VERSION ""

NS_ :

BS_:

BU_: GW_FD5 GW_FD6 GW_FD3 GW_FD4 GW_FD1 GW_FD2 PDCS_FD1 PDCU SRR3 SRR4 ADCU_FD3 BDCS DDCU CDCS ADCS_FD3 CDCS_OverSea TBOX FLC_ME_FD3 FLC_FD3 ICU_E02 ICU PDCS_HVM_FD1 TBOX_OverSea BMS ISC GCU EMS IDB ESC_FD3 EHB_FD3 MCU IMU ACU EPS WPC CDU AMP BAM PDCS_FD3 EVCC REPB ADCS_FD6 ADCU_FD6 FLC_ME_FD6 FLC_FD6 DLC GW_FD7 ESC_FD6 EHB_FD6

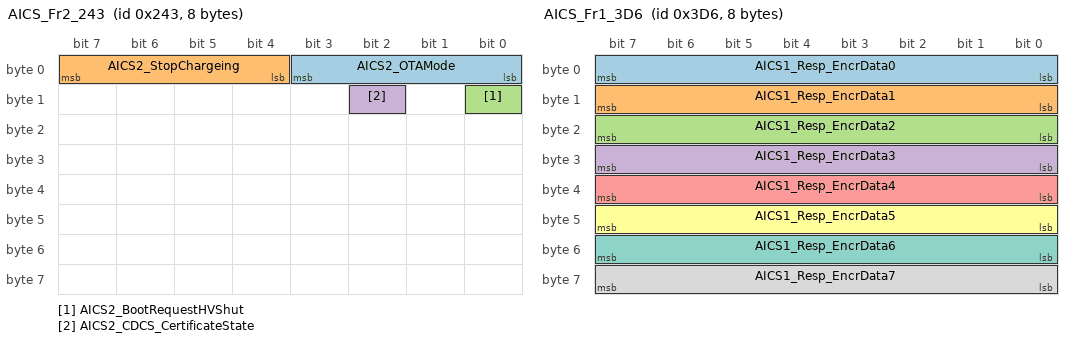
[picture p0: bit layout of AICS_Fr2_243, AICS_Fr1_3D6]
BO_ 579 AICS_Fr2_243: 8 GW_FD5
 SG_ AICS2_OTAMode : 3|4@0+ (1,0) [0|15] "NoUnit" PDCS_FD1,PDCU,SRR3,SRR4,ADCU_FD3,BDCS,DDCU,CDCS,ADCS_FD3,CDCS_OverSea,TBOX,FLC_ME_FD3,FLC_FD3,ICU_E02,ICU,PDCS_HVM_FD1,TBOX_OverSea
 SG_ AICS2_StopChargeing : 7|4@0+ (1,0) [0|15] "NoUnit" PDCS_FD1,ADCU_FD3,BMS,ADCS_FD3,FLC_ME_FD3,FLC_FD3,PDCS_HVM_FD1
 SG_ AICS2_BootRequestHVShut : 8|1@0+ (1,0) [0|1] "NoUnit" PDCS_FD1,ADCU_FD3,BMS,ADCS_FD3,FLC_ME_FD3,FLC_FD3,PDCS_HVM_FD1
 SG_ AICS2_CDCS_CertificateState : 10|1@0+ (1,0) [0|1] "NoUnit" CDCS,CDCS_OverSea

BO_ 982 AICS_Fr1_3D6: 8 GW_FD2
 SG_ AICS1_Resp_EncrData0 : 7|8@0+ (1,0) [0|255] "NoUnit" BDCS
 SG_ AICS1_Resp_EncrData1 : 15|8@0+ (1,0) [0|255] "NoUnit" BDCS
 SG_ AICS1_Resp_EncrData2 : 23|8@0+ (1,0) [0|255] "NoUnit" BDCS
 SG_ AICS1_Resp_EncrData3 : 31|8@0+ (1,0) [0|255] "NoUnit" BDCS
 SG_ AICS1_Resp_EncrData4 : 39|8@0+ (1,0) [0|255] "NoUnit" BDCS
 SG_ AICS1_Resp_EncrData5 : 47|8@0+ (1,0) [0|255] "NoUnit" BDCS
 SG_ AICS1_Resp_EncrData6 : 55|8@0+ (1,0) [0|255] "NoUnit" BDCS
 SG_ AICS1_Resp_EncrData7 : 63|8@0+ (1,0) [0|255] "NoUnit" BDCS

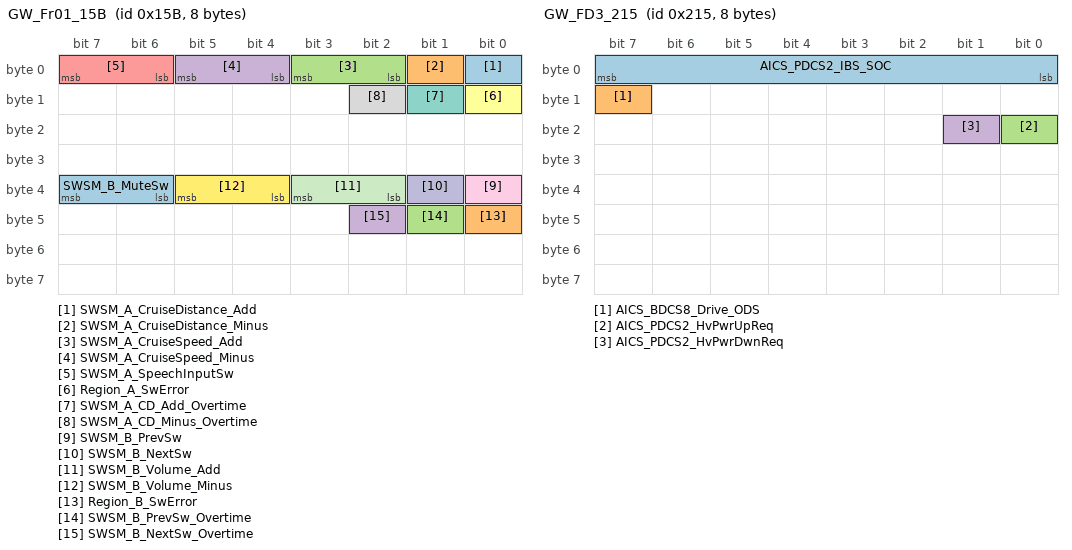
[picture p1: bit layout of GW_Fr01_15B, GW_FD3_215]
BO_ 347 GW_Fr01_15B: 8 GW_FD3
 SG_ SWSM_A_CruiseDistance_Add : 0|1@0+ (1,0) [0|1] "NoUnit" FLC_ME_FD3,FLC_FD3,DDCU,CDCS,ADCS_FD3,CDCS_OverSea
 SG_ SWSM_A_CruiseDistance_Minus : 1|1@0+ (1,0) [0|1] "NoUnit" FLC_ME_FD3,FLC_FD3,DDCU,CDCS,ADCS_FD3,CDCS_OverSea
 SG_ SWSM_A_CruiseSpeed_Add : 3|2@0+ (1,0) [0|3] "NoUnit" PDCS_FD1,FLC_ME_FD3,FLC_FD3,DDCU,CDCS,PDCS_HVM_FD1,ADCS_FD3,CDCS_OverSea
 SG_ SWSM_A_CruiseSpeed_Minus : 5|2@0+ (1,0) [0|3] "NoUnit" PDCS_FD1,FLC_ME_FD3,FLC_FD3,DDCU,CDCS,PDCS_HVM_FD1,ADCS_FD3,CDCS_OverSea
 SG_ SWSM_A_SpeechInputSw : 7|2@0+ (1,0) [0|3] "NoUnit" FLC_ME_FD3,FLC_FD3,CDCS,ADCS_FD3,CDCS_OverSea
 SG_ Region_A_SwError : 8|1@0+ (1,0) [0|1] "NoUnit" PDCS_FD1,FLC_ME_FD3,FLC_FD3,CDCS,PDCS_HVM_FD1,ADCS_FD3,CDCS_OverSea
 SG_ SWSM_A_CD_Add_Overtime : 9|1@0+ (1,0) [0|1] "NoUnit" FLC_ME_FD3,FLC_FD3,CDCS,ADCS_FD3,CDCS_OverSea
 SG_ SWSM_A_CD_Minus_Overtime : 10|1@0+ (1,0) [0|1] "NoUnit" FLC_ME_FD3,FLC_FD3,CDCS,ADCS_FD3,CDCS_OverSea
 SG_ SWSM_B_PrevSw : 32|1@0+ (1,0) [0|1] "NoUnit" PDCU,CDCS,CDCS_OverSea
 SG_ SWSM_B_NextSw : 33|1@0+ (1,0) [0|1] "NoUnit" PDCU,CDCS,CDCS_OverSea
 SG_ SWSM_B_Volume_Add : 35|2@0+ (1,0) [0|3] "NoUnit" PDCU,CDCS,CDCS_OverSea
 SG_ SWSM_B_Volume_Minus : 37|2@0+ (1,0) [0|3] "NoUnit" PDCU,CDCS,CDCS_OverSea
 SG_ SWSM_B_MuteSw : 39|2@0+ (1,0) [0|3] "NoUnit" CDCS,CDCS_OverSea
 SG_ Region_B_SwError : 40|1@0+ (1,0) [0|1] "NoUnit" CDCS,CDCS_OverSea
 SG_ SWSM_B_PrevSw_Overtime : 41|1@0+ (1,0) [0|1] "NoUnit" CDCS,CDCS_OverSea
 SG_ SWSM_B_NextSw_Overtime : 42|1@0+ (1,0) [0|1] "NoUnit" CDCS,CDCS_OverSea

BO_ 405 GW_UPA_0x195: 16 GW_FD5
 SG_ FPA_ResponseError : 0|1@0+ (1,0) [0|1] "" TBOX,CDCS,CDCS_OverSea,TBOX_OverSea
 SG_ FPA_Staus : 1|1@0+ (1,0) [0|1] "" TBOX,CDCS,CDCS_OverSea,TBOX_OverSea
 SG_ FPA_AssemblyNumberDID : 4|3@0+ (1,0) [0|7] "" TBOX,CDCS,CDCS_OverSea,TBOX_OverSea
 SG_ FPA_DetectionFOL : 15|8@0+ (1,0) [0|255] "cm" TBOX,CDCS,CDCS_OverSea,TBOX_OverSea
 SG_ FPA_DetectionFML : 23|8@0+ (1,0) [0|255] "cm" TBOX,CDCS,CDCS_OverSea,TBOX_OverSea
 SG_ FPA_DetectionFMR : 31|8@0+ (1,0) [0|255] "cm" TBOX,CDCS,CDCS_OverSea,TBOX_OverSea
 SG_ FPA_DetectionFOR : 39|8@0+ (1,0) [0|255] "cm" TBOX,CDCS,CDCS_OverSea,TBOX_OverSea
 SG_ FPA_FOLErrorFlag : 40|1@0+ (1,0) [0|1] "" TBOX,CDCS,CDCS_OverSea,TBOX_OverSea
 SG_ FPA_FMLErrorFlag : 41|1@0+ (1,0) [0|1] "" TBOX,CDCS,CDCS_OverSea,TBOX_OverSea
 SG_ FPA_FMRErrorFlag : 42|1@0+ (1,0) [0|1] "" TBOX,CDCS,CDCS_OverSea,TBOX_OverSea
 SG_ FPA_FORErrorFlag : 43|1@0+ (1,0) [0|1] "" TBOX,CDCS,CDCS_OverSea,TBOX_OverSea
 SG_ FPA_PoweVoltageAbnormal : 44|1@0+ (1,0) [0|1] "" TBOX,CDCS,CDCS_OverSea,TBOX_OverSea
 SG_ FPA_Sound_Location : 46|2@0+ (1,0) [0|3] "" TBOX,CDCS,CDCS_OverSea,TBOX_OverSea
 SG_ FPA_SoundIndication : 50|3@0+ (1,0) [0|7] "" TBOX,CDCS,CDCS_OverSea,TBOX_OverSea
 SG_ FPA_HardwareVersion : 55|5@0+ (1,0) [0|31] "" TBOX,CDCS,CDCS_OverSea,TBOX_OverSea
 SG_ FPA_SoftwareSubVersion : 59|4@0+ (1,0) [0|15] "" TBOX,CDCS,CDCS_OverSea,TBOX_OverSea
 SG_ FPA_SoftwareMainVersion : 63|4@0+ (1,0) [0|15] "" TBOX,CDCS,CDCS_OverSea,TBOX_OverSea
 SG_ RPA_ResponseError : 64|1@0+ (1,0) [0|1] "" TBOX,CDCS,CDCS_OverSea,TBOX_OverSea
 SG_ RPA_Staus : 65|1@0+ (1,0) [0|1] "" TBOX,CDCS,CDCS_OverSea,TBOX_OverSea
 SG_ RPA_AssemblyNumberDID : 68|3@0+ (1,0) [0|7] "" TBOX,CDCS,CDCS_OverSea,TBOX_OverSea
 SG_ RPA_DetectionROL : 79|8@0+ (1,0) [0|255] "cm" TBOX,CDCS,CDCS_OverSea,TBOX_OverSea
 SG_ RPA_DetectionRML : 87|8@0+ (1,0) [0|255] "cm" TBOX,CDCS,CDCS_OverSea,TBOX_OverSea
 SG_ RPA_DetectionRMR : 95|8@0+ (1,0) [0|255] "cm" TBOX,CDCS,CDCS_OverSea,TBOX_OverSea
 SG_ RPA_DetectionROR : 103|8@0+ (1,0) [0|255] "cm" TBOX,CDCS,CDCS_OverSea,TBOX_OverSea
 SG_ RPA_ROLErrorFlag : 104|1@0+ (1,0) [0|1] "" TBOX,CDCS,CDCS_OverSea,TBOX_OverSea
 SG_ RPA_RMLErrorFlag : 105|1@0+ (1,0) [0|1] "" TBOX,CDCS,CDCS_OverSea,TBOX_OverSea
 SG_ RPA_RMRErrorFlag : 106|1@0+ (1,0) [0|1] "" TBOX,CDCS,CDCS_OverSea,TBOX_OverSea
 SG_ RPA_RORErrorFlag : 107|1@0+ (1,0) [0|1] "" TBOX,CDCS,CDCS_OverSea,TBOX_OverSea
 SG_ RPA_PoweVoltageAbnormal : 108|1@0+ (1,0) [0|1] "" TBOX,CDCS,CDCS_OverSea,TBOX_OverSea
 SG_ RPA_Sound_Location : 110|2@0+ (1,0) [0|3] "" TBOX,CDCS,CDCS_OverSea,TBOX_OverSea
 SG_ RPA_SoundIndication : 114|3@0+ (1,0) [0|7] "" TBOX,CDCS,CDCS_OverSea,TBOX_OverSea
 SG_ RPA_HardwareVersion : 119|5@0+ (1,0) [0|31] "" TBOX,CDCS,CDCS_OverSea,TBOX_OverSea
 SG_ RPA_SoftwareSubVersion : 123|4@0+ (1,0) [0|15] "" TBOX,CDCS,CDCS_OverSea,TBOX_OverSea
 SG_ RPA_SoftwareMainVersion : 127|4@0+ (1,0) [0|15] "" TBOX,CDCS,CDCS_OverSea,TBOX_OverSea

BO_ 533 GW_FD3_215: 8 GW_FD3
 SG_ AICS_PDCS2_IBS_SOC : 7|8@0+ (1,0) [0|100] "%" CDCS,ADCS_FD3,CDCS_OverSea
 SG_ AICS_BDCS8_Drive_ODS : 15|1@0+ (1,0) [0|1] "NoUnit" FLC_ME_FD3,FLC_FD3,ADCU_FD3,ADCS_FD3
 SG_ AICS_PDCS2_HvPwrUpReq : 16|1@0+ (1,0) [0|1] "NoUnit" ISC
 SG_ AICS_PDCS2_HvPwrDwnReq : 17|1@0+ (1,0) [0|1] "NoUnit" ISC

BO_ 1233 GW_FD5_4D1: 16 GW_FD5
 SG_ AICS_GCU3_OperModFdbk : 7|4@0+ (1,0) [0|15] "NoUnit" TBOX,TBOX_OverSea
 SG_ AICS_GCU3_Motor_Torque : 3|12@0+ (0.5,-300) [-130|130] "Nm" TBOX,TBOX_OverSea
 SG_ AICS_GCU3_Motor_Speed : 23|16@0+ (1,-12000) [-8000|8000] "rpm" TBOX,TBOX_OverSea
 SG_ AICS_EMS1_EngineStartedCompleted : 39|1@0+ (1,0) [0|1] "NoUnit" TBOX,TBOX_OverSea
 SG_ AICS_EMS1_EngineStopAllow : 38|1@0+ (1,0) [0|1] "NoUnit" TBOX,TBOX_OverSea
 SG_ AICS_EMS1_ActualEngineTorqueValid : 37|1@0+ (1,0) [0|1] "NoUnit" TBOX,TBOX_OverSea
 SG_ AICS_EMS1_ActualEngineTorque : 35|12@0+ (0.5,-500) [-500|1547] "Nm" TBOX,TBOX_OverSea
 SG_ AICS_EMS1_EngineTorqMin : 55|12@0+ (0.5,-500) [-500|1547] "Nm" TBOX,TBOX_OverSea
 SG_ AICS_EMS1_EngineTorqMax : 59|12@0+ (0.5,-500) [-500|1547] "Nm" TBOX,TBOX_OverSea
 SG_ AICS_EMS1_EngineTorqLoss : 79|10@0+ (0.5,-100) [-100|411] "Nm" TBOX,TBOX_OverSea

BO_ 1536 AICS_NM_600: 8 GW_FD5
 SG_ AICS_SourceNodeIdentifier : 7|8@0+ (1,0) [0|255] "NoUnit" Vector__XXX
 SG_ AICS_RepeatMessageRequest : 8|1@0+ (1,0) [0|1] "NoUnit" Vector__XXX
 SG_ AICS_Reserve1 : 11|3@0+ (1,0) [0|3] "NoUnit" Vector__XXX
 SG_ AICS_ActiveWakeup : 12|1@0+ (1,0) [0|1] "NoUnit" Vector__XXX
 SG_ AICS_Reserve2 : 15|3@0+ (1,0) [0|7] "NoUnit" Vector__XXX
 SG_ AICS_WakeUp_KL15 : 16|1@0+ (1,0) [0|1] "NoUnit" Vector__XXX
 SG_ AICS_WakeUp_NM : 17|1@0+ (1,0) [0|1] "NoUnit" Vector__XXX
 SG_ AICS_WakeUp_LIN : 18|1@0+ (1,0) [0|1] "NoUnit" Vector__XXX
 SG_ AICS_WakeUp_LocalPreCharge : 19|1@0+ (1,0) [0|1] "NoUnit" Vector__XXX
 SG_ AICS_WakeUp_RemotePreCharge : 20|1@0+ (1,0) [0|1] "NoUnit" Vector__XXX
 SG_ AICS_WakeUp_OTA : 21|1@0+ (1,0) [0|1] "NoUnit" Vector__XXX
 SG_ AICS_WakeUp_Remote : 22|1@0+ (1,0) [0|1] "NoUnit" Vector__XXX
 SG_ AICS_WakeUp_PhoneReminder : 23|1@0+ (1,0) [0|1] "NoUnit" Vector__XXX
 SG_ AICS_RepeatFromSleep : 24|1@0+ (1,0) [0|1] "NoUnit" Vector__XXX
 SG_ AICS_RepeatFromPrepare : 25|1@0+ (1,0) [0|1] "NoUnit" Vector__XXX
 SG_ AICS_NormalFromRepeat : 26|1@0+ (1,0) [0|1] "NoUnit" Vector__XXX
 SG_ AICS_NormalFromReady : 27|1@0+ (1,0) [0|1] "NoUnit" Vector__XXX
 SG_ AICS_RepeatFromReady : 28|1@0+ (1,0) [0|1] "NoUnit" Vector__XXX
 SG_ AICS_RepeatFromNormal : 29|1@0+ (1,0) [0|1] "NoUnit" Vector__XXX
 SG_ AICS_RemainNetworkWakeUp_BMS_NM : 32|1@0+ (1,0) [0|1] "NoUnit" Vector__XXX
 SG_ AICS_RemainNetworkWakeUp_CDU_NM : 33|1@0+ (1,0) [0|1] "NoUnit" Vector__XXX
 SG_ AICS_RemainNetworkWakeUp_MCU_NM : 34|1@0+ (1,0) [0|1] "NoUnit" Vector__XXX
 SG_ AICS_RemainNetworkWakeUp_PDCU_NM : 35|1@0+ (1,0) [0|1] "NoUnit" Vector__XXX
 SG_ AICS_RemainNetworkWakeUp_ADCS_NM : 36|1@0+ (1,0) [0|1] "NoUnit" Vector__XXX
 SG_ AICS_RemainNetworkWakeUp_PDCS_NM : 38|1@0+ (1,0) [0|1] "NoUnit" Vector__XXX
 SG_ AICS_RemainNetworkWakeUp_DDCU_NM : 39|1@0+ (1,0) [0|1] "NoUnit" Vector__XXX
 SG_ AICS_RemainNetworkWakeUpReason1 : 40|1@0+ (1,0) [0|1] "NoUnit" Vector__XXX
 SG_ AICS_RemainNetworkWakeUpReason2 : 41|1@0+ (1,0) [0|1] "NoUnit" Vector__XXX
 SG_ AICS_RemainNetworkWakeUp_BDCS_NM : 42|1@0+ (1,0) [0|1] "NoUnit" Vector__XXX
 SG_ AICS_RemainNetworkWakeUp_FMCU_NM : 43|1@0+ (1,0) [0|1] "NoUnit" Vector__XXX
 SG_ AICS_RemainNetworkWakeUp_ICU_NM : 44|1@0+ (1,0) [0|1] "NoUnit" Vector__XXX
 SG_ AICS_RemainNetworkWakeUp_CDCS_NM : 45|1@0+ (1,0) [0|1] "NoUnit" Vector__XXX
 SG_ AICS_RemainNetworkWakeUp_AMP_NM : 46|1@0+ (1,0) [0|1] "NoUnit" Vector__XXX
 SG_ AICS_RemainNetworkWakeUp_BTM_NM : 47|1@0+ (1,0) [0|1] "NoUnit" Vector__XXX
 SG_ AICS_RemainNetworkWakeUpReason3 : 48|1@0+ (1,0) [0|1] "NoUnit" Vector__XXX
 SG_ AICS_RemainNetworkWakeUp_GCU_NM : 49|1@0+ (1,0) [0|1] "NoUnit" Vector__XXX
 SG_ AICS_RemainNetworkWakeUp_HUD_NM : 50|1@0+ (1,0) [0|1] "NoUnit" Vector__XXX
 SG_ AICS_RemainNetworkWakeUp_T_BOX_NM : 51|1@0+ (1,0) [0|1] "NoUnit" Vector__XXX
 SG_ AICS_RemainNetworkWakeUp_LIN : 52|1@0+ (1,0) [0|1] "NoUnit" Vector__XXX
 SG_ AICS_RemainNetworkWakeUpReason22 : 53|1@0+ (1,0) [0|1] "NoUnit" Vector__XXX
 SG_ AICS_RemainNetworkWakeUpReason23 : 54|1@0+ (1,0) [0|1] "NoUnit" Vector__XXX
 SG_ AICS_RemainNetworkWakeUpReason24 : 55|1@0+ (1,0) [0|1] "NoUnit" Vector__XXX
 SG_ AICS_UserData5 : 63|8@0+ (1,0) [0|255] "NoUnit" Vector__XXX

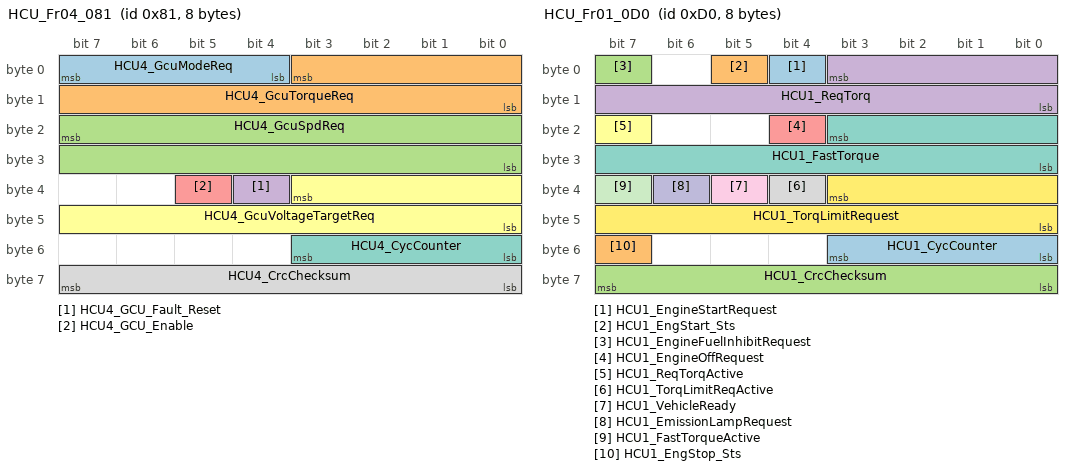
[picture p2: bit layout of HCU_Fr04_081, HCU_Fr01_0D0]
BO_ 129 HCU_Fr04_081: 8 PDCS_FD1
 SG_ HCU4_GcuModeReq : 7|4@0+ (1,0) [0|15] "NoUnit" TBOX,GW_FD5,GCU,TBOX_OverSea
 SG_ HCU4_GcuTorqueReq : 3|12@0+ (0.5,-300) [-130|130] "Nm" TBOX,GW_FD5,GCU,TBOX_OverSea
 SG_ HCU4_GcuSpdReq : 23|16@0+ (1,-12000) [-8000|8000] "rpm" TBOX,GW_FD5,GCU,TBOX_OverSea
 SG_ HCU4_GCU_Fault_Reset : 36|1@0+ (1,0) [0|1] "NoUnit" TBOX,GW_FD5,GCU,TBOX_OverSea
 SG_ HCU4_GCU_Enable : 37|1@0+ (1,0) [0|1] "NoUnit" TBOX,GW_FD5,GCU,TBOX_OverSea
 SG_ HCU4_GcuVoltageTargetReq : 35|12@0+ (1,0) [0|700] "V" TBOX,GW_FD5,GCU,TBOX_OverSea
 SG_ HCU4_CycCounter : 51|4@0+ (1,0) [0|15] "NoUnit" GCU
 SG_ HCU4_CrcChecksum : 63|8@0+ (1,0) [0|255] "NoUnit" GCU

BO_ 208 HCU_Fr01_0D0: 8 PDCS_FD1
 SG_ HCU1_EngineStartRequest : 4|1@0+ (1,0) [0|1] "NoUnit" TBOX,GW_FD5,GCU,EMS,TBOX_OverSea
 SG_ HCU1_EngStart_Sts : 5|1@0+ (1,0) [0|1] "NoUnit" TBOX,GW_FD5,TBOX_OverSea
 SG_ HCU1_EngineFuelInhibitRequest : 7|1@0+ (1,0) [0|1] "NoUnit" TBOX,GW_FD5,GCU,EMS,TBOX_OverSea
 SG_ HCU1_ReqTorq : 3|12@0+ (0.5,-500) [-500|1547] "Nm" TBOX,GW_FD5,GCU,EMS,TBOX_OverSea
 SG_ HCU1_EngineOffRequest : 20|1@0+ (1,0) [0|1] "NoUnit" TBOX,GW_FD5,EMS,TBOX_OverSea
 SG_ HCU1_ReqTorqActive : 23|1@0+ (1,0) [0|1] "NoUnit" TBOX,GW_FD5,EMS,TBOX_OverSea
 SG_ HCU1_FastTorque : 19|12@0+ (0.5,-500) [-500|1547] "Nm" TBOX,GW_FD5,EMS,TBOX_OverSea
 SG_ HCU1_TorqLimitReqActive : 36|1@0+ (1,0) [0|1] "NoUnit" TBOX,GW_FD5,TBOX_OverSea
 SG_ HCU1_VehicleReady : 37|1@0+ (1,0) [0|1] "NoUnit" TBOX,GW_FD5,IDB,ESC_FD3,GW_FD3,EMS,EHB_FD3,TBOX_OverSea
 SG_ HCU1_EmissionLampRequest : 38|1@0+ (1,0) [0|1] "NoUnit" TBOX,GW_FD5,TBOX_OverSea
 SG_ HCU1_FastTorqueActive : 39|1@0+ (1,0) [0|1] "NoUnit" TBOX,GW_FD5,EMS,TBOX_OverSea
 SG_ HCU1_TorqLimitRequest : 35|12@0+ (0.5,-500) [-500|1547] "Nm" TBOX,GW_FD5,TBOX_OverSea
 SG_ HCU1_CycCounter : 51|4@0+ (1,0) [0|15] "" EMS
 SG_ HCU1_EngStop_Sts : 55|1@0+ (1,0) [0|1] "NoUnit" TBOX,GW_FD5,TBOX_OverSea
 SG_ HCU1_CrcChecksum : 63|8@0+ (1,0) [0|255] "" EMS

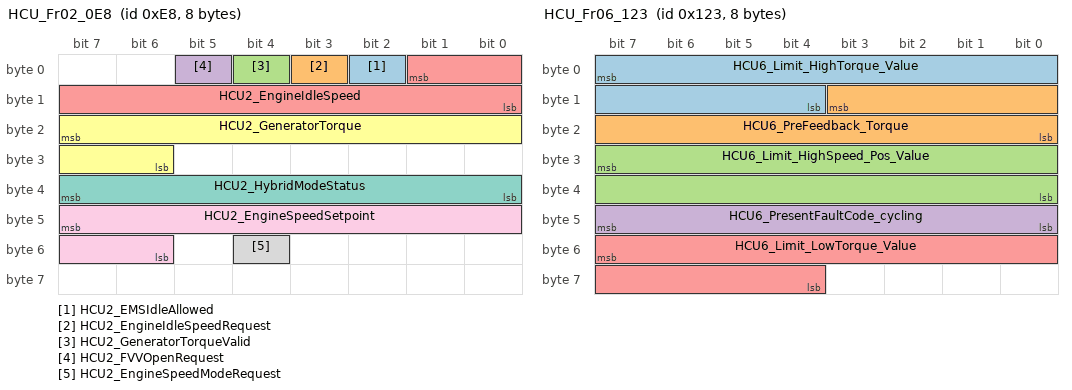
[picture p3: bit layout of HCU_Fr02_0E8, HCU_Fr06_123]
BO_ 232 HCU_Fr02_0E8: 8 PDCS_FD1
 SG_ HCU2_EMSIdleAllowed : 2|1@0+ (1,0) [0|1] "NoUnit" TBOX,GW_FD5,EMS,TBOX_OverSea
 SG_ HCU2_EngineIdleSpeedRequest : 3|1@0+ (1,0) [0|1] "NoUnit" TBOX,GW_FD5,EMS,TBOX_OverSea
 SG_ HCU2_GeneratorTorqueValid : 4|1@0+ (1,0) [0|1] "NoUnit" TBOX,GW_FD5,EMS,TBOX_OverSea
 SG_ HCU2_FVVOpenRequest : 5|1@0+ (1,0) [0|1] "NoUnit" TBOX,GW_FD5,EMS,TBOX_OverSea
 SG_ HCU2_EngineIdleSpeed : 1|10@0+ (10,0) [0|8200] "rpm" TBOX,GW_FD5,EMS,TBOX_OverSea
 SG_ HCU2_GeneratorTorque : 23|10@0+ (0.5,0) [0|255] "NoUnit" TBOX,GW_FD5,EMS,TBOX_OverSea
 SG_ HCU2_HybridModeStatus : 39|8@0+ (1,0) [0|255] "NoUnit" TBOX,GW_FD5,TBOX_OverSea
 SG_ HCU2_EngineSpeedModeRequest : 52|1@0+ (1,0) [0|1] "NoUnit" TBOX,GW_FD5,EMS,TBOX_OverSea
 SG_ HCU2_EngineSpeedSetpoint : 47|10@0+ (10,0) [0|10000] "rpm" TBOX,GW_FD5,EMS,TBOX_OverSea

BO_ 291 HCU_Fr06_123: 8 PDCS_FD1
 SG_ HCU6_Limit_HighTorque_Value : 7|12@0+ (0.5,-300) [-130|130] "Nm" TBOX,GW_FD5,GCU,TBOX_OverSea
 SG_ HCU6_PreFeedback_Torque : 11|12@0+ (0.5,-300) [-130|130] "Nm" TBOX,GW_FD5,GCU,TBOX_OverSea
 SG_ HCU6_Limit_HighSpeed_Pos_Value : 31|16@0+ (1,-12000) [-8000|8000] "rpm" TBOX,GW_FD5,GCU,TBOX_OverSea
 SG_ HCU6_PresentFaultCode_cycling : 47|8@0+ (1,0) [0|255] "NoUnit" TBOX,GW_FD5,GCU,TBOX_OverSea
 SG_ HCU6_Limit_LowTorque_Value : 55|12@0+ (0.5,-300) [-130|130] "Nm" GCU

BO_ 384 HCU_Fr05_180: 16 PDCS_FD1
 SG_ HCU5_EnginIdingIdleSetFeedback : 1|2@0+ (1,0) [0|3] "NoUnit" GW_FD4,CDCS,CDCS_OverSea
 SG_ HCU5_fueltankparkingunlock : 2|1@0+ (1,0) [0|1] "NoUnit" TBOX,GW_FD5,GW_FD4,CDCS,CDCS_OverSea,TBOX_OverSea
 SG_ HCU5_Decompressionfail : 3|1@0+ (1,0) [0|1] "NoUnit" TBOX,GW_FD5,GW_FD4,CDCS,CDCS_OverSea,TBOX_OverSea
 SG_ HCU5_serviceLampRequest : 4|1@0+ (1,0) [0|1] "NoUnit" TBOX,GW_FD5,ICU_E02,GW_FD4,ICU,CDCS,CDCS_OverSea,TBOX_OverSea
 SG_ HCU5_fueltankunLockrequest : 5|1@0+ (1,0) [0|1] "NoUnit" TBOX,PDCU,GW_FD5,GW_FD2,DDCU,TBOX_OverSea
 SG_ HCU5_CoolantFillingSta : 6|1@0+ (1,0) [0|1] "NoUnit" GW_FD4,CDCS,CDCS_OverSea
 SG_ HCU5_PureFuelResMilage : 15|16@0+ (0.1,0) [0|6553] "Km" TBOX,GW_FD5,ICU_E02,GW_FD4,ICU,CDCS,CDCS_OverSea,TBOX_OverSea
 SG_ HCU5_s_WaitTiExitRefu : 24|1@0+ (1,0) [0|1] "NoUnit" TBOX,GW_FD5,GW_FD4,CDCS,CDCS_OverSea,TBOX_OverSea
 SG_ HCU5_flag_CapUncls : 25|1@0+ (1,0) [0|1] "NoUnit" TBOX,GW_FD5,GW_FD4,CDCS,CDCS_OverSea,TBOX_OverSea
 SG_ HCU5_flg_EngWtrOvrTemp : 26|1@0+ (1,0) [0|1] "NoUnit" TBOX,GW_FD5,ICU_E02,GW_FD4,ICU,CDCS,CDCS_OverSea,TBOX_OverSea
 SG_ HCU5_TWV3_CWFlg : 27|1@0+ (1,0) [0|1] "NoUnit" TBOX,GW_FD5,GW_FD4,CDCS,CDCS_OverSea,TBOX_OverSea
 SG_ HCU5_TWV3_CCWFlg : 28|1@0+ (1,0) [0|1] "NoUnit" TBOX,GW_FD5,GW_FD4,CDCS,CDCS_OverSea,TBOX_OverSea
 SG_ HCU5_TWV3_motorSta : 29|1@0+ (1,0) [0|1] "NoUnit" TBOX,GW_FD5,GW_FD4,CDCS,CDCS_OverSea,TBOX_OverSea
 SG_ HCU5_TWV3_RespError : 30|1@0+ (1,0) [0|1] "NoUnit" TBOX,GW_FD5,GW_FD4,CDCS,CDCS_OverSea,TBOX_OverSea
 SG_ HCU5_TWV3_OvervoltageFlt : 31|1@0+ (1,0) [0|1] "NoUnit" TBOX,GW_FD5,GW_FD4,CDCS,CDCS_OverSea,TBOX_OverSea
 SG_ HCU5_TWV3_RealSta : 39|8@0+ (1,0) [0|100] "%" TBOX,GW_FD5,GW_FD4,GW_FD2,BDCS,CDCS,CDCS_OverSea,TBOX_OverSea
 SG_ HCU5_TWV3_OverCurrent : 40|1@0+ (1,0) [0|1] "NoUnit" TBOX,GW_FD5,GW_FD4,CDCS,CDCS_OverSea,TBOX_OverSea
 SG_ HCU5_TWV3_OverTempFlt : 41|1@0+ (1,0) [0|1] "NoUnit" TBOX,GW_FD5,GW_FD4,CDCS,CDCS_OverSea,TBOX_OverSea
 SG_ HCU5_TWV3_UndervoltageFlt : 42|1@0+ (1,0) [0|1] "NoUnit" TBOX,GW_FD5,GW_FD4,CDCS,CDCS_OverSea,TBOX_OverSea
 SG_ HCU5_TWV2_CWFlg : 43|1@0+ (1,0) [0|1] "NoUnit" TBOX,GW_FD5,GW_FD4,CDCS,CDCS_OverSea,TBOX_OverSea
 SG_ HCU5_TWV2_CCWFlg : 44|1@0+ (1,0) [0|1] "NoUnit" TBOX,GW_FD5,GW_FD4,CDCS,CDCS_OverSea,TBOX_OverSea
 SG_ HCU5_TWV2_motorSta : 45|1@0+ (1,0) [0|1] "NoUnit" TBOX,GW_FD5,GW_FD4,CDCS,CDCS_OverSea,TBOX_OverSea
 SG_ HCU5_TWV2_RespError : 46|1@0+ (1,0) [0|1] "NoUnit" TBOX,GW_FD5,GW_FD4,CDCS,CDCS_OverSea,TBOX_OverSea
 SG_ HCU5_TWV2_OvervoltageFlt : 47|1@0+ (1,0) [0|1] "NoUnit" TBOX,GW_FD5,GW_FD4,CDCS,CDCS_OverSea,TBOX_OverSea
 SG_ HCU5_TWV2_OverCurrent : 48|1@0+ (1,0) [0|1] "NoUnit" TBOX,GW_FD5,GW_FD4,CDCS,CDCS_OverSea,TBOX_OverSea
 SG_ HCU5_TWV2_OverTempFlt : 49|1@0+ (1,0) [0|1] "NoUnit" TBOX,GW_FD5,GW_FD4,CDCS,CDCS_OverSea,TBOX_OverSea
 SG_ HCU5_TWV2_UndervoltageFlt : 50|1@0+ (1,0) [0|1] "NoUnit" TBOX,GW_FD5,GW_FD4,CDCS,CDCS_OverSea,TBOX_OverSea
 SG_ HCU5_WtrMotOutTempValid : 51|1@0+ (1,0) [0|1] "NoUnit" GW_FD2,BDCS
 SG_ HCU5_OilFillCapLockremind : 52|1@0+ (1,0) [0|1] "NoUnit" TBOX,GW_FD5,GW_FD4,CDCS,CDCS_OverSea,TBOX_OverSea
 SG_ HCU5_RexMode : 55|3@0+ (1,0) [0|7] "NoUnit" TBOX,GW_FD5,BMS,GW_FD4,CDCS,CDCS_OverSea,TBOX_OverSea
 SG_ HCU5_Ctl_PWM_Fan1_BackDiag : 63|8@0+ (1,0) [0|255] "NoUnit" TBOX,GW_FD5,GW_FD4,CDCS,CDCS_OverSea,TBOX_OverSea
 SG_ HCU5_Ctl_PWM_Wtpump1_BackDiag : 71|8@0+ (1,0) [0|255] "NoUnit" TBOX,GW_FD5,GW_FD4,CDCS,CDCS_OverSea,TBOX_OverSea
 SG_ HCU5_Ctl_PWM_Wtpump3_BackDiag : 79|8@0+ (1,0) [0|255] "NoUnit" TBOX,GW_FD5,GW_FD4,CDCS,CDCS_OverSea,TBOX_OverSea
 SG_ HCU5_TWV2_RealSta : 87|8@0+ (1,0) [0|100] "NoUnit" TBOX,GW_FD5,GW_FD4,CDCS,CDCS_OverSea,TBOX_OverSea
 SG_ HCU5_T_EdCoolant : 95|8@0+ (1,0) [0|255] "NoUnit" TBOX,GW_FD5,GW_FD4,CDCS,CDCS_OverSea,TBOX_OverSea
 SG_ HCU5_ForcechargingLevelSetFeedBack : 97|2@0+ (1,0) [0|3] "" GW_FD4,CDCS,CDCS_OverSea
 SG_ HCU5_PREMDisplayReminder : 103|3@0+ (1,0) [0|7] "NoUnit" GW_FD4,CDCS,CDCS_OverSea
 SG_ HCU5_REXchargSts : 111|2@0+ (1,0) [0|3] "" GW_FD4,CDCS,CDCS_OverSea
 SG_ HCU5_MileagePREMExtended : 109|14@0+ (0.1,0) [0|1638.3] "km" GW_FD4,CDCS,CDCS_OverSea
 SG_ HCU5_WtrMotOutTemp : 127|8@0+ (1,-40) [-40|120] "℃" GW_FD2,BDCS

BO_ 531 HCU_Fr03_213: 32 PDCS_FD1
 SG_ HCU3_EngStrtForStaleFu : 0|1@0+ (1,0) [0|1] "NoUnit" GW_FD4,CDCS,CDCS_OverSea
 SG_ HCU3_VCMActv : 1|1@0+ (1,0) [0|1] "NoUnit" GW_FD4,CDCS,CDCS_OverSea
 SG_ HCU3_SportmodAvailableDisp : 3|2@0+ (1,0) [0|3] "NoUnit" GW_FD4,CDCS,CDCS_OverSea
 SG_ HCU3_RexSysError : 4|1@0+ (1,0) [0|1] "NoUnit" TBOX,GW_FD5,ICU_E02,GW_FD4,ICU,CDCS,CDCS_OverSea,TBOX_OverSea
 SG_ HCU3_RexModeAvalidreminder : 7|3@0+ (1,0) [0|7] "NoUnit" GW_FD4,CDCS,CDCS_OverSea
 SG_ HCU3_MileagePremTolSav : 15|24@0+ (0.1,0) [0|1677721.5] "Km" TBOX,GW_FD5,GW_FD4,CDCS,CDCS_OverSea,TBOX_OverSea
 SG_ HCU3_DayPremActv : 39|16@0+ (1,0) [0|65535] "Day" GW_FD4,CDCS,CDCS_OverSea
 SG_ HCU3_FuelConsumptionLongTrip : 55|16@0+ (0.01,0) [0|655.35] "L/100km" TBOX,GW_FD5,GW_FD4,CDCS,CDCS_OverSea,TBOX_OverSea
 SG_ HCU3_REXStartFail : 65|1@0+ (1,0) [0|1] "NoUnit" GW_FD4,CDCS,CDCS_OverSea
 SG_ HCU3_PowerGradREX2MCU : 67|2@0+ (1,0) [0|3] "NoUnit" GW_FD4,CDCS,CDCS_OverSea
 SG_ HCU3_EnergyFlowSts : 71|4@0+ (1,0) [0|15] "NoUnit" GW_FD4,CDCS,CDCS_OverSea
 SG_ HCU3_FuelSavePremLongTrip : 64|17@0+ (0.1,0) [0|13107.1] "L" TBOX,GW_FD5,GW_FD4,CDCS,CDCS_OverSea,TBOX_OverSea
 SG_ HCU3_PowerGradMCU2Batt : 93|2@0+ (1,0) [0|3] "NoUnit" GW_FD4,CDCS,CDCS_OverSea
 SG_ HCU3_PowerGradREX2Batt : 95|2@0+ (1,0) [0|3] "NoUnit" GW_FD4,CDCS,CDCS_OverSea
 SG_ HCU3_FuelSavePremShortTrip : 91|12@0+ (0.1,0) [0|409.5] "L" GW_FD4,CDCS,CDCS_OverSea
 SG_ HCU3_EVModAvailableDisp : 109|3@0+ (1,0) [0|7] "NoUnit" GW_FD4,CDCS,CDCS_OverSea
 SG_ HCU3_MotorDrive_Satis : 111|2@0+ (1,0) [0|3] "NoUnit" GW_FD4,CDCS,CDCS_OverSea
 SG_ HCU3_FuelConsumptionShortTrip : 119|16@0+ (0.01,0) [0|655.35] "L/100km" TBOX,GW_FD5,GW_FD4,CDCS,CDCS_OverSea,TBOX_OverSea
 SG_ HCU3_FuelLevelEstimated : 135|8@0+ (1,0) [0|255] "%" TBOX,GW_FD5,ICU_E02,GW_FD4,ICU,CDCS,CDCS_OverSea,TBOX_OverSea
 SG_ HCU3_StRngextModeAct : 155|4@0+ (1,0) [0|15] "NoUnit" Vector__XXX
 SG_ HCU3_HCUSoftVersion : 143|20@0+ (1,0) [0|999999] "NoUnit" Vector__XXX
 SG_ HCU3_FTMSt : 167|8@0+ (1,0) [0|15] "NoUnit" Vector__XXX
 SG_ HCU3_REXreadyforsleep : 173|1@0+ (1,0) [0|1] "NoUnit" Vector__XXX
 SG_ HCU3_RexShutdownRdy : 174|1@0+ (1,0) [0|1] "NoUnit" Vector__XXX
 SG_ HCU3_flg_RexZeroPower : 175|1@0+ (1,0) [0|1] "NoUnit" Vector__XXX
 SG_ HCU3_GenInstEnergyConsum : 172|11@0+ (0.1,-99.9) [-99.9|99.9] "Kws" GW_FD4,CDCS,CDCS_OverSea

BO_ 854 HCU_Fr07_356: 64 PDCS_FD1
 SG_ HCU7_perc_EngOilHealth : 7|8@0+ (1,0) [0|100] "%" TBOX,GW_FD5,GW_FD4,CDCS,CDCS_OverSea,TBOX_OverSea
 SG_ HCU7_m_MnResdMilgKm : 15|16@0+ (1,0) [0|30000] "km" TBOX,GW_FD5,GW_FD4,CDCS,CDCS_OverSea,TBOX_OverSea
 SG_ HCU7_ti_MnResTiDay : 31|16@0+ (1,0) [0|1000] "day" TBOX,GW_FD5,GW_FD4,CDCS,CDCS_OverSea,TBOX_OverSea
 SG_ HCU7_ti_AftMnFrznTimYear : 47|8@0+ (1,2000) [2000|2255] "" TBOX,GW_FD5,TBOX_OverSea
 SG_ HCU7_ti_AftMnFrznTimMonth : 51|4@0+ (1,0) [0|15] "" TBOX,GW_FD5,TBOX_OverSea
 SG_ HCU7_kwhpL_PwrGenFu2Elec : 55|4@0+ (1,0) [0|15] "kWh/L" TBOX,GW_FD5,TBOX_OverSea
 SG_ HCU7_ti_AftMnFrznTimDay : 60|5@0+ (1,0) [0|31] "" TBOX,GW_FD5,TBOX_OverSea
 SG_ HCU7_StEngDynTranReq : 62|2@0+ (1,0) [0|3] "" TBOX,GW_FD5,TBOX_OverSea
 SG_ HCU7_ti_EE1EngIdleTimHr : 71|16@0+ (1,0) [0|15000] "h" TBOX,GW_FD5,TBOX_OverSea
 SG_ HCU7_m_EE1EngEquivRunMilgKm : 87|16@0+ (1,0) [0|20000] "km" TBOX,GW_FD5,TBOX_OverSea
 SG_ HCU7_u_EE1HourOfDayLck : 100|5@0+ (1,0) [0|25] "h" TBOX,GW_FD5,TBOX_OverSea
 SG_ HCU7_ti_EE1EngRunTimHr : 111|16@0+ (1,0) [0|15000] "h" TBOX,GW_FD5,TBOX_OverSea
 SG_ HCU7_NrTolEngStartReq : 123|20@0+ (1,0) [0|1048575] "" TBOX,GW_FD5,TBOX_OverSea
 SG_ HCU7_NrTolEngStartFail : 151|16@0+ (1,0) [0|65535] "" TBOX,GW_FD5,TBOX_OverSea
 SG_ HCU7_stEngStopTran : 178|3@0+ (1,0) [0|7] "" TBOX,GW_FD5,TBOX_OverSea
 SG_ HCU7_stEngStrtTran : 181|3@0+ (1,0) [0|7] "" TBOX,GW_FD5,TBOX_OverSea
 SG_ HCU7_Hr_EngRunningTime : 167|18@0+ (1,0) [0|262140] "hour" TBOX,GW_FD5,TBOX_OverSea
 SG_ HCU7_kw_PwrEngDynMaxLim : 191|8@0+ (1,0) [0|255] "kw" TBOX,GW_FD5,TBOX_OverSea
 SG_ HCU7_kw_PwrRngextReq : 199|8@0+ (1,0) [0|255] "kw" TBOX,GW_FD5,TBOX_OverSea
 SG_ HCU7_AcvPwrReqStgy : 202|3@0+ (1,0) [0|7] "" TBOX,GW_FD5,TBOX_OverSea
 SG_ HCU7_StRngextSys : 207|4@0+ (1,0) [0|15] "" TBOX,GW_FD5,TBOX_OverSea
 SG_ HCU7_fac_PREMValEquiv : 215|8@0+ (1,150) [150|405] "g/kwh" TBOX,GW_FD5,TBOX_OverSea
 SG_ HCU7_L_WhlDrvLifeFuCns : 223|16@0+ (1,0) [0|65535] "L" TBOX,GW_FD5,TBOX_OverSea
 SG_ HCU7_kwh_WhlDrvLifeGenEgy : 239|16@0+ (1,0) [0|65535] "kWh" TBOX,GW_FD5,TBOX_OverSea
 SG_ HCU7_kwhpkm_VehEgyCns : 255|8@0+ (1,0) [0|255] "kWh/km" TBOX,GW_FD5,TBOX_OverSea
 SG_ HCU7_Lp100km_FuCnsNormEV : 263|14@0+ (0.01,0) [0|100] "L/100km" TBOX,GW_FD5,TBOX_OverSea
 SG_ HCU7_kwhp100km_ECnsNormEV : 265|10@0+ (0.1,0) [0|100] "kmh/100km" TBOX,GW_FD5,TBOX_OverSea
 SG_ HCU7_kwhpL_FacFuToElecNormEV : 286|7@0+ (0.1,0) [0|10] "kmh/L" TBOX,GW_FD5,TBOX_OverSea
 SG_ HCU7_pct_EffRexSysNormEV : 294|7@0+ (1,0) [0|100] "%" TBOX,GW_FD5,TBOX_OverSea
 SG_ HCU7_Lp100km_FuCnsNormFHEV : 303|14@0+ (0.01,0) [0|100] "L/100km" TBOX,GW_FD5,TBOX_OverSea
 SG_ HCU7_kwhp100km_ECnsNormFHEV : 305|10@0+ (0.1,0) [0|100] "kmh/100km" TBOX,GW_FD5,TBOX_OverSea
 SG_ HCU7_kwhpL_FacFuToElecNormFHEV : 326|7@0+ (0.1,0) [0|10] "kmh/L" TBOX,GW_FD5,TBOX_OverSea
 SG_ HCU7_pct_EffRexSysNormFHEV : 334|7@0+ (1,0) [0|100] "%" TBOX,GW_FD5,TBOX_OverSea
 SG_ HCU7_Lp100km_FuCnsNormPREM : 343|14@0+ (0.01,0) [0|100] "L/100km" TBOX,GW_FD5,TBOX_OverSea
 SG_ HCU7_kwhp100km_ECnsNormPREM : 345|10@0+ (0.1,0) [0|100] "kmh/100km" TBOX,GW_FD5,TBOX_OverSea
 SG_ HCU7_kwhpL_FacFuToElecNormPREM : 366|7@0+ (0.1,0) [0|10] "kmh/L" TBOX,GW_FD5,TBOX_OverSea
 SG_ HCU7_pct_EffRexSysNormPREM : 374|7@0+ (1,0) [0|100] "%" TBOX,GW_FD5,TBOX_OverSea
 SG_ HCU7_Lp100km_FuCnsECOEV : 383|14@0+ (0.01,0) [0|100] "L/100km" TBOX,GW_FD5,TBOX_OverSea
 SG_ HCU7_kwhp100km_ECnsECOEV : 385|10@0+ (0.1,0) [0|100] "kmh/100km" TBOX,GW_FD5,TBOX_OverSea
 SG_ HCU7_kwhpL_FacFuToElecECOEV : 406|7@0+ (0.1,0) [0|10] "kmh/L" TBOX,GW_FD5,TBOX_OverSea
 SG_ HCU7_pct_EffRexSysECOEV : 414|7@0+ (1,0) [0|100] "%" TBOX,GW_FD5,TBOX_OverSea
 SG_ HCU7_Lp100km_FuCnsECOFHEV : 423|14@0+ (0.01,0) [0|100] "L/100km" TBOX,GW_FD5,TBOX_OverSea
 SG_ HCU7_kwhp100km_ECnsECOFHEV : 425|10@0+ (0.1,0) [0|100] "kmh/100km" TBOX,GW_FD5,TBOX_OverSea
 SG_ HCU7_kwhpL_FacFuToElecECOFHEV : 446|7@0+ (0.1,0) [0|10] "kmh/L" TBOX,GW_FD5,TBOX_OverSea
 SG_ HCU7_pct_EffRexSysECOFHEV : 454|7@0+ (1,0) [0|100] "%" TBOX,GW_FD5,TBOX_OverSea
 SG_ HCU7_Lp100km_FuCnsECOPREM : 463|14@0+ (0.01,0) [0|100] "L/100km" TBOX,GW_FD5,TBOX_OverSea
 SG_ HCU7_kwhp100km_ECnsECOPREM : 465|10@0+ (0.1,0) [0|100] "kmh/100km" TBOX,GW_FD5,TBOX_OverSea
 SG_ HCU7_kwhpL_FacFuToElecECOPREM : 486|7@0+ (0.1,0) [0|10] "kmh/L" TBOX,GW_FD5,TBOX_OverSea
 SG_ HCU7_pct_EffRexSysECOPREM : 494|7@0+ (1,0) [0|100] "%" TBOX,GW_FD5,TBOX_OverSea
 SG_ HCU7_Lp100km_FuCnsSpt : 503|14@0+ (0.01,0) [0|100] "L/100km" TBOX,GW_FD5,TBOX_OverSea

BO_ 856 HCU_Fr08_358: 32 PDCS_FD1
 SG_ HCU8_kwhpL_FacFuToElecSpt : 6|7@0+ (0.1,0) [0|10] "kmh/L" TBOX,GW_FD5,TBOX_OverSea
 SG_ HCU8_pct_EffRexSysSpt : 14|7@0+ (1,0) [0|100] "%" TBOX,GW_FD5,TBOX_OverSea
 SG_ HCU8_Lp100km_FuCnsTot : 23|14@0+ (0.01,0) [0|100] "L/100km" TBOX,GW_FD5,TBOX_OverSea
 SG_ HCU8_kwhp100km_ECnsTot : 25|10@0+ (0.1,0) [0|100] "kmh/100km" TBOX,GW_FD5,TBOX_OverSea
 SG_ HCU8_kwhpL_FacFuToElecTot : 46|7@0+ (0.1,0) [0|10] "kmh/L" TBOX,GW_FD5,TBOX_OverSea
 SG_ HCU8_pct_EffRexSysTot : 54|7@0+ (1,0) [0|100] "%" TBOX,GW_FD5,TBOX_OverSea
 SG_ HCU8_StVCM : 62|3@0+ (1,0) [0|7] "NoUnit" TBOX,GW_FD5,TBOX_OverSea
 SG_ HCU8_kwhp100km_ECnsSpt : 57|10@0+ (0.1,0) [0|100] "kmh/100km" TBOX,GW_FD5,TBOX_OverSea
 SG_ HCU8_VolRemainingFuel : 78|7@0+ (1,0) [0|127] "L" TBOX,GW_FD5,TBOX_OverSea
 SG_ HCU8_bAcvFuLeak : 79|1@0+ (1,0) [0|1] "NoUnit" TBOX,GW_FD5,TBOX_OverSea
 SG_ HCU8_FuelLevelEstimated : 86|7@0+ (1,0) [0|100] "%" TBOX,GW_FD5,TBOX_OverSea
 SG_ HCU8_bAcvRefu : 87|1@0+ (1,0) [0|1] "NoUnit" TBOX,GW_FD5,TBOX_OverSea
 SG_ HCU8_StInhbtEngStopReason : 95|16@0+ (1,0) [0|65535] "" TBOX,GW_FD5,TBOX_OverSea
 SG_ HCU8_StInhbtEngStartReason : 111|20@0+ (1,0) [0|1048575] "" TBOX,GW_FD5,TBOX_OverSea
 SG_ HCU8_Lp100km_FuCnsHEV : 135|14@0+ (0.01,0) [0|100] "L/100km" TBOX,GW_FD5,TBOX_OverSea
 SG_ HCU8_kwhp100km_ECnsHEV : 137|10@0+ (0.1,0) [0|100] "kmh/100km" TBOX,GW_FD5,TBOX_OverSea
 SG_ HCU8_kwhpL_FacFuToElecHEV : 158|7@0+ (0.1,0) [0|10] "kmh/L" TBOX,GW_FD5,TBOX_OverSea
 SG_ HCU8_pct_EffRexSysHEV : 166|7@0+ (1,0) [0|100] "%" TBOX,GW_FD5,TBOX_OverSea
 SG_ HCU8_EngStartReason : 175|16@0+ (1,0) [0|65535] "NoUnit" TBOX,GW_FD5,TBOX_OverSea
 SG_ HCU8_EngStopReason : 191|20@0+ (1,0) [0|1048575] "NoUnit" TBOX,GW_FD5,TBOX_OverSea
 SG_ HCU8_m_RexWorkingTolMilgKm : 215|24@0+ (0.1,0) [0|1677721.4] "NoUnit" Vector__XXX

BO_ 200 VCU_Fr01_0C8: 16 PDCS_FD1
 SG_ VCU1_Torque_Command : 7|16@0+ (0.05,-1024) [-1024|1024] "Nm" TBOX,GW_FD5,IDB,GW_FD3,MCU,TBOX_OverSea
 SG_ VCU1_Speed_Command : 23|16@0+ (0.5,-16000) [-16000|16000] "rpm" TBOX,GW_FD5,IDB,GW_FD3,MCU,TBOX_OverSea
 SG_ VCU1_MCUEnable : 33|1@0+ (1,0) [0|1] "NoUnit" TBOX,GW_FD5,MCU,TBOX_OverSea
 SG_ VCU1_Mode_Command : 36|3@0+ (1,0) [0|7] "NoUnit" TBOX,GW_FD5,IDB,GW_FD3,MCU,TBOX_OverSea
 SG_ VCU1_PMM_TmOuSt : 39|3@0+ (1,0) [0|7] "NoUnit" TBOX,GW_FD5,TBOX_OverSea
 SG_ VCU1_PMM_PwrUpSt : 42|3@0+ (1,0) [0|7] "NoUnit" TBOX,GW_FD5,TBOX_OverSea
 SG_ VCU1_HvEmgy_status : 43|1@0+ (1,0) [0|1] "NoUnit" TBOX,GW_FD5,BMS,MCU,TBOX_OverSea
 SG_ VCU1_MCUShakeRedn : 45|2@0+ (1,0) [0|3] "NoUnit" TBOX,GW_FD5,IDB,GW_FD3,MCU,TBOX_OverSea
 SG_ VCU1_VCMModeReq : 46|1@0+ (1,0) [0|1] "NoUnit" GW_FD3,ISC
 SG_ VCU1_VCMPwrDwnCmd : 47|1@0+ (1,0) [0|1] "NoUnit" GW_FD3,ISC
 SG_ VCU1_AliveCounter : 51|4@0+ (1,0) [0|15] "NoUnit" IDB,GW_FD3,MCU
 SG_ VCU1_PMM_PwrDwnSt : 54|3@0+ (1,0) [0|7] "NoUnit" TBOX,GW_FD5,TBOX_OverSea
 SG_ VCU_OBDMilLightReq : 55|1@0+ (1,0) [0|1] "NoUnit" EMS
 SG_ VCU1_Checksum : 63|8@0+ (1,0) [0|255] "NoUnit" IDB,GW_FD3,MCU
 SG_ VCU1_FMCUTorque_Command : 71|16@0+ (0.05,-1024) [-1024|1024] "Nm" TBOX,GW_FD5,IDB,GW_FD3,MCU,TBOX_OverSea
 SG_ VCU1_FMCUSpeed_Command : 87|16@0+ (0.5,-16000) [-16000|16000] "rpm" TBOX,GW_FD5,IDB,GW_FD3,MCU,TBOX_OverSea
 SG_ VCU1_DisBatt2PMM : 96|1@0+ (1,0) [0|1] "NoUnit" BMS
 SG_ VCU1_FMCUEnable : 97|1@0+ (1,0) [0|1] "NoUnit" TBOX,GW_FD5,MCU,TBOX_OverSea
 SG_ VCU1_FMCUMode_Command : 100|3@0+ (1,0) [0|7] "NoUnit" TBOX,GW_FD5,IDB,GW_FD3,MCU,TBOX_OverSea
 SG_ VCU1_RexVCMProcess : 103|3@0+ (1,0) [0|7] "NoUnit" MCU
 SG_ VCU1_AppWrkSts : 106|3@0+ (1,0) [0|7] "NoUnit" BMS
 SG_ VCU1_FMCUHvEmgy_status : 107|1@0+ (1,0) [0|1] "NoUnit" TBOX,GW_FD5,BMS,MCU,TBOX_OverSea
 SG_ VCU1_FMCUShakeRedn : 109|2@0+ (1,0) [0|3] "NoUnit" TBOX,GW_FD5,IDB,GW_FD3,MCU,TBOX_OverSea
 SG_ VCU1_BTVSleepRdyFlg : 110|1@0+ (1,0) [0|1] "NoUnit" Vector__XXX
 SG_ VCU1_HvPwrUpTmOutFlg : 111|1@0+ (1,0) [0|1] "NoUnit" Vector__XXX

BO_ 227 VCU_Fr05_0E3: 8 PDCS_FD1
 SG_ VCU5_ActGear : 2|3@0+ (1,0) [0|7] "NoUnit" PDCU,IDB,ESC_FD3,ADCU_FD3,EHB_FD3,CDCS,ICU_E02,SRR3,SRR4,BDCS,DDCU,ADCS_FD3,CDCS_OverSea,IMU,TBOX,FLC_ME_FD3,ACU,FLC_FD3,GW_FD5,GW_FD6,GW_FD3,GW_FD4,ICU,GW_FD2,TBOX_OverSea
 SG_ VCU5_ActGearValid : 3|1@0+ (1,0) [0|1] "NoUnit" PDCU,IDB,ESC_FD3,ADCU_FD3,EHB_FD3,CDCS,ICU_E02,SRR3,SRR4,BDCS,DDCU,ADCS_FD3,CDCS_OverSea,IMU,TBOX,FLC_ME_FD3,ACU,FLC_FD3,GW_FD5,GW_FD6,GW_FD3,GW_FD4,ICU,GW_FD2,TBOX_OverSea
 SG_ VCU5_READYLightSts : 4|1@0+ (1,0) [0|1] "NoUnit" PDCU,IDB,ESC_FD3,ADCU_FD3,EPS,WPC,EHB_FD3,CDCS,CDU,ICU_E02,ISC,AMP,BMS,EMS,BDCS,DDCU,ADCS_FD3,CDCS_OverSea,TBOX,FLC_ME_FD3,ACU,FLC_FD3,GW_FD5,GCU,GW_FD3,GW_FD4,ICU,GW_FD2,MCU,TBOX_OverSea
 SG_ VCU5_HVIL_Attach : 5|1@0+ (1,0) [0|1] "NoUnit" TBOX,GW_FD5,GW_FD4,CDCS,CDCS_OverSea,TBOX_OverSea
 SG_ VCU5_PwrTrainFailureLevel : 7|2@0+ (1,0) [0|3] "NoUnit" ADCU_FD3,CDCS,ADCS_FD3,CDCS_OverSea,TBOX,FLC_ME_FD3,FLC_FD3,GW_FD5,GW_FD3,GW_FD4,TBOX_OverSea
 SG_ VCU5_HVIL_MajorLoop : 8|1@0+ (1,0) [0|1] "NoUnit" TBOX,GW_FD5,GW_FD4,CDCS,CDCS_OverSea,TBOX_OverSea
 SG_ VCU5_RangeModeFb : 10|2@0+ (1,0) [0|3] "NoUnit" TBOX,GW_FD5,GW_FD4,CDCS,CDCS_OverSea,TBOX_OverSea
 SG_ VCU5_HVReady : 11|1@0+ (1,0) [0|1] "NoUnit" IDB,ADCU_FD3,BDCS,CDCS,ADCS_FD3,CDCS_OverSea,TBOX,FLC_ME_FD3,FLC_FD3,GW_FD5,ICU_E02,GW_FD3,GW_FD4,GW_FD1,ICU,GW_FD2,TBOX_OverSea
 SG_ VCU5_HubMode : 12|1@0+ (1,0) [0|1] "NoUnit" TBOX,GW_FD5,IDB,ESC_FD3,GW_FD3,BMS,EHB_FD3,TBOX_OverSea
 SG_ VCU5_StartOffFlagReq : 13|1@0+ (1,0) [0|1] "NoUnit" TBOX,GW_FD5,GW_FD2,BDCS,TBOX_OverSea
 SG_ VCU5_EmuEngineSts : 14|1@0+ (1,0) [0|1] "NoUnit" IDB,ADCU_FD3,BDCS,ADCS_FD3,TBOX,FLC_ME_FD3,FLC_FD3,GW_FD5,GW_FD3,GW_FD2,TBOX_OverSea
 SG_ VCU5_AccelPositionValid : 15|1@0+ (1,0) [0|1] "NoUnit" IDB,ESC_FD3,ADCU_FD3,EHB_FD3,CDCS,CDU,ICU_E02,BMS,EMS,BDCS,ADCS_FD3,CDCS_OverSea,TBOX,FLC_ME_FD3,ACU,FLC_FD3,GW_FD5,GCU,GW_FD3,GW_FD4,ICU,GW_FD2,MCU,TBOX_OverSea
 SG_ VCU5_GearRatio : 23|16@0+ (0.001,0) [0|20] "NoUnit" TBOX,GW_FD5,IDB,ESC_FD3,GW_FD3,EHB_FD3,TBOX_OverSea
 SG_ VCU5_AccelPosition : 39|8@0+ (1,0) [0|100] "%" IDB,ESC_FD3,ADCU_FD3,EHB_FD3,CDCS,CDU,ICU_E02,BMS,EMS,BDCS,ADCS_FD3,CDCS_OverSea,TBOX,FLC_ME_FD3,ACU,FLC_FD3,GW_FD5,GCU,GW_FD3,GW_FD4,ICU,GW_FD2,MCU,TBOX_OverSea
 SG_ VCU5_LBatt_Voltage : 47|8@0+ (0.1,0) [0|18] "V" IDB,ESC_FD3,WPC,EHB_FD3,BDCS,CDCS,CDCS_OverSea,TBOX,GW_FD5,GW_FD3,GW_FD4,GW_FD2,MCU,TBOX_OverSea
 SG_ VCU5_AliveCounter : 51|4@0+ (1,0) [0|15] "NoUnit" IDB,ESC_FD3,ADCU_FD3,EMS,EHB_FD3,ADCS_FD3,TBOX,FLC_ME_FD3,FLC_FD3,GW_FD5,GW_FD3,TBOX_OverSea
 SG_ VCU5_DriveMode_fb : 54|3@0+ (1,0) [0|7] "NoUnit" ADCU_FD3,BDCS,CDCS,ADCS_FD3,CDCS_OverSea,TBOX,FLC_ME_FD3,FLC_FD3,GW_FD5,GW_FD3,ISC,GW_FD4,GW_FD2,MCU,TBOX_OverSea
 SG_ VCU5_DriverOvertakeMode : 55|1@0+ (1,0) [0|1] "NoUnit" IDB,ESC_FD3,ADCU_FD3,EHB_FD3,ADCS_FD3,TBOX,FLC_ME_FD3,FLC_FD3,GW_FD5,GW_FD3,TBOX_OverSea
 SG_ VCU5_Checksum : 63|8@0+ (1,0) [0|255] "NoUnit" IDB,ESC_FD3,ADCU_FD3,EMS,EHB_FD3,ADCS_FD3,TBOX,FLC_ME_FD3,FLC_FD3,GW_FD5,GW_FD3,TBOX_OverSea

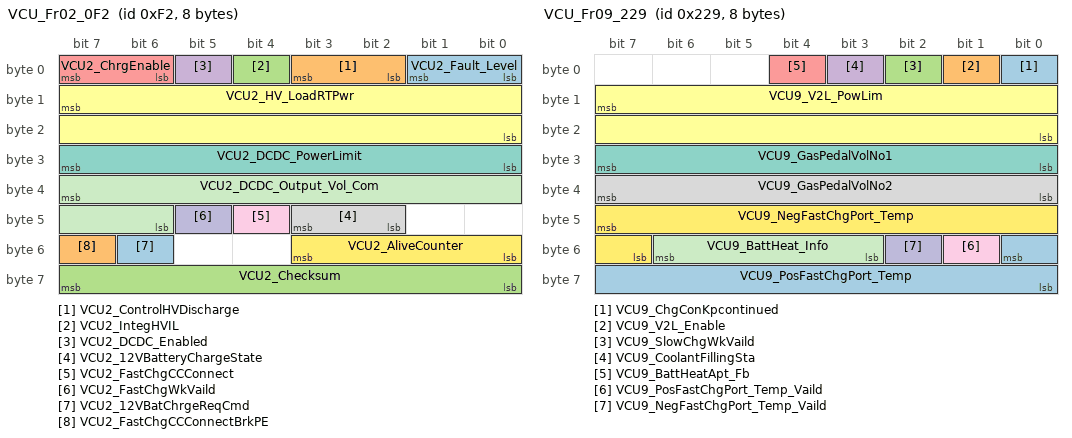
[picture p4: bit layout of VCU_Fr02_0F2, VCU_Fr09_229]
BO_ 242 VCU_Fr02_0F2: 8 PDCS_FD1
 SG_ VCU2_Fault_Level : 1|2@0+ (1,0) [0|3] "NoUnit" TBOX,GW_FD5,TBOX_OverSea
 SG_ VCU2_ControlHVDischarge : 3|2@0+ (1,0) [0|3] "NoUnit" TBOX,CDU,GW_FD5,BMS,TBOX_OverSea
 SG_ VCU2_IntegHVIL : 4|1@0+ (1,0) [0|1] "NoUnit" TBOX,GW_FD5,TBOX_OverSea
 SG_ VCU2_DCDC_Enabled : 5|1@0+ (1,0) [0|1] "NoUnit" TBOX,CDU,GW_FD5,TBOX_OverSea
 SG_ VCU2_ChrgEnable : 7|2@0+ (1,0) [0|3] "NoUnit" TBOX,CDU,GW_FD5,BMS,TBOX_OverSea
 SG_ VCU2_HV_LoadRTPwr : 15|16@0+ (1,0) [0|65535] "W" TBOX,GW_FD5,BMS,TBOX_OverSea
 SG_ VCU2_DCDC_PowerLimit : 31|8@0+ (0.02,0) [0|5] "Kw" TBOX,CDU,GW_FD5,TBOX_OverSea
 SG_ VCU2_12VBatteryChargeState : 43|2@0+ (1,0) [0|3] "NoUnit" TBOX,GW_FD5,BMS,TBOX_OverSea
 SG_ VCU2_FastChgCCConnect : 44|1@0+ (1,0) [0|1] "NoUnit" TBOX,CDU,GW_FD5,BMS,TBOX_OverSea
 SG_ VCU2_FastChgWkVaild : 45|1@0+ (1,0) [0|1] "NoUnit" TBOX,GW_FD5,BMS,TBOX_OverSea
 SG_ VCU2_DCDC_Output_Vol_Com : 39|10@0+ (0.05,0) [0|51.15] "V" TBOX,CDU,GW_FD5,TBOX_OverSea
 SG_ VCU2_AliveCounter : 51|4@0+ (1,0) [0|15] "NoUnit" CDU,BMS
 SG_ VCU2_12VBatChrgeReqCmd : 54|1@0+ (1,0) [0|1] "NoUnit" Vector__XXX
 SG_ VCU2_FastChgCCConnectBrkPE : 55|1@0+ (1,0) [0|1] "NoUnit" BMS
 SG_ VCU2_Checksum : 63|8@0+ (1,0) [0|255] "NoUnit" CDU,BMS

BO_ 251 VCU_Fr06_0FB: 16 PDCS_FD1
 SG_ VCU6_StopModeFb : 1|2@0+ (1,0) [0|3] "NoUnit" IDB,ESC_FD3,EHB_FD3,CDCS,CDCS_OverSea,TBOX,GW_FD5,GW_FD3,ISC,GW_FD4,MCU,TBOX_OverSea
 SG_ VCU6_MotorDrvMode : 2|1@0+ (1,0) [0|1] "NoUnit" TBOX,GW_FD5,TBOX_OverSea
 SG_ VCU6_PMM_SysSt : 5|3@0+ (1,0) [0|7] "NoUnit" TBOX,GW_FD5,GW_FD2,BDCS,TBOX_OverSea
 SG_ VCU6_Lock_Status : 7|2@0+ (1,0) [0|3] "NoUnit" TBOX,GW_FD5,ICU_E02,BMS,GW_FD4,ICU,TBOX_OverSea
 SG_ VCU6_BrakeSts : 9|2@0+ (1,0) [0|3] "NoUnit" TBOX,GW_FD5,GW_FD2,BDCS,MCU,TBOX_OverSea
 SG_ VCU6_BrakeStsValid : 10|1@0+ (1,0) [0|1] "NoUnit" TBOX,GW_FD5,GW_FD2,BDCS,MCU,TBOX_OverSea
 SG_ VCU6_DispGearFltRemind : 13|3@0+ (1,0) [0|7] "NoUnit" ICU_E02,GW_FD3,ISC,GW_FD4,ICU,CDCS,CDCS_OverSea
 SG_ VCU6_ParkCtrlOvrTime : 14|1@0+ (1,0) [0|1] "NoUnit" ICU_E02,IDB,ESC_FD3,GW_FD3,ISC,GW_FD4,ICU,EHB_FD3,CDCS,CDCS_OverSea
 SG_ VCU6_EPBBackupCtrlAail : 15|1@0+ (1,0) [0|1] "NoUnit" IDB,ESC_FD3,GW_FD3,ISC,EHB_FD3
 SG_ VCU6_EnergyRecLevelSts : 25|2@0+ (1,0) [0|3] "NoUnit" TBOX,GW_FD5,ICU_E02,GW_FD4,ICU,CDCS,CDCS_OverSea,TBOX_OverSea
 SG_ VCU6_SystemWarnLightSts : 26|1@0+ (1,0) [0|1] "NoUnit" ADCU_FD3,CDCS,ADCS_FD3,CDCS_OverSea,TBOX,GW_FD5,ICU_E02,GW_FD3,GW_FD4,ICU,TBOX_OverSea
 SG_ VCU6_RegenFlg : 27|1@0+ (1,0) [0|1] "NoUnit" TBOX,GW_FD5,GW_FD2,BDCS,TBOX_OverSea
 SG_ VCU6_ResidualOdometer : 23|12@0+ (1,0) [0|4000] "Km" BDCS,BAM,CDCS,CDCS_OverSea,TBOX,GW_FD5,ICU_E02,GW_FD4,ICU,GW_FD2,TBOX_OverSea
 SG_ VCU6_PNLelFault : 32|1@0+ (1,0) [0|1] "NoUnit" TBOX,GW_FD5,ICU_E02,GW_FD4,ICU,GW_FD2,BDCS,CDCS,CDCS_OverSea,TBOX_OverSea
 SG_ VCU6_SOCWarningLightSts : 33|1@0+ (1,0) [0|1] "NoUnit" TBOX,GW_FD5,ICU_E02,GW_FD4,ICU,CDCS,CDCS_OverSea,TBOX_OverSea
 SG_ VCU6_12VBatChargeFaultSts : 34|1@0+ (1,0) [0|1] "NoUnit" TBOX,GW_FD5,ICU_E02,GW_FD4,ICU,CDCS,CDCS_OverSea,TBOX_OverSea
 SG_ VCU6_SystemFaultWarn_Light : 35|1@0+ (1,0) [0|1] "NoUnit" TBOX,GW_FD5,ICU_E02,GW_FD4,ICU,CDCS,CDCS_OverSea,TBOX_OverSea
 SG_ VCU6_AuthStatus : 37|2@0+ (1,0) [0|3] "NoUnit" ICU_E02,GW_FD4,ICU,GW_FD2,BDCS,CDCS,CDCS_OverSea
 SG_ VCU6_onepedal_WorkSts : 39|2@0+ (1,0) [0|3] "NoUnit" IDB,ESC_FD3,EHB_FD3,BDCS,CDCS,CDCS_OverSea,ICU_E02,GW_FD3,ISC,GW_FD4,ICU,GW_FD2,MCU
 SG_ VCU6_GearShftRmn : 43|4@0+ (1,0) [0|15] "NoUnit" ICU_E02,GW_FD3,ISC,GW_FD4,ICU,CDCS,CDCS_OverSea
 SG_ VCU6_DiagThmStsFltLvl : 45|2@0+ (1,0) [0|3] "NoUnit" ICU_E02,GW_FD4,ICU
 SG_ VCU6_RpBatt_Sts : 47|2@0+ (1,0) [0|3] "NoUnit" BMS
 SG_ VCU6_AliveCounter : 51|4@0+ (1,0) [0|15] "NoUnit" ICU_E02,IDB,ESC_FD3,GW_FD3,ISC,BMS,GW_FD4,GW_FD2,EHB_FD3,BDCS
 SG_ VCU6_ReadyLost_CheckFlt : 52|1@0+ (1,0) [0|1] "NoUnit" ICU_E02,GW_FD4,ICU,CDCS,CDCS_OverSea
 SG_ VCU6_GearFlt_CheckGear : 53|1@0+ (1,0) [0|1] "NoUnit" ICU_E02,GW_FD3,ISC,GW_FD4,ICU,CDCS,CDCS_OverSea
 SG_ VCU6_ChargeConnKpTempSw_Fb : 55|2@0+ (1,0) [0|3] "NoUnit" GW_FD4,CDCS,CDCS_OverSea
 SG_ VCU6_Checksum : 63|8@0+ (1,0) [0|255] "NoUnit" ICU_E02,IDB,ESC_FD3,GW_FD3,ISC,BMS,GW_FD4,GW_FD2,EHB_FD3,BDCS
 SG_ VCU6_StrtgyGear : 66|3@0+ (1,0) [0|7] "NoUnit" IDB,ESC_FD3,ADCU_FD3,BMS,EHB_FD3,BDCS,BAM,CDCS,ADCS_FD3,CDCS_OverSea,TBOX,ACU,CDU,GW_FD5,GW_FD3,ISC,GW_FD4,GW_FD2,MCU,TBOX_OverSea
 SG_ VCU6_DispGear : 69|3@0+ (1,0) [0|7] "NoUnit" BMS,BAM,CDCS,CDCS_OverSea,TBOX,CDU,GW_FD5,ICU_E02,GW_FD3,ISC,GW_FD4,ICU,GW_FD2,TBOX_OverSea
 SG_ VCU6_PGearFlt : 70|1@0+ (1,0) [0|1] "NoUnit" ICU_E02,GW_FD4,ICU,CDCS,CDCS_OverSea
 SG_ VCU6_TracModeEPBRelsReq : 71|1@0+ (1,0) [0|1] "NoUnit" IDB,ESC_FD3,GW_FD3,ISC,EHB_FD3
 SG_ VCU6_PumpMWorkSts : 79|8@0+ (1,0) [0|100] "%" GW_FD2,BDCS,MCU
 SG_ VCU6_PumpMReq : 87|8@0+ (1,0) [0|100] "%" GW_FD2,BDCS,MCU
 SG_ VCU6_AccelPositionD : 95|8@0+ (1,0) [0|100] "%" CDU,IDB,GCU,GW_FD3,EMS,MCU
 SG_ VCU6_AccelPositionE : 103|8@0+ (1,0) [0|100] "%" CDU,IDB,GCU,GW_FD3,EMS,MCU
 SG_ VCU6_EnergyRecyleWarn : 115|2@0+ (1,0) [0|3] "NoUnit" ICU_E02,GW_FD4,ICU,CDCS,CDCS_OverSea
 SG_ VCU6_FltRollgNum : 111|9@0+ (1,0) [0|511] "NoUnit" Vector__XXX

BO_ 252 VCU_Fr07_0FC: 32 PDCS_FD1
 SG_ VCU7_DrvWheelTorqueReq : 7|16@0+ (0.5,-16000) [-16000|16000] "Nm" IDB,ESC_FD3,GW_FD3,ISC,EHB_FD3
 SG_ VCU7_MaxMotPosTq : 23|16@0+ (0.05,0) [0|350] "Nm" IDB,ESC_FD3,GW_FD3,ISC,ADCU_FD3,EHB_FD3,MCU,ADCS_FD3
 SG_ VCU7_MaxMotGenTq : 39|16@0+ (0.05,0) [0|350] "Nm" IDB,ESC_FD3,GW_FD3,ISC,ADCU_FD3,EHB_FD3,MCU,ADCS_FD3
 SG_ VCU7_Fr07_AliveCounter : 51|4@0+ (1,0) [0|15] "NoUnit" IDB,ESC_FD3,GW_FD3,ISC,EHB_FD3,MCU
 SG_ VCU7_FrntAxleWhlTqDemValid : 54|1@0+ (1,0) [0|1] "NoUnit" IDB,ESC_FD3,GW_FD3,ISC,EHB_FD3
 SG_ VCU7_ReAxleWhlTqDemValid : 55|1@0+ (1,0) [0|1] "NoUnit" IDB,ESC_FD3,GW_FD3,ISC,EHB_FD3
 SG_ VCU7_Fr07_Checksum : 63|8@0+ (1,0) [0|255] "NoUnit" IDB,ESC_FD3,GW_FD3,ISC,EHB_FD3,MCU
 SG_ VCU7_FrntAxleWhlTqDem : 71|16@0+ (1,-16000) [-16000|16000] "Nm" IDB,ESC_FD3,GW_FD3,ISC,EHB_FD3
 SG_ VCU7_MaxFMotPosTq : 87|16@0+ (0.05,0) [0|350] "Nm" IDB,ESC_FD3,GW_FD3,ISC,ADCU_FD3,EHB_FD3,MCU,ADCS_FD3
 SG_ VCU7_MaxFMotGenTq : 103|16@0+ (0.05,0) [0|350] "Nm" IDB,ESC_FD3,GW_FD3,ISC,ADCU_FD3,EHB_FD3,MCU,ADCS_FD3
 SG_ VCU7_ReAxleWhlTqDem : 119|16@0+ (1,-16000) [-16000|16000] "Nm" IDB,ESC_FD3,GW_FD3,ISC,EHB_FD3
 SG_ VCU7_FrntMotDrvTqWhlLim : 135|16@0+ (1,-16000) [-16000|16000] "Nm" IDB,ESC_FD3,GW_FD3,ISC,EHB_FD3
 SG_ VCU7_FrntMotRgnTqWhlLim : 151|16@0+ (1,-16000) [-16000|16000] "Nm" IDB,ESC_FD3,GW_FD3,ISC,EHB_FD3
 SG_ VCU7_ReMotDrvTqWhlLim : 167|16@0+ (1,-16000) [-16000|16000] "Nm" IDB,ESC_FD3,GW_FD3,ISC,EHB_FD3
 SG_ VCU7_ReMotRgnTqWhlLim : 183|16@0+ (1,-16000) [-16000|16000] "Nm" IDB,ESC_FD3,GW_FD3,ISC,EHB_FD3
 SG_ VCU7_FrntAxleWhlTqCommd : 199|16@0+ (1,-16000) [-16000|16000] "Nm" IDB,ESC_FD3,GW_FD3,ISC,EHB_FD3
 SG_ VCU7_ReAxleWhlTqCommd : 215|16@0+ (1,-16000) [-16000|16000] "Nm" IDB,ESC_FD3,GW_FD3,ISC,EHB_FD3
 SG_ VCU7_FrntMotDrvTqWhlLimValid : 228|1@0+ (1,0) [0|1] "NoUnit" IDB,ESC_FD3,GW_FD3,ISC,EHB_FD3
 SG_ VCU7_FrntMotRgnTqWhlLimValid : 229|1@0+ (1,0) [0|1] "NoUnit" IDB,ESC_FD3,GW_FD3,ISC,EHB_FD3
 SG_ VCU7_ReMotDrvTqWhlLimValid : 230|1@0+ (1,0) [0|1] "NoUnit" IDB,ESC_FD3,GW_FD3,ISC,EHB_FD3
 SG_ VCU7_ReMotRgnTqWhlLimValid : 231|1@0+ (1,0) [0|1] "NoUnit" IDB,ESC_FD3,GW_FD3,ISC,EHB_FD3

BO_ 553 VCU_Fr09_229: 8 PDCS_FD1
 SG_ VCU9_ChgConKpcontinued : 0|1@0+ (1,0) [0|1] "NoUnit" TBOX,GW_FD5,BMS,GW_FD4,CDCS,CDCS_OverSea,TBOX_OverSea
 SG_ VCU9_V2L_Enable : 1|1@0+ (1,0) [0|1] "NoUnit" TBOX,GW_FD5,BMS,TBOX_OverSea
 SG_ VCU9_SlowChgWkVaild : 2|1@0+ (1,0) [0|1] "NoUnit" TBOX,GW_FD5,BMS,TBOX_OverSea
 SG_ VCU9_CoolantFillingSta : 3|1@0+ (1,0) [0|1] "NoUnit" GW_FD4,GW_FD2,BDCS,CDCS,CDCS_OverSea
 SG_ VCU9_BattHeatApt_Fb : 4|1@0+ (1,0) [0|1] "NoUnit" TBOX,GW_FD5,BMS,GW_FD4,CDCS,CDCS_OverSea,TBOX_OverSea
 SG_ VCU9_V2L_PowLim : 15|16@0+ (5,0) [0|320000] "W" TBOX,GW_FD5,BMS,TBOX_OverSea
 SG_ VCU9_GasPedalVolNo1 : 31|8@0+ (0.1,0) [0|22.5] "V" TBOX,GW_FD5,TBOX_OverSea
 SG_ VCU9_GasPedalVolNo2 : 39|8@0+ (0.1,0) [0|22.5] "V" TBOX,GW_FD5,TBOX_OverSea
 SG_ VCU9_PosFastChgPort_Temp_Vaild : 49|1@0+ (1,0) [0|1] "NoUnit" BMS
 SG_ VCU9_NegFastChgPort_Temp_Vaild : 50|1@0+ (1,0) [0|1] "NoUnit" BMS
 SG_ VCU9_BattHeat_Info : 54|4@0+ (1,0) [0|15] "NoUnit" TBOX,GW_FD5,BMS,GW_FD4,CDCS,CDCS_OverSea,TBOX_OverSea
 SG_ VCU9_NegFastChgPort_Temp : 47|9@0+ (1,-40) [-40|300] "℃" TBOX,GW_FD5,BMS,TBOX_OverSea
 SG_ VCU9_PosFastChgPort_Temp : 48|9@0+ (1,-40) [-40|300] "℃" TBOX,GW_FD5,BMS,TBOX_OverSea

BO_ 724 VCU_Fr04_2D4: 32 PDCS_FD1
 SG_ VCU4_BattWtrInTReq : 7|8@0+ (1,-40) [-40|125] "" TBOX,GW_FD5,GW_FD2,BDCS,TBOX_OverSea
 SG_ VCU4_CLM_PoweLimitedSts : 10|3@0+ (1,0) [0|7] "NoUnit" TBOX,GW_FD5,GW_FD2,BDCS,TBOX_OverSea
 SG_ VCU4_VINEolUnImplnt : 11|1@0+ (1,0) [0|1] "NoUnit" TBOX,GW_FD5,TBOX_OverSea
 SG_ VCU4_ChgWake : 14|1@0+ (1,0) [0|1] "NoUnit" TBOX,GW_FD5,ICU_E02,GW_FD4,ICU,CDCS,CDCS_OverSea,TBOX_OverSea
 SG_ VCU4_VINImps : 15|1@0+ (1,0) [0|1] "NoUnit" TBOX,GW_FD5,TBOX_OverSea
 SG_ VCU4_CLM_PTCPumpFailCode : 17|2@0+ (1,0) [0|3] "NoUnit" TBOX,GW_FD5,GW_FD2,BDCS,TBOX_OverSea
 SG_ VCU4_CLM_FanFailCode : 19|2@0+ (1,0) [0|3] "NoUnit" TBOX,GW_FD5,GW_FD2,BDCS,TBOX_OverSea
 SG_ VCU4_CCS_Status : 23|4@0+ (1,0) [0|15] "NoUnit" TBOX,ACU,GW_FD5,ICU_E02,GW_FD4,ICU,CDCS,CDCS_OverSea,TBOX_OverSea
 SG_ VCU4_CCS_target_Speed : 31|8@0+ (1,0) [0|255] "Km/h" TBOX,GW_FD5,ICU_E02,GW_FD4,ICU,CDCS,CDCS_OverSea,TBOX_OverSea
 SG_ VCU4_CLM_PTCWorkSts : 39|8@0+ (1,0) [0|100] "%" TBOX,GW_FD5,GW_FD2,BDCS,TBOX_OverSea
 SG_ VCU4_CLM_FanGearSts : 41|2@0+ (1,0) [0|3] "NoUnit" TBOX,GW_FD5,GW_FD2,BDCS,TBOX_OverSea
 SG_ VCU4_CLM_PowerPermittedV : 42|1@0+ (1,0) [0|1] "NoUnit" TBOX,GW_FD5,GW_FD2,BDCS,TBOX_OverSea
 SG_ VCU4_CLM_PowerPermitted : 47|5@0+ (0.5,0) [0|15] "Kw" TBOX,GW_FD5,GW_FD2,BDCS,TBOX_OverSea
 SG_ VCU4_BattHeatLvl : 50|3@0+ (1,0) [0|7] "NoUnit" TBOX,GW_FD5,GW_FD2,BDCS,TBOX_OverSea
 SG_ VCU4_ChgConKpTemp : 51|1@0+ (1,0) [0|1] "NoUnit" TBOX,GW_FD5,BMS,TBOX_OverSea
 SG_ VCU4_BattCoolLvl : 54|3@0+ (1,0) [0|7] "NoUnit" TBOX,GW_FD5,GW_FD2,BDCS,TBOX_OverSea
 SG_ VCU4_LearnSts : 55|1@0+ (1,0) [0|1] "NoUnit" TBOX,GW_FD5,TBOX_OverSea
 SG_ VCU4_BattPmpSpdReq : 63|8@0+ (1,0) [0|100] "%" TBOX,GW_FD5,BMS,GW_FD2,BDCS,TBOX_OverSea
 SG_ VCU4_LeftExtFanSpd : 70|7@0+ (1,0) [0|100] "%" GW_FD2,BDCS
 SG_ VCU4_LeftExtFanFlt : 71|1@0+ (1,0) [0|1] "NoUnit" GW_FD2,BDCS
 SG_ VCU4_RightExtFanSpd : 78|7@0+ (1,0) [0|100] "%" GW_FD2,BDCS
 SG_ VCU4_RightExtFanFlt : 79|1@0+ (1,0) [0|1] "NoUnit" GW_FD2,BDCS
 SG_ VCU4_PumpHReq : 87|8@0+ (1,0) [0|100] "%" GW_FD2,BDCS
 SG_ VCU4_TWV2Req : 95|8@0+ (1,0) [0|100] "%" GW_FD2,BDCS
 SG_ VCU4_TWV3Req : 103|8@0+ (1,0) [0|100] "%" GW_FD2,BDCS
 SG_ VCU4_TWV4Req : 111|8@0+ (1,0) [0|100] "%" GW_FD2,BDCS
 SG_ VCU4_FWVReq : 119|8@0+ (1,0) [0|100] "%" GW_FD2,BDCS
 SG_ VCU4_AGSPositionActSts : 127|4@0+ (1,0) [0|15] "NoUnit" GW_FD2,BDCS,CDCS,CDCS_OverSea
 SG_ VCU4_MotlnpWtrT : 122|11@0+ (0.1,-48) [-48|125] "℃" GW_FD2,BDCS
 SG_ VCU4_CCSetFail_Indication : 143|2@0+ (1,0) [0|3] "NoUnit" GW_FD4,CDCS,CDCS_OverSea
 SG_ VCU4_BattInstEnergyCosum : 154|11@0+ (0.1,-100) [-100|100] "kWs" GW_FD4,CDCS,CDCS_OverSea
 SG_ VCU4_DrivingPowerPercentage : 175|8@0+ (1,-100) [-100|100] "%" ICU_E02,GW_FD4,ICU,CDCS,CDCS_OverSea
 SG_ VCU4_BattPmpWorkSts : 183|8@0+ (1,0) [0|100] "%" Vector__XXX
 SG_ VCU4_DrivingPower : 191|12@0+ (1,-512) [-512|512] "" ICU_E02,GW_FD4,ICU,CDCS,CDCS_OverSea

BO_ 809 VCU_Fr10_329: 32 PDCS_FD1
 SG_ VCU10_Odometer : 7|24@0+ (0.1,0) [0|1677721.4] "NoUnit" TBOX,GW_FD5,ICU_E02,GW_FD4,ICU,GW_FD2,BDCS,TBOX_OverSea
 SG_ VCU10_MotCircWtrPumWrkSts : 31|16@0+ (0.1,0) [0|100] "%" TBOX,GW_FD5,TBOX_OverSea
 SG_ VCU10_IBS_ERROR_Commom : 43|1@0+ (1,0) [0|1] "NoUnit" GW_FD4,CDCS,CDCS_OverSea
 SG_ VCU10_SOC_LOW : 44|1@0+ (1,0) [0|1] "NoUnit" ICU_E02,GW_FD4,ICU
 SG_ VCU10_GasPedalFault : 45|1@0+ (1,0) [0|1] "NoUnit" TBOX,GW_FD5,TBOX_OverSea
 SG_ VCU10_GasPedaExcessAmplitude : 46|1@0+ (1,0) [0|1] "NoUnit" TBOX,GW_FD5,TBOX_OverSea
 SG_ VCU10_BMSCommFault : 47|1@0+ (1,0) [0|1] "NoUnit" TBOX,GW_FD5,TBOX_OverSea
 SG_ VCU10_VehRunning_Status : 66|3@0+ (1,0) [0|7] "" TBOX,GW_FD5,GW_FD4,CDCS,CDCS_OverSea,TBOX_OverSea
 SG_ VCU10_Channel1_speed : 69|2@0+ (1,0) [0|3] "" GW_FD4,CDCS,CDCS_OverSea
 SG_ VCU10_MotorDrive_Status : 71|2@0+ (1,0) [0|3] "" TBOX,GW_FD5,GW_FD4,CDCS,CDCS_OverSea,TBOX_OverSea
 SG_ VCU10_Channel2_speed : 79|2@0+ (1,0) [0|3] "" GW_FD4,CDCS,CDCS_OverSea
 SG_ VCU10_Energy_total : 76|13@0+ (0.1,0) [0|500] "kw" TBOX,GW_FD5,GW_FD4,CDCS,CDCS_OverSea,TBOX_OverSea
 SG_ VCU10_Energy_drv : 92|13@0+ (0.1,0) [0|500] "kw" TBOX,GW_FD5,GW_FD4,CDCS,CDCS_OverSea,TBOX_OverSea
 SG_ VCU10_Energy_ac : 108|13@0+ (0.1,0) [0|500] "kw" TBOX,GW_FD5,GW_FD4,CDCS,CDCS_OverSea,TBOX_OverSea
 SG_ VCU10_Energy_elc : 124|13@0+ (0.1,0) [0|500] "kw" TBOX,GW_FD5,GW_FD4,CDCS,CDCS_OverSea,TBOX_OverSea
 SG_ VCU10_Energy_rep : 140|13@0+ (0.1,0) [0|500] "kw" TBOX,GW_FD5,GW_FD4,CDCS,CDCS_OverSea,TBOX_OverSea
 SG_ VCU10_Energy_wid : 156|13@0+ (0.1,0) [0|500] "kw" TBOX,GW_FD5,GW_FD4,CDCS,CDCS_OverSea,TBOX_OverSea
 SG_ VCU10_Energy_Average : 172|13@0+ (0.1,0) [0|500] "Kwh/Km" TBOX,GW_FD5,GW_FD4,CDCS,CDCS_OverSea,TBOX_OverSea

BO_ 152 VCU_Fr0D_098: 16 PDCS_FD3
 SG_ VCU13_TotalMotRgnTqWhlLim : 7|16@0+ (1,-16000) [-16000|16000] "Nm" TBOX,GW_FD5,IDB,ESC_FD3,ISC,EHB_FD3,TBOX_OverSea
 SG_ VCU13_TotalMotDrvTqWhlLim : 23|16@0+ (1,-16000) [-16000|16000] "Nm" TBOX,GW_FD5,IDB,ESC_FD3,ISC,EHB_FD3,TBOX_OverSea
 SG_ VCU13_ReMotRgnTqWhlDesgn : 39|16@0+ (1,-16000) [-16000|16000] "Nm" IDB,ESC_FD3,ISC,EHB_FD3
 SG_ VCU13_Fr0D_rollingcounter : 51|4@0+ (1,0) [0|15] "NoUnit" TBOX,GW_FD5,IDB,ESC_FD3,ISC,EHB_FD3,TBOX_OverSea
 SG_ VCU13_TotalMotRgnTqWhlLimValid : 52|1@0+ (1,0) [0|1] "NoUnit" IDB,ESC_FD3,ISC,EHB_FD3
 SG_ VCU13_TotalMotDrvTqWhlLimValid : 53|1@0+ (1,0) [0|1] "NoUnit" IDB,ESC_FD3,ISC,EHB_FD3
 SG_ VCU13_ReMotRgnTqWhlDesgnValid : 54|1@0+ (1,0) [0|1] "NoUnit" IDB,ESC_FD3,ISC,EHB_FD3
 SG_ VCU13_FrntMotRgnTqWhlDesgnValid : 55|1@0+ (1,0) [0|1] "NoUnit" IDB,ESC_FD3,ISC,EHB_FD3
 SG_ VCU13_Fr0D_Checksum : 63|8@0+ (1,0) [0|255] "NoUnit" IDB,ESC_FD3,ISC,EHB_FD3
 SG_ VCU13_FrntMotRgnTqWhlDesgn : 71|16@0+ (1,-16000) [-16000|16000] "Nm" TBOX,GW_FD5,IDB,ESC_FD3,ISC,EHB_FD3,TBOX_OverSea

BO_ 264 VCU_Fr0E_108: 8 PDCS_FD3
 SG_ VCU14_PAAvailable : 0|1@0+ (1,0) [0|1] "NoUnit" FLC_ME_FD3,FLC_FD3,ADCU_FD3,ADCS_FD3
 SG_ VCU14_Sys_Ready : 1|1@0+ (1,0) [0|1] "NoUnit" Vector__XXX
 SG_ VCU14_ACC_Ready : 2|1@0+ (1,0) [0|1] "NoUnit" FLC_ME_FD3,FLC_FD3,IDB,ESC_FD3,ADCU_FD3,EHB_FD3,ADCS_FD3
 SG_ VCU14_PAActive : 3|1@0+ (1,0) [0|1] "NoUnit" FLC_ME_FD3,FLC_FD3,ADCU_FD3,ADCS_FD3
 SG_ VCU14_AntiSlipWarning : 6|3@0+ (1,0) [0|7] "Na" ICU_E02,GW_FD4,ICU,CDCS,CDCS_OverSea
 SG_ VCU14_AntiSlipAVHActvReq : 7|1@0+ (1,0) [0|1] "Na" IDB
 SG_ VCU14_PA_ParkingFnMd : 18|3@0+ (1,0) [0|7] "NoUnit" FLC_ME_FD3,FLC_FD3,ADCU_FD3,ADCS_FD3
 SG_ VCU14_ACC_Active : 19|1@0+ (1,0) [0|1] "NoUnit" Vector__XXX
 SG_ VCU14_PA_FailCode : 23|4@0+ (1,0) [0|15] "NoUnit" FLC_ME_FD3,FLC_FD3,ADCU_FD3,ADCS_FD3
 SG_ VCU14_Gear_PAActive : 25|2@0+ (1,0) [0|3] "NoUnit" FLC_ME_FD3,FLC_FD3,ADCU_FD3,ADCS_FD3
 SG_ VCU14_Gear_PAAvailable : 28|1@0+ (1,0) [0|1] "NoUnit" FLC_ME_FD3,FLC_FD3,ADCU_FD3,ADCS_FD3
 SG_ VCU14_Gear_ErrorSts_M01 : 29|1@0+ (1,0) [0|1] "NoUnit" FLC_ME_FD3,FLC_FD3,ADCU_FD3,ADCS_FD3
 SG_ VCU4_PA_DeceltorSts : 30|1@0+ (1,0) [0|1] "NoUnit" FLC_ME_FD3,FLC_FD3,ADCU_FD3,ADCS_FD3
 SG_ VCU4_PA_TargetTrqValueValidity : 31|1@0+ (1,0) [0|1] "NoUnit" FLC_ME_FD3,FLC_FD3,ADCU_FD3,ADCS_FD3
 SG_ VCU14_Gear_PACtrlAbortFeedback : 44|3@0+ (1,0) [0|7] "NoUnit" FLC_ME_FD3,FLC_FD3,ADCU_FD3,ADCS_FD3
 SG_ VCU4_PA_TargetTrqValue : 39|11@0+ (0.5,-400) [400|400] "Nm" FLC_ME_FD3,FLC_FD3,ADCU_FD3,ADCS_FD3
 SG_ VCU14_Fr0E_MsgCounter : 51|4@0+ (1,0) [0|15] "NoUnit" FLC_ME_FD3,FLC_FD3,ADCU_FD3,ADCS_FD3
 SG_ VCU14_BMSSOCLowWarn : 55|4@0+ (1,0) [0|15] "" ISC,GW_FD4,CDCS,CDCS_OverSea
 SG_ VCU14_Fr0E_Checksum : 63|8@0+ (1,0) [0|255] "NoUnit" FLC_ME_FD3,FLC_FD3,ADCU_FD3,ADCS_FD3

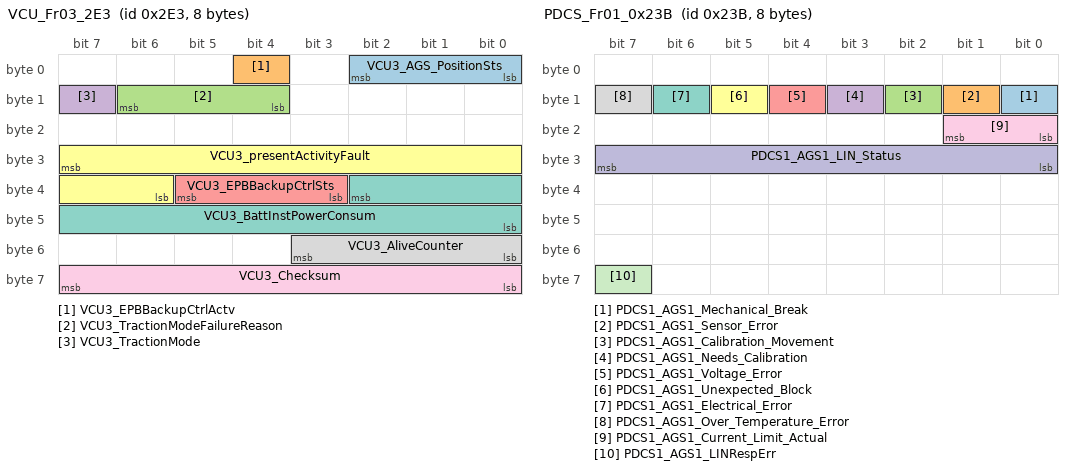
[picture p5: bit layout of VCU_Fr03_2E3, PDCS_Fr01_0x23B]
BO_ 739 VCU_Fr03_2E3: 8 PDCS_FD3
 SG_ VCU3_AGS_PositionSts : 2|3@0+ (1,0) [0|7] "NoUnit" ICU_E02,GW_FD4,ICU,GW_FD2,BDCS,CDCS,CDCS_OverSea
 SG_ VCU3_EPBBackupCtrlActv : 4|1@0+ (1,0) [0|1] "" IDB,ESC_FD3,ISC,ADCU_FD3,ADCS_FD3
 SG_ VCU3_TractionModeFailureReason : 14|3@0+ (1,0) [0|7] "NoUnit" TBOX,GW_FD5,ICU_E02,IDB,ESC_FD3,ISC,GW_FD4,ICU,CDCS,CDCS_OverSea,TBOX_OverSea
 SG_ VCU3_TractionMode : 15|1@0+ (1,0) [0|1] "NoUnit" TBOX,GW_FD5,ICU_E02,IDB,ESC_FD3,ISC,GW_FD4,ICU,CDCS,CDCS_OverSea,TBOX_OverSea
 SG_ VCU3_EPBBackupCtrlSts : 37|3@0+ (1,0) [0|7] "NoUnit" IDB,ESC_FD3,ISC,ADCU_FD3,ADCS_FD3
 SG_ VCU3_presentActivityFault : 31|10@0+ (1,0) [0|1023] "NoUnit" TBOX,GW_FD5,GW_FD4,CDCS,CDCS_OverSea,TBOX_OverSea
 SG_ VCU3_BattInstPowerConsum : 34|11@0+ (0.1,-99.9) [-99.9|99.9] "Kwh/100Km" ICU_E02,GW_FD4,ICU,CDCS,CDCS_OverSea
 SG_ VCU3_AliveCounter : 51|4@0+ (1,0) [0|15] "NoUnit" TBOX,GW_FD5,TBOX_OverSea
 SG_ VCU3_Checksum : 63|8@0+ (1,0) [0|255] "NoUnit" TBOX,GW_FD5,ISC,TBOX_OverSea

BO_ 1073 PDCS_LIN2_431: 32 PDCS_FD1
 SG_ PDCS2_IBS_I_RANGE : 9|2@0+ (1,0) [0|3] "NoUnit" TBOX,GW_FD5,GW_FD1,TBOX_OverSea
 SG_ PDCS2_IBS_U_BATT : 7|14@0+ (9.765625E-4,3) [3|18] "V" TBOX,GW_FD5,GW_FD1,TBOX_OverSea
 SG_ PDCS2_IBS_I_BATT : 23|16@0+ (0.0625,-2048) [-1500|1500] "A" TBOX,GW_FD5,GW_FD1,TBOX_OverSea
 SG_ PDCS2_IBS_T_BATT : 39|8@0+ (1,-40) [-40|105] "℃" TBOX,GW_FD5,GW_FD1,TBOX_OverSea
 SG_ PDCS2_IBS_Status_Current : 49|2@0+ (1,0) [0|3] "NoUnit" GW_FD1
 SG_ PDCS2_IBS_Status_Voltage : 51|2@0+ (1,0) [0|3] "NoUnit" GW_FD1
 SG_ PDCS2_IBS_Status_Temp : 53|2@0+ (1,0) [0|3] "NoUnit" GW_FD1
 SG_ PDCS2_IBS_ERROR_Commom : 54|1@0+ (1,0) [0|1] "NoUnit" TBOX,GW_FD5,GW_FD1,TBOX_OverSea
 SG_ PDCS2_IBS_LINRespErr : 56|1@0+ (1,0) [0|1] "NoUnit" GW_FD1
 SG_ PDCS2_IBS_SOC : 71|8@0+ (1,0) [0|100] "%" TBOX,GW_FD5,GW_FD1,TBOX_OverSea
 SG_ PDCS2_IBS_SOH : 103|8@0+ (1,0) [0|100] "%" TBOX,GW_FD5,GW_FD1,TBOX_OverSea
 SG_ PDCS2_IBS_DisChargeCurrWU_Sts : 104|1@0+ (1,0) [0|1] "NoUnit" TBOX,GW_FD5,GW_FD1,TBOX_OverSea
 SG_ PDCS2_IBS_ChargeCurrWU_Sts : 105|1@0+ (1,0) [0|1] "NoUnit" GW_FD1
 SG_ PDCS2_IBS_SOCWU_Sts : 106|1@0+ (1,0) [0|1] "NoUnit" GW_FD1
 SG_ PDCS2_IBS_DisChargeCurrWU : 107|1@0+ (1,0) [0|1] "NoUnit" GW_FD1
 SG_ PDCS2_IBS_ChargeCurrWU : 108|1@0+ (1,0) [0|1] "NoUnit" GW_FD1
 SG_ PDCS2_IBS_SOCWU : 109|1@0+ (1,0) [0|1] "NoUnit" TBOX,GW_FD5,GW_FD1,TBOX_OverSea
 SG_ PDCS2_IBS_SOH_STATE : 113|2@0+ (1,0) [0|3] "NoUnit" GW_FD1
 SG_ PDCS2_IBS_SOC_STATE : 115|2@0+ (1,0) [0|3] "NoUnit" TBOX,GW_FD5,GW_FD1,TBOX_OverSea
 SG_ PDCS2_SOCWU_Treshold : 135|8@0+ (1,0) [50|80] "℃" GW_FD1
 SG_ PDCS2_SOCWU_Ena : 143|1@0+ (1,0) [0|1] "NoUnit" GW_FD1

BO_ 571 PDCS_Fr01_0x23B: 8 PDCS_FD1
 SG_ PDCS1_AGS1_Mechanical_Break : 8|1@0+ (1,0) [0|1] "" GW_FD2,BDCS
 SG_ PDCS1_AGS1_Sensor_Error : 9|1@0+ (1,0) [0|1] "" GW_FD2,BDCS
 SG_ PDCS1_AGS1_Calibration_Movement : 10|1@0+ (1,0) [0|1] "" GW_FD2,BDCS
 SG_ PDCS1_AGS1_Needs_Calibration : 11|1@0+ (1,0) [0|1] "" GW_FD2,BDCS
 SG_ PDCS1_AGS1_Voltage_Error : 12|1@0+ (1,0) [0|1] "" GW_FD2,BDCS
 SG_ PDCS1_AGS1_Unexpected_Block : 13|1@0+ (1,0) [0|1] "" GW_FD2,BDCS
 SG_ PDCS1_AGS1_Electrical_Error : 14|1@0+ (1,0) [0|1] "" GW_FD2,BDCS
 SG_ PDCS1_AGS1_Over_Temperature_Error : 15|1@0+ (1,0) [0|1] "" GW_FD2,BDCS
 SG_ PDCS1_AGS1_Current_Limit_Actual : 17|2@0+ (1,0) [0|3] "" GW_FD2,BDCS
 SG_ PDCS1_AGS1_LIN_Status : 31|8@0+ (1,0) [0|255] "" GW_FD2,BDCS
 SG_ PDCS1_AGS1_LINRespErr : 63|1@0+ (1,0) [0|1] "" GW_FD2,BDCS

BO_ 816 PDCS_Fr02_330: 16 PDCS_FD1
 SG_ PDCS2_DisAeb : 0|1@0+ (1,0) [0|1] "NoUnit" Vector__XXX
 SG_ PDCS2_DisApa : 1|1@0+ (1,0) [0|1] "NoUnit" Vector__XXX
 SG_ PDCS2_VehSpdLimFgl : 2|1@0+ (1,0) [0|1] "NoUnit" Vector__XXX
 SG_ PDCS2_DisDcDc : 3|1@0+ (1,0) [0|1] "NoUnit" GW_FD1
 SG_ PDCS2_DisRegen : 4|1@0+ (1,0) [0|1] "NoUnit" GW_FD1
 SG_ PDCS2_DisCcs : 5|1@0+ (1,0) [0|1] "NoUnit" GW_FD1
 SG_ PDCS2_DisAcc : 6|1@0+ (1,0) [0|1] "NoUnit" GW_FD1
 SG_ PDCS2_DisMot : 7|1@0+ (1,0) [0|1] "NoUnit" GW_FD1
 SG_ PDCS2_LimHomeFlg : 8|1@0+ (1,0) [0|1] "NoUnit" GW_FD1
 SG_ PDCS2_PwrLimFlg : 9|1@0+ (1,0) [0|1] "NoUnit" GW_FD1
 SG_ PDCS2_12VBatChrgePwrUpReq : 12|1@0+ (1,0) [0|1] "NoUnit" Vector__XXX
 SG_ PDCS2_12VBatChrgePwrDwnReq : 13|1@0+ (1,0) [0|1] "NoUnit" Vector__XXX
 SG_ PDCS2_HvPwrUpReq : 14|1@0+ (1,0) [0|1] "NoUnit" Vector__XXX
 SG_ PDCS2_HvPwrDwnReq : 15|1@0+ (1,0) [0|1] "NoUnit" Vector__XXX
 SG_ PDCS2_12VBatChargeExitReason : 29|4@0+ (1,0) [0|15] "NoUnit" Vector__XXX
 SG_ PDCS2_12VBatChrgeCntr : 25|10@0+ (1,0) [0|1023] "NoUnit" Vector__XXX
 SG_ PDCS2_12VBatChrgeTi : 47|16@0+ (1,0) [0|65535] "s" Vector__XXX
 SG_ PDCS2_entityID : 75|4@0+ (1,0) [0|15] "NoUnit" Vector__XXX
 SG_ PDCS2_Softwareversion : 63|20@0+ (1,0) [0|999999] "NoUnit" Vector__XXX

BO_ 1172 PDCS_Fr03_494: 32 PDCS_FD1
 SG_ MCU_u32ResetReson : 7|16@0+ (1,0) [0|65535] "NoUnit" TBOX,GW_FD5,TBOX_OverSea
 SG_ SOC_BackEepUsed_Flag : 16|1@0+ (1,0) [0|1] "NoUnit" TBOX,GW_FD5,TBOX_OverSea
 SG_ SOC_CurrentBlockChk_Flag : 17|1@0+ (1,0) [0|1] "NoUnit" TBOX,GW_FD5,TBOX_OverSea
 SG_ VCU_ShutdownStoreBlockChk_Flag : 18|1@0+ (1,0) [0|1] "NoUnit" TBOX,GW_FD5,TBOX_OverSea
 SG_ HCU_BackEepUsed_Flag : 19|1@0+ (1,0) [0|1] "NoUnit" TBOX,GW_FD5,TBOX_OverSea
 SG_ HCU_CurrentBlockChk_Flag : 20|1@0+ (1,0) [0|1] "NoUnit" TBOX,GW_FD5,TBOX_OverSea
 SG_ HCU_ShutdownStoreBlockChk_Flag : 21|1@0+ (1,0) [0|1] "NoUnit" TBOX,GW_FD5,TBOX_OverSea
 SG_ BDCS_Reset_PIN_Flag : 22|1@0+ (1,0) [0|1] "NoUnit" TBOX,GW_FD5,TBOX_OverSea
 SG_ BDCS_TeachPinSK_Flag : 23|1@0+ (1,0) [0|1] "NoUnit" TBOX,GW_FD5,TBOX_OverSea
 SG_ BSW_Running_Status : 31|8@0+ (1,0) [0|1] "NoUnit" TBOX,GW_FD5,TBOX_OverSea
 SG_ BSW_Run_su1_run_request : 39|8@0+ (1,0) [0|1] "NoUnit" TBOX,GW_FD5,TBOX_OverSea
 SG_ ComM_BusState0 : 47|8@0+ (1,0) [0|255] "NoUnit" TBOX,GW_FD5,TBOX_OverSea
 SG_ ComM_BusState1 : 55|8@0+ (1,0) [0|255] "NoUnit" TBOX,GW_FD5,TBOX_OverSea
 SG_ ComM_BusState2 : 63|8@0+ (1,0) [0|255] "NoUnit" TBOX,GW_FD5,TBOX_OverSea
 SG_ ComM_BusState3 : 71|8@0+ (1,0) [0|255] "NoUnit" TBOX,GW_FD5,TBOX_OverSea
 SG_ ComM_BusState4 : 79|8@0+ (1,0) [0|255] "NoUnit" TBOX,GW_FD5,TBOX_OverSea
 SG_ ComM_BusState5 : 87|8@0+ (1,0) [0|255] "NoUnit" TBOX,GW_FD5,TBOX_OverSea
 SG_ BSW_PostRun_su1_postrun_request : 95|8@0+ (1,0) [0|255] "NoUnit" TBOX,GW_FD5,TBOX_OverSea
 SG_ BSW_PostRun_CANNMState : 103|8@0+ (1,0) [0|255] "NoUnit" TBOX,GW_FD5,TBOX_OverSea
 SG_ BSW_PostRun_WakeupSource : 111|16@0+ (1,0) [0|65535] "NoUnit" TBOX,GW_FD5,TBOX_OverSea
 SG_ BSW_PostRun_DemPostRunRequest : 127|8@0+ (1,0) [0|255] "NoUnit" TBOX,GW_FD5,TBOX_OverSea
 SG_ BSW_PostRun_app_request : 135|8@0+ (1,0) [0|255] "NoUnit" TBOX,GW_FD5,TBOX_OverSea
 SG_ BSW_WaitForNvm_NvMJobState : 143|8@0+ (1,0) [0|255] "NoUnit" TBOX,GW_FD5,TBOX_OverSea
 SG_ BSW_Eth_TrcvLinkState : 151|8@0+ (1,0) [0|255] "NoUnit" TBOX,GW_FD5,TBOX_OverSea
 SG_ BSW_Eth_SdMsgCnt : 159|8@0+ (1,0) [0|255] "NoUnit" TBOX,GW_FD5,TBOX_OverSea
 SG_ VCU_Packet1 : 167|8@0+ (1,0) [0|255] "NoUnit" GW_FD1
 SG_ VCU_Packet2 : 175|8@0+ (1,0) [0|255] "NoUnit" GW_FD1
 SG_ VCU_Packet3 : 183|8@0+ (1,0) [0|255] "NoUnit" GW_FD1
 SG_ VCU_Packet4 : 191|8@0+ (1,0) [0|255] "NoUnit" GW_FD1
 SG_ VCU_Packet5 : 199|8@0+ (1,0) [0|255] "NoUnit" GW_FD1
 SG_ VCU_Packet6 : 207|8@0+ (1,0) [0|255] "NoUnit" GW_FD1
 SG_ VCU_Packet7 : 215|8@0+ (1,0) [0|255] "NoUnit" GW_FD1
 SG_ VCU_Packet8 : 223|8@0+ (1,0) [0|255] "NoUnit" GW_FD1

BO_ 1545 PDCS_NM_609: 8 PDCS_FD1
 SG_ PDCS_SourceNodeIdentifier : 7|8@0+ (1,0) [0|255] "NoUnit" Vector__XXX
 SG_ PDCS_RepeatMessageRequest : 8|1@0+ (1,0) [0|1] "NoUnit" Vector__XXX
 SG_ PDCS_Reserve1 : 11|3@0+ (1,0) [0|3] "NoUnit" Vector__XXX
 SG_ PDCS_ActiveWakeup : 12|1@0+ (1,0) [0|1] "NoUnit" Vector__XXX
 SG_ PDCS_Reserve2 : 15|3@0+ (1,0) [0|7] "NoUnit" Vector__XXX
 SG_ PDCS_WakeUp_KL15 : 16|1@0+ (1,0) [0|1] "NoUnit" Vector__XXX
 SG_ PDCS_WakeUp_NM : 17|1@0+ (1,0) [0|1] "NoUnit" Vector__XXX
 SG_ PDCS_WakeUp_CC : 18|1@0+ (1,0) [0|1] "NoUnit" Vector__XXX
 SG_ PDCS_WakeUp_CP : 19|1@0+ (1,0) [0|1] "NoUnit" Vector__XXX
 SG_ PDCS_WakeUp_BMS : 20|1@0+ (1,0) [0|1] "NoUnit" Vector__XXX
 SG_ PDCS_WakeUp_RTC : 21|1@0+ (1,0) [0|1] "NoUnit" Vector__XXX
 SG_ PDCS_WakeUp_APLUS : 22|1@0+ (1,0) [0|1] "NoUnit" Vector__XXX
 SG_ PDCS_WakeUp_OBC : 23|1@0+ (1,0) [0|1] "NoUnit" Vector__XXX
 SG_ PDCS_RepeatFromSleep : 24|1@0+ (1,0) [0|1] "NoUnit" Vector__XXX
 SG_ PDCS_RepeatFromPrepare : 25|1@0+ (1,0) [0|1] "NoUnit" Vector__XXX
 SG_ PDCS_NormalFromRepeat : 26|1@0+ (1,0) [0|1] "NoUnit" Vector__XXX
 SG_ PDCS_NormalFromReady : 27|1@0+ (1,0) [0|1] "NoUnit" Vector__XXX
 SG_ PDCS_RepeatFromReady : 28|1@0+ (1,0) [0|1] "NoUnit" Vector__XXX
 SG_ PDCS_RepeatFromNormal : 29|1@0+ (1,0) [0|1] "NoUnit" Vector__XXX
 SG_ PDCS_WakeUp_APP : 32|1@0+ (1,0) [0|1] "NoUnit" Vector__XXX
 SG_ PDCS_WakeUp_DIAG : 33|1@0+ (1,0) [0|1] "NoUnit" Vector__XXX
 SG_ PDCS_WakeUp_LIN : 34|1@0+ (1,0) [0|1] "NoUnit" Vector__XXX
 SG_ PDCS_Request_APP : 39|2@0+ (1,0) [0|3] "NoUnit" Vector__XXX

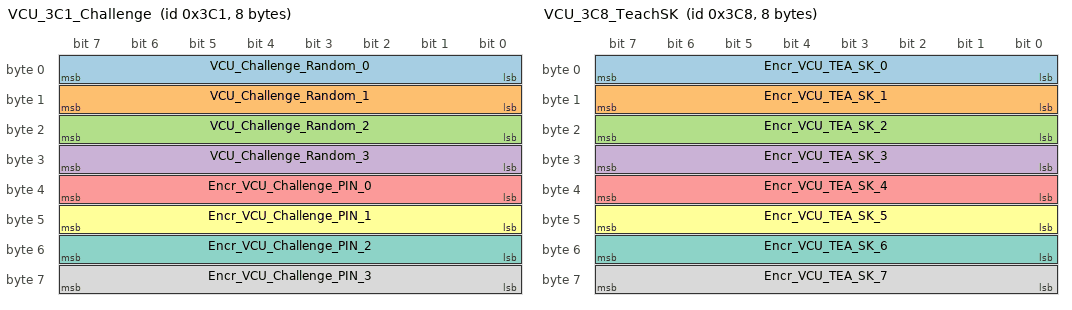
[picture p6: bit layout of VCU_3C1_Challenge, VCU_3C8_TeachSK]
BO_ 961 VCU_3C1_Challenge: 8 PDCS_FD1
 SG_ VCU_Challenge_Random_0 : 7|8@0+ (1,0) [0|255] "NoUnit" GW_FD2,BDCS
 SG_ VCU_Challenge_Random_1 : 15|8@0+ (1,0) [0|255] "NoUnit" GW_FD2,BDCS
 SG_ VCU_Challenge_Random_2 : 23|8@0+ (1,0) [0|255] "NoUnit" GW_FD2,BDCS
 SG_ VCU_Challenge_Random_3 : 31|8@0+ (1,0) [0|255] "NoUnit" GW_FD2,BDCS
 SG_ Encr_VCU_Challenge_PIN_0 : 39|8@0+ (1,0) [0|255] "NoUnit" GW_FD2,BDCS
 SG_ Encr_VCU_Challenge_PIN_1 : 47|8@0+ (1,0) [0|255] "NoUnit" GW_FD2,BDCS
 SG_ Encr_VCU_Challenge_PIN_2 : 55|8@0+ (1,0) [0|255] "NoUnit" GW_FD2,BDCS
 SG_ Encr_VCU_Challenge_PIN_3 : 63|8@0+ (1,0) [0|255] "NoUnit" GW_FD2,BDCS

BO_ 964 VCU_3C4_LearnSK: 8 PDCS_FD1
 SG_ VCU_LEARN_SK_RC : 7|8@0+ (1,0) [0|255] "NoUnit" GW_FD2,BDCS

BO_ 966 VCU_3C6_LearnPIN: 8 PDCS_FD1
 SG_ VCU_LEARN_PIN_RC : 7|8@0+ (1,0) [0|255] "NoUnit" GW_FD2,BDCS

BO_ 968 VCU_3C8_TeachSK: 8 PDCS_FD1
 SG_ Encr_VCU_TEA_SK_0 : 7|8@0+ (1,0) [0|255] "NoUnit" GW_FD2,BDCS
 SG_ Encr_VCU_TEA_SK_1 : 15|8@0+ (1,0) [0|255] "NoUnit" GW_FD2,BDCS
 SG_ Encr_VCU_TEA_SK_2 : 23|8@0+ (1,0) [0|255] "NoUnit" GW_FD2,BDCS
 SG_ Encr_VCU_TEA_SK_3 : 31|8@0+ (1,0) [0|255] "NoUnit" GW_FD2,BDCS
 SG_ Encr_VCU_TEA_SK_4 : 39|8@0+ (1,0) [0|255] "NoUnit" GW_FD2,BDCS
 SG_ Encr_VCU_TEA_SK_5 : 47|8@0+ (1,0) [0|255] "NoUnit" GW_FD2,BDCS
 SG_ Encr_VCU_TEA_SK_6 : 55|8@0+ (1,0) [0|255] "NoUnit" GW_FD2,BDCS
 SG_ Encr_VCU_TEA_SK_7 : 63|8@0+ (1,0) [0|255] "NoUnit" GW_FD2,BDCS

BO_ 970 VCU_3CA_Reset: 8 PDCS_FD1
 SG_ VCU_RES_RC : 7|8@0+ (1,0) [0|255] "NoUnit" GW_FD2,BDCS

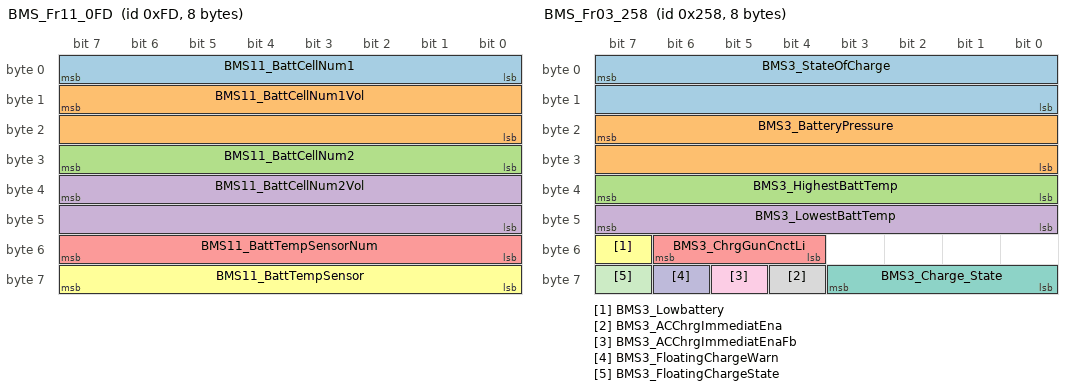
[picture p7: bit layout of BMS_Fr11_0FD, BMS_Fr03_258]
BO_ 253 BMS_Fr11_0FD: 8 BMS
 SG_ BMS11_BattCellNum1 : 7|8@0+ (1,0) [0|255] "NoUnit" TBOX,GW_FD5,TBOX_OverSea
 SG_ BMS11_BattCellNum1Vol : 15|16@0+ (1,0) [0|5000] "NoUnit" TBOX,GW_FD5,TBOX_OverSea
 SG_ BMS11_BattCellNum2 : 31|8@0+ (1,0) [0|255] "NoUnit" TBOX,GW_FD5,TBOX_OverSea
 SG_ BMS11_BattCellNum2Vol : 39|16@0+ (1,0) [0|5000] "NoUnit" TBOX,GW_FD5,TBOX_OverSea
 SG_ BMS11_BattTempSensorNum : 55|8@0+ (1,0) [0|255] "NoUnit" TBOX,GW_FD5,TBOX_OverSea
 SG_ BMS11_BattTempSensor : 63|8@0+ (1,-40) [-40|125] "NoUnit" TBOX,GW_FD5,TBOX_OverSea

BO_ 246 BMS_Fr06_0F6: 8 BMS
 SG_ BMS6_Sts : 0|1@0+ (1,0) [0|1] "NoUnit" PDCS_FD1,TBOX,GW_FD5,TBOX_OverSea
 SG_ BMS6_Enable_request : 1|1@0+ (1,0) [0|1] "NoUnit" PDCS_FD1,TBOX,GW_FD5,TBOX_OverSea
 SG_ BMS6_ControlHVDischarge : 3|2@0+ (1,0) [0|3] "NoUnit" PDCS_FD1,TBOX,GW_FD5,TBOX_OverSea
 SG_ BMS6_WorkingMode : 7|4@0+ (1,0) [0|15] "NoUnit" PDCS_FD1,TBOX,GW_FD5,GW_FD2,BDCS,TBOX_OverSea
 SG_ BMS6_PosBattContSts : 9|2@0+ (1,0) [0|3] "NoUnit" PDCS_FD1,TBOX,GW_FD5,GCU,MCU,TBOX_OverSea
 SG_ BMS6_NegBattContSts : 11|2@0+ (1,0) [0|3] "NoUnit" PDCS_FD1,TBOX,GW_FD5,GCU,MCU,TBOX_OverSea
 SG_ BMS6_PrechargeContSts : 13|2@0+ (1,0) [0|3] "NoUnit" PDCS_FD1,TBOX,GW_FD5,TBOX_OverSea
 SG_ BMS6_DCChargeContSts : 15|2@0+ (1,0) [0|3] "NoUnit" PDCS_FD1,TBOX,GW_FD5,GW_FD4,CDCS,CDCS_OverSea,TBOX_OverSea
 SG_ BMS6_PrechargeSts : 17|2@0+ (1,0) [0|3] "NoUnit" PDCS_FD1,TBOX,GW_FD5,TBOX_OverSea
 SG_ BMS6_InterlockSts : 18|1@0+ (1,0) [0|1] "NoUnit" PDCS_FD1,TBOX,GW_FD5,ICU_E02,GW_FD4,ICU,CDCS,CDCS_OverSea,TBOX_OverSea
 SG_ BMS6_ThermalDiffusion : 19|1@0+ (1,0) [0|1] "NoUnit" PDCS_FD1,ICU_E02,GW_FD4,ICU,GW_FD2,BDCS,CDCS,CDCS_OverSea
 SG_ BMS6_CellOverTempSts : 20|1@0+ (1,0) [0|1] "NoUnit" PDCS_FD1,TBOX,GW_FD5,ICU_E02,GW_FD4,ICU,CDCS,CDCS_OverSea,TBOX_OverSea
 SG_ BMS6_CellUnderTempSts : 21|1@0+ (1,0) [0|1] "NoUnit" PDCS_FD1,TBOX,GW_FD5,ICU_E02,GW_FD4,ICU,CDCS,CDCS_OverSea,TBOX_OverSea
 SG_ BMS6_CellOverVoltageSts : 22|1@0+ (1,0) [0|1] "NoUnit" PDCS_FD1,TBOX,GW_FD5,ICU_E02,GW_FD4,ICU,CDCS,CDCS_OverSea,TBOX_OverSea
 SG_ BMS6_CellUnderVoltageSts : 23|1@0+ (1,0) [0|1] "NoUnit" PDCS_FD1,TBOX,GW_FD5,ICU_E02,GW_FD4,ICU,CDCS,CDCS_OverSea,TBOX_OverSea
 SG_ BMS6_OverVoltageSts : 24|1@0+ (1,0) [0|1] "NoUnit" PDCS_FD1,TBOX,GW_FD5,ICU_E02,GW_FD4,ICU,CDCS,CDCS_OverSea,TBOX_OverSea
 SG_ BMS6_UnderVoltageSts : 25|1@0+ (1,0) [0|1] "NoUnit" PDCS_FD1,TBOX,GW_FD5,ICU_E02,GW_FD4,ICU,CDCS,CDCS_OverSea,TBOX_OverSea
 SG_ BMS6_UnderSOCSts : 26|1@0+ (1,0) [0|1] "NoUnit" PDCS_FD1,TBOX,GW_FD5,ICU_E02,GW_FD4,ICU,CDCS,CDCS_OverSea,TBOX_OverSea
 SG_ BMS6_BattOverSoc : 27|1@0+ (1,0) [0|1] "NoUnit" TBOX,GW_FD5,TBOX_OverSea
 SG_ BMS6_BattSocJump : 28|1@0+ (1,0) [0|1] "NoUnit" TBOX,GW_FD5,TBOX_OverSea
 SG_ BMS6_BattOverCharging : 29|1@0+ (1,0) [0|1] "NoUnit" TBOX,GW_FD5,TBOX_OverSea
 SG_ BMS6_BattMismatching : 30|1@0+ (1,0) [0|1] "NoUnit" TBOX,GW_FD5,TBOX_OverSea
 SG_ BMS6_OverCurrentSts : 31|1@0+ (1,0) [0|1] "NoUnit" PDCS_FD1,TBOX,GW_FD5,ICU_E02,GW_FD4,ICU,CDCS,CDCS_OverSea,TBOX_OverSea
 SG_ BMS6_IsolSuperSts : 32|1@0+ (1,0) [0|1] "NoUnit" PDCS_FD1,TBOX,GW_FD5,ICU_E02,GW_FD4,ICU,CDCS,CDCS_OverSea,TBOX_OverSea
 SG_ BMS6_TempDiffSts : 33|1@0+ (1,0) [0|1] "NoUnit" PDCS_FD1,TBOX,GW_FD5,ICU_E02,GW_FD4,ICU,CDCS,CDCS_OverSea,TBOX_OverSea
 SG_ BMS6_DiagSts : 34|1@0+ (1,0) [0|1] "NoUnit" PDCS_FD1,TBOX,GW_FD5,ICU_E02,GW_FD4,ICU,CDCS,CDCS_OverSea,TBOX_OverSea
 SG_ BMS6_CellConsistencySts : 35|1@0+ (1,0) [0|1] "NoUnit" PDCS_FD1,TBOX,GW_FD5,ICU_E02,GW_FD4,ICU,CDCS,CDCS_OverSea,TBOX_OverSea
 SG_ BMS6_DCChargeNegContSts : 37|2@0+ (1,0) [0|3] "NoUnit" TBOX,CDU,GW_FD5,GW_FD4,CDCS,CDCS_OverSea,TBOX_OverSea
 SG_ BMS6_ElectromagneticLockCtrl : 39|2@0+ (1,0) [0|3] "NoUnit" CDU
 SG_ BMS6_MILSts : 40|1@0+ (1,0) [0|1] "NoUnit" EMS
 SG_ BMS6_TempRiseFast_Flt : 41|1@0+ (1,0) [0|1] "NoUnit" PDCS_FD1,TBOX,GW_FD5,TBOX_OverSea
 SG_ BMS6_dischgActiveFltCategory : 47|4@0+ (1,0) [0|15] "NoUnit" PDCS_FD1,TBOX,GW_FD5,TBOX_OverSea
 SG_ BMS6_AliveCounter : 51|4@0+ (1,0) [0|15] "NoUnit" PDCS_FD1,TBOX,GW_FD5,ICU_E02,GW_FD4,ICU,CDCS,MCU,CDCS_OverSea,TBOX_OverSea
 SG_ BMS6_chgActiveFltCategory : 55|4@0+ (1,0) [0|15] "NoUnit" PDCS_FD1,TBOX,GW_FD5,TBOX_OverSea
 SG_ BMS6_presentActivityFault : 63|8@0+ (1,0) [0|255] "NoUnit" PDCS_FD1,TBOX,GW_FD5,TBOX_OverSea

BO_ 600 BMS_Fr03_258: 8 BMS
 SG_ BMS3_StateOfCharge : 7|16@0+ (0.1,0) [0|100] "NoUnit" PDCS_FD1,PDCU,ADCU_FD3,EMS,BDCS,DDCU,BAM,CDCS,ADCS_FD3,CDCS_OverSea,TBOX,FLC_ME_FD3,FLC_FD3,CDU,GW_FD5,ICU_E02,GW_FD3,GW_FD4,ICU,GW_FD2,TBOX_OverSea
 SG_ BMS3_BatteryPressure : 23|16@0+ (0.1,0) [0|6000] "kPa" TBOX,GW_FD5,TBOX_OverSea
 SG_ BMS3_HighestBattTemp : 39|8@0+ (1,-40) [-40|125] "" PDCS_FD1,TBOX,GW_FD5,GW_FD2,BDCS,BAM,TBOX_OverSea
 SG_ BMS3_LowestBattTemp : 47|8@0+ (1,-40) [-40|125] "" PDCS_FD1,TBOX,GW_FD5,GW_FD2,BDCS,TBOX_OverSea
 SG_ BMS3_ChrgGunCnctLi : 54|3@0+ (1,0) [0|7] "NoUnit" PDCS_FD1,PDCU,BDCS,DDCU,CDCS,CDCS_OverSea,TBOX,GW_FD5,ICU_E02,GW_FD4,ICU,GW_FD2,TBOX_OverSea
 SG_ BMS3_Lowbattery : 55|1@0+ (1,0) [0|1] "NoUnit" GW_FD4,CDCS,CDCS_OverSea
 SG_ BMS3_Charge_State : 59|4@0+ (1,0) [0|15] "NoUnit" PDCS_FD1,PDCU,ADCU_FD3,BDCS,DDCU,BAM,CDCS,ADCS_FD3,CDCS_OverSea,TBOX,FLC_ME_FD3,FLC_FD3,GW_FD5,ICU_E02,GW_FD3,GW_FD4,GW_FD1,ICU,GW_FD2,TBOX_OverSea
 SG_ BMS3_ACChrgImmediatEna : 60|1@0+ (1,0) [0|1] "" TBOX,GW_FD5,GW_FD4,CDCS,CDCS_OverSea,TBOX_OverSea
 SG_ BMS3_ACChrgImmediatEnaFb : 61|1@0+ (1,0) [0|1] "" TBOX,GW_FD5,GW_FD4,CDCS,CDCS_OverSea,TBOX_OverSea
 SG_ BMS3_FloatingChargeWarn : 62|1@0+ (1,0) [0|1] "" TBOX,GW_FD5,GW_FD4,CDCS,CDCS_OverSea,TBOX_OverSea
 SG_ BMS3_FloatingChargeState : 63|1@0+ (1,0) [0|1] "" Vector__XXX

BO_ 136 BMS_Fr01_088: 16 BMS
 SG_ BMS1_PeakDischargeCurrent : 7|16@0+ (0.1,-1600) [-1600|1024] "A" PDCS_FD1
 SG_ BMS1_PeakChargeCurrent : 23|16@0+ (0.1,-1600) [-1600|1024] "A" PDCS_FD1
 SG_ BMS1_BatteryCurrent : 39|16@0+ (0.1,-1600) [-1600|1024] "A" PDCS_FD1,BDCS,CDCS,CDCS_OverSea,TBOX,GW_FD5,ICU_E02,GW_FD4,ICU,GW_FD2,MCU,TBOX_OverSea
 SG_ BMS1_AliveCounter : 51|4@0+ (1,0) [0|15] "NoUnit" PDCS_FD1
 SG_ BMS1_BatteryState : 52|1@0+ (1,0) [0|1] "NoUnit" PDCS_FD1,BDCS,BAM,CDCS,CDCS_OverSea,TBOX,CDU,GW_FD5,ICU_E02,GW_FD4,ICU,GW_FD2,MCU,TBOX_OverSea
 SG_ BMS1_Checksum : 63|8@0+ (1,0) [0|255] "NoUnit" PDCS_FD1
 SG_ BMS1_DCChrgPostvVoltCtrl : 65|2@0+ (1,0) [0|3] "" CDU
 SG_ BMS1_DCChrgNegVoltCtrl : 67|2@0+ (1,0) [0|3] "" CDU
 SG_ BMS1_ContnsChargeCurrent : 79|16@0+ (0.1,-1600) [-1600|1024] "A" PDCS_FD1
 SG_ BMS1_SOEpercentage : 95|16@0+ (0.1,0) [0|100] "%" PDCS_FD1,GW_FD2,BDCS
 SG_ BMS1_ContnsDischargeCurrent : 111|16@0+ (0.1,-1600) [-1600|1024] "A" PDCS_FD1
 SG_ BMS1_SlowChargeInterState : 123|4@0+ (1,0) [0|15] "" Vector__XXX
 SG_ BMS1_FastChargeInterState : 127|4@0+ (1,0) [0|15] "" Vector__XXX

BO_ 261 BMS_Fr05_105: 16 BMS
 SG_ BMS5_PeakDchaPwr : 7|16@0+ (0.1,0) [0|1000] "kW" PDCS_FD1
 SG_ BMS5_ContnsDchaPwr : 23|16@0+ (0.1,0) [0|1000] "kW" PDCS_FD1
 SG_ BMS5_BatteryVoltage : 39|16@0+ (0.05,0) [0|1000] "V" PDCS_FD1,TBOX,GW_FD5,GW_FD4,GW_FD2,BDCS,CDCS,CDCS_OverSea,TBOX_OverSea
 SG_ BMS5_AliveCounter : 51|4@0+ (1,0) [0|15] "NoUnit" PDCS_FD1
 SG_ BMS5_Checksum : 63|8@0+ (1,0) [0|255] "NoUnit" PDCS_FD1
 SG_ BMS5_PeakChrgPwr : 71|16@0+ (0.1,0) [0|1000] "kW" PDCS_FD1
 SG_ BMS5_ContnsChrgPwr : 87|16@0+ (0.1,0) [0|1000] "kW" PDCS_FD1
 SG_ BMS5_DCBusVoltage : 103|16@0+ (0.05,0) [0|1000] "V" PDCS_FD1,TBOX,GW_FD5,TBOX_OverSea

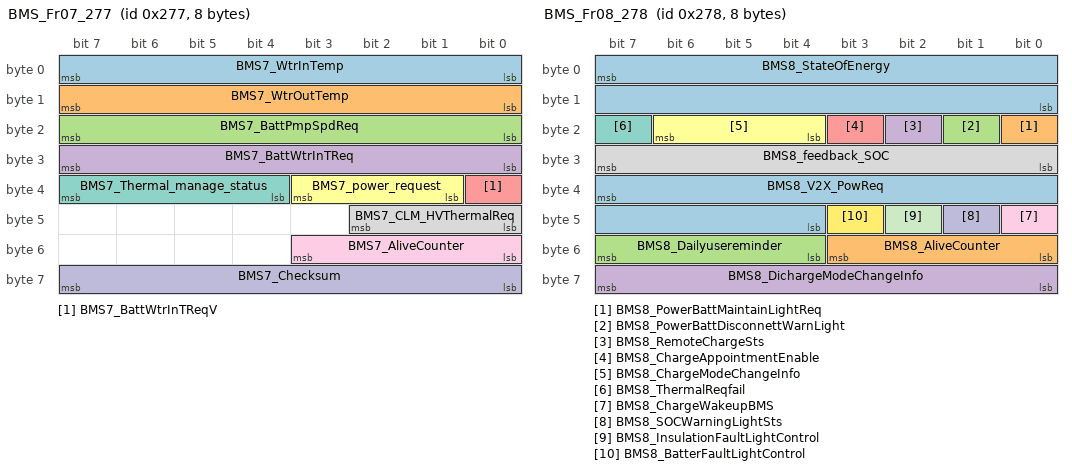
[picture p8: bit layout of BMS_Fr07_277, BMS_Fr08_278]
BO_ 631 BMS_Fr07_277: 8 BMS
 SG_ BMS7_WtrInTemp : 7|8@0+ (1,-40) [-40|125] "" PDCS_FD1,TBOX,GW_FD5,GW_FD2,BDCS,TBOX_OverSea
 SG_ BMS7_WtrOutTemp : 15|8@0+ (1,-40) [-40|125] "" PDCS_FD1,TBOX,GW_FD5,GW_FD2,BDCS,TBOX_OverSea
 SG_ BMS7_BattPmpSpdReq : 23|8@0+ (1,0) [0|100] "%" PDCS_FD1,TBOX,GW_FD5,GW_FD2,BDCS,TBOX_OverSea
 SG_ BMS7_BattWtrInTReq : 31|8@0+ (1,-40) [-40|125] "" PDCS_FD1,TBOX,GW_FD5,GW_FD2,BDCS,TBOX_OverSea
 SG_ BMS7_BattWtrInTReqV : 32|1@0+ (1,0) [0|1] "NoUnit" PDCS_FD1,TBOX,GW_FD5,GW_FD2,BDCS,TBOX_OverSea
 SG_ BMS7_power_request : 35|3@0+ (1,0) [0|7] "NoUnit" PDCS_FD1,TBOX,GW_FD5,GW_FD2,BDCS,TBOX_OverSea
 SG_ BMS7_Thermal_manage_status : 39|4@0+ (1,0) [0|15] "NoUnit" PDCS_FD1,TBOX,GW_FD5,GW_FD2,BDCS,TBOX_OverSea
 SG_ BMS7_CLM_HVThermalReq : 42|3@0+ (1,0) [0|7] "NoUnit" PDCS_FD1,GW_FD2,BDCS
 SG_ BMS7_AliveCounter : 51|4@0+ (1,0) [0|15] "NoUnit" PDCS_FD1,GW_FD2,BDCS
 SG_ BMS7_Checksum : 63|8@0+ (1,0) [0|255] "NoUnit" PDCS_FD1

BO_ 632 BMS_Fr08_278: 8 BMS
 SG_ BMS8_StateOfEnergy : 7|16@0+ (0.1,0) [0|254] "Kwh" PDCS_FD1,TBOX,GW_FD5,GW_FD4,CDCS,CDCS_OverSea,TBOX_OverSea
 SG_ BMS8_PowerBattMaintainLightReq : 16|1@0+ (1,0) [0|1] "NoUnit" TBOX,GW_FD5,ICU_E02,GW_FD4,ICU,CDCS,CDCS_OverSea,TBOX_OverSea
 SG_ BMS8_PowerBattDisconnettWarnLight : 17|1@0+ (1,0) [0|1] "NoUnit" TBOX,GW_FD5,ICU_E02,GW_FD4,ICU,CDCS,CDCS_OverSea,TBOX_OverSea
 SG_ BMS8_RemoteChargeSts : 18|1@0+ (1,0) [0|1] "NoUnit" TBOX,GW_FD5,GW_FD4,CDCS,CDCS_OverSea,TBOX_OverSea
 SG_ BMS8_ChargeAppointmentEnable : 19|1@0+ (1,0) [0|1] "NoUnit" TBOX,GW_FD5,GW_FD4,CDCS,CDCS_OverSea,TBOX_OverSea
 SG_ BMS8_ChargeModeChangeInfo : 22|3@0+ (1,0) [0|7] "NoUnit" TBOX,GW_FD5,GW_FD4,CDCS,CDCS_OverSea,TBOX_OverSea
 SG_ BMS8_ThermalReqfail : 23|1@0+ (1,0) [0|1] "NoUnit" ICU_E02,GW_FD4,ICU,CDCS,CDCS_OverSea
 SG_ BMS8_feedback_SOC : 31|8@0+ (1,0) [0|100] "%" TBOX,GW_FD5,GW_FD4,CDCS,CDCS_OverSea,TBOX_OverSea
 SG_ BMS8_ChargeWakeupBMS : 40|1@0+ (1,0) [0|1] "NoUnit" TBOX,GW_FD5,GW_FD4,CDCS,CDCS_OverSea,TBOX_OverSea
 SG_ BMS8_SOCWarningLightSts : 41|1@0+ (1,0) [0|1] "NoUnit" TBOX,GW_FD5,ICU_E02,GW_FD4,ICU,CDCS,CDCS_OverSea,TBOX_OverSea
 SG_ BMS8_InsulationFaultLightControl : 42|1@0+ (1,0) [0|1] "NoUnit" TBOX,GW_FD5,ICU_E02,GW_FD4,ICU,CDCS,CDCS_OverSea,TBOX_OverSea
 SG_ BMS8_BatterFaultLightControl : 43|1@0+ (1,0) [0|1] "NoUnit" TBOX,GW_FD5,ICU_E02,GW_FD4,ICU,CDCS,CDCS_OverSea,TBOX_OverSea
 SG_ BMS8_V2X_PowReq : 39|12@0+ (0.1,0) [0|254] "Kw" PDCS_FD1
 SG_ BMS8_AliveCounter : 51|4@0+ (1,0) [0|15] "NoUnit" TBOX,GW_FD5,GW_FD4,CDCS,CDCS_OverSea,TBOX_OverSea
 SG_ BMS8_Dailyusereminder : 55|4@0+ (1,0) [0|15] "NoUnit" TBOX,GW_FD5,GW_FD4,CDCS,CDCS_OverSea,TBOX_OverSea
 SG_ BMS8_DichargeModeChangeInfo : 63|8@0+ (1,0) [0|100] "%" TBOX,GW_FD5,GW_FD4,CDCS,CDCS_OverSea,TBOX_OverSea

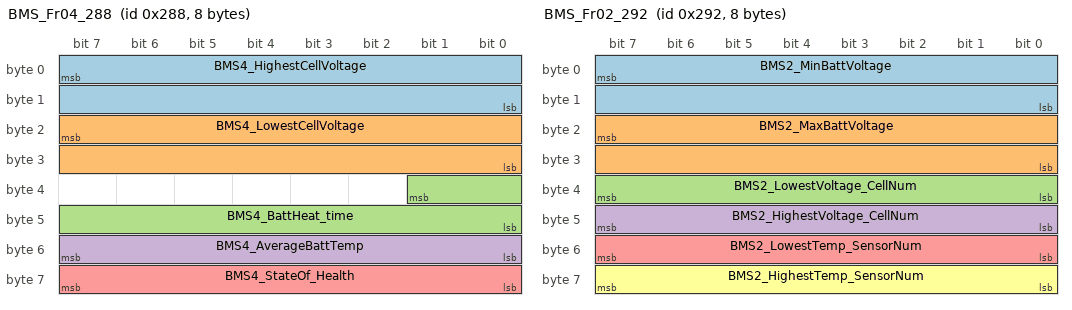
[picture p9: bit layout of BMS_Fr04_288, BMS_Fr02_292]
BO_ 648 BMS_Fr04_288: 8 BMS
 SG_ BMS4_HighestCellVoltage : 7|16@0+ (1,0) [0|5000] "mv" PDCS_FD1,TBOX,GW_FD5,TBOX_OverSea
 SG_ BMS4_LowestCellVoltage : 23|16@0+ (1,0) [0|5000] "mv" PDCS_FD1,TBOX,GW_FD5,TBOX_OverSea
 SG_ BMS4_BattHeat_time : 33|10@0+ (1,0) [0|1023] "min" TBOX,GW_FD5,TBOX_OverSea
 SG_ BMS4_AverageBattTemp : 55|8@0+ (1,-40) [-40|125] "" PDCS_FD1,TBOX,GW_FD5,GW_FD2,BDCS,TBOX_OverSea
 SG_ BMS4_StateOf_Health : 63|8@0+ (1,0) [0|100] "%" PDCS_FD1,TBOX,GW_FD5,GW_FD2,BDCS,TBOX_OverSea

BO_ 658 BMS_Fr02_292: 8 BMS
 SG_ BMS2_MinBattVoltage : 7|16@0+ (0.05,0) [0|1000] "V" PDCS_FD1,TBOX,GW_FD5,TBOX_OverSea
 SG_ BMS2_MaxBattVoltage : 23|16@0+ (0.05,0) [0|1000] "V" PDCS_FD1,TBOX,GW_FD5,TBOX_OverSea
 SG_ BMS2_LowestVoltage_CellNum : 39|8@0+ (1,0) [0|200] "NoUnit" PDCS_FD1,TBOX,GW_FD5,TBOX_OverSea
 SG_ BMS2_HighestVoltage_CellNum : 47|8@0+ (1,0) [0|200] "NoUnit" PDCS_FD1,TBOX,GW_FD5,TBOX_OverSea
 SG_ BMS2_LowestTemp_SensorNum : 55|8@0+ (1,0) [0|200] "NoUnit" PDCS_FD1,TBOX,GW_FD5,TBOX_OverSea
 SG_ BMS2_HighestTemp_SensorNum : 63|8@0+ (1,0) [0|200] "NoUnit" PDCS_FD1,TBOX,GW_FD5,TBOX_OverSea

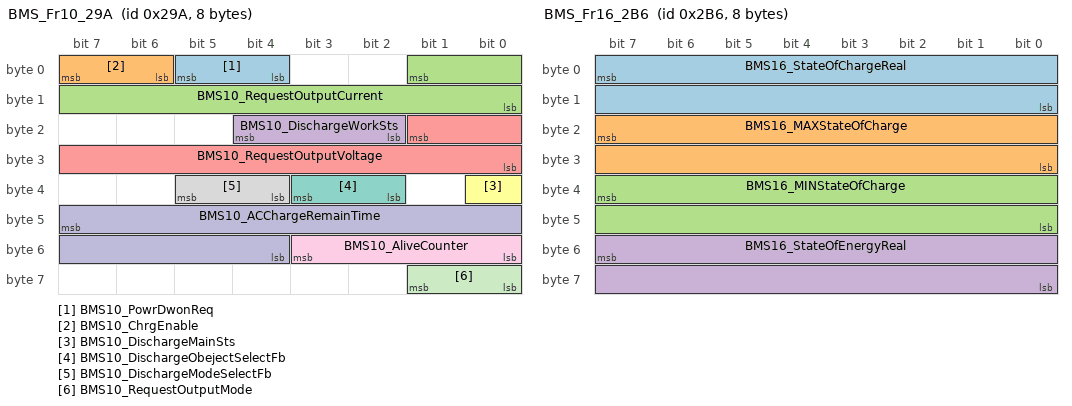
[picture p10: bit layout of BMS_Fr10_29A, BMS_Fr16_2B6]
BO_ 666 BMS_Fr10_29A: 8 BMS
 SG_ BMS10_PowrDwonReq : 5|2@0+ (1,0) [0|3] "NoUnit" CDU,GW_FD2,BDCS,BAM
 SG_ BMS10_ChrgEnable : 7|2@0+ (1,0) [0|3] "NoUnit" CDU,GW_FD2,BAM
 SG_ BMS10_RequestOutputCurrent : 1|10@0+ (0.1,0) [0|100] "A" PDCS_FD1,CDU,GW_FD2,BDCS,BAM
 SG_ BMS10_DischargeWorkSts : 20|3@0+ (1,0) [0|7] "NoUnit" PDCS_FD1,PDCU,DDCU,CDCS,CDCS_OverSea,TBOX,GW_FD5,ICU_E02,GW_FD4,ICU,GW_FD2,TBOX_OverSea
 SG_ BMS10_RequestOutputVoltage : 17|10@0+ (1,0) [0|1000] "V" PDCS_FD1,CDU,GW_FD2,BDCS,BAM
 SG_ BMS10_DischargeMainSts : 32|1@0+ (1,0) [0|1] "NoUnit" PDCS_FD1,TBOX,CDU,GW_FD5,ICU_E02,GW_FD4,ICU,CDCS,CDCS_OverSea,TBOX_OverSea
 SG_ BMS10_DischargeObejectSelectFb : 35|2@0+ (1,0) [0|3] "NoUnit" PDCS_FD1,TBOX,CDU,GW_FD5,ICU_E02,GW_FD4,ICU,CDCS,CDCS_OverSea,TBOX_OverSea
 SG_ BMS10_DischargeModeSelectFb : 37|2@0+ (1,0) [0|3] "NoUnit" PDCS_FD1,TBOX,GW_FD5,ICU_E02,GW_FD4,ICU,CDCS,CDCS_OverSea,TBOX_OverSea
 SG_ BMS10_AliveCounter : 51|4@0+ (1,0) [0|15] "NoUnit" PDCS_FD1,CDU,GW_FD2,BAM
 SG_ BMS10_ACChargeRemainTime : 47|12@0+ (1,0) [0|2400] "min" PDCS_FD1,BDCS,CDCS,CDCS_OverSea,TBOX,GW_FD5,ICU_E02,GW_FD4,ICU,GW_FD2,TBOX_OverSea
 SG_ BMS10_RequestOutputMode : 57|2@0+ (1,0) [0|3] "NoUnit" PDCS_FD1,TBOX,CDU,GW_FD5,GW_FD2,BDCS,BAM,TBOX_OverSea

BO_ 694 BMS_Fr16_2B6: 8 BMS
 SG_ BMS16_StateOfChargeReal : 7|16@0+ (0.1,0) [0|100] "%" PDCS_FD1,IDB,ESC_FD3,GW_FD3,ISC,GW_FD2,EHB_FD3,BDCS
 SG_ BMS16_MAXStateOfCharge : 23|16@0+ (0.1,0) [0|100] "%" PDCS_FD1
 SG_ BMS16_MINStateOfCharge : 39|16@0+ (0.1,0) [0|100] "%" PDCS_FD1
 SG_ BMS16_StateOfEnergyReal : 55|16@0+ (0.1,0) [0|254] "Kwh" PDCS_FD1,GW_FD2,BDCS

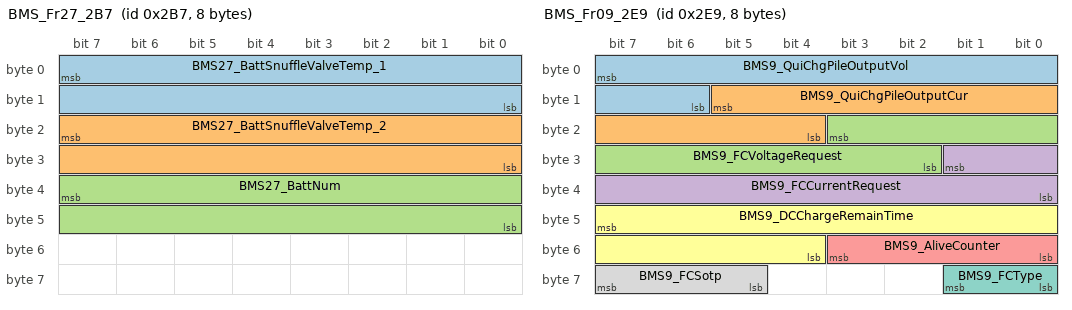
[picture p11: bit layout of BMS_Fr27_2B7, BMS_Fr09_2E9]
BO_ 695 BMS_Fr27_2B7: 8 BMS
 SG_ BMS27_BattSnuffleValveTemp_1 : 7|16@0+ (1,-40) [-40|125] "NoUnit" TBOX,GW_FD5,TBOX_OverSea
 SG_ BMS27_BattSnuffleValveTemp_2 : 23|16@0+ (1,-40) [-40|125] "NoUnit" TBOX,GW_FD5,TBOX_OverSea
 SG_ BMS27_BattNum : 39|16@0+ (1,0) [0|65535] "NoUnit" Vector__XXX

BO_ 745 BMS_Fr09_2E9: 8 BMS
 SG_ BMS9_QuiChgPileOutputVol : 7|10@0+ (1,0) [0|1000] "V" PDCS_FD1,TBOX,GW_FD5,TBOX_OverSea
 SG_ BMS9_QuiChgPileOutputCur : 13|10@0+ (1,-400) [-400|400] "A" PDCS_FD1,TBOX,GW_FD5,TBOX_OverSea
 SG_ BMS9_FCVoltageRequest : 19|10@0+ (1,0) [0|1000] "V" PDCS_FD1,TBOX,GW_FD5,GW_FD2,BDCS,TBOX_OverSea
 SG_ BMS9_FCCurrentRequest : 25|10@0+ (1,-400) [-400|400] "A" PDCS_FD1,TBOX,GW_FD5,GW_FD2,BDCS,TBOX_OverSea
 SG_ BMS9_AliveCounter : 51|4@0+ (1,0) [0|15] "NoUnit" PDCS_FD1,TBOX,GW_FD5,TBOX_OverSea
 SG_ BMS9_DCChargeRemainTime : 47|12@0+ (1,0) [0|2400] "min" PDCS_FD1,TBOX,GW_FD5,GW_FD4,GW_FD2,BDCS,CDCS,CDCS_OverSea,TBOX_OverSea
 SG_ BMS9_FCType : 57|2@0+ (1,0) [0|3] "NoUnit" PDCS_FD1,TBOX,GW_FD5,TBOX_OverSea
 SG_ BMS9_FCSotp : 63|3@0+ (1,0) [0|7] "NoUnit" PDCS_FD1,TBOX,GW_FD5,TBOX_OverSea

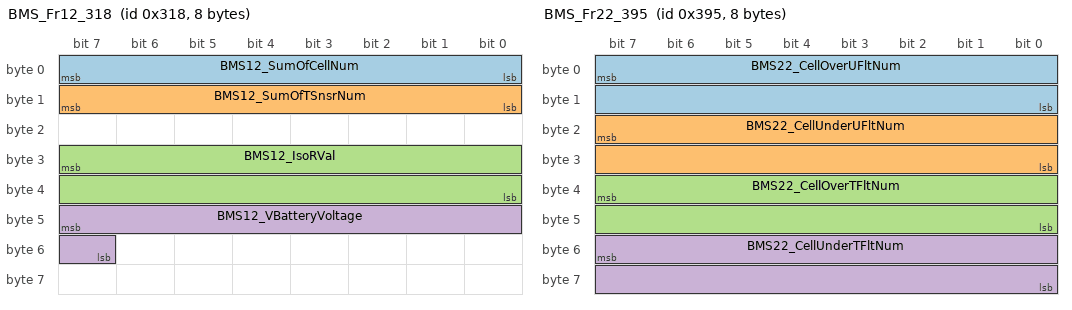
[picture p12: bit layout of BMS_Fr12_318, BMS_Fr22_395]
BO_ 792 BMS_Fr12_318: 8 BMS
 SG_ BMS12_SumOfCellNum : 7|8@0+ (1,0) [0|254] "NoUnit" TBOX,GW_FD5,TBOX_OverSea
 SG_ BMS12_SumOfTSnsrNum : 15|8@0+ (1,0) [0|254] "NoUnit" TBOX,GW_FD5,TBOX_OverSea
 SG_ BMS12_IsoRVal : 31|16@0+ (1,0) [0|60000] "KΩ" TBOX,GW_FD5,TBOX_OverSea
 SG_ BMS12_VBatteryVoltage : 47|9@0+ (0.05,0) [0|25] "V" TBOX,GW_FD5,TBOX_OverSea

BO_ 913 BMS_Fr18_391: 8 BMS
 SG_ BMS18_Hds_ah_AccumChrgCpSum : 2|25@0+ (0.01,0) [0|210240] "Ah" TBOX,GW_FD5,TBOX_OverSea
 SG_ BMS18_Hds_egy_AccumChrgEgySum : 38|23@0+ (0.01,0) [0|68036] "Kwh" TBOX,GW_FD5,TBOX_OverSea

BO_ 914 BMS_Fr19_392: 8 BMS
 SG_ BMS19_Hds_ah_AccumDchaCpSum : 2|25@0+ (0.01,0) [0|210240] "Ah" TBOX,GW_FD5,TBOX_OverSea
 SG_ BMS19_Hds_kWh_AccumDchaEgySum : 38|23@0+ (0.01,0) [0|68036] "Kwh" TBOX,GW_FD5,TBOX_OverSea

BO_ 915 BMS_Fr20_393: 8 BMS
 SG_ BMS20_Hds_ah_AccumRechrgCpSum : 2|25@0+ (0.01,0) [0|210240] "Ah" TBOX,GW_FD5,TBOX_OverSea
 SG_ BMS20_Hds_kWh_AccumRechrgEgySum : 38|23@0+ (0.01,0) [0|68036] "Kwh" TBOX,GW_FD5,TBOX_OverSea

BO_ 916 BMS_Fr21_394: 8 BMS
 SG_ BMS21_HistorcumulativerunT : 7|32@0+ (1,0) [0|4.294967295E9] "NoUnit" TBOX,GW_FD5,TBOX_OverSea
 SG_ BMS21_HistorcumulativedormancyT : 39|32@0+ (1,0) [0|4.294967295E9] "NoUnit" TBOX,GW_FD5,TBOX_OverSea

BO_ 917 BMS_Fr22_395: 8 BMS
 SG_ BMS22_CellOverUFltNum : 7|16@0+ (1,0) [0|65535] "NoUnit" TBOX,GW_FD5,TBOX_OverSea
 SG_ BMS22_CellUnderUFltNum : 23|16@0+ (1,0) [0|65535] "NoUnit" TBOX,GW_FD5,TBOX_OverSea
 SG_ BMS22_CellOverTFltNum : 39|16@0+ (1,0) [0|65535] "NoUnit" TBOX,GW_FD5,TBOX_OverSea
 SG_ BMS22_CellUnderTFltNum : 55|16@0+ (1,0) [0|65535] "NoUnit" TBOX,GW_FD5,TBOX_OverSea

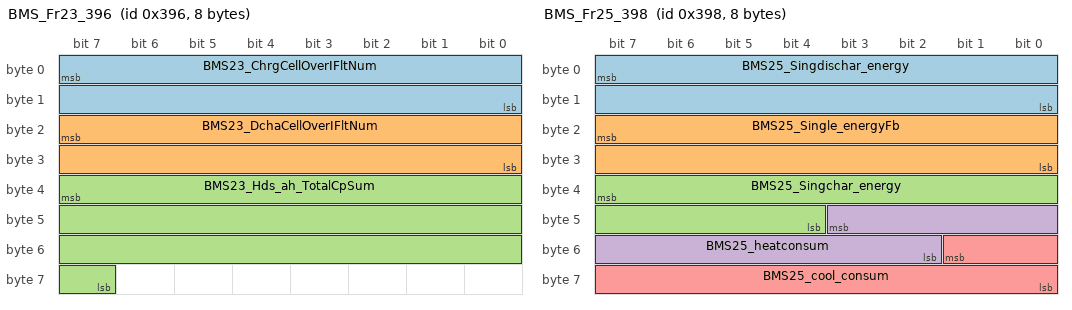
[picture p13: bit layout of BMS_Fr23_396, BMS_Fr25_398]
BO_ 918 BMS_Fr23_396: 8 BMS
 SG_ BMS23_ChrgCellOverIFltNum : 7|16@0+ (1,0) [0|65535] "NoUnit" TBOX,GW_FD5,TBOX_OverSea
 SG_ BMS23_DchaCellOverIFltNum : 23|16@0+ (1,0) [0|65535] "NoUnit" TBOX,GW_FD5,TBOX_OverSea
 SG_ BMS23_Hds_ah_TotalCpSum : 39|25@0+ (0.01,0) [0|210240] "Ah" TBOX,GW_FD5,GW_FD4,CDCS,CDCS_OverSea,TBOX_OverSea

BO_ 919 BMS_Fr24_397: 8 BMS
 SG_ BMS24_Hds_ah_ReActiveCpSum : 1|25@0+ (0.01,0) [0|210240] "NoUnit" TBOX,GW_FD5,TBOX_OverSea
 SG_ BMS24_Hds_ah_ActiveCpSum : 24|25@0+ (0.01,0) [0|210240] "NoUnit" TBOX,GW_FD5,TBOX_OverSea

BO_ 920 BMS_Fr25_398: 8 BMS
 SG_ BMS25_Singdischar_energy : 7|16@0+ (0.1,0) [0|999] "Kwh" TBOX,GW_FD5,TBOX_OverSea
 SG_ BMS25_Single_energyFb : 23|16@0+ (0.1,0) [0|999] "Kwh" TBOX,GW_FD5,TBOX_OverSea
 SG_ BMS25_Singchar_energy : 39|12@0+ (0.1,0) [0|400] "Kwh" PDCS_FD1,TBOX,GW_FD5,TBOX_OverSea
 SG_ BMS25_heatconsum : 43|10@0+ (0.1,0) [0|102] "Kwh" PDCS_FD1,TBOX,GW_FD5,GW_FD2,BDCS,TBOX_OverSea
 SG_ BMS25_cool_consum : 49|10@0+ (0.1,0) [0|102] "Kwh" PDCS_FD1,TBOX,GW_FD5,GW_FD2,BDCS,TBOX_OverSea

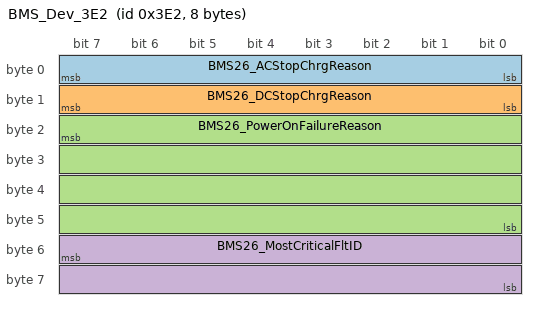
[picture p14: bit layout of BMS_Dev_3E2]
BO_ 994 BMS_Dev_3E2: 8 BMS
 SG_ BMS26_ACStopChrgReason : 7|8@0+ (1,0) [0|255] "NoUnit" TBOX,GW_FD5,TBOX_OverSea
 SG_ BMS26_DCStopChrgReason : 15|8@0+ (1,0) [0|255] "NoUnit" TBOX,GW_FD5,TBOX_OverSea
 SG_ BMS26_PowerOnFailureReason : 23|32@0+ (1,0) [0|4.294967295E9] "NoUnit" TBOX,GW_FD5,TBOX_OverSea
 SG_ BMS26_MostCriticalFltID : 55|16@0+ (1,0) [0|65535] "NoUnit" TBOX,GW_FD5,TBOX_OverSea

BO_ 1540 BMS_NM_604: 8 BMS
 SG_ BMS_SourceNodeIdentifier : 7|8@0+ (1,0) [0|255] "NoUnit" Vector__XXX
 SG_ BMS_RepeatMessageRequest : 8|1@0+ (1,0) [0|1] "NoUnit" Vector__XXX
 SG_ BMS_Reserve1 : 11|3@0+ (1,0) [0|3] "NoUnit" Vector__XXX
 SG_ BMS_ActiveWakeup : 12|1@0+ (1,0) [0|1] "NoUnit" Vector__XXX
 SG_ BMS_Reserve2 : 15|3@0+ (1,0) [0|7] "NoUnit" Vector__XXX
 SG_ BMS_WakeUp_KL15 : 16|1@0+ (1,0) [0|1] "NoUnit" Vector__XXX
 SG_ BMS_WakeUp_NM : 17|1@0+ (1,0) [0|1] "NoUnit" Vector__XXX
 SG_ BMS_WakeUp_ThermalDiffusion : 18|1@0+ (1,0) [0|1] "NoUnit" Vector__XXX
 SG_ BMS_WakeUpReason4 : 19|1@0+ (1,0) [0|1] "NoUnit" Vector__XXX
 SG_ BMS_WakeUpReason5 : 20|1@0+ (1,0) [0|1] "NoUnit" Vector__XXX
 SG_ BMS_WakeUp_PreCharge : 21|1@0+ (1,0) [0|1] "NoUnit" Vector__XXX
 SG_ BMS_WakeUp_OTA : 22|1@0+ (1,0) [0|1] "NoUnit" Vector__XXX
 SG_ BMS_WakeUp_OverAmTemp : 23|1@0+ (1,0) [0|1] "NoUnit" Vector__XXX
 SG_ BMS_RepeatFromSleep : 24|1@0+ (1,0) [0|1] "NoUnit" Vector__XXX
 SG_ BMS_RepeatFromPrepare : 25|1@0+ (1,0) [0|1] "NoUnit" Vector__XXX
 SG_ BMS_NormalFromRepeat : 26|1@0+ (1,0) [0|1] "NoUnit" Vector__XXX
 SG_ BMS_NormalFromReady : 27|1@0+ (1,0) [0|1] "NoUnit" Vector__XXX
 SG_ BMS_RepeatFromReady : 28|1@0+ (1,0) [0|1] "NoUnit" Vector__XXX
 SG_ BMS_RepeatFromNormal : 29|1@0+ (1,0) [0|1] "NoUnit" Vector__XXX
 SG_ BMS_RemainNetworkWakeUpReason1 : 32|1@0+ (1,0) [0|1] "NoUnit" Vector__XXX
 SG_ BMS_RemainNetworkWakeUpReason2 : 33|1@0+ (1,0) [0|1] "NoUnit" Vector__XXX
 SG_ BMS_RemainNetworkWakeUpReason3 : 34|1@0+ (1,0) [0|1] "NoUnit" Vector__XXX
 SG_ BMS_RemainNetworkWakeUpReason4 : 35|1@0+ (1,0) [0|1] "NoUnit" Vector__XXX
 SG_ BMS_RemainNetworkWakeUpReason5 : 36|1@0+ (1,0) [0|1] "NoUnit" Vector__XXX
 SG_ BMS_RemainNetworkWakeUpReason6 : 37|1@0+ (1,0) [0|1] "NoUnit" Vector__XXX
 SG_ BMS_RemainNetworkWakeUpReason7 : 38|1@0+ (1,0) [0|1] "NoUnit" Vector__XXX
 SG_ BMS_RemainNetworkWakeUpReason8 : 39|1@0+ (1,0) [0|1] "NoUnit" Vector__XXX
 SG_ BMS_RemainNetworkWakeUpReason9 : 40|1@0+ (1,0) [0|1] "NoUnit" Vector__XXX
 SG_ BMS_RemainNetworkWakeUpReason10 : 41|1@0+ (1,0) [0|1] "NoUnit" Vector__XXX

BO_ 170 MCU_Fr01_0AA: 16 MCU
 SG_ MCU1_MaxAvailableTorque : 7|16@0+ (0.05,0) [0|1024] "Nm" PDCS_FD1,TBOX,GW_FD5,PDCS_HVM_FD1,TBOX_OverSea
 SG_ MCU1_MotorSpeed : 23|16@0+ (1,-20000) [-20000|45531] "rpm" PDCS_FD1,IDB,ESC_FD3,ADCU_FD3,EHB_FD3,CDCS,ADCS_FD3,CDCS_OverSea,TBOX,FLC_ME_FD3,FLC_FD3,GW_FD5,ICU_E02,GW_FD3,ISC,GW_FD4,ICU,PDCS_HVM_FD1,TBOX_OverSea
 SG_ MCU1_ControllerTorque : 39|16@0+ (0.05,-1024) [-1024|1024] "Nm" PDCS_FD1,IDB,ESC_FD3,ADCU_FD3,EHB_FD3,ADCS_FD3,TBOX,FLC_ME_FD3,FLC_FD3,GW_FD5,ICU_E02,GW_FD3,ISC,GW_FD4,ICU,PDCS_HVM_FD1,TBOX_OverSea
 SG_ MCU1_AliveCounter : 51|4@0+ (1,0) [0|15] "NoUnit" PDCS_FD1,IDB,ESC_FD3,ADCU_FD3,EHB_FD3,CDCS,ADCS_FD3,CDCS_OverSea,TBOX,FLC_ME_FD3,FLC_FD3,GW_FD5,ICU_E02,GW_FD3,GW_FD4,ICU,PDCS_HVM_FD1,TBOX_OverSea
 SG_ MCU1_Mode : 54|3@0+ (1,0) [0|7] "NoUnit" PDCS_FD1,IDB,ESC_FD3,EHB_FD3,CDCS,CDCS_OverSea,TBOX,GW_FD5,GW_FD3,ISC,GW_FD4,PDCS_HVM_FD1,TBOX_OverSea
 SG_ MCU1_ControllerTorqueValid : 55|1@0+ (1,0) [0|1] "NoUnit" PDCS_FD1,PDCS_HVM_FD1
 SG_ MCU1_Checksum : 63|8@0+ (1,0) [0|255] "NoUnit" PDCS_FD1,ICU_E02,IDB,ESC_FD3,GW_FD3,GW_FD4,ICU,EHB_FD3,CDCS,PDCS_HVM_FD1,CDCS_OverSea
 SG_ MCU1_presentActivityFault : 71|8@0+ (1,0) [0|128] "NoUnit" TBOX,FLC_ME_FD3,FLC_FD3,GW_FD5,GW_FD3,ISC,ADCU_FD3,ADCS_FD3,TBOX_OverSea
 SG_ MCU1_CurrentTorque : 78|15@0+ (0.05,-400) [-400|400] "Nm" FLC_ME_FD3,FLC_FD3,IDB,GW_FD3,ADCU_FD3,ADCS_FD3
 SG_ MCU1_TorMonitorFault : 94|1@0+ (1,0) [0|1] "NoUnit" Vector__XXX
 SG_ MCU1_CurrentTorqueValid : 95|1@0+ (1,0) [0|1] "NoUnit" FLC_ME_FD3,FLC_FD3,IDB,GW_FD3,ADCU_FD3,ADCS_FD3
 SG_ MCU1_MonitorTorque : 103|16@0+ (0.05,-1024) [-1024|1024] "Nm" Vector__XXX

BO_TX_BU_ 579 : GW_FD5,GW_FD6,GW_FD3,GW_FD4,GW_FD1,GW_FD2;
BO_TX_BU_ 347 : GW_FD3,GW_FD4,GW_FD1,GW_FD2;
BO_TX_BU_ 405 : GW_FD5,GW_FD4;
BO_TX_BU_ 533 : GW_FD3,GW_FD4;
BO_TX_BU_ 1536 : GW_FD5,GW_FD6,GW_FD3,GW_FD4,GW_FD1,GW_FD2;
BO_TX_BU_ 129 : PDCS_FD1,PDCS_HVM_FD1;
BO_TX_BU_ 208 : PDCS_FD1,PDCS_HVM_FD1;
BO_TX_BU_ 232 : PDCS_FD1,PDCS_HVM_FD1;
BO_TX_BU_ 291 : PDCS_FD1,PDCS_HVM_FD1;
BO_TX_BU_ 384 : PDCS_FD1,PDCS_HVM_FD1;
BO_TX_BU_ 531 : PDCS_FD1,PDCS_HVM_FD1;
BO_TX_BU_ 854 : PDCS_FD1,PDCS_HVM_FD1;
BO_TX_BU_ 856 : PDCS_FD1,PDCS_HVM_FD1;
BO_TX_BU_ 200 : PDCS_FD1,PDCS_HVM_FD1;
BO_TX_BU_ 227 : PDCS_FD1,PDCS_HVM_FD1;
BO_TX_BU_ 242 : PDCS_FD1,PDCS_HVM_FD1;
BO_TX_BU_ 251 : PDCS_FD1,PDCS_HVM_FD1;
BO_TX_BU_ 252 : PDCS_FD1,PDCS_HVM_FD1;
BO_TX_BU_ 553 : PDCS_FD1,PDCS_HVM_FD1;
BO_TX_BU_ 724 : PDCS_FD1,PDCS_HVM_FD1;
BO_TX_BU_ 809 : PDCS_FD1,PDCS_HVM_FD1;
BO_TX_BU_ 1073 : PDCS_FD1,PDCS_HVM_FD1;
BO_TX_BU_ 571 : PDCS_FD1,PDCS_HVM_FD1;
BO_TX_BU_ 816 : PDCS_FD1,PDCS_HVM_FD1;
BO_TX_BU_ 1172 : PDCS_FD1,PDCS_HVM_FD1;
BO_TX_BU_ 1545 : PDCS_FD1,PDCS_HVM_FD1;
BO_TX_BU_ 961 : PDCS_FD1,PDCS_HVM_FD1;
BO_TX_BU_ 964 : PDCS_FD1,PDCS_HVM_FD1;
BO_TX_BU_ 966 : PDCS_FD1,PDCS_HVM_FD1;
BO_TX_BU_ 968 : PDCS_FD1,PDCS_HVM_FD1;
BO_TX_BU_ 970 : PDCS_FD1,PDCS_HVM_FD1;
BO_TX_BU_ 253 : BMS,PDCS_HVM_FD1;
BO_TX_BU_ 246 : BMS,PDCS_HVM_FD1;
BO_TX_BU_ 600 : BMS,PDCS_HVM_FD1;
BO_TX_BU_ 136 : BMS,PDCS_HVM_FD1;
BO_TX_BU_ 261 : BMS,PDCS_HVM_FD1;
BO_TX_BU_ 631 : BMS,PDCS_HVM_FD1;
BO_TX_BU_ 632 : BMS,PDCS_HVM_FD1;
BO_TX_BU_ 648 : BMS,PDCS_HVM_FD1;
BO_TX_BU_ 658 : BMS,PDCS_HVM_FD1;
BO_TX_BU_ 666 : BMS,PDCS_HVM_FD1;
BO_TX_BU_ 694 : BMS,PDCS_HVM_FD1;
BO_TX_BU_ 695 : BMS,PDCS_HVM_FD1;
BO_TX_BU_ 745 : BMS,PDCS_HVM_FD1;
BO_TX_BU_ 792 : BMS,PDCS_HVM_FD1;
BO_TX_BU_ 913 : BMS,PDCS_HVM_FD1;
BO_TX_BU_ 914 : BMS,PDCS_HVM_FD1;
BO_TX_BU_ 915 : BMS,PDCS_HVM_FD1;
BO_TX_BU_ 916 : BMS,PDCS_HVM_FD1;
BO_TX_BU_ 917 : BMS,PDCS_HVM_FD1;
BO_TX_BU_ 918 : BMS,PDCS_HVM_FD1;
BO_TX_BU_ 919 : BMS,PDCS_HVM_FD1;
BO_TX_BU_ 920 : BMS,PDCS_HVM_FD1;
BO_TX_BU_ 994 : BMS,PDCS_HVM_FD1;

CM_ BO_ 252 "T-Box接收该报文中信号上传TSP，在FD5周期改为1000ms";
CM_ BO_ 1172 "PDCS内部状态监控";
CM_ SG_ 579 AICS2_OTAMode "OTA模式进入及退出请求";
CM_ SG_ 579 AICS2_StopChargeing "断开充电";
CM_ SG_ 579 AICS2_BootRequestHVShut "OTA刷写三电下高压电请求";
CM_ SG_ 579 AICS2_CDCS_CertificateState "PKI证书状态";
CM_ SG_ 982 AICS1_Resp_EncrData0 "AICS OTA控制身份认证响应0";
CM_ SG_ 982 AICS1_Resp_EncrData1 "AICS OTA控制身份认证响应1";
CM_ SG_ 982 AICS1_Resp_EncrData2 "AICS OTA控制身份认证响应2";
CM_ SG_ 982 AICS1_Resp_EncrData3 "AICS OTA控制身份认证响应3";
CM_ SG_ 982 AICS1_Resp_EncrData4 "AICS OTA控制身份认证响应4";
CM_ SG_ 982 AICS1_Resp_EncrData5 "AICS OTA控制身份认证响应5";
CM_ SG_ 982 AICS1_Resp_EncrData6 "AICS OTA控制身份认证响应6";
CM_ SG_ 982 AICS1_Resp_EncrData7 "AICS OTA控制身份认证响应7";
CM_ SG_ 347 SWSM_A_CruiseDistance_Add "巡航跟车距离加开关";
CM_ SG_ 347 SWSM_A_CruiseDistance_Minus "巡航跟车距离减开关";
CM_ SG_ 347 SWSM_A_CruiseSpeed_Add "方向盘A区巡航车速+开关";
CM_ SG_ 347 SWSM_A_CruiseSpeed_Minus "方向盘A区巡航车速-开关";
CM_ SG_ 347 SWSM_A_SpeechInputSw "语音唤醒开关";
CM_ SG_ 347 Region_A_SwError "方向盘A区开关故障";
CM_ SG_ 347 SWSM_A_CD_Add_Overtime "CD加开关超时";
CM_ SG_ 347 SWSM_A_CD_Minus_Overtime "CD减开关超时";
CM_ SG_ 347 SWSM_B_PrevSw "方向盘B区上一曲/接通开关";
CM_ SG_ 347 SWSM_B_NextSw "方向盘B区下一曲/挂断开关";
CM_ SG_ 347 SWSM_B_Volume_Add "方向盘B区音量+开关";
CM_ SG_ 347 SWSM_B_Volume_Minus "方向盘B区音量-开关";
CM_ SG_ 347 SWSM_B_MuteSw "方向盘B区静音开关";
CM_ SG_ 347 Region_B_SwError "方向盘B区开关故障";
CM_ SG_ 347 SWSM_B_PrevSw_Overtime "上一曲开关超时";
CM_ SG_ 347 SWSM_B_NextSw_Overtime "下一曲开关超时";
CM_ SG_ 405 FPA_ResponseError "ResponseError";
CM_ SG_ 405 FPA_Staus "Feedback_FPAS_working_status_Frnt";
CM_ SG_ 405 FPA_AssemblyNumberDID "Vehicle Manufacturer ECU Software Assembly Number Data Identifier";
CM_ SG_ 405 FPA_DetectionFOL "Detection_info_for_display_FOL";
CM_ SG_ 405 FPA_DetectionFML "Detection_info_for_display_FML";
CM_ SG_ 405 FPA_DetectionFMR "Detection_info_for_display_FMR";
CM_ SG_ 405 FPA_DetectionFOR "Detection_info_for_display_FOR";
CM_ SG_ 405 FPA_FOLErrorFlag "FOL_Error_Flag";
CM_ SG_ 405 FPA_FMLErrorFlag "FML_Error_Flag";
CM_ SG_ 405 FPA_FMRErrorFlag "FMR_Error_Flag";
CM_ SG_ 405 FPA_FORErrorFlag "FOR_Error_Flag";
CM_ SG_ 405 FPA_PoweVoltageAbnormal "Power_voltage_abnormal";
CM_ SG_ 405 FPA_Sound_Location "FPAS_Sound_Location";
CM_ SG_ 405 FPA_SoundIndication "Front_Park_Assistant_System_Sound_Indication";
CM_ SG_ 405 FPA_HardwareVersion "Hardware version number";
CM_ SG_ 405 FPA_SoftwareSubVersion "Software sub version number";
CM_ SG_ 405 FPA_SoftwareMainVersion "Software main version number";
CM_ SG_ 405 RPA_ResponseError "RPA_ResponseError";
CM_ SG_ 405 RPA_Staus "Feedback_RPAS_working_status_Rear";
CM_ SG_ 405 RPA_AssemblyNumberDID "Vehicle Manufacturer ECU Software Assembly Number Data Identifier";
CM_ SG_ 405 RPA_DetectionROL "Detection_info_for_display_ROL";
CM_ SG_ 405 RPA_DetectionRML "Detection_info_for_display_RML";
CM_ SG_ 405 RPA_DetectionRMR "Detection_info_for_display_RMR";
CM_ SG_ 405 RPA_DetectionROR "Detection_info_for_display_ROR";
CM_ SG_ 405 RPA_ROLErrorFlag "ROL_Error_Flag";
CM_ SG_ 405 RPA_RMLErrorFlag "RML_Error_Flag";
CM_ SG_ 405 RPA_RMRErrorFlag "RMR_Error_Flag";
CM_ SG_ 405 RPA_RORErrorFlag "ROR_Error_Flag";
CM_ SG_ 405 RPA_PoweVoltageAbnormal "Power_voltage_abnormal";
CM_ SG_ 405 RPA_Sound_Location "RPAS_Sound_Location";
CM_ SG_ 405 RPA_SoundIndication "Rear_Park_Assistant_System_Sound_Indication";
CM_ SG_ 405 RPA_HardwareVersion "Hardware version number";
CM_ SG_ 405 RPA_SoftwareSubVersion "Software sub version number";
CM_ SG_ 405 RPA_SoftwareMainVersion "Software main version number";
CM_ SG_ 533 AICS_PDCS2_IBS_SOC "小电池SOC值(转发自FD1网段0x431报文)";
CM_ SG_ 533 AICS_BDCS8_Drive_ODS "Drive ODS  status on CAN Bus
主驾占位传感器状态(转发自FD2网段0x2A5报文)";
CM_ SG_ 533 AICS_PDCS2_HvPwrUpReq "高压上电请求";
CM_ SG_ 533 AICS_PDCS2_HvPwrDwnReq "高压下电请求";
CM_ SG_ 1233 AICS_GCU3_OperModFdbk "GCU反馈的工作模式
GCU Operating Mode";
CM_ SG_ 1233 AICS_GCU3_Motor_Torque "GCU反馈的实际转矩
GCU Actual Torque";
CM_ SG_ 1233 AICS_GCU3_Motor_Speed "GCU反馈的实际转速
GCU Actual Speed";
CM_ SG_ 1233 AICS_EMS1_EngineStartedCompleted "Engine start completed";
CM_ SG_ 1233 AICS_EMS1_EngineStopAllow "Engine stop allowed";
CM_ SG_ 1233 AICS_EMS1_ActualEngineTorqueValid "Actual engine flywheel torque validity";
CM_ SG_ 1233 AICS_EMS1_ActualEngineTorque "Actual engine flywheel torque";
CM_ SG_ 1233 AICS_EMS1_EngineTorqMin "Min engine torque (Flywheel/Indicated)";
CM_ SG_ 1233 AICS_EMS1_EngineTorqMax "Max engine torque (Flywheel/Indicated)";
CM_ SG_ 1233 AICS_EMS1_EngineTorqLoss "Engine friction torque";
CM_ SG_ 1536 AICS_SourceNodeIdentifier "ECU节点标识符";
CM_ SG_ 1536 AICS_RepeatMessageRequest "Repeat Message请求";
CM_ SG_ 1536 AICS_Reserve1 "预留";
CM_ SG_ 1536 AICS_ActiveWakeup "激活唤醒，主动唤醒网络时置1，其他（包括被动唤醒节点）为0";
CM_ SG_ 1536 AICS_Reserve2 "预留";
CM_ SG_ 1536 AICS_WakeUp_KL15 "KL15 ON唤醒";
CM_ SG_ 1536 AICS_WakeUp_NM "NM报文唤醒";
CM_ SG_ 1536 AICS_WakeUp_LIN "LIN电平变化唤醒";
CM_ SG_ 1536 AICS_WakeUp_LocalPreCharge "本地预约充电";
CM_ SG_ 1536 AICS_WakeUp_RemotePreCharge "远程预约充电";
CM_ SG_ 1536 AICS_WakeUp_OTA "OTA";
CM_ SG_ 1536 AICS_WakeUp_Remote "远程功能";
CM_ SG_ 1536 AICS_WakeUp_PhoneReminder "手机遗忘提醒";
CM_ SG_ 1536 AICS_RemainNetworkWakeUp_BMS_NM "KL15 OFF持续收到BMS 网络管理报文0x604";
CM_ SG_ 1536 AICS_RemainNetworkWakeUp_CDU_NM "KL15 OFF持续收到CDU 网络管理报文0x606";
CM_ SG_ 1536 AICS_RemainNetworkWakeUp_MCU_NM "KL15 OFF持续收到MCU 网络管理报文0x636";
CM_ SG_ 1536 AICS_RemainNetworkWakeUp_PDCU_NM "KL15 OFF持续收到PDCU 网络管理报文0x60D";
CM_ SG_ 1536 AICS_RemainNetworkWakeUp_ADCS_NM "KL15 OFF持续收到ADCS 网络管理报文0x607";
CM_ SG_ 1536 AICS_RemainNetworkWakeUp_PDCS_NM "KL15 OFF持续收到PDCS 网络管理报文0x609";
CM_ SG_ 1536 AICS_RemainNetworkWakeUp_DDCU_NM "KL15 OFF持续收到DDCU 网络管理报文0x60E";
CM_ SG_ 1536 AICS_RemainNetworkWakeUpReason1 "预留";
CM_ SG_ 1536 AICS_RemainNetworkWakeUpReason2 "预留";
CM_ SG_ 1536 AICS_RemainNetworkWakeUp_BDCS_NM "KL15 OFF持续收到BDCS 网络管理报文0x602";
CM_ SG_ 1536 AICS_RemainNetworkWakeUp_FMCU_NM "KL15 OFF持续收到FMCU 网络管理报文0x638";
CM_ SG_ 1536 AICS_RemainNetworkWakeUp_ICU_NM "KL15 OFF持续收到ICU 网络管理报文0x641";
CM_ SG_ 1536 AICS_RemainNetworkWakeUp_CDCS_NM "KL15 OFF持续收到CDCS 网络管理报文0x608";
CM_ SG_ 1536 AICS_RemainNetworkWakeUp_AMP_NM "KL15 OFF持续收到AMP 网络管理报文0x635";
CM_ SG_ 1536 AICS_RemainNetworkWakeUp_BTM_NM "KL15 OFF持续收到BTM 网络管理报文0x637";
CM_ SG_ 1536 AICS_RemainNetworkWakeUpReason3 "预留";
CM_ SG_ 1536 AICS_RemainNetworkWakeUp_GCU_NM "KL15 OFF持续收到GCU 网络管理报文0x639";
CM_ SG_ 1536 AICS_RemainNetworkWakeUp_HUD_NM "KL15 OFF持续收到HUD 网络管理报文0x648";
CM_ SG_ 1536 AICS_RemainNetworkWakeUp_T_BOX_NM "KL15 OFF持续收到T_BOX 网络管理报文0x601";
CM_ SG_ 1536 AICS_RemainNetworkWakeUp_LIN "KL15 OFF持续收到LIN电平变化";
CM_ SG_ 1536 AICS_RemainNetworkWakeUpReason22 "保持网络唤醒原因22";
CM_ SG_ 1536 AICS_RemainNetworkWakeUpReason23 "保持网络唤醒原因23";
CM_ SG_ 1536 AICS_RemainNetworkWakeUpReason24 "保持网络唤醒原因24";
CM_ SG_ 1536 AICS_UserData5 "用户数据5预留";
CM_ SG_ 129 HCU4_GcuModeReq "请求GCU工作模式";
CM_ SG_ 129 HCU4_GcuTorqueReq "请求GCU扭矩值";
CM_ SG_ 129 HCU4_GcuSpdReq "请求GCU转速值";
CM_ SG_ 129 HCU4_GCU_Fault_Reset "请求GCU清除故障";
CM_ SG_ 129 HCU4_GCU_Enable "HCU请求GCU使能";
CM_ SG_ 129 HCU4_GcuVoltageTargetReq "请求GCU目标电压值";
CM_ SG_ 129 HCU4_CycCounter "E2E Profile2-CRC8H2F，Counter:0-15";
CM_ SG_ 129 HCU4_CrcChecksum "E2E Profile2-CRC8H2F
DataID List:#64 - 146 66 18 112 62 74 95 181 178 98 228 126 132 205 227 157";
CM_ SG_ 208 HCU1_EngineStartRequest "Engine start request";
CM_ SG_ 208 HCU1_EngStart_Sts "增程器起动状态位";
CM_ SG_ 208 HCU1_EngineFuelInhibitRequest "Engine fuel inhibit request";
CM_ SG_ 208 HCU1_ReqTorq "Flywheel torque request";
CM_ SG_ 208 HCU1_EngineOffRequest "Engine off request";
CM_ SG_ 208 HCU1_ReqTorqActive "Flywheel torque request active";
CM_ SG_ 208 HCU1_FastTorque "Engine fast torque request";
CM_ SG_ 208 HCU1_TorqLimitReqActive "Engine torque limit request active";
CM_ SG_ 208 HCU1_VehicleReady "Vehicle propulsion state is ready to work";
CM_ SG_ 208 HCU1_EmissionLampRequest "HCU请求仪表MIL灯点亮（发给ECU，由ECU点亮MIL灯）";
CM_ SG_ 208 HCU1_FastTorqueActive "Engine fast torque request active";
CM_ SG_ 208 HCU1_TorqLimitRequest "Engine torque limit request";
CM_ SG_ 208 HCU1_CycCounter "E2E Profile2-CRC8H2F，Counter:0-15";
CM_ SG_ 208 HCU1_EngStop_Sts "增程器停机状态位";
CM_ SG_ 208 HCU1_CrcChecksum "E2E Profile2-CRC8H2F
DataID List:#64 - 146 66 18 112 62 74 95 181 178 98 228 126 132 205 227 157";
CM_ SG_ 232 HCU2_EMSIdleAllowed "Allow EMS enable idle control";
CM_ SG_ 232 HCU2_EngineIdleSpeedRequest "Engine idle speed request active";
CM_ SG_ 232 HCU2_GeneratorTorqueValid "Generator torque validity";
CM_ SG_ 232 HCU2_FVVOpenRequest "FVV open request for refuel";
CM_ SG_ 232 HCU2_EngineIdleSpeed "Desired idle speed";
CM_ SG_ 232 HCU2_GeneratorTorque "Generator torque";
CM_ SG_ 232 HCU2_HybridModeStatus "混动模式状态（满足GB T-32960要求）";
CM_ SG_ 232 HCU2_EngineSpeedModeRequest "发动机转速模式请求";
CM_ SG_ 232 HCU2_EngineSpeedSetpoint "发动机转速模式目标转速";
CM_ SG_ 291 HCU6_Limit_HighTorque_Value "HCU请求限制，转速模式下限制转矩
HCU_GCU_Demand_Limit_HighTorque_Pos_Value";
CM_ SG_ 291 HCU6_PreFeedback_Torque "HCU转速环前馈预留
HCU PreFeedback Torque";
CM_ SG_ 291 HCU6_Limit_HighSpeed_Pos_Value "HCU请求限制，转矩模式下限制转速
HCU_GCU_Demand_Limit_HighSpeed_Pos_Value";
CM_ SG_ 291 HCU6_PresentFaultCode_cycling "HCU当前活动故障码";
CM_ SG_ 291 HCU6_Limit_LowTorque_Value "GCU minimal torque limitation";
CM_ SG_ 384 HCU5_EnginIdingIdleSetFeedback "燃油检测模式反馈";
CM_ SG_ 384 HCU5_fueltankparkingunlock "请驻车熄火解锁加油门";
CM_ SG_ 384 HCU5_Decompressionfail "泄压失败";
CM_ SG_ 384 HCU5_serviceLampRequest "HCU请求仪表发动机保养维修灯点亮";
CM_ SG_ 384 HCU5_fueltankunLockrequest "油箱门锁解锁请求";
CM_ SG_ 384 HCU5_CoolantFillingSta "PDCS冷却液加注状态反馈";
CM_ SG_ 384 HCU5_PureFuelResMilage "燃油剩余里程";
CM_ SG_ 384 HCU5_s_WaitTiExitRefu "即将退出加油请求等待时间";
CM_ SG_ 384 HCU5_flag_CapUncls "行车过程中加油口盖未关闭";
CM_ SG_ 384 HCU5_flg_EngWtrOvrTemp "发动机水温过高报警";
CM_ SG_ 384 HCU5_TWV3_CWFlg "Three way valve 3 open rotation flag";
CM_ SG_ 384 HCU5_TWV3_CCWFlg "Three way valve 3 close rotation flag";
CM_ SG_ 384 HCU5_TWV3_motorSta "Three way valve 3 motor state";
CM_ SG_ 384 HCU5_TWV3_RespError "三通阀3LIN响应错误";
CM_ SG_ 384 HCU5_TWV3_OvervoltageFlt "三通阀3过压故障";
CM_ SG_ 384 HCU5_TWV3_RealSta "Three way valve 3 actual postion";
CM_ SG_ 384 HCU5_TWV3_OverCurrent "三通阀3过流故障";
CM_ SG_ 384 HCU5_TWV3_OverTempFlt "三通阀3过温故障";
CM_ SG_ 384 HCU5_TWV3_UndervoltageFlt "三通阀3欠压故障";
CM_ SG_ 384 HCU5_TWV2_CWFlg "Three way valve 2 open rotation flag";
CM_ SG_ 384 HCU5_TWV2_CCWFlg "Three way valve 2 close rotation flag";
CM_ SG_ 384 HCU5_TWV2_motorSta "Three way valve 2 motor state";
CM_ SG_ 384 HCU5_TWV2_RespError "三通阀2LIN响应错误";
CM_ SG_ 384 HCU5_TWV2_OvervoltageFlt "三通阀2过压故障";
CM_ SG_ 384 HCU5_TWV2_OverCurrent "三通阀2过流故障";
CM_ SG_ 384 HCU5_TWV2_OverTempFlt "三通阀2过温故障";
CM_ SG_ 384 HCU5_TWV2_UndervoltageFlt "三通阀2欠压故障";
CM_ SG_ 384 HCU5_WtrMotOutTempValid "增程系统电驱水温有效性";
CM_ SG_ 384 HCU5_OilFillCapLockremind "加油大屏显示";
CM_ SG_ 384 HCU5_RexMode "Actual REX Mode activated";
CM_ SG_ 384 HCU5_Ctl_PWM_Fan1_BackDiag "feedback PWM of fan 1";
CM_ SG_ 384 HCU5_Ctl_PWM_Wtpump1_BackDiag "feedback PWM of water pump 1";
CM_ SG_ 384 HCU5_Ctl_PWM_Wtpump3_BackDiag "feedback PWM of water pump 3";
CM_ SG_ 384 HCU5_TWV2_RealSta "Three way valve 2 actual postion";
CM_ SG_ 384 HCU5_T_EdCoolant "E-drive circuit water temperature";
CM_ SG_ 384 HCU5_ForcechargingLevelSetFeedBack "强制充电档位设置反馈";
CM_ SG_ 384 HCU5_PREMDisplayReminder "PREM功能选择提示";
CM_ SG_ 384 HCU5_REXchargSts "强制充电设置反馈";
CM_ SG_ 384 HCU5_MileagePREMExtended "PREM功能预测的当前延长行驶里程";
CM_ SG_ 384 HCU5_WtrMotOutTemp "增程系统电驱水温";
CM_ SG_ 531 HCU3_EngStrtForStaleFu "HMI reminder at engine start for engine self-mantinaince";
CM_ SG_ 531 HCU3_VCMActv "HMI reminder at VCM active";
CM_ SG_ 531 HCU3_SportmodAvailableDisp "HMI reminder for Sport mode";
CM_ SG_ 531 HCU3_RexSysError "SVS Lamp request";
CM_ SG_ 531 HCU3_RexModeAvalidreminder "HMI reminder for REX mode";
CM_ SG_ 531 HCU3_MileagePremTolSav "total saved  mileage  PREM active for HMI display
PREM模式下累计增加续航";
CM_ SG_ 531 HCU3_DayPremActv "total day PREM active for HMI display";
CM_ SG_ 531 HCU3_FuelConsumptionLongTrip "total average fuel consumpiton";
CM_ SG_ 531 HCU3_REXStartFail "增程器起动失败HMI提示";
CM_ SG_ 531 HCU3_PowerGradREX2MCU "能量流显示REX与MCU之间功率等级";
CM_ SG_ 531 HCU3_EnergyFlowSts "能量流显示状态";
CM_ SG_ 531 HCU3_FuelSavePremLongTrip "total fuel saving from PREM";
CM_ SG_ 531 HCU3_PowerGradMCU2Batt "能量流显示MCU与BATT之间功率等级";
CM_ SG_ 531 HCU3_PowerGradREX2Batt "能量流显示REX与BATT之间功率等级";
CM_ SG_ 531 HCU3_FuelSavePremShortTrip "fuel saving from PREM at current trip";
CM_ SG_ 531 HCU3_EVModAvailableDisp "纯电模式CDCS交互信号用于低电量报警文字提示";
CM_ SG_ 531 HCU3_MotorDrive_Satis "车辆驱动回收状态";
CM_ SG_ 531 HCU3_FuelConsumptionShortTrip "average fuel consumpiton at current trip";
CM_ SG_ 531 HCU3_FuelLevelEstimated "估算燃油液位信号";
CM_ SG_ 531 HCU3_StRngextModeAct "增程模式内部解析信号";
CM_ SG_ 531 HCU3_HCUSoftVersion "HCU软件版本号";
CM_ SG_ 531 HCU3_FTMSt "加油控制状态信号";
CM_ SG_ 531 HCU3_REXreadyforsleep "增程系统允许休眠信号标志信号";
CM_ SG_ 531 HCU3_RexShutdownRdy "增程系统允许关管信号标志信号";
CM_ SG_ 531 HCU3_flg_RexZeroPower "增程系统零功率标志信号";
CM_ SG_ 531 HCU3_GenInstEnergyConsum "发电机短时能量消耗";
CM_ SG_ 854 HCU7_perc_EngOilHealth "增程器智能保养机油健康指数";
CM_ SG_ 854 HCU7_m_MnResdMilgKm "增程器智能保养机油剩余保养里程";
CM_ SG_ 854 HCU7_ti_MnResTiDay "增程器智能保养机油剩余保养时间";
CM_ SG_ 854 HCU7_ti_AftMnFrznTimYear "增程器智能保养当前保养时间年";
CM_ SG_ 854 HCU7_ti_AftMnFrznTimMonth "增程器智能保养当前保养时间月";
CM_ SG_ 854 HCU7_kwhpL_PwrGenFu2Elec "增程器油电转换效率";
CM_ SG_ 854 HCU7_ti_AftMnFrznTimDay "增程器智能保养当前保养时间天";
CM_ SG_ 854 HCU7_StEngDynTranReq "增程器动态行为状态";
CM_ SG_ 854 HCU7_ti_EE1EngIdleTimHr "增程器保养后怠速累计时间";
CM_ SG_ 854 HCU7_m_EE1EngEquivRunMilgKm "增程器保养后等效运行里程累计";
CM_ SG_ 854 HCU7_u_EE1HourOfDayLck "增程器保养时间小时";
CM_ SG_ 854 HCU7_ti_EE1EngRunTimHr "增程器工作时间累计";
CM_ SG_ 854 HCU7_NrTolEngStartReq "发动机累计启机次数";
CM_ SG_ 854 HCU7_NrTolEngStartFail "发动机累计启机失败次数";
CM_ SG_ 854 HCU7_stEngStopTran "停机过程状态";
CM_ SG_ 854 HCU7_stEngStrtTran "启机过程状态";
CM_ SG_ 854 HCU7_Hr_EngRunningTime "发动机累计工作时间";
CM_ SG_ 854 HCU7_kw_PwrEngDynMaxLim "增程器发电功率限值";
CM_ SG_ 854 HCU7_kw_PwrRngextReq "增程器请求发电功率";
CM_ SG_ 854 HCU7_AcvPwrReqStgy "增程器发电类型";
CM_ SG_ 854 HCU7_StRngextSys "上下电状态判定";
CM_ SG_ 854 HCU7_fac_PREMValEquiv "PrEM功能激活后的等效燃油系数";
CM_ SG_ 854 HCU7_L_WhlDrvLifeFuCns "历史总耗油量";
CM_ SG_ 854 HCU7_kwh_WhlDrvLifeGenEgy "增程器历史总发电量";
CM_ SG_ 854 HCU7_kwhpkm_VehEgyCns "单位里程整车用电量";
CM_ SG_ 854 HCU7_Lp100km_FuCnsNormEV "Normal EV模式下油耗值";
CM_ SG_ 854 HCU7_kwhp100km_ECnsNormEV "Normal EV模式下电耗值";
CM_ SG_ 854 HCU7_kwhpL_FacFuToElecNormEV "Normal EV模式下油转点系数";
CM_ SG_ 854 HCU7_pct_EffRexSysNormEV "Normal EV模式下增程系统效率";
CM_ SG_ 854 HCU7_Lp100km_FuCnsNormFHEV "Normal FHEV模式下油耗值";
CM_ SG_ 854 HCU7_kwhp100km_ECnsNormFHEV "Normal FHEV模式下电耗值";
CM_ SG_ 854 HCU7_kwhpL_FacFuToElecNormFHEV "Normal FHEV模式下油转点系数";
CM_ SG_ 854 HCU7_pct_EffRexSysNormFHEV "Normal FHEV模式下增程系统效率";
CM_ SG_ 854 HCU7_Lp100km_FuCnsNormPREM "Normal PREM模式下油耗值";
CM_ SG_ 854 HCU7_kwhp100km_ECnsNormPREM "Normal PREM模式下电耗值";
CM_ SG_ 854 HCU7_kwhpL_FacFuToElecNormPREM "Normal PREM模式下油转点系数";
CM_ SG_ 854 HCU7_pct_EffRexSysNormPREM "Normal PREM模式下增程系统效率";
CM_ SG_ 854 HCU7_Lp100km_FuCnsECOEV "ECO EV模式下油耗值";
CM_ SG_ 854 HCU7_kwhp100km_ECnsECOEV "ECO EV模式下电耗值";
CM_ SG_ 854 HCU7_kwhpL_FacFuToElecECOEV "ECO EV模式下油转点系数";
CM_ SG_ 854 HCU7_pct_EffRexSysECOEV "ECO EV模式下增程系统效率";
CM_ SG_ 854 HCU7_Lp100km_FuCnsECOFHEV "ECO FHEV模式下油耗值";
CM_ SG_ 854 HCU7_kwhp100km_ECnsECOFHEV "ECO FHEV模式下电耗值";
CM_ SG_ 854 HCU7_kwhpL_FacFuToElecECOFHEV "ECO FHEV模式下油转点系数";
CM_ SG_ 854 HCU7_pct_EffRexSysECOFHEV "ECO FHEV模式下增程系统效率";
CM_ SG_ 854 HCU7_Lp100km_FuCnsECOPREM "ECO PREM模式下油耗值";
CM_ SG_ 854 HCU7_kwhp100km_ECnsECOPREM "ECO PREM模式下电耗值";
CM_ SG_ 854 HCU7_kwhpL_FacFuToElecECOPREM "ECO PREM模式下油转点系数";
CM_ SG_ 854 HCU7_pct_EffRexSysECOPREM "ECO PREM模式下增程系统效率";
CM_ SG_ 854 HCU7_Lp100km_FuCnsSpt "运动模式下油耗值";
CM_ SG_ 856 HCU8_kwhpL_FacFuToElecSpt "运动模式下油转点系数";
CM_ SG_ 856 HCU8_pct_EffRexSysSpt "运动模式下增程系统效率";
CM_ SG_ 856 HCU8_Lp100km_FuCnsTot "综合模式下油耗值";
CM_ SG_ 856 HCU8_kwhp100km_ECnsTot "综合模式下电耗值";
CM_ SG_ 856 HCU8_kwhpL_FacFuToElecTot "综合模式下油转点系数";
CM_ SG_ 856 HCU8_pct_EffRexSysTot "综合模式下增程系统效率";
CM_ SG_ 856 HCU8_kwhp100km_ECnsSpt "运动模式下电耗值";
CM_ SG_ 856 HCU8_VolRemainingFuel "估算剩余燃油值";
CM_ SG_ 856 HCU8_bAcvFuLeak "油箱燃油漏油标志";
CM_ SG_ 856 HCU8_FuelLevelEstimated "估算燃油液位信号";
CM_ SG_ 856 HCU8_bAcvRefu "加油标志";
CM_ SG_ 856 HCU8_StInhbtEngStopReason "禁止停机原因:
bit0:增程模式
bit1:驾驶模式
bit2:最小运行时间
bit3:EMS请求
bit4:发动机水温
bit5:催化剂加热
bit6:功率维度
bit7:SOC维度
bit8:电池母线电压低
bit9:固定点发电
bit10:VCM工况
bit11:故障模式";
CM_ SG_ 856 HCU8_StInhbtEngStartReason "禁止启机原因:
bit0:EMS请求
bit1:上下电状态
bit2:DCDC状态
bit3:燃油液位低
bit4:连续3次以上启机失败
bit5:OTA
bit6:EMS故障
bit7:GCU故障
bit8:处于加油过程
bit9:插枪充电
bit10:故障模式
bit11:燃油用尽
bit12:展车模式
bit13:主驾座位信号
bit14: UDS
bit15: RexMode";
CM_ SG_ 856 HCU8_Lp100km_FuCnsHEV "增程电耗模式下油耗值";
CM_ SG_ 856 HCU8_kwhp100km_ECnsHEV "增程电耗模式下电耗值";
CM_ SG_ 856 HCU8_kwhpL_FacFuToElecHEV "增程电耗模式下油转电系数";
CM_ SG_ 856 HCU8_pct_EffRexSysHEV "增程电耗模式下增程系统效率";
CM_ SG_ 856 HCU8_EngStartReason "启机原因:
bit0: REXMODE
bit1: VehicleSpeed
bit2: DrvMode
bit3: EMS
bit4: Coolanttemp
bit5: PwrReq
bit6: BattSOC
bit7: BattVolt
bit8: RemoteStart
bit9: VCM
bit10: UDS
bit11: StaleFuel
bit12: PREM";
CM_ SG_ 856 HCU8_EngStopReason "停机原因:
bit0: PwrReq
bit1: RexMod
bit2: DrvMode
bit3: Engine
bit4: Engine FCO
bit5: RngExtSys
bit6: BattSOC
bit7: EMSError
bit8: GCUERROR
bit9: Refuel
bit10: Charge
bit11: UDS
bit12: Fuel Runout
bit13: PREM
bit14: FIM
bit15:DrvrSeat
bit16: Stational Mode
bit17: GCUstErr";
CM_ SG_ 856 HCU8_m_RexWorkingTolMilgKm "REX total working mileage for HMI display
增程器工作时行驶总里程";
CM_ SG_ 200 VCU1_Torque_Command "扭矩请求命令";
CM_ SG_ 200 VCU1_Speed_Command "速度请求命令";
CM_ SG_ 200 VCU1_MCUEnable "电机使能信号";
CM_ SG_ 200 VCU1_Mode_Command "电机模式请求";
CM_ SG_ 200 VCU1_PMM_TmOuSt "上下电超时原因";
CM_ SG_ 200 VCU1_PMM_PwrUpSt "高压上电状态";
CM_ SG_ 200 VCU1_HvEmgy_status "紧急下电请求状态";
CM_ SG_ 200 VCU1_MCUShakeRedn "VCU请求MCU开启\关闭防抖";
CM_ SG_ 200 VCU1_VCMModeReq "VCM模式请求";
CM_ SG_ 200 VCU1_VCMPwrDwnCmd "VCM下电指令";
CM_ SG_ 200 VCU1_AliveCounter "E2E Profile2-CRC8H2F，Counter:0-15";
CM_ SG_ 200 VCU1_PMM_PwrDwnSt "高压下电状态";
CM_ SG_ 200 VCU_OBDMilLightReq "VCU请求EMS点MIL灯";
CM_ SG_ 200 VCU1_Checksum "E2E Profile2-CRC8H2F
DataID List:#32 - 242 165 194 90 167 136 69 119 173 80 76 95 67 239 144 234";
CM_ SG_ 200 VCU1_FMCUTorque_Command "前电机扭矩请求命令";
CM_ SG_ 200 VCU1_FMCUSpeed_Command "前电机速度请求命令";
CM_ SG_ 200 VCU1_DisBatt2PMM "禁止上高压标志位";
CM_ SG_ 200 VCU1_FMCUEnable "前电机电机使能信号";
CM_ SG_ 200 VCU1_FMCUMode_Command "前电机电机模式请求";
CM_ SG_ 200 VCU1_RexVCMProcess "VCM模式进入状态";
CM_ SG_ 200 VCU1_AppWrkSts "App工作状态";
CM_ SG_ 200 VCU1_FMCUHvEmgy_status "前电机紧急下电请求状态";
CM_ SG_ 200 VCU1_FMCUShakeRedn "VCU请求FMCU开启\关闭防抖";
CM_ SG_ 200 VCU1_BTVSleepRdyFlg "内部休眠请求标志位";
CM_ SG_ 200 VCU1_HvPwrUpTmOutFlg "高压上电超时标志位";
CM_ SG_ 227 VCU5_ActGear "Strategy gear (VCU)";
CM_ SG_ 227 VCU5_ActGearValid "Strategy gear valid (VCU)";
CM_ SG_ 227 VCU5_READYLightSts "运动准备就绪指示灯";
CM_ SG_ 227 VCU5_HVIL_Attach "高压附件环路互锁信号状态";
CM_ SG_ 227 VCU5_PwrTrainFailureLevel "动力系统故障等级";
CM_ SG_ 227 VCU5_HVIL_MajorLoop "主回路高压互锁信号状态";
CM_ SG_ 227 VCU5_RangeModeFb "续航里程显示方式反馈";
CM_ SG_ 227 VCU5_HVReady "高压准备就绪";
CM_ SG_ 227 VCU5_HubMode "转毂模式";
CM_ SG_ 227 VCU5_StartOffFlagReq "要求PEPS断开StartRelay";
CM_ SG_ 227 VCU5_EmuEngineSts "模拟（仿真emulated）的引擎状态，用于start控制逻辑。";
CM_ SG_ 227 VCU5_AccelPositionValid "加速踏板行程有效位";
CM_ SG_ 227 VCU5_GearRatio "速比";
CM_ SG_ 227 VCU5_AccelPosition "加速踏板行程";
CM_ SG_ 227 VCU5_LBatt_Voltage "小电池电压";
CM_ SG_ 227 VCU5_AliveCounter "E2E Profile2-CRC8H2F，Counter:0-15";
CM_ SG_ 227 VCU5_DriveMode_fb "驾驶模式反馈(VCU)";
CM_ SG_ 227 VCU5_DriverOvertakeMode "驾驶员超越模式";
CM_ SG_ 227 VCU5_Checksum "E2E Profile2-CRC8H2F
DataID List:#16 - 149 178 48 27 29 185 17 203 148 68 204 36 101 195 44 16";
CM_ SG_ 242 VCU2_Fault_Level "VCU环路互锁信号故障等级";
CM_ SG_ 242 VCU2_ControlHVDischarge "VCU控制放电回路";
CM_ SG_ 242 VCU2_IntegHVIL "高压互锁信号集成状态（BMS、MCU、VCU，用于国标报警）";
CM_ SG_ 242 VCU2_DCDC_Enabled "DCDC使能信号";
CM_ SG_ 242 VCU2_ChrgEnable "VCU允许充电";
CM_ SG_ 242 VCU2_HV_LoadRTPwr "高压负载实时功率";
CM_ SG_ 242 VCU2_DCDC_PowerLimit "DCDC功率限制";
CM_ SG_ 242 VCU2_12VBatteryChargeState "智能补电状态";
CM_ SG_ 242 VCU2_FastChgCCConnect "Fast Charge(DC Charge) CC Connect Validity";
CM_ SG_ 242 VCU2_FastChgWkVaild "Fast Charge(DC Charge) Wake Validity";
CM_ SG_ 242 VCU2_DCDC_Output_Vol_Com "DCDC输出电压值指令";
CM_ SG_ 242 VCU2_AliveCounter "E2E Profile2-CRC8H2F，Counter:0-15";
CM_ SG_ 242 VCU2_12VBatChrgeReqCmd "智能补电请求指令";
CM_ SG_ 242 VCU2_FastChgCCConnectBrkPE "PE状态";
CM_ SG_ 242 VCU2_Checksum "E2E Profile2-CRC8H2F
DataID List:#74 - 9 47 115 37 72 101 75 248 69 251 51 50 208 228 15 236";
CM_ SG_ 251 VCU6_StopModeFb "停车模式状态反馈";
CM_ SG_ 251 VCU6_MotorDrvMode "纵向(Longitudinal)驾驶响应模式，自动/手动";
CM_ SG_ 251 VCU6_PMM_SysSt "上下电状态";
CM_ SG_ 251 VCU6_Lock_Status "落锁状态(换电项目新增专用)";
CM_ SG_ 251 VCU6_BrakeSts "制动踏板信号";
CM_ SG_ 251 VCU6_BrakeStsValid "制动踏板信号有效位";
CM_ SG_ 251 VCU6_DispGearFltRemind "显示档位故障提醒";
CM_ SG_ 251 VCU6_ParkCtrlOvrTime "驻车超时报警信号";
CM_ SG_ 251 VCU6_EPBBackupCtrlAail "PDCS备份驻车功能有效性信号";
CM_ SG_ 251 VCU6_EnergyRecLevelSts "能量回收等级强度反馈";
CM_ SG_ 251 VCU6_SystemWarnLightSts "系统报警灯（黄色降功率）";
CM_ SG_ 251 VCU6_RegenFlg "能量回收点亮制动灯";
CM_ SG_ 251 VCU6_ResidualOdometer "续航里程";
CM_ SG_ 251 VCU6_PNLelFault "PN档位故障";
CM_ SG_ 251 VCU6_SOCWarningLightSts "电量低报警灯";
CM_ SG_ 251 VCU6_12VBatChargeFaultSts "12V蓄电池充放电故障灯";
CM_ SG_ 251 VCU6_SystemFaultWarn_Light "系统故障灯";
CM_ SG_ 251 VCU6_AuthStatus "VCU和PEPS间的防盗认证结果。";
CM_ SG_ 251 VCU6_onepedal_WorkSts "One Pedal工作状态指示（入门版用）";
CM_ SG_ 251 VCU6_GearShftRmn "换挡提示(仪表接收到NoRmn不提醒，其他以文字提醒，文字显示最长持续5S，满足熄灭条件停止显示)";
CM_ SG_ 251 VCU6_DiagThmStsFltLvl "VCU诊断热管理系统故障等级";
CM_ SG_ 251 VCU6_RpBatt_Sts "换电提示信号状态";
CM_ SG_ 251 VCU6_AliveCounter "E2E Profile2-CRC8H2F，Counter:0-15";
CM_ SG_ 251 VCU6_ReadyLost_CheckFlt "Ready已丢失，请检查故障(文字提示)";
CM_ SG_ 251 VCU6_GearFlt_CheckGear "档位故障，请检查换挡器(文字提示)";
CM_ SG_ 251 VCU6_ChargeConnKpTempSw_Fb "插枪保温开启/关闭开关";
CM_ SG_ 251 VCU6_Checksum "E2E Profile2-CRC8H2F
DataID List:#33 - 37 248 50 236 79 83 180 196 249 48 4 88 62 134 99 246";
CM_ SG_ 251 VCU6_StrtgyGear "档位控制功能需求";
CM_ SG_ 251 VCU6_DispGear "档位控制功能需求";
CM_ SG_ 251 VCU6_PGearFlt "P档故障信号";
CM_ SG_ 251 VCU6_TracModeEPBRelsReq "PDCS牵引模式请求EPB释放";
CM_ SG_ 251 VCU6_PumpMWorkSts "电驱水泵工作状态反馈";
CM_ SG_ 251 VCU6_PumpMReq "电驱水泵目标占空比";
CM_ SG_ 251 VCU6_AccelPositionD "绝对加速踏板行程D";
CM_ SG_ 251 VCU6_AccelPositionE "绝对加速踏板行程E";
CM_ SG_ 251 VCU6_EnergyRecyleWarn "能量回收不足提醒";
CM_ SG_ 251 VCU6_FltRollgNum "PDCS故障码代号";
CM_ SG_ 252 VCU7_DrvWheelTorqueReq "驾驶员需求轮端扭矩,前进为正，后退为负，能量回收为负";
CM_ SG_ 252 VCU7_MaxMotPosTq "1、基于电池可用放电功率计算的电机前向允许驱动扭矩；
2、MCU执行扭矩+MCU内部防抖扭矩之和不允许超出此上限";
CM_ SG_ 252 VCU7_MaxMotGenTq "1、基于电池可用放电功率和回充功率计算的电机允许倒车扭矩和回充扭矩，MCU内部取反处理；
2、MCU执行扭矩+MCU内部防抖扭矩之和不允许超出此上限";
CM_ SG_ 252 VCU7_Fr07_AliveCounter "E2E Profile2-CRC8H2F，Counter:0-15";
CM_ SG_ 252 VCU7_FrntAxleWhlTqDemValid "前轴驾驶员需求扭矩（轮端）";
CM_ SG_ 252 VCU7_ReAxleWhlTqDemValid "后轴驾驶员需求扭矩（轮端）";
CM_ SG_ 252 VCU7_Fr07_Checksum "DataID List:#31 - 107 116 215 111 150 102 246 7 91 151 240 244 28 35 139 81";
CM_ SG_ 252 VCU7_FrntAxleWhlTqDem "前轴驾驶员需求扭矩（轮端）";
CM_ SG_ 252 VCU7_MaxFMotPosTq "1、基于电池可用放电功率计算的电机前向允许驱动扭矩；
2、FMCU执行扭矩+FMCU内部防抖扭矩之和不允许超出此上限";
CM_ SG_ 252 VCU7_MaxFMotGenTq "1、基于电池可用放电功率和回充功率计算的电机允许倒车扭矩和回充扭矩，FMCU内部取反处理；
2、FMCU执行扭矩+MCU内部防抖扭矩之和不允许超出此上限";
CM_ SG_ 252 VCU7_ReAxleWhlTqDem "后轴驾驶员需求扭矩（轮端）";
CM_ SG_ 252 VCU7_FrntMotDrvTqWhlLim "前轴电机最大可用驱动扭矩（轮端）";
CM_ SG_ 252 VCU7_FrntMotRgnTqWhlLim "前轴电机最大可用电回馈扭矩（轮端）";
CM_ SG_ 252 VCU7_ReMotDrvTqWhlLim "后轴电机最大可用驱动扭矩（轮端）";
CM_ SG_ 252 VCU7_ReMotRgnTqWhlLim "后轴电机最大可用电回馈扭矩（轮端）";
CM_ SG_ 252 VCU7_FrntAxleWhlTqCommd "前轴驱动电机扭矩指令（轮边）";
CM_ SG_ 252 VCU7_ReAxleWhlTqCommd "后轴驱动电机扭矩指令（轮边）";
CM_ SG_ 252 VCU7_FrntMotDrvTqWhlLimValid "前轴电机最大可用驱动扭矩（轮端）有效性";
CM_ SG_ 252 VCU7_FrntMotRgnTqWhlLimValid "前轴电机最大可用电回馈扭矩（轮端）有效性";
CM_ SG_ 252 VCU7_ReMotDrvTqWhlLimValid "后轴电机最大可用驱动扭矩（轮端）有效性";
CM_ SG_ 252 VCU7_ReMotRgnTqWhlLimValid "后轴电机最大可用电回馈扭矩（轮端）有效性";
CM_ SG_ 553 VCU9_ChgConKpcontinued "保温间隔反馈";
CM_ SG_ 553 VCU9_V2L_Enable "V2L使能";
CM_ SG_ 553 VCU9_SlowChgWkVaild "Slow Charge(AC Charge) Wake Validity";
CM_ SG_ 553 VCU9_CoolantFillingSta "冷却液加注模式";
CM_ SG_ 553 VCU9_BattHeatApt_Fb "电池保温启动状态";
CM_ SG_ 553 VCU9_V2L_PowLim "V2L功率限制";
CM_ SG_ 553 VCU9_GasPedalVolNo1 "第一路加速踏板信号电压";
CM_ SG_ 553 VCU9_GasPedalVolNo2 "第二路加速踏板信号电压";
CM_ SG_ 553 VCU9_PosFastChgPort_Temp_Vaild "快充口正端温度有效位";
CM_ SG_ 553 VCU9_NegFastChgPort_Temp_Vaild "快充口负端温度有效位";
CM_ SG_ 553 VCU9_BattHeat_Info "电池保温信息提示";
CM_ SG_ 553 VCU9_NegFastChgPort_Temp "快充口负端温度";
CM_ SG_ 553 VCU9_PosFastChgPort_Temp "快充口正端温度";
CM_ SG_ 724 VCU4_BattWtrInTReq "VCU请求电池的目标入水口温度";
CM_ SG_ 724 VCU4_CLM_PoweLimitedSts "空调功率限制状态（原因）";
CM_ SG_ 724 VCU4_VINEolUnImplnt "车辆VIN码未录入";
CM_ SG_ 724 VCU4_ChgWake "充电唤醒信号(BMS HardWire)";
CM_ SG_ 724 VCU4_VINImps "VIN码录入不合理";
CM_ SG_ 724 VCU4_CLM_PTCPumpFailCode "PTC水泵故障反馈";
CM_ SG_ 724 VCU4_CLM_FanFailCode "冷却风扇故障反馈";
CM_ SG_ 724 VCU4_CCS_Status "定速巡航状态";
CM_ SG_ 724 VCU4_CCS_target_Speed "巡航目标车速";
CM_ SG_ 724 VCU4_CLM_PTCWorkSts "PTC水泵工作状态反馈";
CM_ SG_ 724 VCU4_CLM_FanGearSts "冷却风扇高低档状态";
CM_ SG_ 724 VCU4_CLM_PowerPermittedV "空调允许功率值有效性";
CM_ SG_ 724 VCU4_CLM_PowerPermitted "空调允许功率值";
CM_ SG_ 724 VCU4_BattHeatLvl "VCU请求电池热管理的加热等级";
CM_ SG_ 724 VCU4_ChgConKpTemp "VCU插枪保温请求";
CM_ SG_ 724 VCU4_BattCoolLvl "VCU请求电池热管理的制冷等级";
CM_ SG_ 724 VCU4_LearnSts "VCU学习状态";
CM_ SG_ 724 VCU4_BattPmpSpdReq "VCU请求BMS控制电池回路水泵的转速";
CM_ SG_ 724 VCU4_LeftExtFanSpd "室外左风扇转速";
CM_ SG_ 724 VCU4_LeftExtFanFlt "室外左风扇故障状态";
CM_ SG_ 724 VCU4_RightExtFanSpd "室外右风扇转速";
CM_ SG_ 724 VCU4_RightExtFanFlt "室外右风扇故障状态";
CM_ SG_ 724 VCU4_PumpHReq "PTC水泵目标占空比";
CM_ SG_ 724 VCU4_TWV2Req "三通阀2开度控制指令";
CM_ SG_ 724 VCU4_TWV3Req "三通阀3开度控制指令";
CM_ SG_ 724 VCU4_TWV4Req "三通阀4开度控制指令";
CM_ SG_ 724 VCU4_FWVReq "四通阀开度控制指令";
CM_ SG_ 724 VCU4_AGSPositionActSts "AGS实际开度";
CM_ SG_ 724 VCU4_MotlnpWtrT "电机入水口温度传感器温度反馈";
CM_ SG_ 724 VCU4_CCSetFail_Indication "定速巡航激活失败提示";
CM_ SG_ 724 VCU4_BattInstEnergyCosum "短时电量消耗";
CM_ SG_ 724 VCU4_DrivingPowerPercentage "驱动功率百分比";
CM_ SG_ 724 VCU4_BattPmpWorkSts "电池水泵工作状态";
CM_ SG_ 724 VCU4_DrivingPower "驱动功率实时值";
CM_ SG_ 809 VCU10_Odometer "VCU发送总里程信息";
CM_ SG_ 809 VCU10_MotCircWtrPumWrkSts "电机回路水泵工作状态";
CM_ SG_ 809 VCU10_IBS_ERROR_Commom "转发IBS传感器通讯错误信号";
CM_ SG_ 809 VCU10_SOC_LOW "转发IBS传感器SOC信号";
CM_ SG_ 809 VCU10_GasPedalFault "加速踏板信号故障";
CM_ SG_ 809 VCU10_GasPedaExcessAmplitude "加速踏板信号超幅错误";
CM_ SG_ 809 VCU10_BMSCommFault "BMS通信故障";
CM_ SG_ 809 VCU10_VehRunning_Status "车辆运行状态";
CM_ SG_ 809 VCU10_Channel1_speed "通道1流速";
CM_ SG_ 809 VCU10_MotorDrive_Status "驱动/回收状态";
CM_ SG_ 809 VCU10_Channel2_speed "通道2流速";
CM_ SG_ 809 VCU10_Energy_total "总能耗";
CM_ SG_ 809 VCU10_Energy_drv "行驶能耗";
CM_ SG_ 809 VCU10_Energy_ac "空调能耗";
CM_ SG_ 809 VCU10_Energy_elc "其他能耗";
CM_ SG_ 809 VCU10_Energy_rep "回收能量";
CM_ SG_ 809 VCU10_Energy_wid "风阻能耗";
CM_ SG_ 809 VCU10_Energy_Average "平均能耗";
CM_ SG_ 152 VCU13_TotalMotRgnTqWhlLim "基于动力电池可用功率，计算的可用于前/后电机进行能量回收（电制动）的总扭矩";
CM_ SG_ 152 VCU13_TotalMotDrvTqWhlLim "基于动力电池可用功率，计算的可用于前/后电机进行驱动的总扭矩";
CM_ SG_ 152 VCU13_ReMotRgnTqWhlDesgn "后电机能量回收（电制动）的扭矩目标值";
CM_ SG_ 152 VCU13_Fr0D_rollingcounter "E2E Profile2-CRC8H2F，Counter:0-15";
CM_ SG_ 152 VCU13_TotalMotRgnTqWhlLimValid "能量回收（电制动）的总扭矩有效性";
CM_ SG_ 152 VCU13_TotalMotDrvTqWhlLimValid "驱动的总扭矩有效性";
CM_ SG_ 152 VCU13_ReMotRgnTqWhlDesgnValid "后电机能量回收（电制动）的扭矩目标值有效性";
CM_ SG_ 152 VCU13_FrntMotRgnTqWhlDesgnValid "前电机能量回收（电制动）的扭矩目标值有效性";
CM_ SG_ 152 VCU13_Fr0D_Checksum "E2E Profile2-CRC8H2F
DataID List:#27 - 114 177 90 184 43 119 50 223 95 237 29 234 232 83 63 215";
CM_ SG_ 152 VCU13_FrntMotRgnTqWhlDesgn "前电机能量回收（电制动）的扭矩目标值";
CM_ SG_ 264 VCU14_PAAvailable "VCU是否满足APA控制要求";
CM_ SG_ 264 VCU14_Sys_Ready "VCU系统状态正常运行。Ready后ADAS应开始监测CAN报文和输入电压。";
CM_ SG_ 264 VCU14_ACC_Ready "VCU的ACC功能准备就绪，可以响应ACC扭矩请求";
CM_ SG_ 264 VCU14_PAActive "VCU反馈握手请求";
CM_ SG_ 264 VCU14_AntiSlipWarning "防溜坡信息提醒";
CM_ SG_ 264 VCU14_AntiSlipAVHActvReq "防溜坡激活AVH请求";
CM_ SG_ 264 VCU14_PA_ParkingFnMd "VCU反馈当前泊车功能模式";
CM_ SG_ 264 VCU14_ACC_Active "自适应巡航激活标志位";
CM_ SG_ 264 VCU14_PA_FailCode "VCU反馈VCU fail的原因";
CM_ SG_ 264 VCU14_Gear_PAActive "Gear反馈握手请求";
CM_ SG_ 264 VCU14_Gear_PAAvailable "Gear是否满足APA控制状态";
CM_ SG_ 264 VCU14_Gear_ErrorSts_M01 "系统故障信号";
CM_ SG_ 264 VCU4_PA_DeceltorSts "VCU是否支持负扭矩";
CM_ SG_ 264 VCU4_PA_TargetTrqValueValidity "VCU接收到PA目标扭力值有效位";
CM_ SG_ 264 VCU14_Gear_PACtrlAbortFeedback "Gear系统APA功能退出原因";
CM_ SG_ 264 VCU4_PA_TargetTrqValue "VCU接收到PA目标扭力值[-400,400]Nm";
CM_ SG_ 264 VCU14_Fr0E_MsgCounter "E2E Profile2-CRC8H2F，Counter:0-15";
CM_ SG_ 264 VCU14_BMSSOCLowWarn "SOC低提醒";
CM_ SG_ 264 VCU14_Fr0E_Checksum "E2E Profile2-CRC8H2F
DataID List:#28 - 148 221 7 229 19 81 190 49 200 67 41 82 170 169 230 197";
CM_ SG_ 739 VCU3_AGS_PositionSts "进气格栅角度状态";
CM_ SG_ 739 VCU3_EPBBackupCtrlActv "PDCS接管EPB控制状态";
CM_ SG_ 739 VCU3_TractionModeFailureReason "牵引模式激活失败原因";
CM_ SG_ 739 VCU3_TractionMode "牵引模式激活";
CM_ SG_ 739 VCU3_EPBBackupCtrlSts "EPB备份控制状态";
CM_ SG_ 739 VCU3_presentActivityFault "当前活动最严重错误号";
CM_ SG_ 739 VCU3_BattInstPowerConsum "纯电瞬时能耗";
CM_ SG_ 739 VCU3_AliveCounter "E2E Profile2-CRC8H2F，Counter:0-15";
CM_ SG_ 739 VCU3_Checksum "E2E Profile2-CRC8H2F
DataID List:#78 - 123 97 3 75 138 23 158 228 220 120 119 11 5 161 145 180";
CM_ SG_ 1073 PDCS2_IBS_I_RANGE "电池电流值范围(转发自PDCSLIN1的0x34报文对应信号)";
CM_ SG_ 1073 PDCS2_IBS_U_BATT "电池电压值(转发自PDCSLIN1的0x34报文对应信号)";
CM_ SG_ 1073 PDCS2_IBS_I_BATT "(转发自PDCSLIN1的0x34报文对应信号)
根据IBS_I_RANGE定义的取值范围，决定IBS_I_BATT的计算方法和取值范围:
1.IBS_I_RANGE=0时，IBS_I_BATT信号偏移量=-32，精度0.0009765625，取值范围[-1，1]；
2.IBS_I_RANGE=1时，IBS_I_BATT信号偏移量=-256，精度0.0078125，取值范围[-200，200]；
3.IBS_I_RANGE=2时，IBS_I_BATT信号偏移量=-2048，精度0.0625，取值范围[-1500，1500]";
CM_ SG_ 1073 PDCS2_IBS_T_BATT "电池温度值(转发自PDCSLIN1的0x34报文对应信号)";
CM_ SG_ 1073 PDCS2_IBS_Status_Current "电池电流值状态(转发自PDCSLIN1的0x34报文对应信号)";
CM_ SG_ 1073 PDCS2_IBS_Status_Voltage "电池电压值状态(转发自PDCSLIN1的0x34报文对应信号)";
CM_ SG_ 1073 PDCS2_IBS_Status_Temp "电池温度值状态(转发自PDCSLIN1的0x34报文对应信号)";
CM_ SG_ 1073 PDCS2_IBS_ERROR_Commom "Internal IBS error (switch sensor).(转发自PDCSLIN1的0x34报文对应信号)";
CM_ SG_ 1073 PDCS2_IBS_LINRespErr "LIN响应错误(转发自PDCSLIN1的0x34报文对应信号)";
CM_ SG_ 1073 PDCS2_IBS_SOC "小电池SOC值(转发自PDCSLIN1的0x35报文对应信号)";
CM_ SG_ 1073 PDCS2_IBS_SOH "小电池SOH值(转发自PDCSLIN1的0x35报文对应信号)";
CM_ SG_ 1073 PDCS2_IBS_DisChargeCurrWU_Sts "IBS充电唤醒使能(转发自PDCSLIN1的0x35报文对应信号)";
CM_ SG_ 1073 PDCS2_IBS_ChargeCurrWU_Sts "IBS放电唤醒使能(转发自PDCSLIN1的0x35报文对应信号)";
CM_ SG_ 1073 PDCS2_IBS_SOCWU_Sts "IBS低SOC唤醒使能(转发自PDCSLIN1的0x35报文对应信号)";
CM_ SG_ 1073 PDCS2_IBS_DisChargeCurrWU "IBS是否执行放电电流唤醒反馈(转发自PDCSLIN1的0x35报文对应信号)";
CM_ SG_ 1073 PDCS2_IBS_ChargeCurrWU "IBS是否执行充电电流唤醒反馈(转发自PDCSLIN1的0x35报文对应信号)";
CM_ SG_ 1073 PDCS2_IBS_SOCWU "IBS是否执行低SOC唤醒反馈(转发自PDCSLIN1的0x35报文对应信号)";
CM_ SG_ 1073 PDCS2_IBS_SOH_STATE "IBS_SOH值可信度(转发自PDCSLIN1的0x35报文对应信号)";
CM_ SG_ 1073 PDCS2_IBS_SOC_STATE "IBS_SOC值可信度(转发自PDCSLIN1的0x35报文对应信号)";
CM_ SG_ 1073 PDCS2_SOCWU_Treshold "(转发自PDCSLIN1的0x39报文对应信号)";
CM_ SG_ 1073 PDCS2_SOCWU_Ena "(转发自PDCSLIN1的0x39报文对应信号)";
CM_ SG_ 571 PDCS1_AGS1_Mechanical_Break "Mechanical coupling breakage feedback（路由自PDCS LIN_0x21报文）";
CM_ SG_ 571 PDCS1_AGS1_Sensor_Error "Position sensor error feedback（路由自PDCS LIN_0x21报文）";
CM_ SG_ 571 PDCS1_AGS1_Calibration_Movement "Feedback of whether the actuator is in calibrating movement（路由自PDCS LIN_0x21报文）";
CM_ SG_ 571 PDCS1_AGS1_Needs_Calibration "Feedback of whether the actuator needs recalibration（路由自PDCS LIN_0x21报文）";
CM_ SG_ 571 PDCS1_AGS1_Voltage_Error "Feedback of whether under/over voltage error occurs（路由自PDCS LIN_0x21报文）";
CM_ SG_ 571 PDCS1_AGS1_Unexpected_Block "Unexpected blockage feedback（路由自PDCS LIN_0x21报文）";
CM_ SG_ 571 PDCS1_AGS1_Electrical_Error "Electrical error feedback（路由自PDCS LIN_0x21报文）";
CM_ SG_ 571 PDCS1_AGS1_Over_Temperature_Error "Over Temperature fault feedback（路由自PDCS LIN_0x21报文）";
CM_ SG_ 571 PDCS1_AGS1_Current_Limit_Actual "Actuator drive current feedback（路由自PDCS LIN_0x21报文）";
CM_ SG_ 571 PDCS1_AGS1_LIN_Status "Lin Status Feedback（路由自PDCS LIN_0x21报文）";
CM_ SG_ 571 PDCS1_AGS1_LINRespErr "AGS LIN响应错误（路由自PDCS LIN_0x21报文）";
CM_ SG_ 816 PDCS2_DisAeb "禁止AEB标志位";
CM_ SG_ 816 PDCS2_DisApa "禁止泊车标志位";
CM_ SG_ 816 PDCS2_VehSpdLimFgl "限速标志位";
CM_ SG_ 816 PDCS2_DisDcDc "禁止DCDC工作标志位";
CM_ SG_ 816 PDCS2_DisRegen "禁止能量回收标志位";
CM_ SG_ 816 PDCS2_DisCcs "禁止定速巡航标志位";
CM_ SG_ 816 PDCS2_DisAcc "禁止自适应巡航标志位";
CM_ SG_ 816 PDCS2_DisMot "禁止上Ready标志位";
CM_ SG_ 816 PDCS2_LimHomeFlg "跛行标志位";
CM_ SG_ 816 PDCS2_PwrLimFlg "限功率标志位";
CM_ SG_ 816 PDCS2_12VBatChrgePwrUpReq "智能补电上电请求";
CM_ SG_ 816 PDCS2_12VBatChrgePwrDwnReq "智能补电下电请求";
CM_ SG_ 816 PDCS2_HvPwrUpReq "高压上电请求";
CM_ SG_ 816 PDCS2_HvPwrDwnReq "高压下电请求";
CM_ SG_ 816 PDCS2_12VBatChargeExitReason "智能补电退出原因";
CM_ SG_ 816 PDCS2_12VBatChrgeCntr "智能补电次数";
CM_ SG_ 816 PDCS2_12VBatChrgeTi "智能补电工作时间";
CM_ SG_ 816 PDCS2_entityID "零件ID";
CM_ SG_ 816 PDCS2_Softwareversion "软件版本";
CM_ SG_ 1172 MCU_u32ResetReson "软件复位原因
0x11~0xFFFF：Reserved";
CM_ SG_ 1172 SOC_BackEepUsed_Flag "SOC动态存储使用备份数据故障";
CM_ SG_ 1172 SOC_CurrentBlockChk_Flag "SOC当前存储Block数据校验不一致";
CM_ SG_ 1172 VCU_ShutdownStoreBlockChk_Flag "VCU下电存储Block数据校验不一致";
CM_ SG_ 1172 HCU_BackEepUsed_Flag "HCU动态存储使用备份数据故障";
CM_ SG_ 1172 HCU_CurrentBlockChk_Flag "HCU当前动态储Block数据校验不一致";
CM_ SG_ 1172 HCU_ShutdownStoreBlockChk_Flag "HCU下电存储Block数据校验不一致";
CM_ SG_ 1172 BDCS_Reset_PIN_Flag "BDCS是否重置PIN";
CM_ SG_ 1172 BDCS_TeachPinSK_Flag "BDCS是否教PIN和SK";
CM_ SG_ 1172 BSW_Running_Status "BSW 运行状态机观测量";
CM_ SG_ 1172 BSW_Run_su1_run_request "状态机跳转并维持 run请求标志";
CM_ SG_ 1172 ComM_BusState0 "Com0通信状态量";
CM_ SG_ 1172 ComM_BusState1 "Com1通信状态量";
CM_ SG_ 1172 ComM_BusState2 "Com2通信状态量";
CM_ SG_ 1172 ComM_BusState3 "Com3通信状态量";
CM_ SG_ 1172 ComM_BusState4 "Com4通信状态量";
CM_ SG_ 1172 ComM_BusState5 "Com5通信状态量";
CM_ SG_ 1172 BSW_PostRun_su1_postrun_request "状态机跳转并维持 postrun请求标志";
CM_ SG_ 1172 BSW_PostRun_CANNMState "Can NM 状态机观测量";
CM_ SG_ 1172 BSW_PostRun_WakeupSource "唤醒源观测量";
CM_ SG_ 1172 BSW_PostRun_DemPostRunRequest "Dem跳转并维持Postrun请求标志";
CM_ SG_ 1172 BSW_PostRun_app_request "App 请求下电标志";
CM_ SG_ 1172 BSW_WaitForNvm_NvMJobState "NVM Job状态观测量";
CM_ SG_ 1172 BSW_Eth_TrcvLinkState "Eth Transceiver Link的状态";
CM_ SG_ 1172 BSW_Eth_SdMsgCnt "Eth接收到Sd的报文数量计数";
CM_ SG_ 1172 VCU_Packet1 "PDCS数据包1";
CM_ SG_ 1172 VCU_Packet2 "PDCS数据包2";
CM_ SG_ 1172 VCU_Packet3 "PDCS数据包3";
CM_ SG_ 1172 VCU_Packet4 "PDCS数据包4";
CM_ SG_ 1172 VCU_Packet5 "PDCS数据包5";
CM_ SG_ 1172 VCU_Packet6 "PDCS数据包6";
CM_ SG_ 1172 VCU_Packet7 "PDCS数据包7";
CM_ SG_ 1172 VCU_Packet8 "PDCS数据包8";
CM_ SG_ 1545 PDCS_SourceNodeIdentifier "ECU节点标识符";
CM_ SG_ 1545 PDCS_RepeatMessageRequest "Repeat Message请求";
CM_ SG_ 1545 PDCS_Reserve1 "预留";
CM_ SG_ 1545 PDCS_ActiveWakeup "激活唤醒，主动唤醒网络时置1，其他（包括被动唤醒节点）为0";
CM_ SG_ 1545 PDCS_Reserve2 "预留";
CM_ SG_ 1545 PDCS_WakeUp_KL15 "KL15 ON 唤醒";
CM_ SG_ 1545 PDCS_WakeUp_NM "NM报文唤醒";
CM_ SG_ 1545 PDCS_WakeUp_CC "CC唤醒源";
CM_ SG_ 1545 PDCS_WakeUp_CP "CP唤醒源";
CM_ SG_ 1545 PDCS_WakeUp_BMS "BMS唤醒源";
CM_ SG_ 1545 PDCS_WakeUp_RTC "RTC唤醒";
CM_ SG_ 1545 PDCS_WakeUp_APLUS "A+唤醒";
CM_ SG_ 1545 PDCS_WakeUp_OBC "OBC唤醒";
CM_ SG_ 1545 PDCS_WakeUp_APP "APP唤醒源";
CM_ SG_ 1545 PDCS_WakeUp_DIAG "诊断报文唤醒源";
CM_ SG_ 1545 PDCS_WakeUp_LIN "LIN唤醒源";
CM_ SG_ 1545 PDCS_Request_APP "APP请求网络";
CM_ SG_ 961 VCU_Challenge_Random_0 "Random Byte0(HighByte)";
CM_ SG_ 961 VCU_Challenge_Random_1 "Random Byte1";
CM_ SG_ 961 VCU_Challenge_Random_2 "Random Byte2";
CM_ SG_ 961 VCU_Challenge_Random_3 "Random Byte3(LowByte)";
CM_ SG_ 961 Encr_VCU_Challenge_PIN_0 "Encript PIN Code Byte0(HighByte)";
CM_ SG_ 961 Encr_VCU_Challenge_PIN_1 "Encript PIN Code Byte1(LowByte)";
CM_ SG_ 961 Encr_VCU_Challenge_PIN_2 "加密前为0xAA";
CM_ SG_ 961 Encr_VCU_Challenge_PIN_3 "加密前为0x55";
CM_ SG_ 964 VCU_LEARN_SK_RC "Response Code";
CM_ SG_ 966 VCU_LEARN_PIN_RC "Response Code";
CM_ SG_ 968 Encr_VCU_TEA_SK_0 "Encript Secret Key Byte0(HighByte)";
CM_ SG_ 968 Encr_VCU_TEA_SK_1 "Encript Secret Key Byte1";
CM_ SG_ 968 Encr_VCU_TEA_SK_2 "Encript Secret Key Byte2";
CM_ SG_ 968 Encr_VCU_TEA_SK_3 "Encript Secret Key Byte3";
CM_ SG_ 968 Encr_VCU_TEA_SK_4 "Encript Secret Key Byte4";
CM_ SG_ 968 Encr_VCU_TEA_SK_5 "Encript Secret Key Byte5";
CM_ SG_ 968 Encr_VCU_TEA_SK_6 "Encript Secret Key Byte6";
CM_ SG_ 968 Encr_VCU_TEA_SK_7 "Encript Secret Key Byte7(LowByte)";
CM_ SG_ 970 VCU_RES_RC "Response Code";
CM_ SG_ 253 BMS11_BattCellNum1 "单体电压号";
CM_ SG_ 253 BMS11_BattCellNum1Vol "单体电压值";
CM_ SG_ 253 BMS11_BattCellNum2 "单体电压号";
CM_ SG_ 253 BMS11_BattCellNum2Vol "单体电压值";
CM_ SG_ 253 BMS11_BattTempSensorNum "温度探头号";
CM_ SG_ 253 BMS11_BattTempSensor "温度探头值";
CM_ SG_ 246 BMS6_Sts "电池准备就绪";
CM_ SG_ 246 BMS6_Enable_request "BMS模式使能请求";
CM_ SG_ 246 BMS6_ControlHVDischarge "BMS上高压请求";
CM_ SG_ 246 BMS6_WorkingMode "BMS工作模式";
CM_ SG_ 246 BMS6_PosBattContSts "电池正极继电器状态";
CM_ SG_ 246 BMS6_NegBattContSts "电池负极继电器状态";
CM_ SG_ 246 BMS6_PrechargeContSts "电池预充继电器状态";
CM_ SG_ 246 BMS6_DCChargeContSts "电池快充继电器状态";
CM_ SG_ 246 BMS6_PrechargeSts "电池预充状态";
CM_ SG_ 246 BMS6_InterlockSts "高压环路互锁故障";
CM_ SG_ 246 BMS6_ThermalDiffusion "热失控故障";
CM_ SG_ 246 BMS6_CellOverTempSts "电池高温报警";
CM_ SG_ 246 BMS6_CellUnderTempSts "电池低温报警";
CM_ SG_ 246 BMS6_CellOverVoltageSts "单体电池过压报警";
CM_ SG_ 246 BMS6_CellUnderVoltageSts "单体电池欠压报警";
CM_ SG_ 246 BMS6_OverVoltageSts "电池总电压过高报警";
CM_ SG_ 246 BMS6_UnderVoltageSts "总电压低压报警";
CM_ SG_ 246 BMS6_UnderSOCSts "SOC低报警";
CM_ SG_ 246 BMS6_BattOverSoc "SOC过高";
CM_ SG_ 246 BMS6_BattSocJump "SOC跳变";
CM_ SG_ 246 BMS6_BattOverCharging "过充";
CM_ SG_ 246 BMS6_BattMismatching "储能系统不匹配";
CM_ SG_ 246 BMS6_OverCurrentSts "总电流过流报警";
CM_ SG_ 246 BMS6_IsolSuperSts "绝缘故障";
CM_ SG_ 246 BMS6_TempDiffSts "温度差异报警";
CM_ SG_ 246 BMS6_DiagSts "动力电池系统故障";
CM_ SG_ 246 BMS6_CellConsistencySts "单体一致性差报警";
CM_ SG_ 246 BMS6_DCChargeNegContSts "电池快充负极继电器状态";
CM_ SG_ 246 BMS6_ElectromagneticLockCtrl "电磁锁控制";
CM_ SG_ 246 BMS6_MILSts "MIL故障灯点亮申请";
CM_ SG_ 246 BMS6_TempRiseFast_Flt "温升过快故障";
CM_ SG_ 246 BMS6_dischgActiveFltCategory "当前最高放电故障等级";
CM_ SG_ 246 BMS6_AliveCounter "检测控制器工作信号";
CM_ SG_ 246 BMS6_chgActiveFltCategory "当前最高充电故障等级";
CM_ SG_ 246 BMS6_presentActivityFault "当前活动最严重错误号";
CM_ SG_ 600 BMS3_StateOfCharge "电池电量SOC";
CM_ SG_ 600 BMS3_BatteryPressure "BPS压力";
CM_ SG_ 600 BMS3_HighestBattTemp "电池最高温度";
CM_ SG_ 600 BMS3_LowestBattTemp "电池最低温度";
CM_ SG_ 600 BMS3_ChrgGunCnctLi "充电连接指示";
CM_ SG_ 600 BMS3_Lowbattery "电池低温提示显示位";
CM_ SG_ 600 BMS3_Charge_State "电池充电状态";
CM_ SG_ 600 BMS3_ACChrgImmediatEna "BMS交流立即充电控制使能
AC charger immediately enabled";
CM_ SG_ 600 BMS3_ACChrgImmediatEnaFb "BMS交流立即充电控制反馈
AC charger immediately enabled feedback";
CM_ SG_ 600 BMS3_FloatingChargeWarn "防浮充提醒";
CM_ SG_ 600 BMS3_FloatingChargeState "防浮充标志位";
CM_ SG_ 136 BMS1_PeakDischargeCurrent "电池允许峰值放电电流";
CM_ SG_ 136 BMS1_PeakChargeCurrent "电池允许峰值充电电流";
CM_ SG_ 136 BMS1_BatteryCurrent "电池总线电流";
CM_ SG_ 136 BMS1_AliveCounter "E2E Profile2-CRC8H2F，Counter:0-15";
CM_ SG_ 136 BMS1_BatteryState "电池连接状态";
CM_ SG_ 136 BMS1_Checksum "E2E Profile2-CRC8H2F
DataID List:#22 - 23 11 188 245 202 204 151 53 110 34 129 92 51 2 196 121";
CM_ SG_ 136 BMS1_DCChrgPostvVoltCtrl "直流充电正外总压控制
DCCharger Positive Voltage control";
CM_ SG_ 136 BMS1_DCChrgNegVoltCtrl "直流充电负外总压控制
DCCharger Negative Voltage control";
CM_ SG_ 136 BMS1_ContnsChargeCurrent "电池允许持续充电电流";
CM_ SG_ 136 BMS1_SOEpercentage "电池剩余可用SOE百分比";
CM_ SG_ 136 BMS1_ContnsDischargeCurrent "电池允许持续放电电流";
CM_ SG_ 136 BMS1_SlowChargeInterState "慢充内部状态信号";
CM_ SG_ 136 BMS1_FastChargeInterState "快充内部状态信号";
CM_ SG_ 261 BMS5_PeakDchaPwr "峰值放电功率";
CM_ SG_ 261 BMS5_ContnsDchaPwr "持续放电功率";
CM_ SG_ 261 BMS5_BatteryVoltage "电池包两端电压";
CM_ SG_ 261 BMS5_AliveCounter "E2E Profile2-CRC8H2F，Counter:0-15";
CM_ SG_ 261 BMS5_Checksum "E2E Profile2-CRC8H2F
DataID List:#23 - 136 95 77 205 225 52 170 129 17 198 33 10 128 32 4 193";
CM_ SG_ 261 BMS5_PeakChrgPwr "峰值充电功率";
CM_ SG_ 261 BMS5_ContnsChrgPwr "持续充电功率";
CM_ SG_ 261 BMS5_DCBusVoltage "高压总线两端电压";
CM_ SG_ 631 BMS7_WtrInTemp "电池包进水口温度";
CM_ SG_ 631 BMS7_WtrOutTemp "电池包出水口温度";
CM_ SG_ 631 BMS7_BattPmpSpdReq "BMS请求PDCS控制电池回路水泵的转速";
CM_ SG_ 631 BMS7_BattWtrInTReq "BMS请求电池的目标入水口温度";
CM_ SG_ 631 BMS7_BattWtrInTReqV "目标温度是否有效";
CM_ SG_ 631 BMS7_power_request "电池热管理功率请求";
CM_ SG_ 631 BMS7_Thermal_manage_status "电池系统热管理状态";
CM_ SG_ 631 BMS7_CLM_HVThermalReq "电池热管理请求状态";
CM_ SG_ 631 BMS7_AliveCounter "检测控制器工作信号";
CM_ SG_ 631 BMS7_Checksum "E2E Profile2-CRC8H2F
DataID List:#86 - 240 118 247 131 141 192 106 156 64 114 169 166 36 154 165 214";
CM_ SG_ 632 BMS8_StateOfEnergy "电池剩余可用SOE";
CM_ SG_ 632 BMS8_PowerBattMaintainLightReq "动力电池维护请求，仪表收点亮指示灯提示";
CM_ SG_ 632 BMS8_PowerBattDisconnettWarnLight "动力蓄电池切断指示灯";
CM_ SG_ 632 BMS8_RemoteChargeSts "远程充电状态反馈";
CM_ SG_ 632 BMS8_ChargeAppointmentEnable "预约充电使能反馈";
CM_ SG_ 632 BMS8_ChargeModeChangeInfo "SOC设置信息反馈";
CM_ SG_ 632 BMS8_ThermalReqfail "热管理失败反馈提示显示位";
CM_ SG_ 632 BMS8_feedback_SOC "反馈设置后目标SOC值";
CM_ SG_ 632 BMS8_ChargeWakeupBMS "BMS硬线被动唤醒信号";
CM_ SG_ 632 BMS8_SOCWarningLightSts "动力电池电量低提示灯";
CM_ SG_ 632 BMS8_InsulationFaultLightControl "动力电池绝缘灯";
CM_ SG_ 632 BMS8_BatterFaultLightControl "动力电池故障灯";
CM_ SG_ 632 BMS8_V2X_PowReq "V2X功率请求";
CM_ SG_ 632 BMS8_AliveCounter "检测控制器工作信号";
CM_ SG_ 632 BMS8_Dailyusereminder "电池日常提示";
CM_ SG_ 632 BMS8_DichargeModeChangeInfo "外接放电SOC反馈";
CM_ SG_ 648 BMS4_HighestCellVoltage "电池组电池单体最高电压";
CM_ SG_ 648 BMS4_LowestCellVoltage "电池组电池单体最低电压";
CM_ SG_ 648 BMS4_BattHeat_time "插枪保温加热时间";
CM_ SG_ 648 BMS4_AverageBattTemp "电池平均温度";
CM_ SG_ 648 BMS4_StateOf_Health "电池健康指数";
CM_ SG_ 658 BMS2_MinBattVoltage "电池允许最小放电电压";
CM_ SG_ 658 BMS2_MaxBattVoltage "电池允许最大充电电压";
CM_ SG_ 658 BMS2_LowestVoltage_CellNum "最低电压单体序号";
CM_ SG_ 658 BMS2_HighestVoltage_CellNum "最高电压单体序号";
CM_ SG_ 658 BMS2_LowestTemp_SensorNum "最低温度探针号";
CM_ SG_ 658 BMS2_HighestTemp_SensorNum "最高温度探针号";
CM_ SG_ 666 BMS10_PowrDwonReq "慢充下电请求";
CM_ SG_ 666 BMS10_ChrgEnable "充电使能信号";
CM_ SG_ 666 BMS10_RequestOutputCurrent "BMS请求的电流";
CM_ SG_ 666 BMS10_DischargeWorkSts "对外放电激活状态";
CM_ SG_ 666 BMS10_RequestOutputVoltage "BMS请求的电压";
CM_ SG_ 666 BMS10_DischargeMainSts "对外放电主开关状态";
CM_ SG_ 666 BMS10_DischargeObejectSelectFb "对外放电对象选择反馈";
CM_ SG_ 666 BMS10_DischargeModeSelectFb "对外放电模式选择反馈";
CM_ SG_ 666 BMS10_AliveCounter "检测控制器工作信号";
CM_ SG_ 666 BMS10_ACChargeRemainTime "交流充电完成剩余时间";
CM_ SG_ 666 BMS10_RequestOutputMode "OBC充电模式请求";
CM_ SG_ 694 BMS16_StateOfChargeReal "真实SOC";
CM_ SG_ 694 BMS16_MAXStateOfCharge "电池电量最大SOC";
CM_ SG_ 694 BMS16_MINStateOfCharge "电池电量最小SOC";
CM_ SG_ 694 BMS16_StateOfEnergyReal "真实SOE";
CM_ SG_ 695 BMS27_BattSnuffleValveTemp_1 "电池防爆阀温度1";
CM_ SG_ 695 BMS27_BattSnuffleValveTemp_2 "电池防爆阀温度2";
CM_ SG_ 695 BMS27_BattNum "电池组号";
CM_ SG_ 745 BMS9_QuiChgPileOutputVol "快充桩输出电压";
CM_ SG_ 745 BMS9_QuiChgPileOutputCur "快充桩输出电流";
CM_ SG_ 745 BMS9_FCVoltageRequest "快充电压需求";
CM_ SG_ 745 BMS9_FCCurrentRequest "快充电流需求";
CM_ SG_ 745 BMS9_AliveCounter "检测控制器工作信号";
CM_ SG_ 745 BMS9_DCChargeRemainTime "直流充电完成剩余时间";
CM_ SG_ 745 BMS9_FCType "快充充电模式";
CM_ SG_ 745 BMS9_FCSotp "快充停止原因";
CM_ SG_ 792 BMS12_SumOfCellNum "动力电池总成单体总数";
CM_ SG_ 792 BMS12_SumOfTSnsrNum "动力电池温度传感器总数";
CM_ SG_ 792 BMS12_IsoRVal "绝缘电阻值";
CM_ SG_ 792 BMS12_VBatteryVoltage "低压蓄电池电压值";
CM_ SG_ 913 BMS18_Hds_ah_AccumChrgCpSum "累计充电总容量";
CM_ SG_ 913 BMS18_Hds_egy_AccumChrgEgySum "累计充电总能量";
CM_ SG_ 914 BMS19_Hds_ah_AccumDchaCpSum "累计放电总容量";
CM_ SG_ 914 BMS19_Hds_kWh_AccumDchaEgySum "累计放电总能量";
CM_ SG_ 915 BMS20_Hds_ah_AccumRechrgCpSum "累计回充总容量";
CM_ SG_ 915 BMS20_Hds_kWh_AccumRechrgEgySum "累计回充总能量";
CM_ SG_ 916 BMS21_HistorcumulativerunT "BMS历史累计运行时间";
CM_ SG_ 916 BMS21_HistorcumulativedormancyT "BMS历史累计休眠时间";
CM_ SG_ 917 BMS22_CellOverUFltNum "电芯过压故障次数";
CM_ SG_ 917 BMS22_CellUnderUFltNum "电芯欠压故障次数";
CM_ SG_ 917 BMS22_CellOverTFltNum "电芯过温故障次数";
CM_ SG_ 917 BMS22_CellUnderTFltNum "电芯低温故障次数";
CM_ SG_ 918 BMS23_ChrgCellOverIFltNum "充电过流故障次数";
CM_ SG_ 918 BMS23_DchaCellOverIFltNum "放电过流故障次数";
CM_ SG_ 918 BMS23_Hds_ah_TotalCpSum "动力电池总容量";
CM_ SG_ 919 BMS24_Hds_ah_ReActiveCpSum "动力电池剩余可用容量";
CM_ SG_ 919 BMS24_Hds_ah_ActiveCpSum "动力电池可用容量";
CM_ SG_ 920 BMS25_Singdischar_energy "单次放电能量";
CM_ SG_ 920 BMS25_Single_energyFb "单次回馈能量";
CM_ SG_ 920 BMS25_Singchar_energy "单次充电能量";
CM_ SG_ 920 BMS25_heatconsum "电池加热到目标温度消耗能量";
CM_ SG_ 920 BMS25_cool_consum "电池冷却到目标温度消耗能量";
CM_ SG_ 994 BMS26_ACStopChrgReason "慢充停止原因";
CM_ SG_ 994 BMS26_DCStopChrgReason "快充停止原因";
CM_ SG_ 994 BMS26_PowerOnFailureReason "无法上高压原因";
CM_ SG_ 994 BMS26_MostCriticalFltID "BMS内部最严重故障号";
CM_ SG_ 1540 BMS_SourceNodeIdentifier "ECU节点标识符";
CM_ SG_ 1540 BMS_RepeatMessageRequest "Repeat Message请求";
CM_ SG_ 1540 BMS_Reserve1 "预留";
CM_ SG_ 1540 BMS_ActiveWakeup "激活唤醒，主动唤醒网络时置1，其他（包括被动唤醒节点）为0";
CM_ SG_ 1540 BMS_Reserve2 "预留";
CM_ SG_ 1540 BMS_WakeUp_KL15 "KL15 ON唤醒";
CM_ SG_ 1540 BMS_WakeUp_NM "NM报文唤醒";
CM_ SG_ 1540 BMS_WakeUp_ThermalDiffusion "电池包热失控";
CM_ SG_ 1540 BMS_WakeUpReason4 "唤醒原因4";
CM_ SG_ 1540 BMS_WakeUpReason5 "唤醒原因5";
CM_ SG_ 1540 BMS_WakeUp_PreCharge "预约充电唤醒";
CM_ SG_ 1540 BMS_WakeUp_OTA "OTA升级唤醒";
CM_ SG_ 1540 BMS_WakeUp_OverAmTemp "外温过高电池包降温需求";
CM_ SG_ 1540 BMS_RemainNetworkWakeUpReason1 "保持网络唤醒原因1";
CM_ SG_ 1540 BMS_RemainNetworkWakeUpReason2 "保持网络唤醒原因2";
CM_ SG_ 1540 BMS_RemainNetworkWakeUpReason3 "保持网络唤醒原因3";
CM_ SG_ 1540 BMS_RemainNetworkWakeUpReason4 "保持网络唤醒原因4";
CM_ SG_ 1540 BMS_RemainNetworkWakeUpReason5 "保持网络唤醒原因5";
CM_ SG_ 1540 BMS_RemainNetworkWakeUpReason6 "保持网络唤醒原因6";
CM_ SG_ 1540 BMS_RemainNetworkWakeUpReason7 "保持网络唤醒原因7";
CM_ SG_ 1540 BMS_RemainNetworkWakeUpReason8 "保持网络唤醒原因8";
CM_ SG_ 1540 BMS_RemainNetworkWakeUpReason9 "保持网络唤醒原因9";
CM_ SG_ 1540 BMS_RemainNetworkWakeUpReason10 "保持网络唤醒原因10";
CM_ SG_ 170 MCU1_MaxAvailableTorque "电机最大可输出扭矩";
CM_ SG_ 170 MCU1_MotorSpeed "电机转速";
CM_ SG_ 170 MCU1_ControllerTorque "实际输出扭矩
包含MCU Damping torque";
CM_ SG_ 170 MCU1_AliveCounter "E2E Profile2-CRC8H2F，Counter:0-15";
CM_ SG_ 170 MCU1_Mode "电机当前工作模式";
CM_ SG_ 170 MCU1_ControllerTorqueValid "实际输出扭矩有效位
包含MCU Damping torque";
CM_ SG_ 170 MCU1_Checksum "E2E Profile2-CRC8H2F
DataID List:#7 - 12 243 207 94 6 201 30 183 35 143 78 190 188 108 16 38";
CM_ SG_ 170 MCU1_presentActivityFault "当前活动最严重错误号";
CM_ SG_ 170 MCU1_CurrentTorque "实际扭力值
[-400,400] Nm";
CM_ SG_ 170 MCU1_TorMonitorFault "扭矩监控故障";
CM_ SG_ 170 MCU1_CurrentTorqueValid "实际扭力值有效位";
CM_ SG_ 170 MCU1_MonitorTorque "监控扭矩估算值";

BA_DEF_ BO_ "CANFD_BRS" ENUM "0","1";
BA_DEF_ BO_ "GenMsgSendType" ENUM "Cycle","NoMsgSendType","IfActive","Event","CA","CE";
BA_DEF_ BO_ "GenMsgNrOfRepetition" INT 0 0;
BA_DEF_ BO_ "GenMsgILSupport" ENUM "No","Yes";
BA_DEF_ BO_ "GenMsgDelayTime" INT 0 0;
BA_DEF_ BO_ "GenMsgCycleTimeFast" INT 0 0;
BA_DEF_ BO_ "GenMsgCycleTime" INT 0 0;
BA_DEF_ BO_ "DiagResponse" ENUM "No","Yes";
BA_DEF_ BO_ "DiagRequest" ENUM "No","Yes";
BA_DEF_ BO_ "NmMessage" ENUM "No","Yes";
BA_DEF_ BO_ "VFrameFormat" ENUM "StandardCAN","ExtendedCAN","reserved","J1939PG","reserved","reserved","reserved","reserved","reserved","reserved","reserved","reserved","reserved","reserved","StandardCAN_FD","ExtendedCAN_FD";
BA_DEF_ "NmType" STRING ;
BA_DEF_ "ProtocolType" STRING ;
BA_DEF_ "NmBaseAddress" HEX 0 2047;
BA_DEF_ "DBName" STRING ;
BA_DEF_ "BusType" STRING ;
BA_DEF_ "Baudrate" INT 0 1000000;
BA_DEF_ SG_ "GenSigInvalidValue" HEX 0 0;
BA_DEF_ SG_ "GenSigStartValue" HEX 0 0;
BA_DEF_ SG_ "GenSigSendType" ENUM "Cycle","OnWrite","OnWriteWithRepetition","OnChange","OnChangeWithRepetition","IfActive","IfActiveWithRepetition","NoSigSendType","vector_leerstring";
BA_DEF_ BU_ "NodeLayerModules" STRING ;
BA_DEF_ BU_ "NmCAN" INT 1 2;
BA_DEF_ BU_ "ILUsed" ENUM "No","Yes";
BA_DEF_DEF_ "CANFD_BRS" "1";
BA_DEF_DEF_ "GenMsgSendType" "Cycle";
BA_DEF_DEF_ "GenMsgNrOfRepetition" 0;
BA_DEF_DEF_ "GenMsgILSupport" "Yes";
BA_DEF_DEF_ "GenMsgDelayTime" 0;
BA_DEF_DEF_ "GenMsgCycleTimeFast" 0;
BA_DEF_DEF_ "GenMsgCycleTime" 0;
BA_DEF_DEF_ "DiagResponse" "No";
BA_DEF_DEF_ "DiagRequest" "No";
BA_DEF_DEF_ "NmMessage" "No";
BA_DEF_DEF_ "VFrameFormat" "StandardCAN";
BA_DEF_DEF_ "NmType" "AUTOSAR";
BA_DEF_DEF_ "ProtocolType" "CAN";
BA_DEF_DEF_ "NmBaseAddress" 1536;
BA_DEF_DEF_ "DBName" "";
BA_DEF_DEF_ "BusType" "CAN FD";
BA_DEF_DEF_ "Baudrate" 500000;
BA_DEF_DEF_ "GenSigInvalidValue" 0;
BA_DEF_DEF_ "GenSigStartValue" 0;
BA_DEF_DEF_ "GenSigSendType" "Cycle";
BA_DEF_DEF_ "NodeLayerModules" "OSEKNM01.dll,CANoeILNLVector.dll";
BA_DEF_DEF_ "NmCAN" 2;
BA_DEF_DEF_ "ILUsed" "Yes";
BA_ "DBName" "EP32_V5.3.1";
BA_ "ProtocolType" "CAN FD";
BA_ "GenMsgCycleTime" BO_ 579 100;
BA_ "VFrameFormat" BO_ 579 14;
BA_ "GenMsgSendType" BO_ 982 2;
BA_ "VFrameFormat" BO_ 982 14;
BA_ "GenMsgCycleTime" BO_ 347 50;
BA_ "VFrameFormat" BO_ 347 14;
BA_ "GenMsgCycleTime" BO_ 405 50;
BA_ "VFrameFormat" BO_ 405 14;
BA_ "GenMsgCycleTime" BO_ 533 100;
BA_ "VFrameFormat" BO_ 533 14;
BA_ "GenMsgCycleTime" BO_ 1233 200;
BA_ "VFrameFormat" BO_ 1233 14;
BA_ "GenMsgCycleTime" BO_ 1536 500;
BA_ "NmMessage" BO_ 1536 1;
BA_ "GenMsgCycleTime" BO_ 129 10;
BA_ "VFrameFormat" BO_ 129 14;
BA_ "GenMsgCycleTime" BO_ 208 10;
BA_ "VFrameFormat" BO_ 208 14;
BA_ "GenMsgCycleTime" BO_ 232 20;
BA_ "VFrameFormat" BO_ 232 14;
BA_ "GenMsgCycleTime" BO_ 291 20;
BA_ "VFrameFormat" BO_ 291 14;
BA_ "GenMsgCycleTime" BO_ 384 50;
BA_ "VFrameFormat" BO_ 384 14;
BA_ "GenMsgCycleTime" BO_ 531 100;
BA_ "VFrameFormat" BO_ 531 14;
BA_ "GenMsgCycleTime" BO_ 854 1000;
BA_ "VFrameFormat" BO_ 854 14;
BA_ "GenMsgCycleTime" BO_ 856 1000;
BA_ "VFrameFormat" BO_ 856 14;
BA_ "GenMsgCycleTime" BO_ 200 10;
BA_ "VFrameFormat" BO_ 200 14;
BA_ "GenMsgCycleTime" BO_ 227 20;
BA_ "VFrameFormat" BO_ 227 14;
BA_ "GenMsgCycleTime" BO_ 242 20;
BA_ "VFrameFormat" BO_ 242 14;
BA_ "GenMsgCycleTime" BO_ 251 20;
BA_ "VFrameFormat" BO_ 251 14;
BA_ "GenMsgCycleTime" BO_ 252 10;
BA_ "VFrameFormat" BO_ 252 14;
BA_ "GenMsgCycleTime" BO_ 553 100;
BA_ "VFrameFormat" BO_ 553 14;
BA_ "GenMsgCycleTime" BO_ 724 100;
BA_ "VFrameFormat" BO_ 724 14;
BA_ "GenMsgCycleTime" BO_ 809 500;
BA_ "VFrameFormat" BO_ 809 14;
BA_ "GenMsgCycleTime" BO_ 152 10;
BA_ "VFrameFormat" BO_ 152 14;
BA_ "GenMsgCycleTime" BO_ 264 20;
BA_ "VFrameFormat" BO_ 264 14;
BA_ "GenMsgCycleTime" BO_ 739 100;
BA_ "VFrameFormat" BO_ 739 14;
BA_ "GenMsgCycleTime" BO_ 1073 200;
BA_ "VFrameFormat" BO_ 1073 14;
BA_ "GenMsgCycleTime" BO_ 571 100;
BA_ "VFrameFormat" BO_ 571 14;
BA_ "GenMsgCycleTime" BO_ 816 200;
BA_ "VFrameFormat" BO_ 816 14;
BA_ "GenMsgCycleTime" BO_ 1172 500;
BA_ "VFrameFormat" BO_ 1172 14;
BA_ "GenMsgCycleTime" BO_ 1545 500;
BA_ "NmMessage" BO_ 1545 1;
BA_ "GenMsgSendType" BO_ 961 2;
BA_ "VFrameFormat" BO_ 961 14;
BA_ "GenMsgSendType" BO_ 964 2;
BA_ "VFrameFormat" BO_ 964 14;
BA_ "GenMsgSendType" BO_ 966 2;
BA_ "VFrameFormat" BO_ 966 14;
BA_ "GenMsgSendType" BO_ 968 2;
BA_ "VFrameFormat" BO_ 968 14;
BA_ "GenMsgSendType" BO_ 970 2;
BA_ "VFrameFormat" BO_ 970 14;
BA_ "GenMsgCycleTime" BO_ 253 20;
BA_ "VFrameFormat" BO_ 253 14;
BA_ "GenMsgCycleTime" BO_ 246 20;
BA_ "VFrameFormat" BO_ 246 14;
BA_ "GenMsgCycleTime" BO_ 600 100;
BA_ "VFrameFormat" BO_ 600 14;
BA_ "GenMsgCycleTime" BO_ 136 10;
BA_ "VFrameFormat" BO_ 136 14;
BA_ "GenMsgCycleTime" BO_ 261 20;
BA_ "VFrameFormat" BO_ 261 14;
BA_ "GenMsgCycleTime" BO_ 631 100;
BA_ "VFrameFormat" BO_ 631 14;
BA_ "GenMsgCycleTime" BO_ 632 100;
BA_ "VFrameFormat" BO_ 632 14;
BA_ "GenMsgCycleTime" BO_ 648 100;
BA_ "VFrameFormat" BO_ 648 14;
BA_ "GenMsgCycleTime" BO_ 658 100;
BA_ "VFrameFormat" BO_ 658 14;
BA_ "GenMsgCycleTime" BO_ 666 100;
BA_ "VFrameFormat" BO_ 666 14;
BA_ "GenMsgCycleTime" BO_ 694 100;
BA_ "VFrameFormat" BO_ 694 14;
BA_ "GenMsgCycleTime" BO_ 695 100;
BA_ "VFrameFormat" BO_ 695 14;
BA_ "GenMsgCycleTime" BO_ 745 100;
BA_ "VFrameFormat" BO_ 745 14;
BA_ "GenMsgCycleTime" BO_ 792 500;
BA_ "VFrameFormat" BO_ 792 14;
BA_ "GenMsgCycleTime" BO_ 913 5000;
BA_ "VFrameFormat" BO_ 913 14;
BA_ "GenMsgCycleTime" BO_ 914 5000;
BA_ "VFrameFormat" BO_ 914 14;
BA_ "GenMsgCycleTime" BO_ 915 5000;
BA_ "VFrameFormat" BO_ 915 14;
BA_ "GenMsgCycleTime" BO_ 916 5000;
BA_ "VFrameFormat" BO_ 916 14;
BA_ "GenMsgCycleTime" BO_ 917 5000;
BA_ "VFrameFormat" BO_ 917 14;
BA_ "GenMsgCycleTime" BO_ 918 5000;
BA_ "VFrameFormat" BO_ 918 14;
BA_ "GenMsgCycleTime" BO_ 919 5000;
BA_ "VFrameFormat" BO_ 919 14;
BA_ "GenMsgCycleTime" BO_ 920 1000;
BA_ "VFrameFormat" BO_ 920 14;
BA_ "GenMsgCycleTime" BO_ 994 500;
BA_ "VFrameFormat" BO_ 994 14;
BA_ "GenMsgCycleTime" BO_ 1540 500;
BA_ "NmMessage" BO_ 1540 1;
BA_ "GenMsgCycleTime" BO_ 170 10;
BA_ "VFrameFormat" BO_ 170 14;
BA_ "GenSigSendType" SG_ 982 AICS1_Resp_EncrData0 5;
BA_ "GenSigSendType" SG_ 982 AICS1_Resp_EncrData1 5;
BA_ "GenSigSendType" SG_ 982 AICS1_Resp_EncrData2 5;
BA_ "GenSigSendType" SG_ 982 AICS1_Resp_EncrData3 5;
BA_ "GenSigSendType" SG_ 982 AICS1_Resp_EncrData4 5;
BA_ "GenSigSendType" SG_ 982 AICS1_Resp_EncrData5 5;
BA_ "GenSigSendType" SG_ 982 AICS1_Resp_EncrData6 5;
BA_ "GenSigSendType" SG_ 982 AICS1_Resp_EncrData7 5;
BA_ "GenSigInvalidValue" SG_ 533 AICS_PDCS2_IBS_SOC 255;
BA_ "GenSigStartValue" SG_ 533 AICS_PDCS2_IBS_SOC 255;
BA_ "GenSigStartValue" SG_ 531 HCU3_GenInstEnergyConsum 999;
BA_ "GenSigStartValue" SG_ 200 VCU1_RexVCMProcess 2;
BA_ "GenSigStartValue" SG_ 227 VCU5_GearRatio 9110;
BA_ "GenSigInvalidValue" SG_ 242 VCU2_DCDC_PowerLimit 255;
BA_ "GenSigStartValue" SG_ 252 VCU7_FrntAxleWhlTqDem 16000;
BA_ "GenSigStartValue" SG_ 252 VCU7_ReAxleWhlTqDem 16000;
BA_ "GenSigStartValue" SG_ 252 VCU7_FrntMotDrvTqWhlLim 16000;
BA_ "GenSigStartValue" SG_ 252 VCU7_FrntMotRgnTqWhlLim 16000;
BA_ "GenSigStartValue" SG_ 252 VCU7_ReMotDrvTqWhlLim 16000;
BA_ "GenSigStartValue" SG_ 252 VCU7_ReMotRgnTqWhlLim 16000;
BA_ "GenSigStartValue" SG_ 252 VCU7_FrntAxleWhlTqCommd 16000;
BA_ "GenSigStartValue" SG_ 252 VCU7_ReAxleWhlTqCommd 16000;
BA_ "GenSigInvalidValue" SG_ 724 VCU4_CLM_PowerPermitted 31;
BA_ "GenSigInvalidValue" SG_ 724 VCU4_MotlnpWtrT 2047;
BA_ "GenSigStartValue" SG_ 724 VCU4_MotlnpWtrT 680;
BA_ "GenSigStartValue" SG_ 724 VCU4_BattInstEnergyCosum 1000;
BA_ "GenSigStartValue" SG_ 724 VCU4_DrivingPowerPercentage 100;
BA_ "GenSigStartValue" SG_ 724 VCU4_DrivingPower 512;
BA_ "GenSigStartValue" SG_ 152 VCU13_TotalMotRgnTqWhlLim 16000;
BA_ "GenSigStartValue" SG_ 152 VCU13_TotalMotDrvTqWhlLim 16000;
BA_ "GenSigStartValue" SG_ 152 VCU13_ReMotRgnTqWhlDesgn 16000;
BA_ "GenSigStartValue" SG_ 152 VCU13_FrntMotRgnTqWhlDesgn 16000;
BA_ "GenSigStartValue" SG_ 264 VCU4_PA_TargetTrqValue 800;
BA_ "GenSigInvalidValue" SG_ 1073 PDCS2_IBS_I_RANGE 3;
BA_ "GenSigInvalidValue" SG_ 1073 PDCS2_IBS_U_BATT 16383;
BA_ "GenSigStartValue" SG_ 1073 PDCS2_IBS_U_BATT 16383;
BA_ "GenSigInvalidValue" SG_ 1073 PDCS2_IBS_T_BATT 255;
BA_ "GenSigStartValue" SG_ 1073 PDCS2_IBS_T_BATT 255;
BA_ "GenSigInvalidValue" SG_ 1073 PDCS2_IBS_SOC 255;
BA_ "GenSigStartValue" SG_ 1073 PDCS2_IBS_SOC 255;
BA_ "GenSigInvalidValue" SG_ 1073 PDCS2_IBS_SOH 255;
BA_ "GenSigStartValue" SG_ 1073 PDCS2_IBS_SOH 255;
BA_ "GenSigInvalidValue" SG_ 1073 PDCS2_SOCWU_Treshold 255;
BA_ "GenSigStartValue" SG_ 1073 PDCS2_SOCWU_Treshold 70;
BA_ "GenSigSendType" SG_ 961 VCU_Challenge_Random_0 5;
BA_ "GenSigSendType" SG_ 961 VCU_Challenge_Random_1 5;
BA_ "GenSigSendType" SG_ 961 VCU_Challenge_Random_2 5;
BA_ "GenSigSendType" SG_ 961 VCU_Challenge_Random_3 5;
BA_ "GenSigSendType" SG_ 961 Encr_VCU_Challenge_PIN_0 5;
BA_ "GenSigSendType" SG_ 961 Encr_VCU_Challenge_PIN_1 5;
BA_ "GenSigSendType" SG_ 961 Encr_VCU_Challenge_PIN_2 5;
BA_ "GenSigSendType" SG_ 961 Encr_VCU_Challenge_PIN_3 5;
BA_ "GenSigSendType" SG_ 964 VCU_LEARN_SK_RC 5;
BA_ "GenSigSendType" SG_ 966 VCU_LEARN_PIN_RC 5;
BA_ "GenSigSendType" SG_ 968 Encr_VCU_TEA_SK_0 5;
BA_ "GenSigSendType" SG_ 968 Encr_VCU_TEA_SK_1 5;
BA_ "GenSigSendType" SG_ 968 Encr_VCU_TEA_SK_2 5;
BA_ "GenSigSendType" SG_ 968 Encr_VCU_TEA_SK_3 5;
BA_ "GenSigSendType" SG_ 968 Encr_VCU_TEA_SK_4 5;
BA_ "GenSigSendType" SG_ 968 Encr_VCU_TEA_SK_5 5;
BA_ "GenSigSendType" SG_ 968 Encr_VCU_TEA_SK_6 5;
BA_ "GenSigSendType" SG_ 968 Encr_VCU_TEA_SK_7 5;
BA_ "GenSigSendType" SG_ 970 VCU_RES_RC 5;
BA_ "GenSigStartValue" SG_ 136 BMS1_PeakDischargeCurrent 16000;
BA_ "GenSigStartValue" SG_ 136 BMS1_PeakChargeCurrent 16000;
BA_ "GenSigStartValue" SG_ 136 BMS1_BatteryCurrent 6000;
BA_ "GenSigStartValue" SG_ 136 BMS1_ContnsChargeCurrent 16000;
BA_ "GenSigStartValue" SG_ 136 BMS1_ContnsDischargeCurrent 16000;
BA_ "GenSigStartValue" SG_ 632 BMS8_DichargeModeChangeInfo 20;
BA_ "GenSigStartValue" SG_ 695 BMS27_BattSnuffleValveTemp_1 40;
BA_ "GenSigStartValue" SG_ 695 BMS27_BattSnuffleValveTemp_2 40;
BA_ "GenSigStartValue" SG_ 170 MCU1_CurrentTorque 8000;
VAL_ 579 AICS2_OTAMode 15 "Reserved" 14 "Reserved" 13 "Reserved" 12 "Reserved" 11 "Reserved" 10 "Reserved" 9 "Reserved" 8 "Reserved" 7 "Reserved" 6 "Reserved" 5 "Reserved" 4 "Reserved" 3 "in OTA mode" 2 "enter OTA mode request" 1 "quit OTA mode request" 0 "No request";
VAL_ 579 AICS2_StopChargeing 15 "Reserved" 14 "Reserved" 13 "Reserved" 12 "Reserved" 11 "Reserved" 10 "Reserved" 9 "Reserved" 8 "Reserved" 7 "Reserved" 6 "Reserved" 5 "Reserved" 4 "Reserved" 3 "Reserved" 2 "Reserved" 1 "shutdown chargeing" 0 "No request";
VAL_ 579 AICS2_BootRequestHVShut 1 "Request" 0 "No request";
VAL_ 579 AICS2_CDCS_CertificateState 1 "有效" 0 "无效";
VAL_ 347 SWSM_A_CruiseDistance_Add 1 "Press" 0 "No Press";
VAL_ 347 SWSM_A_CruiseDistance_Minus 1 "Press" 0 "No Press";
VAL_ 347 SWSM_A_CruiseSpeed_Add 2 "Fast Slider" 1 "Slowly Slider" 0 "No Action";
VAL_ 347 SWSM_A_CruiseSpeed_Minus 2 "Fast Slider" 1 "Slowly Slider" 0 "No Action";
VAL_ 347 SWSM_A_SpeechInputSw 2 "Long Press" 1 "Short Press" 0 "No Press";
VAL_ 347 Region_A_SwError 1 "Error" 0 "No Error";
VAL_ 347 SWSM_A_CD_Add_Overtime 1 "Stucked _>60s" 0 "No Stuck";
VAL_ 347 SWSM_A_CD_Minus_Overtime 1 "Stucked _>60s" 0 "No Stuck";
VAL_ 347 SWSM_B_PrevSw 1 "Press" 0 "No Press";
VAL_ 347 SWSM_B_NextSw 1 "Press" 0 "No Press";
VAL_ 347 SWSM_B_Volume_Add 2 "Fast Slider" 1 "Slowly Slider" 0 "No Action";
VAL_ 347 SWSM_B_Volume_Minus 2 "Fast Slider" 1 "Slowly Slider" 0 "No Action";
VAL_ 347 SWSM_B_MuteSw 2 "Long Press" 1 "Short Press" 0 "No Press";
VAL_ 347 Region_B_SwError 1 "Error" 0 "No Error";
VAL_ 347 SWSM_B_PrevSw_Overtime 1 "Stucked _>60s" 0 "No Stuck";
VAL_ 347 SWSM_B_NextSw_Overtime 1 "Stucked _>60s" 0 "No Stuck";
VAL_ 405 FPA_ResponseError 1 "Response Error True" 0 "Response Error False";
VAL_ 405 FPA_Staus 1 "Front PAS On" 0 "Front PAS Off";
VAL_ 405 FPA_AssemblyNumberDID 7 "Reserved" 6 "Reserved" 5 "Reserved" 4 "Reserved" 3 "Reserved" 2 "Reserved" 1 "EP40" 0 "EP36";
VAL_ 405 FPA_DetectionFOL 255 "Invalid";
VAL_ 405 FPA_DetectionFML 255 "Invalid";
VAL_ 405 FPA_DetectionFMR 255 "Invalid";
VAL_ 405 FPA_DetectionFOR 255 "Invalid";
VAL_ 405 FPA_FOLErrorFlag 1 "Sensor fault" 0 "Sensor normal";
VAL_ 405 FPA_FMLErrorFlag 1 "Sensor fault" 0 "Sensor normal";
VAL_ 405 FPA_FMRErrorFlag 1 "Sensor fault" 0 "Sensor normal";
VAL_ 405 FPA_FORErrorFlag 1 "Sensor fault" 0 "Sensor normal";
VAL_ 405 FPA_PoweVoltageAbnormal 1 "电压过低,PAS进入保护" 0 "电压正常";
VAL_ 405 FPA_Sound_Location 3 "Right Front+Left Front" 2 "Left Front" 1 "Right Front" 0 "No warning";
VAL_ 405 FPA_SoundIndication 6 "Warning Level 4_R" 5 "Warning Level 3_R" 4 "Warning Level 2_R" 3 "Warning Level 1_R" 2 "SyStem fault" 1 "System normal" 0 "No Request";
VAL_ 405 RPA_ResponseError 1 "Response Error True" 0 "Response Error False";
VAL_ 405 RPA_Staus 1 "Front PAS On" 0 "Front PAS Off";
VAL_ 405 RPA_AssemblyNumberDID 7 "Reserved" 6 "Reserved" 5 "Reserved" 4 "Reserved" 3 "Reserved" 2 "Reserved" 1 "EP40" 0 "EP36";
VAL_ 405 RPA_DetectionROL 255 "Invalid";
VAL_ 405 RPA_DetectionRML 255 "Invalid";
VAL_ 405 RPA_DetectionRMR 255 "Invalid";
VAL_ 405 RPA_DetectionROR 255 "Invalid";
VAL_ 405 RPA_ROLErrorFlag 1 "Sensor fault" 0 "Sensor normal";
VAL_ 405 RPA_RMLErrorFlag 1 "Sensor fault" 0 "Sensor normal";
VAL_ 405 RPA_RMRErrorFlag 1 "Sensor fault" 0 "Sensor normal";
VAL_ 405 RPA_RORErrorFlag 1 "Sensor fault" 0 "Sensor normal";
VAL_ 405 RPA_PoweVoltageAbnormal 1 "电压过低,PAS进入保护" 0 "电压正常";
VAL_ 405 RPA_Sound_Location 3 "Right Front+Left Front" 2 "Left Front" 1 "Right Front" 0 "No warning";
VAL_ 405 RPA_SoundIndication 6 "Warning Level 4_R" 5 "Warning Level 3_R" 4 "Warning Level 2_R" 3 "Warning Level 1_R" 2 "SyStem fault" 1 "System normal" 0 "No Request";
VAL_ 533 AICS_BDCS8_Drive_ODS 1 "Unoccupied（无人）" 0 "Occupied（有人）";
VAL_ 533 AICS_PDCS2_HvPwrUpReq 1 "Request" 0 "No request";
VAL_ 533 AICS_PDCS2_HvPwrDwnReq 1 "Request" 0 "No request";
VAL_ 1233 AICS_GCU3_OperModFdbk 7 "Error Mode" 6 "Discharge" 5 "VolCtrl" 4 "SpdCtrl" 3 "TqCtrl" 2 "Ready" 1 "Standby" 0 "Ini";
VAL_ 1233 AICS_EMS1_EngineStartedCompleted 1 "True" 0 "False";
VAL_ 1233 AICS_EMS1_EngineStopAllow 1 "Stop allowed" 0 "Stop not allowed";
VAL_ 1233 AICS_EMS1_ActualEngineTorqueValid 1 "valid" 0 "Invalid";
VAL_ 1536 AICS_RepeatMessageRequest 1 "Repeat message request" 0 "No repeat message request";
VAL_ 1536 AICS_ActiveWakeup 1 "Wakeup" 0 "No wakeup";
VAL_ 1536 AICS_WakeUp_KL15 1 "KL15 ON Wakeup" 0 "No Request";
VAL_ 1536 AICS_WakeUp_NM 1 "NM Wakeup" 0 "No Request";
VAL_ 1536 AICS_WakeUp_LIN 1 "LIN Wakeup" 0 "No Request";
VAL_ 1536 AICS_WakeUp_LocalPreCharge 1 "Wakeup Requrst" 0 "No Request";
VAL_ 1536 AICS_WakeUp_RemotePreCharge 1 "Wakeup Requrst" 0 "No Request";
VAL_ 1536 AICS_WakeUp_OTA 1 "Wakeup Requrst" 0 "No Request";
VAL_ 1536 AICS_WakeUp_Remote 1 "Wakeup Requrst" 0 "No Request";
VAL_ 1536 AICS_WakeUp_PhoneReminder 1 "Wakeup Requrst" 0 "No Request";
VAL_ 1536 AICS_RepeatFromSleep 1 "occur" 0 "not occur";
VAL_ 1536 AICS_RepeatFromPrepare 1 "occur" 0 "not occur";
VAL_ 1536 AICS_NormalFromRepeat 1 "occur" 0 "not occur";
VAL_ 1536 AICS_NormalFromReady 1 "occur" 0 "not occur";
VAL_ 1536 AICS_RepeatFromReady 1 "occur" 0 "not occur";
VAL_ 1536 AICS_RepeatFromNormal 1 "occur" 0 "not occur";
VAL_ 1536 AICS_RemainNetworkWakeUp_BMS_NM 1 "Remain wakeup BMS NM" 0 "default";
VAL_ 1536 AICS_RemainNetworkWakeUp_CDU_NM 1 "Remain wakeup CDU NM" 0 "default";
VAL_ 1536 AICS_RemainNetworkWakeUp_MCU_NM 1 "Remain wakeup MCU NM" 0 "default";
VAL_ 1536 AICS_RemainNetworkWakeUp_PDCU_NM 1 "Remain wakeup PDCU NM" 0 "default";
VAL_ 1536 AICS_RemainNetworkWakeUp_ADCS_NM 1 "Remain wakeup ADCS NM" 0 "default";
VAL_ 1536 AICS_RemainNetworkWakeUp_PDCS_NM 1 "Remain wakeup PDCS NM" 0 "default";
VAL_ 1536 AICS_RemainNetworkWakeUp_DDCU_NM 1 "Remain wakeup DDCU NM" 0 "default";
VAL_ 1536 AICS_RemainNetworkWakeUpReason1 1 "Remain wakeup PLG NM" 0 "default";
VAL_ 1536 AICS_RemainNetworkWakeUpReason2 1 "Remain wakeup CLM NM" 0 "default";
VAL_ 1536 AICS_RemainNetworkWakeUp_BDCS_NM 1 "Remain wakeup BDM NM" 0 "default";
VAL_ 1536 AICS_RemainNetworkWakeUp_FMCU_NM 1 "Remain wakeup FMCU NM" 0 "default";
VAL_ 1536 AICS_RemainNetworkWakeUp_ICU_NM 1 "Remain wakeup ICU NM" 0 "default";
VAL_ 1536 AICS_RemainNetworkWakeUp_CDCS_NM 1 "Remain wakeup CDCS NM" 0 "default";
VAL_ 1536 AICS_RemainNetworkWakeUp_AMP_NM 1 "Remain wakeup AMP NM" 0 "default";
VAL_ 1536 AICS_RemainNetworkWakeUp_BTM_NM 1 "Remain wakeup BTM NM" 0 "default";
VAL_ 1536 AICS_RemainNetworkWakeUpReason3 1 "Remain wakeup DVR NM" 0 "default";
VAL_ 1536 AICS_RemainNetworkWakeUp_GCU_NM 1 "Remain wakeup GCU NM" 0 "default";
VAL_ 1536 AICS_RemainNetworkWakeUp_HUD_NM 1 "Remain wakeup HUD NM" 0 "default";
VAL_ 1536 AICS_RemainNetworkWakeUp_T_BOX_NM 1 "Remain wakeup T_BOX NM" 0 "default";
VAL_ 1536 AICS_RemainNetworkWakeUp_LIN 1 "Remain wakeup LIN" 0 "default";
VAL_ 1536 AICS_RemainNetworkWakeUpReason22 1 "Remain wakeup reason" 0 "default";
VAL_ 1536 AICS_RemainNetworkWakeUpReason23 1 "Remain wakeup reason" 0 "default";
VAL_ 1536 AICS_RemainNetworkWakeUpReason24 1 "Remain wakeup reason" 0 "default";
VAL_ 129 HCU4_GcuModeReq 6 "Discharge" 5 "VolCtrl" 4 "SpdCtrl" 3 "TqCtrl" 2 "Ready" 1 "Standby" 0 "No Request";
VAL_ 129 HCU4_GCU_Fault_Reset 1 "Enable" 0 "Disable";
VAL_ 129 HCU4_GCU_Enable 1 "Enable" 0 "Disable";
VAL_ 208 HCU1_EngineStartRequest 1 "Engine start request" 0 "No start request";
VAL_ 208 HCU1_EngStart_Sts 1 "start failed" 0 "start success";
VAL_ 208 HCU1_EngineFuelInhibitRequest 1 "Fuel inhibited" 0 "No request";
VAL_ 208 HCU1_EngineOffRequest 1 "Stop request" 0 "No request";
VAL_ 208 HCU1_ReqTorqActive 1 "Request active" 0 "No request";
VAL_ 208 HCU1_TorqLimitReqActive 1 "Request active" 0 "No request";
VAL_ 208 HCU1_VehicleReady 1 "Ready" 0 "Not ready";
VAL_ 208 HCU1_EmissionLampRequest 1 "Request active" 0 "No request";
VAL_ 208 HCU1_FastTorqueActive 1 "Request active" 0 "No request";
VAL_ 208 HCU1_EngStop_Sts 1 "Stop Failed" 0 "Stop Success";
VAL_ 232 HCU2_EMSIdleAllowed 1 "Allowed" 0 "Not allowed";
VAL_ 232 HCU2_EngineIdleSpeedRequest 1 "Request" 0 "No request";
VAL_ 232 HCU2_GeneratorTorqueValid 1 "Valid" 0 "Invalid";
VAL_ 232 HCU2_FVVOpenRequest 1 "True" 0 "False";
VAL_ 232 HCU2_HybridModeStatus 3 "燃油" 2 "混动" 1 "纯电";
VAL_ 232 HCU2_EngineSpeedModeRequest 1 "request" 0 "no request";
VAL_ 384 HCU5_EnginIdingIdleSetFeedback 3 "Reserved" 2 "High" 1 "Low" 0 "Off";
VAL_ 384 HCU5_fueltankparkingunlock 1 "Request" 0 "No Request";
VAL_ 384 HCU5_Decompressionfail 1 "Failed" 0 "No Fail";
VAL_ 384 HCU5_serviceLampRequest 1 "Request" 0 "No Request";
VAL_ 384 HCU5_fueltankunLockrequest 1 "Request" 0 "No Request";
VAL_ 384 HCU5_CoolantFillingSta 1 "on" 0 "off";
VAL_ 384 HCU5_s_WaitTiExitRefu 1 "Valid" 0 "Invalid";
VAL_ 384 HCU5_flag_CapUncls 1 "Valid" 0 "Invalid";
VAL_ 384 HCU5_flg_EngWtrOvrTemp 1 "Valid" 0 "Invalid";
VAL_ 384 HCU5_TWV3_CWFlg 1 "Open rotation" 0 "No open rotaion";
VAL_ 384 HCU5_TWV3_CCWFlg 1 "close rotation" 0 "No close rotation";
VAL_ 384 HCU5_TWV3_motorSta 1 "Motor Stop" 0 "Motor Running";
VAL_ 384 HCU5_TWV3_RespError 1 "Fail" 0 "nromal";
VAL_ 384 HCU5_TWV3_OvervoltageFlt 1 "Fail" 0 "nromal";
VAL_ 384 HCU5_TWV3_OverCurrent 1 "Fail" 0 "nromal";
VAL_ 384 HCU5_TWV3_OverTempFlt 1 "Fail" 0 "nromal";
VAL_ 384 HCU5_TWV3_UndervoltageFlt 1 "Fail" 0 "nromal";
VAL_ 384 HCU5_TWV2_CWFlg 1 "Open rotation" 0 "No open rotaion";
VAL_ 384 HCU5_TWV2_CCWFlg 1 "close rotation" 0 "No close rotation";
VAL_ 384 HCU5_TWV2_motorSta 1 "Motor Stop" 0 "Motor Running";
VAL_ 384 HCU5_TWV2_RespError 1 "Fail" 0 "nromal";
VAL_ 384 HCU5_TWV2_OvervoltageFlt 1 "Fail" 0 "nromal";
VAL_ 384 HCU5_TWV2_OverCurrent 1 "Fail" 0 "nromal";
VAL_ 384 HCU5_TWV2_OverTempFlt 1 "Fail" 0 "nromal";
VAL_ 384 HCU5_TWV2_UndervoltageFlt 1 "Fail" 0 "nromal";
VAL_ 384 HCU5_WtrMotOutTempValid 1 "Valid(有效)" 0 "Invalid(无效)";
VAL_ 384 HCU5_OilFillCapLockremind 1 "Active" 0 "Inactive";
VAL_ 384 HCU5_RexMode 7 "reverse" 6 "reverse" 5 "reverse" 4 "PREM 前哨节能" 3 "FHEV 增程优先" 2 "HEV 纯电优先" 1 "EV 极致纯电" 0 "No Action";
VAL_ 384 HCU5_ForcechargingLevelSetFeedBack 3 "Strong" 2 "Normal" 1 "Weak" 0 "Default";
VAL_ 384 HCU5_PREMDisplayReminder 7 "Reserved" 6 "Reserved" 5 "Reserved" 4 "PREM ACTIVE" 3 "PREM Ready" 2 "e-Horizon date, PREM disable" 1 "PREM enable, No E-horizon" 0 "PREM inactive";
VAL_ 384 HCU5_REXchargSts 3 "Reserved" 2 "OFF" 1 "ON" 0 "Default";
VAL_ 531 HCU3_EngStrtForStaleFu 1 "Request" 0 "NoRequest";
VAL_ 531 HCU3_VCMActv 1 "Active" 0 "Inactive";
VAL_ 531 HCU3_SportmodAvailableDisp 2 "SOC low_Sport is not available" 1 "SOC low_Exit SPORT" 0 "Inactive";
VAL_ 531 HCU3_RexSysError 1 "request" 0 "no request";
VAL_ 531 HCU3_RexModeAvalidreminder 7 "HEV exit due to Batt charge limited" 6 "HEV not available due to Batt charge limited" 5 "Sport mode not available in Sport" 4 "PREM not available in Sport" 3 "FHEV not available in Sport" 2 "HEV not available in Sport" 1 "EV not available in Sport" 0 "no action";
VAL_ 531 HCU3_REXStartFail 1 "Request" 0 "No Request";
VAL_ 531 HCU3_PowerGradREX2MCU 3 "高速" 2 "中速" 1 "低速" 0 "默认状态";
VAL_ 531 HCU3_EnergyFlowSts 15 "Reserved" 14 "Reserved" 13 "Reserved" 12 "Reserved" 11 "Reserved" 10 "Reserved" 9 "Reserved" 8 "Reserved" 7 "增程器充电" 6 "增程器驱动+增程器充电" 5 "增程器驱动+电池驱动" 4 "增程器驱动" 3 "能量回收+增程器充电" 2 "能量回收" 1 "电池驱动" 0 "非运行状态";
VAL_ 531 HCU3_PowerGradMCU2Batt 3 "高速" 2 "中速" 1 "低速" 0 "默认状态";
VAL_ 531 HCU3_PowerGradREX2Batt 3 "高速" 2 "中速" 1 "低速" 0 "默认状态";
VAL_ 531 HCU3_EVModAvailableDisp 7 "Reserved" 6 "Reserved" 5 "18% Soc Low reminder" 4 "9%  Soc Low reminder 2" 3 "9%  Soc Low reminder 1" 2 "5%  Soc Low warning" 1 "0%  Soc Low warning" 0 "default";
VAL_ 531 HCU3_MotorDrive_Satis 3 "Reserved" 2 "回收" 1 "驱动" 0 "默认";
VAL_ 531 HCU3_FuelLevelEstimated 255 "Invalid";
VAL_ 531 HCU3_StRngextModeAct 7 "reserved" 6 "Sport 运动模式" 5 "EV 极致纯电" 4 "PREM 前哨节能" 3 "FHEV 增程优先" 2 "HEV 纯电优先" 1 "EVRange extension silence 增程静默" 0 "No Action";
VAL_ 531 HCU3_FTMSt 14 "Reserved" 13 "Reserved" 12 "Reserved" 11 "Prompt  11" 10 "LED_OFF  10" 9 "FinishedCapOn" 8 "WaitLong" 7 "Decompression_Error" 6 "Unparked" 5 "FinishedCapOff" 4 "Fuelling 4" 3 "FuelTankLock" 2 "FFV_Operation" 1 "Standby" 0 "No Action";
VAL_ 531 HCU3_REXreadyforsleep 1 "Active" 0 "Inactive";
VAL_ 531 HCU3_RexShutdownRdy 1 "Active" 0 "Inactive";
VAL_ 531 HCU3_flg_RexZeroPower 1 "Active" 0 "Inactive";
VAL_ 854 HCU7_StEngDynTranReq 2 "Engine Stop Request" 1 "Engine Start Request" 0 "No request";
VAL_ 854 HCU7_stEngStopTran 5 "EngineStopped" 4 "Engine Stop In Progress" 3 "Ready To Stop" 2 "Engine Stop Preparation" 1 "Engine Running" 0 "Initial State";
VAL_ 854 HCU7_stEngStrtTran 7 "Start Failure" 6 "Engine Running" 5 "Ignition Release" 4 "Engine Cranking" 3 "Ready To Start" 2 "Engine Start Preparation" 1 "EngineStopped" 0 "Initial State";
VAL_ 854 HCU7_AcvPwrReqStgy 5 "能量跟随" 4 "强制发电" 3 "VCM发电" 2 "功率跟随" 1 "定点发电" 0 "No request";
VAL_ 854 HCU7_StRngextSys 13 "Failure" 12 "Sleep" 11 "LV After Run" 10 "Shut down Initial" 9 "Active Discharge" 8 "Power Down Standby" 7 "Engine Off" 6 "Power Down" 5 "Operation" 4 "PT Ready" 3 "HV Ready" 2 "HV Power up" 1 "Initialization" 0 "Wakeup";
VAL_ 856 HCU8_StVCM 4 "Pending" 3 "Fail" 2 "Ready" 1 "Standbyready" 0 "Inactive";
VAL_ 856 HCU8_VolRemainingFuel 127 "Invalid";
VAL_ 856 HCU8_bAcvFuLeak 1 "ture" 0 "false";
VAL_ 856 HCU8_FuelLevelEstimated 127 "Invalid";
VAL_ 856 HCU8_bAcvRefu 1 "ture" 0 "false";
VAL_ 200 VCU1_MCUEnable 1 "Enable" 0 "Disable";
VAL_ 200 VCU1_Mode_Command 7 "Discharge mode" 6 "Zero torque mode" 5 "Speed mode" 4 "Reverse drive mode" 3 "Forward drive mode" 2 "Brake mode" 1 "Failure mode" 0 "Off";
VAL_ 200 VCU1_PMM_TmOuSt 7 "NONE" 6 "WAITVOLTDEC" 5 "OPENCNTCTR" 4 "WAITCURRDEC" 3 "PU" 2 "DCDCPU" 1 "CLSMAINCNTCTR" 0 "NONE";
VAL_ 200 VCU1_PMM_PwrUpSt 7 "Reserved2" 6 "Reserved1" 5 "FINISHED" 4 "TIMEOUT" 3 "TMSTART" 2 "DCDCENABLE" 1 "CLOSEMAINCNTRCTR" 0 "NONE";
VAL_ 200 VCU1_HvEmgy_status 1 "Emergency" 0 "NO Emergency";
VAL_ 200 VCU1_MCUShakeRedn 3 "Closed" 0 "Default/Open";
VAL_ 200 VCU1_VCMModeReq 1 "Request" 0 "No request";
VAL_ 200 VCU1_VCMPwrDwnCmd 1 "Request" 0 "No request";
VAL_ 200 VCU1_PMM_PwrDwnSt 6 "FINISHED" 5 "LOWVOLTPWRDWN" 4 "WAITVOLTDEC" 3 "OPENMAINCNTCTR" 2 "DCDCPWRDWN" 1 "WAITCURRENTDEC" 0 "NONE";
VAL_ 200 VCU_OBDMilLightReq 1 "Request Light MIL" 0 "No request";
VAL_ 200 VCU1_DisBatt2PMM 1 "故障发生" 0 "Default";
VAL_ 200 VCU1_FMCUEnable 1 "Enable" 0 "Disable";
VAL_ 200 VCU1_FMCUMode_Command 7 "Discharge mode" 6 "Zero torque mode" 5 "Speed mode" 4 "Reverse drive mode" 3 "Forward drive mode" 2 "Brake mode" 1 "Failure mode" 0 "Off";
VAL_ 200 VCU1_RexVCMProcess 2 "Default" 1 "VCM process" 0 "No VCM process";
VAL_ 200 VCU1_AppWrkSts 7 "Reserve" 5 "Reserve" 4 "需要打开通信，不可释放通信" 3 "Reserve" 2 "Reserve" 1 "可以下电" 0 "Default";
VAL_ 200 VCU1_FMCUHvEmgy_status 1 "Emergency" 0 "NO Emergency";
VAL_ 200 VCU1_FMCUShakeRedn 3 "Closed" 0 "Default/Open";
VAL_ 200 VCU1_BTVSleepRdyFlg 1 "休眠请求" 0 "Default";
VAL_ 200 VCU1_HvPwrUpTmOutFlg 1 "高压上电超时故障" 0 "Default";
VAL_ 227 VCU5_ActGear 7 "Invalid" 5 "S" 4 "Drive" 3 "Neutral" 2 "Reverse" 1 "Park" 0 "Default";
VAL_ 227 VCU5_ActGearValid 1 "Valid" 0 "Invalid";
VAL_ 227 VCU5_READYLightSts 1 "Lamp ON" 0 "Lamp OFF";
VAL_ 227 VCU5_HVIL_Attach 1 "Connect" 0 "No connect";
VAL_ 227 VCU5_PwrTrainFailureLevel 3 "Failure Stop" 2 "Failure Limit" 1 "Failure Slight" 0 "No Failure";
VAL_ 227 VCU5_HVIL_MajorLoop 1 "Connect" 0 "No connect";
VAL_ 227 VCU5_RangeModeFb 3 "CLTC" 2 "WLTC" 1 "NEDC" 0 "Default";
VAL_ 227 VCU5_HVReady 1 "Ready" 0 "Not Ready";
VAL_ 227 VCU5_HubMode 1 "Hub Mode(下电自动清零)" 0 "Normal mode";
VAL_ 227 VCU5_StartOffFlagReq 1 "Request" 0 "No Request";
VAL_ 227 VCU5_EmuEngineSts 1 "Engine Running" 0 "Engine Stop";
VAL_ 227 VCU5_AccelPositionValid 1 "Valid" 0 "Invalid";
VAL_ 227 VCU5_DriveMode_fb 4 "LAUNCH" 3 "CONFORM" 2 "SPORT" 1 "ECO" 0 "Default";
VAL_ 227 VCU5_DriverOvertakeMode 1 "Active" 0 "Not Active";
VAL_ 242 VCU2_Fault_Level 3 "FaultLevel3" 2 "FaultLevel2" 1 "FaultLevel1" 0 "No Fault";
VAL_ 242 VCU2_ControlHVDischarge 3 "Reserved" 2 "Reserved" 1 "Connect" 0 "Disconnect";
VAL_ 242 VCU2_IntegHVIL 1 "Error" 0 "No Error";
VAL_ 242 VCU2_DCDC_Enabled 1 "On" 0 "Off";
VAL_ 242 VCU2_ChrgEnable 3 "resevered" 2 "disable" 1 "enable" 0 "default";
VAL_ 242 VCU2_12VBatteryChargeState 3 "Error/Interrupt" 2 "Finished" 1 "Charging" 0 "Default/Not active";
VAL_ 242 VCU2_FastChgCCConnect 1 "Vaild" 0 "Invaild";
VAL_ 242 VCU2_FastChgWkVaild 1 "Vaild" 0 "Invaild";
VAL_ 242 VCU2_12VBatChrgeReqCmd 1 "Request" 0 "No request";
VAL_ 242 VCU2_FastChgCCConnectBrkPE 1 "break PE" 0 "PE connect";
VAL_ 251 VCU6_StopModeFb 2 "Parking Stop" 1 "Creep" 0 "Default";
VAL_ 251 VCU6_MotorDrvMode 1 "Auto" 0 "Manual";
VAL_ 251 VCU6_PMM_SysSt 7 "ENUM_PMM_HvActDchaReq" 6 "ENUM_PMM_VCM" 5 "PWRDWN" 4 "TMOUT" 3 "NORMAL" 2 "HVPWRUP" 1 "LVPWRUP" 0 "INIT";
VAL_ 251 VCU6_Lock_Status 3 "预留" 2 "未锁止" 1 "故障" 0 "锁止";
VAL_ 251 VCU6_BrakeSts 3 "Error" 2 "Reserved" 1 "Braking" 0 "Not braking";
VAL_ 251 VCU6_BrakeStsValid 1 "Vaild" 0 "Invaild";
VAL_ 251 VCU6_DispGearFltRemind 7 "Invalid" 6 "Reserved" 5 "Reserved" 4 "Reserved" 3 "档位闪烁 + 档位故障声音提醒" 2 "档位故障声音提醒" 1 "档位闪烁" 0 "No Remind";
VAL_ 251 VCU6_ParkCtrlOvrTime 1 "驻车超时故障" 0 "无故障";
VAL_ 251 VCU6_EPBBackupCtrlAail 1 "PDCS备份控制功能异常（not available）" 0 "PDCS备份控制功能正常（available）";
VAL_ 251 VCU6_EnergyRecLevelSts 3 "Reserved" 2 "High" 1 "Middle" 0 "Weak";
VAL_ 251 VCU6_SystemWarnLightSts 1 "Lamp ON" 0 "Lamp OFF/Startup/Default";
VAL_ 251 VCU6_RegenFlg 1 "ON" 0 "OFF";
VAL_ 251 VCU6_PNLelFault 1 "Fault" 0 "Not fault";
VAL_ 251 VCU6_SOCWarningLightSts 1 "Lamp ON" 0 "Lamp OFF/Startup/Default";
VAL_ 251 VCU6_12VBatChargeFaultSts 1 "Lamp ON" 0 "Lamp OFF/Startup/Default";
VAL_ 251 VCU6_SystemFaultWarn_Light 1 "Lamp ON" 0 "Lamp OFF/Startup/Default";
VAL_ 251 VCU6_AuthStatus 3 "Reserved" 2 "Failure" 1 "Pass" 0 "Default";
VAL_ 251 VCU6_onepedal_WorkSts 3 "StandBy" 2 "Error" 1 "Enable" 0 "Disable";
VAL_ 251 VCU6_GearShftRmn 15 "Invalid" 11 "档位异常" 10 "请踩刹车以进入牵引模式" 9 "请松开加速踏板以换入 R 挡" 8 "请松开加速踏板以换入 D 挡" 7 "请降速以换入 P 挡" 6 "请请降速以换入 R 挡" 5 "请降速以换入 D 挡" 4 "请踩刹车以换出 P 挡" 3 "请踩刹车以换入 P 挡" 2 "请踩刹车以换入 R 挡" 1 "请踩刹车以换入 D 挡" 0 "NoRmn";
VAL_ 251 VCU6_DiagThmStsFltLvl 3 "FaultLvl3" 2 "FaultLvl2" 1 "FaultLvl1" 0 "NoFault";
VAL_ 251 VCU6_RpBatt_Sts 3 "Reserved" 2 "故障" 1 "换电提示信号" 0 "无换电提示信号";
VAL_ 251 VCU6_ReadyLost_CheckFlt 1 "Fault" 0 "NoFault";
VAL_ 251 VCU6_GearFlt_CheckGear 1 "Fault" 0 "NoFault";
VAL_ 251 VCU6_ChargeConnKpTempSw_Fb 3 "Reserved" 2 "Reserved" 1 "开启" 0 "关闭";
VAL_ 251 VCU6_StrtgyGear 7 "Invalid" 5 "S" 4 "Drive" 3 "Neutral" 2 "Reverse" 1 "Park" 0 "Default";
VAL_ 251 VCU6_DispGear 7 "Invalid" 5 "S" 4 "Drive" 3 "Neutral" 2 "Reverse" 1 "Park" 0 "Default";
VAL_ 251 VCU6_PGearFlt 1 "Fault" 0 "NoFault";
VAL_ 251 VCU6_TracModeEPBRelsReq 1 "Request  Release" 0 "No Request";
VAL_ 251 VCU6_EnergyRecyleWarn 3 "Warnning" 2 "Not Enough" 1 "Enough" 0 "Default";
VAL_ 252 VCU7_FrntAxleWhlTqDemValid 1 "Valid(有效" 0 "Invalid(无效)";
VAL_ 252 VCU7_ReAxleWhlTqDemValid 1 "Valid(有效" 0 "Invalid(无效)";
VAL_ 252 VCU7_FrntMotDrvTqWhlLimValid 1 "Valid(有效" 0 "Invalid(无效)";
VAL_ 252 VCU7_FrntMotRgnTqWhlLimValid 1 "Valid(有效" 0 "Invalid(无效)";
VAL_ 252 VCU7_ReMotDrvTqWhlLimValid 1 "Valid(有效" 0 "Invalid(无效)";
VAL_ 252 VCU7_ReMotRgnTqWhlLimValid 1 "Valid(有效" 0 "Invalid(无效)";
VAL_ 553 VCU9_ChgConKpcontinued 1 "Request" 0 "No Request";
VAL_ 553 VCU9_V2L_Enable 1 "Enable" 0 "Disable";
VAL_ 553 VCU9_SlowChgWkVaild 1 "Vaild" 0 "Invaild";
VAL_ 553 VCU9_CoolantFillingSta 1 "on" 0 "off";
VAL_ 553 VCU9_BattHeatApt_Fb 1 "Active" 0 "Inactive";
VAL_ 553 VCU9_PosFastChgPort_Temp_Vaild 1 "Valid(有效" 0 "Invalid(无效)";
VAL_ 553 VCU9_NegFastChgPort_Temp_Vaild 1 "Valid(有效" 0 "Invalid(无效)";
VAL_ 553 VCU9_BattHeat_Info 12 "本次保温无法执行，下次充电生效" 11 "系统故障，电池保温退出" 10 "保温开关关闭，保温退出" 9 "电源模式ON, 电池保温退出" 8 "充电枪拔出或充电停止，电池保温退出" 7 "坏境温度高，电池保温退出" 6 "保温时长到，电池保温退出" 5 "系统故障，电池保温启动失败" 4 "电源模式ON，保温启动失败" 3 "充电枪未连接，保温启动失败" 2 "环境温度高，电池保温启动失败" 1 "电池保温已启动" 0 "default";
VAL_ 724 VCU4_CLM_PoweLimitedSts 5 "压力过高过低" 4 "CAN通信失败" 3 "功率受限" 2 "SOC 低" 1 "系统故障" 0 "reserved";
VAL_ 724 VCU4_VINEolUnImplnt 1 "UNImplemented" 0 "Implemented";
VAL_ 724 VCU4_ChgWake 1 "Waked" 0 "Not waked";
VAL_ 724 VCU4_VINImps 1 "VIN Implausible" 0 "VIN Reliable";
VAL_ 724 VCU4_CLM_PTCPumpFailCode 3 "fault" 2 "work" 1 "stop" 0 "No fault";
VAL_ 724 VCU4_CLM_FanFailCode 1 "Fault Present" 0 "No fault";
VAL_ 724 VCU4_CCS_Status 3 "Error" 2 "Active" 1 "Stand By" 0 "OFF";
VAL_ 724 VCU4_CLM_FanGearSts 3 "Reserved" 2 "High" 1 "Low" 0 "OFF";
VAL_ 724 VCU4_CLM_PowerPermittedV 1 "Valid" 0 "Invalid";
VAL_ 724 VCU4_BattHeatLvl 2 "MaxHeat" 1 "NormalHeat" 0 "OFF";
VAL_ 724 VCU4_ChgConKpTemp 1 "request" 0 "No request";
VAL_ 724 VCU4_BattCoolLvl 2 "MaxCool" 1 "NormalCool" 0 "OFF";
VAL_ 724 VCU4_LearnSts 1 "Learned" 0 "Not learned";
VAL_ 724 VCU4_LeftExtFanSpd 100 "100%" 0 "0";
VAL_ 724 VCU4_LeftExtFanFlt 1 "Fault Present" 0 "No fault";
VAL_ 724 VCU4_RightExtFanSpd 100 "100%" 0 "0";
VAL_ 724 VCU4_RightExtFanFlt 1 "Fault Present" 0 "No fault";
VAL_ 724 VCU4_AGSPositionActSts 15 "Open" 14 "93.75%" 13 "87.5%" 12 "81.25%" 11 "75%" 10 "68.75%" 9 "62.5%" 8 "56.25%" 7 "50%" 6 "43.75%" 5 "37.5%" 4 "31.25%" 3 "25%" 2 "18.75%" 1 "12.5%" 0 "Close";
VAL_ 724 VCU4_CCSetFail_Indication 2 "reserved" 1 "indication" 0 "no indication";
VAL_ 809 VCU10_IBS_ERROR_Commom 1 "Error" 0 "No error";
VAL_ 809 VCU10_SOC_LOW 1 "Low 12v battery SOC" 0 "No low 12v battery SOC";
VAL_ 809 VCU10_GasPedalFault 1 "Fault" 0 "No Fault";
VAL_ 809 VCU10_GasPedaExcessAmplitude 1 "Error" 0 "No Error";
VAL_ 809 VCU10_BMSCommFault 1 "Fault" 0 "No Fault";
VAL_ 809 VCU10_VehRunning_Status 7 "预留" 6 "仅前轮能量回收（预留）" 5 "仅后轮能量回收(预留)" 4 "四轮能量回收" 3 "纯电四驱" 2 "纯电仅前驱（预留）" 1 "纯电仅后驱动" 0 "默认";
VAL_ 809 VCU10_Channel1_speed 3 "高" 2 "中" 1 "低" 0 "默认";
VAL_ 809 VCU10_MotorDrive_Status 2 "能量回收" 1 "驱动" 0 "默认";
VAL_ 809 VCU10_Channel2_speed 3 "高" 2 "中" 1 "低" 0 "默认";
VAL_ 152 VCU13_TotalMotRgnTqWhlLimValid 1 "Valid(有效" 0 "Invalid(无效)";
VAL_ 152 VCU13_TotalMotDrvTqWhlLimValid 1 "Valid(有效" 0 "Invalid(无效)";
VAL_ 152 VCU13_ReMotRgnTqWhlDesgnValid 1 "Valid(有效" 0 "Invalid(无效)";
VAL_ 152 VCU13_FrntMotRgnTqWhlDesgnValid 1 "Valid(有效" 0 "Invalid(无效)";
VAL_ 264 VCU14_PAAvailable 1 "Not Available" 0 "Available";
VAL_ 264 VCU14_Sys_Ready 1 "Ready" 0 "Not ready";
VAL_ 264 VCU14_ACC_Ready 1 "Ready" 0 "Not ready";
VAL_ 264 VCU14_PAActive 1 "active" 0 "not active";
VAL_ 264 VCU14_AntiSlipWarning 7 "Invalid" 6 "Reserved" 5 "Reserved" 4 "Reserved" 3 "车辆正在溜坡" 2 "车辆可能溜坡" 1 "AVH激活失败，车辆可能溜坡" 0 "No Warning";
VAL_ 264 VCU14_AntiSlipAVHActvReq 1 "Request" 0 "No request";
VAL_ 264 VCU14_PA_ParkingFnMd 5 "abort" 4 "suspend" 3 "Cruising_HPP Pro_Mod" 2 "Cruising_HPP_Mode" 1 "Parking Mode" 0 "Function Not Active";
VAL_ 264 VCU14_ACC_Active 1 "active" 0 "not active";
VAL_ 264 VCU14_PA_FailCode 5 "Reserved" 4 "vehicle block（车辆无法移动）" 3 "Can not change gear" 2 "Driver interfervene" 1 "Over speed" 0 "Normal";
VAL_ 264 VCU14_Gear_PAActive 1 "active" 0 "not active";
VAL_ 264 VCU14_Gear_PAAvailable 1 "Not Available" 0 "Available";
VAL_ 264 VCU14_Gear_ErrorSts_M01 1 "Error" 0 "No Error";
VAL_ 264 VCU4_PA_DeceltorSts 1 "Not support" 0 "Support";
VAL_ 264 VCU4_PA_TargetTrqValueValidity 1 "Valid" 0 "Invalid";
VAL_ 264 VCU14_Gear_PACtrlAbortFeedback 4 "vehicle block（车辆无法移动）" 3 "Can not change gear" 2 "Driver intervene" 1 "Over speed" 0 "Normal";
VAL_ 264 VCU14_BMSSOCLowWarn 15 "Reserve" 10 "Reserve" 9 "18%提示纯电" 8 "9%提示纯电" 7 "5%提示纯电" 6 "0%提示纯电" 5 "18%提示增程" 4 "9%提示增程②" 3 "9%提示增程①" 2 "5%提示增程" 1 "0%提示增程" 0 "Default";
VAL_ 739 VCU3_AGS_PositionSts 4 "Reseved1" 3 "level3  大进风量" 2 "level2  小进风量" 1 "level1  无进风量" 0 "Invalid 无效";
VAL_ 739 VCU3_EPBBackupCtrlActv 1 "PDCS接管控制EPB卡钳" 0 "PDCS未接管控制EPB卡钳";
VAL_ 739 VCU3_TractionModeFailureReason 7 "Reserved3" 6 "Reserved2" 5 "充电枪插入导致牵引失败" 4 "其他原因" 3 "请先下高压电" 2 "未踩刹车" 1 "不在P档" 0 "Normal";
VAL_ 739 VCU3_TractionMode 1 "Traction Mode" 0 "Normal";
VAL_ 739 VCU3_EPBBackupCtrlSts 7 "Fault" 6 "Reserved" 5 "Resrved" 4 "Releasing in progress卡钳释放中" 3 "Clamping in progress卡钳夹紧中" 2 "Clamped卡钳夹紧" 1 "Released卡钳释放" 0 "No Control未备份控制";
VAL_ 1073 PDCS2_IBS_I_RANGE 3 "Invalid" 2 "-1500_1500A" 1 "-200_200A" 0 "-1_1A";
VAL_ 1073 PDCS2_IBS_Status_Current 3 "LIN saturation(no HW defect)" 2 "HW defect(out of ranger or ADC defect)" 1 "Error Open circuit" 0 "No Error";
VAL_ 1073 PDCS2_IBS_Status_Voltage 3 "LIN saturation(no HW defect)" 2 "HW defect(ADC defect)" 1 "Error Open circuit" 0 "No Error";
VAL_ 1073 PDCS2_IBS_Status_Temp 3 "LIN saturation(no HW defect)" 2 "HW defect(ADC defect)" 1 "not used" 0 "No Error";
VAL_ 1073 PDCS2_IBS_ERROR_Commom 1 "Error" 0 "No_error";
VAL_ 1073 PDCS2_IBS_LINRespErr 1 "Lin_Respone_Error" 0 "No_error";
VAL_ 1073 PDCS2_IBS_DisChargeCurrWU_Sts 1 "Enabled" 0 "Disabled";
VAL_ 1073 PDCS2_IBS_ChargeCurrWU_Sts 1 "Enabled" 0 "Disabled";
VAL_ 1073 PDCS2_IBS_SOCWU_Sts 1 "Enabled" 0 "Disabled";
VAL_ 1073 PDCS2_IBS_DisChargeCurrWU 1 "Wake Up with discharge current" 0 "No Wake Up with discharge current";
VAL_ 1073 PDCS2_IBS_ChargeCurrWU 1 "Wake Up with charge current" 0 "No Wake Up with discharge current";
VAL_ 1073 PDCS2_IBS_SOCWU 1 "Wake Up with Low SOC" 0 "NNo Wake Up with Low SOC";
VAL_ 1073 PDCS2_IBS_SOH_STATE 3 "invalid" 2 "deviation lower 10%" 1 "deviation lower 15%" 0 "deviation higher 15%";
VAL_ 1073 PDCS2_IBS_SOC_STATE 3 "invalid" 2 "deviation lower 10%" 1 "deviation lower 15%" 0 "deviation higher 15%";
VAL_ 1073 PDCS2_SOCWU_Ena 1 "Enabled" 0 "Disabled";
VAL_ 816 PDCS2_DisAeb 1 "故障发生" 0 "Default";
VAL_ 816 PDCS2_DisApa 1 "故障发生" 0 "Default";
VAL_ 816 PDCS2_VehSpdLimFgl 1 "故障发生" 0 "Default";
VAL_ 816 PDCS2_DisDcDc 1 "故障发生" 0 "Default";
VAL_ 816 PDCS2_DisRegen 1 "故障发生" 0 "Default";
VAL_ 816 PDCS2_DisCcs 1 "故障发生" 0 "Default";
VAL_ 816 PDCS2_DisAcc 1 "故障发生" 0 "Default";
VAL_ 816 PDCS2_DisMot 1 "故障发生" 0 "Default";
VAL_ 816 PDCS2_LimHomeFlg 1 "故障发生" 0 "Default";
VAL_ 816 PDCS2_PwrLimFlg 1 "故障发生" 0 "Default";
VAL_ 816 PDCS2_12VBatChrgePwrUpReq 1 "Request" 0 "No request";
VAL_ 816 PDCS2_12VBatChrgePwrDwnReq 1 "Request" 0 "No request";
VAL_ 816 PDCS2_HvPwrUpReq 1 "Request" 0 "No request";
VAL_ 816 PDCS2_HvPwrDwnReq 1 "Request" 0 "No request";
VAL_ 816 PDCS2_12VBatChargeExitReason 13 "IBSSocHigh" 12 "APAMode_Sentr" 11 "SOC DiffValue Out of rang(3%)" 10 "TailGateAjarOpen" 9 "EngRoomAjarOpen" 8 "BDM Remote Ignition off" 7 "Tbox request Exit" 6 "Charge Timeout" 5 "Crank" 4 "Charge Ignition on" 3 "HV Battery SOC low" 2 "DCDC Fault" 1 "HV not Ready" 0 "No fault";
VAL_ 816 PDCS2_entityID 6 "增程两驱HVM" 5 "纯电四驱HVM" 4 "纯电两驱HVM" 3 "增程两驱BMSEVE" 2 "增程两驱BMSCATL" 1 "纯电四驱BMS" 0 "纯电两驱BMS";
VAL_ 1172 MCU_u32ResetReson 65535 "Reserved" 17 "Reserved" 16 "诊断请求复位" 15 "Reserved" 14 "Reserved" 13 "Reserved" 12 "Reserved" 11 "Reserved" 10 "Reserved" 9 "Reserved" 8 "刷新复位" 7 "Reserved" 6 "Reserved" 5 "Reserved" 4 "硬件看门狗超时复位" 3 "Reserved" 2 "软件看门狗超时复位" 1 "硬件冷启动" 0 "Default";
VAL_ 1545 PDCS_RepeatMessageRequest 1 "Repeat message request" 0 "No repeat message request";
VAL_ 1545 PDCS_ActiveWakeup 1 "Wakeup" 0 "No wakeup";
VAL_ 1545 PDCS_WakeUp_KL15 1 "KL15 ON Wakeup" 0 "No Request";
VAL_ 1545 PDCS_WakeUp_NM 1 "NM Wakeup" 0 "No Request";
VAL_ 1545 PDCS_WakeUp_CC 1 "CC" 0 "No Request";
VAL_ 1545 PDCS_WakeUp_CP 1 "CP" 0 "No Request";
VAL_ 1545 PDCS_WakeUp_BMS 1 "BMS" 0 "No Request";
VAL_ 1545 PDCS_WakeUp_RTC 1 "RTC" 0 "No Request";
VAL_ 1545 PDCS_WakeUp_APLUS 1 "APLUS" 0 "No Request";
VAL_ 1545 PDCS_WakeUp_OBC 1 "OBC" 0 "No Request";
VAL_ 1545 PDCS_RepeatFromSleep 1 "occur" 0 "not occur";
VAL_ 1545 PDCS_RepeatFromPrepare 1 "occur" 0 "not occur";
VAL_ 1545 PDCS_NormalFromRepeat 1 "occur" 0 "not occur";
VAL_ 1545 PDCS_NormalFromReady 1 "occur" 0 "not occur";
VAL_ 1545 PDCS_RepeatFromReady 1 "occur" 0 "not occur";
VAL_ 1545 PDCS_RepeatFromNormal 1 "occur" 0 "not occur";
VAL_ 1545 PDCS_WakeUp_APP 1 "APP" 0 "No Request";
VAL_ 1545 PDCS_WakeUp_DIAG 1 "DIAG" 0 "No Request";
VAL_ 1545 PDCS_WakeUp_LIN 1 "LIN" 0 "No Request";
VAL_ 1545 PDCS_Request_APP 3 "Sleep or overflow" 2 "Reserved" 1 "APP_SHUTDOWN" 0 "APP_NORMAL";
VAL_ 964 VCU_LEARN_SK_RC 50 "VCU未学习，没有 PIN" 82 "VCU已学习过 PIN，但PIN不匹配" 81 "VCU已学习过 SK，但SK不匹配" 17 "由于未知原因，请求未执行" 49 "VCU未学习，没有 SK" 113 "由于PIN不匹配，请求未执行" 16 "请求不支持" 66 "VCU已学习过 PIN" 65 "VCU已学习过 SK" 97 "SK或PIN校验和错误" 33 "VCU忙碌" 0 "VCU已经完成相应请求";
VAL_ 966 VCU_LEARN_PIN_RC 50 "VCU未学习，没有 PIN" 82 "VCU已学习过 PIN，但PIN不匹配" 81 "VCU已学习过 SK，但SK不匹配" 17 "由于未知原因，请求未执行" 49 "VCU未学习，没有 SK" 113 "由于PIN不匹配，请求未执行" 16 "请求不支持" 66 "VCU已学习过 PIN" 65 "VCU已学习过 SK" 97 "SK或PIN校验和错误" 33 "VCU忙碌" 0 "VCU已经完成相应请求";
VAL_ 970 VCU_RES_RC 50 "VCU未学习，没有 PIN" 82 "VCU已学习过 PIN，但PIN不匹配" 81 "VCU已学习过 SK，但SK不匹配" 17 "由于未知原因，请求未执行" 49 "VCU未学习，没有 SK" 113 "由于PIN不匹配，请求未执行" 16 "请求不支持" 66 "VCU已学习过 PIN" 65 "VCU已学习过 SK" 97 "SK或PIN校验和错误" 33 "VCU忙碌" 0 "VCU已经完成相应请求";
VAL_ 246 BMS6_Sts 1 "Battery ready" 0 "Battery not ready";
VAL_ 246 BMS6_Enable_request 1 "request" 0 "no request";
VAL_ 246 BMS6_ControlHVDischarge 2 "HV Down request" 1 "HV Up request" 0 "no request";
VAL_ 246 BMS6_WorkingMode 7 "Power off cooling" 6 "Battery warm" 5 "External discharge" 4 "DC charging" 3 "AC charging" 2 "Discharge" 1 "Standby" 0 "No mode";
VAL_ 246 BMS6_PosBattContSts 3 "stuck" 2 "adhesion" 1 "Connect" 0 "Disconnect";
VAL_ 246 BMS6_NegBattContSts 3 "stuck" 2 "adhesion" 1 "Connect" 0 "Disconnect";
VAL_ 246 BMS6_PrechargeContSts 3 "stuck" 2 "adhesion" 1 "Connect" 0 "Disconnect";
VAL_ 246 BMS6_DCChargeContSts 3 "stuck" 2 "adhesion" 1 "Connect" 0 "Disconnect";
VAL_ 246 BMS6_PrechargeSts 3 "PrechargeFailed" 2 "PrechargeSuccess" 1 "Precharging" 0 "Disconnect";
VAL_ 246 BMS6_InterlockSts 1 "fault" 0 "Normal";
VAL_ 246 BMS6_ThermalDiffusion 1 "fault" 0 "Normal";
VAL_ 246 BMS6_CellOverTempSts 1 "fault" 0 "Normal";
VAL_ 246 BMS6_CellUnderTempSts 1 "fault" 0 "Normal";
VAL_ 246 BMS6_CellOverVoltageSts 1 "fault" 0 "Normal";
VAL_ 246 BMS6_CellUnderVoltageSts 1 "fault" 0 "Normal";
VAL_ 246 BMS6_OverVoltageSts 1 "fault" 0 "Normal";
VAL_ 246 BMS6_UnderVoltageSts 1 "fault" 0 "Normal";
VAL_ 246 BMS6_UnderSOCSts 1 "fault" 0 "Normal";
VAL_ 246 BMS6_BattOverSoc 1 "fault" 0 "Normal";
VAL_ 246 BMS6_BattSocJump 1 "fault" 0 "Normal";
VAL_ 246 BMS6_BattOverCharging 1 "fault" 0 "Normal";
VAL_ 246 BMS6_BattMismatching 1 "fault" 0 "Normal";
VAL_ 246 BMS6_OverCurrentSts 1 "fault" 0 "Normal";
VAL_ 246 BMS6_IsolSuperSts 1 "fault" 0 "Normal";
VAL_ 246 BMS6_TempDiffSts 1 "fault" 0 "Normal";
VAL_ 246 BMS6_DiagSts 1 "fault" 0 "Normal";
VAL_ 246 BMS6_CellConsistencySts 1 "fault" 0 "Normal";
VAL_ 246 BMS6_DCChargeNegContSts 3 "Stuck" 2 "Adhesion" 1 "Connect" 0 "Disconnect";
VAL_ 246 BMS6_ElectromagneticLockCtrl 3 "Reserved" 2 "Unlock_解锁" 1 "Lock_闭锁" 0 "NoReqLock_不请求";
VAL_ 246 BMS6_MILSts 1 "fault" 0 "Normal";
VAL_ 246 BMS6_TempRiseFast_Flt 1 "fault" 0 "Normal";
VAL_ 246 BMS6_dischgActiveFltCategory 8 "Grade 8" 7 "Grade 7" 6 "Grade 6" 5 "Grade 5" 4 "Grade 4" 3 "Grade 3" 2 "Grade 2" 1 "Grade 1" 0 "Default";
VAL_ 246 BMS6_chgActiveFltCategory 8 "Grade 8" 7 "Grade 7" 6 "Grade 6" 5 "Grade 5" 4 "Grade 4" 3 "Grade 3" 2 "Grade 2" 1 "Grade 1" 0 "Default";
VAL_ 600 BMS3_ChrgGunCnctLi 4 "CMConnect Unbelievable" 3 "DCM Connect" 2 "FCM Connect" 1 "CM Connect" 0 "Disconnect";
VAL_ 600 BMS3_Lowbattery 1 "On" 0 "Off";
VAL_ 600 BMS3_Charge_State 8 "Charge Achieved" 7 "Chager Fault" 6 "Charge Stop" 5 "Heat preservation" 4 "Heating while charging" 3 "Heating" 2 "Fast Charging" 1 "Slow Charging" 0 "Normal";
VAL_ 600 BMS3_ACChrgImmediatEna 1 "Enable" 0 "Disable";
VAL_ 600 BMS3_ACChrgImmediatEnaFb 1 "Enable" 0 "Disable";
VAL_ 600 BMS3_FloatingChargeWarn 1 "Request" 0 "NO Request";
VAL_ 600 BMS3_FloatingChargeState 1 "Enable" 0 "Disable";
VAL_ 136 BMS1_BatteryState 1 "Connected" 0 "Disconnect";
VAL_ 136 BMS1_DCChrgPostvVoltCtrl 3 "Reserved" 2 "Disconnected（断开）" 1 "Connected（连接）" 0 "Default（默认值）";
VAL_ 136 BMS1_DCChrgNegVoltCtrl 3 "Reserved" 2 "Disconnected（断开）" 1 "Connected（连接）" 0 "Default（默认值）";
VAL_ 631 BMS7_BattWtrInTReqV 1 "valid" 0 "inviald";
VAL_ 631 BMS7_power_request 5 "resever" 4 "normal power" 3 "max power" 2 "Medium power" 1 "lowe power" 0 "no request";
VAL_ 631 BMS7_Thermal_manage_status 7 "fault" 6 "reveser" 5 "heating finish" 4 "cooling finsh" 3 "thermal balance" 2 "heating" 1 "cooling" 0 "defaut";
VAL_ 631 BMS7_CLM_HVThermalReq 3 "Heating request" 2 "Cooling request" 1 "Circular request" 0 "No request";
VAL_ 632 BMS8_PowerBattMaintainLightReq 1 "Lamp ON" 0 "Lamp OFF";
VAL_ 632 BMS8_PowerBattDisconnettWarnLight 1 "Lamp ON" 0 "Lamp OFF";
VAL_ 632 BMS8_RemoteChargeSts 1 "Start" 0 "Stop";
VAL_ 632 BMS8_ChargeAppointmentEnable 1 "Enable" 0 "Disable";
VAL_ 632 BMS8_ChargeModeChangeInfo 3 "Setup failed" 2 "长续航设置成功" 1 "长寿命设置成功" 0 "default";
VAL_ 632 BMS8_ThermalReqfail 1 "On" 0 "Off";
VAL_ 632 BMS8_ChargeWakeupBMS 1 "On" 0 "Off";
VAL_ 632 BMS8_SOCWarningLightSts 1 "Lamp ON" 0 "Lamp OFF";
VAL_ 632 BMS8_InsulationFaultLightControl 1 "Lamp ON" 0 "Lamp OFF";
VAL_ 632 BMS8_BatterFaultLightControl 1 "Lamp ON" 0 "Lamp OFF";
VAL_ 632 BMS8_Dailyusereminder 10 "慢充连接断开提示" 9 "电池充电故障提示" 8 "电池制冷失效提示" 7 "压差故障提示" 6 "欠压过放提示" 5 "过放提示" 4 "满充提示" 3 "充电过流提示" 2 "使用交流充电提示" 1 "使用长寿命提示" 0 "Normal";
VAL_ 666 BMS10_PowrDwonReq 2 "resevered" 1 "Request sleep" 0 "default value";
VAL_ 666 BMS10_ChrgEnable 3 "resevered" 2 "end of charge" 1 "enable" 0 "default value";
VAL_ 666 BMS10_DischargeWorkSts 7 "invalid3" 6 "invalid2" 5 "invalid1" 4 "Use error" 3 "Fault" 2 "Finished" 1 "Active" 0 "Inactive";
VAL_ 666 BMS10_DischargeMainSts 1 "On" 0 "Off";
VAL_ 666 BMS10_DischargeObejectSelectFb 2 "V2V" 1 "V2L" 0 "default value";
VAL_ 666 BMS10_DischargeModeSelectFb 2 "三相设备" 1 "单相设备" 0 "default value";
VAL_ 666 BMS10_RequestOutputMode 3 "Inverting" 2 "Heating" 1 "charging" 0 "Disconnect";
VAL_ 745 BMS9_FCType 2 "恒流" 1 "恒压" 0 "未直流充电";
VAL_ 745 BMS9_FCSotp 6 "resevered" 5 "vehicle active stop" 4 "Battery Full stop" 3 "Battery failure stop" 2 "Charger failure stop" 1 "Charger active stop" 0 "no Charger";
VAL_ 1540 BMS_RepeatMessageRequest 1 "Repeat message request" 0 "No repeat message request";
VAL_ 1540 BMS_ActiveWakeup 1 "Wakeup" 0 "No wakeup";
VAL_ 1540 BMS_WakeUp_KL15 1 "KL15 Wakeup" 0 "No Request";
VAL_ 1540 BMS_WakeUp_NM 1 "NM Wakeup" 0 "No Request";
VAL_ 1540 BMS_WakeUp_ThermalDiffusion 1 "Thermal_Diffusion" 0 "No Request";
VAL_ 1540 BMS_WakeUpReason4 1 "Wakeup Requrst" 0 "No Request";
VAL_ 1540 BMS_WakeUpReason5 1 "Wakeup Requrst" 0 "No Request";
VAL_ 1540 BMS_WakeUp_PreCharge 1 "PreCharge Wakeup" 0 "No Request";
VAL_ 1540 BMS_WakeUp_OTA 1 "OTA Wakeup" 0 "No Request";
VAL_ 1540 BMS_WakeUp_OverAmTemp 1 "Over Temp" 0 "No Request";
VAL_ 1540 BMS_RepeatFromSleep 1 "occur" 0 "not occur";
VAL_ 1540 BMS_RepeatFromPrepare 1 "occur" 0 "not occur";
VAL_ 1540 BMS_NormalFromRepeat 1 "occur" 0 "not occur";
VAL_ 1540 BMS_NormalFromReady 1 "occur" 0 "not occur";
VAL_ 1540 BMS_RepeatFromReady 1 "occur" 0 "not occur";
VAL_ 1540 BMS_RepeatFromNormal 1 "occur" 0 "not occur";
VAL_ 1540 BMS_RemainNetworkWakeUpReason1 1 "Remain wakeup reason" 0 "default";
VAL_ 1540 BMS_RemainNetworkWakeUpReason2 1 "Remain wakeup reason" 0 "default";
VAL_ 1540 BMS_RemainNetworkWakeUpReason3 1 "Remain wakeup reason" 0 "default";
VAL_ 1540 BMS_RemainNetworkWakeUpReason4 1 "Remain wakeup reason" 0 "default";
VAL_ 1540 BMS_RemainNetworkWakeUpReason5 1 "Remain wakeup reason" 0 "default";
VAL_ 1540 BMS_RemainNetworkWakeUpReason6 1 "Remain wakeup reason" 0 "default";
VAL_ 1540 BMS_RemainNetworkWakeUpReason7 1 "Remain wakeup reason" 0 "default";
VAL_ 1540 BMS_RemainNetworkWakeUpReason8 1 "Remain wakeup reason" 0 "default";
VAL_ 1540 BMS_RemainNetworkWakeUpReason9 1 "Remain wakeup reason" 0 "default";
VAL_ 1540 BMS_RemainNetworkWakeUpReason10 1 "Remain wakeup reason" 0 "default";
VAL_ 170 MCU1_Mode 7 "Discharge mode" 6 "Zero torque mode" 5 "Speed mode" 4 "Reverse drive mode" 3 "Forward drive mode" 2 "Brake mode" 1 "Failure mode" 0 "Off";
VAL_ 170 MCU1_ControllerTorqueValid 1 "Invalid" 0 "Valid";
VAL_ 170 MCU1_TorMonitorFault 1 "fault" 0 "Not fault";
VAL_ 170 MCU1_CurrentTorqueValid 1 "Invalid" 0 "Valid";
VERSION ""

NS_ :

BS_:

BU_: GW_FD5 GW_FD6 GW_FD3 GW_FD4 GW_FD1 GW_FD2 PDCS_FD1 PDCU SRR3 SRR4 ADCU_FD3 BDCS DDCU CDCS ADCS_FD3 CDCS_OverSea TBOX FLC_ME_FD3 FLC_FD3 ICU_E02 ICU PDCS_HVM_FD1 TBOX_OverSea BMS ISC GCU EMS IDB ESC_FD3 EHB_FD3 MCU IMU ACU EPS WPC CDU AMP BAM PDCS_FD3 EVCC REPB ADCS_FD6 ADCU_FD6 FLC_ME_FD6 FLC_FD6 DLC GW_FD7 ESC_FD6 EHB_FD6

BO_ 267 MCU_Fr02_10B: 8 MCU
 SG_ MCU2_MilLampRequest : 0|1@0+ (1,0) [0|1] "NoUnit" EMS
 SG_ MCU2_Fault_Level : 2|2@0+ (1,0) [0|3] "NoUnit" PDCS_FD1,TBOX,GW_FD5,ICU_E02,GW_FD4,ICU,CDCS,PDCS_HVM_FD1,CDCS_OverSea,TBOX_OverSea
 SG_ MCU2_MotorFaultLampRequest : 3|1@0+ (1,0) [0|1] "NoUnit" PDCS_FD1,TBOX,GW_FD5,ICU_E02,GW_FD4,ICU,CDCS,PDCS_HVM_FD1,CDCS_OverSea,TBOX_OverSea
 SG_ MCU2_Motor_Block_Warning : 4|1@0+ (1,0) [0|1] "NoUnit" PDCS_FD1,TBOX,GW_FD5,GW_FD4,CDCS,PDCS_HVM_FD1,CDCS_OverSea,TBOX_OverSea
 SG_ MCU2_OpenProtion_Lock_Fault : 5|1@0+ (1,0) [0|1] "NoUnit" PDCS_FD1,TBOX,GW_FD5,PDCS_HVM_FD1,TBOX_OverSea
 SG_ MCU2_Cooling_System_Fault : 6|1@0+ (1,0) [0|1] "NoUnit" PDCS_FD1,TBOX,GW_FD5,GW_FD4,CDCS,PDCS_HVM_FD1,CDCS_OverSea,TBOX_OverSea
 SG_ MCU2_Self_check_Fault : 7|1@0+ (1,0) [0|1] "NoUnit" PDCS_FD1,TBOX,GW_FD5,GW_FD4,CDCS,PDCS_HVM_FD1,CDCS_OverSea,TBOX_OverSea
 SG_ MCU2_Sensor_Check_Fault : 12|1@0+ (1,0) [0|1] "NoUnit" PDCS_FD1,TBOX,GW_FD5,GW_FD4,CDCS,PDCS_HVM_FD1,CDCS_OverSea,TBOX_OverSea
 SG_ MCU2_Battery_Check_Fault : 13|1@0+ (1,0) [0|1] "NoUnit" PDCS_FD1,TBOX,GW_FD5,GW_FD4,CDCS,PDCS_HVM_FD1,CDCS_OverSea,TBOX_OverSea
 SG_ MCU2_Motor_Lack_of_Phase_Fault : 14|1@0+ (1,0) [0|1] "NoUnit" PDCS_FD1,TBOX,GW_FD5,GW_FD4,CDCS,PDCS_HVM_FD1,CDCS_OverSea,TBOX_OverSea
 SG_ MCU2_RDC_Alignment_Fault : 15|1@0+ (1,0) [0|1] "NoUnit" PDCS_FD1,TBOX,GW_FD5,GW_FD4,CDCS,PDCS_HVM_FD1,CDCS_OverSea,TBOX_OverSea
 SG_ MCU2_DampingTq : 23|16@0+ (0.05,-300) [-300|300] "Nm" PDCS_FD1,TBOX,GW_FD5,GW_FD4,CDCS,PDCS_HVM_FD1,CDCS_OverSea,TBOX_OverSea
 SG_ MCU2_PhaseOvercurrentFault : 32|1@0+ (1,0) [0|1] "NoUnit" PDCS_FD1,TBOX,GW_FD5,GW_FD4,CDCS,PDCS_HVM_FD1,CDCS_OverSea,TBOX_OverSea
 SG_ MCU2_InverterFault : 33|1@0+ (1,0) [0|1] "NoUnit" PDCS_FD1,TBOX,GW_FD5,GW_FD4,CDCS,PDCS_HVM_FD1,CDCS_OverSea,TBOX_OverSea
 SG_ MCU2_SensorSupplyVoltageFault : 39|1@0+ (1,0) [0|1] "NoUnit" PDCS_FD1,TBOX,GW_FD5,GW_FD4,CDCS,PDCS_HVM_FD1,CDCS_OverSea,TBOX_OverSea
 SG_ MCU2_DC_link_OvercurrentFault : 40|1@0+ (1,0) [0|1] "NoUnit" PDCS_FD1,TBOX,GW_FD5,GW_FD4,CDCS,PDCS_HVM_FD1,CDCS_OverSea,TBOX_OverSea
 SG_ MCU2_GateDriverDesaturationFault : 41|1@0+ (1,0) [0|1] "NoUnit" PDCS_FD1,TBOX,GW_FD5,GW_FD4,CDCS,PDCS_HVM_FD1,CDCS_OverSea,TBOX_OverSea
 SG_ MCU2_MotorPositionSensorFault : 42|1@0+ (1,0) [0|1] "NoUnit" PDCS_FD1,TBOX,GW_FD5,GW_FD4,CDCS,PDCS_HVM_FD1,CDCS_OverSea,TBOX_OverSea
 SG_ MCU2_DischargeOverTime : 43|1@0+ (1,0) [0|1] "NoUnit" PDCS_FD1,TBOX,GW_FD5,GW_FD4,CDCS,PDCS_HVM_FD1,CDCS_OverSea,TBOX_OverSea
 SG_ MCU2_SumPhaseCurrentOverThd : 44|1@0+ (1,0) [0|1] "NoUnit" PDCS_FD1,TBOX,GW_FD5,GW_FD4,CDCS,PDCS_HVM_FD1,CDCS_OverSea,TBOX_OverSea
 SG_ MCU2_MotorOvertempFault : 46|2@0+ (1,0) [0|3] "NoUnit" PDCS_FD1,TBOX,GW_FD5,ICU_E02,GW_FD4,ICU,CDCS,PDCS_HVM_FD1,CDCS_OverSea,TBOX_OverSea
 SG_ MCU2_A_phase_OvercurrWarn : 47|1@0+ (1,0) [0|1] "NoUnit" PDCS_FD1,TBOX,GW_FD5,GW_FD4,CDCS,PDCS_HVM_FD1,CDCS_OverSea,TBOX_OverSea
 SG_ MCU2_B_phase_OvercurrWarn : 48|1@0+ (1,0) [0|1] "NoUnit" PDCS_FD1,TBOX,GW_FD5,GW_FD4,CDCS,PDCS_HVM_FD1,CDCS_OverSea,TBOX_OverSea
 SG_ MCU2_C_phase_OvercurrentWarning : 49|1@0+ (1,0) [0|1] "NoUnit" PDCS_FD1,TBOX,GW_FD5,GW_FD4,CDCS,PDCS_HVM_FD1,CDCS_OverSea,TBOX_OverSea
 SG_ MCU2_InverterOvertempFault : 51|2@0+ (1,0) [0|3] "NoUnit" PDCS_FD1,TBOX,GW_FD5,ICU_E02,GW_FD4,ICU,CDCS,PDCS_HVM_FD1,CDCS_OverSea,TBOX_OverSea
 SG_ MCU2_Rx_CAN_Failed : 52|1@0+ (1,0) [0|1] "NoUnit" PDCS_FD1,TBOX,GW_FD5,GW_FD4,CDCS,PDCS_HVM_FD1,CDCS_OverSea,TBOX_OverSea
 SG_ MCU2_LV_PowerSupplyFault : 53|1@0+ (1,0) [0|1] "NoUnit" PDCS_FD1,TBOX,GW_FD5,GW_FD4,CDCS,PDCS_HVM_FD1,CDCS_OverSea,TBOX_OverSea
 SG_ MCU2_IgnSts_Dev : 54|1@0+ (1,0) [0|1] "NoUnit" TBOX,GW_FD5,TBOX_OverSea
 SG_ MCU2_HV_Battery_Connect_states : 55|1@0+ (1,0) [0|1] "NoUnit" PDCS_FD1,TBOX,GW_FD5,GW_FD4,CDCS,PDCS_HVM_FD1,CDCS_OverSea,TBOX_OverSea
 SG_ MCU2_VCU_Inverter_states : 56|1@0+ (1,0) [0|1] "NoUnit" PDCS_FD1,TBOX,GW_FD5,PDCS_HVM_FD1,TBOX_OverSea
 SG_ MCU2_SafetyFault : 57|1@0+ (1,0) [0|1] "NoUnit" PDCS_FD1,TBOX,GW_FD5,GW_FD4,CDCS,PDCS_HVM_FD1,CDCS_OverSea,TBOX_OverSea
 SG_ MCU2_ModeError : 58|1@0+ (1,0) [0|1] "NoUnit" PDCS_FD1,TBOX,GW_FD5,GW_FD4,CDCS,PDCS_HVM_FD1,CDCS_OverSea,TBOX_OverSea
 SG_ MCU2_GateDriverVoltageSupplyFault : 59|1@0+ (1,0) [0|1] "NoUnit" PDCS_FD1,TBOX,GW_FD5,GW_FD4,CDCS,PDCS_HVM_FD1,CDCS_OverSea,TBOX_OverSea
 SG_ MCU2_Fr02_AliveCounter : 63|4@0+ (1,0) [0|15] "NoUnit" PDCS_FD1,TBOX,GW_FD5,GW_FD4,CDCS,PDCS_HVM_FD1,CDCS_OverSea,TBOX_OverSea

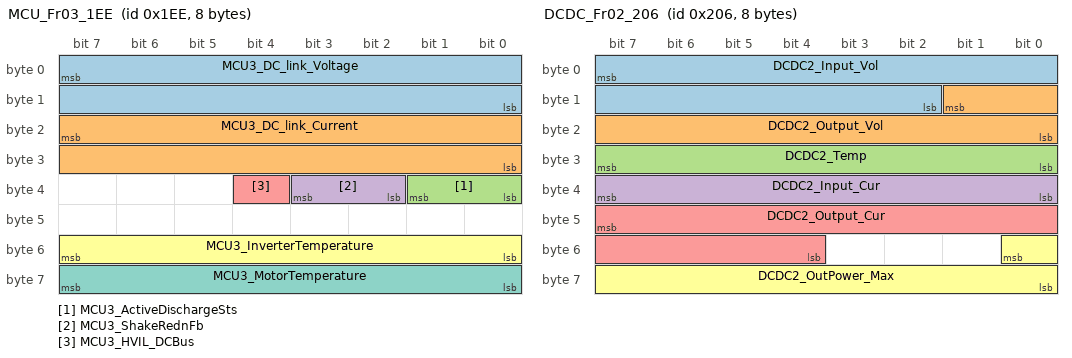
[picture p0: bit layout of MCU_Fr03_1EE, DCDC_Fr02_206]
BO_ 494 MCU_Fr03_1EE: 8 MCU
 SG_ MCU3_DC_link_Voltage : 7|16@0+ (0.05,0) [0|1200] "V" PDCS_FD1,TBOX,GW_FD5,BMS,GW_FD4,GW_FD2,BDCS,CDCS,PDCS_HVM_FD1,CDCS_OverSea,TBOX_OverSea
 SG_ MCU3_DC_link_Current : 23|16@0+ (0.05,-1000) [-1000|1000] "A" PDCS_FD1,TBOX,GW_FD5,BMS,GW_FD4,GW_FD2,BDCS,CDCS,PDCS_HVM_FD1,CDCS_OverSea,TBOX_OverSea
 SG_ MCU3_ActiveDischargeSts : 33|2@0+ (1,0) [0|3] "NoUnit" PDCS_FD1,TBOX,GW_FD5,BMS,PDCS_HVM_FD1,TBOX_OverSea
 SG_ MCU3_ShakeRednFb : 35|2@0+ (1,0) [0|3] "NoUnit" PDCS_FD1,TBOX,GW_FD5,PDCS_HVM_FD1,TBOX_OverSea
 SG_ MCU3_HVIL_DCBus : 36|1@0+ (1,0) [0|1] "NoUnit" PDCS_FD1,TBOX,GW_FD5,PDCS_HVM_FD1,TBOX_OverSea
 SG_ MCU3_InverterTemperature : 55|8@0+ (1,-48) [-48|206] "" PDCS_FD1,TBOX,GW_FD5,GW_FD4,GW_FD2,BDCS,CDCS,PDCS_HVM_FD1,CDCS_OverSea,TBOX_OverSea
 SG_ MCU3_MotorTemperature : 63|8@0+ (1,-48) [-48|206] "" PDCS_FD1,TBOX,GW_FD5,GW_FD4,GW_FD2,BDCS,CDCS,PDCS_HVM_FD1,CDCS_OverSea,TBOX_OverSea

BO_ 735 MCU_Fr04_2DF: 8 MCU
 SG_ MCU4_AlOfsNoPlaus : 0|1@0+ (1,0) [0|1] "NoUnit" PDCS_FD1,TBOX,GW_FD5,PDCS_HVM_FD1,TBOX_OverSea
 SG_ MCU4_Can_BusOff : 1|1@0+ (1,0) [0|1] "NoUnit" PDCS_FD1,TBOX,GW_FD5,PDCS_HVM_FD1,TBOX_OverSea
 SG_ MCU4_IUMonOvHiRng : 4|1@0+ (1,0) [0|1] "NoUnit" PDCS_FD1,TBOX,GW_FD5,PDCS_HVM_FD1,TBOX_OverSea
 SG_ MCU4_IUMonOvLoRng : 5|1@0+ (1,0) [0|1] "NoUnit" PDCS_FD1,TBOX,GW_FD5,PDCS_HVM_FD1,TBOX_OverSea
 SG_ MCU4_IUOc : 6|1@0+ (1,0) [0|1] "NoUnit" PDCS_FD1,TBOX,GW_FD5,PDCS_HVM_FD1,TBOX_OverSea
 SG_ MCU4_IUOvHiRng : 7|1@0+ (1,0) [0|1] "NoUnit" PDCS_FD1,TBOX,GW_FD5,PDCS_HVM_FD1,TBOX_OverSea
 SG_ MCU4_IUOvLoRng : 8|1@0+ (1,0) [0|1] "NoUnit" PDCS_FD1,TBOX,GW_FD5,PDCS_HVM_FD1,TBOX_OverSea
 SG_ MCU4_IVMonOvHiRng : 9|1@0+ (1,0) [0|1] "NoUnit" PDCS_FD1,TBOX,GW_FD5,PDCS_HVM_FD1,TBOX_OverSea
 SG_ MCU4_IVMonOvLoRng : 10|1@0+ (1,0) [0|1] "NoUnit" PDCS_FD1,TBOX,GW_FD5,PDCS_HVM_FD1,TBOX_OverSea
 SG_ MCU4_IVOc : 11|1@0+ (1,0) [0|1] "NoUnit" PDCS_FD1,TBOX,GW_FD5,PDCS_HVM_FD1,TBOX_OverSea
 SG_ MCU4_IVOvHiRng : 12|1@0+ (1,0) [0|1] "NoUnit" PDCS_FD1,TBOX,GW_FD5,PDCS_HVM_FD1,TBOX_OverSea
 SG_ MCU4_IVOvLoRng : 13|1@0+ (1,0) [0|1] "NoUnit" PDCS_FD1,TBOX,GW_FD5,PDCS_HVM_FD1,TBOX_OverSea
 SG_ MCU4_IWMonOvHiRng : 14|1@0+ (1,0) [0|1] "NoUnit" PDCS_FD1,TBOX,GW_FD5,PDCS_HVM_FD1,TBOX_OverSea
 SG_ MCU4_IWMonOvLoRng : 15|1@0+ (1,0) [0|1] "NoUnit" PDCS_FD1,TBOX,GW_FD5,PDCS_HVM_FD1,TBOX_OverSea
 SG_ MCU4_IWOc : 16|1@0+ (1,0) [0|1] "NoUnit" PDCS_FD1,TBOX,GW_FD5,PDCS_HVM_FD1,TBOX_OverSea
 SG_ MCU4_IWOvHiRng : 17|1@0+ (1,0) [0|1] "NoUnit" PDCS_FD1,TBOX,GW_FD5,PDCS_HVM_FD1,TBOX_OverSea
 SG_ MCU4_IWOvLoRng : 18|1@0+ (1,0) [0|1] "NoUnit" PDCS_FD1,TBOX,GW_FD5,PDCS_HVM_FD1,TBOX_OverSea
 SG_ MCU4_IphaOC : 19|1@0+ (1,0) [0|1] "NoUnit" PDCS_FD1,TBOX,GW_FD5,PDCS_HVM_FD1,TBOX_OverSea
 SG_ MCU4_IphaOffCal : 20|1@0+ (1,0) [0|1] "NoUnit" PDCS_FD1,TBOX,GW_FD5,PDCS_HVM_FD1,TBOX_OverSea
 SG_ MCU4_MosTHiRng : 21|1@0+ (1,0) [0|1] "NoUnit" PDCS_FD1,TBOX,GW_FD5,PDCS_HVM_FD1,TBOX_OverSea
 SG_ MCU4_NFltHA : 22|1@0+ (1,0) [0|1] "NoUnit" PDCS_FD1,TBOX,GW_FD5,PDCS_HVM_FD1,TBOX_OverSea
 SG_ MCU4_NFltHB : 23|1@0+ (1,0) [0|1] "NoUnit" PDCS_FD1,TBOX,GW_FD5,PDCS_HVM_FD1,TBOX_OverSea
 SG_ MCU4_NFltLA : 24|1@0+ (1,0) [0|1] "NoUnit" PDCS_FD1,TBOX,GW_FD5,PDCS_HVM_FD1,TBOX_OverSea
 SG_ MCU4_NFltLB : 25|1@0+ (1,0) [0|1] "NoUnit" PDCS_FD1,TBOX,GW_FD5,PDCS_HVM_FD1,TBOX_OverSea
 SG_ MCU4_RslvDos : 26|1@0+ (1,0) [0|1] "NoUnit" PDCS_FD1,TBOX,GW_FD5,PDCS_HVM_FD1,TBOX_OverSea
 SG_ MCU4_RslvLos : 27|1@0+ (1,0) [0|1] "NoUnit" PDCS_FD1,TBOX,GW_FD5,PDCS_HVM_FD1,TBOX_OverSea
 SG_ MCU4_RslvLot : 28|1@0+ (1,0) [0|1] "NoUnit" PDCS_FD1,TBOX,GW_FD5,PDCS_HVM_FD1,TBOX_OverSea
 SG_ MCU4_HwPhaCurPosBackErr : 30|1@0+ (1,0) [0|1] "NoUnit" PDCS_FD1,TBOX,GW_FD5,PDCS_HVM_FD1,TBOX_OverSea
 SG_ MCU4_HwPhaCurNegBackErr : 31|1@0+ (1,0) [0|1] "NoUnit" PDCS_FD1,TBOX,GW_FD5,PDCS_HVM_FD1,TBOX_OverSea
 SG_ MCU4_TSttr1OvHiLim : 33|1@0+ (1,0) [0|1] "NoUnit" PDCS_FD1,TBOX,GW_FD5,PDCS_HVM_FD1,TBOX_OverSea
 SG_ MCU4_TSttr1OvLoLim : 34|1@0+ (1,0) [0|1] "NoUnit" PDCS_FD1,TBOX,GW_FD5,PDCS_HVM_FD1,TBOX_OverSea
 SG_ MCU4_TSttr2OvHiLim : 35|1@0+ (1,0) [0|1] "NoUnit" PDCS_FD1,TBOX,GW_FD5,PDCS_HVM_FD1,TBOX_OverSea
 SG_ MCU4_TSttr2OvLoLim : 36|1@0+ (1,0) [0|1] "NoUnit" PDCS_FD1,TBOX,GW_FD5,PDCS_HVM_FD1,TBOX_OverSea
 SG_ MCU4_TUErrOff : 37|1@0+ (1,0) [0|1] "NoUnit" PDCS_FD1,TBOX,GW_FD5,PDCS_HVM_FD1,TBOX_OverSea
 SG_ MCU4_TVErrOff : 38|1@0+ (1,0) [0|1] "NoUnit" PDCS_FD1,TBOX,GW_FD5,PDCS_HVM_FD1,TBOX_OverSea
 SG_ MCU4_TWErrOff : 39|1@0+ (1,0) [0|1] "NoUnit" PDCS_FD1,TBOX,GW_FD5,PDCS_HVM_FD1,TBOX_OverSea
 SG_ MCU4_tDBCTempUHiLom : 40|1@0+ (1,0) [0|1] "NoUnit" PDCS_FD1,TBOX,GW_FD5,PDCS_HVM_FD1,TBOX_OverSea
 SG_ MCU4_tDBCTempULoLom : 41|1@0+ (1,0) [0|1] "NoUnit" PDCS_FD1,TBOX,GW_FD5,PDCS_HVM_FD1,TBOX_OverSea
 SG_ MCU4_tDBCTempVHiLom : 42|1@0+ (1,0) [0|1] "NoUnit" PDCS_FD1,TBOX,GW_FD5,PDCS_HVM_FD1,TBOX_OverSea
 SG_ MCU4_tDBCTempVLoLom : 43|1@0+ (1,0) [0|1] "NoUnit" PDCS_FD1,TBOX,GW_FD5,PDCS_HVM_FD1,TBOX_OverSea
 SG_ MCU4_tDBCTempWHiLom : 44|1@0+ (1,0) [0|1] "NoUnit" PDCS_FD1,TBOX,GW_FD5,PDCS_HVM_FD1,TBOX_OverSea
 SG_ MCU4_tDBCTempWLoLom : 45|1@0+ (1,0) [0|1] "NoUnit" PDCS_FD1,TBOX,GW_FD5,PDCS_HVM_FD1,TBOX_OverSea
 SG_ MCU4_QtShrGnd : 46|1@0+ (1,0) [0|1] "NoUnit" PDCS_FD1,TBOX,GW_FD5,PDCS_HVM_FD1,TBOX_OverSea
 SG_ MCU4_SttrTemp1ShrGnd : 47|1@0+ (1,0) [0|1] "NoUnit" PDCS_FD1,TBOX,GW_FD5,PDCS_HVM_FD1,TBOX_OverSea
 SG_ MCU4_SttrTemp2ShrGnd : 48|1@0+ (1,0) [0|1] "NoUnit" PDCS_FD1,TBOX,GW_FD5,PDCS_HVM_FD1,TBOX_OverSea
 SG_ MCU4_UMonShrGnd : 49|1@0+ (1,0) [0|1] "NoUnit" PDCS_FD1,TBOX,GW_FD5,PDCS_HVM_FD1,TBOX_OverSea
 SG_ MCU4_VMonShrGnd : 50|1@0+ (1,0) [0|1] "NoUnit" PDCS_FD1,TBOX,GW_FD5,PDCS_HVM_FD1,TBOX_OverSea
 SG_ MCU4_WMonShrGnd : 51|1@0+ (1,0) [0|1] "NoUnit" PDCS_FD1,TBOX,GW_FD5,PDCS_HVM_FD1,TBOX_OverSea
 SG_ MCU4_UShrGnd : 52|1@0+ (1,0) [0|1] "NoUnit" PDCS_FD1,TBOX,GW_FD5,PDCS_HVM_FD1,TBOX_OverSea
 SG_ MCU4_VShrGnd : 53|1@0+ (1,0) [0|1] "NoUnit" PDCS_FD1,TBOX,GW_FD5,PDCS_HVM_FD1,TBOX_OverSea
 SG_ MCU4_WShrGnd : 54|1@0+ (1,0) [0|1] "NoUnit" PDCS_FD1,TBOX,GW_FD5,PDCS_HVM_FD1,TBOX_OverSea
 SG_ MCU4_UKl30Ov : 55|1@0+ (1,0) [0|1] "NoUnit" PDCS_FD1,TBOX,GW_FD5,PDCS_HVM_FD1,TBOX_OverSea
 SG_ MCU4_UKl30Unv : 56|1@0+ (1,0) [0|1] "NoUnit" PDCS_FD1,TBOX,GW_FD5,PDCS_HVM_FD1,TBOX_OverSea
 SG_ MCU4_VcuRecOvTime : 57|1@0+ (1,0) [0|1] "NoUnit" PDCS_FD1,TBOX,GW_FD5,PDCS_HVM_FD1,TBOX_OverSea
 SG_ MCU4_UdcLnkOvHiRng : 59|2@0+ (1,0) [0|3] "NoUnit" PDCS_FD1,TBOX,GW_FD5,PDCS_HVM_FD1,TBOX_OverSea
 SG_ MCU4_UdcLnkOvLoRng : 61|2@0+ (1,0) [0|3] "NoUnit" PDCS_FD1,TBOX,GW_FD5,PDCS_HVM_FD1,TBOX_OverSea
 SG_ MCU4_OverSpdDetn : 63|2@0+ (1,0) [0|3] "NoUnit" PDCS_FD1,TBOX,GW_FD5,PDCS_HVM_FD1,TBOX_OverSea

BO_ 1590 MCU_NM_636: 8 MCU
 SG_ MCU_SourceNodeIdentifier : 7|8@0+ (1,0) [0|255] "NoUnit" Vector__XXX
 SG_ MCU_RepeatMessageRequest : 8|1@0+ (1,0) [0|1] "NoUnit" Vector__XXX
 SG_ MCU_Reserve1 : 11|3@0+ (1,0) [0|3] "NoUnit" Vector__XXX
 SG_ MCU_ActiveWakeup : 12|1@0+ (1,0) [0|1] "NoUnit" Vector__XXX
 SG_ MCU_Reserve2 : 15|3@0+ (1,0) [0|7] "NoUnit" Vector__XXX
 SG_ MCU_WakeUp_Reason1 : 16|1@0+ (1,0) [0|1] "NoUnit" Vector__XXX
 SG_ MCU_WakeUp_NM : 17|1@0+ (1,0) [0|1] "NoUnit" Vector__XXX
 SG_ MCU_RepeatFromSleep : 24|1@0+ (1,0) [0|1] "NoUnit" Vector__XXX
 SG_ MCU_RepeatFromPrepare : 25|1@0+ (1,0) [0|1] "NoUnit" Vector__XXX
 SG_ MCU_NormalFromRepeat : 26|1@0+ (1,0) [0|1] "NoUnit" Vector__XXX
 SG_ MCU_NormalFromReady : 27|1@0+ (1,0) [0|1] "NoUnit" Vector__XXX
 SG_ MCU_RepeatFromReady : 28|1@0+ (1,0) [0|1] "NoUnit" Vector__XXX
 SG_ MCU_RepeatFromNormal : 29|1@0+ (1,0) [0|1] "NoUnit" Vector__XXX
 SG_ MCU_RemainNetworkWakeUpReason1 : 32|1@0+ (1,0) [0|1] "NoUnit" Vector__XXX
 SG_ MCU_RemainNetworkWakeUpReason2 : 33|1@0+ (1,0) [0|1] "NoUnit" Vector__XXX
 SG_ MCU_RemainNetworkWakeUpReason3 : 34|1@0+ (1,0) [0|1] "NoUnit" Vector__XXX
 SG_ MCU_RemainNetworkWakeUpReason4 : 35|1@0+ (1,0) [0|1] "NoUnit" Vector__XXX

BO_ 518 DCDC_Fr02_206: 8 CDU
 SG_ DCDC2_Input_Vol : 7|14@0+ (0.05,0) [0|819.1] "NoUnit" PDCS_FD1,GW_FD2,BDCS,PDCS_HVM_FD1
 SG_ DCDC2_Output_Vol : 9|10@0+ (0.05,0) [0|51.15] "NoUnit" PDCS_FD1,TBOX,GW_FD5,GW_FD2,BDCS,PDCS_HVM_FD1,TBOX_OverSea
 SG_ DCDC2_Temp : 31|8@0+ (1,-48) [-48|206] "NoUnit" PDCS_FD1,GW_FD2,BDCS,PDCS_HVM_FD1
 SG_ DCDC2_Input_Cur : 39|8@0+ (0.1,0) [0|25.4] "NoUnit" PDCS_FD1,GW_FD2,BDCS,PDCS_HVM_FD1
 SG_ DCDC2_Output_Cur : 47|12@0+ (0.05,0) [0|204.7] "NoUnit" PDCS_FD1,TBOX,GW_FD5,GW_FD2,BDCS,PDCS_HVM_FD1,TBOX_OverSea
 SG_ DCDC2_OutPower_Max : 48|9@0+ (0.01,0) [0|3] "NoUnit" PDCS_FD1,GW_FD2,BDCS,PDCS_HVM_FD1

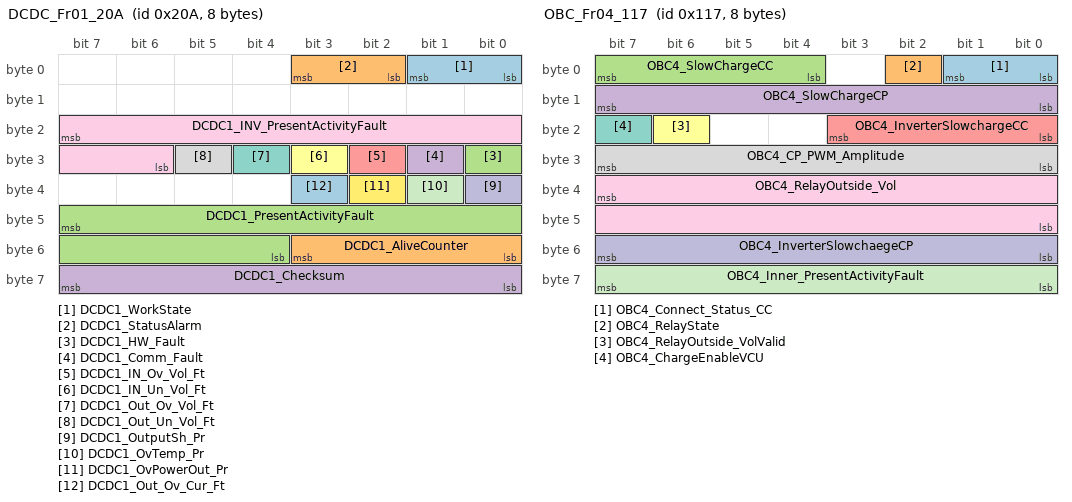
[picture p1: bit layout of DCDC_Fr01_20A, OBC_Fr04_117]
BO_ 522 DCDC_Fr01_20A: 8 CDU
 SG_ DCDC1_WorkState : 1|2@0+ (1,0) [0|3] "NoUnit" PDCS_FD1,TBOX,GW_FD5,ICU_E02,GW_FD4,ICU,CDCS,PDCS_HVM_FD1,CDCS_OverSea,TBOX_OverSea
 SG_ DCDC1_StatusAlarm : 3|2@0+ (1,0) [0|3] "NoUnit" Vector__XXX
 SG_ DCDC1_HW_Fault : 24|1@0+ (1,0) [0|1] "NoUnit" PDCS_FD1,PDCS_HVM_FD1
 SG_ DCDC1_Comm_Fault : 25|1@0+ (1,0) [0|1] "NoUnit" PDCS_FD1,PDCS_HVM_FD1
 SG_ DCDC1_IN_Ov_Vol_Ft : 26|1@0+ (1,0) [0|1] "NoUnit" PDCS_FD1,PDCS_HVM_FD1
 SG_ DCDC1_IN_Un_Vol_Ft : 27|1@0+ (1,0) [0|1] "NoUnit" PDCS_FD1,PDCS_HVM_FD1
 SG_ DCDC1_Out_Ov_Vol_Ft : 28|1@0+ (1,0) [0|1] "NoUnit" PDCS_FD1,PDCS_HVM_FD1
 SG_ DCDC1_Out_Un_Vol_Ft : 29|1@0+ (1,0) [0|1] "NoUnit" PDCS_FD1,PDCS_HVM_FD1
 SG_ DCDC1_INV_PresentActivityFault : 23|10@0+ (1,0) [0|1023] "NoUnit" Vector__XXX
 SG_ DCDC1_OutputSh_Pr : 32|1@0+ (1,0) [0|1] "NoUnit" PDCS_FD1,PDCS_HVM_FD1
 SG_ DCDC1_OvTemp_Pr : 33|1@0+ (1,0) [0|1] "NoUnit" PDCS_FD1,TBOX,GW_FD5,ICU_E02,GW_FD4,ICU,CDCS,PDCS_HVM_FD1,CDCS_OverSea,TBOX_OverSea
 SG_ DCDC1_OvPowerOut_Pr : 34|1@0+ (1,0) [0|1] "NoUnit" PDCS_FD1,PDCS_HVM_FD1
 SG_ DCDC1_Out_Ov_Cur_Ft : 35|1@0+ (1,0) [0|1] "NoUnit" PDCS_FD1,PDCS_HVM_FD1
 SG_ DCDC1_AliveCounter : 51|4@0+ (1,0) [0|15] "NoUnit" PDCS_FD1,TBOX,GW_FD5,PDCS_HVM_FD1,TBOX_OverSea
 SG_ DCDC1_PresentActivityFault : 47|12@0+ (1,0) [0|4095] "NoUnit" Vector__XXX
 SG_ DCDC1_Checksum : 63|8@0+ (1,0) [0|255] "NoUnit" PDCS_FD1,TBOX,GW_FD5,PDCS_HVM_FD1,TBOX_OverSea

BO_ 279 OBC_Fr04_117: 8 CDU
 SG_ OBC4_Connect_Status_CC : 1|2@0+ (1,0) [0|3] "NoUnit" PDCS_FD1,TBOX,GW_FD5,BMS,GW_FD2,BAM,PDCS_HVM_FD1,TBOX_OverSea
 SG_ OBC4_RelayState : 2|1@0+ (1,0) [0|1] "NoUnit" PDCS_FD1,BMS,PDCS_HVM_FD1
 SG_ OBC4_SlowChargeCC : 7|4@0+ (1,0) [0|15] "NoUnit" TBOX,GW_FD5,BMS,GW_FD2,BAM,PDCS_HVM_FD1,TBOX_OverSea
 SG_ OBC4_SlowChargeCP : 15|8@0+ (0.5,0) [0|100] "%" TBOX,GW_FD5,BMS,GW_FD4,GW_FD2,BAM,CDCS,PDCS_HVM_FD1,CDCS_OverSea,TBOX_OverSea
 SG_ OBC4_InverterSlowchargeCC : 19|4@0+ (1,0) [0|15] "NoUnit" BMS,PDCS_HVM_FD1
 SG_ OBC4_RelayOutside_VolValid : 22|1@0+ (1,0) [0|1] "NoUnit" BMS,PDCS_HVM_FD1
 SG_ OBC4_ChargeEnableVCU : 23|1@0+ (1,0) [0|1] "NoUnit" PDCS_HVM_FD1
 SG_ OBC4_CP_PWM_Amplitude : 31|8@0+ (0.1,0) [0|20] "V" PDCS_HVM_FD1
 SG_ OBC4_RelayOutside_Vol : 39|16@0+ (0.05,0) [0|1000] "V" BMS,PDCS_HVM_FD1
 SG_ OBC4_InverterSlowchaegeCP : 55|8@0+ (0.5,0) [0|100] "%" BMS,PDCS_HVM_FD1
 SG_ OBC4_Inner_PresentActivityFault : 63|8@0+ (1,0) [0|255] "" Vector__XXX

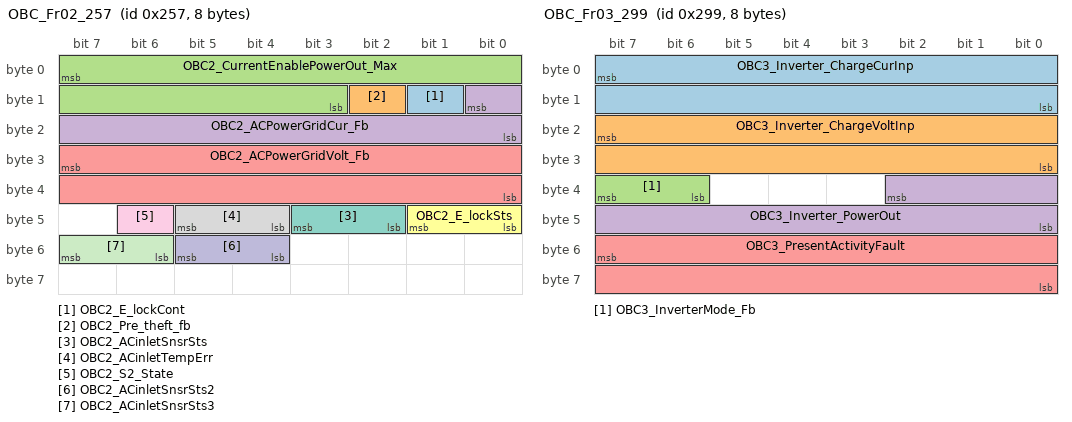
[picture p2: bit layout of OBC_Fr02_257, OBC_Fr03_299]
BO_ 599 OBC_Fr02_257: 8 CDU
 SG_ OBC2_E_lockCont : 9|1@0+ (1,0) [0|1] "NoUnit" GW_FD2,BAM
 SG_ OBC2_Pre_theft_fb : 10|1@0+ (1,0) [0|1] "NoUnit" GW_FD4,GW_FD2,BAM,CDCS,CDCS_OverSea
 SG_ OBC2_CurrentEnablePowerOut_Max : 7|13@0+ (0.005,0) [0|25] "Kw" PDCS_FD1,TBOX,GW_FD5,BMS,GW_FD2,BAM,PDCS_HVM_FD1,TBOX_OverSea
 SG_ OBC2_ACPowerGridCur_Fb : 8|9@0+ (0.1,0) [0|40] "A" TBOX,GW_FD5,BMS,GW_FD2,BAM,PDCS_HVM_FD1,TBOX_OverSea
 SG_ OBC2_ACPowerGridVolt_Fb : 31|16@0+ (0.01,0) [0|655.34] "V" TBOX,GW_FD5,BMS,GW_FD2,BAM,PDCS_HVM_FD1,TBOX_OverSea
 SG_ OBC2_E_lockSts : 41|2@0+ (1,0) [0|3] "NoUnit" TBOX,GW_FD5,BMS,GW_FD4,GW_FD2,BAM,CDCS,PDCS_HVM_FD1,CDCS_OverSea,TBOX_OverSea
 SG_ OBC2_ACinletSnsrSts : 43|2@0+ (1,0) [0|3] "NoUnit" TBOX,GW_FD5,BMS,GW_FD2,BAM,PDCS_HVM_FD1,TBOX_OverSea
 SG_ OBC2_ACinletTempErr : 45|2@0+ (1,0) [0|3] "NoUnit" TBOX,GW_FD5,BMS,GW_FD2,BAM,PDCS_HVM_FD1,TBOX_OverSea
 SG_ OBC2_S2_State : 46|1@0+ (1,0) [0|1] "NoUnit" TBOX,GW_FD5,BMS,GW_FD2,BAM,PDCS_HVM_FD1,TBOX_OverSea
 SG_ OBC2_ACinletSnsrSts2 : 53|2@0+ (1,0) [0|3] "NoUnit" Vector__XXX
 SG_ OBC2_ACinletSnsrSts3 : 55|2@0+ (1,0) [0|3] "NoUnit" Vector__XXX

BO_ 602 OBC_Fr01_25A: 8 CDU
 SG_ OBC1_CM_State : 2|3@0+ (1,0) [0|7] "NoUnit" PDCS_FD1,BMS,BDCS,BAM,CDCS,CDCS_OverSea,TBOX,GW_FD5,ICU_E02,GW_FD4,ICU,GW_FD2,PDCS_HVM_FD1,TBOX_OverSea
 SG_ OBC1_MilLampRequest : 3|1@0+ (1,0) [0|1] "NoUnit" EMS
 SG_ OBC1_StatusAlarm : 5|2@0+ (1,0) [0|3] "NoUnit" PDCS_FD1,BMS,BDCS,BAM,CDCS,CDCS_OverSea,TBOX,GW_FD5,ICU_E02,GW_FD4,ICU,GW_FD2,PDCS_HVM_FD1,TBOX_OverSea
 SG_ OBC1_No_Battery : 7|1@0+ (1,0) [0|1] "NoUnit" TBOX,GW_FD5,BMS,GW_FD2,BAM,PDCS_HVM_FD1,TBOX_OverSea
 SG_ OBC1_ChargeCurrent : 15|16@0+ (0.05,0) [0|400] "A" PDCS_FD1,BMS,BDCS,BAM,CDCS,CDCS_OverSea,TBOX,GW_FD5,ICU_E02,GW_FD4,ICU,GW_FD2,PDCS_HVM_FD1,TBOX_OverSea
 SG_ OBC1_ChargeVoltage : 31|16@0+ (0.05,0) [0|1000] "V" PDCS_FD1,BMS,BDCS,BAM,CDCS,CDCS_OverSea,TBOX,GW_FD5,ICU_E02,GW_FD4,ICU,GW_FD2,PDCS_HVM_FD1,TBOX_OverSea
 SG_ OBC1_HighVoltOutput_UnderVoltFlt : 40|1@0+ (1,0) [0|1] "NoUnit" TBOX,GW_FD5,BMS,GW_FD2,BAM,PDCS_HVM_FD1,TBOX_OverSea
 SG_ OBC1_HighVoltOutput_OverVoltFlt : 41|1@0+ (1,0) [0|1] "NoUnit" TBOX,GW_FD5,BMS,GW_FD2,BAM,PDCS_HVM_FD1,TBOX_OverSea
 SG_ OBC1_HighVoltOutput_ShortCircuitFlt : 42|1@0+ (1,0) [0|1] "NoUnit" TBOX,GW_FD5,BMS,GW_FD2,BAM,PDCS_HVM_FD1,TBOX_OverSea
 SG_ OBC1_Input_UnderVoltage : 43|1@0+ (1,0) [0|1] "NoUnit" TBOX,GW_FD5,BMS,GW_FD2,BAM,PDCS_HVM_FD1,TBOX_OverSea
 SG_ OBC1_Input_OverVoltage : 44|1@0+ (1,0) [0|1] "NoUnit" TBOX,GW_FD5,BMS,GW_FD2,BAM,PDCS_HVM_FD1,TBOX_OverSea
 SG_ OBC1_Over_Temperature : 46|2@0+ (1,0) [0|3] "NoUnit" TBOX,GW_FD5,BMS,GW_FD2,BDCS,BAM,PDCS_HVM_FD1,TBOX_OverSea
 SG_ OBC1_MsgCounter : 51|4@0+ (1,0) [0|15] "NoUnit" PDCS_FD1,BMS,BDCS,BAM,CDCS,CDCS_OverSea,TBOX,GW_FD5,GW_FD4,GW_FD2,PDCS_HVM_FD1,TBOX_OverSea
 SG_ OBC1_High_Current_Output_Fault : 52|1@0+ (1,0) [0|1] "NoUnit" TBOX,GW_FD5,BMS,GW_FD2,BAM,PDCS_HVM_FD1,TBOX_OverSea
 SG_ OBC1_CANMsgFault : 53|1@0+ (1,0) [0|1] "NoUnit" TBOX,GW_FD5,BMS,GW_FD2,BAM,PDCS_HVM_FD1,TBOX_OverSea
 SG_ OBC1_Battery_Reverse : 54|1@0+ (1,0) [0|1] "NoUnit" TBOX,GW_FD5,BMS,GW_FD2,BAM,PDCS_HVM_FD1,TBOX_OverSea
 SG_ OBC1_Temp : 63|8@0+ (1,-48) [-48|206] "" PDCS_FD1,TBOX,GW_FD5,BMS,GW_FD2,BDCS,BAM,PDCS_HVM_FD1,TBOX_OverSea

BO_ 665 OBC_Fr03_299: 8 CDU
 SG_ OBC3_Inverter_ChargeCurInp : 7|16@0+ (0.05,0) [0|400] "A" TBOX,GW_FD5,BMS,GW_FD2,BAM,PDCS_HVM_FD1,TBOX_OverSea
 SG_ OBC3_Inverter_ChargeVoltInp : 23|16@0+ (0.05,0) [0|1000] "V" TBOX,GW_FD5,BMS,GW_FD2,BAM,PDCS_HVM_FD1,TBOX_OverSea
 SG_ OBC3_InverterMode_Fb : 39|2@0+ (1,0) [0|3] "NoUnit" TBOX,GW_FD5,BMS,GW_FD2,BAM,PDCS_HVM_FD1,TBOX_OverSea
 SG_ OBC3_Inverter_PowerOut : 34|11@0+ (0.005,0) [0|7] "Kw" TBOX,GW_FD5,BMS,GW_FD4,GW_FD2,BAM,CDCS,PDCS_HVM_FD1,CDCS_OverSea,TBOX_OverSea
 SG_ OBC3_PresentActivityFault : 55|16@0+ (1,0) [0|65535] "NoUnit" Vector__XXX

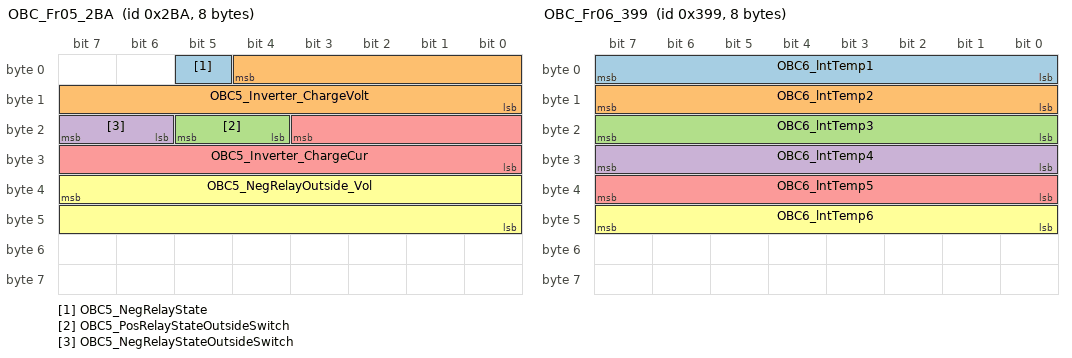
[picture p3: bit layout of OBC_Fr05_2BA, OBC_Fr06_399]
BO_ 698 OBC_Fr05_2BA: 8 CDU
 SG_ OBC5_NegRelayState : 5|1@0+ (1,0) [0|1] "NoUnit" BMS,PDCS_HVM_FD1
 SG_ OBC5_Inverter_ChargeVolt : 4|13@0+ (0.1,0) [0|450] "V" BMS,GW_FD4,CDCS,PDCS_HVM_FD1,CDCS_OverSea
 SG_ OBC5_PosRelayStateOutsideSwitch : 21|2@0+ (1,0) [0|3] "" BMS,PDCS_HVM_FD1
 SG_ OBC5_NegRelayStateOutsideSwitch : 23|2@0+ (1,0) [0|3] "" BMS,PDCS_HVM_FD1
 SG_ OBC5_Inverter_ChargeCur : 19|12@0+ (0.01,0) [0|35] "A" BMS,GW_FD4,CDCS,PDCS_HVM_FD1,CDCS_OverSea
 SG_ OBC5_NegRelayOutside_Vol : 39|16@0+ (0.05,0) [0|1000] "V" BMS,PDCS_HVM_FD1

BO_ 921 OBC_Fr06_399: 8 CDU
 SG_ OBC6_lntTemp1 : 7|8@0+ (1,-40) [-40|215] "" BMS,PDCS_HVM_FD1
 SG_ OBC6_lntTemp2 : 15|8@0+ (1,-40) [-40|215] "" BMS,PDCS_HVM_FD1
 SG_ OBC6_lntTemp3 : 23|8@0+ (1,-40) [-40|215] "" BMS,PDCS_HVM_FD1
 SG_ OBC6_lntTemp4 : 31|8@0+ (1,-40) [-40|215] "" BMS,PDCS_HVM_FD1
 SG_ OBC6_lntTemp5 : 39|8@0+ (1,-40) [-40|215] "" BMS,PDCS_HVM_FD1
 SG_ OBC6_lntTemp6 : 47|8@0+ (1,-40) [-40|215] "" BMS,PDCS_HVM_FD1

BO_ 1542 CDU_NM_606: 8 CDU
 SG_ CDU_SourceNodeIdentifier : 7|8@0+ (1,0) [0|255] "NoUnit" Vector__XXX
 SG_ CDU_RepeatMessageRequest : 8|1@0+ (1,0) [0|1] "NoUnit" Vector__XXX
 SG_ CDU_Reserve1 : 11|3@0+ (1,0) [0|3] "NoUnit" Vector__XXX
 SG_ CDU_ActiveWakeup : 12|1@0+ (1,0) [0|1] "NoUnit" Vector__XXX
 SG_ CDU_Reserve2 : 15|3@0+ (1,0) [0|7] "NoUnit" Vector__XXX
 SG_ CDU_WakeUp_KL15 : 16|1@0+ (1,0) [0|1] "NoUnit" Vector__XXX
 SG_ CDU_WakeUp_ACcharging : 17|1@0+ (1,0) [0|1] "NoUnit" Vector__XXX
 SG_ CDU_WakeUp_BMSIntelligentCharging : 18|1@0+ (1,0) [0|1] "NoUnit" Vector__XXX
 SG_ CDU_WakeUp_ACchargingThermal : 19|1@0+ (1,0) [0|1] "NoUnit" Vector__XXX
 SG_ CDU_WakeUp_LocalPreCharge : 20|1@0+ (1,0) [0|1] "NoUnit" Vector__XXX
 SG_ CDU_WakeUp_RemotePreCharge : 21|1@0+ (1,0) [0|1] "NoUnit" Vector__XXX
 SG_ CDU_WakeUp_OTA : 22|1@0+ (1,0) [0|1] "NoUnit" Vector__XXX
 SG_ CDU_WakeUpReason8 : 23|1@0+ (1,0) [0|1] "NoUnit" Vector__XXX
 SG_ CDU_RepeatFromSleep : 24|1@0+ (1,0) [0|1] "NoUnit" Vector__XXX
 SG_ CDU_RepeatFromPrepare : 25|1@0+ (1,0) [0|1] "NoUnit" Vector__XXX
 SG_ CDU_NormalFromRepeat : 26|1@0+ (1,0) [0|1] "NoUnit" Vector__XXX
 SG_ CDU_NormalFromReady : 27|1@0+ (1,0) [0|1] "NoUnit" Vector__XXX
 SG_ CDU_RepeatFromReady : 28|1@0+ (1,0) [0|1] "NoUnit" Vector__XXX
 SG_ CDU_RepeatFromNormal : 29|1@0+ (1,0) [0|1] "NoUnit" Vector__XXX
 SG_ CDU_RemainNetworkWakeUpReason1 : 32|1@0+ (1,0) [0|1] "NoUnit" Vector__XXX
 SG_ CDU_RemainNetworkWakeUpReason2 : 33|1@0+ (1,0) [0|1] "NoUnit" Vector__XXX
 SG_ CDU_RemainNetworkWakeUpReason3 : 34|1@0+ (1,0) [0|1] "NoUnit" Vector__XXX
 SG_ CDU_RemainNetworkWakeUpReason4 : 35|1@0+ (1,0) [0|1] "NoUnit" Vector__XXX

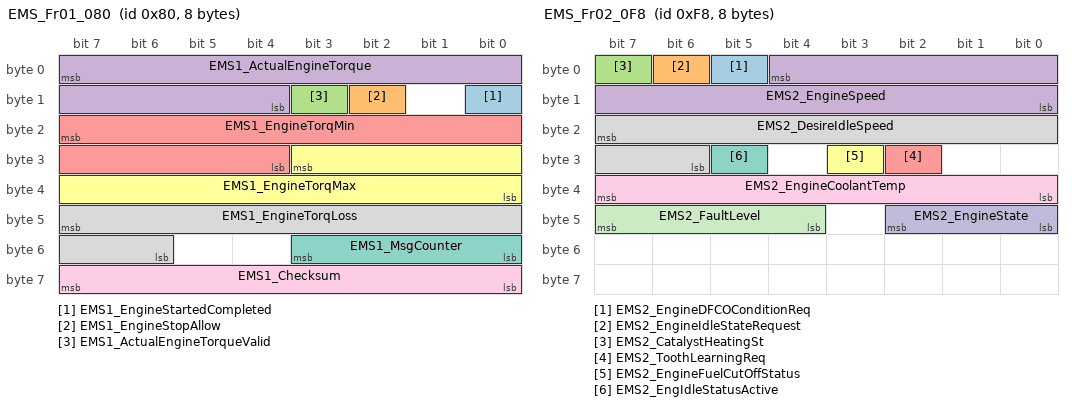
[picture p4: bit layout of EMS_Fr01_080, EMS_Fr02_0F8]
BO_ 128 EMS_Fr01_080: 8 EMS
 SG_ EMS1_EngineStartedCompleted : 8|1@0+ (1,0) [0|1] "NoUnit" PDCS_FD1,GCU,MCU,PDCS_HVM_FD1
 SG_ EMS1_EngineStopAllow : 10|1@0+ (1,0) [0|1] "NoUnit" PDCS_FD1,PDCS_HVM_FD1
 SG_ EMS1_ActualEngineTorqueValid : 11|1@0+ (1,0) [0|1] "NoUnit" PDCS_FD1,GCU,PDCS_HVM_FD1
 SG_ EMS1_ActualEngineTorque : 7|12@0+ (0.5,-500) [-500|1547] "Nm" PDCS_FD1,GCU,PDCS_HVM_FD1
 SG_ EMS1_EngineTorqMin : 23|12@0+ (0.5,-500) [-500|1547] "Nm" PDCS_FD1,PDCS_HVM_FD1
 SG_ EMS1_EngineTorqMax : 27|12@0+ (0.5,-500) [-500|1547] "Nm" PDCS_FD1,PDCS_HVM_FD1
 SG_ EMS1_MsgCounter : 51|4@0+ (1,0) [0|15] "NoUnit" Vector__XXX
 SG_ EMS1_EngineTorqLoss : 47|10@0+ (0.5,-100) [-100|411] "Nm" PDCS_FD1,PDCS_HVM_FD1
 SG_ EMS1_Checksum : 63|8@0+ (1,0) [0|255] "NoUnit" PDCS_FD1,PDCS_HVM_FD1

BO_ 248 EMS_Fr02_0F8: 8 EMS
 SG_ EMS2_EngineDFCOConditionReq : 5|1@0+ (1,0) [0|1] "NoUnit" PDCS_FD1,TBOX,GW_FD5,PDCS_HVM_FD1,TBOX_OverSea
 SG_ EMS2_EngineIdleStateRequest : 6|1@0+ (1,0) [0|1] "NoUnit" PDCS_FD1,PDCS_HVM_FD1
 SG_ EMS2_CatalystHeatingSt : 7|1@0+ (1,0) [0|1] "NoUnit" PDCS_FD1,TBOX,GW_FD5,PDCS_HVM_FD1,TBOX_OverSea
 SG_ EMS2_EngineSpeed : 4|13@0+ (1,0) [0|8191] "rpm" PDCS_FD1,IDB,ESC_FD3,EHB_FD3,BDCS,CDCS,ADCS_FD3,CDCS_OverSea,TBOX,ACU,GW_FD5,GCU,GW_FD3,GW_FD4,GW_FD2,MCU,PDCS_HVM_FD1,TBOX_OverSea
 SG_ EMS2_ToothLearningReq : 26|1@0+ (1,0) [0|1] "NoUnit" PDCS_FD1,TBOX,GW_FD5,PDCS_HVM_FD1,TBOX_OverSea
 SG_ EMS2_EngineFuelCutOffStatus : 27|1@0+ (1,0) [0|1] "NoUnit" PDCS_FD1,TBOX,GW_FD5,PDCS_HVM_FD1,TBOX_OverSea
 SG_ EMS2_EngIdleStatusActive : 29|1@0+ (1,0) [0|1] "NoUnit" PDCS_FD1,TBOX,GW_FD5,PDCS_HVM_FD1,TBOX_OverSea
 SG_ EMS2_DesireIdleSpeed : 23|10@0+ (10,0) [0|8190] "rpm" PDCS_FD1,TBOX,GW_FD5,PDCS_HVM_FD1,TBOX_OverSea
 SG_ EMS2_EngineCoolantTemp : 39|8@0+ (1,-40) [-40|215] "degree" PDCS_FD1,IDB,ESC_FD3,EHB_FD3,BDCS,CDCS,CDCS_OverSea,TBOX,GW_FD5,ICU_E02,GW_FD3,GW_FD4,ICU,GW_FD2,PDCS_HVM_FD1,TBOX_OverSea
 SG_ EMS2_EngineState : 42|3@0+ (1,0) [0|7] "NoUnit" PDCS_FD1,TBOX,GW_FD5,GCU,PDCS_HVM_FD1,TBOX_OverSea
 SG_ EMS2_FaultLevel : 47|4@0+ (1,0) [0|15] "NoUnit" PDCS_FD1,TBOX,GW_FD5,ICU_E02,GW_FD4,ICU,CDCS,PDCS_HVM_FD1,CDCS_OverSea,TBOX_OverSea

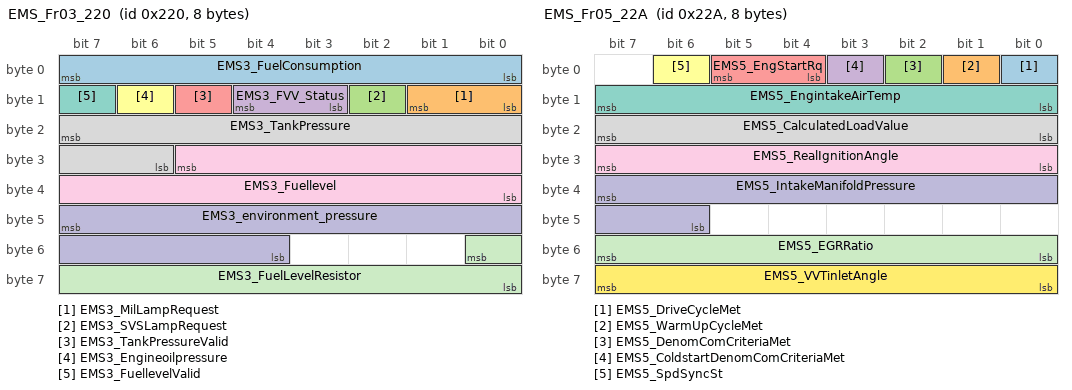
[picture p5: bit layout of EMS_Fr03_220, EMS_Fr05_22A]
BO_ 544 EMS_Fr03_220: 8 EMS
 SG_ EMS3_FuelConsumption : 7|8@0+ (4,0) [0|1020] "ul/100ms" PDCS_FD1,TBOX,GW_FD5,CDCS,PDCS_HVM_FD1,CDCS_OverSea,TBOX_OverSea
 SG_ EMS3_MilLampRequest : 9|2@0+ (1,0) [0|3] "NoUnit" TBOX,GW_FD5,ICU_E02,GW_FD4,ICU,CDCS,CDCS_OverSea,TBOX_OverSea
 SG_ EMS3_SVSLampRequest : 10|1@0+ (1,0) [0|1] "NoUnit" PDCS_FD1,TBOX,GW_FD5,PDCS_HVM_FD1,TBOX_OverSea
 SG_ EMS3_FVV_Status : 12|2@0+ (1,0) [0|3] "NoUnit" PDCS_FD1,TBOX,GW_FD5,PDCS_HVM_FD1,TBOX_OverSea
 SG_ EMS3_TankPressureValid : 13|1@0+ (1,0) [0|1] "NoUnit" PDCS_FD1,TBOX,GW_FD5,PDCS_HVM_FD1,TBOX_OverSea
 SG_ EMS3_Engineoilpressure : 14|1@0+ (1,0) [0|1] "NoUnit" PDCS_FD1,TBOX,GW_FD5,ICU_E02,GW_FD4,ICU,CDCS,PDCS_HVM_FD1,CDCS_OverSea,TBOX_OverSea
 SG_ EMS3_FuellevelValid : 15|1@0+ (1,0) [0|1] "NoUnit" PDCS_FD1,TBOX,GW_FD5,PDCS_HVM_FD1,TBOX_OverSea
 SG_ EMS3_TankPressure : 23|10@0+ (0.1,-20) [-20|40] "kPa" PDCS_FD1,TBOX,GW_FD5,PDCS_HVM_FD1,TBOX_OverSea
 SG_ EMS3_Fuellevel : 29|14@0+ (0.01,0) [0|100] "%" PDCS_FD1,TBOX,GW_FD5,ICU_E02,GW_FD4,ICU,CDCS,PDCS_HVM_FD1,CDCS_OverSea,TBOX_OverSea
 SG_ EMS3_environment_pressure : 47|12@0+ (0.1,0) [0|256] "kPa" PDCS_FD1,TBOX,GW_FD5,PDCS_HVM_FD1,TBOX_OverSea
 SG_ EMS3_FuelLevelResistor : 48|9@0+ (1,0) [0|511] "Ω" PDCS_FD1,TBOX,GW_FD5,PDCS_HVM_FD1,TBOX_OverSea

BO_ 554 EMS_Fr05_22A: 8 EMS
 SG_ EMS5_DriveCycleMet : 0|1@0+ (1,0) [0|1] "NoUnit" PDCS_FD1,CDU,IDB,ESC_FD3,GCU,GW_FD3,BMS,EHB_FD3,MCU,PDCS_HVM_FD1
 SG_ EMS5_WarmUpCycleMet : 1|1@0+ (1,0) [0|1] "NoUnit" PDCS_FD1,CDU,IDB,ESC_FD3,GCU,GW_FD3,BMS,EHB_FD3,MCU,PDCS_HVM_FD1
 SG_ EMS5_DenomComCriteriaMet : 2|1@0+ (1,0) [0|1] "NoUnit" PDCS_FD1,CDU,IDB,GCU,GW_FD3,BMS,MCU,PDCS_HVM_FD1
 SG_ EMS5_ColdstartDenomComCriteriaMet : 3|1@0+ (1,0) [0|1] "NoUnit" PDCS_FD1,CDU,IDB,GCU,GW_FD3,BMS,MCU,PDCS_HVM_FD1
 SG_ EMS5_EngStartRq : 5|2@0+ (1,0) [0|3] "NoUnit" PDCS_FD1,IDB,GW_FD3,PDCS_HVM_FD1
 SG_ EMS5_SpdSyncSt : 6|1@0+ (1,0) [0|1] "" PDCS_FD1,IDB,GW_FD3,PDCS_HVM_FD1
 SG_ EMS5_EngintakeAirTemp : 15|8@0+ (0.75,-40) [-40|150.5] "℃" PDCS_FD1,IDB,GW_FD3,GW_FD2,BDCS,PDCS_HVM_FD1
 SG_ EMS5_CalculatedLoadValue : 23|8@0+ (0.4,0) [0|100] "%" PDCS_FD1,IDB,GW_FD3,PDCS_HVM_FD1
 SG_ EMS5_RealIgnitionAngle : 31|8@0+ (0.75,-96) [-96|95.25] "Grad KW" PDCS_FD1,IDB,GW_FD3,PDCS_HVM_FD1
 SG_ EMS5_IntakeManifoldPressure : 39|10@0+ (4,100) [100|4188] "mba" PDCS_FD1,IDB,GW_FD3,PDCS_HVM_FD1
 SG_ EMS5_EGRRatio : 55|8@0+ (1,0) [0|100] "%" Vector__XXX
 SG_ EMS5_VVTinletAngle : 63|8@0+ (1,-50) [-50|50] "NoUnit" Vector__XXX

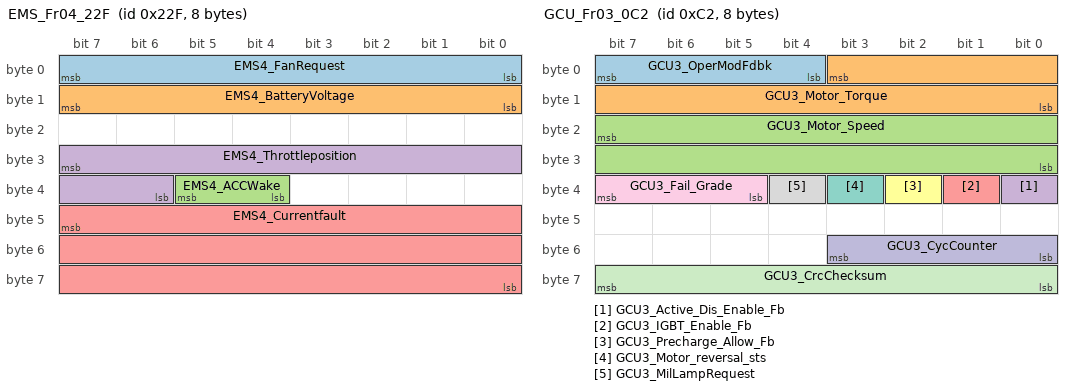
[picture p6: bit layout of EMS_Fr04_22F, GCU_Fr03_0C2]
BO_ 559 EMS_Fr04_22F: 8 EMS
 SG_ EMS4_FanRequest : 7|8@0+ (1,0) [0|100] "%" PDCS_FD1,PDCS_HVM_FD1
 SG_ EMS4_BatteryVoltage : 15|8@0+ (0.1,0) [0|25] "NoUnit" Vector__XXX
 SG_ EMS4_ACCWake : 37|2@0+ (1,0) [0|3] "NoUnit" PDCS_FD1,PDCS_HVM_FD1
 SG_ EMS4_Throttleposition : 31|10@0+ (0.1,0) [0|100] "%" PDCS_FD1,TBOX,ACU,GW_FD5,IDB,ESC_FD3,GW_FD3,EHB_FD3,PDCS_HVM_FD1,ADCS_FD3,TBOX_OverSea
 SG_ EMS4_Currentfault : 47|24@0+ (1,0) [0|1.6777215E7] "NoUnit" PDCS_FD1,TBOX,GW_FD5,PDCS_HVM_FD1,TBOX_OverSea

BO_ 194 GCU_Fr03_0C2: 8 GCU
 SG_ GCU3_OperModFdbk : 7|4@0+ (1,0) [0|15] "NoUnit" PDCS_FD1,GW_FD3,ISC,PDCS_HVM_FD1
 SG_ GCU3_Motor_Torque : 3|12@0+ (0.5,-300) [-130|130] "Nm" PDCS_FD1,GW_FD3,ISC,EMS,PDCS_HVM_FD1
 SG_ GCU3_Motor_Speed : 23|16@0+ (1,-12000) [-8000|8000] "rpm" PDCS_FD1,GW_FD3,ISC,EMS,PDCS_HVM_FD1
 SG_ GCU3_Active_Dis_Enable_Fb : 32|1@0+ (1,0) [0|1] "NoUnit" PDCS_FD1,PDCS_HVM_FD1
 SG_ GCU3_IGBT_Enable_Fb : 33|1@0+ (1,0) [0|1] "NoUnit" PDCS_FD1,PDCS_HVM_FD1
 SG_ GCU3_Precharge_Allow_Fb : 34|1@0+ (1,0) [0|1] "NoUnit" PDCS_FD1,PDCS_HVM_FD1
 SG_ GCU3_Motor_reversal_sts : 35|1@0+ (1,0) [0|1] "NoUnit" PDCS_FD1,PDCS_HVM_FD1
 SG_ GCU3_MilLampRequest : 36|1@0+ (1,0) [0|1] "NoUnit" EMS
 SG_ GCU3_Fail_Grade : 39|3@0+ (1,0) [0|7] "NoUnit" PDCS_FD1,PDCS_HVM_FD1
 SG_ GCU3_CycCounter : 51|4@0+ (1,0) [0|15] "NoUnit" PDCS_FD1,PDCS_HVM_FD1
 SG_ GCU3_CrcChecksum : 63|8@0+ (1,0) [0|255] "NoUnit" PDCS_FD1,PDCS_HVM_FD1

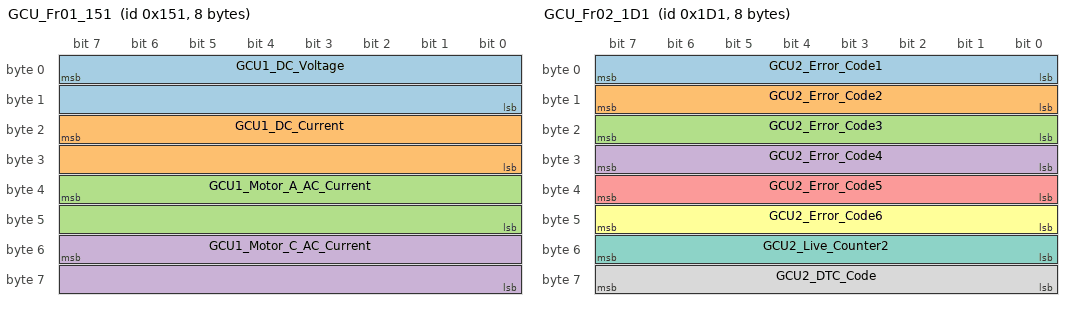
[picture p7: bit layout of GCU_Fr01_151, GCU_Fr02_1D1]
BO_ 337 GCU_Fr01_151: 8 GCU
 SG_ GCU1_DC_Voltage : 7|16@0+ (0.5,0) [0|700] "V" PDCS_FD1,TBOX,GW_FD5,ICU_E02,GW_FD4,ICU,CDCS,PDCS_HVM_FD1,CDCS_OverSea,TBOX_OverSea
 SG_ GCU1_DC_Current : 23|16@0+ (0.5,-500) [-500|500] "A" PDCS_FD1,TBOX,GW_FD5,ICU_E02,GW_FD4,ICU,CDCS,PDCS_HVM_FD1,CDCS_OverSea,TBOX_OverSea
 SG_ GCU1_Motor_A_AC_Current : 39|16@0+ (0.5,-500) [-500|500] "A" PDCS_FD1,TBOX,GW_FD5,ICU_E02,GW_FD4,ICU,PDCS_HVM_FD1,TBOX_OverSea
 SG_ GCU1_Motor_C_AC_Current : 55|16@0+ (0.5,-500) [-500|500] "A" PDCS_FD1,TBOX,GW_FD5,ICU_E02,GW_FD4,ICU,PDCS_HVM_FD1,TBOX_OverSea

BO_ 465 GCU_Fr02_1D1: 8 GCU
 SG_ GCU2_Error_Code1 : 7|8@0+ (1,0) [0|255] "NoUnit" PDCS_FD1,PDCS_HVM_FD1
 SG_ GCU2_Error_Code2 : 15|8@0+ (1,0) [0|255] "NoUnit" PDCS_FD1,PDCS_HVM_FD1
 SG_ GCU2_Error_Code3 : 23|8@0+ (1,0) [0|255] "NoUnit" PDCS_FD1,PDCS_HVM_FD1
 SG_ GCU2_Error_Code4 : 31|8@0+ (1,0) [0|255] "NoUnit" PDCS_FD1,PDCS_HVM_FD1
 SG_ GCU2_Error_Code5 : 39|8@0+ (1,0) [0|255] "NoUnit" PDCS_FD1,PDCS_HVM_FD1
 SG_ GCU2_Error_Code6 : 47|8@0+ (1,0) [0|255] "NoUnit" PDCS_FD1,PDCS_HVM_FD1
 SG_ GCU2_Live_Counter2 : 55|8@0+ (1,0) [0|255] "NoUnit" PDCS_FD1,PDCS_HVM_FD1
 SG_ GCU2_DTC_Code : 63|8@0+ (1,0) [0|255] "NoUnit" PDCS_FD1,PDCS_HVM_FD1

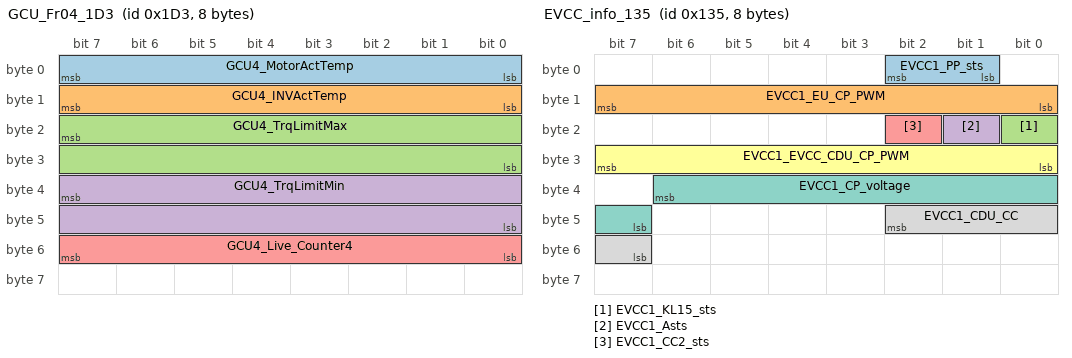
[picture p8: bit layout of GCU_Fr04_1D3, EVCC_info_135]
BO_ 467 GCU_Fr04_1D3: 8 GCU
 SG_ GCU4_MotorActTemp : 7|8@0+ (1,-50) [-45|200] "" PDCS_FD1,TBOX,GW_FD5,PDCS_HVM_FD1,TBOX_OverSea
 SG_ GCU4_INVActTemp : 15|8@0+ (1,-50) [-45|200] "" PDCS_FD1,TBOX,GW_FD5,PDCS_HVM_FD1,TBOX_OverSea
 SG_ GCU4_TrqLimitMax : 23|16@0+ (0.5,-300) [-130|130] "Nm" PDCS_FD1,TBOX,GW_FD5,PDCS_HVM_FD1,TBOX_OverSea
 SG_ GCU4_TrqLimitMin : 39|16@0+ (0.5,-300) [-130|130] "Nm" PDCS_FD1,TBOX,GW_FD5,PDCS_HVM_FD1,TBOX_OverSea
 SG_ GCU4_Live_Counter4 : 55|8@0+ (1,0) [0|255] "NoUnit" PDCS_FD1,PDCS_HVM_FD1

BO_ 1593 GCU_NM_639: 8 GCU
 SG_ GCU_SourceNodeIdentifier : 7|8@0+ (1,0) [0|255] "NoUnit" Vector__XXX
 SG_ GCU_RepeatMessageRequest : 8|1@0+ (1,0) [0|1] "NoUnit" Vector__XXX
 SG_ GCU_Reserve1 : 11|3@0+ (1,0) [0|3] "NoUnit" Vector__XXX
 SG_ GCU_ActiveWakeup : 12|1@0+ (1,0) [0|1] "NoUnit" Vector__XXX
 SG_ GCU_Reserve2 : 15|3@0+ (1,0) [0|7] "NoUnit" Vector__XXX
 SG_ GCU_WakeUp_Reason1 : 16|1@0+ (1,0) [0|1] "NoUnit" Vector__XXX
 SG_ GCU_WakeUp_NM : 17|1@0+ (1,0) [0|1] "NoUnit" Vector__XXX
 SG_ GCU_RepeatFromSleep : 24|1@0+ (1,0) [0|1] "NoUnit" Vector__XXX
 SG_ GCU_RepeatFromPrepare : 25|1@0+ (1,0) [0|1] "NoUnit" Vector__XXX
 SG_ GCU_NormalFromRepeat : 26|1@0+ (1,0) [0|1] "NoUnit" Vector__XXX
 SG_ GCU_NormalFromReady : 27|1@0+ (1,0) [0|1] "NoUnit" Vector__XXX
 SG_ GCU_RepeatFromReady : 28|1@0+ (1,0) [0|1] "NoUnit" Vector__XXX
 SG_ GCU_RepeatFromNormal : 29|1@0+ (1,0) [0|1] "NoUnit" Vector__XXX
 SG_ GCU_RemainNetworkWakeUpReason1 : 32|1@0+ (1,0) [0|1] "NoUnit" Vector__XXX
 SG_ GCU_RemainNetworkWakeUpReason2 : 33|1@0+ (1,0) [0|1] "NoUnit" Vector__XXX
 SG_ GCU_RemainNetworkWakeUpReason3 : 34|1@0+ (1,0) [0|1] "NoUnit" Vector__XXX
 SG_ GCU_RemainNetworkWakeUpReason4 : 35|1@0+ (1,0) [0|1] "NoUnit" Vector__XXX

BO_ 309 EVCC_info_135: 8 EVCC
 SG_ EVCC1_PP_sts : 2|2@0+ (1,0) [0|3] "" PDCS_FD1,CDU,BMS,PDCS_HVM_FD1
 SG_ EVCC1_EU_CP_PWM : 15|8@0+ (1,0) [0|100] "" PDCS_FD1,CDU,BMS,PDCS_HVM_FD1
 SG_ EVCC1_KL15_sts : 16|1@0+ (1,0) [0|1] "" PDCS_FD1,CDU,BMS,PDCS_HVM_FD1
 SG_ EVCC1_Asts : 17|1@0+ (1,0) [0|1] "" PDCS_FD1,CDU,BMS,PDCS_HVM_FD1
 SG_ EVCC1_CC2_sts : 18|1@0+ (1,0) [0|1] "" PDCS_FD1,CDU,BMS,PDCS_HVM_FD1
 SG_ EVCC1_EVCC_CDU_CP_PWM : 31|8@0+ (1,0) [0|100] "" PDCS_FD1,CDU,BMS,PDCS_HVM_FD1
 SG_ EVCC1_CP_voltage : 38|8@0+ (0.1,0) [0|25.4] "" PDCS_FD1,CDU,BMS,PDCS_HVM_FD1
 SG_ EVCC1_CDU_CC : 42|4@0+ (1,0) [0|14] "" PDCS_FD1,CDU,BMS,PDCS_HVM_FD1

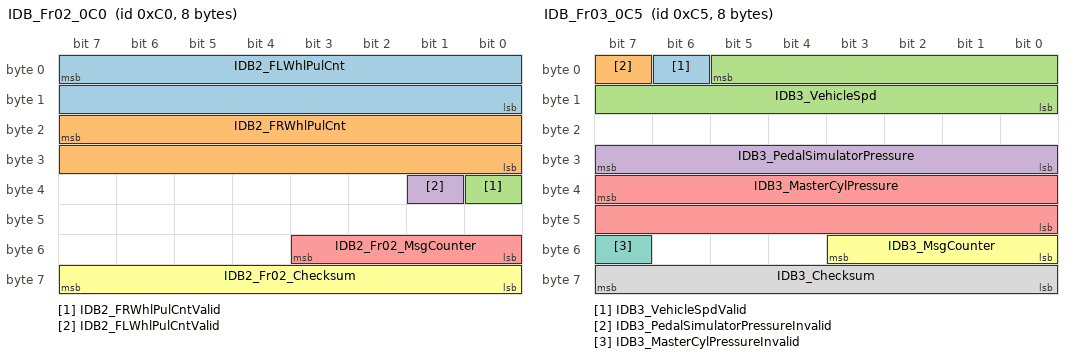
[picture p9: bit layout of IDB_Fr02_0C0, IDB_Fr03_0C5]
BO_ 192 IDB_Fr02_0C0: 8 IDB
 SG_ IDB2_FLWhlPulCnt : 7|16@0+ (0.5,0) [0|32767] "NoUnit" PDCS_FD3,PDCU,REPB,ADCU_FD3,EHB_FD3,BDCS,DDCU,CDCS,ADCS_FD3,CDCS_OverSea,TBOX,FLC_ME_FD3,FLC_FD3,GW_FD5,ICU_E02,ISC,GW_FD4,ICU,GW_FD2,TBOX_OverSea
 SG_ IDB2_FRWhlPulCnt : 23|16@0+ (0.5,0) [0|32767] "NoUnit" PDCS_FD3,REPB,ADCU_FD3,EHB_FD3,CDCS,ADCS_FD3,CDCS_OverSea,TBOX,FLC_ME_FD3,FLC_FD3,GW_FD5,ICU_E02,ISC,GW_FD4,ICU,TBOX_OverSea
 SG_ IDB2_FRWhlPulCntValid : 32|1@0+ (1,0) [0|1] "NoUnit" PDCS_FD3,REPB,ADCU_FD3,EHB_FD3,CDCS,ADCS_FD3,CDCS_OverSea,TBOX,FLC_ME_FD3,FLC_FD3,GW_FD5,ICU_E02,ISC,GW_FD4,ICU,TBOX_OverSea
 SG_ IDB2_FLWhlPulCntValid : 33|1@0+ (1,0) [0|1] "NoUnit" PDCS_FD3,PDCU,REPB,ADCU_FD3,EHB_FD3,BDCS,DDCU,CDCS,ADCS_FD3,CDCS_OverSea,TBOX,FLC_ME_FD3,FLC_FD3,GW_FD5,ICU_E02,ISC,GW_FD4,ICU,GW_FD2,TBOX_OverSea
 SG_ IDB2_Fr02_MsgCounter : 51|4@0+ (1,0) [0|15] "NoUnit" PDCS_FD3,REPB,ADCU_FD3,EHB_FD3,ADCS_FD3,TBOX,FLC_ME_FD3,FLC_FD3,GW_FD5,ISC,TBOX_OverSea
 SG_ IDB2_Fr02_Checksum : 63|8@0+ (1,0) [0|255] "NoUnit" PDCS_FD3,REPB,ADCU_FD3,EHB_FD3,ADCS_FD3,TBOX,FLC_ME_FD3,FLC_FD3,GW_FD5,ISC,TBOX_OverSea

BO_ 197 IDB_Fr03_0C5: 8 IDB
 SG_ IDB3_VehicleSpdValid : 6|1@0+ (1,0) [0|1] "NoUnit" PDCS_FD3,PDCU,REPB,ADCU_FD3,EPS,WPC,EHB_FD3,CDCS,CDU,ICU_E02,ISC,AMP,SRR3,SRR4,BMS,EMS,BDCS,DDCU,BAM,ADCS_FD3,CDCS_OverSea,IMU,TBOX,EVCC,FLC_ME_FD3,ACU,FLC_FD3,GW_FD5,GW_FD6,GCU,GW_FD4,GW_FD1,ICU,GW_FD2,MCU,TBOX_OverSea
 SG_ IDB3_PedalSimulatorPressureInvalid : 7|1@0+ (1,0) [0|1] "NoUnit" TBOX,REPB,GW_FD5,ISC,TBOX_OverSea
 SG_ IDB3_VehicleSpd : 5|14@0+ (0.03125,0) [0|511.9375] "km/h" PDCS_FD3,PDCU,REPB,ADCU_FD3,EPS,WPC,EHB_FD3,CDCS,CDU,ICU_E02,ISC,AMP,SRR3,SRR4,BMS,EMS,BDCS,DDCU,BAM,ADCS_FD3,CDCS_OverSea,IMU,TBOX,EVCC,FLC_ME_FD3,ACU,FLC_FD3,GW_FD5,GW_FD6,GCU,GW_FD4,GW_FD1,ICU,GW_FD2,MCU,TBOX_OverSea
 SG_ IDB3_PedalSimulatorPressure : 31|8@0+ (1,0) [0|250] "Bar" TBOX,REPB,GW_FD5,ISC,TBOX_OverSea
 SG_ IDB3_MasterCylPressure : 39|16@0+ (0.01,-30) [0|280] "Bar" PDCS_FD3,REPB,ADCU_FD3,EHB_FD3,CDCS,ADCS_FD3,CDCS_OverSea,TBOX,FLC_ME_FD3,FLC_FD3,GW_FD5,ICU_E02,ISC,GW_FD4,ICU,TBOX_OverSea
 SG_ IDB3_MsgCounter : 51|4@0+ (1,0) [0|15] "NoUnit" PDCS_FD3,REPB,ADCU_FD3,EPS,EHB_FD3,CDCS,ICU_E02,ISC,BMS,EMS,BDCS,ADCS_FD3,CDCS_OverSea,TBOX,FLC_ME_FD3,ACU,FLC_FD3,GW_FD5,GW_FD4,GW_FD1,ICU,GW_FD2,TBOX_OverSea
 SG_ IDB3_MasterCylPressureInvalid : 55|1@0+ (1,0) [0|1] "NoUnit" PDCS_FD3,REPB,ADCU_FD3,EHB_FD3,CDCS,ADCS_FD3,CDCS_OverSea,TBOX,FLC_ME_FD3,FLC_FD3,GW_FD5,ICU_E02,ISC,GW_FD4,ICU,TBOX_OverSea
 SG_ IDB3_Checksum : 63|8@0+ (1,0) [0|255] "NoUnit" PDCS_FD3,REPB,ADCU_FD3,EPS,EHB_FD3,CDCS,ICU_E02,ISC,BMS,EMS,BDCS,ADCS_FD3,CDCS_OverSea,TBOX,FLC_ME_FD3,ACU,FLC_FD3,GW_FD5,GW_FD4,GW_FD1,ICU,GW_FD2,TBOX_OverSea

BO_ 199 IDB_Fr04_0C7: 32 IDB
 SG_ IDB4_FLWhlVelocityValid : 9|1@0+ (1,0) [0|1] "NoUnit" PDCS_FD3,REPB,SRR3,SRR4,ADCU_FD3,EPS,EMS,EHB_FD3,CDCS,ADCS_FD3,CDCS_OverSea,IMU,TBOX,FLC_ME_FD3,FLC_FD3,GW_FD5,GW_FD6,ISC,GW_FD4,GW_FD1,TBOX_OverSea
 SG_ IDB4_FLWhlVelocity : 7|14@0+ (0.03125,0) [0|511.9375] "km/h" PDCS_FD3,REPB,SRR3,SRR4,ADCU_FD3,EPS,EMS,EHB_FD3,CDCS,ADCS_FD3,CDCS_OverSea,IMU,TBOX,FLC_ME_FD3,FLC_FD3,GW_FD5,GW_FD6,ISC,GW_FD4,GW_FD1,TBOX_OverSea
 SG_ IDB4_FRWhlVelocityValid : 25|1@0+ (1,0) [0|1] "NoUnit" PDCS_FD3,REPB,SRR3,SRR4,ADCU_FD3,EPS,EMS,EHB_FD3,CDCS,ADCS_FD3,CDCS_OverSea,IMU,TBOX,FLC_ME_FD3,FLC_FD3,GW_FD5,GW_FD6,ISC,GW_FD4,GW_FD1,TBOX_OverSea
 SG_ IDB4_FRWhlVelocity : 23|14@0+ (0.03125,0) [0|511.9375] "km/h" PDCS_FD3,REPB,SRR3,SRR4,ADCU_FD3,EPS,EMS,EHB_FD3,CDCS,ADCS_FD3,CDCS_OverSea,IMU,TBOX,FLC_ME_FD3,FLC_FD3,GW_FD5,GW_FD6,ISC,GW_FD4,GW_FD1,TBOX_OverSea
 SG_ IDB4_RRWhlDir : 33|2@0+ (1,0) [0|3] "NoUnit" PDCS_FD3,REPB,SRR3,SRR4,ADCU_FD3,EPS,EHB_FD3,CDCS,ADCS_FD3,CDCS_OverSea,TBOX,FLC_ME_FD3,FLC_FD3,GW_FD5,GW_FD6,ISC,GW_FD4,TBOX_OverSea
 SG_ IDB4_RLWhlDir : 35|2@0+ (1,0) [0|3] "NoUnit" PDCS_FD3,REPB,SRR3,SRR4,ADCU_FD3,EPS,EHB_FD3,CDCS,ADCS_FD3,CDCS_OverSea,TBOX,FLC_ME_FD3,FLC_FD3,GW_FD5,GW_FD6,ISC,GW_FD4,TBOX_OverSea
 SG_ IDB4_FRWhlDir : 37|2@0+ (1,0) [0|3] "NoUnit" PDCS_FD3,REPB,SRR3,SRR4,ADCU_FD3,EPS,EHB_FD3,CDCS,ADCS_FD3,CDCS_OverSea,TBOX,FLC_ME_FD3,FLC_FD3,GW_FD5,GW_FD6,ISC,GW_FD4,TBOX_OverSea
 SG_ IDB4_FLWhlDir : 39|2@0+ (1,0) [0|3] "NoUnit" PDCS_FD3,REPB,SRR3,SRR4,ADCU_FD3,EPS,EHB_FD3,CDCS,ADCS_FD3,CDCS_OverSea,TBOX,FLC_ME_FD3,FLC_FD3,GW_FD5,GW_FD6,ISC,GW_FD4,TBOX_OverSea
 SG_ IDB4_MsgCounter : 51|4@0+ (1,0) [0|15] "NoUnit" PDCS_FD3,REPB,SRR3,SRR4,ADCU_FD3,EPS,EHB_FD3,ADCS_FD3,TBOX,FLC_ME_FD3,FLC_FD3,GW_FD5,GW_FD6,ISC,TBOX_OverSea
 SG_ IDB4_Checksum : 63|8@0+ (1,0) [0|255] "NoUnit" PDCS_FD3,REPB,SRR3,SRR4,ADCU_FD3,EPS,EHB_FD3,ADCS_FD3,TBOX,FLC_ME_FD3,FLC_FD3,GW_FD5,GW_FD6,ISC,TBOX_OverSea
 SG_ IDB4_RRWhlVelocityValid : 72|1@0+ (1,0) [0|1] "NoUnit" PDCS_FD3,REPB,SRR3,SRR4,ADCU_FD3,EPS,EMS,EHB_FD3,CDCS,ADCS_FD3,CDCS_OverSea,IMU,TBOX,FLC_ME_FD3,FLC_FD3,GW_FD5,GW_FD6,ISC,GW_FD4,GW_FD1,TBOX_OverSea
 SG_ IDB4_RLWhlVelocityValid : 73|1@0+ (1,0) [0|1] "NoUnit" PDCS_FD3,REPB,SRR3,SRR4,ADCU_FD3,EPS,EMS,EHB_FD3,CDCS,ADCS_FD3,CDCS_OverSea,IMU,TBOX,FLC_ME_FD3,FLC_FD3,GW_FD5,GW_FD6,ISC,GW_FD4,GW_FD1,TBOX_OverSea
 SG_ IDB4_RLWhlVelocity : 71|14@0+ (0.03125,0) [0|511.9375] "km/h" PDCS_FD3,REPB,SRR3,SRR4,ADCU_FD3,EPS,EMS,EHB_FD3,CDCS,ADCS_FD3,CDCS_OverSea,IMU,TBOX,FLC_ME_FD3,FLC_FD3,GW_FD5,GW_FD6,ISC,GW_FD4,GW_FD1,TBOX_OverSea
 SG_ IDB4_RLWhlPulCntValid : 88|1@0+ (1,0) [0|1] "NoUnit" PDCS_FD3,REPB,SRR3,SRR4,ADCU_FD3,EHB_FD3,CDCS,ADCS_FD3,CDCS_OverSea,TBOX,FLC_ME_FD3,FLC_FD3,GW_FD5,ICU_E02,GW_FD6,ISC,GW_FD4,ICU,TBOX_OverSea
 SG_ IDB4_RRWhlPulCntValid : 89|1@0+ (1,0) [0|1] "NoUnit" PDCS_FD3,REPB,SRR3,SRR4,ADCU_FD3,EHB_FD3,CDCS,ADCS_FD3,CDCS_OverSea,TBOX,FLC_ME_FD3,FLC_FD3,GW_FD5,ICU_E02,GW_FD6,ISC,GW_FD4,ICU,TBOX_OverSea
 SG_ IDB4_RRWhlVelocity : 87|14@0+ (0.03125,0) [0|511.9375] "km/h" PDCS_FD3,REPB,SRR3,SRR4,ADCU_FD3,EPS,EMS,EHB_FD3,CDCS,ADCS_FD3,CDCS_OverSea,IMU,TBOX,FLC_ME_FD3,FLC_FD3,GW_FD5,GW_FD6,ISC,GW_FD4,GW_FD1,TBOX_OverSea
 SG_ IDB4_RLWhlPulCnt : 103|16@0+ (0.5,0) [0|32767] "NoUnit" PDCS_FD3,REPB,SRR3,SRR4,ADCU_FD3,EHB_FD3,CDCS,ADCS_FD3,CDCS_OverSea,TBOX,FLC_ME_FD3,FLC_FD3,GW_FD5,ICU_E02,GW_FD6,ISC,GW_FD4,ICU,TBOX_OverSea
 SG_ IDB4_RRWhlPulCnt : 119|16@0+ (0.5,0) [0|32767] "NoUnit" PDCS_FD3,REPB,SRR3,SRR4,ADCU_FD3,EHB_FD3,CDCS,ADCS_FD3,CDCS_OverSea,TBOX,FLC_ME_FD3,FLC_FD3,GW_FD5,ICU_E02,GW_FD6,ISC,GW_FD4,ICU,TBOX_OverSea

BO_ 201 IDB_Fr10_0C9: 16 IDB
 SG_ IDB10_BrRegenFrntAxleTar : 7|16@0+ (0.5,-16000) [-16000|16000] "Nm" TBOX,PDCS_FD3,REPB,GW_FD5,ESC_FD3,TBOX_OverSea
 SG_ IDB10_BrRegenReAxleTar : 23|16@0+ (0.5,-16000) [-16000|16000] "Nm" TBOX,PDCS_FD3,REPB,GW_FD5,ESC_FD3,TBOX_OverSea
 SG_ IDB10_ADAS_DrvTorqueReq : 40|1@0+ (1,0) [0|1] "NoUnit" TBOX,FLC_ME_FD3,PDCS_FD3,FLC_FD3,REPB,GW_FD5,ESC_FD3,ADCU_FD3,ADCS_FD3,TBOX_OverSea
 SG_ IDB10_ADAS_RegenTorqueReq : 41|1@0+ (1,0) [0|1] "NoUnit" TBOX,FLC_ME_FD3,PDCS_FD3,FLC_FD3,REPB,GW_FD5,ESC_FD3,ADCU_FD3,ADCS_FD3,TBOX_OverSea
 SG_ IDB10_MsgCounter : 51|4@0+ (1,0) [0|15] "NoUnit" TBOX,PDCS_FD3,REPB,GW_FD5,ESC_FD3,TBOX_OverSea
 SG_ IDB10_BrRegenFrntAxleTarReq : 52|1@0+ (1,0) [0|1] "NoUnit" TBOX,PDCS_FD3,REPB,GW_FD5,ESC_FD3,TBOX_OverSea
 SG_ IDB10_BrRegenReAxleTarReq : 53|1@0+ (1,0) [0|1] "NoUnit" TBOX,PDCS_FD3,REPB,GW_FD5,ESC_FD3,TBOX_OverSea
 SG_ IDB10_Checksum : 63|8@0+ (1,0) [0|255] "NoUnit" TBOX,PDCS_FD3,REPB,GW_FD5,ESC_FD3,TBOX_OverSea
 SG_ IDB10_ADAS_DrvTorque : 103|16@0+ (0.5,-16000) [-16000|16000] "Nm" TBOX,FLC_ME_FD3,PDCS_FD3,FLC_FD3,REPB,GW_FD5,ESC_FD3,ADCU_FD3,ADCS_FD3,TBOX_OverSea
 SG_ IDB10_ADAS_RegenTorque : 119|16@0+ (0.5,-16000) [-16000|16000] "Nm" TBOX,FLC_ME_FD3,PDCS_FD3,FLC_FD3,REPB,GW_FD5,ESC_FD3,ADCU_FD3,ADCS_FD3,TBOX_OverSea

BO_ 202 IDB_Fr11_0CA: 16 IDB
 SG_ IDB11_MsgCounter : 51|4@0+ (1,0) [0|15] "NoUnit" TBOX,PDCS_FD3,REPB,GW_FD5,EHB_FD3,TBOX_OverSea
 SG_ IDB11_MotrTrqFrntAxleTargtReq : 54|1@0+ (1,0) [0|1] "NoUnit" TBOX,PDCS_FD3,REPB,GW_FD5,EHB_FD3,TBOX_OverSea
 SG_ IDB11_MotrTrqRearAxleTargtReq : 55|1@0+ (1,0) [0|1] "NoUnit" TBOX,PDCS_FD3,REPB,GW_FD5,EHB_FD3,TBOX_OverSea
 SG_ IDB11_Checksum : 63|8@0+ (1,0) [0|255] "NoUnit" TBOX,PDCS_FD3,REPB,GW_FD5,EHB_FD3,TBOX_OverSea
 SG_ IDB11_MotrTrqFrntAxleTargt : 71|16@0+ (0.5,-16000) [-16000|16000] "Nm" TBOX,PDCS_FD3,REPB,GW_FD5,EHB_FD3,TBOX_OverSea
 SG_ IDB11_MotrTrqRearAxleTargt : 87|16@0+ (0.5,-16000) [-16000|16000] "Nm" TBOX,PDCS_FD3,REPB,GW_FD5,EHB_FD3,TBOX_OverSea

BO_ 229 IDB_Fr01_0E5: 8 IDB
 SG_ IDB1_BrakePedalApplied : 0|1@0+ (1,0) [0|1] "NoUnit" PDCS_FD3,REPB,SRR3,ESC_FD3,SRR4,ADCU_FD3,EMS,CDCS,ADCS_FD3,CDCS_OverSea,TBOX,FLC_ME_FD3,ACU,FLC_FD3,GW_FD5,GW_FD6,ISC,GW_FD4,GW_FD1,TBOX_OverSea
 SG_ IDB1_BrakePedalAppliedV : 1|1@0+ (1,0) [0|1] "NoUnit" PDCS_FD3,REPB,SRR3,ESC_FD3,SRR4,ADCU_FD3,EMS,CDCS,ADCS_FD3,CDCS_OverSea,TBOX,FLC_ME_FD3,ACU,FLC_FD3,GW_FD5,GW_FD6,ISC,GW_FD4,GW_FD1,TBOX_OverSea
 SG_ IDB1_BBSFail : 2|1@0+ (1,0) [0|1] "NoUnit" REPB,ESC_FD3,CDCS,CDCS_OverSea,TBOX,GW_FD5,ICU_E02,ISC,GW_FD4,ICU,TBOX_OverSea
 SG_ IDB1_RBSFail : 3|1@0+ (1,0) [0|1] "NoUnit" TBOX,PDCS_FD3,REPB,GW_FD5,ESC_FD3,ISC,GW_FD4,CDCS,CDCS_OverSea,TBOX_OverSea
 SG_ IDB1_RBS_ActiveSta : 4|1@0+ (1,0) [0|1] "NoUnit" PDCS_FD3,REPB,ESC_FD3,CDCS,CDCS_OverSea,TBOX,GW_FD5,ICU_E02,ISC,GW_FD4,ICU,TBOX_OverSea
 SG_ IDB1_BBS_ActiveSta : 5|1@0+ (1,0) [0|1] "NoUnit" TBOX,REPB,GW_FD5,ESC_FD3,ISC,GW_FD4,CDCS,CDCS_OverSea,TBOX_OverSea
 SG_ IDB1_BrakeFluidLow : 6|1@0+ (1,0) [0|1] "NoUnit" REPB,ESC_FD3,CDCS,CDCS_OverSea,TBOX,GW_FD5,ICU_E02,ISC,GW_FD4,ICU,TBOX_OverSea
 SG_ IDB1_BrakPedalDisp : 15|16@0+ (0.1,-40) [-40|160] "mm" PDCS_FD3,REPB,ESC_FD3,CDCS,ADCS_FD3,CDCS_OverSea,TBOX,FLC_ME_FD3,ACU,FLC_FD3,GW_FD5,ISC,GW_FD4,GW_FD1,TBOX_OverSea
 SG_ IDB1_TrvSnsCalSts : 26|1@0+ (1,0) [0|1] "NoUnit" TBOX,REPB,GW_FD5,ESC_FD3,ISC,GW_FD4,CDCS,CDCS_OverSea,TBOX_OverSea
 SG_ IDB1_BrakPedalDisp_Q : 29|1@0+ (1,0) [0|1] "NoUnit" PDCS_FD3,REPB,ESC_FD3,CDCS,ADCS_FD3,CDCS_OverSea,TBOX,FLC_ME_FD3,ACU,FLC_FD3,GW_FD5,ISC,GW_FD4,GW_FD1,TBOX_OverSea
 SG_ IDB1_BrakeClusterDispMSG : 31|2@0+ (1,0) [0|3] "NoUnit" REPB,ESC_FD3,ISC,GW_FD4,CDCS,CDCS_OverSea
 SG_ IDB1_CSTFail : 40|1@0+ (1,0) [0|1] "NoUnit" PDCS_FD3,REPB,ESC_FD3,ADCU_FD3,CDCS,ADCS_FD3,CDCS_OverSea,TBOX,FLC_ME_FD3,FLC_FD3,GW_FD5,ICU_E02,ISC,GW_FD4,ICU,TBOX_OverSea
 SG_ IDB1_CSTAtive : 41|1@0+ (1,0) [0|1] "NoUnit" PDCS_FD3,REPB,ESC_FD3,ADCU_FD3,CDCS,ADCS_FD3,CDCS_OverSea,TBOX,FLC_ME_FD3,FLC_FD3,GW_FD5,ICU_E02,ISC,GW_FD4,ICU,TBOX_OverSea
 SG_ IDB1_CSTEnabled : 42|1@0+ (1,0) [0|1] "NoUnit" PDCS_FD3,REPB,ESC_FD3,ADCU_FD3,CDCS,ADCS_FD3,CDCS_OverSea,FLC_ME_FD3,FLC_FD3,ICU_E02,ISC,GW_FD4,ICU
 SG_ IDB1_Brakestyle_Enabled : 43|1@0+ (1,0) [0|1] "NoUnit" REPB,ESC_FD3,ADCU_FD3,CDCS,ADCS_FD3,CDCS_OverSea,FLC_ME_FD3,FLC_FD3,ICU_E02,ISC,GW_FD4,ICU
 SG_ IDB1_Brakestyle_Fail : 44|1@0+ (1,0) [0|1] "NoUnit" REPB,ESC_FD3,ADCU_FD3,CDCS,ADCS_FD3,CDCS_OverSea,FLC_ME_FD3,FLC_FD3,ICU_E02,ISC,GW_FD4,ICU
 SG_ IDB1_FailedState : 47|3@0+ (1,0) [0|7] "NoUnit" PDCS_FD3,REPB,ESC_FD3,ADCU_FD3,CDCS,ADCS_FD3,CDCS_OverSea,TBOX,FLC_ME_FD3,ACU,FLC_FD3,GW_FD5,ISC,GW_FD4,GW_FD1,TBOX_OverSea
 SG_ IDB1_Fr01_MsgCounter : 51|4@0+ (1,0) [0|15] "NoUnit" PDCS_FD3,REPB,SRR3,ESC_FD3,SRR4,ADCU_FD3,EMS,CDCS,ADCS_FD3,CDCS_OverSea,TBOX,FLC_ME_FD3,ACU,FLC_FD3,GW_FD5,ICU_E02,GW_FD6,ISC,GW_FD4,GW_FD1,ICU,TBOX_OverSea
 SG_ IDB1_MilLampRequset : 52|1@0+ (1,0) [0|1] "NoUnit" REPB,ESC_FD3,EMS,CDCS,CDCS_OverSea,TBOX,GW_FD5,ISC,GW_FD4,GW_FD1,TBOX_OverSea
 SG_ IDB1_Brakestyle : 55|2@0+ (1,0) [0|3] "NoUnit" REPB,ICU_E02,ESC_FD3,ISC,GW_FD4,ICU,CDCS,CDCS_OverSea
 SG_ IDB1_Fr01_Checksum : 63|8@0+ (1,0) [0|255] "NoUnit" PDCS_FD3,REPB,SRR3,ESC_FD3,SRR4,ADCU_FD3,EMS,CDCS,ADCS_FD3,CDCS_OverSea,TBOX,FLC_ME_FD3,ACU,FLC_FD3,GW_FD5,ICU_E02,GW_FD6,ISC,GW_FD4,GW_FD1,ICU,TBOX_OverSea

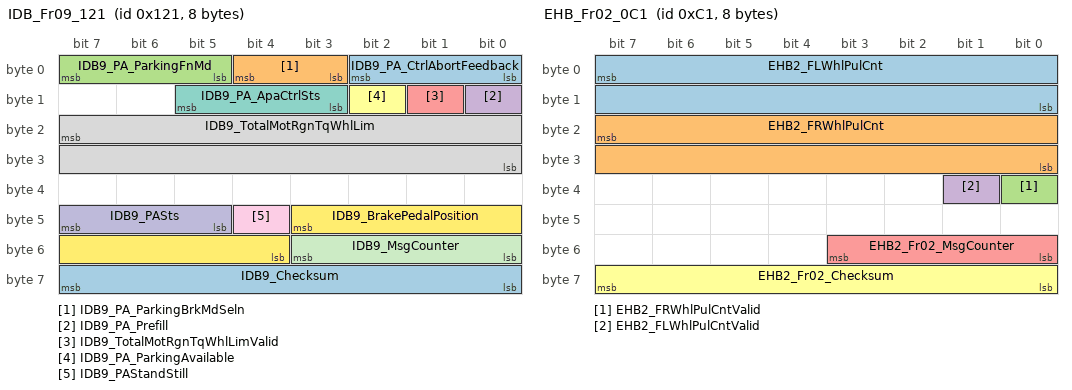
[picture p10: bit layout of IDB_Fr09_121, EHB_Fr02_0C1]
BO_ 289 IDB_Fr09_121: 8 IDB
 SG_ IDB9_PA_CtrlAbortFeedback : 2|3@0+ (1,0) [0|7] "NoUnit" REPB,ESC_FD3,ADCU_FD3,ADCS_FD3
 SG_ IDB9_PA_ParkingBrkMdSeln : 4|2@0+ (1,0) [0|3] "NoUnit" REPB,ESC_FD3,ADCU_FD3,ADCS_FD3
 SG_ IDB9_PA_ParkingFnMd : 7|3@0+ (1,0) [0|7] "NoUnit" REPB,ESC_FD3,ADCU_FD3,ADCS_FD3
 SG_ IDB9_PA_Prefill : 8|1@0+ (1,0) [0|1] "NoUnit" REPB,ESC_FD3,ADCU_FD3,ADCS_FD3
 SG_ IDB9_TotalMotRgnTqWhlLimValid : 9|1@0+ (1,0) [0|1] "NoUnit" REPB
 SG_ IDB9_PA_ParkingAvailable : 10|1@0+ (1,0) [0|1] "NoUnit" REPB,ESC_FD3,ADCU_FD3,ADCS_FD3
 SG_ IDB9_PA_ApaCtrlSts : 13|3@0+ (1,0) [0|7] "NoUnit" PDCS_FD3,REPB,ESC_FD3,ADCU_FD3,ADCS_FD3
 SG_ IDB9_TotalMotRgnTqWhlLim : 23|16@0+ (0.5,-16000) [-16000|16000] "Nm" REPB
 SG_ IDB9_PAStandStill : 44|1@0+ (1,0) [0|1] "NoUnit" TBOX,PDCS_FD3,REPB,GW_FD5,ESC_FD3,ADCU_FD3,ADCS_FD3,TBOX_OverSea
 SG_ IDB9_PASts : 47|3@0+ (1,0) [0|7] "NoUnit" TBOX,PDCS_FD3,REPB,GW_FD5,ESC_FD3,ADCU_FD3,ADCS_FD3,TBOX_OverSea
 SG_ IDB9_MsgCounter : 51|4@0+ (1,0) [0|15] "NoUnit" TBOX,PDCS_FD3,REPB,GW_FD5,ESC_FD3,ADCU_FD3,ADCS_FD3,TBOX_OverSea
 SG_ IDB9_BrakePedalPosition : 43|8@0+ (1,0) [0|100] "%" ACU,FLC_FD3,REPB,ADCU_FD3,GW_FD1,ADCS_FD3
 SG_ IDB9_Checksum : 63|8@0+ (1,0) [0|255] "NoUnit" TBOX,PDCS_FD3,REPB,GW_FD5,ESC_FD3,ADCU_FD3,ADCS_FD3,TBOX_OverSea

BO_ 297 IDB_Fr05_129: 8 IDB
 SG_ IDB5_BrakeDiscTempSts : 0|1@0+ (1,0) [0|1] "NoUnit" FLC_ME_FD3,FLC_FD3,REPB,ESC_FD3,ADCU_FD3,ADCS_FD3
 SG_ IDB5_VehicleStanstill : 2|2@0+ (1,0) [0|3] "NoUnit" FLC_ME_FD3,FLC_FD3,REPB,ESC_FD3,ADCU_FD3,ADCS_FD3
 SG_ IDB5_JerkActive : 3|1@0+ (1,0) [0|1] "NoUnit" FLC_ME_FD3,FLC_FD3,REPB,ESC_FD3,ADCU_FD3,ADCS_FD3
 SG_ IDB5_Jerkfail : 4|1@0+ (1,0) [0|1] "NoUnit" FLC_ME_FD3,FLC_FD3,REPB,ESC_FD3,ADCU_FD3,ADCS_FD3
 SG_ IDB5_ADAS_PrefillSts : 6|2@0+ (1,0) [0|3] "" FLC_ME_FD3,FLC_FD3,REPB,ESC_FD3,ADCU_FD3,ADCS_FD3
 SG_ IDB5_ACC_ReqLim : 25|2@0+ (1,0) [0|3] "NoUnit" FLC_ME_FD3,FLC_FD3,REPB,ESC_FD3,ADCU_FD3,ADCS_FD3
 SG_ IDB5_DBSavailable : 26|1@0+ (1,0) [0|1] "NoUnit" FLC_ME_FD3,FLC_FD3,REPB,ESC_FD3,ADCU_FD3,ADCS_FD3
 SG_ IDB5_Prefillavailable : 27|1@0+ (1,0) [0|1] "NoUnit" FLC_ME_FD3,FLC_FD3,REPB,ESC_FD3,ADCU_FD3,ADCS_FD3
 SG_ IDB5_ABAactive : 28|1@0+ (1,0) [0|1] "NoUnit" FLC_ME_FD3,FLC_FD3,REPB,ESC_FD3,ADCU_FD3,ADCS_FD3
 SG_ IDB5_AEB_Enable : 41|2@0+ (1,0) [0|3] "NoUnit" FLC_ME_FD3,PDCS_FD3,FLC_FD3,REPB,ESC_FD3,ADCU_FD3,ADCS_FD3
 SG_ IDB5_ACC_Enable : 43|2@0+ (1,0) [0|3] "NoUnit" FLC_ME_FD3,PDCS_FD3,FLC_FD3,REPB,ESC_FD3,ADCU_FD3,ADCS_FD3
 SG_ IDB5_ACC_Sta : 44|1@0+ (1,0) [0|1] "NoUnit" FLC_ME_FD3,PDCS_FD3,FLC_FD3,REPB,ESC_FD3,ADCU_FD3,ADCS_FD3
 SG_ IDB5_ACC_ReferenceAccel : 39|11@0+ (0.01,-10.23) [-10.23|10.24] "m/s2" FLC_ME_FD3,FLC_FD3,REPB,ESC_FD3,ADCU_FD3,ADCS_FD3
 SG_ IDB5_MsgCounter : 51|4@0+ (1,0) [0|15] "NoUnit" FLC_ME_FD3,PDCS_FD3,FLC_FD3,REPB,ESC_FD3,ADCU_FD3,ADCS_FD3
 SG_ IDB5_AEBactive : 52|1@0+ (1,0) [0|1] "NoUnit" FLC_ME_FD3,PDCS_FD3,ACU,FLC_FD3,REPB,ESC_FD3,ADCU_FD3,GW_FD1,ADCS_FD3
 SG_ IDB5_DriverOverride : 54|2@0+ (1,0) [0|3] "NoUnit" PDCS_FD3,REPB,ESC_FD3
 SG_ IDB5_Checksum : 63|8@0+ (1,0) [0|255] "NoUnit" FLC_ME_FD3,PDCS_FD3,FLC_FD3,REPB,ESC_FD3,ADCU_FD3,ADCS_FD3

BO_ 299 IDB_Fr06_12B: 8 IDB
 SG_ IDB6_EPB_SwitchSta : 1|2@0+ (1,0) [0|3] "NoUnit" TBOX,PDCS_FD3,REPB,GW_FD5,ESC_FD3,TBOX_OverSea
 SG_ IDB6_MainSysActive : 2|1@0+ (1,0) [0|1] "NoUnit" TBOX,REPB,GW_FD5,TBOX_OverSea
 SG_ IDB6_EPB_DynamicApplySta : 4|2@0+ (1,0) [0|3] "NoUnit" TBOX,PDCS_FD3,REPB,GW_FD5,ESC_FD3,GW_FD4,CDCS_OverSea,TBOX_OverSea
 SG_ IDB6_EPB_ActuatorSt_R : 7|3@0+ (1,0) [0|7] "NoUnit" TBOX,PDCS_FD3,REPB,GW_FD5,ESC_FD3,TBOX_OverSea
 SG_ IDB6_EPB_ActuatorSt_L : 10|3@0+ (1,0) [0|7] "NoUnit" TBOX,PDCS_FD3,REPB,GW_FD5,ESC_FD3,TBOX_OverSea
 SG_ IDB6_EpbDrvAwyInt : 11|1@0+ (1,0) [0|1] "NoUnit" REPB,ESC_FD3
 SG_ IDB6_EpbActrAvailPrim : 12|1@0+ (1,0) [0|1] "NoUnit" REPB,ESC_FD3
 SG_ IDB6_EPB_DisplayMsgID : 15|3@0+ (1,0) [0|7] "NoUnit" TBOX,REPB,GW_FD5,ICU_E02,ESC_FD3,GW_FD4,ICU,TBOX_OverSea
 SG_ IDB6_EpbActrStatPrim : 20|3@0+ (1,0) [0|6] "NoUnit" REPB,ESC_FD3
 SG_ IDB6_PGearPositionReqSt : 21|1@0+ (1,0) [0|1] "NoUnit" PDCS_FD3,REPB,ESC_FD3
 SG_ IDB6_PGearPositionReqStInv : 22|1@0+ (1,0) [0|1] "NoUnit" PDCS_FD3,REPB,ESC_FD3
 SG_ IDB6_PGearPositionReqStValid : 23|1@0+ (1,0) [0|1] "NoUnit" PDCS_FD3,REPB
 SG_ IDB6_EPBClusterDispMSG2 : 28|3@0+ (1,0) [0|7] "NoUnit" REPB,GW_FD4,CDCS,CDCS_OverSea
 SG_ IDB6_EpbAplRelReq : 31|3@0+ (1,0) [0|6] "NoUnit" REPB,ESC_FD3
 SG_ IDB6_EPBStatus : 34|3@0+ (1,0) [0|7] "NoUnit" PDCS_FD3,REPB,ESC_FD3,ADCU_FD3,CDCS,ADCS_FD3,CDCS_OverSea,TBOX,FLC_ME_FD3,ACU,FLC_FD3,GW_FD5,ICU_E02,GW_FD4,GW_FD1,ICU,TBOX_OverSea
 SG_ IDB6_EPBAvailable : 37|3@0+ (1,0) [0|7] "NoUnit" PDCS_FD3,REPB,ESC_FD3,ADCU_FD3,CDCS,ADCS_FD3,CDCS_OverSea,TBOX,FLC_ME_FD3,ACU,FLC_FD3,GW_FD5,ICU_E02,GW_FD4,GW_FD1,ICU,TBOX_OverSea
 SG_ IDB6_EPBWarnLampReq : 41|2@0+ (1,0) [0|3] "NoUnit" TBOX,REPB,GW_FD5,ICU_E02,ESC_FD3,GW_FD4,ICU,CDCS,CDCS_OverSea,TBOX_OverSea
 SG_ IDB6_EPBStatusLampReq : 43|2@0+ (1,0) [0|3] "NoUnit" TBOX,REPB,GW_FD5,ICU_E02,ESC_FD3,GW_FD4,ICU,CDCS,CDCS_OverSea,TBOX_OverSea
 SG_ IDB6_EPBSysBrkLightsReq : 44|1@0+ (1,0) [0|1] "NoUnit" REPB,ESC_FD3
 SG_ IDB6_EPBCruiseCtrlCancelReq : 45|1@0+ (1,0) [0|1] "NoUnit" REPB,ESC_FD3
 SG_ IDB6_RollingBenchModeSts : 50|1@0+ (1,0) [0|1] "NoUnit" TBOX,PDCS_FD3,REPB,GW_FD5,ESC_FD3,TBOX_OverSea
 SG_ IDB6_EpbCtrlAvail : 51|1@0+ (1,0) [0|1] "" PDCS_FD3,REPB,ESC_FD3
 SG_ IDB6_EPBClusterDispMSG : 54|3@0+ (1,0) [0|7] "NoUnit" REPB,ICU_E02,ESC_FD3,GW_FD4,ICU,CDCS,CDCS_OverSea

BO_ 301 IDB_Fr07_12D: 16 IDB
 SG_ IDB7_ESCFail : 0|1@0+ (1,0) [0|1] "NoUnit" PDCS_FD3,REPB,ADCU_FD3,EHB_FD3,CDCS,ADCS_FD3,CDCS_OverSea,TBOX,FLC_ME_FD3,ACU,FLC_FD3,GW_FD5,ICU_E02,ISC,GW_FD4,GW_FD1,ICU,TBOX_OverSea
 SG_ IDB7_ESCActive : 1|1@0+ (1,0) [0|1] "NoUnit" PDCS_FD3,REPB,ADCU_FD3,EHB_FD3,CDCS,ADCS_FD3,CDCS_OverSea,TBOX,FLC_ME_FD3,ACU,FLC_FD3,GW_FD5,ICU_E02,ISC,GW_FD4,GW_FD1,ICU,TBOX_OverSea
 SG_ IDB7_ESCDisable : 2|1@0+ (1,0) [0|1] "NoUnit" PDCS_FD3,REPB,ADCU_FD3,EHB_FD3,CDCS,ADCS_FD3,CDCS_OverSea,TBOX,FLC_ME_FD3,ACU,FLC_FD3,GW_FD5,ICU_E02,ISC,GW_FD4,GW_FD1,ICU,TBOX_OverSea
 SG_ IDB7_ABSActive : 3|1@0+ (1,0) [0|1] "NoUnit" PDCS_FD3,REPB,ADCU_FD3,EHB_FD3,CDCS,ADCS_FD3,CDCS_OverSea,TBOX,FLC_ME_FD3,ACU,FLC_FD3,GW_FD5,ISC,GW_FD4,GW_FD1,TBOX_OverSea
 SG_ IDB7_EBD_Fail : 4|1@0+ (1,0) [0|1] "NoUnit" PDCS_FD3,REPB,ADCU_FD3,EHB_FD3,CDCS,ADCS_FD3,CDCS_OverSea,TBOX,FLC_ME_FD3,ACU,FLC_FD3,GW_FD5,ICU_E02,ISC,GW_FD4,GW_FD1,ICU,TBOX_OverSea
 SG_ IDB7_EBD_Active : 5|1@0+ (1,0) [0|1] "NoUnit" PDCS_FD3,REPB,ADCU_FD3,EHB_FD3,CDCS,ADCS_FD3,CDCS_OverSea,TBOX,FLC_ME_FD3,ACU,FLC_FD3,GW_FD5,ICU_E02,ISC,GW_FD4,GW_FD1,ICU,TBOX_OverSea
 SG_ IDB7_HBAActive : 6|1@0+ (1,0) [0|1] "NoUnit" REPB,ADCU_FD3,EHB_FD3,CDCS,ADCS_FD3,CDCS_OverSea,TBOX,FLC_ME_FD3,FLC_FD3,GW_FD5,ISC,GW_FD4,TBOX_OverSea
 SG_ IDB7_HBAFail : 7|1@0+ (1,0) [0|1] "NoUnit" REPB,ADCU_FD3,EHB_FD3,CDCS,ADCS_FD3,CDCS_OverSea,TBOX,FLC_ME_FD3,FLC_FD3,GW_FD5,ISC,GW_FD4,TBOX_OverSea
 SG_ IDB7_DiagMode : 8|1@0+ (1,0) [0|1] "NoUnit" REPB,ADCU_FD3,EHB_FD3,CDCS,ADCS_FD3,CDCS_OverSea,TBOX,FLC_ME_FD3,FLC_FD3,GW_FD5,ICU_E02,ISC,GW_FD4,ICU,TBOX_OverSea
 SG_ IDB7_TCSActive : 9|1@0+ (1,0) [0|1] "NoUnit" PDCS_FD3,REPB,ADCU_FD3,EHB_FD3,CDCS,ADCS_FD3,CDCS_OverSea,TBOX,FLC_ME_FD3,ACU,FLC_FD3,GW_FD5,ICU_E02,ISC,GW_FD4,GW_FD1,ICU,TBOX_OverSea
 SG_ IDB7_TCSDisable : 10|1@0+ (1,0) [0|1] "NoUnit" PDCS_FD3,REPB,ADCU_FD3,EHB_FD3,CDCS,ADCS_FD3,CDCS_OverSea,TBOX,FLC_ME_FD3,ACU,FLC_FD3,GW_FD5,ICU_E02,ISC,GW_FD4,GW_FD1,ICU,TBOX_OverSea
 SG_ IDB7_TCSFail : 11|1@0+ (1,0) [0|1] "NoUnit" PDCS_FD3,REPB,ADCU_FD3,EHB_FD3,CDCS,ADCS_FD3,CDCS_OverSea,TBOX,FLC_ME_FD3,ACU,FLC_FD3,GW_FD5,ICU_E02,ISC,GW_FD4,GW_FD1,ICU,TBOX_OverSea
 SG_ IDB7_ROPACTIVE : 12|1@0+ (1,0) [0|1] "NoUnit" PDCS_FD3,REPB,ADCU_FD3,EHB_FD3,CDCS,ADCS_FD3,CDCS_OverSea,TBOX,FLC_ME_FD3,FLC_FD3,GW_FD5,ICU_E02,ISC,GW_FD4,ICU,TBOX_OverSea
 SG_ IDB7_ROPFailure : 13|1@0+ (1,0) [0|1] "NoUnit" PDCS_FD3,REPB,ADCU_FD3,EHB_FD3,CDCS,ADCS_FD3,CDCS_OverSea,TBOX,FLC_ME_FD3,FLC_FD3,GW_FD5,ISC,GW_FD4,TBOX_OverSea
 SG_ IDB7_DynParkBrkByIDBActive : 21|1@0+ (1,0) [0|1] "NoUnit" PDCS_FD3,REPB,ADCU_FD3,EHB_FD3,CDCS,ADCS_FD3,CDCS_OverSea,TBOX,FLC_ME_FD3,FLC_FD3,GW_FD5,ISC,GW_FD4,TBOX_OverSea
 SG_ IDB7_DynParkBrkByIDBAvailable : 22|1@0+ (1,0) [0|1] "NoUnit" PDCS_FD3,REPB,ADCU_FD3,EHB_FD3,CDCS,ADCS_FD3,CDCS_OverSea,TBOX,FLC_ME_FD3,FLC_FD3,GW_FD5,ISC,GW_FD4,TBOX_OverSea
 SG_ IDB7_HSAActive : 23|1@0+ (1,0) [0|1] "NoUnit" PDCS_FD3,REPB,ADCU_FD3,EHB_FD3,CDCS,ADCS_FD3,CDCS_OverSea,TBOX,FLC_ME_FD3,FLC_FD3,GW_FD5,ISC,GW_FD4,TBOX_OverSea
 SG_ IDB7_HSAFail : 24|1@0+ (1,0) [0|1] "NoUnit" PDCS_FD3,REPB,ADCU_FD3,EHB_FD3,CDCS,ADCS_FD3,CDCS_OverSea,TBOX,FLC_ME_FD3,FLC_FD3,GW_FD5,ISC,GW_FD4,TBOX_OverSea
 SG_ IDB7_HDCEnabled : 25|1@0+ (1,0) [0|1] "NoUnit" REPB,ADCU_FD3,EHB_FD3,CDCS,ADCS_FD3,CDCS_OverSea,TBOX,FLC_ME_FD3,FLC_FD3,GW_FD5,ISC,GW_FD4,TBOX_OverSea
 SG_ IDB7_HDCFail : 26|1@0+ (1,0) [0|1] "NoUnit" REPB,ADCU_FD3,EHB_FD3,CDCS,ADCS_FD3,CDCS_OverSea,TBOX,FLC_ME_FD3,FLC_FD3,GW_FD5,ICU_E02,ISC,GW_FD4,ICU,TBOX_OverSea
 SG_ IDB7_HDCAtive : 27|1@0+ (1,0) [0|1] "NoUnit" PDCS_FD3,REPB,ADCU_FD3,EHB_FD3,CDCS,ADCS_FD3,CDCS_OverSea,TBOX,FLC_ME_FD3,FLC_FD3,GW_FD5,ICU_E02,ISC,GW_FD4,ICU,TBOX_OverSea
 SG_ IDB7_BrkLightReq : 28|1@0+ (1,0) [0|1] "NoUnit" REPB,EHB_FD3,BDCS,CDCS,CDCS_OverSea,TBOX,GW_FD5,ISC,GW_FD4,GW_FD2,TBOX_OverSea
 SG_ IDB7_ABSFail : 29|1@0+ (1,0) [0|1] "NoUnit" PDCS_FD3,REPB,ADCU_FD3,EHB_FD3,CDCS,ADCS_FD3,CDCS_OverSea,TBOX,FLC_ME_FD3,ACU,FLC_FD3,GW_FD5,ICU_E02,ISC,GW_FD4,GW_FD1,ICU,TBOX_OverSea
 SG_ IDB7_ESSActiveReq : 31|2@0+ (1,0) [0|3] "NoUnit" REPB,EHB_FD3,BDCS,CDCS,CDCS_OverSea,TBOX,GW_FD5,ISC,GW_FD4,GW_FD2,TBOX_OverSea
 SG_ IDB7_CBCActive : 32|1@0+ (1,0) [0|1] "NoUnit" TBOX,REPB,GW_FD5,ISC,GW_FD4,EHB_FD3,CDCS,CDCS_OverSea,TBOX_OverSea
 SG_ IDB7_CBCFail : 33|1@0+ (1,0) [0|1] "NoUnit" TBOX,REPB,GW_FD5,ISC,GW_FD4,EHB_FD3,CDCS,CDCS_OverSea,TBOX_OverSea
 SG_ IDB7_ETCSActivationFlag_F : 34|1@0+ (1,0) [0|1] "NoUnit" TBOX,PDCS_FD3,REPB,GW_FD5,ISC,GW_FD4,EHB_FD3,CDCS,CDCS_OverSea,TBOX_OverSea
 SG_ IDB7_ETCSActivationFlag_R : 35|1@0+ (1,0) [0|1] "NoUnit" TBOX,PDCS_FD3,REPB,GW_FD5,ISC,GW_FD4,EHB_FD3,CDCS,CDCS_OverSea,TBOX_OverSea
 SG_ IDB7_BTCSActFlag : 36|1@0+ (1,0) [0|1] "NoUnit" TBOX,REPB,GW_FD5,ISC,GW_FD4,EHB_FD3,CDCS,CDCS_OverSea,TBOX_OverSea
 SG_ IDB7_HBCActive : 44|1@0+ (1,0) [0|1] "NoUnit" TBOX,REPB,GW_FD5,ISC,GW_FD4,EHB_FD3,CDCS,CDCS_OverSea,TBOX_OverSea
 SG_ IDB7_HBCFail : 45|1@0+ (1,0) [0|1] "NoUnit" TBOX,REPB,GW_FD5,ISC,GW_FD4,EHB_FD3,CDCS,CDCS_OverSea,TBOX_OverSea
 SG_ IDB7_HBCReduced : 46|1@0+ (1,0) [0|1] "NoUnit" TBOX,REPB,GW_FD5,ISC,GW_FD4,EHB_FD3,CDCS,CDCS_OverSea,TBOX_OverSea
 SG_ IDB7_MsgCounter : 51|4@0+ (1,0) [0|15] "NoUnit" PDCS_FD3,REPB,ADCU_FD3,EHB_FD3,BDCS,ADCS_FD3,TBOX,FLC_ME_FD3,FLC_FD3,GW_FD5,ICU_E02,ISC,GW_FD4,GW_FD2,TBOX_OverSea
 SG_ IDB7_BrakeWarningLamp : 54|3@0+ (1,0) [0|7] "NoUnit" REPB,EHB_FD3,CDCS,CDCS_OverSea,TBOX,ACU,GW_FD5,ICU_E02,ISC,GW_FD4,GW_FD1,ICU,TBOX_OverSea
 SG_ IDB7_ActAccXValid : 55|1@0+ (1,0) [0|1] "NoUnit" REPB
 SG_ IDB7_Checksum : 63|8@0+ (1,0) [0|255] "NoUnit" PDCS_FD3,REPB,ADCU_FD3,EHB_FD3,BDCS,ADCS_FD3,TBOX,FLC_ME_FD3,FLC_FD3,GW_FD5,ICU_E02,ISC,GW_FD4,GW_FD2,TBOX_OverSea
 SG_ IDB7_GroundSlopeValid : 100|1@0+ (1,0) [0|1] "NoUnit" REPB
 SG_ IDB7_HDCClusterDispMSG : 103|3@0+ (1,0) [0|7] "NoUnit" REPB,GW_FD4,CDCS,CDCS_OverSea
 SG_ IDB7_GroundSlope : 99|12@0+ (0.1,-200) [-200|200] "%" TBOX,REPB,GW_FD5,TBOX_OverSea
 SG_ IDB7_ActAccX : 119|12@0+ (0.01,-20) [-20|20] "m/s2" TBOX,REPB,GW_FD5,TBOX_OverSea
 SG_ IDB7_PIBFail : 120|1@0+ (1,0) [0|1] "NoUnit" PDCS_FD3,GW_FD2,BDCS
 SG_ IDB7_PIBActive : 121|1@0+ (1,0) [0|1] "NoUnit" PDCS_FD3,GW_FD2,BDCS
 SG_ IDB7_TSAActive : 122|1@0+ (1,0) [0|1] "NoUnit" PDCS_FD3,ICU_E02,ICU,CDCS,CDCS_OverSea
 SG_ IDB7_TSAFail : 123|1@0+ (1,0) [0|1] "NoUnit" PDCS_FD3,ICU_E02,ICU,CDCS,CDCS_OverSea

BO_ 302 IDB_Fr12_12E: 16 IDB
 SG_ IDB12_AVHDispMSG : 15|2@0+ (1,0) [0|3] "NoUnit" REPB,ESC_FD3,ADCU_FD3,CDCS,ADCS_FD3,CDCS_OverSea,FLC_ME_FD3,FLC_FD3,ICU_E02,GW_FD4,ICU
 SG_ IDB12_AVHLampReq : 17|2@0+ (1,0) [0|3] "NoUnit" PDCS_FD3,REPB,ESC_FD3,ADCU_FD3,CDCS,ADCS_FD3,CDCS_OverSea,TBOX,FLC_ME_FD3,FLC_FD3,GW_FD5,ICU_E02,GW_FD4,ICU,TBOX_OverSea
 SG_ IDB12_AVHStatus : 19|2@0+ (1,0) [0|3] "NoUnit" PDCS_FD3,REPB,ESC_FD3,ADCU_FD3,BDCS,CDCS,ADCS_FD3,CDCS_OverSea,FLC_ME_FD3,FLC_FD3,ICU_E02,GW_FD4,ICU,GW_FD2
 SG_ IDB12_AVHEnabled : 20|1@0+ (1,0) [0|1] "NoUnit" FLC_ME_FD3,PDCS_FD3,FLC_FD3,REPB,ESC_FD3,ADCU_FD3,GW_FD4,CDCS,ADCS_FD3,CDCS_OverSea
 SG_ IDB12_EpedalAct : 37|1@0+ (1,0) [0|1] "NoUnit" PDCS_FD3,REPB,ESC_FD3
 SG_ IDB12_EpedalSts : 38|1@0+ (1,0) [0|1] "NoUnit" PDCS_FD3,REPB,ESC_FD3
 SG_ IDB12_RBS_exitReq : 39|1@0+ (1,0) [0|1] "NoUnit" REPB,ESC_FD3
 SG_ IDB12_ReDTCAxleTarReq : 40|1@0+ (1,0) [0|1] "NoUnit" PDCS_FD3,REPB,ESC_FD3
 SG_ IDB12_FrntDTCAxleTarReq : 41|1@0+ (1,0) [0|1] "NoUnit" PDCS_FD3,REPB,ESC_FD3
 SG_ IDB12_DTC_Activesta : 42|1@0+ (1,0) [0|1] "NoUnit" TBOX,PDCS_FD3,REPB,GW_FD5,ESC_FD3,TBOX_OverSea
 SG_ IDB12_DTCFail : 43|1@0+ (1,0) [0|1] "NoUnit" PDCS_FD3,REPB,ESC_FD3,CDCS,CDCS_OverSea,TBOX,GW_FD5,ICU_E02,GW_FD4,ICU,TBOX_OverSea
 SG_ IDB12_MsgCounter : 51|4@0+ (1,0) [0|15] "NoUnit" TBOX,PDCS_FD3,REPB,GW_FD5,ICU_E02,ESC_FD3,GW_FD4,TBOX_OverSea
 SG_ IDB12_Checksum : 63|8@0+ (1,0) [0|255] "NoUnit" TBOX,PDCS_FD3,REPB,GW_FD5,ICU_E02,ESC_FD3,GW_FD4,TBOX_OverSea
 SG_ IDB12_ReDTCAxleTar : 71|16@0+ (0.5,-16000) [-16000|16000] "Nm" PDCS_FD3,REPB,ESC_FD3
 SG_ IDB12_FrntDTCAxleTar : 87|16@0+ (0.5,-16000) [-16000|16000] "Nm" PDCS_FD3,REPB,ESC_FD3
 SG_ IDB12_RBSExitReason : 106|3@0+ (1,0) [0|7] "NoUnit" REPB,ESC_FD3
 SG_ IDB12_sOutputRodAct : 103|13@0+ (0.01,-5) [-5|50] "mm" REPB,ESC_FD3
 SG_ IDB12_sOutputRodActValid : 112|1@0+ (1,0) [0|1] "NoUnit" REPB,ESC_FD3

BO_ 303 IDB_Fr08_12F: 16 IDB
 SG_ IDB8_MsgCounter : 51|4@0+ (1,0) [0|15] "NoUnit" TBOX,REPB,GW_FD5,EHB_FD3,TBOX_OverSea
 SG_ IDB8_BrakeActive : 52|1@0+ (1,0) [0|1] "NoUnit" PDCS_FD3,REPB,EHB_FD3
 SG_ IDB8_Checksum : 63|8@0+ (1,0) [0|255] "NoUnit" TBOX,REPB,GW_FD5,EHB_FD3,TBOX_OverSea
 SG_ IDB8_FrntLeEstimdWhlPres : 71|8@0+ (1,0) [0|250] "Bar" TBOX,PDCS_FD3,REPB,GW_FD5,EHB_FD3,TBOX_OverSea
 SG_ IDB8_FrntRiEstimdWhlPres : 79|8@0+ (1,0) [0|250] "Bar" TBOX,PDCS_FD3,REPB,GW_FD5,EHB_FD3,TBOX_OverSea
 SG_ IDB8_ReLeEstimdWhlPres : 87|8@0+ (1,0) [0|250] "Bar" TBOX,PDCS_FD3,REPB,GW_FD5,EHB_FD3,TBOX_OverSea
 SG_ IDB8_ReRiEstimdWhlPres : 95|8@0+ (1,0) [0|250] "Bar" TBOX,PDCS_FD3,REPB,GW_FD5,EHB_FD3,TBOX_OverSea
 SG_ IDB8_FrntLeEstimdWhlPresVldty : 96|1@0+ (1,0) [0|1] "NoUnit" PDCS_FD3,REPB,EHB_FD3
 SG_ IDB8_FrntRiEstimdWhlPresVldty : 97|1@0+ (1,0) [0|1] "NoUnit" PDCS_FD3,REPB,EHB_FD3
 SG_ IDB8_ReLeEstimdWhlPresVldty : 98|1@0+ (1,0) [0|1] "NoUnit" PDCS_FD3,REPB,EHB_FD3
 SG_ IDB8_ReRiEstimdWhlPresVldty : 99|1@0+ (1,0) [0|1] "NoUnit" PDCS_FD3,REPB,EHB_FD3

BO_ 1554 IDB_NM_612: 8 IDB
 SG_ IDB_SourceNodeIdentifier : 7|8@0+ (1,0) [0|255] "NoUnit" Vector__XXX
 SG_ IDB_RepeatMessageRequest : 8|1@0+ (1,0) [0|1] "NoUnit" Vector__XXX
 SG_ IDB_Reserve1 : 11|3@0+ (1,0) [0|3] "NoUnit" Vector__XXX
 SG_ IDB_ActiveWakeup : 12|1@0+ (1,0) [0|1] "NoUnit" Vector__XXX
 SG_ IDB_Reserve2 : 15|3@0+ (1,0) [0|7] "NoUnit" Vector__XXX
 SG_ IDB_WakeUp_KL15 : 16|1@0+ (1,0) [0|1] "NoUnit" Vector__XXX
 SG_ IDB_WakeUp_NM : 17|1@0+ (1,0) [0|1] "NoUnit" Vector__XXX
 SG_ IDB_WakeUp_EPBsw : 18|1@0+ (1,0) [0|1] "NoUnit" Vector__XXX
 SG_ IDB_RepeatFromSleep : 24|1@0+ (1,0) [0|1] "NoUnit" Vector__XXX
 SG_ IDB_RepeatFromPrepare : 25|1@0+ (1,0) [0|1] "NoUnit" Vector__XXX
 SG_ IDB_NormalFromRepeat : 26|1@0+ (1,0) [0|1] "NoUnit" Vector__XXX
 SG_ IDB_NormalFromReady : 27|1@0+ (1,0) [0|1] "NoUnit" Vector__XXX
 SG_ IDB_RepeatFromReady : 28|1@0+ (1,0) [0|1] "NoUnit" Vector__XXX
 SG_ IDB_RepeatFromNormal : 29|1@0+ (1,0) [0|1] "NoUnit" Vector__XXX
 SG_ IDB_RemainNetworkWakeUpReason1 : 32|1@0+ (1,0) [0|1] "NoUnit" Vector__XXX
 SG_ IDB_RemainNetworkWakeUpReason2 : 33|1@0+ (1,0) [0|1] "NoUnit" Vector__XXX
 SG_ IDB_RemainNetworkWakeUpReason3 : 34|1@0+ (1,0) [0|1] "NoUnit" Vector__XXX
 SG_ IDB_RemainNetworkWakeUpReason4 : 35|1@0+ (1,0) [0|1] "NoUnit" Vector__XXX

BO_ 193 EHB_Fr02_0C1: 8 EHB_FD3
 SG_ EHB2_FLWhlPulCnt : 7|16@0+ (0.5,0) [0|32767] "NoUnit" ESC_FD3
 SG_ EHB2_FRWhlPulCnt : 23|16@0+ (0.5,0) [0|32767] "NoUnit" ESC_FD3
 SG_ EHB2_FRWhlPulCntValid : 32|1@0+ (1,0) [0|1] "NoUnit" ESC_FD3
 SG_ EHB2_FLWhlPulCntValid : 33|1@0+ (1,0) [0|1] "NoUnit" ESC_FD3
 SG_ EHB2_Fr02_MsgCounter : 51|4@0+ (1,0) [0|15] "NoUnit" ESC_FD3
 SG_ EHB2_Fr02_Checksum : 63|8@0+ (1,0) [0|255] "NoUnit" ESC_FD3

BO_ 195 EHB_Fr04_0C3: 32 EHB_FD3
 SG_ EHB4_FLWhlVelocityValid : 9|1@0+ (1,0) [0|1] "NoUnit" ESC_FD3
 SG_ EHB4_FLWhlVelocity : 7|14@0+ (0.03125,0) [0|511.9375] "km/h" ESC_FD3
 SG_ EHB4_FRWhlVelocityValid : 25|1@0+ (1,0) [0|1] "NoUnit" ESC_FD3
 SG_ EHB4_FRWhlVelocity : 23|14@0+ (0.03125,0) [0|511.9375] "km/h" ESC_FD3
 SG_ EHB4_RRWhlDir : 33|2@0+ (1,0) [0|3] "NoUnit" ESC_FD3
 SG_ EHB4_RLWhlDir : 35|2@0+ (1,0) [0|3] "NoUnit" ESC_FD3
 SG_ EHB4_FRWhlDir : 37|2@0+ (1,0) [0|3] "NoUnit" ESC_FD3
 SG_ EHB4_FLWhlDir : 39|2@0+ (1,0) [0|3] "NoUnit" ESC_FD3
 SG_ EHB4_MsgCounter : 51|4@0+ (1,0) [0|15] "NoUnit" ESC_FD3
 SG_ EHB4_Checksum : 63|8@0+ (1,0) [0|255] "NoUnit" ESC_FD3
 SG_ EHB4_RRWhlVelocityValid : 72|1@0+ (1,0) [0|1] "NoUnit" ESC_FD3
 SG_ EHB4_RLWhlVelocityValid : 73|1@0+ (1,0) [0|1] "NoUnit" ESC_FD3
 SG_ EHB4_RLWhlVelocity : 71|14@0+ (0.03125,0) [0|511.9375] "km/h" ESC_FD3
 SG_ EHB4_RLWhlPulCntValid : 88|1@0+ (1,0) [0|1] "NoUnit" ESC_FD3
 SG_ EHB4_RRWhlPulCntValid : 89|1@0+ (1,0) [0|1] "NoUnit" ESC_FD3
 SG_ EHB4_RRWhlVelocity : 87|14@0+ (0.03125,0) [0|511.9375] "km/h" ESC_FD3
 SG_ EHB4_RLWhlPulCnt : 103|16@0+ (0.5,0) [0|32767] "NoUnit" ESC_FD3
 SG_ EHB4_RRWhlPulCnt : 119|16@0+ (0.5,0) [0|32767] "NoUnit" ESC_FD3

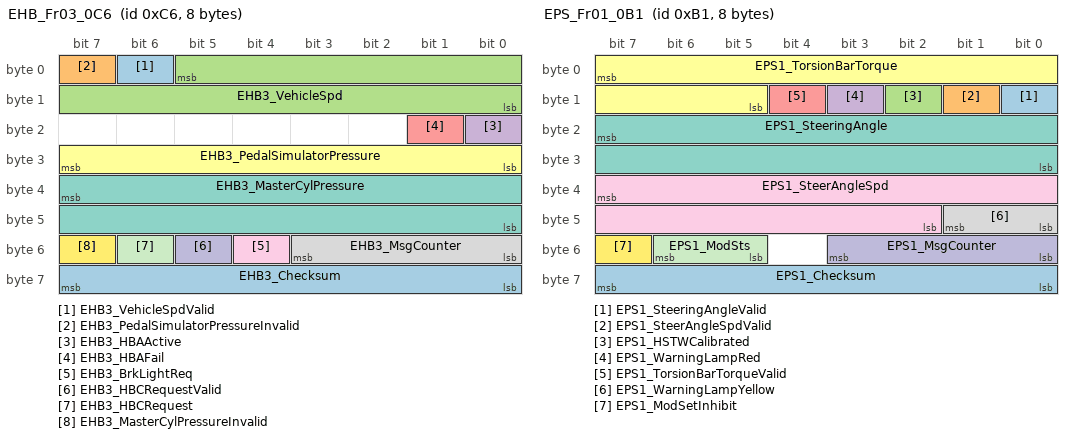
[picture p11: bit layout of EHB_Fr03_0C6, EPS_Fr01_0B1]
BO_ 198 EHB_Fr03_0C6: 8 EHB_FD3
 SG_ EHB3_VehicleSpdValid : 6|1@0+ (1,0) [0|1] "NoUnit" ESC_FD3,ISC
 SG_ EHB3_PedalSimulatorPressureInvalid : 7|1@0+ (1,0) [0|1] "NoUnit" ESC_FD3,ISC
 SG_ EHB3_VehicleSpd : 5|14@0+ (0.03125,0) [0|511.9375] "km/h" ESC_FD3,ISC
 SG_ EHB3_HBAActive : 16|1@0+ (1,0) [0|1] "NoUnit" ESC_FD3,ISC
 SG_ EHB3_HBAFail : 17|1@0+ (1,0) [0|1] "NoUnit" ESC_FD3,ISC
 SG_ EHB3_PedalSimulatorPressure : 31|8@0+ (1,0) [0|250] "Bar" ESC_FD3,ISC
 SG_ EHB3_MasterCylPressure : 39|16@0+ (0.01,-30) [0|280] "Bar" ESC_FD3,ISC
 SG_ EHB3_MsgCounter : 51|4@0+ (1,0) [0|15] "NoUnit" ESC_FD3,ISC
 SG_ EHB3_BrkLightReq : 52|1@0+ (1,0) [0|1] "NoUnit" ESC_FD3,ISC,GW_FD2,BDCS
 SG_ EHB3_HBCRequestValid : 53|1@0+ (1,0) [0|1] "NoUnit" ESC_FD3,ISC
 SG_ EHB3_HBCRequest : 54|1@0+ (1,0) [0|1] "NoUnit" ESC_FD3,ISC
 SG_ EHB3_MasterCylPressureInvalid : 55|1@0+ (1,0) [0|1] "NoUnit" ESC_FD3,ISC
 SG_ EHB3_Checksum : 63|8@0+ (1,0) [0|255] "NoUnit" ESC_FD3,ISC

BO_ 300 ESC_Fr01_12C: 8 ESC_FD3
 SG_ ESC1_EPB_DynamicApplySta : 4|2@0+ (1,0) [0|3] "NoUnit" EHB_FD3
 SG_ ESC1_EPB_ActuatorSt_R : 7|3@0+ (1,0) [0|7] "NoUnit" EHB_FD3
 SG_ ESC1_EPB_ActuatorSt_L : 10|3@0+ (1,0) [0|7] "NoUnit" EHB_FD3
 SG_ ESC1_EpbDrvAwyInt : 11|1@0+ (1,0) [0|1] "NoUnit" EHB_FD3
 SG_ ESC1_EpbActrAvailPrim : 12|1@0+ (1,0) [0|1] "NoUnit" EHB_FD3
 SG_ ESC1_EPB_DisplayMsgID : 15|3@0+ (1,0) [0|7] "NoUnit" EHB_FD3
 SG_ ESC1_EpbActrStatPrim : 20|3@0+ (1,0) [0|6] "NoUnit" EHB_FD3
 SG_ ESC1_EpbAplRelReq : 31|3@0+ (1,0) [0|6] "NoUnit" EHB_FD3
 SG_ ESC1_EPBStatus : 34|3@0+ (1,0) [0|7] "NoUnit" EHB_FD3
 SG_ ESC1_EPBAvailable : 37|3@0+ (1,0) [0|7] "NoUnit" EHB_FD3
 SG_ ESC1_EPBWarnLampReq : 41|2@0+ (1,0) [0|3] "NoUnit" EHB_FD3
 SG_ ESC1_EPBStatusLampReq : 43|2@0+ (1,0) [0|3] "NoUnit" EHB_FD3
 SG_ ESC1_EPBSysBrkLightsReq : 44|1@0+ (1,0) [0|1] "NoUnit" EHB_FD3
 SG_ ESC1_EPBCruiseCtrlCancelReq : 45|1@0+ (1,0) [0|1] "NoUnit" EHB_FD3
 SG_ ESC1_RollingBenchModeSts : 50|1@0+ (1,0) [0|1] "NoUnit" EHB_FD3
 SG_ ESC1_EpbCtrlAvail : 51|1@0+ (1,0) [0|1] "" EHB_FD3
 SG_ ESC1_EPBClusterDispMSG : 54|3@0+ (1,0) [0|7] "NoUnit" EHB_FD3

BO_ 177 EPS_Fr01_0B1: 8 EPS
 SG_ EPS1_SteeringAngleValid : 8|1@0+ (1,0) [0|1] "NoUnit" PDCS_FD3,IDB,ESC_FD3,ADCU_FD3,EHB_FD3,CDCS,ICU_E02,ISC,SRR3,SRR4,BDCS,ADCS_FD3,CDCS_OverSea,IMU,TBOX,FLC_ME_FD3,ACU,FLC_FD3,GW_FD5,GW_FD6,GW_FD4,GW_FD1,ICU,GW_FD2,TBOX_OverSea
 SG_ EPS1_SteerAngleSpdValid : 9|1@0+ (1,0) [0|1] "NoUnit" PDCS_FD3,IDB,SRR3,ESC_FD3,SRR4,ADCU_FD3,EHB_FD3,CDCS,ADCS_FD3,CDCS_OverSea,IMU,FLC_ME_FD3,FLC_FD3,ICU_E02,GW_FD6,ISC,GW_FD4,ICU
 SG_ EPS1_HSTWCalibrated : 10|1@0+ (1,0) [0|1] "NoUnit" PDCS_FD3,IDB,ESC_FD3,ADCU_FD3,EHB_FD3,CDCS,ADCS_FD3,CDCS_OverSea,TBOX,FLC_FD3,GW_FD5,ICU_E02,ISC,GW_FD4,ICU,TBOX_OverSea
 SG_ EPS1_WarningLampRed : 11|1@0+ (1,0) [0|1] "NoUnit" ADCU_FD3,CDCS,ADCS_FD3,CDCS_OverSea,TBOX,FLC_ME_FD3,FLC_FD3,GW_FD5,ICU_E02,ISC,GW_FD4,ICU,TBOX_OverSea
 SG_ EPS1_TorsionBarTorqueValid : 12|1@0+ (1,0) [0|1] "NoUnit" FLC_ME_FD3,FLC_FD3,ISC,ADCU_FD3,ADCS_FD3
 SG_ EPS1_TorsionBarTorque : 7|11@0+ (0.01,-10.24) [-10.24|10.23] "Nm" FLC_ME_FD3,FLC_FD3,ISC,ADCU_FD3,ADCS_FD3
 SG_ EPS1_SteeringAngle : 23|16@0+ (0.0345,-780) [-780|780.021] "degree" PDCS_FD3,IDB,ESC_FD3,ADCU_FD3,EHB_FD3,CDCS,ICU_E02,ISC,SRR3,SRR4,BDCS,ADCS_FD3,CDCS_OverSea,IMU,TBOX,FLC_ME_FD3,ACU,FLC_FD3,GW_FD5,GW_FD6,GW_FD4,GW_FD1,ICU,GW_FD2,TBOX_OverSea
 SG_ EPS1_WarningLampYellow : 41|2@0+ (1,0) [0|3] "NoUnit" FLC_ME_FD3,FLC_FD3,ICU_E02,ISC,ADCU_FD3,GW_FD4,ICU,CDCS,ADCS_FD3,CDCS_OverSea
 SG_ EPS1_SteerAngleSpd : 39|14@0+ (0.125,-1024) [-1024|1023.75] "deg/s" PDCS_FD3,IDB,SRR3,ESC_FD3,SRR4,ADCU_FD3,EHB_FD3,CDCS,ADCS_FD3,CDCS_OverSea,IMU,FLC_ME_FD3,FLC_FD3,ICU_E02,GW_FD6,ISC,GW_FD4,ICU
 SG_ EPS1_MsgCounter : 51|4@0+ (1,0) [0|15] "NoUnit" PDCS_FD3,IDB,SRR3,ESC_FD3,SRR4,ADCU_FD3,EHB_FD3,ADCS_FD3,FLC_ME_FD3,FLC_FD3,GW_FD6,ISC
 SG_ EPS1_ModSts : 54|2@0+ (1,0) [0|3] "NoUnit" ISC,GW_FD4,CDCS,CDCS_OverSea
 SG_ EPS1_ModSetInhibit : 55|1@0+ (1,0) [0|1] "NoUnit" ISC,GW_FD4,CDCS,CDCS_OverSea
 SG_ EPS1_Checksum : 63|8@0+ (1,0) [0|255] "NoUnit" PDCS_FD3,IDB,SRR3,ESC_FD3,SRR4,ADCU_FD3,EHB_FD3,ADCS_FD3,FLC_ME_FD3,FLC_FD3,GW_FD6,ISC

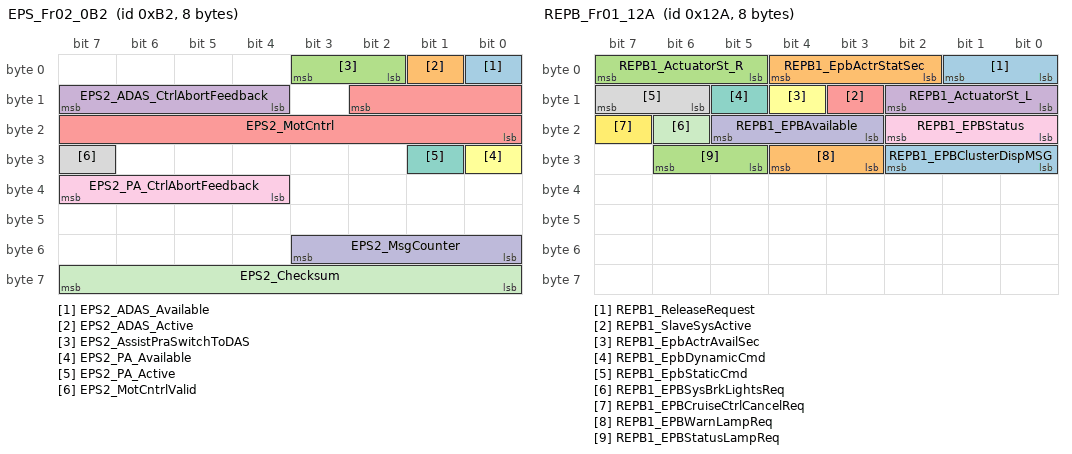
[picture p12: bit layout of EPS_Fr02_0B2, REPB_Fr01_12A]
BO_ 178 EPS_Fr02_0B2: 8 EPS
 SG_ EPS2_ADAS_Available : 0|1@0+ (1,0) [0|1] "NoUnit" FLC_ME_FD3,FLC_FD3,ADCU_FD3,ADCS_FD3
 SG_ EPS2_ADAS_Active : 1|1@0+ (1,0) [0|1] "NoUnit" FLC_ME_FD3,FLC_FD3,ADCU_FD3,ADCS_FD3
 SG_ EPS2_AssistPraSwitchToDAS : 3|2@0+ (1,0) [0|3] "NoUnit" FLC_ME_FD3,FLC_FD3,ADCU_FD3,ADCS_FD3
 SG_ EPS2_ADAS_CtrlAbortFeedback : 15|4@0+ (1,0) [0|15] "NoUnit" FLC_ME_FD3,FLC_FD3,ADCU_FD3,ADCS_FD3
 SG_ EPS2_MotCntrl : 10|11@0+ (0.01,-8) [-8|8] "Nm" FLC_ME_FD3,FLC_FD3,ADCU_FD3,ADCS_FD3
 SG_ EPS2_PA_Available : 24|1@0+ (1,0) [0|1] "NoUnit" FLC_ME_FD3,FLC_FD3,ADCU_FD3,ADCS_FD3
 SG_ EPS2_PA_Active : 25|1@0+ (1,0) [0|1] "NoUnit" FLC_ME_FD3,FLC_FD3,ADCU_FD3,ADCS_FD3
 SG_ EPS2_MotCntrlValid : 31|1@0+ (1,0) [0|1] "NoUnit" FLC_ME_FD3,FLC_FD3,ADCU_FD3,ADCS_FD3
 SG_ EPS2_PA_CtrlAbortFeedback : 39|4@0+ (1,0) [0|15] "NoUnit" FLC_ME_FD3,FLC_FD3,ADCU_FD3,ADCS_FD3
 SG_ EPS2_MsgCounter : 51|4@0+ (1,0) [0|15] "NoUnit" FLC_ME_FD3,FLC_FD3,ADCU_FD3,ADCS_FD3
 SG_ EPS2_Checksum : 63|8@0+ (1,0) [0|255] "NoUnit" FLC_ME_FD3,FLC_FD3,ADCU_FD3,ADCS_FD3

BO_ 298 REPB_Fr01_12A: 8 REPB
 SG_ REPB1_ReleaseRequest : 1|2@0+ (1,0) [0|3] "NoUnit" IDB
 SG_ REPB1_EpbActrStatSec : 4|3@0+ (1,0) [0|6] "NoUnit" IDB
 SG_ REPB1_ActuatorSt_R : 7|3@0+ (1,0) [0|7] "NoUnit" IDB
 SG_ REPB1_ActuatorSt_L : 10|3@0+ (1,0) [0|7] "NoUnit" IDB
 SG_ REPB1_SlaveSysActive : 11|1@0+ (1,0) [0|1] "NoUnit" IDB
 SG_ REPB1_EpbActrAvailSec : 12|1@0+ (1,0) [0|1] "NoUnit" IDB
 SG_ REPB1_EpbDynamicCmd : 13|1@0+ (1,0) [0|1] "NoUnit" IDB
 SG_ REPB1_EpbStaticCmd : 15|2@0+ (1,0) [0|2] "NoUnit" IDB
 SG_ REPB1_EPBStatus : 18|3@0+ (1,0) [0|7] "NoUnit" IDB
 SG_ REPB1_EPBAvailable : 21|3@0+ (1,0) [0|7] "NoUnit" IDB
 SG_ REPB1_EPBSysBrkLightsReq : 22|1@0+ (1,0) [0|1] "NoUnit" IDB
 SG_ REPB1_EPBCruiseCtrlCancelReq : 23|1@0+ (1,0) [0|1] "NoUnit" IDB
 SG_ REPB1_EPBClusterDispMSG : 26|3@0+ (1,0) [0|7] "NoUnit" IDB,GW_FD4,CDCS,CDCS_OverSea
 SG_ REPB1_EPBWarnLampReq : 28|2@0+ (1,0) [0|3] "NoUnit" ICU_E02,IDB,GW_FD4,ICU,CDCS,CDCS_OverSea
 SG_ REPB1_EPBStatusLampReq : 30|2@0+ (1,0) [0|3] "NoUnit" ICU_E02,IDB,GW_FD4,ICU,CDCS,CDCS_OverSea

BO_ 817 ISC_Fr02_331: 8 ISC
 SG_ ISC_ISCErrorSts : 0|1@0+ (1,0) [0|1] "" GW_FD4,CDCS,CDCS_OverSea
 SG_ ISC_ISCModeSetFb : 3|3@0+ (1,0) [0|4] "" GW_FD4,CDCS,CDCS_OverSea

BO_ 555 ISC_Fr01_Dev: 32 ISC
 SG_ ISC_FLWheelAcc : 7|16@0+ (0.001,-16) [-16|16] "G" Vector__XXX
 SG_ ISC_FLBodyAcc : 23|16@0+ (0.001,-16) [-16|16] "G" Vector__XXX
 SG_ ISC_FRWheelAcc : 39|16@0+ (0.001,-16) [-16|16] "G" Vector__XXX
 SG_ ISC_FRBodyAcc : 55|16@0+ (0.001,-16) [-16|16] "G" Vector__XXX
 SG_ ISC_RearBodyAcc : 71|16@0+ (0.001,-16) [-16|16] "G" Vector__XXX
 SG_ ISC_FLCurrentReq : 87|16@0+ (1,0) [0|1600] "mA" Vector__XXX
 SG_ ISC_FRCurrentReq : 103|16@0+ (1,0) [0|1600] "mA" Vector__XXX
 SG_ ISC_RLCurrentReq : 119|16@0+ (1,0) [0|1600] "mA" Vector__XXX
 SG_ ISC_RRCurrentReq : 135|16@0+ (1,0) [0|1600] "mA" Vector__XXX
 SG_ ISC_FLCurrentFb : 151|16@0+ (1,0) [0|1600] "mA" Vector__XXX
 SG_ ISC_FRCurrentFb : 167|16@0+ (1,0) [0|1600] "mA" Vector__XXX
 SG_ ISC_RLCurrentFb : 183|16@0+ (1,0) [0|1600] "mA" Vector__XXX
 SG_ ISC_RRCurrentFb : 199|16@0+ (1,0) [0|1600] "mA" Vector__XXX

BO_ 142 ADCS_Fr02_08E: 16 ADCS_FD3
 SG_ ADCS2_ADAS_EPSAngleReqSt : 0|1@0+ (1,0) [0|1] "NoUnit" ACU,EPS,GW_FD1
 SG_ ADCS2_EPS_LDPState : 3|3@0+ (1,0) [0|7] "NoUnit" ACU,ICU_E02,EPS,GW_FD4,GW_FD1,ICU,CDCS,CDCS_OverSea
 SG_ ADCS2_NNP_SystemFaultStatus : 6|3@0+ (1,0) [0|7] "NoUnit" EPS,GW_FD4,CDCS,CDCS_OverSea
 SG_ ADCS_Pilot_SystemFaultStatus : 10|3@0+ (1,0) [0|7] "NoUnit" EPS
 SG_ ADCS2_ADAS_EPSLateralCtrlType : 14|4@0+ (1,0) [0|15] "NoUnit" ACU,EPS,GW_FD1
 SG_ ADCS2_ADAS_EPSAngleReq : 29|14@0+ (0.1,-720) [-720|720] "degree" ACU,EPS,GW_FD1
 SG_ ADCS2_ADAS_IHBCSysState : 42|3@0+ (1,0) [0|7] "NoUnit" PDCU,ICU_E02,GW_FD4,ICU,GW_FD2,BDCS,DDCU,CDCS,CDCS_OverSea
 SG_ ADCS2_ALCDirection : 45|3@0+ (1,0) [0|7] "NoUnit" ACU,ICU_E02,GW_FD4,GW_FD1,ICU,GW_FD2,BDCS,CDCS,CDCS_OverSea
 SG_ ADCS2_ACC_EpbReq : 47|2@0+ (1,0) [0|3] "NoUnit" IDB,ESC_FD3,EHB_FD3
 SG_ ADCS2_MsgCounter0 : 51|4@0+ (1,0) [0|15] "NoUnit" IDB,ESC_FD3,EPS,EHB_FD3
 SG_ ADCS2_Checksum0 : 63|8@0+ (1,0) [0|255] "NoUnit" IDB,ESC_FD3,EPS,EHB_FD3
 SG_ ADCS2_AEBVehicleHoldReq : 73|1@0+ (1,0) [0|1] "NoUnit" IDB,ESC_FD3,ADCU_FD3,EHB_FD3
 SG_ ADCS2_AEBFullBrake : 74|1@0+ (1,0) [0|1] "NoUnit" PDCS_FD1,IDB,ESC_FD3,ADCU_FD3,EHB_FD3,BDCS,CDCS,CDCS_OverSea,ACU,ICU_E02,GW_FD4,GW_FD1,ICU,GW_FD2,PDCS_HVM_FD1
 SG_ ADCS2_AEBPartialBrake : 75|1@0+ (1,0) [0|1] "NoUnit" IDB,ESC_FD3,ADCU_FD3,EHB_FD3,BDCS,CDCS,CDCS_OverSea,ACU,ICU_E02,GW_FD4,GW_FD1,ICU,GW_FD2
 SG_ ADCS2_AEB_DBSLevel : 77|2@0+ (1,0) [0|3] "NoUnit" IDB,ESC_FD3,ADCU_FD3,EHB_FD3
 SG_ ADCS2_AEBPrefillReq : 78|1@0+ (1,0) [0|1] "NoUnit" IDB,ESC_FD3,ADCU_FD3,EHB_FD3
 SG_ ADCS2_AEB_JerkReq : 79|1@0+ (1,0) [0|1] "NoUnit" IDB,ESC_FD3,ADCU_FD3,GW_FD4,EHB_FD3,CDCS,CDCS_OverSea
 SG_ ADCS2_AEBTargetDeceleration : 87|8@0+ (0.1,-12.7) [-12.7|12.8] "m/s2" IDB,ESC_FD3,EHB_FD3
 SG_ ADCS2_longitudCtrlType : 98|3@0+ (1,0) [0|7] "NoUnit" IDB,ESC_FD3,EHB_FD3
 SG_ ADCS2_LongitudCtrlDecToStopReq : 99|1@0+ (1,0) [0|1] "NoUnit" IDB,ESC_FD3,EHB_FD3
 SG_ ADCS2_LongitudCtrlDriveOff : 100|1@0+ (1,0) [0|1] "NoUnit" IDB,ESC_FD3,EHB_FD3
 SG_ ADCS2_AEB_JerkLevel : 102|2@0+ (1,0) [0|3] "NoUnit" IDB,ESC_FD3,EHB_FD3
 SG_ ADCS2_LongitudCtrlAccelCtrlReq : 116|1@0+ (1,0) [0|1] "NoUnit" PDCS_FD1,ACU,IDB,ESC_FD3,GW_FD1,EHB_FD3,PDCS_HVM_FD1
 SG_ ADCS2_LongitudCtrlTargetAccel : 111|11@0+ (0.01,-10.23) [-10.23|10.24] "m/s2" ACU,IDB,ESC_FD3,GW_FD1,EHB_FD3

BO_ 143 ADCS_Fr11_08F_APA1: 32 ADCU_FD3
 SG_ ADCS11_PA_GearReq : 0|1@0+ (1,0) [0|1] "NoUnit" PDCS_FD1,TBOX,GW_FD5,GW_FD1,PDCS_HVM_FD1,TBOX_OverSea
 SG_ ADCS11_PA_GearPosReqVail : 1|1@0+ (1,0) [0|1] "NoUnit" PDCS_FD1,TBOX,GW_FD5,GW_FD1,PDCS_HVM_FD1,TBOX_OverSea
 SG_ ADCS11_PA_prefillReq : 2|1@0+ (1,0) [0|1] "NoUnit" TBOX,GW_FD5,IDB,ESC_FD3,EHB_FD3,TBOX_OverSea
 SG_ ADCS11_PA_GearPosReq : 5|3@0+ (1,0) [0|7] "NoUnit" PDCS_FD1,TBOX,GW_FD5,GW_FD1,PDCS_HVM_FD1,TBOX_OverSea
 SG_ ADCS11_PA_BrakemodeReq : 7|2@0+ (1,0) [0|3] "NoUnit" TBOX,GW_FD5,IDB,ESC_FD3,EHB_FD3,TBOX_OverSea
 SG_ ADCS11_PA_EpbReq : 17|2@0+ (1,0) [0|3] "NoUnit" TBOX,GW_FD5,IDB,ESC_FD3,EHB_FD3,TBOX_OverSea
 SG_ ADCS11_PA_lampreq : 19|2@0+ (1,0) [0|3] "NoUnit" TBOX,GW_FD5,GW_FD2,BDCS,TBOX_OverSea
 SG_ ADCS11_PA_StopDistance : 15|12@0+ (0.01,0) [0|40.95] "m" TBOX,GW_FD5,IDB,ESC_FD3,EHB_FD3,TBOX_OverSea
 SG_ ADCS11_Parking_WorkSts : 27|4@0+ (1,0) [0|15] "NoUnit" PDCS_FD1,IDB,ESC_FD3,EPS,EHB_FD3,BDCS,CDCS,CDCS_OverSea,TBOX,FLC_FD3,GW_FD5,ICU_E02,GW_FD4,GW_FD1,ICU,GW_FD2,MCU,PDCS_HVM_FD1,TBOX_OverSea
 SG_ ADCS11_RPA_RemoteParkAppStartReq : 28|1@0+ (1,0) [0|1] "NoUnit" TBOX,GW_FD5,GW_FD4,CDCS,CDCS_OverSea,TBOX_OverSea
 SG_ ADCS11_PA_Recover : 29|1@0+ (1,0) [0|1] "NoUnit" TBOX,GW_FD5,IDB,ESC_FD3,GW_FD4,EHB_FD3,CDCS,CDCS_OverSea,TBOX_OverSea
 SG_ ADCS11_TurnLampReq : 31|2@0+ (1,0) [0|3] "NoUnit" TBOX,GW_FD5,TBOX_OverSea
 SG_ ADCS11_SetPathwayWorkSts : 39|2@0+ (1,0) [0|3] "NoUnit" TBOX,GW_FD5,GW_FD4,CDCS,CDCS_OverSea,TBOX_OverSea
 SG_ ADCS11_PA_EPSAngleReq : 37|14@0+ (0.1,-720) [-720|720] "degree" TBOX,GW_FD5,EPS,TBOX_OverSea
 SG_ ADCS11_MsgCounter0 : 51|4@0+ (1,0) [0|15] "NoUnit" PDCS_FD1,TBOX,GW_FD5,IDB,ESC_FD3,EPS,GW_FD1,EHB_FD3,PDCS_HVM_FD1,TBOX_OverSea
 SG_ ADCS11_HPAGuideSts : 54|3@0+ (1,0) [0|7] "NoUnit" TBOX,GW_FD5,GW_FD4,CDCS,CDCS_OverSea,TBOX_OverSea
 SG_ ADCS11_Checksum0 : 63|8@0+ (1,0) [0|255] "NoUnit" PDCS_FD1,TBOX,GW_FD5,IDB,ESC_FD3,EPS,GW_FD1,EHB_FD3,PDCS_HVM_FD1,TBOX_OverSea
 SG_ ADCS11_HPA_WorkSts : 74|3@0+ (1,0) [0|7] "NoUnit" TBOX,GW_FD5,GW_FD4,CDCS,CDCS_OverSea,TBOX_OverSea
 SG_ ADCS11_PA_IDBControlReqV : 75|1@0+ (1,0) [0|1] "NoUnit" TBOX,GW_FD5,IDB,ESC_FD3,EHB_FD3,TBOX_OverSea
 SG_ ADCS11_PA_TarDecel : 71|12@0+ (0.01,-20.48) [-20.48|20.46] "m/s2" PDCS_FD1,TBOX,GW_FD5,IDB,ESC_FD3,GW_FD1,EHB_FD3,PDCS_HVM_FD1,TBOX_OverSea
 SG_ ADCS11_APA_FRWindowsCtrl : 82|3@0+ (1,0) [0|7] "NoUnit" TBOX,GW_FD5,GW_FD2,BDCS,TBOX_OverSea
 SG_ ADCS11_APA_RemoteLockCtrl : 84|2@0+ (1,0) [0|3] "NoUnit" TBOX,GW_FD5,GW_FD2,BDCS,TBOX_OverSea
 SG_ ADCS11_APA_FLWindowsCtrl : 87|3@0+ (1,0) [0|7] "NoUnit" TBOX,GW_FD5,GW_FD2,BDCS,TBOX_OverSea
 SG_ ADCS11_APA_requestMirrorFoldSt : 89|2@0+ (1,0) [0|3] "NoUnit" TBOX,GW_FD5,GW_FD2,BDCS,TBOX_OverSea
 SG_ ADCS11_APA_RRWindowsCtrl : 92|3@0+ (1,0) [0|7] "NoUnit" TBOX,GW_FD5,GW_FD2,BDCS,TBOX_OverSea
 SG_ ADCS11_APA_RLWindowsCtrl : 95|3@0+ (1,0) [0|7] "NoUnit" TBOX,GW_FD5,GW_FD2,BDCS,TBOX_OverSea
 SG_ ADCS11_PA_EPSAngleReqSt : 96|1@0+ (1,0) [0|1] "NoUnit" TBOX,GW_FD5,EPS,TBOX_OverSea
 SG_ ADCS11_PA_EPSAngleReqV : 97|1@0+ (1,0) [0|1] "NoUnit" TBOX,GW_FD5,EPS,TBOX_OverSea
 SG_ ADCS11_PrkngFctnModeReq : 100|3@0+ (1,0) [0|7] "NoUnit" TBOX,GW_FD5,TBOX_OverSea
 SG_ ADCS11_HPAPathlearning_WorkSts : 103|3@0+ (1,0) [0|7] "NoUnit" TBOX,GW_FD5,GW_FD4,CDCS,CDCS_OverSea,TBOX_OverSea
 SG_ ADCS11_HPAPathwaytoCloud_WorkSts : 106|3@0+ (1,0) [0|7] "NoUnit" TBOX,GW_FD5,GW_FD4,CDCS,CDCS_OverSea,TBOX_OverSea
 SG_ ADCS11_TrackreverseWorkSts : 109|3@0+ (1,0) [0|7] "NoUnit" TBOX,GW_FD5,GW_FD4,CDCS,CDCS_OverSea,TBOX_OverSea
 SG_ ADCS11_Currentgear : 111|2@0+ (1,0) [0|3] "NoUnit" TBOX,GW_FD5,GW_FD4,CDCS,CDCS_OverSea,TBOX_OverSea
 SG_ ADCS11_PA_PAMaxSpd : 119|16@0+ (0.015625,0) [0|512] "km/h" PDCS_FD1,TBOX,GW_FD5,IDB,ESC_FD3,GW_FD1,EHB_FD3,PDCS_HVM_FD1,TBOX_OverSea
 SG_ ADCS11_PA_IDBControlReq : 129|2@0+ (1,0) [0|3] "NoUnit" TBOX,GW_FD5,IDB,ESC_FD3,EHB_FD3,TBOX_OverSea
 SG_ ADCS11_APA_RemoteStartReq : 130|1@0+ (1,0) [0|1] "NoUnit" TBOX,GW_FD5,GW_FD2,BDCS,TBOX_OverSea
 SG_ ADCS11_APA_RemoteShutdownReq : 131|1@0+ (1,0) [0|1] "NoUnit" TBOX,GW_FD5,GW_FD2,BDCS,TBOX_OverSea
 SG_ ADCS11_MirrorFoldrequest : 133|2@0+ (1,0) [0|3] "NoUnit" TBOX,GW_FD5,GW_FD2,BDCS,TBOX_OverSea
 SG_ ADCS11_PA_TorqReq : 134|1@0+ (1,0) [0|1] "NoUnit" PDCS_FD1,TBOX,GW_FD5,GW_FD1,PDCS_HVM_FD1,TBOX_OverSea
 SG_ ADCS11_PA_TorqReqValidity : 135|1@0+ (1,0) [0|1] "NoUnit" PDCS_FD1,TBOX,GW_FD5,GW_FD1,PDCS_HVM_FD1,TBOX_OverSea
 SG_ ADCS11_PA_Pause_Recover : 137|2@0+ (1,0) [0|3] "NoUnit" TBOX,GW_FD5,GW_FD4,CDCS,CDCS_OverSea,TBOX_OverSea
 SG_ ADCS11_HPA_BacktoEntrance : 138|1@0+ (1,0) [0|1] "NoUnit" TBOX,GW_FD5,GW_FD4,CDCS,CDCS_OverSea,TBOX_OverSea
 SG_ ADCS11_HPA_BacktoStart : 139|1@0+ (1,0) [0|1] "NoUnit" TBOX,GW_FD5,GW_FD4,CDCS,CDCS_OverSea,TBOX_OverSea
 SG_ ADCS11_PA_TarDecelreq : 141|1@0+ (1,0) [0|1] "NoUnit" TBOX,GW_FD5,IDB,ESC_FD3,EHB_FD3,TBOX_OverSea
 SG_ ADCS11_PA_ParkingFnMd : 143|2@0+ (1,0) [0|3] "NoUnit" TBOX,GW_FD5,IDB,ESC_FD3,EHB_FD3,TBOX_OverSea
 SG_ ADCS11_PA_screenReq : 147|4@0+ (1,0) [0|15] "NoUnit" TBOX,GW_FD5,GW_FD4,CDCS,CDCS_OverSea,TBOX_OverSea
 SG_ ADCS11_HPA_PathlearningSt : 149|2@0+ (1,0) [0|3] "NoUnit" TBOX,GW_FD5,GW_FD4,CDCS,CDCS_OverSea,TBOX_OverSea
 SG_ ADCS11_HPA_Path_exist : 151|2@0+ (1,0) [0|3] "NoUnit" TBOX,GW_FD5,GW_FD4,CDCS,CDCS_OverSea,TBOX_OverSea
 SG_ ADCS11_PA_PickSt : 157|1@0+ (1,0) [0|1] "NoUnit" TBOX,GW_FD5,TBOX_OverSea
 SG_ ADCS11_PA_StopReq : 158|1@0+ (1,0) [0|1] "NoUnit" TBOX,GW_FD5,IDB,ESC_FD3,GW_FD4,EHB_FD3,CDCS,CDCS_OverSea,TBOX_OverSea
 SG_ ADCS11_PA_StopDistanceValid : 159|1@0+ (1,0) [0|1] "NoUnit" TBOX,GW_FD5,IDB,ESC_FD3,EHB_FD3,TBOX_OverSea
 SG_ ADCS11_PA_TorqReqValue : 156|13@0+ (1,-1023) [-1023|1023] "Nm" PDCS_FD1,TBOX,GW_FD5,GW_FD1,PDCS_HVM_FD1,TBOX_OverSea
 SG_ ADCS11_HPA_Pathavailable_ID2 : 175|8@0+ (1,0) [0|255] "NoUnit" TBOX,GW_FD5,GW_FD4,CDCS,CDCS_OverSea,TBOX_OverSea
 SG_ ADCS11_HPA_distance : 183|12@0+ (1,0) [0|4095] "NoUnit" TBOX,GW_FD5,GW_FD4,CDCS,CDCS_OverSea,TBOX_OverSea
 SG_ ADCS11_Parkingtimeremaining : 185|10@0+ (1,0) [0|1023] "NoUnit" TBOX,GW_FD5,GW_FD4,CDCS,CDCS_OverSea,TBOX_OverSea
 SG_ ADCS11_NNS_distance : 207|16@0+ (1,0) [0|65535] "NoUnit" TBOX,GW_FD5,GW_FD4,CDCS,CDCS_OverSea,TBOX_OverSea
 SG_ ADCS11_HPA_Pathavailable_ID1 : 223|8@0+ (1,0) [0|255] "NoUnit" TBOX,GW_FD5,GW_FD4,CDCS,CDCS_OverSea,TBOX_OverSea
 SG_ ADCS11_HighBeam : 225|2@0+ (1,0) [0|3] "NoUnit" TBOX,GW_FD5,GW_FD2,BDCS,TBOX_OverSea
 SG_ ADCS11_ReqPwmode : 227|2@0+ (1,0) [0|3] "NoUnit" TBOX,GW_FD5,GW_FD2,BDCS,TBOX_OverSea
 SG_ ADCS11_SecuritySts : 229|2@0+ (1,0) [0|3] "NoUnit" TBOX,GW_FD5,GW_FD2,BDCS,TBOX_OverSea
 SG_ ADCS11_LowBeam : 231|2@0+ (1,0) [0|3] "NoUnit" TBOX,GW_FD5,GW_FD2,BDCS,TBOX_OverSea
 SG_ ADCS11_PA_IDB_TorqReqValidity : 244|1@0+ (1,0) [0|1] "NoUnit" TBOX,GW_FD5,IDB,ESC_FD3,EHB_FD3,TBOX_OverSea
 SG_ ADCS11_HPA_learnpathdistance : 239|10@0+ (1,0) [0|1023] "NoUnit" TBOX,GW_FD5,GW_FD4,CDCS,CDCS_OverSea,TBOX_OverSea
 SG_ ADCS11_PA_IDB_TorqReqValue : 243|12@0+ (0.5,-1023) [-1023|1023] "Nm" TBOX,GW_FD5,IDB,ESC_FD3,EHB_FD3,TBOX_OverSea

BO_ 254 ADCS_Fr04_0FE_APA2: 32 ADCU_FD3
 SG_ ADCS4_AVM_RCW_warningReq : 1|2@0+ (1,0) [0|3] "NoUnit" IDB,ESC_FD3,GW_FD4,EHB_FD3,CDCS,CDCS_OverSea
 SG_ ADCS4_AVM_BSD_warningReqLeft : 3|2@0+ (1,0) [0|3] "NoUnit" PDCU,GW_FD4,GW_FD2,DDCU,CDCS,CDCS_OverSea
 SG_ ADCS4_AVM_BSD_warningReqRight : 5|2@0+ (1,0) [0|3] "NoUnit" PDCU,GW_FD4,GW_FD2,DDCU,CDCS,CDCS_OverSea
 SG_ ADCS4_SystemFault2 : 7|2@0+ (1,0) [0|3] "NoUnit" GW_FD4,CDCS,CDCS_OverSea
 SG_ ADCS4_TBA_Distance : 13|6@0+ (1,0) [0|63] "m" GW_FD4,CDCS,CDCS_OverSea
 SG_ ADCS4_AVM_DayNightStatus : 14|1@0+ (1,0) [0|1] "NoUnit" GW_FD4,CDCS,CDCS_OverSea
 SG_ ADCS4_APA_InParkingSpaceStatus : 15|1@0+ (1,0) [0|1] "NoUnit" GW_FD4,CDCS,CDCS_OverSea
 SG_ ADCS4_AVM_Sts : 18|3@0+ (1,0) [0|7] "NoUnit" GW_FD4,CDCS,CDCS_OverSea
 SG_ ADCS4_RPA_RemoteParkFinishReq : 20|2@0+ (1,0) [0|3] "NoUnit" TBOX,GW_FD5,GW_FD4,CDCS,CDCS_OverSea,TBOX_OverSea
 SG_ ADCS4_AVM_BSD_SysSts : 23|3@0+ (1,0) [0|7] "NoUnit" GW_FD4,CDCS,CDCS_OverSea
 SG_ ADCS4_PA_InfoDisplayReq : 27|4@0+ (1,0) [0|15] "NoUnit" TBOX,GW_FD5,ICU_E02,GW_FD4,ICU,CDCS,CDCS_OverSea,TBOX_OverSea
 SG_ ADCS4_PA_failinfo : 31|4@0+ (1,0) [0|15] "NoUnit" TBOX,GW_FD5,GW_FD4,CDCS,CDCS_OverSea,TBOX_OverSea
 SG_ ADCS4_UPA_Sound_Location : 35|4@0+ (1,0) [0|15] "NoUnit" GW_FD4,CDCS,CDCS_OverSea
 SG_ ADCS4_HPA_failinfo : 39|4@0+ (1,0) [0|15] "NoUnit" GW_FD4,CDCS,CDCS_OverSea
 SG_ ADCS4_UPA_SysSoundIndication : 42|3@0+ (1,0) [0|7] "NoUnit" GW_FD4,CDCS,CDCS_OverSea
 SG_ ADCS4_AVM_SysSoundIndication : 45|3@0+ (1,0) [0|7] "NoUnit" GW_FD4,CDCS,CDCS_OverSea
 SG_ ADCS4_DCWposition : 47|2@0+ (1,0) [0|3] "NoUnit" GW_FD4,CDCS,CDCS_OverSea
 SG_ ADCS4_MsgCounter0 : 51|4@0+ (1,0) [0|15] "NoUnit" Vector__XXX
 SG_ ADCS4_PA_ParkBarPercent : 55|4@0+ (1,0) [0|15] "NoUnit" TBOX,GW_FD5,GW_FD4,CDCS,CDCS_OverSea,TBOX_OverSea
 SG_ ADCS4_Checksum0 : 63|8@0+ (1,0) [0|255] "NoUnit" Vector__XXX
 SG_ ADCS4_APA_FunctionMode : 70|3@0+ (1,0) [0|7] "NoUnit" TBOX,GW_FD5,GW_FD4,CDCS,CDCS_OverSea,TBOX_OverSea
 SG_ ADCS4_HornReq : 71|1@0+ (1,0) [0|1] "NoUnit" GW_FD2,BDCS
 SG_ ADCS4_Text : 79|8@0+ (1,0) [0|255] "NoUnit" TBOX,GW_FD5,GW_FD4,CDCS,CDCS_OverSea,TBOX_OverSea
 SG_ ADCS4_ParkingswithReq : 80|1@0+ (1,0) [0|1] "NoUnit" TBOX,GW_FD5,GW_FD4,CDCS,CDCS_OverSea,TBOX_OverSea
 SG_ ADCS4_Slotavaliable : 82|2@0+ (1,0) [0|3] "NoUnit" TBOX,GW_FD5,GW_FD4,CDCS,CDCS_OverSea,TBOX_OverSea
 SG_ ADCS4_locationSt : 84|2@0+ (1,0) [0|3] "NoUnit" GW_FD4,CDCS,CDCS_OverSea
 SG_ ADCS4_DCWlevel : 87|3@0+ (1,0) [0|7] "NoUnit" GW_FD4,CDCS,CDCS_OverSea
 SG_ ADCS4_PA_GuideLineE_a : 95|16@0+ (0.01,0) [0|655.35] "NoUnit" TBOX,GW_FD5,GW_FD4,CDCS,CDCS_OverSea,TBOX_OverSea
 SG_ ADCS4_PA_GuideLineE_b : 111|16@0+ (0.01,0) [0|655.35] "NoUnit" TBOX,GW_FD5,GW_FD4,CDCS,CDCS_OverSea,TBOX_OverSea
 SG_ ADCS4_PA_GuideLineE_c : 127|16@0+ (0.01,0) [0|655.35] "NoUnit" TBOX,GW_FD5,GW_FD4,CDCS,CDCS_OverSea,TBOX_OverSea
 SG_ ADCS4_PA_GuideLineE_d : 143|16@0+ (0.01,0) [0|655.35] "NoUnit" TBOX,GW_FD5,GW_FD4,CDCS,CDCS_OverSea,TBOX_OverSea
 SG_ ADCS4_PA_GuideLineE_Xmin : 159|16@0+ (0.01,0) [0|655.35] "NoUnit" TBOX,GW_FD5,GW_FD4,CDCS,CDCS_OverSea,TBOX_OverSea
 SG_ ADCS4_PA_GuideLineE_Xmax : 175|16@0+ (0.01,0) [0|655.35] "NoUnit" TBOX,GW_FD5,GW_FD4,CDCS,CDCS_OverSea,TBOX_OverSea
 SG_ ADCS4_HPA_deleteMapSt : 187|2@0+ (1,0) [0|3] "NoUnit" GW_FD4,CDCS,CDCS_OverSea
 SG_ ADCS4_HPA_uploadMapSt : 191|4@0+ (1,0) [0|15] "NoUnit" GW_FD4,CDCS,CDCS_OverSea
 SG_ ADCS4_ParkingTime : 185|10@0+ (1,0) [0|1023] "s" TBOX,GW_FD5,GW_FD4,CDCS,CDCS_OverSea,TBOX_OverSea
 SG_ ADCS4_HPAWarningInfo : 203|4@0+ (1,0) [0|15] "NoUnit" GW_FD4,CDCS,CDCS_OverSea
 SG_ ADCS4_AVM_vedioReq : 206|3@0+ (1,0) [0|7] "NoUnit" GW_FD4,CDCS,CDCS_OverSea
 SG_ ADCS4_HPA_FunctionMode : 208|1@0+ (1,0) [0|1] "NoUnit" GW_FD4,CDCS,CDCS_OverSea
 SG_ ADCS4_NNS_FunctionMode : 211|3@0+ (1,0) [0|7] "NoUnit" TBOX,GW_FD5,GW_FD4,CDCS,CDCS_OverSea,TBOX_OverSea
 SG_ ADCS4_TractionswithReq : 212|1@0+ (1,0) [0|1] "NoUnit" GW_FD4,CDCS,CDCS_OverSea
 SG_ ADCS4_RPA_FunctionMode : 215|3@0+ (1,0) [0|7] "NoUnit" TBOX,GW_FD5,GW_FD4,CDCS,CDCS_OverSea,TBOX_OverSea
 SG_ ADCS4_HourOfDay : 221|6@0+ (1,0) [0|63] "NoUnit" TBOX,GW_FD5,GW_FD4,CDCS,CDCS_OverSea,TBOX_OverSea
 SG_ ADCS4_MinuteOfHour : 229|6@0+ (1,0) [0|63] "NoUnit" TBOX,GW_FD5,GW_FD4,CDCS,CDCS_OverSea,TBOX_OverSea
 SG_ ADCS4_GMState : 231|2@0+ (1,0) [0|3] "NoUnit" TBOX,GW_FD5,GW_FD4,CDCS,CDCS_OverSea,TBOX_OverSea
 SG_ ADCS4_SecondOfMinute : 237|6@0+ (1,0) [0|63] "NoUnit" TBOX,GW_FD5,GW_FD4,CDCS,CDCS_OverSea,TBOX_OverSea
 SG_ ADCS4_GMWarnState : 239|2@0+ (1,0) [0|3] "NoUnit" TBOX,GW_FD5,GW_FD4,GW_FD2,BDCS,CDCS,CDCS_OverSea,TBOX_OverSea
 SG_ ADCS4_DCWworkSt : 242|3@0+ (1,0) [0|7] "NoUnit" GW_FD4,CDCS,CDCS_OverSea
 SG_ ADCS4_DCWtext : 245|3@0+ (1,0) [0|7] "NoUnit" GW_FD4,CDCS,CDCS_OverSea
 SG_ ADCS4_GM_SystemFaultStatus : 247|2@0+ (1,0) [0|3] "NoUnit" ICU_E02,GW_FD4,ICU,CDCS,CDCS_OverSea
 SG_ ADCS4_GMWorkState : 255|3@0+ (1,0) [0|7] "NoUnit" TBOX,GW_FD5,GW_FD4,CDCS,CDCS_OverSea,TBOX_OverSea

BO_TX_BU_ 192 : IDB,ESC_FD3;
BO_TX_BU_ 197 : IDB,ESC_FD3;
BO_TX_BU_ 199 : IDB,ESC_FD3;
BO_TX_BU_ 201 : IDB,EHB_FD3;
BO_TX_BU_ 202 : IDB,ESC_FD3;
BO_TX_BU_ 229 : IDB,EHB_FD3;
BO_TX_BU_ 289 : IDB,EHB_FD3;
BO_TX_BU_ 297 : IDB,EHB_FD3;
BO_TX_BU_ 299 : IDB,EHB_FD3;
BO_TX_BU_ 301 : IDB,ESC_FD3;
BO_TX_BU_ 302 : IDB,EHB_FD3;
BO_TX_BU_ 303 : IDB,ESC_FD3;
BO_TX_BU_ 142 : ADCS_FD3,FLC_ME_FD3,FLC_FD3;
BO_TX_BU_ 143 : ADCU_FD3,ADCS_FD3;
BO_TX_BU_ 254 : ADCU_FD3,ADCS_FD3;
CM_ SG_ 267 MCU2_MilLampRequest "MIL故障灯点亮";
CM_ SG_ 267 MCU2_Fault_Level "当MCU检测到故障时，故障状态置位";
CM_ SG_ 267 MCU2_MotorFaultLampRequest "电机故障灯点亮";
CM_ SG_ 267 MCU2_Motor_Block_Warning "电机堵转警告";
CM_ SG_ 267 MCU2_OpenProtion_Lock_Fault "MCU开盖保护状态";
CM_ SG_ 267 MCU2_Cooling_System_Fault "MCU冷却系统故障";
CM_ SG_ 267 MCU2_Self_check_Fault "MCU自检故障";
CM_ SG_ 267 MCU2_Sensor_Check_Fault "MCU传感器自检故障";
CM_ SG_ 267 MCU2_Battery_Check_Fault "MCU低压电源输入故障";
CM_ SG_ 267 MCU2_Motor_Lack_of_Phase_Fault "电机缺相故障";
CM_ SG_ 267 MCU2_RDC_Alignment_Fault "电机位置角度故障";
CM_ SG_ 267 MCU2_DampingTq "MCU防抖扭矩";
CM_ SG_ 267 MCU2_PhaseOvercurrentFault "相电流过流";
CM_ SG_ 267 MCU2_InverterFault "逆变器故障";
CM_ SG_ 267 MCU2_SensorSupplyVoltageFault "传感器的供电电压故障";
CM_ SG_ 267 MCU2_DC_link_OvercurrentFault "母线电流过流";
CM_ SG_ 267 MCU2_GateDriverDesaturationFault "功率模块故障";
CM_ SG_ 267 MCU2_MotorPositionSensorFault "电机位置传感器故障";
CM_ SG_ 267 MCU2_DischargeOverTime "放电超时故障";
CM_ SG_ 267 MCU2_SumPhaseCurrentOverThd "三相电流和超限故障";
CM_ SG_ 267 MCU2_MotorOvertempFault "电机温度过高";
CM_ SG_ 267 MCU2_A_phase_OvercurrWarn "A相电流过载";
CM_ SG_ 267 MCU2_B_phase_OvercurrWarn "B 相电流过载";
CM_ SG_ 267 MCU2_C_phase_OvercurrentWarning "C 相电流过载";
CM_ SG_ 267 MCU2_InverterOvertempFault "逆变器温度过高（驱动电机控制器温度报警）";
CM_ SG_ 267 MCU2_Rx_CAN_Failed "CAN 总线故障";
CM_ SG_ 267 MCU2_LV_PowerSupplyFault "控制器供电电压故障";
CM_ SG_ 267 MCU2_IgnSts_Dev "MCU点火状态";
CM_ SG_ 267 MCU2_HV_Battery_Connect_states "电池连接状态";
CM_ SG_ 267 MCU2_VCU_Inverter_states "VCU对Inverter的控制状态";
CM_ SG_ 267 MCU2_SafetyFault "MCU安全故障";
CM_ SG_ 267 MCU2_ModeError "电机模式故障";
CM_ SG_ 267 MCU2_GateDriverVoltageSupplyFault "门驱动供电电压故障";
CM_ SG_ 267 MCU2_Fr02_AliveCounter "检测控制器工作信号";
CM_ SG_ 494 MCU3_DC_link_Voltage "直流母线电压";
CM_ SG_ 494 MCU3_DC_link_Current "直流母线电流";
CM_ SG_ 494 MCU3_ActiveDischargeSts "主动放电状态";
CM_ SG_ 494 MCU3_ShakeRednFb "MCU防抖反馈";
CM_ SG_ 494 MCU3_HVIL_DCBus "直流母线互锁（国标报警）
当MCU检测到直流母线互锁硬件信号时反馈环路互锁连接状态为1，否则为0";
CM_ SG_ 494 MCU3_InverterTemperature "逆变器温度";
CM_ SG_ 494 MCU3_MotorTemperature "电机温度";
CM_ SG_ 735 MCU4_AlOfsNoPlaus "偏移角标定结果可信度诊断";
CM_ SG_ 735 MCU4_Can_BusOff "Can总线关闭";
CM_ SG_ 735 MCU4_IUMonOvHiRng "U相监控电流超高限";
CM_ SG_ 735 MCU4_IUMonOvLoRng "U相监控电流超低限";
CM_ SG_ 735 MCU4_IUOc "U相过流";
CM_ SG_ 735 MCU4_IUOvHiRng "U相电流超高限";
CM_ SG_ 735 MCU4_IUOvLoRng "U相电流超低限";
CM_ SG_ 735 MCU4_IVMonOvHiRng "V相监控电流超高限";
CM_ SG_ 735 MCU4_IVMonOvLoRng "V相监控电流超低限";
CM_ SG_ 735 MCU4_IVOc "V相过流";
CM_ SG_ 735 MCU4_IVOvHiRng "V相电流超高限";
CM_ SG_ 735 MCU4_IVOvLoRng "V相电流超低限";
CM_ SG_ 735 MCU4_IWMonOvHiRng "W相监控电流超高限";
CM_ SG_ 735 MCU4_IWMonOvLoRng "W相监控电流超低限";
CM_ SG_ 735 MCU4_IWOc "W相过流";
CM_ SG_ 735 MCU4_IWOvHiRng "W相电流超高限";
CM_ SG_ 735 MCU4_IWOvLoRng "W相电流超低限";
CM_ SG_ 735 MCU4_IphaOC "相电流硬件过流";
CM_ SG_ 735 MCU4_IphaOffCal "相电流偏移量标定";
CM_ SG_ 735 MCU4_MosTHiRng "EPP mos管过温故障";
CM_ SG_ 735 MCU4_NFltHA "上桥A故障";
CM_ SG_ 735 MCU4_NFltHB "上桥B故障";
CM_ SG_ 735 MCU4_NFltLA "下桥A故障";
CM_ SG_ 735 MCU4_NFltLB "下桥B故障";
CM_ SG_ 735 MCU4_RslvDos "旋变Dos故障";
CM_ SG_ 735 MCU4_RslvLos "旋变Los故障";
CM_ SG_ 735 MCU4_RslvLot "旋变Lot故障";
CM_ SG_ 735 MCU4_HwPhaCurPosBackErr "硬件电流阈值正值回采故障";
CM_ SG_ 735 MCU4_HwPhaCurNegBackErr "硬件电流阈值负值回采故障";
CM_ SG_ 735 MCU4_TSttr1OvHiLim "第一路定子温度超高限";
CM_ SG_ 735 MCU4_TSttr1OvLoLim "第一路定子温度超低限";
CM_ SG_ 735 MCU4_TSttr2OvHiLim "第二路定子温度超高限";
CM_ SG_ 735 MCU4_TSttr2OvLoLim "第二路定子温度超低限";
CM_ SG_ 735 MCU4_TUErrOff "U相温度传感器出错";
CM_ SG_ 735 MCU4_TVErrOff "V相温度传感器出错";
CM_ SG_ 735 MCU4_TWErrOff "W相温度传感器出错";
CM_ SG_ 735 MCU4_tDBCTempUHiLom "U相DBC温度超高限";
CM_ SG_ 735 MCU4_tDBCTempULoLom "U相DBC温度超低限";
CM_ SG_ 735 MCU4_tDBCTempVHiLom "V相DBC温度超高限";
CM_ SG_ 735 MCU4_tDBCTempVLoLom "V相DBC温度超低限";
CM_ SG_ 735 MCU4_tDBCTempWHiLom "W相DBC温度超高限";
CM_ SG_ 735 MCU4_tDBCTempWLoLom "W相DBC温度超低限";
CM_ SG_ 735 MCU4_QtShrGnd "驱动板供电短路到地";
CM_ SG_ 735 MCU4_SttrTemp1ShrGnd "电机第一路采样短路到地";
CM_ SG_ 735 MCU4_SttrTemp2ShrGnd "电机第二路采样短路到地";
CM_ SG_ 735 MCU4_UMonShrGnd "U相电流监控采样短路到地";
CM_ SG_ 735 MCU4_VMonShrGnd "V相电流监控采样短路到地";
CM_ SG_ 735 MCU4_WMonShrGnd "W相电流监控采样短路到地";
CM_ SG_ 735 MCU4_UShrGnd "U相电流采样短路到地";
CM_ SG_ 735 MCU4_VShrGnd "V相电流采样短路到地";
CM_ SG_ 735 MCU4_WShrGnd "W相电流采样短路到地";
CM_ SG_ 735 MCU4_UKl30Ov "KL30过压";
CM_ SG_ 735 MCU4_UKl30Unv "KL30欠压";
CM_ SG_ 735 MCU4_VcuRecOvTime "VCU接收超时";
CM_ SG_ 735 MCU4_UdcLnkOvHiRng "母线电压超高限";
CM_ SG_ 735 MCU4_UdcLnkOvLoRng "母线电压超低限";
CM_ SG_ 735 MCU4_OverSpdDetn "过转速检测故障";
CM_ SG_ 1590 MCU_SourceNodeIdentifier "ECU节点标识符";
CM_ SG_ 1590 MCU_RepeatMessageRequest "Repeat Message请求";
CM_ SG_ 1590 MCU_Reserve1 "预留";
CM_ SG_ 1590 MCU_ActiveWakeup "激活唤醒，主动唤醒网络时置1，其他（包括被动唤醒节点）为0";
CM_ SG_ 1590 MCU_Reserve2 "预留";
CM_ SG_ 1590 MCU_WakeUp_Reason1 "唤醒原因1";
CM_ SG_ 1590 MCU_WakeUp_NM "NM报文唤醒";
CM_ SG_ 1590 MCU_RemainNetworkWakeUpReason1 "保持网络唤醒原因1";
CM_ SG_ 1590 MCU_RemainNetworkWakeUpReason2 "保持网络唤醒原因2";
CM_ SG_ 1590 MCU_RemainNetworkWakeUpReason3 "保持网络唤醒原因3";
CM_ SG_ 1590 MCU_RemainNetworkWakeUpReason4 "保持网络唤醒原因4";
CM_ SG_ 518 DCDC2_Input_Vol "DCDC输入电压";
CM_ SG_ 518 DCDC2_Output_Vol "DCDC输出电压";
CM_ SG_ 518 DCDC2_Temp "DCDC温度";
CM_ SG_ 518 DCDC2_Input_Cur "DCDC输入电流";
CM_ SG_ 518 DCDC2_Output_Cur "DCDC输出电流";
CM_ SG_ 518 DCDC2_OutPower_Max "DCDC当前可输出最大功率";
CM_ SG_ 522 DCDC1_WorkState "DCDC工作状态";
CM_ SG_ 522 DCDC1_StatusAlarm "DCDC故障等级";
CM_ SG_ 522 DCDC1_HW_Fault "DCDC硬件故障";
CM_ SG_ 522 DCDC1_Comm_Fault "DCDC通讯故障";
CM_ SG_ 522 DCDC1_IN_Ov_Vol_Ft "DCDC输入过压故障";
CM_ SG_ 522 DCDC1_IN_Un_Vol_Ft "DCDC输入欠压故障";
CM_ SG_ 522 DCDC1_Out_Ov_Vol_Ft "DCDC输出过压故障";
CM_ SG_ 522 DCDC1_Out_Un_Vol_Ft "DCDC输出欠压故障";
CM_ SG_ 522 DCDC1_INV_PresentActivityFault "INV故障码";
CM_ SG_ 522 DCDC1_OutputSh_Pr "DCDC输出短路保护";
CM_ SG_ 522 DCDC1_OvTemp_Pr "DCDC过温保护（DC-DC温度报警）";
CM_ SG_ 522 DCDC1_OvPowerOut_Pr "DCDC超功率输出保护";
CM_ SG_ 522 DCDC1_Out_Ov_Cur_Ft "DCDC输出过流故障";
CM_ SG_ 522 DCDC1_AliveCounter "E2E Profile2-CRC8H2F，Counter:0-15";
CM_ SG_ 522 DCDC1_PresentActivityFault "DCDC故障码";
CM_ SG_ 522 DCDC1_Checksum "E2E Profile2-CRC8H2F
DataID List:#84 - 128 61 228 182 89 180 44 105 245 137 215 134 80 152 12 70";
CM_ SG_ 279 OBC4_Connect_Status_CC "CC连接状态";
CM_ SG_ 279 OBC4_RelayState "快充接触器状态";
CM_ SG_ 279 OBC4_SlowChargeCC "慢充CC状态";
CM_ SG_ 279 OBC4_SlowChargeCP "慢充CP(0-100)";
CM_ SG_ 279 OBC4_InverterSlowchargeCC "逆变慢充CC状态，不同于慢充CC信号";
CM_ SG_ 279 OBC4_RelayOutside_VolValid "快充接触器外侧电压有效性";
CM_ SG_ 279 OBC4_ChargeEnableVCU "慢充硬线使能VCU";
CM_ SG_ 279 OBC4_CP_PWM_Amplitude "慢充CP幅值";
CM_ SG_ 279 OBC4_RelayOutside_Vol "快充接触器外侧电压";
CM_ SG_ 279 OBC4_InverterSlowchaegeCP "V2V放电CP值";
CM_ SG_ 279 OBC4_Inner_PresentActivityFault "内部其他故障码";
CM_ SG_ 599 OBC2_E_lockCont "电子锁控制";
CM_ SG_ 599 OBC2_Pre_theft_fb "电子锁防盗状态反馈";
CM_ SG_ 599 OBC2_CurrentEnablePowerOut_Max "充电机当前可输出的最大功率";
CM_ SG_ 599 OBC2_ACPowerGridCur_Fb "OBC反馈交流电网电流";
CM_ SG_ 599 OBC2_ACPowerGridVolt_Fb "OBC反馈交流电网电压";
CM_ SG_ 599 OBC2_E_lockSts "电子锁状态";
CM_ SG_ 599 OBC2_ACinletSnsrSts "慢充温度传感器状态";
CM_ SG_ 599 OBC2_ACinletTempErr "慢充插座温度故障";
CM_ SG_ 599 OBC2_S2_State "S2状态";
CM_ SG_ 599 OBC2_ACinletSnsrSts2 "慢充温度传感器2状态";
CM_ SG_ 599 OBC2_ACinletSnsrSts3 "慢充温度传感器3状态";
CM_ SG_ 602 OBC1_CM_State "充电机状态";
CM_ SG_ 602 OBC1_MilLampRequest "MIL故障灯点亮申请";
CM_ SG_ 602 OBC1_StatusAlarm "OBC故障等级";
CM_ SG_ 602 OBC1_No_Battery "充电机未检测到电池包或电池电压过低故障";
CM_ SG_ 602 OBC1_ChargeCurrent "充电机输出电流";
CM_ SG_ 602 OBC1_ChargeVoltage "充电机输出电压";
CM_ SG_ 602 OBC1_HighVoltOutput_UnderVoltFlt "充电机高压输出欠压故障";
CM_ SG_ 602 OBC1_HighVoltOutput_OverVoltFlt "充电机高压输出过压故障";
CM_ SG_ 602 OBC1_HighVoltOutput_ShortCircuitFlt "充电机高压输出回路短路故障";
CM_ SG_ 602 OBC1_Input_UnderVoltage "充电机交流电输入欠压故障";
CM_ SG_ 602 OBC1_Input_OverVoltage "充电机交流电输入过压故障";
CM_ SG_ 602 OBC1_Over_Temperature "充电机过温故障";
CM_ SG_ 602 OBC1_High_Current_Output_Fault "充电机输出电流故障";
CM_ SG_ 602 OBC1_CANMsgFault "充电机CAN故障";
CM_ SG_ 602 OBC1_Battery_Reverse "电池包正负极反接故障";
CM_ SG_ 602 OBC1_Temp "OBC温度";
CM_ SG_ 665 OBC3_Inverter_ChargeCurInp "充电机逆变输入电流";
CM_ SG_ 665 OBC3_Inverter_ChargeVoltInp "充电机逆变输入电压";
CM_ SG_ 665 OBC3_InverterMode_Fb "OBC逆变模式反馈";
CM_ SG_ 665 OBC3_Inverter_PowerOut "OBC逆变输出功率";
CM_ SG_ 665 OBC3_PresentActivityFault "OBC故障码";
CM_ SG_ 698 OBC5_NegRelayState "快充负接触器状态";
CM_ SG_ 698 OBC5_Inverter_ChargeVolt "OBC逆变输出电压";
CM_ SG_ 698 OBC5_PosRelayStateOutsideSwitch "快充正极检测回路继电器状态";
CM_ SG_ 698 OBC5_NegRelayStateOutsideSwitch "快充负极检测回路继电器状态";
CM_ SG_ 698 OBC5_Inverter_ChargeCur "OBC逆变输出电流";
CM_ SG_ 698 OBC5_NegRelayOutside_Vol "快充负接触器外侧电压";
CM_ SG_ 921 OBC6_lntTemp1 "慢充插座温度NTC1温度";
CM_ SG_ 921 OBC6_lntTemp2 "慢充插座温度NTC2温度";
CM_ SG_ 921 OBC6_lntTemp3 "慢充插座温度NTC3温度";
CM_ SG_ 921 OBC6_lntTemp4 "慢充插座温度NTC4温度";
CM_ SG_ 921 OBC6_lntTemp5 "慢充插座温度NTC5温度";
CM_ SG_ 921 OBC6_lntTemp6 "慢充插座温度NTC6温度";
CM_ SG_ 1542 CDU_SourceNodeIdentifier "ECU节点标识符";
CM_ SG_ 1542 CDU_RepeatMessageRequest "Repeat Message请求";
CM_ SG_ 1542 CDU_Reserve1 "预留";
CM_ SG_ 1542 CDU_ActiveWakeup "激活唤醒，主动唤醒网络时置1，其他（包括被动唤醒节点）为0";
CM_ SG_ 1542 CDU_Reserve2 "预留";
CM_ SG_ 1542 CDU_WakeUp_KL15 "KL15 ON唤醒";
CM_ SG_ 1542 CDU_WakeUp_ACcharging "交流充电";
CM_ SG_ 1542 CDU_WakeUp_BMSIntelligentCharging "BMS智能充电";
CM_ SG_ 1542 CDU_WakeUp_ACchargingThermal "交流充电热管理";
CM_ SG_ 1542 CDU_WakeUp_LocalPreCharge "本地预约充电";
CM_ SG_ 1542 CDU_WakeUp_RemotePreCharge "远程预约充电";
CM_ SG_ 1542 CDU_WakeUp_OTA "OTA";
CM_ SG_ 1542 CDU_WakeUpReason8 "右后外释放开关";
CM_ SG_ 1542 CDU_RemainNetworkWakeUpReason1 "保持网络唤醒原因1";
CM_ SG_ 1542 CDU_RemainNetworkWakeUpReason2 "保持网络唤醒原因2";
CM_ SG_ 1542 CDU_RemainNetworkWakeUpReason3 "保持网络唤醒原因3";
CM_ SG_ 1542 CDU_RemainNetworkWakeUpReason4 "保持网络唤醒原因4";
CM_ SG_ 128 EMS1_EngineStartedCompleted "Engine start completed";
CM_ SG_ 128 EMS1_EngineStopAllow "Engine stop allowed";
CM_ SG_ 128 EMS1_ActualEngineTorqueValid "Actual engine flywheel torque validity";
CM_ SG_ 128 EMS1_ActualEngineTorque "Actual engine flywheel torque";
CM_ SG_ 128 EMS1_EngineTorqMin "Min engine torque (Flywheel/Indicated)";
CM_ SG_ 128 EMS1_EngineTorqMax "Max engine torque (Flywheel/Indicated)";
CM_ SG_ 128 EMS1_MsgCounter "E2E Profile2-CRC8H2F，Counter:0-15";
CM_ SG_ 128 EMS1_EngineTorqLoss "Engine friction torque";
CM_ SG_ 128 EMS1_Checksum "E2E Profile2-CRC8H2F
DataID List:#19 - 42 45 226 106 113 62 80 154 133 115 60 98 94 63 21 212";
CM_ SG_ 248 EMS2_EngineDFCOConditionReq "Deceleration fuel cut off condition request (for O2 diag)";
CM_ SG_ 248 EMS2_EngineIdleStateRequest "Engine idle state request
 (for PCVD/ICMD diag)";
CM_ SG_ 248 EMS2_CatalystHeatingSt "Catalyst heating active status";
CM_ SG_ 248 EMS2_EngineSpeed "Engine Speed";
CM_ SG_ 248 EMS2_ToothLearningReq "齿讯学习请求信号";
CM_ SG_ 248 EMS2_EngineFuelCutOffStatus "Engine fuel cut off status";
CM_ SG_ 248 EMS2_EngIdleStatusActive "Engine idle status";
CM_ SG_ 248 EMS2_DesireIdleSpeed "Desired idle speed";
CM_ SG_ 248 EMS2_EngineCoolantTemp "Engine Coolant Temperature";
CM_ SG_ 248 EMS2_EngineState "Engine state";
CM_ SG_ 248 EMS2_FaultLevel "Engine fault level";
CM_ SG_ 544 EMS3_FuelConsumption "Engine fuel consume(100ms)";
CM_ SG_ 544 EMS3_MilLampRequest "ECU request Mil lamp";
CM_ SG_ 544 EMS3_SVSLampRequest "ECU request SVS lamp";
CM_ SG_ 544 EMS3_FVV_Status "FVV  status";
CM_ SG_ 544 EMS3_TankPressureValid "Tank pressure validity";
CM_ SG_ 544 EMS3_Engineoilpressure "发动机机油压力";
CM_ SG_ 544 EMS3_FuellevelValid "燃油液位有效位";
CM_ SG_ 544 EMS3_TankPressure "Tank pressure";
CM_ SG_ 544 EMS3_Fuellevel "燃油液位";
CM_ SG_ 544 EMS3_environment_pressure "环境压力";
CM_ SG_ 544 EMS3_FuelLevelResistor "油箱油位传感器电阻值";
CM_ SG_ 554 EMS5_DriveCycleMet "OBD基础信号
EMS Drive Cycle met";
CM_ SG_ 554 EMS5_WarmUpCycleMet "OBD基础信号
EMS WarmUp Cycle met";
CM_ SG_ 554 EMS5_DenomComCriteriaMet "OBD基础信号
EMS DenomCom Criteria Met";
CM_ SG_ 554 EMS5_ColdstartDenomComCriteriaMet "OBD基础信号
EMS Coldstart DenomCom Criteria Met";
CM_ SG_ 554 EMS5_EngStartRq "EMS基础信号
Engine Start Request";
CM_ SG_ 554 EMS5_SpdSyncSt "EMS基础信号
SpdSyncSt";
CM_ SG_ 554 EMS5_EngintakeAirTemp "EMS基础信号
EngintakeAirTemp";
CM_ SG_ 554 EMS5_CalculatedLoadValue "EMS基础信号
CalculatedLoadValue";
CM_ SG_ 554 EMS5_RealIgnitionAngle "EMS基础信号
RealIgnitionAngle";
CM_ SG_ 554 EMS5_IntakeManifoldPressure "EMS基础信号
IntakeManifoldPressure";
CM_ SG_ 554 EMS5_EGRRatio "EMS EGR率";
CM_ SG_ 554 EMS5_VVTinletAngle "EMS VVT角度";
CM_ SG_ 559 EMS4_FanRequest "Fan running request";
CM_ SG_ 559 EMS4_BatteryVoltage "EMS系统电压";
CM_ SG_ 559 EMS4_ACCWake "ACC高电平唤醒信号";
CM_ SG_ 559 EMS4_Throttleposition "节气门开度";
CM_ SG_ 559 EMS4_Currentfault "当前故障码";
CM_ SG_ 194 GCU3_OperModFdbk "GCU反馈的工作模式
GCU Operating Mode";
CM_ SG_ 194 GCU3_Motor_Torque "GCU反馈的实际转矩
GCU Actual Torque";
CM_ SG_ 194 GCU3_Motor_Speed "GCU反馈的实际转速
GCU Actual Speed";
CM_ SG_ 194 GCU3_Active_Dis_Enable_Fb "GCU反馈是否允许主动放电
GCU Active Discharge Allow Feedback";
CM_ SG_ 194 GCU3_IGBT_Enable_Fb "GCU反馈当前是否允许IGBT开管
GCU IGBT Enable Feedback";
CM_ SG_ 194 GCU3_Precharge_Allow_Fb "GCU反馈是否允许预充
GCU Precharge Allow Feedback";
CM_ SG_ 194 GCU3_Motor_reversal_sts "GCU发生反转标志位
ISG speed reversal ststus";
CM_ SG_ 194 GCU3_Fail_Grade "GCU故障状态
GCU Fail Status";
CM_ SG_ 194 GCU3_CycCounter "E2E Profile2-CRC8H2F，Counter:0-15";
CM_ SG_ 194 GCU3_CrcChecksum "E2E Profile2-CRC8H2F
DataID List:#85 - 76 163 161 44 164 33 6 152 151 73 88 19 40 143 104 219";
CM_ SG_ 337 GCU1_DC_Voltage "GCU母线电压";
CM_ SG_ 337 GCU1_DC_Current "GCU母线直流电流";
CM_ SG_ 337 GCU1_Motor_A_AC_Current "GCU A相交流电流";
CM_ SG_ 337 GCU1_Motor_C_AC_Current "GCUC相交流电流";
CM_ SG_ 465 GCU2_Error_Code1 "GCU故障代码1
GCU Error Code 1";
CM_ SG_ 465 GCU2_Error_Code2 "GCU故障代码2
GCU Error Code 2";
CM_ SG_ 465 GCU2_Error_Code3 "GCU故障代码3
GCU Error Code 3";
CM_ SG_ 465 GCU2_Error_Code4 "GCU故障代码4
GCU Error Code 4";
CM_ SG_ 465 GCU2_Error_Code5 "GCU故障代码5
GCU Error Code 5";
CM_ SG_ 465 GCU2_Error_Code6 "GCU故障代码6
GCU Error Code 6";
CM_ SG_ 465 GCU2_Live_Counter2 "GCU生命信号2
GCU Live_Counter2";
CM_ SG_ 465 GCU2_DTC_Code "GCU故障代码";
CM_ SG_ 467 GCU4_MotorActTemp "GCU电机温度
GCU Motor Actual Temperature";
CM_ SG_ 467 GCU4_INVActTemp "GCU逆变器温度
GCU Inverter Actual Temperature";
CM_ SG_ 467 GCU4_TrqLimitMax "GCU最大转矩限制
GCU Torque Limit";
CM_ SG_ 467 GCU4_TrqLimitMin "GCU最小转矩限制
GCU Torque Limit";
CM_ SG_ 467 GCU4_Live_Counter4 "GCU生命信号4
GCU Live_Counter4";
CM_ SG_ 1593 GCU_SourceNodeIdentifier "ECU节点标识符";
CM_ SG_ 1593 GCU_RepeatMessageRequest "Repeat Message请求";
CM_ SG_ 1593 GCU_Reserve1 "预留";
CM_ SG_ 1593 GCU_ActiveWakeup "激活唤醒，主动唤醒网络时置1，其他（包括被动唤醒节点）为0";
CM_ SG_ 1593 GCU_Reserve2 "预留";
CM_ SG_ 1593 GCU_WakeUp_Reason1 "唤醒原因1";
CM_ SG_ 1593 GCU_WakeUp_NM "NM报文唤醒";
CM_ SG_ 1593 GCU_RemainNetworkWakeUpReason1 "保持网络唤醒原因1";
CM_ SG_ 1593 GCU_RemainNetworkWakeUpReason2 "保持网络唤醒原因2";
CM_ SG_ 1593 GCU_RemainNetworkWakeUpReason3 "保持网络唤醒原因3";
CM_ SG_ 1593 GCU_RemainNetworkWakeUpReason4 "保持网络唤醒原因4";
CM_ SG_ 309 EVCC1_PP_sts "PP连接状态";
CM_ SG_ 309 EVCC1_EU_CP_PWM "EU PP";
CM_ SG_ 309 EVCC1_KL15_sts "KL15状态";
CM_ SG_ 309 EVCC1_Asts "A+状态";
CM_ SG_ 309 EVCC1_CC2_sts "CC2状态";
CM_ SG_ 309 EVCC1_EVCC_CDU_CP_PWM "CDU接收CP_PWM状态";
CM_ SG_ 309 EVCC1_CP_voltage "CP_幅值";
CM_ SG_ 309 EVCC1_CDU_CC "OBC接收 CC连接";
CM_ SG_ 192 IDB2_FLWhlPulCnt "FL Wheel Pulse Counter";
CM_ SG_ 192 IDB2_FRWhlPulCnt "FR Wheel Pulse Counter";
CM_ SG_ 192 IDB2_FRWhlPulCntValid "FR Wheel Speed Sensor Validity";
CM_ SG_ 192 IDB2_FLWhlPulCntValid "FL Wheel Speed Sensor Validity";
CM_ SG_ 192 IDB2_Fr02_MsgCounter "E2E Profile2-CRC8H2F，Counter:0-15";
CM_ SG_ 192 IDB2_Fr02_Checksum "E2E Profile2-CRC8H2F
DataID List:#32 - 242 165 194 90 167 136 69 119 173 80 76 95 67 239 144 234";
CM_ SG_ 197 IDB3_VehicleSpdValid "Vehicle Speed Status 车速有效位";
CM_ SG_ 197 IDB3_PedalSimulatorPressureInvalid "Pedal Simulator Pressure Validity";
CM_ SG_ 197 IDB3_VehicleSpd "Vehicle Speed 车速";
CM_ SG_ 197 IDB3_PedalSimulatorPressure "Pedal Simulator Pressure";
CM_ SG_ 197 IDB3_MasterCylPressure "主缸压力";
CM_ SG_ 197 IDB3_MsgCounter "E2E Profile2-CRC8H2F，Counter:0-15";
CM_ SG_ 197 IDB3_MasterCylPressureInvalid "主缸压力值有效性";
CM_ SG_ 197 IDB3_Checksum "E2E Profile2-CRC8H2F
DataID List:#54 - 87 57 114 13 81 177 37 40 90 82 133 184 56 248 43 107";
CM_ SG_ 199 IDB4_FLWhlVelocityValid "Wheel Ground Velocity FL Valid";
CM_ SG_ 199 IDB4_FLWhlVelocity "Wheel Ground Velocity FL";
CM_ SG_ 199 IDB4_FRWhlVelocityValid "Wheel Ground Velocity FR Valid";
CM_ SG_ 199 IDB4_FRWhlVelocity "Wheel Ground Velocity FR";
CM_ SG_ 199 IDB4_RRWhlDir "Wheel RR Directiion";
CM_ SG_ 199 IDB4_RLWhlDir "Wheel RL Directiion";
CM_ SG_ 199 IDB4_FRWhlDir "Wheel FR Directiion";
CM_ SG_ 199 IDB4_FLWhlDir "Wheel FL Directiion";
CM_ SG_ 199 IDB4_MsgCounter "E2E Profile2-CRC8H2F，Counter:0-15";
CM_ SG_ 199 IDB4_Checksum "E2E Profile2-CRC8H2F
DataID List:#2 - 180 134 53 233 243 121 67 176 9 94 168 132 198 142 201 138";
CM_ SG_ 199 IDB4_RRWhlVelocityValid "Wheel Ground Velocity RR Valid";
CM_ SG_ 199 IDB4_RLWhlVelocityValid "Wheel Ground Velocity RL Valid";
CM_ SG_ 199 IDB4_RLWhlVelocity "Wheel Ground Velocity RL";
CM_ SG_ 199 IDB4_RLWhlPulCntValid "RL Wheel Speed Sensor Validity";
CM_ SG_ 199 IDB4_RRWhlPulCntValid "RR Wheel Speed Sensor Validity";
CM_ SG_ 199 IDB4_RRWhlVelocity "Wheel Ground Velocity RR";
CM_ SG_ 199 IDB4_RLWhlPulCnt "RL Wheel Pulse Counter";
CM_ SG_ 199 IDB4_RRWhlPulCnt "RR Wheel Pulse Counter";
CM_ SG_ 201 IDB10_BrRegenFrntAxleTar "Regenerative torque of front axle braking";
CM_ SG_ 201 IDB10_BrRegenReAxleTar "Regenerative torque of rear axle braking";
CM_ SG_ 201 IDB10_ADAS_DrvTorqueReq "Total driver torque of ADAS request";
CM_ SG_ 201 IDB10_ADAS_RegenTorqueReq "Total regenerative braking torque of ADAS request";
CM_ SG_ 201 IDB10_MsgCounter "E2E Profile2-CRC8H2F，Counter:0-15";
CM_ SG_ 201 IDB10_BrRegenFrntAxleTarReq "Regenerative torque of front axle braking request";
CM_ SG_ 201 IDB10_BrRegenReAxleTarReq "Regenerative torque of rear axle braking  request";
CM_ SG_ 201 IDB10_Checksum "E2E Profile2-CRC8H2F
DataID List:#34 - 219 232 142 64 159 96 133 222 128 194 15 172 7 227 20 164";
CM_ SG_ 201 IDB10_ADAS_DrvTorque "Total driver torque of ADAS";
CM_ SG_ 201 IDB10_ADAS_RegenTorque "Total regenerative braking torque of ADAS";
CM_ SG_ 202 IDB11_MsgCounter "E2E Profile2-CRC8H2F，Counter:0-15";
CM_ SG_ 202 IDB11_MotrTrqFrntAxleTargtReq "Target torque value of front axle motor request";
CM_ SG_ 202 IDB11_MotrTrqRearAxleTargtReq "Target torque value of rear axle motor request";
CM_ SG_ 202 IDB11_Checksum "E2E Profile2-CRC8H2F
DataID List:#34 - 219 232 142 64 159 96 133 222 128 194 15 172 7 227 20 164";
CM_ SG_ 202 IDB11_MotrTrqFrntAxleTargt "Target torque value of front axle motor";
CM_ SG_ 202 IDB11_MotrTrqRearAxleTargt "Target torque value of rear axle motor";
CM_ SG_ 229 IDB1_BrakePedalApplied "制动踏板踩下信号";
CM_ SG_ 229 IDB1_BrakePedalAppliedV "制动踏板踩下信号有效性";
CM_ SG_ 229 IDB1_BBSFail "BBS(Basic brake boost) FAIL OR NOT";
CM_ SG_ 229 IDB1_RBSFail "RBS(Regen brake boost) FAIL OR NOT";
CM_ SG_ 229 IDB1_RBS_ActiveSta "RBS(Regen brake boost) Active Status";
CM_ SG_ 229 IDB1_BBS_ActiveSta "BBS(Basic brake boost) Active Status";
CM_ SG_ 229 IDB1_BrakeFluidLow "制动液液位报警信号";
CM_ SG_ 229 IDB1_BrakPedalDisp "制动踏板位移量";
CM_ SG_ 229 IDB1_TrvSnsCalSts "踏板行程传感器零位标定状态";
CM_ SG_ 229 IDB1_BrakPedalDisp_Q "制动踏板位移量有效性";
CM_ SG_ 229 IDB1_BrakeClusterDispMSG "BrakeClusterDispMSG";
CM_ SG_ 229 IDB1_CSTFail "CST功能失效";
CM_ SG_ 229 IDB1_CSTAtive "CST激活";
CM_ SG_ 229 IDB1_CSTEnabled "CST功能使能";
CM_ SG_ 229 IDB1_Brakestyle_Enabled "Brake style功能使能";
CM_ SG_ 229 IDB1_Brakestyle_Fail "Brake style功能失效";
CM_ SG_ 229 IDB1_FailedState "IDB/EHB故障及有效性";
CM_ SG_ 229 IDB1_Fr01_MsgCounter "E2E Profile2-CRC8H2F，Counter:0-15";
CM_ SG_ 229 IDB1_MilLampRequset "Mil request";
CM_ SG_ 229 IDB1_Brakestyle "制动类型";
CM_ SG_ 229 IDB1_Fr01_Checksum "E2E Profile2-CRC8H2F
DataID List:#19 - 42 45 226 106 113 62 80 154 133 115 60 98 94 63 21 212";
CM_ SG_ 289 IDB9_PA_CtrlAbortFeedback "IDB/EHB反馈泊车的终止原因
ESC反馈泊车的终止原因";
CM_ SG_ 289 IDB9_PA_ParkingBrkMdSeln "IDB/EHB反馈当前制动模式
ESC反馈当前制动模式";
CM_ SG_ 289 IDB9_PA_ParkingFnMd "IDB/EHB反馈当前功能模式
ESC反馈当前功能模式";
CM_ SG_ 289 IDB9_PA_Prefill "PA预建压是否已开启";
CM_ SG_ 289 IDB9_TotalMotRgnTqWhlLimValid "制动能量回收可用的最大转矩值（轮端）有效性";
CM_ SG_ 289 IDB9_PA_ParkingAvailable "当前是否满足泊车的状态信号";
CM_ SG_ 289 IDB9_TotalMotRgnTqWhlLim "制动能量回收可用的最大转矩值（轮端）";
CM_ SG_ 289 IDB9_PAStandStill "Stop confirmation signal during APA operation";
CM_ SG_ 289 IDB9_PASts "IDB/EHB control state for APA
ESC control state for APA";
CM_ SG_ 289 IDB9_MsgCounter "E2E Profile2-CRC8H2F，Counter:0-15";
CM_ SG_ 289 IDB9_BrakePedalPosition "制动踏板开度";
CM_ SG_ 289 IDB9_Checksum "E2E Profile2-CRC8H2F
DataID List:#67 - 24 231 54 71 249 240 162 122 56 55 94 118 178 174 32 41";
CM_ SG_ 297 IDB5_BrakeDiscTempSts "Over Temp status";
CM_ SG_ 297 IDB5_VehicleStanstill "Vehicle Stan still";
CM_ SG_ 297 IDB5_JerkActive "Jerk Active 点刹功能激活";
CM_ SG_ 297 IDB5_Jerkfail "Jerk fail 点刹功能失败";
CM_ SG_ 297 IDB5_ACC_ReqLim "Due to limitaion of the actuators the acceleration or deceleration request from FRM can not be processed or only partly";
CM_ SG_ 297 IDB5_DBSavailable "DBS function available";
CM_ SG_ 297 IDB5_Prefillavailable "Prefill function available";
CM_ SG_ 297 IDB5_AEB_Enable "This signal is set by the safety logic for AEB in the ESC";
CM_ SG_ 297 IDB5_ACC_Enable "This signal is set by the safety logic in the ESC.";
CM_ SG_ 297 IDB5_ACC_Sta "IDB ACC激活状态";
CM_ SG_ 297 IDB5_ACC_ReferenceAccel "Feedback signal for the inner acceleration control loop";
CM_ SG_ 297 IDB5_MsgCounter "E2E Profile2-CRC8H2F，Counter:0-15";
CM_ SG_ 297 IDB5_DriverOverride "Input signal which represents a driver accelerator/brake pedal press/release manipulation.";
CM_ SG_ 297 IDB5_Checksum "E2E Profile2-CRC8H2F
DataID List:#58 - 204 92 25 9 246 113 123 47 41 35 210 115 157 97 39 37";
CM_ SG_ 299 IDB6_EPB_SwitchSta "EPB开关状态";
CM_ SG_ 299 IDB6_MainSysActive "主系统工作状态";
CM_ SG_ 299 IDB6_EPB_DynamicApplySta "Dynamic Apply Status
动态制动状态";
CM_ SG_ 299 IDB6_EPB_ActuatorSt_R "Right EPB Actuator State
右Moc状态";
CM_ SG_ 299 IDB6_EPB_ActuatorSt_L "Left EPB Actuator State
左Moc状态";
CM_ SG_ 299 IDB6_EpbDrvAwyInt "EPB Drive Away Intention Indicatio";
CM_ SG_ 299 IDB6_EpbActrAvailPrim "EPB Actuator Available in IDB";
CM_ SG_ 299 IDB6_EpbActrStatPrim "EPB Actuator State in IDB";
CM_ SG_ 299 IDB6_PGearPositionReqSt "P Gear Request
P档请求";
CM_ SG_ 299 IDB6_PGearPositionReqStInv "P Gear Request
P档请求取反";
CM_ SG_ 299 IDB6_PGearPositionReqStValid "P Gear Request
P档请求有效性";
CM_ SG_ 299 IDB6_EPBClusterDispMSG2 "EPB Cluster Display MSG2";
CM_ SG_ 299 IDB6_EpbAplRelReq "EPB Apply Release Request";
CM_ SG_ 299 IDB6_EPBStatus "EPB工作状态";
CM_ SG_ 299 IDB6_EPBAvailable "Availability of EPB";
CM_ SG_ 299 IDB6_EPBWarnLampReq "Electric Park Brake System Warning Indication Request";
CM_ SG_ 299 IDB6_EPBStatusLampReq "Electric Park Brake System Status Indication Request";
CM_ SG_ 299 IDB6_EPBSysBrkLightsReq "Electric Park Brake System Brake Lights Requested";
CM_ SG_ 299 IDB6_EPBCruiseCtrlCancelReq "Electric Park Brake Cruise Control Cancel Request";
CM_ SG_ 299 IDB6_RollingBenchModeSts "转鼓模式";
CM_ SG_ 299 IDB6_EpbCtrlAvail "vailableEPB Control";
CM_ SG_ 299 IDB6_EPBClusterDispMSG "EPB Cluster Display Message";
CM_ SG_ 301 IDB7_ESCFail "Electric Stability Control  Fault";
CM_ SG_ 301 IDB7_ESCActive "Electric Stability Control Active";
CM_ SG_ 301 IDB7_ESCDisable "Electric Stability Control Driver Intent
(ESC_DISABLED)";
CM_ SG_ 301 IDB7_ABSActive "Antilock Brake System Active";
CM_ SG_ 301 IDB7_EBD_Fail "EBD Fault";
CM_ SG_ 301 IDB7_EBD_Active "EBD激活";
CM_ SG_ 301 IDB7_HBAActive "HBA激活";
CM_ SG_ 301 IDB7_HBAFail "HBA失效";
CM_ SG_ 301 IDB7_DiagMode "This signal indicate diagnostic mode condition";
CM_ SG_ 301 IDB7_TCSActive "Traction Control System Active";
CM_ SG_ 301 IDB7_TCSDisable "Traction Control System Driver Intent";
CM_ SG_ 301 IDB7_TCSFail "Traction Control System Fault";
CM_ SG_ 301 IDB7_ROPACTIVE "ROP激活";
CM_ SG_ 301 IDB7_ROPFailure "ROP失效";
CM_ SG_ 301 IDB7_DynParkBrkByIDBActive "Dynamic Parking Brake Activation by IDB";
CM_ SG_ 301 IDB7_DynParkBrkByIDBAvailable "Dynamic Parking Brake Available status by IDB";
CM_ SG_ 301 IDB7_HSAActive "坡道辅助";
CM_ SG_ 301 IDB7_HSAFail "坡道辅助故障";
CM_ SG_ 301 IDB7_HDCEnabled "HDC功能使能";
CM_ SG_ 301 IDB7_HDCFail "HDC功能失效";
CM_ SG_ 301 IDB7_HDCAtive "HDC激活";
CM_ SG_ 301 IDB7_BrkLightReq "ESC请求点亮制动灯";
CM_ SG_ 301 IDB7_ABSFail "Antilock Brake System Failed";
CM_ SG_ 301 IDB7_ESSActiveReq "紧急制动信号，用于制动灯快闪";
CM_ SG_ 301 IDB7_CBCActive "CBCActive";
CM_ SG_ 301 IDB7_CBCFail "CBCFail";
CM_ SG_ 301 IDB7_ETCSActivationFlag_F "ETCS Activation Flag  (Front)";
CM_ SG_ 301 IDB7_ETCSActivationFlag_R "ETCS Activation Flag (Rear)";
CM_ SG_ 301 IDB7_BTCSActFlag "BTCS Act Flag";
CM_ SG_ 301 IDB7_HBCActive "HBC功能激活";
CM_ SG_ 301 IDB7_HBCFail "HBC功能故障";
CM_ SG_ 301 IDB7_HBCReduced "HBCReduced激活置位";
CM_ SG_ 301 IDB7_MsgCounter "E2E Profile2-CRC8H2F，Counter:0-15";
CM_ SG_ 301 IDB7_BrakeWarningLamp "汇总各种故障状态给仪表、安全气囊等控制器";
CM_ SG_ 301 IDB7_ActAccXValid "相对地面的实际加速度有效性";
CM_ SG_ 301 IDB7_Checksum "E2E Profile2-CRC8H2F
DataID List:#12 - 159 194 20 136 217 173 214 95 89 144 158 77 230 186 51 205";
CM_ SG_ 301 IDB7_GroundSlopeValid "地面坡度信号有效性";
CM_ SG_ 301 IDB7_HDCClusterDispMSG "HDC功能在大屏上的文字提示";
CM_ SG_ 301 IDB7_GroundSlope "地面坡度信号";
CM_ SG_ 301 IDB7_ActAccX "相对地面的实际加速度";
CM_ SG_ 301 IDB7_PIBFail "PIB功能故障";
CM_ SG_ 301 IDB7_PIBActive "PIB激活";
CM_ SG_ 301 IDB7_TSAActive "TSA拖车激活";
CM_ SG_ 301 IDB7_TSAFail "TSA拖车故障";
CM_ SG_ 302 IDB12_AVHDispMSG "Auto Hold System Display Message";
CM_ SG_ 302 IDB12_AVHLampReq "Auto Hold System Lamp Request";
CM_ SG_ 302 IDB12_AVHStatus "Auto Hold System Status";
CM_ SG_ 302 IDB12_AVHEnabled "AVH功能使能";
CM_ SG_ 302 IDB12_EpedalAct "E-pedal Act Flag";
CM_ SG_ 302 IDB12_EpedalSts "E-pedal Status";
CM_ SG_ 302 IDB12_RBS_exitReq "DTC请求RBS退出";
CM_ SG_ 302 IDB12_ReDTCAxleTarReq "干预转矩请求（后）";
CM_ SG_ 302 IDB12_FrntDTCAxleTarReq "干预转矩请求（前）";
CM_ SG_ 302 IDB12_DTC_Activesta "DTC功能激活状态";
CM_ SG_ 302 IDB12_DTCFail "DTC功能失效状态";
CM_ SG_ 302 IDB12_MsgCounter "E2E Profile2-CRC8H2F，Counter:0-15";
CM_ SG_ 302 IDB12_Checksum "E2E Profile2-CRC8H2F
DataID List:#12 - 159 194 20 136 217 173 214 95 89 144 158 77 230 186 51 205";
CM_ SG_ 302 IDB12_ReDTCAxleTar "干预转矩值（后）";
CM_ SG_ 302 IDB12_FrntDTCAxleTar "干预转矩值（前）";
CM_ SG_ 302 IDB12_RBSExitReason "制动能量回收退出原因";
CM_ SG_ 302 IDB12_sOutputRodAct "主缸推杆位移量";
CM_ SG_ 302 IDB12_sOutputRodActValid "主缸推杆位移量有效性";
CM_ SG_ 303 IDB8_MsgCounter "E2E Profile2-CRC8H2F，Counter:0-15";
CM_ SG_ 303 IDB8_BrakeActive "Brake Active";
CM_ SG_ 303 IDB8_Checksum "E2E Profile2-CRC8H2F
DataID List:#14 - 186 170 140 32 215 199 25 141 103 102 16 242 163 113 91 114";
CM_ SG_ 303 IDB8_FrntLeEstimdWhlPres "Front  left  of the estimated wheels pressure";
CM_ SG_ 303 IDB8_FrntRiEstimdWhlPres "Front  right   of the estimated wheels pressure";
CM_ SG_ 303 IDB8_ReLeEstimdWhlPres "Rear left  of the estimated wheels pressure";
CM_ SG_ 303 IDB8_ReRiEstimdWhlPres "Rear  right  of the estimated wheels pressure";
CM_ SG_ 303 IDB8_FrntLeEstimdWhlPresVldty "Front  left  of the estimated wheels pressure Validity";
CM_ SG_ 303 IDB8_FrntRiEstimdWhlPresVldty "Front  right   of the estimated wheels pressure Validity";
CM_ SG_ 303 IDB8_ReLeEstimdWhlPresVldty "Rear  left  of the estimated wheels pressure Validity";
CM_ SG_ 303 IDB8_ReRiEstimdWhlPresVldty "Rear  right  of the estimated wheels pressure Validity";
CM_ SG_ 1554 IDB_SourceNodeIdentifier "ECU节点标识符";
CM_ SG_ 1554 IDB_RepeatMessageRequest "Repeat Message请求";
CM_ SG_ 1554 IDB_Reserve1 "预留";
CM_ SG_ 1554 IDB_ActiveWakeup "激活唤醒，主动唤醒网络时置1，其他（包括被动唤醒节点）为0";
CM_ SG_ 1554 IDB_Reserve2 "预留";
CM_ SG_ 1554 IDB_WakeUp_KL15 "KL15 ON 唤醒";
CM_ SG_ 1554 IDB_WakeUp_NM "NM报文唤醒";
CM_ SG_ 1554 IDB_WakeUp_EPBsw "EPB开关拉起";
CM_ SG_ 1554 IDB_RemainNetworkWakeUpReason1 "保持网络唤醒原因1";
CM_ SG_ 1554 IDB_RemainNetworkWakeUpReason2 "保持网络唤醒原因2";
CM_ SG_ 1554 IDB_RemainNetworkWakeUpReason3 "保持网络唤醒原因3";
CM_ SG_ 1554 IDB_RemainNetworkWakeUpReason4 "保持网络唤醒原因4";
CM_ SG_ 193 EHB2_FLWhlPulCnt "FL Wheel Pulse Counter";
CM_ SG_ 193 EHB2_FRWhlPulCnt "FR Wheel Pulse Counter";
CM_ SG_ 193 EHB2_FRWhlPulCntValid "FR Wheel Speed Sensor Validity";
CM_ SG_ 193 EHB2_FLWhlPulCntValid "FL Wheel Speed Sensor Validity";
CM_ SG_ 193 EHB2_Fr02_MsgCounter "E2E Profile2-CRC8H2F，Counter:0-15";
CM_ SG_ 193 EHB2_Fr02_Checksum "E2E Profile2-CRC8H2F
DataID List:#32 - 242 165 194 90 167 136 69 119 173 80 76 95 67 239 144 234";
CM_ SG_ 195 EHB4_FLWhlVelocityValid "Wheel Ground Velocity FL Valid";
CM_ SG_ 195 EHB4_FLWhlVelocity "Wheel Ground Velocity FL";
CM_ SG_ 195 EHB4_FRWhlVelocityValid "Wheel Ground Velocity FR Valid";
CM_ SG_ 195 EHB4_FRWhlVelocity "Wheel Ground Velocity FR";
CM_ SG_ 195 EHB4_RRWhlDir "Wheel RR Directiion";
CM_ SG_ 195 EHB4_RLWhlDir "Wheel RL Directiion";
CM_ SG_ 195 EHB4_FRWhlDir "Wheel FR Directiion";
CM_ SG_ 195 EHB4_FLWhlDir "Wheel FL Directiion";
CM_ SG_ 195 EHB4_MsgCounter "E2E Profile2-CRC8H2F，Counter:0-15";
CM_ SG_ 195 EHB4_Checksum "E2E Profile2-CRC8H2F
DataID List:#2 - 180 134 53 233 243 121 67 176 9 94 168 132 198 142 201 138";
CM_ SG_ 195 EHB4_RRWhlVelocityValid "Wheel Ground Velocity RR Valid";
CM_ SG_ 195 EHB4_RLWhlVelocityValid "Wheel Ground Velocity RL Valid";
CM_ SG_ 195 EHB4_RLWhlVelocity "Wheel Ground Velocity RL";
CM_ SG_ 195 EHB4_RLWhlPulCntValid "RL Wheel Speed Sensor Validity";
CM_ SG_ 195 EHB4_RRWhlPulCntValid "RR Wheel Speed Sensor Validity";
CM_ SG_ 195 EHB4_RRWhlVelocity "Wheel Ground Velocity RR";
CM_ SG_ 195 EHB4_RLWhlPulCnt "RL Wheel Pulse Counter";
CM_ SG_ 195 EHB4_RRWhlPulCnt "RR Wheel Pulse Counter";
CM_ SG_ 198 EHB3_VehicleSpdValid "Vehicle Speed Status 车速有效位";
CM_ SG_ 198 EHB3_PedalSimulatorPressureInvalid "踏板感模拟缸压力信号有效性";
CM_ SG_ 198 EHB3_VehicleSpd "Vehicle Speed 车速";
CM_ SG_ 198 EHB3_HBAActive "HBA激活";
CM_ SG_ 198 EHB3_HBAFail "HBA失效";
CM_ SG_ 198 EHB3_PedalSimulatorPressure "踏板感模拟缸压力信号";
CM_ SG_ 198 EHB3_MasterCylPressure "主缸压力";
CM_ SG_ 198 EHB3_MsgCounter "E2E Profile2-CRC8H2F，Counter:0-15";
CM_ SG_ 198 EHB3_BrkLightReq "EHB点亮制动灯请求";
CM_ SG_ 198 EHB3_HBCRequestValid "请求HBC工作信号有效性";
CM_ SG_ 198 EHB3_HBCRequest "请求HBC工作";
CM_ SG_ 198 EHB3_MasterCylPressureInvalid "主缸压力值有效性";
CM_ SG_ 198 EHB3_Checksum "E2E Profile2-CRC8H2F
DataID List:#54 - 87 57 114 13 81 177 37 40 90 82 133 184 56 248 43 107";
CM_ SG_ 300 ESC1_EPB_DynamicApplySta "Dynamic Apply Status
动态制动状态";
CM_ SG_ 300 ESC1_EPB_ActuatorSt_R "Right EPB Actuator State
右Moc状态";
CM_ SG_ 300 ESC1_EPB_ActuatorSt_L "Left EPB Actuator State
左Moc状态";
CM_ SG_ 300 ESC1_EpbDrvAwyInt "EPB Drive Away Intention Indicatio";
CM_ SG_ 300 ESC1_EpbActrAvailPrim "EPB Actuator Available in IDB";
CM_ SG_ 300 ESC1_EpbActrStatPrim "EPB Actuator State in IDB";
CM_ SG_ 300 ESC1_EpbAplRelReq "EPB Apply Release Request";
CM_ SG_ 300 ESC1_EPBStatus "EPB工作状态";
CM_ SG_ 300 ESC1_EPBAvailable "Availability of EPB";
CM_ SG_ 300 ESC1_EPBWarnLampReq "Electric Park Brake System Warning Indication Request";
CM_ SG_ 300 ESC1_EPBStatusLampReq "Electric Park Brake System Status Indication Request";
CM_ SG_ 300 ESC1_EPBSysBrkLightsReq "Electric Park Brake System Brake Lights Requested";
CM_ SG_ 300 ESC1_EPBCruiseCtrlCancelReq "Electric Park Brake Cruise Control Cancel Request";
CM_ SG_ 300 ESC1_RollingBenchModeSts "转鼓模式";
CM_ SG_ 300 ESC1_EpbCtrlAvail "vailableEPB Control";
CM_ SG_ 300 ESC1_EPBClusterDispMSG "EPB Cluster Display Message";
CM_ SG_ 177 EPS1_SteeringAngleValid "方向盘转角有效位";
CM_ SG_ 177 EPS1_SteerAngleSpdValid "方向盘角速度有效位";
CM_ SG_ 177 EPS1_HSTWCalibrated "方向盘水平位置标定状态";
CM_ SG_ 177 EPS1_WarningLampRed "EPS功能故障红色警示灯";
CM_ SG_ 177 EPS1_TorsionBarTorqueValid "转向杆扭矩有效位";
CM_ SG_ 177 EPS1_TorsionBarTorque "转向扭杆扭矩（驾驶员手力矩，左正右负）";
CM_ SG_ 177 EPS1_SteeringAngle "方向盘转角（左正右负）";
CM_ SG_ 177 EPS1_WarningLampYellow "EPS一般故障黄色警示灯";
CM_ SG_ 177 EPS1_SteerAngleSpd "方向盘角速度（左正右负）";
CM_ SG_ 177 EPS1_MsgCounter "E2E Profile2-CRC8H2F，Counter:0-15";
CM_ SG_ 177 EPS1_ModSts "EPS转向模式状态";
CM_ SG_ 177 EPS1_ModSetInhibit "EPS反馈转向模式是否允许切换";
CM_ SG_ 177 EPS1_Checksum "E2E Profile2-CRC8H2F
DataID List:#7 - 12 243 207 94 6 201 30 183 35 143 78 190 188 108 16 38";
CM_ SG_ 178 EPS2_ADAS_Available "EPS ADAS功能可用状态";
CM_ SG_ 178 EPS2_ADAS_Active "EPS反馈ADAS功能激活状态";
CM_ SG_ 178 EPS2_AssistPraSwitchToDAS "EPS ADAS助力模式状态";
CM_ SG_ 178 EPS2_ADAS_CtrlAbortFeedback "EPS当前跳出ADAS的原因";
CM_ SG_ 178 EPS2_MotCntrl "电机控制扭矩 (left“+”,right“-” )";
CM_ SG_ 178 EPS2_PA_Available "EPS系统APA功能可用状态";
CM_ SG_ 178 EPS2_PA_Active "EPS反馈APA功能激活状态";
CM_ SG_ 178 EPS2_MotCntrlValid "电机扭矩有效性";
CM_ SG_ 178 EPS2_PA_CtrlAbortFeedback "EPS当前跳出APA的原因";
CM_ SG_ 178 EPS2_MsgCounter "E2E Profile2-CRC8H2F，Counter:0-15";
CM_ SG_ 178 EPS2_Checksum "E2E Profile2-CRC8H2F
DataID List:#10 - 4 65 1 42 110 208 168 45 211 25 191 226 12 167 122 106";
CM_ SG_ 298 REPB1_ReleaseRequest "辅系统请求主系统释放EPB";
CM_ SG_ 298 REPB1_EpbActrStatSec "EPB Actuator State in R-EPB";
CM_ SG_ 298 REPB1_ActuatorSt_R "Right EPB Actuator State
右Moc状态";
CM_ SG_ 298 REPB1_ActuatorSt_L "Left EPB Actuator State
左Moc状态";
CM_ SG_ 298 REPB1_SlaveSysActive "辅系统工作状态";
CM_ SG_ 298 REPB1_EpbActrAvailSec "EPB Actuator Available in R-EPB";
CM_ SG_ 298 REPB1_EpbDynamicCmd "EPB Dynamic Command from R-EPB";
CM_ SG_ 298 REPB1_EpbStaticCmd "EPB Static Command from R-EPB";
CM_ SG_ 298 REPB1_EPBStatus "REPB工作状态";
CM_ SG_ 298 REPB1_EPBAvailable "Availability of R-EPB";
CM_ SG_ 298 REPB1_EPBSysBrkLightsReq "Electric Park Brake System Brake Lights Requested";
CM_ SG_ 298 REPB1_EPBCruiseCtrlCancelReq "Electric Park Brake Cruise Control Cancel Request";
CM_ SG_ 298 REPB1_EPBClusterDispMSG "REPB Cluster Display Message";
CM_ SG_ 298 REPB1_EPBWarnLampReq "Electric Park Brake System Warning Indication Request";
CM_ SG_ 298 REPB1_EPBStatusLampReq "Electric Park Brake System Status Indication Request";
CM_ SG_ 817 ISC_ISCErrorSts "减振器故障";
CM_ SG_ 817 ISC_ISCModeSetFb "悬架模式设置反馈信号";
CM_ SG_ 555 ISC_FLWheelAcc "Front left wheel accelaration";
CM_ SG_ 555 ISC_FLBodyAcc "Front left Body accelaration";
CM_ SG_ 555 ISC_FRWheelAcc "Front right wheel accelaration";
CM_ SG_ 555 ISC_FRBodyAcc "Front right Body accelaration";
CM_ SG_ 555 ISC_RearBodyAcc "Rear Body accelaration";
CM_ SG_ 555 ISC_FLCurrentReq "Front Left Target Current";
CM_ SG_ 555 ISC_FRCurrentReq "Front Right Target Current";
CM_ SG_ 555 ISC_RLCurrentReq "Rear Left Target Current";
CM_ SG_ 555 ISC_RRCurrentReq "Rear Right Target Current";
CM_ SG_ 555 ISC_FLCurrentFb "Front Left Current Feedback";
CM_ SG_ 555 ISC_FRCurrentFb "Front Right Current Feedback";
CM_ SG_ 555 ISC_RLCurrentFb "Rear Left Current Feedback";
CM_ SG_ 555 ISC_RRCurrentFb "Rear Right Current Feedback";
CM_ SG_ 142 ADCS2_ADAS_EPSAngleReqSt "ADAS横向控制对EPS的请求状态";
CM_ SG_ 142 ADCS2_EPS_LDPState "LDP功能状态";
CM_ SG_ 142 ADCS2_NNP_SystemFaultStatus "NNP故障状态";
CM_ SG_ 142 ADCS_Pilot_SystemFaultStatus "Pilot故障状态";
CM_ SG_ 142 ADCS2_ADAS_EPSLateralCtrlType "ADAS横向控制对EPS的请求类型";
CM_ SG_ 142 ADCS2_ADAS_EPSAngleReq "ADAS 请求转向角度值(left“+”,right“-” )";
CM_ SG_ 142 ADCS2_ADAS_IHBCSysState "IHBC System State";
CM_ SG_ 142 ADCS2_ALCDirection "变道转向灯请求";
CM_ SG_ 142 ADCS2_ACC_EpbReq "EPB请求信号(行车功能)";
CM_ SG_ 142 ADCS2_MsgCounter0 "E2E Profile2-CRC8H2F，Counter:0-15";
CM_ SG_ 142 ADCS2_Checksum0 "E2E Profile2-CRC8H2F
DataID List:#4 - 158 161 150 33 238 151 203 19 139 104 55 2 184 16 105 67";
CM_ SG_ 142 ADCS2_AEBVehicleHoldReq "This signal means stop request flag by AEB";
CM_ SG_ 142 ADCS2_AEBFullBrake "This signal means flag which indicates that the deceleration command for AEB full braking is valid or not.";
CM_ SG_ 142 ADCS2_AEBPartialBrake "This signal means flag which indicates that the deceleration command for AEB partial braking is valid or not.";
CM_ SG_ 142 ADCS2_AEB_DBSLevel "This signal means command to use lowered DBS (Dynamic Braking Support) threshold to determine the DBS entrance";
CM_ SG_ 142 ADCS2_AEBPrefillReq "This signal means command to activate pre-fill";
CM_ SG_ 142 ADCS2_AEB_JerkReq "AEB点刹报警请求";
CM_ SG_ 142 ADCS2_AEBTargetDeceleration "This signal means deceleration command for AEB braking";
CM_ SG_ 142 ADCS2_longitudCtrlType "ADAS纵向控制请求类型";
CM_ SG_ 142 ADCS2_LongitudCtrlDecToStopReq "ADAS纵向控制减速到停请求";
CM_ SG_ 142 ADCS2_LongitudCtrlDriveOff "ADAS纵向控制起步请求";
CM_ SG_ 142 ADCS2_AEB_JerkLevel "Jerk等级";
CM_ SG_ 142 ADCS2_LongitudCtrlAccelCtrlReq "ADAS纵向控制请求";
CM_ SG_ 142 ADCS2_LongitudCtrlTargetAccel "ADAS纵向控制请求值";
CM_ SG_ 143 ADCS11_PA_GearReq "APA换挡握手请求";
CM_ SG_ 143 ADCS11_PA_GearPosReqVail "挡位请求有效性";
CM_ SG_ 143 ADCS11_PA_prefillReq "APA请求ESC预制动";
CM_ SG_ 143 ADCS11_PA_GearPosReq "挡位请求";
CM_ SG_ 143 ADCS11_PA_BrakemodeReq "APA制动模式请求";
CM_ SG_ 143 ADCS11_PA_EpbReq "EPB请求信号";
CM_ SG_ 143 ADCS11_PA_lampreq "APA请求危险报警灯光";
CM_ SG_ 143 ADCS11_PA_StopDistance "刹车距离请求";
CM_ SG_ 143 ADCS11_Parking_WorkSts "泊车工作状态信号";
CM_ SG_ 143 ADCS11_RPA_RemoteParkAppStartReq "泊车程序启动请求";
CM_ SG_ 143 ADCS11_PA_Recover "APA/RPA泊车恢复指令";
CM_ SG_ 143 ADCS11_TurnLampReq "请求双闪灯";
CM_ SG_ 143 ADCS11_SetPathwayWorkSts "路线管理开关反馈";
CM_ SG_ 143 ADCS11_PA_EPSAngleReq "APA请求转向角度值(left“+”,right“-” )";
CM_ SG_ 143 ADCS11_MsgCounter0 "E2E Profile2-CRC8H2F，Counter:0-15";
CM_ SG_ 143 ADCS11_HPAGuideSts "记忆泊车学习使用状态信息播报";
CM_ SG_ 143 ADCS11_Checksum0 "E2E Profile2-CRC8H2F
DataID List:#1 - 28 8 73 140 234 86 71 199 14 46 36 103 158 122 129 242";
CM_ SG_ 143 ADCS11_HPA_WorkSts "记忆泊车状态播报";
CM_ SG_ 143 ADCS11_PA_IDBControlReqV "IDB握手请求有效位";
CM_ SG_ 143 ADCS11_PA_TarDecel "减速度请求（发给IDB）";
CM_ SG_ 143 ADCS11_APA_FRWindowsCtrl "远程控制副驾车窗动作";
CM_ SG_ 143 ADCS11_APA_RemoteLockCtrl "远程控制车辆上锁";
CM_ SG_ 143 ADCS11_APA_FLWindowsCtrl "远程控制主驾车窗动作";
CM_ SG_ 143 ADCS11_APA_requestMirrorFoldSt "请求控制后视镜状态";
CM_ SG_ 143 ADCS11_APA_RRWindowsCtrl "远程控制右后车窗动作";
CM_ SG_ 143 ADCS11_APA_RLWindowsCtrl "远程控制左后车窗动作";
CM_ SG_ 143 ADCS11_PA_EPSAngleReqSt "APA转向握手控制请求";
CM_ SG_ 143 ADCS11_PA_EPSAngleReqV "APA转向握手控制请求有效性";
CM_ SG_ 143 ADCS11_PrkngFctnModeReq "泊车当前模式";
CM_ SG_ 143 ADCS11_HPAPathlearning_WorkSts "记忆泊车路线学习反馈";
CM_ SG_ 143 ADCS11_HPAPathwaytoCloud_WorkSts "路线上传反馈播报";
CM_ SG_ 143 ADCS11_TrackreverseWorkSts "循迹倒车开关反馈";
CM_ SG_ 143 ADCS11_Currentgear "泊车当前档位信息";
CM_ SG_ 143 ADCS11_PA_PAMaxSpd "最大速度请求";
CM_ SG_ 143 ADCS11_PA_IDBControlReq "IDB握手请求";
CM_ SG_ 143 ADCS11_APA_RemoteStartReq "远程启动请求";
CM_ SG_ 143 ADCS11_APA_RemoteShutdownReq "远程熄火请求";
CM_ SG_ 143 ADCS11_MirrorFoldrequest "车后视镜控制请求";
CM_ SG_ 143 ADCS11_PA_TorqReq "PA请求控制加速";
CM_ SG_ 143 ADCS11_PA_TorqReqValidity "目标扭力值有效位";
CM_ SG_ 143 ADCS11_PA_Pause_Recover "HPP/SM 暂停反馈";
CM_ SG_ 143 ADCS11_HPA_BacktoEntrance "回到车库入口";
CM_ SG_ 143 ADCS11_HPA_BacktoStart "回到起点位置";
CM_ SG_ 143 ADCS11_PA_TarDecelreq "PA请求加减速度控制";
CM_ SG_ 143 ADCS11_PA_ParkingFnMd "泊车当前工作状态";
CM_ SG_ 143 ADCS11_PA_screenReq "泊车系统对大屏显示的请求";
CM_ SG_ 143 ADCS11_HPA_PathlearningSt "路线学习状态";
CM_ SG_ 143 ADCS11_HPA_Path_exist "是否存在记忆泊车路线";
CM_ SG_ 143 ADCS11_PA_PickSt "ADCS反馈接驾模式";
CM_ SG_ 143 ADCS11_PA_StopReq "stop请求信号";
CM_ SG_ 143 ADCS11_PA_StopDistanceValid "刹车距离请求有效位";
CM_ SG_ 143 ADCS11_PA_TorqReqValue "目标扭力值（轮端）";
CM_ SG_ 143 ADCS11_HPA_Pathavailable_ID2 "显示存在路线";
CM_ SG_ 143 ADCS11_HPA_distance "记忆泊车剩余距离信息";
CM_ SG_ 143 ADCS11_Parkingtimeremaining "记忆泊车剩余时间";
CM_ SG_ 143 ADCS11_NNS_distance "智能召唤剩余距离";
CM_ SG_ 143 ADCS11_HPA_Pathavailable_ID1 "显示存在路线";
CM_ SG_ 143 ADCS11_HighBeam "请求远光灯";
CM_ SG_ 143 ADCS11_ReqPwmode "ADCS请求上高压";
CM_ SG_ 143 ADCS11_SecuritySts "ADCS发送认证";
CM_ SG_ 143 ADCS11_LowBeam "请求近光灯";
CM_ SG_ 143 ADCS11_PA_IDB_TorqReqValidity "PA请求IDB扭矩值有效位";
CM_ SG_ 143 ADCS11_HPA_learnpathdistance "车端选择车位信息";
CM_ SG_ 143 ADCS11_PA_IDB_TorqReqValue "PA请求IDB扭矩值";
CM_ SG_ 254 ADCS4_AVM_RCW_warningReq "车辆后方报警信号";
CM_ SG_ 254 ADCS4_AVM_BSD_warningReqLeft "BSD左侧报警信号";
CM_ SG_ 254 ADCS4_AVM_BSD_warningReqRight "BSD右侧报警信号";
CM_ SG_ 254 ADCS4_SystemFault2 "ADAS系统故障指示（泊车）";
CM_ SG_ 254 ADCS4_TBA_Distance "循迹倒车剩余距离信息";
CM_ SG_ 254 ADCS4_AVM_DayNightStatus "AVM/APA黑夜/白天显示状态";
CM_ SG_ 254 ADCS4_APA_InParkingSpaceStatus "ADAS判断车辆当前是否在车位内";
CM_ SG_ 254 ADCS4_AVM_Sts "AVM系统状态";
CM_ SG_ 254 ADCS4_RPA_RemoteParkFinishReq "泊车结束请求";
CM_ SG_ 254 ADCS4_AVM_BSD_SysSts "BSD系统状态信号";
CM_ SG_ 254 ADCS4_PA_InfoDisplayReq "APA请求IHU显示APA进入失败原因";
CM_ SG_ 254 ADCS4_PA_failinfo "上电故障，开关置灰";
CM_ SG_ 254 ADCS4_UPA_Sound_Location "UPA声音报警对应车上扬声器位置发声";
CM_ SG_ 254 ADCS4_HPA_failinfo "记忆泊车路线学习过程中出错，退出原因播报";
CM_ SG_ 254 ADCS4_UPA_SysSoundIndication "UPA系统声音提示";
CM_ SG_ 254 ADCS4_AVM_SysSoundIndication "系统声音指示";
CM_ SG_ 254 ADCS4_DCWposition "反馈开门预警设置信号";
CM_ SG_ 254 ADCS4_MsgCounter0 "E2E Profile2-CRC8H2F，Counter:0-15";
CM_ SG_ 254 ADCS4_PA_ParkBarPercent "泊车进程";
CM_ SG_ 254 ADCS4_Checksum0 "E2E Profile2-CRC8H2F
DataID List:#16 - 149 178 48 27 29 185 17 203 148 68 204 36 101 195 44 16";
CM_ SG_ 254 ADCS4_APA_FunctionMode "APA功能模式反馈信号";
CM_ SG_ 254 ADCS4_HornReq "请求喇叭响(泊车)";
CM_ SG_ 254 ADCS4_Text "文字提示信息";
CM_ SG_ 254 ADCS4_ParkingswithReq "自动泊车软开关显示请求";
CM_ SG_ 254 ADCS4_Slotavaliable "自选车位是否可用";
CM_ SG_ 254 ADCS4_locationSt "当前定位状态";
CM_ SG_ 254 ADCS4_DCWlevel "开门预警报警级别信号";
CM_ SG_ 254 ADCS4_PA_GuideLineE_a "泊车引导线方程y=ax3+bx2+cx+d";
CM_ SG_ 254 ADCS4_PA_GuideLineE_b "泊车引导线方程y=ax3+bx2+cx+d";
CM_ SG_ 254 ADCS4_PA_GuideLineE_c "泊车引导线方程y=ax3+bx2+cx+d";
CM_ SG_ 254 ADCS4_PA_GuideLineE_d "泊车引导线方程y=ax3+bx2+cx+d";
CM_ SG_ 254 ADCS4_PA_GuideLineE_Xmin "泊车引导线方程y=ax3+bx2+cx+d";
CM_ SG_ 254 ADCS4_PA_GuideLineE_Xmax "泊车引导线方程y=ax3+bx2+cx+d";
CM_ SG_ 254 ADCS4_HPA_deleteMapSt "记忆泊车删除路线状态";
CM_ SG_ 254 ADCS4_HPA_uploadMapSt "记忆泊车上传路线状态";
CM_ SG_ 254 ADCS4_ParkingTime "泊车计时";
CM_ SG_ 254 ADCS4_HPAWarningInfo "记忆泊车警报信息";
CM_ SG_ 254 ADCS4_AVM_vedioReq "AVM启动反馈信号";
CM_ SG_ 254 ADCS4_HPA_FunctionMode "记忆泊车模式";
CM_ SG_ 254 ADCS4_NNS_FunctionMode "智能召唤状态";
CM_ SG_ 254 ADCS4_TractionswithReq "循迹倒车开始信息";
CM_ SG_ 254 ADCS4_RPA_FunctionMode "反馈泊车模式信号";
CM_ SG_ 254 ADCS4_HourOfDay "目标到达时间显示";
CM_ SG_ 254 ADCS4_MinuteOfHour "目标到达时间显示";
CM_ SG_ 254 ADCS4_GMState "哨兵模式开关状态反馈";
CM_ SG_ 254 ADCS4_SecondOfMinute "目标到达时间显示";
CM_ SG_ 254 ADCS4_GMWarnState "哨兵模式报警";
CM_ SG_ 254 ADCS4_DCWworkSt "开门预警状态";
CM_ SG_ 254 ADCS4_DCWtext "开门预警提示信息";
CM_ SG_ 254 ADCS4_GM_SystemFaultStatus "哪吒卫士故障";
CM_ SG_ 254 ADCS4_GMWorkState "哨兵模式工作状态";

BA_DEF_ BO_ "CANFD_BRS" ENUM "0","1";
BA_DEF_ BO_ "GenMsgSendType" ENUM "Cycle","NoMsgSendType","IfActive","Event","CA","CE";
BA_DEF_ BO_ "GenMsgNrOfRepetition" INT 0 0;
BA_DEF_ BO_ "GenMsgILSupport" ENUM "No","Yes";
BA_DEF_ BO_ "GenMsgDelayTime" INT 0 0;
BA_DEF_ BO_ "GenMsgCycleTimeFast" INT 0 0;
BA_DEF_ BO_ "GenMsgCycleTime" INT 0 0;
BA_DEF_ BO_ "DiagResponse" ENUM "No","Yes";
BA_DEF_ BO_ "DiagRequest" ENUM "No","Yes";
BA_DEF_ BO_ "NmMessage" ENUM "No","Yes";
BA_DEF_ BO_ "VFrameFormat" ENUM "StandardCAN","ExtendedCAN","reserved","J1939PG","reserved","reserved","reserved","reserved","reserved","reserved","reserved","reserved","reserved","reserved","StandardCAN_FD","ExtendedCAN_FD";
BA_DEF_ SG_ "GenSigInvalidValue" HEX 0 0;
BA_DEF_ SG_ "GenSigStartValue" HEX 0 0;
BA_DEF_ SG_ "GenSigSendType" ENUM "Cycle","OnWrite","OnWriteWithRepetition","OnChange","OnChangeWithRepetition","IfActive","IfActiveWithRepetition","NoSigSendType","vector_leerstring";
BA_DEF_DEF_ "CANFD_BRS" "1";
BA_DEF_DEF_ "GenMsgSendType" "Cycle";
BA_DEF_DEF_ "GenMsgNrOfRepetition" 0;
BA_DEF_DEF_ "GenMsgILSupport" "Yes";
BA_DEF_DEF_ "GenMsgDelayTime" 0;
BA_DEF_DEF_ "GenMsgCycleTimeFast" 0;
BA_DEF_DEF_ "GenMsgCycleTime" 0;
BA_DEF_DEF_ "DiagResponse" "No";
BA_DEF_DEF_ "DiagRequest" "No";
BA_DEF_DEF_ "NmMessage" "No";
BA_DEF_DEF_ "VFrameFormat" "StandardCAN";
BA_DEF_DEF_ "GenSigInvalidValue" 0;
BA_DEF_DEF_ "GenSigStartValue" 0;
BA_DEF_DEF_ "GenSigSendType" "Cycle";
BA_ "GenMsgCycleTime" BO_ 267 20;
BA_ "VFrameFormat" BO_ 267 14;
BA_ "GenMsgCycleTime" BO_ 494 50;
BA_ "VFrameFormat" BO_ 494 14;
BA_ "GenMsgCycleTime" BO_ 735 100;
BA_ "VFrameFormat" BO_ 735 14;
BA_ "GenMsgCycleTime" BO_ 1590 500;
BA_ "NmMessage" BO_ 1590 1;
BA_ "GenMsgCycleTime" BO_ 518 100;
BA_ "VFrameFormat" BO_ 518 14;
BA_ "GenMsgCycleTime" BO_ 522 100;
BA_ "VFrameFormat" BO_ 522 14;
BA_ "GenMsgCycleTime" BO_ 279 20;
BA_ "VFrameFormat" BO_ 279 14;
BA_ "GenMsgCycleTime" BO_ 599 100;
BA_ "VFrameFormat" BO_ 599 14;
BA_ "GenMsgCycleTime" BO_ 602 100;
BA_ "VFrameFormat" BO_ 602 14;
BA_ "GenMsgCycleTime" BO_ 665 100;
BA_ "VFrameFormat" BO_ 665 14;
BA_ "GenMsgCycleTime" BO_ 698 100;
BA_ "VFrameFormat" BO_ 698 14;
BA_ "GenMsgCycleTime" BO_ 921 500;
BA_ "VFrameFormat" BO_ 921 14;
BA_ "GenMsgCycleTime" BO_ 1542 500;
BA_ "NmMessage" BO_ 1542 1;
BA_ "GenMsgCycleTime" BO_ 128 10;
BA_ "VFrameFormat" BO_ 128 14;
BA_ "GenMsgCycleTime" BO_ 248 20;
BA_ "VFrameFormat" BO_ 248 14;
BA_ "GenMsgCycleTime" BO_ 544 100;
BA_ "VFrameFormat" BO_ 544 14;
BA_ "GenMsgCycleTime" BO_ 554 100;
BA_ "VFrameFormat" BO_ 554 14;
BA_ "GenMsgCycleTime" BO_ 559 100;
BA_ "VFrameFormat" BO_ 559 14;
BA_ "GenMsgCycleTime" BO_ 194 10;
BA_ "VFrameFormat" BO_ 194 14;
BA_ "GenMsgCycleTime" BO_ 337 50;
BA_ "VFrameFormat" BO_ 337 14;
BA_ "GenMsgCycleTime" BO_ 465 50;
BA_ "VFrameFormat" BO_ 465 14;
BA_ "GenMsgCycleTime" BO_ 467 50;
BA_ "VFrameFormat" BO_ 467 14;
BA_ "GenMsgCycleTime" BO_ 1593 500;
BA_ "NmMessage" BO_ 1593 1;
BA_ "GenMsgCycleTime" BO_ 309 20;
BA_ "VFrameFormat" BO_ 309 14;
BA_ "GenMsgCycleTime" BO_ 192 10;
BA_ "VFrameFormat" BO_ 192 14;
BA_ "GenMsgCycleTime" BO_ 197 10;
BA_ "VFrameFormat" BO_ 197 14;
BA_ "GenMsgCycleTime" BO_ 199 10;
BA_ "VFrameFormat" BO_ 199 14;
BA_ "GenMsgCycleTime" BO_ 201 10;
BA_ "VFrameFormat" BO_ 201 14;
BA_ "GenMsgCycleTime" BO_ 202 10;
BA_ "VFrameFormat" BO_ 202 14;
BA_ "GenMsgCycleTime" BO_ 229 10;
BA_ "VFrameFormat" BO_ 229 14;
BA_ "GenMsgCycleTime" BO_ 289 20;
BA_ "VFrameFormat" BO_ 289 14;
BA_ "GenMsgCycleTime" BO_ 297 20;
BA_ "VFrameFormat" BO_ 297 14;
BA_ "GenMsgCycleTime" BO_ 299 20;
BA_ "VFrameFormat" BO_ 299 14;
BA_ "GenMsgCycleTime" BO_ 301 20;
BA_ "VFrameFormat" BO_ 301 14;
BA_ "GenMsgCycleTime" BO_ 302 20;
BA_ "VFrameFormat" BO_ 302 14;
BA_ "GenMsgCycleTime" BO_ 303 20;
BA_ "VFrameFormat" BO_ 303 14;
BA_ "GenMsgCycleTime" BO_ 1554 500;
BA_ "NmMessage" BO_ 1554 1;
BA_ "GenMsgCycleTime" BO_ 193 10;
BA_ "VFrameFormat" BO_ 193 14;
BA_ "GenMsgCycleTime" BO_ 195 10;
BA_ "VFrameFormat" BO_ 195 14;
BA_ "GenMsgCycleTime" BO_ 198 10;
BA_ "VFrameFormat" BO_ 198 14;
BA_ "GenMsgCycleTime" BO_ 300 20;
BA_ "VFrameFormat" BO_ 300 14;
BA_ "GenMsgCycleTime" BO_ 177 10;
BA_ "VFrameFormat" BO_ 177 14;
BA_ "GenMsgCycleTime" BO_ 178 10;
BA_ "VFrameFormat" BO_ 178 14;
BA_ "GenMsgCycleTime" BO_ 298 20;
BA_ "VFrameFormat" BO_ 298 14;
BA_ "GenMsgCycleTime" BO_ 817 100;
BA_ "VFrameFormat" BO_ 817 14;
BA_ "GenMsgCycleTime" BO_ 555 50;
BA_ "VFrameFormat" BO_ 555 14;
BA_ "GenMsgCycleTime" BO_ 142 10;
BA_ "VFrameFormat" BO_ 142 14;
BA_ "GenMsgCycleTime" BO_ 143 10;
BA_ "VFrameFormat" BO_ 143 14;
BA_ "GenMsgCycleTime" BO_ 254 20;
BA_ "VFrameFormat" BO_ 254 14;
BA_ "GenSigInvalidValue" SG_ 494 MCU3_InverterTemperature 255;
BA_ "GenSigInvalidValue" SG_ 494 MCU3_MotorTemperature 255;
BA_ "GenSigInvalidValue" SG_ 518 DCDC2_Input_Vol 16383;
BA_ "GenSigInvalidValue" SG_ 518 DCDC2_Temp 255;
BA_ "GenSigInvalidValue" SG_ 518 DCDC2_Input_Cur 255;
BA_ "GenSigInvalidValue" SG_ 518 DCDC2_Output_Cur 4095;
BA_ "GenSigInvalidValue" SG_ 518 DCDC2_OutPower_Max 511;
BA_ "GenSigInvalidValue" SG_ 599 OBC2_CurrentEnablePowerOut_Max 8191;
BA_ "GenSigStartValue" SG_ 554 EMS5_VVTinletAngle 50;
BA_ "GenSigInvalidValue" SG_ 192 IDB2_FLWhlPulCnt 65535;
BA_ "GenSigInvalidValue" SG_ 192 IDB2_FRWhlPulCnt 65535;
BA_ "GenSigInvalidValue" SG_ 197 IDB3_MasterCylPressure 65535;
BA_ "GenSigStartValue" SG_ 197 IDB3_MasterCylPressure 3000;
BA_ "GenSigInvalidValue" SG_ 199 IDB4_FLWhlVelocity 16383;
BA_ "GenSigInvalidValue" SG_ 199 IDB4_FRWhlVelocity 16383;
BA_ "GenSigInvalidValue" SG_ 199 IDB4_RLWhlVelocity 16383;
BA_ "GenSigInvalidValue" SG_ 199 IDB4_RRWhlVelocity 16383;
BA_ "GenSigInvalidValue" SG_ 199 IDB4_RLWhlPulCnt 65535;
BA_ "GenSigInvalidValue" SG_ 199 IDB4_RRWhlPulCnt 65535;
BA_ "GenSigStartValue" SG_ 201 IDB10_BrRegenFrntAxleTar 32000;
BA_ "GenSigStartValue" SG_ 201 IDB10_BrRegenReAxleTar 32000;
BA_ "GenSigStartValue" SG_ 201 IDB10_ADAS_DrvTorque 32000;
BA_ "GenSigStartValue" SG_ 201 IDB10_ADAS_RegenTorque 32000;
BA_ "GenSigStartValue" SG_ 202 IDB11_MotrTrqFrntAxleTargt 32000;
BA_ "GenSigStartValue" SG_ 202 IDB11_MotrTrqRearAxleTargt 32000;
BA_ "GenSigStartValue" SG_ 229 IDB1_BrakPedalDisp 400;
BA_ "GenSigStartValue" SG_ 229 IDB1_Brakestyle_Enabled 1;
BA_ "GenSigStartValue" SG_ 289 IDB9_TotalMotRgnTqWhlLim 32000;
BA_ "GenSigStartValue" SG_ 297 IDB5_ACC_ReferenceAccel 1023;
BA_ "GenSigStartValue" SG_ 301 IDB7_GroundSlope 2000;
BA_ "GenSigStartValue" SG_ 301 IDB7_ActAccX 2000;
BA_ "GenSigStartValue" SG_ 302 IDB12_ReDTCAxleTar 32000;
BA_ "GenSigStartValue" SG_ 302 IDB12_FrntDTCAxleTar 32000;
BA_ "GenSigStartValue" SG_ 302 IDB12_sOutputRodActValid 1;
BA_ "GenSigInvalidValue" SG_ 193 EHB2_FLWhlPulCnt 65535;
BA_ "GenSigInvalidValue" SG_ 193 EHB2_FRWhlPulCnt 65535;
BA_ "GenSigInvalidValue" SG_ 195 EHB4_FLWhlVelocity 16383;
BA_ "GenSigInvalidValue" SG_ 195 EHB4_FRWhlVelocity 16383;
BA_ "GenSigInvalidValue" SG_ 195 EHB4_RLWhlVelocity 16383;
BA_ "GenSigInvalidValue" SG_ 195 EHB4_RRWhlVelocity 16383;
BA_ "GenSigInvalidValue" SG_ 195 EHB4_RLWhlPulCnt 65535;
BA_ "GenSigInvalidValue" SG_ 195 EHB4_RRWhlPulCnt 65535;
BA_ "GenSigStartValue" SG_ 198 EHB3_HBAActive 1;
BA_ "GenSigInvalidValue" SG_ 198 EHB3_MasterCylPressure 65535;
BA_ "GenSigStartValue" SG_ 198 EHB3_MasterCylPressure 3000;
BA_ "GenSigInvalidValue" SG_ 177 EPS1_TorsionBarTorque 2047;
BA_ "GenSigInvalidValue" SG_ 177 EPS1_SteeringAngle 65535;
BA_ "GenSigInvalidValue" SG_ 177 EPS1_SteerAngleSpd 16383;
BA_ "GenSigInvalidValue" SG_ 178 EPS2_MotCntrl 2047;
BA_ "GenSigInvalidValue" SG_ 817 ISC_ISCErrorSts 1;
BA_ "GenSigStartValue" SG_ 142 ADCS2_ADAS_EPSAngleReq 7200;
BA_ "GenSigStartValue" SG_ 142 ADCS2_AEBTargetDeceleration 127;
BA_ "GenSigStartValue" SG_ 142 ADCS2_LongitudCtrlTargetAccel 1023;
BA_ "GenSigStartValue" SG_ 143 ADCS11_PA_EPSAngleReq 7200;
BA_ "GenSigInvalidValue" SG_ 143 ADCS11_PA_TarDecel 4095;
BA_ "GenSigStartValue" SG_ 143 ADCS11_PA_TarDecel 2048;
BA_ "GenSigInvalidValue" SG_ 143 ADCS11_PA_TorqReqValue 2047;
BA_ "GenSigStartValue" SG_ 143 ADCS11_PA_TorqReqValue 1023;
BA_ "GenSigInvalidValue" SG_ 143 ADCS11_HPA_Pathavailable_ID2 255;
BA_ "GenSigInvalidValue" SG_ 143 ADCS11_HPA_distance 4095;
BA_ "GenSigInvalidValue" SG_ 143 ADCS11_Parkingtimeremaining 1023;
BA_ "GenSigInvalidValue" SG_ 143 ADCS11_NNS_distance 65535;
BA_ "GenSigInvalidValue" SG_ 143 ADCS11_HPA_Pathavailable_ID1 255;
BA_ "GenSigInvalidValue" SG_ 143 ADCS11_HPA_learnpathdistance 1023;
BA_ "GenSigInvalidValue" SG_ 143 ADCS11_PA_IDB_TorqReqValue 4095;
BA_ "GenSigStartValue" SG_ 143 ADCS11_PA_IDB_TorqReqValue 4095;
BA_ "GenSigInvalidValue" SG_ 254 ADCS4_HourOfDay 63;
BA_ "GenSigInvalidValue" SG_ 254 ADCS4_MinuteOfHour 63;
BA_ "GenSigStartValue" SG_ 254 ADCS4_GMState 2;
BA_ "GenSigInvalidValue" SG_ 254 ADCS4_SecondOfMinute 63;
VAL_ 267 MCU2_MilLampRequest 1 "Lamp on request" 0 "No request";
VAL_ 267 MCU2_Fault_Level 3 "FaultLevel3" 2 "FaultLevel2" 1 "FaultLevel1" 0 "No Fault";
VAL_ 267 MCU2_MotorFaultLampRequest 1 "Lamp on request" 0 "No request";
VAL_ 267 MCU2_Motor_Block_Warning 1 "Fault" 0 "Not fault";
VAL_ 267 MCU2_OpenProtion_Lock_Fault 1 "Fault" 0 "Not fault";
VAL_ 267 MCU2_Cooling_System_Fault 1 "Fault" 0 "Not fault";
VAL_ 267 MCU2_Self_check_Fault 1 "Fault" 0 "Not fault";
VAL_ 267 MCU2_Sensor_Check_Fault 1 "Fault" 0 "Not fault";
VAL_ 267 MCU2_Battery_Check_Fault 1 "Fault" 0 "Not fault";
VAL_ 267 MCU2_Motor_Lack_of_Phase_Fault 1 "Fault" 0 "Not fault";
VAL_ 267 MCU2_RDC_Alignment_Fault 1 "Fault" 0 "Not fault";
VAL_ 267 MCU2_PhaseOvercurrentFault 1 "Fault" 0 "Not fault";
VAL_ 267 MCU2_InverterFault 1 "Fault" 0 "Not fault";
VAL_ 267 MCU2_SensorSupplyVoltageFault 1 "Fault" 0 "Not fault";
VAL_ 267 MCU2_DC_link_OvercurrentFault 1 "Fault" 0 "Not fault";
VAL_ 267 MCU2_GateDriverDesaturationFault 1 "Fault" 0 "Not fault";
VAL_ 267 MCU2_MotorPositionSensorFault 1 "Fault" 0 "Not fault";
VAL_ 267 MCU2_DischargeOverTime 1 "Fault" 0 "Not fault";
VAL_ 267 MCU2_SumPhaseCurrentOverThd 1 "Fault" 0 "Not fault";
VAL_ 267 MCU2_MotorOvertempFault 3 "FaultLevel3" 2 "FaultLevel2" 1 "FaultLevel1" 0 "No Fault";
VAL_ 267 MCU2_A_phase_OvercurrWarn 1 "Fault" 0 "Not fault";
VAL_ 267 MCU2_B_phase_OvercurrWarn 1 "Fault" 0 "Not fault";
VAL_ 267 MCU2_C_phase_OvercurrentWarning 1 "Fault" 0 "Not fault";
VAL_ 267 MCU2_InverterOvertempFault 3 "FaultLevel3" 2 "FaultLevel2" 1 "FaultLevel1" 0 "No Fault";
VAL_ 267 MCU2_Rx_CAN_Failed 1 "Fault" 0 "Not fault";
VAL_ 267 MCU2_LV_PowerSupplyFault 1 "Fault" 0 "Not fault";
VAL_ 267 MCU2_IgnSts_Dev 1 "ON" 0 "OFF";
VAL_ 267 MCU2_HV_Battery_Connect_states 1 "Connect" 0 "No connect";
VAL_ 267 MCU2_VCU_Inverter_states 1 "Inverter enable" 0 "Inverter disable";
VAL_ 267 MCU2_SafetyFault 1 "Fault" 0 "Not fault";
VAL_ 267 MCU2_ModeError 1 "Fault" 0 "Not fault";
VAL_ 267 MCU2_GateDriverVoltageSupplyFault 1 "Fault" 0 "Not fault";
VAL_ 494 MCU3_ActiveDischargeSts 3 "失败" 2 "完成" 1 "放电中" 0 "未进行";
VAL_ 494 MCU3_ShakeRednFb 1 "关闭" 0 "默认开启";
VAL_ 494 MCU3_HVIL_DCBus 1 "Connect" 0 "Disconnect";
VAL_ 735 MCU4_AlOfsNoPlaus 1 "Fault" 0 "Not fault";
VAL_ 735 MCU4_Can_BusOff 1 "Fault" 0 "Not fault";
VAL_ 735 MCU4_IUMonOvHiRng 1 "Fault" 0 "Not fault";
VAL_ 735 MCU4_IUMonOvLoRng 1 "Fault" 0 "Not fault";
VAL_ 735 MCU4_IUOc 1 "Fault" 0 "Not fault";
VAL_ 735 MCU4_IUOvHiRng 1 "Fault" 0 "Not fault";
VAL_ 735 MCU4_IUOvLoRng 1 "Fault" 0 "Not fault";
VAL_ 735 MCU4_IVMonOvHiRng 1 "Fault" 0 "Not fault";
VAL_ 735 MCU4_IVMonOvLoRng 1 "Fault" 0 "Not fault";
VAL_ 735 MCU4_IVOc 1 "Fault" 0 "Not fault";
VAL_ 735 MCU4_IVOvHiRng 1 "Fault" 0 "Not fault";
VAL_ 735 MCU4_IVOvLoRng 1 "Fault" 0 "Not fault";
VAL_ 735 MCU4_IWMonOvHiRng 1 "Fault" 0 "Not fault";
VAL_ 735 MCU4_IWMonOvLoRng 1 "Fault" 0 "Not fault";
VAL_ 735 MCU4_IWOc 1 "Fault" 0 "Not fault";
VAL_ 735 MCU4_IWOvHiRng 1 "Fault" 0 "Not fault";
VAL_ 735 MCU4_IWOvLoRng 1 "Fault" 0 "Not fault";
VAL_ 735 MCU4_IphaOC 1 "Fault" 0 "Not fault";
VAL_ 735 MCU4_IphaOffCal 1 "Fault" 0 "Not fault";
VAL_ 735 MCU4_MosTHiRng 1 "Fault" 0 "Not fault";
VAL_ 735 MCU4_NFltHA 1 "Fault" 0 "Not fault";
VAL_ 735 MCU4_NFltHB 1 "Fault" 0 "Not fault";
VAL_ 735 MCU4_NFltLA 1 "Fault" 0 "Not fault";
VAL_ 735 MCU4_NFltLB 1 "Fault" 0 "Not fault";
VAL_ 735 MCU4_RslvDos 1 "Fault" 0 "Not fault";
VAL_ 735 MCU4_RslvLos 1 "Fault" 0 "Not fault";
VAL_ 735 MCU4_RslvLot 1 "Fault" 0 "Not fault";
VAL_ 735 MCU4_HwPhaCurPosBackErr 1 "Fault" 0 "Not fault";
VAL_ 735 MCU4_HwPhaCurNegBackErr 1 "Fault" 0 "Not fault";
VAL_ 735 MCU4_TSttr1OvHiLim 1 "Fault" 0 "Not fault";
VAL_ 735 MCU4_TSttr1OvLoLim 1 "Fault" 0 "Not fault";
VAL_ 735 MCU4_TSttr2OvHiLim 1 "Fault" 0 "Not fault";
VAL_ 735 MCU4_TSttr2OvLoLim 1 "Fault" 0 "Not fault";
VAL_ 735 MCU4_TUErrOff 1 "Fault" 0 "Not fault";
VAL_ 735 MCU4_TVErrOff 1 "Fault" 0 "Not fault";
VAL_ 735 MCU4_TWErrOff 1 "Fault" 0 "Not fault";
VAL_ 735 MCU4_tDBCTempUHiLom 1 "Fault" 0 "Not fault";
VAL_ 735 MCU4_tDBCTempULoLom 1 "Fault" 0 "Not fault";
VAL_ 735 MCU4_tDBCTempVHiLom 1 "Fault" 0 "Not fault";
VAL_ 735 MCU4_tDBCTempVLoLom 1 "Fault" 0 "Not fault";
VAL_ 735 MCU4_tDBCTempWHiLom 1 "Fault" 0 "Not fault";
VAL_ 735 MCU4_tDBCTempWLoLom 1 "Fault" 0 "Not fault";
VAL_ 735 MCU4_QtShrGnd 1 "Fault" 0 "Not fault";
VAL_ 735 MCU4_SttrTemp1ShrGnd 1 "Fault" 0 "Not fault";
VAL_ 735 MCU4_SttrTemp2ShrGnd 1 "Fault" 0 "Not fault";
VAL_ 735 MCU4_UMonShrGnd 1 "Fault" 0 "Not fault";
VAL_ 735 MCU4_VMonShrGnd 1 "Fault" 0 "Not fault";
VAL_ 735 MCU4_WMonShrGnd 1 "Fault" 0 "Not fault";
VAL_ 735 MCU4_UShrGnd 1 "Fault" 0 "Not fault";
VAL_ 735 MCU4_VShrGnd 1 "Fault" 0 "Not fault";
VAL_ 735 MCU4_WShrGnd 1 "Fault" 0 "Not fault";
VAL_ 735 MCU4_UKl30Ov 1 "Fault" 0 "Not fault";
VAL_ 735 MCU4_UKl30Unv 1 "Fault" 0 "Not fault";
VAL_ 735 MCU4_VcuRecOvTime 1 "Fault" 0 "Not fault";
VAL_ 735 MCU4_UdcLnkOvHiRng 3 "Level 3 Fault" 2 "Level 2 Fault" 1 "Level 1 Fault" 0 "No Fault";
VAL_ 735 MCU4_UdcLnkOvLoRng 3 "Level 3 Fault" 2 "Level 2 Fault" 1 "Level 1 Fault" 0 "No Fault";
VAL_ 735 MCU4_OverSpdDetn 3 "Level 3 Fault" 2 "Level 2 Fault" 1 "Level 1 Fault" 0 "No Fault";
VAL_ 1590 MCU_RepeatMessageRequest 1 "Repeat message request" 0 "No repeat message request";
VAL_ 1590 MCU_ActiveWakeup 1 "Wakeup" 0 "No wakeup";
VAL_ 1590 MCU_WakeUp_Reason1 1 "Wakeup" 0 "No Request";
VAL_ 1590 MCU_WakeUp_NM 1 "NM Wakeup" 0 "No Request";
VAL_ 1590 MCU_RepeatFromSleep 1 "occur" 0 "not occur";
VAL_ 1590 MCU_RepeatFromPrepare 1 "occur" 0 "not occur";
VAL_ 1590 MCU_NormalFromRepeat 1 "occur" 0 "not occur";
VAL_ 1590 MCU_NormalFromReady 1 "occur" 0 "not occur";
VAL_ 1590 MCU_RepeatFromReady 1 "occur" 0 "not occur";
VAL_ 1590 MCU_RepeatFromNormal 1 "occur" 0 "not occur";
VAL_ 1590 MCU_RemainNetworkWakeUpReason1 1 "Remain wakeup reason" 0 "default";
VAL_ 1590 MCU_RemainNetworkWakeUpReason2 1 "Remain wakeup reason" 0 "default";
VAL_ 1590 MCU_RemainNetworkWakeUpReason3 1 "Remain wakeup reason" 0 "default";
VAL_ 1590 MCU_RemainNetworkWakeUpReason4 1 "Remain wakeup reason" 0 "default";
VAL_ 522 DCDC1_WorkState 3 "Reserved" 2 "error" 1 "work" 0 "standby";
VAL_ 522 DCDC1_StatusAlarm 3 "Level 3" 2 "Level 2" 1 "Level 1" 0 "Normal";
VAL_ 522 DCDC1_HW_Fault 1 "Fault" 0 "Not fault";
VAL_ 522 DCDC1_Comm_Fault 1 "Fault" 0 "Not fault";
VAL_ 522 DCDC1_IN_Ov_Vol_Ft 1 "Fault" 0 "Not fault";
VAL_ 522 DCDC1_IN_Un_Vol_Ft 1 "Fault" 0 "Not fault";
VAL_ 522 DCDC1_Out_Ov_Vol_Ft 1 "Fault" 0 "Not fault";
VAL_ 522 DCDC1_Out_Un_Vol_Ft 1 "Fault" 0 "Not fault";
VAL_ 522 DCDC1_OutputSh_Pr 1 "Protected happened" 0 "No protected";
VAL_ 522 DCDC1_OvTemp_Pr 1 "Protected happened" 0 "No protected";
VAL_ 522 DCDC1_OvPowerOut_Pr 1 "Protected happened" 0 "No protected";
VAL_ 522 DCDC1_Out_Ov_Cur_Ft 1 "Fault" 0 "Not fault";
VAL_ 279 OBC4_Connect_Status_CC 2 "Connect" 1 "Half Connect" 0 "Not Connect";
VAL_ 279 OBC4_RelayState 1 "Connected" 0 "Disconnect";
VAL_ 279 OBC4_SlowChargeCC 9 "State F/" 8 "State F" 7 "State E/" 6 "State E" 5 "State D/" 4 "State D" 3 "State C/" 2 "State C" 1 "State B" 0 "State A";
VAL_ 279 OBC4_InverterSlowchargeCC 9 "State F/" 8 "State F" 7 "State E/" 6 "State E" 5 "State D/" 4 "State D" 3 "State C/" 2 "State C" 1 "State B" 0 "State A";
VAL_ 279 OBC4_RelayOutside_VolValid 1 "valid" 0 "invalid";
VAL_ 279 OBC4_ChargeEnableVCU 1 "on" 0 "off";
VAL_ 599 OBC2_E_lockCont 1 "locked" 0 "unlock";
VAL_ 599 OBC2_Pre_theft_fb 1 "Open" 0 "Close";
VAL_ 599 OBC2_E_lockSts 3 "lock error" 2 "unlock error" 1 "locked" 0 "unlock";
VAL_ 599 OBC2_ACinletSnsrSts 2 "both two sensor  in error state" 1 "one sensor  in error state" 0 "no fault";
VAL_ 599 OBC2_ACinletTempErr 2 "AC inlet over temperature" 1 "Over differential of two sensors" 0 "no fault";
VAL_ 599 OBC2_S2_State 1 "Connect" 0 "Disconnect";
VAL_ 599 OBC2_ACinletSnsrSts2 2 "both two sensor  in error state" 1 "one sensor  in error state" 0 "no fault";
VAL_ 599 OBC2_ACinletSnsrSts3 2 "both two sensor  in error state" 1 "one sensor  in error state" 0 "no fault";
VAL_ 602 OBC1_CM_State 6 "Sleeping" 5 "Inverting" 4 "Heating" 3 "ChargerFault" 2 "Charging" 1 "standby" 0 "Initial";
VAL_ 602 OBC1_MilLampRequest 1 "Lamp on request" 0 "No request";
VAL_ 602 OBC1_StatusAlarm 3 "Level 3" 2 "Level 2" 1 "Level 1" 0 "Normal";
VAL_ 602 OBC1_No_Battery 1 "Fault" 0 "Not fault";
VAL_ 602 OBC1_HighVoltOutput_UnderVoltFlt 1 "Fault" 0 "Not fault";
VAL_ 602 OBC1_HighVoltOutput_OverVoltFlt 1 "Fault" 0 "Not fault";
VAL_ 602 OBC1_HighVoltOutput_ShortCircuitFlt 1 "Fault" 0 "Not fault";
VAL_ 602 OBC1_Input_UnderVoltage 1 "Fault" 0 "Not fault";
VAL_ 602 OBC1_Input_OverVoltage 1 "Fault" 0 "Not fault";
VAL_ 602 OBC1_Over_Temperature 3 "Reserved" 2 "Over Temperature 2" 1 "Over Temperature 1" 0 "Not fault";
VAL_ 602 OBC1_High_Current_Output_Fault 1 "Fault" 0 "Not fault";
VAL_ 602 OBC1_CANMsgFault 1 "Fault" 0 "Not fault";
VAL_ 602 OBC1_Battery_Reverse 1 "Fault" 0 "Not fault";
VAL_ 665 OBC3_InverterMode_Fb 3 "Error" 2 "无状态" 1 "V2V" 0 "V2L";
VAL_ 698 OBC5_NegRelayState 1 "valid" 0 "invalid";
VAL_ 698 OBC5_PosRelayStateOutsideSwitch 3 "Reserved" 2 "Disconnected（断开）" 1 "Connected（闭合）" 0 "Default（默认值）";
VAL_ 698 OBC5_NegRelayStateOutsideSwitch 3 "Reserved" 2 "Disconnected（断开）" 1 "Connected（闭合）" 0 "Default（默认值）";
VAL_ 1542 CDU_RepeatMessageRequest 1 "Repeat message request" 0 "No repeat message request";
VAL_ 1542 CDU_ActiveWakeup 1 "Wakeup" 0 "No wakeup";
VAL_ 1542 CDU_WakeUp_KL15 1 "KL15 ON Wakeup" 0 "No Request";
VAL_ 1542 CDU_WakeUp_ACcharging 1 "NM Wakeup" 0 "No Request";
VAL_ 1542 CDU_WakeUp_BMSIntelligentCharging 1 "Wakeup Requrst" 0 "No Request";
VAL_ 1542 CDU_WakeUp_ACchargingThermal 1 "Wakeup Requrst" 0 "No Request";
VAL_ 1542 CDU_WakeUp_LocalPreCharge 1 "Wakeup Requrst" 0 "No Request";
VAL_ 1542 CDU_WakeUp_RemotePreCharge 1 "Wakeup Requrst" 0 "No Request";
VAL_ 1542 CDU_WakeUp_OTA 1 "Wakeup Requrst" 0 "No Request";
VAL_ 1542 CDU_WakeUpReason8 1 "Wakeup Requrst" 0 "No Request";
VAL_ 1542 CDU_RepeatFromSleep 1 "occur" 0 "not occur";
VAL_ 1542 CDU_RepeatFromPrepare 1 "occur" 0 "not occur";
VAL_ 1542 CDU_NormalFromRepeat 1 "occur" 0 "not occur";
VAL_ 1542 CDU_NormalFromReady 1 "occur" 0 "not occur";
VAL_ 1542 CDU_RepeatFromReady 1 "occur" 0 "not occur";
VAL_ 1542 CDU_RepeatFromNormal 1 "occur" 0 "not occur";
VAL_ 1542 CDU_RemainNetworkWakeUpReason1 1 "Remain wakeup reason" 0 "default";
VAL_ 1542 CDU_RemainNetworkWakeUpReason2 1 "Remain wakeup reason" 0 "default";
VAL_ 1542 CDU_RemainNetworkWakeUpReason3 1 "Remain wakeup reason" 0 "default";
VAL_ 1542 CDU_RemainNetworkWakeUpReason4 1 "Remain wakeup reason" 0 "default";
VAL_ 128 EMS1_EngineStartedCompleted 1 "True" 0 "False";
VAL_ 128 EMS1_EngineStopAllow 1 "Stop allowed" 0 "Stop not allowed";
VAL_ 128 EMS1_ActualEngineTorqueValid 1 "valid" 0 "Invalid";
VAL_ 248 EMS2_EngineDFCOConditionReq 1 "Request active" 0 "No request";
VAL_ 248 EMS2_EngineIdleStateRequest 1 "Idle state request" 0 "No request";
VAL_ 248 EMS2_CatalystHeatingSt 1 "Catalyst is heating" 0 "Catalyst is not heating";
VAL_ 248 EMS2_ToothLearningReq 1 "True" 0 "False";
VAL_ 248 EMS2_EngineFuelCutOffStatus 1 "Fuel cut off active" 0 "Not active";
VAL_ 248 EMS2_EngIdleStatusActive 1 "True" 0 "False";
VAL_ 248 EMS2_EngineState 7 "Power Off Delay" 6 "Stopped" 5 "Stopping" 4 "Stall" 3 "Running" 2 "Crank" 1 "Key On" 0 "Power Off";
VAL_ 248 EMS2_FaultLevel 9 "Level9" 8 "Level8" 7 "Level7" 6 "Level6" 5 "Level5" 4 "Level4" 3 "Level3" 2 "Level2" 1 "Level1" 0 "Normal";
VAL_ 544 EMS3_MilLampRequest 2 "Lamp Flash" 1 "Lamp on request" 0 "No request";
VAL_ 544 EMS3_SVSLampRequest 1 "Lamp on request" 0 "No request";
VAL_ 544 EMS3_FVV_Status 2 "invalid" 1 "Open" 0 "Close";
VAL_ 544 EMS3_TankPressureValid 1 "True" 0 "False";
VAL_ 544 EMS3_Engineoilpressure 1 "压力低" 0 "压力正常";
VAL_ 544 EMS3_FuellevelValid 1 "Valid" 0 "Invalid";
VAL_ 554 EMS5_DriveCycleMet 1 "met" 0 "not met";
VAL_ 554 EMS5_WarmUpCycleMet 1 "met" 0 "not met";
VAL_ 554 EMS5_DenomComCriteriaMet 1 "met" 0 "not met";
VAL_ 554 EMS5_ColdstartDenomComCriteriaMet 1 "met" 0 "not met";
VAL_ 554 EMS5_EngStartRq 3 "Reserved" 2 "Reserved" 1 "Allowed" 0 "Not allowed";
VAL_ 554 EMS5_SpdSyncSt 1 "SYNC" 0 "NOT_SYNC";
VAL_ 559 EMS4_ACCWake 3 "Reserved" 2 "Reserved" 1 "True" 0 "False";
VAL_ 194 GCU3_OperModFdbk 7 "Error Mode" 6 "Discharge" 5 "VolCtrl" 4 "SpdCtrl" 3 "TqCtrl" 2 "Ready" 1 "Standby" 0 "Ini";
VAL_ 194 GCU3_Active_Dis_Enable_Fb 1 "Enable" 0 "Disable";
VAL_ 194 GCU3_IGBT_Enable_Fb 1 "Enable" 0 "Disable";
VAL_ 194 GCU3_Precharge_Allow_Fb 1 "Enable" 0 "Disable";
VAL_ 194 GCU3_Motor_reversal_sts 1 "True" 0 "False";
VAL_ 194 GCU3_MilLampRequest 1 "Lamp on request" 0 "No request";
VAL_ 194 GCU3_Fail_Grade 4 "Serious Fault(stop the vehicle)" 3 "Fault(shut down MCU)" 2 "Fault(zero torque output)" 1 "Warning(degraded)" 0 "No Fault";
VAL_ 1593 GCU_RepeatMessageRequest 1 "Repeat message request" 0 "No repeat message request";
VAL_ 1593 GCU_ActiveWakeup 1 "Wakeup" 0 "No wakeup";
VAL_ 1593 GCU_WakeUp_Reason1 1 "Wakeup" 0 "No Request";
VAL_ 1593 GCU_WakeUp_NM 1 "NM Wakeup" 0 "No Request";
VAL_ 1593 GCU_RepeatFromSleep 1 "occur" 0 "not occur";
VAL_ 1593 GCU_RepeatFromPrepare 1 "occur" 0 "not occur";
VAL_ 1593 GCU_NormalFromRepeat 1 "occur" 0 "not occur";
VAL_ 1593 GCU_NormalFromReady 1 "occur" 0 "not occur";
VAL_ 1593 GCU_RepeatFromReady 1 "occur" 0 "not occur";
VAL_ 1593 GCU_RepeatFromNormal 1 "occur" 0 "not occur";
VAL_ 1593 GCU_RemainNetworkWakeUpReason1 1 "Remain wakeup reason" 0 "default";
VAL_ 1593 GCU_RemainNetworkWakeUpReason2 1 "Remain wakeup reason" 0 "default";
VAL_ 1593 GCU_RemainNetworkWakeUpReason3 1 "Remain wakeup reason" 0 "default";
VAL_ 1593 GCU_RemainNetworkWakeUpReason4 1 "Remain wakeup reason" 0 "default";
VAL_ 309 EVCC1_PP_sts 3 "reserve" 2 "Unreliable" 1 "ture" 0 "false";
VAL_ 309 EVCC1_KL15_sts 1 "ture" 0 "false";
VAL_ 309 EVCC1_Asts 1 "ture" 0 "false";
VAL_ 309 EVCC1_CC2_sts 1 "ture" 0 "false";
VAL_ 309 EVCC1_CDU_CC 14 "预留" 8 "预留" 7 "双枪插入" 6 "放电枪半连接" 5 "慢充半连接" 4 "放电枪连接" 3 "16A慢充连接" 2 "10A慢充连接" 1 "快充枪连接" 0 "无连接";
VAL_ 192 IDB2_FRWhlPulCntValid 1 "Valid(有效)" 0 "Invalid(无效)";
VAL_ 192 IDB2_FLWhlPulCntValid 1 "Valid(有效)" 0 "Invalid(无效)";
VAL_ 197 IDB3_VehicleSpdValid 1 "Valid(有效)" 0 "Invalid(无效)";
VAL_ 197 IDB3_PedalSimulatorPressureInvalid 1 "Valid(有效)" 0 "Invalid(无效)";
VAL_ 197 IDB3_MasterCylPressureInvalid 1 "Valid(有效)" 0 "Invalid(无效)";
VAL_ 199 IDB4_FLWhlVelocityValid 1 "Valid(有效)" 0 "Invalid(无效)";
VAL_ 199 IDB4_FRWhlVelocityValid 1 "Valid(有效)" 0 "Invalid(无效)";
VAL_ 199 IDB4_RRWhlDir 3 "Error identifier" 2 "Backward direction" 1 "Forward direction" 0 "Unknown or stanstill";
VAL_ 199 IDB4_RLWhlDir 3 "Error identifier" 2 "Backward direction" 1 "Forward direction" 0 "Unknown or stanstill";
VAL_ 199 IDB4_FRWhlDir 3 "Error identifier" 2 "Backward direction" 1 "Forward direction" 0 "Unknown or stanstill";
VAL_ 199 IDB4_FLWhlDir 3 "Error identifier" 2 "Backward direction" 1 "Forward direction" 0 "Unknown or stanstill";
VAL_ 199 IDB4_RRWhlVelocityValid 1 "Valid(有效)" 0 "Invalid(无效)";
VAL_ 199 IDB4_RLWhlVelocityValid 1 "Valid(有效)" 0 "Invalid(无效)";
VAL_ 199 IDB4_RLWhlPulCntValid 1 "Valid(有效)" 0 "Invalid(无效)";
VAL_ 199 IDB4_RRWhlPulCntValid 1 "Valid(有效)" 0 "Invalid(无效)";
VAL_ 201 IDB10_ADAS_DrvTorqueReq 1 "Request" 0 "No Request";
VAL_ 201 IDB10_ADAS_RegenTorqueReq 1 "Request" 0 "No Request";
VAL_ 201 IDB10_BrRegenFrntAxleTarReq 1 "Requested" 0 "No Request";
VAL_ 201 IDB10_BrRegenReAxleTarReq 1 "Requested" 0 "No Request";
VAL_ 202 IDB11_MotrTrqFrntAxleTargtReq 1 "Request" 0 "No Request";
VAL_ 202 IDB11_MotrTrqRearAxleTargtReq 1 "Request" 0 "No Request";
VAL_ 229 IDB1_BrakePedalApplied 1 "press( 制动踏板被踩下)" 0 "no press(( 制动踏板未被踩下)";
VAL_ 229 IDB1_BrakePedalAppliedV 1 "Valid(有效)" 0 "Invalid(无效)";
VAL_ 229 IDB1_BBSFail 1 "fail" 0 "no fail";
VAL_ 229 IDB1_RBSFail 1 "fail" 0 "no fail";
VAL_ 229 IDB1_RBS_ActiveSta 1 "Active" 0 "Inactive";
VAL_ 229 IDB1_BBS_ActiveSta 1 "Active" 0 "Inactive";
VAL_ 229 IDB1_BrakeFluidLow 1 "Low" 0 "Normal";
VAL_ 229 IDB1_TrvSnsCalSts 1 "Yes" 0 "No";
VAL_ 229 IDB1_BrakPedalDisp_Q 1 "Valid(有效)" 0 "Invalid(无效)";
VAL_ 229 IDB1_BrakeClusterDispMSG 2 "The brake style function is faulty" 1 "Please release brake pedal" 0 "Off";
VAL_ 229 IDB1_CSTFail 1 "Fail" 0 "Not fail";
VAL_ 229 IDB1_CSTAtive 1 "Active" 0 "Not active";
VAL_ 229 IDB1_CSTEnabled 1 "Enabled" 0 "Disabled";
VAL_ 229 IDB1_Brakestyle_Enabled 1 "Enabled" 0 "Disabled";
VAL_ 229 IDB1_Brakestyle_Fail 1 "Fail" 0 "Not fail";
VAL_ 229 IDB1_FailedState 6 "fault level 6" 5 "fault level 5" 4 "fault level 4" 3 "fault level 3" 2 "fault level 2" 1 "fault level 1" 0 "no fault";
VAL_ 229 IDB1_MilLampRequset 1 "request" 0 "no request";
VAL_ 229 IDB1_Brakestyle 2 "sport" 1 "normal" 0 "comfortable";
VAL_ 289 IDB9_PA_CtrlAbortFeedback 7 "Communication failure with RCU" 6 "IDB Hydraulic failure" 5 "IDB Internal failure" 4 "Communication error with APA" 3 "Failure" 2 "EPB intervened" 1 "over speed" 0 "normal";
VAL_ 289 IDB9_PA_ParkingBrkMdSeln 2 "Function Not Active" 1 "Standstill (vehicle has been stopped)" 0 "Not standstill";
VAL_ 289 IDB9_PA_ParkingFnMd 3 "HPP Pro_Cruising" 2 "HPP_Cruising" 1 "Parking Mode" 0 "Function Not Active";
VAL_ 289 IDB9_PA_Prefill 1 "on" 0 "off";
VAL_ 289 IDB9_TotalMotRgnTqWhlLimValid 1 "Valid(有效)" 0 "Invalid(无效)";
VAL_ 289 IDB9_PA_ParkingAvailable 1 "Not Available" 0 "Available";
VAL_ 289 IDB9_PA_ApaCtrlSts 7 "Reserved" 6 "Emergency Stop" 5 "IDB Fail" 4 "Standstill" 3 "Stop Control" 2 "Speed Control" 1 "Ready" 0 "Off";
VAL_ 289 IDB9_PAStandStill 1 "standstill" 0 "not standstill";
VAL_ 289 IDB9_PASts 1 "Failure" 0 "Normal";
VAL_ 297 IDB5_BrakeDiscTempSts 1 "Temperature too high" 0 "Not high";
VAL_ 297 IDB5_VehicleStanstill 3 "reserved" 2 "invalid (short unavailability, max 3min)" 1 "standstill" 0 "not standstill";
VAL_ 297 IDB5_JerkActive 1 "available" 0 "Not available";
VAL_ 297 IDB5_Jerkfail 1 "fail" 0 "no fail";
VAL_ 297 IDB5_ADAS_PrefillSts 1 "active" 0 "not active";
VAL_ 297 IDB5_ACC_ReqLim 3 "Deceleration Limit" 2 "Reserved" 1 "Reserved" 0 "No request";
VAL_ 297 IDB5_DBSavailable 1 "Available" 0 "Not Available";
VAL_ 297 IDB5_Prefillavailable 1 "Available" 0 "Not Available";
VAL_ 297 IDB5_ABAactive 1 "Active" 0 "No Active";
VAL_ 297 IDB5_AEB_Enable 3 "AEB Communication Error" 2 "Permanently not Available" 1 "Temporarily not Available" 0 "Available";
VAL_ 297 IDB5_ACC_Enable 3 "ACC Communication Error" 2 "Permanently not Available" 1 "Temporarily not Available" 0 "Available";
VAL_ 297 IDB5_ACC_Sta 1 "ready" 0 "no ready";
VAL_ 297 IDB5_AEBactive 1 "Active" 0 "No Active";
VAL_ 297 IDB5_DriverOverride 3 "Reserved" 2 "DecelOverride" 1 "AccelOverride" 0 "No override";
VAL_ 299 IDB6_EPB_SwitchSta 2 "Error" 1 "Pressing" 0 "No action";
VAL_ 299 IDB6_MainSysActive 1 "Active" 0 "Inactive";
VAL_ 299 IDB6_EPB_DynamicApplySta 3 "reversed" 2 "Degrade Apply" 1 "RWU active" 0 "Not Active";
VAL_ 299 IDB6_EPB_ActuatorSt_R 7 "reversed" 6 "Hold" 5 "Unknown" 4 "Completely Released" 3 "Brake Applying" 2 "Brake Released" 1 "Brake Applied" 0 "Brake Releasing";
VAL_ 299 IDB6_EPB_ActuatorSt_L 7 "reversed" 6 "Hold" 5 "Unknown" 4 "Completely Released" 3 "Brake Applying" 2 "Brake Released" 1 "Brake Applied" 0 "Brake Releasing";
VAL_ 299 IDB6_EpbDrvAwyInt 1 "Indicated" 0 "Not Indicated";
VAL_ 299 IDB6_EpbActrAvailPrim 1 "Not Available" 0 "Available";
VAL_ 299 IDB6_EPB_DisplayMsgID 4 "after roll reapply,still roll" 3 "slpoe too steep" 2 "push brake pedal" 1 "close door（主驾门）" 0 "off";
VAL_ 299 IDB6_EpbActrStatPrim 6 "CompletelyReleased" 5 "Releasing" 4 "Applying" 3 "Released" 2 "HoldApplied" 1 "ParkApplied" 0 "Unknown";
VAL_ 299 IDB6_PGearPositionReqSt 1 "Request" 0 "No Request";
VAL_ 299 IDB6_PGearPositionReqStInv 1 "Request" 0 "No Request";
VAL_ 299 IDB6_PGearPositionReqStValid 1 "Valid" 0 "Invalid";
VAL_ 299 IDB6_EPBClusterDispMSG2 7 "Reserved" 6 "Reserved" 5 "Reserved" 4 "Reserved" 3 "Please switch gears" 2 "Please press the accelerator pedal" 1 "Please fasten seat belt" 0 "Off";
VAL_ 299 IDB6_EpbAplRelReq 6 "Adjustment" 5 "RollerbenchApply" 4 "DynamicApply" 3 "Release" 2 "HoldApply" 1 "ParkApply" 0 "None";
VAL_ 299 IDB6_EPBStatus 7 "Not Initialized (NEW)" 6 "Full Released完全释放" 5 "Dynamic braking via EPB动态驻车" 4 "Releasing in progress卡钳释放中" 3 "Clamping in progress卡钳夹紧中" 2 "Clamped卡钳夹紧" 1 "Released卡钳释放" 0 "Unknown未知";
VAL_ 299 IDB6_EPBAvailable 6 "EPB  failure" 5 "EPB Permanently Not Available" 4 "EPB Temporarily Not Available" 3 "EPB Diagnostic" 2 "EPB Initialization State" 1 "EPB No failure" 0 "Not valid";
VAL_ 299 IDB6_EPBWarnLampReq 3 "Reserved" 2 "Flash Rate 1 Indication" 1 "Continuous Indication" 0 "No Indication";
VAL_ 299 IDB6_EPBStatusLampReq 3 "Reserved" 2 "Flash Rate 1 Indication" 1 "Continuous Indication" 0 "No Indication";
VAL_ 299 IDB6_EPBSysBrkLightsReq 1 "Request to turn on" 0 "No request";
VAL_ 299 IDB6_EPBCruiseCtrlCancelReq 1 "Cruise Control Cancel Requested" 0 "No request";
VAL_ 299 IDB6_RollingBenchModeSts 1 "Active" 0 "Inactive";
VAL_ 299 IDB6_EpbCtrlAvail 1 "Not Available (Both Actuator Not Avvailable）" 0 "Available";
VAL_ 299 IDB6_EPBClusterDispMSG 7 "Not support EPB release under gear P" 6 "Press down the accelerator pedal" 5 "Park Brake Released" 4 "Park Brake Set" 3 "Service Park Brake" 2 "Release Park Brake Switch" 1 "Press Brake Pedal to Release Park Brake" 0 "Off";
VAL_ 301 IDB7_ESCFail 1 "Fail" 0 "Not fail";
VAL_ 301 IDB7_ESCActive 1 "Active" 0 "Inactive";
VAL_ 301 IDB7_ESCDisable 1 "ESC Function Disabled" 0 "ESC Function Enabled";
VAL_ 301 IDB7_ABSActive 1 "Active" 0 "Inactive";
VAL_ 301 IDB7_EBD_Fail 1 "fail" 0 "no fail";
VAL_ 301 IDB7_EBD_Active 1 "Active" 0 "Inactive";
VAL_ 301 IDB7_HBAActive 1 "Active" 0 "Inactive";
VAL_ 301 IDB7_HBAFail 1 "Fail" 0 "Not fail";
VAL_ 301 IDB7_DiagMode 1 "DiagnosticMode" 0 "NormalMode";
VAL_ 301 IDB7_TCSActive 1 "Active" 0 "Inactive";
VAL_ 301 IDB7_TCSDisable 1 "TCS Function Disabled" 0 "TCS Function Enabled";
VAL_ 301 IDB7_TCSFail 1 "Fail" 0 "Not fail";
VAL_ 301 IDB7_ROPACTIVE 1 "Active" 0 "No Active";
VAL_ 301 IDB7_ROPFailure 1 "Failure" 0 "No Failure";
VAL_ 301 IDB7_DynParkBrkByIDBActive 1 "Active" 0 "Inactive";
VAL_ 301 IDB7_DynParkBrkByIDBAvailable 1 "Available" 0 "Not Available";
VAL_ 301 IDB7_HSAActive 1 "Active" 0 "Inactive";
VAL_ 301 IDB7_HSAFail 1 "Fail" 0 "Not fail";
VAL_ 301 IDB7_HDCEnabled 1 "Enabled" 0 "Disabled";
VAL_ 301 IDB7_HDCFail 1 "Fail" 0 "Not fail";
VAL_ 301 IDB7_HDCAtive 1 "Active" 0 "Not active";
VAL_ 301 IDB7_BrkLightReq 1 "Requested" 0 "No Request";
VAL_ 301 IDB7_ABSFail 1 "fail" 0 "no fail";
VAL_ 301 IDB7_ESSActiveReq 2 "ESS function defective" 1 "Requested" 0 "No Request";
VAL_ 301 IDB7_CBCActive 1 "Active" 0 "Inactive";
VAL_ 301 IDB7_CBCFail 1 "Fail" 0 "Not fail";
VAL_ 301 IDB7_ETCSActivationFlag_F 1 "Active" 0 "Inactive";
VAL_ 301 IDB7_ETCSActivationFlag_R 1 "Active" 0 "Inactive";
VAL_ 301 IDB7_BTCSActFlag 1 "Active" 0 "Inactive";
VAL_ 301 IDB7_HBCActive 1 "Active" 0 "Inactive";
VAL_ 301 IDB7_HBCFail 1 "Fail" 0 "No Fail";
VAL_ 301 IDB7_HBCReduced 1 "Active" 0 "Inactive";
VAL_ 301 IDB7_BrakeWarningLamp 2 "IDB  BrakeWarning YellowLamp ON" 1 "IDB  BrakeWarning RedLamp ON" 0 "IDB BrakeWarning Lamp OFF";
VAL_ 301 IDB7_ActAccXValid 1 "Valid(有效)" 0 "Invalid(无效)";
VAL_ 301 IDB7_GroundSlopeValid 1 "Valid(有效)" 0 "Invalid(无效)";
VAL_ 301 IDB7_HDCClusterDispMSG 7 "Reserved" 6 "Reserved" 5 "Reserved" 4 "The HDC function  exits because the vehicle speed is greater than 60km/h；HDC功能因车速大于60km/h而退出" 3 "The HDC function exits because the temperature of the brake disk is too high；HDC功能因制动盘温度过高退出" 2 "The HDC function fails to be enabled because the temperature of the brake disc is too high；HDC功能因制动盘温度过高而无法开启" 1 "The HDC function cannot be enabled because the vehicle speed is greater than 60km/h；HDC功能因车速大于60km/h而无法开启" 0 "Off";
VAL_ 301 IDB7_PIBFail 1 "fail" 0 "no fail";
VAL_ 301 IDB7_PIBActive 1 "Active" 0 "no active";
VAL_ 301 IDB7_TSAActive 1 "Active" 0 "Inactive";
VAL_ 301 IDB7_TSAFail 1 "Fail" 0 "No Fail";
VAL_ 302 IDB12_AVHDispMSG 3 "AUTO HOLD cannot be activated Close Door" 2 "Press Brake Pedal to Release AUTO HOLD" 1 "AUTO HOLD to be deactivated Press Brake Pedal" 0 "AVH is off";
VAL_ 302 IDB12_AVHLampReq 3 "AVH READY" 2 "AVH ACTIVE(Green)" 1 "AVH failure(Yellow)" 0 "AVH Off";
VAL_ 302 IDB12_AVHStatus 2 "AVH being released" 1 "AVH Active" 0 "AVH Inactive";
VAL_ 302 IDB12_AVHEnabled 1 "Enabled" 0 "Disabled";
VAL_ 302 IDB12_EpedalAct 1 "Active" 0 "No Active";
VAL_ 302 IDB12_EpedalSts 1 "Fail" 0 "Normal";
VAL_ 302 IDB12_RBS_exitReq 1 "Requested" 0 "No Request";
VAL_ 302 IDB12_ReDTCAxleTarReq 1 "Requested" 0 "No Request";
VAL_ 302 IDB12_FrntDTCAxleTarReq 1 "Requested" 0 "No Request";
VAL_ 302 IDB12_DTC_Activesta 1 "Active" 0 "No Active";
VAL_ 302 IDB12_DTCFail 1 "Fail" 0 "Not Fail";
VAL_ 302 IDB12_RBSExitReason 7 "Reserved" 6 "Reserved" 5 "非D挡" 4 "制动踏板踩下速率达到阈值" 3 "滑移率达到阈值" 2 "ABS/EBD/ESC/AEB功能激活" 1 "制动踏板未踩下" 0 "RBS功能未工作";
VAL_ 302 IDB12_sOutputRodActValid 1 "Valid(有效)" 0 "Invalid(无效)";
VAL_ 303 IDB8_BrakeActive 1 "Active" 0 "No Active";
VAL_ 303 IDB8_FrntLeEstimdWhlPresVldty 1 "Valid(有效)" 0 "Invalid(无效)";
VAL_ 303 IDB8_FrntRiEstimdWhlPresVldty 1 "Valid(有效)" 0 "Invalid(无效)";
VAL_ 303 IDB8_ReLeEstimdWhlPresVldty 1 "Valid(有效)" 0 "Invalid(无效)";
VAL_ 303 IDB8_ReRiEstimdWhlPresVldty 1 "Valid(有效)" 0 "Invalid(无效)";
VAL_ 1554 IDB_RepeatMessageRequest 1 "Repeat message request" 0 "No repeat message request";
VAL_ 1554 IDB_ActiveWakeup 1 "Wakeup" 0 "No wakeup";
VAL_ 1554 IDB_WakeUp_KL15 1 "KL15 ON Wakeup" 0 "No Request";
VAL_ 1554 IDB_WakeUp_NM 1 "NM Wakeup" 0 "No Request";
VAL_ 1554 IDB_WakeUp_EPBsw 1 "EPB" 0 "No Request";
VAL_ 1554 IDB_RepeatFromSleep 1 "occur" 0 "not occur";
VAL_ 1554 IDB_RepeatFromPrepare 1 "occur" 0 "not occur";
VAL_ 1554 IDB_NormalFromRepeat 1 "occur" 0 "not occur";
VAL_ 1554 IDB_NormalFromReady 1 "occur" 0 "not occur";
VAL_ 1554 IDB_RepeatFromReady 1 "occur" 0 "not occur";
VAL_ 1554 IDB_RepeatFromNormal 1 "occur" 0 "not occur";
VAL_ 1554 IDB_RemainNetworkWakeUpReason1 1 "Remain wakeup reason" 0 "default";
VAL_ 1554 IDB_RemainNetworkWakeUpReason2 1 "Remain wakeup reason" 0 "default";
VAL_ 1554 IDB_RemainNetworkWakeUpReason3 1 "Remain wakeup reason" 0 "default";
VAL_ 1554 IDB_RemainNetworkWakeUpReason4 1 "Remain wakeup reason" 0 "default";
VAL_ 193 EHB2_FRWhlPulCntValid 1 "Valid(有效)" 0 "Invalid(无效)";
VAL_ 193 EHB2_FLWhlPulCntValid 1 "Valid(有效)" 0 "Invalid(无效)";
VAL_ 195 EHB4_FLWhlVelocityValid 1 "Valid(有效)" 0 "Invalid(无效)";
VAL_ 195 EHB4_FRWhlVelocityValid 1 "Valid(有效)" 0 "Invalid(无效)";
VAL_ 195 EHB4_RRWhlDir 3 "Error identifier" 2 "Backward direction" 1 "Forward direction" 0 "Unknown or stanstill";
VAL_ 195 EHB4_RLWhlDir 3 "Error identifier" 2 "Backward direction" 1 "Forward direction" 0 "Unknown or stanstill";
VAL_ 195 EHB4_FRWhlDir 3 "Error identifier" 2 "Backward direction" 1 "Forward direction" 0 "Unknown or stanstill";
VAL_ 195 EHB4_FLWhlDir 3 "Error identifier" 2 "Backward direction" 1 "Forward direction" 0 "Unknown or stanstill";
VAL_ 195 EHB4_RRWhlVelocityValid 1 "Valid(有效)" 0 "Invalid(无效)";
VAL_ 195 EHB4_RLWhlVelocityValid 1 "Valid(有效)" 0 "Invalid(无效)";
VAL_ 195 EHB4_RLWhlPulCntValid 1 "Valid(有效)" 0 "Invalid(无效)";
VAL_ 195 EHB4_RRWhlPulCntValid 1 "Valid(有效)" 0 "Invalid(无效)";
VAL_ 198 EHB3_VehicleSpdValid 1 "Valid(有效)" 0 "Invalid(无效)";
VAL_ 198 EHB3_PedalSimulatorPressureInvalid 1 "Valid(有效)" 0 "Invalid(无效)";
VAL_ 198 EHB3_HBAActive 1 "Active" 0 "Inactive";
VAL_ 198 EHB3_HBAFail 1 "Fail" 0 "Not fail";
VAL_ 198 EHB3_BrkLightReq 1 "Request" 0 "No request";
VAL_ 198 EHB3_HBCRequestValid 1 "Valid(有效)" 0 "Invalid(无效)";
VAL_ 198 EHB3_HBCRequest 1 "Request(请求HBC工作)" 0 "No Request(无请求)";
VAL_ 198 EHB3_MasterCylPressureInvalid 1 "Valid(有效)" 0 "Invalid(无效)";
VAL_ 300 ESC1_EPB_DynamicApplySta 3 "reversed" 2 "Degrade Apply" 1 "RWU active" 0 "Not Active";
VAL_ 300 ESC1_EPB_ActuatorSt_R 7 "reversed" 6 "Hold" 5 "Unknown" 4 "Completely Released" 3 "Brake Applying" 2 "Brake Released" 1 "Brake Applied" 0 "Brake Releasing";
VAL_ 300 ESC1_EPB_ActuatorSt_L 7 "reversed" 6 "Hold" 5 "Unknown" 4 "Completely Released" 3 "Brake Applying" 2 "Brake Released" 1 "Brake Applied" 0 "Brake Releasing";
VAL_ 300 ESC1_EpbDrvAwyInt 1 "Indicated" 0 "Not Indicated";
VAL_ 300 ESC1_EpbActrAvailPrim 1 "Not Available" 0 "Available";
VAL_ 300 ESC1_EPB_DisplayMsgID 4 "after roll reapply,still roll" 3 "slpoe too steep" 2 "push brake pedal" 1 "close door（主驾门）" 0 "off";
VAL_ 300 ESC1_EpbActrStatPrim 6 "CompletelyReleased" 5 "Releasing" 4 "Applying" 3 "Released" 2 "HoldApplied" 1 "ParkApplied" 0 "Unknown";
VAL_ 300 ESC1_EpbAplRelReq 6 "Adjustment" 5 "RollerbenchApply" 4 "DynamicApply" 3 "Release" 2 "HoldApply" 1 "ParkApply" 0 "None";
VAL_ 300 ESC1_EPBStatus 7 "Not Initialized (NEW)" 6 "Full Released完全释放" 5 "Dynamic braking via EPB动态驻车" 4 "Releasing in progress卡钳释放中" 3 "Clamping in progress卡钳夹紧中" 2 "Clamped卡钳夹紧" 1 "Released卡钳释放" 0 "Unknown未知";
VAL_ 300 ESC1_EPBAvailable 6 "EPB  failure" 5 "EPB Permanently Not Available" 4 "EPB Temporarily Not Available" 3 "EPB Diagnostic" 2 "EPB Initialization State" 1 "EPB No failure" 0 "Not valid";
VAL_ 300 ESC1_EPBWarnLampReq 3 "Reserved" 2 "Flash Rate 1 Indication" 1 "Continuous Indication" 0 "No Indication";
VAL_ 300 ESC1_EPBStatusLampReq 3 "Reserved" 2 "Flash Rate 1 Indication" 1 "Continuous Indication" 0 "No Indication";
VAL_ 300 ESC1_EPBSysBrkLightsReq 1 "Request to turn on" 0 "No request";
VAL_ 300 ESC1_EPBCruiseCtrlCancelReq 1 "Cruise Control Cancel Requested" 0 "No request";
VAL_ 300 ESC1_RollingBenchModeSts 1 "Active" 0 "Inactive";
VAL_ 300 ESC1_EpbCtrlAvail 1 "Not Available (Both Actuator Not Avvailable）" 0 "Available";
VAL_ 300 ESC1_EPBClusterDispMSG 6 "Press down the accelerator pedal" 5 "Park Brake Released" 4 "Park Brake Set" 3 "Service Park Brake" 2 "Release Park Brake Switch" 1 "Press Brake Pedal to Release Park Brake" 0 "Off";
VAL_ 177 EPS1_SteeringAngleValid 1 "Valid" 0 "Invalid";
VAL_ 177 EPS1_SteerAngleSpdValid 1 "Valid" 0 "Invalid";
VAL_ 177 EPS1_HSTWCalibrated 1 "angle calibrated" 0 "angle not calibrated";
VAL_ 177 EPS1_WarningLampRed 1 "Function failure, lamp on" 0 "close";
VAL_ 177 EPS1_TorsionBarTorqueValid 1 "Valid" 0 "Invalid";
VAL_ 177 EPS1_WarningLampYellow 3 "Reserved" 2 "function limited, lamp on" 1 "angle not calibrated, lamp blink" 0 "close";
VAL_ 177 EPS1_ModSts 3 "Sport" 2 "Standard" 1 "Comfort" 0 "Reserved";
VAL_ 177 EPS1_ModSetInhibit 1 "Inhibit" 0 "No inhibit";
VAL_ 178 EPS2_ADAS_Available 1 "Available" 0 "Not  Available";
VAL_ 178 EPS2_ADAS_Active 1 "active" 0 "not active";
VAL_ 178 EPS2_AssistPraSwitchToDAS 3 "Reserved" 2 "APA mode" 1 "ADAS mode" 0 "not in ADAS mode";
VAL_ 178 EPS2_ADAS_CtrlAbortFeedback 10 "Parking interruption" 9 "ADAS activation request error" 8 "Request Value over range" 7 "Request Slope over range" 6 "ADAS transmition signal error" 5 "EPS Temporary error" 4 "EPS Permanently error" 3 "Over speed" 2 "Vehicle Speed Invalid" 1 "Driver  override" 0 "No error";
VAL_ 178 EPS2_PA_Available 1 "Available" 0 "Not Available";
VAL_ 178 EPS2_PA_Active 1 "active" 0 "not active";
VAL_ 178 EPS2_MotCntrlValid 1 "Valid" 0 "Invalid";
VAL_ 178 EPS2_PA_CtrlAbortFeedback 9 "Parking activation error" 8 "Request Value over range" 7 "Request Slope over range" 6 "APA transmition signal error" 5 "EPS Temporary error" 4 "EPS Permanently error" 3 "Over speed" 2 "Vehicle Speed Invalid" 1 "Driver override" 0 "No error";
VAL_ 298 REPB1_ReleaseRequest 2 "EPB Apply Request" 1 "EPB Release Request" 0 "No Request";
VAL_ 298 REPB1_EpbActrStatSec 6 "CompletelyReleased" 5 "Releasing" 4 "Applying" 3 "Released" 2 "HoldApplied" 1 "ParkApplied" 0 "Unknown";
VAL_ 298 REPB1_ActuatorSt_R 7 "reversed" 6 "Hold" 5 "Unknown" 4 "Completely Released" 3 "Brake Applying" 2 "Brake Released" 1 "Brake Applied" 0 "Brake Releasing";
VAL_ 298 REPB1_ActuatorSt_L 7 "reversed" 6 "Hold" 5 "Unknown" 4 "Completely Released" 3 "Brake Applying" 2 "Brake Released" 1 "Brake Applied" 0 "Brake Releasing";
VAL_ 298 REPB1_SlaveSysActive 1 "Active" 0 "Inactive";
VAL_ 298 REPB1_EpbActrAvailSec 1 "Not Available" 0 "Available";
VAL_ 298 REPB1_EpbDynamicCmd 1 "Dynamic Apply" 0 "None";
VAL_ 298 REPB1_EpbStaticCmd 2 "Apply" 1 "Release" 0 "None";
VAL_ 298 REPB1_EPBStatus 7 "Not Initialized (NEW)" 6 "Full Released完全释放" 5 "Dynamic braking via EPB动态驻车" 4 "Releasing in progress卡钳释放中" 3 "Clamping in progress卡钳夹紧中" 2 "Clamped卡钳夹紧" 1 "Released卡钳释放" 0 "Unknown未知";
VAL_ 298 REPB1_EPBAvailable 6 "EPB  failure" 5 "EPB Permanently Not Available" 4 "EPB Temporarily Not Available" 3 "EPB Diagnostic" 2 "EPB Initialization State" 1 "EPB No failure" 0 "Not valid";
VAL_ 298 REPB1_EPBSysBrkLightsReq 1 "Request to turn on" 0 "No request";
VAL_ 298 REPB1_EPBCruiseCtrlCancelReq 1 "Cruise Control Cancel Requested" 0 "No request";
VAL_ 298 REPB1_EPBClusterDispMSG 7 "Not support EPB release under gear P" 6 "Press down the accelerator pedal" 5 "Park Brake Released" 4 "Park Brake Set" 3 "Service Park Brake" 2 "Release Park Brake Switch" 1 "Press Brake Pedal to Release Park Brake" 0 "Off";
VAL_ 298 REPB1_EPBWarnLampReq 3 "Reserved" 2 "Flash Rate 1 Indication" 1 "Continuous Indication" 0 "No Indication";
VAL_ 298 REPB1_EPBStatusLampReq 3 "Reserved" 2 "Flash Rate 1 Indication" 1 "Continuous Indication" 0 "No Indication";
VAL_ 817 ISC_ISCErrorSts 1 "Error" 0 "No error";
VAL_ 817 ISC_ISCModeSetFb 4 "RESERVED" 3 "RESERVED" 2 "SPORT" 1 "NORMAL" 0 "COMFORT";
VAL_ 142 ADCS2_ADAS_EPSAngleReqSt 1 "Requested" 0 "No Request";
VAL_ 142 ADCS2_EPS_LDPState 4 "LDP passive" 3 "LDP Fail" 2 "LDP Active" 1 "LDP Standby" 0 "Off";
VAL_ 142 ADCS2_NNP_SystemFaultStatus 3 "Service Required" 2 "System Temporary Unvailable" 1 "Performance Degradation" 0 "No Error";
VAL_ 142 ADCS_Pilot_SystemFaultStatus 3 "Service Required" 2 "System Temporary Unvailable" 1 "Performance Degradation" 0 "No Error";
VAL_ 142 ADCS2_ADAS_EPSLateralCtrlType 7 "Reserved" 6 "Reserved" 5 "Reserved" 4 "ELK Mode" 3 "NNP Mode" 2 "Pilot Mode" 1 "LDP Mode" 0 "None";
VAL_ 142 ADCS2_ADAS_IHBCSysState 4 "System Failure" 3 "IHBC On & High Beam On" 2 "IHBC On & High Beam Off" 1 "Standby&passive" 0 "IHBC Off";
VAL_ 142 ADCS2_ALCDirection 4 "Warning Light" 3 "Shutdown" 2 "Right" 1 "Left" 0 "Off";
VAL_ 142 ADCS2_ACC_EpbReq 3 "Reserve" 2 "apply request" 1 "Release request" 0 "No request";
VAL_ 142 ADCS2_AEBVehicleHoldReq 1 "Requested" 0 "No Request";
VAL_ 142 ADCS2_AEBFullBrake 1 "Requested" 0 "No Request";
VAL_ 142 ADCS2_AEBPartialBrake 1 "Requested" 0 "No Request";
VAL_ 142 ADCS2_AEB_DBSLevel 3 "DBS level 3" 2 "DBS level 2" 1 "DBS level 1" 0 "No activation";
VAL_ 142 ADCS2_AEBPrefillReq 1 "Requested" 0 "No Request";
VAL_ 142 ADCS2_AEB_JerkReq 1 "Request" 0 "No request";
VAL_ 142 ADCS2_longitudCtrlType 3 "NNP Mode" 2 "NPilot Mode" 1 "ACC Mode" 0 "None";
VAL_ 142 ADCS2_LongitudCtrlDecToStopReq 1 "Requested" 0 "No Request";
VAL_ 142 ADCS2_LongitudCtrlDriveOff 1 "Requested" 0 "No Request";
VAL_ 142 ADCS2_AEB_JerkLevel 3 "Jerk level 3" 2 "Jerk level 2" 1 "Jerk level 1" 0 "No activation";
VAL_ 142 ADCS2_LongitudCtrlAccelCtrlReq 1 "Requested" 0 "No Request";
VAL_ 143 ADCS11_PA_GearReq 1 "Request" 0 "No request";
VAL_ 143 ADCS11_PA_GearPosReqVail 1 "Valid" 0 "Invalid";
VAL_ 143 ADCS11_PA_prefillReq 1 "Request" 0 "No request";
VAL_ 143 ADCS11_PA_GearPosReq 7 "Reserved" 6 "Reserved" 5 "Reserved" 4 "D" 3 "N" 2 "R" 1 "P" 0 "No request";
VAL_ 143 ADCS11_PA_BrakemodeReq 2 "Emergency Brake Active" 1 "Comfort Brake Active" 0 "Function Not Active";
VAL_ 143 ADCS11_PA_EpbReq 3 "Reserve" 2 "apply request" 1 "Release request" 0 "No request";
VAL_ 143 ADCS11_PA_lampreq 3 "Hazard Lamp Request" 2 "Right Turn Lamp Request" 1 "Left Turn Lamp  Request" 0 "No Request";
VAL_ 143 ADCS11_Parking_WorkSts 15 "Invalid" 11 "Cruising（HPP Pro）" 10 "Failure" 9 "Abort" 8 "Suspend" 7 "Complete" 6 "Localization" 5 "Map building" 4 "Cruising（HPP）" 3 "Parking" 2 "TBA standby" 1 "Standby(通过开关进入PA)" 0 "off";
VAL_ 143 ADCS11_RPA_RemoteParkAppStartReq 1 "Request" 0 "No Request";
VAL_ 143 ADCS11_PA_Recover 1 "Recovered" 0 "No Request";
VAL_ 143 ADCS11_TurnLampReq 3 "HazardLamp on" 2 "right turn lamp on" 1 "left turn lamp on" 0 "off";
VAL_ 143 ADCS11_SetPathwayWorkSts 2 "off" 1 "on" 0 "No Request";
VAL_ 143 ADCS11_HPAGuideSts 7 "Reserved" 6 "Reserved" 5 "Reserved" 4 "backtobasement" 3 "backtobegin" 2 "Located" 1 "Relocation" 0 "Normal";
VAL_ 143 ADCS11_HPA_WorkSts 7 "Failed" 6 "Abort" 5 "Suspend" 4 "Finished" 3 "Active" 2 "Enable" 1 "Standby" 0 "Off";
VAL_ 143 ADCS11_PA_IDBControlReqV 1 "valid" 0 "Invalid";
VAL_ 143 ADCS11_APA_FRWindowsCtrl 5 "通风" 4 "Auto Down" 3 "Auto Up预留" 2 "Manual Down" 1 "Manual Up" 0 "No request";
VAL_ 143 ADCS11_APA_RemoteLockCtrl 3 "寻车" 2 "Unlock" 1 "Lock" 0 "No request";
VAL_ 143 ADCS11_APA_FLWindowsCtrl 5 "通风" 4 "Auto Down" 3 "Auto Up" 2 "Manual Down" 1 "Manual Up" 0 "No request";
VAL_ 143 ADCS11_APA_requestMirrorFoldSt 2 "Fold" 1 "Unfold" 0 "No request";
VAL_ 143 ADCS11_APA_RRWindowsCtrl 5 "通风" 4 "Auto Down" 3 "Auto Up预留" 2 "Manual Down" 1 "Manual Up" 0 "No request";
VAL_ 143 ADCS11_APA_RLWindowsCtrl 5 "通风" 4 "Auto Down" 3 "Auto Up预留" 2 "Manual Down" 1 "Manual Up" 0 "No request";
VAL_ 143 ADCS11_PA_EPSAngleReqSt 1 "Request" 0 "No request";
VAL_ 143 ADCS11_PA_EPSAngleReqV 1 "Valid" 0 "Invalid";
VAL_ 143 ADCS11_PrkngFctnModeReq 7 "reserved" 6 "TAB" 5 "ISM" 4 "AVP" 3 "HPP" 2 "RPA" 1 "FAPA" 0 "Off";
VAL_ 143 ADCS11_HPAPathlearning_WorkSts 7 "Failed" 6 "Abort" 5 "Suspend" 4 "Finished" 3 "Active" 2 "Enable" 1 "Standby" 0 "Off";
VAL_ 143 ADCS11_HPAPathwaytoCloud_WorkSts 7 "Reserve" 6 "Reserve" 5 "Reserve" 4 "Reserve" 3 "Uploading error" 2 "Uploading" 1 "Uploaded" 0 "To be uploaded";
VAL_ 143 ADCS11_TrackreverseWorkSts 7 "Failed" 6 "Abort" 5 "Suspend" 4 "Finished" 3 "Active" 2 "Enable" 1 "Standby" 0 "Off";
VAL_ 143 ADCS11_Currentgear 2 "Gear R" 1 "Gear D" 0 "No Request";
VAL_ 143 ADCS11_PA_IDBControlReq 3 "Failed" 2 "Assist" 1 "Ready" 0 "Off";
VAL_ 143 ADCS11_APA_RemoteStartReq 1 "Request" 0 "No request";
VAL_ 143 ADCS11_APA_RemoteShutdownReq 1 "Request" 0 "No request";
VAL_ 143 ADCS11_MirrorFoldrequest 2 "Fold" 1 "Unfold" 0 "No request";
VAL_ 143 ADCS11_PA_TorqReq 1 "Request" 0 "No request";
VAL_ 143 ADCS11_PA_TorqReqValidity 1 "Valid" 0 "Invalid";
VAL_ 143 ADCS11_PA_Pause_Recover 3 "reserved" 2 "recover" 1 "Pause" 0 "No request";
VAL_ 143 ADCS11_HPA_BacktoEntrance 1 "Request" 0 "No request";
VAL_ 143 ADCS11_HPA_BacktoStart 1 "Request" 0 "No request";
VAL_ 143 ADCS11_PA_TarDecelreq 1 "Request" 0 "No Request";
VAL_ 143 ADCS11_PA_ParkingFnMd 3 "HPP Pro_Cruising" 2 "HPP_Cruising" 1 "Parking" 0 "NoRequest";
VAL_ 143 ADCS11_PA_screenReq 9 "TAB" 8 "ISM" 7 "AVP" 6 "HPP" 5 "RPA" 4 "FAPA" 3 "AVM" 2 "RVC" 1 "PDC" 0 "No Request";
VAL_ 143 ADCS11_HPA_PathlearningSt 2 "complete" 1 "learning" 0 "Noaction";
VAL_ 143 ADCS11_HPA_Path_exist 3 "A certain distance" 2 "exist" 1 "inexistence" 0 "Noaction";
VAL_ 143 ADCS11_PA_PickSt 1 "active" 0 "Noaction";
VAL_ 143 ADCS11_PA_StopReq 1 "Stop control is required" 0 "No request";
VAL_ 143 ADCS11_PA_StopDistanceValid 1 "valid" 0 "Invalid";
VAL_ 143 ADCS11_HPA_Pathavailable_ID2 0 "Default";
VAL_ 143 ADCS11_HPA_distance 4095 "invalid";
VAL_ 143 ADCS11_Parkingtimeremaining 1023 "invalid";
VAL_ 143 ADCS11_NNS_distance 65535 "invaild";
VAL_ 143 ADCS11_HPA_Pathavailable_ID1 0 "Default";
VAL_ 143 ADCS11_HighBeam 3 "Flash" 2 "OFF" 1 "ON" 0 "No request";
VAL_ 143 ADCS11_ReqPwmode 2 "Power off" 1 "Power on" 0 "No request";
VAL_ 143 ADCS11_SecuritySts 3 "Reserved" 2 "In security  status" 1 "Not in Security status" 0 "Initial value";
VAL_ 143 ADCS11_LowBeam 2 "Request Off" 1 "Request On" 0 "No request";
VAL_ 143 ADCS11_PA_IDB_TorqReqValidity 1 "Valid" 0 "Invalid";
VAL_ 143 ADCS11_HPA_learnpathdistance 0 "Default";
VAL_ 254 ADCS4_AVM_RCW_warningReq 3 "Reserved2" 2 "Reserved1" 1 "Warning" 0 "No warning";
VAL_ 254 ADCS4_AVM_BSD_warningReqLeft 3 "Reserved" 2 "Warning level 2" 1 "Warning level 1" 0 "No warning";
VAL_ 254 ADCS4_AVM_BSD_warningReqRight 3 "Reserved" 2 "Warning level 2" 1 "Warning level 1" 0 "No warning";
VAL_ 254 ADCS4_SystemFault2 3 "reserved" 2 "Service Required" 1 "System temporary Unavaliable" 0 "System Normal";
VAL_ 254 ADCS4_AVM_DayNightStatus 1 "Night" 0 "Day";
VAL_ 254 ADCS4_APA_InParkingSpaceStatus 1 "In Parking Space" 0 "Not In Parking Space";
VAL_ 254 ADCS4_AVM_Sts 7 "Show Sc" 6 "Show PA" 5 "Fault" 4 "Calibration" 3 "Road Calibration" 2 "Show AVM" 1 "Standby" 0 "off";
VAL_ 254 ADCS4_RPA_RemoteParkFinishReq 2 "Park out finish" 1 "Park in finish" 0 "No request";
VAL_ 254 ADCS4_AVM_BSD_SysSts 6 "Reserved" 5 "System blindness" 4 "System fault" 3 "Trailer mode, all BSD function not available(Reserved)" 2 "Active" 1 "Standby" 0 "Initialization";
VAL_ 254 ADCS4_PA_InfoDisplayReq 9 "Extreme weather" 8 "Abort_external system_Fail" 7 "Abort_VCU_Fail" 6 "Abort_ESP_Fail" 5 "Abort_EPS_Fail" 4 "Abort_APA_ECU_Fail" 3 "APA_Off_Speed too high" 2 "Slope_is_restricted" 1 "Abort_Other_reasons" 0 "OFF";
VAL_ 254 ADCS4_PA_failinfo 15 "充电中，请稍后再试" 14 "请检查车门,后背箱和机舱盖是否关闭" 13 "当前环境无法开启路线学习" 12 "蓝牙连接异常，无法使用此功能" 11 "车辆未挂P档，无法使用此功能" 10 "当前环境，无法使用此功能" 9 "续航能力低，无法使用此功能" 8 "ADAS已开启，无法使用此功能" 7 "请保持速度＜25km/h下，使用此功能" 6 "后视镜折叠，功能无法开启" 5 "关联件系统故障，功能无法开启" 4 "请在车辆启动下，使用此功能" 3 "雷达故障，功能无法开启" 2 "系统故障，功能无法开启" 1 "摄像头故障，功能无法开启" 0 "Normal";
VAL_ 254 ADCS4_UPA_Sound_Location 6 "Right Rear+Left Rear" 5 "Left Rear" 4 "Right Rear" 3 "Driver Front+Passenger Front" 2 "Driver Front" 1 "Passenger Front" 0 "No warning";
VAL_ 254 ADCS4_HPA_failinfo 15 "reserved" 14 "reserved" 13 "reserved" 12 "reserved" 11 "reserved" 10 "reserved" 9 "记忆泊车暂不可用" 8 "系统受限，功能无法开启" 7 "当前环境，无法开启记忆泊车" 6 "请在车辆启动下，使用此功能" 5 "关联系统受限，功能无法开启" 4 "激光雷达不可用，功能无法开启" 3 "请从地面回到地库，再使用记忆泊车" 2 "请打开设置项开关，再使用记忆泊车" 1 "请在地下停车场使用记忆泊车功能" 0 "Normal";
VAL_ 254 ADCS4_UPA_SysSoundIndication 5 "Tone 4 - 1Hz音频 (ICU_AudioAlarmReq 0x4:Radar lv1)" 4 "Tone 4 - 1Hz音频(ICU_AudioAlarmReq 0x4:Radar lv1)" 3 "Tone 3 - 2Hz音频(ICU_AudioAlarmReq 0x3:Radar lv2)" 2 "Tone 2 - 4Hz音频(ICU_AudioAlarmReq 0x2:Radar lv3)" 1 "Tone 1 - 长鸣(ICU_AudioAlarmReq 0x1:Radar lv4)" 0 "Tone 0 - No warning(ICU_AudioAlarmReq 0x0:Off)";
VAL_ 254 ADCS4_AVM_SysSoundIndication 2 "Over speed" 1 "System disabled or fault" 0 "No indication";
VAL_ 254 ADCS4_DCWposition 3 "level3" 2 "level2" 1 "level1" 0 "off";
VAL_ 254 ADCS4_PA_ParkBarPercent 11 "100%" 10 "90%" 9 "80%" 8 "70%" 7 "60%" 6 "50%" 5 "40%" 4 "30%" 3 "20%" 2 "10%" 1 "0%" 0 "No request";
VAL_ 254 ADCS4_APA_FunctionMode 4 "Traction" 3 "choice parking in" 2 "Parking out" 1 "Parking in" 0 "No action";
VAL_ 254 ADCS4_HornReq 1 "Request" 0 "No Request";
VAL_ 254 ADCS4_Text 63 "前方左转" 62 "回到记忆泊车路线上，点击恢复记忆泊车" 61 "Reserved" 60 "Reserved" 59 "请行驶到路线起点，开启记忆泊车" 58 "Reserved" 57 "Reserved" 56 "请按照提示的指引来使用记忆泊车" 55 "有点难，你帮我过去吧" 54 "请踩住刹车，点击开始泊入" 53 "请泊入车位后再挂P档" 52 "选中您的车位后点击开始泊入" 51 "请保持低速行驶" 50 "请按照提示的指引重新学习路线" 49 "前方右转" 48 "记忆泊车工作中" 47 "目标车位被占，请接管车辆" 46 "您的车位已被占，请点击选择其他车位泊入" 45 "你可操作上传或删除，路线删除后，如需使?该地停?场记忆泊?，则需重新学习(弹窗)" 44 "当前起点有重复路线，请选择路线（弹窗）" 43 "重新学习路线，将会覆盖原有的路线，确定要重新学习吗？(弹窗)" 42 "您好，路线正在学习中，如退出，已学习路线将删除（弹窗）“" 41 "即将自动泊入车位" 40 "正在低速跟车" 39 "正在避让行人" 38 "前方路口" 37 "正在避让障碍物" 36 "前方路口，请注意穿行车辆" 35 "车辆已到达召唤点（手机）" 34 "记忆泊车已暂停" 33 "长按终点图标重设召唤点" 32 "路径规划中" 31 "拖动或点击地图，选择召唤点" 30 "已到达预约位置，请尽快前往" 29 "记忆泊车已完成" 28 "语音播报（不显示文字）" 27 "语音播报2（不显示文字）" 26 "请选择车位" 25 "点击开始记忆泊车" 24 "语音播报1（不显示文字）" 23 "恭喜，路线学习成功（弹窗）" 22 "请输入路线名称，已学习的路线将自动保存（弹窗）" 21 "倒入车位后，请挂P档" 20 "请泊入您的车位" 19 "你好，路线库已满，如需学习路线，需前往路线管理删除路线（弹窗）" 18 "到达您的车位后，请倒车入库" 17 "请控制车辆搜索车位" 16 "你好，使用远程泊车功能需停好车辆后，挂P档，下车，关好车门，打开手机蓝牙，通过手机App来进行操作。（弹窗）" 15 "请在车辆静止下使用此功能" 14 "请保持车辆静止并点击开始泊车" 13 "请选择合适车位，当前车位不可用" 12 "请调整好目标车位后点击确认" 11 "请保持车辆静止并选择车位类型" 10 "当前方向不可泊出，请重新选择" 9 "请保持车辆静止并选择泊出类型及方向" 8 "车速过快" 7 "车速过快，自动泊车已退出" 6 "车速过快，请将车速降低至25km/H以下" 5 "泊车已完成，3S后退出（车端）请前往处理（手机）" 4 "请注意周边环境" 3 "请松开刹车及方向盘，自动泊车开始" 2 "已找到车位，请踩住刹车，点击开始泊入或OK手势开启泊车，您也可以通过点选或语音切换目标车位" 1 "搜索车位中，请保持低速行驶" 0 "No indication";
VAL_ 254 ADCS4_ParkingswithReq 1 "Request" 0 "No Request";
VAL_ 254 ADCS4_Slotavaliable 2 "not Avaliable" 1 "Avaliable" 0 "Undecided";
VAL_ 254 ADCS4_locationSt 2 "step2" 1 "step1" 0 "No action";
VAL_ 254 ADCS4_DCWlevel 3 "doublewarning" 2 "rightwarning" 1 "leftwarning" 0 "default";
VAL_ 254 ADCS4_HPA_deleteMapSt 2 "delcomplete" 1 "deleting" 0 "Noaction";
VAL_ 254 ADCS4_HPA_uploadMapSt 11 "100%" 10 "90%" 9 "80%" 8 "70%" 7 "60%" 6 "50%" 5 "40%" 4 "30%" 3 "20%" 2 "10%" 1 "0%" 0 "No request";
VAL_ 254 ADCS4_HPAWarningInfo 2 "此处已有地图，是否重新学习" 1 "地图存储已满" 0 "Default";
VAL_ 254 ADCS4_AVM_vedioReq 6 "Picture in picture" 5 "Send Calibration File" 4 "Show calibration" 3 "Show PA" 2 "Show AVM" 1 "Hide" 0 "No Request";
VAL_ 254 ADCS4_HPA_FunctionMode 1 "Request on" 0 "No request";
VAL_ 254 ADCS4_NNS_FunctionMode 5 "Inplace" 4 "suspend" 3 "Ready" 2 "Path planing" 1 "NNS" 0 "No action";
VAL_ 254 ADCS4_TractionswithReq 1 "Request" 0 "No Request";
VAL_ 254 ADCS4_RPA_FunctionMode 4 "liner ctrl" 3 "choice parking in" 2 "Parking out" 1 "Parking in" 0 "No action";
VAL_ 254 ADCS4_GMState 3 "Reserved" 2 "Standby" 1 "On" 0 "Off";
VAL_ 254 ADCS4_GMWarnState 3 "Level 2 Warning" 2 "Approach Warning" 1 "Vibration Warning" 0 "No Warning";
VAL_ 254 ADCS4_DCWworkSt 7 "Reserved" 6 "Reserved" 5 "Reserved" 4 "Abort" 3 "Failure" 2 "Active" 1 "Standby" 0 "Off";
VAL_ 254 ADCS4_DCWtext 7 "Reserved" 6 "Reserved" 5 "Reserved" 4 "Reserved" 3 "请小心开门" 2 "请小心右侧开门" 1 "请小心左侧开门" 0 "default";
VAL_ 254 ADCS4_GM_SystemFaultStatus 3 "Service Required" 2 "System Temporary Unvailable" 1 "Performance Degradation" 0 "No Error";
VAL_ 254 ADCS4_GMWorkState 7 "Reserved" 6 "Reserved" 5 "fail" 4 "disable" 3 "active" 2 "passive" 1 "standby" 0 "NO action";
VERSION ""

NS_ :

BS_:

BU_: GW_FD5 GW_FD6 GW_FD3 GW_FD4 GW_FD1 GW_FD2 PDCS_FD1 PDCU SRR3 SRR4 ADCU_FD3 BDCS DDCU CDCS ADCS_FD3 CDCS_OverSea TBOX FLC_ME_FD3 FLC_FD3 ICU_E02 ICU PDCS_HVM_FD1 TBOX_OverSea BMS ISC GCU EMS IDB ESC_FD3 EHB_FD3 MCU IMU ACU EPS WPC CDU AMP BAM PDCS_FD3 EVCC REPB ADCS_FD6 ADCU_FD6 FLC_ME_FD6 FLC_FD6 DLC GW_FD7 ESC_FD6 EHB_FD6

BO_ 528 ADCS_Fr09_210: 8 ADCU_FD3
 SG_ ADCS9_AVM_MODdetectionSts : 0|1@0+ (1,0) [0|1] "NoUnit" ICU_E02,GW_FD4,ICU,CDCS,CDCS_OverSea
 SG_ ADCS9_AVM_TransparentchassisSts : 1|1@0+ (1,0) [0|1] "NoUnit" ICU_E02,GW_FD4,ICU,CDCS,CDCS_OverSea
 SG_ ADCS9_PA_FRS_Onoffset : 2|1@0+ (1,0) [0|1] "NoUnit" GW_FD4,CDCS,CDCS_OverSea
 SG_ ADCS9_AVM_Diaphaneity : 7|4@0+ (1,0) [0|15] "NoUnit" ICU_E02,GW_FD4,ICU,CDCS,CDCS_OverSea
 SG_ ADCS9_AVM_startMode : 10|3@0+ (1,0) [0|7] "NoUnit" GW_FD4,CDCS,CDCS_OverSea
 SG_ ADCS9_CDCS_CertificateState : 11|1@0+ (1,0) [0|1] "NoUnit" GW_FD4,CDCS,CDCS_OverSea
 SG_ ADCS9_AVMFrontCAMFault : 17|2@0+ (1,0) [0|3] "NoUnit" GW_FD4,CDCS,CDCS_OverSea
 SG_ ADCS9_AVMLeftCAMFault : 19|2@0+ (1,0) [0|3] "NoUnit" GW_FD4,CDCS,CDCS_OverSea
 SG_ ADCS9_AVMRightCAMFault : 21|2@0+ (1,0) [0|3] "NoUnit" GW_FD4,CDCS,CDCS_OverSea
 SG_ ADCS9_AVMRearCAMFault : 23|2@0+ (1,0) [0|3] "NoUnit" GW_FD4,CDCS,CDCS_OverSea
 SG_ ADCS9_HPA_OnOffSetSts : 26|1@0+ (1,0) [0|1] "NoUnit" TBOX,GW_FD5,GW_FD4,CDCS,CDCS_OverSea,TBOX_OverSea
 SG_ ADCS9_AVM_InitializationSts : 32|1@0+ (1,0) [0|1] "NoUnit" GW_FD4,CDCS,CDCS_OverSea
 SG_ ADCS9_AVM_bodySyncSts : 33|1@0+ (1,0) [0|1] "NoUnit" GW_FD4,CDCS,CDCS_OverSea
 SG_ ADCS9_HPA_CrossingNumber : 25|8@0+ (1,0) [0|255] "NoUnit" TBOX,GW_FD5,GW_FD4,CDCS,CDCS_OverSea,TBOX_OverSea
 SG_ ADCS9_AVM_3DRotateSts : 40|1@0+ (1,0) [0|1] "NoUnit" GW_FD4,CDCS,CDCS_OverSea
 SG_ ADCS9_AVM_TurnlightstartSts : 41|1@0+ (1,0) [0|1] "NoUnit" GW_FD4,CDCS,CDCS_OverSea
 SG_ ADCS9_AVM_SteeringstartSts : 42|1@0+ (1,0) [0|1] "NoUnit" GW_FD4,CDCS,CDCS_OverSea
 SG_ ADCS9_AVM_MagnifiedviewSts : 43|1@0+ (1,0) [0|1] "NoUnit" GW_FD4,CDCS,CDCS_OverSea
 SG_ ADCS9_AVM_auxiliarylineSts : 44|1@0+ (1,0) [0|1] "NoUnit" GW_FD4,CDCS,CDCS_OverSea
 SG_ ADCS9_AVM_RaderdisplaySts : 45|1@0+ (1,0) [0|1] "NoUnit" GW_FD4,CDCS,CDCS_OverSea
 SG_ ADCS9_AVM_LowSpeedBSDSts : 53|1@0+ (1,0) [0|1] "NoUnit" GW_FD4,CDCS,CDCS_OverSea
 SG_ ADCS9_AVM_SpeViewSts : 55|2@0+ (1,0) [0|3] "NoUnit" GW_FD4,CDCS,CDCS_OverSea

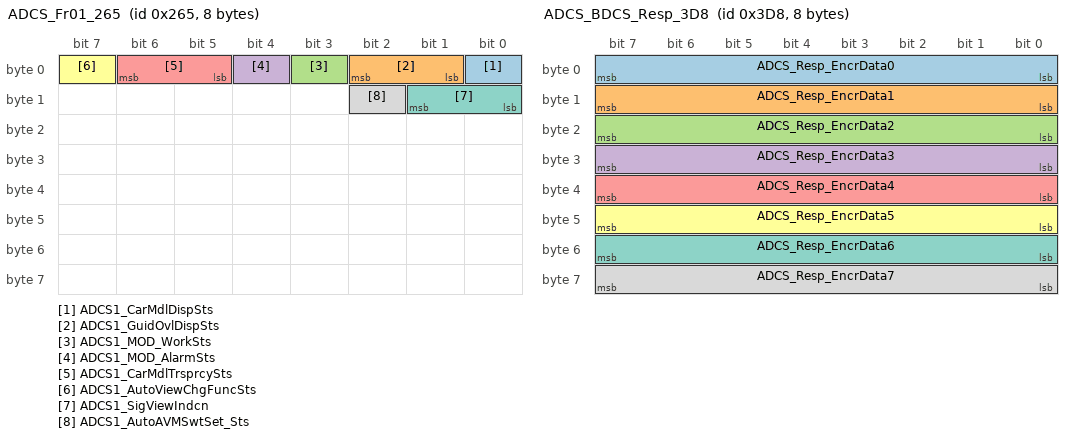
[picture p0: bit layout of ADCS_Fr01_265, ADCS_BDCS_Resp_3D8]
BO_ 613 ADCS_Fr01_265: 8 ADCU_FD3
 SG_ ADCS1_CarMdlDispSts : 0|1@0+ (1,0) [0|1] "NoUnit" GW_FD4,CDCS,CDCS_OverSea
 SG_ ADCS1_GuidOvlDispSts : 2|2@0+ (1,0) [0|3] "NoUnit" GW_FD4,CDCS,CDCS_OverSea
 SG_ ADCS1_MOD_WorkSts : 3|1@0+ (1,0) [0|1] "NoUnit" GW_FD4,CDCS,CDCS_OverSea
 SG_ ADCS1_MOD_AlarmSts : 4|1@0+ (1,0) [0|1] "NoUnit" GW_FD4,CDCS,CDCS_OverSea
 SG_ ADCS1_CarMdlTrsprcySts : 6|2@0+ (1,0) [0|3] "NoUnit" GW_FD4,CDCS,CDCS_OverSea
 SG_ ADCS1_AutoViewChgFuncSts : 7|1@0+ (1,0) [0|1] "NoUnit" GW_FD4,CDCS,CDCS_OverSea
 SG_ ADCS1_SigViewIndcn : 9|2@0+ (1,0) [0|3] "NoUnit" GW_FD4,CDCS,CDCS_OverSea
 SG_ ADCS1_AutoAVMSwtSet_Sts : 10|1@0+ (1,0) [0|1] "NoUnit" GW_FD4,CDCS,CDCS_OverSea

BO_ 984 ADCS_BDCS_Resp_3D8: 8 ADCU_FD3
 SG_ ADCS_Resp_EncrData0 : 7|8@0+ (1,0) [0|255] "NoUnit" GW_FD2,BDCS
 SG_ ADCS_Resp_EncrData1 : 15|8@0+ (1,0) [0|255] "NoUnit" GW_FD2,BDCS
 SG_ ADCS_Resp_EncrData2 : 23|8@0+ (1,0) [0|255] "NoUnit" GW_FD2,BDCS
 SG_ ADCS_Resp_EncrData3 : 31|8@0+ (1,0) [0|255] "NoUnit" GW_FD2,BDCS
 SG_ ADCS_Resp_EncrData4 : 39|8@0+ (1,0) [0|255] "NoUnit" GW_FD2,BDCS
 SG_ ADCS_Resp_EncrData5 : 47|8@0+ (1,0) [0|255] "NoUnit" GW_FD2,BDCS
 SG_ ADCS_Resp_EncrData6 : 55|8@0+ (1,0) [0|255] "NoUnit" GW_FD2,BDCS
 SG_ ADCS_Resp_EncrData7 : 63|8@0+ (1,0) [0|255] "NoUnit" GW_FD2,BDCS

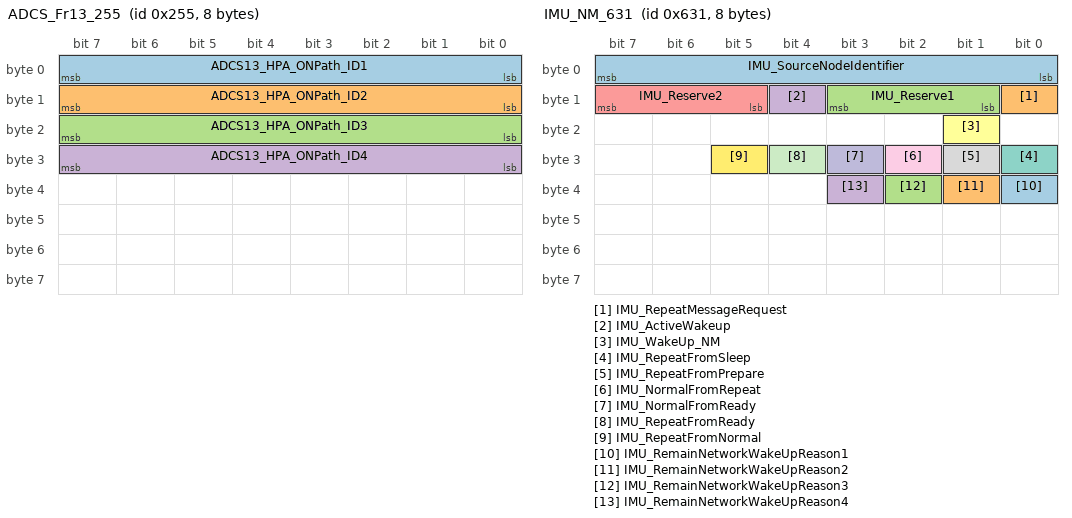
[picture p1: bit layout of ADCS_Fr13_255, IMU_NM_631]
BO_ 597 ADCS_Fr13_255: 8 ADCS_FD3
 SG_ ADCS13_HPA_ONPath_ID1 : 7|8@0+ (1,0) [0|255] "NoUnit" GW_FD4,CDCS,CDCS_OverSea
 SG_ ADCS13_HPA_ONPath_ID2 : 15|8@0+ (1,0) [0|255] "NoUnit" GW_FD4,CDCS,CDCS_OverSea
 SG_ ADCS13_HPA_ONPath_ID3 : 23|8@0+ (1,0) [0|255] "NoUnit" GW_FD4,CDCS,CDCS_OverSea
 SG_ ADCS13_HPA_ONPath_ID4 : 31|8@0+ (1,0) [0|255] "NoUnit" GW_FD4,CDCS,CDCS_OverSea

BO_ 842 FLC_Fr01_34A: 64 FLC_ME_FD6
 SG_ FLC_RlvTgt01_heading : 7|8@0+ (2,-180) [0|180] "°" GW_FD4,CDCS_OverSea
 SG_ FLC_SRObject_RlvTgt01Detn : 12|2@0+ (1,0) [0|3] "" GW_FD4,CDCS_OverSea
 SG_ FLC_SRObject_RlvTgt01Typ : 15|3@0+ (1,0) [0|7] "" GW_FD4,CDCS_OverSea
 SG_ FLC_SRObject_RlvTgt01Dx : 8|9@0+ (0.5,0) [0|255] "m" GW_FD4,CDCS_OverSea
 SG_ FLC_RlvTgt02_heading : 31|8@0+ (2,-180) [0|180] "°" GW_FD4,CDCS_OverSea
 SG_ FLC_SRObject_RlvTgt01Dy : 39|8@0+ (0.1,-12.8) [-12.8|12.7] "m" GW_FD4,CDCS_OverSea
 SG_ FLC_SRObject_LeTgt02Typ : 47|3@0+ (1,0) [0|7] "" GW_FD4,CDCS_OverSea
 SG_ FLC_SRObject_RlvTgt02Detn : 44|2@0+ (1,0) [0|3] "" GW_FD4,CDCS_OverSea
 SG_ FLC_SRObject_RlvTgt02Dx : 40|9@0+ (0.5,0) [0|255] "m" GW_FD4,CDCS_OverSea
 SG_ FLC_RiTgt01_heading : 63|8@0+ (2,-180) [0|180] "°" GW_FD4,CDCS_OverSea
 SG_ FLC_SRObject_RlvTgt02Dy : 71|8@0+ (0.1,-12.8) [-12.8|12.7] "m" GW_FD4,CDCS_OverSea
 SG_ FLC_SRObject_RlvTgt02Typ : 79|3@0+ (1,0) [0|7] "" GW_FD4,CDCS_OverSea
 SG_ FLC_SRObject_RiTgt01Detn : 76|2@0+ (1,0) [0|3] "" GW_FD4,CDCS_OverSea
 SG_ FLC_SRObject_RiTgt01Dx : 72|9@0+ (0.5,0) [0|255] "m" GW_FD4,CDCS_OverSea
 SG_ FLC_RiTgt02_heading : 95|8@0+ (2,-180) [0|180] "°" GW_FD4,CDCS_OverSea
 SG_ FLC_SRObject_RiTgt01Dy : 103|8@0+ (0.1,-12.8) [-12.8|12.7] "m" GW_FD4,CDCS_OverSea
 SG_ FLC_SRObject_RiTgt01Typ : 111|3@0+ (1,0) [0|7] "" GW_FD4,CDCS_OverSea
 SG_ FLC_SRObject_RiTgt02Detn : 108|2@0+ (1,0) [0|3] "" GW_FD4,CDCS_OverSea
 SG_ FLC_SRObject_RiTgt02Dx : 104|9@0+ (0.5,0) [0|255] "m" GW_FD4,CDCS_OverSea
 SG_ FLC_LeTgt01_heading : 127|8@0+ (2,-180) [0|180] "°" GW_FD4,CDCS_OverSea
 SG_ FLC_SRObject_RiTgt02Dy : 135|8@0+ (0.1,-12.8) [-12.8|12.7] "m" GW_FD4,CDCS_OverSea
 SG_ FLC_SRObject_RiTgt02Typ : 143|3@0+ (1,0) [0|7] "" GW_FD4,CDCS_OverSea
 SG_ FLC_SRObject_LeTgt01Detn : 140|2@0+ (1,0) [0|3] "" GW_FD4,CDCS_OverSea
 SG_ FLC_SRObject_LeTgt01Dx : 136|9@0+ (0.5,0) [0|255] "m" GW_FD4,CDCS_OverSea
 SG_ FLC_LeTgt02_heading : 159|8@0+ (2,-180) [0|180] "°" GW_FD4,CDCS_OverSea
 SG_ FLC_SRObject_LeTgt01Dy : 167|8@0+ (0.1,-12.8) [-12.8|12.7] "m" GW_FD4,CDCS_OverSea
 SG_ FLC_SRObject_LeTgt01Typ : 175|3@0+ (1,0) [0|7] "" GW_FD4,CDCS_OverSea
 SG_ FLC_SRObject_LeTgt02Detn : 172|2@0+ (1,0) [0|3] "" GW_FD4,CDCS_OverSea
 SG_ FLC_SRObject_LeTgt02Dx : 168|9@0+ (0.5,0) [0|255] "" GW_FD4,CDCS_OverSea
 SG_ FLC_SRObject_LeTgt02Dy : 191|8@0+ (0.1,-12.8) [-12.8|12.7] "" GW_FD4,CDCS_OverSea

BO_ 843 FLC_Fr02_34B: 64 FLC_ME_FD6
 SG_ FLC_LeftLane_C0 : 7|12@0+ (0.00390625,-8) [-8|7.99609375] "" GW_FD4,CDCS_OverSea
 SG_ FLC_RightLane_C0 : 11|12@0+ (0.00390625,-8) [-8|7.99609375] "" GW_FD4,CDCS_OverSea
 SG_ FLC_NextLeftLane_C0 : 31|12@0+ (0.00390625,-8) [-8|7.99609375] "" GW_FD4,CDCS_OverSea
 SG_ FLC_NextRightLane_C0 : 35|12@0+ (0.00390625,-8) [-8|7.99609375] "" GW_FD4,CDCS_OverSea
 SG_ FLC_NextLeftLane_C1 : 55|12@0+ (5.0E-4,-1) [-1|1] "" GW_FD4,CDCS_OverSea
 SG_ FLC_NextLeftLane_C2 : 59|12@0+ (1.0E-5,-0.02) [-0.02|0.02] "" GW_FD4,CDCS_OverSea
 SG_ FLC_NextLeftLane_C3 : 79|12@0+ (1.0E-7,-0.0002) [-2.0E-4|2.0E-4] "" GW_FD4,CDCS_OverSea
 SG_ FLC_NextRightLane_C1 : 83|12@0+ (5.0E-4,-1) [-1|1] "" GW_FD4,CDCS_OverSea
 SG_ FLC_NextRightLane_C2 : 103|12@0+ (1.0E-5,-0.02) [-0.02|0.02] "" GW_FD4,CDCS_OverSea
 SG_ FLC_NextRightLane_C3 : 107|12@0+ (1.0E-7,-0.0002) [-2.0E-4|2.0E-4] "" GW_FD4,CDCS_OverSea
 SG_ FLC_LeftLane_C1 : 127|12@0+ (5.0E-4,-1) [-1|1] "" GW_FD4,CDCS_OverSea
 SG_ FLC_LeftLane_C2 : 131|12@0+ (1.0E-5,-0.02) [-0.02|0.02] "" GW_FD4,CDCS_OverSea
 SG_ FLC_LeftLane_C3 : 151|12@0+ (1.0E-7,-0.0002) [-2.0E-4|2.0E-4] "" GW_FD4,CDCS_OverSea
 SG_ FLC_RightLane_C1 : 155|12@0+ (5.0E-4,-1) [-1|1] "" GW_FD4,CDCS_OverSea
 SG_ FLC_RightLane_C2 : 175|12@0+ (1.0E-5,-0.02) [-0.02|0.02] "" GW_FD4,CDCS_OverSea
 SG_ FLC_RightLane_C3 : 179|12@0+ (1.0E-7,-0.0002) [-2.0E-4|2.0E-4] "" GW_FD4,CDCS_OverSea
 SG_ FLC_NextRightLane_Type : 198|7@0+ (1,0) [0|127] "" GW_FD4,CDCS_OverSea
 SG_ FLC_NextRightLane_DxStart : 207|11@0+ (0.1,0) [0|200] "m" GW_FD4,CDCS_OverSea
 SG_ FLC_NextRightLane_DxEnd : 218|11@0+ (0.1,0) [0|200] "m" GW_FD4,CDCS_OverSea
 SG_ FLC_RightLane_Type : 238|7@0+ (1,0) [0|127] "" GW_FD4,CDCS_OverSea
 SG_ FLC_RightLane_DxStart : 247|11@0+ (0.1,0) [0|200] "m" GW_FD4,CDCS_OverSea
 SG_ FLC_RightLane_DxEnd : 250|11@0+ (0.1,0) [0|200] "m" GW_FD4,CDCS_OverSea
 SG_ FLC_LeftLane_Type : 270|7@0+ (1,0) [0|127] "" GW_FD4,CDCS_OverSea
 SG_ FLC_LeftLane_DxStart : 279|11@0+ (0.1,0) [0|200] "m" GW_FD4,CDCS_OverSea
 SG_ FLC_LeftLane_DxEnd : 282|11@0+ (0.1,0) [0|200] "m" GW_FD4,CDCS_OverSea
 SG_ FLC_NextLeftLane_Type : 302|7@0+ (1,0) [0|127] "" GW_FD4,CDCS_OverSea
 SG_ FLC_NextLeftLane_DxStart : 311|11@0+ (0.1,0) [0|200] "m" GW_FD4,CDCS_OverSea
 SG_ FLC_NextLeftLane_DxEnd : 314|11@0+ (0.1,0) [0|200] "m" GW_FD4,CDCS_OverSea

BO_ 1543 ADCS_NM_607: 8 ADCS_FD3
 SG_ ADCS_SourceNodeIdentifier : 7|8@0+ (1,0) [0|255] "NoUnit" Vector__XXX
 SG_ ADCS_RepeatMessageRequest : 8|1@0+ (1,0) [0|1] "NoUnit" Vector__XXX
 SG_ ADCS_Reserve1 : 11|3@0+ (1,0) [0|3] "NoUnit" Vector__XXX
 SG_ ADCS_ActiveWakeup : 12|1@0+ (1,0) [0|1] "NoUnit" Vector__XXX
 SG_ ADCS_Reserve2 : 15|3@0+ (1,0) [0|7] "NoUnit" Vector__XXX
 SG_ ADCS_WakeUp_KL15 : 16|1@0+ (1,0) [0|1] "NoUnit" Vector__XXX
 SG_ ADCS_WakeUp_NM : 17|1@0+ (1,0) [0|1] "NoUnit" Vector__XXX
 SG_ ADCS_WakeUp_GM : 18|1@0+ (1,0) [0|1] "NoUnit" Vector__XXX
 SG_ ADCS_WakeUpReason4 : 19|1@0+ (1,0) [0|1] "NoUnit" Vector__XXX
 SG_ ADCS_WakeUpReason5 : 20|1@0+ (1,0) [0|1] "NoUnit" Vector__XXX
 SG_ ADCS_WakeUpReason6 : 21|1@0+ (1,0) [0|1] "NoUnit" Vector__XXX
 SG_ ADCS_WakeUpReason7 : 22|1@0+ (1,0) [0|1] "NoUnit" Vector__XXX
 SG_ ADCS_WakeUpReason8 : 23|1@0+ (1,0) [0|1] "NoUnit" Vector__XXX
 SG_ ADCS_RepeatFromSleep : 24|1@0+ (1,0) [0|1] "NoUnit" Vector__XXX
 SG_ ADCS_RepeatFromPrepare : 25|1@0+ (1,0) [0|1] "NoUnit" Vector__XXX
 SG_ ADCS_NormalFromRepeat : 26|1@0+ (1,0) [0|1] "NoUnit" Vector__XXX
 SG_ ADCS_NormalFromReady : 27|1@0+ (1,0) [0|1] "NoUnit" Vector__XXX
 SG_ ADCS_RepeatFromReady : 28|1@0+ (1,0) [0|1] "NoUnit" Vector__XXX
 SG_ ADCS_RepeatFromNormal : 29|1@0+ (1,0) [0|1] "NoUnit" Vector__XXX
 SG_ ADCS_RNM_DOW : 32|1@0+ (1,0) [0|1] "NoUnit" Vector__XXX
 SG_ ADCS_RNM_GM : 33|1@0+ (1,0) [0|1] "NoUnit" Vector__XXX
 SG_ ADCS_RNM_ICS : 34|1@0+ (1,0) [0|1] "NoUnit" Vector__XXX
 SG_ ADCS_RNM_RPA : 35|1@0+ (1,0) [0|1] "NoUnit" Vector__XXX
 SG_ ADCS_RNM_ISM : 36|1@0+ (1,0) [0|1] "NoUnit" Vector__XXX

BO_ 1557 ADCU_NM_615: 8 ADCU_FD3
 SG_ ADCU_SourceNodeIdentifier : 7|8@0+ (1,0) [0|255] "NoUnit" Vector__XXX
 SG_ ADCU_RepeatMessageRequest : 8|1@0+ (1,0) [0|1] "NoUnit" Vector__XXX
 SG_ ADCU_Reserve1 : 11|3@0+ (1,0) [0|3] "NoUnit" Vector__XXX
 SG_ ADCU_ActiveWakeup : 12|1@0+ (1,0) [0|1] "NoUnit" Vector__XXX
 SG_ ADCU_Reserve2 : 15|3@0+ (1,0) [0|7] "NoUnit" Vector__XXX
 SG_ ADCU_WakeUp_KL15 : 16|1@0+ (1,0) [0|1] "NoUnit" Vector__XXX
 SG_ ADCU_WakeUp_NM : 17|1@0+ (1,0) [0|1] "NoUnit" Vector__XXX
 SG_ ADCU_WakeUp_GM : 18|1@0+ (1,0) [0|1] "NoUnit" Vector__XXX
 SG_ ADCU_WakeUpReason4 : 19|1@0+ (1,0) [0|1] "NoUnit" Vector__XXX
 SG_ ADCU_WakeUpReason5 : 20|1@0+ (1,0) [0|1] "NoUnit" Vector__XXX
 SG_ ADCU_WakeUpReason6 : 21|1@0+ (1,0) [0|1] "NoUnit" Vector__XXX
 SG_ ADCU_WakeUpReason7 : 22|1@0+ (1,0) [0|1] "NoUnit" Vector__XXX
 SG_ ADCU_WakeUpReason8 : 23|1@0+ (1,0) [0|1] "NoUnit" Vector__XXX
 SG_ ADCU_RepeatFromSleep : 24|1@0+ (1,0) [0|1] "NoUnit" Vector__XXX
 SG_ ADCU_RepeatFromPrepare : 25|1@0+ (1,0) [0|1] "NoUnit" Vector__XXX
 SG_ ADCU_NormalFromRepeat : 26|1@0+ (1,0) [0|1] "NoUnit" Vector__XXX
 SG_ ADCU_NormalFromReady : 27|1@0+ (1,0) [0|1] "NoUnit" Vector__XXX
 SG_ ADCU_RepeatFromReady : 28|1@0+ (1,0) [0|1] "NoUnit" Vector__XXX
 SG_ ADCU_RepeatFromNormal : 29|1@0+ (1,0) [0|1] "NoUnit" Vector__XXX
 SG_ ADCU_RNM_GM : 33|1@0+ (1,0) [0|1] "NoUnit" Vector__XXX
 SG_ ADCU_RNM_ICS : 34|1@0+ (1,0) [0|1] "NoUnit" Vector__XXX
 SG_ ADCU_RNM_RPA : 35|1@0+ (1,0) [0|1] "NoUnit" Vector__XXX
 SG_ ADCU_RNM_ISM : 36|1@0+ (1,0) [0|1] "NoUnit" Vector__XXX

BO_ 1556 FLC_NM_614: 8 FLC_ME_FD3
 SG_ FLC_SourceNodeIdentifier : 7|8@0+ (1,0) [0|255] "NoUnit" Vector__XXX
 SG_ FLC_RepeatMessageRequest : 8|1@0+ (1,0) [0|1] "NoUnit" Vector__XXX
 SG_ FLC_Reserve1 : 11|3@0+ (1,0) [0|3] "NoUnit" Vector__XXX
 SG_ FLC_ActiveWakeup : 12|1@0+ (1,0) [0|1] "NoUnit" Vector__XXX
 SG_ FLC_Reserve2 : 15|3@0+ (1,0) [0|7] "NoUnit" Vector__XXX
 SG_ FLC_WakeUp_KL15 : 16|1@0+ (1,0) [0|1] "NoUnit" Vector__XXX
 SG_ FLC_WakeUp_NM : 17|1@0+ (1,0) [0|1] "NoUnit" Vector__XXX
 SG_ FLC_WakeUpReason4 : 19|1@0+ (1,0) [0|1] "NoUnit" Vector__XXX
 SG_ FLC_WakeUpReason5 : 20|1@0+ (1,0) [0|1] "NoUnit" Vector__XXX
 SG_ FLC_WakeUpReason6 : 21|1@0+ (1,0) [0|1] "NoUnit" Vector__XXX
 SG_ FLC_WakeUpReason7 : 22|1@0+ (1,0) [0|1] "NoUnit" Vector__XXX
 SG_ FLC_WakeUpReason8 : 23|1@0+ (1,0) [0|1] "NoUnit" Vector__XXX
 SG_ FLC_RepeatFromSleep : 24|1@0+ (1,0) [0|1] "NoUnit" Vector__XXX
 SG_ FLC_RepeatFromPrepare : 25|1@0+ (1,0) [0|1] "NoUnit" Vector__XXX
 SG_ FLC_NormalFromRepeat : 26|1@0+ (1,0) [0|1] "NoUnit" Vector__XXX
 SG_ FLC_NormalFromReady : 27|1@0+ (1,0) [0|1] "NoUnit" Vector__XXX
 SG_ FLC_RepeatFromReady : 28|1@0+ (1,0) [0|1] "NoUnit" Vector__XXX
 SG_ FLC_RepeatFromNormal : 29|1@0+ (1,0) [0|1] "NoUnit" Vector__XXX
 SG_ FLC_RNM_DOW : 32|1@0+ (1,0) [0|1] "NoUnit" Vector__XXX

BO_ 615 IMU_HCFDINSPVAT2B: 32 IMU
 SG_ INS_GpsWeek : 7|16@0+ (1,0) [0|65535] "week" PDCS_FD1,GW_FD1,PDCS_HVM_FD1
 SG_ INS_GpsTime : 23|32@0+ (0.001,0) [0|604800] "s" PDCS_FD1,GW_FD1,PDCS_HVM_FD1
 SG_ INS_E2eCounter : 51|4@0+ (1,0) [0|15] "" PDCS_FD1,GW_FD1,PDCS_HVM_FD1
 SG_ INS_Received : 55|4@0+ (1,0) [0|15] "" PDCS_FD1,GW_FD1,PDCS_HVM_FD1
 SG_ INS_E2eCRC : 63|8@0+ (1,0) [0|255] "" PDCS_FD1,GW_FD1,PDCS_HVM_FD1
 SG_ INS_VelE : 71|16@0- (0.005,0) [-150|150] "m/s" PDCS_FD1,GW_FD1,PDCS_HVM_FD1
 SG_ INS_VelN : 87|16@0- (0.005,0) [-150|150] "m/s" PDCS_FD1,GW_FD1,PDCS_HVM_FD1
 SG_ INS_VelU : 103|16@0- (0.005,0) [-150|150] "m/s" PDCS_FD1,GW_FD1,PDCS_HVM_FD1
 SG_ INS_Pitch : 119|16@0- (0.01,0) [-90|90] "deg" PDCS_FD1,GW_FD1,PDCS_HVM_FD1
 SG_ INS_Roll : 135|16@0- (0.01,0) [-180|180] "deg" PDCS_FD1,GW_FD1,PDCS_HVM_FD1
 SG_ INS_Yaw : 151|16@0- (0.01,0) [-180|180] "deg" PDCS_FD1,GW_FD1,PDCS_HVM_FD1
 SG_ INS_StdVelE : 167|12@0+ (0.01,0) [0|40] "m/s" PDCS_FD1,GW_FD1,PDCS_HVM_FD1
 SG_ INS_StdVelN : 171|12@0+ (0.01,0) [0|40] "m/s" PDCS_FD1,GW_FD1,PDCS_HVM_FD1
 SG_ INS_StdVelU : 191|12@0+ (0.01,0) [0|40] "m/s" PDCS_FD1,GW_FD1,PDCS_HVM_FD1
 SG_ INS_StdPitch : 195|12@0+ (0.01,0) [0|40] "deg" PDCS_FD1,GW_FD1,PDCS_HVM_FD1
 SG_ INS_StdRoll : 215|12@0+ (0.01,0) [0|40] "deg" PDCS_FD1,GW_FD1,PDCS_HVM_FD1
 SG_ INS_StdYaw : 219|12@0+ (0.01,0) [0|40] "deg" PDCS_FD1,GW_FD1,PDCS_HVM_FD1
 SG_ INS_StatIns : 235|2@0+ (1,0) [0|3] "" PDCS_FD1,GW_FD1,PDCS_HVM_FD1
 SG_ INS_StatPos : 239|4@0+ (1,0) [0|15] "" PDCS_FD1,GW_FD1,PDCS_HVM_FD1

BO_ 772 IMU_GGA_Fr01_304: 64 IMU
 SG_ IMU_GPGGA_size : 7|8@0+ (1,0) [0|60] "NoUnit" TBOX,GW_FD5,TBOX_OverSea
 SG_ IMU_GPGGA_num_total : 15|8@0+ (1,0) [0|255] "NoUnit" TBOX,GW_FD5,TBOX_OverSea
 SG_ IMU_GPGGA_num : 23|8@0+ (1,0) [0|255] "NoUnit" TBOX,GW_FD5,TBOX_OverSea
 SG_ IMU_GPGGA_Reserved : 31|8@0+ (1,0) [0|255] "NoUnit" TBOX,GW_FD5,TBOX_OverSea
 SG_ IMU_GPGGA_data : 39|480@0+ (1,0) [0|0] "NoUnit" TBOX,GW_FD5,TBOX_OverSea

BO_ 1376 IMU_HCFDSUMMARY: 64 IMU
 SG_ calibration_progress : 7|8@0+ (1,0) [0|100] "%" GW_FD4,CDCS,CDCS_OverSea
 SG_ satellite_used_num : 15|8@0+ (1,0) [0|255] "" GW_FD4,CDCS,CDCS_OverSea
 SG_ stat_pos : 19|4@0+ (1,0) [0|15] "" GW_FD4,CDCS,CDCS_OverSea
 SG_ stat_ins : 21|2@0+ (1,0) [0|3] "" GW_FD4,CDCS,CDCS_OverSea
 SG_ antenes_status : 23|2@0+ (1,0) [0|3] "" GW_FD4,CDCS,CDCS_OverSea
 SG_ diff_Age : 31|16@0+ (0.1,0) [0|6553.5] "s" GW_FD4,CDCS,CDCS_OverSea
 SG_ BD_CN_L1 : 47|6@0+ (1,0) [0|63] "" GW_FD4,CDCS,CDCS_OverSea
 SG_ BD_CN_L5 : 41|6@0+ (1,0) [0|63] "" GW_FD4,CDCS,CDCS_OverSea
 SG_ GAL_CN_L5 : 61|6@0+ (1,0) [0|63] "" GW_FD4,CDCS,CDCS_OverSea
 SG_ GAL_CN_L1 : 51|6@0+ (1,0) [0|63] "" GW_FD4,CDCS,CDCS_OverSea
 SG_ GPS_CN_L1 : 71|6@0+ (1,0) [0|63] "" GW_FD4,CDCS,CDCS_OverSea
 SG_ CalibrationFailReason : 75|4@0+ (1,0) [0|15] "" GW_FD4,CDCS,CDCS_OverSea
 SG_ GPS_CN_L5 : 65|6@0+ (1,0) [0|63] "" GW_FD4,CDCS,CDCS_OverSea
 SG_ satellite_visible_num : 87|8@0+ (1,0) [0|255] "" GW_FD4,CDCS,CDCS_OverSea
 SG_ differential_status : 88|1@0+ (1,0) [0|1] "" GW_FD4,CDCS,CDCS_OverSea
 SG_ Base1005_lost : 89|1@0+ (1,0) [0|1] "" GW_FD4,CDCS,CDCS_OverSea
 SG_ Base1005_CoordinatesWrong : 90|1@0+ (1,0) [0|1] "" GW_FD4,CDCS,CDCS_OverSea

BO_ 1585 IMU_NM_631: 8 IMU
 SG_ IMU_SourceNodeIdentifier : 7|8@0+ (1,0) [0|255] "NoUnit" Vector__XXX
 SG_ IMU_RepeatMessageRequest : 8|1@0+ (1,0) [0|1] "" Vector__XXX
 SG_ IMU_Reserve1 : 11|3@0+ (1,0) [0|3] "" Vector__XXX
 SG_ IMU_ActiveWakeup : 12|1@0+ (1,0) [0|1] "" Vector__XXX
 SG_ IMU_Reserve2 : 15|3@0+ (1,0) [0|7] "" Vector__XXX
 SG_ IMU_WakeUp_NM : 17|1@0+ (1,0) [0|1] "" Vector__XXX
 SG_ IMU_RepeatFromSleep : 24|1@0+ (1,0) [0|1] "" Vector__XXX
 SG_ IMU_RepeatFromPrepare : 25|1@0+ (1,0) [0|1] "" Vector__XXX
 SG_ IMU_NormalFromRepeat : 26|1@0+ (1,0) [0|1] "" Vector__XXX
 SG_ IMU_NormalFromReady : 27|1@0+ (1,0) [0|1] "" Vector__XXX
 SG_ IMU_RepeatFromReady : 28|1@0+ (1,0) [0|1] "" Vector__XXX
 SG_ IMU_RepeatFromNormal : 29|1@0+ (1,0) [0|1] "" Vector__XXX
 SG_ IMU_RemainNetworkWakeUpReason1 : 32|1@0+ (1,0) [0|1] "" Vector__XXX
 SG_ IMU_RemainNetworkWakeUpReason2 : 33|1@0+ (1,0) [0|1] "" Vector__XXX
 SG_ IMU_RemainNetworkWakeUpReason3 : 34|1@0+ (1,0) [0|1] "" Vector__XXX
 SG_ IMU_RemainNetworkWakeUpReason4 : 35|1@0+ (1,0) [0|1] "" Vector__XXX

BO_ 824 SRR3_FR01_338: 16 SRR3
 SG_ SRR_BsdSetFd : 10|1@0+ (1,0) [0|1] "" FLC_ME_FD6,GW_FD4,CDCS,CDCS_OverSea
 SG_ SRR_BSD_warningReqRight : 12|2@0+ (1,0) [0|3] "" FLC_ME_FD6,GW_FD4,CDCS,CDCS_OverSea
 SG_ SRR_BSD_warningReqLeft : 14|2@0+ (1,0) [0|3] "" FLC_ME_FD6,GW_FD4,CDCS,CDCS_OverSea
 SG_ SRR_RL_Fault : 17|2@0+ (1,0) [0|3] "" FLC_ME_FD6,GW_FD4,CDCS,CDCS_OverSea
 SG_ SRR_RR_Fault : 19|2@0+ (1,0) [0|3] "" FLC_ME_FD6,GW_FD4,CDCS,CDCS_OverSea
 SG_ SRR_BSD_VoiceActive_St : 22|3@0+ (1,0) [0|7] "" FLC_ME_FD6,GW_FD4,CDCS,CDCS_OverSea
 SG_ SRR_BSD_SysSts : 9|3@0+ (1,0) [0|7] "" FLC_ME_FD6,GW_FD4,CDCS,CDCS_OverSea
 SG_ SRR_DOW_OnOff_fbk : 32|1@0+ (1,0) [0|1] "" FLC_ME_FD6,GW_FD4,CDCS,CDCS_OverSea
 SG_ SRR_DOW_St : 36|4@0+ (1,0) [0|15] "" FLC_ME_FD6,GW_FD4,CDCS,CDCS_OverSea
 SG_ SRR_DOW_FL_Warn_St : 38|2@0+ (1,0) [0|3] "" FLC_ME_FD6,GW_FD4,CDCS,CDCS_OverSea
 SG_ SRR_DOW_RL_Warn_St : 41|2@0+ (1,0) [0|3] "" FLC_ME_FD6,GW_FD4,CDCS,CDCS_OverSea
 SG_ SRR_DOW_FR_Warn_St : 43|2@0+ (1,0) [0|3] "" FLC_ME_FD6,GW_FD4,CDCS,CDCS_OverSea
 SG_ SRR_DOW_RR_Warn_St : 45|2@0+ (1,0) [0|3] "" FLC_ME_FD6,GW_FD4,CDCS,CDCS_OverSea
 SG_ SRR_FCTA_OnOff_fbk : 46|1@0+ (1,0) [0|1] "" FLC_ME_FD6,GW_FD4,CDCS,CDCS_OverSea
 SG_ SRR_RCTA_Left_VoiceActive_St : 50|3@0+ (1,0) [0|7] "" FLC_ME_FD6,GW_FD4,CDCS,CDCS_OverSea
 SG_ SRR_FCTA_Left_Active_St : 53|3@0+ (1,0) [0|7] "" FLC_ME_FD6,GW_FD4,CDCS,CDCS_OverSea
 SG_ SRR_FCTA_Right_Active_St : 58|3@0+ (1,0) [0|7] "" FLC_ME_FD6,GW_FD4,CDCS,CDCS_OverSea
 SG_ SRR_FCTA_St : 63|4@0+ (1,0) [0|15] "" FLC_ME_FD6,GW_FD4,CDCS,CDCS_OverSea
 SG_ SRR_DOW_VoiceActive_St : 66|3@0+ (1,0) [0|7] "" FLC_ME_FD6,GW_FD4,CDCS,CDCS_OverSea
 SG_ SRR_RCTA_OnOff_fbk : 67|1@0+ (1,0) [0|1] "" FLC_ME_FD6,GW_FD4,CDCS,CDCS_OverSea
 SG_ SRR_RCTA_St : 71|4@0+ (1,0) [0|15] "" FLC_ME_FD6,GW_FD4,CDCS,CDCS_OverSea
 SG_ SRR_RCTA_Left_Active_St : 74|3@0+ (1,0) [0|7] "" FLC_ME_FD6,GW_FD4,CDCS,CDCS_OverSea
 SG_ SRR_RCTA_Right_Active_St : 77|3@0+ (1,0) [0|7] "" FLC_ME_FD6,GW_FD4,CDCS,CDCS_OverSea
 SG_ SRR_RCW_St : 99|4@0+ (1,0) [0|15] "" FLC_ME_FD6,GW_FD4,CDCS,CDCS_OverSea
 SG_ SRR_RCW_OnOff_fbk : 104|1@0+ (1,0) [0|1] "" FLC_ME_FD6,GW_FD4,CDCS,CDCS_OverSea
 SG_ SRR_RCTA_Right_VoiceActive_St : 107|3@0+ (1,0) [0|7] "" FLC_ME_FD6,GW_FD4,CDCS,CDCS_OverSea
 SG_ SRR_RCW_Warn_St : 109|2@0+ (1,0) [0|3] "" FLC_ME_FD6,GW_FD4,CDCS,CDCS_OverSea

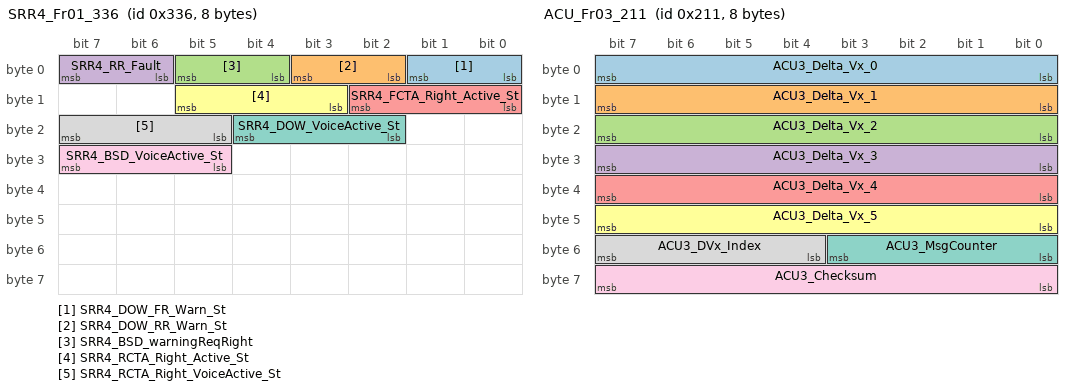
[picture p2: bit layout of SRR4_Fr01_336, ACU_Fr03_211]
BO_ 822 SRR4_Fr01_336: 8 SRR4
 SG_ SRR4_DOW_FR_Warn_St : 1|2@0+ (1,0) [0|3] "" FLC_ME_FD6,SRR3
 SG_ SRR4_DOW_RR_Warn_St : 3|2@0+ (1,0) [0|3] "" FLC_ME_FD6,SRR3
 SG_ SRR4_BSD_warningReqRight : 5|2@0+ (1,0) [0|3] "" FLC_ME_FD6,SRR3
 SG_ SRR4_RR_Fault : 7|2@0+ (1,0) [0|3] "" FLC_ME_FD6,SRR3
 SG_ SRR4_FCTA_Right_Active_St : 10|3@0+ (1,0) [0|7] "" FLC_ME_FD6,SRR3
 SG_ SRR4_RCTA_Right_Active_St : 13|3@0+ (1,0) [0|7] "" FLC_ME_FD6,SRR3
 SG_ SRR4_DOW_VoiceActive_St : 20|3@0+ (1,0) [0|7] "" FLC_ME_FD6,SRR3
 SG_ SRR4_RCTA_Right_VoiceActive_St : 23|3@0+ (1,0) [0|7] "" FLC_ME_FD6,SRR3
 SG_ SRR4_BSD_VoiceActive_St : 31|3@0+ (1,0) [0|7] "" FLC_ME_FD6,SRR3

BO_ 825 SRR_RL_First_Frame: 64 SRR3
 SG_ SRR_RL_TargetTI_Status : 7|8@0+ (1,0) [0|255] "" FLC_ME_FD6
 SG_ SRR_RL_OBJTi_Stamp : 15|32@0+ (0.1,0) [0|4.294967295E8] "ms" FLC_ME_FD6
 SG_ SRR_RL_Delay_Time : 47|32@0+ (0.1,0) [0|4.294967295E8] "ms" FLC_ME_FD6
 SG_ SRR_RL_NrObj : 79|8@0+ (1,0) [0|255] "" FLC_ME_FD6
 SG_ SRR_RLRadar_Status : 87|4@0+ (1,0) [0|15] "" FLC_ME_FD6
 SG_ SRR_RL_MsgCounter : 491|4@0+ (1,0) [0|15] "" FLC_ME_FD6
 SG_ SRR_RL_CRC16Checksum : 503|16@0+ (1,0) [0|65535] "" FLC_ME_FD6

BO_ 826 SRR_RL_SGUObjPos_1: 64 SRR3
 SG_ SRR_RL_ObjID_1 : 7|8@0+ (1,0) [0|255] "" FLC_ME_FD6
 SG_ SRR_RL_ObjConf_1 : 15|6@0+ (0.015625,0) [0|0.984375] "" FLC_ME_FD6
 SG_ SRR_RL_ObjSNR_1 : 9|11@0+ (0.0625,0) [0|40] "dB" FLC_ME_FD6
 SG_ SRR_RL_ObjDistX_1 : 30|12@0+ (0.0625,-128) [-128|127] "m" FLC_ME_FD6
 SG_ SRR_RL_ObjRelVelX_1 : 34|12@0+ (0.0625,-128) [-128|127] "m/s" FLC_ME_FD6
 SG_ SRR_RL_ObjDistY_1 : 54|14@0+ (0.015625,-128) [-128|127] "m" FLC_ME_FD6
 SG_ SRR_RL_ObjRelVelY_1 : 56|12@0+ (0.0625,-128) [-128|127] "m/s" FLC_ME_FD6
 SG_ SRR_RL_ObjAccelX_1 : 76|12@0+ (0.03125,-16) [-16|15] "m/s2" FLC_ME_FD6
 SG_ SRR_RL_ObjAccelY_1 : 80|12@0+ (0.03125,-16) [-16|15] "m/s2" FLC_ME_FD6
 SG_ SRR_RL_ObjHeading_1 : 100|12@0+ (0.1,-180) [-180|180] "Deg" FLC_ME_FD6
 SG_ SRR_RL_ObjBoxCenterLgt_1 : 104|9@0+ (0.1,-25) [-25|25] "m" FLC_ME_FD6
 SG_ SRR_RL_ObjBoxCenterLat_1 : 127|9@0+ (0.1,-25) [-25|25] "m" FLC_ME_FD6
 SG_ SRR_RL_ObjBoxLength_1 : 134|9@0+ (0.1,0) [0|50] "m" FLC_ME_FD6
 SG_ SRR_RL_ObjBoxWidth_1 : 141|9@0+ (0.1,0) [0|50] "m" FLC_ME_FD6
 SG_ SRR_RL_ObjDyStdDe_1 : 148|8@0+ (0.05,0) [0|12.7] "m" FLC_ME_FD6
 SG_ SRR_RL_ObjDxStdDe_1 : 156|8@0+ (0.05,0) [0|12.7] "m" FLC_ME_FD6
 SG_ SRR_RL_ObjVyStdDe_1 : 174|6@0+ (0.05,0) [0|2] "m/s" FLC_ME_FD6
 SG_ SRR_RL_ObjVxStdDe_1 : 164|6@0+ (0.05,0) [0|2] "m/s" FLC_ME_FD6
 SG_ SRR_RL_ObjMtnPat_1 : 180|3@0+ (1,0) [0|7] "" FLC_ME_FD6
 SG_ SRR_RL_ObjTyp_1 : 183|3@0+ (1,0) [0|7] "" FLC_ME_FD6
 SG_ SRR_RL_ObjID_2 : 191|8@0+ (1,0) [0|255] "" FLC_ME_FD6
 SG_ SRR_RL_ObjConf_2 : 199|6@0+ (0.015625,0) [0|0.984375] "" FLC_ME_FD6
 SG_ SRR_RL_ObjSNR_2 : 193|11@0+ (0.0625,0) [0|40] "dB" FLC_ME_FD6
 SG_ SRR_RL_ObjDistX_2 : 214|12@0+ (0.0625,-128) [-128|127] "m" FLC_ME_FD6
 SG_ SRR_RL_ObjRelVelX_2 : 218|12@0+ (0.0625,-128) [-128|127] "m/s" FLC_ME_FD6
 SG_ SRR_RL_ObjDistY_2 : 238|14@0+ (0.015625,-128) [-128|127] "m" FLC_ME_FD6
 SG_ SRR_RL_ObjRelVelY_2 : 240|12@0+ (0.0625,-128) [-128|127] "m/s" FLC_ME_FD6
 SG_ SRR_RL_ObjAccelX_2 : 260|12@0+ (0.03125,-16) [-16|15] "m/s2" FLC_ME_FD6
 SG_ SRR_RL_ObjAccelY_2 : 264|12@0+ (0.03125,-16) [-16|15] "m/s2" FLC_ME_FD6
 SG_ SRR_RL_ObjHeading_2 : 284|12@0+ (0.1,-180) [-180|180] "Deg" FLC_ME_FD6
 SG_ SRR_RL_ObjBoxCenterLgt_2 : 288|9@0+ (0.1,-25) [-25|25] "m" FLC_ME_FD6
 SG_ SRR_RL_ObjBoxCenterLat_2 : 311|9@0+ (0.1,-25) [-25|25] "m" FLC_ME_FD6
 SG_ SRR_RL_ObjBoxLength_2 : 318|9@0+ (0.1,0) [0|50] "m" FLC_ME_FD6
 SG_ SRR_RL_ObjBoxWidth_2 : 325|9@0+ (0.1,0) [0|50] "m" FLC_ME_FD6
 SG_ SRR_RL_ObjDyStdDe_2 : 332|8@0+ (0.05,0) [0|12.7] "m" FLC_ME_FD6
 SG_ SRR_RL_ObjDxStdDe_2 : 340|8@0+ (0.05,0) [0|12.7] "m" FLC_ME_FD6
 SG_ SRR_RL_ObjVyStdDe_2 : 358|6@0+ (0.05,0) [0|2] "m/s" FLC_ME_FD6
 SG_ SRR_RL_ObjVxStdDe_2 : 348|6@0+ (0.05,0) [0|2] "m/s" FLC_ME_FD6
 SG_ SRR_RL_ObjMtnPat_2 : 364|3@0+ (1,0) [0|7] "" FLC_ME_FD6
 SG_ SRR_RL_ObjTyp_2 : 367|3@0+ (1,0) [0|7] "" FLC_ME_FD6
 SG_ SRR_RLObj1MsgCounter : 491|4@0+ (1,0) [0|15] "" FLC_ME_FD6
 SG_ SRR_RLObj1CRC16Checksum : 503|16@0+ (1,0) [0|65535] "" FLC_ME_FD6

BO_ 827 SRR_RL_SGUObjPos_2: 64 SRR3
 SG_ SRR_RL_ObjID_3 : 7|8@0+ (1,0) [0|255] "" FLC_ME_FD6
 SG_ SRR_RL_ObjConf_3 : 15|6@0+ (0.015625,0) [0|0.984375] "" FLC_ME_FD6
 SG_ SRR_RL_ObjSNR_3 : 9|11@0+ (0.0625,0) [0|40] "dB" FLC_ME_FD6
 SG_ SRR_RL_ObjDistX_3 : 30|12@0+ (0.0625,-128) [-128|127] "m" FLC_ME_FD6
 SG_ SRR_RL_ObjRelVelX_3 : 34|12@0+ (0.0625,-128) [-128|127] "m/s" FLC_ME_FD6
 SG_ SRR_RL_ObjDistY_3 : 54|14@0+ (0.015625,-128) [-128|127] "m" FLC_ME_FD6
 SG_ SRR_RL_ObjRelVelY_3 : 56|12@0+ (0.0625,-128) [-128|127] "m/s" FLC_ME_FD6
 SG_ SRR_RL_ObjAccelX_3 : 76|12@0+ (0.03125,-16) [-16|15] "m/s2" FLC_ME_FD6
 SG_ SRR_RL_ObjAccelY_3 : 80|12@0+ (0.03125,-16) [-16|15] "m/s2" FLC_ME_FD6
 SG_ SRR_RL_ObjHeading_3 : 100|12@0+ (0.1,-180) [-180|180] "Deg" FLC_ME_FD6
 SG_ SRR_RL_ObjBoxCenterLgt_3 : 104|9@0+ (0.1,-25) [-25|25] "m" FLC_ME_FD6
 SG_ SRR_RL_ObjBoxCenterLat_3 : 127|9@0+ (0.1,-25) [-25|25] "m" FLC_ME_FD6
 SG_ SRR_RL_ObjBoxLength_3 : 134|9@0+ (0.1,0) [0|50] "m" FLC_ME_FD6
 SG_ SRR_RL_ObjBoxWidth_3 : 141|9@0+ (0.1,0) [0|50] "m" FLC_ME_FD6
 SG_ SRR_RL_ObjDyStdDe_3 : 148|8@0+ (0.05,0) [0|12.7] "m" FLC_ME_FD6
 SG_ SRR_RL_ObjDxStdDe_3 : 156|8@0+ (0.05,0) [0|12.7] "m" FLC_ME_FD6
 SG_ SRR_RL_ObjVyStdDe_3 : 174|6@0+ (0.05,0) [0|2] "m/s" FLC_ME_FD6
 SG_ SRR_RL_ObjVxStdDe_3 : 164|6@0+ (0.05,0) [0|2] "m/s" FLC_ME_FD6
 SG_ SRR_RL_ObjMtnPat_3 : 180|3@0+ (1,0) [0|7] "" FLC_ME_FD6
 SG_ SRR_RL_ObjTyp_3 : 183|3@0+ (1,0) [0|7] "" FLC_ME_FD6
 SG_ SRR_RL_ObjID_4 : 191|8@0+ (1,0) [0|255] "" FLC_ME_FD6
 SG_ SRR_RL_ObjConf_4 : 199|6@0+ (0.015625,0) [0|0.984375] "" FLC_ME_FD6
 SG_ SRR_RL_ObjSNR_4 : 193|11@0+ (0.0625,0) [0|40] "dB" FLC_ME_FD6
 SG_ SRR_RL_ObjDistX_4 : 214|12@0+ (0.0625,-128) [-128|127] "m" FLC_ME_FD6
 SG_ SRR_RL_ObjRelVelX_4 : 218|12@0+ (0.0625,-128) [-128|127] "m/s" FLC_ME_FD6
 SG_ SRR_RL_ObjDistY_4 : 238|14@0+ (0.015625,-128) [-128|127] "m" FLC_ME_FD6
 SG_ SRR_RL_ObjRelVelY_4 : 240|12@0+ (0.0625,-128) [-128|127] "m/s" FLC_ME_FD6
 SG_ SRR_RL_ObjAccelX_4 : 260|12@0+ (0.03125,-16) [-16|15] "m/s2" FLC_ME_FD6
 SG_ SRR_RL_ObjAccelY_4 : 264|12@0+ (0.03125,-16) [-16|15] "m/s2" FLC_ME_FD6
 SG_ SRR_RL_ObjHeading_4 : 284|12@0+ (0.1,-180) [-180|180] "Deg" FLC_ME_FD6
 SG_ SRR_RL_ObjBoxCenterLgt_4 : 288|9@0+ (0.1,-25) [-25|25] "m" FLC_ME_FD6
 SG_ SRR_RL_ObjBoxCenterLat_4 : 311|9@0+ (0.1,-25) [-25|25] "m" FLC_ME_FD6
 SG_ SRR_RL_ObjBoxLength_4 : 318|9@0+ (0.1,0) [0|50] "m" FLC_ME_FD6
 SG_ SRR_RL_ObjBoxWidth_4 : 325|9@0+ (0.1,0) [0|50] "m" FLC_ME_FD6
 SG_ SRR_RL_ObjDyStdDe_4 : 332|8@0+ (0.05,0) [0|12.7] "m" FLC_ME_FD6
 SG_ SRR_RL_ObjDxStdDe_4 : 340|8@0+ (0.05,0) [0|12.7] "m" FLC_ME_FD6
 SG_ SRR_RL_ObjVyStdDe_4 : 358|6@0+ (0.05,0) [0|2] "m/s" FLC_ME_FD6
 SG_ SRR_RL_ObjVxStdDe_4 : 348|6@0+ (0.05,0) [0|2] "m/s" FLC_ME_FD6
 SG_ SRR_RL_ObjMtnPat_4 : 364|3@0+ (1,0) [0|7] "" FLC_ME_FD6
 SG_ SRR_RL_ObjTyp_4 : 367|3@0+ (1,0) [0|7] "" FLC_ME_FD6
 SG_ SRR_RLObj2MsgCounter : 491|4@0+ (1,0) [0|15] "" FLC_ME_FD6
 SG_ SRR_RLObj2CRC16Checksum : 503|16@0+ (1,0) [0|65535] "" FLC_ME_FD6

BO_ 828 SRR_RL_SGUObjPos_3: 64 SRR3
 SG_ SRR_RL_ObjID_5 : 7|8@0+ (1,0) [0|255] "" FLC_ME_FD6
 SG_ SRR_RL_ObjConf_5 : 15|6@0+ (0.015625,0) [0|0.984375] "" FLC_ME_FD6
 SG_ SRR_RL_ObjSNR_5 : 9|11@0+ (0.0625,0) [0|40] "dB" FLC_ME_FD6
 SG_ SRR_RL_ObjDistX_5 : 30|12@0+ (0.0625,-128) [-128|127] "m" FLC_ME_FD6
 SG_ SRR_RL_ObjRelVelX_5 : 34|12@0+ (0.0625,-128) [-128|127] "m/s" FLC_ME_FD6
 SG_ SRR_RL_ObjDistY_5 : 54|14@0+ (0.015625,-128) [-128|127] "m" FLC_ME_FD6
 SG_ SRR_RL_ObjRelVelY_5 : 56|12@0+ (0.0625,-128) [-128|127] "m/s" FLC_ME_FD6
 SG_ SRR_RL_ObjAccelX_5 : 76|12@0+ (0.03125,-16) [-16|15] "m/s2" FLC_ME_FD6
 SG_ SRR_RL_ObjAccelY_5 : 80|12@0+ (0.03125,-16) [-16|15] "m/s2" FLC_ME_FD6
 SG_ SRR_RL_ObjHeading_5 : 100|12@0+ (0.1,-180) [-180|180] "Deg" FLC_ME_FD6
 SG_ SRR_RL_ObjBoxCenterLgt_5 : 104|9@0+ (0.1,-25) [-25|25] "m" FLC_ME_FD6
 SG_ SRR_RL_ObjBoxCenterLat_5 : 127|9@0+ (0.1,-25) [-25|25] "m" FLC_ME_FD6
 SG_ SRR_RL_ObjBoxLength_5 : 134|9@0+ (0.1,0) [0|50] "m" FLC_ME_FD6
 SG_ SRR_RL_ObjBoxWidth_5 : 141|9@0+ (0.1,0) [0|50] "m" FLC_ME_FD6
 SG_ SRR_RL_ObjDyStdDe_5 : 148|8@0+ (0.05,0) [0|12.7] "m" FLC_ME_FD6
 SG_ SRR_RL_ObjDxStdDe_5 : 156|8@0+ (0.05,0) [0|12.7] "m" FLC_ME_FD6
 SG_ SRR_RL_ObjVyStdDe_5 : 174|6@0+ (0.05,0) [0|2] "m/s" FLC_ME_FD6
 SG_ SRR_RL_ObjVxStdDe_5 : 164|6@0+ (0.05,0) [0|2] "m/s" FLC_ME_FD6
 SG_ SRR_RL_ObjMtnPat_5 : 180|3@0+ (1,0) [0|7] "" FLC_ME_FD6
 SG_ SRR_RL_ObjTyp_5 : 183|3@0+ (1,0) [0|7] "" FLC_ME_FD6
 SG_ SRR_RL_ObjID_6 : 191|8@0+ (1,0) [0|255] "" FLC_ME_FD6
 SG_ SRR_RL_ObjConf_6 : 199|6@0+ (0.015625,0) [0|0.984375] "" FLC_ME_FD6
 SG_ SRR_RL_ObjSNR_6 : 193|11@0+ (0.0625,0) [0|40] "dB" FLC_ME_FD6
 SG_ SRR_RL_ObjDistX_6 : 214|12@0+ (0.0625,-128) [-128|127] "m" FLC_ME_FD6
 SG_ SRR_RL_ObjRelVelX_6 : 218|12@0+ (0.0625,-128) [-128|127] "m/s" FLC_ME_FD6
 SG_ SRR_RL_ObjDistY_6 : 238|14@0+ (0.015625,-128) [-128|127] "m" FLC_ME_FD6
 SG_ SRR_RL_ObjRelVelY_6 : 240|12@0+ (0.0625,-128) [-128|127] "m/s" FLC_ME_FD6
 SG_ SRR_RL_ObjAccelX_6 : 260|12@0+ (0.03125,-16) [-16|15] "m/s2" FLC_ME_FD6
 SG_ SRR_RL_ObjAccelY_6 : 264|12@0+ (0.03125,-16) [-16|15] "m/s2" FLC_ME_FD6
 SG_ SRR_RL_ObjHeading_6 : 284|12@0+ (0.1,-180) [-180|180] "Deg" FLC_ME_FD6
 SG_ SRR_RL_ObjBoxCenterLgt_6 : 288|9@0+ (0.1,-25) [-25|25] "m" FLC_ME_FD6
 SG_ SRR_RL_ObjBoxCenterLat_6 : 311|9@0+ (0.1,-25) [-25|25] "m" FLC_ME_FD6
 SG_ SRR_RL_ObjBoxLength_6 : 318|9@0+ (0.1,0) [0|50] "m" FLC_ME_FD6
 SG_ SRR_RL_ObjBoxWidth_6 : 325|9@0+ (0.1,0) [0|50] "m" FLC_ME_FD6
 SG_ SRR_RL_ObjDyStdDe_6 : 332|8@0+ (0.05,0) [0|12.7] "m" FLC_ME_FD6
 SG_ SRR_RL_ObjDxStdDe_6 : 340|8@0+ (0.05,0) [0|12.7] "m" FLC_ME_FD6
 SG_ SRR_RL_ObjVyStdDe_6 : 358|6@0+ (0.05,0) [0|2] "m/s" FLC_ME_FD6
 SG_ SRR_RL_ObjVxStdDe_6 : 348|6@0+ (0.05,0) [0|2] "m/s" FLC_ME_FD6
 SG_ SRR_RL_ObjMtnPat_6 : 364|3@0+ (1,0) [0|7] "" FLC_ME_FD6
 SG_ SRR_RL_ObjTyp_6 : 367|3@0+ (1,0) [0|7] "" FLC_ME_FD6
 SG_ SRR_RLObj3MsgCounter : 491|4@0+ (1,0) [0|15] "" FLC_ME_FD6
 SG_ SRR_RLObj3CRC16Checksum : 503|16@0+ (1,0) [0|65535] "" FLC_ME_FD6

BO_ 829 SRR_RL_SGUObjPos_4: 64 SRR3
 SG_ SRR_RL_ObjID_7 : 7|8@0+ (1,0) [0|255] "" FLC_ME_FD6
 SG_ SRR_RL_ObjConf_7 : 15|6@0+ (0.015625,0) [0|0.984375] "" FLC_ME_FD6
 SG_ SRR_RL_ObjSNR_7 : 9|11@0+ (0.0625,0) [0|40] "dB" FLC_ME_FD6
 SG_ SRR_RL_ObjDistX_7 : 30|12@0+ (0.0625,-128) [-128|127] "m" FLC_ME_FD6
 SG_ SRR_RL_ObjRelVelX_7 : 34|12@0+ (0.0625,-128) [-128|127] "m/s" FLC_ME_FD6
 SG_ SRR_RL_ObjDistY_7 : 54|14@0+ (0.015625,-128) [-128|127] "m" FLC_ME_FD6
 SG_ SRR_RL_ObjRelVelY_7 : 56|12@0+ (0.0625,-128) [-128|127] "m/s" FLC_ME_FD6
 SG_ SRR_RL_ObjAccelX_7 : 76|12@0+ (0.03125,-16) [-16|15] "m/s2" FLC_ME_FD6
 SG_ SRR_RL_ObjAccelY_7 : 80|12@0+ (0.03125,-16) [-16|15] "m/s2" FLC_ME_FD6
 SG_ SRR_RL_ObjHeading_7 : 100|12@0+ (0.1,-180) [-180|180] "Deg" FLC_ME_FD6
 SG_ SRR_RL_ObjBoxCenterLgt_7 : 104|9@0+ (0.1,-25) [-25|25] "m" FLC_ME_FD6
 SG_ SRR_RL_ObjBoxCenterLat_7 : 127|9@0+ (0.1,-25) [-25|25] "m" FLC_ME_FD6
 SG_ SRR_RL_ObjBoxLength_7 : 134|9@0+ (0.1,0) [0|50] "m" FLC_ME_FD6
 SG_ SRR_RL_ObjBoxWidth_7 : 141|9@0+ (0.1,0) [0|50] "m" FLC_ME_FD6
 SG_ SRR_RL_ObjDyStdDe_7 : 148|8@0+ (0.05,0) [0|12.7] "m" FLC_ME_FD6
 SG_ SRR_RL_ObjDxStdDe_7 : 156|8@0+ (0.05,0) [0|12.7] "m" FLC_ME_FD6
 SG_ SRR_RL_ObjVyStdDe_7 : 174|6@0+ (0.05,0) [0|2] "m/s" FLC_ME_FD6
 SG_ SRR_RL_ObjVxStdDe_7 : 164|6@0+ (0.05,0) [0|2] "m/s" FLC_ME_FD6
 SG_ SRR_RL_ObjMtnPat_7 : 180|3@0+ (1,0) [0|7] "" FLC_ME_FD6
 SG_ SRR_RL_ObjTyp_7 : 183|3@0+ (1,0) [0|7] "" FLC_ME_FD6
 SG_ SRR_RL_ObjID_8 : 191|8@0+ (1,0) [0|255] "" FLC_ME_FD6
 SG_ SRR_RL_ObjConf_8 : 199|6@0+ (0.015625,0) [0|0.984375] "" FLC_ME_FD6
 SG_ SRR_RL_ObjSNR_8 : 193|11@0+ (0.0625,0) [0|40] "dB" FLC_ME_FD6
 SG_ SRR_RL_ObjDistX_8 : 214|12@0+ (0.0625,-128) [-128|127] "m" FLC_ME_FD6
 SG_ SRR_RL_ObjRelVelX_8 : 218|12@0+ (0.0625,-128) [-128|127] "m/s" FLC_ME_FD6
 SG_ SRR_RL_ObjDistY_8 : 238|14@0+ (0.015625,-128) [-128|127] "m" FLC_ME_FD6
 SG_ SRR_RL_ObjRelVelY_8 : 240|12@0+ (0.0625,-128) [-128|127] "m/s" FLC_ME_FD6
 SG_ SRR_RL_ObjAccelX_8 : 260|12@0+ (0.03125,-16) [-16|15] "m/s2" FLC_ME_FD6
 SG_ SRR_RL_ObjAccelY_8 : 264|12@0+ (0.03125,-16) [-16|15] "m/s2" FLC_ME_FD6
 SG_ SRR_RL_ObjHeading_8 : 284|12@0+ (0.1,-180) [-180|180] "Deg" FLC_ME_FD6
 SG_ SRR_RL_ObjBoxCenterLgt_8 : 288|9@0+ (0.1,-25) [-25|25] "m" FLC_ME_FD6
 SG_ SRR_RL_ObjBoxCenterLat_8 : 311|9@0+ (0.1,-25) [-25|25] "m" FLC_ME_FD6
 SG_ SRR_RL_ObjBoxLength_8 : 318|9@0+ (0.1,0) [0|50] "m" FLC_ME_FD6
 SG_ SRR_RL_ObjBoxWidth_8 : 325|9@0+ (0.1,0) [0|50] "m" FLC_ME_FD6
 SG_ SRR_RL_ObjDyStdDe_8 : 332|8@0+ (0.05,0) [0|12.7] "m" FLC_ME_FD6
 SG_ SRR_RL_ObjDxStdDe_8 : 340|8@0+ (0.05,0) [0|12.7] "m" FLC_ME_FD6
 SG_ SRR_RL_ObjVyStdDe_8 : 358|6@0+ (0.05,0) [0|2] "m/s" FLC_ME_FD6
 SG_ SRR_RL_ObjVxStdDe_8 : 348|6@0+ (0.05,0) [0|2] "m/s" FLC_ME_FD6
 SG_ SRR_RL_ObjMtnPat_8 : 364|3@0+ (1,0) [0|7] "" FLC_ME_FD6
 SG_ SRR_RL_ObjTyp_8 : 367|3@0+ (1,0) [0|7] "" FLC_ME_FD6
 SG_ SRR_RLObj4MsgCounter : 491|4@0+ (1,0) [0|15] "" FLC_ME_FD6
 SG_ SRR_RLObj4CRC16Checksum : 503|16@0+ (1,0) [0|65535] "" FLC_ME_FD6

BO_ 830 SRR_RL_SGUObjPos_5: 64 SRR3
 SG_ SRR_RL_ObjID_9 : 7|8@0+ (1,0) [0|255] "" FLC_ME_FD6
 SG_ SRR_RL_ObjConf_9 : 15|6@0+ (0.015625,0) [0|0.984375] "" FLC_ME_FD6
 SG_ SRR_RL_ObjSNR_9 : 9|11@0+ (0.0625,0) [0|40] "dB" FLC_ME_FD6
 SG_ SRR_RL_ObjDistX_9 : 30|12@0+ (0.0625,-128) [-128|127] "m" FLC_ME_FD6
 SG_ SRR_RL_ObjRelVelX_9 : 34|12@0+ (0.0625,-128) [-128|127] "m/s" FLC_ME_FD6
 SG_ SRR_RL_ObjDistY_9 : 54|14@0+ (0.015625,-128) [-128|127] "m" FLC_ME_FD6
 SG_ SRR_RL_ObjRelVelY_9 : 56|12@0+ (0.0625,-128) [-128|127] "m/s" FLC_ME_FD6
 SG_ SRR_RL_ObjAccelX_9 : 76|12@0+ (0.03125,-16) [-16|15] "m/s2" FLC_ME_FD6
 SG_ SRR_RL_ObjAccelY_9 : 80|12@0+ (0.03125,-16) [-16|15] "m/s2" FLC_ME_FD6
 SG_ SRR_RL_ObjHeading_9 : 100|12@0+ (0.1,-180) [-180|180] "Deg" FLC_ME_FD6
 SG_ SRR_RL_ObjBoxCenterLgt_9 : 104|9@0+ (0.1,-25) [-25|25] "m" FLC_ME_FD6
 SG_ SRR_RL_ObjBoxCenterLat_9 : 127|9@0+ (0.1,-25) [-25|25] "m" FLC_ME_FD6
 SG_ SRR_RL_ObjBoxLength_9 : 134|9@0+ (0.1,0) [0|50] "m" FLC_ME_FD6
 SG_ SRR_RL_ObjBoxWidth_9 : 141|9@0+ (0.1,0) [0|50] "m" FLC_ME_FD6
 SG_ SRR_RL_ObjDyStdDe_9 : 148|8@0+ (0.05,0) [0|12.7] "m" FLC_ME_FD6
 SG_ SRR_RL_ObjDxStdDe_9 : 156|8@0+ (0.05,0) [0|12.7] "m" FLC_ME_FD6
 SG_ SRR_RL_ObjVyStdDe_9 : 174|6@0+ (0.05,0) [0|2] "m/s" FLC_ME_FD6
 SG_ SRR_RL_ObjVxStdDe_9 : 164|6@0+ (0.05,0) [0|2] "m/s" FLC_ME_FD6
 SG_ SRR_RL_ObjMtnPat_9 : 180|3@0+ (1,0) [0|7] "" FLC_ME_FD6
 SG_ SRR_RL_ObjTyp_9 : 183|3@0+ (1,0) [0|7] "" FLC_ME_FD6
 SG_ SRR_RL_ObjID_10 : 191|8@0+ (1,0) [0|255] "" FLC_ME_FD6
 SG_ SRR_RL_ObjConf_10 : 199|6@0+ (0.015625,0) [0|0.984375] "" FLC_ME_FD6
 SG_ SRR_RL_ObjSNR_10 : 193|11@0+ (0.0625,0) [0|40] "dB" FLC_ME_FD6
 SG_ SRR_RL_ObjDistX_10 : 214|12@0+ (0.0625,-128) [-128|127] "m" FLC_ME_FD6
 SG_ SRR_RL_ObjRelVelX_10 : 218|12@0+ (0.0625,-128) [-128|127] "m/s" FLC_ME_FD6
 SG_ SRR_RL_ObjDistY_10 : 238|14@0+ (0.015625,-128) [-128|127] "m" FLC_ME_FD6
 SG_ SRR_RL_ObjRelVelY_10 : 240|12@0+ (0.0625,-128) [-128|127] "m/s" FLC_ME_FD6
 SG_ SRR_RL_ObjAccelX_10 : 260|12@0+ (0.03125,-16) [-16|15] "m/s2" FLC_ME_FD6
 SG_ SRR_RL_ObjAccelY_10 : 264|12@0+ (0.03125,-16) [-16|15] "m/s2" FLC_ME_FD6
 SG_ SRR_RL_ObjHeading_10 : 284|12@0+ (0.1,-180) [-180|180] "Deg" FLC_ME_FD6
 SG_ SRR_RL_ObjBoxCenterLgt_10 : 288|9@0+ (0.1,-25) [-25|25] "m" FLC_ME_FD6
 SG_ SRR_RL_ObjBoxCenterLat_10 : 311|9@0+ (0.1,-25) [-25|25] "m" FLC_ME_FD6
 SG_ SRR_RL_ObjBoxLength_10 : 318|9@0+ (0.1,0) [0|50] "m" FLC_ME_FD6
 SG_ SRR_RL_ObjBoxWidth_10 : 325|9@0+ (0.1,0) [0|50] "m" FLC_ME_FD6
 SG_ SRR_RL_ObjDyStdDe_10 : 332|8@0+ (0.05,0) [0|12.7] "m" FLC_ME_FD6
 SG_ SRR_RL_ObjDxStdDe_10 : 340|8@0+ (0.05,0) [0|12.7] "m" FLC_ME_FD6
 SG_ SRR_RL_ObjVyStdDe_10 : 358|6@0+ (0.05,0) [0|2] "m/s" FLC_ME_FD6
 SG_ SRR_RL_ObjVxStdDe_10 : 348|6@0+ (0.05,0) [0|2] "m/s" FLC_ME_FD6
 SG_ SRR_RL_ObjMtnPat_10 : 364|3@0+ (1,0) [0|7] "" FLC_ME_FD6
 SG_ SRR_RL_ObjTyp_10 : 367|3@0+ (1,0) [0|7] "" FLC_ME_FD6
 SG_ SRR_RLObj5MsgCounter : 491|4@0+ (1,0) [0|15] "" FLC_ME_FD6
 SG_ SRR_RLObj5CRC16Checksum : 503|16@0+ (1,0) [0|65535] "" FLC_ME_FD6

BO_ 831 SRR_RL_SGUObjPos_6: 64 SRR3
 SG_ SRR_RL_ObjID_11 : 7|8@0+ (1,0) [0|255] "" FLC_ME_FD6
 SG_ SRR_RL_ObjConf_11 : 15|6@0+ (0.015625,0) [0|0.984375] "" FLC_ME_FD6
 SG_ SRR_RL_ObjSNR_11 : 9|11@0+ (0.0625,0) [0|40] "dB" FLC_ME_FD6
 SG_ SRR_RL_ObjDistX_11 : 30|12@0+ (0.0625,-128) [-128|127] "m" FLC_ME_FD6
 SG_ SRR_RL_ObjRelVelX_11 : 34|12@0+ (0.0625,-128) [-128|127] "m/s" FLC_ME_FD6
 SG_ SRR_RL_ObjDistY_11 : 54|14@0+ (0.015625,-128) [-128|127] "m" FLC_ME_FD6
 SG_ SRR_RL_ObjRelVelY_11 : 56|12@0+ (0.0625,-128) [-128|127] "m/s" FLC_ME_FD6
 SG_ SRR_RL_ObjAccelX_11 : 76|12@0+ (0.03125,-16) [-16|15] "m/s2" FLC_ME_FD6
 SG_ SRR_RL_ObjAccelY_11 : 80|12@0+ (0.03125,-16) [-16|15] "m/s2" FLC_ME_FD6
 SG_ SRR_RL_ObjHeading_11 : 100|12@0+ (0.1,-180) [-180|180] "Deg" FLC_ME_FD6
 SG_ SRR_RL_ObjBoxCenterLgt_11 : 104|9@0+ (0.1,-25) [-25|25] "m" FLC_ME_FD6
 SG_ SRR_RL_ObjBoxCenterLat_11 : 127|9@0+ (0.1,-25) [-25|25] "m" FLC_ME_FD6
 SG_ SRR_RL_ObjBoxLength_11 : 134|9@0+ (0.1,0) [0|50] "m" FLC_ME_FD6
 SG_ SRR_RL_ObjBoxWidth_11 : 141|9@0+ (0.1,0) [0|50] "m" FLC_ME_FD6
 SG_ SRR_RL_ObjDyStdDe_11 : 148|8@0+ (0.05,0) [0|12.7] "m" FLC_ME_FD6
 SG_ SRR_RL_ObjDxStdDe_11 : 156|8@0+ (0.05,0) [0|12.7] "m" FLC_ME_FD6
 SG_ SRR_RL_ObjVyStdDe_11 : 174|6@0+ (0.05,0) [0|2] "m/s" FLC_ME_FD6
 SG_ SRR_RL_ObjVxStdDe_11 : 164|6@0+ (0.05,0) [0|2] "m/s" FLC_ME_FD6
 SG_ SRR_RL_ObjMtnPat_11 : 180|3@0+ (1,0) [0|7] "" FLC_ME_FD6
 SG_ SRR_RL_ObjTyp_11 : 183|3@0+ (1,0) [0|7] "" FLC_ME_FD6
 SG_ SRR_RL_ObjID_12 : 191|8@0+ (1,0) [0|255] "" FLC_ME_FD6
 SG_ SRR_RL_ObjConf_12 : 199|6@0+ (0.015625,0) [0|0.984375] "" FLC_ME_FD6
 SG_ SRR_RL_ObjSNR_12 : 193|11@0+ (0.0625,0) [0|40] "dB" FLC_ME_FD6
 SG_ SRR_RL_ObjDistX_12 : 214|12@0+ (0.0625,-128) [-128|127] "m" FLC_ME_FD6
 SG_ SRR_RL_ObjRelVelX_12 : 218|12@0+ (0.0625,-128) [-128|127] "m/s" FLC_ME_FD6
 SG_ SRR_RL_ObjDistY_12 : 238|14@0+ (0.015625,-128) [-128|127] "m" FLC_ME_FD6
 SG_ SRR_RL_ObjRelVelY_12 : 240|12@0+ (0.0625,-128) [-128|127] "m/s" FLC_ME_FD6
 SG_ SRR_RL_ObjAccelX_12 : 260|12@0+ (0.03125,-16) [-16|15] "m/s2" FLC_ME_FD6
 SG_ SRR_RL_ObjAccelY_12 : 264|12@0+ (0.03125,-16) [-16|15] "m/s2" FLC_ME_FD6
 SG_ SRR_RL_ObjHeading_12 : 284|12@0+ (0.1,-180) [-180|180] "Deg" FLC_ME_FD6
 SG_ SRR_RL_ObjBoxCenterLgt_12 : 288|9@0+ (0.1,-25) [-25|25] "m" FLC_ME_FD6
 SG_ SRR_RL_ObjBoxCenterLat_12 : 311|9@0+ (0.1,-25) [-25|25] "m" FLC_ME_FD6
 SG_ SRR_RL_ObjBoxLength_12 : 318|9@0+ (0.1,0) [0|50] "m" FLC_ME_FD6
 SG_ SRR_RL_ObjBoxWidth_12 : 325|9@0+ (0.1,0) [0|50] "m" FLC_ME_FD6
 SG_ SRR_RL_ObjDyStdDe_12 : 332|8@0+ (0.05,0) [0|12.7] "m" FLC_ME_FD6
 SG_ SRR_RL_ObjDxStdDe_12 : 340|8@0+ (0.05,0) [0|12.7] "m" FLC_ME_FD6
 SG_ SRR_RL_ObjVyStdDe_12 : 358|6@0+ (0.05,0) [0|2] "m/s" FLC_ME_FD6
 SG_ SRR_RL_ObjVxStdDe_12 : 348|6@0+ (0.05,0) [0|2] "m/s" FLC_ME_FD6
 SG_ SRR_RL_ObjMtnPat_12 : 364|3@0+ (1,0) [0|7] "" FLC_ME_FD6
 SG_ SRR_RL_ObjTyp_12 : 367|3@0+ (1,0) [0|7] "" FLC_ME_FD6
 SG_ SRR_RLObj6MsgCounter : 491|4@0+ (1,0) [0|15] "" FLC_ME_FD6
 SG_ SRR_RLObj6CRC16Checksum : 503|16@0+ (1,0) [0|65535] "" FLC_ME_FD6

BO_ 832 SRR_RL_SGUObjPos_7: 64 SRR3
 SG_ SRR_RL_ObjID_13 : 7|8@0+ (1,0) [0|255] "" FLC_ME_FD6
 SG_ SRR_RL_ObjConf_13 : 15|6@0+ (0.015625,0) [0|0.984375] "" FLC_ME_FD6
 SG_ SRR_RL_ObjSNR_13 : 9|11@0+ (0.0625,0) [0|40] "dB" FLC_ME_FD6
 SG_ SRR_RL_ObjDistX_13 : 30|12@0+ (0.0625,-128) [-128|127] "m" FLC_ME_FD6
 SG_ SRR_RL_ObjRelVelX_13 : 34|12@0+ (0.0625,-128) [-128|127] "m/s" FLC_ME_FD6
 SG_ SRR_RL_ObjDistY_13 : 54|14@0+ (0.015625,-128) [-128|127] "m" FLC_ME_FD6
 SG_ SRR_RL_ObjRelVelY_13 : 56|12@0+ (0.0625,-128) [-128|127] "m/s" FLC_ME_FD6
 SG_ SRR_RL_ObjAccelX_13 : 76|12@0+ (0.03125,-16) [-16|15] "m/s2" FLC_ME_FD6
 SG_ SRR_RL_ObjAccelY_13 : 80|12@0+ (0.03125,-16) [-16|15] "m/s2" FLC_ME_FD6
 SG_ SRR_RL_ObjHeading_13 : 100|12@0+ (0.1,-180) [-180|180] "Deg" FLC_ME_FD6
 SG_ SRR_RL_ObjBoxCenterLgt_13 : 104|9@0+ (0.1,-25) [-25|25] "m" FLC_ME_FD6
 SG_ SRR_RL_ObjBoxCenterLat_13 : 127|9@0+ (0.1,-25) [-25|25] "m" FLC_ME_FD6
 SG_ SRR_RL_ObjBoxLength_13 : 134|9@0+ (0.1,0) [0|50] "m" FLC_ME_FD6
 SG_ SRR_RL_ObjBoxWidth_13 : 141|9@0+ (0.1,0) [0|50] "m" FLC_ME_FD6
 SG_ SRR_RL_ObjDyStdDe_13 : 148|8@0+ (0.05,0) [0|12.7] "m" FLC_ME_FD6
 SG_ SRR_RL_ObjDxStdDe_13 : 156|8@0+ (0.05,0) [0|12.7] "m" FLC_ME_FD6
 SG_ SRR_RL_ObjVyStdDe_13 : 174|6@0+ (0.05,0) [0|2] "m/s" FLC_ME_FD6
 SG_ SRR_RL_ObjVxStdDe_13 : 164|6@0+ (0.05,0) [0|2] "m/s" FLC_ME_FD6
 SG_ SRR_RL_ObjMtnPat_13 : 180|3@0+ (1,0) [0|7] "" FLC_ME_FD6
 SG_ SRR_RL_ObjTyp_13 : 183|3@0+ (1,0) [0|7] "" FLC_ME_FD6
 SG_ SRR_RL_ObjID_14 : 191|8@0+ (1,0) [0|255] "" FLC_ME_FD6
 SG_ SRR_RL_ObjConf_14 : 199|6@0+ (0.015625,0) [0|0.984375] "" FLC_ME_FD6
 SG_ SRR_RL_ObjSNR_14 : 193|11@0+ (0.0625,0) [0|40] "dB" FLC_ME_FD6
 SG_ SRR_RL_ObjDistX_14 : 214|12@0+ (0.0625,-128) [-128|127] "m" FLC_ME_FD6
 SG_ SRR_RL_ObjRelVelX_14 : 218|12@0+ (0.0625,-128) [-128|127] "m/s" FLC_ME_FD6
 SG_ SRR_RL_ObjDistY_14 : 238|14@0+ (0.015625,-128) [-128|127] "m" FLC_ME_FD6
 SG_ SRR_RL_ObjRelVelY_14 : 240|12@0+ (0.0625,-128) [-128|127] "m/s" FLC_ME_FD6
 SG_ SRR_RL_ObjAccelX_14 : 260|12@0+ (0.03125,-16) [-16|15] "m/s2" FLC_ME_FD6
 SG_ SRR_RL_ObjAccelY_14 : 264|12@0+ (0.03125,-16) [-16|15] "m/s2" FLC_ME_FD6
 SG_ SRR_RL_ObjHeading_14 : 284|12@0+ (0.1,-180) [-180|180] "Deg" FLC_ME_FD6
 SG_ SRR_RL_ObjBoxCenterLgt_14 : 288|9@0+ (0.1,-25) [-25|25] "m" FLC_ME_FD6
 SG_ SRR_RL_ObjBoxCenterLat_14 : 311|9@0+ (0.1,-25) [-25|25] "m" FLC_ME_FD6
 SG_ SRR_RL_ObjBoxLength_14 : 318|9@0+ (0.1,0) [0|50] "m" FLC_ME_FD6
 SG_ SRR_RL_ObjBoxWidth_14 : 325|9@0+ (0.1,0) [0|50] "m" FLC_ME_FD6
 SG_ SRR_RL_ObjDyStdDe_14 : 332|8@0+ (0.05,0) [0|12.7] "m" FLC_ME_FD6
 SG_ SRR_RL_ObjDxStdDe_14 : 340|8@0+ (0.05,0) [0|12.7] "m" FLC_ME_FD6
 SG_ SRR_RL_ObjVyStdDe_14 : 358|6@0+ (0.05,0) [0|2] "m/s" FLC_ME_FD6
 SG_ SRR_RL_ObjVxStdDe_14 : 348|6@0+ (0.05,0) [0|2] "m/s" FLC_ME_FD6
 SG_ SRR_RL_ObjMtnPat_14 : 364|3@0+ (1,0) [0|7] "" FLC_ME_FD6
 SG_ SRR_RL_ObjTyp_14 : 367|3@0+ (1,0) [0|7] "" FLC_ME_FD6
 SG_ SRR_RLObj7MsgCounter : 491|4@0+ (1,0) [0|15] "" FLC_ME_FD6
 SG_ SRR_RLObj7CRC16Checksum : 503|16@0+ (1,0) [0|65535] "" FLC_ME_FD6

BO_ 833 SRR_RL_SGUObjPos_8: 64 SRR3
 SG_ SRR_RL_ObjID_15 : 7|8@0+ (1,0) [0|255] "" FLC_ME_FD6
 SG_ SRR_RL_ObjConf_15 : 15|6@0+ (0.015625,0) [0|0.984375] "" FLC_ME_FD6
 SG_ SRR_RL_ObjSNR_15 : 9|11@0+ (0.0625,0) [0|40] "dB" FLC_ME_FD6
 SG_ SRR_RL_ObjDistX_15 : 30|12@0+ (0.0625,-128) [-128|127] "m" FLC_ME_FD6
 SG_ SRR_RL_ObjRelVelX_15 : 34|12@0+ (0.0625,-128) [-128|127] "m/s" FLC_ME_FD6
 SG_ SRR_RL_ObjDistY_15 : 54|14@0+ (0.015625,-128) [-128|127] "m" FLC_ME_FD6
 SG_ SRR_RL_ObjRelVelY_15 : 56|12@0+ (0.0625,-128) [-128|127] "m/s" FLC_ME_FD6
 SG_ SRR_RL_ObjAccelX_15 : 76|12@0+ (0.03125,-16) [-16|15] "m/s2" FLC_ME_FD6
 SG_ SRR_RL_ObjAccelY_15 : 80|12@0+ (0.03125,-16) [-16|15] "m/s2" FLC_ME_FD6
 SG_ SRR_RL_ObjHeading_15 : 100|12@0+ (0.1,-180) [-180|180] "Deg" FLC_ME_FD6
 SG_ SRR_RL_ObjBoxCenterLgt_15 : 104|9@0+ (0.1,-25) [-25|25] "m" FLC_ME_FD6
 SG_ SRR_RL_ObjBoxCenterLat_15 : 127|9@0+ (0.1,-25) [-25|25] "m" FLC_ME_FD6
 SG_ SRR_RL_ObjBoxLength_15 : 134|9@0+ (0.1,0) [0|50] "m" FLC_ME_FD6
 SG_ SRR_RL_ObjBoxWidth_15 : 141|9@0+ (0.1,0) [0|50] "m" FLC_ME_FD6
 SG_ SRR_RL_ObjDyStdDe_15 : 148|8@0+ (0.05,0) [0|12.7] "m" FLC_ME_FD6
 SG_ SRR_RL_ObjDxStdDe_15 : 156|8@0+ (0.05,0) [0|12.7] "m" FLC_ME_FD6
 SG_ SRR_RL_ObjVyStdDe_15 : 174|6@0+ (0.05,0) [0|2] "m/s" FLC_ME_FD6
 SG_ SRR_RL_ObjVxStdDe_15 : 164|6@0+ (0.05,0) [0|2] "m/s" FLC_ME_FD6
 SG_ SRR_RL_ObjMtnPat_15 : 180|3@0+ (1,0) [0|7] "" FLC_ME_FD6
 SG_ SRR_RL_ObjTyp_15 : 183|3@0+ (1,0) [0|7] "" FLC_ME_FD6
 SG_ SRR_RL_ObjID_16 : 191|8@0+ (1,0) [0|255] "" FLC_ME_FD6
 SG_ SRR_RL_ObjConf_16 : 199|6@0+ (0.015625,0) [0|0.984375] "" FLC_ME_FD6
 SG_ SRR_RL_ObjSNR_16 : 193|11@0+ (0.0625,0) [0|40] "dB" FLC_ME_FD6
 SG_ SRR_RL_ObjDistX_16 : 214|12@0+ (0.0625,-128) [-128|127] "m" FLC_ME_FD6
 SG_ SRR_RL_ObjRelVelX_16 : 218|12@0+ (0.0625,-128) [-128|127] "m/s" FLC_ME_FD6
 SG_ SRR_RL_ObjDistY_16 : 238|14@0+ (0.015625,-128) [-128|127] "m" FLC_ME_FD6
 SG_ SRR_RL_ObjRelVelY_16 : 240|12@0+ (0.0625,-128) [-128|127] "m/s" FLC_ME_FD6
 SG_ SRR_RL_ObjAccelX_16 : 260|12@0+ (0.03125,-16) [-16|15] "m/s2" FLC_ME_FD6
 SG_ SRR_RL_ObjAccelY_16 : 264|12@0+ (0.03125,-16) [-16|15] "m/s2" FLC_ME_FD6
 SG_ SRR_RL_ObjHeading_16 : 284|12@0+ (0.1,-180) [-180|180] "Deg" FLC_ME_FD6
 SG_ SRR_RL_ObjBoxCenterLgt_16 : 288|9@0+ (0.1,-25) [-25|25] "m" FLC_ME_FD6
 SG_ SRR_RL_ObjBoxCenterLat_16 : 311|9@0+ (0.1,-25) [-25|25] "m" FLC_ME_FD6
 SG_ SRR_RL_ObjBoxLength_16 : 318|9@0+ (0.1,0) [0|50] "m" FLC_ME_FD6
 SG_ SRR_RL_ObjBoxWidth_16 : 325|9@0+ (0.1,0) [0|50] "m" FLC_ME_FD6
 SG_ SRR_RL_ObjDyStdDe_16 : 332|8@0+ (0.05,0) [0|12.7] "m" FLC_ME_FD6
 SG_ SRR_RL_ObjDxStdDe_16 : 340|8@0+ (0.05,0) [0|12.7] "m" FLC_ME_FD6
 SG_ SRR_RL_ObjVyStdDe_16 : 358|6@0+ (0.05,0) [0|2] "m/s" FLC_ME_FD6
 SG_ SRR_RL_ObjVxStdDe_16 : 348|6@0+ (0.05,0) [0|2] "m/s" FLC_ME_FD6
 SG_ SRR_RL_ObjMtnPat_16 : 364|3@0+ (1,0) [0|7] "" FLC_ME_FD6
 SG_ SRR_RL_ObjTyp_16 : 367|3@0+ (1,0) [0|7] "" FLC_ME_FD6
 SG_ SRR_RLObj8MsgCounter : 491|4@0+ (1,0) [0|15] "" FLC_ME_FD6
 SG_ SRR_RLObj8CRC16Checksum : 503|16@0+ (1,0) [0|65535] "" FLC_ME_FD6

BO_ 834 SRR_RR_First_Frame: 64 SRR4
 SG_ SRR_RR_TargetTI_Status : 7|8@0+ (1,0) [0|255] "" FLC_ME_FD6
 SG_ SRR_RR_OBJTi_Stamp : 15|32@0+ (0.1,0) [0|4.294967295E8] "" FLC_ME_FD6
 SG_ SRR_RR_Delay_Time : 47|32@0+ (0.1,0) [0|4.294967295E8] "" FLC_ME_FD6
 SG_ SRR_RR_NrObj : 79|8@0+ (1,0) [0|255] "" FLC_ME_FD6
 SG_ SRR_RRRadar_Status : 87|4@0+ (1,0) [0|15] "" FLC_ME_FD6
 SG_ SRR_RR_MsgCounter : 491|4@0+ (1,0) [0|15] "" FLC_ME_FD6
 SG_ SRR_RR_CRC16Checksum : 503|16@0+ (1,0) [0|65535] "" FLC_ME_FD6

BO_ 835 SRR_RR_SGUObjPos_1: 64 SRR4
 SG_ SRR_RR_ObjID_1 : 7|8@0+ (1,0) [0|255] "" FLC_ME_FD6
 SG_ SRR_RR_ObjConf_1 : 15|6@0+ (0.015625,0) [0|0.984375] "" FLC_ME_FD6
 SG_ SRR_RR_ObjSNR_1 : 9|11@0+ (0.0625,0) [0|40] "" FLC_ME_FD6
 SG_ SRR_RR_ObjDistX_1 : 30|12@0+ (0.0625,-128) [-128|127] "" FLC_ME_FD6
 SG_ SRR_RR_ObjRelVelX_1 : 34|12@0+ (0.0625,-128) [-128|127] "" FLC_ME_FD6
 SG_ SRR_RR_ObjDistY_1 : 54|14@0+ (0.015625,-128) [-128|127] "" FLC_ME_FD6
 SG_ SRR_RR_ObjRelVelY_1 : 56|12@0+ (0.0625,-128) [-128|127] "" FLC_ME_FD6
 SG_ SRR_RR_ObjAccelX_1 : 76|12@0+ (0.03125,-16) [-16|15] "" FLC_ME_FD6
 SG_ SRR_RR_ObjAccelY_1 : 80|12@0+ (0.03125,-16) [-16|15] "" FLC_ME_FD6
 SG_ SRR_RR_ObjHeading_1 : 100|12@0+ (0.1,-180) [-180|180] "" FLC_ME_FD6
 SG_ SRR_RR_ObjBoxCenterLgt_1 : 104|9@0+ (0.1,-25) [-25|25] "" FLC_ME_FD6
 SG_ SRR_RR_ObjBoxCenterLat_1 : 127|9@0+ (0.1,-25) [-25|25] "" FLC_ME_FD6
 SG_ SRR_RR_ObjBoxLength_1 : 134|9@0+ (0.1,0) [0|50] "" FLC_ME_FD6
 SG_ SRR_RR_ObjBoxWidth_1 : 141|9@0+ (0.1,0) [0|50] "" FLC_ME_FD6
 SG_ SRR_RR_ObjDyStdDe_1 : 148|8@0+ (0.05,0) [0|12.7] "" FLC_ME_FD6
 SG_ SRR_RR_ObjDxStdDe_1 : 156|8@0+ (0.05,0) [0|12.7] "" FLC_ME_FD6
 SG_ SRR_RR_ObjVyStdDe_1 : 174|6@0+ (0.05,0) [0|2] "" FLC_ME_FD6
 SG_ SRR_RR_ObjVxStdDe_1 : 164|6@0+ (0.05,0) [0|2] "" FLC_ME_FD6
 SG_ SRR_RR_ObjMtnPat_1 : 180|3@0+ (1,0) [0|7] "" FLC_ME_FD6
 SG_ SRR_RR_ObjTyp_1 : 183|3@0+ (1,0) [0|7] "" FLC_ME_FD6
 SG_ SRR_RR_ObjID_2 : 191|8@0+ (1,0) [0|255] "" FLC_ME_FD6
 SG_ SRR_RR_ObjConf_2 : 199|6@0+ (0.015625,0) [0|0.984375] "" FLC_ME_FD6
 SG_ SRR_RR_ObjSNR_2 : 193|11@0+ (0.0625,0) [0|40] "" FLC_ME_FD6
 SG_ SRR_RR_ObjDistX_2 : 214|12@0+ (0.0625,-128) [-128|127] "" FLC_ME_FD6
 SG_ SRR_RR_ObjRelVelX_2 : 218|12@0+ (0.0625,-128) [-128|127] "" FLC_ME_FD6
 SG_ SRR_RR_ObjDistY_2 : 238|14@0+ (0.015625,-128) [-128|127] "" FLC_ME_FD6
 SG_ SRR_RR_ObjRelVelY_2 : 240|12@0+ (0.0625,-128) [-128|127] "" FLC_ME_FD6
 SG_ SRR_RR_ObjAccelX_2 : 260|12@0+ (0.03125,-16) [-16|15] "" FLC_ME_FD6
 SG_ SRR_RR_ObjAccelY_2 : 264|12@0+ (0.03125,-16) [-16|15] "" FLC_ME_FD6
 SG_ SRR_RR_ObjHeading_2 : 284|12@0+ (0.1,-180) [-180|180] "" FLC_ME_FD6
 SG_ SRR_RR_ObjBoxCenterLgt_2 : 288|9@0+ (0.1,-25) [-25|25] "" FLC_ME_FD6
 SG_ SRR_RR_ObjBoxCenterLat_2 : 311|9@0+ (0.1,-25) [-25|25] "" FLC_ME_FD6
 SG_ SRR_RR_ObjBoxLength_2 : 318|9@0+ (0.1,0) [0|50] "" FLC_ME_FD6
 SG_ SRR_RR_ObjBoxWidth_2 : 325|9@0+ (0.1,0) [0|50] "" FLC_ME_FD6
 SG_ SRR_RR_ObjDyStdDe_2 : 332|8@0+ (0.05,0) [0|12.7] "" FLC_ME_FD6
 SG_ SRR_RR_ObjDxStdDe_2 : 340|8@0+ (0.05,0) [0|12.7] "" FLC_ME_FD6
 SG_ SRR_RR_ObjVyStdDe_2 : 358|6@0+ (0.05,0) [0|2] "" FLC_ME_FD6
 SG_ SRR_RR_ObjVxStdDe_2 : 348|6@0+ (0.05,0) [0|2] "" FLC_ME_FD6
 SG_ SRR_RR_ObjMtnPat_2 : 364|3@0+ (1,0) [0|7] "" FLC_ME_FD6
 SG_ SRR_RR_ObjTyp_2 : 367|3@0+ (1,0) [0|7] "" FLC_ME_FD6
 SG_ SRR_RRObj1MsgCounter : 491|4@0+ (1,0) [0|15] "" FLC_ME_FD6
 SG_ SRR_RRObj1CRC16Checksum : 503|16@0+ (1,0) [0|65535] "" FLC_ME_FD6

BO_ 836 SRR_RR_SGUObjPos_2: 64 SRR4
 SG_ SRR_RR_ObjID_3 : 7|8@0+ (1,0) [0|255] "" FLC_ME_FD6
 SG_ SRR_RR_ObjConf_3 : 15|6@0+ (0.015625,0) [0|0.984375] "" FLC_ME_FD6
 SG_ SRR_RR_ObjSNR_3 : 9|11@0+ (0.0625,0) [0|40] "" FLC_ME_FD6
 SG_ SRR_RR_ObjDistX_3 : 30|12@0+ (0.0625,-128) [-128|127] "" FLC_ME_FD6
 SG_ SRR_RR_ObjRelVelX_3 : 34|12@0+ (0.0625,-128) [-128|127] "" FLC_ME_FD6
 SG_ SRR_RR_ObjDistY_3 : 54|14@0+ (0.015625,-128) [-128|127] "" FLC_ME_FD6
 SG_ SRR_RR_ObjRelVelY_3 : 56|12@0+ (0.0625,-128) [-128|127] "" FLC_ME_FD6
 SG_ SRR_RR_ObjAccelX_3 : 76|12@0+ (0.03125,-16) [-16|15] "" FLC_ME_FD6
 SG_ SRR_RR_ObjAccelY_3 : 80|12@0+ (0.03125,-16) [-16|15] "" FLC_ME_FD6
 SG_ SRR_RR_ObjHeading_3 : 100|12@0+ (0.1,-180) [-180|180] "" FLC_ME_FD6
 SG_ SRR_RR_ObjBoxCenterLgt_3 : 104|9@0+ (0.1,-25) [-25|25] "" FLC_ME_FD6
 SG_ SRR_RR_ObjBoxCenterLat_3 : 127|9@0+ (0.1,-25) [-25|25] "" FLC_ME_FD6
 SG_ SRR_RR_ObjBoxLength_3 : 134|9@0+ (0.1,0) [0|50] "" FLC_ME_FD6
 SG_ SRR_RR_ObjBoxWidth_3 : 141|9@0+ (0.1,0) [0|50] "" FLC_ME_FD6
 SG_ SRR_RR_ObjDyStdDe_3 : 148|8@0+ (0.05,0) [0|12.7] "" FLC_ME_FD6
 SG_ SRR_RR_ObjDxStdDe_3 : 156|8@0+ (0.05,0) [0|12.7] "" FLC_ME_FD6
 SG_ SRR_RR_ObjVyStdDe_3 : 174|6@0+ (0.05,0) [0|2] "" FLC_ME_FD6
 SG_ SRR_RR_ObjVxStdDe_3 : 164|6@0+ (0.05,0) [0|2] "" FLC_ME_FD6
 SG_ SRR_RR_ObjMtnPat_3 : 180|3@0+ (1,0) [0|7] "" FLC_ME_FD6
 SG_ SRR_RR_ObjTyp_3 : 183|3@0+ (1,0) [0|7] "" FLC_ME_FD6
 SG_ SRR_RR_ObjID_4 : 191|8@0+ (1,0) [0|255] "" FLC_ME_FD6
 SG_ SRR_RR_ObjConf_4 : 199|6@0+ (0.015625,0) [0|0.984375] "" FLC_ME_FD6
 SG_ SRR_RR_ObjSNR_4 : 193|11@0+ (0.0625,0) [0|40] "" FLC_ME_FD6
 SG_ SRR_RR_ObjDistX_4 : 214|12@0+ (0.0625,-128) [-128|127] "" FLC_ME_FD6
 SG_ SRR_RR_ObjRelVelX_4 : 218|12@0+ (0.0625,-128) [-128|127] "" FLC_ME_FD6
 SG_ SRR_RR_ObjDistY_4 : 238|14@0+ (0.015625,-128) [-128|127] "" FLC_ME_FD6
 SG_ SRR_RR_ObjRelVelY_4 : 240|12@0+ (0.0625,-128) [-128|127] "" FLC_ME_FD6
 SG_ SRR_RR_ObjAccelX_4 : 260|12@0+ (0.03125,-16) [-16|15] "" FLC_ME_FD6
 SG_ SRR_RR_ObjAccelY_4 : 264|12@0+ (0.03125,-16) [-16|15] "" FLC_ME_FD6
 SG_ SRR_RR_ObjHeading_4 : 284|12@0+ (0.1,-180) [-180|180] "" FLC_ME_FD6
 SG_ SRR_RR_ObjBoxCenterLgt_4 : 288|9@0+ (0.1,-25) [-25|25] "" FLC_ME_FD6
 SG_ SRR_RR_ObjBoxCenterLat_4 : 311|9@0+ (0.1,-25) [-25|25] "" FLC_ME_FD6
 SG_ SRR_RR_ObjBoxLength_4 : 318|9@0+ (0.1,0) [0|50] "" FLC_ME_FD6
 SG_ SRR_RR_ObjBoxWidth_4 : 325|9@0+ (0.1,0) [0|50] "" FLC_ME_FD6
 SG_ SRR_RR_ObjDyStdDe_4 : 332|8@0+ (0.05,0) [0|12.7] "" FLC_ME_FD6
 SG_ SRR_RR_ObjDxStdDe_4 : 340|8@0+ (0.05,0) [0|12.7] "" FLC_ME_FD6
 SG_ SRR_RR_ObjVyStdDe_4 : 358|6@0+ (0.05,0) [0|2] "" FLC_ME_FD6
 SG_ SRR_RR_ObjVxStdDe_4 : 348|6@0+ (0.05,0) [0|2] "" FLC_ME_FD6
 SG_ SRR_RR_ObjMtnPat_4 : 364|3@0+ (1,0) [0|7] "" FLC_ME_FD6
 SG_ SRR_RR_ObjTyp_4 : 367|3@0+ (1,0) [0|7] "" FLC_ME_FD6
 SG_ SRR_RRObj2MsgCounter : 491|4@0+ (1,0) [0|15] "" FLC_ME_FD6
 SG_ SRR_RRObj2CRC16Checksum : 503|16@0+ (1,0) [0|65535] "" FLC_ME_FD6

BO_ 837 SRR_RR_SGUObjPos_3: 64 SRR4
 SG_ SRR_RR_ObjID_5 : 7|8@0+ (1,0) [0|255] "" FLC_ME_FD6
 SG_ SRR_RR_ObjConf_5 : 15|6@0+ (0.015625,0) [0|0.984375] "" FLC_ME_FD6
 SG_ SRR_RR_ObjSNR_5 : 9|11@0+ (0.0625,0) [0|40] "" FLC_ME_FD6
 SG_ SRR_RR_ObjDistX_5 : 30|12@0+ (0.0625,-128) [-128|127] "" FLC_ME_FD6
 SG_ SRR_RR_ObjRelVelX_5 : 34|12@0+ (0.0625,-128) [-128|127] "" FLC_ME_FD6
 SG_ SRR_RR_ObjDistY_5 : 54|14@0+ (0.015625,-128) [-128|127] "" FLC_ME_FD6
 SG_ SRR_RR_ObjRelVelY_5 : 56|12@0+ (0.0625,-128) [-128|127] "" FLC_ME_FD6
 SG_ SRR_RR_ObjAccelX_5 : 76|12@0+ (0.03125,-16) [-16|15] "" FLC_ME_FD6
 SG_ SRR_RR_ObjAccelY_5 : 80|12@0+ (0.03125,-16) [-16|15] "" FLC_ME_FD6
 SG_ SRR_RR_ObjHeading_5 : 100|12@0+ (0.1,-180) [-180|180] "" FLC_ME_FD6
 SG_ SRR_RR_ObjBoxCenterLgt_5 : 104|9@0+ (0.1,-25) [-25|25] "" FLC_ME_FD6
 SG_ SRR_RR_ObjBoxCenterLat_5 : 127|9@0+ (0.1,-25) [-25|25] "" FLC_ME_FD6
 SG_ SRR_RR_ObjBoxLength_5 : 134|9@0+ (0.1,0) [0|50] "" FLC_ME_FD6
 SG_ SRR_RR_ObjBoxWidth_5 : 141|9@0+ (0.1,0) [0|50] "" FLC_ME_FD6
 SG_ SRR_RR_ObjDyStdDe_5 : 148|8@0+ (0.05,0) [0|12.7] "" FLC_ME_FD6
 SG_ SRR_RR_ObjDxStdDe_5 : 156|8@0+ (0.05,0) [0|12.7] "" FLC_ME_FD6
 SG_ SRR_RR_ObjVyStdDe_5 : 174|6@0+ (0.05,0) [0|2] "" FLC_ME_FD6
 SG_ SRR_RR_ObjVxStdDe_5 : 164|6@0+ (0.05,0) [0|2] "" FLC_ME_FD6
 SG_ SRR_RR_ObjMtnPat_5 : 180|3@0+ (1,0) [0|7] "" FLC_ME_FD6
 SG_ SRR_RR_ObjTyp_5 : 183|3@0+ (1,0) [0|7] "" FLC_ME_FD6
 SG_ SRR_RR_ObjID_6 : 191|8@0+ (1,0) [0|255] "" FLC_ME_FD6
 SG_ SRR_RR_ObjConf_6 : 199|6@0+ (0.015625,0) [0|0.984375] "" FLC_ME_FD6
 SG_ SRR_RR_ObjSNR_6 : 193|11@0+ (0.0625,0) [0|40] "" FLC_ME_FD6
 SG_ SRR_RR_ObjDistX_6 : 214|12@0+ (0.0625,-128) [-128|127] "" FLC_ME_FD6
 SG_ SRR_RR_ObjRelVelX_6 : 218|12@0+ (0.0625,-128) [-128|127] "" FLC_ME_FD6
 SG_ SRR_RR_ObjDistY_6 : 238|14@0+ (0.015625,-128) [-128|127] "" FLC_ME_FD6
 SG_ SRR_RR_ObjRelVelY_6 : 240|12@0+ (0.0625,-128) [-128|127] "" FLC_ME_FD6
 SG_ SRR_RR_ObjAccelX_6 : 260|12@0+ (0.03125,-16) [-16|15] "" FLC_ME_FD6
 SG_ SRR_RR_ObjAccelY_6 : 264|12@0+ (0.03125,-16) [-16|15] "" FLC_ME_FD6
 SG_ SRR_RR_ObjHeading_6 : 284|12@0+ (0.1,-180) [-180|180] "" FLC_ME_FD6
 SG_ SRR_RR_ObjBoxCenterLgt_6 : 288|9@0+ (0.1,-25) [-25|25] "" FLC_ME_FD6
 SG_ SRR_RR_ObjBoxCenterLat_6 : 311|9@0+ (0.1,-25) [-25|25] "" FLC_ME_FD6
 SG_ SRR_RR_ObjBoxLength_6 : 318|9@0+ (0.1,0) [0|50] "" FLC_ME_FD6
 SG_ SRR_RR_ObjBoxWidth_6 : 325|9@0+ (0.1,0) [0|50] "" FLC_ME_FD6
 SG_ SRR_RR_ObjDyStdDe_6 : 332|8@0+ (0.05,0) [0|12.7] "" FLC_ME_FD6
 SG_ SRR_RR_ObjDxStdDe_6 : 340|8@0+ (0.05,0) [0|12.7] "" FLC_ME_FD6
 SG_ SRR_RR_ObjVyStdDe_6 : 358|6@0+ (0.05,0) [0|2] "" FLC_ME_FD6
 SG_ SRR_RR_ObjVxStdDe_6 : 348|6@0+ (0.05,0) [0|2] "" FLC_ME_FD6
 SG_ SRR_RR_ObjMtnPat_6 : 364|3@0+ (1,0) [0|7] "" FLC_ME_FD6
 SG_ SRR_RR_ObjTyp_6 : 367|3@0+ (1,0) [0|7] "" FLC_ME_FD6
 SG_ SRR_RRObj3MsgCounter : 491|4@0+ (1,0) [0|15] "" FLC_ME_FD6
 SG_ SRR_RRObj3CRC16Checksum : 503|16@0+ (1,0) [0|65535] "" FLC_ME_FD6

BO_ 838 SRR_RR_SGUObjPos_4: 64 SRR4
 SG_ SRR_RR_ObjID_7 : 7|8@0+ (1,0) [0|255] "" FLC_ME_FD6
 SG_ SRR_RR_ObjConf_7 : 15|6@0+ (0.015625,0) [0|0.984375] "" FLC_ME_FD6
 SG_ SRR_RR_ObjSNR_7 : 9|11@0+ (0.0625,0) [0|40] "" FLC_ME_FD6
 SG_ SRR_RR_ObjDistX_7 : 30|12@0+ (0.0625,-128) [-128|127] "" FLC_ME_FD6
 SG_ SRR_RR_ObjRelVelX_7 : 34|12@0+ (0.0625,-128) [-128|127] "" FLC_ME_FD6
 SG_ SRR_RR_ObjDistY_7 : 54|14@0+ (0.015625,-128) [-128|127] "" FLC_ME_FD6
 SG_ SRR_RR_ObjRelVelY_7 : 56|12@0+ (0.0625,-128) [-128|127] "" FLC_ME_FD6
 SG_ SRR_RR_ObjAccelX_7 : 76|12@0+ (0.03125,-16) [-16|15] "" FLC_ME_FD6
 SG_ SRR_RR_ObjAccelY_7 : 80|12@0+ (0.03125,-16) [-16|15] "" FLC_ME_FD6
 SG_ SRR_RR_ObjHeading_7 : 100|12@0+ (0.1,-180) [-180|180] "" FLC_ME_FD6
 SG_ SRR_RR_ObjBoxCenterLgt_7 : 104|9@0+ (0.1,-25) [-25|25] "" FLC_ME_FD6
 SG_ SRR_RR_ObjBoxCenterLat_7 : 127|9@0+ (0.1,-25) [-25|25] "" FLC_ME_FD6
 SG_ SRR_RR_ObjBoxLength_7 : 134|9@0+ (0.1,0) [0|50] "" FLC_ME_FD6
 SG_ SRR_RR_ObjBoxWidth_7 : 141|9@0+ (0.1,0) [0|50] "" FLC_ME_FD6
 SG_ SRR_RR_ObjDyStdDe_7 : 148|8@0+ (0.05,0) [0|12.7] "" FLC_ME_FD6
 SG_ SRR_RR_ObjDxStdDe_7 : 156|8@0+ (0.05,0) [0|12.7] "" FLC_ME_FD6
 SG_ SRR_RR_ObjVyStdDe_7 : 174|6@0+ (0.05,0) [0|2] "" FLC_ME_FD6
 SG_ SRR_RR_ObjVxStdDe_7 : 164|6@0+ (0.05,0) [0|2] "" FLC_ME_FD6
 SG_ SRR_RR_ObjMtnPat_7 : 180|3@0+ (1,0) [0|7] "" FLC_ME_FD6
 SG_ SRR_RR_ObjTyp_7 : 183|3@0+ (1,0) [0|7] "" FLC_ME_FD6
 SG_ SRR_RR_ObjID_8 : 191|8@0+ (1,0) [0|255] "" FLC_ME_FD6
 SG_ SRR_RR_ObjConf_8 : 199|6@0+ (0.015625,0) [0|0.984375] "" FLC_ME_FD6
 SG_ SRR_RR_ObjSNR_8 : 193|11@0+ (0.0625,0) [0|40] "" FLC_ME_FD6
 SG_ SRR_RR_ObjDistX_8 : 214|12@0+ (0.0625,-128) [-128|127] "" FLC_ME_FD6
 SG_ SRR_RR_ObjRelVelX_8 : 218|12@0+ (0.0625,-128) [-128|127] "" FLC_ME_FD6
 SG_ SRR_RR_ObjDistY_8 : 238|14@0+ (0.015625,-128) [-128|127] "" FLC_ME_FD6
 SG_ SRR_RR_ObjRelVelY_8 : 240|12@0+ (0.0625,-128) [-128|127] "" FLC_ME_FD6
 SG_ SRR_RR_ObjAccelX_8 : 260|12@0+ (0.03125,-16) [-16|15] "" FLC_ME_FD6
 SG_ SRR_RR_ObjAccelY_8 : 264|12@0+ (0.03125,-16) [-16|15] "" FLC_ME_FD6
 SG_ SRR_RR_ObjHeading_8 : 284|12@0+ (0.1,-180) [-180|180] "" FLC_ME_FD6
 SG_ SRR_RR_ObjBoxCenterLgt_8 : 288|9@0+ (0.1,-25) [-25|25] "" FLC_ME_FD6
 SG_ SRR_RR_ObjBoxCenterLat_8 : 311|9@0+ (0.1,-25) [-25|25] "" FLC_ME_FD6
 SG_ SRR_RR_ObjBoxLength_8 : 318|9@0+ (0.1,0) [0|50] "" FLC_ME_FD6
 SG_ SRR_RR_ObjBoxWidth_8 : 325|9@0+ (0.1,0) [0|50] "" FLC_ME_FD6
 SG_ SRR_RR_ObjDyStdDe_8 : 332|8@0+ (0.05,0) [0|12.7] "" FLC_ME_FD6
 SG_ SRR_RR_ObjDxStdDe_8 : 340|8@0+ (0.05,0) [0|12.7] "" FLC_ME_FD6
 SG_ SRR_RR_ObjVyStdDe_8 : 358|6@0+ (0.05,0) [0|2] "" FLC_ME_FD6
 SG_ SRR_RR_ObjVxStdDe_8 : 348|6@0+ (0.05,0) [0|2] "" FLC_ME_FD6
 SG_ SRR_RR_ObjMtnPat_8 : 364|3@0+ (1,0) [0|7] "" FLC_ME_FD6
 SG_ SRR_RR_ObjTyp_8 : 367|3@0+ (1,0) [0|7] "" FLC_ME_FD6
 SG_ SRR_RRObj4MsgCounter : 491|4@0+ (1,0) [0|15] "" FLC_ME_FD6
 SG_ SRR_RRObj4CRC16Checksum : 503|16@0+ (1,0) [0|65535] "" FLC_ME_FD6

BO_ 839 SRR_RR_SGUObjPos_5: 64 SRR4
 SG_ SRR_RR_ObjID_9 : 7|8@0+ (1,0) [0|255] "" FLC_ME_FD6
 SG_ SRR_RR_ObjConf_9 : 15|6@0+ (0.015625,0) [0|0.984375] "" FLC_ME_FD6
 SG_ SRR_RR_ObjSNR_9 : 9|11@0+ (0.0625,0) [0|40] "" FLC_ME_FD6
 SG_ SRR_RR_ObjDistX_9 : 30|12@0+ (0.0625,-128) [-128|127] "" FLC_ME_FD6
 SG_ SRR_RR_ObjRelVelX_9 : 34|12@0+ (0.0625,-128) [-128|127] "" FLC_ME_FD6
 SG_ SRR_RR_ObjDistY_9 : 54|14@0+ (0.015625,-128) [-128|127] "" FLC_ME_FD6
 SG_ SRR_RR_ObjRelVelY_9 : 56|12@0+ (0.0625,-128) [-128|127] "" FLC_ME_FD6
 SG_ SRR_RR_ObjAccelX_9 : 76|12@0+ (0.03125,-16) [-16|15] "" FLC_ME_FD6
 SG_ SRR_RR_ObjAccelY_9 : 80|12@0+ (0.03125,-16) [-16|15] "" FLC_ME_FD6
 SG_ SRR_RR_ObjHeading_9 : 100|12@0+ (0.1,-180) [-180|180] "" FLC_ME_FD6
 SG_ SRR_RR_ObjBoxCenterLgt_9 : 104|9@0+ (0.1,-25) [-25|25] "" FLC_ME_FD6
 SG_ SRR_RR_ObjBoxCenterLat_9 : 127|9@0+ (0.1,-25) [-25|25] "" FLC_ME_FD6
 SG_ SRR_RR_ObjBoxLength_9 : 134|9@0+ (0.1,0) [0|50] "" FLC_ME_FD6
 SG_ SRR_RR_ObjBoxWidth_9 : 141|9@0+ (0.1,0) [0|50] "" FLC_ME_FD6
 SG_ SRR_RR_ObjDyStdDe_9 : 148|8@0+ (0.05,0) [0|12.7] "" FLC_ME_FD6
 SG_ SRR_RR_ObjDxStdDe_9 : 156|8@0+ (0.05,0) [0|12.7] "" FLC_ME_FD6
 SG_ SRR_RR_ObjVyStdDe_9 : 174|6@0+ (0.05,0) [0|2] "" FLC_ME_FD6
 SG_ SRR_RR_ObjVxStdDe_9 : 164|6@0+ (0.05,0) [0|2] "" FLC_ME_FD6
 SG_ SRR_RR_ObjMtnPat_9 : 180|3@0+ (1,0) [0|7] "" FLC_ME_FD6
 SG_ SRR_RR_ObjTyp_9 : 183|3@0+ (1,0) [0|7] "" FLC_ME_FD6
 SG_ SRR_RR_ObjID_10 : 191|8@0+ (1,0) [0|255] "" FLC_ME_FD6
 SG_ SRR_RR_ObjConf_10 : 199|6@0+ (0.015625,0) [0|0.984375] "" FLC_ME_FD6
 SG_ SRR_RR_ObjSNR_10 : 193|11@0+ (0.0625,0) [0|40] "" FLC_ME_FD6
 SG_ SRR_RR_ObjDistX_10 : 214|12@0+ (0.0625,-128) [-128|127] "" FLC_ME_FD6
 SG_ SRR_RR_ObjRelVelX_10 : 218|12@0+ (0.0625,-128) [-128|127] "" FLC_ME_FD6
 SG_ SRR_RR_ObjDistY_10 : 238|14@0+ (0.015625,-128) [-128|127] "" FLC_ME_FD6
 SG_ SRR_RR_ObjRelVelY_10 : 240|12@0+ (0.0625,-128) [-128|127] "" FLC_ME_FD6
 SG_ SRR_RR_ObjAccelX_10 : 260|12@0+ (0.03125,-16) [-16|15] "" FLC_ME_FD6
 SG_ SRR_RR_ObjAccelY_10 : 264|12@0+ (0.03125,-16) [-16|15] "" FLC_ME_FD6
 SG_ SRR_RR_ObjHeading_10 : 284|12@0+ (0.1,-180) [-180|180] "" FLC_ME_FD6
 SG_ SRR_RR_ObjBoxCenterLgt_10 : 288|9@0+ (0.1,-25) [-25|25] "" FLC_ME_FD6
 SG_ SRR_RR_ObjBoxCenterLat_10 : 311|9@0+ (0.1,-25) [-25|25] "" FLC_ME_FD6
 SG_ SRR_RR_ObjBoxLength_10 : 318|9@0+ (0.1,0) [0|50] "" FLC_ME_FD6
 SG_ SRR_RR_ObjBoxWidth_10 : 325|9@0+ (0.1,0) [0|50] "" FLC_ME_FD6
 SG_ SRR_RR_ObjDyStdDe_10 : 332|8@0+ (0.05,0) [0|12.7] "" FLC_ME_FD6
 SG_ SRR_RR_ObjDxStdDe_10 : 340|8@0+ (0.05,0) [0|12.7] "" FLC_ME_FD6
 SG_ SRR_RR_ObjVyStdDe_10 : 358|6@0+ (0.05,0) [0|2] "" FLC_ME_FD6
 SG_ SRR_RR_ObjVxStdDe_10 : 348|6@0+ (0.05,0) [0|2] "" FLC_ME_FD6
 SG_ SRR_RR_ObjMtnPat_10 : 364|3@0+ (1,0) [0|7] "" FLC_ME_FD6
 SG_ SRR_RR_ObjTyp_10 : 367|3@0+ (1,0) [0|7] "" FLC_ME_FD6
 SG_ SRR_RRObj5MsgCounter : 491|4@0+ (1,0) [0|15] "" FLC_ME_FD6
 SG_ SRR_RRObj5CRC16Checksum : 503|16@0+ (1,0) [0|65535] "" FLC_ME_FD6

BO_ 840 SRR_RR_SGUObjPos_6: 64 SRR4
 SG_ SRR_RR_ObjID_11 : 7|8@0+ (1,0) [0|255] "" FLC_ME_FD6
 SG_ SRR_RR_ObjConf_11 : 15|6@0+ (0.015625,0) [0|0.984375] "" FLC_ME_FD6
 SG_ SRR_RR_ObjSNR_11 : 9|11@0+ (0.0625,0) [0|40] "" FLC_ME_FD6
 SG_ SRR_RR_ObjDistX_11 : 30|12@0+ (0.0625,-128) [-128|127] "" FLC_ME_FD6
 SG_ SRR_RR_ObjRelVelX_11 : 34|12@0+ (0.0625,-128) [-128|127] "" FLC_ME_FD6
 SG_ SRR_RR_ObjDistY_11 : 54|14@0+ (0.015625,-128) [-128|127] "" FLC_ME_FD6
 SG_ SRR_RR_ObjRelVelY_11 : 56|12@0+ (0.0625,-128) [-128|127] "" FLC_ME_FD6
 SG_ SRR_RR_ObjAccelX_11 : 76|12@0+ (0.03125,-16) [-16|15] "" FLC_ME_FD6
 SG_ SRR_RR_ObjAccelY_11 : 80|12@0+ (0.03125,-16) [-16|15] "" FLC_ME_FD6
 SG_ SRR_RR_ObjHeading_11 : 100|12@0+ (0.1,-180) [-180|180] "" FLC_ME_FD6
 SG_ SRR_RR_ObjBoxCenterLgt_11 : 104|9@0+ (0.1,-25) [-25|25] "" FLC_ME_FD6
 SG_ SRR_RR_ObjBoxCenterLat_11 : 127|9@0+ (0.1,-25) [-25|25] "" FLC_ME_FD6
 SG_ SRR_RR_ObjBoxLength_11 : 134|9@0+ (0.1,0) [0|50] "" FLC_ME_FD6
 SG_ SRR_RR_ObjBoxWidth_11 : 141|9@0+ (0.1,0) [0|50] "" FLC_ME_FD6
 SG_ SRR_RR_ObjDyStdDe_11 : 148|8@0+ (0.05,0) [0|12.7] "" FLC_ME_FD6
 SG_ SRR_RR_ObjDxStdDe_11 : 156|8@0+ (0.05,0) [0|12.7] "" FLC_ME_FD6
 SG_ SRR_RR_ObjVyStdDe_11 : 174|6@0+ (0.05,0) [0|2] "" FLC_ME_FD6
 SG_ SRR_RR_ObjVxStdDe_11 : 164|6@0+ (0.05,0) [0|2] "" FLC_ME_FD6
 SG_ SRR_RR_ObjMtnPat_11 : 180|3@0+ (1,0) [0|7] "" FLC_ME_FD6
 SG_ SRR_RR_ObjTyp_11 : 183|3@0+ (1,0) [0|7] "" FLC_ME_FD6
 SG_ SRR_RR_ObjID_12 : 191|8@0+ (1,0) [0|255] "" FLC_ME_FD6
 SG_ SRR_RR_ObjConf_12 : 199|6@0+ (0.015625,0) [0|0.984375] "" FLC_ME_FD6
 SG_ SRR_RR_ObjSNR_12 : 193|11@0+ (0.0625,0) [0|40] "" FLC_ME_FD6
 SG_ SRR_RR_ObjDistX_12 : 214|12@0+ (0.0625,-128) [-128|127] "" FLC_ME_FD6
 SG_ SRR_RR_ObjRelVelX_12 : 218|12@0+ (0.0625,-128) [-128|127] "" FLC_ME_FD6
 SG_ SRR_RR_ObjDistY_12 : 238|14@0+ (0.015625,-128) [-128|127] "" FLC_ME_FD6
 SG_ SRR_RR_ObjRelVelY_12 : 240|12@0+ (0.0625,-128) [-128|127] "" FLC_ME_FD6
 SG_ SRR_RR_ObjAccelX_12 : 260|12@0+ (0.03125,-16) [-16|15] "" FLC_ME_FD6
 SG_ SRR_RR_ObjAccelY_12 : 264|12@0+ (0.03125,-16) [-16|15] "" FLC_ME_FD6
 SG_ SRR_RR_ObjHeading_12 : 284|12@0+ (0.1,-180) [-180|180] "" FLC_ME_FD6
 SG_ SRR_RR_ObjBoxCenterLgt_12 : 288|9@0+ (0.1,-25) [-25|25] "" FLC_ME_FD6
 SG_ SRR_RR_ObjBoxCenterLat_12 : 311|9@0+ (0.1,-25) [-25|25] "" FLC_ME_FD6
 SG_ SRR_RR_ObjBoxLength_12 : 318|9@0+ (0.1,0) [0|50] "" FLC_ME_FD6
 SG_ SRR_RR_ObjBoxWidth_12 : 325|9@0+ (0.1,0) [0|50] "" FLC_ME_FD6
 SG_ SRR_RR_ObjDyStdDe_12 : 332|8@0+ (0.05,0) [0|12.7] "" FLC_ME_FD6
 SG_ SRR_RR_ObjDxStdDe_12 : 340|8@0+ (0.05,0) [0|12.7] "" FLC_ME_FD6
 SG_ SRR_RR_ObjVyStdDe_12 : 358|6@0+ (0.05,0) [0|2] "" FLC_ME_FD6
 SG_ SRR_RR_ObjVxStdDe_12 : 348|6@0+ (0.05,0) [0|2] "" FLC_ME_FD6
 SG_ SRR_RR_ObjMtnPat_12 : 364|3@0+ (1,0) [0|7] "" FLC_ME_FD6
 SG_ SRR_RR_ObjTyp_12 : 367|3@0+ (1,0) [0|7] "" FLC_ME_FD6
 SG_ SRR_RRObj6MsgCounter : 491|4@0+ (1,0) [0|15] "" FLC_ME_FD6
 SG_ SRR_RRObj6CRC16Checksum : 503|16@0+ (1,0) [0|65535] "" FLC_ME_FD6

BO_ 841 SRR_RR_SGUObjPos_7: 64 SRR4
 SG_ SRR_RR_ObjID_13 : 7|8@0+ (1,0) [0|255] "" FLC_ME_FD6
 SG_ SRR_RR_ObjConf_13 : 15|6@0+ (0.015625,0) [0|0.984375] "" FLC_ME_FD6
 SG_ SRR_RR_ObjSNR_13 : 9|11@0+ (0.0625,0) [0|40] "" FLC_ME_FD6
 SG_ SRR_RR_ObjDistX_13 : 30|12@0+ (0.0625,-128) [-128|127] "" FLC_ME_FD6
 SG_ SRR_RR_ObjRelVelX_13 : 34|12@0+ (0.0625,-128) [-128|127] "" FLC_ME_FD6
 SG_ SRR_RR_ObjDistY_13 : 54|14@0+ (0.015625,-128) [-128|127] "" FLC_ME_FD6
 SG_ SRR_RR_ObjRelVelY_13 : 56|12@0+ (0.0625,-128) [-128|127] "" FLC_ME_FD6
 SG_ SRR_RR_ObjAccelX_13 : 76|12@0+ (0.03125,-16) [-16|15] "" FLC_ME_FD6
 SG_ SRR_RR_ObjAccelY_13 : 80|12@0+ (0.03125,-16) [-16|15] "" FLC_ME_FD6
 SG_ SRR_RR_ObjHeading_13 : 100|12@0+ (0.1,-180) [-180|180] "" FLC_ME_FD6
 SG_ SRR_RR_ObjBoxCenterLgt_13 : 104|9@0+ (0.1,-25) [-25|25] "" FLC_ME_FD6
 SG_ SRR_RR_ObjBoxCenterLat_13 : 127|9@0+ (0.1,-25) [-25|25] "" FLC_ME_FD6
 SG_ SRR_RR_ObjBoxLength_13 : 134|9@0+ (0.1,0) [0|50] "" FLC_ME_FD6
 SG_ SRR_RR_ObjBoxWidth_13 : 141|9@0+ (0.1,0) [0|50] "" FLC_ME_FD6
 SG_ SRR_RR_ObjDyStdDe_13 : 148|8@0+ (0.05,0) [0|12.7] "" FLC_ME_FD6
 SG_ SRR_RR_ObjDxStdDe_13 : 156|8@0+ (0.05,0) [0|12.7] "" FLC_ME_FD6
 SG_ SRR_RR_ObjVyStdDe_13 : 174|6@0+ (0.05,0) [0|2] "" FLC_ME_FD6
 SG_ SRR_RR_ObjVxStdDe_13 : 164|6@0+ (0.05,0) [0|2] "" FLC_ME_FD6
 SG_ SRR_RR_ObjMtnPat_13 : 180|3@0+ (1,0) [0|7] "" FLC_ME_FD6
 SG_ SRR_RR_ObjTyp_13 : 183|3@0+ (1,0) [0|7] "" FLC_ME_FD6
 SG_ SRR_RR_ObjID_14 : 191|8@0+ (1,0) [0|255] "" FLC_ME_FD6
 SG_ SRR_RR_ObjConf_14 : 199|6@0+ (0.015625,0) [0|0.984375] "" FLC_ME_FD6
 SG_ SRR_RR_ObjSNR_14 : 193|11@0+ (0.0625,0) [0|40] "" FLC_ME_FD6
 SG_ SRR_RR_ObjDistX_14 : 214|12@0+ (0.0625,-128) [-128|127] "" FLC_ME_FD6
 SG_ SRR_RR_ObjRelVelX_14 : 218|12@0+ (0.0625,-128) [-128|127] "" FLC_ME_FD6
 SG_ SRR_RR_ObjDistY_14 : 238|14@0+ (0.015625,-128) [-128|127] "" FLC_ME_FD6
 SG_ SRR_RR_ObjRelVelY_14 : 240|12@0+ (0.0625,-128) [-128|127] "" FLC_ME_FD6
 SG_ SRR_RR_ObjAccelX_14 : 260|12@0+ (0.03125,-16) [-16|15] "" FLC_ME_FD6
 SG_ SRR_RR_ObjAccelY_14 : 264|12@0+ (0.03125,-16) [-16|15] "" FLC_ME_FD6
 SG_ SRR_RR_ObjHeading_14 : 284|12@0+ (0.1,-180) [-180|180] "" FLC_ME_FD6
 SG_ SRR_RR_ObjBoxCenterLgt_14 : 288|9@0+ (0.1,-25) [-25|25] "" FLC_ME_FD6
 SG_ SRR_RR_ObjBoxCenterLat_14 : 311|9@0+ (0.1,-25) [-25|25] "" FLC_ME_FD6
 SG_ SRR_RR_ObjBoxLength_14 : 318|9@0+ (0.1,0) [0|50] "" FLC_ME_FD6
 SG_ SRR_RR_ObjBoxWidth_14 : 325|9@0+ (0.1,0) [0|50] "" FLC_ME_FD6
 SG_ SRR_RR_ObjDyStdDe_14 : 332|8@0+ (0.05,0) [0|12.7] "" FLC_ME_FD6
 SG_ SRR_RR_ObjDxStdDe_14 : 340|8@0+ (0.05,0) [0|12.7] "" FLC_ME_FD6
 SG_ SRR_RR_ObjVyStdDe_14 : 358|6@0+ (0.05,0) [0|2] "" FLC_ME_FD6
 SG_ SRR_RR_ObjVxStdDe_14 : 348|6@0+ (0.05,0) [0|2] "" FLC_ME_FD6
 SG_ SRR_RR_ObjMtnPat_14 : 364|3@0+ (1,0) [0|7] "" FLC_ME_FD6
 SG_ SRR_RR_ObjTyp_14 : 367|3@0+ (1,0) [0|7] "" FLC_ME_FD6
 SG_ SRR_RRObj7MsgCounter : 491|4@0+ (1,0) [0|15] "" FLC_ME_FD6
 SG_ SRR_RRObj7CRC16Checksum : 503|16@0+ (1,0) [0|65535] "" FLC_ME_FD6

BO_ 848 SRR_RR_SGUObjPos_8: 64 SRR4
 SG_ SRR_RR_ObjID_15 : 7|8@0+ (1,0) [0|255] "" FLC_ME_FD6
 SG_ SRR_RR_ObjConf_15 : 15|6@0+ (0.015625,0) [0|0.984375] "" FLC_ME_FD6
 SG_ SRR_RR_ObjSNR_15 : 9|11@0+ (0.0625,0) [0|40] "" FLC_ME_FD6
 SG_ SRR_RR_ObjDistX_15 : 30|12@0+ (0.0625,-128) [-128|127] "" FLC_ME_FD6
 SG_ SRR_RR_ObjRelVelX_15 : 34|12@0+ (0.0625,-128) [-128|127] "" FLC_ME_FD6
 SG_ SRR_RR_ObjDistY_15 : 54|14@0+ (0.015625,-128) [-128|127] "" FLC_ME_FD6
 SG_ SRR_RR_ObjRelVelY_15 : 56|12@0+ (0.0625,-128) [-128|127] "" FLC_ME_FD6
 SG_ SRR_RR_ObjAccelX_15 : 76|12@0+ (0.03125,-16) [-16|15] "" FLC_ME_FD6
 SG_ SRR_RR_ObjAccelY_15 : 80|12@0+ (0.03125,-16) [-16|15] "" FLC_ME_FD6
 SG_ SRR_RR_ObjHeading_15 : 100|12@0+ (0.1,-180) [-180|180] "" FLC_ME_FD6
 SG_ SRR_RR_ObjBoxCenterLgt_15 : 104|9@0+ (0.1,-25) [-25|25] "" FLC_ME_FD6
 SG_ SRR_RR_ObjBoxCenterLat_15 : 127|9@0+ (0.1,-25) [-25|25] "" FLC_ME_FD6
 SG_ SRR_RR_ObjBoxLength_15 : 134|9@0+ (0.1,0) [0|50] "" FLC_ME_FD6
 SG_ SRR_RR_ObjBoxWidth_15 : 141|9@0+ (0.1,0) [0|50] "" FLC_ME_FD6
 SG_ SRR_RR_ObjDyStdDe_15 : 148|8@0+ (0.05,0) [0|12.7] "" FLC_ME_FD6
 SG_ SRR_RR_ObjDxStdDe_15 : 156|8@0+ (0.05,0) [0|12.7] "" FLC_ME_FD6
 SG_ SRR_RR_ObjVyStdDe_15 : 174|6@0+ (0.05,0) [0|2] "" FLC_ME_FD6
 SG_ SRR_RR_ObjVxStdDe_15 : 164|6@0+ (0.05,0) [0|2] "" FLC_ME_FD6
 SG_ SRR_RR_ObjMtnPat_15 : 180|3@0+ (1,0) [0|7] "" FLC_ME_FD6
 SG_ SRR_RR_ObjTyp_15 : 183|3@0+ (1,0) [0|7] "" FLC_ME_FD6
 SG_ SRR_RR_ObjID_16 : 191|8@0+ (1,0) [0|255] "" FLC_ME_FD6
 SG_ SRR_RR_ObjConf_16 : 199|6@0+ (0.015625,0) [0|0.984375] "" FLC_ME_FD6
 SG_ SRR_RR_ObjSNR_16 : 193|11@0+ (0.0625,0) [0|40] "" FLC_ME_FD6
 SG_ SRR_RR_ObjDistX_16 : 214|12@0+ (0.0625,-128) [-128|127] "" FLC_ME_FD6
 SG_ SRR_RR_ObjRelVelX_16 : 218|12@0+ (0.0625,-128) [-128|127] "" FLC_ME_FD6
 SG_ SRR_RR_ObjDistY_16 : 238|14@0+ (0.015625,-128) [-128|127] "" FLC_ME_FD6
 SG_ SRR_RR_ObjRelVelY_16 : 240|12@0+ (0.0625,-128) [-128|127] "" FLC_ME_FD6
 SG_ SRR_RR_ObjAccelX_16 : 260|12@0+ (0.03125,-16) [-16|15] "" FLC_ME_FD6
 SG_ SRR_RR_ObjAccelY_16 : 264|12@0+ (0.03125,-16) [-16|15] "" FLC_ME_FD6
 SG_ SRR_RR_ObjHeading_16 : 284|12@0+ (0.1,-180) [-180|180] "" FLC_ME_FD6
 SG_ SRR_RR_ObjBoxCenterLgt_16 : 288|9@0+ (0.1,-25) [-25|25] "" FLC_ME_FD6
 SG_ SRR_RR_ObjBoxCenterLat_16 : 311|9@0+ (0.1,-25) [-25|25] "" FLC_ME_FD6
 SG_ SRR_RR_ObjBoxLength_16 : 318|9@0+ (0.1,0) [0|50] "" FLC_ME_FD6
 SG_ SRR_RR_ObjBoxWidth_16 : 325|9@0+ (0.1,0) [0|50] "" FLC_ME_FD6
 SG_ SRR_RR_ObjDyStdDe_16 : 332|8@0+ (0.05,0) [0|12.7] "" FLC_ME_FD6
 SG_ SRR_RR_ObjDxStdDe_16 : 340|8@0+ (0.05,0) [0|12.7] "" FLC_ME_FD6
 SG_ SRR_RR_ObjVyStdDe_16 : 358|6@0+ (0.05,0) [0|2] "" FLC_ME_FD6
 SG_ SRR_RR_ObjVxStdDe_16 : 348|6@0+ (0.05,0) [0|2] "" FLC_ME_FD6
 SG_ SRR_RR_ObjMtnPat_16 : 364|3@0+ (1,0) [0|7] "" FLC_ME_FD6
 SG_ SRR_RR_ObjTyp_16 : 367|3@0+ (1,0) [0|7] "" FLC_ME_FD6
 SG_ SRR_RRObj8MsgCounter : 491|4@0+ (1,0) [0|15] "" FLC_ME_FD6
 SG_ SRR_RRObj8CRC16Checksum : 503|16@0+ (1,0) [0|65535] "" FLC_ME_FD6

BO_ 529 ACU_Fr03_211: 8 ACU
 SG_ ACU3_Delta_Vx_0 : 7|8@0+ (1,-127) [-100|100] "kph" GW_FD5,TBOX_OverSea
 SG_ ACU3_Delta_Vx_1 : 15|8@0+ (1,-127) [-100|100] "kph" GW_FD5,TBOX_OverSea
 SG_ ACU3_Delta_Vx_2 : 23|8@0+ (1,-127) [-100|100] "kph" GW_FD5,TBOX_OverSea
 SG_ ACU3_Delta_Vx_3 : 31|8@0+ (1,-127) [-100|100] "kph" GW_FD5,TBOX_OverSea
 SG_ ACU3_Delta_Vx_4 : 39|8@0+ (1,-127) [-100|100] "kph" GW_FD5,TBOX_OverSea
 SG_ ACU3_Delta_Vx_5 : 47|8@0+ (1,-127) [-100|100] "kph" GW_FD5,TBOX_OverSea
 SG_ ACU3_MsgCounter : 51|4@0+ (1,0) [0|15] "NoUnit" GW_FD5,TBOX_OverSea
 SG_ ACU3_DVx_Index : 55|4@0+ (1,0) [0|15] "NoUnit" GW_FD5,TBOX_OverSea
 SG_ ACU3_Checksum : 63|8@0+ (1,0) [0|255] "NoUnit" GW_FD5,TBOX_OverSea

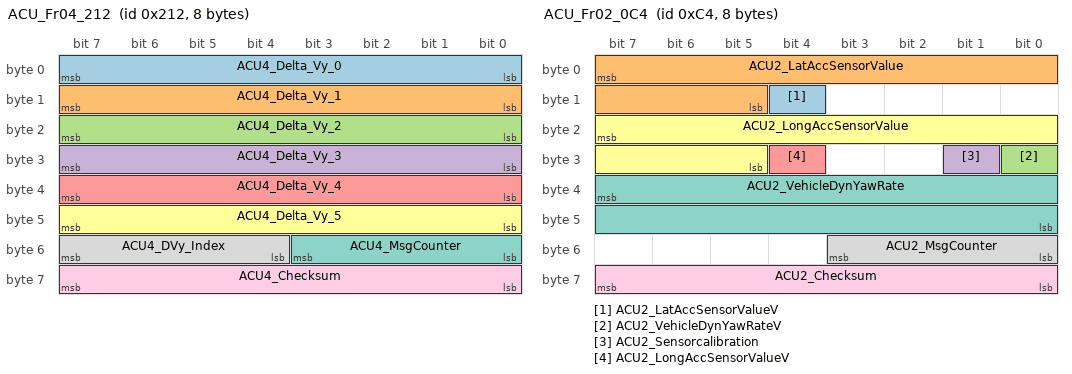
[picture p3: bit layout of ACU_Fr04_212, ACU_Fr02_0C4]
BO_ 530 ACU_Fr04_212: 8 ACU
 SG_ ACU4_Delta_Vy_0 : 7|8@0+ (1,-127) [-100|100] "kph" GW_FD5,TBOX_OverSea
 SG_ ACU4_Delta_Vy_1 : 15|8@0+ (1,-127) [-100|100] "kph" GW_FD5,TBOX_OverSea
 SG_ ACU4_Delta_Vy_2 : 23|8@0+ (1,-127) [-100|100] "kph" GW_FD5,TBOX_OverSea
 SG_ ACU4_Delta_Vy_3 : 31|8@0+ (1,-127) [-100|100] "kph" GW_FD5,TBOX_OverSea
 SG_ ACU4_Delta_Vy_4 : 39|8@0+ (1,-127) [-100|100] "kph" GW_FD5,TBOX_OverSea
 SG_ ACU4_Delta_Vy_5 : 47|8@0+ (1,-127) [-100|100] "kph" GW_FD5,TBOX_OverSea
 SG_ ACU4_MsgCounter : 51|4@0+ (1,0) [0|15] "NoUnit" GW_FD5,TBOX_OverSea
 SG_ ACU4_DVy_Index : 55|4@0+ (1,0) [0|15] "NoUnit" GW_FD5,TBOX_OverSea
 SG_ ACU4_Checksum : 63|8@0+ (1,0) [0|255] "NoUnit" GW_FD5,TBOX_OverSea

BO_ 196 ACU_Fr02_0C4: 8 ACU
 SG_ ACU2_LatAccSensorValueV : 12|1@0+ (1,0) [0|1] "NoUnit" PDCS_FD1,IDB,SRR3,ESC_FD3,SRR4,ADCU_FD3,EHB_FD3,CDCS,ADCS_FD3,CDCS_OverSea,TBOX,FLC_ME_FD3,FLC_FD3,GW_FD5,GW_FD6,GW_FD3,ISC,GW_FD4,PDCS_HVM_FD1,TBOX_OverSea
 SG_ ACU2_LatAccSensorValue : 7|11@0+ (0.02,-16) [-16|16] "m/s2" PDCS_FD1,IDB,SRR3,ESC_FD3,SRR4,ADCU_FD3,EHB_FD3,CDCS,ADCS_FD3,CDCS_OverSea,TBOX,FLC_ME_FD3,FLC_FD3,GW_FD5,GW_FD6,GW_FD3,ISC,GW_FD4,PDCS_HVM_FD1,TBOX_OverSea
 SG_ ACU2_VehicleDynYawRateV : 24|1@0+ (1,0) [0|1] "NoUnit" PDCS_FD1,IDB,SRR3,ESC_FD3,SRR4,ADCU_FD3,EPS,EHB_FD3,CDCS,ADCS_FD3,CDCS_OverSea,TBOX,FLC_ME_FD3,FLC_FD3,GW_FD5,GW_FD6,GW_FD3,ISC,GW_FD4,PDCS_HVM_FD1,TBOX_OverSea
 SG_ ACU2_Sensorcalibration : 25|1@0+ (1,0) [0|1] "NoUnit" PDCS_FD1,IDB,SRR3,ESC_FD3,SRR4,ADCU_FD3,EHB_FD3,CDCS,ADCS_FD3,CDCS_OverSea,TBOX,FLC_ME_FD3,FLC_FD3,GW_FD5,GW_FD6,GW_FD3,ISC,GW_FD4,PDCS_HVM_FD1,TBOX_OverSea
 SG_ ACU2_LongAccSensorValueV : 28|1@0+ (1,0) [0|1] "NoUnit" PDCS_FD1,IDB,SRR3,ESC_FD3,SRR4,ADCU_FD3,EHB_FD3,CDCS,ADCS_FD3,CDCS_OverSea,TBOX,FLC_ME_FD3,FLC_FD3,GW_FD5,GW_FD6,GW_FD3,ISC,GW_FD4,PDCS_HVM_FD1,TBOX_OverSea
 SG_ ACU2_LongAccSensorValue : 23|11@0+ (0.02,-16) [-16|16] "m/s2" PDCS_FD1,IDB,SRR3,ESC_FD3,SRR4,ADCU_FD3,EHB_FD3,CDCS,ADCS_FD3,CDCS_OverSea,TBOX,FLC_ME_FD3,FLC_FD3,GW_FD5,GW_FD6,GW_FD3,ISC,GW_FD4,PDCS_HVM_FD1,TBOX_OverSea
 SG_ ACU2_VehicleDynYawRate : 39|16@0+ (0.01,-180) [-180|180] "deg/s" PDCS_FD1,IDB,SRR3,ESC_FD3,SRR4,ADCU_FD3,EPS,EHB_FD3,CDCS,ADCS_FD3,CDCS_OverSea,TBOX,FLC_ME_FD3,FLC_FD3,GW_FD5,GW_FD6,GW_FD3,ISC,GW_FD4,PDCS_HVM_FD1,TBOX_OverSea
 SG_ ACU2_MsgCounter : 51|4@0+ (1,0) [0|15] "NoUnit" PDCS_FD1,IDB,SRR3,ESC_FD3,SRR4,ADCU_FD3,EPS,EHB_FD3,ADCS_FD3,TBOX,FLC_ME_FD3,FLC_FD3,GW_FD5,GW_FD6,GW_FD3,ISC,PDCS_HVM_FD1,TBOX_OverSea
 SG_ ACU2_Checksum : 63|8@0+ (1,0) [0|255] "NoUnit" PDCS_FD1,IDB,SRR3,ESC_FD3,SRR4,ADCU_FD3,EPS,EHB_FD3,ADCS_FD3,TBOX,FLC_ME_FD3,FLC_FD3,GW_FD5,GW_FD6,GW_FD3,ISC,PDCS_HVM_FD1,TBOX_OverSea

BO_ 258 ACU_Fr01_102: 8 ACU
 SG_ ACU1_Driver_Buckle : 1|2@0+ (1,0) [0|3] "NoUnit" PDCS_FD1,IDB,ESC_FD3,ADCU_FD3,EHB_FD3,BDCS,CDCS,ADCS_FD3,CDCS_OverSea,TBOX,FLC_ME_FD3,FLC_FD3,GW_FD5,ICU_E02,GW_FD3,GW_FD4,ICU,GW_FD2,PDCS_HVM_FD1,TBOX_OverSea
 SG_ ACU1_Passenger_Buckle : 3|2@0+ (1,0) [0|3] "NoUnit" PDCS_FD1,IDB,ADCU_FD3,CDCS,ADCS_FD3,CDCS_OverSea,TBOX,FLC_ME_FD3,FLC_FD3,GW_FD5,ICU_E02,GW_FD3,GW_FD4,ICU,PDCS_HVM_FD1,TBOX_OverSea
 SG_ ACU1_PAB_State : 7|1@0+ (1,0) [0|1] "NoUnit" GW_FD4,CDCS_OverSea
 SG_ ACU1_Passenger_ODS : 11|2@0+ (1,0) [0|3] "NoUnit" ADCU_FD3,BDCS,CDCS,ADCS_FD3,CDCS_OverSea,TBOX,FLC_ME_FD3,FLC_FD3,GW_FD5,ICU_E02,GW_FD3,GW_FD4,ICU,GW_FD2,TBOX_OverSea
 SG_ ACU1_CrashStatus : 12|1@0+ (1,0) [0|1] "NoUnit" PDCS_FD1,PDCU,IDB,ADCU_FD3,BMS,EMS,BDCS,DDCU,CDCS,ADCS_FD3,CDCS_OverSea,TBOX,FLC_ME_FD3,FLC_FD3,GW_FD5,GW_FD3,GW_FD4,GW_FD2,MCU,PDCS_HVM_FD1,TBOX_OverSea
 SG_ ACU1_warningLight : 14|2@0+ (1,0) [0|3] "NoUnit" ADCU_FD3,BDCS,CDCS,ADCS_FD3,CDCS_OverSea,TBOX,FLC_ME_FD3,FLC_FD3,GW_FD5,ICU_E02,GW_FD3,GW_FD4,ICU,GW_FD2,TBOX_OverSea
 SG_ ACU1_Rear_Left_ODS : 17|2@0+ (1,0) [0|3] "NoUnit" ADCU_FD3,BDCS,CDCS,ADCS_FD3,CDCS_OverSea,TBOX,FLC_FD3,GW_FD5,ICU_E02,GW_FD3,GW_FD4,ICU,GW_FD2,TBOX_OverSea
 SG_ ACU1_Rear_Left_BuckleSts_Logic : 20|3@0+ (1,0) [0|7] "NoUnit" ADCU_FD3,BDCS,CDCS,ADCS_FD3,CDCS_OverSea,TBOX,FLC_FD3,GW_FD5,ICU_E02,GW_FD3,GW_FD4,ICU,GW_FD2,TBOX_OverSea
 SG_ ACU1_Rear_Right_Buckle : 23|3@0+ (1,0) [0|7] "NoUnit" TBOX,FLC_ME_FD3,FLC_FD3,GW_FD5,ICU_E02,GW_FD3,ADCU_FD3,GW_FD4,ICU,ADCS_FD3,TBOX_OverSea
 SG_ ACU1_Rear_Left_Buckle : 26|3@0+ (1,0) [0|7] "NoUnit" TBOX,FLC_ME_FD3,FLC_FD3,GW_FD5,ICU_E02,GW_FD3,ADCU_FD3,GW_FD4,ICU,ADCS_FD3,TBOX_OverSea
 SG_ ACU1_Rear_Middle_Buckle : 29|3@0+ (1,0) [0|7] "NoUnit" TBOX,FLC_ME_FD3,FLC_FD3,GW_FD5,ICU_E02,GW_FD3,ADCU_FD3,GW_FD4,ICU,ADCS_FD3,TBOX_OverSea
 SG_ ACU1_Rear_Middle_ODS : 31|2@0+ (1,0) [0|3] "NoUnit" ADCU_FD3,BDCS,CDCS,ADCS_FD3,CDCS_OverSea,TBOX,FLC_FD3,GW_FD5,ICU_E02,GW_FD3,GW_FD4,ICU,GW_FD2,TBOX_OverSea
 SG_ ACU1_Rear_Midlle_BuckleSts_Logic : 34|3@0+ (1,0) [0|7] "NoUnit" ADCU_FD3,BDCS,CDCS,ADCS_FD3,CDCS_OverSea,TBOX,FLC_FD3,GW_FD5,ICU_E02,GW_FD3,GW_FD4,ICU,GW_FD2,TBOX_OverSea
 SG_ ACU1_Rear_Right_ODS : 36|2@0+ (1,0) [0|3] "NoUnit" ADCU_FD3,BDCS,CDCS,ADCS_FD3,CDCS_OverSea,TBOX,FLC_FD3,GW_FD5,ICU_E02,GW_FD3,GW_FD4,ICU,GW_FD2,TBOX_OverSea
 SG_ ACU1_Rear_Right_BuckleSts_Logic : 39|3@0+ (1,0) [0|7] "NoUnit" ADCU_FD3,BDCS,CDCS,ADCS_FD3,CDCS_OverSea,TBOX,FLC_FD3,GW_FD5,ICU_E02,GW_FD3,GW_FD4,ICU,GW_FD2,TBOX_OverSea
 SG_ ACU1_CrashType : 47|8@0+ (1,0) [0|255] "NoUnit" TBOX,GW_FD5,TBOX_OverSea
 SG_ ACU1_MsgCounter : 51|4@0+ (1,0) [0|15] "NoUnit" PDCS_FD1,IDB,ESC_FD3,BMS,EMS,EHB_FD3,CDCS,CDCS_OverSea,TBOX,GW_FD5,ICU_E02,GW_FD3,GW_FD4,ICU,MCU,PDCS_HVM_FD1,TBOX_OverSea
 SG_ ACU1_Checksum : 63|8@0+ (1,0) [0|255] "NoUnit" PDCS_FD1,IDB,ESC_FD3,BMS,EMS,EHB_FD3,CDCS,CDCS_OverSea,TBOX,GW_FD5,ICU_E02,GW_FD3,GW_FD4,ICU,MCU,PDCS_HVM_FD1,TBOX_OverSea

BO_TX_BU_ 528 : ADCU_FD3,ADCS_FD3;
BO_TX_BU_ 613 : ADCU_FD3,ADCS_FD3;
BO_TX_BU_ 984 : ADCU_FD3,ADCS_FD3;
BO_TX_BU_ 1556 : FLC_ME_FD3,FLC_FD3;
CM_ BO_ 842 "欧盟小批量智驾FLC_ME平台方案报文";
CM_ BO_ 843 "欧盟小批量智驾FLC_ME平台方案报文";
CM_ BO_ 822 "报文触发报警功能后按照50ms周期发送";
CM_ BO_ 529 "纵向Delta_Vx";
CM_ BO_ 530 "横向Delta_Vy";
CM_ SG_ 528 ADCS9_AVM_MODdetectionSts "MOD状态";
CM_ SG_ 528 ADCS9_AVM_TransparentchassisSts "透明底盘状态";
CM_ SG_ 528 ADCS9_PA_FRS_Onoffset "反馈前雷达开关信号";
CM_ SG_ 528 ADCS9_AVM_Diaphaneity "透明度反馈";
CM_ SG_ 528 ADCS9_AVM_startMode "ADCS记忆设置";
CM_ SG_ 528 ADCS9_CDCS_CertificateState "PKI证书状态(泊车)";
CM_ SG_ 528 ADCS9_AVMFrontCAMFault "前环视摄像头故障";
CM_ SG_ 528 ADCS9_AVMLeftCAMFault "左环视摄像头故障";
CM_ SG_ 528 ADCS9_AVMRightCAMFault "右环视摄像头故障";
CM_ SG_ 528 ADCS9_AVMRearCAMFault "后环视摄像头故障";
CM_ SG_ 528 ADCS9_HPA_OnOffSetSts "记忆泊车功能开关状态反馈";
CM_ SG_ 528 ADCS9_AVM_InitializationSts "初始化设置功能状态";
CM_ SG_ 528 ADCS9_AVM_bodySyncSts "车身信息同步功能状态";
CM_ SG_ 528 ADCS9_HPA_CrossingNumber "记忆泊车经过路口数显示信号";
CM_ SG_ 528 ADCS9_AVM_3DRotateSts "3D旋转动画功能状态";
CM_ SG_ 528 ADCS9_AVM_TurnlightstartSts "转向灯开启全景功能状态";
CM_ SG_ 528 ADCS9_AVM_SteeringstartSts "转向角开启全景功能状态";
CM_ SG_ 528 ADCS9_AVM_MagnifiedviewSts "自动放大视角开关功能状态";
CM_ SG_ 528 ADCS9_AVM_auxiliarylineSts "辅助线功能状态";
CM_ SG_ 528 ADCS9_AVM_RaderdisplaySts "雷达显示功能状态";
CM_ SG_ 528 ADCS9_AVM_LowSpeedBSDSts "低速BSD功能状态";
CM_ SG_ 528 ADCS9_AVM_SpeViewSts "特殊视角功能状态";
CM_ SG_ 613 ADCS1_CarMdlDispSts "360全景2D、3D模式反馈";
CM_ SG_ 613 ADCS1_GuidOvlDispSts "360全景轨迹线显示方式";
CM_ SG_ 613 ADCS1_MOD_WorkSts "360低速移动物体探测工作状态";
CM_ SG_ 613 ADCS1_MOD_AlarmSts "360低速移动物体警告";
CM_ SG_ 613 ADCS1_CarMdlTrsprcySts "360透明底盘显示模式";
CM_ SG_ 613 ADCS1_AutoViewChgFuncSts "360智能视角模式状态反馈";
CM_ SG_ 613 ADCS1_SigViewIndcn "360前后左右视角";
CM_ SG_ 613 ADCS1_AutoAVMSwtSet_Sts "360转向开启功能状态";
CM_ SG_ 984 ADCS_Resp_EncrData0 "ADCS控制身份认证响应0";
CM_ SG_ 984 ADCS_Resp_EncrData1 "ADCS控制身份认证响应1";
CM_ SG_ 984 ADCS_Resp_EncrData2 "ADCS控制身份认证响应2";
CM_ SG_ 984 ADCS_Resp_EncrData3 "ADCS控制身份认证响应3";
CM_ SG_ 984 ADCS_Resp_EncrData4 "ADCS控制身份认证响应4";
CM_ SG_ 984 ADCS_Resp_EncrData5 "ADCS控制身份认证响应5";
CM_ SG_ 984 ADCS_Resp_EncrData6 "ADCS控制身份认证响应6";
CM_ SG_ 984 ADCS_Resp_EncrData7 "ADCS控制身份认证响应7";
CM_ SG_ 597 ADCS13_HPA_ONPath_ID1 "记忆泊车当前车辆所在路线ID1";
CM_ SG_ 597 ADCS13_HPA_ONPath_ID2 "记忆泊车当前车辆所在路线ID2";
CM_ SG_ 597 ADCS13_HPA_ONPath_ID3 "记忆泊车当前车辆所在路线ID3";
CM_ SG_ 597 ADCS13_HPA_ONPath_ID4 "记忆泊车当前车辆所在路线ID4";
CM_ SG_ 842 FLC_RlvTgt01_heading "本车道目标01朝向角";
CM_ SG_ 842 FLC_SRObject_RlvTgt01Detn "本车道内识别第一目标的状态";
CM_ SG_ 842 FLC_SRObject_RlvTgt01Typ "本车道内识别第一目标的类型";
CM_ SG_ 842 FLC_SRObject_RlvTgt01Dx "本车道内识别第一目标的纵向距离Dx";
CM_ SG_ 842 FLC_RlvTgt02_heading "本车道目标02朝向角";
CM_ SG_ 842 FLC_SRObject_RlvTgt01Dy "本车道内识别第一目标的横向距离Dy";
CM_ SG_ 842 FLC_SRObject_LeTgt02Typ "左侧车道内识别第二目标的类型";
CM_ SG_ 842 FLC_SRObject_RlvTgt02Detn "本车道内识别第二目标的状态";
CM_ SG_ 842 FLC_SRObject_RlvTgt02Dx "本车道内识别第二目标的纵向距离Dx";
CM_ SG_ 842 FLC_RiTgt01_heading "右车道目标01朝向角";
CM_ SG_ 842 FLC_SRObject_RlvTgt02Dy "本车道内识别第二目标的横向距离Dy";
CM_ SG_ 842 FLC_SRObject_RlvTgt02Typ "本车道内识别第二目标的类型";
CM_ SG_ 842 FLC_SRObject_RiTgt01Detn "右侧车道内识别第一目标的状态";
CM_ SG_ 842 FLC_SRObject_RiTgt01Dx "右侧车道内识别第一目标的纵向距离Dx";
CM_ SG_ 842 FLC_RiTgt02_heading "右车道目标02朝向角";
CM_ SG_ 842 FLC_SRObject_RiTgt01Dy "右侧车道内识别第一目标的横向距离Dy";
CM_ SG_ 842 FLC_SRObject_RiTgt01Typ "右侧车道内识别第一目标的类型";
CM_ SG_ 842 FLC_SRObject_RiTgt02Detn "右侧车道内识别第二目标的状态";
CM_ SG_ 842 FLC_SRObject_RiTgt02Dx "右侧车道内识别第二目标的纵向距离Dx";
CM_ SG_ 842 FLC_LeTgt01_heading "左车道目标01朝向角";
CM_ SG_ 842 FLC_SRObject_RiTgt02Dy "右侧车道内识别第二目标的横向距离Dy";
CM_ SG_ 842 FLC_SRObject_RiTgt02Typ "右侧车道内识别第二目标的类型";
CM_ SG_ 842 FLC_SRObject_LeTgt01Detn "左侧车道内识别第一目标的状态";
CM_ SG_ 842 FLC_SRObject_LeTgt01Dx "左侧车道内识别第一目标的纵向距离Dx";
CM_ SG_ 842 FLC_LeTgt02_heading "左车道目标02朝向角";
CM_ SG_ 842 FLC_SRObject_LeTgt01Dy "左侧车道内识别第一目标的横向距离Dy";
CM_ SG_ 842 FLC_SRObject_LeTgt01Typ "左侧车道内识别第一目标的类型";
CM_ SG_ 842 FLC_SRObject_LeTgt02Detn "左侧车道内识别第二目标的状态";
CM_ SG_ 842 FLC_SRObject_LeTgt02Dx "左侧车道内识别第二目标的纵向距离Dx";
CM_ SG_ 842 FLC_SRObject_LeTgt02Dy "左侧车道内识别第二目标的横向距离Dy";
CM_ SG_ 843 FLC_LeftLane_C0 "左车道线的方程参数C0";
CM_ SG_ 843 FLC_RightLane_C0 "右车道线的方程参数C0";
CM_ SG_ 843 FLC_NextLeftLane_C0 "左左车道线的方程参数C0";
CM_ SG_ 843 FLC_NextRightLane_C0 "右右车道线的方程参数C0";
CM_ SG_ 843 FLC_NextLeftLane_C1 "左左车道线方程参数";
CM_ SG_ 843 FLC_NextLeftLane_C2 "左左车道线方程参数";
CM_ SG_ 843 FLC_NextLeftLane_C3 "左左车道线方程参数";
CM_ SG_ 843 FLC_NextRightLane_C1 "右右车道线方程参数";
CM_ SG_ 843 FLC_NextRightLane_C2 "右右车道线方程参数";
CM_ SG_ 843 FLC_NextRightLane_C3 "右右车道线方程参数";
CM_ SG_ 843 FLC_LeftLane_C1 "左车道线方程参数";
CM_ SG_ 843 FLC_LeftLane_C2 "左车道线方程参数";
CM_ SG_ 843 FLC_LeftLane_C3 "左车道线方程参数";
CM_ SG_ 843 FLC_RightLane_C1 "右车道线方程参数";
CM_ SG_ 843 FLC_RightLane_C2 "右车道线方程参数";
CM_ SG_ 843 FLC_RightLane_C3 "右车道线方程参数";
CM_ SG_ 843 FLC_NextRightLane_Type "识别相邻右侧车道线的类型";
CM_ SG_ 843 FLC_NextRightLane_DxStart "识别相邻右侧车道线的纵向距离起始位置";
CM_ SG_ 843 FLC_NextRightLane_DxEnd "识别相邻右侧车道线的纵向距离结束位置";
CM_ SG_ 843 FLC_RightLane_Type "识别右侧车道线的类型";
CM_ SG_ 843 FLC_RightLane_DxStart "识别右侧车道线的纵向距离起始位置";
CM_ SG_ 843 FLC_RightLane_DxEnd "识别右侧车道线的纵向距离结束位置";
CM_ SG_ 843 FLC_LeftLane_Type "识别左侧车道线的类型";
CM_ SG_ 843 FLC_LeftLane_DxStart "识别左侧车道线的纵向距离起始位置";
CM_ SG_ 843 FLC_LeftLane_DxEnd "识别左侧车道线的纵向距离结束位置";
CM_ SG_ 843 FLC_NextLeftLane_Type "识别相邻左侧车道线的类型";
CM_ SG_ 843 FLC_NextLeftLane_DxStart "识别相邻左侧车道线的纵向距离起始位置";
CM_ SG_ 843 FLC_NextLeftLane_DxEnd "识别相邻左侧车道线的纵向距离结束位置";
CM_ SG_ 1543 ADCS_SourceNodeIdentifier "ECU节点标识符";
CM_ SG_ 1543 ADCS_RepeatMessageRequest "Repeat Message请求";
CM_ SG_ 1543 ADCS_Reserve1 "预留";
CM_ SG_ 1543 ADCS_ActiveWakeup "激活唤醒，主动唤醒网络时置1，其他（包括被动唤醒节点）为0";
CM_ SG_ 1543 ADCS_Reserve2 "预留";
CM_ SG_ 1543 ADCS_WakeUp_KL15 "KL15 ON唤醒";
CM_ SG_ 1543 ADCS_WakeUp_NM "NM报文唤醒";
CM_ SG_ 1543 ADCS_WakeUp_GM "哨兵模式唤醒";
CM_ SG_ 1543 ADCS_WakeUpReason4 "网络唤醒原因4";
CM_ SG_ 1543 ADCS_WakeUpReason5 "网络唤醒原因5";
CM_ SG_ 1543 ADCS_WakeUpReason6 "网络唤醒原因6";
CM_ SG_ 1543 ADCS_WakeUpReason7 "网络唤醒原因7";
CM_ SG_ 1543 ADCS_WakeUpReason8 "网络唤醒原因8";
CM_ SG_ 1543 ADCS_RNM_DOW "DOW功能，需整车延迟休眠3min";
CM_ SG_ 1543 ADCS_RNM_GM "哨兵模式";
CM_ SG_ 1543 ADCS_RNM_ICS "智能寻车";
CM_ SG_ 1543 ADCS_RNM_RPA "遥控泊车";
CM_ SG_ 1543 ADCS_RNM_ISM "智能召唤";
CM_ SG_ 1557 ADCU_SourceNodeIdentifier "ECU节点标识符";
CM_ SG_ 1557 ADCU_RepeatMessageRequest "Repeat Message请求";
CM_ SG_ 1557 ADCU_Reserve1 "预留";
CM_ SG_ 1557 ADCU_ActiveWakeup "激活唤醒，主动唤醒网络时置1，其他（包括被动唤醒节点）为0";
CM_ SG_ 1557 ADCU_Reserve2 "预留";
CM_ SG_ 1557 ADCU_WakeUp_KL15 "KL15 ON唤醒";
CM_ SG_ 1557 ADCU_WakeUp_NM "NM报文唤醒";
CM_ SG_ 1557 ADCU_WakeUp_GM "哨兵模式唤醒";
CM_ SG_ 1557 ADCU_WakeUpReason4 "网络唤醒原因4";
CM_ SG_ 1557 ADCU_WakeUpReason5 "网络唤醒原因5";
CM_ SG_ 1557 ADCU_WakeUpReason6 "网络唤醒原因6";
CM_ SG_ 1557 ADCU_WakeUpReason7 "网络唤醒原因7";
CM_ SG_ 1557 ADCU_WakeUpReason8 "网络唤醒原因8";
CM_ SG_ 1557 ADCU_RNM_GM "哨兵模式";
CM_ SG_ 1557 ADCU_RNM_ICS "智能寻车";
CM_ SG_ 1557 ADCU_RNM_RPA "遥控泊车";
CM_ SG_ 1557 ADCU_RNM_ISM "智能召唤";
CM_ SG_ 1556 FLC_SourceNodeIdentifier "ECU节点标识符";
CM_ SG_ 1556 FLC_RepeatMessageRequest "Repeat Message请求";
CM_ SG_ 1556 FLC_Reserve1 "预留";
CM_ SG_ 1556 FLC_ActiveWakeup "激活唤醒，主动唤醒网络时置1，其他（包括被动唤醒节点）为0";
CM_ SG_ 1556 FLC_Reserve2 "预留";
CM_ SG_ 1556 FLC_WakeUp_KL15 "KL15 ON唤醒";
CM_ SG_ 1556 FLC_WakeUp_NM "NM报文唤醒";
CM_ SG_ 1556 FLC_WakeUpReason4 "网络唤醒原因4";
CM_ SG_ 1556 FLC_WakeUpReason5 "网络唤醒原因5";
CM_ SG_ 1556 FLC_WakeUpReason6 "网络唤醒原因6";
CM_ SG_ 1556 FLC_WakeUpReason7 "网络唤醒原因7";
CM_ SG_ 1556 FLC_WakeUpReason8 "网络唤醒原因8";
CM_ SG_ 1556 FLC_RNM_DOW "DOW功能，需整车延迟休眠3min";
CM_ SG_ 615 INS_GpsWeek "GPS周";
CM_ SG_ 615 INS_GpsTime "GPS周内秒，s";
CM_ SG_ 615 INS_E2eCounter "E2E Profile2-CRC8H2F，Counter:0-15";
CM_ SG_ 615 INS_Received "预留";
CM_ SG_ 615 INS_E2eCRC "E2E Profile2-CRC8H2F
DataID List:#22:23 11 188 245 202 204 151 53 110 34 129 92 51 2 196 121";
CM_ SG_ 615 INS_VelE "东向速度，m/s";
CM_ SG_ 615 INS_VelN "北向速度，m/s";
CM_ SG_ 615 INS_VelU "天向速度，m/s";
CM_ SG_ 615 INS_Pitch "俯仰角，deg";
CM_ SG_ 615 INS_Roll "横滚角，deg";
CM_ SG_ 615 INS_Yaw "航向角，deg";
CM_ SG_ 615 INS_StdVelE "东向速度标准差，m/s";
CM_ SG_ 615 INS_StdVelN "北向速度标准差，m/s";
CM_ SG_ 615 INS_StdVelU "天向速度标准差，m/s";
CM_ SG_ 615 INS_StdPitch "俯仰角标准差，deg";
CM_ SG_ 615 INS_StdRoll "横滚角标准差，deg";
CM_ SG_ 615 INS_StdYaw "航向角标准差，deg";
CM_ SG_ 615 INS_StatIns "组合状态";
CM_ SG_ 615 INS_StatPos "定位状态";
CM_ SG_ 772 IMU_GPGGA_size "单包数据的大小";
CM_ SG_ 772 IMU_GPGGA_num_total "分包总数";
CM_ SG_ 772 IMU_GPGGA_num "第几个分包";
CM_ SG_ 772 IMU_GPGGA_Reserved "预留位";
CM_ SG_ 772 IMU_GPGGA_data "数据";
CM_ SG_ 1376 calibration_progress "标定进度";
CM_ SG_ 1376 satellite_used_num "搜星数";
CM_ SG_ 1376 stat_pos "定位状态";
CM_ SG_ 1376 stat_ins "组合状态";
CM_ SG_ 1376 antenes_status "天线状态";
CM_ SG_ 1376 diff_Age "差分龄期，s";
CM_ SG_ 1376 BD_CN_L1 "BDL1信噪比";
CM_ SG_ 1376 BD_CN_L5 "BDL5信噪比";
CM_ SG_ 1376 GAL_CN_L5 "GAL5信噪比";
CM_ SG_ 1376 GAL_CN_L1 "GAL1信噪比";
CM_ SG_ 1376 GPS_CN_L1 "GPS1信噪比";
CM_ SG_ 1376 CalibrationFailReason "标定失败原因";
CM_ SG_ 1376 GPS_CN_L5 "GPS5信噪比";
CM_ SG_ 1376 satellite_visible_num "使用卫星数";
CM_ SG_ 1376 differential_status "差分状态";
CM_ SG_ 1376 Base1005_lost "1005基站数据丢失";
CM_ SG_ 1376 Base1005_CoordinatesWrong "1005基站坐标错误";
CM_ SG_ 1585 IMU_SourceNodeIdentifier "ECU节点标识符";
CM_ SG_ 1585 IMU_RepeatMessageRequest "Repeat Message请求";
CM_ SG_ 1585 IMU_Reserve1 "预留";
CM_ SG_ 1585 IMU_ActiveWakeup "激活唤醒，主动唤醒网络时置1，其他（包括被动唤醒节点）为0";
CM_ SG_ 1585 IMU_Reserve2 "预留";
CM_ SG_ 1585 IMU_WakeUp_NM "NM报文唤醒（OTA\远程）";
CM_ SG_ 1585 IMU_RemainNetworkWakeUpReason1 "保持网络唤醒原因1";
CM_ SG_ 1585 IMU_RemainNetworkWakeUpReason2 "保持网络唤醒原因2";
CM_ SG_ 1585 IMU_RemainNetworkWakeUpReason3 "保持网络唤醒原因3";
CM_ SG_ 1585 IMU_RemainNetworkWakeUpReason4 "保持网络唤醒原因4";
CM_ SG_ 824 SRR_BsdSetFd "BSD开关设置反馈";
CM_ SG_ 824 SRR_BSD_warningReqRight "BSD右侧报警";
CM_ SG_ 824 SRR_BSD_warningReqLeft "BSD左侧报警";
CM_ SG_ 824 SRR_RL_Fault "左后角雷达故障";
CM_ SG_ 824 SRR_RR_Fault "右后角雷达故障";
CM_ SG_ 824 SRR_BSD_VoiceActive_St "BSD激活报警状态";
CM_ SG_ 824 SRR_BSD_SysSts "BSD系统状态";
CM_ SG_ 824 SRR_DOW_OnOff_fbk "DOW开关反馈";
CM_ SG_ 824 SRR_DOW_St "开门预警功能状态";
CM_ SG_ 824 SRR_DOW_FL_Warn_St "左前门开门报警状态";
CM_ SG_ 824 SRR_DOW_RL_Warn_St "左后门开门报警状态";
CM_ SG_ 824 SRR_DOW_FR_Warn_St "右前门开门报警状态";
CM_ SG_ 824 SRR_DOW_RR_Warn_St "右后门开门报警状态";
CM_ SG_ 824 SRR_FCTA_OnOff_fbk "FCTA开关反馈";
CM_ SG_ 824 SRR_RCTA_Left_VoiceActive_St "RCTA左侧激活报警制动状态";
CM_ SG_ 824 SRR_FCTA_Left_Active_St "FCTA左侧激活报警制动状态";
CM_ SG_ 824 SRR_FCTA_Right_Active_St "FCTA右侧激活报警制动状态";
CM_ SG_ 824 SRR_FCTA_St "FCTA (前向目标横穿辅助）功能状态";
CM_ SG_ 824 SRR_DOW_VoiceActive_St "DOW激活报警状态";
CM_ SG_ 824 SRR_RCTA_OnOff_fbk "RCTA开关反馈";
CM_ SG_ 824 SRR_RCTA_St "RCTA (前向目标横穿辅助）功能状态";
CM_ SG_ 824 SRR_RCTA_Left_Active_St "RCTA左侧激活报警制动状态";
CM_ SG_ 824 SRR_RCTA_Right_Active_St "RCTA右侧激活报警制动状态";
CM_ SG_ 824 SRR_RCW_St "RCW（后碰撞预警）功能状态";
CM_ SG_ 824 SRR_RCW_OnOff_fbk "RCW开关反馈";
CM_ SG_ 824 SRR_RCTA_Right_VoiceActive_St "RCTA右侧激活报警制动状态";
CM_ SG_ 824 SRR_RCW_Warn_St "RCW报警等级";
CM_ SG_ 822 SRR4_DOW_FR_Warn_St "右前门开门报警状态";
CM_ SG_ 822 SRR4_DOW_RR_Warn_St "右后门开门报警状态";
CM_ SG_ 822 SRR4_BSD_warningReqRight "BSD右侧报警";
CM_ SG_ 822 SRR4_RR_Fault "右后角雷达故障";
CM_ SG_ 822 SRR4_FCTA_Right_Active_St "FCTA右侧激活报警制动状态";
CM_ SG_ 822 SRR4_RCTA_Right_Active_St "RCTA右侧激活报警制动状态";
CM_ SG_ 822 SRR4_DOW_VoiceActive_St "DOW激活报警状态";
CM_ SG_ 822 SRR4_RCTA_Right_VoiceActive_St "RCTA右侧激活报警制动状态";
CM_ SG_ 822 SRR4_BSD_VoiceActive_St "BSD激活报警状态";
CM_ SG_ 825 SRR_RL_TargetTI_Status "Status of time synchronization";
CM_ SG_ 825 SRR_RL_OBJTi_Stamp "Object timestamp雷达目标时间戳";
CM_ SG_ 825 SRR_RL_NrObj "目标数目";
CM_ SG_ 825 SRR_RLRadar_Status "雷达内部故障:雷达被遮挡、雷达未标定、雷达标定失败、雷达温度过高、雷达硬件故障、雷达软件故障、雷达水平角度超差、雷达位置安装错误、下线NVM无汽车参数未配置
雷达外部故障:与FLC丢失通信、雷达接收的数据无效";
CM_ SG_ 825 SRR_RL_MsgCounter "The MessageCounter is a 0 ~ 15 counter, increased of one unit on every message transmission";
CM_ SG_ 825 SRR_RL_CRC16Checksum "CRC16";
CM_ SG_ 826 SRR_RL_ObjID_1 "ID is an identifier number that allows for tracking of persistent objects over time";
CM_ SG_ 826 SRR_RL_ObjConf_1 "The probability of an object to exist in reality";
CM_ SG_ 826 SRR_RL_ObjSNR_1 "Signal noise ratio";
CM_ SG_ 826 SRR_RL_ObjDistX_1 "Position of target vehicle in x-direction（目标最近点的纵向距离）";
CM_ SG_ 826 SRR_RL_ObjRelVelX_1 "target object velocity in x-direction（绝对速度）";
CM_ SG_ 826 SRR_RL_ObjDistY_1 "Position of target vehicle in y-direction（目标最近点的横向距离）";
CM_ SG_ 826 SRR_RL_ObjRelVelY_1 "target object velocity in y-direction（绝对速度）";
CM_ SG_ 826 SRR_RL_ObjAccelX_1 "target acceleration  in x-direction（绝对加速度）";
CM_ SG_ 826 SRR_RL_ObjAccelY_1 "target acceleration  in y-direction（绝对加速度）";
CM_ SG_ 826 SRR_RL_ObjHeading_1 "Heading angle";
CM_ SG_ 826 SRR_RL_ObjBoxCenterLgt_1 "长方体中心x坐标（相对于目标最近点）";
CM_ SG_ 826 SRR_RL_ObjBoxCenterLat_1 "长方体中心y坐标（相对于目标最近点）";
CM_ SG_ 826 SRR_RL_ObjBoxLength_1 "长方体长度（平行于对象Heading angle的长方体长度）";
CM_ SG_ 826 SRR_RL_ObjBoxWidth_1 "长方体宽度垂直于对象Heading angle的长方体宽度）";
CM_ SG_ 826 SRR_RL_ObjDyStdDe_1 "Lateral position standard deviation";
CM_ SG_ 826 SRR_RL_ObjDxStdDe_1 "Longitudinal position standard deviation";
CM_ SG_ 826 SRR_RL_ObjVyStdDe_1 "Lateral speed standard deviation";
CM_ SG_ 826 SRR_RL_ObjVxStdDe_1 "Longitudinal speed standard deviation";
CM_ SG_ 826 SRR_RL_ObjID_2 "ID is an identifier number that allows for tracking of persistent objects over time";
CM_ SG_ 826 SRR_RL_ObjConf_2 "The probability of an object to exist in reality";
CM_ SG_ 826 SRR_RL_ObjSNR_2 "Signal noise ratio";
CM_ SG_ 826 SRR_RL_ObjDistX_2 "Position of target vehicle in x-direction（目标最近点的纵向距离）";
CM_ SG_ 826 SRR_RL_ObjRelVelX_2 "target object velocity in x-direction（绝对速度）";
CM_ SG_ 826 SRR_RL_ObjDistY_2 "Position of target vehicle in y-direction（目标最近点的横向距离）";
CM_ SG_ 826 SRR_RL_ObjRelVelY_2 "target object velocity in y-direction（绝对速度）";
CM_ SG_ 826 SRR_RL_ObjAccelX_2 "target acceleration  in x-direction（绝对加速度）";
CM_ SG_ 826 SRR_RL_ObjAccelY_2 "target acceleration  in y-direction（绝对加速度）";
CM_ SG_ 826 SRR_RL_ObjHeading_2 "Heading angle";
CM_ SG_ 826 SRR_RL_ObjBoxCenterLgt_2 "长方体中心x坐标（相对于目标最近点）";
CM_ SG_ 826 SRR_RL_ObjBoxCenterLat_2 "长方体中心y坐标（相对于目标最近点）";
CM_ SG_ 826 SRR_RL_ObjBoxLength_2 "长方体长度（平行于对象Heading angle的长方体长度）";
CM_ SG_ 826 SRR_RL_ObjBoxWidth_2 "长方体宽度垂直于对象Heading angle的长方体宽度）";
CM_ SG_ 826 SRR_RL_ObjDyStdDe_2 "Lateral position standard deviation";
CM_ SG_ 826 SRR_RL_ObjDxStdDe_2 "Longitudinal position standard deviation";
CM_ SG_ 826 SRR_RL_ObjVyStdDe_2 "Lateral speed standard deviation";
CM_ SG_ 826 SRR_RL_ObjVxStdDe_2 "Longitudinal speed standard deviation";
CM_ SG_ 826 SRR_RLObj1MsgCounter "The MessageCounter is a 0 ~ 15 counter, increased of one unit on every message transmission";
CM_ SG_ 826 SRR_RLObj1CRC16Checksum "CRC16";
CM_ SG_ 827 SRR_RL_ObjID_3 "ID is an identifier number that allows for tracking of persistent objects over time";
CM_ SG_ 827 SRR_RL_ObjConf_3 "The probability of an object to exist in reality";
CM_ SG_ 827 SRR_RL_ObjSNR_3 "Signal noise ratio";
CM_ SG_ 827 SRR_RL_ObjDistX_3 "Position of target vehicle in x-direction（目标最近点的纵向距离）";
CM_ SG_ 827 SRR_RL_ObjRelVelX_3 "target object velocity in x-direction（绝对速度）";
CM_ SG_ 827 SRR_RL_ObjDistY_3 "Position of target vehicle in y-direction（目标最近点的横向距离）";
CM_ SG_ 827 SRR_RL_ObjRelVelY_3 "target object velocity in y-direction（绝对速度）";
CM_ SG_ 827 SRR_RL_ObjAccelX_3 "target acceleration  in x-direction（绝对加速度）";
CM_ SG_ 827 SRR_RL_ObjAccelY_3 "target acceleration  in y-direction（绝对加速度）";
CM_ SG_ 827 SRR_RL_ObjHeading_3 "Heading angle";
CM_ SG_ 827 SRR_RL_ObjBoxCenterLgt_3 "长方体中心x坐标（相对于目标最近点）";
CM_ SG_ 827 SRR_RL_ObjBoxCenterLat_3 "长方体中心y坐标（相对于目标最近点）";
CM_ SG_ 827 SRR_RL_ObjBoxLength_3 "长方体长度（平行于对象Heading angle的长方体长度）";
CM_ SG_ 827 SRR_RL_ObjBoxWidth_3 "长方体宽度垂直于对象Heading angle的长方体宽度）";
CM_ SG_ 827 SRR_RL_ObjDyStdDe_3 "Lateral position standard deviation";
CM_ SG_ 827 SRR_RL_ObjDxStdDe_3 "Longitudinal position standard deviation";
CM_ SG_ 827 SRR_RL_ObjVyStdDe_3 "Lateral speed standard deviation";
CM_ SG_ 827 SRR_RL_ObjVxStdDe_3 "Longitudinal speed standard deviation";
CM_ SG_ 827 SRR_RL_ObjID_4 "ID is an identifier number that allows for tracking of persistent objects over time";
CM_ SG_ 827 SRR_RL_ObjConf_4 "The probability of an object to exist in reality";
CM_ SG_ 827 SRR_RL_ObjSNR_4 "Signal noise ratio";
CM_ SG_ 827 SRR_RL_ObjDistX_4 "Position of target vehicle in x-direction（目标最近点的纵向距离）";
CM_ SG_ 827 SRR_RL_ObjRelVelX_4 "target object velocity in x-direction（绝对速度）";
CM_ SG_ 827 SRR_RL_ObjDistY_4 "Position of target vehicle in y-direction（目标最近点的横向距离）";
CM_ SG_ 827 SRR_RL_ObjRelVelY_4 "target object velocity in y-direction（绝对速度）";
CM_ SG_ 827 SRR_RL_ObjAccelX_4 "target acceleration  in x-direction（绝对加速度）";
CM_ SG_ 827 SRR_RL_ObjAccelY_4 "target acceleration  in y-direction（绝对加速度）";
CM_ SG_ 827 SRR_RL_ObjHeading_4 "Heading angle";
CM_ SG_ 827 SRR_RL_ObjBoxCenterLgt_4 "长方体中心x坐标（相对于目标最近点）";
CM_ SG_ 827 SRR_RL_ObjBoxCenterLat_4 "长方体中心y坐标（相对于目标最近点）";
CM_ SG_ 827 SRR_RL_ObjBoxLength_4 "长方体长度（平行于对象Heading angle的长方体长度）";
CM_ SG_ 827 SRR_RL_ObjBoxWidth_4 "长方体宽度垂直于对象Heading angle的长方体宽度）";
CM_ SG_ 827 SRR_RL_ObjDyStdDe_4 "Lateral position standard deviation";
CM_ SG_ 827 SRR_RL_ObjDxStdDe_4 "Longitudinal position standard deviation";
CM_ SG_ 827 SRR_RL_ObjVyStdDe_4 "Lateral speed standard deviation";
CM_ SG_ 827 SRR_RL_ObjVxStdDe_4 "Longitudinal speed standard deviation";
CM_ SG_ 827 SRR_RLObj2MsgCounter "The MessageCounter is a 0 ~ 15 counter, increased of one unit on every message transmission";
CM_ SG_ 827 SRR_RLObj2CRC16Checksum "CRC16";
CM_ SG_ 828 SRR_RL_ObjID_5 "ID is an identifier number that allows for tracking of persistent objects over time";
CM_ SG_ 828 SRR_RL_ObjConf_5 "The probability of an object to exist in reality";
CM_ SG_ 828 SRR_RL_ObjSNR_5 "Signal noise ratio";
CM_ SG_ 828 SRR_RL_ObjDistX_5 "Position of target vehicle in x-direction（目标最近点的纵向距离）";
CM_ SG_ 828 SRR_RL_ObjRelVelX_5 "target object velocity in x-direction（绝对速度）";
CM_ SG_ 828 SRR_RL_ObjDistY_5 "Position of target vehicle in y-direction（目标最近点的横向距离）";
CM_ SG_ 828 SRR_RL_ObjRelVelY_5 "target object velocity in y-direction（绝对速度）";
CM_ SG_ 828 SRR_RL_ObjAccelX_5 "target acceleration  in x-direction（绝对加速度）";
CM_ SG_ 828 SRR_RL_ObjAccelY_5 "target acceleration  in y-direction（绝对加速度）";
CM_ SG_ 828 SRR_RL_ObjHeading_5 "Heading angle";
CM_ SG_ 828 SRR_RL_ObjBoxCenterLgt_5 "长方体中心x坐标（相对于目标最近点）";
CM_ SG_ 828 SRR_RL_ObjBoxCenterLat_5 "长方体中心y坐标（相对于目标最近点）";
CM_ SG_ 828 SRR_RL_ObjBoxLength_5 "长方体长度（平行于对象Heading angle的长方体长度）";
CM_ SG_ 828 SRR_RL_ObjBoxWidth_5 "长方体宽度垂直于对象Heading angle的长方体宽度）";
CM_ SG_ 828 SRR_RL_ObjDyStdDe_5 "Lateral position standard deviation";
CM_ SG_ 828 SRR_RL_ObjDxStdDe_5 "Longitudinal position standard deviation";
CM_ SG_ 828 SRR_RL_ObjVyStdDe_5 "Lateral speed standard deviation";
CM_ SG_ 828 SRR_RL_ObjVxStdDe_5 "Longitudinal speed standard deviation";
CM_ SG_ 828 SRR_RL_ObjID_6 "ID is an identifier number that allows for tracking of persistent objects over time";
CM_ SG_ 828 SRR_RL_ObjConf_6 "The probability of an object to exist in reality";
CM_ SG_ 828 SRR_RL_ObjSNR_6 "Signal noise ratio";
CM_ SG_ 828 SRR_RL_ObjDistX_6 "Position of target vehicle in x-direction（目标最近点的纵向距离）";
CM_ SG_ 828 SRR_RL_ObjRelVelX_6 "target object velocity in x-direction（绝对速度）";
CM_ SG_ 828 SRR_RL_ObjDistY_6 "Position of target vehicle in y-direction（目标最近点的横向距离）";
CM_ SG_ 828 SRR_RL_ObjRelVelY_6 "target object velocity in y-direction（绝对速度）";
CM_ SG_ 828 SRR_RL_ObjAccelX_6 "target acceleration  in x-direction（绝对加速度）";
CM_ SG_ 828 SRR_RL_ObjAccelY_6 "target acceleration  in y-direction（绝对加速度）";
CM_ SG_ 828 SRR_RL_ObjHeading_6 "Heading angle";
CM_ SG_ 828 SRR_RL_ObjBoxCenterLgt_6 "长方体中心x坐标（相对于目标最近点）";
CM_ SG_ 828 SRR_RL_ObjBoxCenterLat_6 "长方体中心y坐标（相对于目标最近点）";
CM_ SG_ 828 SRR_RL_ObjBoxLength_6 "长方体长度（平行于对象Heading angle的长方体长度）";
CM_ SG_ 828 SRR_RL_ObjBoxWidth_6 "长方体宽度垂直于对象Heading angle的长方体宽度）";
CM_ SG_ 828 SRR_RL_ObjDyStdDe_6 "Lateral position standard deviation";
CM_ SG_ 828 SRR_RL_ObjDxStdDe_6 "Longitudinal position standard deviation";
CM_ SG_ 828 SRR_RL_ObjVyStdDe_6 "Lateral speed standard deviation";
CM_ SG_ 828 SRR_RL_ObjVxStdDe_6 "Longitudinal speed standard deviation";
CM_ SG_ 828 SRR_RLObj3MsgCounter "The MessageCounter is a 0 ~ 15 counter, increased of one unit on every message transmission";
CM_ SG_ 828 SRR_RLObj3CRC16Checksum "CRC16";
CM_ SG_ 829 SRR_RL_ObjID_7 "ID is an identifier number that allows for tracking of persistent objects over time";
CM_ SG_ 829 SRR_RL_ObjConf_7 "The probability of an object to exist in reality";
CM_ SG_ 829 SRR_RL_ObjSNR_7 "Signal noise ratio";
CM_ SG_ 829 SRR_RL_ObjDistX_7 "Position of target vehicle in x-direction（目标最近点的纵向距离）";
CM_ SG_ 829 SRR_RL_ObjRelVelX_7 "target object velocity in x-direction（绝对速度）";
CM_ SG_ 829 SRR_RL_ObjDistY_7 "Position of target vehicle in y-direction（目标最近点的横向距离）";
CM_ SG_ 829 SRR_RL_ObjRelVelY_7 "target object velocity in y-direction（绝对速度）";
CM_ SG_ 829 SRR_RL_ObjAccelX_7 "target acceleration  in x-direction（绝对加速度）";
CM_ SG_ 829 SRR_RL_ObjAccelY_7 "target acceleration  in y-direction（绝对加速度）";
CM_ SG_ 829 SRR_RL_ObjHeading_7 "Heading angle";
CM_ SG_ 829 SRR_RL_ObjBoxCenterLgt_7 "长方体中心x坐标（相对于目标最近点）";
CM_ SG_ 829 SRR_RL_ObjBoxCenterLat_7 "长方体中心y坐标（相对于目标最近点）";
CM_ SG_ 829 SRR_RL_ObjBoxLength_7 "长方体长度（平行于对象Heading angle的长方体长度）";
CM_ SG_ 829 SRR_RL_ObjBoxWidth_7 "长方体宽度垂直于对象Heading angle的长方体宽度）";
CM_ SG_ 829 SRR_RL_ObjDyStdDe_7 "Lateral position standard deviation";
CM_ SG_ 829 SRR_RL_ObjDxStdDe_7 "Longitudinal position standard deviation";
CM_ SG_ 829 SRR_RL_ObjVyStdDe_7 "Lateral speed standard deviation";
CM_ SG_ 829 SRR_RL_ObjVxStdDe_7 "Longitudinal speed standard deviation";
CM_ SG_ 829 SRR_RL_ObjID_8 "ID is an identifier number that allows for tracking of persistent objects over time";
CM_ SG_ 829 SRR_RL_ObjConf_8 "The probability of an object to exist in reality";
CM_ SG_ 829 SRR_RL_ObjSNR_8 "Signal noise ratio";
CM_ SG_ 829 SRR_RL_ObjDistX_8 "Position of target vehicle in x-direction（目标最近点的纵向距离）";
CM_ SG_ 829 SRR_RL_ObjRelVelX_8 "target object velocity in x-direction（绝对速度）";
CM_ SG_ 829 SRR_RL_ObjDistY_8 "Position of target vehicle in y-direction（目标最近点的横向距离）";
CM_ SG_ 829 SRR_RL_ObjRelVelY_8 "target object velocity in y-direction（绝对速度）";
CM_ SG_ 829 SRR_RL_ObjAccelX_8 "target acceleration  in x-direction（绝对加速度）";
CM_ SG_ 829 SRR_RL_ObjAccelY_8 "target acceleration  in y-direction（绝对加速度）";
CM_ SG_ 829 SRR_RL_ObjHeading_8 "Heading angle";
CM_ SG_ 829 SRR_RL_ObjBoxCenterLgt_8 "长方体中心x坐标（相对于目标最近点）";
CM_ SG_ 829 SRR_RL_ObjBoxCenterLat_8 "长方体中心y坐标（相对于目标最近点）";
CM_ SG_ 829 SRR_RL_ObjBoxLength_8 "长方体长度（平行于对象Heading angle的长方体长度）";
CM_ SG_ 829 SRR_RL_ObjBoxWidth_8 "长方体宽度垂直于对象Heading angle的长方体宽度）";
CM_ SG_ 829 SRR_RL_ObjDyStdDe_8 "Lateral position standard deviation";
CM_ SG_ 829 SRR_RL_ObjDxStdDe_8 "Longitudinal position standard deviation";
CM_ SG_ 829 SRR_RL_ObjVyStdDe_8 "Lateral speed standard deviation";
CM_ SG_ 829 SRR_RL_ObjVxStdDe_8 "Longitudinal speed standard deviation";
CM_ SG_ 829 SRR_RLObj4MsgCounter "The MessageCounter is a 0 ~ 15 counter, increased of one unit on every message transmission";
CM_ SG_ 829 SRR_RLObj4CRC16Checksum "CRC16";
CM_ SG_ 830 SRR_RL_ObjID_9 "ID is an identifier number that allows for tracking of persistent objects over time";
CM_ SG_ 830 SRR_RL_ObjConf_9 "The probability of an object to exist in reality";
CM_ SG_ 830 SRR_RL_ObjSNR_9 "Signal noise ratio";
CM_ SG_ 830 SRR_RL_ObjDistX_9 "Position of target vehicle in x-direction（目标最近点的纵向距离）";
CM_ SG_ 830 SRR_RL_ObjRelVelX_9 "target object velocity in x-direction（绝对速度）";
CM_ SG_ 830 SRR_RL_ObjDistY_9 "Position of target vehicle in y-direction（目标最近点的横向距离）";
CM_ SG_ 830 SRR_RL_ObjRelVelY_9 "target object velocity in y-direction（绝对速度）";
CM_ SG_ 830 SRR_RL_ObjAccelX_9 "target acceleration  in x-direction（绝对加速度）";
CM_ SG_ 830 SRR_RL_ObjAccelY_9 "target acceleration  in y-direction（绝对加速度）";
CM_ SG_ 830 SRR_RL_ObjHeading_9 "Heading angle";
CM_ SG_ 830 SRR_RL_ObjBoxCenterLgt_9 "长方体中心x坐标（相对于目标最近点）";
CM_ SG_ 830 SRR_RL_ObjBoxCenterLat_9 "长方体中心y坐标（相对于目标最近点）";
CM_ SG_ 830 SRR_RL_ObjBoxLength_9 "长方体长度（平行于对象Heading angle的长方体长度）";
CM_ SG_ 830 SRR_RL_ObjBoxWidth_9 "长方体宽度垂直于对象Heading angle的长方体宽度）";
CM_ SG_ 830 SRR_RL_ObjDyStdDe_9 "Lateral position standard deviation";
CM_ SG_ 830 SRR_RL_ObjDxStdDe_9 "Longitudinal position standard deviation";
CM_ SG_ 830 SRR_RL_ObjVyStdDe_9 "Lateral speed standard deviation";
CM_ SG_ 830 SRR_RL_ObjVxStdDe_9 "Longitudinal speed standard deviation";
CM_ SG_ 830 SRR_RL_ObjID_10 "ID is an identifier number that allows for tracking of persistent objects over time";
CM_ SG_ 830 SRR_RL_ObjConf_10 "The probability of an object to exist in reality";
CM_ SG_ 830 SRR_RL_ObjSNR_10 "Signal noise ratio";
CM_ SG_ 830 SRR_RL_ObjDistX_10 "Position of target vehicle in x-direction（目标最近点的纵向距离）";
CM_ SG_ 830 SRR_RL_ObjRelVelX_10 "target object velocity in x-direction（绝对速度）";
CM_ SG_ 830 SRR_RL_ObjDistY_10 "Position of target vehicle in y-direction（目标最近点的横向距离）";
CM_ SG_ 830 SRR_RL_ObjRelVelY_10 "target object velocity in y-direction（绝对速度）";
CM_ SG_ 830 SRR_RL_ObjAccelX_10 "target acceleration  in x-direction（绝对加速度）";
CM_ SG_ 830 SRR_RL_ObjAccelY_10 "target acceleration  in y-direction（绝对加速度）";
CM_ SG_ 830 SRR_RL_ObjHeading_10 "Heading angle";
CM_ SG_ 830 SRR_RL_ObjBoxCenterLgt_10 "长方体中心x坐标（相对于目标最近点）";
CM_ SG_ 830 SRR_RL_ObjBoxCenterLat_10 "长方体中心y坐标（相对于目标最近点）";
CM_ SG_ 830 SRR_RL_ObjBoxLength_10 "长方体长度（平行于对象Heading angle的长方体长度）";
CM_ SG_ 830 SRR_RL_ObjBoxWidth_10 "长方体宽度垂直于对象Heading angle的长方体宽度）";
CM_ SG_ 830 SRR_RL_ObjDyStdDe_10 "Lateral position standard deviation";
CM_ SG_ 830 SRR_RL_ObjDxStdDe_10 "Longitudinal position standard deviation";
CM_ SG_ 830 SRR_RL_ObjVyStdDe_10 "Lateral speed standard deviation";
CM_ SG_ 830 SRR_RL_ObjVxStdDe_10 "Longitudinal speed standard deviation";
CM_ SG_ 830 SRR_RLObj5MsgCounter "The MessageCounter is a 0 ~ 15 counter, increased of one unit on every message transmission";
CM_ SG_ 830 SRR_RLObj5CRC16Checksum "CRC16";
CM_ SG_ 831 SRR_RL_ObjID_11 "ID is an identifier number that allows for tracking of persistent objects over time";
CM_ SG_ 831 SRR_RL_ObjConf_11 "The probability of an object to exist in reality";
CM_ SG_ 831 SRR_RL_ObjSNR_11 "Signal noise ratio";
CM_ SG_ 831 SRR_RL_ObjDistX_11 "Position of target vehicle in x-direction（目标最近点的纵向距离）";
CM_ SG_ 831 SRR_RL_ObjRelVelX_11 "target object velocity in x-direction（绝对速度）";
CM_ SG_ 831 SRR_RL_ObjDistY_11 "Position of target vehicle in y-direction（目标最近点的横向距离）";
CM_ SG_ 831 SRR_RL_ObjRelVelY_11 "target object velocity in y-direction（绝对速度）";
CM_ SG_ 831 SRR_RL_ObjAccelX_11 "target acceleration  in x-direction（绝对加速度）";
CM_ SG_ 831 SRR_RL_ObjAccelY_11 "target acceleration  in y-direction（绝对加速度）";
CM_ SG_ 831 SRR_RL_ObjHeading_11 "Heading angle";
CM_ SG_ 831 SRR_RL_ObjBoxCenterLgt_11 "长方体中心x坐标（相对于目标最近点）";
CM_ SG_ 831 SRR_RL_ObjBoxCenterLat_11 "长方体中心y坐标（相对于目标最近点）";
CM_ SG_ 831 SRR_RL_ObjBoxLength_11 "长方体长度（平行于对象Heading angle的长方体长度）";
CM_ SG_ 831 SRR_RL_ObjBoxWidth_11 "长方体宽度垂直于对象Heading angle的长方体宽度）";
CM_ SG_ 831 SRR_RL_ObjDyStdDe_11 "Lateral position standard deviation";
CM_ SG_ 831 SRR_RL_ObjDxStdDe_11 "Longitudinal position standard deviation";
CM_ SG_ 831 SRR_RL_ObjVyStdDe_11 "Lateral speed standard deviation";
CM_ SG_ 831 SRR_RL_ObjVxStdDe_11 "Longitudinal speed standard deviation";
CM_ SG_ 831 SRR_RL_ObjID_12 "ID is an identifier number that allows for tracking of persistent objects over time";
CM_ SG_ 831 SRR_RL_ObjConf_12 "The probability of an object to exist in reality";
CM_ SG_ 831 SRR_RL_ObjSNR_12 "Signal noise ratio";
CM_ SG_ 831 SRR_RL_ObjDistX_12 "Position of target vehicle in x-direction（目标最近点的纵向距离）";
CM_ SG_ 831 SRR_RL_ObjRelVelX_12 "target object velocity in x-direction（绝对速度）";
CM_ SG_ 831 SRR_RL_ObjDistY_12 "Position of target vehicle in y-direction（目标最近点的横向距离）";
CM_ SG_ 831 SRR_RL_ObjRelVelY_12 "target object velocity in y-direction（绝对速度）";
CM_ SG_ 831 SRR_RL_ObjAccelX_12 "target acceleration  in x-direction（绝对加速度）";
CM_ SG_ 831 SRR_RL_ObjAccelY_12 "target acceleration  in y-direction（绝对加速度）";
CM_ SG_ 831 SRR_RL_ObjHeading_12 "Heading angle";
CM_ SG_ 831 SRR_RL_ObjBoxCenterLgt_12 "长方体中心x坐标（相对于目标最近点）";
CM_ SG_ 831 SRR_RL_ObjBoxCenterLat_12 "长方体中心y坐标（相对于目标最近点）";
CM_ SG_ 831 SRR_RL_ObjBoxLength_12 "长方体长度（平行于对象Heading angle的长方体长度）";
CM_ SG_ 831 SRR_RL_ObjBoxWidth_12 "长方体宽度垂直于对象Heading angle的长方体宽度）";
CM_ SG_ 831 SRR_RL_ObjDyStdDe_12 "Lateral position standard deviation";
CM_ SG_ 831 SRR_RL_ObjDxStdDe_12 "Longitudinal position standard deviation";
CM_ SG_ 831 SRR_RL_ObjVyStdDe_12 "Lateral speed standard deviation";
CM_ SG_ 831 SRR_RL_ObjVxStdDe_12 "Longitudinal speed standard deviation";
CM_ SG_ 831 SRR_RLObj6MsgCounter "The MessageCounter is a 0 ~ 15 counter, increased of one unit on every message transmission";
CM_ SG_ 831 SRR_RLObj6CRC16Checksum "CRC16";
CM_ SG_ 832 SRR_RL_ObjID_13 "ID is an identifier number that allows for tracking of persistent objects over time";
CM_ SG_ 832 SRR_RL_ObjConf_13 "The probability of an object to exist in reality";
CM_ SG_ 832 SRR_RL_ObjSNR_13 "Signal noise ratio";
CM_ SG_ 832 SRR_RL_ObjDistX_13 "Position of target vehicle in x-direction（目标最近点的纵向距离）";
CM_ SG_ 832 SRR_RL_ObjRelVelX_13 "target object velocity in x-direction（绝对速度）";
CM_ SG_ 832 SRR_RL_ObjDistY_13 "Position of target vehicle in y-direction（目标最近点的横向距离）";
CM_ SG_ 832 SRR_RL_ObjRelVelY_13 "target object velocity in y-direction（绝对速度）";
CM_ SG_ 832 SRR_RL_ObjAccelX_13 "target acceleration  in x-direction（绝对加速度）";
CM_ SG_ 832 SRR_RL_ObjAccelY_13 "target acceleration  in y-direction（绝对加速度）";
CM_ SG_ 832 SRR_RL_ObjHeading_13 "Heading angle";
CM_ SG_ 832 SRR_RL_ObjBoxCenterLgt_13 "长方体中心x坐标（相对于目标最近点）";
CM_ SG_ 832 SRR_RL_ObjBoxCenterLat_13 "长方体中心y坐标（相对于目标最近点）";
CM_ SG_ 832 SRR_RL_ObjBoxLength_13 "长方体长度（平行于对象Heading angle的长方体长度）";
CM_ SG_ 832 SRR_RL_ObjBoxWidth_13 "长方体宽度垂直于对象Heading angle的长方体宽度）";
CM_ SG_ 832 SRR_RL_ObjDyStdDe_13 "Lateral position standard deviation";
CM_ SG_ 832 SRR_RL_ObjDxStdDe_13 "Longitudinal position standard deviation";
CM_ SG_ 832 SRR_RL_ObjVyStdDe_13 "Lateral speed standard deviation";
CM_ SG_ 832 SRR_RL_ObjVxStdDe_13 "Longitudinal speed standard deviation";
CM_ SG_ 832 SRR_RL_ObjID_14 "ID is an identifier number that allows for tracking of persistent objects over time";
CM_ SG_ 832 SRR_RL_ObjConf_14 "The probability of an object to exist in reality";
CM_ SG_ 832 SRR_RL_ObjSNR_14 "Signal noise ratio";
CM_ SG_ 832 SRR_RL_ObjDistX_14 "Position of target vehicle in x-direction（目标最近点的纵向距离）";
CM_ SG_ 832 SRR_RL_ObjRelVelX_14 "target object velocity in x-direction（绝对速度）";
CM_ SG_ 832 SRR_RL_ObjDistY_14 "Position of target vehicle in y-direction（目标最近点的横向距离）";
CM_ SG_ 832 SRR_RL_ObjRelVelY_14 "target object velocity in y-direction（绝对速度）";
CM_ SG_ 832 SRR_RL_ObjAccelX_14 "target acceleration  in x-direction（绝对加速度）";
CM_ SG_ 832 SRR_RL_ObjAccelY_14 "target acceleration  in y-direction（绝对加速度）";
CM_ SG_ 832 SRR_RL_ObjHeading_14 "Heading angle";
CM_ SG_ 832 SRR_RL_ObjBoxCenterLgt_14 "长方体中心x坐标（相对于目标最近点）";
CM_ SG_ 832 SRR_RL_ObjBoxCenterLat_14 "长方体中心y坐标（相对于目标最近点）";
CM_ SG_ 832 SRR_RL_ObjBoxLength_14 "长方体长度（平行于对象Heading angle的长方体长度）";
CM_ SG_ 832 SRR_RL_ObjBoxWidth_14 "长方体宽度垂直于对象Heading angle的长方体宽度）";
CM_ SG_ 832 SRR_RL_ObjDyStdDe_14 "Lateral position standard deviation";
CM_ SG_ 832 SRR_RL_ObjDxStdDe_14 "Longitudinal position standard deviation";
CM_ SG_ 832 SRR_RL_ObjVyStdDe_14 "Lateral speed standard deviation";
CM_ SG_ 832 SRR_RL_ObjVxStdDe_14 "Longitudinal speed standard deviation";
CM_ SG_ 832 SRR_RLObj7MsgCounter "The MessageCounter is a 0 ~ 15 counter, increased of one unit on every message transmission";
CM_ SG_ 832 SRR_RLObj7CRC16Checksum "CRC16";
CM_ SG_ 833 SRR_RL_ObjID_15 "ID is an identifier number that allows for tracking of persistent objects over time";
CM_ SG_ 833 SRR_RL_ObjConf_15 "The probability of an object to exist in reality";
CM_ SG_ 833 SRR_RL_ObjSNR_15 "Signal noise ratio";
CM_ SG_ 833 SRR_RL_ObjDistX_15 "Position of target vehicle in x-direction（目标最近点的纵向距离）";
CM_ SG_ 833 SRR_RL_ObjRelVelX_15 "target object velocity in x-direction（绝对速度）";
CM_ SG_ 833 SRR_RL_ObjDistY_15 "Position of target vehicle in y-direction（目标最近点的横向距离）";
CM_ SG_ 833 SRR_RL_ObjRelVelY_15 "target object velocity in y-direction（绝对速度）";
CM_ SG_ 833 SRR_RL_ObjAccelX_15 "target acceleration  in x-direction（绝对加速度）";
CM_ SG_ 833 SRR_RL_ObjAccelY_15 "target acceleration  in y-direction（绝对加速度）";
CM_ SG_ 833 SRR_RL_ObjHeading_15 "Heading angle";
CM_ SG_ 833 SRR_RL_ObjBoxCenterLgt_15 "长方体中心x坐标（相对于目标最近点）";
CM_ SG_ 833 SRR_RL_ObjBoxCenterLat_15 "长方体中心y坐标（相对于目标最近点）";
CM_ SG_ 833 SRR_RL_ObjBoxLength_15 "长方体长度（平行于对象Heading angle的长方体长度）";
CM_ SG_ 833 SRR_RL_ObjBoxWidth_15 "长方体宽度垂直于对象Heading angle的长方体宽度）";
CM_ SG_ 833 SRR_RL_ObjDyStdDe_15 "Lateral position standard deviation";
CM_ SG_ 833 SRR_RL_ObjDxStdDe_15 "Longitudinal position standard deviation";
CM_ SG_ 833 SRR_RL_ObjVyStdDe_15 "Lateral speed standard deviation";
CM_ SG_ 833 SRR_RL_ObjVxStdDe_15 "Longitudinal speed standard deviation";
CM_ SG_ 833 SRR_RL_ObjID_16 "ID is an identifier number that allows for tracking of persistent objects over time";
CM_ SG_ 833 SRR_RL_ObjConf_16 "The probability of an object to exist in reality";
CM_ SG_ 833 SRR_RL_ObjSNR_16 "Signal noise ratio";
CM_ SG_ 833 SRR_RL_ObjDistX_16 "Position of target vehicle in x-direction（目标最近点的纵向距离）";
CM_ SG_ 833 SRR_RL_ObjRelVelX_16 "target object velocity in x-direction（绝对速度）";
CM_ SG_ 833 SRR_RL_ObjDistY_16 "Position of target vehicle in y-direction（目标最近点的横向距离）";
CM_ SG_ 833 SRR_RL_ObjRelVelY_16 "target object velocity in y-direction（绝对速度）";
CM_ SG_ 833 SRR_RL_ObjAccelX_16 "target acceleration  in x-direction（绝对加速度）";
CM_ SG_ 833 SRR_RL_ObjAccelY_16 "target acceleration  in y-direction（绝对加速度）";
CM_ SG_ 833 SRR_RL_ObjHeading_16 "Heading angle";
CM_ SG_ 833 SRR_RL_ObjBoxCenterLgt_16 "长方体中心x坐标（相对于目标最近点）";
CM_ SG_ 833 SRR_RL_ObjBoxCenterLat_16 "长方体中心y坐标（相对于目标最近点）";
CM_ SG_ 833 SRR_RL_ObjBoxLength_16 "长方体长度（平行于对象Heading angle的长方体长度）";
CM_ SG_ 833 SRR_RL_ObjBoxWidth_16 "长方体宽度垂直于对象Heading angle的长方体宽度）";
CM_ SG_ 833 SRR_RL_ObjDyStdDe_16 "Lateral position standard deviation";
CM_ SG_ 833 SRR_RL_ObjDxStdDe_16 "Longitudinal position standard deviation";
CM_ SG_ 833 SRR_RL_ObjVyStdDe_16 "Lateral speed standard deviation";
CM_ SG_ 833 SRR_RL_ObjVxStdDe_16 "Longitudinal speed standard deviation";
CM_ SG_ 833 SRR_RLObj8MsgCounter "The MessageCounter is a 0 ~ 15 counter, increased of one unit on every message transmission";
CM_ SG_ 833 SRR_RLObj8CRC16Checksum "CRC16";
CM_ SG_ 834 SRR_RR_TargetTI_Status "Status of time synchronization";
CM_ SG_ 834 SRR_RR_OBJTi_Stamp "Object timestamp雷达目标时间戳";
CM_ SG_ 834 SRR_RR_NrObj "目标数目";
CM_ SG_ 834 SRR_RRRadar_Status "雷达内部故障:雷达被遮挡、雷达未标定、雷达标定失败、雷达温度过高、雷达硬件故障、雷达软件故障、雷达水平角度超差、雷达位置安装错误、下线NVM无汽车参数未配置
雷达外部故障:与FLC丢失通信、雷达接收的数据无效";
CM_ SG_ 834 SRR_RR_MsgCounter "The MessageCounter is a 0 ~ 15 counter, increased of one unit on every message transmission";
CM_ SG_ 834 SRR_RR_CRC16Checksum "CRC16";
CM_ SG_ 835 SRR_RR_ObjID_1 "ID is an identifier number that allows for tracking of persistent objects over time";
CM_ SG_ 835 SRR_RR_ObjConf_1 "The probability of an object to exist in reality";
CM_ SG_ 835 SRR_RR_ObjSNR_1 "Signal noise ratio";
CM_ SG_ 835 SRR_RR_ObjDistX_1 "Position of target vehicle in x-direction（目标最近点的纵向距离）";
CM_ SG_ 835 SRR_RR_ObjRelVelX_1 "target object velocity in x-direction（绝对速度）";
CM_ SG_ 835 SRR_RR_ObjDistY_1 "Position of target vehicle in y-direction（目标最近点的横向距离）";
CM_ SG_ 835 SRR_RR_ObjRelVelY_1 "target object velocity in y-direction（绝对速度）";
CM_ SG_ 835 SRR_RR_ObjAccelX_1 "target acceleration  in x-direction（绝对加速度）";
CM_ SG_ 835 SRR_RR_ObjAccelY_1 "target acceleration  in y-direction（绝对加速度）";
CM_ SG_ 835 SRR_RR_ObjHeading_1 "Heading angle";
CM_ SG_ 835 SRR_RR_ObjBoxCenterLgt_1 "长方体中心x坐标（相对于目标最近点）";
CM_ SG_ 835 SRR_RR_ObjBoxCenterLat_1 "长方体中心y坐标（相对于目标最近点）";
CM_ SG_ 835 SRR_RR_ObjBoxLength_1 "长方体长度（平行于对象Heading angle的长方体长度）";
CM_ SG_ 835 SRR_RR_ObjBoxWidth_1 "长方体宽度垂直于对象Heading angle的长方体宽度）";
CM_ SG_ 835 SRR_RR_ObjDyStdDe_1 "Lateral position standard deviation";
CM_ SG_ 835 SRR_RR_ObjDxStdDe_1 "Longitudinal position standard deviation";
CM_ SG_ 835 SRR_RR_ObjVyStdDe_1 "Lateral speed standard deviation";
CM_ SG_ 835 SRR_RR_ObjVxStdDe_1 "Longitudinal speed standard deviation";
CM_ SG_ 835 SRR_RR_ObjID_2 "ID is an identifier number that allows for tracking of persistent objects over time";
CM_ SG_ 835 SRR_RR_ObjConf_2 "The probability of an object to exist in reality";
CM_ SG_ 835 SRR_RR_ObjSNR_2 "Signal noise ratio";
CM_ SG_ 835 SRR_RR_ObjDistX_2 "Position of target vehicle in x-direction（目标最近点的纵向距离）";
CM_ SG_ 835 SRR_RR_ObjRelVelX_2 "target object velocity in x-direction（绝对速度）";
CM_ SG_ 835 SRR_RR_ObjDistY_2 "Position of target vehicle in y-direction（目标最近点的横向距离）";
CM_ SG_ 835 SRR_RR_ObjRelVelY_2 "target object velocity in y-direction（绝对速度）";
CM_ SG_ 835 SRR_RR_ObjAccelX_2 "target acceleration  in x-direction（绝对加速度）";
CM_ SG_ 835 SRR_RR_ObjAccelY_2 "target acceleration  in y-direction（绝对加速度）";
CM_ SG_ 835 SRR_RR_ObjHeading_2 "Heading angle";
CM_ SG_ 835 SRR_RR_ObjBoxCenterLgt_2 "长方体中心x坐标（相对于目标最近点）";
CM_ SG_ 835 SRR_RR_ObjBoxCenterLat_2 "长方体中心y坐标（相对于目标最近点）";
CM_ SG_ 835 SRR_RR_ObjBoxLength_2 "长方体长度（平行于对象Heading angle的长方体长度）";
CM_ SG_ 835 SRR_RR_ObjBoxWidth_2 "长方体宽度垂直于对象Heading angle的长方体宽度）";
CM_ SG_ 835 SRR_RR_ObjDyStdDe_2 "Lateral position standard deviation";
CM_ SG_ 835 SRR_RR_ObjDxStdDe_2 "Longitudinal position standard deviation";
CM_ SG_ 835 SRR_RR_ObjVyStdDe_2 "Lateral speed standard deviation";
CM_ SG_ 835 SRR_RR_ObjVxStdDe_2 "Longitudinal speed standard deviation";
CM_ SG_ 835 SRR_RRObj1MsgCounter "The MessageCounter is a 0 ~ 15 counter, increased of one unit on every message transmission";
CM_ SG_ 835 SRR_RRObj1CRC16Checksum "CRC16";
CM_ SG_ 836 SRR_RR_ObjID_3 "ID is an identifier number that allows for tracking of persistent objects over time";
CM_ SG_ 836 SRR_RR_ObjConf_3 "The probability of an object to exist in reality";
CM_ SG_ 836 SRR_RR_ObjSNR_3 "Signal noise ratio";
CM_ SG_ 836 SRR_RR_ObjDistX_3 "Position of target vehicle in x-direction（目标最近点的纵向距离）";
CM_ SG_ 836 SRR_RR_ObjRelVelX_3 "target object velocity in x-direction（绝对速度）";
CM_ SG_ 836 SRR_RR_ObjDistY_3 "Position of target vehicle in y-direction（目标最近点的横向距离）";
CM_ SG_ 836 SRR_RR_ObjRelVelY_3 "target object velocity in y-direction（绝对速度）";
CM_ SG_ 836 SRR_RR_ObjAccelX_3 "target acceleration  in x-direction（绝对加速度）";
CM_ SG_ 836 SRR_RR_ObjAccelY_3 "target acceleration  in y-direction（绝对加速度）";
CM_ SG_ 836 SRR_RR_ObjHeading_3 "Heading angle";
CM_ SG_ 836 SRR_RR_ObjBoxCenterLgt_3 "长方体中心x坐标（相对于目标最近点）";
CM_ SG_ 836 SRR_RR_ObjBoxCenterLat_3 "长方体中心y坐标（相对于目标最近点）";
CM_ SG_ 836 SRR_RR_ObjBoxLength_3 "长方体长度（平行于对象Heading angle的长方体长度）";
CM_ SG_ 836 SRR_RR_ObjBoxWidth_3 "长方体宽度垂直于对象Heading angle的长方体宽度）";
CM_ SG_ 836 SRR_RR_ObjDyStdDe_3 "Lateral position standard deviation";
CM_ SG_ 836 SRR_RR_ObjDxStdDe_3 "Longitudinal position standard deviation";
CM_ SG_ 836 SRR_RR_ObjVyStdDe_3 "Lateral speed standard deviation";
CM_ SG_ 836 SRR_RR_ObjVxStdDe_3 "Longitudinal speed standard deviation";
CM_ SG_ 836 SRR_RR_ObjID_4 "ID is an identifier number that allows for tracking of persistent objects over time";
CM_ SG_ 836 SRR_RR_ObjConf_4 "The probability of an object to exist in reality";
CM_ SG_ 836 SRR_RR_ObjSNR_4 "Signal noise ratio";
CM_ SG_ 836 SRR_RR_ObjDistX_4 "Position of target vehicle in x-direction（目标最近点的纵向距离）";
CM_ SG_ 836 SRR_RR_ObjRelVelX_4 "target object velocity in x-direction（绝对速度）";
CM_ SG_ 836 SRR_RR_ObjDistY_4 "Position of target vehicle in y-direction（目标最近点的横向距离）";
CM_ SG_ 836 SRR_RR_ObjRelVelY_4 "target object velocity in y-direction（绝对速度）";
CM_ SG_ 836 SRR_RR_ObjAccelX_4 "target acceleration  in x-direction（绝对加速度）";
CM_ SG_ 836 SRR_RR_ObjAccelY_4 "target acceleration  in y-direction（绝对加速度）";
CM_ SG_ 836 SRR_RR_ObjHeading_4 "Heading angle";
CM_ SG_ 836 SRR_RR_ObjBoxCenterLgt_4 "长方体中心x坐标（相对于目标最近点）";
CM_ SG_ 836 SRR_RR_ObjBoxCenterLat_4 "长方体中心y坐标（相对于目标最近点）";
CM_ SG_ 836 SRR_RR_ObjBoxLength_4 "长方体长度（平行于对象Heading angle的长方体长度）";
CM_ SG_ 836 SRR_RR_ObjBoxWidth_4 "长方体宽度垂直于对象Heading angle的长方体宽度）";
CM_ SG_ 836 SRR_RR_ObjDyStdDe_4 "Lateral position standard deviation";
CM_ SG_ 836 SRR_RR_ObjDxStdDe_4 "Longitudinal position standard deviation";
CM_ SG_ 836 SRR_RR_ObjVyStdDe_4 "Lateral speed standard deviation";
CM_ SG_ 836 SRR_RR_ObjVxStdDe_4 "Longitudinal speed standard deviation";
CM_ SG_ 836 SRR_RRObj2MsgCounter "The MessageCounter is a 0 ~ 15 counter, increased of one unit on every message transmission";
CM_ SG_ 836 SRR_RRObj2CRC16Checksum "CRC16";
CM_ SG_ 837 SRR_RR_ObjID_5 "ID is an identifier number that allows for tracking of persistent objects over time";
CM_ SG_ 837 SRR_RR_ObjConf_5 "The probability of an object to exist in reality";
CM_ SG_ 837 SRR_RR_ObjSNR_5 "Signal noise ratio";
CM_ SG_ 837 SRR_RR_ObjDistX_5 "Position of target vehicle in x-direction（目标最近点的纵向距离）";
CM_ SG_ 837 SRR_RR_ObjRelVelX_5 "target object velocity in x-direction（绝对速度）";
CM_ SG_ 837 SRR_RR_ObjDistY_5 "Position of target vehicle in y-direction（目标最近点的横向距离）";
CM_ SG_ 837 SRR_RR_ObjRelVelY_5 "target object velocity in y-direction（绝对速度）";
CM_ SG_ 837 SRR_RR_ObjAccelX_5 "target acceleration  in x-direction（绝对加速度）";
CM_ SG_ 837 SRR_RR_ObjAccelY_5 "target acceleration  in y-direction（绝对加速度）";
CM_ SG_ 837 SRR_RR_ObjHeading_5 "Heading angle";
CM_ SG_ 837 SRR_RR_ObjBoxCenterLgt_5 "长方体中心x坐标（相对于目标最近点）";
CM_ SG_ 837 SRR_RR_ObjBoxCenterLat_5 "长方体中心y坐标（相对于目标最近点）";
CM_ SG_ 837 SRR_RR_ObjBoxLength_5 "长方体长度（平行于对象Heading angle的长方体长度）";
CM_ SG_ 837 SRR_RR_ObjBoxWidth_5 "长方体宽度垂直于对象Heading angle的长方体宽度）";
CM_ SG_ 837 SRR_RR_ObjDyStdDe_5 "Lateral position standard deviation";
CM_ SG_ 837 SRR_RR_ObjDxStdDe_5 "Longitudinal position standard deviation";
CM_ SG_ 837 SRR_RR_ObjVyStdDe_5 "Lateral speed standard deviation";
CM_ SG_ 837 SRR_RR_ObjVxStdDe_5 "Longitudinal speed standard deviation";
CM_ SG_ 837 SRR_RR_ObjID_6 "ID is an identifier number that allows for tracking of persistent objects over time";
CM_ SG_ 837 SRR_RR_ObjConf_6 "The probability of an object to exist in reality";
CM_ SG_ 837 SRR_RR_ObjSNR_6 "Signal noise ratio";
CM_ SG_ 837 SRR_RR_ObjDistX_6 "Position of target vehicle in x-direction（目标最近点的纵向距离）";
CM_ SG_ 837 SRR_RR_ObjRelVelX_6 "target object velocity in x-direction（绝对速度）";
CM_ SG_ 837 SRR_RR_ObjDistY_6 "Position of target vehicle in y-direction（目标最近点的横向距离）";
CM_ SG_ 837 SRR_RR_ObjRelVelY_6 "target object velocity in y-direction（绝对速度）";
CM_ SG_ 837 SRR_RR_ObjAccelX_6 "target acceleration  in x-direction（绝对加速度）";
CM_ SG_ 837 SRR_RR_ObjAccelY_6 "target acceleration  in y-direction（绝对加速度）";
CM_ SG_ 837 SRR_RR_ObjHeading_6 "Heading angle";
CM_ SG_ 837 SRR_RR_ObjBoxCenterLgt_6 "长方体中心x坐标（相对于目标最近点）";
CM_ SG_ 837 SRR_RR_ObjBoxCenterLat_6 "长方体中心y坐标（相对于目标最近点）";
CM_ SG_ 837 SRR_RR_ObjBoxLength_6 "长方体长度（平行于对象Heading angle的长方体长度）";
CM_ SG_ 837 SRR_RR_ObjBoxWidth_6 "长方体宽度垂直于对象Heading angle的长方体宽度）";
CM_ SG_ 837 SRR_RR_ObjDyStdDe_6 "Lateral position standard deviation";
CM_ SG_ 837 SRR_RR_ObjDxStdDe_6 "Longitudinal position standard deviation";
CM_ SG_ 837 SRR_RR_ObjVyStdDe_6 "Lateral speed standard deviation";
CM_ SG_ 837 SRR_RR_ObjVxStdDe_6 "Longitudinal speed standard deviation";
CM_ SG_ 837 SRR_RRObj3MsgCounter "The MessageCounter is a 0 ~ 15 counter, increased of one unit on every message transmission";
CM_ SG_ 837 SRR_RRObj3CRC16Checksum "CRC16";
CM_ SG_ 838 SRR_RR_ObjID_7 "ID is an identifier number that allows for tracking of persistent objects over time";
CM_ SG_ 838 SRR_RR_ObjConf_7 "The probability of an object to exist in reality";
CM_ SG_ 838 SRR_RR_ObjSNR_7 "Signal noise ratio";
CM_ SG_ 838 SRR_RR_ObjDistX_7 "Position of target vehicle in x-direction（目标最近点的纵向距离）";
CM_ SG_ 838 SRR_RR_ObjRelVelX_7 "target object velocity in x-direction（绝对速度）";
CM_ SG_ 838 SRR_RR_ObjDistY_7 "Position of target vehicle in y-direction（目标最近点的横向距离）";
CM_ SG_ 838 SRR_RR_ObjRelVelY_7 "target object velocity in y-direction（绝对速度）";
CM_ SG_ 838 SRR_RR_ObjAccelX_7 "target acceleration  in x-direction（绝对加速度）";
CM_ SG_ 838 SRR_RR_ObjAccelY_7 "target acceleration  in y-direction（绝对加速度）";
CM_ SG_ 838 SRR_RR_ObjHeading_7 "Heading angle";
CM_ SG_ 838 SRR_RR_ObjBoxCenterLgt_7 "长方体中心x坐标（相对于目标最近点）";
CM_ SG_ 838 SRR_RR_ObjBoxCenterLat_7 "长方体中心y坐标（相对于目标最近点）";
CM_ SG_ 838 SRR_RR_ObjBoxLength_7 "长方体长度（平行于对象Heading angle的长方体长度）";
CM_ SG_ 838 SRR_RR_ObjBoxWidth_7 "长方体宽度垂直于对象Heading angle的长方体宽度）";
CM_ SG_ 838 SRR_RR_ObjDyStdDe_7 "Lateral position standard deviation";
CM_ SG_ 838 SRR_RR_ObjDxStdDe_7 "Longitudinal position standard deviation";
CM_ SG_ 838 SRR_RR_ObjVyStdDe_7 "Lateral speed standard deviation";
CM_ SG_ 838 SRR_RR_ObjVxStdDe_7 "Longitudinal speed standard deviation";
CM_ SG_ 838 SRR_RR_ObjID_8 "ID is an identifier number that allows for tracking of persistent objects over time";
CM_ SG_ 838 SRR_RR_ObjConf_8 "The probability of an object to exist in reality";
CM_ SG_ 838 SRR_RR_ObjSNR_8 "Signal noise ratio";
CM_ SG_ 838 SRR_RR_ObjDistX_8 "Position of target vehicle in x-direction（目标最近点的纵向距离）";
CM_ SG_ 838 SRR_RR_ObjRelVelX_8 "target object velocity in x-direction（绝对速度）";
CM_ SG_ 838 SRR_RR_ObjDistY_8 "Position of target vehicle in y-direction（目标最近点的横向距离）";
CM_ SG_ 838 SRR_RR_ObjRelVelY_8 "target object velocity in y-direction（绝对速度）";
CM_ SG_ 838 SRR_RR_ObjAccelX_8 "target acceleration  in x-direction（绝对加速度）";
CM_ SG_ 838 SRR_RR_ObjAccelY_8 "target acceleration  in y-direction（绝对加速度）";
CM_ SG_ 838 SRR_RR_ObjHeading_8 "Heading angle";
CM_ SG_ 838 SRR_RR_ObjBoxCenterLgt_8 "长方体中心x坐标（相对于目标最近点）";
CM_ SG_ 838 SRR_RR_ObjBoxCenterLat_8 "长方体中心y坐标（相对于目标最近点）";
CM_ SG_ 838 SRR_RR_ObjBoxLength_8 "长方体长度（平行于对象Heading angle的长方体长度）";
CM_ SG_ 838 SRR_RR_ObjBoxWidth_8 "长方体宽度垂直于对象Heading angle的长方体宽度）";
CM_ SG_ 838 SRR_RR_ObjDyStdDe_8 "Lateral position standard deviation";
CM_ SG_ 838 SRR_RR_ObjDxStdDe_8 "Longitudinal position standard deviation";
CM_ SG_ 838 SRR_RR_ObjVyStdDe_8 "Lateral speed standard deviation";
CM_ SG_ 838 SRR_RR_ObjVxStdDe_8 "Longitudinal speed standard deviation";
CM_ SG_ 838 SRR_RRObj4MsgCounter "The MessageCounter is a 0 ~ 15 counter, increased of one unit on every message transmission";
CM_ SG_ 838 SRR_RRObj4CRC16Checksum "CRC16";
CM_ SG_ 839 SRR_RR_ObjID_9 "ID is an identifier number that allows for tracking of persistent objects over time";
CM_ SG_ 839 SRR_RR_ObjConf_9 "The probability of an object to exist in reality";
CM_ SG_ 839 SRR_RR_ObjSNR_9 "Signal noise ratio";
CM_ SG_ 839 SRR_RR_ObjDistX_9 "Position of target vehicle in x-direction（目标最近点的纵向距离）";
CM_ SG_ 839 SRR_RR_ObjRelVelX_9 "target object velocity in x-direction（绝对速度）";
CM_ SG_ 839 SRR_RR_ObjDistY_9 "Position of target vehicle in y-direction（目标最近点的横向距离）";
CM_ SG_ 839 SRR_RR_ObjRelVelY_9 "target object velocity in y-direction（绝对速度）";
CM_ SG_ 839 SRR_RR_ObjAccelX_9 "target acceleration  in x-direction（绝对加速度）";
CM_ SG_ 839 SRR_RR_ObjAccelY_9 "target acceleration  in y-direction（绝对加速度）";
CM_ SG_ 839 SRR_RR_ObjHeading_9 "Heading angle";
CM_ SG_ 839 SRR_RR_ObjBoxCenterLgt_9 "长方体中心x坐标（相对于目标最近点）";
CM_ SG_ 839 SRR_RR_ObjBoxCenterLat_9 "长方体中心y坐标（相对于目标最近点）";
CM_ SG_ 839 SRR_RR_ObjBoxLength_9 "长方体长度（平行于对象Heading angle的长方体长度）";
CM_ SG_ 839 SRR_RR_ObjBoxWidth_9 "长方体宽度垂直于对象Heading angle的长方体宽度）";
CM_ SG_ 839 SRR_RR_ObjDyStdDe_9 "Lateral position standard deviation";
CM_ SG_ 839 SRR_RR_ObjDxStdDe_9 "Longitudinal position standard deviation";
CM_ SG_ 839 SRR_RR_ObjVyStdDe_9 "Lateral speed standard deviation";
CM_ SG_ 839 SRR_RR_ObjVxStdDe_9 "Longitudinal speed standard deviation";
CM_ SG_ 839 SRR_RR_ObjID_10 "ID is an identifier number that allows for tracking of persistent objects over time";
CM_ SG_ 839 SRR_RR_ObjConf_10 "The probability of an object to exist in reality";
CM_ SG_ 839 SRR_RR_ObjSNR_10 "Signal noise ratio";
CM_ SG_ 839 SRR_RR_ObjDistX_10 "Position of target vehicle in x-direction（目标最近点的纵向距离）";
CM_ SG_ 839 SRR_RR_ObjRelVelX_10 "target object velocity in x-direction（绝对速度）";
CM_ SG_ 839 SRR_RR_ObjDistY_10 "Position of target vehicle in y-direction（目标最近点的横向距离）";
CM_ SG_ 839 SRR_RR_ObjRelVelY_10 "target object velocity in y-direction（绝对速度）";
CM_ SG_ 839 SRR_RR_ObjAccelX_10 "target acceleration  in x-direction（绝对加速度）";
CM_ SG_ 839 SRR_RR_ObjAccelY_10 "target acceleration  in y-direction（绝对加速度）";
CM_ SG_ 839 SRR_RR_ObjHeading_10 "Heading angle";
CM_ SG_ 839 SRR_RR_ObjBoxCenterLgt_10 "长方体中心x坐标（相对于目标最近点）";
CM_ SG_ 839 SRR_RR_ObjBoxCenterLat_10 "长方体中心y坐标（相对于目标最近点）";
CM_ SG_ 839 SRR_RR_ObjBoxLength_10 "长方体长度（平行于对象Heading angle的长方体长度）";
CM_ SG_ 839 SRR_RR_ObjBoxWidth_10 "长方体宽度垂直于对象Heading angle的长方体宽度）";
CM_ SG_ 839 SRR_RR_ObjDyStdDe_10 "Lateral position standard deviation";
CM_ SG_ 839 SRR_RR_ObjDxStdDe_10 "Longitudinal position standard deviation";
CM_ SG_ 839 SRR_RR_ObjVyStdDe_10 "Lateral speed standard deviation";
CM_ SG_ 839 SRR_RR_ObjVxStdDe_10 "Longitudinal speed standard deviation";
CM_ SG_ 839 SRR_RRObj5MsgCounter "The MessageCounter is a 0 ~ 15 counter, increased of one unit on every message transmission";
CM_ SG_ 839 SRR_RRObj5CRC16Checksum "CRC16";
CM_ SG_ 840 SRR_RR_ObjID_11 "ID is an identifier number that allows for tracking of persistent objects over time";
CM_ SG_ 840 SRR_RR_ObjConf_11 "The probability of an object to exist in reality";
CM_ SG_ 840 SRR_RR_ObjSNR_11 "Signal noise ratio";
CM_ SG_ 840 SRR_RR_ObjDistX_11 "Position of target vehicle in x-direction（目标最近点的纵向距离）";
CM_ SG_ 840 SRR_RR_ObjRelVelX_11 "target object velocity in x-direction（绝对速度）";
CM_ SG_ 840 SRR_RR_ObjDistY_11 "Position of target vehicle in y-direction（目标最近点的横向距离）";
CM_ SG_ 840 SRR_RR_ObjRelVelY_11 "target object velocity in y-direction（绝对速度）";
CM_ SG_ 840 SRR_RR_ObjAccelX_11 "target acceleration  in x-direction（绝对加速度）";
CM_ SG_ 840 SRR_RR_ObjAccelY_11 "target acceleration  in y-direction（绝对加速度）";
CM_ SG_ 840 SRR_RR_ObjHeading_11 "Heading angle";
CM_ SG_ 840 SRR_RR_ObjBoxCenterLgt_11 "长方体中心x坐标（相对于目标最近点）";
CM_ SG_ 840 SRR_RR_ObjBoxCenterLat_11 "长方体中心y坐标（相对于目标最近点）";
CM_ SG_ 840 SRR_RR_ObjBoxLength_11 "长方体长度（平行于对象Heading angle的长方体长度）";
CM_ SG_ 840 SRR_RR_ObjBoxWidth_11 "长方体宽度垂直于对象Heading angle的长方体宽度）";
CM_ SG_ 840 SRR_RR_ObjDyStdDe_11 "Lateral position standard deviation";
CM_ SG_ 840 SRR_RR_ObjDxStdDe_11 "Longitudinal position standard deviation";
CM_ SG_ 840 SRR_RR_ObjVyStdDe_11 "Lateral speed standard deviation";
CM_ SG_ 840 SRR_RR_ObjVxStdDe_11 "Longitudinal speed standard deviation";
CM_ SG_ 840 SRR_RR_ObjID_12 "ID is an identifier number that allows for tracking of persistent objects over time";
CM_ SG_ 840 SRR_RR_ObjConf_12 "The probability of an object to exist in reality";
CM_ SG_ 840 SRR_RR_ObjSNR_12 "Signal noise ratio";
CM_ SG_ 840 SRR_RR_ObjDistX_12 "Position of target vehicle in x-direction（目标最近点的纵向距离）";
CM_ SG_ 840 SRR_RR_ObjRelVelX_12 "target object velocity in x-direction（绝对速度）";
CM_ SG_ 840 SRR_RR_ObjDistY_12 "Position of target vehicle in y-direction（目标最近点的横向距离）";
CM_ SG_ 840 SRR_RR_ObjRelVelY_12 "target object velocity in y-direction（绝对速度）";
CM_ SG_ 840 SRR_RR_ObjAccelX_12 "target acceleration  in x-direction（绝对加速度）";
CM_ SG_ 840 SRR_RR_ObjAccelY_12 "target acceleration  in y-direction（绝对加速度）";
CM_ SG_ 840 SRR_RR_ObjHeading_12 "Heading angle";
CM_ SG_ 840 SRR_RR_ObjBoxCenterLgt_12 "长方体中心x坐标（相对于目标最近点）";
CM_ SG_ 840 SRR_RR_ObjBoxCenterLat_12 "长方体中心y坐标（相对于目标最近点）";
CM_ SG_ 840 SRR_RR_ObjBoxLength_12 "长方体长度（平行于对象Heading angle的长方体长度）";
CM_ SG_ 840 SRR_RR_ObjBoxWidth_12 "长方体宽度垂直于对象Heading angle的长方体宽度）";
CM_ SG_ 840 SRR_RR_ObjDyStdDe_12 "Lateral position standard deviation";
CM_ SG_ 840 SRR_RR_ObjDxStdDe_12 "Longitudinal position standard deviation";
CM_ SG_ 840 SRR_RR_ObjVyStdDe_12 "Lateral speed standard deviation";
CM_ SG_ 840 SRR_RR_ObjVxStdDe_12 "Longitudinal speed standard deviation";
CM_ SG_ 840 SRR_RRObj6MsgCounter "The MessageCounter is a 0 ~ 15 counter, increased of one unit on every message transmission";
CM_ SG_ 840 SRR_RRObj6CRC16Checksum "CRC16";
CM_ SG_ 841 SRR_RR_ObjID_13 "ID is an identifier number that allows for tracking of persistent objects over time";
CM_ SG_ 841 SRR_RR_ObjConf_13 "The probability of an object to exist in reality";
CM_ SG_ 841 SRR_RR_ObjSNR_13 "Signal noise ratio";
CM_ SG_ 841 SRR_RR_ObjDistX_13 "Position of target vehicle in x-direction（目标最近点的纵向距离）";
CM_ SG_ 841 SRR_RR_ObjRelVelX_13 "target object velocity in x-direction（绝对速度）";
CM_ SG_ 841 SRR_RR_ObjDistY_13 "Position of target vehicle in y-direction（目标最近点的横向距离）";
CM_ SG_ 841 SRR_RR_ObjRelVelY_13 "target object velocity in y-direction（绝对速度）";
CM_ SG_ 841 SRR_RR_ObjAccelX_13 "target acceleration  in x-direction（绝对加速度）";
CM_ SG_ 841 SRR_RR_ObjAccelY_13 "target acceleration  in y-direction（绝对加速度）";
CM_ SG_ 841 SRR_RR_ObjHeading_13 "Heading angle";
CM_ SG_ 841 SRR_RR_ObjBoxCenterLgt_13 "长方体中心x坐标（相对于目标最近点）";
CM_ SG_ 841 SRR_RR_ObjBoxCenterLat_13 "长方体中心y坐标（相对于目标最近点）";
CM_ SG_ 841 SRR_RR_ObjBoxLength_13 "长方体长度（平行于对象Heading angle的长方体长度）";
CM_ SG_ 841 SRR_RR_ObjBoxWidth_13 "长方体宽度垂直于对象Heading angle的长方体宽度）";
CM_ SG_ 841 SRR_RR_ObjDyStdDe_13 "Lateral position standard deviation";
CM_ SG_ 841 SRR_RR_ObjDxStdDe_13 "Longitudinal position standard deviation";
CM_ SG_ 841 SRR_RR_ObjVyStdDe_13 "Lateral speed standard deviation";
CM_ SG_ 841 SRR_RR_ObjVxStdDe_13 "Longitudinal speed standard deviation";
CM_ SG_ 841 SRR_RR_ObjID_14 "ID is an identifier number that allows for tracking of persistent objects over time";
CM_ SG_ 841 SRR_RR_ObjConf_14 "The probability of an object to exist in reality";
CM_ SG_ 841 SRR_RR_ObjSNR_14 "Signal noise ratio";
CM_ SG_ 841 SRR_RR_ObjDistX_14 "Position of target vehicle in x-direction（目标最近点的纵向距离）";
CM_ SG_ 841 SRR_RR_ObjRelVelX_14 "target object velocity in x-direction（绝对速度）";
CM_ SG_ 841 SRR_RR_ObjDistY_14 "Position of target vehicle in y-direction（目标最近点的横向距离）";
CM_ SG_ 841 SRR_RR_ObjRelVelY_14 "target object velocity in y-direction（绝对速度）";
CM_ SG_ 841 SRR_RR_ObjAccelX_14 "target acceleration  in x-direction（绝对加速度）";
CM_ SG_ 841 SRR_RR_ObjAccelY_14 "target acceleration  in y-direction（绝对加速度）";
CM_ SG_ 841 SRR_RR_ObjHeading_14 "Heading angle";
CM_ SG_ 841 SRR_RR_ObjBoxCenterLgt_14 "长方体中心x坐标（相对于目标最近点）";
CM_ SG_ 841 SRR_RR_ObjBoxCenterLat_14 "长方体中心y坐标（相对于目标最近点）";
CM_ SG_ 841 SRR_RR_ObjBoxLength_14 "长方体长度（平行于对象Heading angle的长方体长度）";
CM_ SG_ 841 SRR_RR_ObjBoxWidth_14 "长方体宽度垂直于对象Heading angle的长方体宽度）";
CM_ SG_ 841 SRR_RR_ObjDyStdDe_14 "Lateral position standard deviation";
CM_ SG_ 841 SRR_RR_ObjDxStdDe_14 "Longitudinal position standard deviation";
CM_ SG_ 841 SRR_RR_ObjVyStdDe_14 "Lateral speed standard deviation";
CM_ SG_ 841 SRR_RR_ObjVxStdDe_14 "Longitudinal speed standard deviation";
CM_ SG_ 841 SRR_RRObj7MsgCounter "The MessageCounter is a 0 ~ 15 counter, increased of one unit on every message transmission";
CM_ SG_ 841 SRR_RRObj7CRC16Checksum "CRC16";
CM_ SG_ 848 SRR_RR_ObjID_15 "ID is an identifier number that allows for tracking of persistent objects over time";
CM_ SG_ 848 SRR_RR_ObjConf_15 "The probability of an object to exist in reality";
CM_ SG_ 848 SRR_RR_ObjSNR_15 "Signal noise ratio";
CM_ SG_ 848 SRR_RR_ObjDistX_15 "Position of target vehicle in x-direction（目标最近点的纵向距离）";
CM_ SG_ 848 SRR_RR_ObjRelVelX_15 "target object velocity in x-direction（绝对速度）";
CM_ SG_ 848 SRR_RR_ObjDistY_15 "Position of target vehicle in y-direction（目标最近点的横向距离）";
CM_ SG_ 848 SRR_RR_ObjRelVelY_15 "target object velocity in y-direction（绝对速度）";
CM_ SG_ 848 SRR_RR_ObjAccelX_15 "target acceleration  in x-direction（绝对加速度）";
CM_ SG_ 848 SRR_RR_ObjAccelY_15 "target acceleration  in y-direction（绝对加速度）";
CM_ SG_ 848 SRR_RR_ObjHeading_15 "Heading angle";
CM_ SG_ 848 SRR_RR_ObjBoxCenterLgt_15 "长方体中心x坐标（相对于目标最近点）";
CM_ SG_ 848 SRR_RR_ObjBoxCenterLat_15 "长方体中心y坐标（相对于目标最近点）";
CM_ SG_ 848 SRR_RR_ObjBoxLength_15 "长方体长度（平行于对象Heading angle的长方体长度）";
CM_ SG_ 848 SRR_RR_ObjBoxWidth_15 "长方体宽度垂直于对象Heading angle的长方体宽度）";
CM_ SG_ 848 SRR_RR_ObjDyStdDe_15 "Lateral position standard deviation";
CM_ SG_ 848 SRR_RR_ObjDxStdDe_15 "Longitudinal position standard deviation";
CM_ SG_ 848 SRR_RR_ObjVyStdDe_15 "Lateral speed standard deviation";
CM_ SG_ 848 SRR_RR_ObjVxStdDe_15 "Longitudinal speed standard deviation";
CM_ SG_ 848 SRR_RR_ObjID_16 "ID is an identifier number that allows for tracking of persistent objects over time";
CM_ SG_ 848 SRR_RR_ObjConf_16 "The probability of an object to exist in reality";
CM_ SG_ 848 SRR_RR_ObjSNR_16 "Signal noise ratio";
CM_ SG_ 848 SRR_RR_ObjDistX_16 "Position of target vehicle in x-direction（目标最近点的纵向距离）";
CM_ SG_ 848 SRR_RR_ObjRelVelX_16 "target object velocity in x-direction（绝对速度）";
CM_ SG_ 848 SRR_RR_ObjDistY_16 "Position of target vehicle in y-direction（目标最近点的横向距离）";
CM_ SG_ 848 SRR_RR_ObjRelVelY_16 "target object velocity in y-direction（绝对速度）";
CM_ SG_ 848 SRR_RR_ObjAccelX_16 "target acceleration  in x-direction（绝对加速度）";
CM_ SG_ 848 SRR_RR_ObjAccelY_16 "target acceleration  in y-direction（绝对加速度）";
CM_ SG_ 848 SRR_RR_ObjHeading_16 "Heading angle";
CM_ SG_ 848 SRR_RR_ObjBoxCenterLgt_16 "长方体中心x坐标（相对于目标最近点）";
CM_ SG_ 848 SRR_RR_ObjBoxCenterLat_16 "长方体中心y坐标（相对于目标最近点）";
CM_ SG_ 848 SRR_RR_ObjBoxLength_16 "长方体长度（平行于对象Heading angle的长方体长度）";
CM_ SG_ 848 SRR_RR_ObjBoxWidth_16 "长方体宽度垂直于对象Heading angle的长方体宽度）";
CM_ SG_ 848 SRR_RR_ObjDyStdDe_16 "Lateral position standard deviation";
CM_ SG_ 848 SRR_RR_ObjDxStdDe_16 "Longitudinal position standard deviation";
CM_ SG_ 848 SRR_RR_ObjVyStdDe_16 "Lateral speed standard deviation";
CM_ SG_ 848 SRR_RR_ObjVxStdDe_16 "Longitudinal speed standard deviation";
CM_ SG_ 848 SRR_RRObj8MsgCounter "The MessageCounter is a 0 ~ 15 counter, increased of one unit on every message transmission";
CM_ SG_ 848 SRR_RRObj8CRC16Checksum "CRC16";
CM_ SG_ 529 ACU3_Delta_Vx_0 "纵向碰撞Delta_Vx0";
CM_ SG_ 529 ACU3_Delta_Vx_1 "纵向碰撞Delta_Vx1";
CM_ SG_ 529 ACU3_Delta_Vx_2 "纵向碰撞Delta_Vx2";
CM_ SG_ 529 ACU3_Delta_Vx_3 "纵向碰撞Delta_Vx3";
CM_ SG_ 529 ACU3_Delta_Vx_4 "纵向碰撞Delta_Vx4";
CM_ SG_ 529 ACU3_Delta_Vx_5 "纵向碰撞Delta_Vx5";
CM_ SG_ 529 ACU3_MsgCounter "E2E Profile2-CRC8H2F，Counter:0-15";
CM_ SG_ 529 ACU3_DVx_Index "纵向碰撞Delta_V索引";
CM_ SG_ 529 ACU3_Checksum "E2E Profile2-CRC8H2F
DataID List:#39 - 35 72 175 251 135 15 120 79 40 109 154 209 122 216 197 48";
CM_ SG_ 530 ACU4_Delta_Vy_0 "横向碰撞Delta_Vy0";
CM_ SG_ 530 ACU4_Delta_Vy_1 "横向碰撞Delta_Vy1";
CM_ SG_ 530 ACU4_Delta_Vy_2 "横向碰撞Delta_Vy2";
CM_ SG_ 530 ACU4_Delta_Vy_3 "横向碰撞Delta_Vy3";
CM_ SG_ 530 ACU4_Delta_Vy_4 "横向碰撞Delta_Vy4";
CM_ SG_ 530 ACU4_Delta_Vy_5 "横向碰撞Delta_Vy5";
CM_ SG_ 530 ACU4_MsgCounter "E2E Profile2-CRC8H2F，Counter:0-15";
CM_ SG_ 530 ACU4_DVy_Index "横向碰撞Delta_Vy索引";
CM_ SG_ 530 ACU4_Checksum "E2E Profile2-CRC8H2F
DataID List:#40 - 80 63 225 241 23 198 116 213 4 11 73 153 20 111 188 235";
CM_ SG_ 196 ACU2_LatAccSensorValueV "Lateral Acceleration Sensor Value Validity";
CM_ SG_ 196 ACU2_LatAccSensorValue "Lateral Acceleration Sensor Value";
CM_ SG_ 196 ACU2_VehicleDynYawRateV "Vehicle Dynamics Yaw Rate Validity";
CM_ SG_ 196 ACU2_Sensorcalibration "组合传感器零位是否标定
Sensor calibration or not";
CM_ SG_ 196 ACU2_LongAccSensorValueV "Longitude Acceleration Sensor Value Validity";
CM_ SG_ 196 ACU2_LongAccSensorValue "Longitude Acceleration Sensor Value";
CM_ SG_ 196 ACU2_VehicleDynYawRate "Vehicle Dynamics Yaw Rate";
CM_ SG_ 196 ACU2_MsgCounter "E2E Profile2-CRC8H2F，Counter:0-15";
CM_ SG_ 196 ACU2_Checksum "E2E Profile2-CRC8H2F
DataID List:#26 - 39 175 13 15 49 40 145 209 184 197 98 107 118 202 100 99";
CM_ SG_ 258 ACU1_Driver_Buckle "Driver Buckle status on CAN Bus
驾驶员安全带状态";
CM_ SG_ 258 ACU1_Passenger_Buckle "Passenger Buckle status on CAN Bus
副驾安全带状态";
CM_ SG_ 258 ACU1_PAB_State "ACU1_PAB_State
ACU反馈副驾驶气囊开启状态";
CM_ SG_ 258 ACU1_Passenger_ODS "Passenger ODS  status on CAN Bus
副驾占位传感器状态";
CM_ SG_ 258 ACU1_CrashStatus "Crash status on CAN Bus
碰撞信号";
CM_ SG_ 258 ACU1_warningLight "Airbag System Fault
安全气囊故障警报灯";
CM_ SG_ 258 ACU1_Rear_Left_ODS "Rear Left Passenger ODS status on CAN Bus后排左侧占位传感器状态";
CM_ SG_ 258 ACU1_Rear_Left_BuckleSts_Logic "Rear Left Buckle status After Logic
后排左侧安全带状态(与占位开关逻辑后)";
CM_ SG_ 258 ACU1_Rear_Right_Buckle "Rear Right Buckle status on CAN Bus
后排右侧安全带状态";
CM_ SG_ 258 ACU1_Rear_Left_Buckle "Rear Left Buckle status on CAN Bus
后排左侧安全带状态";
CM_ SG_ 258 ACU1_Rear_Middle_Buckle "Rear Middle Buckle status on CAN Bus
后排中间安全带状态";
CM_ SG_ 258 ACU1_Rear_Middle_ODS "Rear Left Passenger ODS status on CAN Bus后排中间侧占位传感器状态";
CM_ SG_ 258 ACU1_Rear_Midlle_BuckleSts_Logic "Rear Middle Buckle status After Logic
后排中间侧安全带状态(与占位开关逻辑后)";
CM_ SG_ 258 ACU1_Rear_Right_ODS "Rear Left Passenger ODS status on CAN Bus
后排右侧占位传感器状态";
CM_ SG_ 258 ACU1_Rear_Right_BuckleSts_Logic "Rear Left Buckle status After Logic
后排右侧安全带状态(与占位开关逻辑后)";
CM_ SG_ 258 ACU1_CrashType "碰撞类型
Crash信号是按照bit表示状态的:
若同时有多个方向发生碰撞，则代表各方向的各个碰撞标志位均会被置1.例如左碰叠加右碰，那么输出的信号是00001100";
CM_ SG_ 258 ACU1_MsgCounter "E2E Profile2-CRC8H2F，Counter:0-15";
CM_ SG_ 258 ACU1_Checksum "E2E Profile2-CRC8H2F
DataID List:#72 - 131 156 166 214 177 28 212 186 164 184 178 8 135 171 119 170";

BA_DEF_ BO_ "CANFD_BRS" ENUM "0","1";
BA_DEF_ BO_ "GenMsgSendType" ENUM "Cycle","NoMsgSendType","IfActive","Event","CA","CE";
BA_DEF_ BO_ "GenMsgNrOfRepetition" INT 0 0;
BA_DEF_ BO_ "GenMsgILSupport" ENUM "No","Yes";
BA_DEF_ BO_ "GenMsgDelayTime" INT 0 0;
BA_DEF_ BO_ "GenMsgCycleTimeFast" INT 0 0;
BA_DEF_ BO_ "GenMsgCycleTime" INT 0 0;
BA_DEF_ BO_ "DiagResponse" ENUM "No","Yes";
BA_DEF_ BO_ "DiagRequest" ENUM "No","Yes";
BA_DEF_ BO_ "NmMessage" ENUM "No","Yes";
BA_DEF_ BO_ "VFrameFormat" ENUM "StandardCAN","ExtendedCAN","reserved","J1939PG","reserved","reserved","reserved","reserved","reserved","reserved","reserved","reserved","reserved","reserved","StandardCAN_FD","ExtendedCAN_FD";
BA_DEF_ SG_ "GenSigInvalidValue" HEX 0 0;
BA_DEF_ SG_ "GenSigStartValue" HEX 0 0;
BA_DEF_ SG_ "GenSigSendType" ENUM "Cycle","OnWrite","OnWriteWithRepetition","OnChange","OnChangeWithRepetition","IfActive","IfActiveWithRepetition","NoSigSendType","vector_leerstring";
BA_DEF_DEF_ "CANFD_BRS" "1";
BA_DEF_DEF_ "GenMsgSendType" "Cycle";
BA_DEF_DEF_ "GenMsgNrOfRepetition" 0;
BA_DEF_DEF_ "GenMsgILSupport" "Yes";
BA_DEF_DEF_ "GenMsgDelayTime" 0;
BA_DEF_DEF_ "GenMsgCycleTimeFast" 0;
BA_DEF_DEF_ "GenMsgCycleTime" 0;
BA_DEF_DEF_ "DiagResponse" "No";
BA_DEF_DEF_ "DiagRequest" "No";
BA_DEF_DEF_ "NmMessage" "No";
BA_DEF_DEF_ "VFrameFormat" "StandardCAN";
BA_DEF_DEF_ "GenSigInvalidValue" 0;
BA_DEF_DEF_ "GenSigStartValue" 0;
BA_DEF_DEF_ "GenSigSendType" "Cycle";
BA_ "GenMsgCycleTime" BO_ 528 100;
BA_ "VFrameFormat" BO_ 528 14;
BA_ "GenMsgCycleTime" BO_ 613 100;
BA_ "VFrameFormat" BO_ 613 14;
BA_ "GenMsgSendType" BO_ 984 2;
BA_ "VFrameFormat" BO_ 984 14;
BA_ "GenMsgCycleTime" BO_ 597 100;
BA_ "VFrameFormat" BO_ 597 14;
BA_ "GenMsgCycleTime" BO_ 842 50;
BA_ "GenMsgCycleTimeFast" BO_ 842 50;
BA_ "VFrameFormat" BO_ 842 14;
BA_ "GenMsgCycleTime" BO_ 843 100;
BA_ "GenMsgCycleTimeFast" BO_ 843 50;
BA_ "VFrameFormat" BO_ 843 14;
BA_ "GenMsgCycleTime" BO_ 1543 500;
BA_ "NmMessage" BO_ 1543 1;
BA_ "GenMsgCycleTime" BO_ 1557 500;
BA_ "NmMessage" BO_ 1557 1;
BA_ "GenMsgCycleTime" BO_ 1556 500;
BA_ "NmMessage" BO_ 1556 1;
BA_ "GenMsgCycleTime" BO_ 615 100;
BA_ "VFrameFormat" BO_ 615 14;
BA_ "GenMsgNrOfRepetition" BO_ 772 3;
BA_ "GenMsgCycleTimeFast" BO_ 772 20;
BA_ "GenMsgSendType" BO_ 772 3;
BA_ "VFrameFormat" BO_ 772 14;
BA_ "GenMsgCycleTime" BO_ 1376 500;
BA_ "VFrameFormat" BO_ 1376 14;
BA_ "GenMsgCycleTime" BO_ 1585 500;
BA_ "NmMessage" BO_ 1585 1;
BA_ "GenMsgCycleTime" BO_ 824 50;
BA_ "VFrameFormat" BO_ 824 14;
BA_ "GenMsgCycleTime" BO_ 822 50;
BA_ "VFrameFormat" BO_ 822 14;
BA_ "GenMsgCycleTime" BO_ 825 50;
BA_ "VFrameFormat" BO_ 825 14;
BA_ "GenMsgCycleTime" BO_ 826 50;
BA_ "VFrameFormat" BO_ 826 14;
BA_ "GenMsgCycleTime" BO_ 827 50;
BA_ "VFrameFormat" BO_ 827 14;
BA_ "GenMsgCycleTime" BO_ 828 50;
BA_ "VFrameFormat" BO_ 828 14;
BA_ "GenMsgCycleTime" BO_ 829 50;
BA_ "VFrameFormat" BO_ 829 14;
BA_ "GenMsgCycleTime" BO_ 830 50;
BA_ "VFrameFormat" BO_ 830 14;
BA_ "GenMsgCycleTime" BO_ 831 50;
BA_ "VFrameFormat" BO_ 831 14;
BA_ "GenMsgCycleTime" BO_ 832 50;
BA_ "VFrameFormat" BO_ 832 14;
BA_ "GenMsgCycleTime" BO_ 833 50;
BA_ "VFrameFormat" BO_ 833 14;
BA_ "GenMsgCycleTime" BO_ 834 50;
BA_ "VFrameFormat" BO_ 834 14;
BA_ "GenMsgCycleTime" BO_ 835 50;
BA_ "VFrameFormat" BO_ 835 14;
BA_ "GenMsgCycleTime" BO_ 836 50;
BA_ "VFrameFormat" BO_ 836 14;
BA_ "GenMsgCycleTime" BO_ 837 50;
BA_ "VFrameFormat" BO_ 837 14;
BA_ "GenMsgCycleTime" BO_ 838 50;
BA_ "VFrameFormat" BO_ 838 14;
BA_ "GenMsgCycleTime" BO_ 839 50;
BA_ "VFrameFormat" BO_ 839 14;
BA_ "GenMsgCycleTime" BO_ 840 50;
BA_ "VFrameFormat" BO_ 840 14;
BA_ "GenMsgCycleTime" BO_ 841 50;
BA_ "VFrameFormat" BO_ 841 14;
BA_ "GenMsgCycleTime" BO_ 848 50;
BA_ "VFrameFormat" BO_ 848 14;
BA_ "GenMsgCycleTime" BO_ 529 100;
BA_ "VFrameFormat" BO_ 529 14;
BA_ "GenMsgCycleTime" BO_ 530 100;
BA_ "VFrameFormat" BO_ 530 14;
BA_ "GenMsgCycleTime" BO_ 196 10;
BA_ "VFrameFormat" BO_ 196 14;
BA_ "GenMsgCycleTime" BO_ 258 20;
BA_ "VFrameFormat" BO_ 258 14;
BA_ "GenSigStartValue" SG_ 528 ADCS9_CDCS_CertificateState 1;
BA_ "GenSigSendType" SG_ 984 ADCS_Resp_EncrData0 5;
BA_ "GenSigSendType" SG_ 984 ADCS_Resp_EncrData1 5;
BA_ "GenSigSendType" SG_ 984 ADCS_Resp_EncrData2 5;
BA_ "GenSigSendType" SG_ 984 ADCS_Resp_EncrData3 5;
BA_ "GenSigSendType" SG_ 984 ADCS_Resp_EncrData4 5;
BA_ "GenSigSendType" SG_ 984 ADCS_Resp_EncrData5 5;
BA_ "GenSigSendType" SG_ 984 ADCS_Resp_EncrData6 5;
BA_ "GenSigSendType" SG_ 984 ADCS_Resp_EncrData7 5;
BA_ "GenSigSendType" SG_ 772 IMU_GPGGA_size 1;
BA_ "GenSigSendType" SG_ 772 IMU_GPGGA_num_total 1;
BA_ "GenSigSendType" SG_ 772 IMU_GPGGA_num 1;
BA_ "GenSigSendType" SG_ 772 IMU_GPGGA_Reserved 1;
BA_ "GenSigSendType" SG_ 772 IMU_GPGGA_data 1;
BA_ "GenSigStartValue" SG_ 826 SRR_RL_ObjDistX_1 2048;
BA_ "GenSigStartValue" SG_ 826 SRR_RL_ObjRelVelX_1 2048;
BA_ "GenSigStartValue" SG_ 826 SRR_RL_ObjDistY_1 8192;
BA_ "GenSigStartValue" SG_ 826 SRR_RL_ObjRelVelY_1 2048;
BA_ "GenSigStartValue" SG_ 826 SRR_RL_ObjAccelX_1 512;
BA_ "GenSigStartValue" SG_ 826 SRR_RL_ObjAccelY_1 512;
BA_ "GenSigStartValue" SG_ 826 SRR_RL_ObjHeading_1 1800;
BA_ "GenSigStartValue" SG_ 826 SRR_RL_ObjBoxCenterLgt_1 250;
BA_ "GenSigStartValue" SG_ 826 SRR_RL_ObjBoxCenterLat_1 250;
BA_ "GenSigStartValue" SG_ 826 SRR_RL_ObjDistX_2 2048;
BA_ "GenSigStartValue" SG_ 826 SRR_RL_ObjRelVelX_2 2048;
BA_ "GenSigStartValue" SG_ 826 SRR_RL_ObjDistY_2 8192;
BA_ "GenSigStartValue" SG_ 826 SRR_RL_ObjRelVelY_2 2048;
BA_ "GenSigStartValue" SG_ 826 SRR_RL_ObjAccelX_2 512;
BA_ "GenSigStartValue" SG_ 826 SRR_RL_ObjAccelY_2 512;
BA_ "GenSigStartValue" SG_ 826 SRR_RL_ObjHeading_2 1800;
BA_ "GenSigStartValue" SG_ 826 SRR_RL_ObjBoxCenterLgt_2 250;
BA_ "GenSigStartValue" SG_ 826 SRR_RL_ObjBoxCenterLat_2 250;
BA_ "GenSigStartValue" SG_ 827 SRR_RL_ObjDistX_3 2048;
BA_ "GenSigStartValue" SG_ 827 SRR_RL_ObjRelVelX_3 2048;
BA_ "GenSigStartValue" SG_ 827 SRR_RL_ObjDistY_3 8192;
BA_ "GenSigStartValue" SG_ 827 SRR_RL_ObjRelVelY_3 2048;
BA_ "GenSigStartValue" SG_ 827 SRR_RL_ObjAccelX_3 512;
BA_ "GenSigStartValue" SG_ 827 SRR_RL_ObjAccelY_3 512;
BA_ "GenSigStartValue" SG_ 827 SRR_RL_ObjHeading_3 1800;
BA_ "GenSigStartValue" SG_ 827 SRR_RL_ObjBoxCenterLgt_3 250;
BA_ "GenSigStartValue" SG_ 827 SRR_RL_ObjBoxCenterLat_3 250;
BA_ "GenSigStartValue" SG_ 827 SRR_RL_ObjDistX_4 2048;
BA_ "GenSigStartValue" SG_ 827 SRR_RL_ObjRelVelX_4 2048;
BA_ "GenSigStartValue" SG_ 827 SRR_RL_ObjDistY_4 8192;
BA_ "GenSigStartValue" SG_ 827 SRR_RL_ObjRelVelY_4 2048;
BA_ "GenSigStartValue" SG_ 827 SRR_RL_ObjAccelX_4 512;
BA_ "GenSigStartValue" SG_ 827 SRR_RL_ObjAccelY_4 512;
BA_ "GenSigStartValue" SG_ 827 SRR_RL_ObjHeading_4 1800;
BA_ "GenSigStartValue" SG_ 827 SRR_RL_ObjBoxCenterLgt_4 250;
BA_ "GenSigStartValue" SG_ 827 SRR_RL_ObjBoxCenterLat_4 250;
BA_ "GenSigStartValue" SG_ 828 SRR_RL_ObjDistX_5 2048;
BA_ "GenSigStartValue" SG_ 828 SRR_RL_ObjRelVelX_5 2048;
BA_ "GenSigStartValue" SG_ 828 SRR_RL_ObjDistY_5 8192;
BA_ "GenSigStartValue" SG_ 828 SRR_RL_ObjRelVelY_5 2048;
BA_ "GenSigStartValue" SG_ 828 SRR_RL_ObjAccelX_5 512;
BA_ "GenSigStartValue" SG_ 828 SRR_RL_ObjAccelY_5 512;
BA_ "GenSigStartValue" SG_ 828 SRR_RL_ObjHeading_5 1800;
BA_ "GenSigStartValue" SG_ 828 SRR_RL_ObjBoxCenterLgt_5 250;
BA_ "GenSigStartValue" SG_ 828 SRR_RL_ObjBoxCenterLat_5 250;
BA_ "GenSigStartValue" SG_ 828 SRR_RL_ObjDistX_6 2048;
BA_ "GenSigStartValue" SG_ 828 SRR_RL_ObjRelVelX_6 2048;
BA_ "GenSigStartValue" SG_ 828 SRR_RL_ObjDistY_6 8192;
BA_ "GenSigStartValue" SG_ 828 SRR_RL_ObjRelVelY_6 2048;
BA_ "GenSigStartValue" SG_ 828 SRR_RL_ObjAccelX_6 512;
BA_ "GenSigStartValue" SG_ 828 SRR_RL_ObjAccelY_6 512;
BA_ "GenSigStartValue" SG_ 828 SRR_RL_ObjHeading_6 1800;
BA_ "GenSigStartValue" SG_ 828 SRR_RL_ObjBoxCenterLgt_6 250;
BA_ "GenSigStartValue" SG_ 828 SRR_RL_ObjBoxCenterLat_6 250;
BA_ "GenSigStartValue" SG_ 829 SRR_RL_ObjDistX_7 2048;
BA_ "GenSigStartValue" SG_ 829 SRR_RL_ObjRelVelX_7 2048;
BA_ "GenSigStartValue" SG_ 829 SRR_RL_ObjDistY_7 8192;
BA_ "GenSigStartValue" SG_ 829 SRR_RL_ObjRelVelY_7 2048;
BA_ "GenSigStartValue" SG_ 829 SRR_RL_ObjAccelX_7 512;
BA_ "GenSigStartValue" SG_ 829 SRR_RL_ObjAccelY_7 512;
BA_ "GenSigStartValue" SG_ 829 SRR_RL_ObjHeading_7 1800;
BA_ "GenSigStartValue" SG_ 829 SRR_RL_ObjBoxCenterLgt_7 250;
BA_ "GenSigStartValue" SG_ 829 SRR_RL_ObjBoxCenterLat_7 250;
BA_ "GenSigStartValue" SG_ 829 SRR_RL_ObjDistX_8 2048;
BA_ "GenSigStartValue" SG_ 829 SRR_RL_ObjRelVelX_8 2048;
BA_ "GenSigStartValue" SG_ 829 SRR_RL_ObjDistY_8 8192;
BA_ "GenSigStartValue" SG_ 829 SRR_RL_ObjRelVelY_8 2048;
BA_ "GenSigStartValue" SG_ 829 SRR_RL_ObjAccelX_8 512;
BA_ "GenSigStartValue" SG_ 829 SRR_RL_ObjAccelY_8 512;
BA_ "GenSigStartValue" SG_ 829 SRR_RL_ObjHeading_8 1800;
BA_ "GenSigStartValue" SG_ 829 SRR_RL_ObjBoxCenterLgt_8 250;
BA_ "GenSigStartValue" SG_ 829 SRR_RL_ObjBoxCenterLat_8 250;
BA_ "GenSigStartValue" SG_ 830 SRR_RL_ObjDistX_9 2048;
BA_ "GenSigStartValue" SG_ 830 SRR_RL_ObjRelVelX_9 2048;
BA_ "GenSigStartValue" SG_ 830 SRR_RL_ObjDistY_9 8192;
BA_ "GenSigStartValue" SG_ 830 SRR_RL_ObjRelVelY_9 2048;
BA_ "GenSigStartValue" SG_ 830 SRR_RL_ObjAccelX_9 512;
BA_ "GenSigStartValue" SG_ 830 SRR_RL_ObjAccelY_9 512;
BA_ "GenSigStartValue" SG_ 830 SRR_RL_ObjHeading_9 1800;
BA_ "GenSigStartValue" SG_ 830 SRR_RL_ObjBoxCenterLgt_9 250;
BA_ "GenSigStartValue" SG_ 830 SRR_RL_ObjBoxCenterLat_9 250;
BA_ "GenSigStartValue" SG_ 830 SRR_RL_ObjDistX_10 2048;
BA_ "GenSigStartValue" SG_ 830 SRR_RL_ObjRelVelX_10 2048;
BA_ "GenSigStartValue" SG_ 830 SRR_RL_ObjDistY_10 8192;
BA_ "GenSigStartValue" SG_ 830 SRR_RL_ObjRelVelY_10 2048;
BA_ "GenSigStartValue" SG_ 830 SRR_RL_ObjAccelX_10 512;
BA_ "GenSigStartValue" SG_ 830 SRR_RL_ObjAccelY_10 512;
BA_ "GenSigStartValue" SG_ 830 SRR_RL_ObjHeading_10 1800;
BA_ "GenSigStartValue" SG_ 830 SRR_RL_ObjBoxCenterLgt_10 250;
BA_ "GenSigStartValue" SG_ 830 SRR_RL_ObjBoxCenterLat_10 250;
BA_ "GenSigStartValue" SG_ 831 SRR_RL_ObjDistX_11 2048;
BA_ "GenSigStartValue" SG_ 831 SRR_RL_ObjRelVelX_11 2048;
BA_ "GenSigStartValue" SG_ 831 SRR_RL_ObjDistY_11 8192;
BA_ "GenSigStartValue" SG_ 831 SRR_RL_ObjRelVelY_11 2048;
BA_ "GenSigStartValue" SG_ 831 SRR_RL_ObjAccelX_11 512;
BA_ "GenSigStartValue" SG_ 831 SRR_RL_ObjAccelY_11 512;
BA_ "GenSigStartValue" SG_ 831 SRR_RL_ObjHeading_11 1800;
BA_ "GenSigStartValue" SG_ 831 SRR_RL_ObjBoxCenterLgt_11 250;
BA_ "GenSigStartValue" SG_ 831 SRR_RL_ObjBoxCenterLat_11 250;
BA_ "GenSigStartValue" SG_ 831 SRR_RL_ObjDistX_12 2048;
BA_ "GenSigStartValue" SG_ 831 SRR_RL_ObjRelVelX_12 2048;
BA_ "GenSigStartValue" SG_ 831 SRR_RL_ObjDistY_12 8192;
BA_ "GenSigStartValue" SG_ 831 SRR_RL_ObjRelVelY_12 2048;
BA_ "GenSigStartValue" SG_ 831 SRR_RL_ObjAccelX_12 512;
BA_ "GenSigStartValue" SG_ 831 SRR_RL_ObjAccelY_12 512;
BA_ "GenSigStartValue" SG_ 831 SRR_RL_ObjHeading_12 1800;
BA_ "GenSigStartValue" SG_ 831 SRR_RL_ObjBoxCenterLgt_12 250;
BA_ "GenSigStartValue" SG_ 831 SRR_RL_ObjBoxCenterLat_12 250;
BA_ "GenSigStartValue" SG_ 832 SRR_RL_ObjDistX_13 2048;
BA_ "GenSigStartValue" SG_ 832 SRR_RL_ObjRelVelX_13 2048;
BA_ "GenSigStartValue" SG_ 832 SRR_RL_ObjDistY_13 8192;
BA_ "GenSigStartValue" SG_ 832 SRR_RL_ObjRelVelY_13 2048;
BA_ "GenSigStartValue" SG_ 832 SRR_RL_ObjAccelX_13 512;
BA_ "GenSigStartValue" SG_ 832 SRR_RL_ObjAccelY_13 512;
BA_ "GenSigStartValue" SG_ 832 SRR_RL_ObjHeading_13 1800;
BA_ "GenSigStartValue" SG_ 832 SRR_RL_ObjBoxCenterLgt_13 250;
BA_ "GenSigStartValue" SG_ 832 SRR_RL_ObjBoxCenterLat_13 250;
BA_ "GenSigStartValue" SG_ 832 SRR_RL_ObjDistX_14 2048;
BA_ "GenSigStartValue" SG_ 832 SRR_RL_ObjRelVelX_14 2048;
BA_ "GenSigStartValue" SG_ 832 SRR_RL_ObjDistY_14 8192;
BA_ "GenSigStartValue" SG_ 832 SRR_RL_ObjRelVelY_14 2048;
BA_ "GenSigStartValue" SG_ 832 SRR_RL_ObjAccelX_14 512;
BA_ "GenSigStartValue" SG_ 832 SRR_RL_ObjAccelY_14 512;
BA_ "GenSigStartValue" SG_ 832 SRR_RL_ObjHeading_14 1800;
BA_ "GenSigStartValue" SG_ 832 SRR_RL_ObjBoxCenterLgt_14 250;
BA_ "GenSigStartValue" SG_ 832 SRR_RL_ObjBoxCenterLat_14 250;
BA_ "GenSigStartValue" SG_ 833 SRR_RL_ObjDistX_15 2048;
BA_ "GenSigStartValue" SG_ 833 SRR_RL_ObjRelVelX_15 2048;
BA_ "GenSigStartValue" SG_ 833 SRR_RL_ObjDistY_15 8192;
BA_ "GenSigStartValue" SG_ 833 SRR_RL_ObjRelVelY_15 2048;
BA_ "GenSigStartValue" SG_ 833 SRR_RL_ObjAccelX_15 512;
BA_ "GenSigStartValue" SG_ 833 SRR_RL_ObjAccelY_15 512;
BA_ "GenSigStartValue" SG_ 833 SRR_RL_ObjHeading_15 1800;
BA_ "GenSigStartValue" SG_ 833 SRR_RL_ObjBoxCenterLgt_15 250;
BA_ "GenSigStartValue" SG_ 833 SRR_RL_ObjBoxCenterLat_15 250;
BA_ "GenSigStartValue" SG_ 833 SRR_RL_ObjDistX_16 2048;
BA_ "GenSigStartValue" SG_ 833 SRR_RL_ObjRelVelX_16 2048;
BA_ "GenSigStartValue" SG_ 833 SRR_RL_ObjDistY_16 8192;
BA_ "GenSigStartValue" SG_ 833 SRR_RL_ObjRelVelY_16 2048;
BA_ "GenSigStartValue" SG_ 833 SRR_RL_ObjAccelX_16 512;
BA_ "GenSigStartValue" SG_ 833 SRR_RL_ObjAccelY_16 512;
BA_ "GenSigStartValue" SG_ 833 SRR_RL_ObjHeading_16 1800;
BA_ "GenSigStartValue" SG_ 833 SRR_RL_ObjBoxCenterLgt_16 250;
BA_ "GenSigStartValue" SG_ 833 SRR_RL_ObjBoxCenterLat_16 250;
BA_ "GenSigStartValue" SG_ 835 SRR_RR_ObjDistX_1 2048;
BA_ "GenSigStartValue" SG_ 835 SRR_RR_ObjRelVelX_1 2048;
BA_ "GenSigStartValue" SG_ 835 SRR_RR_ObjDistY_1 8192;
BA_ "GenSigStartValue" SG_ 835 SRR_RR_ObjRelVelY_1 2048;
BA_ "GenSigStartValue" SG_ 835 SRR_RR_ObjAccelX_1 512;
BA_ "GenSigStartValue" SG_ 835 SRR_RR_ObjAccelY_1 512;
BA_ "GenSigStartValue" SG_ 835 SRR_RR_ObjHeading_1 1800;
BA_ "GenSigStartValue" SG_ 835 SRR_RR_ObjBoxCenterLgt_1 250;
BA_ "GenSigStartValue" SG_ 835 SRR_RR_ObjBoxCenterLat_1 250;
BA_ "GenSigStartValue" SG_ 835 SRR_RR_ObjDistX_2 2048;
BA_ "GenSigStartValue" SG_ 835 SRR_RR_ObjRelVelX_2 2048;
BA_ "GenSigStartValue" SG_ 835 SRR_RR_ObjDistY_2 8192;
BA_ "GenSigStartValue" SG_ 835 SRR_RR_ObjRelVelY_2 2048;
BA_ "GenSigStartValue" SG_ 835 SRR_RR_ObjAccelX_2 512;
BA_ "GenSigStartValue" SG_ 835 SRR_RR_ObjAccelY_2 512;
BA_ "GenSigStartValue" SG_ 835 SRR_RR_ObjHeading_2 1800;
BA_ "GenSigStartValue" SG_ 835 SRR_RR_ObjBoxCenterLgt_2 250;
BA_ "GenSigStartValue" SG_ 835 SRR_RR_ObjBoxCenterLat_2 250;
BA_ "GenSigStartValue" SG_ 836 SRR_RR_ObjDistX_3 2048;
BA_ "GenSigStartValue" SG_ 836 SRR_RR_ObjRelVelX_3 2048;
BA_ "GenSigStartValue" SG_ 836 SRR_RR_ObjDistY_3 8192;
BA_ "GenSigStartValue" SG_ 836 SRR_RR_ObjRelVelY_3 2048;
BA_ "GenSigStartValue" SG_ 836 SRR_RR_ObjAccelX_3 512;
BA_ "GenSigStartValue" SG_ 836 SRR_RR_ObjAccelY_3 512;
BA_ "GenSigStartValue" SG_ 836 SRR_RR_ObjHeading_3 1800;
BA_ "GenSigStartValue" SG_ 836 SRR_RR_ObjBoxCenterLgt_3 250;
BA_ "GenSigStartValue" SG_ 836 SRR_RR_ObjBoxCenterLat_3 250;
BA_ "GenSigStartValue" SG_ 836 SRR_RR_ObjDistX_4 2048;
BA_ "GenSigStartValue" SG_ 836 SRR_RR_ObjRelVelX_4 2048;
BA_ "GenSigStartValue" SG_ 836 SRR_RR_ObjDistY_4 8192;
BA_ "GenSigStartValue" SG_ 836 SRR_RR_ObjRelVelY_4 2048;
BA_ "GenSigStartValue" SG_ 836 SRR_RR_ObjAccelX_4 512;
BA_ "GenSigStartValue" SG_ 836 SRR_RR_ObjAccelY_4 512;
BA_ "GenSigStartValue" SG_ 836 SRR_RR_ObjHeading_4 1800;
BA_ "GenSigStartValue" SG_ 836 SRR_RR_ObjBoxCenterLgt_4 250;
BA_ "GenSigStartValue" SG_ 836 SRR_RR_ObjBoxCenterLat_4 250;
BA_ "GenSigStartValue" SG_ 837 SRR_RR_ObjDistX_5 2048;
BA_ "GenSigStartValue" SG_ 837 SRR_RR_ObjRelVelX_5 2048;
BA_ "GenSigStartValue" SG_ 837 SRR_RR_ObjDistY_5 8192;
BA_ "GenSigStartValue" SG_ 837 SRR_RR_ObjRelVelY_5 2048;
BA_ "GenSigStartValue" SG_ 837 SRR_RR_ObjAccelX_5 512;
BA_ "GenSigStartValue" SG_ 837 SRR_RR_ObjAccelY_5 512;
BA_ "GenSigStartValue" SG_ 837 SRR_RR_ObjHeading_5 1800;
BA_ "GenSigStartValue" SG_ 837 SRR_RR_ObjBoxCenterLgt_5 250;
BA_ "GenSigStartValue" SG_ 837 SRR_RR_ObjBoxCenterLat_5 250;
BA_ "GenSigStartValue" SG_ 837 SRR_RR_ObjDistX_6 2048;
BA_ "GenSigStartValue" SG_ 837 SRR_RR_ObjRelVelX_6 2048;
BA_ "GenSigStartValue" SG_ 837 SRR_RR_ObjDistY_6 8192;
BA_ "GenSigStartValue" SG_ 837 SRR_RR_ObjRelVelY_6 2048;
BA_ "GenSigStartValue" SG_ 837 SRR_RR_ObjAccelX_6 512;
BA_ "GenSigStartValue" SG_ 837 SRR_RR_ObjAccelY_6 512;
BA_ "GenSigStartValue" SG_ 837 SRR_RR_ObjHeading_6 1800;
BA_ "GenSigStartValue" SG_ 837 SRR_RR_ObjBoxCenterLgt_6 250;
BA_ "GenSigStartValue" SG_ 837 SRR_RR_ObjBoxCenterLat_6 250;
BA_ "GenSigStartValue" SG_ 838 SRR_RR_ObjDistX_7 2048;
BA_ "GenSigStartValue" SG_ 838 SRR_RR_ObjRelVelX_7 2048;
BA_ "GenSigStartValue" SG_ 838 SRR_RR_ObjDistY_7 8192;
BA_ "GenSigStartValue" SG_ 838 SRR_RR_ObjRelVelY_7 2048;
BA_ "GenSigStartValue" SG_ 838 SRR_RR_ObjAccelX_7 512;
BA_ "GenSigStartValue" SG_ 838 SRR_RR_ObjAccelY_7 512;
BA_ "GenSigStartValue" SG_ 838 SRR_RR_ObjHeading_7 1800;
BA_ "GenSigStartValue" SG_ 838 SRR_RR_ObjBoxCenterLgt_7 250;
BA_ "GenSigStartValue" SG_ 838 SRR_RR_ObjBoxCenterLat_7 250;
BA_ "GenSigStartValue" SG_ 838 SRR_RR_ObjDistX_8 2048;
BA_ "GenSigStartValue" SG_ 838 SRR_RR_ObjRelVelX_8 2048;
BA_ "GenSigStartValue" SG_ 838 SRR_RR_ObjDistY_8 8192;
BA_ "GenSigStartValue" SG_ 838 SRR_RR_ObjRelVelY_8 2048;
BA_ "GenSigStartValue" SG_ 838 SRR_RR_ObjAccelX_8 512;
BA_ "GenSigStartValue" SG_ 838 SRR_RR_ObjAccelY_8 512;
BA_ "GenSigStartValue" SG_ 838 SRR_RR_ObjHeading_8 1800;
BA_ "GenSigStartValue" SG_ 838 SRR_RR_ObjBoxCenterLgt_8 250;
BA_ "GenSigStartValue" SG_ 838 SRR_RR_ObjBoxCenterLat_8 250;
BA_ "GenSigStartValue" SG_ 839 SRR_RR_ObjDistX_9 2048;
BA_ "GenSigStartValue" SG_ 839 SRR_RR_ObjRelVelX_9 2048;
BA_ "GenSigStartValue" SG_ 839 SRR_RR_ObjDistY_9 8192;
BA_ "GenSigStartValue" SG_ 839 SRR_RR_ObjRelVelY_9 2048;
BA_ "GenSigStartValue" SG_ 839 SRR_RR_ObjAccelX_9 512;
BA_ "GenSigStartValue" SG_ 839 SRR_RR_ObjAccelY_9 512;
BA_ "GenSigStartValue" SG_ 839 SRR_RR_ObjHeading_9 1800;
BA_ "GenSigStartValue" SG_ 839 SRR_RR_ObjBoxCenterLgt_9 250;
BA_ "GenSigStartValue" SG_ 839 SRR_RR_ObjBoxCenterLat_9 250;
BA_ "GenSigStartValue" SG_ 839 SRR_RR_ObjDistX_10 2048;
BA_ "GenSigStartValue" SG_ 839 SRR_RR_ObjRelVelX_10 2048;
BA_ "GenSigStartValue" SG_ 839 SRR_RR_ObjDistY_10 8192;
BA_ "GenSigStartValue" SG_ 839 SRR_RR_ObjRelVelY_10 2048;
BA_ "GenSigStartValue" SG_ 839 SRR_RR_ObjAccelX_10 512;
BA_ "GenSigStartValue" SG_ 839 SRR_RR_ObjAccelY_10 512;
BA_ "GenSigStartValue" SG_ 839 SRR_RR_ObjHeading_10 1800;
BA_ "GenSigStartValue" SG_ 839 SRR_RR_ObjBoxCenterLgt_10 250;
BA_ "GenSigStartValue" SG_ 839 SRR_RR_ObjBoxCenterLat_10 250;
BA_ "GenSigStartValue" SG_ 840 SRR_RR_ObjDistX_11 2048;
BA_ "GenSigStartValue" SG_ 840 SRR_RR_ObjRelVelX_11 2048;
BA_ "GenSigStartValue" SG_ 840 SRR_RR_ObjDistY_11 8192;
BA_ "GenSigStartValue" SG_ 840 SRR_RR_ObjRelVelY_11 2048;
BA_ "GenSigStartValue" SG_ 840 SRR_RR_ObjAccelX_11 512;
BA_ "GenSigStartValue" SG_ 840 SRR_RR_ObjAccelY_11 512;
BA_ "GenSigStartValue" SG_ 840 SRR_RR_ObjHeading_11 1800;
BA_ "GenSigStartValue" SG_ 840 SRR_RR_ObjBoxCenterLgt_11 250;
BA_ "GenSigStartValue" SG_ 840 SRR_RR_ObjBoxCenterLat_11 250;
BA_ "GenSigStartValue" SG_ 840 SRR_RR_ObjDistX_12 2048;
BA_ "GenSigStartValue" SG_ 840 SRR_RR_ObjRelVelX_12 2048;
BA_ "GenSigStartValue" SG_ 840 SRR_RR_ObjDistY_12 8192;
BA_ "GenSigStartValue" SG_ 840 SRR_RR_ObjRelVelY_12 2048;
BA_ "GenSigStartValue" SG_ 840 SRR_RR_ObjAccelX_12 512;
BA_ "GenSigStartValue" SG_ 840 SRR_RR_ObjAccelY_12 512;
BA_ "GenSigStartValue" SG_ 840 SRR_RR_ObjHeading_12 1800;
BA_ "GenSigStartValue" SG_ 840 SRR_RR_ObjBoxCenterLgt_12 250;
BA_ "GenSigStartValue" SG_ 840 SRR_RR_ObjBoxCenterLat_12 250;
BA_ "GenSigStartValue" SG_ 841 SRR_RR_ObjDistX_13 2048;
BA_ "GenSigStartValue" SG_ 841 SRR_RR_ObjRelVelX_13 2048;
BA_ "GenSigStartValue" SG_ 841 SRR_RR_ObjDistY_13 8192;
BA_ "GenSigStartValue" SG_ 841 SRR_RR_ObjRelVelY_13 2048;
BA_ "GenSigStartValue" SG_ 841 SRR_RR_ObjAccelX_13 512;
BA_ "GenSigStartValue" SG_ 841 SRR_RR_ObjAccelY_13 512;
BA_ "GenSigStartValue" SG_ 841 SRR_RR_ObjHeading_13 1800;
BA_ "GenSigStartValue" SG_ 841 SRR_RR_ObjBoxCenterLgt_13 250;
BA_ "GenSigStartValue" SG_ 841 SRR_RR_ObjBoxCenterLat_13 250;
BA_ "GenSigStartValue" SG_ 841 SRR_RR_ObjDistX_14 2048;
BA_ "GenSigStartValue" SG_ 841 SRR_RR_ObjRelVelX_14 2048;
BA_ "GenSigStartValue" SG_ 841 SRR_RR_ObjDistY_14 8192;
BA_ "GenSigStartValue" SG_ 841 SRR_RR_ObjRelVelY_14 2048;
BA_ "GenSigStartValue" SG_ 841 SRR_RR_ObjAccelX_14 512;
BA_ "GenSigStartValue" SG_ 841 SRR_RR_ObjAccelY_14 512;
BA_ "GenSigStartValue" SG_ 841 SRR_RR_ObjHeading_14 1800;
BA_ "GenSigStartValue" SG_ 841 SRR_RR_ObjBoxCenterLgt_14 250;
BA_ "GenSigStartValue" SG_ 841 SRR_RR_ObjBoxCenterLat_14 250;
BA_ "GenSigStartValue" SG_ 848 SRR_RR_ObjDistX_15 2048;
BA_ "GenSigStartValue" SG_ 848 SRR_RR_ObjRelVelX_15 2048;
BA_ "GenSigStartValue" SG_ 848 SRR_RR_ObjDistY_15 8192;
BA_ "GenSigStartValue" SG_ 848 SRR_RR_ObjRelVelY_15 2048;
BA_ "GenSigStartValue" SG_ 848 SRR_RR_ObjAccelX_15 512;
BA_ "GenSigStartValue" SG_ 848 SRR_RR_ObjAccelY_15 512;
BA_ "GenSigStartValue" SG_ 848 SRR_RR_ObjHeading_15 1800;
BA_ "GenSigStartValue" SG_ 848 SRR_RR_ObjBoxCenterLgt_15 250;
BA_ "GenSigStartValue" SG_ 848 SRR_RR_ObjBoxCenterLat_15 250;
BA_ "GenSigStartValue" SG_ 848 SRR_RR_ObjDistX_16 2048;
BA_ "GenSigStartValue" SG_ 848 SRR_RR_ObjRelVelX_16 2048;
BA_ "GenSigStartValue" SG_ 848 SRR_RR_ObjDistY_16 8192;
BA_ "GenSigStartValue" SG_ 848 SRR_RR_ObjRelVelY_16 2048;
BA_ "GenSigStartValue" SG_ 848 SRR_RR_ObjAccelX_16 512;
BA_ "GenSigStartValue" SG_ 848 SRR_RR_ObjAccelY_16 512;
BA_ "GenSigStartValue" SG_ 848 SRR_RR_ObjHeading_16 1800;
BA_ "GenSigStartValue" SG_ 848 SRR_RR_ObjBoxCenterLgt_16 250;
BA_ "GenSigStartValue" SG_ 848 SRR_RR_ObjBoxCenterLat_16 250;
BA_ "GenSigStartValue" SG_ 529 ACU3_Delta_Vx_0 127;
BA_ "GenSigStartValue" SG_ 529 ACU3_Delta_Vx_1 127;
BA_ "GenSigStartValue" SG_ 529 ACU3_Delta_Vx_2 127;
BA_ "GenSigStartValue" SG_ 529 ACU3_Delta_Vx_3 127;
BA_ "GenSigStartValue" SG_ 529 ACU3_Delta_Vx_4 127;
BA_ "GenSigStartValue" SG_ 529 ACU3_Delta_Vx_5 127;
BA_ "GenSigStartValue" SG_ 530 ACU4_Delta_Vy_0 127;
BA_ "GenSigStartValue" SG_ 530 ACU4_Delta_Vy_1 127;
BA_ "GenSigStartValue" SG_ 530 ACU4_Delta_Vy_2 127;
BA_ "GenSigStartValue" SG_ 530 ACU4_Delta_Vy_3 127;
BA_ "GenSigStartValue" SG_ 530 ACU4_Delta_Vy_4 127;
BA_ "GenSigStartValue" SG_ 530 ACU4_Delta_Vy_5 127;
BA_ "GenSigInvalidValue" SG_ 196 ACU2_LatAccSensorValue 2047;
BA_ "GenSigInvalidValue" SG_ 196 ACU2_LongAccSensorValue 2047;
BA_ "GenSigInvalidValue" SG_ 196 ACU2_VehicleDynYawRate 8191;
BA_ "GenSigStartValue" SG_ 258 ACU1_PAB_State 1;
VAL_ 528 ADCS9_AVM_MODdetectionSts 1 "Closed" 0 "Open";
VAL_ 528 ADCS9_AVM_TransparentchassisSts 1 "Closed" 0 "Open";
VAL_ 528 ADCS9_PA_FRS_Onoffset 1 "On（开启）" 0 "Off（关闭）";
VAL_ 528 ADCS9_AVM_Diaphaneity 10 "100%" 9 "90%" 8 "80%" 7 "70%" 6 "60%" 5 "50%" 4 "40%" 3 "30%" 2 "20%" 1 "10%" 0 "0%";
VAL_ 528 ADCS9_AVM_startMode 7 "Reserved" 6 "Reserved" 5 "Reserved" 4 "Reserved" 3 "Reserved" 2 "24h" 1 "12h" 0 "0h";
VAL_ 528 ADCS9_CDCS_CertificateState 1 "有效" 0 "无效";
VAL_ 528 ADCS9_AVMFrontCAMFault 2 "Sensor Fault" 1 "Blocked" 0 "Normal";
VAL_ 528 ADCS9_AVMLeftCAMFault 2 "Sensor Fault" 1 "Blocked" 0 "Normal";
VAL_ 528 ADCS9_AVMRightCAMFault 2 "Sensor Fault" 1 "Blocked" 0 "Normal";
VAL_ 528 ADCS9_AVMRearCAMFault 2 "Sensor Fault" 1 "Blocked" 0 "Normal";
VAL_ 528 ADCS9_HPA_OnOffSetSts 1 "Off" 0 "On";
VAL_ 528 ADCS9_AVM_InitializationSts 1 "Initialization success" 0 "Default";
VAL_ 528 ADCS9_AVM_bodySyncSts 1 "Closed" 0 "Open";
VAL_ 528 ADCS9_AVM_3DRotateSts 1 "Closed" 0 "Open";
VAL_ 528 ADCS9_AVM_TurnlightstartSts 1 "Closed" 0 "Open";
VAL_ 528 ADCS9_AVM_SteeringstartSts 1 "Closed" 0 "Open";
VAL_ 528 ADCS9_AVM_MagnifiedviewSts 1 "Closed" 0 "Open";
VAL_ 528 ADCS9_AVM_auxiliarylineSts 1 "Closed" 0 "Open";
VAL_ 528 ADCS9_AVM_RaderdisplaySts 1 "Closed" 0 "Open";
VAL_ 528 ADCS9_AVM_LowSpeedBSDSts 1 "Closed" 0 "Open";
VAL_ 528 ADCS9_AVM_SpeViewSts 2 "Rear wide view" 1 "Front wide view" 0 "Default";
VAL_ 613 ADCS1_CarMdlDispSts 1 "3D mode" 0 "2D mode";
VAL_ 613 ADCS1_GuidOvlDispSts 3 "N无轨迹线" 2 "仅后视角显示轨迹线" 1 "仅环视轨迹线" 0 "全部视角+轨迹线";
VAL_ 613 ADCS1_MOD_WorkSts 1 "ON" 0 "OFF";
VAL_ 613 ADCS1_MOD_AlarmSts 1 "ON" 0 "OFF";
VAL_ 613 ADCS1_CarMdlTrsprcySts 3 "Reserved" 2 "Completely Transparent" 1 "Translucent" 0 "Opaque";
VAL_ 613 ADCS1_AutoViewChgFuncSts 1 "ON" 0 "OFF";
VAL_ 613 ADCS1_SigViewIndcn 3 "右视角" 2 "左视角" 1 "后视角" 0 "前视角";
VAL_ 613 ADCS1_AutoAVMSwtSet_Sts 1 "ON" 0 "OFF";
VAL_ 842 FLC_SRObject_RlvTgt01Detn 3 "Invalid" 2 "Reserved" 1 "Dectected" 0 "Not dectected";
VAL_ 842 FLC_SRObject_RlvTgt01Typ 7 "Invalid" 6 "Reserved(预留)" 5 "Bicycle(自行车)" 4 "Pedestrian(行人)" 3 "Motorcycle(摩托车)" 2 "Truck(卡车)" 1 "Sedan(轿车)" 0 "Unkown(未知)";
VAL_ 842 FLC_SRObject_LeTgt02Typ 7 "Invalid" 6 "Reserved(预留)" 5 "Bicycle(自行车)" 4 "Pedestrian(行人)" 3 "Motorcycle(摩托车)" 2 "Truck(卡车)" 1 "Sedan(轿车)" 0 "Unkown(未知)";
VAL_ 842 FLC_SRObject_RlvTgt02Detn 3 "Invalid" 2 "Reserved" 1 "Dectected" 0 "Not dectected";
VAL_ 842 FLC_SRObject_RlvTgt02Typ 7 "Invalid" 6 "Reserved(预留)" 5 "Bicycle(自行车)" 4 "Pedestrian(行人)" 3 "Motorcycle(摩托车)" 2 "Truck(卡车)" 1 "Sedan(轿车)" 0 "Unkown(未知)";
VAL_ 842 FLC_SRObject_RiTgt01Detn 3 "Invalid" 2 "Reserved" 1 "Dectected" 0 "Not dectected";
VAL_ 842 FLC_SRObject_RiTgt01Typ 7 "Invalid" 6 "Reserved(预留)" 5 "Bicycle(自行车)" 4 "Pedestrian(行人)" 3 "Motorcycle(摩托车)" 2 "Truck(卡车)" 1 "Sedan(轿车)" 0 "Unkown(未知)";
VAL_ 842 FLC_SRObject_RiTgt02Detn 3 "Invalid" 2 "Reserved" 1 "Dectected" 0 "Not dectected";
VAL_ 842 FLC_SRObject_RiTgt02Typ 7 "Invalid" 6 "Reserved(预留)" 5 "Bicycle(自行车)" 4 "Pedestrian(行人)" 3 "Motorcycle(摩托车)" 2 "Truck(卡车)" 1 "Sedan(轿车)" 0 "Unkown(未知)";
VAL_ 842 FLC_SRObject_LeTgt01Detn 3 "Invalid" 2 "Reserved" 1 "Dectected" 0 "Not dectected";
VAL_ 842 FLC_SRObject_LeTgt01Typ 7 "Invalid" 6 "Reserved(预留)" 5 "Bicycle(自行车)" 4 "Pedestrian(行人)" 3 "Motorcycle(摩托车)" 2 "Truck(卡车)" 1 "Sedan(轿车)" 0 "Unkown(未知)";
VAL_ 842 FLC_SRObject_LeTgt02Detn 3 "Invalid" 2 "Reserved" 1 "Dectected" 0 "Not dectected";
VAL_ 843 FLC_NextRightLane_Type 15 "fishbone_dashed" 14 "fishbone_solid" 13 "cones_poles" 12 "curb" 11 "elevated_structure" 10 "road edge" 9 "hov_lane" 8 "deceleration" 7 "botts" 6 "double dashed dashed" 5 "double solid solid" 4 "double dashed solid" 3 "double solid dashed" 2 "dashed" 1 "solid" 0 "undecided";
VAL_ 843 FLC_RightLane_Type 15 "fishbone_dashed" 14 "fishbone_solid" 13 "cones_poles" 12 "curb" 11 "elevated_structure" 10 "road edge" 9 "hov_lane" 8 "deceleration" 7 "botts" 6 "double dashed dashed" 5 "double solid solid" 4 "double dashed solid" 3 "double solid dashed" 2 "dashed" 1 "solid" 0 "undecided";
VAL_ 843 FLC_LeftLane_Type 15 "fishbone_dashed" 14 "fishbone_solid" 13 "cones_poles" 12 "curb" 11 "elevated_structure" 10 "road edge" 9 "hov_lane" 8 "deceleration" 7 "botts" 6 "double dashed dashed" 5 "double solid solid" 4 "double dashed solid" 3 "double solid dashed" 2 "dashed" 1 "solid" 0 "undecided";
VAL_ 843 FLC_NextLeftLane_Type 15 "fishbone_dashed" 14 "fishbone_solid" 13 "cones_poles" 12 "curb" 11 "elevated_structure" 10 "road edge" 9 "hov_lane" 8 "deceleration" 7 "botts" 6 "double dashed dashed" 5 "double solid solid" 4 "double dashed solid" 3 "double solid dashed" 2 "dashed" 1 "solid" 0 "undecided";
VAL_ 1543 ADCS_RepeatMessageRequest 1 "Repeat message request" 0 "No repeat message request";
VAL_ 1543 ADCS_ActiveWakeup 1 "Wakeup" 0 "No wakeup";
VAL_ 1543 ADCS_WakeUp_KL15 1 "KL15 ON Wakeup" 0 "No Request";
VAL_ 1543 ADCS_WakeUp_NM 1 "NM Wakeup" 0 "No Request";
VAL_ 1543 ADCS_WakeUp_GM 1 "Wakeup Requrst" 0 "No Request";
VAL_ 1543 ADCS_WakeUpReason4 1 "Wakeup Requrst" 0 "No Request";
VAL_ 1543 ADCS_WakeUpReason5 1 "Wakeup Requrst" 0 "No Request";
VAL_ 1543 ADCS_WakeUpReason6 1 "Wakeup Requrst" 0 "No Request";
VAL_ 1543 ADCS_WakeUpReason7 1 "Wakeup Requrst" 0 "No Request";
VAL_ 1543 ADCS_WakeUpReason8 1 "Wakeup Requrst" 0 "No Request";
VAL_ 1543 ADCS_RepeatFromSleep 1 "occur" 0 "not occur";
VAL_ 1543 ADCS_RepeatFromPrepare 1 "occur" 0 "not occur";
VAL_ 1543 ADCS_NormalFromRepeat 1 "occur" 0 "not occur";
VAL_ 1543 ADCS_NormalFromReady 1 "occur" 0 "not occur";
VAL_ 1543 ADCS_RepeatFromReady 1 "occur" 0 "not occur";
VAL_ 1543 ADCS_RepeatFromNormal 1 "occur" 0 "not occur";
VAL_ 1543 ADCS_RNM_DOW 1 "DOW" 0 "default";
VAL_ 1543 ADCS_RNM_GM 1 "GM" 0 "default";
VAL_ 1543 ADCS_RNM_ICS 1 "ICS" 0 "default";
VAL_ 1543 ADCS_RNM_RPA 1 "RPA" 0 "default";
VAL_ 1543 ADCS_RNM_ISM 1 "ISM" 0 "default";
VAL_ 1557 ADCU_RepeatMessageRequest 1 "Repeat message request" 0 "No repeat message request";
VAL_ 1557 ADCU_ActiveWakeup 1 "Wakeup" 0 "No wakeup";
VAL_ 1557 ADCU_WakeUp_KL15 1 "KL15 ON Wakeup" 0 "No Request";
VAL_ 1557 ADCU_WakeUp_NM 1 "NM Wakeup" 0 "No Request";
VAL_ 1557 ADCU_WakeUp_GM 1 "Wakeup Requrst" 0 "No Request";
VAL_ 1557 ADCU_WakeUpReason4 1 "Wakeup Requrst" 0 "No Request";
VAL_ 1557 ADCU_WakeUpReason5 1 "Wakeup Requrst" 0 "No Request";
VAL_ 1557 ADCU_WakeUpReason6 1 "Wakeup Requrst" 0 "No Request";
VAL_ 1557 ADCU_WakeUpReason7 1 "Wakeup Requrst" 0 "No Request";
VAL_ 1557 ADCU_WakeUpReason8 1 "Wakeup Requrst" 0 "No Request";
VAL_ 1557 ADCU_RepeatFromSleep 1 "occur" 0 "not occur";
VAL_ 1557 ADCU_RepeatFromPrepare 1 "occur" 0 "not occur";
VAL_ 1557 ADCU_NormalFromRepeat 1 "occur" 0 "not occur";
VAL_ 1557 ADCU_NormalFromReady 1 "occur" 0 "not occur";
VAL_ 1557 ADCU_RepeatFromReady 1 "occur" 0 "not occur";
VAL_ 1557 ADCU_RepeatFromNormal 1 "occur" 0 "not occur";
VAL_ 1557 ADCU_RNM_GM 1 "GM" 0 "default";
VAL_ 1557 ADCU_RNM_ICS 1 "ICS" 0 "default";
VAL_ 1557 ADCU_RNM_RPA 1 "RPA" 0 "default";
VAL_ 1557 ADCU_RNM_ISM 1 "ISM" 0 "default";
VAL_ 1556 FLC_RepeatMessageRequest 1 "Repeat message request" 0 "No repeat message request";
VAL_ 1556 FLC_ActiveWakeup 1 "Wakeup" 0 "No wakeup";
VAL_ 1556 FLC_WakeUp_KL15 1 "KL15 ON Wakeup" 0 "No Request";
VAL_ 1556 FLC_WakeUp_NM 1 "NM Wakeup" 0 "No Request";
VAL_ 1556 FLC_WakeUpReason4 1 "Wakeup Requrst" 0 "No Request";
VAL_ 1556 FLC_WakeUpReason5 1 "Wakeup Requrst" 0 "No Request";
VAL_ 1556 FLC_WakeUpReason6 1 "Wakeup Requrst" 0 "No Request";
VAL_ 1556 FLC_WakeUpReason7 1 "Wakeup Requrst" 0 "No Request";
VAL_ 1556 FLC_WakeUpReason8 1 "Wakeup Requrst" 0 "No Request";
VAL_ 1556 FLC_RepeatFromSleep 1 "occur" 0 "not occur";
VAL_ 1556 FLC_RepeatFromPrepare 1 "occur" 0 "not occur";
VAL_ 1556 FLC_NormalFromRepeat 1 "occur" 0 "not occur";
VAL_ 1556 FLC_NormalFromReady 1 "occur" 0 "not occur";
VAL_ 1556 FLC_RepeatFromReady 1 "occur" 0 "not occur";
VAL_ 1556 FLC_RepeatFromNormal 1 "occur" 0 "not occur";
VAL_ 1556 FLC_RNM_DOW 1 "DOW" 0 "default";
VAL_ 615 INS_StatIns 3 "纯惯导" 2 "组合导航" 1 "卫导" 0 "初始化";
VAL_ 615 INS_StatPos 15 "Reserved" 14 "Reserved" 13 "Reserved" 12 "Reserved" 11 "Reserved" 10 "Reserved" 9 "RTK浮点解定位不定向" 8 "RTK稳定解定位不定向" 7 "伪距差分定位不定向" 6 "单点定位不定向" 5 "RTK浮点解定位定向" 4 "RTK 稳定解定位定向" 3 "组合推算" 2 "伪距差分定位定向" 1 "单点定位定向" 0 "不定位不定向";
VAL_ 1376 stat_pos 9 "RTK浮点解定位不定向" 8 "RTK稳定解定位不定向" 7 "伪距差分定位不定向" 6 "单点定位不定向" 5 "RTK浮点解定位定向" 4 "RTK 稳定解定位定向" 3 "组合推算" 2 "伪距差分定位定向" 1 "单点定位定向" 0 "不定位不定向";
VAL_ 1376 stat_ins 3 "纯惯导" 2 "组合导航" 1 "卫导" 0 "初始化";
VAL_ 1376 antenes_status 2 "天线短路" 1 "天线断路" 0 "天线整车";
VAL_ 1376 CalibrationFailReason 15 "预留" 13 "预留" 12 "固定率过低" 11 "输入参数异常" 10 "标定结果超过限值" 9 "多次标定互差超限" 3 "可视卫星不足" 2 "RTK差分服务异常" 1 "载体动态性过低" 0 "无错误";
VAL_ 1376 differential_status 1 "未收到差分报文" 0 "差分接收正常";
VAL_ 1376 Base1005_lost 1 "1005基站数据丢失" 0 "收到1005基站数据";
VAL_ 1376 Base1005_CoordinatesWrong 1 "1005基站坐标错误" 0 "1005基站坐标正常";
VAL_ 1585 IMU_RepeatMessageRequest 1 "Repeat message request" 0 "No repeat message request";
VAL_ 1585 IMU_ActiveWakeup 1 "Wakeup" 0 "No wakeup";
VAL_ 1585 IMU_WakeUp_NM 1 "NM Wakeup" 0 "No Request";
VAL_ 1585 IMU_RepeatFromSleep 1 "occur" 0 "not occur";
VAL_ 1585 IMU_RepeatFromPrepare 1 "occur" 0 "not occur";
VAL_ 1585 IMU_NormalFromRepeat 1 "occur" 0 "not occur";
VAL_ 1585 IMU_NormalFromReady 1 "occur" 0 "not occur";
VAL_ 1585 IMU_RepeatFromReady 1 "occur" 0 "not occur";
VAL_ 1585 IMU_RepeatFromNormal 1 "occur" 0 "not occur";
VAL_ 1585 IMU_RemainNetworkWakeUpReason1 1 "Remain wakeup reason" 0 "default";
VAL_ 1585 IMU_RemainNetworkWakeUpReason2 1 "Remain wakeup reason" 0 "default";
VAL_ 1585 IMU_RemainNetworkWakeUpReason3 1 "Remain wakeup reason" 0 "default";
VAL_ 1585 IMU_RemainNetworkWakeUpReason4 1 "Remain wakeup reason" 0 "default";
VAL_ 824 SRR_BsdSetFd 1 "On" 0 "Off";
VAL_ 824 SRR_BSD_warningReqRight 3 "Reserved" 2 "LV2 Warning" 1 "LV1 Warning" 0 "No warning";
VAL_ 824 SRR_BSD_warningReqLeft 3 "Reserved" 2 "LV2 Warning" 1 "LV1 Warning" 0 "No warning";
VAL_ 824 SRR_RL_Fault 2 "Radar Fault" 1 "Radar Blocked" 0 "Radar is working";
VAL_ 824 SRR_RR_Fault 2 "Radar Fault" 1 "Radar Blocked" 0 "Radar is working";
VAL_ 824 SRR_BSD_VoiceActive_St 7 "Reserved" 6 "Reserved" 5 "Reserved" 4 "Reserved" 3 "Reserved" 2 "LV2_Warning" 1 "LV1_Warning" 0 "No warning";
VAL_ 824 SRR_BSD_SysSts 7 "Reserved" 6 "OFF" 5 "System blindness" 4 "System fault" 3 "Trailer mode, all BSD function not available(Reserved)" 2 "Active" 1 "Standby" 0 "Initialization";
VAL_ 824 SRR_DOW_OnOff_fbk 1 "On" 0 "Off";
VAL_ 824 SRR_DOW_St 15 "Reserved" 14 "Reserved" 13 "Reserved" 12 "Reserved" 11 "Reserved" 10 "Reserved" 9 "Reserved" 8 "Failure" 7 "Active" 6 "Standby" 5 "Initial" 4 "OFF" 3 "Service required" 2 "System temperary unavailable" 1 "Performance degrade" 0 "No error";
VAL_ 824 SRR_DOW_FL_Warn_St 3 "Reserved" 2 "LV2 Warning" 1 "LV1 Warning" 0 "No warning";
VAL_ 824 SRR_DOW_RL_Warn_St 3 "Reserved" 2 "LV2 Warning" 1 "LV1 Warning" 0 "No warning";
VAL_ 824 SRR_DOW_FR_Warn_St 3 "Reserved" 2 "LV2 Warning" 1 "LV1 Warning" 0 "No warning";
VAL_ 824 SRR_DOW_RR_Warn_St 3 "Reserved" 2 "LV2 Warning" 1 "LV1 Warning" 0 "No warning";
VAL_ 824 SRR_FCTA_OnOff_fbk 1 "On" 0 "Off";
VAL_ 824 SRR_RCTA_Left_VoiceActive_St 7 "Reserved" 6 "Reserved" 5 "Reserved" 4 "Reserved" 3 "Reserved" 2 "RCTA_LV2_Warning" 1 "RCTA_LV1_Warning" 0 "Inactive";
VAL_ 824 SRR_FCTA_Left_Active_St 7 "Reserved" 6 "Reserved" 5 "Reserved" 4 "Reserved" 3 "Reserved" 2 "FCTA_LV2_Warning" 1 "FCTA_LV1_Warning" 0 "Inactive";
VAL_ 824 SRR_FCTA_Right_Active_St 7 "Reserved" 6 "Reserved" 5 "Reserved" 4 "Reserved" 3 "Reserved" 2 "FCTA_LV2_Warning" 1 "FCTA_LV1_Warning" 0 "Inactive";
VAL_ 824 SRR_FCTA_St 9 "Reserved" 8 "Failure" 7 "Active" 6 "Standby" 5 "Initial" 4 "OFF" 3 "Service required" 2 "System temperary unavailable" 1 "Performance degrade" 0 "No error";
VAL_ 824 SRR_DOW_VoiceActive_St 7 "Reserved" 6 "Reserved" 5 "Reserved" 4 "Reserved" 3 "Reserved" 2 "LV2_Warning" 1 "LV1_Warning" 0 "No warning";
VAL_ 824 SRR_RCTA_OnOff_fbk 1 "On" 0 "Off";
VAL_ 824 SRR_RCTA_St 9 "Reserved" 8 "Failure" 7 "Active" 6 "Standby" 5 "Initial" 4 "OFF" 3 "Service required" 2 "System temperary unavailable" 1 "Performance degrade" 0 "No error";
VAL_ 824 SRR_RCTA_Left_Active_St 7 "Reserved" 6 "Reserved" 5 "Reserved" 4 "Reserved" 3 "Reserved" 2 "RCTA_LV2_Warning" 1 "RCTA_LV1_Warning" 0 "Inactive";
VAL_ 824 SRR_RCTA_Right_Active_St 7 "Reserved" 6 "Reserved" 5 "Reserved" 4 "Reserved" 3 "Reserved" 2 "RCTA_LV2_Warning" 1 "RCTA_LV1_Warning" 0 "Inactive";
VAL_ 824 SRR_RCW_St 9 "Reserved" 8 "Failure" 7 "Active" 6 "Standby" 5 "Initial" 4 "OFF" 3 "Service required" 2 "System temperary unavailable" 1 "Performance degrade" 0 "No error";
VAL_ 824 SRR_RCW_OnOff_fbk 1 "On" 0 "Off";
VAL_ 824 SRR_RCTA_Right_VoiceActive_St 7 "Reserved" 6 "Reserved" 5 "Reserved" 4 "Reserved" 3 "Reserved" 2 "RCTA_LV2_Warning" 1 "RCTA_LV1_Warning" 0 "Inactive";
VAL_ 824 SRR_RCW_Warn_St 3 "Reserved" 2 "LV2 Warning" 1 "LV1 Warning" 0 "No warning";
VAL_ 822 SRR4_DOW_FR_Warn_St 3 "Reserved" 2 "LV2 Warning" 1 "LV1 Warning" 0 "No warning";
VAL_ 822 SRR4_DOW_RR_Warn_St 3 "Reserved" 2 "LV2 Warning" 1 "LV1 Warning" 0 "No warning";
VAL_ 822 SRR4_BSD_warningReqRight 3 "Reserved" 2 "LV2 Warning" 1 "LV1 Warning" 0 "No warning";
VAL_ 822 SRR4_RR_Fault 2 "Radar Fault" 1 "Radar Blocked" 0 "Radar is working";
VAL_ 822 SRR4_FCTA_Right_Active_St 7 "Reserved" 6 "Reserved" 5 "Reserved" 4 "Reserved" 3 "Reserved" 2 "FCTA_LV2_Warning" 1 "FCTA_LV1_Warning" 0 "Inactive";
VAL_ 822 SRR4_RCTA_Right_Active_St 7 "Reserved" 6 "Reserved" 5 "Reserved" 4 "Reserved" 3 "Reserved" 2 "RCTA_LV2_Warning" 1 "RCTA_LV1_Warning" 0 "Inactive";
VAL_ 822 SRR4_DOW_VoiceActive_St 7 "Reserved" 6 "Reserved" 5 "Reserved" 4 "Reserved" 3 "Reserved" 2 "LV2_Warning" 1 "LV1_Warning" 0 "No warning";
VAL_ 822 SRR4_RCTA_Right_VoiceActive_St 7 "Reserved" 6 "Reserved" 5 "Reserved" 4 "Reserved" 3 "Reserved" 2 "RCTA_LV2_Warning" 1 "RCTA_LV1_Warning" 0 "Inactive";
VAL_ 822 SRR4_BSD_VoiceActive_St 7 "Reserved" 6 "Reserved" 5 "Reserved" 4 "Reserved" 3 "Reserved" 2 "LV2_Warning" 1 "LV1_Warning" 0 "No warning";
VAL_ 826 SRR_RL_ObjMtnPat_1 2 "moving" 1 "StatyFromMovg" 0 "unknown";
VAL_ 826 SRR_RL_ObjTyp_1 3 "Vehicle" 2 "Bicycle" 1 "pedestrian" 0 "unknown";
VAL_ 826 SRR_RL_ObjMtnPat_2 2 "moving" 1 "StatyFromMovg" 0 "unknown";
VAL_ 826 SRR_RL_ObjTyp_2 3 "Vehicle" 2 "Bicycle" 1 "pedestrian" 0 "unknown";
VAL_ 827 SRR_RL_ObjMtnPat_3 2 "moving" 1 "StatyFromMovg" 0 "unknown";
VAL_ 827 SRR_RL_ObjTyp_3 3 "Vehicle" 2 "Bicycle" 1 "pedestrian" 0 "unknown";
VAL_ 827 SRR_RL_ObjMtnPat_4 2 "moving" 1 "StatyFromMovg" 0 "unknown";
VAL_ 827 SRR_RL_ObjTyp_4 3 "Vehicle" 2 "Bicycle" 1 "pedestrian" 0 "unknown";
VAL_ 828 SRR_RL_ObjMtnPat_5 2 "moving" 1 "StatyFromMovg" 0 "unknown";
VAL_ 828 SRR_RL_ObjTyp_5 3 "Vehicle" 2 "Bicycle" 1 "pedestrian" 0 "unknown";
VAL_ 828 SRR_RL_ObjMtnPat_6 2 "moving" 1 "StatyFromMovg" 0 "unknown";
VAL_ 828 SRR_RL_ObjTyp_6 3 "Vehicle" 2 "Bicycle" 1 "pedestrian" 0 "unknown";
VAL_ 829 SRR_RL_ObjMtnPat_7 2 "moving" 1 "StatyFromMovg" 0 "unknown";
VAL_ 829 SRR_RL_ObjTyp_7 3 "Vehicle" 2 "Bicycle" 1 "pedestrian" 0 "unknown";
VAL_ 829 SRR_RL_ObjMtnPat_8 2 "moving" 1 "StatyFromMovg" 0 "unknown";
VAL_ 829 SRR_RL_ObjTyp_8 3 "Vehicle" 2 "Bicycle" 1 "pedestrian" 0 "unknown";
VAL_ 830 SRR_RL_ObjMtnPat_9 2 "moving" 1 "StatyFromMovg" 0 "unknown";
VAL_ 830 SRR_RL_ObjTyp_9 3 "Vehicle" 2 "Bicycle" 1 "pedestrian" 0 "unknown";
VAL_ 830 SRR_RL_ObjMtnPat_10 2 "moving" 1 "StatyFromMovg" 0 "unknown";
VAL_ 830 SRR_RL_ObjTyp_10 3 "Vehicle" 2 "Bicycle" 1 "pedestrian" 0 "unknown";
VAL_ 831 SRR_RL_ObjMtnPat_11 2 "moving" 1 "StatyFromMovg" 0 "unknown";
VAL_ 831 SRR_RL_ObjTyp_11 3 "Vehicle" 2 "Bicycle" 1 "pedestrian" 0 "unknown";
VAL_ 831 SRR_RL_ObjMtnPat_12 2 "moving" 1 "StatyFromMovg" 0 "unknown";
VAL_ 831 SRR_RL_ObjTyp_12 3 "Vehicle" 2 "Bicycle" 1 "pedestrian" 0 "unknown";
VAL_ 832 SRR_RL_ObjMtnPat_13 2 "moving" 1 "StatyFromMovg" 0 "unknown";
VAL_ 832 SRR_RL_ObjTyp_13 3 "Vehicle" 2 "Bicycle" 1 "pedestrian" 0 "unknown";
VAL_ 832 SRR_RL_ObjMtnPat_14 2 "moving" 1 "StatyFromMovg" 0 "unknown";
VAL_ 832 SRR_RL_ObjTyp_14 3 "Vehicle" 2 "Bicycle" 1 "pedestrian" 0 "unknown";
VAL_ 833 SRR_RL_ObjMtnPat_15 2 "moving" 1 "StatyFromMovg" 0 "unknown";
VAL_ 833 SRR_RL_ObjTyp_15 3 "Vehicle" 2 "Bicycle" 1 "pedestrian" 0 "unknown";
VAL_ 833 SRR_RL_ObjMtnPat_16 2 "moving" 1 "StatyFromMovg" 0 "unknown";
VAL_ 833 SRR_RL_ObjTyp_16 3 "Vehicle" 2 "Bicycle" 1 "pedestrian" 0 "unknown";
VAL_ 835 SRR_RR_ObjMtnPat_1 3 "moving" 2 "StatyFromMovg" 1 "staty" 0 "wnknown";
VAL_ 835 SRR_RR_ObjTyp_1 3 "Vehicle" 2 "Bicycle" 1 "pedestrian" 0 "unknown";
VAL_ 835 SRR_RR_ObjMtnPat_2 2 "moving" 1 "StatyFromMovg" 0 "unknown";
VAL_ 835 SRR_RR_ObjTyp_2 3 "Vehicle" 2 "Bicycle" 1 "pedestrian" 0 "unknown";
VAL_ 836 SRR_RR_ObjMtnPat_3 2 "moving" 1 "StatyFromMovg" 0 "unknown";
VAL_ 836 SRR_RR_ObjTyp_3 3 "Vehicle" 2 "Bicycle" 1 "pedestrian" 0 "unknown";
VAL_ 836 SRR_RR_ObjMtnPat_4 2 "moving" 1 "StatyFromMovg" 0 "unknown";
VAL_ 836 SRR_RR_ObjTyp_4 3 "Vehicle" 2 "Bicycle" 1 "pedestrian" 0 "unknown";
VAL_ 837 SRR_RR_ObjMtnPat_5 2 "moving" 1 "StatyFromMovg" 0 "unknown";
VAL_ 837 SRR_RR_ObjTyp_5 3 "Vehicle" 2 "Bicycle" 1 "pedestrian" 0 "unknown";
VAL_ 837 SRR_RR_ObjMtnPat_6 2 "moving" 1 "StatyFromMovg" 0 "unknown";
VAL_ 837 SRR_RR_ObjTyp_6 3 "Vehicle" 2 "Bicycle" 1 "pedestrian" 0 "unknown";
VAL_ 838 SRR_RR_ObjMtnPat_7 2 "moving" 1 "StatyFromMovg" 0 "unknown";
VAL_ 838 SRR_RR_ObjTyp_7 3 "Vehicle" 2 "Bicycle" 1 "pedestrian" 0 "unknown";
VAL_ 838 SRR_RR_ObjMtnPat_8 2 "moving" 1 "StatyFromMovg" 0 "unknown";
VAL_ 838 SRR_RR_ObjTyp_8 3 "Vehicle" 2 "Bicycle" 1 "pedestrian" 0 "unknown";
VAL_ 839 SRR_RR_ObjMtnPat_9 2 "moving" 1 "StatyFromMovg" 0 "unknown";
VAL_ 839 SRR_RR_ObjTyp_9 3 "Vehicle" 2 "Bicycle" 1 "pedestrian" 0 "unknown";
VAL_ 839 SRR_RR_ObjMtnPat_10 2 "moving" 1 "StatyFromMovg" 0 "unknown";
VAL_ 839 SRR_RR_ObjTyp_10 3 "Vehicle" 2 "Bicycle" 1 "pedestrian" 0 "unknown";
VAL_ 840 SRR_RR_ObjMtnPat_11 2 "moving" 1 "StatyFromMovg" 0 "unknown";
VAL_ 840 SRR_RR_ObjTyp_11 3 "Vehicle" 2 "Bicycle" 1 "pedestrian" 0 "unknown";
VAL_ 840 SRR_RR_ObjMtnPat_12 2 "moving" 1 "StatyFromMovg" 0 "unknown";
VAL_ 840 SRR_RR_ObjTyp_12 3 "Vehicle" 2 "Bicycle" 1 "pedestrian" 0 "unknown";
VAL_ 841 SRR_RR_ObjMtnPat_13 2 "moving" 1 "StatyFromMovg" 0 "unknown";
VAL_ 841 SRR_RR_ObjTyp_13 3 "Vehicle" 2 "Bicycle" 1 "pedestrian" 0 "unknown";
VAL_ 841 SRR_RR_ObjMtnPat_14 2 "moving" 1 "StatyFromMovg" 0 "unknown";
VAL_ 841 SRR_RR_ObjTyp_14 3 "Vehicle" 2 "Bicycle" 1 "pedestrian" 0 "unknown";
VAL_ 848 SRR_RR_ObjMtnPat_15 2 "moving" 1 "StatyFromMovg" 0 "unknown";
VAL_ 848 SRR_RR_ObjTyp_15 3 "Vehicle" 2 "Bicycle" 1 "pedestrian" 0 "unknown";
VAL_ 848 SRR_RR_ObjMtnPat_16 2 "moving" 1 "StatyFromMovg" 0 "unknown";
VAL_ 848 SRR_RR_ObjTyp_16 3 "Vehicle" 2 "Bicycle" 1 "pedestrian" 0 "unknown";
VAL_ 196 ACU2_LatAccSensorValueV 1 "Valid(有效)" 0 "Invalid(无效)";
VAL_ 196 ACU2_VehicleDynYawRateV 1 "Valid(有效)" 0 "Invalid(无效)";
VAL_ 196 ACU2_Sensorcalibration 1 "calibration(已标定)" 0 "No calibration(未标定)";
VAL_ 196 ACU2_LongAccSensorValueV 1 "Valid(有效)" 0 "Invalid(无效)";
VAL_ 258 ACU1_Driver_Buckle 3 "Not Avaliable(安全带未配置)" 2 "Fault(安全带有错)" 1 "Unbuckled(安全带未系上)" 0 "Buckled(安全带系上)";
VAL_ 258 ACU1_Passenger_Buckle 3 "Not Avaliable(安全带未配置)" 2 "Fault(安全带有错)" 1 "Unbuckled(安全带未系上)" 0 "Buckled(安全带系上)";
VAL_ 258 ACU1_PAB_State 1 "ON（开启）" 0 "OFF（关闭）";
VAL_ 258 ACU1_Passenger_ODS 3 "Not Avaliable(安全带未配置)" 2 "Fault(安全带有错)" 1 "Unoccupied（无人）" 0 "Occupied（有人）";
VAL_ 258 ACU1_CrashStatus 1 "Crash happened（有碰撞事件）" 0 "Crash not happened（没有碰撞事件）";
VAL_ 258 ACU1_warningLight 3 "Reserved" 2 "AWL Flashing（警报灯闪）" 1 "AWL ON（警报灯亮）" 0 "AWL OFF（警报灯灭）";
VAL_ 258 ACU1_Rear_Left_ODS 3 "Not Avaliable(未配置)" 2 "Fault(故障)" 1 "Unoccupied（无人）" 0 "Occupied（有人）";
VAL_ 258 ACU1_Rear_Left_BuckleSts_Logic 7 "Reserved" 6 "Reserved" 5 "Unbuckled（无ODS）" 4 "Buckled（无ODS）" 3 "Not Avaliable(锁扣未配置)" 2 "Fault(安全带有错)" 1 "Occupied and Unbuckled（有人未系）" 0 "Buckled Or unOccupied（安全带系上或者无人）";
VAL_ 258 ACU1_Rear_Right_Buckle 7 "Reserved" 6 "Reserved" 5 "Reserved" 4 "Reserved" 3 "Not Avaliable(锁扣未配置）" 2 "Fault(锁扣有错)" 1 "Unbuckled" 0 "Buckled";
VAL_ 258 ACU1_Rear_Left_Buckle 7 "Reserved" 6 "Reserved" 5 "Reserved" 4 "Reserved" 3 "Not Avaliable(锁扣未配置）" 2 "Fault(锁扣有错)" 1 "Unbuckled" 0 "Buckled";
VAL_ 258 ACU1_Rear_Middle_Buckle 7 "Reserved" 6 "Reserved" 5 "Reserved" 4 "Reserved" 3 "Not Avaliable(锁扣未配置）" 2 "Fault(锁扣有错)" 1 "Unbuckled" 0 "Buckled";
VAL_ 258 ACU1_Rear_Middle_ODS 3 "Not Avaliable(未配置)" 2 "Fault(故障)" 1 "Unoccupied（无人）" 0 "Occupied（有人）";
VAL_ 258 ACU1_Rear_Midlle_BuckleSts_Logic 7 "Reserved" 6 "Reserved" 5 "Unbuckled（无ODS）" 4 "Buckled（无ODS）" 3 "Not Avaliable(锁扣未配置)" 2 "Fault(安全带有错)" 1 "Occupied and Unbuckled（有人未系）" 0 "Buckled Or unOccupied（安全带系上或者无人）";
VAL_ 258 ACU1_Rear_Right_ODS 3 "Not Avaliable(未配置)" 2 "Fault(故障)" 1 "Unoccupied（无人）" 0 "Occupied（有人）";
VAL_ 258 ACU1_Rear_Right_BuckleSts_Logic 7 "Reserved" 6 "Reserved" 5 "Unbuckled（无ODS）" 4 "Buckled（无ODS）" 3 "Not Avaliable(锁扣未配置)" 2 "Fault(安全带有错)" 1 "Occupied and Unbuckled（有人未系）" 0 "Buckled Or unOccupied（安全带系上或者无人）";
VAL_ 258 ACU1_CrashType 8 "Right Side Crash" 4 "Left Side Crash" 2 "Front Crash" 1 "Belt Crash" 16 "Rear Crash" 0 "No crash";
VERSION ""

NS_ :

BS_:

BU_: GW_FD5 GW_FD6 GW_FD3 GW_FD4 GW_FD1 GW_FD2 PDCS_FD1 PDCU SRR3 SRR4 ADCU_FD3 BDCS DDCU CDCS ADCS_FD3 CDCS_OverSea TBOX FLC_ME_FD3 FLC_FD3 ICU_E02 ICU PDCS_HVM_FD1 TBOX_OverSea BMS ISC GCU EMS IDB ESC_FD3 EHB_FD3 MCU IMU ACU EPS WPC CDU AMP BAM PDCS_FD3 EVCC REPB ADCS_FD6 ADCU_FD6 FLC_ME_FD6 FLC_FD6 DLC GW_FD7 ESC_FD6 EHB_FD6

BO_ 272 BDCS_Fr01_110: 8 BDCS
 SG_ BDCS1_PowerMode : 1|2@0+ (1,0) [0|3] "NoUnit" PDCS_FD1,PDCU,IDB,ESC_FD3,ADCU_FD3,EPS,WPC,ADCU_FD6,EHB_FD3,CDCS,CDU,ICU_E02,ISC,AMP,SRR3,SRR4,BMS,ADCS_FD6,EMS,DDCU,BAM,ADCS_FD3,CDCS_OverSea,IMU,TBOX,FLC_ME_FD6,FLC_ME_FD3,ACU,FLC_FD3,FLC_FD6,GW_FD5,GW_FD6,GCU,GW_FD3,GW_FD4,GW_FD1,ICU,GW_FD2,MCU,PDCS_HVM_FD1,TBOX_OverSea
 SG_ BDCS1_PetToLookAfterFbk : 2|1@0+ (1,0) [0|1] "NoUnit" PDCS_FD1,SRR3,SRR4,CDCS,CDCS_OverSea,TBOX,GW_FD5,ICU_E02,GW_FD6,GW_FD4,GW_FD1,ICU,PDCS_HVM_FD1,TBOX_OverSea
 SG_ BDCS1_PetToLookAfterRmd : 3|1@0+ (1,0) [0|1] "NoUnit" PDCS_FD1,SRR3,SRR4,CDCS,CDCS_OverSea,TBOX,GW_FD5,ICU_E02,GW_FD6,GW_FD4,GW_FD1,ICU,PDCS_HVM_FD1,TBOX_OverSea
 SG_ BDCS1_PowerManageMode : 7|4@0+ (1,0) [0|15] "NoUnit" PDCS_FD1,PDCU,IDB,ESC_FD3,ADCU_FD3,WPC,EHB_FD3,CDCS,CDU,ICU_E02,AMP,SRR3,SRR4,BMS,EMS,DDCU,BAM,ADCS_FD3,CDCS_OverSea,IMU,TBOX,FLC_ME_FD3,ACU,FLC_FD3,GW_FD5,GW_FD6,GCU,GW_FD3,GW_FD4,GW_FD1,ICU,MCU,PDCS_HVM_FD1,TBOX_OverSea
 SG_ BDCS1_AlarmMode : 10|3@0+ (1,0) [0|7] "NoUnit" PDCU,SRR3,SRR4,ADCU_FD3,DDCU,CDCS,ADCS_FD3,CDCS_OverSea,TBOX,GW_FD5,GW_FD6,GW_FD4,TBOX_OverSea
 SG_ BDCS1_LowBeamSt : 11|1@0+ (1,0) [0|1] "NoUnit" SRR3,SRR4,ADCU_FD3,CDCS,ADCS_FD3,CDCS_OverSea,TBOX,FLC_ME_FD3,FLC_FD3,GW_FD5,ICU_E02,GW_FD6,GW_FD3,GW_FD4,ICU,TBOX_OverSea
 SG_ BDCS1_HighBeamSt : 12|1@0+ (1,0) [0|1] "NoUnit" SRR3,SRR4,ADCU_FD3,CDCS,ADCS_FD3,CDCS_OverSea,TBOX,FLC_ME_FD3,FLC_FD3,GW_FD5,ICU_E02,GW_FD6,GW_FD3,GW_FD4,ICU,TBOX_OverSea
 SG_ BDCS1_EnergyManagement : 15|3@0+ (1,0) [0|7] "NoUnit" PDCS_FD1,SRR3,SRR4,CDCS,CDCS_OverSea,TBOX,GW_FD5,ICU_E02,GW_FD6,GW_FD4,GW_FD1,ICU,PDCS_HVM_FD1,TBOX_OverSea
 SG_ BDCS1_FindCarSts : 16|1@0+ (1,0) [0|1] "NoUnit" TBOX,GW_FD5,SRR3,GW_FD6,SRR4,BAM,TBOX_OverSea
 SG_ BDCS1_PositionLightSts : 17|1@0+ (1,0) [0|1] "NoUnit" PDCU,SRR3,SRR4,ADCU_FD3,DDCU,CDCS,ADCS_FD3,CDCS_OverSea,TBOX,FLC_ME_FD3,FLC_FD3,GW_FD5,ICU_E02,GW_FD6,GW_FD3,GW_FD4,ICU,TBOX_OverSea
 SG_ BDCS1_BacklightStatus : 18|1@0+ (1,0) [0|1] "NoUnit" PDCU,SRR3,SRR4,ADCU_FD3,DDCU,CDCS,ADCS_FD3,CDCS_OverSea,TBOX,FLC_ME_FD3,FLC_FD3,GW_FD5,ICU_E02,GW_FD6,GW_FD3,GW_FD4,ICU,TBOX_OverSea
 SG_ BDCS1_LeftTurnLightSt : 19|1@0+ (1,0) [0|1] "NoUnit" SRR3,SRR4,ADCU_FD3,CDCS,ADCS_FD3,CDCS_OverSea,TBOX,FLC_ME_FD3,ACU,FLC_FD3,GW_FD5,ICU_E02,GW_FD6,GW_FD3,GW_FD4,GW_FD1,ICU,TBOX_OverSea
 SG_ BDCS1_RightTurnLightSt : 20|1@0+ (1,0) [0|1] "NoUnit" SRR3,SRR4,ADCU_FD3,CDCS,ADCS_FD3,CDCS_OverSea,TBOX,FLC_ME_FD3,ACU,FLC_FD3,GW_FD5,ICU_E02,GW_FD6,GW_FD3,GW_FD4,GW_FD1,ICU,TBOX_OverSea
 SG_ BDCS1_FrontLampSt : 22|2@0+ (1,0) [0|3] "NoUnit" SRR3,SRR4,ADCU_FD3,CDCS,ADCS_FD3,CDCS_OverSea,TBOX,FLC_ME_FD3,FLC_FD3,GW_FD5,ICU_E02,GW_FD6,GW_FD3,GW_FD4,ICU,TBOX_OverSea
 SG_ BDCS1_HazardLampSt : 23|1@0+ (1,0) [0|1] "NoUnit" SRR3,SRR4,ADCU_FD3,CDCS,ADCS_FD3,CDCS_OverSea,TBOX,FLC_ME_FD3,ACU,FLC_FD3,GW_FD5,ICU_E02,GW_FD6,GW_FD3,GW_FD4,GW_FD1,ICU,TBOX_OverSea
 SG_ BDCS1_HighBeamSW : 25|2@0+ (1,0) [0|3] "NoUnit" SRR3,SRR4,ADCU_FD3,CDCS,ADCS_FD3,CDCS_OverSea,TBOX,FLC_ME_FD3,FLC_FD3,GW_FD5,ICU_E02,GW_FD6,GW_FD3,GW_FD4,ICU,TBOX_OverSea
 SG_ BDCS1_TurnLightSW : 27|2@0+ (1,0) [0|3] "NoUnit" SRR3,SRR4,ADCU_FD3,CDCS,ADCS_FD3,CDCS_OverSea,TBOX,FLC_ME_FD3,ACU,FLC_FD3,GW_FD5,ICU_E02,GW_FD6,GW_FD3,GW_FD4,GW_FD1,ICU,TBOX_OverSea
 SG_ BDCS1_HazardSwSt : 28|1@0+ (1,0) [0|1] "NoUnit" SRR3,SRR4,ADCU_FD3,CDCS,ADCS_FD3,CDCS_OverSea,TBOX,FLC_ME_FD3,ACU,FLC_FD3,GW_FD5,ICU_E02,GW_FD6,GW_FD3,GW_FD4,GW_FD1,ICU,TBOX_OverSea
 SG_ BDCS1_BrakeLightSts : 29|1@0+ (1,0) [0|1] "NoUnit" TBOX,GW_FD5,ICU_E02,SRR3,GW_FD6,SRR4,GW_FD4,ICU,CDCS,CDCS_OverSea,TBOX_OverSea
 SG_ BDCS1_RearFogLampSt : 30|1@0+ (1,0) [0|1] "NoUnit" SRR3,SRR4,ADCU_FD3,CDCS,ADCS_FD3,CDCS_OverSea,TBOX,FLC_ME_FD3,FLC_FD3,GW_FD5,ICU_E02,GW_FD6,GW_FD3,GW_FD4,ICU,TBOX_OverSea
 SG_ BDCS1_FrontFogLampSt : 31|1@0+ (1,0) [0|1] "NoUnit" SRR3,SRR4,ADCU_FD3,CDCS,ADCS_FD3,CDCS_OverSea,TBOX,FLC_ME_FD3,FLC_FD3,GW_FD5,ICU_E02,GW_FD6,GW_FD3,GW_FD4,ICU,TBOX_OverSea
 SG_ BDCS1_BackupLightSts : 32|1@0+ (1,0) [0|1] "NoUnit" TBOX,GW_FD5,ICU_E02,SRR3,GW_FD6,SRR4,GW_FD4,ICU,CDCS,CDCS_OverSea,TBOX_OverSea
 SG_ BDCS1_HeadlampHeight_fb : 34|2@0+ (1,0) [0|3] "NoUnit" TBOX,GW_FD5,ICU_E02,SRR3,GW_FD6,SRR4,GW_FD4,ICU,CDCS,CDCS_OverSea,TBOX_OverSea
 SG_ BDCS1_TrunkLockSts : 35|1@0+ (1,0) [0|1] "NoUnit" PDCS_FD1,SRR3,SRR4,ADCU_FD3,DDCU,BAM,CDCS,ADCS_FD3,CDCS_OverSea,TBOX,FLC_ME_FD3,FLC_FD3,GW_FD5,ICU_E02,GW_FD6,GW_FD3,GW_FD4,GW_FD1,ICU,PDCS_HVM_FD1,TBOX_OverSea
 SG_ BDCS1_FMH_SetSts : 38|3@0+ (1,0) [0|7] "NoUnit" TBOX,GW_FD5,ICU_E02,SRR3,GW_FD6,SRR4,GW_FD4,ICU,CDCS,CDCS_OverSea,TBOX_OverSea
 SG_ BDCS1_HoodAjarSts : 39|1@0+ (1,0) [0|1] "NoUnit" PDCS_FD1,SRR3,SRR4,ADCU_FD3,BMS,DDCU,BAM,CDCS,ADCS_FD3,CDCS_OverSea,TBOX,FLC_ME_FD3,FLC_FD3,GW_FD5,ICU_E02,GW_FD6,GW_FD3,GW_FD4,GW_FD1,ICU,PDCS_HVM_FD1,TBOX_OverSea
 SG_ BDCS1_Backlight_brightness_fb : 43|4@0+ (1,0) [0|15] "NoUnit" PDCU,SRR3,GW_FD6,SRR4,GW_FD4,DDCU,CDCS,CDCS_OverSea
 SG_ BDCS1_DRLSt : 44|1@0+ (1,0) [0|1] "NoUnit" SRR3,GW_FD6,SRR4,GW_FD4,CDCS,CDCS_OverSea
 SG_ BDCS1_CentralLockFbk : 45|1@0+ (1,0) [0|1] "NoUnit" SRR3,GW_FD6,SRR4,GW_FD4,CDCS,CDCS_OverSea
 SG_ BDCS1_OTAauthenSts : 47|2@0+ (1,0) [0|3] "NoUnit" SRR3,GW_FD6,SRR4
 SG_ BDCS1_MsgCounter : 51|4@0+ (1,0) [0|15] "NoUnit" PDCS_FD1,PDCU,IDB,ESC_FD3,ADCU_FD3,EPS,WPC,ADCU_FD6,EHB_FD3,CDU,ISC,AMP,SRR3,SRR4,BMS,ADCS_FD6,DDCU,BAM,ADCS_FD3,IMU,TBOX,FLC_ME_FD6,FLC_ME_FD3,ACU,FLC_FD3,FLC_FD6,GW_FD5,GW_FD6,GCU,GW_FD3,GW_FD4,GW_FD1,MCU,PDCS_HVM_FD1,TBOX_OverSea
 SG_ BDCS1_WelcomeLampModFbk : 55|4@0+ (1,0) [0|15] "NoUnit" GW_FD4,CDCS,CDCS_OverSea
 SG_ BDCS1_Checksum : 63|8@0+ (1,0) [0|255] "NoUnit" PDCS_FD1,PDCU,IDB,ESC_FD3,ADCU_FD3,EPS,WPC,ADCU_FD6,EHB_FD3,CDU,ISC,AMP,SRR3,SRR4,BMS,ADCS_FD6,DDCU,BAM,ADCS_FD3,IMU,TBOX,FLC_ME_FD6,FLC_ME_FD3,ACU,FLC_FD3,FLC_FD6,GW_FD5,GW_FD6,GCU,GW_FD3,GW_FD4,GW_FD1,MCU,PDCS_HVM_FD1,TBOX_OverSea

BO_ 274 BDCS_Fr03_112: 16 BDCS
 SG_ BDCS3_StartRequest : 0|1@0+ (1,0) [0|1] "NoUnit" TBOX,GW_FD5,ICU_E02,GW_FD4,ICU,CDCS,CDCS_OverSea,TBOX_OverSea
 SG_ BDCS3_LightShowSts : 1|1@0+ (1,0) [0|1] "NoUnit" Vector__XXX
 SG_ BDCS3_CarMode : 4|3@0+ (1,0) [0|7] "NoUnit" PDCS_FD1,TBOX,GW_FD5,ICU_E02,GW_FD4,GW_FD1,ICU,CDCS,PDCS_HVM_FD1,CDCS_OverSea,TBOX_OverSea
 SG_ BDCS3_BluetoothAuthenSts : 6|2@0+ (1,0) [0|3] "NoUnit" TBOX,GW_FD5,GW_FD4,BAM,CDCS,CDCS_OverSea,TBOX_OverSea
 SG_ BDCS3_EngineForbidSts : 7|1@0+ (1,0) [0|1] "NoUnit" TBOX,GW_FD5,GW_FD4,CDCS,CDCS_OverSea,TBOX_OverSea
 SG_ BDCS3_RemoteStartSts : 9|2@0+ (1,0) [0|3] "NoUnit" TBOX,GW_FD5,ICU_E02,GW_FD4,ICU,CDCS,CDCS_OverSea,TBOX_OverSea
 SG_ BDCS3_RemoteAuthenSts : 11|2@0+ (1,0) [0|3] "NoUnit" TBOX,FLC_ME_FD3,FLC_FD3,GW_FD5,GW_FD3,ADCU_FD3,GW_FD4,CDCS,ADCS_FD3,CDCS_OverSea,TBOX_OverSea
 SG_ BDCS3_RemoteReadySts : 13|2@0+ (1,0) [0|3] "NoUnit" TBOX,GW_FD5,GW_FD4,BAM,CDCS,CDCS_OverSea,TBOX_OverSea
 SG_ BDCS3_IHU_DoorHeightSetFb : 15|2@0+ (1,0) [0|3] "NoUnit" TBOX,GW_FD5,GW_FD4,BAM,CDCS,CDCS_OverSea,TBOX_OverSea
 SG_ BDCS3_RemoteAuthenFailCondition : 21|6@0+ (1,0) [0|63] "NoUnit" TBOX,GW_FD5,TBOX_OverSea
 SG_ BDCS3_KeyAuthenSts : 23|2@0+ (1,0) [0|3] "NoUnit" TBOX,GW_FD5,ICU_E02,GW_FD4,ICU,TBOX_OverSea
 SG_ BDCS3_IHU_ReclockReq : 24|1@0+ (1,0) [0|1] "NoUnit" TBOX,GW_FD5,ICU_E02,GW_FD4,ICU,CDCS,CDCS_OverSea,TBOX_OverSea
 SG_ BDCS3_BackDoorAjar : 27|3@0+ (1,0) [0|7] "NoUnit" ADCU_FD3,BAM,CDCS,ADCS_FD3,CDCS_OverSea,TBOX,FLC_ME_FD3,FLC_FD3,GW_FD5,GW_FD3,GW_FD4,TBOX_OverSea
 SG_ BDCS3_RKECmd : 31|4@0+ (1,0) [0|15] "NoUnit" TBOX,GW_FD5,ICU_E02,GW_FD4,ICU,BAM,CDCS,CDCS_OverSea,TBOX_OverSea
 SG_ BDCS3_DoorHeight : 39|7@0+ (1,0) [0|100] "%" TBOX,GW_FD5,GW_FD4,BAM,CDCS,CDCS_OverSea,TBOX_OverSea
 SG_ BDCS3_DoorHeightValid : 40|1@0+ (1,0) [0|1] "NoUnit" TBOX,GW_FD5,ICU_E02,GW_FD4,ICU,BAM,CDCS,CDCS_OverSea,TBOX_OverSea
 SG_ BDCS3_RearDoorStatus : 43|3@0+ (1,0) [0|7] "NoUnit" TBOX,GW_FD5,GW_FD4,BAM,CDCS,CDCS_OverSea,TBOX_OverSea
 SG_ BDCS3_IDdeviceNo : 46|3@0+ (1,0) [0|7] "NoUnit" TBOX,GW_FD5,GW_FD4,CDCS,CDCS_OverSea,TBOX_OverSea
 SG_ BDCS3_ShutDownReqFbk : 47|1@0+ (1,0) [0|1] "NoUnit" GW_FD4,CDCS,CDCS_OverSea
 SG_ BDCS3_OTAModeSts : 50|3@0+ (1,0) [0|7] "NoUnit" GW_FD2
 SG_ BDCS3_LaunchRequest : 51|1@0+ (1,0) [0|1] "NoUnit" PDCS_FD1,GW_FD1,PDCS_HVM_FD1
 SG_ BDCS3_StarterRelay2On : 52|1@0+ (1,0) [0|1] "NoUnit" TBOX,GW_FD5,ICU_E02,GW_FD4,ICU,CDCS,CDCS_OverSea,TBOX_OverSea
 SG_ BDCS3_StarterRelay1On : 53|1@0+ (1,0) [0|1] "NoUnit" TBOX,GW_FD5,ICU_E02,GW_FD4,ICU,CDCS,CDCS_OverSea,TBOX_OverSea
 SG_ BDCS3_PARKUnLockFeedback : 54|1@0+ (1,0) [0|1] "NoUnit" GW_FD4,CDCS,CDCS_OverSea
 SG_ BDCS3_SpeedLockFeedback : 55|1@0+ (1,0) [0|1] "NoUnit" ICU_E02,GW_FD4,ICU,CDCS,CDCS_OverSea
 SG_ BDCS3_StationaryModeReminder : 57|2@0+ (1,0) [0|3] "NoUnit" TBOX,GW_FD5,ICU_E02,GW_FD4,ICU,CDCS,CDCS_OverSea,TBOX_OverSea
 SG_ BDCS3_SportRequest : 58|1@0+ (1,0) [0|1] "NoUnit" GW_FD4,CDCS,CDCS_OverSea
 SG_ BDCS3_SportRequestValid : 60|1@0+ (1,0) [0|1] "NoUnit" GW_FD4,CDCS,CDCS_OverSea
 SG_ BDCS3_LaunchRequestValid : 61|1@0+ (1,0) [0|1] "NoUnit" PDCS_FD1,GW_FD1,PDCS_HVM_FD1
 SG_ BDCS3_ADCSAuthenSts : 63|2@0+ (1,0) [0|3] "NoUnit" FLC_ME_FD3,FLC_FD3,GW_FD3,ADCU_FD3,ADCS_FD3
 SG_ BDCS3_InteriorLightingFdb : 65|2@0+ (1,0) [0|3] "NoUnit" GW_FD4,CDCS,CDCS_OverSea
 SG_ BDCS3_LFreadinglampSts : 66|1@0+ (1,0) [0|1] "NoUnit" GW_FD4,CDCS,CDCS_OverSea
 SG_ BDCS3_RFreadinglampSts : 67|1@0+ (1,0) [0|1] "NoUnit" GW_FD4,CDCS,CDCS_OverSea
 SG_ BDCS3_LRreadinglampSts : 68|1@0+ (1,0) [0|1] "NoUnit" GW_FD4,CDCS,CDCS_OverSea
 SG_ BDCS3_RRreadinglampSts : 69|1@0+ (1,0) [0|1] "NoUnit" GW_FD4,CDCS,CDCS_OverSea
 SG_ BDCS3_FindMyCarTimeSet_Fb : 71|2@0+ (1,0) [0|3] "NoUnit" GW_FD4,CDCS,CDCS_OverSea
 SG_ BDCS3_Horn_SW : 79|1@0+ (1,0) [0|1] "NoUnit" GW_FD4,CDCS,CDCS_OverSea
 SG_ BDCS3_AntiTheftInnerStsEE : 87|4@0+ (1,0) [0|15] "NoUnit" Vector__XXX
 SG_ BDCS3_AntiTheftRmdSoundFdb : 89|2@0+ (1,0) [0|3] "NoUnit" GW_FD4,CDCS,CDCS_OverSea
 SG_ BDCS3_AlarmRmdSoundFdb : 91|2@0+ (1,0) [0|3] "NoUnit" GW_FD4,CDCS,CDCS_OverSea
 SG_ BDCS3_AlarmTurnTimeFdb : 93|2@0+ (1,0) [0|3] "NoUnit" TBOX,GW_FD5,GW_FD4,CDCS,CDCS_OverSea,TBOX_OverSea
 SG_ BDCS3_Wal_Away_Up_swSt : 95|2@0+ (1,0) [0|3] "NoUnit" GW_FD4,CDCS,CDCS_OverSea
 SG_ BDCS3_WelcomeLampCmd_swSt : 97|2@0+ (1,0) [0|3] "NoUnit" GW_FD4,CDCS,CDCS_OverSea
 SG_ BDCS3_TrunkHomeLockSts : 98|1@0+ (1,0) [0|1] "NoUnit" Vector__XXX
 SG_ BDCS3_TrunkHalfLockSts : 99|1@0+ (1,0) [0|1] "NoUnit" Vector__XXX
 SG_ BDCS3_UserSceneModeFbk : 103|4@0+ (1,0) [0|15] "NoUnit" PDCS_FD1,GW_FD4,CDCS,PDCS_HVM_FD1,CDCS_OverSea
 SG_ BDCS3_VehicleStatelRemind : 106|3@0+ (1,0) [0|7] "NoUnit" PDCS_FD1,TBOX,GW_FD5,PDCS_HVM_FD1,TBOX_OverSea
 SG_ BDCS3_TrunkCtrlFailure : 115|2@0+ (1,0) [0|3] "NoUnit" ICU_E02,GW_FD4,CDCS_OverSea
 SG_ RF_Key_Position : 119|3@0+ (1,0) [0|7] "NoUnit" PDCU,DDCU
 SG_ BDCS3_Key_Ventilation_Fbk : 127|3@0+ (1,0) [0|7] "NoUnit" GW_FD4,CDCS,CDCS_OverSea

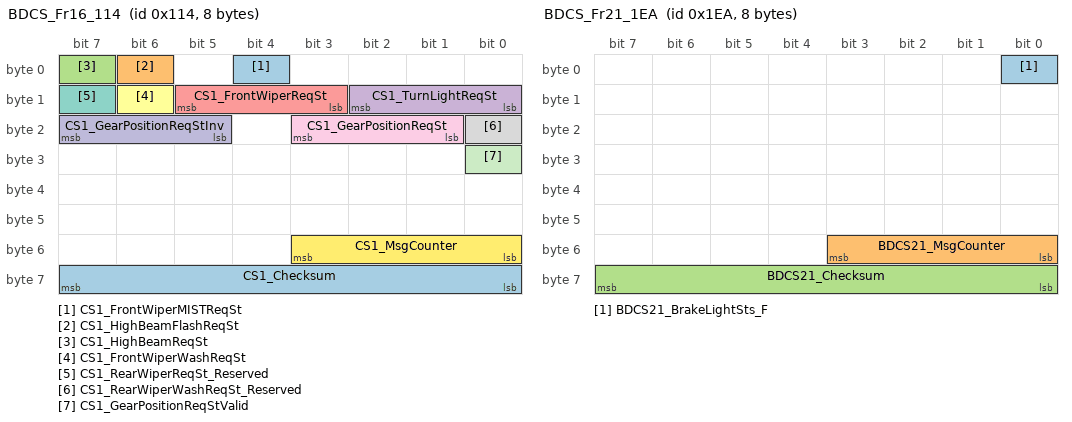
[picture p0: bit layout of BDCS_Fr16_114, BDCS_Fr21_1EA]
BO_ 276 BDCS_Fr16_114: 8 BDCS
 SG_ CS1_FrontWiperMISTReqSt : 4|1@0+ (1,0) [0|1] "NoUnit" FLC_ME_FD6,FLC_ME_FD3,FLC_FD3,SRR3,GW_FD6,SRR4,GW_FD3,ADCS_FD3
 SG_ CS1_HighBeamFlashReqSt : 6|1@0+ (1,0) [0|1] "NoUnit" FLC_ME_FD6,FLC_ME_FD3,FLC_FD3,SRR3,GW_FD6,SRR4,GW_FD3,ADCS_FD3
 SG_ CS1_HighBeamReqSt : 7|1@0+ (1,0) [0|1] "NoUnit" FLC_ME_FD6,FLC_ME_FD3,FLC_FD3,SRR3,GW_FD6,SRR4,GW_FD3,ADCS_FD3
 SG_ CS1_TurnLightReqSt : 10|3@0+ (1,0) [0|7] "NoUnit" FLC_ME_FD6,FLC_ME_FD3,FLC_FD3,SRR3,GW_FD6,SRR4,GW_FD3,ADCS_FD3
 SG_ CS1_FrontWiperReqSt : 13|3@0+ (1,0) [0|7] "NoUnit" FLC_ME_FD6,FLC_ME_FD3,FLC_FD3,SRR3,GW_FD6,SRR4,GW_FD3,GW_FD4,CDCS,ADCS_FD3,CDCS_OverSea
 SG_ CS1_FrontWiperWashReqSt : 14|1@0+ (1,0) [0|1] "NoUnit" FLC_ME_FD6,FLC_ME_FD3,FLC_FD3,SRR3,GW_FD6,SRR4,GW_FD3,ADCS_FD3
 SG_ CS1_RearWiperReqSt_Reserved : 15|1@0+ (1,0) [0|1] "NoUnit" FLC_ME_FD6,FLC_ME_FD3,FLC_FD3,SRR3,GW_FD6,SRR4,GW_FD3,ADCS_FD3
 SG_ CS1_RearWiperWashReqSt_Reserved : 16|1@0+ (1,0) [0|1] "NoUnit" FLC_ME_FD6,FLC_ME_FD3,FLC_FD3,SRR3,GW_FD6,SRR4,GW_FD3,ADCS_FD3
 SG_ CS1_GearPositionReqSt : 19|3@0+ (1,0) [0|7] "NoUnit" PDCS_FD1,SRR3,SRR4,CDCS,ADCS_FD3,CDCS_OverSea,FLC_ME_FD6,FLC_ME_FD3,FLC_FD3,GW_FD6,GW_FD3,GW_FD1,PDCS_HVM_FD1
 SG_ CS1_GearPositionReqStInv : 23|3@0+ (1,0) [0|7] "NoUnit" PDCS_FD1,FLC_ME_FD6,FLC_ME_FD3,FLC_FD3,SRR3,GW_FD6,SRR4,GW_FD3,GW_FD1,PDCS_HVM_FD1,ADCS_FD3
 SG_ CS1_GearPositionReqStValid : 24|1@0+ (1,0) [0|1] "NoUnit" PDCS_FD1,FLC_ME_FD6,FLC_ME_FD3,FLC_FD3,SRR3,GW_FD6,SRR4,GW_FD3,GW_FD1,PDCS_HVM_FD1,ADCS_FD3
 SG_ CS1_MsgCounter : 51|4@0+ (1,0) [0|15] "NoUnit" PDCS_FD1,FLC_ME_FD6,FLC_ME_FD3,FLC_FD3,SRR3,GW_FD6,SRR4,GW_FD3,GW_FD1,PDCS_HVM_FD1,ADCS_FD3
 SG_ CS1_Checksum : 63|8@0+ (1,0) [0|255] "NoUnit" PDCS_FD1,FLC_ME_FD6,FLC_ME_FD3,FLC_FD3,SRR3,GW_FD6,SRR4,GW_FD3,GW_FD1,PDCS_HVM_FD1,ADCS_FD3

BO_ 482 BDCS_Fr04_1E2: 8 BDCS
 SG_ BDCS4_Ftyre_Status : 0|1@0+ (1,0) [0|1] "NoUnit" TBOX,GW_FD5,ICU_E02,GW_FD3,ADCU_FD3,GW_FD4,ICU,CDCS,ADCS_FD3,CDCS_OverSea,TBOX_OverSea
 SG_ BDCS4_FLTyre_LearntSt : 1|1@0+ (1,0) [0|1] "NoUnit" TBOX,GW_FD5,ICU_E02,GW_FD3,ADCU_FD3,GW_FD4,ICU,CDCS,ADCS_FD3,CDCS_OverSea,TBOX_OverSea
 SG_ BDCS4_FLTyre_PressureWarn : 3|2@0+ (1,0) [0|3] "NoUnit" TBOX,GW_FD5,ICU_E02,GW_FD3,ADCU_FD3,GW_FD4,ICU,CDCS,ADCS_FD3,CDCS_OverSea,TBOX_OverSea
 SG_ BDCS4_FLTyre_TemperatureWarn : 4|1@0+ (1,0) [0|1] "NoUnit" TBOX,GW_FD5,ICU_E02,GW_FD3,ADCU_FD3,GW_FD4,ICU,CDCS,ADCS_FD3,CDCS_OverSea,TBOX_OverSea
 SG_ BDCS4_FLTyre_QucikLeak : 5|1@0+ (1,0) [0|1] "NoUnit" TBOX,GW_FD5,ICU_E02,GW_FD3,ADCU_FD3,GW_FD4,ICU,CDCS,ADCS_FD3,CDCS_OverSea,TBOX_OverSea
 SG_ BDCS4_FLTyre_SensorFailure : 6|1@0+ (1,0) [0|1] "NoUnit" TBOX,GW_FD5,ICU_E02,GW_FD3,ADCU_FD3,GW_FD4,ICU,CDCS,ADCS_FD3,CDCS_OverSea,TBOX_OverSea
 SG_ BDCS4_FLTyre_LowBattery : 7|1@0+ (1,0) [0|1] "NoUnit" TBOX,GW_FD5,ICU_E02,GW_FD3,ADCU_FD3,GW_FD4,ICU,CDCS,ADCS_FD3,CDCS_OverSea,TBOX_OverSea
 SG_ BDCS4_FLTyre_Pressure : 15|8@0+ (3.137,0) [0|796.798] "kpa" TBOX,GW_FD5,ICU_E02,GW_FD3,ADCU_FD3,GW_FD4,ICU,CDCS,ADCS_FD3,CDCS_OverSea,TBOX_OverSea
 SG_ BDCS4_FLTyre_Temperature : 23|8@0+ (1,-50) [-50|204] "" TBOX,GW_FD5,ICU_E02,GW_FD3,ADCU_FD3,GW_FD4,ICU,CDCS,ADCS_FD3,CDCS_OverSea,TBOX_OverSea
 SG_ BDCS4_FRTyre_LearntSt : 25|1@0+ (1,0) [0|1] "NoUnit" TBOX,GW_FD5,ICU_E02,GW_FD3,ADCU_FD3,GW_FD4,ICU,CDCS,ADCS_FD3,CDCS_OverSea,TBOX_OverSea
 SG_ BDCS4_FRTyre_PressureWarn : 27|2@0+ (1,0) [0|3] "NoUnit" TBOX,GW_FD5,ICU_E02,GW_FD3,ADCU_FD3,GW_FD4,ICU,CDCS,ADCS_FD3,CDCS_OverSea,TBOX_OverSea
 SG_ BDCS4_FRTyre_TemperatureWarn : 28|1@0+ (1,0) [0|1] "NoUnit" TBOX,GW_FD5,ICU_E02,GW_FD3,ADCU_FD3,GW_FD4,ICU,CDCS,ADCS_FD3,CDCS_OverSea,TBOX_OverSea
 SG_ BDCS4_FRTyre_QucikLeak : 29|1@0+ (1,0) [0|1] "NoUnit" TBOX,GW_FD5,ICU_E02,GW_FD3,ADCU_FD3,GW_FD4,ICU,CDCS,ADCS_FD3,CDCS_OverSea,TBOX_OverSea
 SG_ BDCS4_FRTyre_SensorFailure : 30|1@0+ (1,0) [0|1] "NoUnit" TBOX,GW_FD5,ICU_E02,GW_FD3,ADCU_FD3,GW_FD4,ICU,CDCS,ADCS_FD3,CDCS_OverSea,TBOX_OverSea
 SG_ BDCS4_FRTyre_LowBattery : 31|1@0+ (1,0) [0|1] "NoUnit" TBOX,GW_FD5,ICU_E02,GW_FD3,ADCU_FD3,GW_FD4,ICU,CDCS,ADCS_FD3,CDCS_OverSea,TBOX_OverSea
 SG_ BDCS4_FRTyre_Pressure : 39|8@0+ (3.137,0) [0|796.798] "kpa" TBOX,GW_FD5,ICU_E02,GW_FD3,ADCU_FD3,GW_FD4,ICU,CDCS,ADCS_FD3,CDCS_OverSea,TBOX_OverSea
 SG_ BDCS4_FRTyre_Temperature : 47|8@0+ (1,-50) [-50|204] "" TBOX,GW_FD5,ICU_E02,GW_FD3,ADCU_FD3,GW_FD4,ICU,CDCS,ADCS_FD3,CDCS_OverSea,TBOX_OverSea
 SG_ BDCS4_Testmode : 53|1@0+ (1,0) [0|1] "NoUnit" TBOX,GW_FD5,ICU_E02,GW_FD3,ADCU_FD3,GW_FD4,ICU,CDCS,ADCS_FD3,CDCS_OverSea,TBOX_OverSea
 SG_ BDCS4_SystemFailure : 55|2@0+ (1,0) [0|3] "NoUnit" ADCU_FD3,CDCS,ADCS_FD3,CDCS_OverSea,TBOX,ACU,GW_FD5,ICU_E02,GW_FD3,GW_FD4,GW_FD1,ICU,TBOX_OverSea

BO_ 484 BDCS_Fr05_1E4: 8 BDCS
 SG_ BDCS5_Rtyre_Status : 0|1@0+ (1,0) [0|1] "NoUnit" TBOX,GW_FD5,ICU_E02,GW_FD3,ADCU_FD3,GW_FD4,ICU,CDCS,ADCS_FD3,CDCS_OverSea,TBOX_OverSea
 SG_ BDCS5_RLTyre_LearntSt : 1|1@0+ (1,0) [0|1] "NoUnit" TBOX,GW_FD5,ICU_E02,GW_FD3,ADCU_FD3,GW_FD4,ICU,CDCS,ADCS_FD3,CDCS_OverSea,TBOX_OverSea
 SG_ BDCS5_RLTyre_PressureWarn : 3|2@0+ (1,0) [0|3] "NoUnit" TBOX,GW_FD5,ICU_E02,GW_FD3,ADCU_FD3,GW_FD4,ICU,CDCS,ADCS_FD3,CDCS_OverSea,TBOX_OverSea
 SG_ BDCS5_RLTyre_TemperatureWarn : 4|1@0+ (1,0) [0|1] "NoUnit" TBOX,GW_FD5,ICU_E02,GW_FD3,ADCU_FD3,GW_FD4,ICU,CDCS,ADCS_FD3,CDCS_OverSea,TBOX_OverSea
 SG_ BDCS5_RLTyre_QucikLeak : 5|1@0+ (1,0) [0|1] "NoUnit" TBOX,GW_FD5,ICU_E02,GW_FD3,ADCU_FD3,GW_FD4,ICU,CDCS,ADCS_FD3,CDCS_OverSea,TBOX_OverSea
 SG_ BDCS5_RLTyre_SensorFailure : 6|1@0+ (1,0) [0|1] "NoUnit" TBOX,GW_FD5,ICU_E02,GW_FD3,ADCU_FD3,GW_FD4,ICU,CDCS,ADCS_FD3,CDCS_OverSea,TBOX_OverSea
 SG_ BDCS5_RLTyre_LowBattery : 7|1@0+ (1,0) [0|1] "NoUnit" TBOX,GW_FD5,ICU_E02,GW_FD3,ADCU_FD3,GW_FD4,ICU,CDCS,ADCS_FD3,CDCS_OverSea,TBOX_OverSea
 SG_ BDCS5_RLTyre_Pressure : 15|8@0+ (3.137,0) [0|796.798] "kpa" TBOX,GW_FD5,ICU_E02,GW_FD3,ADCU_FD3,GW_FD4,ICU,CDCS,ADCS_FD3,CDCS_OverSea,TBOX_OverSea
 SG_ BDCS5_RLTyre_Temperature : 23|8@0+ (1,-50) [-50|204] "" TBOX,GW_FD5,ICU_E02,GW_FD3,ADCU_FD3,GW_FD4,ICU,CDCS,ADCS_FD3,CDCS_OverSea,TBOX_OverSea
 SG_ BDCS5_RRTyre_LearntSt : 25|1@0+ (1,0) [0|1] "NoUnit" TBOX,GW_FD5,ICU_E02,GW_FD3,ADCU_FD3,GW_FD4,ICU,CDCS,ADCS_FD3,CDCS_OverSea,TBOX_OverSea
 SG_ BDCS5_RRTyre_PressureWarn : 27|2@0+ (1,0) [0|3] "NoUnit" TBOX,GW_FD5,ICU_E02,GW_FD3,ADCU_FD3,GW_FD4,ICU,CDCS,ADCS_FD3,CDCS_OverSea,TBOX_OverSea
 SG_ BDCS5_RRTyre_TemperatureWarn : 28|1@0+ (1,0) [0|1] "NoUnit" TBOX,GW_FD5,ICU_E02,GW_FD3,ADCU_FD3,GW_FD4,ICU,CDCS,ADCS_FD3,CDCS_OverSea,TBOX_OverSea
 SG_ BDCS5_RRTyre_QucikLeak : 29|1@0+ (1,0) [0|1] "NoUnit" TBOX,GW_FD5,ICU_E02,GW_FD3,ADCU_FD3,GW_FD4,ICU,CDCS,ADCS_FD3,CDCS_OverSea,TBOX_OverSea
 SG_ BDCS5_RRTyre_SensorFailure : 30|1@0+ (1,0) [0|1] "NoUnit" TBOX,GW_FD5,ICU_E02,GW_FD3,ADCU_FD3,GW_FD4,ICU,CDCS,ADCS_FD3,CDCS_OverSea,TBOX_OverSea
 SG_ BDCS5_RRTyre_LowBattery : 31|1@0+ (1,0) [0|1] "NoUnit" TBOX,GW_FD5,ICU_E02,GW_FD3,ADCU_FD3,GW_FD4,ICU,CDCS,ADCS_FD3,CDCS_OverSea,TBOX_OverSea
 SG_ BDCS5_RRTyre_Pressure : 39|8@0+ (3.137,0) [0|796.798] "kpa" TBOX,GW_FD5,ICU_E02,GW_FD3,ADCU_FD3,GW_FD4,ICU,CDCS,ADCS_FD3,CDCS_OverSea,TBOX_OverSea
 SG_ BDCS5_RRTyre_Temperature : 47|8@0+ (1,-50) [-50|204] "" TBOX,GW_FD5,ICU_E02,GW_FD3,ADCU_FD3,GW_FD4,ICU,CDCS,ADCS_FD3,CDCS_OverSea,TBOX_OverSea

BO_ 486 BDCS_Fr06_1E6: 16 BDCS
 SG_ BDCS6_KeyNotFindIndication : 0|1@0+ (1,0) [0|1] "NoUnit" TBOX,GW_FD5,ICU_E02,GW_FD4,ICU,CDCS,CDCS_OverSea,TBOX_OverSea
 SG_ BDCS6_FindMyCar_Sts_feedback : 1|1@0+ (1,0) [0|1] "NoUnit" ICU_E02,GW_FD4,ICU,CDCS,CDCS_OverSea
 SG_ BDCS6_KeySearchingSts : 2|1@0+ (1,0) [0|1] "NoUnit" TBOX,GW_FD5,ICU_E02,GW_FD4,ICU,WPC,CDCS,CDCS_OverSea,TBOX_OverSea
 SG_ BDCS6_KeylessWarningLight : 3|1@0+ (1,0) [0|1] "NoUnit" TBOX,GW_FD5,ICU_E02,GW_FD4,ICU,CDCS,CDCS_OverSea,TBOX_OverSea
 SG_ BDCS6_KeyLowBatteryIndication : 4|1@0+ (1,0) [0|1] "NoUnit" ICU_E02,GW_FD4,ICU,CDCS,CDCS_OverSea
 SG_ BDCS6_KeyInIndication : 5|1@0+ (1,0) [0|1] "NoUnit" ICU_E02,GW_FD4,ICU,CDCS,CDCS_OverSea
 SG_ BDCS6_DepressBrakePedalInd : 6|1@0+ (1,0) [0|1] "NoUnit" TBOX,GW_FD5,ICU_E02,GW_FD4,ICU,CDCS,CDCS_OverSea,TBOX_OverSea
 SG_ BDCS6_ShiftGearToPNIndication : 7|1@0+ (1,0) [0|1] "NoUnit" TBOX,GW_FD5,ICU_E02,GW_FD4,ICU,CDCS,CDCS_OverSea,TBOX_OverSea
 SG_ BDCS6_ShiftGearToPIndication : 8|1@0+ (1,0) [0|1] "NoUnit" TBOX,GW_FD5,ICU_E02,GW_FD4,ICU,CDCS,CDCS_OverSea,TBOX_OverSea
 SG_ BDCS6_BackupStartIndication : 9|1@0+ (1,0) [0|1] "NoUnit" TBOX,GW_FD5,ICU_E02,GW_FD4,ICU,CDCS,CDCS_OverSea,TBOX_OverSea
 SG_ BDCS6_WiperNozzleHeat_SW_Fed : 10|1@0+ (1,0) [0|1] "NoUnit" GW_FD4,CDCS_OverSea
 SG_ BDCS6_ALHSelectModeCtrlFed : 13|3@0+ (1,0) [0|7] "NoUnit" TBOX,GW_FD5,GW_FD4,CDCS,CDCS_OverSea,TBOX_OverSea
 SG_ BDCS6_FrontWasherSts : 14|1@0+ (1,0) [0|1] "NoUnit" TBOX,GW_FD5,GW_FD4,CDCS,CDCS_OverSea,TBOX_OverSea
 SG_ BDCS6_FrontWiperParkPos : 15|1@0+ (1,0) [0|1] "NoUnit" SRR3,SRR4,CDCS,ADCS_FD3,CDCS_OverSea,TBOX,FLC_ME_FD3,FLC_FD3,GW_FD5,GW_FD6,GW_FD3,GW_FD4,TBOX_OverSea
 SG_ BDCS6_FrontWiperSts : 18|3@0+ (1,0) [0|7] "NoUnit" SRR3,SRR4,CDCS,ADCS_FD3,CDCS_OverSea,TBOX,FLC_ME_FD3,FLC_FD3,GW_FD5,GW_FD6,GW_FD3,GW_FD4,TBOX_OverSea
 SG_ BDCS6_FrontWiperMaintenancePos : 19|1@0+ (1,0) [0|1] "NoUnit" TBOX,GW_FD5,GW_FD4,CDCS,CDCS_OverSea,TBOX_OverSea
 SG_ BDCS6_RearWiperSts : 20|1@0+ (1,0) [0|1] "NoUnit" TBOX,GW_FD5,GW_FD4,CDCS,CDCS_OverSea,TBOX_OverSea
 SG_ BDCS6_RearWiperParkPos : 21|1@0+ (1,0) [0|1] "NoUnit" TBOX,GW_FD5,GW_FD4,CDCS,CDCS_OverSea,TBOX_OverSea
 SG_ BDCS6_RearWasherSts : 22|1@0+ (1,0) [0|1] "NoUnit" TBOX,GW_FD5,GW_FD4,CDCS,CDCS_OverSea,TBOX_OverSea
 SG_ BDCS6_RearDefrostSts : 23|1@0+ (1,0) [0|1] "NoUnit" PDCS_FD1,TBOX,GW_FD5,GW_FD4,GW_FD1,CDCS,PDCS_HVM_FD1,CDCS_OverSea,TBOX_OverSea
 SG_ BDCS6_IHU_AC_St : 24|1@0+ (1,0) [0|1] "NoUnit" TBOX,GW_FD5,GW_FD4,CDCS,CDCS_OverSea,TBOX_OverSea
 SG_ BDCS6_ALH_SW_Fed : 25|1@0+ (1,0) [0|1] "NoUnit" GW_FD4,CDCS,CDCS_OverSea
 SG_ BDCS6_EntryMode_Fed : 26|1@0+ (1,0) [0|1] "NoUnit" GW_FD4,CDCS,CDCS_OverSea
 SG_ BDCS6_AEBMode_Fed : 27|1@0+ (1,0) [0|1] "NoUnit" GW_FD4,CDCS,CDCS_OverSea
 SG_ BDCS6_LockUpWindowSETfbk : 29|2@0+ (1,0) [0|3] "NoUnit" GW_FD4,CDCS,CDCS_OverSea
 SG_ BDCS6_LOGOLampST : 30|1@0+ (1,0) [0|1] "NoUnit" GW_FD4,CDCS,CDCS_OverSea
 SG_ BDCS6_AUTOHOLDLamp : 31|1@0+ (1,0) [0|1] "NoUnit" GW_FD4,CDCS,CDCS_OverSea
 SG_ BDCS6_WiperNozzleHeat_Fdb : 34|3@0+ (1,0) [0|7] "NoUnit" GW_FD4,CDCS_OverSea
 SG_ BDCS6_BiologicalDetectionFbk : 35|1@0+ (1,0) [0|1] "NoUnit" GW_FD4,CDCS,CDCS_OverSea
 SG_ BDCS6_ALH_DriveModeSW_Fed : 36|1@0+ (1,0) [0|1] "NoUnit" GW_FD4,CDCS,CDCS_OverSea
 SG_ BDCS6_ALH_TemperatureSW_Fed : 37|1@0+ (1,0) [0|1] "NoUnit" GW_FD4,CDCS,CDCS_OverSea
 SG_ BDCS6_ALHSelectColourCtrlFed : 39|2@0+ (1,0) [0|3] "NoUnit" GW_FD4,CDCS,CDCS_OverSea
 SG_ BDCS6_IHU_Brightness_fb : 46|7@0+ (1,0) [0|100] "%" GW_FD4,CDCS,CDCS_OverSea
 SG_ BDCS6_RoadRecSts : 47|1@0+ (1,0) [0|1] "NoUnit" GW_FD4,CDCS,CDCS_OverSea
 SG_ BDCS6_IHU_Rvalue_fb : 55|8@0+ (1,0) [0|255] "NoUnit" GW_FD4,CDCS,CDCS_OverSea
 SG_ BDCS6_IHU_Gvalue_fb : 63|8@0+ (1,0) [0|255] "NoUnit" ICU_E02,GW_FD4,ICU,CDCS,CDCS_OverSea
 SG_ BDCS6_IHU_Bvalue_fb : 71|8@0+ (1,0) [0|255] "NoUnit" ICU_E02,GW_FD4,ICU,CDCS,CDCS_OverSea
 SG_ BDCS6_DGM_percentSts : 76|5@0+ (1,0) [0|31] "NoUnit" GW_FD4,CDCS,CDCS_OverSea
 SG_ BDCS6_DGM_SWSts : 78|2@0+ (1,0) [0|3] "NoUnit" GW_FD4,CDCS,CDCS_OverSea
 SG_ BDCS6_ChargingLamp_Fdb : 79|1@0+ (1,0) [0|1] "NoUnit" ICU_E02,GW_FD4,ICU,CDCS,CDCS_OverSea
 SG_ BDCS6_LowBeamSt_F : 80|1@0+ (1,0) [0|1] "NoUnit" ICU_E02,GW_FD4,ICU,CDCS,CDCS_OverSea
 SG_ BDCS6_HighBeamSt_F : 81|1@0+ (1,0) [0|1] "NoUnit" ICU_E02,GW_FD4,ICU,CDCS,CDCS_OverSea
 SG_ BDCS6_PositionLightSts_F : 82|1@0+ (1,0) [0|1] "NoUnit" ICU_E02,GW_FD4,ICU,CDCS,CDCS_OverSea
 SG_ BDCS6_LeftTurnLightSt_F : 83|1@0+ (1,0) [0|1] "NoUnit" ICU_E02,GW_FD4,ICU,CDCS,CDCS_OverSea
 SG_ BDCS6_RightTurnLightSt_F : 84|1@0+ (1,0) [0|1] "NoUnit" ICU_E02,GW_FD4,ICU,CDCS,CDCS_OverSea
 SG_ BDCS6_BrakeLightSts_F : 85|1@0+ (1,0) [0|1] "NoUnit" GW_FD4,CDCS,CDCS_OverSea
 SG_ BDCS6_RearFogLampSt_F : 86|1@0+ (1,0) [0|1] "NoUnit" GW_FD4,CDCS,CDCS_OverSea
 SG_ BDCS6_DRLSt_F : 87|1@0+ (1,0) [0|1] "NoUnit" GW_FD4,CDCS,CDCS_OverSea
 SG_ BDCS6_FLcorneringLampSt : 89|2@0+ (1,0) [0|3] "NoUnit" GW_FD4,CDCS,CDCS_OverSea
 SG_ BDCS6_FRcorneringLampSt : 91|2@0+ (1,0) [0|3] "NoUnit" GW_FD4,CDCS,CDCS_OverSea
 SG_ BDCS6_DayNightMode : 93|2@0+ (1,0) [0|3] "NoUnit" FLC_ME_FD3,FLC_FD3,GW_FD3,GW_FD4,CDCS,ADCS_FD3,CDCS_OverSea
 SG_ BDCS6_ALHBrightnessAutoMode_Fdb : 95|2@0+ (1,0) [0|3] "NoUnit" GW_FD4,CDCS,CDCS_OverSea
 SG_ BDCS6_DGM_AdjustedPercentage : 102|7@0+ (1,0) [0|100] "%" GW_FD4,CDCS,CDCS_OverSea
 SG_ BDCS6_SOC_Lamp_Fdb : 103|1@0+ (1,0) [0|1] "NoUnit" GW_FD4,CDCS,CDCS_OverSea
 SG_ BDCS6_AutoDfrostSts : 104|1@0+ (1,0) [0|1] "NoUnit" GW_FD4,CDCS,CDCS_OverSea
 SG_ BDCS6_AutoDrySts : 105|1@0+ (1,0) [0|1] "NoUnit" GW_FD4,CDCS,CDCS_OverSea
 SG_ BDCS6_BtmCallAutoSpdSts : 106|1@0+ (1,0) [0|1] "NoUnit" GW_FD4,CDCS,CDCS_OverSea
 SG_ BDCS6_AutoAionSts : 107|1@0+ (1,0) [0|1] "NoUnit" GW_FD4,CDCS,CDCS_OverSea
 SG_ BDCS6_AQSConfigSts : 108|1@0+ (1,0) [0|1] "NoUnit" GW_FD4,CDCS,CDCS_OverSea
 SG_ BDCS6_PM25AutoCleanPopupSts : 109|1@0+ (1,0) [0|1] "NoUnit" GW_FD4,CDCS,CDCS_OverSea
 SG_ BDCS6_CabinCleanConfigSts : 110|1@0+ (1,0) [0|1] "NoUnit" GW_FD4,CDCS,CDCS_OverSea
 SG_ BDCS6_ALH_ADASWarning_Fdb : 111|1@0+ (1,0) [0|1] "NoUnit" GW_FD4,CDCS,CDCS_OverSea
 SG_ BDCS6_ALHSelectTheme_Fdb : 114|3@0+ (1,0) [0|7] "NoUnit" GW_FD4,CDCS,CDCS_OverSea
 SG_ BDCS6_SunRoofSLideCtrlReq_Fdb : 119|5@0+ (1,0) [0|31] "NoUnit" GW_FD4,CDCS,CDCS_OverSea
 SG_ BDCS6_SunRoofCtrlReq_Fdb : 122|3@0+ (1,0) [0|7] "NoUnit" TBOX,GW_FD5,GW_FD4,CDCS,CDCS_OverSea,TBOX_OverSea
 SG_ BDCS6_CurtainSLideCtrlReq_Fdb : 127|5@0+ (1,0) [0|31] "NoUnit" GW_FD4,CDCS,CDCS_OverSea

BO_ 496 BDCS_Fr02_1F0: 8 BDCS
 SG_ BDCS2_DoorLockCmd : 1|2@0+ (1,0) [0|3] "NoUnit" PDCU,DDCU,BAM,CDCS,CDCS_OverSea,TBOX,CDU,GW_FD5,ICU_E02,GW_FD4,GW_FD1,ICU,TBOX_OverSea
 SG_ BDCS2_FLWindowsCtrl : 4|3@0+ (1,0) [0|7] "NoUnit" DDCU
 SG_ BDCS2_FRWindowsCtrl : 7|3@0+ (1,0) [0|7] "NoUnit" PDCU
 SG_ BDCS2_RLWindowsCtrl : 10|3@0+ (1,0) [0|7] "NoUnit" DDCU
 SG_ BDCS2_RRWindowsCtrl : 13|3@0+ (1,0) [0|7] "NoUnit" PDCU
 SG_ BDCS2_FrontDoorOpenModeSts : 15|2@0+ (1,0) [0|3] "NoUnit" GW_FD4,CDCS,CDCS_OverSea
 SG_ BDCS2_OpenFLDoorReq : 17|2@0+ (1,0) [0|3] "NoUnit" DDCU
 SG_ BDCS2_OpenFRDoorReq : 19|2@0+ (1,0) [0|3] "NoUnit" PDCU
 SG_ BDCS2_LSD_FL_Away_Up_Sts : 21|2@0+ (1,0) [0|3] "NoUnit" GW_FD4,CDCS,CDCS_OverSea
 SG_ BDCS2_LSD_FR_Away_Up_Sts : 23|2@0+ (1,0) [0|3] "NoUnit" GW_FD4,CDCS,CDCS_OverSea
 SG_ BDCS2_RainwinClosedFbk : 25|2@0+ (1,0) [0|3] "NoUnit" TBOX,GW_FD5,TBOX_OverSea
 SG_ BDCS2_SunRoof_GlassMovement : 27|2@0+ (1,0) [0|3] "NoUnit" GW_FD4,CDCS,CDCS_OverSea
 SG_ BDCS2_Curtain_Movement : 29|2@0+ (1,0) [0|3] "NoUnit" GW_FD4,CDCS,CDCS_OverSea
 SG_ BDCS2_CarTempHoldMode_Fdb : 31|2@0+ (1,0) [0|3] "NoUnit" TBOX,GW_FD5,GW_FD4,CDCS,CDCS_OverSea,TBOX_OverSea
 SG_ BDCS2_RemoteFindCarStsFdb : 33|1@0+ (1,0) [0|1] "NoUnit" TBOX,GW_FD5,TBOX_OverSea
 SG_ BDCS2_CurtainCtrlReq_Fdb : 36|2@0+ (1,0) [0|3] "NoUnit" GW_FD4,CDCS,CDCS_OverSea
 SG_ BDCS2_SRMGlassInitialized : 37|1@0+ (1,0) [0|1] "NoUnit" GW_FD4,CDCS,CDCS_OverSea
 SG_ BDCS2_SRMTeachingRunningSts : 38|1@0+ (1,0) [0|1] "NoUnit" GW_FD4,CDCS,CDCS_OverSea
 SG_ BDCS2_CurtainInitialized : 39|1@0+ (1,0) [0|1] "NoUnit" GW_FD4,CDCS,CDCS_OverSea
 SG_ BDCS2_CurtainTeachingRunningSts : 40|1@0+ (1,0) [0|1] "NoUnit" GW_FD4,CDCS,CDCS_OverSea
 SG_ BDCS2_TemKeepModeRmd : 41|1@0+ (1,0) [0|1] "NoUnit" TBOX,GW_FD5,TBOX_OverSea
 SG_ BDCS2_TemKeepModeExitFailRsn : 43|2@0+ (1,0) [0|3] "NoUnit" TBOX,GW_FD5,TBOX_OverSea
 SG_ BDCS2_SRMOverspeedClosing : 48|1@0+ (1,0) [0|1] "NoUnit" GW_FD4,CDCS,CDCS_OverSea
 SG_ BDCS2_PLG_DoorHeightSetFb : 55|7@0+ (1,0) [0|100] "%" GW_FD4,CDCS,CDCS_OverSea

BO_ 512 BDCS_Fr20_200: 32 BDCS
 SG_ BDCS20_bParkPosnReq : 0|1@0+ (1,0) [0|1] "NoUnit" Vector__XXX
 SG_ BDCS20_bAcvCmprSpdLim : 1|1@0+ (1,0) [0|1] "NoUnit" Vector__XXX
 SG_ BDCS20_bAcvExvPosnRchdMax : 2|1@0+ (1,0) [0|1] "NoUnit" Vector__XXX
 SG_ BDCS20_bAcvCtlForPRlf : 3|1@0+ (1,0) [0|1] "NoUnit" Vector__XXX
 SG_ BDCS20_bBlowrClnReq : 4|1@0+ (1,0) [0|1] "NoUnit" Vector__XXX
 SG_ BDCS20_bBodyCtlrSleepAllwd : 5|1@0+ (1,0) [0|1] "NoUnit" Vector__XXX
 SG_ BDCS20_bAcvFlapIniDoneFlg : 6|1@0+ (1,0) [0|1] "NoUnit" Vector__XXX
 SG_ BDCS20_bAirDefrstDibtnReq : 7|1@0+ (1,0) [0|1] "NoUnit" Vector__XXX
 SG_ BDCS20_bAirFaceDibtnReq : 8|1@0+ (1,0) [0|1] "NoUnit" Vector__XXX
 SG_ BDCS20_bAirFootDibtnReq : 9|1@0+ (1,0) [0|1] "NoUnit" Vector__XXX
 SG_ BDCS20_StPerfEve : 15|4@0+ (1,0) [0|3] "NoUnit" Vector__XXX
 SG_ BDCS20_ModeHvacThermReq : 19|4@0+ (1,0) [0|3] "NoUnit" Vector__XXX
 SG_ BDCS20_StCircHeatgThermMode : 23|4@0+ (1,0) [0|3] "NoUnit" Vector__XXX
 SG_ BDCS20_StRfgtCircThermMode : 27|4@0+ (1,0) [0|3] "NoUnit" Vector__XXX
 SG_ BDCS20_StHumCtlEve : 31|4@0+ (1,0) [0|7] "NoUnit" Vector__XXX
 SG_ BDCS20_StPtThermMode : 35|4@0+ (1,0) [0|7] "NoUnit" Vector__XXX
 SG_ BDCS20_ModePwrDstnModeRaw : 39|4@0+ (1,0) [0|7] "NoUnit" Vector__XXX
 SG_ BDCS20_StEve : 43|4@0+ (1,0) [0|15] "NoUnit" Vector__XXX
 SG_ BDCS20_NrEvst : 47|4@0+ (1,0) [0|15] "NoUnit" Vector__XXX
 SG_ BDCS20_UBlowrSpdReq : 55|8@0+ (0.1,0) [0|14] "V" Vector__XXX
 SG_ BDCS20_UBlowrSpdAct : 63|8@0+ (0.1,0) [0|14] "V" Vector__XXX
 SG_ BDCS20_PwrWtrHeatrRawReq : 71|8@0+ (100,0) [0|20000] "W" Vector__XXX
 SG_ BDCS20_PwrWtrHeatrReq : 79|8@0+ (100,0) [0|20000] "W" Vector__XXX
 SG_ BDCS20_PwrCmprLimIni : 87|8@0+ (0.1,0) [0|20] "kW" Vector__XXX
 SG_ BDCS20_PwrWtrHeatrLim : 95|8@0+ (0.1,0) [0|20] "kW" Vector__XXX
 SG_ BDCS20_PctgPosnReq : 103|7@0+ (1,0) [0|100] "%" Vector__XXX
 SG_ BDCS20_PCmprInletAct : 96|9@0+ (0.1,0) [0|50] "bar" Vector__XXX
 SG_ BDCS20_PctgBlowrSpdReq : 119|7@0+ (1,0) [0|100] "%" Vector__XXX
 SG_ BDCS20_PCndsrOutlAct : 112|9@0+ (0.1,0) [0|50] "bar" Vector__XXX
 SG_ BDCS20_RateCabinAccdnrCmdZone1 : 135|8@0+ (1,-100) [-100|100] "%" Vector__XXX
 SG_ BDCS20_RateCabinAccdnrCmdZone2 : 143|8@0+ (1,-100) [-100|100] "%" Vector__XXX
 SG_ BDCS20_NCmprReqLimdByP : 150|7@0+ (100,0) [0|12000] "rpm" Vector__XXX
 SG_ BDCS20_NCmprSatdReq : 158|7@0+ (100,0) [0|12000] "rpm" Vector__XXX
 SG_ BDCS20_TFootDmdZone1 : 167|8@0+ (0.5,-40) [-40|80] "℃" Vector__XXX
 SG_ BDCS20_TFootDmdZone2 : 175|8@0+ (0.5,-40) [-40|80] "℃" Vector__XXX
 SG_ BDCS20_TFaceDmdZone1 : 183|8@0+ (0.5,-40) [-40|80] "℃" Vector__XXX
 SG_ BDCS20_TFaceDmdZone2 : 191|8@0+ (0.5,-40) [-40|80] "℃" Vector__XXX

BO_ 490 BDCS_Fr21_1EA: 8 BDCS
 SG_ BDCS21_BrakeLightSts_F : 0|1@0+ (1,0) [0|1] "NoUnit" ICU_E02,GW_FD4,CDCS_OverSea
 SG_ BDCS21_MsgCounter : 51|4@0+ (1,0) [0|15] "NoUnit" ICU_E02,GW_FD4,CDCS_OverSea
 SG_ BDCS21_Checksum : 63|8@0+ (1,0) [0|255] "NoUnit" ICU_E02,GW_FD4,CDCS_OverSea

BO_ 564 BDCS_Fr14_234: 16 BDCS
 SG_ BDCS10_AGS_Pos_Cmd : 3|4@0+ (1,0) [0|15] "" PDCS_FD1,GW_FD1,PDCS_HVM_FD1
 SG_ BDCS10_AGS_Cali_Cmd : 4|1@0+ (1,0) [0|1] "" PDCS_FD1,GW_FD1,PDCS_HVM_FD1
 SG_ BDCS10_AGS_Curr_Limit_Cmd : 7|2@0+ (1,0) [0|3] "" PDCS_FD1,GW_FD1,PDCS_HVM_FD1
 SG_ BDCS10_FTWV_A_MoveEnable : 8|1@0+ (1,0) [0|1] "" Vector__XXX
 SG_ BDCS10_FTWV_B_MoveEnable : 9|1@0+ (1,0) [0|1] "" Vector__XXX
 SG_ BDCS10_EXV_B_MoveEnb : 10|1@0+ (1,0) [0|1] "" Vector__XXX
 SG_ BDCS10_EWP_H_DefaultReq : 11|1@0+ (1,0) [0|1] "" Vector__XXX
 SG_ BDCS10_EXV_B_InitReq : 13|2@0+ (1,0) [0|2] "" Vector__XXX
 SG_ BDCS10_EWP_B_DefaultReq : 14|1@0+ (1,0) [0|1] "" Vector__XXX
 SG_ BDCS10_EWP_M_DefaultRq : 15|1@0+ (1,0) [0|1] "" Vector__XXX
 SG_ BDCS10_FTWV_A_ReqMovePos : 23|12@0+ (0.1,0) [0|100] "%" GW_FD1,MCU
 SG_ BDCS10_FTWV_B_ReqMovePos : 27|12@0+ (0.1,0) [0|100] "%" GW_FD1,MCU
 SG_ BDCS10_EXV_B_PosReq : 71|16@0+ (1,0) [0|576] "" Vector__XXX
 SG_ BDCS10_EWP_H_TRPMRq : 87|8@0+ (1,0) [0|254] "" Vector__XXX
 SG_ BDCS10_EWP_B_TRPMReq : 95|8@0+ (1,0) [0|254] "" Vector__XXX
 SG_ BDCS10_EWP_M_TRPMReq : 103|8@0+ (1,0) [0|254] "" GW_FD1,MCU

BO_ 565 BDCS_Fr15_LIN4_235: 64 BDCS
 SG_ EXV_B_LINRespErr : 0|1@0+ (1,0) [0|1] "" Vector__XXX
 SG_ EXV_B_curInit_Stat : 2|2@0+ (1,0) [0|3] "" Vector__XXX
 SG_ EXV_B_Run_Stat : 3|1@0+ (1,0) [0|1] "" Vector__XXX
 SG_ EXV_B_Fault_Stat : 7|4@0+ (1,0) [0|15] "" Vector__XXX
 SG_ EXV_B_CurPos : 15|16@0+ (1,0) [0|576] "" Vector__XXX
 SG_ EXV_B_Volt_Stat : 25|2@0+ (1,0) [0|3] "" Vector__XXX
 SG_ EXV_B_OvrTemp_Warn : 27|2@0+ (1,0) [0|3] "" Vector__XXX
 SG_ EWP_H_LINRespErr : 28|1@0+ (1,0) [0|1] "" Vector__XXX
 SG_ EWP_B_LINRespErr : 29|1@0+ (1,0) [0|1] "" Vector__XXX
 SG_ EWP_M_LINRespErr : 30|1@0+ (1,0) [0|1] "" Vector__XXX
 SG_ FTWV_A_Rsp_Comm_Err : 31|1@0+ (1,0) [0|1] "" Vector__XXX
 SG_ EWP_H_RPM_Target_Stat : 39|8@0+ (1,0) [0|254] "" Vector__XXX
 SG_ EWP_H_RPM_ActlVal_Stat : 47|8@0+ (1,0) [0|254] "" Vector__XXX
 SG_ EWP_H_Volt_Stat : 55|8@0+ (0.1,0) [0|25.4] "V" Vector__XXX
 SG_ EWP_H_Temp_Stat : 63|8@0+ (1,-50) [-50|204] "℃" Vector__XXX
 SG_ EWP_H_Curr_Stat : 71|8@0+ (0.1,0) [0|25.4] "A" Vector__XXX
 SG_ EWP_H_OverCurr_Error : 73|2@0+ (1,0) [0|3] "" Vector__XXX
 SG_ EWP_H_DryRun_Error : 75|2@0+ (1,0) [0|3] "" Vector__XXX
 SG_ EWP_H_SupVolt_Error : 77|2@0+ (1,0) [0|3] "" Vector__XXX
 SG_ EWP_H_Block_Error : 79|2@0+ (1,0) [0|3] "" Vector__XXX
 SG_ EWP_H_OverTemp_Error : 81|2@0+ (1,0) [0|3] "" Vector__XXX
 SG_ EWP_B_OverTemp_Error : 83|2@0+ (1,0) [0|3] "" Vector__XXX
 SG_ EWP_M_OverTemp_Error : 85|2@0+ (1,0) [0|3] "" Vector__XXX
 SG_ FTWV_B_Rsp_Comm_Err : 86|1@0+ (1,0) [0|1] "" Vector__XXX
 SG_ EWP_B_RPM_Target_Stat : 95|8@0+ (1,0) [0|254] "" Vector__XXX
 SG_ EWP_B_RPM_ActlVal_Stat : 103|8@0+ (1,0) [0|254] "" Vector__XXX
 SG_ EWP_B_Volt_Stat : 111|8@0+ (0.1,0) [0|25.4] "V" Vector__XXX
 SG_ EWP_B_Temp_Stat : 119|8@0+ (1,-50) [-50|204] "℃" Vector__XXX
 SG_ EWP_B_Curr_Stat : 127|8@0+ (0.1,0) [0|25.4] "A" Vector__XXX
 SG_ EWP_B_OverCurr_Error : 129|2@0+ (1,0) [0|3] "" Vector__XXX
 SG_ EWP_B_DryRun_Error : 131|2@0+ (1,0) [0|3] "" Vector__XXX
 SG_ EWP_B_SupVolt_Error : 133|2@0+ (1,0) [0|3] "" Vector__XXX
 SG_ EWP_B_Block_Error : 135|2@0+ (1,0) [0|3] "" Vector__XXX
 SG_ EWP_M_RPM_Target_Stat : 143|8@0+ (1,0) [0|254] "" Vector__XXX
 SG_ EWP_M_RPM_ActlVal_Stat : 151|8@0+ (1,0) [0|254] "" GW_FD1,MCU
 SG_ EWP_M_Volt_Stat : 159|8@0+ (0.1,0) [0|25.4] "V" Vector__XXX
 SG_ EWP_M_Temp_Stat : 167|8@0+ (1,-50) [-50|204] "℃" Vector__XXX
 SG_ EWP_M_Curr_Stat : 175|8@0+ (0.1,0) [0|25.4] "A" Vector__XXX
 SG_ EWP_M_OverCurr_Error : 177|2@0+ (1,0) [0|3] "" Vector__XXX
 SG_ EWP_M_DryRun_Error : 179|2@0+ (1,0) [0|3] "" Vector__XXX
 SG_ EWP_M_SupVolt_Error : 181|2@0+ (1,0) [0|3] "" Vector__XXX
 SG_ EWP_M_Block_Error : 183|2@0+ (1,0) [0|3] "" Vector__XXX
 SG_ FTWV_A_Fault_Signal : 187|4@0+ (1,0) [0|15] "" Vector__XXX
 SG_ FTWV_A_VoltageErr : 189|2@0+ (1,0) [0|3] "" Vector__XXX
 SG_ FTWV_A_TempWarn : 190|1@0+ (1,0) [0|1] "" Vector__XXX
 SG_ FTWV_A_MotorStatus : 191|1@0+ (1,0) [0|1] "" Vector__XXX
 SG_ FTWV_A_Rsp_Pos : 199|16@0+ (0.1,0) [0|100] "%" GW_FD1,MCU
 SG_ FTWV_B_Fault_Signal : 211|4@0+ (1,0) [0|15] "" Vector__XXX
 SG_ FTWV_B_VoltageErr : 213|2@0+ (1,0) [0|3] "" Vector__XXX
 SG_ FTWV_B_TempWarn : 214|1@0+ (1,0) [0|1] "" Vector__XXX
 SG_ FTWV_B_MotorStatus : 215|1@0+ (1,0) [0|1] "" Vector__XXX
 SG_ FTWV_B_Rsp_Pos : 223|16@0+ (0.1,0) [0|100] "%" GW_FD1,MCU
 SG_ BDCS15_PChlrOutlTgt : 239|7@0+ (0.01,0) [0|1.1] "Mpa" Vector__XXX
 SG_ BDCS15_PCmprOutlTgt : 232|9@0+ (0.01,0) [0|3.6] "Mpa" Vector__XXX
 SG_ BDCS15_PEvprOutlTgt : 255|7@0+ (0.01,0) [0|1.1] "Mpa" Vector__XXX
 SG_ BDCS15_TEdrvCooltInletTgt : 263|8@0+ (1,-40) [-40|120] "℃" Vector__XXX
 SG_ BDCS15_THeatCoreCooltInletTgt : 271|8@0+ (1,-40) [-40|120] "℃" Vector__XXX
 SG_ BDCS15_THVBatCooltInletTgt : 279|8@0+ (1,-40) [-40|120] "℃" Vector__XXX
 SG_ BDCS15_HPTMD_StHeatgMode : 287|2@0+ (1,0) [0|3] "" Vector__XXX

BO_ 645 BDCS_Fr13_LIN2_285: 8 BDCS
 SG_ BDCS13_RLS_HUDBrightRawValue : 6|7@0+ (1,0) [0|127] "NoUnit" ICU_E02,GW_FD4,ICU,CDCS,CDCS_OverSea
 SG_ BDCS13_RLS_HUDBrightnessSnrFault : 7|1@0+ (1,0) [0|1] "NoUnit" ICU_E02,GW_FD4,ICU,CDCS,CDCS_OverSea
 SG_ BDCS13_RLS_HUDBrightUnit : 9|2@0+ (1,0) [0|3] "NoUnit" ICU_E02,GW_FD4,ICU,CDCS,CDCS_OverSea
 SG_ BDCS13_RLS_REP_Error : 10|1@0+ (1,0) [0|1] "NoUnit" ICU_E02,GW_FD4,ICU,CDCS,CDCS_OverSea
 SG_ BDCS13_RLS_VOLT_Error : 12|2@0+ (1,0) [0|3] "NoUnit" ICU_E02,GW_FD4,ICU,CDCS,CDCS_OverSea
 SG_ BDCS13_RLS_RQ_WiperSPD : 14|2@0+ (1,0) [0|3] "NoUnit" TBOX,FLC_ME_FD3,FLC_FD3,GW_FD5,GW_FD3,ADCU_FD3,GW_FD4,CDCS,ADCS_FD3,CDCS_OverSea,TBOX_OverSea
 SG_ RATS1_DFGLS_ButtonSoundRequest : 15|1@0+ (1,0) [0|1] "NoUnit" GW_FD4,CDCS,CDCS_OverSea
 SG_ DGM_IntelligentProtectionSt : 16|1@0+ (1,0) [0|1] "NoUnit" GW_FD4,CDCS,CDCS_OverSea
 SG_ DGM_AutoSWSts : 17|1@0+ (1,0) [0|1] "NoUnit" GW_FD4,CDCS,CDCS_OverSea
 SG_ BDCS13_CO2_State : 19|2@0+ (1,0) [0|3] "NoUnit" TBOX,GW_FD5,GW_FD4,CDCS,CDCS_OverSea,TBOX_OverSea
 SG_ BDCS13_CO2_DensitySts : 21|2@0+ (1,0) [0|3] "NoUnit" TBOX,GW_FD5,GW_FD4,CDCS,CDCS_OverSea,TBOX_OverSea
 SG_ BDCS13_IN_TrunkSWStatus : 23|1@0+ (1,0) [0|1] "NoUnit" GW_FD4,CDCS_OverSea
 SG_ BDCS13_CO2_Value : 31|16@0+ (1,0) [0|5000] "ug/m3" TBOX,GW_FD5,GW_FD4,CDCS,CDCS_OverSea,TBOX_OverSea
 SG_ BDCS13_RLS_Rain_state : 40|1@0+ (1,0) [0|1] "NoUnit" PDCU,GW_FD4,DDCU,CDCS,CDCS_OverSea
 SG_ BDCS13_OUT_TrunkSWStatus : 44|1@0+ (1,0) [0|1] "NoUnit" GW_FD4,CDCS_OverSea
 SG_ BDCS13_TrunkDrivingStatus : 51|1@0+ (1,0) [0|1] "NoUnit" GW_FD4,CDCS_OverSea
 SG_ BDCS13_SRM_FaultMessage : 54|3@0+ (1,0) [0|7] "NoUnit" Vector__XXX

BO_ 661 BDCS_Fr11_295: 32 BDCS
 SG_ BDCS11_AcFilter_SOH : 7|8@0+ (1,0) [0|100] "%" TBOX,GW_FD5,GW_FD4,CDCS,CDCS_OverSea,TBOX_OverSea
 SG_ BDCS11_AC_EAC_Command : 9|2@0+ (1,0) [0|3] "NoUnit" PDCS_FD1,BMS,GW_FD1,PDCS_HVM_FD1
 SG_ BDCS11_AC_PTC_Request : 11|2@0+ (1,0) [0|3] "NoUnit" PDCS_FD1,BMS,GW_FD1,PDCS_HVM_FD1
 SG_ BDCS11_AC_PTC_Level : 15|4@0+ (10,0) [0|100] "%" Vector__XXX
 SG_ BDCS11_PTC_TargTemp : 22|7@0+ (1,0) [0|98] "" PDCS_FD1,TBOX,GW_FD5,BMS,GW_FD1,PDCS_HVM_FD1,TBOX_OverSea
 SG_ BDCS11_AcFilter_SOH_Valid : 23|1@0+ (1,0) [0|1] "NoUnit" TBOX,GW_FD5,GW_FD4,CDCS,CDCS_OverSea,TBOX_OverSea
 SG_ BDCS11_PumpHTarSpdValid : 24|1@0+ (1,0) [0|1] "NoUnit" PDCS_FD1,GW_FD1,PDCS_HVM_FD1
 SG_ BDCS11_AC_EAC_SpeedSet : 31|7@0+ (100,0) [0|8600] "rpm" TBOX,GW_FD5,TBOX_OverSea
 SG_ BDCS11_PumpHTarSpd : 39|8@0+ (1,0) [0|100] "%" PDCS_FD1,GW_FD1,PDCS_HVM_FD1
 SG_ BDCS11_AC_FanGearPwmReq : 47|8@0+ (1,0) [0|100] "%" PDCS_FD1,GW_FD1,PDCS_HVM_FD1
 SG_ BDCS11_FogRiskLvl : 50|3@0+ (1,0) [0|7] "" Vector__XXX
 SG_ BDCS11_AC_FanGearPwmReqV : 51|1@0+ (1,0) [0|1] "NoUnit" PDCS_FD1,GW_FD1,PDCS_HVM_FD1
 SG_ BDCS11_AC_EAC_PowerLimit : 55|4@0+ (0.5,0) [0|7] "Kw" Vector__XXX
 SG_ BDCS11_PM25WorkReq : 56|1@0+ (1,0) [0|1] "NoUnit" Vector__XXX
 SG_ BDCS11_PM25RealSts : 58|2@0+ (1,0) [0|3] "NoUnit" Vector__XXX
 SG_ BDCS11_AC_PowerReq : 63|5@0+ (0.5,0) [0|15] "Kw" PDCS_FD1,GW_FD1,PDCS_HVM_FD1
 SG_ BDCS11_ACMaxSts : 64|1@0+ (1,0) [0|1] "NoUnit" GW_FD4,CDCS,CDCS_OverSea
 SG_ BDCS11_HeatMaxSts : 65|1@0+ (1,0) [0|1] "NoUnit" GW_FD4,CDCS,CDCS_OverSea
 SG_ BDCS11_AirCleanSts : 66|1@0+ (1,0) [0|1] "NoUnit" GW_FD4,CDCS,CDCS_OverSea
 SG_ BDCS11_ECONModeSts : 67|1@0+ (1,0) [0|1] "NoUnit" GW_FD4,CDCS,CDCS_OverSea
 SG_ BDCS11_BlowModSts : 71|4@0+ (1,0) [0|15] "NoUnit" TBOX,GW_FD5,GW_FD4,CDCS,CDCS_OverSea,TBOX_OverSea
 SG_ BDCS11_PMAirInQLevel : 74|3@0+ (1,0) [0|7] "NoUnit" GW_FD4,CDCS,CDCS_OverSea
 SG_ BDCS11_CabModeSts : 78|4@0+ (1,0) [0|15] "NoUnit" PDCS_FD1,BMS,GW_FD1,PDCS_HVM_FD1
 SG_ BDCS11_HeatMngtFctLim : 79|1@0+ (1,0) [0|1] "NoUnit" Vector__XXX
 SG_ BDCS11_BatModeSts : 83|4@0+ (1,0) [0|15] "NoUnit" PDCS_FD1,BMS,GW_FD1,PDCS_HVM_FD1
 SG_ BDCS11_PwrModeSts : 87|4@0+ (1,0) [0|15] "NoUnit" PDCS_FD1,GW_FD1,PDCS_HVM_FD1
 SG_ BDCS11_ELV1Pos : 88|1@0+ (1,0) [0|1] "NoUnit" Vector__XXX
 SG_ BDCS11_ELV1Flt : 89|1@0+ (1,0) [0|1] "NoUnit" Vector__XXX
 SG_ BDCS11_ELV2Pos : 90|1@0+ (1,0) [0|1] "NoUnit" Vector__XXX
 SG_ BDCS11_ELV2Flt : 91|1@0+ (1,0) [0|1] "NoUnit" Vector__XXX
 SG_ BDCS11_ELV3Pos : 92|1@0+ (1,0) [0|1] "NoUnit" Vector__XXX
 SG_ BDCS11_ELV3Flt : 93|1@0+ (1,0) [0|1] "NoUnit" Vector__XXX
 SG_ BDCS11_ELV4Pos : 94|1@0+ (1,0) [0|1] "NoUnit" Vector__XXX
 SG_ BDCS11_ELV4Flt : 95|1@0+ (1,0) [0|1] "NoUnit" Vector__XXX
 SG_ BDCS11_ComLost_EXV1 : 96|1@0+ (1,0) [0|1] "NoUnit" Vector__XXX
 SG_ BDCS11_ComLost_EXV_H : 97|1@0+ (1,0) [0|1] "NoUnit" Vector__XXX
 SG_ BDCS11_EXV1Flt : 99|1@0+ (1,0) [0|1] "NoUnit" Vector__XXX
 SG_ BDCS11_EXV_H_Flt : 100|1@0+ (1,0) [0|1] "NoUnit" Vector__XXX
 SG_ BDCS11_BlowrRlySts : 101|1@0+ (1,0) [0|1] "NoUnit" Vector__XXX
 SG_ BDCS11_HeatingWireSts : 102|1@0+ (1,0) [0|1] "NoUnit" Vector__XXX
 SG_ BDCS11_EXV1EnableReq : 106|1@0+ (1,0) [0|1] "NoUnit" Vector__XXX
 SG_ BDCS11_EXV1CalibReq : 107|1@0+ (1,0) [0|1] "NoUnit" Vector__XXX
 SG_ BDCS11_HPVTMSModeSts : 111|4@0+ (1,0) [0|15] "NoUnit" Vector__XXX
 SG_ BDCS11_EXV1ValCmd : 105|10@0+ (1,0) [0|500] "NoUnit" Vector__XXX
 SG_ BDCS11_EXV_H_ValCmd : 121|10@0+ (1,0) [0|500] "NoUnit" Vector__XXX
 SG_ BDCS11_UBlowrSpdReq : 143|8@0+ (0.1,0) [0|14] "V" Vector__XXX
 SG_ BDCS11_UBlowrSpdAct : 151|8@0+ (0.1,0) [0|14] "V" Vector__XXX
 SG_ BDCS11_EXV1ActVal : 153|10@0+ (1,0) [0|500] "NoUnit" Vector__XXX
 SG_ BDCS11_OilHeatingSwEnable : 170|1@0+ (1,0) [0|1] "NoUnit" GW_FD4,CDCS_OverSea
 SG_ BDCS11_OilHeatingFuelLevel : 173|3@0+ (1,0) [0|7] "NoUnit" GW_FD4,CDCS_OverSea
 SG_ BDCS11_EXV_H_ActVal : 169|10@0+ (1,0) [0|500] "NoUnit" Vector__XXX
 SG_ BDCS11_OilHeatingWarn : 186|3@0+ (1,0) [0|7] "NoUnit" GW_FD5,GW_FD4,CDCS_OverSea,TBOX_OverSea
 SG_ BDCS11_OilHeatingWorkSts : 190|2@0+ (1,0) [0|3] "NoUnit" GW_FD4,CDCS_OverSea
 SG_ BDCS11_OilHeatingSwSts : 191|1@0+ (1,0) [0|1] "NoUnit" GW_FD5,GW_FD4,CDCS_OverSea,TBOX_OverSea
 SG_ BDCS11_TWV1ActSaveReq : 193|2@0+ (1,0) [0|3] "NoUnit" Vector__XXX
 SG_ BDCS11_TWV1CalibReq : 195|2@0+ (1,0) [0|3] "NoUnit" Vector__XXX
 SG_ BDCS11_TWV1ModeSts : 199|4@0+ (1,0) [0|15] "NoUnit" Vector__XXX
 SG_ BDCS11_TWV1ValCmd : 207|8@0+ (1,0) [0|100] "NoUnit" Vector__XXX
 SG_ BDCS11_TWV1ActVal : 215|8@0+ (1,0) [0|100] "NoUnit" Vector__XXX
 SG_ BDCS11_CLMSwVersS : 223|8@0+ (1,0) [0|255] "NoUnit" Vector__XXX
 SG_ BDCS11_CLMSwVersM : 231|8@0+ (1,0) [0|255] "NoUnit" Vector__XXX
 SG_ BDCS11_PumpHActSpd : 239|8@0+ (1,0) [0|100] "%" Vector__XXX
 SG_ BDCS11_EXV1InitSts : 241|2@0+ (1,0) [0|3] "NoUnit" Vector__XXX
 SG_ BDCS11_EXV_H_InitSts : 243|2@0+ (1,0) [0|3] "NoUnit" Vector__XXX
 SG_ BDCS11_NVMSts : 245|2@0+ (1,0) [0|3] "NoUnit" Vector__XXX
 SG_ BDCS11_ComLost_TWV1 : 246|1@0+ (1,0) [0|1] "NoUnit" Vector__XXX
 SG_ BDCS11_TWV1Flt : 247|1@0+ (1,0) [0|1] "NoUnit" Vector__XXX

BO_ 664 BDCS_Fr12_298: 64 BDCS
 SG_ BDCS12_InsideTemp : 7|8@0+ (0.5,-50) [-50|75] "℃" TBOX,GW_FD5,GW_FD4,BAM,CDCS,CDCS_OverSea,TBOX_OverSea
 SG_ BDCS12_InsideTempValid : 8|1@0+ (1,0) [0|1] "NoUnit" TBOX,GW_FD5,GW_FD4,BAM,CDCS,CDCS_OverSea,TBOX_OverSea
 SG_ BDCS12_OutletTempValid : 9|1@0+ (1,0) [0|1] "NoUnit" PDCS_FD1,TBOX,GW_FD5,GW_FD1,PDCS_HVM_FD1,TBOX_OverSea
 SG_ BDCS12_UncoolReason : 12|3@0+ (1,0) [0|7] "NoUnit" TBOX,GW_FD5,TBOX_OverSea
 SG_ BDCS12_UnheatReason : 15|3@0+ (1,0) [0|7] "NoUnit" TBOX,GW_FD5,TBOX_OverSea
 SG_ BDCS12_OutletTemp : 23|8@0+ (0.5,-50) [-50|75] "" PDCS_FD1,TBOX,GW_FD5,GW_FD1,PDCS_HVM_FD1,TBOX_OverSea
 SG_ BDCS12_SensorFailCode : 27|4@0+ (1,0) [0|15] "NoUnit" TBOX,GW_FD5,TBOX_OverSea
 SG_ BDCS12_ThermalSts : 31|4@0+ (1,0) [0|15] "NoUnit" PDCS_FD1,TBOX,GW_FD5,ICU_E02,GW_FD4,GW_FD1,ICU,CDCS,PDCS_HVM_FD1,CDCS_OverSea,TBOX_OverSea
 SG_ BDCS12_DisplayInfo : 36|5@0+ (1,0) [0|31] "NoUnit" TBOX,GW_FD5,ICU_E02,GW_FD4,ICU,CDCS,CDCS_OverSea,TBOX_OverSea
 SG_ BDCS12_EVAPTempValid : 37|1@0+ (1,0) [0|1] "NoUnit" TBOX,GW_FD5,TBOX_OverSea
 SG_ BDCS12_InCarClimateSystemFault : 38|1@0+ (1,0) [0|1] "NoUnit" TBOX,GW_FD5,ICU_E02,GW_FD4,ICU,CDCS,CDCS_OverSea,TBOX_OverSea
 SG_ BDCS12_BatteryThermalSystemFault : 39|1@0+ (1,0) [0|1] "NoUnit" TBOX,GW_FD5,ICU_E02,BMS,GW_FD4,GW_FD1,ICU,CDCS,PDCS_HVM_FD1,CDCS_OverSea,TBOX_OverSea
 SG_ BDCS12_EVAPTemp : 47|8@0+ (0.5,-50) [-50|75] "" TBOX,GW_FD5,TBOX_OverSea
 SG_ BDCS12_AC_PTC_PowerLimit : 55|8@0+ (0.1,0) [0|25.3] "Kw" PDCS_FD1,TBOX,GW_FD5,GW_FD1,PDCS_HVM_FD1,TBOX_OverSea
 SG_ BDCS12_AC_PTC_PowerSet : 63|8@0+ (0.1,0) [0|25.3] "Kw" PDCS_FD1,TBOX,GW_FD5,GW_FD1,PDCS_HVM_FD1,TBOX_OverSea
 SG_ BDCS12_LFaceOutletTemp : 71|8@0+ (0.5,-50) [-50|75] "" TBOX,GW_FD5,TBOX_OverSea
 SG_ BDCS12_LFootOutletTemp : 79|8@0+ (0.5,-50) [-50|75] "" TBOX,GW_FD5,TBOX_OverSea
 SG_ BDCS12_RFaceOutletTemp : 87|8@0+ (0.5,-50) [-50|75] "" TBOX,GW_FD5,TBOX_OverSea
 SG_ BDCS12_RFootOutletTemp : 95|8@0+ (0.5,-50) [-50|75] "" TBOX,GW_FD5,TBOX_OverSea
 SG_ BDCS12_FragranceType_Position_1 : 99|4@0+ (1,0) [0|15] "NoUnit" TBOX,GW_FD5,GW_FD4,CDCS,CDCS_OverSea,TBOX_OverSea
 SG_ BDCS12_FragranceType_Position_2 : 103|4@0+ (1,0) [0|15] "NoUnit" TBOX,GW_FD5,GW_FD4,CDCS,CDCS_OverSea,TBOX_OverSea
 SG_ BDCS12_FragranceType_Position_3 : 107|4@0+ (1,0) [0|15] "NoUnit" TBOX,GW_FD5,GW_FD4,CDCS,CDCS_OverSea,TBOX_OverSea
 SG_ BDCS12_FM_FragrancePositionSts : 111|4@0+ (1,0) [0|15] "NoUnit" TBOX,GW_FD5,GW_FD4,CDCS,CDCS_OverSea,TBOX_OverSea
 SG_ BDCS12_FM_FragranceWorkingSts : 112|1@0+ (1,0) [0|1] "NoUnit" TBOX,GW_FD5,GW_FD4,CDCS,CDCS_OverSea,TBOX_OverSea
 SG_ BDCS12_FM_FragranceConcentration : 114|2@0+ (1,0) [0|3] "NoUnit" TBOX,GW_FD5,GW_FD4,CDCS,CDCS_OverSea,TBOX_OverSea
 SG_ BDCS12_LEAOSts : 117|3@0+ (1,0) [0|4] "NoUnit" GW_FD4,CDCS,CDCS_OverSea
 SG_ BDCS12_AQSCycleSts : 119|2@0+ (1,0) [0|3] "NoUnit" Vector__XXX
 SG_ BDCS12_AQSValue : 122|3@0+ (1,0) [0|7] "NoUnit" GW_FD4,CDCS,CDCS_OverSea
 SG_ BDCS12_FragranceFaultSts : 123|1@0+ (1,0) [0|1] "NoUnit" Vector__XXX
 SG_ BDCS12_PM25FltSta : 125|2@0+ (1,0) [0|3] "NoUnit" Vector__XXX
 SG_ BDCS12_SolarError : 126|1@0+ (1,0) [0|1] "NoUnit" PDCS_FD1,GW_FD1,PDCS_HVM_FD1
 SG_ BDCS12_HumidTemp_Error : 127|1@0+ (1,0) [0|1] "NoUnit" Vector__XXX
 SG_ BDCS12_LeSunshineSnsrT : 135|8@0+ (4,0) [0|1000] "w/m2" Vector__XXX
 SG_ BDCS12_RiSunshineSnsrT : 143|8@0+ (4,0) [0|1000] "w/m2" Vector__XXX
 SG_ BDCS12_Humid : 151|8@0+ (0.5,0) [0|100] "%" GW_FD4,CDCS,CDCS_OverSea
 SG_ BDCS12_DefTemperature : 159|8@0+ (0.5,-40) [-40|87] "" Vector__XXX
 SG_ BDCS12_REAOSts : 165|3@0+ (1,0) [0|7] "NoUnit" GW_FD4,CDCS,CDCS_OverSea
 SG_ BDCS12_EAOCtrlVaild : 166|1@0+ (1,0) [0|1] "NoUnit" GW_FD4,CDCS,CDCS_OverSea
 SG_ BDCS12_CoolantFillingSta : 167|1@0+ (1,0) [0|1] "NoUnit" GW_FD4,CDCS,CDCS_OverSea
 SG_ BDCS12_TempDewPoint : 162|11@0+ (0.1,-39.6) [-39.6|60.4] "" Vector__XXX
 SG_ BDCS12_LPTSnsrP : 183|7@0+ (0.01,0) [0|1.1] "Mpa" Vector__XXX
 SG_ BDCS12_HPSnsrP : 176|9@0+ (0.01,0) [0|3.6] "Mpa" PDCS_FD1,GW_FD1,PDCS_HVM_FD1
 SG_ BDCS12_EvprTempTar : 199|7@0+ (0.5,-10) [-10|40] "℃" Vector__XXX
 SG_ BDCS12_LPTSnsrT : 192|9@0+ (0.5,-40) [-40|150] "" Vector__XXX
 SG_ BDCS12_FL_RLMotorPos : 215|8@0+ (1,0) [0|135] "NoUnit" GW_FD4,CDCS,CDCS_OverSea
 SG_ BDCS12_FL_UDMotorPos : 223|8@0+ (1,0) [0|90] "NoUnit" GW_FD4,CDCS,CDCS_OverSea
 SG_ BDCS12_CL_RLMotorPos : 231|8@0+ (1,0) [0|135] "NoUnit" GW_FD4,CDCS,CDCS_OverSea
 SG_ BDCS12_CL_UDMotorPos : 239|8@0+ (1,0) [0|90] "NoUnit" GW_FD4,CDCS,CDCS_OverSea
 SG_ BDCS12_CR_RLMotorPos : 247|8@0+ (1,0) [0|135] "NoUnit" GW_FD4,CDCS,CDCS_OverSea
 SG_ BDCS12_CR_UDMotorPos : 255|8@0+ (1,0) [0|90] "NoUnit" GW_FD4,CDCS,CDCS_OverSea
 SG_ BDCS12_FR_RLMotorPos : 263|8@0+ (1,0) [0|135] "NoUnit" GW_FD4,CDCS,CDCS_OverSea
 SG_ BDCS12_FR_UDMotorPos : 271|8@0+ (1,0) [0|90] "NoUnit" GW_FD4,CDCS,CDCS_OverSea
 SG_ BDCS12_LeftExtFanSpdCmd : 294|7@0+ (1,0) [0|100] "%" PDCS_FD1,GW_FD1,PDCS_HVM_FD1
 SG_ BDCS12_HPSnsrT : 287|9@0+ (0.5,-40) [-40|150] "℃" Vector__XXX
 SG_ BDCS12_RightExtFanSpdCmd : 302|7@0+ (1,0) [0|100] "%" PDCS_FD1,GW_FD1,PDCS_HVM_FD1
 SG_ BDCS12_PumpHFlt : 306|1@0+ (1,0) [0|1] "NoUnit" Vector__XXX
 SG_ BDCS12_LFaceOutletTempFlt : 307|1@0+ (1,0) [0|1] "NoUnit" Vector__XXX
 SG_ BDCS12_LFootOutletTempFlt : 308|1@0+ (1,0) [0|1] "NoUnit" Vector__XXX
 SG_ BDCS12_RFaceOutletTempFlt : 309|1@0+ (1,0) [0|1] "NoUnit" Vector__XXX
 SG_ BDCS12_RFootOutletTempFlt : 310|1@0+ (1,0) [0|1] "NoUnit" Vector__XXX
 SG_ BDCS12_WindSpdAutSts : 319|1@0+ (1,0) [0|1] "NoUnit" Vector__XXX
 SG_ BDCS12_BlowModAutSts : 327|1@0+ (1,0) [0|1] "NoUnit" Vector__XXX
 SG_ BDCS12_LPTSnsrPEvpr : 335|7@0+ (0.01,0) [0|1.1] "Mpa" Vector__XXX
 SG_ BDCS12_LPTSnsrTEvpr : 328|9@0+ (0.5,-40) [-40|150] "℃" Vector__XXX
 SG_ BDCS12_IHE_OutTemp : 351|8@0+ (1,-40) [-40|120] "" Vector__XXX
 SG_ BDCS12_OHE_OutTemp : 359|8@0+ (1,-40) [-40|120] "" Vector__XXX
 SG_ BDCS12_WCC_OutTemp : 367|8@0+ (1,-40) [-40|120] "" Vector__XXX
 SG_ BDCS12_Chiller_OutTemp : 375|8@0+ (1,-40) [-40|120] "" Vector__XXX
 SG_ BDCS12_IHE_OutTempFlt : 376|1@0+ (1,0) [0|1] "NoUnit" Vector__XXX
 SG_ BDCS12_OHE_OutTempFlt : 377|1@0+ (1,0) [0|1] "NoUnit" Vector__XXX
 SG_ BDCS12_WCC_OutTempFlt : 378|1@0+ (1,0) [0|1] "NoUnit" Vector__XXX
 SG_ BDCS12_Chiller_OutTempFlt : 379|1@0+ (1,0) [0|1] "NoUnit" Vector__XXX
 SG_ BDCS12_LeMixThrCmd : 390|7@0+ (1,0) [0|100] "%" Vector__XXX
 SG_ BDCS12_LeHybThrMotFlt : 391|1@0+ (1,0) [0|1] "NoUnit" Vector__XXX
 SG_ BDCS12_RiMixThrCmd : 398|7@0+ (1,0) [0|100] "%" Vector__XXX
 SG_ BDCS12_RiHybThrMotFlt : 399|1@0+ (1,0) [0|1] "NoUnit" Vector__XXX
 SG_ BDCS12_CycleThrCmd : 406|7@0+ (1,0) [0|100] "%" Vector__XXX
 SG_ BDCS12_CycleMotFlt : 407|1@0+ (1,0) [0|1] "NoUnit" Vector__XXX
 SG_ BDCS12_ModThrCmd : 414|7@0+ (1,0) [0|100] "%" Vector__XXX
 SG_ BDCS12_ModThrMotFlt : 415|1@0+ (1,0) [0|1] "NoUnit" Vector__XXX
 SG_ BDCS12_BSOFverBSW : 423|32@0+ (1,0) [0|4.294967295E9] "NoUnit" Vector__XXX
 SG_ BDCS12_VerTMSApp : 455|16@0+ (1,0) [0|65535] "NoUnit" Vector__XXX
 SG_ BDCS12_VerTMSCal : 471|16@0+ (1,0) [0|65535] "NoUnit" Vector__XXX
 SG_ BDCS12_TMSFltRollgNum : 487|16@0+ (1,0) [0|65535] "NoUnit" Vector__XXX
 SG_ BDCS12_TMSFltRollgNumHistory : 503|16@0+ (1,0) [0|65535] "NoUnit" Vector__XXX

BO_ 670 BDCS_Fr10_29E: 8 BDCS
 SG_ BDCS10_AC_ACSts : 0|1@0+ (1,0) [0|1] "NoUnit" TBOX,GW_FD5,GW_FD4,CDCS,CDCS_OverSea,TBOX_OverSea
 SG_ BDCS10_AC_CycleSts : 3|2@0+ (1,0) [0|3] "NoUnit" PDCS_FD1,TBOX,GW_FD5,GW_FD4,GW_FD1,CDCS,PDCS_HVM_FD1,CDCS_OverSea,TBOX_OverSea
 SG_ BDCS10_AC_BlowerSpdSts : 7|4@0+ (1,0) [0|15] "NoUnit" PDCS_FD1,TBOX,GW_FD5,GW_FD4,GW_FD1,CDCS,PDCS_HVM_FD1,CDCS_OverSea,TBOX_OverSea
 SG_ BDCS10_AC_OnOffSts : 8|1@0+ (1,0) [0|1] "NoUnit" PDCS_FD1,TBOX,GW_FD5,GW_FD4,GW_FD1,CDCS,PDCS_HVM_FD1,CDCS_OverSea,TBOX_OverSea
 SG_ BDCS10_AC_VentSts : 9|1@0+ (1,0) [0|1] "NoUnit" TBOX,GW_FD5,GW_FD4,CDCS,CDCS_OverSea,TBOX_OverSea
 SG_ BDCS10_AC_VentilationSts : 10|1@0+ (1,0) [0|1] "NoUnit" GW_FD4,CDCS,CDCS_OverSea
 SG_ BDCS10_AC_WindowSts : 22|1@0+ (1,0) [0|1] "NoUnit" PDCS_FD1,TBOX,GW_FD5,GW_FD4,GW_FD1,CDCS,PDCS_HVM_FD1,CDCS_OverSea,TBOX_OverSea
 SG_ BDCS10_AC_AnionSts : 23|1@0+ (1,0) [0|1] "NoUnit" TBOX,GW_FD5,GW_FD4,CDCS,CDCS_OverSea,TBOX_OverSea
 SG_ BDCS10_AC_OutsideTempValid : 33|1@0+ (1,0) [0|1] "NoUnit" PDCS_FD1,PDCU,IDB,ESC_FD3,ADCU_FD3,BMS,EMS,EHB_FD3,DDCU,CDCS,ADCS_FD3,CDCS_OverSea,TBOX,GW_FD5,ICU_E02,GW_FD3,GW_FD4,GW_FD1,ICU,PDCS_HVM_FD1,TBOX_OverSea
 SG_ BDCS10_AC_AutoSts : 34|1@0+ (1,0) [0|1] "NoUnit" TBOX,GW_FD5,GW_FD4,CDCS,CDCS_OverSea,TBOX_OverSea
 SG_ BDCS10_AC_FootSts : 35|1@0+ (1,0) [0|1] "NoUnit" TBOX,GW_FD5,GW_FD4,CDCS,CDCS_OverSea,TBOX_OverSea
 SG_ BDCS10_AC_DualSw : 36|1@0+ (1,0) [0|1] "NoUnit" TBOX,GW_FD5,GW_FD4,CDCS,CDCS_OverSea,TBOX_OverSea
 SG_ BDCS10_AC_PM25_ValueValid : 37|1@0+ (1,0) [0|1] "NoUnit" PDCS_FD1,TBOX,GW_FD5,GW_FD4,GW_FD1,CDCS,PDCS_HVM_FD1,CDCS_OverSea,TBOX_OverSea
 SG_ BDCS10_AC_PM25_Value : 31|10@0+ (1,0) [0|999] "NoUnit" PDCS_FD1,TBOX,GW_FD5,GW_FD4,GW_FD1,CDCS,PDCS_HVM_FD1,CDCS_OverSea,TBOX_OverSea
 SG_ BDCS10_AC_OutsideTemp : 47|8@0+ (0.5,-50) [-50|75] "" PDCS_FD1,PDCU,IDB,ESC_FD3,ADCU_FD3,BMS,EMS,EHB_FD3,DDCU,CDCS,ADCS_FD3,CDCS_OverSea,TBOX,GW_FD5,ICU_E02,GW_FD3,GW_FD4,GW_FD1,ICU,PDCS_HVM_FD1,TBOX_OverSea
 SG_ BDCS10_AC_LHTemp : 55|8@0+ (1,0) [0|255] "" TBOX,GW_FD5,GW_FD4,CDCS,CDCS_OverSea,TBOX_OverSea
 SG_ BDCS10_AC_RHTemp : 63|8@0+ (1,0) [0|255] "" TBOX,GW_FD5,ICU_E02,GW_FD4,ICU,CDCS,CDCS_OverSea,TBOX_OverSea

BO_ 677 BDCS_Fr08_2A5: 16 BDCS
 SG_ BDCS8_FL_Pos_ManualAdjust_Sts : 0|1@0+ (1,0) [0|1] "NoUnit" GW_FD4,CDCS,CDCS_OverSea
 SG_ BDCS8_DriverSeatHorizontalPos : 7|7@0+ (1,0) [0|100] "%" GW_FD4,CDCS,CDCS_OverSea
 SG_ BDCS8_DriverSeatVerticalHeight : 14|7@0+ (1,0) [0|100] "%" GW_FD4,CDCS,CDCS_OverSea
 SG_ BDCS8_FR_Pos_ManualAdjust_Sts : 15|1@0+ (1,0) [0|1] "NoUnit" GW_FD4,CDCS,CDCS_OverSea
 SG_ BDCS8_DriverCushionTiltPos : 22|7@0+ (1,0) [0|100] "%" GW_FD4,CDCS,CDCS_OverSea
 SG_ BDCS8_FR_SeatEasygetON_OFF_Sts : 23|1@0+ (1,0) [0|1] "NoUnit" GW_FD4,CDCS,CDCS_OverSea
 SG_ BDCS8_Drive_ODS : 24|1@0+ (1,0) [0|1] "NoUnit" PDCS_FD1,TBOX,GW_FD5,ICU_E02,GW_FD4,GW_FD1,ICU,CDCS,PDCS_HVM_FD1,CDCS_OverSea,TBOX_OverSea
 SG_ BDCS8_FR_SeatPosMemory_Sts : 28|2@0+ (1,0) [0|3] "NoUnit" GW_FD4,CDCS,CDCS_OverSea
 SG_ BDCS8_FR_SeatPosLoad_Sts : 30|2@0+ (1,0) [0|3] "NoUnit" GW_FD4,CDCS,CDCS_OverSea
 SG_ BDCS8_FL_SeatEasygetON_OFF_Sts : 31|1@0+ (1,0) [0|1] "NoUnit" GW_FD4,CDCS,CDCS_OverSea
 SG_ BDCS8_FL_SeatPosLoad_Sts : 33|2@0+ (1,0) [0|3] "NoUnit" GW_FD4,CDCS,CDCS_OverSea
 SG_ BDCS8_FL_SeatPosMemory_Sts : 35|2@0+ (1,0) [0|3] "NoUnit" GW_FD4,CDCS,CDCS_OverSea
 SG_ BDCS8_Driver_Heating_Sts : 37|2@0+ (1,0) [0|3] "NoUnit" TBOX,GW_FD5,GW_FD4,BAM,CDCS,CDCS_OverSea,TBOX_OverSea
 SG_ BDCS8_Passenger_Heating_Sts : 39|2@0+ (1,0) [0|3] "NoUnit" TBOX,GW_FD5,GW_FD4,BAM,CDCS,CDCS_OverSea,TBOX_OverSea
 SG_ BDCS8_Driver_Venting_Sts : 41|2@0+ (1,0) [0|3] "NoUnit" TBOX,GW_FD5,GW_FD4,BAM,CDCS,CDCS_OverSea,TBOX_OverSea
 SG_ BDCS8_Passenger_Venting_Sts : 43|2@0+ (1,0) [0|3] "NoUnit" TBOX,GW_FD5,GW_FD4,BAM,CDCS,CDCS_OverSea,TBOX_OverSea
 SG_ BDCS8_Driver_LHFailure : 44|1@0+ (1,0) [0|1] "NoUnit" TBOX,GW_FD5,GW_FD4,BAM,CDCS,CDCS_OverSea,TBOX_OverSea
 SG_ BDCS8_Passenger_RHFailure : 45|1@0+ (1,0) [0|1] "NoUnit" TBOX,GW_FD5,GW_FD4,BAM,CDCS,CDCS_OverSea,TBOX_OverSea
 SG_ BDCS8_Driver_LVFailure : 46|1@0+ (1,0) [0|1] "NoUnit" TBOX,GW_FD5,GW_FD4,BAM,CDCS,CDCS_OverSea,TBOX_OverSea
 SG_ BDCS8_Passenger_RVFailure : 47|1@0+ (1,0) [0|1] "NoUnit" TBOX,GW_FD5,GW_FD4,BAM,CDCS,CDCS_OverSea,TBOX_OverSea
 SG_ BDCS8_Driver_BackrestAngle : 70|7@0+ (1,0) [0|100] "%" GW_FD4,CDCS,CDCS_OverSea
 SG_ BDCS8_Passenger_SeatHorizontalPos : 78|7@0+ (1,0) [0|100] "%" GW_FD4,CDCS,CDCS_OverSea
 SG_ BDCS8_Passenger_SeatVerticalHeight : 86|7@0+ (1,0) [0|100] "%" GW_FD4,CDCS,CDCS_OverSea
 SG_ BDCS8_Passenger_BackrestAngle : 94|7@0+ (1,0) [0|100] "%" GW_FD4,CDCS,CDCS_OverSea
 SG_ BDCS8_Passenger_LegsupporPos : 102|7@0+ (1,0) [0|100] "%" GW_FD4,CDCS,CDCS_OverSea
 SG_ BDCS8_Driver_MassageModeSts : 106|3@0+ (1,0) [0|7] "NoUnit" GW_FD4,CDCS,CDCS_OverSea
 SG_ BDCS8_Driver_MassageLevelSts : 109|3@0+ (1,0) [0|7] "NoUnit" GW_FD4,CDCS,CDCS_OverSea
 SG_ BDCS8_Passenger_MassageModeSts : 114|3@0+ (1,0) [0|7] "NoUnit" GW_FD4,CDCS,CDCS_OverSea
 SG_ BDCS8_Passenger_MassageLevelSts : 117|3@0+ (1,0) [0|7] "NoUnit" GW_FD4,CDCS,CDCS_OverSea
 SG_ BDCS8_Driver_Massage_Sts : 122|3@0+ (1,0) [0|7] "NoUnit" GW_FD4,CDCS,CDCS_OverSea
 SG_ BDCS8_Passenger_MassageSts : 125|3@0+ (1,0) [0|7] "NoUnit" GW_FD4,CDCS,CDCS_OverSea

BO_ 678 BDCS_Fr09_2A6: 8 BDCS
 SG_ BDCS9_RL_Heating_Sts : 1|2@0+ (1,0) [0|3] "NoUnit" TBOX,GW_FD5,GW_FD4,BAM,CDCS,CDCS_OverSea,TBOX_OverSea
 SG_ BDCS9_RR_Heating_Sts : 3|2@0+ (1,0) [0|3] "NoUnit" TBOX,GW_FD5,GW_FD4,BAM,CDCS,CDCS_OverSea,TBOX_OverSea
 SG_ BDCS9_RL_Venting_Sts : 5|2@0+ (1,0) [0|3] "NoUnit" TBOX,GW_FD5,GW_FD4,BAM,CDCS,CDCS_OverSea,TBOX_OverSea
 SG_ BDCS9_RR_Venting_Sts : 7|2@0+ (1,0) [0|3] "NoUnit" TBOX,GW_FD5,GW_FD4,BAM,CDCS,CDCS_OverSea,TBOX_OverSea
 SG_ BDCS9_RLVentilating_Failure : 8|1@0+ (1,0) [0|1] "NoUnit" TBOX,GW_FD5,GW_FD4,BAM,CDCS,CDCS_OverSea,TBOX_OverSea
 SG_ BDCS9_RRVentilating_Failure : 9|1@0+ (1,0) [0|1] "NoUnit" TBOX,GW_FD5,GW_FD4,BAM,CDCS,CDCS_OverSea,TBOX_OverSea
 SG_ BDCS9_RLBackAngleRelay_Failure : 10|1@0+ (1,0) [0|1] "NoUnit" TBOX,GW_FD5,GW_FD4,BAM,CDCS,CDCS_OverSea,TBOX_OverSea
 SG_ BDCS9_RRBackAngleRelay_Failure : 11|1@0+ (1,0) [0|1] "NoUnit" TBOX,GW_FD5,GW_FD4,BAM,CDCS,CDCS_OverSea,TBOX_OverSea
 SG_ BDCS9_FR_ZeroGravity_Sts : 14|3@0+ (1,0) [0|7] "NoUnit" GW_FD4,CDCS,CDCS_OverSea
 SG_ BDCS9_RL_MassageLevel_Fdb : 17|2@0+ (1,0) [0|3] "NoUnit" GW_FD4,CDCS,CDCS_OverSea
 SG_ BDCS9_RL_LumbarActionSts_Fdb : 20|3@0+ (1,0) [0|7] "NoUnit" GW_FD4,CDCS,CDCS_OverSea
 SG_ BDCS9_RL_MassageMode_Fdb : 23|3@0+ (1,0) [0|7] "NoUnit" GW_FD4,CDCS,CDCS_OverSea
 SG_ BDCS9_RR_MassageLevel_Fdb : 25|2@0+ (1,0) [0|3] "NoUnit" GW_FD4,CDCS,CDCS_OverSea
 SG_ BDCS9_RR_LumbarActionSts_Fdb : 28|3@0+ (1,0) [0|7] "NoUnit" GW_FD4,CDCS,CDCS_OverSea
 SG_ BDCS9_RR_MassageMode_Fdb : 31|3@0+ (1,0) [0|7] "NoUnit" GW_FD4,CDCS,CDCS_OverSea
 SG_ BDCS9_FridgeHeat_TempSts : 36|5@0+ (1,0) [0|31] "" TBOX,GW_FD5,GW_FD4,CDCS,CDCS_OverSea,TBOX_OverSea
 SG_ BDCS9_FridgeMod_Sts : 38|2@0+ (1,0) [0|3] "" TBOX,GW_FD5,GW_FD4,CDCS,CDCS_OverSea,TBOX_OverSea
 SG_ BDCS9_FridgeTemp_KeepSts : 39|1@0+ (1,0) [0|1] "" TBOX,GW_FD5,GW_FD4,CDCS,CDCS_OverSea,TBOX_OverSea
 SG_ BDCS9_FridgeCool_TempSts : 43|4@0+ (1,0) [0|15] "" TBOX,GW_FD5,GW_FD4,CDCS,CDCS_OverSea,TBOX_OverSea
 SG_ BDCS9_RC_FridgeDoorSts : 45|2@0+ (1,0) [0|3] "" TBOX,GW_FD5,GW_FD4,CDCS,CDCS_OverSea,TBOX_OverSea
 SG_ BDCS9_RC_FridgeErSts : 47|2@0+ (1,0) [0|3] "" TBOX,GW_FD5,GW_FD4,CDCS,CDCS_OverSea,TBOX_OverSea
 SG_ BDCS9_RmtFridgeReqFailCondition : 49|2@0+ (1,0) [0|3] "" TBOX,GW_FD5,TBOX_OverSea
 SG_ BDCS9_RL_Heating_Failure : 54|1@0+ (1,0) [0|1] "" Vector__XXX
 SG_ BDCS9_RR_Heating_Failure : 55|1@0+ (1,0) [0|1] "" Vector__XXX
 SG_ BDCS9_Passenger_LegsupporLength : 63|8@0+ (1,0) [0|100] "%" GW_FD4,CDCS,CDCS_OverSea

BO_ 680 BDCS_Fr17_SubCAN_2A8: 16 BDCS
 SG_ PTC1_ClntOtltOverTemProtn : 0|1@0+ (1,0) [0|1] "" TBOX,GW_FD5,TBOX_OverSea
 SG_ PTC1_VbatVtgUnstable : 1|1@0+ (1,0) [0|1] "" TBOX,GW_FD5,TBOX_OverSea
 SG_ PTC1_VbatVtgSnsrFlt : 2|1@0+ (1,0) [0|1] "" TBOX,GW_FD5,TBOX_OverSea
 SG_ PTC1_PCBTempSnsrFlt : 3|1@0+ (1,0) [0|1] "" TBOX,GW_FD5,TBOX_OverSea
 SG_ PTC1_HiCrntSnsrFlt : 4|1@0+ (1,0) [0|1] "" TBOX,GW_FD5,TBOX_OverSea
 SG_ PTC1_PCBOverTempProtn : 5|1@0+ (1,0) [0|1] "" TBOX,GW_FD5,TBOX_OverSea
 SG_ PTC1_WrkngSts : 7|2@0+ (1,0) [0|3] "" PDCS_FD1,TBOX,GW_FD5,BMS,GW_FD1,PDCS_HVM_FD1,TBOX_OverSea
 SG_ PTC1_CoreOrIGBTOpenErr : 8|1@0+ (1,0) [0|1] "" TBOX,GW_FD5,TBOX_OverSea
 SG_ PTC1_IGBTShrtErr : 9|1@0+ (1,0) [0|1] "" TBOX,GW_FD5,TBOX_OverSea
 SG_ PTC1_HVOverCrntProtn : 11|1@0+ (1,0) [0|1] "" TBOX,GW_FD5,TBOX_OverSea
 SG_ PTC1_VbatVtgProtn : 12|1@0+ (1,0) [0|1] "" TBOX,GW_FD5,TBOX_OverSea
 SG_ PTC1_HVDisconnectProtn : 13|1@0+ (1,0) [0|1] "" TBOX,GW_FD5,TBOX_OverSea
 SG_ PTC1_IGBTOverTemProtn : 14|1@0+ (1,0) [0|1] "" TBOX,GW_FD5,TBOX_OverSea
 SG_ PTC1_ClntInltOverTemProtn : 15|1@0+ (1,0) [0|1] "" TBOX,GW_FD5,TBOX_OverSea
 SG_ PTC1_MmryFlt : 19|1@0+ (1,0) [0|1] "" TBOX,GW_FD5,TBOX_OverSea
 SG_ PTC1_IGBTTemSnsrFlt : 20|1@0+ (1,0) [0|1] "" TBOX,GW_FD5,TBOX_OverSea
 SG_ PTC1_ClntInltTemSnsrFlt : 21|1@0+ (1,0) [0|1] "" TBOX,GW_FD5,TBOX_OverSea
 SG_ PTC1_ClntOtltTemSnsrFlt : 22|1@0+ (1,0) [0|1] "" TBOX,GW_FD5,TBOX_OverSea
 SG_ PTC1_CommError : 23|1@0+ (1,0) [0|1] "" TBOX,GW_FD5,TBOX_OverSea
 SG_ PTC1_PowerConsumption : 31|8@0+ (0.1,0) [0|25.3] "kw" PDCS_FD1,TBOX,GW_FD5,BMS,GW_FD1,PDCS_HVM_FD1,TBOX_OverSea
 SG_ PTC1_ActuHiCrnt : 39|8@0+ (0.25,0) [0|63.25] "A" TBOX,GW_FD5,BMS,GW_FD1,TBOX_OverSea
 SG_ PTC1_ClntTempInlt : 47|8@0+ (1,-40) [-40|100] "℃" PDCS_FD1,TBOX,GW_FD5,BMS,GW_FD1,PDCS_HVM_FD1,TBOX_OverSea
 SG_ PTC1_ClntTempOtlt : 55|8@0+ (1,-40) [-40|100] "℃" PDCS_FD1,TBOX,GW_FD5,BMS,GW_FD1,PDCS_HVM_FD1,TBOX_OverSea
 SG_ PTC1_IGBTTem : 63|8@0+ (1,-40) [-40|213] "℃" TBOX,GW_FD5,TBOX_OverSea
 SG_ EACP1_OPState : 65|1@0+ (1,0) [0|1] "" Vector__XXX
 SG_ EACP1_OutputPwr : 71|6@0+ (0.1,0) [0|6.2] "Kw" PDCS_FD1,TBOX,GW_FD5,BMS,GW_FD1,PDCS_HVM_FD1,TBOX_OverSea
 SG_ EACP1_InputCurr : 64|9@0+ (0.1,0) [0|51] "A" Vector__XXX
 SG_ EACP1_MotorTemp : 87|8@0+ (1,-40) [-40|140] "℃" Vector__XXX
 SG_ EACP1_ACPSpeed : 95|7@0+ (100,0) [0|8600] "rpm" TBOX,GW_FD5,BMS,GW_FD1,TBOX_OverSea
 SG_ EACP1_InputVolt : 88|9@0+ (1,0) [0|510] "V" TBOX,GW_FD5,TBOX_OverSea
 SG_ EACP1_BaseState : 106|3@0+ (1,0) [0|7] "" PDCS_FD1,TBOX,GW_FD5,GW_FD1,PDCS_HVM_FD1,TBOX_OverSea
 SG_ EACP1_OVState : 107|1@0+ (1,0) [0|1] "" Vector__XXX
 SG_ EACP1_LVState : 108|1@0+ (1,0) [0|1] "" Vector__XXX
 SG_ EACP1_OTState : 109|1@0+ (1,0) [0|1] "" Vector__XXX
 SG_ EACP1_OCState : 110|1@0+ (1,0) [0|1] "" Vector__XXX
 SG_ EACP1_ComState : 111|1@0+ (1,0) [0|1] "" Vector__XXX
 SG_ EACP1_LRState : 112|1@0+ (1,0) [0|1] "" Vector__XXX
 SG_ EACP1_OSState : 113|1@0+ (1,0) [0|1] "" Vector__XXX
 SG_ EACP1_PowerOffState : 114|1@0+ (1,0) [0|1] "" Vector__XXX
 SG_ EACP1_CurrSState : 115|1@0+ (1,0) [0|1] "" Vector__XXX
 SG_ EACP1_COVState : 116|1@0+ (1,0) [0|1] "" Vector__XXX
 SG_ EACP1_FailGrade : 119|3@0+ (1,0) [0|7] "" Vector__XXX
 SG_ EACP1_PhaseCurr : 127|8@0+ (0.2,0) [0|50.8] "A" Vector__XXX

BO_ 807 BDCS_Fr07_327: 8 BDCS
 SG_ BDCS7_Odometer : 7|24@0+ (0.1,0) [0|1677721.4] "km" PDCS_FD1,TBOX,GW_FD5,ICU_E02,GW_FD4,GW_FD1,ICU,CDCS,PDCS_HVM_FD1,CDCS_OverSea,TBOX_OverSea
 SG_ BDCS7_On_120minTime : 28|13@0+ (1,0) [0|7200] "s" TBOX,GW_FD5,GW_FD4,BAM,CDCS,CDCS_OverSea,TBOX_OverSea

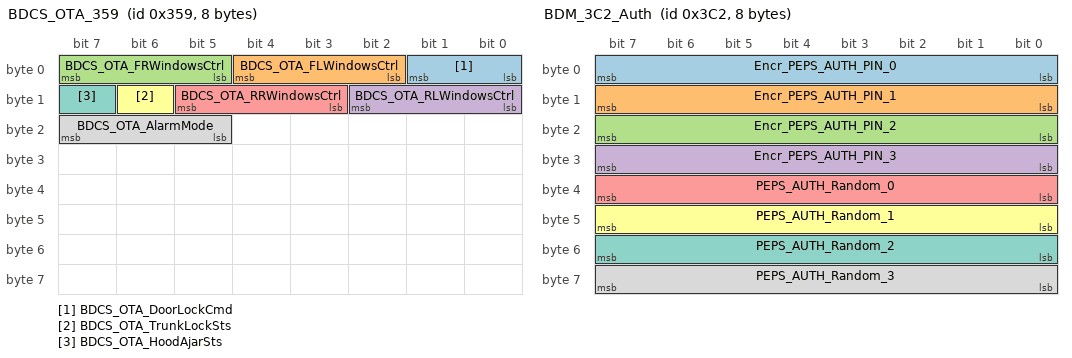
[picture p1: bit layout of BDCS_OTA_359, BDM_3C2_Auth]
BO_ 857 BDCS_OTA_359: 8 BDCS
 SG_ BDCS_OTA_DoorLockCmd : 1|2@0+ (1,0) [0|3] "NoUnit" PDCU,DDCU
 SG_ BDCS_OTA_FLWindowsCtrl : 4|3@0+ (1,0) [0|7] "NoUnit" PDCU,DDCU
 SG_ BDCS_OTA_FRWindowsCtrl : 7|3@0+ (1,0) [0|7] "NoUnit" PDCU,DDCU
 SG_ BDCS_OTA_RLWindowsCtrl : 10|3@0+ (1,0) [0|7] "NoUnit" PDCU,DDCU
 SG_ BDCS_OTA_RRWindowsCtrl : 13|3@0+ (1,0) [0|7] "NoUnit" PDCU,DDCU
 SG_ BDCS_OTA_TrunkLockSts : 14|1@0+ (1,0) [0|1] "NoUnit" TBOX,GW_FD5,DDCU,TBOX_OverSea
 SG_ BDCS_OTA_HoodAjarSts : 15|1@0+ (1,0) [0|1] "NoUnit" TBOX,GW_FD5,DDCU,TBOX_OverSea
 SG_ BDCS_OTA_AlarmMode : 23|3@0+ (1,0) [0|7] "NoUnit" DDCU

BO_ 938 BDCS_Fr19_3AA: 64 BDCS
 SG_ BDCS19_AC_ClmttSts_ChgTrg : 0|1@0+ (1,0) [0|1] "NoUnit" Vector__XXX
 SG_ BDCS19_AC_ClmttSts_ClmtOffTrg : 1|1@0+ (1,0) [0|1] "NoUnit" Vector__XXX
 SG_ BDCS19_AC_ClmttSts_SlpTrg : 2|1@0+ (1,0) [0|1] "NoUnit" Vector__XXX
 SG_ BDCS19_AC_ACSts_ChgTrg : 3|1@0+ (1,0) [0|1] "NoUnit" Vector__XXX
 SG_ BDCS19_AC_ACSts_ClmtOffTrg : 4|1@0+ (1,0) [0|1] "NoUnit" Vector__XXX
 SG_ BDCS19_AC_ACSts_SlpTrg : 5|1@0+ (1,0) [0|1] "NoUnit" Vector__XXX
 SG_ BDCS19_AC_AutoSts_ChgTrg : 6|1@0+ (1,0) [0|1] "NoUnit" Vector__XXX
 SG_ BDCS19_AC_AutoSts_ClmtOffTrg : 7|1@0+ (1,0) [0|1] "NoUnit" Vector__XXX
 SG_ BDCS19_AC_AutoSts_SlpTrg : 8|1@0+ (1,0) [0|1] "NoUnit" Vector__XXX
 SG_ BDCS19_AC_WinDefrstSts_ChgTrg : 9|1@0+ (1,0) [0|1] "NoUnit" Vector__XXX
 SG_ BDCS19_AC_WinDefrstSts_ClmtOffTrg : 10|1@0+ (1,0) [0|1] "NoUnit" Vector__XXX
 SG_ BDCS19_AC_WinDefrstSts_SlpTrg : 11|1@0+ (1,0) [0|1] "NoUnit" Vector__XXX
 SG_ BDCS19_AC_ACMaxSts_ChgTrg : 12|1@0+ (1,0) [0|1] "NoUnit" Vector__XXX
 SG_ BDCS19_AC_ACMaxSts_ClmtOffTrg : 13|1@0+ (1,0) [0|1] "NoUnit" Vector__XXX
 SG_ BDCS19_AC_ACMaxSts_SlpTrg : 14|1@0+ (1,0) [0|1] "NoUnit" Vector__XXX
 SG_ BDCS19_AC_DualReq_ChgTrg : 15|1@0+ (1,0) [0|1] "NoUnit" Vector__XXX
 SG_ BDCS19_AC_RecircCycleSts_ChgTrg : 17|2@0+ (1,0) [0|3] "NoUnit" Vector__XXX
 SG_ BDCS19_AC_RecircCycleSts_ClmtOffTrg : 19|2@0+ (1,0) [0|3] "NoUnit" Vector__XXX
 SG_ BDCS19_AC_RecircCycleSts_SlpTrg : 21|2@0+ (1,0) [0|3] "NoUnit" Vector__XXX
 SG_ BDCS19_AC_DualReq_ClmtOffTrg : 22|1@0+ (1,0) [0|1] "NoUnit" Vector__XXX
 SG_ BDCS19_AC_DualReq_SlpTrg : 23|1@0+ (1,0) [0|1] "NoUnit" Vector__XXX
 SG_ BDCS19_AC_DrvTempReq_ChgTrg : 31|8@0+ (1,0) [0|255] "℃" Vector__XXX
 SG_ BDCS19_AC_DrvTempReq_ClmtOffTrg : 39|8@0+ (1,0) [0|255] "℃" Vector__XXX
 SG_ BDCS19_AC_DrvTempReq_SlpTrg : 47|8@0+ (1,0) [0|255] "℃" Vector__XXX
 SG_ BDCS19_AC_PassTempReq_ChgTrg : 55|8@0+ (1,0) [0|255] "℃" Vector__XXX
 SG_ BDCS19_AC_PassTempReq_ClmtOffTrg : 63|8@0+ (1,0) [0|255] "℃" Vector__XXX
 SG_ BDCS19_AC_PassTempReq_SlpTrg : 71|8@0+ (1,0) [0|255] "℃" Vector__XXX
 SG_ BDCS19_AC_BlowerSpdLvl_ChgTrg : 75|4@0+ (1,0) [0|15] "NoUnit" Vector__XXX
 SG_ BDCS19_AC_BlowerSpdLvl_ClmtOffTrg : 79|4@0+ (1,0) [0|15] "NoUnit" Vector__XXX
 SG_ BDCS19_AC_BlowerSpdLvl_SlpTrg : 83|4@0+ (1,0) [0|15] "NoUnit" Vector__XXX
 SG_ BDCS19_AC_AirOutletMod_ChgTrg : 87|4@0+ (1,0) [0|15] "NoUnit" Vector__XXX
 SG_ BDCS19_AC_AirOutletMod_ClmtOffTrg : 91|4@0+ (1,0) [0|15] "NoUnit" Vector__XXX
 SG_ BDCS19_AC_AirOutletMod_SlpTrg : 95|4@0+ (1,0) [0|15] "NoUnit" Vector__XXX
 SG_ BDCS19_AC_ECONMod_ChgTrg : 96|1@0+ (1,0) [0|1] "NoUnit" Vector__XXX
 SG_ BDCS19_AC_ECONMod_ClmtOffTrg : 97|1@0+ (1,0) [0|1] "NoUnit" Vector__XXX
 SG_ BDCS19_AC_ECONMod_SlpTrg : 98|1@0+ (1,0) [0|1] "NoUnit" Vector__XXX
 SG_ BDCS19_AC_AirCleanSts_ChgTrg : 99|1@0+ (1,0) [0|1] "NoUnit" Vector__XXX
 SG_ BDCS19_AC_AirCleanSts_ClmtOffTrg : 100|1@0+ (1,0) [0|1] "NoUnit" Vector__XXX
 SG_ BDCS19_AC_AirCleanSts_SlpTrg : 101|1@0+ (1,0) [0|1] "NoUnit" Vector__XXX
 SG_ BDCS19_AC_AnionSts_ChgTrg : 102|1@0+ (1,0) [0|1] "NoUnit" Vector__XXX
 SG_ BDCS19_AC_AnionSts_ClmtOffTrg : 103|1@0+ (1,0) [0|1] "NoUnit" Vector__XXX
 SG_ BDCS19_AC_AnionSts_SlpTrg : 104|1@0+ (1,0) [0|1] "NoUnit" Vector__XXX
 SG_ BDCS19_AC_FrgrcSts_ChgTrg : 105|1@0+ (1,0) [0|1] "NoUnit" Vector__XXX
 SG_ BDCS19_AC_FrgrcSts_ClmtOffTrg : 106|1@0+ (1,0) [0|1] "NoUnit" Vector__XXX
 SG_ BDCS19_AC_FrgrcSts_SlpTrg : 107|1@0+ (1,0) [0|1] "NoUnit" Vector__XXX
 SG_ BDCS19_AC_FrgrcConctn_ChgTrg : 109|2@0+ (1,0) [0|3] "NoUnit" Vector__XXX
 SG_ BDCS19_AC_FrgrcConctn_ClmtOffTrg : 111|2@0+ (1,0) [0|3] "NoUnit" Vector__XXX
 SG_ BDCS19_AC_FrgrcConctn_SlpTrg : 113|2@0+ (1,0) [0|3] "NoUnit" Vector__XXX
 SG_ BDCS19_AC_FrgrcPosn_ChgTrg : 119|4@0+ (1,0) [0|15] "NoUnit" Vector__XXX
 SG_ BDCS19_AC_FrgrcPosn_ClmtOffTrg : 123|4@0+ (1,0) [0|15] "NoUnit" Vector__XXX
 SG_ BDCS19_AC_FrgrcPosn_SlpTrg : 127|4@0+ (1,0) [0|15] "NoUnit" Vector__XXX
 SG_ BDCS19_AC_FrgrcPosn1Type_ChgTrg : 131|4@0+ (1,0) [0|15] "NoUnit" Vector__XXX
 SG_ BDCS19_AC_FrgrcPosn1Type_ClmtOffTrg : 135|4@0+ (1,0) [0|15] "NoUnit" Vector__XXX
 SG_ BDCS19_AC_FrgrcPosn1Type_SlpTrg : 139|4@0+ (1,0) [0|15] "NoUnit" Vector__XXX
 SG_ BDCS19_AC_FrgrcPosn2Type_ChgTrg : 143|4@0+ (1,0) [0|15] "NoUnit" Vector__XXX
 SG_ BDCS19_AC_FrgrcPosn2Type_ClmtOffTrg : 147|4@0+ (1,0) [0|15] "NoUnit" Vector__XXX
 SG_ BDCS19_AC_FrgrcPosn2Type_SlpTrg : 151|4@0+ (1,0) [0|15] "NoUnit" Vector__XXX
 SG_ BDCS19_AC_FrgrcPosn3Type_ChgTrg : 155|4@0+ (1,0) [0|15] "NoUnit" Vector__XXX
 SG_ BDCS19_AC_FrgrcPosn3Type_ClmtOffTrg : 159|4@0+ (1,0) [0|15] "NoUnit" Vector__XXX
 SG_ BDCS19_AC_FrgrcPosn3Type_SlpTrg : 163|4@0+ (1,0) [0|15] "NoUnit" Vector__XXX
 SG_ BDCS19_EAO_FL_RLMotPosn_ChgTrg : 175|8@0+ (1,0) [0|135] "NoUnit" Vector__XXX
 SG_ BDCS19_EAO_FL_RLMotPosn_ClmtOffTrg : 183|8@0+ (1,0) [0|135] "NoUnit" Vector__XXX
 SG_ BDCS19_EAO_FL_RLMotPosn_SlpTrg : 191|8@0+ (1,0) [0|135] "NoUnit" Vector__XXX
 SG_ BDCS19_EAO_FL_UDMotPosn_ChgTrg : 199|8@0+ (1,0) [0|90] "NoUnit" Vector__XXX
 SG_ BDCS19_EAO_FL_UDMotPosn_ClmtOffTrg : 207|8@0+ (1,0) [0|90] "NoUnit" Vector__XXX
 SG_ BDCS19_EAO_FL_UDMotPosn_SlpTrg : 215|8@0+ (1,0) [0|90] "NoUnit" Vector__XXX
 SG_ BDCS19_EAO_CL_RLMotPosn_ChgTrg : 223|8@0+ (1,0) [0|135] "NoUnit" Vector__XXX
 SG_ BDCS19_EAO_CL_RLMotPosn_ClmtOffTrg : 231|8@0+ (1,0) [0|135] "NoUnit" Vector__XXX
 SG_ BDCS19_EAO_CL_RLMotPosn_SlpTrg : 239|8@0+ (1,0) [0|135] "NoUnit" Vector__XXX
 SG_ BDCS19_EAO_CL_UDMotPosn_ChgTrg : 247|8@0+ (1,0) [0|90] "NoUnit" Vector__XXX
 SG_ BDCS19_EAO_CL_UDMotPosn_ClmtOffTrg : 255|8@0+ (1,0) [0|90] "NoUnit" Vector__XXX
 SG_ BDCS19_EAO_CL_UDMotPosn_SlpTrg : 263|8@0+ (1,0) [0|90] "NoUnit" Vector__XXX
 SG_ BDCS19_EAO_CR_RLMotPosn_ChgTrg : 271|8@0+ (1,0) [0|135] "NoUnit" Vector__XXX
 SG_ BDCS19_EAO_CR_RLMotPosn_ClmtOffTrg : 279|8@0+ (1,0) [0|135] "NoUnit" Vector__XXX
 SG_ BDCS19_EAO_CR_RLMotPosn_SlpTrg : 287|8@0+ (1,0) [0|135] "NoUnit" Vector__XXX
 SG_ BDCS19_EAO_CR_UDMotPosn_ChgTrg : 295|8@0+ (1,0) [0|90] "NoUnit" Vector__XXX
 SG_ BDCS19_EAO_CR_UDMotPosn_ClmtOffTrg : 303|8@0+ (1,0) [0|90] "NoUnit" Vector__XXX
 SG_ BDCS19_EAO_CR_UDMotPosn_SlpTrg : 311|8@0+ (1,0) [0|90] "NoUnit" Vector__XXX
 SG_ BDCS19_EAO_FR_RLMotPosn_ChgTrg : 319|8@0+ (1,0) [0|135] "NoUnit" Vector__XXX
 SG_ BDCS19_EAO_FR_RLMotPosn_ClmtOffTrg : 327|8@0+ (1,0) [0|135] "NoUnit" Vector__XXX
 SG_ BDCS19_EAO_FR_RLMotPosn_SlpTrg : 335|8@0+ (1,0) [0|135] "NoUnit" Vector__XXX
 SG_ BDCS19_EAO_FR_UDMotPosn_ChgTrg : 343|8@0+ (1,0) [0|90] "NoUnit" Vector__XXX
 SG_ BDCS19_EAO_FR_UDMotPosn_ClmtOffTrg : 351|8@0+ (1,0) [0|90] "NoUnit" Vector__XXX
 SG_ BDCS19_EAO_FR_UDMotPosn_SlpTrg : 359|8@0+ (1,0) [0|90] "NoUnit" Vector__XXX
 SG_ BDCS19_EAO_LeVentMod_ChgTrg : 362|3@0+ (1,0) [0|4] "NoUnit" Vector__XXX
 SG_ BDCS19_AC_AutoDrySts_ChgTrg : 363|1@0+ (1,0) [0|1] "NoUnit" Vector__XXX
 SG_ BDCS19_EAO_LeVentMod_ClmtOffTrg : 366|3@0+ (1,0) [0|4] "NoUnit" Vector__XXX
 SG_ BDCS19_AC_AutoDrySts_ClmtOffTrg : 367|1@0+ (1,0) [0|1] "NoUnit" Vector__XXX
 SG_ BDCS19_EAO_LeVentMod_SlpTrg : 370|3@0+ (1,0) [0|4] "NoUnit" Vector__XXX
 SG_ BDCS19_AC_AutoDrySts_SlpTrg : 371|1@0+ (1,0) [0|1] "NoUnit" Vector__XXX
 SG_ BDCS19_EAO_RiVentMod_ChgTrg : 374|3@0+ (1,0) [0|4] "NoUnit" Vector__XXX
 SG_ BDCS19_AC_AutoWinDefrstSts_ChgTrg : 375|1@0+ (1,0) [0|1] "NoUnit" Vector__XXX
 SG_ BDCS19_EAO_RiVentMod_ClmtOffTrg : 378|3@0+ (1,0) [0|4] "NoUnit" Vector__XXX
 SG_ BDCS19_AC_AutoWinDefrstSts_ClmtOffTrg : 379|1@0+ (1,0) [0|1] "NoUnit" Vector__XXX
 SG_ BDCS19_EAO_RiVentMod_SlpTrg : 382|3@0+ (1,0) [0|4] "NoUnit" Vector__XXX
 SG_ BDCS19_AC_AutoWinDefrstSts_SlpTrg : 383|1@0+ (1,0) [0|1] "NoUnit" Vector__XXX
 SG_ BDCS19_AC_ChgTrgSts : 384|1@0+ (1,0) [0|1] "NoUnit" Vector__XXX
 SG_ BDCS19_AC_ClmtOffTrgSts : 385|1@0+ (1,0) [0|1] "NoUnit" Vector__XXX
 SG_ BDCS19_AC_SlpTrgSts : 386|1@0+ (1,0) [0|1] "NoUnit" Vector__XXX
 SG_ BDCS19_AC_ACTrgMod : 389|3@0+ (1,0) [0|5] "NoUnit" Vector__XXX
 SG_ BDCS19_AC_App2NVMSts_ClmtOffTrg : 391|2@0+ (1,0) [0|2] "NoUnit" Vector__XXX
 SG_ BDCS19_AC_App2NVMSts_SlpTrg : 393|2@0+ (1,0) [0|2] "NoUnit" Vector__XXX
 SG_ BDCS19_AC_ClmttMod_ClmtOffTrg : 395|2@0+ (1,0) [0|3] "NoUnit" Vector__XXX
 SG_ BDCS19_AC_ClmttMod_SlpTrg : 397|2@0+ (1,0) [0|3] "NoUnit" Vector__XXX
 SG_ BDCS19_VehicleEOLCode : 407|32@0+ (1,0) [0|4.294967295E9] "NoUnit" Vector__XXX

BO_ 962 BDM_3C2_Auth: 8 BDCS
 SG_ Encr_PEPS_AUTH_PIN_0 : 7|8@0+ (1,0) [0|255] "NoUnit" PDCS_FD1,GW_FD1,PDCS_HVM_FD1
 SG_ Encr_PEPS_AUTH_PIN_1 : 15|8@0+ (1,0) [0|255] "NoUnit" PDCS_FD1,GW_FD1,PDCS_HVM_FD1
 SG_ Encr_PEPS_AUTH_PIN_2 : 23|8@0+ (1,0) [0|255] "NoUnit" PDCS_FD1,GW_FD1,PDCS_HVM_FD1
 SG_ Encr_PEPS_AUTH_PIN_3 : 31|8@0+ (1,0) [0|255] "NoUnit" PDCS_FD1,GW_FD1,PDCS_HVM_FD1
 SG_ PEPS_AUTH_Random_0 : 39|8@0+ (1,0) [0|255] "NoUnit" PDCS_FD1,GW_FD1,PDCS_HVM_FD1
 SG_ PEPS_AUTH_Random_1 : 47|8@0+ (1,0) [0|255] "NoUnit" PDCS_FD1,GW_FD1,PDCS_HVM_FD1
 SG_ PEPS_AUTH_Random_2 : 55|8@0+ (1,0) [0|255] "NoUnit" PDCS_FD1,GW_FD1,PDCS_HVM_FD1
 SG_ PEPS_AUTH_Random_3 : 63|8@0+ (1,0) [0|255] "NoUnit" PDCS_FD1,GW_FD1,PDCS_HVM_FD1

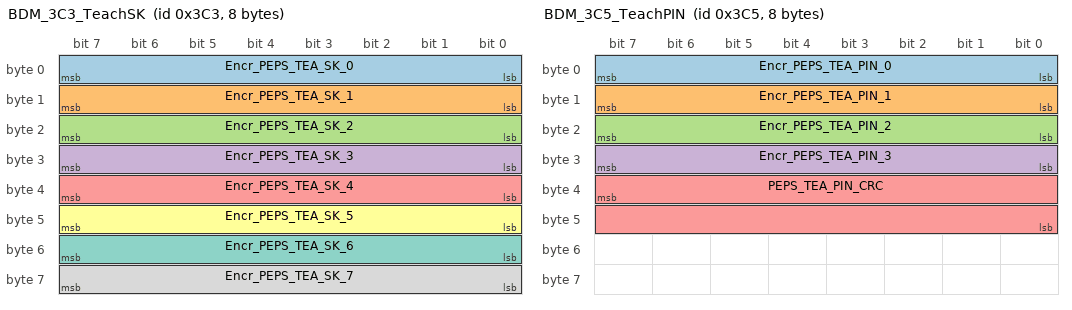
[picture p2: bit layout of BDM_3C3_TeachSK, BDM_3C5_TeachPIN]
BO_ 963 BDM_3C3_TeachSK: 8 BDCS
 SG_ Encr_PEPS_TEA_SK_0 : 7|8@0+ (1,0) [0|255] "NoUnit" PDCS_FD1,GW_FD1,PDCS_HVM_FD1
 SG_ Encr_PEPS_TEA_SK_1 : 15|8@0+ (1,0) [0|255] "NoUnit" PDCS_FD1,GW_FD1,PDCS_HVM_FD1
 SG_ Encr_PEPS_TEA_SK_2 : 23|8@0+ (1,0) [0|255] "NoUnit" PDCS_FD1,GW_FD1,PDCS_HVM_FD1
 SG_ Encr_PEPS_TEA_SK_3 : 31|8@0+ (1,0) [0|255] "NoUnit" PDCS_FD1,GW_FD1,PDCS_HVM_FD1
 SG_ Encr_PEPS_TEA_SK_4 : 39|8@0+ (1,0) [0|255] "NoUnit" PDCS_FD1,GW_FD1,PDCS_HVM_FD1
 SG_ Encr_PEPS_TEA_SK_5 : 47|8@0+ (1,0) [0|255] "NoUnit" PDCS_FD1,GW_FD1,PDCS_HVM_FD1
 SG_ Encr_PEPS_TEA_SK_6 : 55|8@0+ (1,0) [0|255] "NoUnit" PDCS_FD1,GW_FD1,PDCS_HVM_FD1
 SG_ Encr_PEPS_TEA_SK_7 : 63|8@0+ (1,0) [0|255] "NoUnit" PDCS_FD1,GW_FD1,PDCS_HVM_FD1

BO_ 965 BDM_3C5_TeachPIN: 8 BDCS
 SG_ Encr_PEPS_TEA_PIN_0 : 7|8@0+ (1,0) [0|255] "NoUnit" PDCS_FD1,GW_FD1,PDCS_HVM_FD1
 SG_ Encr_PEPS_TEA_PIN_1 : 15|8@0+ (1,0) [0|255] "NoUnit" PDCS_FD1,GW_FD1,PDCS_HVM_FD1
 SG_ Encr_PEPS_TEA_PIN_2 : 23|8@0+ (1,0) [0|255] "NoUnit" PDCS_FD1,GW_FD1,PDCS_HVM_FD1
 SG_ Encr_PEPS_TEA_PIN_3 : 31|8@0+ (1,0) [0|255] "NoUnit" PDCS_FD1,GW_FD1,PDCS_HVM_FD1
 SG_ PEPS_TEA_PIN_CRC : 39|16@0+ (1,0) [0|65535] "NoUnit" PDCS_FD1,GW_FD1,PDCS_HVM_FD1

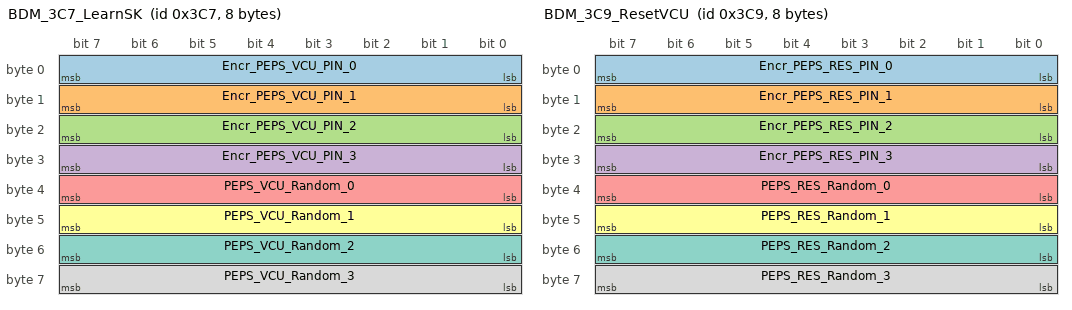
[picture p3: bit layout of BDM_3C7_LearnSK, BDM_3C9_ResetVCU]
BO_ 967 BDM_3C7_LearnSK: 8 BDCS
 SG_ Encr_PEPS_VCU_PIN_0 : 7|8@0+ (1,0) [0|255] "NoUnit" PDCS_FD1,GW_FD1,PDCS_HVM_FD1
 SG_ Encr_PEPS_VCU_PIN_1 : 15|8@0+ (1,0) [0|255] "NoUnit" PDCS_FD1,GW_FD1,PDCS_HVM_FD1
 SG_ Encr_PEPS_VCU_PIN_2 : 23|8@0+ (1,0) [0|255] "NoUnit" PDCS_FD1,GW_FD1,PDCS_HVM_FD1
 SG_ Encr_PEPS_VCU_PIN_3 : 31|8@0+ (1,0) [0|255] "NoUnit" PDCS_FD1,GW_FD1,PDCS_HVM_FD1
 SG_ PEPS_VCU_Random_0 : 39|8@0+ (1,0) [0|255] "NoUnit" PDCS_FD1,GW_FD1,PDCS_HVM_FD1
 SG_ PEPS_VCU_Random_1 : 47|8@0+ (1,0) [0|255] "NoUnit" PDCS_FD1,GW_FD1,PDCS_HVM_FD1
 SG_ PEPS_VCU_Random_2 : 55|8@0+ (1,0) [0|255] "NoUnit" PDCS_FD1,GW_FD1,PDCS_HVM_FD1
 SG_ PEPS_VCU_Random_3 : 63|8@0+ (1,0) [0|255] "NoUnit" PDCS_FD1,GW_FD1,PDCS_HVM_FD1

BO_ 969 BDM_3C9_ResetVCU: 8 BDCS
 SG_ Encr_PEPS_RES_PIN_0 : 7|8@0+ (1,0) [0|255] "NoUnit" PDCS_FD1,GW_FD1,PDCS_HVM_FD1
 SG_ Encr_PEPS_RES_PIN_1 : 15|8@0+ (1,0) [0|255] "NoUnit" PDCS_FD1,GW_FD1,PDCS_HVM_FD1
 SG_ Encr_PEPS_RES_PIN_2 : 23|8@0+ (1,0) [0|255] "NoUnit" PDCS_FD1,GW_FD1,PDCS_HVM_FD1
 SG_ Encr_PEPS_RES_PIN_3 : 31|8@0+ (1,0) [0|255] "NoUnit" PDCS_FD1,GW_FD1,PDCS_HVM_FD1
 SG_ PEPS_RES_Random_0 : 39|8@0+ (1,0) [0|255] "NoUnit" PDCS_FD1,GW_FD1,PDCS_HVM_FD1
 SG_ PEPS_RES_Random_1 : 47|8@0+ (1,0) [0|255] "NoUnit" PDCS_FD1,GW_FD1,PDCS_HVM_FD1
 SG_ PEPS_RES_Random_2 : 55|8@0+ (1,0) [0|255] "NoUnit" PDCS_FD1,GW_FD1,PDCS_HVM_FD1
 SG_ PEPS_RES_Random_3 : 63|8@0+ (1,0) [0|255] "NoUnit" PDCS_FD1,GW_FD1,PDCS_HVM_FD1

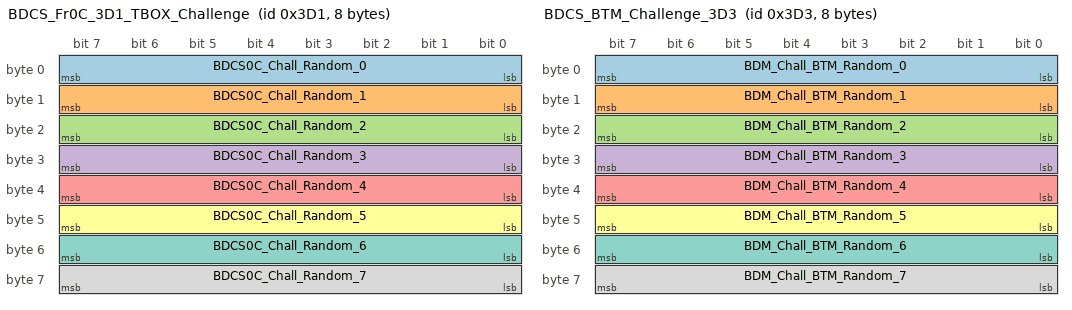
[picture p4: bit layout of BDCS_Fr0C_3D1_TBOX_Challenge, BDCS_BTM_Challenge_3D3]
BO_ 977 BDCS_Fr0C_3D1_TBOX_Challenge: 8 BDCS
 SG_ BDCS0C_Chall_Random_0 : 7|8@0+ (1,0) [0|255] "NoUnit" TBOX,GW_FD5,TBOX_OverSea
 SG_ BDCS0C_Chall_Random_1 : 15|8@0+ (1,0) [0|255] "NoUnit" TBOX,GW_FD5,TBOX_OverSea
 SG_ BDCS0C_Chall_Random_2 : 23|8@0+ (1,0) [0|255] "NoUnit" TBOX,GW_FD5,TBOX_OverSea
 SG_ BDCS0C_Chall_Random_3 : 31|8@0+ (1,0) [0|255] "NoUnit" TBOX,GW_FD5,TBOX_OverSea
 SG_ BDCS0C_Chall_Random_4 : 39|8@0+ (1,0) [0|255] "NoUnit" TBOX,GW_FD5,TBOX_OverSea
 SG_ BDCS0C_Chall_Random_5 : 47|8@0+ (1,0) [0|255] "NoUnit" TBOX,GW_FD5,TBOX_OverSea
 SG_ BDCS0C_Chall_Random_6 : 55|8@0+ (1,0) [0|255] "NoUnit" TBOX,GW_FD5,TBOX_OverSea
 SG_ BDCS0C_Chall_Random_7 : 63|8@0+ (1,0) [0|255] "NoUnit" TBOX,GW_FD5,TBOX_OverSea

BO_ 979 BDCS_BTM_Challenge_3D3: 8 BDCS
 SG_ BDM_Chall_BTM_Random_0 : 7|8@0+ (1,0) [0|255] "NoUnit" TBOX,GW_FD5,TBOX_OverSea
 SG_ BDM_Chall_BTM_Random_1 : 15|8@0+ (1,0) [0|255] "NoUnit" TBOX,GW_FD5,TBOX_OverSea
 SG_ BDM_Chall_BTM_Random_2 : 23|8@0+ (1,0) [0|255] "NoUnit" TBOX,GW_FD5,TBOX_OverSea
 SG_ BDM_Chall_BTM_Random_3 : 31|8@0+ (1,0) [0|255] "NoUnit" TBOX,GW_FD5,TBOX_OverSea
 SG_ BDM_Chall_BTM_Random_4 : 39|8@0+ (1,0) [0|255] "NoUnit" TBOX,GW_FD5,TBOX_OverSea
 SG_ BDM_Chall_BTM_Random_5 : 47|8@0+ (1,0) [0|255] "NoUnit" TBOX,GW_FD5,TBOX_OverSea
 SG_ BDM_Chall_BTM_Random_6 : 55|8@0+ (1,0) [0|255] "NoUnit" TBOX,GW_FD5,TBOX_OverSea
 SG_ BDM_Chall_BTM_Random_7 : 63|8@0+ (1,0) [0|255] "NoUnit" TBOX,GW_FD5,TBOX_OverSea

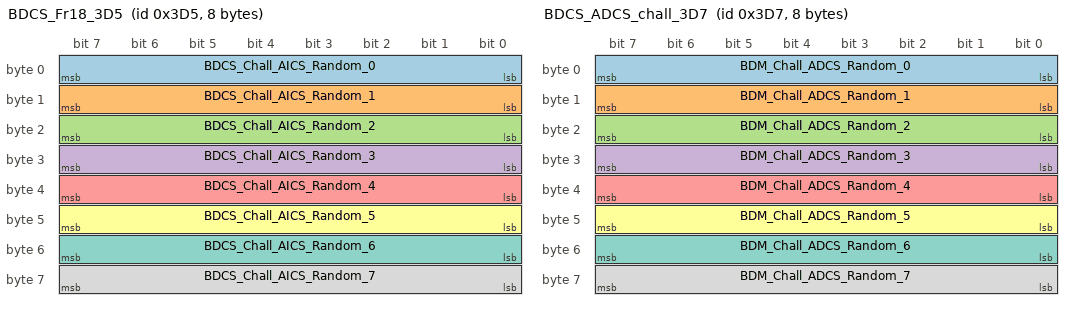
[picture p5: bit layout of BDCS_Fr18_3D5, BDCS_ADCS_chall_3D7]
BO_ 981 BDCS_Fr18_3D5: 8 BDCS
 SG_ BDCS_Chall_AICS_Random_0 : 7|8@0+ (1,0) [0|255] "NoUnit" GW_FD2
 SG_ BDCS_Chall_AICS_Random_1 : 15|8@0+ (1,0) [0|255] "NoUnit" GW_FD2
 SG_ BDCS_Chall_AICS_Random_2 : 23|8@0+ (1,0) [0|255] "NoUnit" GW_FD2
 SG_ BDCS_Chall_AICS_Random_3 : 31|8@0+ (1,0) [0|255] "NoUnit" GW_FD2
 SG_ BDCS_Chall_AICS_Random_4 : 39|8@0+ (1,0) [0|255] "NoUnit" GW_FD2
 SG_ BDCS_Chall_AICS_Random_5 : 47|8@0+ (1,0) [0|255] "NoUnit" GW_FD2
 SG_ BDCS_Chall_AICS_Random_6 : 55|8@0+ (1,0) [0|255] "NoUnit" GW_FD2
 SG_ BDCS_Chall_AICS_Random_7 : 63|8@0+ (1,0) [0|255] "NoUnit" GW_FD2

BO_ 983 BDCS_ADCS_chall_3D7: 8 BDCS
 SG_ BDM_Chall_ADCS_Random_0 : 7|8@0+ (1,0) [0|255] "NoUnit" GW_FD3,ADCU_FD3,ADCS_FD3
 SG_ BDM_Chall_ADCS_Random_1 : 15|8@0+ (1,0) [0|255] "NoUnit" GW_FD3,ADCU_FD3,ADCS_FD3
 SG_ BDM_Chall_ADCS_Random_2 : 23|8@0+ (1,0) [0|255] "NoUnit" GW_FD3,ADCU_FD3,ADCS_FD3
 SG_ BDM_Chall_ADCS_Random_3 : 31|8@0+ (1,0) [0|255] "NoUnit" GW_FD3,ADCU_FD3,ADCS_FD3
 SG_ BDM_Chall_ADCS_Random_4 : 39|8@0+ (1,0) [0|255] "NoUnit" GW_FD3,ADCU_FD3,ADCS_FD3
 SG_ BDM_Chall_ADCS_Random_5 : 47|8@0+ (1,0) [0|255] "NoUnit" GW_FD3,ADCU_FD3,ADCS_FD3
 SG_ BDM_Chall_ADCS_Random_6 : 55|8@0+ (1,0) [0|255] "NoUnit" GW_FD3,ADCU_FD3,ADCS_FD3
 SG_ BDM_Chall_ADCS_Random_7 : 63|8@0+ (1,0) [0|255] "NoUnit" GW_FD3,ADCU_FD3,ADCS_FD3

CM_ SG_ 272 BDCS1_PowerMode "低压电源模式";
CM_ SG_ 272 BDCS1_PetToLookAfterFbk "宠物照看模式反馈";
CM_ SG_ 272 BDCS1_PetToLookAfterRmd "宠物照看模式提醒";
CM_ SG_ 272 BDCS1_PowerManageMode "低压电源管理模式";
CM_ SG_ 272 BDCS1_AlarmMode "车身防盗状态";
CM_ SG_ 272 BDCS1_LowBeamSt "近光灯状态";
CM_ SG_ 272 BDCS1_HighBeamSt "远光灯状态";
CM_ SG_ 272 BDCS1_EnergyManagement "能量管理等级(BDCS预留此信号)";
CM_ SG_ 272 BDCS1_FindCarSts "寻车模式状态";
CM_ SG_ 272 BDCS1_PositionLightSts "位置灯状态";
CM_ SG_ 272 BDCS1_BacklightStatus "整车背光灯状态";
CM_ SG_ 272 BDCS1_LeftTurnLightSt "左转向灯状态";
CM_ SG_ 272 BDCS1_RightTurnLightSt "右转向灯状态";
CM_ SG_ 272 BDCS1_FrontLampSt "前照灯开关";
CM_ SG_ 272 BDCS1_HazardLampSt "危险报警灯状态";
CM_ SG_ 272 BDCS1_HighBeamSW "远光灯开关状态";
CM_ SG_ 272 BDCS1_TurnLightSW "转向灯开关";
CM_ SG_ 272 BDCS1_HazardSwSt "危险报警灯开关状态";
CM_ SG_ 272 BDCS1_BrakeLightSts "制动灯工作状态";
CM_ SG_ 272 BDCS1_RearFogLampSt "后雾灯状态";
CM_ SG_ 272 BDCS1_FrontFogLampSt "前雾灯状态（预留）";
CM_ SG_ 272 BDCS1_BackupLightSts "倒车灯状态";
CM_ SG_ 272 BDCS1_HeadlampHeight_fb "大灯高度调节反馈";
CM_ SG_ 272 BDCS1_TrunkLockSts "后背门锁状态（是否电动尾门，该信号均作为提示尾门是否开启）";
CM_ SG_ 272 BDCS1_FMH_SetSts "伴我回家功能反馈";
CM_ SG_ 272 BDCS1_HoodAjarSts "前舱盖开闭状态";
CM_ SG_ 272 BDCS1_Backlight_brightness_fb "背光灯亮度调节反馈";
CM_ SG_ 272 BDCS1_DRLSt "日间行车灯状态";
CM_ SG_ 272 BDCS1_CentralLockFbk "中控锁";
CM_ SG_ 272 BDCS1_OTAauthenSts "OTA认证状态";
CM_ SG_ 272 BDCS1_MsgCounter "E2E Profile2-CRC8H2F，Counter:0-15";
CM_ SG_ 272 BDCS1_WelcomeLampModFbk "迎宾灯模式设置反馈信号";
CM_ SG_ 272 BDCS1_Checksum "E2E Profile2-CRC8H2F
DataID List:#60 - 174 124 106 58 47 154 237 220 98 37 173 212 59 125 101 188";
CM_ SG_ 274 BDCS3_StartRequest "启动请求信号";
CM_ SG_ 274 BDCS3_LightShowSts "灯光秀状态";
CM_ SG_ 274 BDCS3_CarMode "车辆模式状态";
CM_ SG_ 274 BDCS3_BluetoothAuthenSts "蓝牙认证状态";
CM_ SG_ 274 BDCS3_EngineForbidSts "远程禁止启动";
CM_ SG_ 274 BDCS3_RemoteStartSts "远程启动状态";
CM_ SG_ 274 BDCS3_RemoteAuthenSts "远程认证状态";
CM_ SG_ 274 BDCS3_RemoteReadySts "蓝牙启动状态有效性";
CM_ SG_ 274 BDCS3_IHU_DoorHeightSetFb "尾门开启高度百分比设置反馈";
CM_ SG_ 274 BDCS3_RemoteAuthenFailCondition "远程进入失败原因";
CM_ SG_ 274 BDCS3_KeyAuthenSts "钥匙认证状态";
CM_ SG_ 274 BDCS3_IHU_ReclockReq "请求大屏重计时";
CM_ SG_ 274 BDCS3_BackDoorAjar "电动尾门位置状态";
CM_ SG_ 274 BDCS3_RKECmd "遥控钥匙指令";
CM_ SG_ 274 BDCS3_DoorHeight "尾门开启高度百分比";
CM_ SG_ 274 BDCS3_DoorHeightValid "尾门高度有效性";
CM_ SG_ 274 BDCS3_RearDoorStatus "尾门动作状态";
CM_ SG_ 274 BDCS3_IDdeviceNo "钥匙ID";
CM_ SG_ 274 BDCS3_ShutDownReqFbk "下电失败反馈";
CM_ SG_ 274 BDCS3_OTAModeSts "OTA模式失败原因";
CM_ SG_ 274 BDCS3_LaunchRequest "弹射请求";
CM_ SG_ 274 BDCS3_StarterRelay2On "IGN1继电器吸合状态";
CM_ SG_ 274 BDCS3_StarterRelay1On "IGN1继电器吸合状态";
CM_ SG_ 274 BDCS3_PARKUnLockFeedback "驻车解锁反馈";
CM_ SG_ 274 BDCS3_SpeedLockFeedback "自动落锁速度设置反馈";
CM_ SG_ 274 BDCS3_StationaryModeReminder "静态模式提醒";
CM_ SG_ 274 BDCS3_SportRequest "运动模式请求";
CM_ SG_ 274 BDCS3_SportRequestValid "运动模式请求有效性";
CM_ SG_ 274 BDCS3_LaunchRequestValid "弹射请求有效性";
CM_ SG_ 274 BDCS3_ADCSAuthenSts "与ADCS认证状态";
CM_ SG_ 274 BDCS3_InteriorLightingFdb "室内灯反馈";
CM_ SG_ 274 BDCS3_LFreadinglampSts "左前阅读灯状态";
CM_ SG_ 274 BDCS3_RFreadinglampSts "右前阅读灯状态";
CM_ SG_ 274 BDCS3_LRreadinglampSts "左后阅读灯状态";
CM_ SG_ 274 BDCS3_RRreadinglampSts "右后阅读灯状态";
CM_ SG_ 274 BDCS3_FindMyCarTimeSet_Fb "寻车时间设置";
CM_ SG_ 274 BDCS3_Horn_SW "喇叭开关";
CM_ SG_ 274 BDCS3_AntiTheftInnerStsEE "解防设防状态";
CM_ SG_ 274 BDCS3_AntiTheftRmdSoundFdb "设防成功提示音请求反馈";
CM_ SG_ 274 BDCS3_AlarmRmdSoundFdb "报警时声音请求反馈(BDCS预留此信号)";
CM_ SG_ 274 BDCS3_AlarmTurnTimeFdb "(BDCS预留此信号)报警时转向灯时长请求反馈";
CM_ SG_ 274 BDCS3_Wal_Away_Up_swSt "无感进出状态反馈";
CM_ SG_ 274 BDCS3_WelcomeLampCmd_swSt "迎宾灯开关状态反馈";
CM_ SG_ 274 BDCS3_TrunkHomeLockSts "后背门锁复位状态";
CM_ SG_ 274 BDCS3_TrunkHalfLockSts "后背门棘爪状态";
CM_ SG_ 274 BDCS3_UserSceneModeFbk "情景模式反馈信号";
CM_ SG_ 274 BDCS3_VehicleStatelRemind "车辆状态提醒";
CM_ SG_ 274 BDCS3_TrunkCtrlFailure "尾门控制系统故障（防夹失效+锁监控失效）";
CM_ SG_ 274 RF_Key_Position "射频钥匙位置";
CM_ SG_ 274 BDCS3_Key_Ventilation_Fbk "一键通风反馈信号";
CM_ SG_ 276 CS1_FrontWiperMISTReqSt "前雨刮MIST请求状态";
CM_ SG_ 276 CS1_HighBeamFlashReqSt "超车灯信号";
CM_ SG_ 276 CS1_HighBeamReqSt "远光灯信号";
CM_ SG_ 276 CS1_TurnLightReqSt "转向灯";
CM_ SG_ 276 CS1_FrontWiperReqSt "前雨刮";
CM_ SG_ 276 CS1_FrontWiperWashReqSt "前洗涤";
CM_ SG_ 276 CS1_RearWiperReqSt_Reserved "后雨刮";
CM_ SG_ 276 CS1_RearWiperWashReqSt_Reserved "后洗涤";
CM_ SG_ 276 CS1_GearPositionReqSt "档位请求信号";
CM_ SG_ 276 CS1_GearPositionReqStInv "档位请求信号取反";
CM_ SG_ 276 CS1_GearPositionReqStValid "档位请求信号有效性";
CM_ SG_ 276 CS1_MsgCounter "E2E Profile2-CRC8H2F，Counter:0-15";
CM_ SG_ 276 CS1_Checksum "E2E Profile2-CRC8H2F
DataID List:#71 - 213 235 162 78 53 174 81 206 45 121 159 124 52 82 9 3";
CM_ SG_ 482 BDCS4_Ftyre_Status "前轮信号状态(表示本帧信号代表的是当前状态还是前回状态)";
CM_ SG_ 482 BDCS4_FLTyre_LearntSt "左前轮胎传感器学习状态";
CM_ SG_ 482 BDCS4_FLTyre_PressureWarn "左前轮胎胎压报警";
CM_ SG_ 482 BDCS4_FLTyre_TemperatureWarn "左前轮胎高温报警";
CM_ SG_ 482 BDCS4_FLTyre_QucikLeak "左前轮快速漏气";
CM_ SG_ 482 BDCS4_FLTyre_SensorFailure "左前轮胎传感器故障";
CM_ SG_ 482 BDCS4_FLTyre_LowBattery "左前轮胎传感器电量低";
CM_ SG_ 482 BDCS4_FLTyre_Pressure "左前轮胎压力";
CM_ SG_ 482 BDCS4_FLTyre_Temperature "左前轮胎温度";
CM_ SG_ 482 BDCS4_FRTyre_LearntSt "右前轮胎传感器学习状态";
CM_ SG_ 482 BDCS4_FRTyre_PressureWarn "右前轮胎胎压报警";
CM_ SG_ 482 BDCS4_FRTyre_TemperatureWarn "右前轮胎高温报警";
CM_ SG_ 482 BDCS4_FRTyre_QucikLeak "右前轮快速漏气";
CM_ SG_ 482 BDCS4_FRTyre_SensorFailure "右前轮胎传感器故障";
CM_ SG_ 482 BDCS4_FRTyre_LowBattery "右前轮胎传感器电量低";
CM_ SG_ 482 BDCS4_FRTyre_Pressure "右前轮胎压力";
CM_ SG_ 482 BDCS4_FRTyre_Temperature "右前轮胎温度";
CM_ SG_ 482 BDCS4_Testmode "自检模式";
CM_ SG_ 482 BDCS4_SystemFailure "系统报警";
CM_ SG_ 484 BDCS5_Rtyre_Status "后轮信号状态(表示本帧信号代表的是当前状态还是前回状态)";
CM_ SG_ 484 BDCS5_RLTyre_LearntSt "左后轮胎传感器学习状态";
CM_ SG_ 484 BDCS5_RLTyre_PressureWarn "左后轮胎胎压报警";
CM_ SG_ 484 BDCS5_RLTyre_TemperatureWarn "左后轮胎高温报警";
CM_ SG_ 484 BDCS5_RLTyre_QucikLeak "左后轮快速漏气";
CM_ SG_ 484 BDCS5_RLTyre_SensorFailure "左后轮胎传感器故障";
CM_ SG_ 484 BDCS5_RLTyre_LowBattery "左后轮胎传感器电量低";
CM_ SG_ 484 BDCS5_RLTyre_Pressure "左后轮胎压力";
CM_ SG_ 484 BDCS5_RLTyre_Temperature "左后轮胎温度";
CM_ SG_ 484 BDCS5_RRTyre_LearntSt "右后轮胎传感器学习状态";
CM_ SG_ 484 BDCS5_RRTyre_PressureWarn "右后轮胎胎压报警";
CM_ SG_ 484 BDCS5_RRTyre_TemperatureWarn "右后轮胎高温报警";
CM_ SG_ 484 BDCS5_RRTyre_QucikLeak "右后轮快速漏气";
CM_ SG_ 484 BDCS5_RRTyre_SensorFailure "右后轮胎传感器故障";
CM_ SG_ 484 BDCS5_RRTyre_LowBattery "右后轮胎传感器电量低";
CM_ SG_ 484 BDCS5_RRTyre_Pressure "右后轮胎压力";
CM_ SG_ 484 BDCS5_RRTyre_Temperature "右后轮胎温度";
CM_ SG_ 486 BDCS6_KeyNotFindIndication "未检测到钥匙提示";
CM_ SG_ 486 BDCS6_FindMyCar_Sts_feedback "寻车反馈状态反馈";
CM_ SG_ 486 BDCS6_KeySearchingSts "钥匙搜寻信号（用于禁止无线充电功能）";
CM_ SG_ 486 BDCS6_KeylessWarningLight "无钥匙系统报警灯";
CM_ SG_ 486 BDCS6_KeyLowBatteryIndication "钥匙电池电量低提示";
CM_ SG_ 486 BDCS6_KeyInIndication "钥匙遗留提示";
CM_ SG_ 486 BDCS6_DepressBrakePedalInd "踩下制动踏板提示";
CM_ SG_ 486 BDCS6_ShiftGearToPNIndication "切换P/N档位提示";
CM_ SG_ 486 BDCS6_ShiftGearToPIndication "切换P档提示";
CM_ SG_ 486 BDCS6_BackupStartIndication "备份启动提示";
CM_ SG_ 486 BDCS6_WiperNozzleHeat_SW_Fed "雨刮喷嘴加热开关反馈";
CM_ SG_ 486 BDCS6_ALHSelectModeCtrlFed "氛围灯模式选择";
CM_ SG_ 486 BDCS6_FrontWasherSts "前洗涤工作状态";
CM_ SG_ 486 BDCS6_FrontWiperParkPos "前雨刮回位开关状态";
CM_ SG_ 486 BDCS6_FrontWiperSts "前雨刮工作状态";
CM_ SG_ 486 BDCS6_FrontWiperMaintenancePos "维修位开关状态";
CM_ SG_ 486 BDCS6_RearWiperSts "后雨刮工作状态";
CM_ SG_ 486 BDCS6_RearWiperParkPos "后雨刮回位开关状态";
CM_ SG_ 486 BDCS6_RearWasherSts "后洗涤工作状态";
CM_ SG_ 486 BDCS6_RearDefrostSts "后除霜状态";
CM_ SG_ 486 BDCS6_IHU_AC_St "空调开启状态反馈";
CM_ SG_ 486 BDCS6_ALH_SW_Fed "氛围灯开关反馈";
CM_ SG_ 486 BDCS6_EntryMode_Fed "氛围灯进入模式反馈";
CM_ SG_ 486 BDCS6_AEBMode_Fed "氛围灯紧急制动开关反馈";
CM_ SG_ 486 BDCS6_LockUpWindowSETfbk "闭锁升窗设置反馈";
CM_ SG_ 486 BDCS6_LOGOLampST "Logo灯";
CM_ SG_ 486 BDCS6_AUTOHOLDLamp "AutoHold灯";
CM_ SG_ 486 BDCS6_WiperNozzleHeat_Fdb "雨刮喷嘴加热时长反馈";
CM_ SG_ 486 BDCS6_BiologicalDetectionFbk "生物检测开启开关反馈";
CM_ SG_ 486 BDCS6_ALH_DriveModeSW_Fed "驾驶模式设置开关反馈";
CM_ SG_ 486 BDCS6_ALH_TemperatureSW_Fed "温度模式设置开关反馈";
CM_ SG_ 486 BDCS6_ALHSelectColourCtrlFed "氛围灯颜色模式反馈";
CM_ SG_ 486 BDCS6_IHU_Brightness_fb "氛围灯亮度值反馈";
CM_ SG_ 486 BDCS6_RoadRecSts "基于路况控制内外循环开关状态";
CM_ SG_ 486 BDCS6_IHU_Rvalue_fb "氛围灯红色值反馈";
CM_ SG_ 486 BDCS6_IHU_Gvalue_fb "氛围灯绿色值反馈";
CM_ SG_ 486 BDCS6_IHU_Bvalue_fb "氛围灯蓝色值反馈";
CM_ SG_ 486 BDCS6_DGM_percentSts "天幕输出电压反馈信号（用于透明度反馈）";
CM_ SG_ 486 BDCS6_DGM_SWSts "天幕调节开关反馈";
CM_ SG_ 486 BDCS6_ChargingLamp_Fdb "充电指示灯反馈";
CM_ SG_ 486 BDCS6_LowBeamSt_F "近光灯故障信号";
CM_ SG_ 486 BDCS6_HighBeamSt_F "远光灯故障信号";
CM_ SG_ 486 BDCS6_PositionLightSts_F "位置灯故障信号";
CM_ SG_ 486 BDCS6_LeftTurnLightSt_F "左转向灯故障信号";
CM_ SG_ 486 BDCS6_RightTurnLightSt_F "右转向灯故障信号";
CM_ SG_ 486 BDCS6_BrakeLightSts_F "制动灯故障信号";
CM_ SG_ 486 BDCS6_RearFogLampSt_F "后雾灯故障信号";
CM_ SG_ 486 BDCS6_DRLSt_F "日行灯故障信号";
CM_ SG_ 486 BDCS6_FLcorneringLampSt "左角灯状态信号";
CM_ SG_ 486 BDCS6_FRcorneringLampSt "右角灯状态信号";
CM_ SG_ 486 BDCS6_DayNightMode "白天夜晚模式";
CM_ SG_ 486 BDCS6_ALHBrightnessAutoMode_Fdb "氛围灯亮度模式选择反馈";
CM_ SG_ 486 BDCS6_DGM_AdjustedPercentage "天幕调节百分比(预留)";
CM_ SG_ 486 BDCS6_SOC_Lamp_Fdb "电量提示设置开关反馈";
CM_ SG_ 486 BDCS6_AutoDfrostSts "自动除雾开关状态";
CM_ SG_ 486 BDCS6_AutoDrySts "空调自干燥开关状态";
CM_ SG_ 486 BDCS6_BtmCallAutoSpdSts "蓝牙通话自动降噪开关状态";
CM_ SG_ 486 BDCS6_AutoAionSts "负离子自动开启开关状态";
CM_ SG_ 486 BDCS6_AQSConfigSts "AQS防止尾气进入车内开关状态";
CM_ SG_ 486 BDCS6_PM25AutoCleanPopupSts "PM2.5自动净化开关状态";
CM_ SG_ 486 BDCS6_CabinCleanConfigSts "主动座舱清洁开关状态";
CM_ SG_ 486 BDCS6_ALH_ADASWarning_Fdb "氛围灯提醒ADAS功能开关反馈";
CM_ SG_ 486 BDCS6_ALHSelectTheme_Fdb "氛围灯主题模式选择反馈";
CM_ SG_ 486 BDCS6_SunRoofSLideCtrlReq_Fdb "天窗开度控制请求反馈信号";
CM_ SG_ 486 BDCS6_SunRoofCtrlReq_Fdb "天窗控制请求反馈信号";
CM_ SG_ 486 BDCS6_CurtainSLideCtrlReq_Fdb "遮阳帘开度控制请求反馈信号";
CM_ SG_ 496 BDCS2_DoorLockCmd "车门控制命令";
CM_ SG_ 496 BDCS2_FLWindowsCtrl "控制左前车窗动作";
CM_ SG_ 496 BDCS2_FRWindowsCtrl "控制右前车窗动作";
CM_ SG_ 496 BDCS2_RLWindowsCtrl "控制左后车窗动作";
CM_ SG_ 496 BDCS2_RRWindowsCtrl "控制右后车窗动作";
CM_ SG_ 496 BDCS2_FrontDoorOpenModeSts "前门开启方式状态";
CM_ SG_ 496 BDCS2_OpenFLDoorReq "左前门开闭指令";
CM_ SG_ 496 BDCS2_OpenFRDoorReq "右前门开闭指令";
CM_ SG_ 496 BDCS2_LSD_FL_Away_Up_Sts "左前远离关门靠近开门状态";
CM_ SG_ 496 BDCS2_LSD_FR_Away_Up_Sts "右前远离关门靠近开门状态";
CM_ SG_ 496 BDCS2_RainwinClosedFbk "雨天关窗完成状态反馈";
CM_ SG_ 496 BDCS2_SunRoof_GlassMovement "天窗玻璃运动状态";
CM_ SG_ 496 BDCS2_Curtain_Movement "遮阳帘运动状态";
CM_ SG_ 496 BDCS2_CarTempHoldMode_Fdb "驻车温度保持功能反馈信号";
CM_ SG_ 496 BDCS2_RemoteFindCarStsFdb "远程寻车状态反馈";
CM_ SG_ 496 BDCS2_CurtainCtrlReq_Fdb "遮阳帘控制请求反馈信号";
CM_ SG_ 496 BDCS2_SRMGlassInitialized "SunroofGlassInitialized
天窗玻璃初始化";
CM_ SG_ 496 BDCS2_SRMTeachingRunningSts "Sunroof Teaching Running Status
天窗玻璃学习";
CM_ SG_ 496 BDCS2_CurtainInitialized "Curtain Initialized
遮阳帘初始化";
CM_ SG_ 496 BDCS2_CurtainTeachingRunningSts "Curtain Teaching Running Status
遮阳帘学习";
CM_ SG_ 496 BDCS2_TemKeepModeRmd "驻车温度保持提醒（用于告知TBOX，车辆
因低电量自动退出驻车温度保持功能）";
CM_ SG_ 496 BDCS2_TemKeepModeExitFailRsn "驻车温度保持功能退出失败原因（告知TBOX，离车温度保持功能关闭失败的原因）";
CM_ SG_ 496 BDCS2_SRMOverspeedClosing "天窗超速关闭信号";
CM_ SG_ 496 BDCS2_PLG_DoorHeightSetFb "后备箱高度设置反馈信号";
CM_ SG_ 512 BDCS20_bParkPosnReq "Park位置请求状态";
CM_ SG_ 512 BDCS20_bAcvCmprSpdLim "压缩机限速状态";
CM_ SG_ 512 BDCS20_bAcvExvPosnRchdMax "Exv最大限制位置状态";
CM_ SG_ 512 BDCS20_bAcvCtlForPRlf "泄压激活状态";
CM_ SG_ 512 BDCS20_bBlowrClnReq "鼓风机后运行状态";
CM_ SG_ 512 BDCS20_bBodyCtlrSleepAllwd "BDCS允许休眠的状态";
CM_ SG_ 512 BDCS20_bAcvFlapIniDoneFlg "风门初始化完成状态";
CM_ SG_ 512 BDCS20_bAirDefrstDibtnReq "吹窗请求状态";
CM_ SG_ 512 BDCS20_bAirFaceDibtnReq "吹脸请求状态";
CM_ SG_ 512 BDCS20_bAirFootDibtnReq "吹脚请求状态";
CM_ SG_ 512 BDCS20_StPerfEve "性能事件状态";
CM_ SG_ 512 BDCS20_ModeHvacThermReq "热管理模式请求状态";
CM_ SG_ 512 BDCS20_StCircHeatgThermMode "制热热管理模式";
CM_ SG_ 512 BDCS20_StRfgtCircThermMode "制冷热管理模式";
CM_ SG_ 512 BDCS20_StHumCtlEve "湿度等级状态";
CM_ SG_ 512 BDCS20_StPtThermMode "动力系统热管理模式";
CM_ SG_ 512 BDCS20_ModePwrDstnModeRaw "制冷制热分配模式";
CM_ SG_ 512 BDCS20_StEve "性能事件状态位";
CM_ SG_ 512 BDCS20_NrEvst "热管理状态机序号";
CM_ SG_ 512 BDCS20_UBlowrSpdReq "鼓风机风速电压请求";
CM_ SG_ 512 BDCS20_UBlowrSpdAct "鼓风机风速实际电压反馈";
CM_ SG_ 512 BDCS20_PwrWtrHeatrRawReq "PTC功率请求状态（未限制）";
CM_ SG_ 512 BDCS20_PwrWtrHeatrReq "PTC功率请求状态";
CM_ SG_ 512 BDCS20_PwrCmprLimIni "压缩机功率限制值";
CM_ SG_ 512 BDCS20_PwrWtrHeatrLim "PTC功率限制值";
CM_ SG_ 512 BDCS20_PctgPosnReq "模式风门位置请求";
CM_ SG_ 512 BDCS20_PCmprInletAct "压缩机吸气压力值";
CM_ SG_ 512 BDCS20_PctgBlowrSpdReq "鼓风机风速百分比请求";
CM_ SG_ 512 BDCS20_PCndsrOutlAct "压缩机排气压力值";
CM_ SG_ 512 BDCS20_RateCabinAccdnrCmdZone1 "主驾CV值";
CM_ SG_ 512 BDCS20_RateCabinAccdnrCmdZone2 "副驾CV值";
CM_ SG_ 512 BDCS20_NCmprReqLimdByP "压缩机转速限制请求";
CM_ SG_ 512 BDCS20_NCmprSatdReq "压缩机转速饱和请求";
CM_ SG_ 512 BDCS20_TFootDmdZone1 "主驾脚部目标温度请求";
CM_ SG_ 512 BDCS20_TFootDmdZone2 "副驾脚部目标温度请求";
CM_ SG_ 512 BDCS20_TFaceDmdZone1 "主驾脸部目标温度请求";
CM_ SG_ 512 BDCS20_TFaceDmdZone2 "副驾脸部目标温度请求";
CM_ SG_ 490 BDCS21_BrakeLightSts_F "制动灯故障信号（逻辑同1E6信号）";
CM_ SG_ 490 BDCS21_MsgCounter "E2E Profile2-CRC8H2F，Counter:0-15";
CM_ SG_ 490 BDCS21_Checksum "E2E Profile2-CRC8H2F
DataID list #76:192 166 222 28 90 164 24 8 238 119 48 73 49 231 95 140";
CM_ SG_ 564 BDCS10_AGS_Pos_Cmd "进气格栅角度控制命令";
CM_ SG_ 564 BDCS10_AGS_Cali_Cmd "AGS初始化标定信号";
CM_ SG_ 564 BDCS10_AGS_Curr_Limit_Cmd "AGS扭矩选择指令";
CM_ SG_ 564 BDCS10_FTWV_A_MoveEnable "FTWV_A开关使能请求";
CM_ SG_ 564 BDCS10_FTWV_B_MoveEnable "FTWV_B开关使能请求";
CM_ SG_ 564 BDCS10_EXV_B_MoveEnb "EXV_B使能请求";
CM_ SG_ 564 BDCS10_EWP_H_DefaultReq "暖风水泵节能模式请求";
CM_ SG_ 564 BDCS10_EXV_B_InitReq "EXV_B初始化状态请求";
CM_ SG_ 564 BDCS10_EWP_B_DefaultReq "电池水泵节能模式请求";
CM_ SG_ 564 BDCS10_EWP_M_DefaultRq "电驱水泵节能模式请求";
CM_ SG_ 564 BDCS10_FTWV_A_ReqMovePos "FTWV_A位置请求";
CM_ SG_ 564 BDCS10_FTWV_B_ReqMovePos "FTWV_B位置请求";
CM_ SG_ 564 BDCS10_EXV_B_PosReq "EXV_B位置请求";
CM_ SG_ 564 BDCS10_EWP_H_TRPMRq "暖风水泵目标转速";
CM_ SG_ 564 BDCS10_EWP_B_TRPMReq "电池水泵目标转速";
CM_ SG_ 564 BDCS10_EWP_M_TRPMReq "电驱水泵目标转速";
CM_ SG_ 565 EXV_B_LINRespErr "Communication Error Status";
CM_ SG_ 565 EXV_B_curInit_Stat "Initialization Status";
CM_ SG_ 565 EXV_B_Run_Stat "Run Status";
CM_ SG_ 565 EXV_B_Fault_Stat "Fault Status";
CM_ SG_ 565 EXV_B_CurPos "Current Position";
CM_ SG_ 565 EXV_B_Volt_Stat "Voltage Status";
CM_ SG_ 565 EXV_B_OvrTemp_Warn "Temperature Status";
CM_ SG_ 565 EWP_H_LINRespErr "Response Error
响应错误";
CM_ SG_ 565 EWP_B_LINRespErr "Response Error
响应错误";
CM_ SG_ 565 EWP_M_LINRespErr "Response Error
响应错误";
CM_ SG_ 565 FTWV_A_Rsp_Comm_Err "通讯错误";
CM_ SG_ 565 EWP_H_RPM_Target_Stat "Target RPM
目标转速";
CM_ SG_ 565 EWP_H_RPM_ActlVal_Stat "Actual RPM
真实转速";
CM_ SG_ 565 EWP_H_Volt_Stat "Current Voltage
当前电压";
CM_ SG_ 565 EWP_H_Temp_Stat "Current Temperature
当前温度";
CM_ SG_ 565 EWP_H_Curr_Stat "CurrentCurrent
当前电流";
CM_ SG_ 565 EWP_H_OverCurr_Error "Over Current Error
过流错误";
CM_ SG_ 565 EWP_H_DryRun_Error "DryRun Error
干转错误";
CM_ SG_ 565 EWP_H_SupVolt_Error "SupVolt Error
电压错误";
CM_ SG_ 565 EWP_H_Block_Error "Block Error
阻塞错误";
CM_ SG_ 565 EWP_H_OverTemp_Error "Over Temperature Error
过温错误(过温关断=1 过温降级=2）";
CM_ SG_ 565 EWP_B_OverTemp_Error "Over Temperature Error
过温错误(过温关断=1 过温降级=2）";
CM_ SG_ 565 EWP_M_OverTemp_Error "Over Temperature Error
过温错误(过温关断=1 过温降级=2）";
CM_ SG_ 565 FTWV_B_Rsp_Comm_Err "通讯错误";
CM_ SG_ 565 EWP_B_RPM_Target_Stat "Target RPM
目标转速";
CM_ SG_ 565 EWP_B_RPM_ActlVal_Stat "Actual RPM
真实转速";
CM_ SG_ 565 EWP_B_Volt_Stat "Current Voltage
当前电压";
CM_ SG_ 565 EWP_B_Temp_Stat "Current Temperature
当前温度";
CM_ SG_ 565 EWP_B_Curr_Stat "CurrentCurrent
当前电流";
CM_ SG_ 565 EWP_B_OverCurr_Error "Over Current Error
过流错误";
CM_ SG_ 565 EWP_B_DryRun_Error "DryRun Error
干转错误";
CM_ SG_ 565 EWP_B_SupVolt_Error "SupVolt Error
电压错误";
CM_ SG_ 565 EWP_B_Block_Error "Block Error
阻塞错误";
CM_ SG_ 565 EWP_M_RPM_Target_Stat "Target RPM
目标转速";
CM_ SG_ 565 EWP_M_RPM_ActlVal_Stat "Actual RPM
真实转速";
CM_ SG_ 565 EWP_M_Volt_Stat "Current Voltage
当前电压";
CM_ SG_ 565 EWP_M_Temp_Stat "Current Temperature
当前温度";
CM_ SG_ 565 EWP_M_Curr_Stat "CurrentCurrent
当前电流";
CM_ SG_ 565 EWP_M_OverCurr_Error "Over Current Error
过流错误";
CM_ SG_ 565 EWP_M_DryRun_Error "DryRun Error
干转错误";
CM_ SG_ 565 EWP_M_SupVolt_Error "SupVolt Error
电压错误";
CM_ SG_ 565 EWP_M_Block_Error "Block Error
阻塞错误";
CM_ SG_ 565 FTWV_A_Fault_Signal "报错信息信号";
CM_ SG_ 565 FTWV_A_VoltageErr "电压报错";
CM_ SG_ 565 FTWV_A_TempWarn "温度报错";
CM_ SG_ 565 FTWV_A_MotorStatus "五通阀A运行状态信号";
CM_ SG_ 565 FTWV_A_Rsp_Pos "五通阀A位置反馈信号";
CM_ SG_ 565 FTWV_B_Fault_Signal "报错信息信号";
CM_ SG_ 565 FTWV_B_VoltageErr "电压报错";
CM_ SG_ 565 FTWV_B_TempWarn "温度报错";
CM_ SG_ 565 FTWV_B_MotorStatus "五通阀B运行状态信号";
CM_ SG_ 565 FTWV_B_Rsp_Pos "五通阀B位置反馈信号";
CM_ SG_ 565 BDCS15_PChlrOutlTgt "Chiller出口目标压力";
CM_ SG_ 565 BDCS15_PCmprOutlTgt "压缩机出口目标压力";
CM_ SG_ 565 BDCS15_PEvprOutlTgt "蒸发器出口目标压力";
CM_ SG_ 565 BDCS15_TEdrvCooltInletTgt "电机进口目标水温";
CM_ SG_ 565 BDCS15_THeatCoreCooltInletTgt "暖风芯体目标进水温度";
CM_ SG_ 565 BDCS15_THVBatCooltInletTgt "电池目标进水温度";
CM_ SG_ 565 BDCS15_HPTMD_StHeatgMode "热泵热源模式";
CM_ SG_ 645 BDCS13_RLS_HUDBrightRawValue "HUD亮度值基数(实际亮度等于基数*系数)";
CM_ SG_ 645 BDCS13_RLS_HUDBrightnessSnrFault "亮度传感器故障状态";
CM_ SG_ 645 BDCS13_RLS_HUDBrightUnit "HUD亮度值精度系数";
CM_ SG_ 645 BDCS13_RLS_REP_Error "RLS通讯故障状态";
CM_ SG_ 645 BDCS13_RLS_VOLT_Error "检测电池电压错误";
CM_ SG_ 645 BDCS13_RLS_RQ_WiperSPD "雨刮速度";
CM_ SG_ 645 RATS1_DFGLS_ButtonSoundRequest "后扶手触摸座椅开关按键提示音";
CM_ SG_ 645 DGM_IntelligentProtectionSt "智能防护开关状态";
CM_ SG_ 645 DGM_AutoSWSts "天幕自动调节开关状态";
CM_ SG_ 645 BDCS13_CO2_State "CO2传感器状态";
CM_ SG_ 645 BDCS13_CO2_DensitySts "CO2提示";
CM_ SG_ 645 BDCS13_IN_TrunkSWStatus "尾门内开关状态";
CM_ SG_ 645 BDCS13_CO2_Value "CO2值";
CM_ SG_ 645 BDCS13_RLS_Rain_state "有雨状态";
CM_ SG_ 645 BDCS13_OUT_TrunkSWStatus "尾门外开关状态";
CM_ SG_ 645 BDCS13_TrunkDrivingStatus "尾门锁解锁驱动状态";
CM_ SG_ 645 BDCS13_SRM_FaultMessage "SRM故障信息";
CM_ SG_ 661 BDCS11_AcFilter_SOH "空调滤芯寿命有效值";
CM_ SG_ 661 BDCS11_AC_EAC_Command "压缩机使能信号";
CM_ SG_ 661 BDCS11_AC_PTC_Request "PTC开启请求";
CM_ SG_ 661 BDCS11_AC_PTC_Level "PTC档位信号(预留)";
CM_ SG_ 661 BDCS11_PTC_TargTemp "PTC目标温度";
CM_ SG_ 661 BDCS11_AcFilter_SOH_Valid "空调滤芯寿命有效标志位";
CM_ SG_ 661 BDCS11_PumpHTarSpdValid "PTC水泵转速请求有效性";
CM_ SG_ 661 BDCS11_AC_EAC_SpeedSet "压缩机转速要求";
CM_ SG_ 661 BDCS11_PumpHTarSpd "PTC水泵转速请求";
CM_ SG_ 661 BDCS11_AC_FanGearPwmReq "冷却风扇PWM控制";
CM_ SG_ 661 BDCS11_FogRiskLvl "起雾风险等级";
CM_ SG_ 661 BDCS11_AC_FanGearPwmReqV "冷却风扇PWM控制有效性";
CM_ SG_ 661 BDCS11_AC_EAC_PowerLimit "压缩机功率限值";
CM_ SG_ 661 BDCS11_PM25WorkReq "车内PM2.5状态控制请求";
CM_ SG_ 661 BDCS11_PM25RealSts "车内PM2.5当前工作状态";
CM_ SG_ 661 BDCS11_AC_PowerReq "空调功率请求值";
CM_ SG_ 661 BDCS11_ACMaxSts "最大制冷状态";
CM_ SG_ 661 BDCS11_HeatMaxSts "最大制热状态";
CM_ SG_ 661 BDCS11_AirCleanSts "空气净化功能";
CM_ SG_ 661 BDCS11_ECONModeSts "空调ECO经济模式开关";
CM_ SG_ 661 BDCS11_BlowModSts "空调出风模式";
CM_ SG_ 661 BDCS11_PMAirInQLevel "室内空气质量等级";
CM_ SG_ 661 BDCS11_CabModeSts "乘员舱热管理模式";
CM_ SG_ 661 BDCS11_HeatMngtFctLim "乘员舱热管理功能限制";
CM_ SG_ 661 BDCS11_BatModeSts "电池热管理模式";
CM_ SG_ 661 BDCS11_PwrModeSts "动力系统热管理模式";
CM_ SG_ 661 BDCS11_ELV1Pos "电磁阀1位置";
CM_ SG_ 661 BDCS11_ELV1Flt "电磁阀1故障";
CM_ SG_ 661 BDCS11_ELV2Pos "电磁阀2位置";
CM_ SG_ 661 BDCS11_ELV2Flt "电磁阀2故障";
CM_ SG_ 661 BDCS11_ELV3Pos "电磁阀3位置";
CM_ SG_ 661 BDCS11_ELV3Flt "电磁阀3故障";
CM_ SG_ 661 BDCS11_ELV4Pos "电磁阀4位置";
CM_ SG_ 661 BDCS11_ELV4Flt "电磁阀4故障";
CM_ SG_ 661 BDCS11_ComLost_EXV1 "BDCS与EXV1通讯丢失";
CM_ SG_ 661 BDCS11_ComLost_EXV_H "BDCS与EXV-H通讯丢失";
CM_ SG_ 661 BDCS11_EXV1Flt "电池EXV故障";
CM_ SG_ 661 BDCS11_EXV_H_Flt "乘员舱EXV故障";
CM_ SG_ 661 BDCS11_BlowrRlySts "空调鼓风机继电器状态";
CM_ SG_ 661 BDCS11_HeatingWireSts "前风挡双目摄像头加热丝状态";
CM_ SG_ 661 BDCS11_EXV1EnableReq "电池EXV使能请求";
CM_ SG_ 661 BDCS11_EXV1CalibReq "电池EXV初始化请求";
CM_ SG_ 661 BDCS11_HPVTMSModeSts "热泵热管理模式状态";
CM_ SG_ 661 BDCS11_EXV1ValCmd "电池EXV目标开度";
CM_ SG_ 661 BDCS11_EXV_H_ValCmd "乘员舱EXV阀目标开度";
CM_ SG_ 661 BDCS11_UBlowrSpdReq "空调鼓风机目标电压";
CM_ SG_ 661 BDCS11_UBlowrSpdAct "空调鼓风机实际电压";
CM_ SG_ 661 BDCS11_EXV1ActVal "电池EXV实际开度";
CM_ SG_ 661 BDCS11_OilHeatingSwEnable "燃油辅热开关使能状态";
CM_ SG_ 661 BDCS11_OilHeatingFuelLevel "燃油液位";
CM_ SG_ 661 BDCS11_EXV_H_ActVal "乘员舱EXV实际开度";
CM_ SG_ 661 BDCS11_OilHeatingWarn "燃油加热器开启失败报警提示";
CM_ SG_ 661 BDCS11_OilHeatingWorkSts "燃油加热器工作状态显示";
CM_ SG_ 661 BDCS11_OilHeatingSwSts "燃油辅热开关反馈";
CM_ SG_ 661 BDCS11_TWV1ActSaveReq "电池TWV位置存储请求";
CM_ SG_ 661 BDCS11_TWV1CalibReq "电池TWV自学习请求";
CM_ SG_ 661 BDCS11_TWV1ModeSts "电池TWV模式状态反馈";
CM_ SG_ 661 BDCS11_TWV1ValCmd "电池TWV目标开度";
CM_ SG_ 661 BDCS11_TWV1ActVal "电池TWV实际位置";
CM_ SG_ 661 BDCS11_CLMSwVersS "CLM次软件版本号";
CM_ SG_ 661 BDCS11_CLMSwVersM "CLM主软件版本号";
CM_ SG_ 661 BDCS11_PumpHActSpd "PTC水泵实际转速";
CM_ SG_ 661 BDCS11_EXV1InitSts "电池EXV初始化状态";
CM_ SG_ 661 BDCS11_EXV_H_InitSts "乘员舱EXV初始化状态";
CM_ SG_ 661 BDCS11_NVMSts "空调存储单元存储状态";
CM_ SG_ 661 BDCS11_ComLost_TWV1 "BDCS与TWV1通讯丢失";
CM_ SG_ 661 BDCS11_TWV1Flt "电池TWV故障";
CM_ SG_ 664 BDCS12_InsideTemp "室内温度值";
CM_ SG_ 664 BDCS12_InsideTempValid "室内温度值有效性";
CM_ SG_ 664 BDCS12_OutletTempValid "出风口温度值有效性";
CM_ SG_ 664 BDCS12_UncoolReason "制冷不响应原因";
CM_ SG_ 664 BDCS12_UnheatReason "制热不响应原因";
CM_ SG_ 664 BDCS12_OutletTemp "出风口温度值";
CM_ SG_ 664 BDCS12_SensorFailCode "传感器类故障";
CM_ SG_ 664 BDCS12_ThermalSts "热管理状态";
CM_ SG_ 664 BDCS12_DisplayInfo "空调热管理系统信息显示";
CM_ SG_ 664 BDCS12_EVAPTempValid "蒸发器温度值有效性";
CM_ SG_ 664 BDCS12_InCarClimateSystemFault "乘员舱空调系统故障";
CM_ SG_ 664 BDCS12_BatteryThermalSystemFault "电池热管理系统故障";
CM_ SG_ 664 BDCS12_EVAPTemp "蒸发器温度值";
CM_ SG_ 664 BDCS12_AC_PTC_PowerLimit "PTC功率限值";
CM_ SG_ 664 BDCS12_AC_PTC_PowerSet "PTC功率请求";
CM_ SG_ 664 BDCS12_LFaceOutletTemp "左侧吹脸出风温度";
CM_ SG_ 664 BDCS12_LFootOutletTemp "左侧吹脚出风温度";
CM_ SG_ 664 BDCS12_RFaceOutletTemp "右侧吹脸出风温度";
CM_ SG_ 664 BDCS12_RFootOutletTemp "右侧吹脚出风温度";
CM_ SG_ 664 BDCS12_FragranceType_Position_1 "位置1香型";
CM_ SG_ 664 BDCS12_FragranceType_Position_2 "位置2香型";
CM_ SG_ 664 BDCS12_FragranceType_Position_3 "位置3香型";
CM_ SG_ 664 BDCS12_FM_FragrancePositionSts "香氛位置设置状态";
CM_ SG_ 664 BDCS12_FM_FragranceWorkingSts "香氛工作状态";
CM_ SG_ 664 BDCS12_FM_FragranceConcentration "香氛浓度";
CM_ SG_ 664 BDCS12_LEAOSts "左电动出风口工作状态";
CM_ SG_ 664 BDCS12_AQSCycleSts "AQS内外循环状态";
CM_ SG_ 664 BDCS12_AQSValue "AQS空气质量";
CM_ SG_ 664 BDCS12_FragranceFaultSts "香氛故障状态";
CM_ SG_ 664 BDCS12_PM25FltSta "PM2.5传感器故障状态";
CM_ SG_ 664 BDCS12_SolarError "阳光传感器故障";
CM_ SG_ 664 BDCS12_HumidTemp_Error "温湿度传感器故障状态";
CM_ SG_ 664 BDCS12_LeSunshineSnsrT "左阳光传感器值";
CM_ SG_ 664 BDCS12_RiSunshineSnsrT "右阳光传感器值";
CM_ SG_ 664 BDCS12_Humid "空气湿度";
CM_ SG_ 664 BDCS12_DefTemperature "挡风玻璃温度";
CM_ SG_ 664 BDCS12_REAOSts "右电动出风口工作状态";
CM_ SG_ 664 BDCS12_EAOCtrlVaild "电动出风口控制有效性";
CM_ SG_ 664 BDCS12_CoolantFillingSta "冷却液加注模式状态";
CM_ SG_ 664 BDCS12_TempDewPoint "露点温度";
CM_ SG_ 664 BDCS12_LPTSnsrP "低压压力值";
CM_ SG_ 664 BDCS12_HPSnsrP "高压压力值";
CM_ SG_ 664 BDCS12_EvprTempTar "蒸发器目标温度值";
CM_ SG_ 664 BDCS12_LPTSnsrT "低压温度值";
CM_ SG_ 664 BDCS12_FL_RLMotorPos "左前风门左右角度";
CM_ SG_ 664 BDCS12_FL_UDMotorPos "左前风门上下角度";
CM_ SG_ 664 BDCS12_CL_RLMotorPos "左中风门左右角度";
CM_ SG_ 664 BDCS12_CL_UDMotorPos "左中风门上下角度";
CM_ SG_ 664 BDCS12_CR_RLMotorPos "右中风门左右角度";
CM_ SG_ 664 BDCS12_CR_UDMotorPos "右中风门上下角度";
CM_ SG_ 664 BDCS12_FR_RLMotorPos "右前风门左右角度";
CM_ SG_ 664 BDCS12_FR_UDMotorPos "右前风门上下角度";
CM_ SG_ 664 BDCS12_LeftExtFanSpdCmd "室外左风扇目标转速";
CM_ SG_ 664 BDCS12_HPSnsrT "高压温度值";
CM_ SG_ 664 BDCS12_RightExtFanSpdCmd "室外右风扇目标转速";
CM_ SG_ 664 BDCS12_PumpHFlt "PTC水泵故障";
CM_ SG_ 664 BDCS12_LFaceOutletTempFlt "左侧吹脸出风温度传感器故障";
CM_ SG_ 664 BDCS12_LFootOutletTempFlt "左侧吹脚出风温度传感器故障";
CM_ SG_ 664 BDCS12_RFaceOutletTempFlt "右侧吹脸出风温度传感器故障";
CM_ SG_ 664 BDCS12_RFootOutletTempFlt "右侧吹脚出风温度传感器故障";
CM_ SG_ 664 BDCS12_WindSpdAutSts "风速自动状态";
CM_ SG_ 664 BDCS12_BlowModAutSts "出风模式自动状态";
CM_ SG_ 664 BDCS12_LPTSnsrPEvpr "蒸发器出口低压压力值";
CM_ SG_ 664 BDCS12_LPTSnsrTEvpr "蒸发器出口低压温度值";
CM_ SG_ 664 BDCS12_IHE_OutTemp "室内换热器出口温度";
CM_ SG_ 664 BDCS12_OHE_OutTemp "室外换热器出口温度";
CM_ SG_ 664 BDCS12_WCC_OutTemp "水冷冷凝器出口温度";
CM_ SG_ 664 BDCS12_Chiller_OutTemp "chiller出口温度";
CM_ SG_ 664 BDCS12_IHE_OutTempFlt "室内换热器出口温度传感器故障";
CM_ SG_ 664 BDCS12_OHE_OutTempFlt "室外换热器出口温度传感器故障";
CM_ SG_ 664 BDCS12_WCC_OutTempFlt "水冷冷凝器出口温度传感器故障";
CM_ SG_ 664 BDCS12_Chiller_OutTempFlt "chiller出口温度传感器故障";
CM_ SG_ 664 BDCS12_LeMixThrCmd "左温度混合风门开度";
CM_ SG_ 664 BDCS12_LeHybThrMotFlt "左温度风门电机故障";
CM_ SG_ 664 BDCS12_RiMixThrCmd "右温度混合风门开度";
CM_ SG_ 664 BDCS12_RiHybThrMotFlt "右温度风门电机故障";
CM_ SG_ 664 BDCS12_CycleThrCmd "内外循环风门开度";
CM_ SG_ 664 BDCS12_CycleMotFlt "内外循环电机故障";
CM_ SG_ 664 BDCS12_ModThrCmd "模式风门开度";
CM_ SG_ 664 BDCS12_ModThrMotFlt "模式风门电机故障";
CM_ SG_ 664 BDCS12_BSOFverBSW "BDCS底层版本号";
CM_ SG_ 664 BDCS12_VerTMSApp "热管理应用层版本号";
CM_ SG_ 664 BDCS12_VerTMSCal "热管理标定版本号";
CM_ SG_ 664 BDCS12_TMSFltRollgNum "热管理故障码代号";
CM_ SG_ 664 BDCS12_TMSFltRollgNumHistory "热管理当前故障总数";
CM_ SG_ 670 BDCS10_AC_ACSts "AC请求状态";
CM_ SG_ 670 BDCS10_AC_CycleSts "内外循环状态";
CM_ SG_ 670 BDCS10_AC_BlowerSpdSts "风速档位状态";
CM_ SG_ 670 BDCS10_AC_OnOffSts "空调开启状态";
CM_ SG_ 670 BDCS10_AC_VentSts "吹面模式";
CM_ SG_ 670 BDCS10_AC_VentilationSts "空调通风状态";
CM_ SG_ 670 BDCS10_AC_WindowSts "吹窗模式";
CM_ SG_ 670 BDCS10_AC_AnionSts "负离子工作状态";
CM_ SG_ 670 BDCS10_AC_OutsideTempValid "室外温度值有效性";
CM_ SG_ 670 BDCS10_AC_AutoSts "auto状态";
CM_ SG_ 670 BDCS10_AC_FootSts "吹脚模式";
CM_ SG_ 670 BDCS10_AC_DualSw "双区空调开关状态";
CM_ SG_ 670 BDCS10_AC_PM25_ValueValid "PM2.5值有效性";
CM_ SG_ 670 BDCS10_AC_PM25_Value "PM2.5值";
CM_ SG_ 670 BDCS10_AC_OutsideTemp "室外温度值";
CM_ SG_ 670 BDCS10_AC_LHTemp "主驾设定温度";
CM_ SG_ 670 BDCS10_AC_RHTemp "副驾设定温度";
CM_ SG_ 677 BDCS8_FL_Pos_ManualAdjust_Sts "主驾座椅位置手动调节状态";
CM_ SG_ 677 BDCS8_DriverSeatHorizontalPos "主驾座椅水平位置";
CM_ SG_ 677 BDCS8_DriverSeatVerticalHeight "主驾座椅垂直高度";
CM_ SG_ 677 BDCS8_FR_Pos_ManualAdjust_Sts "副驾座椅位置手动调节状态";
CM_ SG_ 677 BDCS8_DriverCushionTiltPos "主驾座椅坐垫倾斜位置";
CM_ SG_ 677 BDCS8_FR_SeatEasygetON_OFF_Sts "右前座椅便捷进出设置状态";
CM_ SG_ 677 BDCS8_Drive_ODS "Drive ODS  status on CAN Bus
主驾占位传感器状态";
CM_ SG_ 677 BDCS8_FR_SeatPosMemory_Sts "副驾位置记忆成功状态";
CM_ SG_ 677 BDCS8_FR_SeatPosLoad_Sts "副驾位置加载成功状态";
CM_ SG_ 677 BDCS8_FL_SeatEasygetON_OFF_Sts "左前座椅便捷进出设置状态";
CM_ SG_ 677 BDCS8_FL_SeatPosLoad_Sts "主驾位置加载成功状态";
CM_ SG_ 677 BDCS8_FL_SeatPosMemory_Sts "主驾位置记忆成功状态";
CM_ SG_ 677 BDCS8_Driver_Heating_Sts "主驾座椅加热状态";
CM_ SG_ 677 BDCS8_Passenger_Heating_Sts "副驾座椅加热状态";
CM_ SG_ 677 BDCS8_Driver_Venting_Sts "主驾座椅通风状态";
CM_ SG_ 677 BDCS8_Passenger_Venting_Sts "副驾座椅通风状态";
CM_ SG_ 677 BDCS8_Driver_LHFailure "主驾座椅加热故障";
CM_ SG_ 677 BDCS8_Passenger_RHFailure "副驾座椅加热故障";
CM_ SG_ 677 BDCS8_Driver_LVFailure "主驾座椅通风故障";
CM_ SG_ 677 BDCS8_Passenger_RVFailure "副驾座椅通风故障";
CM_ SG_ 677 BDCS8_Driver_BackrestAngle "主驾座椅靠背角度";
CM_ SG_ 677 BDCS8_Passenger_SeatHorizontalPos "副驾座椅水平位置";
CM_ SG_ 677 BDCS8_Passenger_SeatVerticalHeight "副驾座椅垂直高度";
CM_ SG_ 677 BDCS8_Passenger_BackrestAngle "副驾座椅靠背角度";
CM_ SG_ 677 BDCS8_Passenger_LegsupporPos "副驾座椅腿托位置";
CM_ SG_ 677 BDCS8_Driver_MassageModeSts "主驾座椅按摩模式状态";
CM_ SG_ 677 BDCS8_Driver_MassageLevelSts "主驾座椅按摩强度状态";
CM_ SG_ 677 BDCS8_Passenger_MassageModeSts "副驾座椅按摩模式状态";
CM_ SG_ 677 BDCS8_Passenger_MassageLevelSts "副驾座椅按摩强度状态";
CM_ SG_ 677 BDCS8_Driver_Massage_Sts "主驾腰托动作状态反馈";
CM_ SG_ 677 BDCS8_Passenger_MassageSts "副驾腰托动作状态反馈";
CM_ SG_ 678 BDCS9_RL_Heating_Sts "后排左侧座椅加热状态";
CM_ SG_ 678 BDCS9_RR_Heating_Sts "后排右侧座椅加热状态";
CM_ SG_ 678 BDCS9_RL_Venting_Sts "后排左侧座椅通风状态（预留）";
CM_ SG_ 678 BDCS9_RR_Venting_Sts "后排右侧座椅通风状态（预留）";
CM_ SG_ 678 BDCS9_RLVentilating_Failure "后排左侧通风故障";
CM_ SG_ 678 BDCS9_RRVentilating_Failure "后排右侧通风故障";
CM_ SG_ 678 BDCS9_RLBackAngleRelay_Failure "后排左侧调节故障";
CM_ SG_ 678 BDCS9_RRBackAngleRelay_Failure "后排右侧调节故障";
CM_ SG_ 678 BDCS9_FR_ZeroGravity_Sts "副驾零重力座椅调节状态反馈";
CM_ SG_ 678 BDCS9_RL_MassageLevel_Fdb "左后座椅按摩强度反馈信号";
CM_ SG_ 678 BDCS9_RL_LumbarActionSts_Fdb "左后腰托动作状态反馈信号";
CM_ SG_ 678 BDCS9_RL_MassageMode_Fdb "左后座椅按摩模式反馈信号";
CM_ SG_ 678 BDCS9_RR_MassageLevel_Fdb "右后座椅按摩强度反馈信号";
CM_ SG_ 678 BDCS9_RR_LumbarActionSts_Fdb "右后腰托动作状态反馈信号";
CM_ SG_ 678 BDCS9_RR_MassageMode_Fdb "右后座椅按摩模式反馈信号";
CM_ SG_ 678 BDCS9_FridgeHeat_TempSts "车载冰箱保温模式温度反馈";
CM_ SG_ 678 BDCS9_FridgeMod_Sts "车载冰箱运行模式反馈信号";
CM_ SG_ 678 BDCS9_FridgeTemp_KeepSts "车载冰箱温度保持状态反馈（锁车维持）信号";
CM_ SG_ 678 BDCS9_FridgeCool_TempSts "车载冰箱冷藏模式温度反馈";
CM_ SG_ 678 BDCS9_RC_FridgeDoorSts "车载冰箱门状态";
CM_ SG_ 678 BDCS9_RC_FridgeErSts "车载车载冰箱故障标志位";
CM_ SG_ 678 BDCS9_RmtFridgeReqFailCondition "远程开冰箱失败原因反馈";
CM_ SG_ 678 BDCS9_RL_Heating_Failure "后排左侧加热故障";
CM_ SG_ 678 BDCS9_RR_Heating_Failure "后排右侧加热故障";
CM_ SG_ 678 BDCS9_Passenger_LegsupporLength "副驾座椅腿托长度位置";
CM_ SG_ 680 PTC1_ClntOtltOverTemProtn "冷却液出口过温保护";
CM_ SG_ 680 PTC1_VbatVtgUnstable "电池电压不稳定";
CM_ SG_ 680 PTC1_VbatVtgSnsrFlt "电池电压传感器故障";
CM_ SG_ 680 PTC1_PCBTempSnsrFlt "PCB温度传感器故障";
CM_ SG_ 680 PTC1_HiCrntSnsrFlt "电流传感器故障";
CM_ SG_ 680 PTC1_PCBOverTempProtn "PCB过温保护";
CM_ SG_ 680 PTC1_WrkngSts "PTC工作状态";
CM_ SG_ 680 PTC1_CoreOrIGBTOpenErr "IGBT或芯体开路";
CM_ SG_ 680 PTC1_IGBTShrtErr "IGBT短路";
CM_ SG_ 680 PTC1_HVOverCrntProtn "高压过流保护";
CM_ SG_ 680 PTC1_VbatVtgProtn "电池电压异常保护";
CM_ SG_ 680 PTC1_HVDisconnectProtn "高压断开保护";
CM_ SG_ 680 PTC1_IGBTOverTemProtn "IGBT过温保护";
CM_ SG_ 680 PTC1_ClntInltOverTemProtn "冷却液进口过温保护";
CM_ SG_ 680 PTC1_MmryFlt "存储器故障";
CM_ SG_ 680 PTC1_IGBTTemSnsrFlt "IGBT 温度传感器故障";
CM_ SG_ 680 PTC1_ClntInltTemSnsrFlt "冷却液进口温度传感器故障";
CM_ SG_ 680 PTC1_ClntOtltTemSnsrFlt "冷却液出口温度传感器故障";
CM_ SG_ 680 PTC1_CommError "通信错误";
CM_ SG_ 680 PTC1_PowerConsumption "PTC功率消耗";
CM_ SG_ 680 PTC1_ActuHiCrnt "实际高压电流";
CM_ SG_ 680 PTC1_ClntTempInlt "冷却液进口温度";
CM_ SG_ 680 PTC1_ClntTempOtlt "冷却液出口温度";
CM_ SG_ 680 PTC1_IGBTTem "IGBT温度";
CM_ SG_ 680 EACP1_OPState "缺相状态位";
CM_ SG_ 680 EACP1_OutputPwr "压缩机消耗功率";
CM_ SG_ 680 EACP1_InputCurr "输入电流";
CM_ SG_ 680 EACP1_MotorTemp "MOTOR温度";
CM_ SG_ 680 EACP1_ACPSpeed "压缩机转速";
CM_ SG_ 680 EACP1_InputVolt "输入电压";
CM_ SG_ 680 EACP1_BaseState "基本状态位";
CM_ SG_ 680 EACP1_OVState "过压状态位";
CM_ SG_ 680 EACP1_LVState "欠压状态位";
CM_ SG_ 680 EACP1_OTState "过温状态位";
CM_ SG_ 680 EACP1_OCState "过流状态位";
CM_ SG_ 680 EACP1_ComState "通讯状态位";
CM_ SG_ 680 EACP1_LRState "堵转状态位";
CM_ SG_ 680 EACP1_OSState "过速状态位";
CM_ SG_ 680 EACP1_PowerOffState "掉电状态位";
CM_ SG_ 680 EACP1_CurrSState "电流采样状态位";
CM_ SG_ 680 EACP1_COVState "电压超高状态位";
CM_ SG_ 680 EACP1_FailGrade "故障级别位";
CM_ SG_ 680 EACP1_PhaseCurr "相电流";
CM_ SG_ 807 BDCS7_Odometer "里程同步信息";
CM_ SG_ 807 BDCS7_On_120minTime "ON（120min）模式计时";
CM_ SG_ 857 BDCS_OTA_DoorLockCmd "车门控制命令";
CM_ SG_ 857 BDCS_OTA_FLWindowsCtrl "控制左前车窗动作";
CM_ SG_ 857 BDCS_OTA_FRWindowsCtrl "控制右前车窗动作";
CM_ SG_ 857 BDCS_OTA_RLWindowsCtrl "控制左后车窗动作";
CM_ SG_ 857 BDCS_OTA_RRWindowsCtrl "控制右后车窗动作";
CM_ SG_ 857 BDCS_OTA_TrunkLockSts "后背门锁状态（是否电动尾门，该信号均作为提示尾门是否开启）";
CM_ SG_ 857 BDCS_OTA_HoodAjarSts "前舱盖开闭状态";
CM_ SG_ 857 BDCS_OTA_AlarmMode "OTA车身防盗状态";
CM_ SG_ 938 BDCS19_AC_ClmttSts_ChgTrg "空调开启状态（用户设置存储）";
CM_ SG_ 938 BDCS19_AC_ClmttSts_ClmtOffTrg "空调开启状态（空调关机存储）";
CM_ SG_ 938 BDCS19_AC_ClmttSts_SlpTrg "空调开启状态（控制器休眠存储）";
CM_ SG_ 938 BDCS19_AC_ACSts_ChgTrg "AC请求状态（用户设置存储）";
CM_ SG_ 938 BDCS19_AC_ACSts_ClmtOffTrg "AC请求状态（空调关机存储）";
CM_ SG_ 938 BDCS19_AC_ACSts_SlpTrg "AC请求状态（控制器休眠存储）";
CM_ SG_ 938 BDCS19_AC_AutoSts_ChgTrg "Auto请求状态（用户设置存储）";
CM_ SG_ 938 BDCS19_AC_AutoSts_ClmtOffTrg "Auto请求状态（空调关机存储）";
CM_ SG_ 938 BDCS19_AC_AutoSts_SlpTrg "Auto请求状态（控制器休眠存储）";
CM_ SG_ 938 BDCS19_AC_WinDefrstSts_ChgTrg "一键前除霜状态（用户设置存储）";
CM_ SG_ 938 BDCS19_AC_WinDefrstSts_ClmtOffTrg "一键前除霜状态（空调关机存储）";
CM_ SG_ 938 BDCS19_AC_WinDefrstSts_SlpTrg "一键前除霜状态（控制器休眠存储）";
CM_ SG_ 938 BDCS19_AC_ACMaxSts_ChgTrg "最大制冷状态（用户设置存储）";
CM_ SG_ 938 BDCS19_AC_ACMaxSts_ClmtOffTrg "最大制冷状态（空调关机存储）";
CM_ SG_ 938 BDCS19_AC_ACMaxSts_SlpTrg "最大制冷状态（控制器休眠存储）";
CM_ SG_ 938 BDCS19_AC_DualReq_ChgTrg "双区空调开关状态（用户设置存储）";
CM_ SG_ 938 BDCS19_AC_RecircCycleSts_ChgTrg "内外循环状态（用户设置存储）";
CM_ SG_ 938 BDCS19_AC_RecircCycleSts_ClmtOffTrg "内外循环状态（空调关机存储）";
CM_ SG_ 938 BDCS19_AC_RecircCycleSts_SlpTrg "内外循环状态（控制器休眠存储）";
CM_ SG_ 938 BDCS19_AC_DualReq_ClmtOffTrg "双区空调开关状态（空调关机存储）";
CM_ SG_ 938 BDCS19_AC_DualReq_SlpTrg "双区空调开关状态（控制器休眠存储）";
CM_ SG_ 938 BDCS19_AC_DrvTempReq_ChgTrg "主驾设定温度（用户设置存储）";
CM_ SG_ 938 BDCS19_AC_DrvTempReq_ClmtOffTrg "主驾设定温度（空调关机存储）";
CM_ SG_ 938 BDCS19_AC_DrvTempReq_SlpTrg "主驾设定温度（控制器休眠存储）";
CM_ SG_ 938 BDCS19_AC_PassTempReq_ChgTrg "副驾设定温度（用户设置存储）";
CM_ SG_ 938 BDCS19_AC_PassTempReq_ClmtOffTrg "副驾设定温度（空调关机存储）";
CM_ SG_ 938 BDCS19_AC_PassTempReq_SlpTrg "副驾设定温度（控制器休眠存储）";
CM_ SG_ 938 BDCS19_AC_BlowerSpdLvl_ChgTrg "风速档位状态（用户设置存储）";
CM_ SG_ 938 BDCS19_AC_BlowerSpdLvl_ClmtOffTrg "风速档位状态（空调关机存储）";
CM_ SG_ 938 BDCS19_AC_BlowerSpdLvl_SlpTrg "风速档位状态（控制器休眠存储）";
CM_ SG_ 938 BDCS19_AC_AirOutletMod_ChgTrg "空调出风模式（用户设置存储）";
CM_ SG_ 938 BDCS19_AC_AirOutletMod_ClmtOffTrg "空调出风模式（空调关机存储）";
CM_ SG_ 938 BDCS19_AC_AirOutletMod_SlpTrg "空调出风模式（控制器休眠存储）";
CM_ SG_ 938 BDCS19_AC_ECONMod_ChgTrg "空调ECO经济模式（用户设置存储）";
CM_ SG_ 938 BDCS19_AC_ECONMod_ClmtOffTrg "空调ECO经济模式（空调关机存储）";
CM_ SG_ 938 BDCS19_AC_ECONMod_SlpTrg "空调ECO经济模式（控制器休眠存储）";
CM_ SG_ 938 BDCS19_AC_AirCleanSts_ChgTrg "空气净化功能（用户设置存储）";
CM_ SG_ 938 BDCS19_AC_AirCleanSts_ClmtOffTrg "空气净化功能（空调关机存储）";
CM_ SG_ 938 BDCS19_AC_AirCleanSts_SlpTrg "空气净化功能（控制器休眠存储）";
CM_ SG_ 938 BDCS19_AC_AnionSts_ChgTrg "负离子工作状态（用户设置存储）";
CM_ SG_ 938 BDCS19_AC_AnionSts_ClmtOffTrg "负离子工作状态（空调关机存储）";
CM_ SG_ 938 BDCS19_AC_AnionSts_SlpTrg "负离子工作状态（控制器休眠存储）";
CM_ SG_ 938 BDCS19_AC_FrgrcSts_ChgTrg "香氛工作状态（用户设置存储）";
CM_ SG_ 938 BDCS19_AC_FrgrcSts_ClmtOffTrg "香氛工作状态（空调关机存储）";
CM_ SG_ 938 BDCS19_AC_FrgrcSts_SlpTrg "香氛工作状态（控制器休眠存储）";
CM_ SG_ 938 BDCS19_AC_FrgrcConctn_ChgTrg "香氛浓度（用户设置存储）";
CM_ SG_ 938 BDCS19_AC_FrgrcConctn_ClmtOffTrg "香氛浓度（空调关机存储）";
CM_ SG_ 938 BDCS19_AC_FrgrcConctn_SlpTrg "香氛浓度（控制器休眠存储）";
CM_ SG_ 938 BDCS19_AC_FrgrcPosn_ChgTrg "香氛位置设置状态（用户设置存储）";
CM_ SG_ 938 BDCS19_AC_FrgrcPosn_ClmtOffTrg "香氛位置设置状态（空调关机存储）";
CM_ SG_ 938 BDCS19_AC_FrgrcPosn_SlpTrg "香氛位置设置状态（控制器休眠存储）";
CM_ SG_ 938 BDCS19_AC_FrgrcPosn1Type_ChgTrg "位置1香型（用户设置存储）";
CM_ SG_ 938 BDCS19_AC_FrgrcPosn1Type_ClmtOffTrg "位置1香型（空调关机存储）";
CM_ SG_ 938 BDCS19_AC_FrgrcPosn1Type_SlpTrg "位置1香型（控制器休眠存储）";
CM_ SG_ 938 BDCS19_AC_FrgrcPosn2Type_ChgTrg "位置2香型（用户设置存储）";
CM_ SG_ 938 BDCS19_AC_FrgrcPosn2Type_ClmtOffTrg "位置2香型（空调关机存储）";
CM_ SG_ 938 BDCS19_AC_FrgrcPosn2Type_SlpTrg "位置2香型（控制器休眠存储）";
CM_ SG_ 938 BDCS19_AC_FrgrcPosn3Type_ChgTrg "位置3香型（用户设置存储）";
CM_ SG_ 938 BDCS19_AC_FrgrcPosn3Type_ClmtOffTrg "位置3香型（空调关机存储）";
CM_ SG_ 938 BDCS19_AC_FrgrcPosn3Type_SlpTrg "位置3香型（控制器休眠存储）";
CM_ SG_ 938 BDCS19_EAO_FL_RLMotPosn_ChgTrg "左前风门左右角度（用户设置存储）";
CM_ SG_ 938 BDCS19_EAO_FL_RLMotPosn_ClmtOffTrg "左前风门左右角度空调关机存储）";
CM_ SG_ 938 BDCS19_EAO_FL_RLMotPosn_SlpTrg "左前风门左右角度（控制器休眠存储）";
CM_ SG_ 938 BDCS19_EAO_FL_UDMotPosn_ChgTrg "左前风门上下角度用户设置存储）";
CM_ SG_ 938 BDCS19_EAO_FL_UDMotPosn_ClmtOffTrg "左前风门上下角度（空调关机存储）";
CM_ SG_ 938 BDCS19_EAO_FL_UDMotPosn_SlpTrg "左前风门上下角度（控制器休眠存储）";
CM_ SG_ 938 BDCS19_EAO_CL_RLMotPosn_ChgTrg "左中风门左右角度（用户设置存储）";
CM_ SG_ 938 BDCS19_EAO_CL_RLMotPosn_ClmtOffTrg "左中风门左右角度（空调关机存储）";
CM_ SG_ 938 BDCS19_EAO_CL_RLMotPosn_SlpTrg "左中风门左右角度（控制器休眠存储）";
CM_ SG_ 938 BDCS19_EAO_CL_UDMotPosn_ChgTrg "左中风门上下角度（用户设置存储）";
CM_ SG_ 938 BDCS19_EAO_CL_UDMotPosn_ClmtOffTrg "左中风门上下角度（空调关机存储）";
CM_ SG_ 938 BDCS19_EAO_CL_UDMotPosn_SlpTrg "左中风门上下角度（控制器休眠存储）";
CM_ SG_ 938 BDCS19_EAO_CR_RLMotPosn_ChgTrg "右中风门左右角度（用户设置存储）";
CM_ SG_ 938 BDCS19_EAO_CR_RLMotPosn_ClmtOffTrg "右中风门左右角度（空调关机存储）";
CM_ SG_ 938 BDCS19_EAO_CR_RLMotPosn_SlpTrg "右中风门左右角度（控制器休眠存储）";
CM_ SG_ 938 BDCS19_EAO_CR_UDMotPosn_ChgTrg "右中风门上下角度（用户设置存储）";
CM_ SG_ 938 BDCS19_EAO_CR_UDMotPosn_ClmtOffTrg "右中风门上下角度（空调关机存储）";
CM_ SG_ 938 BDCS19_EAO_CR_UDMotPosn_SlpTrg "右中风门上下角度（控制器休眠存储）";
CM_ SG_ 938 BDCS19_EAO_FR_RLMotPosn_ChgTrg "右前风门左右角度（用户设置存储）";
CM_ SG_ 938 BDCS19_EAO_FR_RLMotPosn_ClmtOffTrg "右前风门左右角度（空调关机存储）";
CM_ SG_ 938 BDCS19_EAO_FR_RLMotPosn_SlpTrg "右前风门左右角度（控制器休眠存储）";
CM_ SG_ 938 BDCS19_EAO_FR_UDMotPosn_ChgTrg "右前风门上下角度（用户设置存储）";
CM_ SG_ 938 BDCS19_EAO_FR_UDMotPosn_ClmtOffTrg "右前风门上下角度（空调关机存储）";
CM_ SG_ 938 BDCS19_EAO_FR_UDMotPosn_SlpTrg "右前风门上下角度（控制器休眠存储）";
CM_ SG_ 938 BDCS19_EAO_LeVentMod_ChgTrg "左电动出风口工作状态（用户设置存储）";
CM_ SG_ 938 BDCS19_AC_AutoDrySts_ChgTrg "空调自干燥开关状态（用户设置存储）";
CM_ SG_ 938 BDCS19_EAO_LeVentMod_ClmtOffTrg "左电动出风口工作状态（空调关机存储）";
CM_ SG_ 938 BDCS19_AC_AutoDrySts_ClmtOffTrg "空调自干燥开关状态（空调关机存储）";
CM_ SG_ 938 BDCS19_EAO_LeVentMod_SlpTrg "左电动出风口工作状态（控制器休眠存储）";
CM_ SG_ 938 BDCS19_AC_AutoDrySts_SlpTrg "空调自干燥开关状态（控制器休眠存储）";
CM_ SG_ 938 BDCS19_EAO_RiVentMod_ChgTrg "右电动出风口工作状态（用户设置存储）";
CM_ SG_ 938 BDCS19_AC_AutoWinDefrstSts_ChgTrg "自动除雾开关状态（用户设置存储）";
CM_ SG_ 938 BDCS19_EAO_RiVentMod_ClmtOffTrg "右电动出风口工作状态（空调关机存储）";
CM_ SG_ 938 BDCS19_AC_AutoWinDefrstSts_ClmtOffTrg "自动除雾开关状态（空调关机存储）";
CM_ SG_ 938 BDCS19_EAO_RiVentMod_SlpTrg "右电动出风口工作状态（控制器休眠存储）";
CM_ SG_ 938 BDCS19_AC_AutoWinDefrstSts_SlpTrg "自动除雾开关状态（控制器休眠存储）";
CM_ SG_ 938 BDCS19_AC_ChgTrgSts "用户设置存储标志位";
CM_ SG_ 938 BDCS19_AC_ClmtOffTrgSts "空调关机存储标志位";
CM_ SG_ 938 BDCS19_AC_SlpTrgSts "控制器休眠存储标志位";
CM_ SG_ 938 BDCS19_AC_ACTrgMod "空调操作模式";
CM_ SG_ 938 BDCS19_AC_App2NVMSts_ClmtOffTrg "空调存储单元存储状态（空调关机存储）";
CM_ SG_ 938 BDCS19_AC_App2NVMSts_SlpTrg "空调存储单元存储状态（控制器休眠存储）";
CM_ SG_ 938 BDCS19_AC_ClmttMod_ClmtOffTrg "空调模式（空调关机存储）";
CM_ SG_ 938 BDCS19_AC_ClmttMod_SlpTrg "空调模式（控制器休眠存储）";
CM_ SG_ 938 BDCS19_VehicleEOLCode "整车配置字";
CM_ SG_ 962 Encr_PEPS_AUTH_PIN_0 "Encript PIN Code Byte0(HighByte)";
CM_ SG_ 962 Encr_PEPS_AUTH_PIN_1 "Encript PIN Code Byte1(LowByte)";
CM_ SG_ 962 Encr_PEPS_AUTH_PIN_2 "加密前为0xAA";
CM_ SG_ 962 Encr_PEPS_AUTH_PIN_3 "加密前为0x55";
CM_ SG_ 962 PEPS_AUTH_Random_0 "Random Byte0(HighByte)";
CM_ SG_ 962 PEPS_AUTH_Random_1 "Random Byte1";
CM_ SG_ 962 PEPS_AUTH_Random_2 "Random Byte2";
CM_ SG_ 962 PEPS_AUTH_Random_3 "Random Byte3(LowByte)";
CM_ SG_ 963 Encr_PEPS_TEA_SK_0 "Encript SecretKeyByte0(HighByte)";
CM_ SG_ 963 Encr_PEPS_TEA_SK_1 "Encript Secret Key Byte1";
CM_ SG_ 963 Encr_PEPS_TEA_SK_2 "Encript Secret Key Byte2";
CM_ SG_ 963 Encr_PEPS_TEA_SK_3 "Encript Secret Key Byte3";
CM_ SG_ 963 Encr_PEPS_TEA_SK_4 "Encript Secret Key Byte4";
CM_ SG_ 963 Encr_PEPS_TEA_SK_5 "Encript Secret Key Byte5";
CM_ SG_ 963 Encr_PEPS_TEA_SK_6 "Encript Secret Key Byte6";
CM_ SG_ 963 Encr_PEPS_TEA_SK_7 "Encript Secret Key Byte7";
CM_ SG_ 965 Encr_PEPS_TEA_PIN_0 "Encript PIN Code Byte0(HighByte)";
CM_ SG_ 965 Encr_PEPS_TEA_PIN_1 "Encript PIN Code Byte1(LowByte)";
CM_ SG_ 965 Encr_PEPS_TEA_PIN_2 "加密前为0xAA";
CM_ SG_ 965 Encr_PEPS_TEA_PIN_3 "加密前为0x55";
CM_ SG_ 965 PEPS_TEA_PIN_CRC "(32,8)CRC Data Byte1
(40,8)CRC Data Byte1";
CM_ SG_ 967 Encr_PEPS_VCU_PIN_0 "Encript PIN Code Byte0(HighByte)";
CM_ SG_ 967 Encr_PEPS_VCU_PIN_1 "Encript PIN Code Byte1(LowByte)";
CM_ SG_ 967 Encr_PEPS_VCU_PIN_2 "加密前为0xAA";
CM_ SG_ 967 Encr_PEPS_VCU_PIN_3 "加密前为0x55";
CM_ SG_ 967 PEPS_VCU_Random_0 "Random Byte0(HighByte)";
CM_ SG_ 967 PEPS_VCU_Random_1 "Random Byte1";
CM_ SG_ 967 PEPS_VCU_Random_2 "Random Byte2";
CM_ SG_ 967 PEPS_VCU_Random_3 "Random Byte3(LowByte)";
CM_ SG_ 969 Encr_PEPS_RES_PIN_0 "Encript PIN Code Byte0(HighByte)";
CM_ SG_ 969 Encr_PEPS_RES_PIN_1 "Encript PIN Code Byte1(LowByte)";
CM_ SG_ 969 Encr_PEPS_RES_PIN_2 "加密前为0xAA";
CM_ SG_ 969 Encr_PEPS_RES_PIN_3 "加密前为0x55";
CM_ SG_ 969 PEPS_RES_Random_0 "Random Byte0(HighByte)";
CM_ SG_ 969 PEPS_RES_Random_1 "Random Byte1";
CM_ SG_ 969 PEPS_RES_Random_2 "Random Byte2";
CM_ SG_ 969 PEPS_RES_Random_3 "Random Byte3(LowByte)";
CM_ SG_ 977 BDCS0C_Chall_Random_0 "TBOX远程控制身份认证随机数0";
CM_ SG_ 977 BDCS0C_Chall_Random_1 "TBOX远程控制身份认证随机数1";
CM_ SG_ 977 BDCS0C_Chall_Random_2 "TBOX远程控制身份认证随机数2";
CM_ SG_ 977 BDCS0C_Chall_Random_3 "TBOX远程控制身份认证随机数3";
CM_ SG_ 977 BDCS0C_Chall_Random_4 "TBOX远程控制身份认证随机数4";
CM_ SG_ 977 BDCS0C_Chall_Random_5 "TBOX远程控制身份认证随机数5";
CM_ SG_ 977 BDCS0C_Chall_Random_6 "TBOX远程控制身份认证随机数6";
CM_ SG_ 977 BDCS0C_Chall_Random_7 "TBOX远程控制身份认证随机数7";
CM_ SG_ 979 BDM_Chall_BTM_Random_0 "BTM远程控制身份认证随机数0";
CM_ SG_ 979 BDM_Chall_BTM_Random_1 "BTM远程控制身份认证随机数1";
CM_ SG_ 979 BDM_Chall_BTM_Random_2 "BTM远程控制身份认证随机数2";
CM_ SG_ 979 BDM_Chall_BTM_Random_3 "BTM远程控制身份认证随机数3";
CM_ SG_ 979 BDM_Chall_BTM_Random_4 "BTM远程控制身份认证随机数4";
CM_ SG_ 979 BDM_Chall_BTM_Random_5 "BTM远程控制身份认证随机数5";
CM_ SG_ 979 BDM_Chall_BTM_Random_6 "BTM远程控制身份认证随机数6";
CM_ SG_ 979 BDM_Chall_BTM_Random_7 "BTM远程控制身份认证随机数7";
CM_ SG_ 981 BDCS_Chall_AICS_Random_0 "AICS OTA控制身份认证随机数0";
CM_ SG_ 981 BDCS_Chall_AICS_Random_1 "AICS OTA控制身份认证随机数1";
CM_ SG_ 981 BDCS_Chall_AICS_Random_2 "AICS OTA控制身份认证随机数2";
CM_ SG_ 981 BDCS_Chall_AICS_Random_3 "AICS OTA控制身份认证随机数3";
CM_ SG_ 981 BDCS_Chall_AICS_Random_4 "AICS OTA控制身份认证随机数4";
CM_ SG_ 981 BDCS_Chall_AICS_Random_5 "AICS OTA控制身份认证随机数5";
CM_ SG_ 981 BDCS_Chall_AICS_Random_6 "AICS OTA控制身份认证随机数6";
CM_ SG_ 981 BDCS_Chall_AICS_Random_7 "AICS OTA控制身份认证随机数7";
CM_ SG_ 983 BDM_Chall_ADCS_Random_0 "ADCS控制身份认证随机数0";
CM_ SG_ 983 BDM_Chall_ADCS_Random_1 "ADCS控制身份认证随机数1";
CM_ SG_ 983 BDM_Chall_ADCS_Random_2 "ADCS控制身份认证随机数2";
CM_ SG_ 983 BDM_Chall_ADCS_Random_3 "ADCS控制身份认证随机数3";
CM_ SG_ 983 BDM_Chall_ADCS_Random_4 "ADCS控制身份认证随机数4";
CM_ SG_ 983 BDM_Chall_ADCS_Random_5 "ADCS控制身份认证随机数5";
CM_ SG_ 983 BDM_Chall_ADCS_Random_6 "ADCS控制身份认证随机数6";
CM_ SG_ 983 BDM_Chall_ADCS_Random_7 "ADCS控制身份认证随机数7";

BA_DEF_ BO_ "CANFD_BRS" ENUM "0","1";
BA_DEF_ BO_ "GenMsgSendType" ENUM "Cycle","NoMsgSendType","IfActive","Event","CA","CE";
BA_DEF_ BO_ "GenMsgNrOfRepetition" INT 0 0;
BA_DEF_ BO_ "GenMsgILSupport" ENUM "No","Yes";
BA_DEF_ BO_ "GenMsgDelayTime" INT 0 0;
BA_DEF_ BO_ "GenMsgCycleTimeFast" INT 0 0;
BA_DEF_ BO_ "GenMsgCycleTime" INT 0 0;
BA_DEF_ BO_ "DiagResponse" ENUM "No","Yes";
BA_DEF_ BO_ "DiagRequest" ENUM "No","Yes";
BA_DEF_ BO_ "NmMessage" ENUM "No","Yes";
BA_DEF_ BO_ "VFrameFormat" ENUM "StandardCAN","ExtendedCAN","reserved","J1939PG","reserved","reserved","reserved","reserved","reserved","reserved","reserved","reserved","reserved","reserved","StandardCAN_FD","ExtendedCAN_FD";
BA_DEF_ SG_ "GenSigInvalidValue" HEX 0 0;
BA_DEF_ SG_ "GenSigStartValue" HEX 0 0;
BA_DEF_ SG_ "GenSigSendType" ENUM "Cycle","OnWrite","OnWriteWithRepetition","OnChange","OnChangeWithRepetition","IfActive","IfActiveWithRepetition","NoSigSendType","vector_leerstring";
BA_DEF_DEF_ "CANFD_BRS" "1";
BA_DEF_DEF_ "GenMsgSendType" "Cycle";
BA_DEF_DEF_ "GenMsgNrOfRepetition" 0;
BA_DEF_DEF_ "GenMsgILSupport" "Yes";
BA_DEF_DEF_ "GenMsgDelayTime" 0;
BA_DEF_DEF_ "GenMsgCycleTimeFast" 0;
BA_DEF_DEF_ "GenMsgCycleTime" 0;
BA_DEF_DEF_ "DiagResponse" "No";
BA_DEF_DEF_ "DiagRequest" "No";
BA_DEF_DEF_ "NmMessage" "No";
BA_DEF_DEF_ "VFrameFormat" "StandardCAN";
BA_DEF_DEF_ "GenSigInvalidValue" 0;
BA_DEF_DEF_ "GenSigStartValue" 0;
BA_DEF_DEF_ "GenSigSendType" "Cycle";
BA_ "GenMsgCycleTime" BO_ 272 20;
BA_ "VFrameFormat" BO_ 272 14;
BA_ "GenMsgCycleTime" BO_ 274 20;
BA_ "VFrameFormat" BO_ 274 14;
BA_ "GenMsgCycleTime" BO_ 276 20;
BA_ "VFrameFormat" BO_ 276 14;
BA_ "GenMsgCycleTime" BO_ 482 50;
BA_ "VFrameFormat" BO_ 482 14;
BA_ "GenMsgCycleTime" BO_ 484 50;
BA_ "VFrameFormat" BO_ 484 14;
BA_ "GenMsgCycleTime" BO_ 486 50;
BA_ "VFrameFormat" BO_ 486 14;
BA_ "GenMsgCycleTime" BO_ 496 50;
BA_ "VFrameFormat" BO_ 496 14;
BA_ "GenMsgCycleTime" BO_ 512 50;
BA_ "VFrameFormat" BO_ 512 14;
BA_ "GenMsgCycleTime" BO_ 490 50;
BA_ "VFrameFormat" BO_ 490 14;
BA_ "GenMsgCycleTime" BO_ 564 100;
BA_ "VFrameFormat" BO_ 564 14;
BA_ "GenMsgCycleTime" BO_ 565 500;
BA_ "VFrameFormat" BO_ 565 14;
BA_ "GenMsgCycleTime" BO_ 645 100;
BA_ "VFrameFormat" BO_ 645 14;
BA_ "GenMsgCycleTime" BO_ 661 100;
BA_ "VFrameFormat" BO_ 661 14;
BA_ "GenMsgCycleTime" BO_ 664 100;
BA_ "VFrameFormat" BO_ 664 14;
BA_ "GenMsgCycleTime" BO_ 670 100;
BA_ "VFrameFormat" BO_ 670 14;
BA_ "GenMsgCycleTime" BO_ 677 100;
BA_ "VFrameFormat" BO_ 677 14;
BA_ "GenMsgCycleTime" BO_ 678 100;
BA_ "VFrameFormat" BO_ 678 14;
BA_ "GenMsgCycleTime" BO_ 680 100;
BA_ "VFrameFormat" BO_ 680 14;
BA_ "GenMsgCycleTime" BO_ 807 500;
BA_ "VFrameFormat" BO_ 807 14;
BA_ "GenMsgNrOfRepetition" BO_ 857 3;
BA_ "GenMsgCycleTimeFast" BO_ 857 20;
BA_ "GenMsgSendType" BO_ 857 3;
BA_ "VFrameFormat" BO_ 857 14;
BA_ "GenMsgCycleTime" BO_ 938 500;
BA_ "VFrameFormat" BO_ 938 14;
BA_ "GenMsgSendType" BO_ 962 2;
BA_ "VFrameFormat" BO_ 962 14;
BA_ "GenMsgSendType" BO_ 963 2;
BA_ "VFrameFormat" BO_ 963 14;
BA_ "GenMsgSendType" BO_ 965 2;
BA_ "VFrameFormat" BO_ 965 14;
BA_ "GenMsgSendType" BO_ 967 2;
BA_ "VFrameFormat" BO_ 967 14;
BA_ "GenMsgSendType" BO_ 969 2;
BA_ "VFrameFormat" BO_ 969 14;
BA_ "GenMsgSendType" BO_ 977 2;
BA_ "VFrameFormat" BO_ 977 14;
BA_ "GenMsgSendType" BO_ 979 2;
BA_ "VFrameFormat" BO_ 979 14;
BA_ "GenMsgSendType" BO_ 981 2;
BA_ "VFrameFormat" BO_ 981 14;
BA_ "GenMsgSendType" BO_ 983 2;
BA_ "VFrameFormat" BO_ 983 14;
BA_ "GenSigStartValue" SG_ 272 BDCS1_Backlight_brightness_fb 3;
BA_ "GenSigStartValue" SG_ 274 BDCS3_Wal_Away_Up_swSt 3;
BA_ "GenSigStartValue" SG_ 274 BDCS3_WelcomeLampCmd_swSt 3;
BA_ "GenSigStartValue" SG_ 276 CS1_GearPositionReqStInv 7;
BA_ "GenSigInvalidValue" SG_ 482 BDCS4_FLTyre_Pressure 255;
BA_ "GenSigInvalidValue" SG_ 482 BDCS4_FLTyre_Temperature 255;
BA_ "GenSigInvalidValue" SG_ 482 BDCS4_FRTyre_Pressure 255;
BA_ "GenSigInvalidValue" SG_ 482 BDCS4_FRTyre_Temperature 255;
BA_ "GenSigInvalidValue" SG_ 484 BDCS5_RLTyre_Pressure 255;
BA_ "GenSigInvalidValue" SG_ 484 BDCS5_RLTyre_Temperature 255;
BA_ "GenSigInvalidValue" SG_ 484 BDCS5_RRTyre_Pressure 255;
BA_ "GenSigInvalidValue" SG_ 484 BDCS5_RRTyre_Temperature 255;
BA_ "GenSigInvalidValue" SG_ 564 BDCS10_EWP_H_TRPMRq 255;
BA_ "GenSigInvalidValue" SG_ 564 BDCS10_EWP_B_TRPMReq 255;
BA_ "GenSigInvalidValue" SG_ 564 BDCS10_EWP_M_TRPMReq 255;
BA_ "GenSigInvalidValue" SG_ 565 EXV_B_curInit_Stat 3;
BA_ "GenSigInvalidValue" SG_ 565 EWP_H_RPM_Target_Stat 255;
BA_ "GenSigInvalidValue" SG_ 565 EWP_H_RPM_ActlVal_Stat 255;
BA_ "GenSigInvalidValue" SG_ 565 EWP_H_Volt_Stat 255;
BA_ "GenSigInvalidValue" SG_ 565 EWP_H_Temp_Stat 255;
BA_ "GenSigInvalidValue" SG_ 565 EWP_H_Curr_Stat 255;
BA_ "GenSigInvalidValue" SG_ 565 EWP_H_OverCurr_Error 3;
BA_ "GenSigInvalidValue" SG_ 565 EWP_H_DryRun_Error 3;
BA_ "GenSigInvalidValue" SG_ 565 EWP_H_SupVolt_Error 3;
BA_ "GenSigInvalidValue" SG_ 565 EWP_H_Block_Error 3;
BA_ "GenSigInvalidValue" SG_ 565 EWP_H_OverTemp_Error 3;
BA_ "GenSigInvalidValue" SG_ 565 EWP_B_OverTemp_Error 3;
BA_ "GenSigInvalidValue" SG_ 565 EWP_M_OverTemp_Error 3;
BA_ "GenSigInvalidValue" SG_ 565 EWP_B_RPM_Target_Stat 255;
BA_ "GenSigInvalidValue" SG_ 565 EWP_B_RPM_ActlVal_Stat 255;
BA_ "GenSigInvalidValue" SG_ 565 EWP_B_Volt_Stat 255;
BA_ "GenSigInvalidValue" SG_ 565 EWP_B_Temp_Stat 255;
BA_ "GenSigInvalidValue" SG_ 565 EWP_B_Curr_Stat 255;
BA_ "GenSigInvalidValue" SG_ 565 EWP_B_OverCurr_Error 3;
BA_ "GenSigInvalidValue" SG_ 565 EWP_B_DryRun_Error 3;
BA_ "GenSigInvalidValue" SG_ 565 EWP_B_SupVolt_Error 3;
BA_ "GenSigInvalidValue" SG_ 565 EWP_B_Block_Error 3;
BA_ "GenSigInvalidValue" SG_ 565 EWP_M_RPM_Target_Stat 255;
BA_ "GenSigInvalidValue" SG_ 565 EWP_M_RPM_ActlVal_Stat 255;
BA_ "GenSigInvalidValue" SG_ 565 EWP_M_Volt_Stat 255;
BA_ "GenSigInvalidValue" SG_ 565 EWP_M_Temp_Stat 255;
BA_ "GenSigInvalidValue" SG_ 565 EWP_M_Curr_Stat 255;
BA_ "GenSigInvalidValue" SG_ 565 EWP_M_OverCurr_Error 3;
BA_ "GenSigInvalidValue" SG_ 565 EWP_M_DryRun_Error 3;
BA_ "GenSigInvalidValue" SG_ 565 EWP_M_SupVolt_Error 3;
BA_ "GenSigInvalidValue" SG_ 565 EWP_M_Block_Error 3;
BA_ "GenSigInvalidValue" SG_ 661 BDCS11_AC_PTC_Level 15;
BA_ "GenSigInvalidValue" SG_ 661 BDCS11_AC_EAC_SpeedSet 127;
BA_ "GenSigInvalidValue" SG_ 661 BDCS11_PumpHTarSpd 255;
BA_ "GenSigInvalidValue" SG_ 661 BDCS11_AC_EAC_PowerLimit 15;
BA_ "GenSigInvalidValue" SG_ 661 BDCS11_AC_PowerReq 31;
BA_ "GenSigInvalidValue" SG_ 664 BDCS12_InsideTemp 255;
BA_ "GenSigStartValue" SG_ 664 BDCS12_InsideTemp 255;
BA_ "GenSigInvalidValue" SG_ 664 BDCS12_AC_PTC_PowerLimit 255;
BA_ "GenSigStartValue" SG_ 664 BDCS12_AC_PTC_PowerLimit 253;
BA_ "GenSigInvalidValue" SG_ 664 BDCS12_AC_PTC_PowerSet 255;
BA_ "GenSigStartValue" SG_ 664 BDCS12_AC_PTC_PowerSet 253;
BA_ "GenSigInvalidValue" SG_ 670 BDCS10_AC_OutsideTemp 255;
BA_ "GenSigStartValue" SG_ 670 BDCS10_AC_OutsideTemp 255;
BA_ "GenSigInvalidValue" SG_ 670 BDCS10_AC_LHTemp 255;
BA_ "GenSigInvalidValue" SG_ 670 BDCS10_AC_RHTemp 255;
BA_ "GenSigStartValue" SG_ 678 BDCS9_FridgeMod_Sts 1;
BA_ "GenSigInvalidValue" SG_ 680 PTC1_PowerConsumption 255;
BA_ "GenSigInvalidValue" SG_ 680 PTC1_ActuHiCrnt 255;
BA_ "GenSigInvalidValue" SG_ 680 PTC1_ClntTempInlt 255;
BA_ "GenSigInvalidValue" SG_ 680 PTC1_ClntTempOtlt 255;
BA_ "GenSigInvalidValue" SG_ 680 PTC1_IGBTTem 255;
BA_ "GenSigInvalidValue" SG_ 680 EACP1_OutputPwr 63;
BA_ "GenSigInvalidValue" SG_ 680 EACP1_InputCurr 511;
BA_ "GenSigInvalidValue" SG_ 680 EACP1_MotorTemp 255;
BA_ "GenSigInvalidValue" SG_ 680 EACP1_ACPSpeed 127;
BA_ "GenSigInvalidValue" SG_ 680 EACP1_InputVolt 511;
BA_ "GenSigSendType" SG_ 857 BDCS_OTA_DoorLockCmd 3;
BA_ "GenSigSendType" SG_ 857 BDCS_OTA_FLWindowsCtrl 3;
BA_ "GenSigSendType" SG_ 857 BDCS_OTA_FRWindowsCtrl 3;
BA_ "GenSigSendType" SG_ 857 BDCS_OTA_RLWindowsCtrl 3;
BA_ "GenSigSendType" SG_ 857 BDCS_OTA_RRWindowsCtrl 3;
BA_ "GenSigSendType" SG_ 857 BDCS_OTA_TrunkLockSts 3;
BA_ "GenSigSendType" SG_ 857 BDCS_OTA_HoodAjarSts 3;
BA_ "GenSigSendType" SG_ 857 BDCS_OTA_AlarmMode 3;
BA_ "GenSigSendType" SG_ 962 Encr_PEPS_AUTH_PIN_0 5;
BA_ "GenSigSendType" SG_ 962 Encr_PEPS_AUTH_PIN_1 5;
BA_ "GenSigSendType" SG_ 962 Encr_PEPS_AUTH_PIN_2 5;
BA_ "GenSigSendType" SG_ 962 Encr_PEPS_AUTH_PIN_3 5;
BA_ "GenSigSendType" SG_ 962 PEPS_AUTH_Random_0 5;
BA_ "GenSigSendType" SG_ 962 PEPS_AUTH_Random_1 5;
BA_ "GenSigSendType" SG_ 962 PEPS_AUTH_Random_2 5;
BA_ "GenSigSendType" SG_ 962 PEPS_AUTH_Random_3 5;
BA_ "GenSigSendType" SG_ 963 Encr_PEPS_TEA_SK_0 5;
BA_ "GenSigSendType" SG_ 963 Encr_PEPS_TEA_SK_1 5;
BA_ "GenSigSendType" SG_ 963 Encr_PEPS_TEA_SK_2 5;
BA_ "GenSigSendType" SG_ 963 Encr_PEPS_TEA_SK_3 5;
BA_ "GenSigSendType" SG_ 963 Encr_PEPS_TEA_SK_4 5;
BA_ "GenSigSendType" SG_ 963 Encr_PEPS_TEA_SK_5 5;
BA_ "GenSigSendType" SG_ 963 Encr_PEPS_TEA_SK_6 5;
BA_ "GenSigSendType" SG_ 963 Encr_PEPS_TEA_SK_7 5;
BA_ "GenSigSendType" SG_ 965 Encr_PEPS_TEA_PIN_0 5;
BA_ "GenSigSendType" SG_ 965 Encr_PEPS_TEA_PIN_1 5;
BA_ "GenSigSendType" SG_ 965 Encr_PEPS_TEA_PIN_2 5;
BA_ "GenSigSendType" SG_ 965 Encr_PEPS_TEA_PIN_3 5;
BA_ "GenSigSendType" SG_ 965 PEPS_TEA_PIN_CRC 5;
BA_ "GenSigSendType" SG_ 967 Encr_PEPS_VCU_PIN_0 5;
BA_ "GenSigSendType" SG_ 967 Encr_PEPS_VCU_PIN_1 5;
BA_ "GenSigSendType" SG_ 967 Encr_PEPS_VCU_PIN_2 5;
BA_ "GenSigSendType" SG_ 967 Encr_PEPS_VCU_PIN_3 5;
BA_ "GenSigSendType" SG_ 967 PEPS_VCU_Random_0 5;
BA_ "GenSigSendType" SG_ 967 PEPS_VCU_Random_1 5;
BA_ "GenSigSendType" SG_ 967 PEPS_VCU_Random_2 5;
BA_ "GenSigSendType" SG_ 967 PEPS_VCU_Random_3 5;
BA_ "GenSigSendType" SG_ 969 Encr_PEPS_RES_PIN_0 5;
BA_ "GenSigSendType" SG_ 969 Encr_PEPS_RES_PIN_1 5;
BA_ "GenSigSendType" SG_ 969 Encr_PEPS_RES_PIN_2 5;
BA_ "GenSigSendType" SG_ 969 Encr_PEPS_RES_PIN_3 5;
BA_ "GenSigSendType" SG_ 969 PEPS_RES_Random_0 5;
BA_ "GenSigSendType" SG_ 969 PEPS_RES_Random_1 5;
BA_ "GenSigSendType" SG_ 969 PEPS_RES_Random_2 5;
BA_ "GenSigSendType" SG_ 969 PEPS_RES_Random_3 5;
BA_ "GenSigSendType" SG_ 977 BDCS0C_Chall_Random_0 5;
BA_ "GenSigSendType" SG_ 977 BDCS0C_Chall_Random_1 5;
BA_ "GenSigSendType" SG_ 977 BDCS0C_Chall_Random_2 5;
BA_ "GenSigSendType" SG_ 977 BDCS0C_Chall_Random_3 5;
BA_ "GenSigSendType" SG_ 977 BDCS0C_Chall_Random_4 5;
BA_ "GenSigSendType" SG_ 977 BDCS0C_Chall_Random_5 5;
BA_ "GenSigSendType" SG_ 977 BDCS0C_Chall_Random_6 5;
BA_ "GenSigSendType" SG_ 977 BDCS0C_Chall_Random_7 5;
BA_ "GenSigSendType" SG_ 979 BDM_Chall_BTM_Random_0 5;
BA_ "GenSigSendType" SG_ 979 BDM_Chall_BTM_Random_1 5;
BA_ "GenSigSendType" SG_ 979 BDM_Chall_BTM_Random_2 5;
BA_ "GenSigSendType" SG_ 979 BDM_Chall_BTM_Random_3 5;
BA_ "GenSigSendType" SG_ 979 BDM_Chall_BTM_Random_4 5;
BA_ "GenSigSendType" SG_ 979 BDM_Chall_BTM_Random_5 5;
BA_ "GenSigSendType" SG_ 979 BDM_Chall_BTM_Random_6 5;
BA_ "GenSigSendType" SG_ 979 BDM_Chall_BTM_Random_7 5;
BA_ "GenSigSendType" SG_ 981 BDCS_Chall_AICS_Random_0 5;
BA_ "GenSigSendType" SG_ 981 BDCS_Chall_AICS_Random_1 5;
BA_ "GenSigSendType" SG_ 981 BDCS_Chall_AICS_Random_2 5;
BA_ "GenSigSendType" SG_ 981 BDCS_Chall_AICS_Random_3 5;
BA_ "GenSigSendType" SG_ 981 BDCS_Chall_AICS_Random_4 5;
BA_ "GenSigSendType" SG_ 981 BDCS_Chall_AICS_Random_5 5;
BA_ "GenSigSendType" SG_ 981 BDCS_Chall_AICS_Random_6 5;
BA_ "GenSigSendType" SG_ 981 BDCS_Chall_AICS_Random_7 5;
BA_ "GenSigSendType" SG_ 983 BDM_Chall_ADCS_Random_0 5;
BA_ "GenSigSendType" SG_ 983 BDM_Chall_ADCS_Random_1 5;
BA_ "GenSigSendType" SG_ 983 BDM_Chall_ADCS_Random_2 5;
BA_ "GenSigSendType" SG_ 983 BDM_Chall_ADCS_Random_3 5;
BA_ "GenSigSendType" SG_ 983 BDM_Chall_ADCS_Random_4 5;
BA_ "GenSigSendType" SG_ 983 BDM_Chall_ADCS_Random_5 5;
BA_ "GenSigSendType" SG_ 983 BDM_Chall_ADCS_Random_6 5;
BA_ "GenSigSendType" SG_ 983 BDM_Chall_ADCS_Random_7 5;
VAL_ 272 BDCS1_PowerMode 3 "Crank" 2 "ON" 1 "ACC" 0 "OFF";
VAL_ 272 BDCS1_PetToLookAfterFbk 1 "ON" 0 "OFF";
VAL_ 272 BDCS1_PetToLookAfterRmd 1 "Reminder" 0 "No Reminder";
VAL_ 272 BDCS1_PowerManageMode 15 "Reserved" 14 "Reserved" 13 "Reserved" 12 "Reserved" 11 "ON(Not Power OFF)" 10 "ON(Biological)" 9 "ON(Guard)" 8 "RUNNING" 7 "CRANK" 6 "ON(Remote)" 5 "ON(OTA)" 4 "ON(PetToLookAfter)" 3 "ON(120min)" 2 "ON(5min)" 1 "ON(Factory)" 0 "OFF";
VAL_ 272 BDCS1_AlarmMode 4 "Alarm" 3 "Alarm Triggered" 2 "AntiTheft" 1 "Pre-AntiThrft" 0 "No-AntiTheft";
VAL_ 272 BDCS1_LowBeamSt 1 "Active" 0 "Inactive";
VAL_ 272 BDCS1_HighBeamSt 1 "Active" 0 "Inactive";
VAL_ 272 BDCS1_EnergyManagement 7 "Reserved" 6 "LEVEL5" 5 "LEVEL4" 4 "LEVEL3" 3 "LEVEL2" 2 "LEVEL1" 1 "OFF" 0 "Default";
VAL_ 272 BDCS1_FindCarSts 1 "Active" 0 "Inactive";
VAL_ 272 BDCS1_PositionLightSts 1 "Active" 0 "Inactive";
VAL_ 272 BDCS1_BacklightStatus 1 "Active" 0 "Inactive";
VAL_ 272 BDCS1_LeftTurnLightSt 1 "Active" 0 "Inactive";
VAL_ 272 BDCS1_RightTurnLightSt 1 "Active" 0 "Inactive";
VAL_ 272 BDCS1_FrontLampSt 3 "LowBeam" 2 "PositionLamp" 1 "Auto" 0 "OFF";
VAL_ 272 BDCS1_HazardLampSt 1 "Active" 0 "Inactive";
VAL_ 272 BDCS1_HighBeamSW 3 "Reserved" 2 "HighBeam" 1 "Flash" 0 "OFF";
VAL_ 272 BDCS1_TurnLightSW 3 "Reserved" 2 "Right" 1 "Left" 0 "OFF";
VAL_ 272 BDCS1_HazardSwSt 1 "Active" 0 "Inactive";
VAL_ 272 BDCS1_BrakeLightSts 1 "Active" 0 "Inactive";
VAL_ 272 BDCS1_RearFogLampSt 1 "Active" 0 "Inactive";
VAL_ 272 BDCS1_FrontFogLampSt 1 "Active" 0 "Inactive";
VAL_ 272 BDCS1_BackupLightSts 1 "Active" 0 "Inactive";
VAL_ 272 BDCS1_HeadlampHeight_fb 3 "Level 3" 2 "Level 2" 1 "Level 1" 0 "Level 0";
VAL_ 272 BDCS1_TrunkLockSts 1 "Locked" 0 "Unlocked";
VAL_ 272 BDCS1_FMH_SetSts 7 "Reserved2" 6 "Reserved1" 5 "150 Seconds" 4 "120 Seconds" 3 "90 Seconds" 2 "60 Seconds" 1 "30 Seconds" 0 "Follow Me Closed";
VAL_ 272 BDCS1_HoodAjarSts 1 "Open" 0 "Closed";
VAL_ 272 BDCS1_Backlight_brightness_fb 10 "Level 10" 9 "Level 9" 8 "Level 8" 7 "Level 7" 6 "Level 6" 5 "Level 5" 4 "Level 4" 3 "Level 3" 2 "Level 2" 1 "Level 1";
VAL_ 272 BDCS1_DRLSt 1 "Active" 0 "Inactive";
VAL_ 272 BDCS1_CentralLockFbk 1 "Locked" 0 "Unlocked";
VAL_ 272 BDCS1_OTAauthenSts 3 "Reserved" 2 "Authentication Failed" 1 "Authentication Succeed" 0 "Default";
VAL_ 272 BDCS1_WelcomeLampModFbk 12 "预留场景4" 11 "预留场景3" 10 "预留场景2" 9 "预留场景1" 8 "泊车成功" 7 "解锁" 6 "慢充" 5 "快充" 4 "AUTOHOLD" 3 "寻车" 2 "欢送" 1 "迎宾" 0 "No active";
VAL_ 274 BDCS3_StartRequest 1 "Active" 0 "Inactive";
VAL_ 274 BDCS3_LightShowSts 1 "Active" 0 "Inactive";
VAL_ 274 BDCS3_CarMode 7 "Fault" 6 "Sea transport Mode" 5 "Stationary Mode" 4 "Test Mode" 3 "Factory Mode(Reserved)" 2 "Transport Mode" 1 "Normal Mode" 0 "Default";
VAL_ 274 BDCS3_BluetoothAuthenSts 3 "Reserved" 2 "Authentication Failed" 1 "Authentication Succeed" 0 "Default";
VAL_ 274 BDCS3_EngineForbidSts 1 "Forbid" 0 "Not forbid";
VAL_ 274 BDCS3_RemoteStartSts 3 "Crank" 2 "ON (Driving)" 1 "ON" 0 "OFF";
VAL_ 274 BDCS3_RemoteAuthenSts 3 "Reserved" 2 "Authentication Failed" 1 "Authentication Successed" 0 "Default";
VAL_ 274 BDCS3_RemoteReadySts 3 "Reserved" 2 "Succeed" 1 "Failed" 0 "Invalid";
VAL_ 274 BDCS3_IHU_DoorHeightSetFb 3 "High" 2 "Middle" 1 "Low" 0 "no command";
VAL_ 274 BDCS3_RemoteAuthenFailCondition 39 "ESCL not unlocked" 38 "MT gear shift not N" 37 "Clutch pressed" 36 "EMS not running" 35 "CAN bus off" 34 "BDM timeout" 33 "Engine permit success" 32 "Engine forbid success" 31 "Reserved" 30 "System reset" 29 "Command not supported in current mode" 28 "Remote request to power off" 27 "Transition to normal system power mode" 26 "Max. engine running timeout" 25 "Max. power on timeout" 24 "Max. authentication timeout" 23 "Crank-allowance timeout" 22 "System alarm (reserved)" 21 "No response from ems" 20 "EMS authentication failed" 19 "Telematics authentication failed" 18 "SSB pressed" 17 "Voltage out of range" 16 "Telematics power mode not OFF" 15 "System power mode not OFF" 14 "Gear P failure" 13 "Starter output failure" 12 "IGN1 output failure" 11 "Any door open" 10 "System not armed not all doors locked" 9 "Gear not P" 8 "Brake pedal pressed" 7 "Vehicle not standstill" 6 "Speed invalid" 5 "Invalid telematics mode" 4 "Telematics not supported" 3 "Escl enabled" 2 "PEPS not learnt" 1 "Reserved" 0 "Default";
VAL_ 274 BDCS3_KeyAuthenSts 3 "Reserved" 2 "Fail" 1 "Success" 0 "Default";
VAL_ 274 BDCS3_IHU_ReclockReq 1 "request" 0 "no request";
VAL_ 274 BDCS3_BackDoorAjar 7 "Unknow" 6 "Reserved" 5 "Reserved" 4 "Cannot Close Area" 3 "Fully Open" 2 "Open to Custon Height" 1 "Not Closed" 0 "Fully Closed";
VAL_ 274 BDCS3_RKECmd 7 "Start Engine" 6 "Long Unlock (>2s)" 5 "Long Lock (>2s)" 4 "Vehicle Tracking" 3 "Trunk Unlock" 2 "Short Lock" 1 "Short Unlock" 0 "Default";
VAL_ 274 BDCS3_DoorHeightValid 1 "Valid" 0 "Invalid";
VAL_ 274 BDCS3_RearDoorStatus 4 "Paused" 3 "Opened" 2 "Opening" 1 "Closed" 0 "Closing";
VAL_ 274 BDCS3_IDdeviceNo 7 "Reserved" 6 "Reserved" 5 "Reserved" 4 "Fob Four" 3 "Fob Three" 2 "Fob Two" 1 "Fob One" 0 "Default";
VAL_ 274 BDCS3_ShutDownReqFbk 1 "Fail" 0 "Default";
VAL_ 274 BDCS3_OTAModeSts 7 "unknown error" 6 "READY状态不能进入OTA模式" 5 "Bus communication fail" 4 "Authentication fail" 3 "BDCS HW fail" 2 "false cmd, No exec" 1 "in otamode, No failure" 0 "idle, No failure";
VAL_ 274 BDCS3_LaunchRequest 1 "Request" 0 "Not Request";
VAL_ 274 BDCS3_StarterRelay2On 1 "Active" 0 "Inactive";
VAL_ 274 BDCS3_StarterRelay1On 1 "Active" 0 "Inactive";
VAL_ 274 BDCS3_PARKUnLockFeedback 1 "Enable" 0 "Disable";
VAL_ 274 BDCS3_SpeedLockFeedback 1 "Enable" 0 "Disable";
VAL_ 274 BDCS3_StationaryModeReminder 3 "Reserved" 2 "Reserved" 1 "Reminder ON" 0 "Reminder OFF";
VAL_ 274 BDCS3_SportRequest 1 "Request" 0 "Not Request";
VAL_ 274 BDCS3_SportRequestValid 1 "Valid" 0 "Invalid";
VAL_ 274 BDCS3_LaunchRequestValid 1 "Valid" 0 "Invalid";
VAL_ 274 BDCS3_ADCSAuthenSts 3 "Reserved" 2 "Authentication Failed" 1 "Authentication Successed" 0 "Default";
VAL_ 274 BDCS3_InteriorLightingFdb 3 "Auto" 2 "OFF" 1 "ON" 0 "Default";
VAL_ 274 BDCS3_LFreadinglampSts 1 "ON" 0 "OFF";
VAL_ 274 BDCS3_RFreadinglampSts 1 "ON" 0 "OFF";
VAL_ 274 BDCS3_LRreadinglampSts 1 "ON" 0 "OFF";
VAL_ 274 BDCS3_RRreadinglampSts 1 "ON" 0 "OFF";
VAL_ 274 BDCS3_FindMyCarTimeSet_Fb 2 "30 second" 1 "20 second" 0 "10 second";
VAL_ 274 BDCS3_Horn_SW 1 "Active" 0 "Inactive";
VAL_ 274 BDCS3_AntiTheftInnerStsEE 9 "预设防等待" 8 "报警解除" 7 "半设防" 6 "半设防等待" 5 "半解防等待" 4 "自动重设防" 3 "Alarm Triggered" 2 "AntiTheft" 1 "Pre-AntiThrft" 0 "No-AntiTheft";
VAL_ 274 BDCS3_AntiTheftRmdSoundFdb 2 "flicker_Chord（音效）" 1 "flicker" 0 "Smart_Sound（灯语+音效）";
VAL_ 274 BDCS3_AlarmRmdSoundFdb 2 "Sound" 1 "No Sound" 0 "No Request";
VAL_ 274 BDCS3_AlarmTurnTimeFdb 3 "300s" 2 "180s" 1 "90s" 0 "No Request";
VAL_ 274 BDCS3_Wal_Away_Up_swSt 3 "Not Used" 2 "Inactive" 1 "Active" 0 "Default";
VAL_ 274 BDCS3_WelcomeLampCmd_swSt 3 "Not Used" 2 "Inactive" 1 "Active" 0 "Default";
VAL_ 274 BDCS3_TrunkHomeLockSts 1 "断开" 0 "闭合";
VAL_ 274 BDCS3_TrunkHalfLockSts 1 "断开" 0 "闭合";
VAL_ 274 BDCS3_UserSceneModeFbk 15 "Reserved" 14 "Reserved" 13 "Reserved" 12 "Reserved" 11 "Reserved" 10 "OtherMode5" 9 "OtherMode4" 8 "OtherMode3" 7 "OtherMode2" 6 "OtherMode1" 5 "CampingMode" 4 "PetMode" 3 "Childmode" 2 "CarWashMode" 1 "RacingMode" 0 "No Scene";
VAL_ 274 BDCS3_VehicleStatelRemind 7 "Reserved" 6 "Reserved" 5 "Reserved" 4 "Rainy day auto up  window succeed  Remind" 3 "Rainy day auto up  window failure  Remind" 2 "Auto up window failure Remind" 1 "Forget to lock the car door" 0 "Default";
VAL_ 274 BDCS3_TrunkCtrlFailure 3 "Reserved" 2 "Reserved" 1 "Failure" 0 "No Failure";
VAL_ 274 RF_Key_Position 5 "Inside（PS）" 4 "PE Trunk" 3 "PE Passenger Side" 2 "PE Drive Side" 1 "PE Front" 0 "Default";
VAL_ 274 BDCS3_Key_Ventilation_Fbk 7 "Reserved" 6 "Reserved" 5 "Reserved" 4 "Moving" 3 "Vent" 2 "OFF" 1 "ON" 0 "No Action";
VAL_ 276 CS1_FrontWiperMISTReqSt 1 "Active" 0 "Inactive";
VAL_ 276 CS1_HighBeamFlashReqSt 1 "Active" 0 "Inactive";
VAL_ 276 CS1_HighBeamReqSt 1 "Active" 0 "Inactive";
VAL_ 276 CS1_TurnLightReqSt 7 "Error" 4 "TurnLeftStatus" 3 "左变道" 2 "TurnRightStatus" 1 "右变道" 0 "No request";
VAL_ 276 CS1_FrontWiperReqSt 7 "Error" 5 "AUTO 2" 4 "AUTO 1" 3 "HI" 2 "LOW" 1 "MIST（Reserved）" 0 "OFF";
VAL_ 276 CS1_FrontWiperWashReqSt 1 "Active" 0 "Inactive";
VAL_ 276 CS1_RearWiperReqSt_Reserved 1 "Active" 0 "Inactive";
VAL_ 276 CS1_RearWiperWashReqSt_Reserved 1 "Active" 0 "Inactive";
VAL_ 276 CS1_GearPositionReqSt 7 "Gear hold（Reserved）" 6 "S（Reserved）" 5 "D" 4 "N2" 3 "N1" 2 "R" 1 "P（Reserved）" 0 "No request";
VAL_ 276 CS1_GearPositionReqStInv 7 "No request" 6 "P(Reserved)" 5 "R" 4 "N1" 3 "N2" 2 "D" 1 "S(Reserved)" 0 "Gear Hold(Reserved)";
VAL_ 276 CS1_GearPositionReqStValid 1 "Valid" 0 "Invalid";
VAL_ 482 BDCS4_Ftyre_Status 1 "Last Signal" 0 "Current Signal";
VAL_ 482 BDCS4_FLTyre_LearntSt 1 "Learnt" 0 "Not Learnt";
VAL_ 482 BDCS4_FLTyre_PressureWarn 3 "High Pressure" 2 "Low Pressure" 1 "Pre-warning" 0 "Normal Pressure";
VAL_ 482 BDCS4_FLTyre_TemperatureWarn 1 "High Temperature" 0 "Normal Temperature";
VAL_ 482 BDCS4_FLTyre_QucikLeak 1 "Quick Leak" 0 "No Quick Leak";
VAL_ 482 BDCS4_FLTyre_SensorFailure 1 "Sensoe Failure" 0 "No Sensoe Failure";
VAL_ 482 BDCS4_FLTyre_LowBattery 1 "Low Battery" 0 "Normal Battery";
VAL_ 482 BDCS4_FRTyre_LearntSt 1 "Learnt" 0 "Not Learnt";
VAL_ 482 BDCS4_FRTyre_PressureWarn 3 "High Pressure" 2 "Low Pressure" 1 "Pre-warning" 0 "Normal Pressure";
VAL_ 482 BDCS4_FRTyre_TemperatureWarn 1 "High Temperature" 0 "Normal Temperature";
VAL_ 482 BDCS4_FRTyre_QucikLeak 1 "Quick Leak" 0 "No Quick Leak";
VAL_ 482 BDCS4_FRTyre_SensorFailure 1 "Sensoe Failure" 0 "No Sensoe Failure";
VAL_ 482 BDCS4_FRTyre_LowBattery 1 "Low Battery" 0 "Normal Battery";
VAL_ 482 BDCS4_Testmode 1 "Test Mode" 0 "No Test Mode";
VAL_ 482 BDCS4_SystemFailure 3 "TPMS Not All" 2 "Pressure Abnormal" 1 "System Not OK" 0 "System OK";
VAL_ 484 BDCS5_Rtyre_Status 1 "Last Signal" 0 "Current Signal";
VAL_ 484 BDCS5_RLTyre_LearntSt 1 "Learnt" 0 "Not Learnt";
VAL_ 484 BDCS5_RLTyre_PressureWarn 3 "High Pressure" 2 "Low Pressure" 1 "Pre-warning" 0 "Normal Pressure";
VAL_ 484 BDCS5_RLTyre_TemperatureWarn 1 "High Temperature" 0 "Normal Temperature";
VAL_ 484 BDCS5_RLTyre_QucikLeak 1 "Quick Leak" 0 "No Quick Leak";
VAL_ 484 BDCS5_RLTyre_SensorFailure 1 "Sensoe Failure" 0 "No Sensoe Failure";
VAL_ 484 BDCS5_RLTyre_LowBattery 1 "Low Battery" 0 "Normal Battery";
VAL_ 484 BDCS5_RRTyre_LearntSt 1 "Learnt" 0 "Not Learnt";
VAL_ 484 BDCS5_RRTyre_PressureWarn 3 "High Pressure" 2 "Low Pressure" 1 "Pre-warning" 0 "Normal Pressure";
VAL_ 484 BDCS5_RRTyre_TemperatureWarn 1 "High Temperature" 0 "Normal Temperature";
VAL_ 484 BDCS5_RRTyre_QucikLeak 1 "Quick Leak" 0 "No Quick Leak";
VAL_ 484 BDCS5_RRTyre_SensorFailure 1 "Sensoe Failure" 0 "No Sensoe Failure";
VAL_ 484 BDCS5_RRTyre_LowBattery 1 "Low Battery" 0 "Normal Battery";
VAL_ 486 BDCS6_KeyNotFindIndication 1 "Active" 0 "Inactive";
VAL_ 486 BDCS6_FindMyCar_Sts_feedback 1 "闪灯" 0 "闪灯+鸣笛";
VAL_ 486 BDCS6_KeySearchingSts 1 "Searching" 0 "Not searching";
VAL_ 486 BDCS6_KeylessWarningLight 1 "Active" 0 "Inactive";
VAL_ 486 BDCS6_KeyLowBatteryIndication 1 "Active" 0 "Inactive";
VAL_ 486 BDCS6_KeyInIndication 1 "Active" 0 "Inactive";
VAL_ 486 BDCS6_DepressBrakePedalInd 1 "Active" 0 "Inactive";
VAL_ 486 BDCS6_ShiftGearToPNIndication 1 "Active" 0 "Inactive";
VAL_ 486 BDCS6_ShiftGearToPIndication 1 "Active" 0 "Inactive";
VAL_ 486 BDCS6_BackupStartIndication 1 "Active" 0 "Inactive";
VAL_ 486 BDCS6_WiperNozzleHeat_SW_Fed 1 "ON" 0 "OFF";
VAL_ 486 BDCS6_ALHSelectModeCtrlFed 4 "General" 3 "Music" 2 "Reserved" 1 "Speed" 0 "Initialization";
VAL_ 486 BDCS6_FrontWasherSts 1 "ON" 0 "OFF";
VAL_ 486 BDCS6_FrontWiperParkPos 1 "Park" 0 "Not park";
VAL_ 486 BDCS6_FrontWiperSts 7 "Reserved3" 6 "Reserved2" 5 "Reserved1" 4 "Reserved0" 3 "Reserved" 2 "High" 1 "Low" 0 "OFF";
VAL_ 486 BDCS6_FrontWiperMaintenancePos 1 "ON" 0 "OFF";
VAL_ 486 BDCS6_RearWiperSts 1 "ON" 0 "OFF";
VAL_ 486 BDCS6_RearWiperParkPos 1 "Park" 0 "Not park";
VAL_ 486 BDCS6_RearWasherSts 1 "ON" 0 "OFF";
VAL_ 486 BDCS6_RearDefrostSts 1 "Active" 0 "InActive";
VAL_ 486 BDCS6_IHU_AC_St 1 "ON" 0 "OFF";
VAL_ 486 BDCS6_ALH_SW_Fed 1 "ON" 0 "OFF";
VAL_ 486 BDCS6_EntryMode_Fed 1 "ON" 0 "OFF";
VAL_ 486 BDCS6_AEBMode_Fed 1 "ON" 0 "OFF";
VAL_ 486 BDCS6_LockUpWindowSETfbk 3 "OFF（保持原状态）" 2 "留缝" 1 "Close" 0 "No Action";
VAL_ 486 BDCS6_LOGOLampST 1 "Disable" 0 "Enable";
VAL_ 486 BDCS6_AUTOHOLDLamp 1 "Disable" 0 "Enable";
VAL_ 486 BDCS6_WiperNozzleHeat_Fdb 7 "Reserved" 6 "Reserved" 5 "T≤-15" 4 "-15＜T≤-10" 3 "-10＜T≤-5" 2 "-5＜T≤0" 1 "0＜T≤5" 0 "No Request";
VAL_ 486 BDCS6_BiologicalDetectionFbk 1 "ON" 0 "OFF";
VAL_ 486 BDCS6_ALH_DriveModeSW_Fed 1 "ON" 0 "OFF";
VAL_ 486 BDCS6_ALH_TemperatureSW_Fed 1 "ON" 0 "OFF";
VAL_ 486 BDCS6_ALHSelectColourCtrlFed 3 "Multicolor Mode" 2 "Monoclour Mode" 1 "Drive Mode" 0 "Default";
VAL_ 486 BDCS6_RoadRecSts 1 "ON" 0 "OFF";
VAL_ 486 BDCS6_DGM_percentSts 31 "INVALID" 11 "100%" 10 "90%" 9 "80%" 8 "70%" 7 "60%" 6 "50%" 5 "40%" 4 "30%" 3 "20%" 2 "10%" 1 "0%" 0 "Default";
VAL_ 486 BDCS6_DGM_SWSts 3 "INVALID" 2 "CLOSE" 1 "OPEN" 0 "Default";
VAL_ 486 BDCS6_ChargingLamp_Fdb 1 "ON" 0 "OFF";
VAL_ 486 BDCS6_LowBeamSt_F 1 "Failure" 0 "Normal";
VAL_ 486 BDCS6_HighBeamSt_F 1 "Failure" 0 "Normal";
VAL_ 486 BDCS6_PositionLightSts_F 1 "Failure" 0 "Normal";
VAL_ 486 BDCS6_LeftTurnLightSt_F 1 "Failure" 0 "Normal";
VAL_ 486 BDCS6_RightTurnLightSt_F 1 "Failure" 0 "Normal";
VAL_ 486 BDCS6_BrakeLightSts_F 1 "Failure" 0 "Normal";
VAL_ 486 BDCS6_RearFogLampSt_F 1 "Failure" 0 "Normal";
VAL_ 486 BDCS6_DRLSt_F 1 "Failure" 0 "Normal";
VAL_ 486 BDCS6_FLcorneringLampSt 2 "Failure" 1 "Active" 0 "Inactive";
VAL_ 486 BDCS6_FRcorneringLampSt 2 "Failure" 1 "Active" 0 "Inactive";
VAL_ 486 BDCS6_DayNightMode 2 "Night mode" 1 "Day mode" 0 "Default";
VAL_ 486 BDCS6_ALHBrightnessAutoMode_Fdb 3 "Reserved" 2 "Manual mode" 1 "Auto mode" 0 "Initialization";
VAL_ 486 BDCS6_SOC_Lamp_Fdb 1 "ON" 0 "OFF";
VAL_ 486 BDCS6_AutoDfrostSts 1 "on" 0 "off";
VAL_ 486 BDCS6_AutoDrySts 1 "on" 0 "off";
VAL_ 486 BDCS6_BtmCallAutoSpdSts 1 "on" 0 "off";
VAL_ 486 BDCS6_AutoAionSts 1 "on" 0 "off";
VAL_ 486 BDCS6_AQSConfigSts 1 "on" 0 "off";
VAL_ 486 BDCS6_PM25AutoCleanPopupSts 1 "on" 0 "off";
VAL_ 486 BDCS6_CabinCleanConfigSts 1 "on" 0 "off";
VAL_ 486 BDCS6_ALH_ADASWarning_Fdb 1 "on" 0 "off";
VAL_ 486 BDCS6_ALHSelectTheme_Fdb 7 "Reserved" 6 "Reserved" 5 "Theme5" 4 "Theme4" 3 "Theme3" 2 "Theme2" 1 "Theme1" 0 "No Request";
VAL_ 486 BDCS6_SunRoofSLideCtrlReq_Fdb 31 "Reserved" 30 "Reserved" 29 "Reserved" 28 "Reserved" 27 "Reserved" 26 "Reserved" 25 "Reserved" 24 "Reserved" 23 "Reserved" 22 "Reserved" 21 "Tilt Area" 20 "100%" 19 "95%" 18 "90%" 17 "85%" 16 "80%" 15 "75%" 14 "70%" 13 "65%" 12 "60%" 11 "55%" 10 "50%" 9 "45%" 8 "40%" 7 "35%" 6 "30%" 5 "25%" 4 "20%" 3 "15%" 2 "10%" 1 "5%" 0 "0%";
VAL_ 486 BDCS6_SunRoofCtrlReq_Fdb 7 "Reserved" 6 "Reserved" 5 "Reserved" 4 "Open开启" 3 "Comfort舒适" 2 "Tilt 通风" 1 "Close关闭" 0 "Default";
VAL_ 486 BDCS6_CurtainSLideCtrlReq_Fdb 31 "Reserved" 30 "Reserved" 29 "Reserved" 28 "Reserved" 27 "Reserved" 26 "Reserved" 25 "Reserved" 24 "Reserved" 23 "Reserved" 22 "Reserved" 21 "Reserved" 20 "100%" 19 "95%" 18 "90%" 17 "85%" 16 "80%" 15 "75%" 14 "70%" 13 "65%" 12 "60%" 11 "55%" 10 "50%" 9 "45%" 8 "40%" 7 "35%" 6 "30%" 5 "25%" 4 "20%" 3 "15%" 2 "10%" 1 "5%" 0 "0%";
VAL_ 496 BDCS2_DoorLockCmd 3 "DriverDoor Unlock" 2 "AllDoor Lock" 1 "AllDoor Unlock" 0 "No Request";
VAL_ 496 BDCS2_FLWindowsCtrl 5 "留缝" 4 "Auto Down" 3 "Auto Up" 2 "Manual Down" 1 "Manual Up" 0 "No request";
VAL_ 496 BDCS2_FRWindowsCtrl 5 "留缝" 4 "Auto Down" 3 "Auto Up" 2 "Manual Down" 1 "Manual Up" 0 "No request";
VAL_ 496 BDCS2_RLWindowsCtrl 5 "留缝" 4 "Auto Down" 3 "Auto Up" 2 "Manual Down" 1 "Manual Up" 0 "No request";
VAL_ 496 BDCS2_RRWindowsCtrl 5 "留缝" 4 "Auto Down" 3 "Auto Up" 2 "Manual Down" 1 "Manual Up" 0 "No request";
VAL_ 496 BDCS2_FrontDoorOpenModeSts 2 "Driver door and front passenger door" 1 "Front passenger door" 0 "Driver door";
VAL_ 496 BDCS2_OpenFLDoorReq 3 "Suspend" 2 "Close" 1 "Open" 0 "No request";
VAL_ 496 BDCS2_OpenFRDoorReq 3 "Suspend" 2 "Close" 1 "Open" 0 "No request";
VAL_ 496 BDCS2_LSD_FL_Away_Up_Sts 3 "Reserved" 2 "OFF" 1 "ON" 0 "Default";
VAL_ 496 BDCS2_LSD_FR_Away_Up_Sts 3 "Reserved" 2 "OFF" 1 "ON" 0 "Default";
VAL_ 496 BDCS2_RainwinClosedFbk 3 "Reserved" 2 "Failed" 1 "Complete" 0 "Default";
VAL_ 496 BDCS2_SunRoof_GlassMovement 3 "Reserved" 2 "Moving" 1 "Stopped" 0 "Default";
VAL_ 496 BDCS2_Curtain_Movement 3 "Reserved" 2 "Moving" 1 "Stopped" 0 "Default";
VAL_ 496 BDCS2_CarTempHoldMode_Fdb 3 "Reserved" 2 "OFF" 1 "ON" 0 "No action";
VAL_ 496 BDCS2_RemoteFindCarStsFdb 1 "Active" 0 "Inactive";
VAL_ 496 BDCS2_CurtainCtrlReq_Fdb 3 "Reserved" 2 "ON" 1 "OFF" 0 "Default";
VAL_ 496 BDCS2_SRMGlassInitialized 1 "Initialized" 0 "De-initialized";
VAL_ 496 BDCS2_SRMTeachingRunningSts 1 "Teach run successful" 0 "No teach run";
VAL_ 496 BDCS2_CurtainInitialized 1 "Initialized" 0 "De-initialized";
VAL_ 496 BDCS2_CurtainTeachingRunningSts 1 "Teach run successful" 0 "No teach run";
VAL_ 496 BDCS2_TemKeepModeRmd 1 "Reminder" 0 "No Reminder";
VAL_ 496 BDCS2_TemKeepModeExitFailRsn 3 "Reserved" 2 "POWer not support" 1 "CentralLock not lock" 0 "Default";
VAL_ 496 BDCS2_SRMOverspeedClosing 1 "Active" 0 "Inactive";
VAL_ 512 BDCS20_bParkPosnReq 1 "Action" 0 "No Action";
VAL_ 512 BDCS20_bAcvCmprSpdLim 1 "Action" 0 "No Action";
VAL_ 512 BDCS20_bAcvExvPosnRchdMax 1 "Action" 0 "No Action";
VAL_ 512 BDCS20_bAcvCtlForPRlf 1 "Action" 0 "No Action";
VAL_ 512 BDCS20_bBlowrClnReq 1 "Action" 0 "No Action";
VAL_ 512 BDCS20_bBodyCtlrSleepAllwd 1 "Action" 0 "No Action";
VAL_ 512 BDCS20_bAcvFlapIniDoneFlg 1 "Action" 0 "No Action";
VAL_ 512 BDCS20_bAirDefrstDibtnReq 1 "Action" 0 "No Action";
VAL_ 512 BDCS20_bAirFaceDibtnReq 1 "Action" 0 "No Action";
VAL_ 512 BDCS20_bAirFootDibtnReq 1 "Action" 0 "No Action";
VAL_ 512 BDCS20_StPerfEve 3 "max defrost" 2 "max heating" 1 "max AC" 0 "no request";
VAL_ 512 BDCS20_ModeHvacThermReq 3 "reheating" 2 "heating mode" 1 "cooling mode" 0 "no request";
VAL_ 512 BDCS20_StCircHeatgThermMode 3 "both heating" 2 "cabin heating" 1 "battery heating" 0 "No request";
VAL_ 512 BDCS20_StRfgtCircThermMode 3 "both cooling" 2 "cabin cooling" 1 "battery cooling" 0 "No request";
VAL_ 512 BDCS20_StHumCtlEve 6 "humidity control event risk6" 5 "humidity control event risk5" 4 "humidity control event risk4" 3 "humidity control event risk3" 2 "humidity control event risk2" 1 "humidity control event risk1" 0 "not risk";
VAL_ 512 BDCS20_StPtThermMode 4 "Heat homogenization" 3 "Heat recovery" 2 "Active cooling" 1 "Natrual cooling" 0 "Off";
VAL_ 512 BDCS20_ModePwrDstnModeRaw 4 "Refrigerant only mode" 3 "PTC only mode" 2 "PTC first mode" 1 "Refrigerant first mode" 0 "NaN mode";
VAL_ 512 BDCS20_StEve 10 "air quality event" 9 "humidity control event risk6" 8 "humidity control event risk5" 7 "humidity control event risk4" 6 "humidity control event risk3" 5 "humidity control event risk2" 4 "humidity control event risk1" 3 "max defrost" 2 "max heating" 1 "max AC" 0 "no request";
VAL_ 512 BDCS20_NrEvst 10 "10" 9 "9" 8 "8" 7 "7" 6 "6" 5 "5" 4 "4" 3 "3" 2 "2" 1 "1" 0 "0";
VAL_ 490 BDCS21_BrakeLightSts_F 1 "Active" 0 "Inactive";
VAL_ 564 BDCS10_AGS_Pos_Cmd 15 "Open" 14 "93.75%" 13 "87.5%" 12 "81.25%" 11 "75%" 10 "68.75%" 9 "62.5%" 8 "56.25%" 7 "50%" 6 "43.75%" 5 "37.5%" 4 "31.25%" 3 "25%" 2 "18.75%" 1 "12.5%" 0 "Close";
VAL_ 564 BDCS10_AGS_Cali_Cmd 1 "CALIB_ENABLE" 0 "CALIB_DISABLE";
VAL_ 564 BDCS10_AGS_Curr_Limit_Cmd 3 "Boosted Torque Mode 1" 2 "Boosted Torque Mode 0" 1 "Low Torque Mode" 0 "Torque Mode 0";
VAL_ 564 BDCS10_FTWV_A_MoveEnable 1 "ReqMotorMove" 0 "NoReq";
VAL_ 564 BDCS10_FTWV_B_MoveEnable 1 "ReqMotorMove" 0 "NoReq";
VAL_ 564 BDCS10_EXV_B_MoveEnb 1 "Move to Commanded Position" 0 "Ignore Commanded Position";
VAL_ 564 BDCS10_EWP_H_DefaultReq 1 "Default Operation" 0 "Default Sleep";
VAL_ 564 BDCS10_EXV_B_InitReq 2 "waiting for Sequence to finish" 1 "start Init-Sequence" 0 "No Request";
VAL_ 564 BDCS10_EWP_B_DefaultReq 1 "Default Operation" 0 "Default Sleep";
VAL_ 564 BDCS10_EWP_M_DefaultRq 1 "Default Operation" 0 "Default Sleep";
VAL_ 565 EXV_B_LINRespErr 1 "Lin_Respone_Error" 0 "No_error";
VAL_ 565 EXV_B_curInit_Stat 3 "Invalid" 2 "Initialized" 1 "Initialization in Process" 0 "Not Initialized";
VAL_ 565 EXV_B_Run_Stat 1 "Actuator is moving" 0 "Actuator is not moving";
VAL_ 565 EXV_B_Fault_Stat 15 "Reserved" 14 "Reserved" 13 "Reserved" 12 "Reserved" 11 "Reserved" 10 "Reserved" 9 "Reserved" 8 "Reserved" 7 "Reserved" 6 "Reserved" 5 "Motor_Stall" 4 "not defined" 3 "Over temperature shutdown" 2 "Motor-Coil open load" 1 "Motor-Coil shorted" 0 "Actuator Not Faulted";
VAL_ 565 EXV_B_Volt_Stat 3 "Not defined" 2 "Under voltage" 1 "Over voltage" 0 "Voltage Range ok";
VAL_ 565 EXV_B_OvrTemp_Warn 3 "not defined" 2 "not defined" 1 "High Temperature Warning" 0 "Ok";
VAL_ 565 EWP_H_LINRespErr 1 "Lin_Respone_Error" 0 "No_error";
VAL_ 565 EWP_B_LINRespErr 1 "Lin_Respone_Error" 0 "No_error";
VAL_ 565 EWP_M_LINRespErr 1 "Lin_Respone_Error" 0 "No_error";
VAL_ 565 FTWV_A_Rsp_Comm_Err 1 "LIN Communication Error" 0 "No_error";
VAL_ 565 EWP_H_OverCurr_Error 2 "SNA" 1 "ERROR" 0 "NO ERROR";
VAL_ 565 EWP_H_DryRun_Error 2 "SNA" 1 "ERROR" 0 "NO ERROR";
VAL_ 565 EWP_H_SupVolt_Error 2 "SNA" 1 "ERROR" 0 "NO ERROR";
VAL_ 565 EWP_H_Block_Error 2 "SNA" 1 "ERROR" 0 "NO ERROR";
VAL_ 565 EWP_H_OverTemp_Error 2 "OverTempDegrade" 1 "ERROR" 0 "NO ERROR";
VAL_ 565 EWP_B_OverTemp_Error 2 "OverTempDegrade" 1 "ERROR" 0 "NO ERROR";
VAL_ 565 EWP_M_OverTemp_Error 2 "OverTempDegrade" 1 "ERROR" 0 "NO ERROR";
VAL_ 565 FTWV_B_Rsp_Comm_Err 1 "LIN Communication Error" 0 "No_error";
VAL_ 565 EWP_B_OverCurr_Error 2 "SNA" 1 "ERROR" 0 "NO ERROR";
VAL_ 565 EWP_B_DryRun_Error 2 "SNA" 1 "ERROR" 0 "NO ERROR";
VAL_ 565 EWP_B_SupVolt_Error 2 "SNA" 1 "ERROR" 0 "NO ERROR";
VAL_ 565 EWP_B_Block_Error 2 "SNA" 1 "ERROR" 0 "NO ERROR";
VAL_ 565 EWP_M_OverCurr_Error 2 "SNA" 1 "ERROR" 0 "NO ERROR";
VAL_ 565 EWP_M_DryRun_Error 2 "SNA" 1 "ERROR" 0 "NO ERROR";
VAL_ 565 EWP_M_SupVolt_Error 2 "SNA" 1 "ERROR" 0 "NO ERROR";
VAL_ 565 EWP_M_Block_Error 2 "SNA" 1 "ERROR" 0 "NO ERROR";
VAL_ 565 FTWV_A_Fault_Signal 15 "Reserved" 14 "Reserved" 13 "Reserved" 12 "Reserved" 11 "Reserved" 10 "Reserved" 9 "Reserved" 8 "Reserved" 7 "Reserved" 6 "Reserved" 5 "Reserved" 4 "Overcurrent Detected" 3 "OverTemp Shutdown" 2 "Stall Detected" 1 "Coil Open Detected" 0 "No_Fault";
VAL_ 565 FTWV_A_VoltageErr 3 "Reserved" 2 "Lack Voltage" 1 "Over voltage" 0 "Normal";
VAL_ 565 FTWV_A_TempWarn 1 "temp warn" 0 "Normal";
VAL_ 565 FTWV_A_MotorStatus 1 "Motor Running" 0 "Motor Stop";
VAL_ 565 FTWV_B_Fault_Signal 15 "Reserved" 14 "Reserved" 13 "Reserved" 12 "Reserved" 11 "Reserved" 10 "Reserved" 9 "Reserved" 8 "Reserved" 7 "Reserved" 6 "Reserved" 5 "Reserved" 4 "Overcurrent Detected" 3 "OverTemp Shutdown" 2 "Stall Detected" 1 "Coil Open Detected" 0 "No_Fault";
VAL_ 565 FTWV_B_VoltageErr 3 "Reserved" 2 "Lack Voltage" 1 "Over voltage" 0 "Normal";
VAL_ 565 FTWV_B_TempWarn 1 "temp warn" 0 "Normal";
VAL_ 565 FTWV_B_MotorStatus 1 "Motor Running" 0 "Motor Stop";
VAL_ 565 BDCS15_HPTMD_StHeatgMode 3 "Reserved" 2 "Heat pump mode using ambient and e-drive as heat source" 1 "Heat pump mode using e-drive as heat source" 0 "Without heat pump mode";
VAL_ 645 BDCS13_RLS_HUDBrightnessSnrFault 1 "Error" 0 "No error";
VAL_ 645 BDCS13_RLS_HUDBrightUnit 3 "invalid" 2 "1000 lux" 1 "100 lux" 0 "10 lux";
VAL_ 645 BDCS13_RLS_REP_Error 1 "Error" 0 "No error";
VAL_ 645 BDCS13_RLS_VOLT_Error 3 "Not used" 2 "VOLT_High" 1 "VOLT_Low" 0 "No error";
VAL_ 645 BDCS13_RLS_RQ_WiperSPD 3 "Not used" 2 "High Speed" 1 "Low Speed" 0 "No wiping";
VAL_ 645 RATS1_DFGLS_ButtonSoundRequest 1 "Request" 0 "NO Request";
VAL_ 645 DGM_IntelligentProtectionSt 1 "ON" 0 "OFF";
VAL_ 645 DGM_AutoSWSts 1 "ON" 0 "OFF";
VAL_ 645 BDCS13_CO2_State 3 "传感器控制单元出错" 2 "传感器测量停止" 1 "传感器受限" 0 "正常";
VAL_ 645 BDCS13_CO2_DensitySts 3 "取消高浓度报警" 2 "车辆停止运行时浓度过高" 1 "车辆运行时浓度过高" 0 "正常浓度";
VAL_ 645 BDCS13_IN_TrunkSWStatus 1 "Press" 0 "No press";
VAL_ 645 BDCS13_RLS_Rain_state 1 "rainy" 0 "No rain";
VAL_ 645 BDCS13_OUT_TrunkSWStatus 1 "Press" 0 "No press";
VAL_ 645 BDCS13_TrunkDrivingStatus 1 "Active" 0 "Inactive";
VAL_ 645 BDCS13_SRM_FaultMessage 7 "Reserved" 6 "Reserved" 5 "Sunshield Thermal" 4 "Sunshield Anti-pinch" 3 "Response Error" 2 "SR Thermal Protect" 1 "SR Anti-pinch" 0 "No Error";
VAL_ 661 BDCS11_AC_EAC_Command 3 "Invalid" 2 "ON" 1 "OFF" 0 "Self Test";
VAL_ 661 BDCS11_AC_PTC_Request 3 "Reserved" 2 "按档位" 1 "按目标温度" 0 "无请求";
VAL_ 661 BDCS11_AcFilter_SOH_Valid 1 "Valid" 0 "No Valid";
VAL_ 661 BDCS11_PumpHTarSpdValid 1 "Valid" 0 "Invalid";
VAL_ 661 BDCS11_FogRiskLvl 7 "Reserved" 6 "Level 6" 5 "Level 5" 4 "Level 4" 3 "Level 3" 2 "Level 2" 1 "Level 1" 0 "No Level";
VAL_ 661 BDCS11_AC_FanGearPwmReqV 1 "Valid" 0 "Invalid";
VAL_ 661 BDCS11_PM25WorkReq 1 "Measuring传感器采集" 0 "Standby传感器待机";
VAL_ 661 BDCS11_PM25RealSts 3 "Invalid" 2 "Complete 完成空气检测" 1 "Running 工作状态" 0 "Standby 待机状态";
VAL_ 661 BDCS11_ACMaxSts 1 "ON" 0 "OFF";
VAL_ 661 BDCS11_HeatMaxSts 1 "ON" 0 "OFF";
VAL_ 661 BDCS11_AirCleanSts 1 "ON" 0 "OFF";
VAL_ 661 BDCS11_ECONModeSts 1 "ON" 0 "OFF";
VAL_ 661 BDCS11_BlowModSts 7 "吹脸吹脚吹窗模式" 6 "吹脚吹窗模式" 5 "吹脸吹窗模式" 4 "吹脸吹脚模式" 3 "吹窗模式" 2 "吹脚模式" 1 "吹脸模式" 0 "Inactive";
VAL_ 661 BDCS11_PMAirInQLevel 7 "Invalid" 6 "Level 6 PM2.5≤999 And PM2.5>250" 5 "Level 5 PM2.5≤250 And PM2.5>150" 4 "Level 4 PM2.5≤150 And PM2.5>115" 3 "Level 3 PM2.5≤115 And PM2.5>75" 2 "Level 2 PM2.5≤75 And PM2.5>35" 1 "Level 1 PM2.5≤35" 0 "Inactive";
VAL_ 661 BDCS11_CabModeSts 7 "采暖" 6 "未用" 5 "再加热" 4 "制冷除湿" 3 "未用" 2 "制冷" 1 "通风" 0 "停机";
VAL_ 661 BDCS11_HeatMngtFctLim 1 "功能限制" 0 "功能正常";
VAL_ 661 BDCS11_BatModeSts 4 "自然冷却" 3 "主动加热" 2 "主动冷却" 1 "自然循环" 0 "关闭";
VAL_ 661 BDCS11_PwrModeSts 4 "均温" 3 "余热回收" 2 "主动冷却" 1 "自然冷却" 0 "关闭";
VAL_ 661 BDCS11_ELV1Pos 1 "ON" 0 "OFF";
VAL_ 661 BDCS11_ELV1Flt 1 "Error" 0 "No error";
VAL_ 661 BDCS11_ELV2Pos 1 "ON" 0 "OFF";
VAL_ 661 BDCS11_ELV2Flt 1 "Error" 0 "No error";
VAL_ 661 BDCS11_ELV3Pos 1 "ON" 0 "OFF";
VAL_ 661 BDCS11_ELV3Flt 1 "Error" 0 "No error";
VAL_ 661 BDCS11_ELV4Pos 1 "ON" 0 "OFF";
VAL_ 661 BDCS11_ELV4Flt 1 "Error" 0 "No error";
VAL_ 661 BDCS11_ComLost_EXV1 1 "Error" 0 "No error";
VAL_ 661 BDCS11_ComLost_EXV_H 1 "Error" 0 "No error";
VAL_ 661 BDCS11_EXV1Flt 1 "Error" 0 "No error";
VAL_ 661 BDCS11_EXV_H_Flt 1 "Error" 0 "No error";
VAL_ 661 BDCS11_BlowrRlySts 1 "ON" 0 "OFF";
VAL_ 661 BDCS11_HeatingWireSts 1 "ON" 0 "OFF";
VAL_ 661 BDCS11_EXV1EnableReq 1 "Enable" 0 "Not Enable";
VAL_ 661 BDCS11_EXV1CalibReq 1 "Initialization_Req" 0 "No_Req";
VAL_ 661 BDCS11_HPVTMSModeSts 15 "Reserved" 14 "Filling" 13 "HVB Heating with E-Drive" 12 "HVB Radiator Cooling" 11 "HVB Heat Recovery" 10 "Cabin Reheat and HVB Heating" 9 "Cabin and HVB Heating" 8 "Cabin Reheat (heating)" 7 "Cabin Heating" 6 "HVB Heating" 5 "Cabin Reheat and HVB Cooling" 4 "Cabin and HVB Cooling" 3 "Cabin Reheat (cooling)" 2 "Cabin Cooling" 1 "HVB Cooling" 0 "Default";
VAL_ 661 BDCS11_OilHeatingSwEnable 1 "Enable" 0 "Disable";
VAL_ 661 BDCS11_OilHeatingFuelLevel 7 "Reserved" 6 "Reserved" 5 "Reserved" 4 "四格" 3 "三格" 2 "二格" 1 "一格" 0 "空";
VAL_ 661 BDCS11_OilHeatingWarn 7 "Reserved" 6 "Unable to open due to high temperature" 5 "Not in AC heating mode" 4 "Unable to open during charging" 3 "Fuel empty" 2 "OHC Fault" 1 "No heater found" 0 "None";
VAL_ 661 BDCS11_OilHeatingWorkSts 3 "Reserved" 2 "ON（显示工作图标）" 1 "OFF（显示未工作图标）" 0 "None（不显示图标）";
VAL_ 661 BDCS11_OilHeatingSwSts 1 "ON" 0 "OFF";
VAL_ 661 BDCS11_TWV1ActSaveReq 3 "SNA" 2 "Reserved" 1 "ActiveSave_Req" 0 "NoReq";
VAL_ 661 BDCS11_TWV1CalibReq 3 "SNA" 2 "Reserved" 1 "REFDRV_Req" 0 "NoReq";
VAL_ 661 BDCS11_TWV1ModeSts 2 "Learning" 1 "MotorOff" 0 "Normaloperation";
VAL_ 661 BDCS11_TWV1ValCmd 95 "95%" 30 "30%" 60 "60%" 90 "90%" 25 "25%" 55 "55%" 85 "85%" 20 "20%" 50 "50%" 80 "80%" 15 "15%" 45 "45%" 75 "75%" 10 "10%" 40 "40%" 70 "70%" 5 "5%" 100 "100%" 35 "35%" 65 "65%" 0 "0%";
VAL_ 661 BDCS11_TWV1ActVal 95 "95%" 30 "30%" 60 "60%" 90 "90%" 25 "25%" 55 "55%" 85 "85%" 20 "20%" 50 "50%" 80 "80%" 15 "15%" 45 "45%" 75 "75%" 10 "10%" 40 "40%" 70 "70%" 5 "5%" 100 "100%" 35 "35%" 65 "65%" 0 "0%";
VAL_ 661 BDCS11_EXV1InitSts 3 "Invalid" 2 "Initialized" 1 "Initialization in Process" 0 "Not Initialized";
VAL_ 661 BDCS11_EXV_H_InitSts 3 "Invalid" 2 "Initialized" 1 "Initialization in Process" 0 "Not Initialized";
VAL_ 661 BDCS11_NVMSts 2 "NVRAM failure" 1 "Success NVRAM storage" 0 "NVRAM empty";
VAL_ 661 BDCS11_ComLost_TWV1 1 "Error" 0 "No error";
VAL_ 661 BDCS11_TWV1Flt 1 "Error" 0 "No error";
VAL_ 664 BDCS12_InsideTemp 255 "Invalid";
VAL_ 664 BDCS12_InsideTempValid 1 "Valid" 0 "Invalid";
VAL_ 664 BDCS12_OutletTempValid 1 "Valid" 0 "Invalid";
VAL_ 664 BDCS12_UncoolReason 7 "Reserved" 6 "蒸发器温度传感器故障" 5 "冷却风扇故障" 4 "压力传感器故障" 3 "HV故障" 2 "电子膨胀阀故障" 1 "压缩机故障" 0 "无异常";
VAL_ 664 BDCS12_UnheatReason 4 "三通水阀故障" 3 "PTC水泵故障" 2 "HV故障" 1 "PTC故障" 0 "无异常";
VAL_ 664 BDCS12_SensorFailCode 12 "循环执行器反馈异常" 11 "混合执行器反馈异常" 10 "模式执行器反馈异常" 9 "鼓风机反馈异常" 8 "吹脚出风口温度传感器" 7 "负离子发生器异常" 6 "PM2.5传感器异常" 5 "阳光传感器异常" 4 "蒸发器传感器异常" 3 "室内温度传感器异常" 2 "室外温度传感器异常" 1 "出风口温度传感器" 0 "无异常";
VAL_ 664 BDCS12_ThermalSts 10 "乘员舱加热+BAT冷却" 9 "乘员舱制冷+BAT制冷" 8 "乘员舱加热+BAT加热" 7 "BAT制冷" 6 "BAT加热" 5 "乘员舱PTC采暖" 4 "乘员舱热泵采暖" 3 "乘员舱除湿采暖" 2 "乘员舱制冷" 1 "乘员舱通风" 0 "停机";
VAL_ 664 BDCS12_DisplayInfo 5 "message5" 4 "message4" 3 "message3" 2 "message2,缩短充电时间" 1 "Message1,空调开启" 0 "无信息反馈";
VAL_ 664 BDCS12_EVAPTempValid 1 "Valid" 0 "Invalid";
VAL_ 664 BDCS12_InCarClimateSystemFault 1 "fault present" 0 "no fault";
VAL_ 664 BDCS12_BatteryThermalSystemFault 1 "fault present" 0 "no fault";
VAL_ 664 BDCS12_FragranceType_Position_1 15 "Reserved (预留）" 11 "Reserved (预留）" 10 "Type_10 (森林）" 9 "Type_9 (绚丽栀子花）" 8 "Type_8 (天竺葵先生）" 7 "Type_7 (保加利亚玫瑰）" 6 "Type_6 (白色广藿香）" 5 "Type_5 (清风）" 4 "Type_4 (薰衣草天堂）" 3 "Type_3 (雨后花园）" 2 "Type_2 (白茶）" 1 "Type_1 (秘境)" 0 "No Type (无香型)";
VAL_ 664 BDCS12_FragranceType_Position_2 15 "Reserved (预留）" 11 "Reserved (预留）" 10 "Type_10 (森林）" 9 "Type_9 (绚丽栀子花）" 8 "Type_8 (天竺葵先生）" 7 "Type_7 (保加利亚玫瑰）" 6 "Type_6 (白色广藿香）" 5 "Type_5 (清风）" 4 "Type_4 (薰衣草天堂）" 3 "Type_3 (雨后花园）" 2 "Type_2 (白茶）" 1 "Type_1 (秘境)" 0 "No Type (无香型)";
VAL_ 664 BDCS12_FragranceType_Position_3 15 "Reserved (预留）" 11 "Reserved (预留）" 10 "Type_10 (森林）" 9 "Type_9 (绚丽栀子花）" 8 "Type_8 (天竺葵先生）" 7 "Type_7 (保加利亚玫瑰）" 6 "Type_6 (白色广藿香）" 5 "Type_5 (清风）" 4 "Type_4 (薰衣草天堂）" 3 "Type_3 (雨后花园）" 2 "Type_2 (白茶）" 1 "Type_1 (秘境)" 0 "No Type (无香型)";
VAL_ 664 BDCS12_FM_FragrancePositionSts 3 "Fragrance Position_3 (位置3的香型）" 2 "Fragrance Position_2 (位置2的香型）" 1 "Fragrance Position_1 (位置1的香型)" 0 "Initial value";
VAL_ 664 BDCS12_FM_FragranceWorkingSts 1 "Running" 0 "Standby";
VAL_ 664 BDCS12_FM_FragranceConcentration 3 "High concentration" 2 "Middle concentration" 1 "Low concentration" 0 "Initial value";
VAL_ 664 BDCS12_LEAOSts 4 "自动扫风" 3 "镜像模式" 2 "避人模式" 1 "脸部清爽" 0 "手动模式";
VAL_ 664 BDCS12_AQSCycleSts 2 "外循环状态" 1 "内循环状态" 0 "Inactive";
VAL_ 664 BDCS12_AQSValue 7 "error_PMW_10%±2%" 6 "Level 5_PMW_40%±2%" 5 "Level 4_PMW_50%±2%" 4 "Level 3_PMW_60%±2%" 3 "Level 2_PMW_70%±2%" 2 "Level 1_PMW_80%±2%" 1 "Level 0_PMW_90%±2%" 0 "Inactive";
VAL_ 664 BDCS12_FragranceFaultSts 1 "Fault" 0 "No Fault";
VAL_ 664 BDCS12_PM25FltSta 3 "Open Circuit 传感器开路" 2 "Short Circuit 传感器短路" 1 "Error 传感器错误" 0 "No Error 正常";
VAL_ 664 BDCS12_SolarError 1 "Error" 0 "No error";
VAL_ 664 BDCS12_HumidTemp_Error 1 "Error" 0 "No error";
VAL_ 664 BDCS12_REAOSts 4 "自动扫风" 3 "镜像模式" 2 "避人模式" 1 "脸部清爽" 0 "手动模式";
VAL_ 664 BDCS12_EAOCtrlVaild 1 "Vaild" 0 "Invaild";
VAL_ 664 BDCS12_CoolantFillingSta 1 "ON" 0 "OFF";
VAL_ 664 BDCS12_LeftExtFanSpdCmd 100 "100%" 0 "0";
VAL_ 664 BDCS12_RightExtFanSpdCmd 100 "100%" 0 "0";
VAL_ 664 BDCS12_PumpHFlt 1 "Error" 0 "No error";
VAL_ 664 BDCS12_LFaceOutletTempFlt 1 "Error" 0 "No error";
VAL_ 664 BDCS12_LFootOutletTempFlt 1 "Error" 0 "No error";
VAL_ 664 BDCS12_RFaceOutletTempFlt 1 "Error" 0 "No error";
VAL_ 664 BDCS12_RFootOutletTempFlt 1 "Error" 0 "No error";
VAL_ 664 BDCS12_WindSpdAutSts 1 "自动状态" 0 "手动状态";
VAL_ 664 BDCS12_BlowModAutSts 1 "自动状态" 0 "手动状态";
VAL_ 664 BDCS12_IHE_OutTempFlt 1 "Error" 0 "No error";
VAL_ 664 BDCS12_OHE_OutTempFlt 1 "Error" 0 "No error";
VAL_ 664 BDCS12_WCC_OutTempFlt 1 "Error" 0 "No error";
VAL_ 664 BDCS12_Chiller_OutTempFlt 1 "Error" 0 "No error";
VAL_ 664 BDCS12_LeHybThrMotFlt 1 "Error" 0 "No error";
VAL_ 664 BDCS12_RiHybThrMotFlt 1 "Error" 0 "No error";
VAL_ 664 BDCS12_CycleMotFlt 1 "Error" 0 "No error";
VAL_ 664 BDCS12_ModThrMotFlt 1 "Error" 0 "No error";
VAL_ 670 BDCS10_AC_ACSts 1 "ON" 0 "OFF";
VAL_ 670 BDCS10_AC_CycleSts 3 "Reserved" 2 "AUTO" 1 "外循环" 0 "内循环";
VAL_ 670 BDCS10_AC_BlowerSpdSts 10 "风速十挡" 9 "风速九挡" 8 "风速八挡" 7 "风速七挡" 6 "风速六挡" 5 "风速五挡" 4 "风速四挡" 3 "风速三挡" 2 "风速二挡" 1 "风速一挡" 0 "无风挡位";
VAL_ 670 BDCS10_AC_OnOffSts 1 "ON" 0 "OFF";
VAL_ 670 BDCS10_AC_VentSts 1 "ON" 0 "OFF";
VAL_ 670 BDCS10_AC_VentilationSts 1 "ON" 0 "OFF";
VAL_ 670 BDCS10_AC_WindowSts 1 "ON" 0 "OFF";
VAL_ 670 BDCS10_AC_AnionSts 1 "ON" 0 "OFF";
VAL_ 670 BDCS10_AC_OutsideTempValid 1 "Valid" 0 "Invalid";
VAL_ 670 BDCS10_AC_AutoSts 1 "ON" 0 "OFF";
VAL_ 670 BDCS10_AC_FootSts 1 "ON" 0 "OFF";
VAL_ 670 BDCS10_AC_DualSw 1 "ON" 0 "OFF";
VAL_ 670 BDCS10_AC_PM25_ValueValid 1 "Valid" 0 "Invalid";
VAL_ 670 BDCS10_AC_OutsideTemp 255 "Invalid";
VAL_ 670 BDCS10_AC_LHTemp 255 "Invalid" 33 "High" 32 "31.5" 31 "31" 30 "30.5" 29 "30" 28 "29.5" 27 "29" 26 "28.5" 25 "28" 24 "27.5" 23 "27" 22 "26.5" 21 "26" 20 "25.5" 19 "25" 18 "24.5" 17 "24" 16 "23.5" 15 "23" 14 "22.5" 13 "22" 12 "21.5" 11 "21" 10 "20.5" 9 "20" 8 "19.5" 7 "19" 6 "18.5" 5 "18" 4 "17.5" 3 "17" 2 "16.5" 1 "Low" 0 "Inactive";
VAL_ 670 BDCS10_AC_RHTemp 255 "Invalid" 33 "High" 32 "31.5" 31 "31" 30 "30.5" 29 "30" 28 "29.5" 27 "29" 26 "28.5" 25 "28" 24 "27.5" 23 "27" 22 "26.5" 21 "26" 20 "25.5" 19 "25" 18 "24.5" 17 "24" 16 "23.5" 15 "23" 14 "22.5" 13 "22" 12 "21.5" 11 "21" 10 "20.5" 9 "20" 8 "19.5" 7 "19" 6 "18.5" 5 "18" 4 "17.5" 3 "17" 2 "16.5" 1 "Low" 0 "Inactive";
VAL_ 677 BDCS8_FL_Pos_ManualAdjust_Sts 1 "Adjusted" 0 "Not adjust";
VAL_ 677 BDCS8_FR_Pos_ManualAdjust_Sts 1 "Adjusted" 0 "Not adjust";
VAL_ 677 BDCS8_FR_SeatEasygetON_OFF_Sts 1 "ON" 0 "OFF";
VAL_ 677 BDCS8_Drive_ODS 1 "Unoccupied（无人）" 0 "Occupied（有人）";
VAL_ 677 BDCS8_FR_SeatPosMemory_Sts 2 "Failed" 1 "Succeed" 0 "Default";
VAL_ 677 BDCS8_FR_SeatPosLoad_Sts 2 "Failed" 1 "Succeed" 0 "Default";
VAL_ 677 BDCS8_FL_SeatEasygetON_OFF_Sts 1 "ON" 0 "OFF";
VAL_ 677 BDCS8_FL_SeatPosLoad_Sts 2 "Failed" 1 "Succeed" 0 "Default";
VAL_ 677 BDCS8_FL_SeatPosMemory_Sts 2 "Failed" 1 "Succeed" 0 "Default";
VAL_ 677 BDCS8_Driver_Heating_Sts 3 "Hight" 2 "Middle" 1 "Low" 0 "OFF";
VAL_ 677 BDCS8_Passenger_Heating_Sts 3 "Hight" 2 "Middle" 1 "Low" 0 "OFF";
VAL_ 677 BDCS8_Driver_Venting_Sts 3 "Hight" 2 "Middle" 1 "Low" 0 "OFF";
VAL_ 677 BDCS8_Passenger_Venting_Sts 3 "Hight" 2 "Middle" 1 "Low" 0 "OFF";
VAL_ 677 BDCS8_Driver_LHFailure 1 "Failure" 0 "No failure";
VAL_ 677 BDCS8_Passenger_RHFailure 1 "Failure" 0 "No failure";
VAL_ 677 BDCS8_Driver_LVFailure 1 "Failure" 0 "No failure";
VAL_ 677 BDCS8_Passenger_RVFailure 1 "Failure" 0 "No failure";
VAL_ 677 BDCS8_Driver_MassageModeSts 5 "MODE 5" 4 "MODE 4" 3 "MODE 3" 2 "MODE 2" 1 "MODE 1" 0 "OFF";
VAL_ 677 BDCS8_Driver_MassageLevelSts 3 "High Intensity" 2 "Normal Intensity" 1 "Weak Intensity" 0 "OFF";
VAL_ 677 BDCS8_Passenger_MassageModeSts 5 "MODE 5" 4 "MODE 4" 3 "MODE 3" 2 "MODE 2" 1 "MODE 1" 0 "OFF";
VAL_ 677 BDCS8_Passenger_MassageLevelSts 3 "High Intensity" 2 "Normal Intensity" 1 "Weak Intensity" 0 "OFF";
VAL_ 677 BDCS8_Driver_Massage_Sts 4 "Down active" 3 "Up active" 2 "Rear active" 1 "Forward active" 0 "no action";
VAL_ 677 BDCS8_Passenger_MassageSts 4 "Down active" 3 "Up active" 2 "Rear active" 1 "Forward active" 0 "no action";
VAL_ 678 BDCS9_RL_Heating_Sts 3 "Hight" 2 "Middle" 1 "Low" 0 "OFF";
VAL_ 678 BDCS9_RR_Heating_Sts 3 "Hight" 2 "Middle" 1 "Low" 0 "OFF";
VAL_ 678 BDCS9_RL_Venting_Sts 3 "Hight" 2 "Middle" 1 "Low" 0 "OFF";
VAL_ 678 BDCS9_RR_Venting_Sts 3 "Hight" 2 "Middle" 1 "Low" 0 "OFF";
VAL_ 678 BDCS9_RLVentilating_Failure 1 "Failure" 0 "No failure";
VAL_ 678 BDCS9_RRVentilating_Failure 1 "Failure" 0 "No failure";
VAL_ 678 BDCS9_RLBackAngleRelay_Failure 1 "Failure" 0 "No failure";
VAL_ 678 BDCS9_RRBackAngleRelay_Failure 1 "Failure" 0 "No failure";
VAL_ 678 BDCS9_FR_ZeroGravity_Sts 7 "Reserved" 6 "Reserved" 5 "故障" 4 "开启条件不满足（人或物）" 3 "加载完成" 2 "加载暂停" 1 "加载过程中" 0 "Default";
VAL_ 678 BDCS9_RL_MassageLevel_Fdb 3 "High Intensity" 2 "Normal Intensity" 1 "Weak Intensity" 0 "OFF";
VAL_ 678 BDCS9_RL_LumbarActionSts_Fdb 4 "Down active" 3 "Up active" 2 "Rear active" 1 "Forward active" 0 "no action";
VAL_ 678 BDCS9_RL_MassageMode_Fdb 5 "MODE 5" 4 "MODE 4" 3 "MODE 3" 2 "MODE 2" 1 "MODE 1" 0 "OFF";
VAL_ 678 BDCS9_RR_MassageLevel_Fdb 3 "High Intensity" 2 "Normal Intensity" 1 "Weak Intensity" 0 "OFF";
VAL_ 678 BDCS9_RR_LumbarActionSts_Fdb 4 "Down active" 3 "Up active" 2 "Rear active" 1 "Forward active" 0 "no action";
VAL_ 678 BDCS9_RR_MassageMode_Fdb 5 "MODE 5" 4 "MODE 4" 3 "MODE 3" 2 "MODE 2" 1 "MODE 1" 0 "OFF";
VAL_ 678 BDCS9_FridgeHeat_TempSts 31 "Reserved" 30 "Reserved" 29 "Reserved" 28 "Reserved" 27 "Reserved" 26 "Reserved" 25 "Reserved" 24 "Reserved" 23 "Reserved" 22 "Reserved" 21 "Reserved" 20 "Reserved" 19 "Reserved" 18 "Reserved" 17 "Reserved" 16 "50℃" 15 "49℃" 14 "48℃" 13 "47℃" 12 "46℃" 11 "45℃" 10 "44℃" 9 "43℃" 8 "42℃" 7 "41℃" 6 "40℃" 5 "39℃" 4 "38℃" 3 "37℃" 2 "36℃" 1 "35℃" 0 "Default";
VAL_ 678 BDCS9_FridgeMod_Sts 3 "保温" 2 "冷藏" 1 "关闭" 0 "Default";
VAL_ 678 BDCS9_FridgeTemp_KeepSts 1 "Open" 0 "Close";
VAL_ 678 BDCS9_FridgeCool_TempSts 15 "Reserved" 14 "Reserved" 13 "6℃" 12 "5℃" 11 "4℃" 10 "3℃" 9 "2℃" 8 "1℃" 7 "0℃" 6 "-1℃" 5 "-2℃" 4 "-3℃" 3 "-4℃" 2 "-5℃" 1 "-6℃" 0 "Default";
VAL_ 678 BDCS9_RC_FridgeDoorSts 3 "Reserved" 2 "Close" 1 "Open" 0 "Init";
VAL_ 678 BDCS9_RC_FridgeErSts 3 "Reserved" 2 "Heating error" 1 "Cooling error" 0 "Normal";
VAL_ 678 BDCS9_RmtFridgeReqFailCondition 3 "Reserved" 2 "Fuccessful" 1 "Fail" 0 "Default";
VAL_ 678 BDCS9_RL_Heating_Failure 1 "Failure" 0 "No failure";
VAL_ 678 BDCS9_RR_Heating_Failure 1 "Failure" 0 "No failure";
VAL_ 680 PTC1_ClntOtltOverTemProtn 1 "True" 0 "False";
VAL_ 680 PTC1_VbatVtgUnstable 1 "True" 0 "False";
VAL_ 680 PTC1_VbatVtgSnsrFlt 1 "True" 0 "False";
VAL_ 680 PTC1_PCBTempSnsrFlt 1 "True" 0 "False";
VAL_ 680 PTC1_HiCrntSnsrFlt 1 "True" 0 "False";
VAL_ 680 PTC1_PCBOverTempProtn 1 "True" 0 "False";
VAL_ 680 PTC1_WrkngSts 3 "Operation" 2 "Sleep Fault" 1 "Wait Fault" 0 "Off";
VAL_ 680 PTC1_CoreOrIGBTOpenErr 1 "True" 0 "False";
VAL_ 680 PTC1_IGBTShrtErr 1 "True" 0 "False";
VAL_ 680 PTC1_HVOverCrntProtn 1 "True" 0 "False";
VAL_ 680 PTC1_VbatVtgProtn 1 "True" 0 "False";
VAL_ 680 PTC1_HVDisconnectProtn 1 "True" 0 "False";
VAL_ 680 PTC1_IGBTOverTemProtn 1 "True" 0 "False";
VAL_ 680 PTC1_ClntInltOverTemProtn 1 "True" 0 "False";
VAL_ 680 PTC1_MmryFlt 1 "True" 0 "False";
VAL_ 680 PTC1_IGBTTemSnsrFlt 1 "True" 0 "False";
VAL_ 680 PTC1_ClntInltTemSnsrFlt 1 "True" 0 "False";
VAL_ 680 PTC1_ClntOtltTemSnsrFlt 1 "True" 0 "False";
VAL_ 680 PTC1_CommError 1 "True" 0 "False";
VAL_ 680 EACP1_OPState 1 "缺相故障" 0 "无故障";
VAL_ 680 EACP1_BaseState 3 "诊断和标定" 2 "故障" 1 "使能工作状态" 0 "就绪";
VAL_ 680 EACP1_OVState 1 "电压过高" 0 "无故障";
VAL_ 680 EACP1_LVState 1 "电压过低" 0 "无故障";
VAL_ 680 EACP1_OTState 1 "模块过温" 0 "无故障";
VAL_ 680 EACP1_OCState 1 "过流故障" 0 "无故障";
VAL_ 680 EACP1_ComState 1 "CAN通讯故障" 0 "无故障";
VAL_ 680 EACP1_LRState 1 "堵转故障" 0 "无故障";
VAL_ 680 EACP1_OSState 1 "过速故障" 0 "无故障";
VAL_ 680 EACP1_PowerOffState 1 "掉电故障" 0 "无故障";
VAL_ 680 EACP1_CurrSState 1 "电流采样故障" 0 "无故障";
VAL_ 680 EACP1_COVState 1 "电压超高故障" 0 "无故障";
VAL_ 680 EACP1_FailGrade 3 "level 3(最高级故障)" 2 "level 2(次高级故障)" 1 "level 1(一般故障）" 0 "No Error";
VAL_ 857 BDCS_OTA_DoorLockCmd 3 "DriverDoor Unlock" 2 "AllDoor Lock" 1 "AllDoor Unlock" 0 "No Request";
VAL_ 857 BDCS_OTA_FLWindowsCtrl 5 "留缝" 4 "Auto Down" 3 "Auto Up" 2 "Manual Down" 1 "Manual Up" 0 "No request";
VAL_ 857 BDCS_OTA_FRWindowsCtrl 5 "留缝" 4 "Auto Down" 3 "Auto Up" 2 "Manual Down" 1 "Manual Up" 0 "No request";
VAL_ 857 BDCS_OTA_RLWindowsCtrl 5 "留缝" 4 "Auto Down" 3 "Auto Up" 2 "Manual Down" 1 "Manual Up" 0 "No request";
VAL_ 857 BDCS_OTA_RRWindowsCtrl 5 "留缝" 4 "Auto Down" 3 "Auto Up" 2 "Manual Down" 1 "Manual Up" 0 "No request";
VAL_ 857 BDCS_OTA_TrunkLockSts 1 "Locked" 0 "Unlocked";
VAL_ 857 BDCS_OTA_HoodAjarSts 1 "Open" 0 "Closed";
VAL_ 857 BDCS_OTA_AlarmMode 4 "Alarm" 3 "Alarm Triggered" 2 "AntiTheft" 1 "Pre-AntiThrft" 0 "No-AntiTheft";
VAL_ 938 BDCS19_AC_ClmttSts_ChgTrg 1 "ON" 0 "OFF";
VAL_ 938 BDCS19_AC_ClmttSts_ClmtOffTrg 1 "ON" 0 "OFF";
VAL_ 938 BDCS19_AC_ClmttSts_SlpTrg 1 "ON" 0 "OFF";
VAL_ 938 BDCS19_AC_ACSts_ChgTrg 1 "ON" 0 "OFF";
VAL_ 938 BDCS19_AC_ACSts_ClmtOffTrg 1 "ON" 0 "OFF";
VAL_ 938 BDCS19_AC_ACSts_SlpTrg 1 "ON" 0 "OFF";
VAL_ 938 BDCS19_AC_AutoSts_ChgTrg 1 "ON" 0 "OFF";
VAL_ 938 BDCS19_AC_AutoSts_ClmtOffTrg 1 "ON" 0 "OFF";
VAL_ 938 BDCS19_AC_AutoSts_SlpTrg 1 "ON" 0 "OFF";
VAL_ 938 BDCS19_AC_WinDefrstSts_ChgTrg 1 "ON" 0 "OFF";
VAL_ 938 BDCS19_AC_WinDefrstSts_ClmtOffTrg 1 "ON" 0 "OFF";
VAL_ 938 BDCS19_AC_WinDefrstSts_SlpTrg 1 "ON" 0 "OFF";
VAL_ 938 BDCS19_AC_ACMaxSts_ChgTrg 1 "ON" 0 "OFF";
VAL_ 938 BDCS19_AC_ACMaxSts_ClmtOffTrg 1 "ON" 0 "OFF";
VAL_ 938 BDCS19_AC_ACMaxSts_SlpTrg 1 "ON" 0 "OFF";
VAL_ 938 BDCS19_AC_DualReq_ChgTrg 1 "ON" 0 "OFF";
VAL_ 938 BDCS19_AC_RecircCycleSts_ChgTrg 3 "Reserved" 2 "AUTO" 1 "外循环" 0 "内循环";
VAL_ 938 BDCS19_AC_RecircCycleSts_ClmtOffTrg 3 "Reserved" 2 "AUTO" 1 "外循环" 0 "内循环";
VAL_ 938 BDCS19_AC_RecircCycleSts_SlpTrg 3 "Reserved" 2 "AUTO" 1 "外循环" 0 "内循环";
VAL_ 938 BDCS19_AC_DualReq_ClmtOffTrg 1 "ON" 0 "OFF";
VAL_ 938 BDCS19_AC_DualReq_SlpTrg 1 "ON" 0 "OFF";
VAL_ 938 BDCS19_AC_DrvTempReq_ChgTrg 255 "Invalid" 33 "High" 32 "31.5" 31 "31" 30 "30.5" 29 "30" 28 "29.5" 27 "29" 26 "28.5" 25 "28" 24 "27.5" 23 "27" 22 "26.5" 21 "26" 20 "25.5" 19 "25" 18 "24.5" 17 "24" 16 "23.5" 15 "23" 14 "22.5" 13 "22" 12 "21.5" 11 "21" 10 "20.5" 9 "20" 8 "19.5" 7 "19" 6 "18.5" 5 "18" 4 "17.5" 3 "17" 2 "16.5" 1 "Low" 0 "Inactive";
VAL_ 938 BDCS19_AC_DrvTempReq_ClmtOffTrg 255 "Invalid" 33 "High" 32 "31.5" 31 "31" 30 "30.5" 29 "30" 28 "29.5" 27 "29" 26 "28.5" 25 "28" 24 "27.5" 23 "27" 22 "26.5" 21 "26" 20 "25.5" 19 "25" 18 "24.5" 17 "24" 16 "23.5" 15 "23" 14 "22.5" 13 "22" 12 "21.5" 11 "21" 10 "20.5" 9 "20" 8 "19.5" 7 "19" 6 "18.5" 5 "18" 4 "17.5" 3 "17" 2 "16.5" 1 "Low" 0 "Inactive";
VAL_ 938 BDCS19_AC_DrvTempReq_SlpTrg 255 "Invalid" 33 "High" 32 "31.5" 31 "31" 30 "30.5" 29 "30" 28 "29.5" 27 "29" 26 "28.5" 25 "28" 24 "27.5" 23 "27" 22 "26.5" 21 "26" 20 "25.5" 19 "25" 18 "24.5" 17 "24" 16 "23.5" 15 "23" 14 "22.5" 13 "22" 12 "21.5" 11 "21" 10 "20.5" 9 "20" 8 "19.5" 7 "19" 6 "18.5" 5 "18" 4 "17.5" 3 "17" 2 "16.5" 1 "Low" 0 "Inactive";
VAL_ 938 BDCS19_AC_PassTempReq_ChgTrg 255 "Invalid" 33 "High" 32 "31.5" 31 "31" 30 "30.5" 29 "30" 28 "29.5" 27 "29" 26 "28.5" 25 "28" 24 "27.5" 23 "27" 22 "26.5" 21 "26" 20 "25.5" 19 "25" 18 "24.5" 17 "24" 16 "23.5" 15 "23" 14 "22.5" 13 "22" 12 "21.5" 11 "21" 10 "20.5" 9 "20" 8 "19.5" 7 "19" 6 "18.5" 5 "18" 4 "17.5" 3 "17" 2 "16.5" 1 "Low" 0 "Inactive";
VAL_ 938 BDCS19_AC_PassTempReq_ClmtOffTrg 255 "Invalid" 33 "High" 32 "31.5" 31 "31" 30 "30.5" 29 "30" 28 "29.5" 27 "29" 26 "28.5" 25 "28" 24 "27.5" 23 "27" 22 "26.5" 21 "26" 20 "25.5" 19 "25" 18 "24.5" 17 "24" 16 "23.5" 15 "23" 14 "22.5" 13 "22" 12 "21.5" 11 "21" 10 "20.5" 9 "20" 8 "19.5" 7 "19" 6 "18.5" 5 "18" 4 "17.5" 3 "17" 2 "16.5" 1 "Low" 0 "Inactive";
VAL_ 938 BDCS19_AC_PassTempReq_SlpTrg 255 "Invalid" 33 "High" 32 "31.5" 31 "31" 30 "30.5" 29 "30" 28 "29.5" 27 "29" 26 "28.5" 25 "28" 24 "27.5" 23 "27" 22 "26.5" 21 "26" 20 "25.5" 19 "25" 18 "24.5" 17 "24" 16 "23.5" 15 "23" 14 "22.5" 13 "22" 12 "21.5" 11 "21" 10 "20.5" 9 "20" 8 "19.5" 7 "19" 6 "18.5" 5 "18" 4 "17.5" 3 "17" 2 "16.5" 1 "Low" 0 "Inactive";
VAL_ 938 BDCS19_AC_BlowerSpdLvl_ChgTrg 10 "风速十挡" 9 "风速九挡" 8 "风速八挡" 7 "风速七挡" 6 "风速六挡" 5 "风速五挡" 4 "风速四挡" 3 "风速三挡" 2 "风速二挡" 1 "风速一挡" 0 "无风挡位";
VAL_ 938 BDCS19_AC_BlowerSpdLvl_ClmtOffTrg 10 "风速十挡" 9 "风速九挡" 8 "风速八挡" 7 "风速七挡" 6 "风速六挡" 5 "风速五挡" 4 "风速四挡" 3 "风速三挡" 2 "风速二挡" 1 "风速一挡" 0 "无风挡位";
VAL_ 938 BDCS19_AC_BlowerSpdLvl_SlpTrg 10 "风速十挡" 9 "风速九挡" 8 "风速八挡" 7 "风速七挡" 6 "风速六挡" 5 "风速五挡" 4 "风速四挡" 3 "风速三挡" 2 "风速二挡" 1 "风速一挡" 0 "无风挡位";
VAL_ 938 BDCS19_AC_AirOutletMod_ChgTrg 7 "吹脸吹脚吹窗模式" 6 "吹脚吹窗模式" 5 "吹脸吹窗模式" 4 "吹脸吹脚模式" 3 "吹窗模式" 2 "吹脚模式" 1 "吹脸模式" 0 "Inactive";
VAL_ 938 BDCS19_AC_AirOutletMod_ClmtOffTrg 7 "吹脸吹脚吹窗模式" 6 "吹脚吹窗模式" 5 "吹脸吹窗模式" 4 "吹脸吹脚模式" 3 "吹窗模式" 2 "吹脚模式" 1 "吹脸模式" 0 "Inactive";
VAL_ 938 BDCS19_AC_AirOutletMod_SlpTrg 7 "吹脸吹脚吹窗模式" 6 "吹脚吹窗模式" 5 "吹脸吹窗模式" 4 "吹脸吹脚模式" 3 "吹窗模式" 2 "吹脚模式" 1 "吹脸模式" 0 "Inactive";
VAL_ 938 BDCS19_AC_ECONMod_ChgTrg 1 "ON" 0 "OFF";
VAL_ 938 BDCS19_AC_ECONMod_ClmtOffTrg 1 "ON" 0 "OFF";
VAL_ 938 BDCS19_AC_ECONMod_SlpTrg 1 "ON" 0 "OFF";
VAL_ 938 BDCS19_AC_AirCleanSts_ChgTrg 1 "ON" 0 "OFF";
VAL_ 938 BDCS19_AC_AirCleanSts_ClmtOffTrg 1 "ON" 0 "OFF";
VAL_ 938 BDCS19_AC_AirCleanSts_SlpTrg 1 "ON" 0 "OFF";
VAL_ 938 BDCS19_AC_AnionSts_ChgTrg 1 "ON" 0 "OFF";
VAL_ 938 BDCS19_AC_AnionSts_ClmtOffTrg 1 "ON" 0 "OFF";
VAL_ 938 BDCS19_AC_AnionSts_SlpTrg 1 "ON" 0 "OFF";
VAL_ 938 BDCS19_AC_FrgrcSts_ChgTrg 1 "Running" 0 "Standby";
VAL_ 938 BDCS19_AC_FrgrcSts_ClmtOffTrg 1 "Running" 0 "Standby";
VAL_ 938 BDCS19_AC_FrgrcSts_SlpTrg 1 "Running" 0 "Standby";
VAL_ 938 BDCS19_AC_FrgrcConctn_ChgTrg 3 "High concentration" 2 "Middle concentration" 1 "Low concentration" 0 "Initial value";
VAL_ 938 BDCS19_AC_FrgrcConctn_ClmtOffTrg 3 "High concentration" 2 "Middle concentration" 1 "Low concentration" 0 "Initial value";
VAL_ 938 BDCS19_AC_FrgrcConctn_SlpTrg 3 "High concentration" 2 "Middle concentration" 1 "Low concentration" 0 "Initial value";
VAL_ 938 BDCS19_AC_FrgrcPosn_ChgTrg 3 "Fragrance Position_3 (位置3的香型）" 2 "Fragrance Position_2 (位置2的香型）" 1 "Fragrance Position_1 (位置1的香型)" 0 "Initial value";
VAL_ 938 BDCS19_AC_FrgrcPosn_ClmtOffTrg 3 "Fragrance Position_3 (位置3的香型）" 2 "Fragrance Position_2 (位置2的香型）" 1 "Fragrance Position_1 (位置1的香型)" 0 "Initial value";
VAL_ 938 BDCS19_AC_FrgrcPosn_SlpTrg 3 "Fragrance Position_3 (位置3的香型）" 2 "Fragrance Position_2 (位置2的香型）" 1 "Fragrance Position_1 (位置1的香型)" 0 "Initial value";
VAL_ 938 BDCS19_AC_FrgrcPosn1Type_ChgTrg 10 "Type_10 (五时姜香）" 9 "Type_9 (绚丽栀子花）" 8 "Type_8 (天竺葵先生）" 7 "Type_7 (保加利亚玫瑰）" 6 "Type_6 (白色广藿香）" 5 "Type_5 (蓝风铃）" 4 "Type_4 (薰衣草天堂）" 3 "Type_3 (雨后花园）" 2 "Type_2 (白茶）" 1 "Type_1 (远行)" 0 "No Type (无香型)";
VAL_ 938 BDCS19_AC_FrgrcPosn1Type_ClmtOffTrg 10 "Type_10 (五时姜香）" 9 "Type_9 (绚丽栀子花）" 8 "Type_8 (天竺葵先生）" 7 "Type_7 (保加利亚玫瑰）" 6 "Type_6 (白色广藿香）" 5 "Type_5 (蓝风铃）" 4 "Type_4 (薰衣草天堂）" 3 "Type_3 (雨后花园）" 2 "Type_2 (白茶）" 1 "Type_1 (远行)" 0 "No Type (无香型)";
VAL_ 938 BDCS19_AC_FrgrcPosn1Type_SlpTrg 10 "Type_10 (五时姜香）" 9 "Type_9 (绚丽栀子花）" 8 "Type_8 (天竺葵先生）" 7 "Type_7 (保加利亚玫瑰）" 6 "Type_6 (白色广藿香）" 5 "Type_5 (蓝风铃）" 4 "Type_4 (薰衣草天堂）" 3 "Type_3 (雨后花园）" 2 "Type_2 (白茶）" 1 "Type_1 (远行)" 0 "No Type (无香型)";
VAL_ 938 BDCS19_AC_FrgrcPosn2Type_ChgTrg 10 "Type_10 (五时姜香）" 9 "Type_9 (绚丽栀子花）" 8 "Type_8 (天竺葵先生）" 7 "Type_7 (保加利亚玫瑰）" 6 "Type_6 (白色广藿香）" 5 "Type_5 (蓝风铃）" 4 "Type_4 (薰衣草天堂）" 3 "Type_3 (雨后花园）" 2 "Type_2 (白茶）" 1 "Type_1 (远行)" 0 "No Type (无香型)";
VAL_ 938 BDCS19_AC_FrgrcPosn2Type_ClmtOffTrg 10 "Type_10 (五时姜香）" 9 "Type_9 (绚丽栀子花）" 8 "Type_8 (天竺葵先生）" 7 "Type_7 (保加利亚玫瑰）" 6 "Type_6 (白色广藿香）" 5 "Type_5 (蓝风铃）" 4 "Type_4 (薰衣草天堂）" 3 "Type_3 (雨后花园）" 2 "Type_2 (白茶）" 1 "Type_1 (远行)" 0 "No Type (无香型)";
VAL_ 938 BDCS19_AC_FrgrcPosn2Type_SlpTrg 10 "Type_10 (五时姜香）" 9 "Type_9 (绚丽栀子花）" 8 "Type_8 (天竺葵先生）" 7 "Type_7 (保加利亚玫瑰）" 6 "Type_6 (白色广藿香）" 5 "Type_5 (蓝风铃）" 4 "Type_4 (薰衣草天堂）" 3 "Type_3 (雨后花园）" 2 "Type_2 (白茶）" 1 "Type_1 (远行)" 0 "No Type (无香型)";
VAL_ 938 BDCS19_AC_FrgrcPosn3Type_ChgTrg 10 "Type_10 (五时姜香）" 9 "Type_9 (绚丽栀子花）" 8 "Type_8 (天竺葵先生）" 7 "Type_7 (保加利亚玫瑰）" 6 "Type_6 (白色广藿香）" 5 "Type_5 (蓝风铃）" 4 "Type_4 (薰衣草天堂）" 3 "Type_3 (雨后花园）" 2 "Type_2 (白茶）" 1 "Type_1 (远行)" 0 "No Type (无香型)";
VAL_ 938 BDCS19_AC_FrgrcPosn3Type_ClmtOffTrg 10 "Type_10 (五时姜香）" 9 "Type_9 (绚丽栀子花）" 8 "Type_8 (天竺葵先生）" 7 "Type_7 (保加利亚玫瑰）" 6 "Type_6 (白色广藿香）" 5 "Type_5 (蓝风铃）" 4 "Type_4 (薰衣草天堂）" 3 "Type_3 (雨后花园）" 2 "Type_2 (白茶）" 1 "Type_1 (远行)" 0 "No Type (无香型)";
VAL_ 938 BDCS19_AC_FrgrcPosn3Type_SlpTrg 10 "Type_10 (五时姜香）" 9 "Type_9 (绚丽栀子花）" 8 "Type_8 (天竺葵先生）" 7 "Type_7 (保加利亚玫瑰）" 6 "Type_6 (白色广藿香）" 5 "Type_5 (蓝风铃）" 4 "Type_4 (薰衣草天堂）" 3 "Type_3 (雨后花园）" 2 "Type_2 (白茶）" 1 "Type_1 (远行)" 0 "No Type (无香型)";
VAL_ 938 BDCS19_EAO_LeVentMod_ChgTrg 4 "自动扫风" 3 "镜像模式" 2 "避人模式" 1 "脸部清爽" 0 "手动模式";
VAL_ 938 BDCS19_AC_AutoDrySts_ChgTrg 1 "ON" 0 "OFF";
VAL_ 938 BDCS19_EAO_LeVentMod_ClmtOffTrg 4 "自动扫风" 3 "镜像模式" 2 "避人模式" 1 "脸部清爽" 0 "手动模式";
VAL_ 938 BDCS19_AC_AutoDrySts_ClmtOffTrg 1 "ON" 0 "OFF";
VAL_ 938 BDCS19_EAO_LeVentMod_SlpTrg 4 "自动扫风" 3 "镜像模式" 2 "避人模式" 1 "脸部清爽" 0 "手动模式";
VAL_ 938 BDCS19_AC_AutoDrySts_SlpTrg 1 "ON" 0 "OFF";
VAL_ 938 BDCS19_EAO_RiVentMod_ChgTrg 4 "自动扫风" 3 "镜像模式" 2 "避人模式" 1 "脸部清爽" 0 "手动模式";
VAL_ 938 BDCS19_AC_AutoWinDefrstSts_ChgTrg 1 "ON" 0 "OFF";
VAL_ 938 BDCS19_EAO_RiVentMod_ClmtOffTrg 4 "自动扫风" 3 "镜像模式" 2 "避人模式" 1 "脸部清爽" 0 "手动模式";
VAL_ 938 BDCS19_AC_AutoWinDefrstSts_ClmtOffTrg 1 "ON" 0 "OFF";
VAL_ 938 BDCS19_EAO_RiVentMod_SlpTrg 4 "自动扫风" 3 "镜像模式" 2 "避人模式" 1 "脸部清爽" 0 "手动模式";
VAL_ 938 BDCS19_AC_AutoWinDefrstSts_SlpTrg 1 "ON" 0 "OFF";
VAL_ 938 BDCS19_AC_ChgTrgSts 1 "ON" 0 "OFF";
VAL_ 938 BDCS19_AC_ClmtOffTrgSts 1 "ON" 0 "OFF";
VAL_ 938 BDCS19_AC_SlpTrgSts 1 "ON" 0 "OFF";
VAL_ 938 BDCS19_AC_ACTrgMod 5 "Reserved" 4 "SOA" 3 "Remote control" 2 "Location" 1 "Memory last cycle" 0 "Inactive";
VAL_ 938 BDCS19_AC_App2NVMSts_ClmtOffTrg 2 "NVRAM failure" 1 "success NVRAM storage" 0 "NVRAM empty";
VAL_ 938 BDCS19_AC_App2NVMSts_SlpTrg 2 "NVRAM failure" 1 "success NVRAM storage" 0 "NVRAM empty";
VAL_ 938 BDCS19_AC_ClmttMod_ClmtOffTrg 3 "Spcl" 2 "Auto" 1 "Manu" 0 "Off";
VAL_ 938 BDCS19_AC_ClmttMod_SlpTrg 3 "Spcl" 2 "Auto" 1 "Manu" 0 "Off";
VERSION ""

NS_ :

BS_:

BU_: GW_FD5 GW_FD6 GW_FD3 GW_FD4 GW_FD1 GW_FD2 PDCS_FD1 PDCU SRR3 SRR4 ADCU_FD3 BDCS DDCU CDCS ADCS_FD3 CDCS_OverSea TBOX FLC_ME_FD3 FLC_FD3 ICU_E02 ICU PDCS_HVM_FD1 TBOX_OverSea BMS ISC GCU EMS IDB ESC_FD3 EHB_FD3 MCU IMU ACU EPS WPC CDU AMP BAM PDCS_FD3 EVCC REPB ADCS_FD6 ADCU_FD6 FLC_ME_FD6 FLC_FD6 DLC GW_FD7 ESC_FD6 EHB_FD6

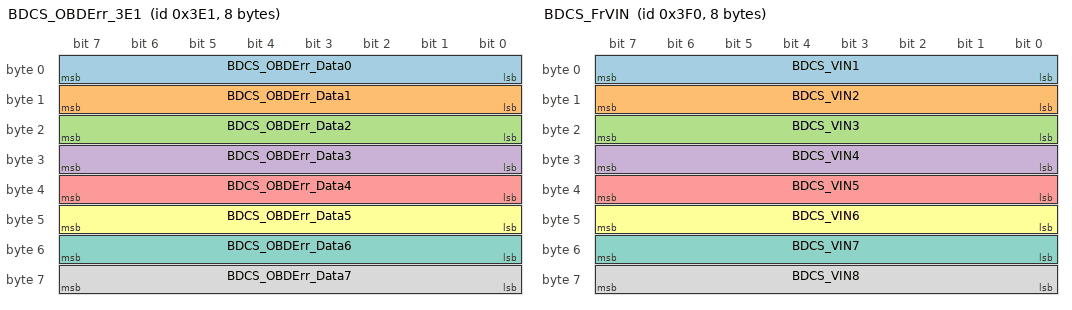
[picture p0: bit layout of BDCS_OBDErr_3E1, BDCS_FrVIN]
BO_ 993 BDCS_OBDErr_3E1: 8 BDCS
 SG_ BDCS_OBDErr_Data0 : 7|8@0+ (1,0) [0|255] "NoUnit" PDCS_FD1,GW_FD1,PDCS_HVM_FD1
 SG_ BDCS_OBDErr_Data1 : 15|8@0+ (1,0) [0|255] "NoUnit" PDCS_FD1,GW_FD1,PDCS_HVM_FD1
 SG_ BDCS_OBDErr_Data2 : 23|8@0+ (1,0) [0|255] "NoUnit" PDCS_FD1,GW_FD1,PDCS_HVM_FD1
 SG_ BDCS_OBDErr_Data3 : 31|8@0+ (1,0) [0|255] "NoUnit" PDCS_FD1,GW_FD1,PDCS_HVM_FD1
 SG_ BDCS_OBDErr_Data4 : 39|8@0+ (1,0) [0|255] "NoUnit" PDCS_FD1,GW_FD1,PDCS_HVM_FD1
 SG_ BDCS_OBDErr_Data5 : 47|8@0+ (1,0) [0|255] "NoUnit" PDCS_FD1,GW_FD1,PDCS_HVM_FD1
 SG_ BDCS_OBDErr_Data6 : 55|8@0+ (1,0) [0|255] "NoUnit" PDCS_FD1,GW_FD1,PDCS_HVM_FD1
 SG_ BDCS_OBDErr_Data7 : 63|8@0+ (1,0) [0|255] "NoUnit" PDCS_FD1,GW_FD1,PDCS_HVM_FD1

BO_ 1008 BDCS_FrVIN: 8 BDCS
 SG_ BDCS_VIN1 : 7|8@0+ (1,0) [0|255] "NoUnit" TBOX,GW_FD5,ICU_E02,GW_FD4,ICU,CDCS,CDCS_OverSea,TBOX_OverSea
 SG_ BDCS_VIN2 : 15|8@0+ (1,0) [0|255] "NoUnit" TBOX,GW_FD5,ICU_E02,GW_FD4,ICU,CDCS,CDCS_OverSea,TBOX_OverSea
 SG_ BDCS_VIN3 : 23|8@0+ (1,0) [0|255] "NoUnit" TBOX,GW_FD5,ICU_E02,GW_FD4,ICU,CDCS,CDCS_OverSea,TBOX_OverSea
 SG_ BDCS_VIN4 : 31|8@0+ (1,0) [0|255] "NoUnit" TBOX,GW_FD5,ICU_E02,GW_FD4,ICU,CDCS,CDCS_OverSea,TBOX_OverSea
 SG_ BDCS_VIN5 : 39|8@0+ (1,0) [0|255] "NoUnit" TBOX,GW_FD5,ICU_E02,GW_FD4,ICU,CDCS,CDCS_OverSea,TBOX_OverSea
 SG_ BDCS_VIN6 : 47|8@0+ (1,0) [0|255] "NoUnit" TBOX,GW_FD5,ICU_E02,GW_FD4,ICU,CDCS,CDCS_OverSea,TBOX_OverSea
 SG_ BDCS_VIN7 : 55|8@0+ (1,0) [0|255] "NoUnit" TBOX,GW_FD5,ICU_E02,GW_FD4,ICU,CDCS,CDCS_OverSea,TBOX_OverSea
 SG_ BDCS_VIN8 : 63|8@0+ (1,0) [0|255] "NoUnit" TBOX,GW_FD5,ICU_E02,GW_FD4,ICU,CDCS,CDCS_OverSea,TBOX_OverSea

BO_ 1538 BDCS_NM_602: 8 BDCS
 SG_ BDCS_SourceNodeIdentifier : 7|8@0+ (1,0) [0|255] "NoUnit" Vector__XXX
 SG_ BDCS_RepeatMessageRequest : 8|1@0+ (1,0) [0|1] "NoUnit" Vector__XXX
 SG_ BDCS_Reserve1 : 11|3@0+ (1,0) [0|7] "NoUnit" Vector__XXX
 SG_ BDCS_ActiveWakeup : 12|1@0+ (1,0) [0|1] "NoUnit" Vector__XXX
 SG_ BDCS_Reserve2 : 15|3@0+ (1,0) [0|7] "NoUnit" Vector__XXX
 SG_ BDCS_WakeUp_KL15 : 16|1@0+ (1,0) [0|1] "NoUnit" Vector__XXX
 SG_ BDCS_WakeUp_Rx_NM : 17|1@0+ (1,0) [0|1] "NoUnit" Vector__XXX
 SG_ BDCS_WakeUp_Hazard : 18|1@0+ (1,0) [0|1] "NoUnit" Vector__XXX
 SG_ BDCS_WakeUp_BackDoorFB : 19|1@0+ (1,0) [0|1] "NoUnit" Vector__XXX
 SG_ BDCS_WakeUp_BackDoorOutSW : 20|1@0+ (1,0) [0|1] "NoUnit" Vector__XXX
 SG_ BDCS_WakeUp_LiftGateLockSW : 21|1@0+ (1,0) [0|1] "NoUnit" Vector__XXX
 SG_ BDCS_WakeUp_PLGInLockSW : 22|1@0+ (1,0) [0|1] "NoUnit" Vector__XXX
 SG_ BDCS_WakeUp_FullLock : 23|1@0+ (1,0) [0|1] "NoUnit" Vector__XXX
 SG_ BDCS_RepeatFromSleep : 24|1@0+ (1,0) [0|1] "NoUnit" Vector__XXX
 SG_ BDCS_RepeatFromPrepare : 25|1@0+ (1,0) [0|1] "NoUnit" Vector__XXX
 SG_ BDCS_NormalFromRepeat : 26|1@0+ (1,0) [0|1] "NoUnit" Vector__XXX
 SG_ BDCS_NormalFromReady : 27|1@0+ (1,0) [0|1] "NoUnit" Vector__XXX
 SG_ BDCS_RepeatFromReady : 28|1@0+ (1,0) [0|1] "NoUnit" Vector__XXX
 SG_ BDCS_RepeatFromNormal : 29|1@0+ (1,0) [0|1] "NoUnit" Vector__XXX
 SG_ BDCS_WakeUp_RKE : 30|1@0+ (1,0) [0|1] "NoUnit" Vector__XXX
 SG_ BDCS_RemainNetworkWakeUp_Power : 32|1@0+ (1,0) [0|1] "NoUnit" Vector__XXX
 SG_ BDCS_RemainNetworkWakeUp_DiagMode : 33|1@0+ (1,0) [0|1] "NoUnit" Vector__XXX
 SG_ BDCS_RemainNetworkWakeUp_HazardBlink : 34|1@0+ (1,0) [0|1] "NoUnit" Vector__XXX
 SG_ BDCS_RemainNetworkWakeUp_PosLightOn : 35|1@0+ (1,0) [0|1] "NoUnit" Vector__XXX
 SG_ BDCS_RemainNetworkWakeUp_AlarmState : 36|1@0+ (1,0) [0|1] "NoUnit" Vector__XXX
 SG_ BDCS_RemainNetworkWakeUp_Wait_AutoRepeatLock : 37|1@0+ (1,0) [0|1] "NoUnit" Vector__XXX
 SG_ BDCS_RemainNetworkWakeUp_DomeLightOn : 38|1@0+ (1,0) [0|1] "NoUnit" Vector__XXX
 SG_ BDCS_RemainNetworkWakeUp_PowerSavingRelayWorking : 39|1@0+ (1,0) [0|1] "NoUnit" Vector__XXX
 SG_ BDCS_RemainNetworkWakeUp_FollowmeHome : 40|1@0+ (1,0) [0|1] "NoUnit" Vector__XXX
 SG_ BDCS_WakeUp_HoodAjarFB : 41|1@0+ (1,0) [0|1] "NoUnit" Vector__XXX
 SG_ BDCS_WakeUp_LIN2 : 42|1@0+ (1,0) [0|1] "NoUnit" Vector__XXX
 SG_ BDCS_WakeUp_TPMS : 43|1@0+ (1,0) [0|1] "NoUnit" Vector__XXX
 SG_ BDCS_WakeUp_PassengerSideHandleLock : 46|1@0+ (1,0) [0|1] "NoUnit" Vector__XXX
 SG_ BDCS_WakeUp_PassengerSideHandleUnLock : 47|1@0+ (1,0) [0|1] "NoUnit" Vector__XXX
 SG_ BDCS_WakeUp_DriverSideHandleLock : 48|1@0+ (1,0) [0|1] "NoUnit" Vector__XXX
 SG_ BDCS_WakeUp_DriverSideHandleUnlock : 49|1@0+ (1,0) [0|1] "NoUnit" Vector__XXX
 SG_ BDCS_WakeUp_SSBSW2 : 50|1@0+ (1,0) [0|1] "NoUnit" Vector__XXX
 SG_ BDCS_WakeUp_SSBSW1 : 51|1@0+ (1,0) [0|1] "NoUnit" Vector__XXX
 SG_ BDCS_WakeUp_IGN2 : 52|1@0+ (1,0) [0|1] "NoUnit" Vector__XXX
 SG_ BDCS_WakeUp_IGN1 : 53|1@0+ (1,0) [0|1] "NoUnit" Vector__XXX
 SG_ BDCS_WakeUp_ACC : 54|1@0+ (1,0) [0|1] "NoUnit" Vector__XXX
 SG_ BDCS_WakeUp_Break1 : 55|1@0+ (1,0) [0|1] "NoUnit" Vector__XXX
 SG_ BDCS_WakeUp_Break2 : 56|1@0+ (1,0) [0|1] "NoUnit" Vector__XXX
 SG_ BDCS_WakeUp_KickSensor : 57|1@0+ (1,0) [0|1] "NoUnit" Vector__XXX
 SG_ BDCS_WakeUp_PassageSideContainerSW : 58|1@0+ (1,0) [0|1] "NoUnit" Vector__XXX
 SG_ BDCS_WakeUp_HornInput : 59|1@0+ (1,0) [0|1] "NoUnit" Vector__XXX
 SG_ BDCS_WakeUp_DriverSideSensor : 60|1@0+ (1,0) [0|1] "NoUnit" Vector__XXX
 SG_ BDCS_WakeUp_LightLevelInput : 61|1@0+ (1,0) [0|1] "NoUnit" Vector__XXX
 SG_ BDCS_WakeUp_HighBeam : 62|1@0+ (1,0) [0|1] "NoUnit" Vector__XXX
 SG_ BDCS_UserData5 : 63|1@0+ (1,0) [0|1] "NoUnit" Vector__XXX

BO_ 1664 BDCS_TEST1: 16 BDCS
 SG_ BDCS1_TEST : 7|64@0+ (1,0) [0|0] "NoUnit" Vector__XXX

BO_ 1665 BDCS_TEST2: 16 BDCS
 SG_ BDCS2_TEST : 7|64@0+ (1,0) [0|0] "NoUnit" Vector__XXX

BO_ 418 DDCU_Fr01_1A2: 16 DDCU
 SG_ DDCU1_ControlWindowLockSw : 0|1@0+ (1,0) [0|1] "NoUnit" PDCU,SRR3,GW_FD6,SRR4,CDCS,CDCS_OverSea
 SG_ DDCU1_OilFillCapFbk : 1|1@0+ (1,0) [0|1] "NoUnit" GW_FD4,CDCS,CDCS_OverSea
 SG_ DDCU1_FLWinCtrl_Fb : 4|3@0+ (1,0) [0|7] "NoUnit" TBOX,GW_FD5,SRR3,GW_FD6,SRR4,GW_FD4,CDCS,CDCS_OverSea,TBOX_OverSea
 SG_ DDCU1_RLWinCtrl_Fb : 7|3@0+ (1,0) [0|7] "NoUnit" TBOX,GW_FD5,SRR3,GW_FD6,SRR4,GW_FD4,CDCS,CDCS_OverSea,TBOX_OverSea
 SG_ DDCU1_FL_WinPos : 15|8@0+ (1,0) [0|100] "%" SRR3,SRR4,ADCU_FD3,BDCS,CDCS,ADCS_FD3,CDCS_OverSea,TBOX,FLC_ME_FD3,FLC_FD3,GW_FD5,GW_FD6,GW_FD3,GW_FD4,TBOX_OverSea
 SG_ DDCU1_RL_WinPos : 23|8@0+ (1,0) [0|100] "%" SRR3,SRR4,ADCU_FD3,BDCS,CDCS,ADCS_FD3,CDCS_OverSea,TBOX,FLC_ME_FD3,FLC_FD3,GW_FD5,GW_FD6,GW_FD3,GW_FD4,TBOX_OverSea
 SG_ DDCU1_FLDoorAjar : 25|2@0+ (1,0) [0|3] "NoUnit" PDCS_FD1,IDB,ESC_FD3,ADCU_FD3,WPC,EHB_FD3,CDCS,ICU_E02,SRR3,SRR4,BMS,BDCS,ADCS_FD3,CDCS_OverSea,TBOX,FLC_ME_FD3,FLC_FD3,GW_FD5,GW_FD6,GW_FD3,GW_FD4,GW_FD1,ICU,PDCS_HVM_FD1,TBOX_OverSea
 SG_ DDCU1_RLDoorAjar : 27|2@0+ (1,0) [0|3] "NoUnit" PDCS_FD1,SRR3,SRR4,ADCU_FD3,BMS,BDCS,CDCS,ADCS_FD3,CDCS_OverSea,TBOX,FLC_ME_FD3,FLC_FD3,GW_FD5,ICU_E02,GW_FD6,GW_FD3,GW_FD4,GW_FD1,ICU,PDCS_HVM_FD1,TBOX_OverSea
 SG_ DDCU1_RL_SafetyLockFdbk : 28|1@0+ (1,0) [0|1] "NoUnit" TBOX,GW_FD5,SRR3,GW_FD6,SRR4,GW_FD4,CDCS,CDCS_OverSea,TBOX_OverSea
 SG_ DDCU1_MirrorFoldSt : 29|1@0+ (1,0) [0|1] "NoUnit" SRR3,SRR4,ADCU_FD3,CDCS,ADCS_FD3,CDCS_OverSea,TBOX,FLC_ME_FD3,FLC_FD3,GW_FD5,GW_FD6,GW_FD3,GW_FD4,TBOX_OverSea
 SG_ DDCU1_MirrorFoldSet_fdbk : 30|1@0+ (1,0) [0|1] "NoUnit" TBOX,GW_FD5,SRR3,GW_FD6,SRR4,GW_FD4,CDCS,CDCS_OverSea,TBOX_OverSea
 SG_ DDCU1_LockReleaseSw_Out_FL : 31|1@0+ (1,0) [0|1] "NoUnit" TBOX,GW_FD5,SRR3,GW_FD6,SRR4,GW_FD4,BDCS,CDCS,CDCS_OverSea,TBOX_OverSea
 SG_ DDCU1_LockReleaseSw_Out_FR : 32|1@0+ (1,0) [0|1] "NoUnit" TBOX,GW_FD5,SRR3,GW_FD6,SRR4,GW_FD4,CDCS,CDCS_OverSea,TBOX_OverSea
 SG_ DDCU1_LockReleaseSw_In_FL : 33|1@0+ (1,0) [0|1] "NoUnit" TBOX,GW_FD5,SRR3,GW_FD6,SRR4,GW_FD4,BDCS,CDCS,CDCS_OverSea,TBOX_OverSea
 SG_ DDCU1_LockReleaseSw_In_FR : 34|1@0+ (1,0) [0|1] "NoUnit" TBOX,GW_FD5,SRR3,GW_FD6,SRR4,GW_FD4,CDCS,CDCS_OverSea,TBOX_OverSea
 SG_ DDCU1_FL_HallFault : 35|1@0+ (1,0) [0|1] "NoUnit" TBOX,GW_FD5,SRR3,GW_FD6,SRR4,GW_FD4,CDCS,CDCS_OverSea,TBOX_OverSea
 SG_ DDCU1_FL_PWL_Init : 36|1@0+ (1,0) [0|1] "NoUnit" TBOX,GW_FD5,SRR3,GW_FD6,SRR4,GW_FD4,CDCS,CDCS_OverSea,TBOX_OverSea
 SG_ DDCU1_FL_PWL_State : 39|3@0+ (1,0) [0|7] "NoUnit" TBOX,GW_FD5,SRR3,GW_FD6,SRR4,GW_FD4,CDCS,CDCS_OverSea,TBOX_OverSea
 SG_ DDCU1_RL_PWL_State : 42|3@0+ (1,0) [0|7] "NoUnit" TBOX,GW_FD5,SRR3,GW_FD6,SRR4,GW_FD4,CDCS,CDCS_OverSea,TBOX_OverSea
 SG_ DDCU1_RL_HallFault : 43|1@0+ (1,0) [0|1] "NoUnit" TBOX,GW_FD5,SRR3,GW_FD6,SRR4,GW_FD4,CDCS,CDCS_OverSea,TBOX_OverSea
 SG_ DDCU1_RL_PWL_Init : 44|1@0+ (1,0) [0|1] "NoUnit" TBOX,GW_FD5,SRR3,GW_FD6,SRR4,GW_FD4,CDCS,CDCS_OverSea,TBOX_OverSea
 SG_ DDCU1_LeftMirrorAutoTurnDownFb : 45|1@0+ (1,0) [0|1] "NoUnit" TBOX,GW_FD5,SRR3,GW_FD6,SRR4,GW_FD4,CDCS,CDCS_OverSea,TBOX_OverSea
 SG_ DDCU1_LeftPosLoad_Sts : 47|2@0+ (1,0) [0|3] "NoUnit" TBOX,GW_FD5,SRR3,GW_FD6,SRR4,GW_FD4,CDCS,CDCS_OverSea,TBOX_OverSea
 SG_ DDCU1_AliveCounter : 51|4@0+ (1,0) [0|15] "NoUnit" TBOX,GW_FD5,IDB,SRR3,ESC_FD3,GW_FD6,SRR4,GW_FD3,EHB_FD3,TBOX_OverSea
 SG_ DDCU1_FL_WindowsExerciseSts : 53|2@0+ (1,0) [0|3] "NoUnit" SRR3,GW_FD6,SRR4,BDCS
 SG_ DDCU1_RL_WindowsExerciseSts : 55|2@0+ (1,0) [0|3] "NoUnit" SRR3,GW_FD6,SRR4,BDCS
 SG_ DDCU1_Checksum : 63|8@0+ (1,0) [0|255] "NoUnit" TBOX,GW_FD5,IDB,SRR3,ESC_FD3,GW_FD6,SRR4,GW_FD3,EHB_FD3,TBOX_OverSea
 SG_ DDCU1_FRWindowsCtrl : 66|3@0+ (1,0) [0|7] "NoUnit" TBOX,PDCU,GW_FD5,SRR3,GW_FD6,SRR4,TBOX_OverSea
 SG_ DDCU1_RRWindowsCtrl : 69|3@0+ (1,0) [0|7] "NoUnit" TBOX,PDCU,GW_FD5,SRR3,GW_FD6,SRR4,TBOX_OverSea
 SG_ DDCU1_LeftPosMemory_Sts : 71|2@0+ (1,0) [0|3] "NoUnit" TBOX,GW_FD5,SRR3,GW_FD6,SRR4,GW_FD4,CDCS,CDCS_OverSea,TBOX_OverSea
 SG_ DDCU1_FL_LockSt : 73|2@0+ (1,0) [0|3] "NoUnit" TBOX,GW_FD5,GW_FD6,BDCS,TBOX_OverSea
 SG_ DDCU1_RL_LockSt : 75|2@0+ (1,0) [0|3] "NoUnit" TBOX,GW_FD5,GW_FD6,BDCS,TBOX_OverSea
 SG_ DDCU1_WindowSteamSet_Fb : 77|2@0+ (1,0) [0|3] "NoUnit" TBOX,GW_FD5,SRR3,GW_FD6,SRR4,TBOX_OverSea
 SG_ DRGLS_CustomSignal : 78|1@0+ (1,0) [0|1] "NoUnit" SRR3,GW_FD6,SRR4,GW_FD4,CDCS,CDCS_OverSea
 SG_ DFGLS_CustomSignal : 79|1@0+ (1,0) [0|1] "NoUnit" SRR3,GW_FD6,SRR4,GW_FD4,BDCS,CDCS,CDCS_OverSea
 SG_ DDCU1_FL_WindowsAnti_pinchSts : 80|1@0+ (1,0) [0|1] "NoUnit" SRR3,GW_FD6,SRR4,BDCS
 SG_ DDCU1_RL_WindowsAnti_pinchSts : 81|1@0+ (1,0) [0|1] "NoUnit" SRR3,GW_FD6,SRR4,BDCS
 SG_ DDCU1_LeftMirror_Pos_ManualAdjust_Sts : 82|1@0+ (1,0) [0|1] "NoUnit" TBOX,PDCU,GW_FD5,SRR3,GW_FD6,SRR4,GW_FD4,CDCS,CDCS_OverSea,TBOX_OverSea
 SG_ DDCU1_DoorHandleRetractedOverTimeSts : 85|3@0+ (1,0) [0|7] "NoUnit" SRR3,GW_FD6,SRR4,GW_FD4,BDCS,CDCS,CDCS_OverSea
 SG_ DDCU1_FLWindowFollowUpDoorSts : 87|2@0+ (1,0) [0|3] "NoUnit" SRR3,GW_FD6,SRR4,GW_FD4,CDCS,CDCS_OverSea
 SG_ DDCU1_OilFillCapSts : 88|1@0+ (1,0) [0|1] "NoUnit" PDCS_FD1,PDCU,SRR3,SRR4,CDCS,CDCS_OverSea,TBOX,GW_FD5,GW_FD6,GW_FD4,GW_FD1,PDCS_HVM_FD1,TBOX_OverSea
 SG_ DDCU1_CentralLockFailure : 89|1@0+ (1,0) [0|1] "NoUnit" ICU_E02,GW_FD4,BDCS,CDCS_OverSea
 SG_ DDCU1_OilFillCapLockSts : 90|1@0+ (1,0) [0|1] "NoUnit" PDCS_FD1,PDCU,SRR3,SRR4,CDCS,CDCS_OverSea,TBOX,GW_FD5,GW_FD6,GW_FD4,GW_FD1,PDCS_HVM_FD1,TBOX_OverSea
 SG_ DDCU1_MirrorFoldSpeedLimit_Fb : 92|1@0+ (1,0) [0|1] "NoUnit" ICU_E02,SRR3,GW_FD6,SRR4,GW_FD4,ICU,CDCS,CDCS_OverSea
 SG_ DDCU1_FL_DoorHandleSts : 93|1@0+ (1,0) [0|1] "NoUnit" SRR3,GW_FD6,SRR4
 SG_ DDCU1_RL_DoorHandleSts : 94|1@0+ (1,0) [0|1] "NoUnit" SRR3,GW_FD6,SRR4
 SG_ DDCU1_MirrorHeatingSts : 95|1@0+ (1,0) [0|1] "NoUnit" SRR3,GW_FD6,SRR4
 SG_ DDCU1_CentralLockLightSts : 97|2@0+ (1,0) [0|3] "NoUnit" Vector__XXX
 SG_ DDCU1_CentralLockSts : 99|2@0+ (1,0) [0|3] "NoUnit" PDCU,BDCS
 SG_ DDCU1_DFGLS_FLWindowControl : 106|3@0+ (1,0) [0|7] "NoUnit" SRR3,GW_FD6,SRR4
 SG_ DDCU1_DFGLS_RLWindowControl : 109|3@0+ (1,0) [0|7] "NoUnit" SRR3,GW_FD6,SRR4
 SG_ DDCU1_FL_Cause_loss_PWL_Init : 116|5@0+ (1,0) [0|31] "NoUnit" SRR3,GW_FD6,SRR4
 SG_ DDCU1_DRGLS_RLWindowControl : 119|3@0+ (1,0) [0|7] "NoUnit" SRR3,GW_FD6,SRR4
 SG_ DFGLS_ButtonSoundRequest : 120|1@0+ (1,0) [0|1] "NoUnit" SRR3,GW_FD6,SRR4,GW_FD4,CDCS,CDCS_OverSea
 SG_ DRGLS_ButtonSoundRequest : 121|1@0+ (1,0) [0|1] "NoUnit" SRR3,GW_FD6,SRR4,GW_FD4,CDCS,CDCS_OverSea
 SG_ DDCU1_RL_Cause_loss_PWL_Init : 126|5@0+ (1,0) [0|31] "NoUnit" SRR3,GW_FD6,SRR4

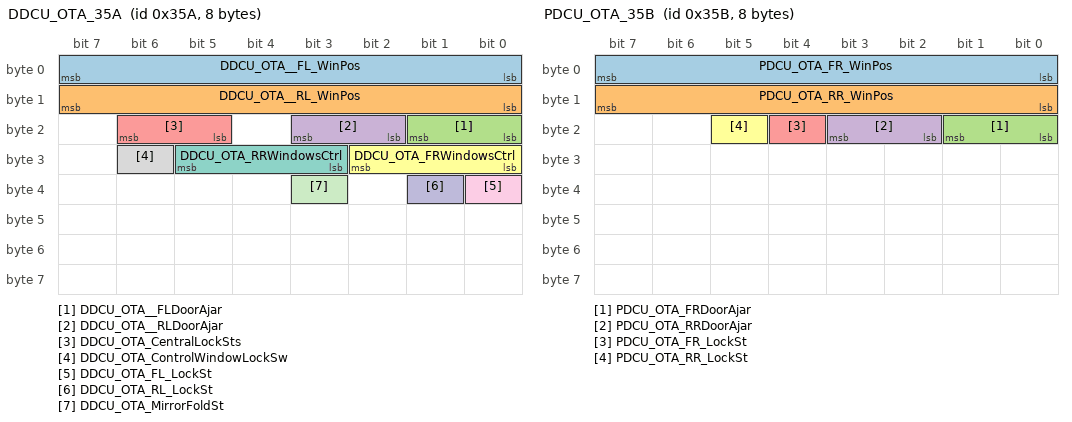
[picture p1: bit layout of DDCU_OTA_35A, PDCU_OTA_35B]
BO_ 858 DDCU_OTA_35A: 8 DDCU
 SG_ DDCU_OTA__FL_WinPos : 7|8@0+ (1,0) [0|100] "%" TBOX,GW_FD5,BDCS,TBOX_OverSea
 SG_ DDCU_OTA__RL_WinPos : 15|8@0+ (1,0) [0|100] "%" TBOX,GW_FD5,BDCS,TBOX_OverSea
 SG_ DDCU_OTA__FLDoorAjar : 17|2@0+ (1,0) [0|3] "NoUnit" TBOX,GW_FD5,BDCS,TBOX_OverSea
 SG_ DDCU_OTA__RLDoorAjar : 19|2@0+ (1,0) [0|3] "NoUnit" TBOX,GW_FD5,BDCS,TBOX_OverSea
 SG_ DDCU_OTA_CentralLockSts : 22|2@0+ (1,0) [0|3] "NoUnit" BDCS
 SG_ DDCU_OTA_FRWindowsCtrl : 26|3@0+ (1,0) [0|7] "NoUnit" PDCU
 SG_ DDCU_OTA_RRWindowsCtrl : 29|3@0+ (1,0) [0|7] "NoUnit" PDCU
 SG_ DDCU_OTA_ControlWindowLockSw : 30|1@0+ (1,0) [0|1] "NoUnit" PDCU
 SG_ DDCU_OTA_FL_LockSt : 32|1@0+ (1,0) [0|1] "NoUnit" TBOX,PDCU,GW_FD5,BDCS,TBOX_OverSea
 SG_ DDCU_OTA_RL_LockSt : 33|1@0+ (1,0) [0|1] "NoUnit" TBOX,PDCU,GW_FD5,BDCS,TBOX_OverSea
 SG_ DDCU_OTA_MirrorFoldSt : 35|1@0+ (1,0) [0|1] "NoUnit" BDCS

BO_ 1550 DDCU_NM_60E: 8 DDCU
 SG_ DDCU_SourceNodeIdentifier : 7|8@0+ (1,0) [0|255] "NoUnit" Vector__XXX
 SG_ DDCU_RepeatMessageRequest : 8|1@0+ (1,0) [0|1] "NoUnit" Vector__XXX
 SG_ DDCU_Reserve1 : 11|3@0+ (1,0) [0|3] "NoUnit" Vector__XXX
 SG_ DDCU_ActiveWakeup : 12|1@0+ (1,0) [0|1] "NoUnit" Vector__XXX
 SG_ DDCU_Reserve2 : 15|3@0+ (1,0) [0|7] "NoUnit" Vector__XXX
 SG_ DDCU_WakeUp_KL15 : 16|1@0+ (1,0) [0|1] "NoUnit" Vector__XXX
 SG_ DDCU_WakeUp_NM : 17|1@0+ (1,0) [0|1] "NoUnit" Vector__XXX
 SG_ DDCU_WakeUp_FLDoor : 18|1@0+ (1,0) [0|1] "NoUnit" Vector__XXX
 SG_ DDCU_WakeUp_RLDoor : 19|1@0+ (1,0) [0|1] "NoUnit" Vector__XXX
 SG_ DDCU_WakeUp_FLInSW : 20|1@0+ (1,0) [0|1] "NoUnit" Vector__XXX
 SG_ DDCU_WakeUp_FLOutSW : 21|1@0+ (1,0) [0|1] "NoUnit" Vector__XXX
 SG_ DDCU_WakeUp_RLInSW : 22|1@0+ (1,0) [0|1] "NoUnit" Vector__XXX
 SG_ DDCU_WakeUp_RLOutSW : 23|1@0+ (1,0) [0|1] "NoUnit" Vector__XXX
 SG_ DDCU_RepeatFromSleep : 24|1@0+ (1,0) [0|1] "NoUnit" Vector__XXX
 SG_ DDCU_RepeatFromPrepare : 25|1@0+ (1,0) [0|1] "NoUnit" Vector__XXX
 SG_ DDCU_NormalFromRepeat : 26|1@0+ (1,0) [0|1] "NoUnit" Vector__XXX
 SG_ DDCU_NormalFromReady : 27|1@0+ (1,0) [0|1] "NoUnit" Vector__XXX
 SG_ DDCU_RepeatFromReady : 28|1@0+ (1,0) [0|1] "NoUnit" Vector__XXX
 SG_ DDCU_RepeatFromNormal : 29|1@0+ (1,0) [0|1] "NoUnit" Vector__XXX
 SG_ DDCU_RemainNetworkWakeUpReason1 : 32|1@0+ (1,0) [0|1] "NoUnit" Vector__XXX
 SG_ DDCU_RemainNetworkWakeUpReason2 : 33|1@0+ (1,0) [0|1] "NoUnit" Vector__XXX
 SG_ DDCU_RemainNetworkWakeUpReason3 : 34|1@0+ (1,0) [0|1] "NoUnit" Vector__XXX
 SG_ DDCU_RemainNetworkWakeUpReason4 : 35|1@0+ (1,0) [0|1] "NoUnit" Vector__XXX
 SG_ DDCU_WakeUp_FLLockSts : 54|1@0+ (1,0) [0|1] "NoUnit" Vector__XXX
 SG_ DDCU_WakeUp_FuelTankCap : 55|1@0+ (1,0) [0|1] "NoUnit" Vector__XXX

BO_ 419 PDCU_Fr01_1A3: 16 PDCU
 SG_ PDCU1_OilFillCapSts : 0|1@0+ (1,0) [0|1] "NoUnit" PDCS_FD1,TBOX,GW_FD5,GW_FD4,GW_FD1,CDCS,PDCS_HVM_FD1,CDCS_OverSea,TBOX_OverSea
 SG_ PDCU1_OilFillCapLockSts : 1|1@0+ (1,0) [0|1] "NoUnit" TBOX,GW_FD5,GW_FD4,CDCS,CDCS_OverSea,TBOX_OverSea
 SG_ PDCU1_FRWinCtrl_Fb : 4|3@0+ (1,0) [0|7] "NoUnit" TBOX,GW_FD5,GW_FD4,CDCS,CDCS_OverSea,TBOX_OverSea
 SG_ PDCU1_RRWinCtrl_Fb : 7|3@0+ (1,0) [0|7] "NoUnit" TBOX,GW_FD5,GW_FD4,CDCS,CDCS_OverSea,TBOX_OverSea
 SG_ PDCU1_FR_WinPos : 15|8@0+ (1,0) [0|100] "%" ADCU_FD3,BDCS,CDCS,ADCS_FD3,CDCS_OverSea,TBOX,FLC_ME_FD3,FLC_FD3,GW_FD5,GW_FD3,GW_FD4,TBOX_OverSea
 SG_ PDCU1_RR_WinPos : 23|8@0+ (1,0) [0|100] "%" ADCU_FD3,BDCS,CDCS,ADCS_FD3,CDCS_OverSea,TBOX,FLC_ME_FD3,FLC_FD3,GW_FD5,GW_FD3,GW_FD4,TBOX_OverSea
 SG_ PDCU1_FRDoorAjar : 25|2@0+ (1,0) [0|3] "NoUnit" PDCS_FD1,IDB,ESC_FD3,ADCU_FD3,EHB_FD3,CDCS,ICU_E02,SRR3,SRR4,BMS,BDCS,DDCU,ADCS_FD3,CDCS_OverSea,TBOX,FLC_ME_FD3,FLC_FD3,GW_FD5,GW_FD6,GW_FD3,GW_FD4,GW_FD1,ICU,PDCS_HVM_FD1,TBOX_OverSea
 SG_ PDCU1_RRDoorAjar : 27|2@0+ (1,0) [0|3] "NoUnit" PDCS_FD1,SRR3,SRR4,ADCU_FD3,BMS,BDCS,DDCU,CDCS,ADCS_FD3,CDCS_OverSea,TBOX,FLC_ME_FD3,FLC_FD3,GW_FD5,ICU_E02,GW_FD6,GW_FD3,GW_FD4,GW_FD1,ICU,PDCS_HVM_FD1,TBOX_OverSea
 SG_ PDCU1_RR_SafetyLockFdbk : 28|1@0+ (1,0) [0|1] "NoUnit" TBOX,GW_FD5,GW_FD4,CDCS,CDCS_OverSea,TBOX_OverSea
 SG_ PFGLS_CustomSignal : 29|1@0+ (1,0) [0|1] "NoUnit" GW_FD4,CDCS,CDCS_OverSea
 SG_ PRGLS_CustomSignal : 30|1@0+ (1,0) [0|1] "NoUnit" GW_FD4,CDCS,CDCS_OverSea
 SG_ PDCU1_LockReleaseSw_Out_FR : 31|1@0+ (1,0) [0|1] "NoUnit" TBOX,GW_FD5,GW_FD4,BDCS,CDCS,CDCS_OverSea,TBOX_OverSea
 SG_ PDCU1_LockReleaseSw_Out_RR : 32|1@0+ (1,0) [0|1] "NoUnit" TBOX,GW_FD5,GW_FD4,CDCS,CDCS_OverSea,TBOX_OverSea
 SG_ PDCU1_LockReleaseSw_In_FR : 33|1@0+ (1,0) [0|1] "NoUnit" TBOX,GW_FD5,GW_FD4,BDCS,CDCS,CDCS_OverSea,TBOX_OverSea
 SG_ PDCU1_LockReleaseSw_In_RR : 34|1@0+ (1,0) [0|1] "NoUnit" TBOX,GW_FD5,GW_FD4,CDCS,CDCS_OverSea,TBOX_OverSea
 SG_ PDCU1_FR_HallFault : 35|1@0+ (1,0) [0|1] "NoUnit" TBOX,GW_FD5,GW_FD4,CDCS,CDCS_OverSea,TBOX_OverSea
 SG_ PDCU1_FR_PWL_Init : 36|1@0+ (1,0) [0|1] "NoUnit" TBOX,GW_FD5,GW_FD4,CDCS,CDCS_OverSea,TBOX_OverSea
 SG_ PDCU1_FR_PWL_State : 39|3@0+ (1,0) [0|7] "NoUnit" TBOX,GW_FD5,GW_FD4,CDCS,CDCS_OverSea,TBOX_OverSea
 SG_ PDCU1_RR_PWL_State : 42|3@0+ (1,0) [0|7] "NoUnit" TBOX,GW_FD5,GW_FD4,CDCS,CDCS_OverSea,TBOX_OverSea
 SG_ PDCU1_RR_HallFault : 43|1@0+ (1,0) [0|1] "NoUnit" TBOX,GW_FD5,GW_FD4,CDCS,CDCS_OverSea,TBOX_OverSea
 SG_ PDCU1_RR_PWL_Init : 44|1@0+ (1,0) [0|1] "NoUnit" TBOX,GW_FD5,GW_FD4,CDCS,CDCS_OverSea,TBOX_OverSea
 SG_ PDCU1_RightMirrorAutoTurnDownFb : 45|1@0+ (1,0) [0|1] "NoUnit" TBOX,GW_FD5,GW_FD4,CDCS,CDCS_OverSea,TBOX_OverSea
 SG_ PDCU1_PosLoad_Sts : 47|2@0+ (1,0) [0|3] "NoUnit" TBOX,GW_FD5,GW_FD4,CDCS,CDCS_OverSea,TBOX_OverSea
 SG_ PDCU1_AliveCounter : 51|4@0+ (1,0) [0|15] "NoUnit" TBOX,GW_FD5,IDB,GW_FD3,TBOX_OverSea
 SG_ PDCU1_ChargeFillCapLockSts : 55|1@0+ (1,0) [0|1] "NoUnit" PDCS_FD1,TBOX,GW_FD5,GW_FD4,GW_FD1,CDCS,PDCS_HVM_FD1,CDCS_OverSea,TBOX_OverSea
 SG_ PDCU1_Checksum : 63|8@0+ (1,0) [0|255] "NoUnit" TBOX,GW_FD5,IDB,GW_FD3,TBOX_OverSea
 SG_ PDCU1_ChargeLidSts : 64|1@0+ (1,0) [0|1] "NoUnit" TBOX,GW_FD5,GW_FD4,CDCS,CDCS_OverSea,TBOX_OverSea
 SG_ PDCU1_PosMemory_Sts : 67|2@0+ (1,0) [0|3] "NoUnit" TBOX,GW_FD5,GW_FD4,CDCS,CDCS_OverSea,TBOX_OverSea
 SG_ PDCU1_FR_WindowsExerciseSts : 69|2@0+ (1,0) [0|3] "NoUnit" BDCS
 SG_ PDCU1_RR_WindowsExerciseSts : 71|2@0+ (1,0) [0|3] "NoUnit" BDCS
 SG_ PDCU1_FR_LockSt : 73|2@0+ (1,0) [0|3] "NoUnit" TBOX,GW_FD5,GW_FD6,BDCS,TBOX_OverSea
 SG_ PDCU1_RR_LockSt : 75|2@0+ (1,0) [0|3] "NoUnit" TBOX,GW_FD5,GW_FD6,BDCS,TBOX_OverSea
 SG_ PDCU1_WindowSteamSet_Fb : 77|2@0+ (1,0) [0|3] "NoUnit" TBOX,GW_FD5,TBOX_OverSea
 SG_ PDCU1_FR_WindowsAnti_pinchSts : 78|1@0+ (1,0) [0|1] "NoUnit" BDCS
 SG_ PDCU1_RR_WindowsAnti_pinchSts : 79|1@0+ (1,0) [0|1] "NoUnit" BDCS
 SG_ PDCU1_DoorHandleRetractedOverTimeSts : 82|3@0+ (1,0) [0|7] "NoUnit" GW_FD4,CDCS,CDCS_OverSea
 SG_ PDCU1_RightMirror_Pos_ManualAdjust_Sts : 84|1@0+ (1,0) [0|1] "NoUnit" GW_FD4,CDCS,CDCS_OverSea
 SG_ PDCU1_FRWindowFollowUpDoorSts : 87|2@0+ (1,0) [0|3] "NoUnit" GW_FD4,CDCS,CDCS_OverSea
 SG_ PDCU1_FR_DoorHandleSts : 88|1@0+ (1,0) [0|1] "NoUnit" Vector__XXX
 SG_ PDCU1_RR_DoorHandleSts : 89|1@0+ (1,0) [0|1] "NoUnit" Vector__XXX
 SG_ PDCU1_MirrorHeatingSts : 90|1@0+ (1,0) [0|1] "NoUnit" Vector__XXX
 SG_ PDCU1_PFGLS_RLWindowControl : 95|3@0+ (1,0) [0|7] "NoUnit" Vector__XXX
 SG_ PDCU1_FR_Cause_loss_PWL_Init : 116|5@0+ (1,0) [0|31] "NoUnit" Vector__XXX
 SG_ PDCU1_PRGLS_RRWindowControl : 119|3@0+ (1,0) [0|7] "NoUnit" Vector__XXX
 SG_ PFGLS_ButtonSoundRequest : 120|1@0+ (1,0) [0|1] "NoUnit" GW_FD4,CDCS,CDCS_OverSea
 SG_ PRGLS_ButtonSoundRequest : 121|1@0+ (1,0) [0|1] "NoUnit" GW_FD4,CDCS,CDCS_OverSea
 SG_ PDCU1_RR_Cause_loss_PWL_Init : 126|5@0+ (1,0) [0|31] "NoUnit" Vector__XXX

BO_ 859 PDCU_OTA_35B: 8 PDCU
 SG_ PDCU_OTA_FR_WinPos : 7|8@0+ (1,0) [0|100] "%" TBOX,GW_FD5,BDCS,TBOX_OverSea
 SG_ PDCU_OTA_RR_WinPos : 15|8@0+ (1,0) [0|100] "%" TBOX,GW_FD5,BDCS,TBOX_OverSea
 SG_ PDCU_OTA_FRDoorAjar : 17|2@0+ (1,0) [0|3] "NoUnit" TBOX,GW_FD5,BDCS,DDCU,TBOX_OverSea
 SG_ PDCU_OTA_RRDoorAjar : 19|2@0+ (1,0) [0|3] "NoUnit" TBOX,GW_FD5,BDCS,DDCU,TBOX_OverSea
 SG_ PDCU_OTA_FR_LockSt : 20|1@0+ (1,0) [0|1] "NoUnit" TBOX,GW_FD5,BDCS,DDCU,TBOX_OverSea
 SG_ PDCU_OTA_RR_LockSt : 21|1@0+ (1,0) [0|1] "NoUnit" TBOX,GW_FD5,BDCS,DDCU,TBOX_OverSea

BO_ 1549 PDCU_NM_60D: 8 PDCU
 SG_ PDCU_SourceNodeIdentifier : 7|8@0+ (1,0) [0|255] "NoUnit" Vector__XXX
 SG_ PDCU_RepeatMessageRequest : 8|1@0+ (1,0) [0|1] "NoUnit" Vector__XXX
 SG_ PDCU_Reserve1 : 11|3@0+ (1,0) [0|3] "NoUnit" Vector__XXX
 SG_ PDCU_ActiveWakeup : 12|1@0+ (1,0) [0|1] "NoUnit" Vector__XXX
 SG_ PDCU_Reserve2 : 15|3@0+ (1,0) [0|7] "NoUnit" Vector__XXX
 SG_ PDCU_WakeUp_KL15 : 16|1@0+ (1,0) [0|1] "NoUnit" Vector__XXX
 SG_ PDCU_WakeUp_NM : 17|1@0+ (1,0) [0|1] "NoUnit" Vector__XXX
 SG_ PDCU_WakeUp_FRDoor : 18|1@0+ (1,0) [0|1] "NoUnit" Vector__XXX
 SG_ PDCU_WakeUp_RRDoor : 19|1@0+ (1,0) [0|1] "NoUnit" Vector__XXX
 SG_ PDCU_WakeUp_FRInSW : 20|1@0+ (1,0) [0|1] "NoUnit" Vector__XXX
 SG_ PDCU_WakeUp_FROutSW : 21|1@0+ (1,0) [0|1] "NoUnit" Vector__XXX
 SG_ PDCU_WakeUp_RRInSW : 22|1@0+ (1,0) [0|1] "NoUnit" Vector__XXX
 SG_ PDCU_WakeUp_RROutSW : 23|1@0+ (1,0) [0|1] "NoUnit" Vector__XXX
 SG_ PDCU_RepeatFromSleep : 24|1@0+ (1,0) [0|1] "NoUnit" Vector__XXX
 SG_ PDCU_RepeatFromPrepare : 25|1@0+ (1,0) [0|1] "NoUnit" Vector__XXX
 SG_ PDCU_NormalFromRepeat : 26|1@0+ (1,0) [0|1] "NoUnit" Vector__XXX
 SG_ PDCU_NormalFromReady : 27|1@0+ (1,0) [0|1] "NoUnit" Vector__XXX
 SG_ PDCU_RepeatFromReady : 28|1@0+ (1,0) [0|1] "NoUnit" Vector__XXX
 SG_ PDCU_RepeatFromNormal : 29|1@0+ (1,0) [0|1] "NoUnit" Vector__XXX
 SG_ PDCU_RemainNetworkWakeUpReason1 : 32|1@0+ (1,0) [0|1] "NoUnit" Vector__XXX
 SG_ PDCU_RemainNetworkWakeUpReason2 : 33|1@0+ (1,0) [0|1] "NoUnit" Vector__XXX
 SG_ PDCU_RemainNetworkWakeUpReason3 : 34|1@0+ (1,0) [0|1] "NoUnit" Vector__XXX
 SG_ PDCU_RemainNetworkWakeUpReason4 : 35|1@0+ (1,0) [0|1] "NoUnit" Vector__XXX
 SG_ PDCU_WakeUp_FuelTankCap : 55|1@0+ (1,0) [0|1] "NoUnit" Vector__XXX
 SG_ PDCU_UserData5 : 54|8@0+ (1,0) [0|255] "NoUnit" Vector__XXX

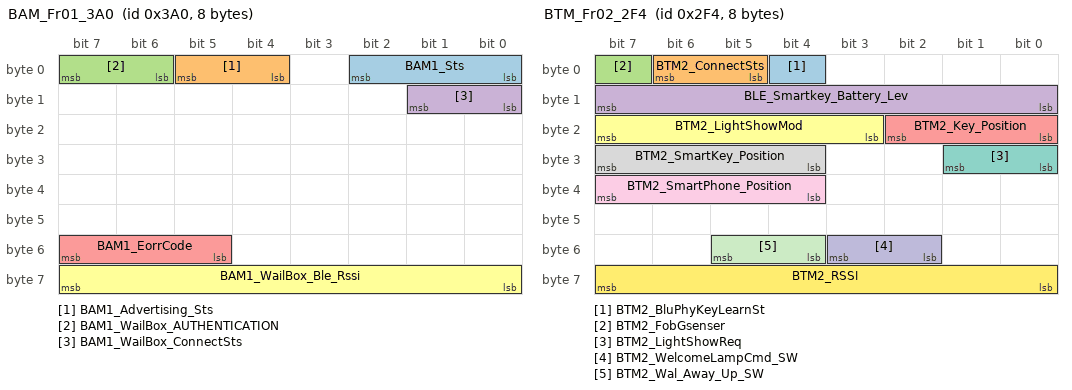
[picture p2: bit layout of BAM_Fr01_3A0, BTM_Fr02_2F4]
BO_ 928 BAM_Fr01_3A0: 8 BAM
 SG_ BAM1_Sts : 2|3@0+ (1,0) [0|7] "NoUnit" PDCU,CDU,BMS,GW_FD4,GW_FD1,DDCU,CDCS,PDCS_HVM_FD1,CDCS_OverSea
 SG_ BAM1_Advertising_Sts : 5|2@0+ (1,0) [0|3] "NoUnit" CDU,BMS,GW_FD4,GW_FD1,CDCS,PDCS_HVM_FD1,CDCS_OverSea
 SG_ BAM1_WailBox_AUTHENTICATION : 7|2@0+ (1,0) [0|3] "NoUnit" PDCU,CDU,BMS,GW_FD4,GW_FD1,DDCU,CDCS,PDCS_HVM_FD1,CDCS_OverSea
 SG_ BAM1_WailBox_ConnectSts : 9|2@0+ (1,0) [0|3] "NoUnit" PDCU,CDU,BMS,GW_FD4,GW_FD1,DDCU,CDCS,PDCS_HVM_FD1,CDCS_OverSea
 SG_ BAM1_EorrCode : 55|3@0+ (1,0) [0|7] "NoUnit" PDCU,CDU,BMS,GW_FD4,GW_FD1,DDCU,CDCS,PDCS_HVM_FD1,CDCS_OverSea
 SG_ BAM1_WailBox_Ble_Rssi : 63|8@0+ (1,0) [0|255] "NoUnit" CDU,BMS,GW_FD4,GW_FD1,CDCS,PDCS_HVM_FD1,CDCS_OverSea

BO_ 1609 BAM_NM_649: 8 BAM
 SG_ BAM_SourceNodeIdentifier : 7|8@0+ (1,0) [0|255] "NoUnit" Vector__XXX
 SG_ BAM_RepeatMessageRequest : 8|1@0+ (1,0) [0|1] "" Vector__XXX
 SG_ BAM_Reserve1 : 11|3@0+ (1,0) [0|3] "" Vector__XXX
 SG_ BAM_ActiveWakeup : 12|1@0+ (1,0) [0|1] "" Vector__XXX
 SG_ BAM_Reserve2 : 15|3@0+ (1,0) [0|7] "" Vector__XXX
 SG_ BAM_WakeUp_KL15 : 16|1@0+ (1,0) [0|1] "" Vector__XXX
 SG_ BAM_WakeUp_NM : 17|1@0+ (1,0) [0|1] "" Vector__XXX
 SG_ BAM_RepeatFromSleep : 24|1@0+ (1,0) [0|1] "" Vector__XXX
 SG_ BAM_RepeatFromPrepare : 25|1@0+ (1,0) [0|1] "" Vector__XXX
 SG_ BAM_NormalFromRepeat : 26|1@0+ (1,0) [0|1] "" Vector__XXX
 SG_ BAM_NormalFromReady : 27|1@0+ (1,0) [0|1] "" Vector__XXX
 SG_ BAM_RepeatFromReady : 28|1@0+ (1,0) [0|1] "" Vector__XXX
 SG_ BAM_RepeatFromNormal : 29|1@0+ (1,0) [0|1] "" Vector__XXX
 SG_ BAM_RemainNetworkWakeUpReason1 : 32|1@0+ (1,0) [0|1] "" Vector__XXX
 SG_ BAM_RemainNetworkWakeUpReason2 : 33|1@0+ (1,0) [0|1] "" Vector__XXX
 SG_ BAM_RemainNetworkWakeUpReason3 : 34|1@0+ (1,0) [0|1] "" Vector__XXX
 SG_ BAM_RemainNetworkWakeUpReason4 : 35|1@0+ (1,0) [0|1] "" Vector__XXX

BO_ 243 BTM_Fr01_0F3: 32 TBOX
 SG_ BTM1_SecuritySts : 3|4@0+ (1,0) [0|15] "NoUnit" GW_FD3,ADCU_FD3,ADCS_FD3
 SG_ BTM1_PhoneBatSts : 15|1@0+ (1,0) [0|1] "NoUnit" GW_FD3,ADCU_FD3,GW_FD4,CDCS,ADCS_FD3,CDCS_OverSea
 SG_ BTM1_RemoteIntModSel : 22|2@0+ (1,0) [0|3] "NoUnit" GW_FD3,ADCU_FD3,GW_FD4,CDCS,ADCS_FD3,CDCS_OverSea
 SG_ BTM1_SelectSlotID : 27|4@0+ (1,0) [0|15] "NoUnit" GW_FD3,ADCU_FD3,ADCS_FD3
 SG_ BTM1_Retry : 29|2@0+ (1,0) [0|3] "NoUnit" GW_FD3,ADCU_FD3,ADCS_FD3
 SG_ BTM1_Fixslot : 31|2@0+ (1,0) [0|3] "NoUnit" GW_FD3,ADCU_FD3,ADCS_FD3
 SG_ BTM1_parkingoutSlot_Dire : 33|2@0+ (1,0) [0|3] "NoUnit" GW_FD3,ADCU_FD3,ADCS_FD3
 SG_ BTM1_parkingoutSlotType : 35|2@0+ (1,0) [0|3] "NoUnit" GW_FD3,ADCU_FD3,ADCS_FD3
 SG_ BTM1_Recover : 36|1@0+ (1,0) [0|1] "NoUnit" GW_FD3,ADCU_FD3,ADCS_FD3
 SG_ BTM1_ParkingReq : 38|2@0+ (1,0) [0|3] "NoUnit" GW_FD3,ADCU_FD3,ADCS_FD3
 SG_ BTM1_FunctionMode : 42|3@0+ (1,0) [0|7] "NoUnit" GW_FD3,ADCU_FD3,ADCS_FD3
 SG_ BTM1_OptionalSlot_Dire : 45|3@0+ (1,0) [0|7] "NoUnit" GW_FD3,ADCU_FD3,ADCS_FD3
 SG_ BTM1_OptionalSlotType : 47|2@0+ (1,0) [0|3] "NoUnit" GW_FD3,ADCU_FD3,ADCS_FD3
 SG_ BTM1_RollingCounter : 51|4@0+ (1,0) [0|15] "NoUnit" GW_FD3,ADCU_FD3,ADCS_FD3
 SG_ BTM1_RemoteParkReq : 53|2@0+ (1,0) [0|3] "NoUnit" GW_FD3,ADCU_FD3,ADCS_FD3
 SG_ BTM1_Movectrl : 55|2@0+ (1,0) [0|3] "NoUnit" GW_FD3,ADCU_FD3,ADCS_FD3
 SG_ BTM1_Checksum : 63|8@0+ (1,0) [0|255] "NoUnit" GW_FD3,ADCU_FD3,ADCS_FD3
 SG_ BTM1_OptionalSlotAngle : 70|15@0+ (0.001,0) [0|32.767] "rad" GW_FD3,ADCU_FD3,ADCS_FD3
 SG_ BTM1_OptionalSlotCoor_P0_X : 85|14@0+ (1,0) [0|16383] "NoUnit" GW_FD3,ADCU_FD3,ADCS_FD3
 SG_ BTM1_OptionalSlotCoor_P0_Y : 101|14@0+ (1,0) [0|16383] "NoUnit" GW_FD3,ADCU_FD3,ADCS_FD3
 SG_ BTM1_OptionalSlotCoor_P1_X : 117|14@0+ (1,0) [0|16383] "NoUnit" GW_FD3,ADCU_FD3,ADCS_FD3
 SG_ BTM1_OptionalSlotCoor_P1_Y : 133|14@0+ (1,0) [0|16383] "NoUnit" GW_FD3,ADCU_FD3,ADCS_FD3
 SG_ BTM1_OptionalSlotCoor_P2_X : 149|14@0+ (1,0) [0|16383] "NoUnit" GW_FD3,ADCU_FD3,ADCS_FD3
 SG_ BTM1_OptionalSlotCoor_P2_Y : 165|14@0+ (1,0) [0|16383] "NoUnit" GW_FD3,ADCU_FD3,ADCS_FD3
 SG_ BTM1_OptionalSlotCoor_P3_X : 181|14@0+ (1,0) [0|16383] "NoUnit" GW_FD3,ADCU_FD3,ADCS_FD3
 SG_ BTM1_OptionalSlotCoor_P3_Y : 197|14@0+ (1,0) [0|16383] "NoUnit" GW_FD3,ADCU_FD3,ADCS_FD3

BO_ 498 BTM_Fr03_1F2: 8 TBOX
 SG_ BTM3_ArmingCmd : 1|2@0+ (1,0) [0|3] "NoUnit" GW_FD2,BDCS,BAM
 SG_ BTM3_TrunkCmd : 3|2@0+ (1,0) [0|3] "NoUnit" GW_FD2,BDCS,BAM
 SG_ BTM3_RKECmd : 7|4@0+ (1,0) [0|15] "NoUnit" GW_FD3,ADCU_FD3,GW_FD2,BDCS,BAM,ADCS_FD3
 SG_ BTM3_Chargingflapcmd : 9|2@0+ (1,0) [0|3] "NoUnit" PDCU,GW_FD2,BAM
 SG_ BTM3_WelcomeLampCmd : 11|2@0+ (1,0) [0|3] "NoUnit" GW_FD4,GW_FD2,BDCS,BAM,CDCS,CDCS_OverSea
 SG_ BTM3_CLM_OnoffCmd : 13|2@0+ (1,0) [0|3] "NoUnit" GW_FD2,BDCS,BAM
 SG_ BTM3_Remote_ControlCmd : 15|2@0+ (1,0) [0|3] "NoUnit" GW_FD2,BDCS,BAM
 SG_ BTM3_RL_Window_Control_Cmd : 18|3@0+ (1,0) [0|7] "NoUnit" GW_FD2,BAM
 SG_ BTM3_RR_Window_Control_Cmd : 21|3@0+ (1,0) [0|7] "NoUnit" PDCU,GW_FD2,DDCU,BAM
 SG_ BTM3_CLM_ACCmd : 23|2@0+ (1,0) [0|3] "NoUnit" GW_FD2,BDCS,BAM
 SG_ BTM3_FL_Window_Control_Cmd : 26|3@0+ (1,0) [0|7] "NoUnit" GW_FD2,BAM
 SG_ BTM3_FR_Window_Control_Cmd : 29|3@0+ (1,0) [0|7] "NoUnit" PDCU,GW_FD2,BAM
 SG_ BTM3_CLM_PTCCmd : 31|2@0+ (1,0) [0|3] "NoUnit" GW_FD2,BDCS,BAM
 SG_ BTM3_CLM_BlowerSpdSet : 39|4@0+ (1,0) [0|15] "NoUnit" GW_FD2,BDCS,BAM
 SG_ BTM3_CLM_RHTempSet : 45|6@0+ (0.5,16) [16|32] "NoUnit" GW_FD2,BDCS,BAM
 SG_ BTM3_CLM_LHTempSet : 35|6@0+ (0.5,16) [16|32] "NoUnit" GW_FD2,BDCS,BAM
 SG_ BTM3_Charging_cmd : 49|2@0+ (1,0) [0|3] "NoUnit" GW_FD4,GW_FD2,BAM,CDCS,CDCS_OverSea
 SG_ BTM3_OpenFLDoorReq : 51|2@0+ (1,0) [0|3] "NoUnit" GW_FD2,BDCS
 SG_ BTM3_All_Window_Closd_Cmd : 55|2@0+ (1,0) [0|3] "NoUnit" GW_FD2,BDCS
 SG_ BTM3_All_Window_Open_Cmd : 57|2@0+ (1,0) [0|3] "NoUnit" GW_FD2,BDCS
 SG_ BTM3_All_Window_Ventilate_Cmd : 59|2@0+ (1,0) [0|3] "NoUnit" GW_FD2,BDCS
 SG_ BTM3_OpenFLFRDoorReq : 61|2@0+ (1,0) [0|3] "NoUnit" GW_FD2,BDCS
 SG_ BTM3_OpenFRDoorReq : 63|2@0+ (1,0) [0|3] "NoUnit" GW_FD2,BDCS

BO_ 755 BTM_Fr04_2F3: 8 TBOX
 SG_ BTM4_Key_Sts : 3|3@0+ (1,0) [0|7] "NoUnit" GW_FD2,BDCS,BAM
 SG_ BTM4_SunroofCtrl : 6|3@0+ (1,0) [0|7] "NoUnit" GW_FD2,BDCS

BO_ 756 BTM_Fr02_2F4: 8 TBOX
 SG_ BTM2_BluPhyKeyLearnSt : 4|1@0+ (1,0) [0|1] "NoUnit" GW_FD2,BDCS,BAM
 SG_ BTM2_ConnectSts : 6|2@0+ (1,0) [0|3] "NoUnit" GW_FD3,ADCU_FD3,GW_FD2,BDCS,BAM,CDCS,ADCS_FD3,CDCS_OverSea
 SG_ BTM2_FobGsenser : 7|1@0+ (1,0) [0|1] "NoUnit" GW_FD2,BAM
 SG_ BLE_Smartkey_Battery_Lev : 15|8@0+ (0.5,0) [0|100] "%" GW_FD4,GW_FD2,BDCS,BAM,CDCS,CDCS_OverSea
 SG_ BTM2_Key_Position : 18|3@0+ (1,0) [0|7] "NoUnit" GW_FD3,ADCU_FD3,GW_FD2,BDCS,DDCU,BAM,ADCS_FD3
 SG_ BTM2_LightShowMod : 23|5@0+ (1,0) [0|31] "NoUnit" GW_FD2,BDCS
 SG_ BTM2_LightShowReq : 25|2@0+ (1,0) [0|3] "NoUnit" GW_FD2,BDCS
 SG_ BTM2_SmartKey_Position : 31|4@0+ (1,0) [0|15] "NoUnit" GW_FD2,BDCS
 SG_ BTM2_SmartPhone_Position : 39|4@0+ (1,0) [0|15] "NoUnit" GW_FD2,BDCS
 SG_ BTM2_WelcomeLampCmd_SW : 51|2@0+ (1,0) [0|3] "NoUnit" GW_FD4,GW_FD2,BDCS,BAM,CDCS,CDCS_OverSea
 SG_ BTM2_Wal_Away_Up_SW : 53|2@0+ (1,0) [0|3] "NoUnit" GW_FD4,GW_FD2,BDCS,BAM,CDCS,CDCS_OverSea
 SG_ BTM2_RSSI : 63|8@0+ (1,0) [0|255] "NoUnit" GW_FD2,BAM

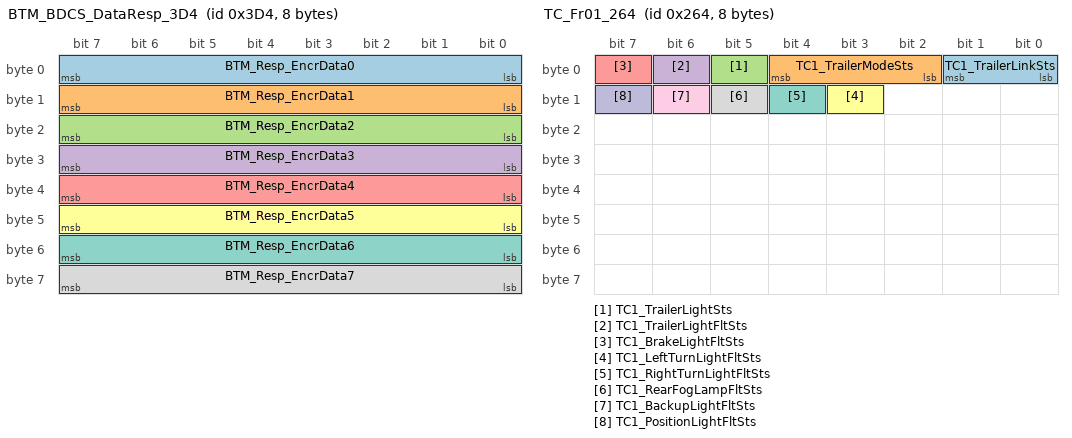
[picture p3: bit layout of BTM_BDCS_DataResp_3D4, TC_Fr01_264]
BO_ 980 BTM_BDCS_DataResp_3D4: 8 TBOX
 SG_ BTM_Resp_EncrData0 : 7|8@0+ (1,0) [0|255] "NoUnit" GW_FD2,BDCS
 SG_ BTM_Resp_EncrData1 : 15|8@0+ (1,0) [0|255] "NoUnit" GW_FD2,BDCS
 SG_ BTM_Resp_EncrData2 : 23|8@0+ (1,0) [0|255] "NoUnit" GW_FD2,BDCS
 SG_ BTM_Resp_EncrData3 : 31|8@0+ (1,0) [0|255] "NoUnit" GW_FD2,BDCS
 SG_ BTM_Resp_EncrData4 : 39|8@0+ (1,0) [0|255] "NoUnit" GW_FD2,BDCS
 SG_ BTM_Resp_EncrData5 : 47|8@0+ (1,0) [0|255] "NoUnit" GW_FD2,BDCS
 SG_ BTM_Resp_EncrData6 : 55|8@0+ (1,0) [0|255] "NoUnit" GW_FD2,BDCS
 SG_ BTM_Resp_EncrData7 : 63|8@0+ (1,0) [0|255] "NoUnit" GW_FD2,BDCS

BO_ 612 TC_Fr01_264: 8 BDCS
 SG_ TC1_TrailerLinkSts : 1|2@0+ (1,0) [0|3] "NoUnit" IDB,GW_FD3,GW_FD4,CDCS_OverSea
 SG_ TC1_TrailerModeSts : 4|3@0+ (1,0) [0|7] "NoUnit" IDB,GW_FD3,GW_FD4,CDCS_OverSea
 SG_ TC1_TrailerLightSts : 5|1@0+ (1,0) [0|1] "NoUnit" GW_FD4,CDCS_OverSea
 SG_ TC1_TrailerLightFltSts : 6|1@0+ (1,0) [0|1] "NoUnit" GW_FD4,CDCS_OverSea
 SG_ TC1_BrakeLightFltSts : 7|1@0+ (1,0) [0|1] "NoUnit" GW_FD4,CDCS_OverSea
 SG_ TC1_LeftTurnLightFltSts : 11|1@0+ (1,0) [0|1] "NoUnit" GW_FD4,CDCS_OverSea
 SG_ TC1_RightTurnLightFltSts : 12|1@0+ (1,0) [0|1] "NoUnit" GW_FD4,CDCS_OverSea
 SG_ TC1_RearFogLampFltSts : 13|1@0+ (1,0) [0|1] "NoUnit" GW_FD4,CDCS_OverSea
 SG_ TC1_BackupLightFltSts : 14|1@0+ (1,0) [0|1] "NoUnit" GW_FD4,CDCS_OverSea
 SG_ TC1_PositionLightFltSts : 15|1@0+ (1,0) [0|1] "NoUnit" GW_FD4,CDCS_OverSea

BO_ 320 CDCS_Fr03_140: 16 CDCS
 SG_ CDCS3_FailSts : 0|1@0+ (1,0) [0|1] "NoUnit" GW_FD3,ISC,EPS
 SG_ CDCS3_ChargeConnKpTempSw : 3|2@0+ (1,0) [0|3] "NoUnit" PDCS_FD1,GW_FD1,PDCS_HVM_FD1
 SG_ CDCS3_EnergyRecLevelSet : 5|2@0+ (1,0) [0|3] "NoUnit" PDCS_FD1,GW_FD1,PDCS_HVM_FD1
 SG_ CDCS3_ePedalSw : 7|2@0+ (1,0) [0|3] "NoUnit" PDCS_FD1,GW_FD1,PDCS_HVM_FD1
 SG_ CDCS3_StopModeReq : 9|2@0+ (1,0) [0|3] "NoUnit" PDCS_FD1,GW_FD1,PDCS_HVM_FD1
 SG_ CDCS3_ESCOffSw : 11|2@0+ (1,0) [0|3] "NoUnit" PDCS_FD1,IDB,ESC_FD3,ADCU_FD3,EHB_FD3,ADCS_FD3,FLC_ME_FD3,FLC_FD3,GW_FD3,GW_FD1,PDCS_HVM_FD1
 SG_ CDCS3_EPSModeSet : 14|3@0+ (1,0) [0|7] "NoUnit" GW_FD3,EPS
 SG_ CDCS3_RangeModeReq : 17|2@0+ (1,0) [0|3] "NoUnit" PDCS_FD1,GW_FD1,PDCS_HVM_FD1
 SG_ CDCS3_HDCSw : 19|2@0+ (1,0) [0|3] "NoUnit" FLC_ME_FD3,FLC_FD3,IDB,ESC_FD3,GW_FD3,ADCU_FD3,EHB_FD3,ADCS_FD3
 SG_ CDCS3_Refuelrequest : 22|2@0+ (1,0) [0|3] "NoUnit" PDCS_FD1,GW_FD1,PDCS_HVM_FD1
 SG_ CDCS3_CDCModeSet : 26|3@0+ (1,0) [0|7] "NoUnit" GW_FD3,ISC
 SG_ CDCS3_EnginIdingldleSet : 28|2@0+ (1,0) [0|3] "NoUnit" PDCS_FD1,GW_FD1,PDCS_HVM_FD1
 SG_ CDCS3_TractionModeSw : 41|2@0+ (1,0) [0|3] "NoUnit" PDCS_FD1,GW_FD1,PDCS_HVM_FD1
 SG_ CDCS3_AVHSw : 43|2@0+ (1,0) [0|3] "NoUnit" PDCS_FD1,IDB,ESC_FD3,GW_FD3,GW_FD1,EHB_FD3,PDCS_HVM_FD1
 SG_ CDCS3_EPBSw : 45|2@0+ (1,0) [0|3] "NoUnit" PDCS_FD1,IDB,ESC_FD3,GW_FD3,GW_FD1,EHB_FD3,PDCS_HVM_FD1
 SG_ CDCS3_CSTSw : 47|2@0+ (1,0) [0|3] "NoUnit" PDCS_FD1,IDB,ESC_FD3,GW_FD3,GW_FD1,EHB_FD3,PDCS_HVM_FD1
 SG_ CDCS3_DriveModeSet : 50|3@0+ (1,0) [0|7] "NoUnit" PDCS_FD1,IDB,ESC_FD3,ADCU_FD3,EHB_FD3,ADCS_FD3,FLC_ME_FD3,FLC_FD3,GW_FD3,ISC,GW_FD1,PDCS_HVM_FD1
 SG_ CDCS3_BrakestyleSw : 52|2@0+ (1,0) [0|3] "NoUnit" PDCS_FD1,IDB,ESC_FD3,GW_FD3,GW_FD1,EHB_FD3,PDCS_HVM_FD1
 SG_ CDCS3_Force_Refuelrequ : 54|2@0+ (1,0) [0|3] "NoUnit" PDCS_FD1,GW_FD1,PDCS_HVM_FD1
 SG_ CDCS3_EVModeRexOnAllowed : 55|1@0+ (1,0) [0|1] "NoUnit" PDCS_FD1,GW_FD1,PDCS_HVM_FD1
 SG_ CDCS3_PREMModeSet : 60|2@0+ (1,0) [0|3] "NoUnit" PDCS_FD1,GW_FD1,PDCS_HVM_FD1
 SG_ CDCS3_RexModeSet : 63|3@0+ (1,0) [0|7] "NoUnit" PDCS_FD1,GW_FD1,PDCS_HVM_FD1
 SG_ CDCS3_Xcoordinate : 79|16@0+ (1,0) [0|65534] "NoUnit" FLC_ME_FD3,FLC_FD3,GW_FD3,ADCU_FD3,ADCS_FD3
 SG_ CDCS3_Ycoordinate : 95|16@0+ (1,0) [0|65534] "NoUnit" FLC_ME_FD3,FLC_FD3,GW_FD3,ADCU_FD3,ADCS_FD3
 SG_ CDCS3_XGestureSpd : 111|8@0+ (1,0) [0|254] "NoUnit" FLC_ME_FD3,FLC_FD3,GW_FD3,ADCU_FD3,ADCS_FD3
 SG_ CDCS3_YGestureSpd : 119|8@0+ (1,0) [0|254] "NoUnit" FLC_ME_FD3,FLC_FD3,GW_FD3,ADCU_FD3,ADCS_FD3
 SG_ CDCS3_TouchEvtTyp : 123|4@0+ (1,0) [0|15] "NoUnit" FLC_ME_FD3,FLC_FD3,GW_FD3,ADCU_FD3,ADCS_FD3
 SG_ CDCS3_REXchargSet : 125|2@0+ (1,0) [0|3] "NoUnit" PDCS_FD1,GW_FD1,PDCS_HVM_FD1
 SG_ CDCS3_ForceChargingLevelSet : 127|2@0+ (1,0) [0|3] "NoUnit" PDCS_FD1,GW_FD1,PDCS_HVM_FD1

BO_ 442 CDCS_Fr10_1BA: 8 CDCS
 SG_ CDCS10_Slot0_Valid : 0|1@0+ (1,0) [0|1] "NoUnit" AMP
 SG_ CDCS10_Slot0_Volume : 5|5@0+ (1,0) [0|31] "NoUnit" AMP
 SG_ CDCS10_WorK_status : 7|2@0+ (1,0) [0|3] "NoUnit" FLC_ME_FD3,FLC_FD3,AMP,GW_FD3,ADCS_FD3
 SG_ CDCS10_Slot1_Valid : 8|1@0+ (1,0) [0|1] "NoUnit" AMP
 SG_ CDCS10_Slot1_Volume : 13|5@0+ (1,0) [0|31] "NoUnit" AMP
 SG_ CDCS10_Slot2_Valid : 16|1@0+ (1,0) [0|1] "NoUnit" AMP
 SG_ CDCS10_Slot2_Volume : 21|5@0+ (1,0) [0|31] "NoUnit" AMP
 SG_ CDCS10_Slot3_Valid : 24|1@0+ (1,0) [0|1] "NoUnit" AMP
 SG_ CDCS10_Slot3_Volume : 29|5@0+ (1,0) [0|31] "NoUnit" AMP
 SG_ CDCS10_Slot4_Valid : 32|1@0+ (1,0) [0|1] "NoUnit" AMP
 SG_ CDCS10_Slot4_Volume : 37|5@0+ (1,0) [0|31] "NoUnit" AMP
 SG_ CDCS10_Slot5_Valid : 40|1@0+ (1,0) [0|1] "NoUnit" AMP
 SG_ CDCS10_Slot5_Volume : 45|5@0+ (1,0) [0|31] "NoUnit" AMP
 SG_ CDCS10_Slot6_Valid : 48|1@0+ (1,0) [0|1] "NoUnit" AMP
 SG_ CDCS10_Slot6_Volume : 53|5@0+ (1,0) [0|31] "NoUnit" AMP
 SG_ CDCS10_AUD_Engineering_Mode : 55|2@0+ (1,0) [0|3] "NoUnit" AMP
 SG_ CDCS10_Slot7_Valid : 56|1@0+ (1,0) [0|1] "NoUnit" AMP
 SG_ CDCS10_Slot7_Volume : 61|5@0+ (1,0) [0|31] "NoUnit" AMP
 SG_ CDCS10_AUD_Mute : 63|1@0+ (1,0) [0|1] "NoUnit" AMP

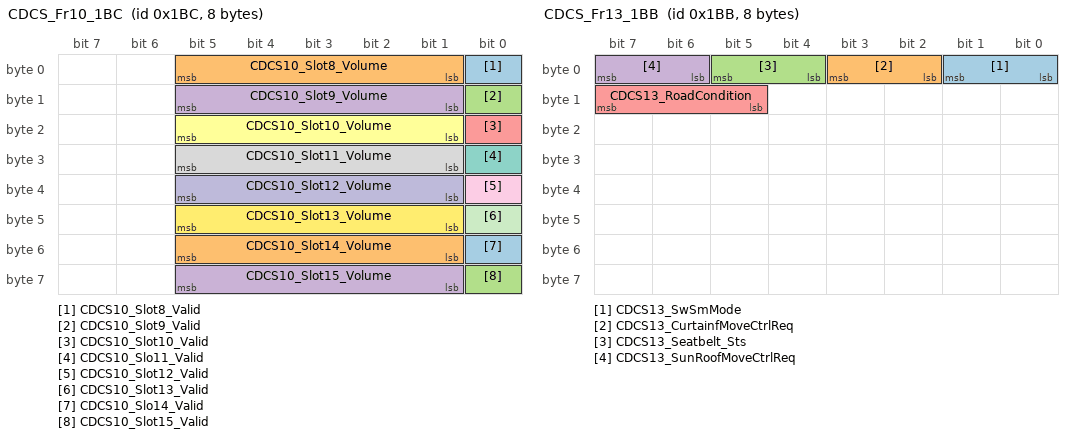
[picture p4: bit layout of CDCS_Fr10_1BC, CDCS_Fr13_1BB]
BO_ 444 CDCS_Fr10_1BC: 8 CDCS
 SG_ CDCS10_Slot8_Valid : 0|1@0+ (1,0) [0|1] "NoUnit" AMP
 SG_ CDCS10_Slot8_Volume : 5|5@0+ (1,0) [0|31] "NoUnit" AMP
 SG_ CDCS10_Slot9_Valid : 8|1@0+ (1,0) [0|1] "NoUnit" AMP
 SG_ CDCS10_Slot9_Volume : 13|5@0+ (1,0) [0|31] "NoUnit" AMP
 SG_ CDCS10_Slot10_Valid : 16|1@0+ (1,0) [0|1] "NoUnit" AMP
 SG_ CDCS10_Slot10_Volume : 21|5@0+ (1,0) [0|31] "NoUnit" AMP
 SG_ CDCS10_Slo11_Valid : 24|1@0+ (1,0) [0|1] "NoUnit" AMP
 SG_ CDCS10_Slot11_Volume : 29|5@0+ (1,0) [0|31] "NoUnit" AMP
 SG_ CDCS10_Slot12_Valid : 32|1@0+ (1,0) [0|1] "NoUnit" AMP
 SG_ CDCS10_Slot12_Volume : 37|5@0+ (1,0) [0|31] "NoUnit" AMP
 SG_ CDCS10_Slot13_Valid : 40|1@0+ (1,0) [0|1] "NoUnit" AMP
 SG_ CDCS10_Slot13_Volume : 45|5@0+ (1,0) [0|31] "NoUnit" AMP
 SG_ CDCS10_Slo14_Valid : 48|1@0+ (1,0) [0|1] "NoUnit" AMP
 SG_ CDCS10_Slot14_Volume : 53|5@0+ (1,0) [0|31] "NoUnit" AMP
 SG_ CDCS10_Slot15_Valid : 56|1@0+ (1,0) [0|1] "NoUnit" AMP
 SG_ CDCS10_Slot15_Volume : 61|5@0+ (1,0) [0|31] "NoUnit" AMP

BO_ 443 CDCS_Fr13_1BB: 8 CDCS
 SG_ CDCS13_SwSmMode : 1|2@0+ (1,0) [0|3] "NoUnit" FLC_ME_FD3,PDCS_FD3,FLC_FD3,PDCU,GW_FD3,ADCU_FD3,GW_FD2,DDCU,ADCS_FD3
 SG_ CDCS13_CurtainfMoveCtrlReq : 3|2@0+ (1,0) [0|3] "NoUnit" GW_FD2,BDCS
 SG_ CDCS13_Seatbelt_Sts : 5|2@0+ (1,0) [0|3] "NoUnit" ICU_E02,ICU
 SG_ CDCS13_SunRoofMoveCtrlReq : 7|2@0+ (1,0) [0|3] "NoUnit" GW_FD2,BDCS
 SG_ CDCS13_RoadCondition : 15|3@0+ (1,0) [0|7] "NoUnit" GW_FD2,BDCS

BO_ 794 CDCS_FR19_31A: 24 CDCS
 SG_ CDCS19_Trip_AfterStart : 7|20@0+ (0.1,0) [0|9999.9] "Km" TBOX,GW_FD5,ICU_E02,ICU,TBOX_OverSea
 SG_ CDCS19_Trip_AfterReset : 19|20@0+ (0.1,0) [0|9999.9] "Km" TBOX,GW_FD5,ICU_E02,ICU,TBOX_OverSea
 SG_ CDCS19_TripEnergyConsump_AfterStart : 47|12@0+ (0.1,0) [0|99.9] "Kwh/100Km" TBOX,GW_FD5,ICU_E02,ICU,TBOX_OverSea
 SG_ CDCS19_TripEnergyConsump_AfterReset : 51|12@0+ (0.1,0) [0|99.9] "Kwh/100Km" TBOX,GW_FD5,ICU_E02,ICU,TBOX_OverSea
 SG_ CDCS19_TripDriveTime_AfterStart : 71|16@0+ (1,0) [0|65535] "min" TBOX,GW_FD5,ICU_E02,ICU,TBOX_OverSea
 SG_ CDCS19_TripDriveTime_AfterReset : 87|16@0+ (1,0) [0|65535] "min" TBOX,GW_FD5,ICU_E02,ICU,TBOX_OverSea
 SG_ CDCS19_AvgSpd_AfterStart : 103|8@0+ (1,0) [0|255] "km/h" TBOX,GW_FD5,ICU_E02,ICU,TBOX_OverSea
 SG_ CDCS19_AvgSpd_AfterReset : 111|8@0+ (1,0) [0|255] "km/h" TBOX,GW_FD5,ICU_E02,ICU,TBOX_OverSea
 SG_ CDCS19_Vehicle_service : 119|2@0+ (1,0) [0|3] "NoUnit" TBOX,GW_FD5,ICU_E02,ICU,TBOX_OverSea
 SG_ CDCS19_TripFuelConsump_AfterStart : 117|12@0+ (0.1,0) [0|99.9] "L/100km" TBOX,GW_FD5,ICU_E02,ICU,TBOX_OverSea
 SG_ CDCS19_TripFuelConsump_AfterReset : 121|12@0+ (0.1,0) [0|99.9] "L/100km" TBOX,GW_FD5,ICU_E02,ICU,TBOX_OverSea

BO_ 466 CDCS_FR07_1D2: 32 CDCS
 SG_ CDCS7_ALHMusicMode_Working : 1|2@0+ (1,0) [0|3] "NoUnit" GW_FD2,BDCS
 SG_ CDCS7_ALH_SW : 4|2@0+ (1,0) [0|3] "NoUnit" GW_FD2,BDCS
 SG_ CDCS7_ALHSelectModeCtrl : 7|3@0+ (1,0) [0|7] "NoUnit" GW_FD2,BDCS
 SG_ CDCS7_ALH_RValueCmd : 15|8@0+ (1,0) [0|255] "NoUnit" GW_FD2,BDCS
 SG_ CDCS7_ALH_GValueCmd : 23|8@0+ (1,0) [0|255] "NoUnit" GW_FD2,BDCS
 SG_ CDCS7_ALH_BValueCmd : 31|8@0+ (1,0) [0|255] "NoUnit" GW_FD2,BDCS
 SG_ CDCS7_ALH_BrightnessCm : 38|7@0+ (1,0) [0|100] "%" GW_FD2,BDCS
 SG_ CDCS7_FL_SeatPositionMemoryPosition : 44|5@0+ (1,0) [0|31] "NoUnit" PDCU,GW_FD2,BDCS,DDCU
 SG_ CDCS7_FL_SeatPositionMemory_Req : 45|1@0+ (1,0) [0|1] "NoUnit" PDCU,GW_FD2,BDCS,DDCU
 SG_ CDCS7_FL_SeatEasygetON_OFF_Set : 47|2@0+ (1,0) [0|3] "NoUnit" GW_FD2,BDCS
 SG_ CDCS7_FR_SeatPositionMemory_Req : 48|1@0+ (1,0) [0|1] "NoUnit" GW_FD2,BDCS
 SG_ CDCS7_FL_SeatPositionLoad_Req : 49|1@0+ (1,0) [0|1] "NoUnit" PDCU,GW_FD2,BDCS,DDCU
 SG_ CDCS7_PositionMemoryUnbind_Req : 50|1@0+ (1,0) [0|1] "NoUnit" PDCU,GW_FD2,DDCU
 SG_ CDCS7_FL_SeatPositionLoadPosition : 55|5@0+ (1,0) [0|31] "NoUnit" PDCU,GW_FD2,BDCS,DDCU
 SG_ CDCS7_PosMemoryUnbindAccount : 60|5@0+ (1,0) [0|31] "NoUnit" PDCU,GW_FD2,DDCU
 SG_ CDCS7_PositionMode : 63|3@0+ (1,0) [0|7] "NoUnit" PDCU,GW_FD2,DDCU
 SG_ CDCS7_InteriorLightingReq : 65|2@0+ (1,0) [0|3] "NoUnit" PDCU,GW_FD2,BDCS,DDCU
 SG_ CDCS7_DGSW : 67|2@0+ (1,0) [0|3] "NoUnit" PDCU,GW_FD2,DDCU
 SG_ CDCS7_FR_SeatPositionMemoryPosition : 70|3@0+ (1,0) [0|7] "NoUnit" PDCU,GW_FD2,BDCS,DDCU
 SG_ CDCS7_FR_SeatPositionLoad_Req : 71|1@0+ (1,0) [0|1] "NoUnit" GW_FD2,BDCS
 SG_ CDCS7_DGSWLevel : 76|5@0+ (1,0) [0|31] "NoUnit" GW_FD2,BDCS
 SG_ CDCS7_Driver_MassageModeSet : 79|3@0+ (1,0) [0|7] "NoUnit" GW_FD2,BDCS
 SG_ CDCS7_ALH_EntryMode : 81|2@0+ (1,0) [0|3] "NoUnit" GW_FD2,BDCS
 SG_ CDCS7_Passenger_MassageModeSet : 84|3@0+ (1,0) [0|7] "NoUnit" GW_FD2,BDCS
 SG_ CDCS7_Driver_MassageLevelSet : 87|3@0+ (1,0) [0|7] "NoUnit" GW_FD2,BDCS
 SG_ CDCS7_ALH_AEBMode : 89|2@0+ (1,0) [0|3] "NoUnit" GW_FD2,BDCS
 SG_ CDCS7_FR_SeatPositionLoadPosition : 92|3@0+ (1,0) [0|7] "NoUnit" GW_FD2,BDCS
 SG_ CDCS7_Passenger_MassageLevelSet : 95|3@0+ (1,0) [0|7] "NoUnit" GW_FD2,BDCS
 SG_ CDCS7_FragranceCtrlReq : 97|2@0+ (1,0) [0|3] "NoUnit" GW_FD2,BDCS
 SG_ CDCS7_FragranceConcentrationSet : 99|2@0+ (1,0) [0|3] "NoUnit" GW_FD2,BDCS
 SG_ CDCS7_FragrancePositionSet : 103|4@0+ (1,0) [0|15] "NoUnit" GW_FD2,BDCS
 SG_ CDCS7_LHTemp : 111|8@0+ (1,0) [0|255] "" GW_FD2,BDCS
 SG_ CDCS7_RHTemp : 119|8@0+ (1,0) [0|255] "" GW_FD2,BDCS
 SG_ CDCS7_BlowerSpdSet : 123|4@0+ (1,0) [0|15] "NoUnit" GW_FD2,BDCS
 SG_ CDCS7_HeatMaxSW : 125|2@0+ (1,0) [0|3] "NoUnit" GW_FD2,BDCS
 SG_ CDCS7_FaceFootSW : 127|2@0+ (1,0) [0|3] "NoUnit" GW_FD2,BDCS
 SG_ CDCS7_FaceWinSW : 129|2@0+ (1,0) [0|3] "NoUnit" GW_FD2,BDCS
 SG_ CDCS7_FootWinSW : 131|2@0+ (1,0) [0|3] "NoUnit" GW_FD2,BDCS
 SG_ CDCS7_FaceFootWinSW : 133|2@0+ (1,0) [0|3] "NoUnit" GW_FD2,BDCS
 SG_ CDCS7_FR_SeatEasygetON_OFF_Set : 135|2@0+ (1,0) [0|3] "NoUnit" GW_FD2,BDCS
 SG_ CDCS7_Fragrance_Position_1 : 139|4@0+ (1,0) [0|15] "NoUnit" GW_FD2,BDCS
 SG_ CDCS7_Fragrance_Position_2 : 143|4@0+ (1,0) [0|15] "NoUnit" GW_FD2,BDCS
 SG_ CDCS7_Fragrance_Position_3 : 147|4@0+ (1,0) [0|15] "NoUnit" GW_FD2,BDCS
 SG_ CDCS7_ALH_DriveModeSW : 149|2@0+ (1,0) [0|3] "NoUnit" GW_FD2,BDCS
 SG_ CDCS7_FRSeatVoiceEZEReq : 151|2@0+ (1,0) [0|3] "NoUnit" GW_FD2,BDCS
 SG_ CDCS7_FL_RLMotorPosCmd : 159|8@0+ (1,0) [0|135] "NoUnit" GW_FD2,BDCS
 SG_ CDCS7_FL_UDMotorPosCmd : 167|8@0+ (1,0) [0|90] "NoUnit" GW_FD2,BDCS
 SG_ CDCS7_CL_RLMotorPosCmd : 175|8@0+ (1,0) [0|135] "NoUnit" GW_FD2,BDCS
 SG_ CDCS7_CL_UDMotorPosCmd : 183|8@0+ (1,0) [0|90] "NoUnit" GW_FD2,BDCS
 SG_ CDCS7_CR_RLMotorPosCmd : 191|8@0+ (1,0) [0|135] "NoUnit" GW_FD2,BDCS
 SG_ CDCS7_CR_UDMotorPosCmd : 199|8@0+ (1,0) [0|90] "NoUnit" GW_FD2,BDCS
 SG_ CDCS7_FR_RLMotorPosCmd : 207|8@0+ (1,0) [0|135] "NoUnit" GW_FD2,BDCS
 SG_ CDCS7_FR_UDMotorPosCmd : 215|8@0+ (1,0) [0|90] "NoUnit" GW_FD2,BDCS
 SG_ CDCS7_AQSValue : 218|3@0+ (1,0) [0|7] "NoUnit" GW_FD2,BDCS
 SG_ CDCS7_BlowModStsReq : 222|4@0+ (1,0) [0|15] "NoUnit" GW_FD2,BDCS
 SG_ CDCS7_FR_ZeroGravityPause_Req : 223|1@0+ (1,0) [0|1] "NoUnit" GW_FD2,BDCS
 SG_ CDCS7_ALHSelectColourCtrl : 227|2@0+ (1,0) [0|3] "NoUnit" GW_FD2,BDCS
 SG_ CDCS7_PMAirInQLevel : 231|3@0+ (1,0) [0|7] "NoUnit" GW_FD2,BDCS
 SG_ CDCS7_PM25_Value : 225|10@0+ (1,0) [0|999] "ug/m3" GW_FD2,BDCS
 SG_ CDCS7_FLSeatVoiceHorizontalAdj : 241|2@0+ (1,0) [0|3] "NoUnit" GW_FD2,BDCS
 SG_ CDCS7_FLSeatVoiceVerticalAdj : 243|2@0+ (1,0) [0|3] "NoUnit" GW_FD2,BDCS
 SG_ CDCS7_FLSeatVoiceCushionTiltAdj : 245|2@0+ (1,0) [0|3] "NoUnit" GW_FD2,BDCS
 SG_ CDCS7_FLSeatVoiceBackrestAngletAdj : 247|2@0+ (1,0) [0|3] "NoUnit" GW_FD2,BDCS
 SG_ CDCS7_FRSeatVoiceHorizontalAdj : 249|2@0+ (1,0) [0|3] "NoUnit" GW_FD2,BDCS
 SG_ CDCS7_FRSeatVoiceVerticalAdj : 251|2@0+ (1,0) [0|3] "NoUnit" GW_FD2,BDCS
 SG_ CDCS7_FRSeatLegsupporVoiceAdj : 253|2@0+ (1,0) [0|3] "NoUnit" GW_FD2,BDCS
 SG_ CDCS7_FRSeatVoiceBackrestAngletAdj : 255|2@0+ (1,0) [0|3] "NoUnit" GW_FD2,BDCS

BO_ 468 CDCS_FR05_1D4: 32 CDCS
 SG_ CDCS5_ResetAllSetup : 0|1@0+ (1,0) [0|1] "NoUnit" PDCS_FD1,PDCU,IDB,ESC_FD3,WPC,EHB_FD3,CDU,ICU_E02,ISC,AMP,SRR3,SRR4,BMS,BDCS,DDCU,BAM,ADCS_FD3,TBOX,FLC_ME_FD3,ACU,FLC_FD3,GW_FD5,GW_FD6,GW_FD3,GW_FD1,ICU,GW_FD2,PDCS_HVM_FD1,TBOX_OverSea
 SG_ CDCS5_FactoryReset : 1|1@0+ (1,0) [0|1] "NoUnit" PDCS_FD1,PDCU,IDB,ESC_FD3,WPC,EHB_FD3,CDU,ICU_E02,ISC,AMP,SRR3,SRR4,BMS,BDCS,DDCU,BAM,ADCS_FD3,TBOX,FLC_ME_FD3,ACU,FLC_FD3,GW_FD5,GW_FD6,GW_FD3,GW_FD1,ICU,GW_FD2,PDCS_HVM_FD1,TBOX_OverSea
 SG_ CDCS5_RightMirrorAutoTurnDownSw : 4|2@0+ (1,0) [0|3] "NoUnit" PDCU,GW_FD2
 SG_ CDCS5_Key_Ventilation_Set : 6|2@0+ (1,0) [0|3] "NoUnit" PDCU,GW_FD2,BDCS,DDCU
 SG_ CDCS5_AutoDfrostSw : 9|2@0+ (1,0) [0|3] "NoUnit" GW_FD2,BDCS
 SG_ CDCS5_AutoDrySw : 11|2@0+ (1,0) [0|3] "NoUnit" GW_FD2,BDCS
 SG_ CDCS5_ChargingLampSwt : 13|2@0+ (1,0) [0|3] "NoUnit" GW_FD2,BDCS
 SG_ CDCS5_MirrorFoldSet : 15|2@0+ (1,0) [0|3] "NoUnit" GW_FD2,DDCU
 SG_ CDCS5_StationaryModeSet : 17|2@0+ (1,0) [0|3] "NoUnit" GW_FD2,BDCS
 SG_ CDCS5_LightShowWinDown : 19|2@0+ (1,0) [0|3] "NoUnit" GW_FD2,BDCS
 SG_ CDCS_BtmCallAutoSpdSw : 21|2@0+ (1,0) [0|3] "NoUnit" GW_FD2,BDCS
 SG_ CDCS5_AutoAionSw : 23|2@0+ (1,0) [0|3] "NoUnit" GW_FD2,BDCS
 SG_ CDCS5_AQSConfigSw : 25|2@0+ (1,0) [0|3] "" GW_FD2,BDCS
 SG_ CDCS5_CenterLock : 27|2@0+ (1,0) [0|3] "NoUnit" PDCU,CDU,GW_FD1,GW_FD2,BDCS
 SG_ CDCS5_WindowSteam_SET : 29|2@0+ (1,0) [0|3] "NoUnit" PDCU,GW_FD2,DDCU
 SG_ CDCS5_CoolantFillingReq : 31|2@0+ (1,0) [0|3] "NoUnit" PDCS_FD1,GW_FD1,GW_FD2,BDCS,PDCS_HVM_FD1
 SG_ CDCS5_OutLampControl : 34|3@0+ (1,0) [0|7] "NoUnit" GW_FD2,BDCS
 SG_ CDCS5_FMHTimeSet : 37|3@0+ (1,0) [0|7] "NoUnit" GW_FD2,BDCS
 SG_ CDCS5_BiologicalDetectionSw : 39|2@0+ (1,0) [0|3] "NoUnit" GW_FD2,BDCS
 SG_ CDCS5_BDCS_ReclockReqFdb : 40|1@0+ (1,0) [0|1] "NoUnit" GW_FD2,BDCS
 SG_ CDCS5_ShutDownReq : 42|1@0+ (1,0) [0|1] "NoUnit" GW_FD2,BDCS
 SG_ CDCS5_FindMyCarTimeSet : 46|3@0+ (1,0) [0|7] "NoUnit" GW_FD2,BDCS
 SG_ CDCS5_BacklightLevel : 51|4@0+ (1,0) [0|15] "NoUnit" PDCU,ICU_E02,ICU,GW_FD2,BDCS,DDCU
 SG_ CDCS5_PetToLookAfterReq : 53|2@0+ (1,0) [0|3] "NoUnit" GW_FD2,BDCS
 SG_ CDCS5_ChargeLidSw : 55|2@0+ (1,0) [0|3] "NoUnit" PDCU,GW_FD2
 SG_ CDCS5_SpeedLockReq : 59|2@0+ (1,0) [0|3] "NoUnit" GW_FD2,BDCS
 SG_ CDCS5_Wiper_maintenancePos_Req : 61|2@0+ (1,0) [0|3] "NoUnit" GW_FD2,BDCS
 SG_ CDCS5_FindMyCarSet : 63|2@0+ (1,0) [0|3] "NoUnit" GW_FD2,BDCS
 SG_ CDCS5_WelcomeLampMod : 67|4@0+ (1,0) [0|15] "NoUnit" GW_FD2,BDCS
 SG_ CDCS5_AntiTheftRemanderSoundReq : 69|2@0+ (1,0) [0|3] "NoUnit" GW_FD2,BDCS
 SG_ CDCS5_LightShowMod : 76|5@0+ (1,0) [0|31] "NoUnit" GW_FD2,BDCS
 SG_ CDCS5_FLHEALamp_Height : 79|3@0+ (1,0) [0|7] "NoUnit" GW_FD2,BDCS
 SG_ CDCS5_PARKUnLockReq : 81|2@0+ (1,0) [0|3] "NoUnit" GW_FD2,BDCS
 SG_ CDCS5_LOGOLampSwt : 83|2@0+ (1,0) [0|3] "NoUnit" GW_FD2,BDCS
 SG_ CDCS5_AUTOHOLDLampSwt : 85|2@0+ (1,0) [0|3] "NoUnit" GW_FD2,BDCS
 SG_ CDCS5_ElectronicLock_Pre_theft : 87|2@0+ (1,0) [0|3] "NoUnit" CDU,GW_FD1
 SG_ CDCS5_LockUpWindowSET : 89|2@0+ (1,0) [0|3] "NoUnit" GW_FD2,BDCS
 SG_ CDCS5_MirrorFoldSw : 91|2@0+ (1,0) [0|3] "NoUnit" GW_FD2,DDCU
 SG_ CDCS5_RL_SafetyLockSw : 93|2@0+ (1,0) [0|3] "NoUnit" GW_FD2,DDCU
 SG_ CDCS5_RR_SafetyLockSw : 95|2@0+ (1,0) [0|3] "NoUnit" PDCU,GW_FD2
 SG_ CDCS5_RearFogLampSWt : 97|2@0+ (1,0) [0|3] "NoUnit" GW_FD2,BDCS
 SG_ CDCS5_WalkMeeting_SW : 99|2@0+ (1,0) [0|3] "NoUnit" TBOX,GW_FD5,GW_FD2,BDCS,TBOX_OverSea
 SG_ CDCS5_Induction_PLG_SW : 101|2@0+ (1,0) [0|3] "NoUnit" TBOX,GW_FD5,TBOX_OverSea
 SG_ CDCS5_Wal_Away_Up_SW : 103|2@0+ (1,0) [0|3] "NoUnit" TBOX,GW_FD5,GW_FD2,BDCS,TBOX_OverSea
 SG_ CDCS5_HighPressureTankUnlockSW : 105|2@0+ (1,0) [0|3] "NoUnit" PDCS_FD1,TBOX,GW_FD5,GW_FD1,PDCS_HVM_FD1,TBOX_OverSea
 SG_ CDCS5_ControlFLWindow : 118|7@0+ (1,0) [0|100] "%" GW_FD2,DDCU
 SG_ CDCS5_ControlRLWindow : 126|7@0+ (1,0) [0|100] "%" GW_FD2,DDCU
 SG_ CDCS5_ControlFRWindow : 134|7@0+ (1,0) [0|100] "%" PDCU,GW_FD2
 SG_ CDCS5_ControlRRWindow : 142|7@0+ (1,0) [0|100] "%" PDCU,GW_FD2
 SG_ CDCS5_RLSeatBackrestAdjCmd : 145|2@0+ (1,0) [0|3] "NoUnit" GW_FD2,BDCS
 SG_ CDCS5_RRSeatBackrestAdjCmd : 147|2@0+ (1,0) [0|3] "NoUnit" GW_FD2,BDCS
 SG_ CDCS5_LSD_FL_Away_Up_SW : 149|2@0+ (1,0) [0|3] "NoUnit" GW_FD2,BDCS
 SG_ CDCS5_LSD_FR_Away_Up_SW : 151|2@0+ (1,0) [0|3] "NoUnit" GW_FD2,BDCS
 SG_ CDCS5_LRSeatHeaterCmd : 154|3@0+ (1,0) [0|7] "NoUnit" GW_FD2,BDCS
 SG_ CDCS5_RRSeatHeaterCmd : 157|3@0+ (1,0) [0|7] "NoUnit" GW_FD2,BDCS
 SG_ CDCS5_DGM_IntelligentProtectionSW : 159|2@0+ (1,0) [0|3] "NoUnit" GW_FD2,BDCS
 SG_ CDCS5_DGM_AutoSW : 161|2@0+ (1,0) [0|3] "NoUnit" GW_FD2,BDCS
 SG_ CDCS5_FrontDoorOpenModeSet : 163|2@0+ (1,0) [0|3] "NoUnit" GW_FD2,BDCS
 SG_ CDCS5_CabinCleanConfigSW : 165|2@0+ (1,0) [0|3] "NoUnit" GW_FD2,BDCS
 SG_ CDCS5_PM25AutoCleanPopup : 167|2@0+ (1,0) [0|3] "NoUnit" GW_FD2,BDCS
 SG_ CDCS5_WindowFollowUpDoorSW : 175|2@0+ (1,0) [0|3] "NoUnit" PDCU,GW_FD2,DDCU
 SG_ CDCS5_DoorHandleRetractedOverTimeSW : 178|3@0+ (1,0) [0|7] "NoUnit" PDCU,GW_FD2,DDCU
 SG_ CDCS5_LeftMirrorAutoTurnDownSw : 181|2@0+ (1,0) [0|3] "NoUnit" GW_FD2,DDCU
 SG_ CDCS5_PAB_OnOffSet : 183|2@0+ (1,0) [0|3] "NoUnit" ACU,GW_FD1
 SG_ CDCS5_SunRoofCtrlReq : 186|3@0+ (1,0) [0|7] "NoUnit" GW_FD2,BDCS
 SG_ CDCS5_SunRoofSLideCtrlReq : 191|5@0+ (1,0) [0|31] "NoUnit" GW_FD2,BDCS
 SG_ CDCS5_CurtainCtrlReq : 193|2@0+ (1,0) [0|3] "NoUnit" GW_FD2,BDCS
 SG_ CDCS5_CurtainSLideCtrlReq : 199|5@0+ (1,0) [0|31] "NoUnit" GW_FD2,BDCS
 SG_ CDCS5_SunRoofStopCtrlReq : 201|2@0+ (1,0) [0|3] "NoUnit" GW_FD2,BDCS
 SG_ CDCS5_CarTempHoldModeSw : 203|2@0+ (1,0) [0|3] "NoUnit" GW_FD2,BDCS
 SG_ CDCS5_SmartLightReq : 205|2@0+ (1,0) [0|3] "NoUnit" GW_FD2,BDCS
 SG_ CDCS5_NapPositionReset : 208|1@0+ (1,0) [0|1] "NoUnit" GW_FD2,BDCS
 SG_ CDCS5_PLG_DoorHeightSet : 215|7@0+ (1,0) [0|100] "%" GW_FD2,BDCS
 SG_ CDCS5_RLLumbarUpAndDwnAdioAdj : 218|2@0+ (1,0) [0|3] "NoUnit" GW_FD2,BDCS
 SG_ CDCS5_RoadRecSw : 220|2@0+ (1,0) [0|3] "NoUnit" GW_FD2,BDCS
 SG_ CDCS5_TrailerModeSw : 225|2@0+ (1,0) [0|3] "NoUnit" GW_FD2,BDCS
 SG_ CDCS5_RR_MassageModeSet : 228|3@0+ (1,0) [0|7] "NoUnit" GW_FD2,BDCS
 SG_ CDCS5_RR_MassageLevelSet : 231|3@0+ (1,0) [0|7] "NoUnit" GW_FD2,BDCS
 SG_ CDCS5_ZeroGravityPositionReset : 233|2@0+ (1,0) [0|3] "NoUnit" GW_FD2,BDCS
 SG_ CDCS5_RL_MassageModeSet : 236|3@0+ (1,0) [0|7] "NoUnit" GW_FD2,BDCS
 SG_ CDCS5_RL_MassageLevelSet : 239|3@0+ (1,0) [0|7] "NoUnit" GW_FD2,BDCS
 SG_ CDCS5_RL_SeatVentCmd : 244|3@0+ (1,0) [0|7] "NoUnit" GW_FD2,BDCS
 SG_ CDCS5_RR_SeatVentCmd : 247|3@0+ (1,0) [0|7] "NoUnit" GW_FD2,BDCS
 SG_ CDCS5_RLLumbarFwdBakwdAdioAdj : 249|2@0+ (1,0) [0|3] "NoUnit" GW_FD2,BDCS
 SG_ CDCS5_RRLumbarUpAndDwnAdioAdj : 251|2@0+ (1,0) [0|3] "NoUnit" GW_FD2,BDCS
 SG_ CDCS5_RRLumbarFwdBakwdAdioAdj : 253|2@0+ (1,0) [0|3] "NoUnit" GW_FD2,BDCS
 SG_ CDCS5_WiperNozzleHeatSWt : 255|2@0+ (1,0) [0|3] "NoUnit" GW_FD2,BDCS

BO_ 501 CDCS_Fr11_1F5: 64 CDCS
 SG_ CDCS11_LKSSetspeed : 7|8@0+ (1,0) [0|255] "Km/h" TBOX,FLC_ME_FD3,FLC_FD3,GW_FD5,GW_FD3,ADCU_FD3,ADCS_FD3,TBOX_OverSea
 SG_ CDCS11_LDW_OnOffSet : 9|2@0+ (1,0) [0|3] "NoUnit" TBOX,FLC_ME_FD3,FLC_FD3,GW_FD5,GW_FD3,ADCU_FD3,ADCS_FD3,TBOX_OverSea
 SG_ CDCS11_LowSpeedBSDSw : 11|2@0+ (1,0) [0|3] "NoUnit" TBOX,FLC_ME_FD3,FLC_FD3,GW_FD5,GW_FD3,ADCU_FD3,ADCS_FD3,TBOX_OverSea
 SG_ CDCS11_FCW_OnOffSet : 13|2@0+ (1,0) [0|3] "NoUnit" TBOX,FLC_ME_FD3,FLC_FD3,GW_FD5,GW_FD3,ADCU_FD3,ADCS_FD3,TBOX_OverSea
 SG_ CDCS11_AEB_OnOffSet : 15|2@0+ (1,0) [0|3] "NoUnit" TBOX,FLC_ME_FD3,FLC_FD3,GW_FD5,GW_FD3,ADCU_FD3,ADCS_FD3,TBOX_OverSea
 SG_ CDCS11_FCW_WarnTiming : 17|2@0+ (1,0) [0|3] "NoUnit" TBOX,FLC_ME_FD3,FLC_FD3,GW_FD5,GW_FD3,ADCU_FD3,ADCS_FD3,TBOX_OverSea
 SG_ CDCS11_FCTA_OnOffSet : 19|2@0+ (1,0) [0|3] "NoUnit" SRR3,SRR4,ADCU_FD3,ADCS_FD3,TBOX,FLC_ME_FD3,FLC_FD3,GW_FD5,GW_FD6,GW_FD3,TBOX_OverSea
 SG_ CDCS11_RCTA_OnOffSet : 21|2@0+ (1,0) [0|3] "NoUnit" SRR3,SRR4,ADCU_FD3,ADCS_FD3,TBOX,FLC_ME_FD3,FLC_FD3,GW_FD5,GW_FD6,GW_FD3,TBOX_OverSea
 SG_ CDCS11_RCW_OnOffSet : 23|2@0+ (1,0) [0|3] "NoUnit" SRR3,SRR4,ADCU_FD3,ADCS_FD3,TBOX,FLC_ME_FD3,FLC_FD3,GW_FD5,GW_FD6,GW_FD3,TBOX_OverSea
 SG_ CDCS11_DOW_OnOffSet : 25|2@0+ (1,0) [0|3] "NoUnit" SRR3,SRR4,ADCU_FD3,ADCS_FD3,TBOX,FLC_ME_FD3,FLC_FD3,GW_FD5,GW_FD6,GW_FD3,TBOX_OverSea
 SG_ CDCS11_IHBC_SysSwState : 27|2@0+ (1,0) [0|3] "NoUnit" TBOX,FLC_ME_FD3,FLC_FD3,GW_FD5,GW_FD3,ADCU_FD3,ADCS_FD3,TBOX_OverSea
 SG_ CDCS11_LCA_OnOffSet : 29|2@0+ (1,0) [0|3] "NoUnit" SRR3,SRR4,ADCU_FD3,ADCS_FD3,TBOX,FLC_ME_FD3,FLC_FD3,GW_FD5,GW_FD6,GW_FD3,TBOX_OverSea
 SG_ CDCS11_TSR_OnOffSet : 31|2@0+ (1,0) [0|3] "NoUnit" TBOX,FLC_ME_FD3,FLC_FD3,GW_FD5,GW_FD3,ADCU_FD3,ADCS_FD3,TBOX_OverSea
 SG_ CDCS11_AVM_3DRotate : 33|2@0+ (1,0) [0|3] "NoUnit" TBOX,FLC_ME_FD3,FLC_FD3,GW_FD5,GW_FD3,ADCU_FD3,ADCS_FD3,TBOX_OverSea
 SG_ CDCS11_AVM_Turnlightstart : 35|2@0+ (1,0) [0|3] "NoUnit" TBOX,FLC_ME_FD3,FLC_FD3,GW_FD5,GW_FD3,ADCU_FD3,ADCS_FD3,TBOX_OverSea
 SG_ CDCS11_AVM_Steeringstart : 37|2@0+ (1,0) [0|3] "NoUnit" TBOX,FLC_ME_FD3,FLC_FD3,GW_FD5,GW_FD3,ADCU_FD3,ADCS_FD3,TBOX_OverSea
 SG_ CDCS11_AVM_Magnifiedview : 39|2@0+ (1,0) [0|3] "NoUnit" TBOX,FLC_ME_FD3,FLC_FD3,GW_FD5,GW_FD3,ADCU_FD3,ADCS_FD3,TBOX_OverSea
 SG_ CDCS11_AVM_MODdetection : 43|2@0+ (1,0) [0|3] "NoUnit" TBOX,FLC_ME_FD3,FLC_FD3,GW_FD5,GW_FD3,ADCU_FD3,ADCS_FD3,TBOX_OverSea
 SG_ CDCS11_GM_OnOffSet : 45|2@0+ (1,0) [0|3] "NoUnit" TBOX,FLC_ME_FD3,FLC_FD3,GW_FD5,GW_FD3,ADCU_FD3,ADCS_FD3,TBOX_OverSea
 SG_ CDCS11_NNP_OnOffSet : 47|2@0+ (1,0) [0|3] "NoUnit" TBOX,FLC_ME_FD3,FLC_FD3,GW_FD5,GW_FD3,ADCU_FD3,ADCS_FD3,TBOX_OverSea
 SG_ CDCS11_DCLCSysState : 49|2@0+ (1,0) [0|3] "NoUnit" TBOX,FLC_ME_FD3,FLC_FD3,GW_FD5,GW_FD3,ADCU_FD3,ADCS_FD3,TBOX_OverSea
 SG_ CDCS11_ALCSysState : 51|2@0+ (1,0) [0|3] "NoUnit" TBOX,FLC_ME_FD3,FLC_FD3,GW_FD5,GW_FD3,ADCU_FD3,ADCS_FD3,TBOX_OverSea
 SG_ CDCS11_DriveOffPossilbeswitch : 53|2@0+ (1,0) [0|3] "NoUnit" TBOX,FLC_ME_FD3,FLC_FD3,GW_FD5,GW_FD3,ADCU_FD3,ADCS_FD3,TBOX_OverSea
 SG_ CDCS11_DriveOffinhibitionswitch : 55|2@0+ (1,0) [0|3] "NoUnit" TBOX,FLC_ME_FD3,FLC_FD3,GW_FD5,GW_FD3,ADCU_FD3,ADCS_FD3,TBOX_OverSea
 SG_ CDCS11_ADAS_SndCtrlOnOff : 57|2@0+ (1,0) [0|3] "NoUnit" TBOX,FLC_ME_FD3,FLC_FD3,GW_FD5,GW_FD3,ADCU_FD3,ADCS_FD3,TBOX_OverSea
 SG_ CDCS11_AVM_auxiliaryline : 59|2@0+ (1,0) [0|3] "NoUnit" TBOX,FLC_ME_FD3,FLC_FD3,GW_FD5,GW_FD3,ADCU_FD3,ADCS_FD3,TBOX_OverSea
 SG_ CDCS11_AVM_Raderdisplay : 61|2@0+ (1,0) [0|3] "NoUnit" TBOX,FLC_ME_FD3,FLC_FD3,GW_FD5,GW_FD3,ADCU_FD3,ADCS_FD3,TBOX_OverSea
 SG_ CDCS11_AVM_Transparentchassis : 63|2@0+ (1,0) [0|3] "NoUnit" TBOX,FLC_ME_FD3,FLC_FD3,GW_FD5,GW_FD3,ADCU_FD3,ADCS_FD3,TBOX_OverSea
 SG_ CDCS11_VoiceMode : 65|2@0+ (1,0) [0|3] "NoUnit" TBOX,FLC_ME_FD3,FLC_FD3,GW_FD5,GW_FD3,ADCU_FD3,ADCS_FD3,TBOX_OverSea
 SG_ CDCS11_NNP_Active_OnOffSet : 67|2@0+ (1,0) [0|3] "NoUnit" TBOX,FLC_ME_FD3,FLC_FD3,GW_FD5,GW_FD3,ADCU_FD3,ADCS_FD3,TBOX_OverSea
 SG_ CDCS11_ALC_mode : 69|2@0+ (1,0) [0|3] "NoUnit" TBOX,FLC_ME_FD3,FLC_FD3,GW_FD5,GW_FD3,ADCU_FD3,ADCS_FD3,TBOX_OverSea
 SG_ CDCS11_ADSDriving_mode : 71|2@0+ (1,0) [0|3] "NoUnit" TBOX,FLC_ME_FD3,FLC_FD3,GW_FD5,GW_FD3,ADCU_FD3,ADCS_FD3,TBOX_OverSea
 SG_ CDCS11_TSR_OverspeedOnoffSet : 73|2@0+ (1,0) [0|3] "NoUnit" TBOX,FLC_ME_FD3,FLC_FD3,GW_FD5,GW_FD3,ADCU_FD3,ADCS_FD3,TBOX_OverSea
 SG_ CDCS11_NNP_AutoOnOffSet : 75|2@0+ (1,0) [0|3] "NoUnit" TBOX,FLC_ME_FD3,FLC_FD3,GW_FD5,GW_FD3,ADCU_FD3,ADCS_FD3,TBOX_OverSea
 SG_ CDCS11_SnCtrl_NNP_OnOff : 77|2@0+ (1,0) [0|3] "NoUnit" TBOX,FLC_ME_FD3,FLC_FD3,GW_FD5,GW_FD3,ADCU_FD3,ADCS_FD3,TBOX_OverSea
 SG_ CDCS11_GM_VidedIn : 79|2@0+ (1,0) [0|3] "NoUnit" TBOX,FLC_ME_FD3,FLC_FD3,GW_FD5,GW_FD3,ADCU_FD3,ADCS_FD3,TBOX_OverSea
 SG_ CDCS11_TSR_SLFOnOffSet : 81|2@0+ (1,0) [0|3] "NoUnit" TBOX,FLC_ME_FD3,FLC_FD3,GW_FD5,GW_FD3,ADCU_FD3,ADCS_FD3,TBOX_OverSea
 SG_ CDCS11_APA_FunctionMode : 85|4@0+ (1,0) [0|15] "NoUnit" TBOX,FLC_ME_FD3,FLC_FD3,GW_FD5,GW_FD3,ADCU_FD3,ADCS_FD3,TBOX_OverSea
 SG_ CDCS11_TrackreverseSW : 87|2@0+ (1,0) [0|3] "NoUnit" TBOX,FLC_ME_FD3,FLC_FD3,GW_FD5,GW_FD3,ADCU_FD3,ADCS_FD3,TBOX_OverSea
 SG_ CDCS11_SetPathwaySW : 89|2@0+ (1,0) [0|3] "NoUnit" TBOX,FLC_ME_FD3,FLC_FD3,GW_FD5,GW_FD3,ADCU_FD3,ADCS_FD3,TBOX_OverSea
 SG_ CDCS11_PA_changeLanguage : 91|2@0+ (1,0) [0|3] "NoUnit" TBOX,FLC_ME_FD3,FLC_FD3,GW_FD5,GW_FD3,ADCU_FD3,ADCS_FD3,TBOX_OverSea
 SG_ CDCS11_LDP_OnOffSet : 93|2@0+ (1,0) [0|3] "NoUnit" TBOX,FLC_ME_FD3,FLC_FD3,GW_FD5,GW_FD3,ADCU_FD3,ADCS_FD3,TBOX_OverSea
 SG_ CDCS11_AVMSw : 95|2@0+ (1,0) [0|3] "NoUnit" TBOX,FLC_ME_FD3,FLC_FD3,GW_FD5,GW_FD3,ADCU_FD3,ADCS_FD3,TBOX_OverSea
 SG_ CDCS11_tryHPP : 96|1@0+ (1,0) [0|1] "NoUnit" TBOX,FLC_ME_FD3,FLC_FD3,GW_FD5,GW_FD3,ADCU_FD3,ADCS_FD3,TBOX_OverSea
 SG_ CDCS11_NetReset : 97|1@0+ (1,0) [0|1] "NoUnit" TBOX,GW_FD5,TBOX_OverSea
 SG_ CDCS11_RPASw : 99|2@0+ (1,0) [0|3] "NoUnit" TBOX,FLC_ME_FD3,FLC_FD3,GW_FD5,GW_FD3,ADCU_FD3,ADCS_FD3,TBOX_OverSea
 SG_ CDCS11_SetSw : 100|1@0+ (1,0) [0|1] "NoUnit" TBOX,FLC_ME_FD3,FLC_FD3,GW_FD5,GW_FD3,ADCU_FD3,ADCS_FD3,TBOX_OverSea
 SG_ CDCS11_SoundCtrlSetReq : 103|3@0+ (1,0) [0|7] "NoUnit" TBOX,FLC_ME_FD3,FLC_FD3,GW_FD5,GW_FD3,ADCU_FD3,ADCS_FD3,TBOX_OverSea
 SG_ CDCS11_location_sw : 104|1@0+ (1,0) [0|1] "NoUnit" TBOX,FLC_ME_FD3,FLC_FD3,GW_FD5,GW_FD3,ADCU_FD3,ADCS_FD3,TBOX_OverSea
 SG_ CDCS11_Pathrefresh : 105|1@0+ (1,0) [0|1] "NoUnit" TBOX,FLC_ME_FD3,FLC_FD3,GW_FD5,GW_FD3,ADCU_FD3,ADCS_FD3,TBOX_OverSea
 SG_ CDCS11_HPAGuideSW : 107|2@0+ (1,0) [0|3] "NoUnit" TBOX,FLC_ME_FD3,FLC_FD3,GW_FD5,GW_FD3,ADCU_FD3,ADCS_FD3,TBOX_OverSea
 SG_ CDCS11_HPAPathwaytoCloudSW : 109|2@0+ (1,0) [0|3] "NoUnit" TBOX,FLC_ME_FD3,FLC_FD3,GW_FD5,GW_FD3,ADCU_FD3,ADCS_FD3,TBOX_OverSea
 SG_ CDCS11_PathlearningSw : 111|2@0+ (1,0) [0|3] "NoUnit" TBOX,FLC_ME_FD3,FLC_FD3,GW_FD5,GW_FD3,ADCU_FD3,ADCS_FD3,TBOX_OverSea
 SG_ CDCS11_PA_screenMd : 115|4@0+ (1,0) [0|15] "NoUnit" TBOX,FLC_ME_FD3,FLC_FD3,GW_FD5,GW_FD3,ADCU_FD3,ADCS_FD3,TBOX_OverSea
 SG_ CDCS11_PASw : 118|3@0+ (1,0) [0|7] "NoUnit" TBOX,FLC_ME_FD3,FLC_FD3,GW_FD5,GW_FD3,ADCU_FD3,ADCS_FD3,TBOX_OverSea
 SG_ CDCS11_PA_Recover : 119|1@0+ (1,0) [0|1] "NoUnit" TBOX,FLC_ME_FD3,FLC_FD3,GW_FD5,GW_FD3,ADCU_FD3,ADCS_FD3,TBOX_OverSea
 SG_ CDCS_Lcsndrequest : 121|2@0+ (1,0) [0|3] "NoUnit" TBOX,FLC_ME_FD3,FLC_FD3,GW_FD5,GW_FD3,ADCU_FD3,ADCS_FD3,TBOX_OverSea
 SG_ CDCS_Lcsndconfirm : 123|2@0+ (1,0) [0|3] "NoUnit" TBOX,FLC_ME_FD3,FLC_FD3,GW_FD5,GW_FD3,ADCU_FD3,ADCS_FD3,TBOX_OverSea
 SG_ CDCS_SpdAdaptComfirm : 125|2@0+ (1,0) [0|3] "NoUnit" TBOX,FLC_ME_FD3,FLC_FD3,GW_FD5,GW_FD3,ADCU_FD3,ADCS_FD3,TBOX_OverSea
 SG_ CDCS_PayModeConfirm : 127|2@0+ (1,0) [0|3] "NoUnit" TBOX,FLC_ME_FD3,FLC_FD3,GW_FD5,GW_FD3,ADCU_FD3,ADCS_FD3,TBOX_OverSea
 SG_ CDCS11_SelectSlotID : 131|4@0+ (1,0) [0|15] "NoUnit" TBOX,FLC_ME_FD3,FLC_FD3,GW_FD5,GW_FD3,ADCU_FD3,ADCS_FD3,TBOX_OverSea
 SG_ CDCS11_ParkingInReq : 133|2@0+ (1,0) [0|3] "NoUnit" TBOX,FLC_ME_FD3,FLC_FD3,GW_FD5,GW_FD3,ADCU_FD3,ADCS_FD3,TBOX_OverSea
 SG_ CDCS11_ParkingOutReq : 135|2@0+ (1,0) [0|3] "NoUnit" TBOX,FLC_ME_FD3,FLC_FD3,GW_FD5,GW_FD3,ADCU_FD3,ADCS_FD3,TBOX_OverSea
 SG_ CDCS11_AVM_ViewMode : 137|2@0+ (1,0) [0|3] "NoUnit" TBOX,FLC_ME_FD3,FLC_FD3,GW_FD5,GW_FD3,ADCU_FD3,ADCS_FD3,TBOX_OverSea
 SG_ CDCS11_RPA_FunctionMode : 139|2@0+ (1,0) [0|3] "NoUnit" TBOX,FLC_ME_FD3,FLC_FD3,GW_FD5,GW_FD3,ADCU_FD3,ADCS_FD3,TBOX_OverSea
 SG_ CDCS11_AVM_VideoOutputFail : 140|1@0+ (1,0) [0|1] "NoUnit" TBOX,FLC_ME_FD3,FLC_FD3,GW_FD5,GW_FD3,ADCU_FD3,ADCS_FD3,TBOX_OverSea
 SG_ CDCS11_AVM_Initialization : 141|1@0+ (1,0) [0|1] "NoUnit" TBOX,FLC_ME_FD3,FLC_FD3,GW_FD5,GW_FD3,ADCU_FD3,ADCS_FD3,TBOX_OverSea
 SG_ CDCS11_AVM_bodySync : 143|2@0+ (1,0) [0|3] "NoUnit" TBOX,FLC_ME_FD3,FLC_FD3,GW_FD5,GW_FD3,ADCU_FD3,ADCS_FD3,TBOX_OverSea
 SG_ CDCS11_AVM_licenseplateabbr : 149|6@0+ (1,0) [0|63] "NoUnit" TBOX,FLC_ME_FD3,FLC_FD3,GW_FD5,GW_FD3,ADCU_FD3,ADCS_FD3,TBOX_OverSea
 SG_ CDCS11_AVM_SpeView : 151|2@0+ (1,0) [0|3] "NoUnit" TBOX,FLC_ME_FD3,FLC_FD3,GW_FD5,GW_FD3,ADCU_FD3,ADCS_FD3,TBOX_OverSea
 SG_ CDCS11_AVM_licenseplateArea : 156|5@0+ (1,0) [0|31] "NoUnit" TBOX,FLC_ME_FD3,FLC_FD3,GW_FD5,GW_FD3,ADCU_FD3,ADCS_FD3,TBOX_OverSea
 SG_ CDCS11_AVM_StartMode : 159|3@0+ (1,0) [0|7] "NoUnit" FLC_ME_FD3,FLC_FD3,GW_FD3,ADCU_FD3,ADCS_FD3
 SG_ CDCS11_AVM_LicensePlateNO1 : 165|6@0+ (1,0) [0|63] "NoUnit" TBOX,FLC_ME_FD3,FLC_FD3,GW_FD5,GW_FD3,ADCU_FD3,ADCS_FD3,TBOX_OverSea
 SG_ CDCS11_AVM_LicensePlateNO2 : 173|6@0+ (1,0) [0|63] "NoUnit" TBOX,FLC_ME_FD3,FLC_FD3,GW_FD5,GW_FD3,ADCU_FD3,ADCS_FD3,TBOX_OverSea
 SG_ CDCS11_DrvOffAlertSwitch : 175|2@0+ (1,0) [0|3] "NoUnit" FLC_ME_FD3,FLC_FD3,GW_FD3,ADCU_FD3,ADCS_FD3
 SG_ CDCS11_AVM_LicensePlateNO3 : 181|6@0+ (1,0) [0|63] "NoUnit" TBOX,FLC_ME_FD3,FLC_FD3,GW_FD5,GW_FD3,ADCU_FD3,ADCS_FD3,TBOX_OverSea
 SG_ CDCS11_DCWposition : 183|2@0+ (1,0) [0|3] "NoUnit" FLC_ME_FD3,FLC_FD3,GW_FD3,ADCU_FD3,ADCS_FD3
 SG_ CDCS11_AVM_LicensePlateNO4 : 189|6@0+ (1,0) [0|63] "NoUnit" TBOX,FLC_ME_FD3,FLC_FD3,GW_FD5,GW_FD3,ADCU_FD3,ADCS_FD3,TBOX_OverSea
 SG_ CDCS11_EOL_Fdbk : 191|2@0+ (1,0) [0|3] "NoUnit" GW_FD3,ADCU_FD3
 SG_ CDCS11_AVM_LicensePlateNO5 : 197|6@0+ (1,0) [0|63] "NoUnit" TBOX,FLC_ME_FD3,FLC_FD3,GW_FD5,GW_FD3,ADCU_FD3,ADCS_FD3,TBOX_OverSea
 SG_ CDCS11_AVM_LicensePlateNO6 : 205|6@0+ (1,0) [0|63] "NoUnit" TBOX,FLC_ME_FD3,FLC_FD3,GW_FD5,GW_FD3,ADCU_FD3,ADCS_FD3,TBOX_OverSea
 SG_ CDCS11_DataUp_Trigger : 207|2@0+ (1,0) [0|3] "NoUnit" FLC_ME_FD3,FLC_FD3,GW_FD3,ADCU_FD3,ADCS_FD3
 SG_ CDCS11_AVM_LicensePlateNO7 : 213|6@0+ (1,0) [0|63] "NoUnit" TBOX,FLC_ME_FD3,FLC_FD3,GW_FD5,GW_FD3,ADCU_FD3,ADCS_FD3,TBOX_OverSea
 SG_ CDCS11_AVM_DayNightMode : 215|2@0+ (1,0) [0|3] "NoUnit" GW_FD3,ADCU_FD3,ADCS_FD3
 SG_ CDCS11_AVM_LicensePlateNO8 : 221|6@0+ (1,0) [0|63] "NoUnit" TBOX,FLC_ME_FD3,FLC_FD3,GW_FD5,GW_FD3,ADCU_FD3,ADCS_FD3,TBOX_OverSea
 SG_ CDCS11_AVM_Powertype : 223|2@0+ (1,0) [0|3] "NoUnit" TBOX,FLC_ME_FD3,FLC_FD3,GW_FD5,GW_FD3,ADCU_FD3,ADCS_FD3,TBOX_OverSea
 SG_ CDCS11_AVM_Diaphaneity : 227|4@0+ (1,0) [0|15] "NoUnit" TBOX,FLC_ME_FD3,FLC_FD3,GW_FD5,GW_FD3,ADCU_FD3,ADCS_FD3,TBOX_OverSea
 SG_ CDCS11_AVM_DiaphaneitySw : 228|1@0+ (1,0) [0|1] "NoUnit" TBOX,FLC_ME_FD3,FLC_FD3,GW_FD5,GW_FD3,ADCU_FD3,ADCS_FD3,TBOX_OverSea
 SG_ CDCS11_LDWLKAAidSwSts : 231|3@0+ (1,0) [0|7] "NoUnit" FLC_ME_FD3,FLC_FD3,GW_FD3,ADCS_FD3
 SG_ CDCS11_MOD_Sound_Sw : 233|2@0+ (1,0) [0|3] "NoUnit" TBOX,FLC_ME_FD3,FLC_FD3,GW_FD5,GW_FD3,ADCU_FD3,ADCS_FD3,TBOX_OverSea
 SG_ CDCS11_MOD_BSD_Sw : 235|2@0+ (1,0) [0|3] "NoUnit" TBOX,FLC_ME_FD3,FLC_FD3,GW_FD5,GW_FD3,ADCU_FD3,ADCS_FD3,TBOX_OverSea
 SG_ CDCS11_PA_FRS_OnOffSet : 237|2@0+ (1,0) [0|3] "NoUnit" TBOX,FLC_ME_FD3,FLC_FD3,GW_FD5,GW_FD3,ADCU_FD3,ADCS_FD3,TBOX_OverSea
 SG_ CDCS11_PA_3D_OnOffSet : 239|2@0+ (1,0) [0|3] "NoUnit" TBOX,FLC_ME_FD3,FLC_FD3,GW_FD5,GW_FD3,ADCU_FD3,ADCS_FD3,TBOX_OverSea
 SG_ CDCS11_PA_measure_OnOffSet : 241|2@0+ (1,0) [0|3] "NoUnit" TBOX,FLC_ME_FD3,FLC_FD3,GW_FD5,GW_FD3,ADCU_FD3,ADCS_FD3,TBOX_OverSea
 SG_ CDCS11_MODSw : 243|2@0+ (1,0) [0|3] "NoUnit" TBOX,FLC_ME_FD3,FLC_FD3,GW_FD5,GW_FD3,ADCU_FD3,ADCS_FD3,TBOX_OverSea
 SG_ CDCS11_VoiceNotifFrequency_mode : 245|2@0+ (1,0) [0|3] "NoUnit" TBOX,FLC_ME_FD3,FLC_FD3,GW_FD5,GW_FD3,ADCU_FD3,ADCS_FD3,TBOX_OverSea
 SG_ CDCS11_ACCOnOffSet : 247|2@0+ (1,0) [0|3] "NoUnit" TBOX,FLC_ME_FD3,FLC_FD3,GW_FD5,GW_FD3,ADCU_FD3,ADCS_FD3,TBOX_OverSea
 SG_ CDCS11_HPASw : 249|2@0+ (1,0) [0|3] "NoUnit" TBOX,FLC_ME_FD3,FLC_FD3,GW_FD5,GW_FD3,ADCU_FD3,ADCS_FD3,TBOX_OverSea
 SG_ CDCS11_PA_WarningType : 253|2@0+ (1,0) [0|3] "NoUnit" GW_FD3,ADCU_FD3
 SG_ CDCS11_HPA_OnOffSet : 255|2@0+ (1,0) [0|3] "NoUnit" GW_FD3,ADCU_FD3
 SG_ CDCS11_DeleteMapID : 263|8@0+ (1,0) [0|255] "NoUnit" TBOX,FLC_ME_FD3,FLC_FD3,GW_FD5,GW_FD3,ADCU_FD3,ADCS_FD3,TBOX_OverSea
 SG_ CDCS11_UploadMapID : 271|8@0+ (1,0) [0|255] "NoUnit" TBOX,FLC_ME_FD3,FLC_FD3,GW_FD5,GW_FD3,ADCU_FD3,ADCS_FD3,TBOX_OverSea
 SG_ CDCS11_HPAActiveConfirm : 274|1@0+ (1,0) [0|1] "NoUnit" TBOX,FLC_ME_FD3,FLC_FD3,GW_FD5,GW_FD3,ADCU_FD3,ADCS_FD3,TBOX_OverSea
 SG_ CDCS11_TSR_ALSUpdataSwState : 276|2@0+ (1,0) [0|3] "NoUnit" FLC_ME_FD3,GW_FD3
 SG_ CDCS11_HPApreparkingSw : 278|2@0+ (1,0) [0|3] "NoUnit" TBOX,FLC_ME_FD3,FLC_FD3,GW_FD5,GW_FD3,ADCU_FD3,ADCS_FD3,TBOX_OverSea
 SG_ CDCS11_HPAPathwaytoCloud_WorkSts : 282|3@0+ (1,0) [0|7] "NoUnit" TBOX,FLC_ME_FD3,FLC_FD3,GW_FD5,GW_FD3,ADCU_FD3,ADCS_FD3,TBOX_OverSea
 SG_ CDCS11_TSR_SLWFVoiceSwState : 284|2@0+ (1,0) [0|3] "NoUnit" FLC_ME_FD3,GW_FD3
 SG_ CDCS11_ELKA_OnOffSet : 286|2@0+ (1,0) [0|3] "NoUnit" FLC_ME_FD3,FLC_FD3,GW_FD3,ADCS_FD3
 SG_ CDCS11_Pathrelearn : 287|1@0+ (1,0) [0|1] "NoUnit" GW_FD3,ADCU_FD3
 SG_ CDCS11_HPA_ONPath_ID1 : 295|8@0+ (1,0) [0|255] "NoUnit" FLC_ME_FD3,FLC_FD3,GW_FD3,ADCU_FD3,ADCS_FD3
 SG_ CDCS11_HPA_ONPath_ID2 : 303|8@0+ (1,0) [0|255] "NoUnit" FLC_ME_FD3,FLC_FD3,GW_FD3,ADCU_FD3,ADCS_FD3
 SG_ CDCS11_HPA_ONPath_ID3 : 311|8@0+ (1,0) [0|255] "NoUnit" FLC_ME_FD3,FLC_FD3,GW_FD3,ADCU_FD3,ADCS_FD3
 SG_ CDCS11_HPA_ONPath_ID4 : 319|8@0+ (1,0) [0|255] "NoUnit" FLC_ME_FD3,FLC_FD3,GW_FD3,ADCU_FD3,ADCS_FD3
 SG_ CDCS11_HPA_Select_ID : 327|8@0+ (1,0) [0|255] "NoUnit" FLC_ME_FD3,FLC_FD3,GW_FD3,ADCU_FD3,ADCS_FD3
 SG_ CDCS11_PA_Select_ID : 335|8@0+ (1,0) [0|255] "NoUnit" TBOX,FLC_ME_FD3,FLC_FD3,GW_FD5,GW_FD3,ADCU_FD3,ADCS_FD3,TBOX_OverSea
 SG_ CDCS11_learnpath_St : 337|2@0+ (1,0) [0|3] "NoUnit" FLC_ME_FD3,FLC_FD3,GW_FD3,ADCU_FD3,ADCS_FD3
 SG_ CDCS11_LDWLKA_WarnTiming : 343|3@0+ (1,0) [0|7] "NoUnit" FLC_ME_FD3,GW_FD3
 SG_ CDCS11_TSR_LimitOverspeedSet : 351|8@0+ (1,0) [0|100] "%" FLC_ME_FD3,FLC_FD3,GW_FD3,ADCS_FD3
 SG_ CDCS11_FrbdWindowOpen_Req : 362|2@0+ (1,0) [0|3] "NoUnit" GW_FD2,DDCU
 SG_ CDCS11_ParkingoutSlot_Type : 369|2@0+ (1,0) [0|3] "NoUnit" TBOX,FLC_ME_FD3,FLC_FD3,GW_FD5,GW_FD3,ADCU_FD3,ADCS_FD3,TBOX_OverSea
 SG_ CDCS11_ParkingoutSlot_Dire : 371|2@0+ (1,0) [0|3] "NoUnit" TBOX,FLC_ME_FD3,FLC_FD3,GW_FD5,GW_FD3,ADCU_FD3,ADCS_FD3,TBOX_OverSea
 SG_ CDCS11_OptionalSlot_Type : 373|2@0+ (1,0) [0|3] "NoUnit" TBOX,FLC_ME_FD3,FLC_FD3,GW_FD5,GW_FD3,ADCU_FD3,ADCS_FD3,TBOX_OverSea
 SG_ CDCS11_OptionalSlot_Dire : 360|3@0+ (1,0) [0|7] "NoUnit" TBOX,FLC_ME_FD3,FLC_FD3,GW_FD5,GW_FD3,ADCU_FD3,ADCS_FD3,TBOX_OverSea
 SG_ CDCS11_OptionalSlotAngle : 383|8@0+ (0.255,0) [0|65.025] "rad" TBOX,FLC_ME_FD3,FLC_FD3,GW_FD5,GW_FD3,ADCU_FD3,ADCS_FD3,TBOX_OverSea
 SG_ CDCS11_OptionalSlotCoor_P0_X : 391|16@0+ (1,0) [0|65535] "NoUnit" TBOX,FLC_ME_FD3,FLC_FD3,GW_FD5,GW_FD3,ADCU_FD3,ADCS_FD3,TBOX_OverSea
 SG_ CDCS11_OptionalSlotCoor_P0_Y : 407|16@0+ (1,0) [0|65535] "NoUnit" TBOX,FLC_ME_FD3,FLC_FD3,GW_FD5,GW_FD3,ADCU_FD3,ADCS_FD3,TBOX_OverSea
 SG_ CDCS11_OptionalSlotCoor_P1_X : 423|16@0+ (1,0) [0|65535] "NoUnit" TBOX,FLC_ME_FD3,FLC_FD3,GW_FD5,GW_FD3,ADCU_FD3,ADCS_FD3,TBOX_OverSea
 SG_ CDCS11_OptionalSlotCoor_P1_Y : 439|16@0+ (1,0) [0|65535] "NoUnit" TBOX,FLC_ME_FD3,FLC_FD3,GW_FD5,GW_FD3,ADCU_FD3,ADCS_FD3,TBOX_OverSea
 SG_ CDCS11_OptionalSlotCoor_P2_X : 455|16@0+ (1,0) [0|65535] "NoUnit" TBOX,FLC_ME_FD3,FLC_FD3,GW_FD5,GW_FD3,ADCU_FD3,ADCS_FD3,TBOX_OverSea
 SG_ CDCS11_OptionalSlotCoor_P2_Y : 471|16@0+ (1,0) [0|65535] "NoUnit" TBOX,FLC_ME_FD3,FLC_FD3,GW_FD5,GW_FD3,ADCU_FD3,ADCS_FD3,TBOX_OverSea
 SG_ CDCS11_OptionalSlotCoor_P3_X : 487|16@0+ (1,0) [0|65535] "NoUnit" TBOX,FLC_ME_FD3,FLC_FD3,GW_FD5,GW_FD3,ADCU_FD3,ADCS_FD3,TBOX_OverSea
 SG_ CDCS11_OptionalSlotCoor_P3_Y : 503|16@0+ (1,0) [0|65535] "NoUnit" TBOX,FLC_ME_FD3,FLC_FD3,GW_FD5,GW_FD3,ADCU_FD3,ADCS_FD3,TBOX_OverSea

BO_TX_BU_ 243 : TBOX,TBOX_OverSea;
BO_TX_BU_ 498 : TBOX,TBOX_OverSea;
BO_TX_BU_ 755 : TBOX,TBOX_OverSea;
BO_TX_BU_ 756 : TBOX,TBOX_OverSea;
BO_TX_BU_ 980 : TBOX,TBOX_OverSea;
BO_TX_BU_ 320 : CDCS,CDCS_OverSea;
BO_TX_BU_ 442 : CDCS,CDCS_OverSea;
BO_TX_BU_ 444 : CDCS,CDCS_OverSea;
BO_TX_BU_ 443 : CDCS,CDCS_OverSea;
BO_TX_BU_ 794 : CDCS,CDCS_OverSea;
BO_TX_BU_ 466 : CDCS,CDCS_OverSea;
BO_TX_BU_ 468 : CDCS,CDCS_OverSea;
BO_TX_BU_ 501 : CDCS,CDCS_OverSea;
CM_ BO_ 794 "复位后里程车速";
CM_ SG_ 993 BDCS_OBDErr_Data0 "OBD故障数据Data0";
CM_ SG_ 993 BDCS_OBDErr_Data1 "OBD故障数据Data1";
CM_ SG_ 993 BDCS_OBDErr_Data2 "OBD故障数据Data2";
CM_ SG_ 993 BDCS_OBDErr_Data3 "OBD故障数据Data3";
CM_ SG_ 993 BDCS_OBDErr_Data4 "OBD故障数据Data4";
CM_ SG_ 993 BDCS_OBDErr_Data5 "OBD故障数据Data5";
CM_ SG_ 993 BDCS_OBDErr_Data6 "OBD故障数据Data6";
CM_ SG_ 993 BDCS_OBDErr_Data7 "OBD故障数据Data7";
CM_ SG_ 1008 BDCS_VIN1 "BDCS VIN ASCII 第10位";
CM_ SG_ 1008 BDCS_VIN2 "BDCS VIN ASCII 第11位";
CM_ SG_ 1008 BDCS_VIN3 "BDCS VIN ASCII 第12位";
CM_ SG_ 1008 BDCS_VIN4 "BDCS VIN ASCII 第13位";
CM_ SG_ 1008 BDCS_VIN5 "BDCS VIN ASCII 第14位";
CM_ SG_ 1008 BDCS_VIN6 "BDCS VIN ASCII 第15位";
CM_ SG_ 1008 BDCS_VIN7 "BDCS VIN ASCII 第16位";
CM_ SG_ 1008 BDCS_VIN8 "BDCS VIN ASCII 第17位";
CM_ SG_ 1538 BDCS_SourceNodeIdentifier "ECU节点标识符";
CM_ SG_ 1538 BDCS_RepeatMessageRequest "Repeat Message请求";
CM_ SG_ 1538 BDCS_Reserve1 "预留";
CM_ SG_ 1538 BDCS_ActiveWakeup "激活唤醒，主动唤醒网络时置1，其他（包括被动唤醒节点）为0";
CM_ SG_ 1538 BDCS_Reserve2 "预留";
CM_ SG_ 1538 BDCS_WakeUp_KL15 "KL15 ON 唤醒";
CM_ SG_ 1538 BDCS_WakeUp_Rx_NM "NM报文唤醒";
CM_ SG_ 1538 BDCS_WakeUp_Hazard "危险报警开关按下唤醒";
CM_ SG_ 1538 BDCS_WakeUp_BackDoorFB "后背门开闭状态反馈";
CM_ SG_ 1538 BDCS_WakeUp_BackDoorOutSW "后背门车外开关";
CM_ SG_ 1538 BDCS_WakeUp_LiftGateLockSW "尾门内整车闭锁开关";
CM_ SG_ 1538 BDCS_WakeUp_PLGInLockSW "尾门内电动尾门闭锁开关";
CM_ SG_ 1538 BDCS_WakeUp_FullLock "Full Lock";
CM_ SG_ 1538 BDCS_WakeUp_RKE "RKE唤醒";
CM_ SG_ 1538 BDCS_RemainNetworkWakeUp_Power "电源模式不在OFF";
CM_ SG_ 1538 BDCS_RemainNetworkWakeUp_DiagMode "BDCS处于诊断模式";
CM_ SG_ 1538 BDCS_RemainNetworkWakeUp_HazardBlink "危险警示灯仍在工作";
CM_ SG_ 1538 BDCS_RemainNetworkWakeUp_PosLightOn "位置灯仍在工作---预留";
CM_ SG_ 1538 BDCS_RemainNetworkWakeUp_AlarmState "BDCS仍在防盗报警状态---预留";
CM_ SG_ 1538 BDCS_RemainNetworkWakeUp_Wait_AutoRepeatLock "BDCS处于等待自动重上锁状态---预留";
CM_ SG_ 1538 BDCS_RemainNetworkWakeUp_DomeLightOn "室内灯仍在工作---预留";
CM_ SG_ 1538 BDCS_RemainNetworkWakeUp_PowerSavingRelayWorking "节电继电器仍在工作---预留";
CM_ SG_ 1538 BDCS_RemainNetworkWakeUp_FollowmeHome "伴我回家功能激活---预留";
CM_ SG_ 1538 BDCS_WakeUp_HoodAjarFB "前舱盖开闭状态反馈";
CM_ SG_ 1538 BDCS_WakeUp_LIN2 "LIN2子节点唤醒";
CM_ SG_ 1538 BDCS_WakeUp_TPMS "胎压射频信号唤醒";
CM_ SG_ 1538 BDCS_WakeUp_PassengerSideHandleLock "副驾门把手闭锁请求输入";
CM_ SG_ 1538 BDCS_WakeUp_PassengerSideHandleUnLock "副驾门把手解锁请求输入";
CM_ SG_ 1538 BDCS_WakeUp_DriverSideHandleLock "主驾门把手闭锁请求输入";
CM_ SG_ 1538 BDCS_WakeUp_DriverSideHandleUnlock "主驾门把手解锁请求输入";
CM_ SG_ 1538 BDCS_WakeUp_SSBSW2 "IA_SSB_SW2";
CM_ SG_ 1538 BDCS_WakeUp_SSBSW1 "IA_SSB_SW1";
CM_ SG_ 1538 BDCS_WakeUp_IGN2 "IDH_IGN2_FB/IGN2_RELAY_FB";
CM_ SG_ 1538 BDCS_WakeUp_IGN1 "IDH_IGN1_FB/IGN1_RELAY_FB";
CM_ SG_ 1538 BDCS_WakeUp_ACC "IDH_ACC_FB/ACC_RELAY_FB";
CM_ SG_ 1538 BDCS_WakeUp_Break1 "刹车输入1";
CM_ SG_ 1538 BDCS_WakeUp_Break2 "刹车输入2";
CM_ SG_ 1538 BDCS_WakeUp_KickSensor "脚踢传感器输入";
CM_ SG_ 1538 BDCS_WakeUp_PassageSideContainerSW "副驾储物盒电动开关";
CM_ SG_ 1538 BDCS_WakeUp_HornInput "喇叭输入";
CM_ SG_ 1538 BDCS_WakeUp_DriverSideSensor "主驾座椅压力传感器";
CM_ SG_ 1538 BDCS_WakeUp_LightLevelInput "灯光档位输入";
CM_ SG_ 1538 BDCS_WakeUp_HighBeam "远光灯输入";
CM_ SG_ 1538 BDCS_UserData5 "用户数据5预留";
CM_ SG_ 1664 BDCS1_TEST "测试报文，特定工况下触发";
CM_ SG_ 1665 BDCS2_TEST "测试报文，特定工况下触发";
CM_ SG_ 418 DDCU1_ControlWindowLockSw "主驾玻璃锁止控制开关";
CM_ SG_ 418 DDCU1_OilFillCapFbk "油箱口盖未盖提醒";
CM_ SG_ 418 DDCU1_FLWinCtrl_Fb "语音左前车窗控制反馈";
CM_ SG_ 418 DDCU1_RLWinCtrl_Fb "语音左后车窗控制反馈";
CM_ SG_ 418 DDCU1_FL_WinPos "左前车窗位置信息(0%关闭100%全开)";
CM_ SG_ 418 DDCU1_RL_WinPos "左后车窗位置信息(0%关闭100%全开)";
CM_ SG_ 418 DDCU1_FLDoorAjar "左前车门开闭状态";
CM_ SG_ 418 DDCU1_RLDoorAjar "左后车门开闭状态";
CM_ SG_ 418 DDCU1_RL_SafetyLockFdbk "左后儿童锁设置反馈";
CM_ SG_ 418 DDCU1_MirrorFoldSt "外后视镜折叠状态";
CM_ SG_ 418 DDCU1_MirrorFoldSet_fdbk "外后视镜折叠设置反馈";
CM_ SG_ 418 DDCU1_LockReleaseSw_Out_FL "左前外释放开关信号";
CM_ SG_ 418 DDCU1_LockReleaseSw_Out_FR "左后外释放开关信号";
CM_ SG_ 418 DDCU1_LockReleaseSw_In_FL "左前内释放开关信号";
CM_ SG_ 418 DDCU1_LockReleaseSw_In_FR "左后内释放开关信号";
CM_ SG_ 418 DDCU1_FL_HallFault "左前霍尔传感器故障";
CM_ SG_ 418 DDCU1_FL_PWL_Init "左前车窗驱动初始化状态";
CM_ SG_ 418 DDCU1_FL_PWL_State "左前车窗驱动器工作状态";
CM_ SG_ 418 DDCU1_RL_PWL_State "左后车窗驱动器工作状态";
CM_ SG_ 418 DDCU1_RL_HallFault "左后霍尔传感器故障";
CM_ SG_ 418 DDCU1_RL_PWL_Init "左后车窗驱动初始化状态";
CM_ SG_ 418 DDCU1_LeftMirrorAutoTurnDownFb "左外后视镜倒车下翻反馈";
CM_ SG_ 418 DDCU1_LeftPosLoad_Sts "左后视镜位置加载成功状态";
CM_ SG_ 418 DDCU1_AliveCounter "E2E Profile2-CRC8H2F";
CM_ SG_ 418 DDCU1_FL_WindowsExerciseSts "左前车窗运动状态";
CM_ SG_ 418 DDCU1_RL_WindowsExerciseSts "左后车窗运动状态";
CM_ SG_ 418 DDCU1_Checksum "E2E Profile2-CRC8H2F
DataID List:#18 - 160 145 248 202 149 236 182 34 83 178 198 196 106 105 48 207";
CM_ SG_ 418 DDCU1_FRWindowsCtrl "右前车窗控制请求";
CM_ SG_ 418 DDCU1_RRWindowsCtrl "右后车窗控制请求";
CM_ SG_ 418 DDCU1_LeftPosMemory_Sts "左后视镜位置记忆成功状态";
CM_ SG_ 418 DDCU1_FL_LockSt "左前侧门锁状态";
CM_ SG_ 418 DDCU1_RL_LockSt "左后侧门锁状态";
CM_ SG_ 418 DDCU1_WindowSteamSet_Fb "车窗留缝设置反馈";
CM_ SG_ 418 DRGLS_CustomSignal "转发DRGLS的自定义按钮信号";
CM_ SG_ 418 DFGLS_CustomSignal "转发DFGLS的自定义按钮信号";
CM_ SG_ 418 DDCU1_FL_WindowsAnti_pinchSts "左前车窗防夹状态";
CM_ SG_ 418 DDCU1_RL_WindowsAnti_pinchSts "左后车窗防夹状态";
CM_ SG_ 418 DDCU1_LeftMirror_Pos_ManualAdjust_Sts "左外后视镜位置手动调节状态";
CM_ SG_ 418 DDCU1_DoorHandleRetractedOverTimeSts "门把手超时回缩开关状态";
CM_ SG_ 418 DDCU1_FLWindowFollowUpDoorSts "左前车窗随动车门开关状态";
CM_ SG_ 418 DDCU1_OilFillCapSts "油箱口盖状态";
CM_ SG_ 418 DDCU1_CentralLockFailure "门锁系统故障信号";
CM_ SG_ 418 DDCU1_OilFillCapLockSts "油箱口盖锁状态";
CM_ SG_ 418 DDCU1_MirrorFoldSpeedLimit_Fb "后视镜折叠车速限制反馈";
CM_ SG_ 418 DDCU1_FL_DoorHandleSts "左前门把手状态";
CM_ SG_ 418 DDCU1_RL_DoorHandleSts "左后门把手状态";
CM_ SG_ 418 DDCU1_MirrorHeatingSts "左外后视镜加热状态";
CM_ SG_ 418 DDCU1_CentralLockLightSts "中控锁指示灯状态";
CM_ SG_ 418 DDCU1_CentralLockSts "中控锁状态";
CM_ SG_ 418 DDCU1_DFGLS_FLWindowControl "主驾左前车窗控制请求";
CM_ SG_ 418 DDCU1_DFGLS_RLWindowControl "主驾左后车窗控制请求";
CM_ SG_ 418 DDCU1_FL_Cause_loss_PWL_Init "左前车窗驱动丢初始化原因";
CM_ SG_ 418 DDCU1_DRGLS_RLWindowControl "后排左后车窗控制请求";
CM_ SG_ 418 DFGLS_ButtonSoundRequest "玻璃升降主开关按键提示音";
CM_ SG_ 418 DRGLS_ButtonSoundRequest "左后玻璃升降开关按键提示音";
CM_ SG_ 418 DDCU1_RL_Cause_loss_PWL_Init "左后车窗驱动丢初始化原因";
CM_ SG_ 858 DDCU_OTA__FL_WinPos "左前车窗位置信息(0%关闭100%全开)";
CM_ SG_ 858 DDCU_OTA__RL_WinPos "左后车窗位置信息(0%关闭100%全开)";
CM_ SG_ 858 DDCU_OTA__FLDoorAjar "左前车门开闭状态";
CM_ SG_ 858 DDCU_OTA__RLDoorAjar "左后车门开闭状态";
CM_ SG_ 858 DDCU_OTA_CentralLockSts "中控锁状态";
CM_ SG_ 858 DDCU_OTA_FRWindowsCtrl "OTA时右前车窗控制请求";
CM_ SG_ 858 DDCU_OTA_RRWindowsCtrl "OTA时右后车窗控制请求";
CM_ SG_ 858 DDCU_OTA_ControlWindowLockSw "OTA时DDCU转发DFGLS的玻璃锁止控制开关信号给PDCU";
CM_ SG_ 858 DDCU_OTA_FL_LockSt "OTA时左前侧门锁状态";
CM_ SG_ 858 DDCU_OTA_RL_LockSt "OTA时左后侧门锁状态";
CM_ SG_ 858 DDCU_OTA_MirrorFoldSt "OTA时外后视镜折叠状态";
CM_ SG_ 1550 DDCU_SourceNodeIdentifier "ECU节点标识符";
CM_ SG_ 1550 DDCU_RepeatMessageRequest "Repeat Message请求";
CM_ SG_ 1550 DDCU_Reserve1 "预留";
CM_ SG_ 1550 DDCU_ActiveWakeup "激活唤醒，主动唤醒网络时置1，其他（包括被动唤醒节点）为0";
CM_ SG_ 1550 DDCU_Reserve2 "预留";
CM_ SG_ 1550 DDCU_WakeUp_KL15 "KL15 ON唤醒";
CM_ SG_ 1550 DDCU_WakeUp_NM "NM报文唤醒";
CM_ SG_ 1550 DDCU_WakeUp_FLDoor "左前门打开";
CM_ SG_ 1550 DDCU_WakeUp_RLDoor "左后门打开";
CM_ SG_ 1550 DDCU_WakeUp_FLInSW "左前内释放开关";
CM_ SG_ 1550 DDCU_WakeUp_FLOutSW "左前外释放开关";
CM_ SG_ 1550 DDCU_WakeUp_RLInSW "左后内释放开关";
CM_ SG_ 1550 DDCU_WakeUp_RLOutSW "左后外释放开关";
CM_ SG_ 1550 DDCU_RemainNetworkWakeUpReason1 "保持网络唤醒原因1";
CM_ SG_ 1550 DDCU_RemainNetworkWakeUpReason2 "保持网络唤醒原因2";
CM_ SG_ 1550 DDCU_RemainNetworkWakeUpReason3 "保持网络唤醒原因3";
CM_ SG_ 1550 DDCU_RemainNetworkWakeUpReason4 "保持网络唤醒原因4";
CM_ SG_ 1550 DDCU_WakeUp_FLLockSts "主驾钥匙解锁唤醒";
CM_ SG_ 1550 DDCU_WakeUp_FuelTankCap "油箱盖打开";
CM_ SG_ 419 PDCU1_OilFillCapSts "油箱口盖状态";
CM_ SG_ 419 PDCU1_OilFillCapLockSts "油箱口盖锁状态";
CM_ SG_ 419 PDCU1_FRWinCtrl_Fb "语音右前车窗控制反馈";
CM_ SG_ 419 PDCU1_RRWinCtrl_Fb "语音右后车窗控制反馈";
CM_ SG_ 419 PDCU1_FR_WinPos "右前车窗位置信息(0%关闭100%全开)";
CM_ SG_ 419 PDCU1_RR_WinPos "右后车窗位置信息(0%关闭100%全开)";
CM_ SG_ 419 PDCU1_FRDoorAjar "右前车门开闭状态";
CM_ SG_ 419 PDCU1_RRDoorAjar "右后车门开闭状态";
CM_ SG_ 419 PDCU1_RR_SafetyLockFdbk "右后儿童锁设置反馈";
CM_ SG_ 419 PFGLS_CustomSignal "转发PFGLS的自定义按钮";
CM_ SG_ 419 PRGLS_CustomSignal "转发PRGLS的自定义按钮信号";
CM_ SG_ 419 PDCU1_LockReleaseSw_Out_FR "右前外释放开关信号";
CM_ SG_ 419 PDCU1_LockReleaseSw_Out_RR "右后外释放开关信号";
CM_ SG_ 419 PDCU1_LockReleaseSw_In_FR "右前内释放开关信号";
CM_ SG_ 419 PDCU1_LockReleaseSw_In_RR "右后内释放开关信号";
CM_ SG_ 419 PDCU1_FR_HallFault "右前霍尔传感器故障";
CM_ SG_ 419 PDCU1_FR_PWL_Init "右前车窗驱动初始化状态";
CM_ SG_ 419 PDCU1_FR_PWL_State "右前车窗驱动器工作状态";
CM_ SG_ 419 PDCU1_RR_PWL_State "右后车窗驱动器工作状态";
CM_ SG_ 419 PDCU1_RR_HallFault "右后霍尔传感器故障";
CM_ SG_ 419 PDCU1_RR_PWL_Init "右后车窗驱动初始化状态";
CM_ SG_ 419 PDCU1_RightMirrorAutoTurnDownFb "右外后视镜倒车下翻反馈";
CM_ SG_ 419 PDCU1_PosLoad_Sts "右后视镜位置加载成功状态";
CM_ SG_ 419 PDCU1_AliveCounter "E2E Profile2-CRC8H2F";
CM_ SG_ 419 PDCU1_ChargeFillCapLockSts "充电口盖锁状态";
CM_ SG_ 419 PDCU1_Checksum "E2E Profile2-CRC8H2F
DataID List:#19 - 42 45 226 106 113 62 80 154 133 115 60 98 94 63 21 212";
CM_ SG_ 419 PDCU1_ChargeLidSts "充电口盖开关状态(Reserved)";
CM_ SG_ 419 PDCU1_PosMemory_Sts "右后视镜位置记忆成功状态";
CM_ SG_ 419 PDCU1_FR_WindowsExerciseSts "右前车窗运动状态";
CM_ SG_ 419 PDCU1_RR_WindowsExerciseSts "右后车窗运动状态";
CM_ SG_ 419 PDCU1_FR_LockSt "右前侧门锁状态";
CM_ SG_ 419 PDCU1_RR_LockSt "右后侧门锁状态";
CM_ SG_ 419 PDCU1_WindowSteamSet_Fb "车窗留缝设置反馈";
CM_ SG_ 419 PDCU1_FR_WindowsAnti_pinchSts "右前车窗防夹状态";
CM_ SG_ 419 PDCU1_RR_WindowsAnti_pinchSts "右后车窗防夹状态";
CM_ SG_ 419 PDCU1_DoorHandleRetractedOverTimeSts "门把手超时回缩开关状态";
CM_ SG_ 419 PDCU1_RightMirror_Pos_ManualAdjust_Sts "右外后视镜位置手动调节状态";
CM_ SG_ 419 PDCU1_FRWindowFollowUpDoorSts "右前车窗随动车门开关状态";
CM_ SG_ 419 PDCU1_FR_DoorHandleSts "右前门把手状态";
CM_ SG_ 419 PDCU1_RR_DoorHandleSts "右后门把手状态";
CM_ SG_ 419 PDCU1_MirrorHeatingSts "右外后视镜加热状态";
CM_ SG_ 419 PDCU1_PFGLS_RLWindowControl "副驾右前车窗控制请求";
CM_ SG_ 419 PDCU1_FR_Cause_loss_PWL_Init "右前车窗驱动丢初始化原因";
CM_ SG_ 419 PDCU1_PRGLS_RRWindowControl "后排右后车窗控制请求";
CM_ SG_ 419 PFGLS_ButtonSoundRequest "玻璃升降副开关按键提示音";
CM_ SG_ 419 PRGLS_ButtonSoundRequest "右后玻璃升降开关按键提示音";
CM_ SG_ 419 PDCU1_RR_Cause_loss_PWL_Init "右后车窗驱动丢初始化原因";
CM_ SG_ 859 PDCU_OTA_FR_WinPos "右前车窗位置信息(0%关闭100%全开)";
CM_ SG_ 859 PDCU_OTA_RR_WinPos "右后车窗位置信息(0%关闭100%全开)";
CM_ SG_ 859 PDCU_OTA_FRDoorAjar "右前车门开闭状态";
CM_ SG_ 859 PDCU_OTA_RRDoorAjar "右后车门开闭状态";
CM_ SG_ 859 PDCU_OTA_FR_LockSt "OTA时右前侧门锁状态";
CM_ SG_ 859 PDCU_OTA_RR_LockSt "OTA时右后侧门锁状态";
CM_ SG_ 1549 PDCU_SourceNodeIdentifier "ECU节点标识符";
CM_ SG_ 1549 PDCU_RepeatMessageRequest "Repeat Message请求";
CM_ SG_ 1549 PDCU_Reserve1 "预留";
CM_ SG_ 1549 PDCU_ActiveWakeup "激活唤醒，主动唤醒网络时置1，其他（包括被动唤醒节点）为0";
CM_ SG_ 1549 PDCU_Reserve2 "预留";
CM_ SG_ 1549 PDCU_WakeUp_KL15 "KL15 ON唤醒";
CM_ SG_ 1549 PDCU_WakeUp_NM "NM报文唤醒";
CM_ SG_ 1549 PDCU_WakeUp_FRDoor "右前门开";
CM_ SG_ 1549 PDCU_WakeUp_RRDoor "右后门开";
CM_ SG_ 1549 PDCU_WakeUp_FRInSW "右前内释放开关";
CM_ SG_ 1549 PDCU_WakeUp_FROutSW "右前外释放开关";
CM_ SG_ 1549 PDCU_WakeUp_RRInSW "右后内释放开关";
CM_ SG_ 1549 PDCU_WakeUp_RROutSW "右后外释放开关";
CM_ SG_ 1549 PDCU_RemainNetworkWakeUpReason1 "保持网络唤醒原因1";
CM_ SG_ 1549 PDCU_RemainNetworkWakeUpReason2 "保持网络唤醒原因2";
CM_ SG_ 1549 PDCU_RemainNetworkWakeUpReason3 "保持网络唤醒原因3";
CM_ SG_ 1549 PDCU_RemainNetworkWakeUpReason4 "保持网络唤醒原因4";
CM_ SG_ 1549 PDCU_WakeUp_FuelTankCap "油箱盖打开";
CM_ SG_ 1549 PDCU_UserData5 "用户数据5预留";
CM_ SG_ 928 BAM1_Sts "车辆蓝牙状态";
CM_ SG_ 928 BAM1_Advertising_Sts "车端蓝牙广播模式";
CM_ SG_ 928 BAM1_WailBox_AUTHENTICATION "充电机器鉴权结果";
CM_ SG_ 928 BAM1_WailBox_ConnectSts "充电桩连接状态";
CM_ SG_ 928 BAM1_EorrCode "错误状态";
CM_ SG_ 928 BAM1_WailBox_Ble_Rssi "充电机BLE信号强度";
CM_ SG_ 1609 BAM_SourceNodeIdentifier "ECU节点标识符";
CM_ SG_ 1609 BAM_RepeatMessageRequest "Repeat Message请求";
CM_ SG_ 1609 BAM_Reserve1 "预留";
CM_ SG_ 1609 BAM_ActiveWakeup "激活唤醒，主动唤醒网络时置1，其他（包括被动唤醒节点）为0";
CM_ SG_ 1609 BAM_Reserve2 "预留";
CM_ SG_ 1609 BAM_WakeUp_KL15 "KL15 ON 唤醒";
CM_ SG_ 1609 BAM_WakeUp_NM "NM报文唤醒（OTA\远程）";
CM_ SG_ 1609 BAM_RemainNetworkWakeUpReason1 "保持网络唤醒原因1";
CM_ SG_ 1609 BAM_RemainNetworkWakeUpReason2 "保持网络唤醒原因2";
CM_ SG_ 1609 BAM_RemainNetworkWakeUpReason3 "保持网络唤醒原因3";
CM_ SG_ 1609 BAM_RemainNetworkWakeUpReason4 "保持网络唤醒原因4";
CM_ SG_ 243 BTM1_SecuritySts "BTM蓝牙认证状态";
CM_ SG_ 243 BTM1_PhoneBatSts "手机电量低提示信息";
CM_ SG_ 243 BTM1_RemoteIntModSel "手机电话中断";
CM_ SG_ 243 BTM1_SelectSlotID "车位信息";
CM_ SG_ 243 BTM1_Retry "遇障碍物重试开关";
CM_ SG_ 243 BTM1_Fixslot "确认车位开关";
CM_ SG_ 243 BTM1_parkingoutSlot_Dire "泊出车位方向信号";
CM_ SG_ 243 BTM1_parkingoutSlotType "泊出车位类型信号";
CM_ SG_ 243 BTM1_Recover "恢复泊车信息";
CM_ SG_ 243 BTM1_ParkingReq "开始泊车信息";
CM_ SG_ 243 BTM1_FunctionMode "遥控泊车模式信号";
CM_ SG_ 243 BTM1_OptionalSlot_Dire "自选车位方向信号";
CM_ SG_ 243 BTM1_OptionalSlotType "自选车位类型信号";
CM_ SG_ 243 BTM1_RollingCounter "E2E Profile2-CRC8H2F，Counter:0-15";
CM_ SG_ 243 BTM1_RemoteParkReq "遥控泊车请求";
CM_ SG_ 243 BTM1_Movectrl "遥控泊车前进后退信号";
CM_ SG_ 243 BTM1_Checksum "E2E Profile2-CRC8H2F
DataID List:#18 - 160 145 248 202 149 236 182 34 83 178 198 196 106 105 48 207";
CM_ SG_ 243 BTM1_OptionalSlotAngle "自选车位角度信号";
CM_ SG_ 243 BTM1_OptionalSlotCoor_P0_X "自选车位坐标信号";
CM_ SG_ 243 BTM1_OptionalSlotCoor_P0_Y "自选车位坐标信号";
CM_ SG_ 243 BTM1_OptionalSlotCoor_P1_X "自选车位坐标信号";
CM_ SG_ 243 BTM1_OptionalSlotCoor_P1_Y "自选车位坐标信号";
CM_ SG_ 243 BTM1_OptionalSlotCoor_P2_X "自选车位坐标信号";
CM_ SG_ 243 BTM1_OptionalSlotCoor_P2_Y "自选车位坐标信号";
CM_ SG_ 243 BTM1_OptionalSlotCoor_P3_X "自选车位坐标信号";
CM_ SG_ 243 BTM1_OptionalSlotCoor_P3_Y "自选车位坐标信号";
CM_ SG_ 498 BTM3_ArmingCmd "蓝牙控制门锁命令";
CM_ SG_ 498 BTM3_TrunkCmd "蓝牙控制车辆尾门";
CM_ SG_ 498 BTM3_RKECmd "物理蓝牙钥匙命令";
CM_ SG_ 498 BTM3_Chargingflapcmd "关闭打开充电口盖命令";
CM_ SG_ 498 BTM3_WelcomeLampCmd "蓝牙控制迎宾灯功能";
CM_ SG_ 498 BTM3_CLM_OnoffCmd "关闭打开空调命令";
CM_ SG_ 498 BTM3_Remote_ControlCmd "蓝牙远程控制启动";
CM_ SG_ 498 BTM3_RL_Window_Control_Cmd "左后车窗模式控制";
CM_ SG_ 498 BTM3_RR_Window_Control_Cmd "右后车窗模式控制";
CM_ SG_ 498 BTM3_CLM_ACCmd "A/C控制指令";
CM_ SG_ 498 BTM3_FL_Window_Control_Cmd "左前车窗模式控制";
CM_ SG_ 498 BTM3_FR_Window_Control_Cmd "右前车窗模式控制";
CM_ SG_ 498 BTM3_CLM_PTCCmd "远程加热指令";
CM_ SG_ 498 BTM3_CLM_BlowerSpdSet "远程风速设定";
CM_ SG_ 498 BTM3_CLM_RHTempSet "远程副驾温度设定";
CM_ SG_ 498 BTM3_CLM_LHTempSet "远程主驾温度设定";
CM_ SG_ 498 BTM3_Charging_cmd "充电控制";
CM_ SG_ 498 BTM3_OpenFLDoorReq "左前门开闭指令";
CM_ SG_ 498 BTM3_All_Window_Closd_Cmd "控制所有车窗关闭";
CM_ SG_ 498 BTM3_All_Window_Open_Cmd "控制所有车窗打开";
CM_ SG_ 498 BTM3_All_Window_Ventilate_Cmd "控制所有车窗通风";
CM_ SG_ 498 BTM3_OpenFLFRDoorReq "前门双侧开闭指令";
CM_ SG_ 498 BTM3_OpenFRDoorReq "右前门开闭指令";
CM_ SG_ 755 BTM4_Key_Sts "蓝牙钥匙的当前位置（包括物理钥匙和蓝牙手机钥匙）";
CM_ SG_ 755 BTM4_SunroofCtrl "天窗控制请求";
CM_ SG_ 756 BTM2_BluPhyKeyLearnSt "蓝牙物理钥匙学习状态";
CM_ SG_ 756 BTM2_ConnectSts "蓝牙钥匙与蓝牙模块的连接状态（包括蓝牙物理钥匙和蓝牙手机钥匙）";
CM_ SG_ 756 BTM2_FobGsenser "钥匙运动状态";
CM_ SG_ 756 BLE_Smartkey_Battery_Lev "蓝牙智能钥匙电量值";
CM_ SG_ 756 BTM2_Key_Position "钥匙位置";
CM_ SG_ 756 BTM2_LightShowMod "远程灯光秀模式";
CM_ SG_ 756 BTM2_LightShowReq "远程灯光秀请求";
CM_ SG_ 756 BTM2_SmartKey_Position "物理蓝牙钥匙位置
智能钥匙位置";
CM_ SG_ 756 BTM2_SmartPhone_Position "手机蓝牙钥匙位置
智能手机位置";
CM_ SG_ 756 BTM2_WelcomeLampCmd_SW "迎宾开关";
CM_ SG_ 756 BTM2_Wal_Away_Up_SW "远离闭锁靠近解锁";
CM_ SG_ 756 BTM2_RSSI "RSSI强度信号";
CM_ SG_ 980 BTM_Resp_EncrData0 "BTM远程控制身份认证响应0";
CM_ SG_ 980 BTM_Resp_EncrData1 "BTM远程控制身份认证响应1";
CM_ SG_ 980 BTM_Resp_EncrData2 "BTM远程控制身份认证响应2";
CM_ SG_ 980 BTM_Resp_EncrData3 "BTM远程控制身份认证响应3";
CM_ SG_ 980 BTM_Resp_EncrData4 "BTM远程控制身份认证响应4";
CM_ SG_ 980 BTM_Resp_EncrData5 "BTM远程控制身份认证响应5";
CM_ SG_ 980 BTM_Resp_EncrData6 "BTM远程控制身份认证响应6";
CM_ SG_ 980 BTM_Resp_EncrData7 "BTM远程控制身份认证响应7";
CM_ SG_ 612 TC1_TrailerLinkSts "拖车连接线状态";
CM_ SG_ 612 TC1_TrailerModeSts "拖挂模式状态";
CM_ SG_ 612 TC1_TrailerLightSts "拖车灯状态";
CM_ SG_ 612 TC1_TrailerLightFltSts "拖车灯故障状态";
CM_ SG_ 612 TC1_BrakeLightFltSts "拖车制动灯故障状态";
CM_ SG_ 612 TC1_LeftTurnLightFltSts "拖车左转向灯故障状态";
CM_ SG_ 612 TC1_RightTurnLightFltSts "拖车右转向灯故障状态";
CM_ SG_ 612 TC1_RearFogLampFltSts "拖车后雾灯故障状态";
CM_ SG_ 612 TC1_BackupLightFltSts "拖车倒车灯故障状态";
CM_ SG_ 612 TC1_PositionLightFltSts "拖车位置灯故障状态";
CM_ SG_ 320 CDCS3_FailSts "IHU故障状态";
CM_ SG_ 320 CDCS3_ChargeConnKpTempSw "插枪保温开启/关闭开关";
CM_ SG_ 320 CDCS3_EnergyRecLevelSet "能量回馈强度设置";
CM_ SG_ 320 CDCS3_ePedalSw "e_Pedal功能开启设置";
CM_ SG_ 320 CDCS3_StopModeReq "e_Pedal功能停车模式设置";
CM_ SG_ 320 CDCS3_ESCOffSw "ESC OFF开关";
CM_ SG_ 320 CDCS3_EPSModeSet "转向助力模式设置";
CM_ SG_ 320 CDCS3_RangeModeReq "续航里程显示方式设置";
CM_ SG_ 320 CDCS3_HDCSw "HDC开关";
CM_ SG_ 320 CDCS3_Refuelrequest "油箱加油请求";
CM_ SG_ 320 CDCS3_CDCModeSet "悬架模式设置信号";
CM_ SG_ 320 CDCS3_EnginIdingldleSet "燃油检测模式设置";
CM_ SG_ 320 CDCS3_TractionModeSw "牵引模式开关";
CM_ SG_ 320 CDCS3_AVHSw "AVH使能";
CM_ SG_ 320 CDCS3_EPBSw "EPB动态拉紧";
CM_ SG_ 320 CDCS3_CSTSw "舒适停车功能/开关";
CM_ SG_ 320 CDCS3_DriveModeSet "驾驶模式选择";
CM_ SG_ 320 CDCS3_BrakestyleSw "制动风格显示及选择按钮";
CM_ SG_ 320 CDCS3_Force_Refuelrequ "加油大屏显示需求";
CM_ SG_ 320 CDCS3_EVModeRexOnAllowed "纯电模式电量极低增程器禁止起动信号";
CM_ SG_ 320 CDCS3_PREMModeSet "PREM功能选择提示";
CM_ SG_ 320 CDCS3_RexModeSet "增程系统模式选择";
CM_ SG_ 320 CDCS3_Xcoordinate "IHU坐标X";
CM_ SG_ 320 CDCS3_Ycoordinate "IHU坐标Y";
CM_ SG_ 320 CDCS3_XGestureSpd "IHU坐标X速度";
CM_ SG_ 320 CDCS3_YGestureSpd "IHU坐标Y速度";
CM_ SG_ 320 CDCS3_TouchEvtTyp "触屏类型";
CM_ SG_ 320 CDCS3_REXchargSet "强制充电设置";
CM_ SG_ 320 CDCS3_ForceChargingLevelSet "强制充电档位设置";
CM_ SG_ 442 CDCS10_Slot0_Valid "有效性";
CM_ SG_ 442 CDCS10_Slot0_Volume "音量";
CM_ SG_ 442 CDCS10_WorK_status "CDCS工作状态";
CM_ SG_ 442 CDCS10_Slot1_Valid "有效性";
CM_ SG_ 442 CDCS10_Slot1_Volume "音量";
CM_ SG_ 442 CDCS10_Slot2_Valid "有效性";
CM_ SG_ 442 CDCS10_Slot2_Volume "音量";
CM_ SG_ 442 CDCS10_Slot3_Valid "有效性";
CM_ SG_ 442 CDCS10_Slot3_Volume "音量";
CM_ SG_ 442 CDCS10_Slot4_Valid "有效性";
CM_ SG_ 442 CDCS10_Slot4_Volume "音量";
CM_ SG_ 442 CDCS10_Slot5_Valid "有效性";
CM_ SG_ 442 CDCS10_Slot5_Volume "音量";
CM_ SG_ 442 CDCS10_Slot6_Valid "有效性";
CM_ SG_ 442 CDCS10_Slot6_Volume "音量";
CM_ SG_ 442 CDCS10_AUD_Engineering_Mode "工程模式";
CM_ SG_ 442 CDCS10_Slot7_Valid "有效性";
CM_ SG_ 442 CDCS10_Slot7_Volume "音量";
CM_ SG_ 442 CDCS10_AUD_Mute "MUTE控制";
CM_ SG_ 444 CDCS10_Slot8_Valid "有效性";
CM_ SG_ 444 CDCS10_Slot8_Volume "音量";
CM_ SG_ 444 CDCS10_Slot9_Valid "有效性";
CM_ SG_ 444 CDCS10_Slot9_Volume "音量";
CM_ SG_ 444 CDCS10_Slot10_Valid "有效性";
CM_ SG_ 444 CDCS10_Slot10_Volume "音量";
CM_ SG_ 444 CDCS10_Slo11_Valid "有效性";
CM_ SG_ 444 CDCS10_Slot11_Volume "音量";
CM_ SG_ 444 CDCS10_Slot12_Valid "有效性";
CM_ SG_ 444 CDCS10_Slot12_Volume "音量";
CM_ SG_ 444 CDCS10_Slot13_Valid "有效性";
CM_ SG_ 444 CDCS10_Slot13_Volume "音量";
CM_ SG_ 444 CDCS10_Slo14_Valid "有效性";
CM_ SG_ 444 CDCS10_Slot14_Volume "音量";
CM_ SG_ 444 CDCS10_Slot15_Valid "有效性";
CM_ SG_ 444 CDCS10_Slot15_Volume "音量";
CM_ SG_ 443 CDCS13_SwSmMode "CDCS周期性通知DDCU、PDCU和ADAS当前多功能方向盘控制功能所处的控制模式（默认模式/ARHUD模式/侧后视镜模式）";
CM_ SG_ 443 CDCS13_CurtainfMoveCtrlReq "遮阳帘运动请求";
CM_ SG_ 443 CDCS13_Seatbelt_Sts "仪表上安全带报警灯状态";
CM_ SG_ 443 CDCS13_SunRoofMoveCtrlReq "天窗运动请求";
CM_ SG_ 443 CDCS13_RoadCondition "路况信息";
CM_ SG_ 794 CDCS19_Trip_AfterStart "自本次车辆启动后的行驶里程";
CM_ SG_ 794 CDCS19_Trip_AfterReset "自本次复位后的行驶里程";
CM_ SG_ 794 CDCS19_TripEnergyConsump_AfterStart "自本次车辆启动后的平均电耗";
CM_ SG_ 794 CDCS19_TripEnergyConsump_AfterReset "自本次复位后的平均电耗";
CM_ SG_ 794 CDCS19_TripDriveTime_AfterStart "自本次车辆启动后的行驶时间";
CM_ SG_ 794 CDCS19_TripDriveTime_AfterReset "自本次复位后的行驶时间";
CM_ SG_ 794 CDCS19_AvgSpd_AfterStart "自本次车辆启动后的平均车速";
CM_ SG_ 794 CDCS19_AvgSpd_AfterReset "自上次复位后的平均车速";
CM_ SG_ 794 CDCS19_Vehicle_service "车辆保养信息";
CM_ SG_ 794 CDCS19_TripFuelConsump_AfterStart "自本次车辆启动后的平均油耗";
CM_ SG_ 794 CDCS19_TripFuelConsump_AfterReset "自上次复位后的平均油耗";
CM_ SG_ 466 CDCS7_ALHMusicMode_Working "氛围灯律动模式工作标志位";
CM_ SG_ 466 CDCS7_ALH_SW "氛围灯总开关";
CM_ SG_ 466 CDCS7_ALHSelectModeCtrl "氛围灯模式选择";
CM_ SG_ 466 CDCS7_ALH_RValueCmd "氛围灯红色坐标值";
CM_ SG_ 466 CDCS7_ALH_GValueCmd "氛围灯绿色坐标值";
CM_ SG_ 466 CDCS7_ALH_BValueCmd "氛围灯蓝色坐标值";
CM_ SG_ 466 CDCS7_ALH_BrightnessCm "氛围灯亮度值";
CM_ SG_ 466 CDCS7_FL_SeatPositionMemoryPosition "主驾请求记忆位置";
CM_ SG_ 466 CDCS7_FL_SeatPositionMemory_Req "主驾位置记忆请求指令";
CM_ SG_ 466 CDCS7_FL_SeatEasygetON_OFF_Set "左前座椅便捷进出设置开关";
CM_ SG_ 466 CDCS7_FR_SeatPositionMemory_Req "副驾位置记忆请求指令";
CM_ SG_ 466 CDCS7_FL_SeatPositionLoad_Req "主驾位置加载请求指令";
CM_ SG_ 466 CDCS7_PositionMemoryUnbind_Req "位置记忆解除绑定指令";
CM_ SG_ 466 CDCS7_FL_SeatPositionLoadPosition "主驾请求加载位置";
CM_ SG_ 466 CDCS7_PosMemoryUnbindAccount "位置记忆解除账号";
CM_ SG_ 466 CDCS7_PositionMode "位置模式（预留）";
CM_ SG_ 466 CDCS7_InteriorLightingReq "室内灯开关需求";
CM_ SG_ 466 CDCS7_DGSW "天幕调节开关";
CM_ SG_ 466 CDCS7_FR_SeatPositionMemoryPosition "副驾记忆请求位置";
CM_ SG_ 466 CDCS7_FR_SeatPositionLoad_Req "副驾位置加载请求指令";
CM_ SG_ 466 CDCS7_DGSWLevel "天幕调节档位";
CM_ SG_ 466 CDCS7_Driver_MassageModeSet "主驾座椅按摩模式设置";
CM_ SG_ 466 CDCS7_ALH_EntryMode "进入模式开关";
CM_ SG_ 466 CDCS7_Passenger_MassageModeSet "副驾座椅按摩模式设置";
CM_ SG_ 466 CDCS7_Driver_MassageLevelSet "主驾座椅按摩强度设置";
CM_ SG_ 466 CDCS7_ALH_AEBMode "紧急制动模式开关";
CM_ SG_ 466 CDCS7_FR_SeatPositionLoadPosition "副驾请求加载位置";
CM_ SG_ 466 CDCS7_Passenger_MassageLevelSet "副驾座椅按摩强度设置";
CM_ SG_ 466 CDCS7_FragranceCtrlReq "香氛状态控制请求";
CM_ SG_ 466 CDCS7_FragranceConcentrationSet "香氛浓度设置";
CM_ SG_ 466 CDCS7_FragrancePositionSet "香氛位置设置";
CM_ SG_ 466 CDCS7_LHTemp "主驾设定温度（大屏）";
CM_ SG_ 466 CDCS7_RHTemp "副驾设定温度（大屏）";
CM_ SG_ 466 CDCS7_BlowerSpdSet "风速设定(大屏)";
CM_ SG_ 466 CDCS7_HeatMaxSW "最大制热请求";
CM_ SG_ 466 CDCS7_FaceFootSW "吹脸吹脚开关";
CM_ SG_ 466 CDCS7_FaceWinSW "吹脸吹窗开关";
CM_ SG_ 466 CDCS7_FootWinSW "吹脚吹窗开关";
CM_ SG_ 466 CDCS7_FaceFootWinSW "吹脸吹脚吹窗开关";
CM_ SG_ 466 CDCS7_FR_SeatEasygetON_OFF_Set "右前座椅便捷进出设置开关";
CM_ SG_ 466 CDCS7_Fragrance_Position_1 "位置1香型";
CM_ SG_ 466 CDCS7_Fragrance_Position_2 "位置2香型";
CM_ SG_ 466 CDCS7_Fragrance_Position_3 "位置3香型";
CM_ SG_ 466 CDCS7_ALH_DriveModeSW "氛围灯驾驶模式设置开关";
CM_ SG_ 466 CDCS7_FRSeatVoiceEZEReq "副驾 EZE 语音请求";
CM_ SG_ 466 CDCS7_FL_RLMotorPosCmd "左前风门左右角度需求";
CM_ SG_ 466 CDCS7_FL_UDMotorPosCmd "左前风门上下角度需求";
CM_ SG_ 466 CDCS7_CL_RLMotorPosCmd "左中风门左右角度需求";
CM_ SG_ 466 CDCS7_CL_UDMotorPosCmd "左中风门上下角度需求";
CM_ SG_ 466 CDCS7_CR_RLMotorPosCmd "右中风门左右角度需求";
CM_ SG_ 466 CDCS7_CR_UDMotorPosCmd "右中风门上下角度需求";
CM_ SG_ 466 CDCS7_FR_RLMotorPosCmd "右前风门左右角度需求";
CM_ SG_ 466 CDCS7_FR_UDMotorPosCmd "右前风门上下角度需求";
CM_ SG_ 466 CDCS7_AQSValue "AQS空气质量";
CM_ SG_ 466 CDCS7_BlowModStsReq "空调出风模式请求";
CM_ SG_ 466 CDCS7_FR_ZeroGravityPause_Req "副驾座椅调节暂停请求";
CM_ SG_ 466 CDCS7_ALHSelectColourCtrl "氛围灯颜色模式";
CM_ SG_ 466 CDCS7_PMAirInQLevel "室内空气质量等级";
CM_ SG_ 466 CDCS7_PM25_Value "PM2.5值";
CM_ SG_ 466 CDCS7_FLSeatVoiceHorizontalAdj "主驾座椅水平位置语音调节";
CM_ SG_ 466 CDCS7_FLSeatVoiceVerticalAdj "主驾座椅垂直高度语音调节";
CM_ SG_ 466 CDCS7_FLSeatVoiceCushionTiltAdj "主驾座椅坐垫倾斜语音调节";
CM_ SG_ 466 CDCS7_FLSeatVoiceBackrestAngletAdj "主驾座椅靠背角度语音调节";
CM_ SG_ 466 CDCS7_FRSeatVoiceHorizontalAdj "副驾座椅水平位置语音调节";
CM_ SG_ 466 CDCS7_FRSeatVoiceVerticalAdj "副驾座椅垂直高度语音调节";
CM_ SG_ 466 CDCS7_FRSeatLegsupporVoiceAdj "副驾座椅腿托语音调节";
CM_ SG_ 466 CDCS7_FRSeatVoiceBackrestAngletAdj "副驾座椅靠背角度语音调节";
CM_ SG_ 468 CDCS5_ResetAllSetup "重置设置的信号";
CM_ SG_ 468 CDCS5_FactoryReset "恢复出厂的信号";
CM_ SG_ 468 CDCS5_RightMirrorAutoTurnDownSw "右外后视镜倒车下翻按键
右外后视镜倒车下调开关";
CM_ SG_ 468 CDCS5_Key_Ventilation_Set "一键通风设置信号";
CM_ SG_ 468 CDCS5_AutoDfrostSw "空调自动除雾开关";
CM_ SG_ 468 CDCS5_AutoDrySw "空调自干燥开关";
CM_ SG_ 468 CDCS5_ChargingLampSwt "充电指示灯开关";
CM_ SG_ 468 CDCS5_MirrorFoldSet "外后视镜折叠设置";
CM_ SG_ 468 CDCS5_StationaryModeSet "静态模式进入/退出设置";
CM_ SG_ 468 CDCS5_LightShowWinDown "灯光秀降窗请求";
CM_ SG_ 468 CDCS_BtmCallAutoSpdSw "蓝牙通话自动降噪开关";
CM_ SG_ 468 CDCS5_AutoAionSw "负离子自动开启开关";
CM_ SG_ 468 CDCS5_AQSConfigSw "AQS防止尾气进入车内开关";
CM_ SG_ 468 CDCS5_CenterLock "中控解闭锁命令";
CM_ SG_ 468 CDCS5_WindowSteam_SET "车窗留缝设置";
CM_ SG_ 468 CDCS5_CoolantFillingReq "冷却液加注请求指令";
CM_ SG_ 468 CDCS5_OutLampControl "组合开关灯光功能";
CM_ SG_ 468 CDCS5_FMHTimeSet "伴我回家时间设置";
CM_ SG_ 468 CDCS5_BiologicalDetectionSw "生物检测开启开关";
CM_ SG_ 468 CDCS5_BDCS_ReclockReqFdb "重新计时请求反馈";
CM_ SG_ 468 CDCS5_ShutDownReq "大屏下电请求";
CM_ SG_ 468 CDCS5_FindMyCarTimeSet "寻车时间设置";
CM_ SG_ 468 CDCS5_BacklightLevel "背光亮度调节";
CM_ SG_ 468 CDCS5_PetToLookAfterReq "爱宠照看模式需求";
CM_ SG_ 468 CDCS5_ChargeLidSw "充电口盖解闭锁开关";
CM_ SG_ 468 CDCS5_SpeedLockReq "自动落锁速度设置";
CM_ SG_ 468 CDCS5_Wiper_maintenancePos_Req "雨刮维修位请求";
CM_ SG_ 468 CDCS5_FindMyCarSet "寻车设置";
CM_ SG_ 468 CDCS5_WelcomeLampMod "迎宾灯模式";
CM_ SG_ 468 CDCS5_AntiTheftRemanderSoundReq "设防成功提示请求";
CM_ SG_ 468 CDCS5_LightShowMod "大灯灯光秀模式";
CM_ SG_ 468 CDCS5_FLHEALamp_Height "调光电机档位信号";
CM_ SG_ 468 CDCS5_PARKUnLockReq "驻车解锁设置";
CM_ SG_ 468 CDCS5_LOGOLampSwt "Logo灯";
CM_ SG_ 468 CDCS5_AUTOHOLDLampSwt "AutoHold灯";
CM_ SG_ 468 CDCS5_ElectronicLock_Pre_theft "电子锁防盗设置";
CM_ SG_ 468 CDCS5_LockUpWindowSET "闭锁升窗开关（选项开关）";
CM_ SG_ 468 CDCS5_MirrorFoldSw "外后视镜折叠展开按键";
CM_ SG_ 468 CDCS5_RL_SafetyLockSw "左后排儿童锁按键";
CM_ SG_ 468 CDCS5_RR_SafetyLockSw "右后排儿童锁按键";
CM_ SG_ 468 CDCS5_RearFogLampSWt "后雾灯开关（软）";
CM_ SG_ 468 CDCS5_WalkMeeting_SW "迎宾灯功能";
CM_ SG_ 468 CDCS5_Induction_PLG_SW "感应电动尾门";
CM_ SG_ 468 CDCS5_Wal_Away_Up_SW "远离闭锁靠近解锁";
CM_ SG_ 468 CDCS5_HighPressureTankUnlockSW "High pressure tank unlock switch
高压燃油口盖解锁命令";
CM_ SG_ 468 CDCS5_ControlFLWindow "语音左前车窗控制";
CM_ SG_ 468 CDCS5_ControlRLWindow "语音左后车窗控制";
CM_ SG_ 468 CDCS5_ControlFRWindow "语音右前车窗控制";
CM_ SG_ 468 CDCS5_ControlRRWindow "语音右后车窗控制";
CM_ SG_ 468 CDCS5_RLSeatBackrestAdjCmd "后排左侧座椅靠背调节";
CM_ SG_ 468 CDCS5_RRSeatBackrestAdjCmd "后排右侧座椅靠背调节";
CM_ SG_ 468 CDCS5_LSD_FL_Away_Up_SW "左前远离关门靠近开门设置";
CM_ SG_ 468 CDCS5_LSD_FR_Away_Up_SW "右前远离关门靠近开门设置";
CM_ SG_ 468 CDCS5_LRSeatHeaterCmd "后排左侧座椅加热指令";
CM_ SG_ 468 CDCS5_RRSeatHeaterCmd "后排右侧座椅加热指令";
CM_ SG_ 468 CDCS5_DGM_IntelligentProtectionSW "天幕智能防护开关";
CM_ SG_ 468 CDCS5_DGM_AutoSW "天幕自动调节开关";
CM_ SG_ 468 CDCS5_FrontDoorOpenModeSet "前门开启方式设置";
CM_ SG_ 468 CDCS5_CabinCleanConfigSW "主动座舱清洁开关";
CM_ SG_ 468 CDCS5_PM25AutoCleanPopup "PM2.5自动净化开关";
CM_ SG_ 468 CDCS5_WindowFollowUpDoorSW "车窗随动车门开关";
CM_ SG_ 468 CDCS5_DoorHandleRetractedOverTimeSW "门把手超时回缩开关";
CM_ SG_ 468 CDCS5_LeftMirrorAutoTurnDownSw "左侧外后视镜倒车下调开关";
CM_ SG_ 468 CDCS5_PAB_OnOffSet "副驾气囊开关";
CM_ SG_ 468 CDCS5_SunRoofCtrlReq "天窗控制请求";
CM_ SG_ 468 CDCS5_SunRoofSLideCtrlReq "天窗开度控制请求";
CM_ SG_ 468 CDCS5_CurtainCtrlReq "遮阳帘控制请求";
CM_ SG_ 468 CDCS5_CurtainSLideCtrlReq "遮阳帘开度控制请求";
CM_ SG_ 468 CDCS5_SunRoofStopCtrlReq "天窗遮阳帘运动停止请求";
CM_ SG_ 468 CDCS5_CarTempHoldModeSw "驻车温度保持功能开关";
CM_ SG_ 468 CDCS5_SmartLightReq "智能灯语请求";
CM_ SG_ 468 CDCS5_NapPositionReset "小憩出厂位置恢复";
CM_ SG_ 468 CDCS5_PLG_DoorHeightSet "后备箱高度设置";
CM_ SG_ 468 CDCS5_RLLumbarUpAndDwnAdioAdj "后排左座椅腰托语音上下调节信号";
CM_ SG_ 468 CDCS5_RoadRecSw "基于路况控制内外循环开关";
CM_ SG_ 468 CDCS5_TrailerModeSw "拖挂模式切换请求";
CM_ SG_ 468 CDCS5_RR_MassageModeSet "后排右座椅按摩模式设置信号";
CM_ SG_ 468 CDCS5_RR_MassageLevelSet "后排右座椅按摩强度设置信号";
CM_ SG_ 468 CDCS5_ZeroGravityPositionReset "零重力座椅位置恢复指令";
CM_ SG_ 468 CDCS5_RL_MassageModeSet "后排左座椅按摩模式设置信号";
CM_ SG_ 468 CDCS5_RL_MassageLevelSet "后排左座椅按摩强度设置信号";
CM_ SG_ 468 CDCS5_RL_SeatVentCmd "后排左座椅通风档位调节信号";
CM_ SG_ 468 CDCS5_RR_SeatVentCmd "后排右座椅通风档位调节信号";
CM_ SG_ 468 CDCS5_RLLumbarFwdBakwdAdioAdj "后排左座椅腰托语音垂直前后调节信号";
CM_ SG_ 468 CDCS5_RRLumbarUpAndDwnAdioAdj "后排右座椅腰托语音上下调节信号";
CM_ SG_ 468 CDCS5_RRLumbarFwdBakwdAdioAdj "后排右座椅腰托语音垂直前后调节信号";
CM_ SG_ 468 CDCS5_WiperNozzleHeatSWt "雨刮喷嘴加热开关";
CM_ SG_ 501 CDCS11_LKSSetspeed "速度设定反馈";
CM_ SG_ 501 CDCS11_LDW_OnOffSet "LKS开启/关闭设置";
CM_ SG_ 501 CDCS11_LowSpeedBSDSw "低速BSD功能开关";
CM_ SG_ 501 CDCS11_FCW_OnOffSet "FCW开启/关闭控制开关";
CM_ SG_ 501 CDCS11_AEB_OnOffSet "AEB开启/关闭控制开关";
CM_ SG_ 501 CDCS11_FCW_WarnTiming "FCW灵敏度设置";
CM_ SG_ 501 CDCS11_FCTA_OnOffSet "FCTA开启/关闭设置";
CM_ SG_ 501 CDCS11_RCTA_OnOffSet "RCTA开启/关闭设置";
CM_ SG_ 501 CDCS11_RCW_OnOffSet "RCW开启/关闭设置";
CM_ SG_ 501 CDCS11_DOW_OnOffSet "DOW开启/关闭设置";
CM_ SG_ 501 CDCS11_IHBC_SysSwState "IHBC mode switch request by driver
智能远光灯功能设置开关";
CM_ SG_ 501 CDCS11_LCA_OnOffSet "LCA开启/关闭设置";
CM_ SG_ 501 CDCS11_TSR_OnOffSet "TSR开启/关闭设置";
CM_ SG_ 501 CDCS11_AVM_3DRotate "3D旋转动画";
CM_ SG_ 501 CDCS11_AVM_Turnlightstart "转向灯开启全景";
CM_ SG_ 501 CDCS11_AVM_Steeringstart "转向角开启全景";
CM_ SG_ 501 CDCS11_AVM_Magnifiedview "自动放大视角开关";
CM_ SG_ 501 CDCS11_AVM_MODdetection "移动物体检测";
CM_ SG_ 501 CDCS11_GM_OnOffSet "哨兵模式开启/关闭设置";
CM_ SG_ 501 CDCS11_NNP_OnOffSet "NNP开启/关闭设置";
CM_ SG_ 501 CDCS11_DCLCSysState "DCLC开启/关闭设置";
CM_ SG_ 501 CDCS11_ALCSysState "ALC开启/关闭设置";
CM_ SG_ 501 CDCS11_DriveOffPossilbeswitch "前车起步提请状态";
CM_ SG_ 501 CDCS11_DriveOffinhibitionswitch "前车起步抑制";
CM_ SG_ 501 CDCS11_ADAS_SndCtrlOnOff "ADAS唤醒语音开关状态";
CM_ SG_ 501 CDCS11_AVM_auxiliaryline "辅助线";
CM_ SG_ 501 CDCS11_AVM_Raderdisplay "雷达显示";
CM_ SG_ 501 CDCS11_AVM_Transparentchassis "透明底盘";
CM_ SG_ 501 CDCS11_VoiceMode "语音播报模式";
CM_ SG_ 501 CDCS11_NNP_Active_OnOffSet "NNP快捷开关";
CM_ SG_ 501 CDCS11_ALC_mode "NNP_ALC自动变道设置";
CM_ SG_ 501 CDCS11_ADSDriving_mode "NNP_自动驾驶风格选项设置";
CM_ SG_ 501 CDCS11_TSR_OverspeedOnoffSet "超速报警开关";
CM_ SG_ 501 CDCS11_NNP_AutoOnOffSet "NNP快捷开关_开启关闭";
CM_ SG_ 501 CDCS11_SnCtrl_NNP_OnOff "NNP语音开启关闭控制";
CM_ SG_ 501 CDCS11_GM_VidedIn "哨兵模式";
CM_ SG_ 501 CDCS11_TSR_SLFOnOffSet "智能限速_开关";
CM_ SG_ 501 CDCS11_APA_FunctionMode "泊车功能模式";
CM_ SG_ 501 CDCS11_TrackreverseSW "循迹倒车开关";
CM_ SG_ 501 CDCS11_SetPathwaySW "路线管理开关";
CM_ SG_ 501 CDCS11_PA_changeLanguage "语言切换";
CM_ SG_ 501 CDCS11_LDP_OnOffSet "LDP开关设置";
CM_ SG_ 501 CDCS11_AVMSw "AVM软开关";
CM_ SG_ 501 CDCS11_tryHPP "记忆泊车试一试按键";
CM_ SG_ 501 CDCS11_NetReset "车机网络重置请求信号";
CM_ SG_ 501 CDCS11_RPASw "RPA软开关";
CM_ SG_ 501 CDCS11_SetSw "设置项开启";
CM_ SG_ 501 CDCS11_SoundCtrlSetReq "语音控制使能开关";
CM_ SG_ 501 CDCS11_location_sw "IHU发出APA定位开启信号";
CM_ SG_ 501 CDCS11_Pathrefresh "更新路线开关";
CM_ SG_ 501 CDCS11_HPAGuideSW "开关，用户选择是否尝试记忆泊车学习";
CM_ SG_ 501 CDCS11_HPAPathwaytoCloudSW "记忆泊车路线学习完成，是否上传开关";
CM_ SG_ 501 CDCS11_PathlearningSw "记忆泊车路线学习开关";
CM_ SG_ 501 CDCS11_PA_screenMd "大屏收到泊车系统状态";
CM_ SG_ 501 CDCS11_PASw "APA软开关";
CM_ SG_ 501 CDCS11_PA_Recover "IHU发出恢复泊车指令";
CM_ SG_ 501 CDCS_Lcsndrequest "语音变道";
CM_ SG_ 501 CDCS_Lcsndconfirm "主动变道驾驶员确认";
CM_ SG_ 501 CDCS_SpdAdaptComfirm "速度匹配确认信号";
CM_ SG_ 501 CDCS_PayModeConfirm "收费站匹配确认信号";
CM_ SG_ 501 CDCS11_SelectSlotID "车位选择信息";
CM_ SG_ 501 CDCS11_ParkingInReq "开始泊入开关";
CM_ SG_ 501 CDCS11_ParkingOutReq "开始泊出开关";
CM_ SG_ 501 CDCS11_AVM_ViewMode "视图显示模式";
CM_ SG_ 501 CDCS11_RPA_FunctionMode "遥控泊车功能模式";
CM_ SG_ 501 CDCS11_AVM_VideoOutputFail "视频输出信号";
CM_ SG_ 501 CDCS11_AVM_Initialization "初始化设置";
CM_ SG_ 501 CDCS11_AVM_bodySync "车身信息同步开关";
CM_ SG_ 501 CDCS11_AVM_licenseplateabbr "车牌照省会简称";
CM_ SG_ 501 CDCS11_AVM_SpeView "特殊视角";
CM_ SG_ 501 CDCS11_AVM_licenseplateArea "省内区域";
CM_ SG_ 501 CDCS11_AVM_StartMode "AVM启动模式设置";
CM_ SG_ 501 CDCS11_AVM_LicensePlateNO1 "车牌照第1位数字";
CM_ SG_ 501 CDCS11_AVM_LicensePlateNO2 "车牌照第2位数字";
CM_ SG_ 501 CDCS11_DrvOffAlertSwitch "起步提醒开关";
CM_ SG_ 501 CDCS11_AVM_LicensePlateNO3 "车牌照第3位数字";
CM_ SG_ 501 CDCS11_DCWposition "开门预警设置";
CM_ SG_ 501 CDCS11_AVM_LicensePlateNO4 "车牌照第4位数字";
CM_ SG_ 501 CDCS11_EOL_Fdbk "EOL反馈";
CM_ SG_ 501 CDCS11_AVM_LicensePlateNO5 "车牌照第5位数字";
CM_ SG_ 501 CDCS11_AVM_LicensePlateNO6 "车牌照第6位数字";
CM_ SG_ 501 CDCS11_DataUp_Trigger "数据上云请求";
CM_ SG_ 501 CDCS11_AVM_LicensePlateNO7 "车牌照第7位数字";
CM_ SG_ 501 CDCS11_AVM_DayNightMode "AVM/APA黑夜/白天显示模式切换";
CM_ SG_ 501 CDCS11_AVM_LicensePlateNO8 "车牌照第8位数字";
CM_ SG_ 501 CDCS11_AVM_Powertype "车辆动力类型";
CM_ SG_ 501 CDCS11_AVM_Diaphaneity "透明度";
CM_ SG_ 501 CDCS11_AVM_DiaphaneitySw "透明度功能开关";
CM_ SG_ 501 CDCS11_LDWLKAAidSwSts "ELKS（LDW+LKA）
紧急车道保持系统(FLC-ME平台专用)";
CM_ SG_ 501 CDCS11_MOD_Sound_Sw "MOD报警设置开关";
CM_ SG_ 501 CDCS11_MOD_BSD_Sw "低速BSD功能";
CM_ SG_ 501 CDCS11_PA_FRS_OnOffSet "前雷达开关";
CM_ SG_ 501 CDCS11_PA_3D_OnOffSet "超声波雷达立体显示开关";
CM_ SG_ 501 CDCS11_PA_measure_OnOffSet "超声波雷达测距显示开关";
CM_ SG_ 501 CDCS11_MODSw "MOD低速动态物体识别设置开关";
CM_ SG_ 501 CDCS11_VoiceNotifFrequency_mode "导航播报模式";
CM_ SG_ 501 CDCS11_ACCOnOffSet "巡航开关信号";
CM_ SG_ 501 CDCS11_HPASw "开启记忆泊车开关";
CM_ SG_ 501 CDCS11_PA_WarningType "泊车报警方式（语音/报警音）切换控制";
CM_ SG_ 501 CDCS11_HPA_OnOffSet "HPA功能设置项开关";
CM_ SG_ 501 CDCS11_DeleteMapID "删除地图ID";
CM_ SG_ 501 CDCS11_UploadMapID "上传地图ID";
CM_ SG_ 501 CDCS11_HPAActiveConfirm "确认注意事项";
CM_ SG_ 501 CDCS11_TSR_ALSUpdataSwState "TSR mode switch of speed limits update request by driver TSR限速更新声音开关(FLC-ME平台专用)";
CM_ SG_ 501 CDCS11_HPApreparkingSw "记忆泊车快捷开关";
CM_ SG_ 501 CDCS11_HPAPathwaytoCloud_WorkSts "路线上传开关状态";
CM_ SG_ 501 CDCS11_TSR_SLWFVoiceSwState "超速提醒SLWF功能设置开关(FLC-ME平台专用)";
CM_ SG_ 501 CDCS11_ELKA_OnOffSet "ELKA功能设置开关(FLC-ME平台专用)";
CM_ SG_ 501 CDCS11_Pathrelearn "NTP新增重新学习按钮信号";
CM_ SG_ 501 CDCS11_HPA_ONPath_ID1 "CDCS反馈选中记忆泊车路线ID1信号";
CM_ SG_ 501 CDCS11_HPA_ONPath_ID2 "CDCS反馈选中记忆泊车路线ID2信号";
CM_ SG_ 501 CDCS11_HPA_ONPath_ID3 "CDCS反馈选中记忆泊车路线ID3信号";
CM_ SG_ 501 CDCS11_HPA_ONPath_ID4 "CDCS反馈选中记忆泊车路线ID4信号";
CM_ SG_ 501 CDCS11_HPA_Select_ID "选择HPA路线ID";
CM_ SG_ 501 CDCS11_PA_Select_ID "CDCS发送车端选择车位信息";
CM_ SG_ 501 CDCS11_learnpath_St "记忆泊车路线学习后用户操作状态";
CM_ SG_ 501 CDCS11_LDWLKA_WarnTiming "车道偏离灵敏度设置";
CM_ SG_ 501 CDCS11_TSR_LimitOverspeedSet "交通标志识别（TSR）增加用户可设置限定的超速值，进行超速报警提醒";
CM_ SG_ 501 CDCS11_FrbdWindowOpen_Req "儿童关怀功能请求车窗锁开关";
CM_ SG_ 501 CDCS11_ParkingoutSlot_Type "自选车位类型";
CM_ SG_ 501 CDCS11_ParkingoutSlot_Dire "自选车位方向";
CM_ SG_ 501 CDCS11_OptionalSlot_Type "自选车位类型";
CM_ SG_ 501 CDCS11_OptionalSlot_Dire "自选车位方向";
CM_ SG_ 501 CDCS11_OptionalSlotAngle "自选车位角度";
CM_ SG_ 501 CDCS11_OptionalSlotCoor_P0_X "自选车位功能四角坐标信息";
CM_ SG_ 501 CDCS11_OptionalSlotCoor_P0_Y "自选车位功能四角坐标信息";
CM_ SG_ 501 CDCS11_OptionalSlotCoor_P1_X "自选车位功能四角坐标信息";
CM_ SG_ 501 CDCS11_OptionalSlotCoor_P1_Y "自选车位功能四角坐标信息";
CM_ SG_ 501 CDCS11_OptionalSlotCoor_P2_X "自选车位功能四角坐标信息";
CM_ SG_ 501 CDCS11_OptionalSlotCoor_P2_Y "自选车位功能四角坐标信息";
CM_ SG_ 501 CDCS11_OptionalSlotCoor_P3_X "自选车位功能四角坐标信息";
CM_ SG_ 501 CDCS11_OptionalSlotCoor_P3_Y "自选车位功能四角坐标信息";

BA_DEF_ BO_ "CANFD_BRS" ENUM "0","1";
BA_DEF_ BO_ "GenMsgSendType" ENUM "Cycle","NoMsgSendType","IfActive","Event","CA","CE";
BA_DEF_ BO_ "GenMsgNrOfRepetition" INT 0 0;
BA_DEF_ BO_ "GenMsgILSupport" ENUM "No","Yes";
BA_DEF_ BO_ "GenMsgDelayTime" INT 0 0;
BA_DEF_ BO_ "GenMsgCycleTimeFast" INT 0 0;
BA_DEF_ BO_ "GenMsgCycleTime" INT 0 0;
BA_DEF_ BO_ "DiagResponse" ENUM "No","Yes";
BA_DEF_ BO_ "DiagRequest" ENUM "No","Yes";
BA_DEF_ BO_ "NmMessage" ENUM "No","Yes";
BA_DEF_ BO_ "VFrameFormat" ENUM "StandardCAN","ExtendedCAN","reserved","J1939PG","reserved","reserved","reserved","reserved","reserved","reserved","reserved","reserved","reserved","reserved","StandardCAN_FD","ExtendedCAN_FD";
BA_DEF_ SG_ "GenSigInvalidValue" HEX 0 0;
BA_DEF_ SG_ "GenSigStartValue" HEX 0 0;
BA_DEF_ SG_ "GenSigSendType" ENUM "Cycle","OnWrite","OnWriteWithRepetition","OnChange","OnChangeWithRepetition","IfActive","IfActiveWithRepetition","NoSigSendType","vector_leerstring";
BA_DEF_DEF_ "CANFD_BRS" "1";
BA_DEF_DEF_ "GenMsgSendType" "Cycle";
BA_DEF_DEF_ "GenMsgNrOfRepetition" 0;
BA_DEF_DEF_ "GenMsgILSupport" "Yes";
BA_DEF_DEF_ "GenMsgDelayTime" 0;
BA_DEF_DEF_ "GenMsgCycleTimeFast" 0;
BA_DEF_DEF_ "GenMsgCycleTime" 0;
BA_DEF_DEF_ "DiagResponse" "No";
BA_DEF_DEF_ "DiagRequest" "No";
BA_DEF_DEF_ "NmMessage" "No";
BA_DEF_DEF_ "VFrameFormat" "StandardCAN";
BA_DEF_DEF_ "GenSigInvalidValue" 0;
BA_DEF_DEF_ "GenSigStartValue" 0;
BA_DEF_DEF_ "GenSigSendType" "Cycle";
BA_ "GenMsgCycleTime" BO_ 993 1000;
BA_ "VFrameFormat" BO_ 993 14;
BA_ "GenMsgCycleTime" BO_ 1008 1000;
BA_ "VFrameFormat" BO_ 1008 14;
BA_ "GenMsgCycleTime" BO_ 1538 500;
BA_ "NmMessage" BO_ 1538 1;
BA_ "GenMsgCycleTime" BO_ 1664 10;
BA_ "VFrameFormat" BO_ 1664 14;
BA_ "GenMsgCycleTime" BO_ 1665 10;
BA_ "VFrameFormat" BO_ 1665 14;
BA_ "GenMsgCycleTime" BO_ 418 50;
BA_ "VFrameFormat" BO_ 418 14;
BA_ "GenMsgNrOfRepetition" BO_ 858 3;
BA_ "GenMsgCycleTimeFast" BO_ 858 20;
BA_ "GenMsgSendType" BO_ 858 3;
BA_ "VFrameFormat" BO_ 858 14;
BA_ "GenMsgCycleTime" BO_ 1550 500;
BA_ "NmMessage" BO_ 1550 1;
BA_ "GenMsgCycleTime" BO_ 419 50;
BA_ "VFrameFormat" BO_ 419 14;
BA_ "GenMsgNrOfRepetition" BO_ 859 3;
BA_ "GenMsgCycleTimeFast" BO_ 859 20;
BA_ "GenMsgSendType" BO_ 859 3;
BA_ "VFrameFormat" BO_ 859 14;
BA_ "GenMsgCycleTime" BO_ 1549 500;
BA_ "NmMessage" BO_ 1549 1;
BA_ "GenMsgCycleTime" BO_ 928 500;
BA_ "VFrameFormat" BO_ 928 14;
BA_ "GenMsgCycleTime" BO_ 1609 500;
BA_ "NmMessage" BO_ 1609 1;
BA_ "GenMsgCycleTime" BO_ 243 20;
BA_ "VFrameFormat" BO_ 243 14;
BA_ "GenMsgNrOfRepetition" BO_ 498 3;
BA_ "GenMsgCycleTimeFast" BO_ 498 50;
BA_ "GenMsgSendType" BO_ 498 3;
BA_ "VFrameFormat" BO_ 498 14;
BA_ "GenMsgNrOfRepetition" BO_ 755 3;
BA_ "GenMsgCycleTime" BO_ 755 100;
BA_ "GenMsgCycleTimeFast" BO_ 755 20;
BA_ "GenMsgSendType" BO_ 755 5;
BA_ "VFrameFormat" BO_ 755 14;
BA_ "GenMsgCycleTime" BO_ 756 100;
BA_ "VFrameFormat" BO_ 756 14;
BA_ "GenMsgSendType" BO_ 980 2;
BA_ "VFrameFormat" BO_ 980 14;
BA_ "GenMsgCycleTime" BO_ 612 100;
BA_ "VFrameFormat" BO_ 612 14;
BA_ "GenMsgNrOfRepetition" BO_ 320 3;
BA_ "GenMsgCycleTimeFast" BO_ 320 20;
BA_ "GenMsgSendType" BO_ 320 3;
BA_ "VFrameFormat" BO_ 320 14;
BA_ "GenMsgCycleTime" BO_ 442 50;
BA_ "VFrameFormat" BO_ 442 14;
BA_ "GenMsgCycleTime" BO_ 444 50;
BA_ "VFrameFormat" BO_ 444 14;
BA_ "GenMsgCycleTime" BO_ 443 100;
BA_ "VFrameFormat" BO_ 443 14;
BA_ "GenMsgCycleTime" BO_ 794 200;
BA_ "VFrameFormat" BO_ 794 14;
BA_ "GenMsgNrOfRepetition" BO_ 466 3;
BA_ "GenMsgCycleTimeFast" BO_ 466 20;
BA_ "GenMsgSendType" BO_ 466 3;
BA_ "VFrameFormat" BO_ 466 14;
BA_ "GenMsgNrOfRepetition" BO_ 468 3;
BA_ "GenMsgCycleTimeFast" BO_ 468 20;
BA_ "GenMsgSendType" BO_ 468 3;
BA_ "VFrameFormat" BO_ 468 14;
BA_ "GenMsgNrOfRepetition" BO_ 501 3;
BA_ "GenMsgCycleTimeFast" BO_ 501 20;
BA_ "GenMsgSendType" BO_ 501 3;
BA_ "VFrameFormat" BO_ 501 14;
BA_ "GenSigInvalidValue" SG_ 418 DDCU1_FL_WinPos 255;
BA_ "GenSigInvalidValue" SG_ 418 DDCU1_RL_WinPos 255;
BA_ "GenSigStartValue" SG_ 418 DDCU1_RL_SafetyLockFdbk 1;
BA_ "GenSigStartValue" SG_ 418 DDCU1_MirrorFoldSet_fdbk 1;
BA_ "GenSigInvalidValue" SG_ 858 DDCU_OTA__FL_WinPos 255;
BA_ "GenSigSendType" SG_ 858 DDCU_OTA__FL_WinPos 3;
BA_ "GenSigInvalidValue" SG_ 858 DDCU_OTA__RL_WinPos 255;
BA_ "GenSigSendType" SG_ 858 DDCU_OTA__RL_WinPos 3;
BA_ "GenSigSendType" SG_ 858 DDCU_OTA__FLDoorAjar 3;
BA_ "GenSigSendType" SG_ 858 DDCU_OTA__RLDoorAjar 3;
BA_ "GenSigSendType" SG_ 858 DDCU_OTA_CentralLockSts 3;
BA_ "GenSigSendType" SG_ 858 DDCU_OTA_FRWindowsCtrl 3;
BA_ "GenSigSendType" SG_ 858 DDCU_OTA_RRWindowsCtrl 3;
BA_ "GenSigSendType" SG_ 858 DDCU_OTA_ControlWindowLockSw 3;
BA_ "GenSigSendType" SG_ 858 DDCU_OTA_FL_LockSt 3;
BA_ "GenSigSendType" SG_ 858 DDCU_OTA_RL_LockSt 3;
BA_ "GenSigSendType" SG_ 858 DDCU_OTA_MirrorFoldSt 3;
BA_ "GenSigInvalidValue" SG_ 419 PDCU1_FR_WinPos 255;
BA_ "GenSigInvalidValue" SG_ 419 PDCU1_RR_WinPos 255;
BA_ "GenSigStartValue" SG_ 419 PDCU1_RR_SafetyLockFdbk 1;
BA_ "GenSigInvalidValue" SG_ 859 PDCU_OTA_FR_WinPos 255;
BA_ "GenSigSendType" SG_ 859 PDCU_OTA_FR_WinPos 3;
BA_ "GenSigInvalidValue" SG_ 859 PDCU_OTA_RR_WinPos 255;
BA_ "GenSigSendType" SG_ 859 PDCU_OTA_RR_WinPos 3;
BA_ "GenSigSendType" SG_ 859 PDCU_OTA_FRDoorAjar 3;
BA_ "GenSigSendType" SG_ 859 PDCU_OTA_RRDoorAjar 3;
BA_ "GenSigSendType" SG_ 859 PDCU_OTA_FR_LockSt 3;
BA_ "GenSigSendType" SG_ 859 PDCU_OTA_RR_LockSt 3;
BA_ "GenSigSendType" SG_ 498 BTM3_ArmingCmd 5;
BA_ "GenSigSendType" SG_ 498 BTM3_TrunkCmd 5;
BA_ "GenSigSendType" SG_ 498 BTM3_RKECmd 5;
BA_ "GenSigSendType" SG_ 498 BTM3_Chargingflapcmd 5;
BA_ "GenSigSendType" SG_ 498 BTM3_WelcomeLampCmd 5;
BA_ "GenSigSendType" SG_ 498 BTM3_CLM_OnoffCmd 5;
BA_ "GenSigSendType" SG_ 498 BTM3_Remote_ControlCmd 5;
BA_ "GenSigSendType" SG_ 498 BTM3_RL_Window_Control_Cmd 5;
BA_ "GenSigSendType" SG_ 498 BTM3_RR_Window_Control_Cmd 5;
BA_ "GenSigSendType" SG_ 498 BTM3_CLM_ACCmd 5;
BA_ "GenSigSendType" SG_ 498 BTM3_FL_Window_Control_Cmd 5;
BA_ "GenSigSendType" SG_ 498 BTM3_FR_Window_Control_Cmd 5;
BA_ "GenSigSendType" SG_ 498 BTM3_CLM_PTCCmd 5;
BA_ "GenSigInvalidValue" SG_ 498 BTM3_CLM_BlowerSpdSet 15;
BA_ "GenSigSendType" SG_ 498 BTM3_CLM_BlowerSpdSet 5;
BA_ "GenSigSendType" SG_ 498 BTM3_CLM_RHTempSet 5;
BA_ "GenSigSendType" SG_ 498 BTM3_CLM_LHTempSet 5;
BA_ "GenSigSendType" SG_ 498 BTM3_Charging_cmd 5;
BA_ "GenSigSendType" SG_ 498 BTM3_OpenFLDoorReq 5;
BA_ "GenSigSendType" SG_ 498 BTM3_All_Window_Closd_Cmd 5;
BA_ "GenSigSendType" SG_ 498 BTM3_All_Window_Open_Cmd 5;
BA_ "GenSigSendType" SG_ 498 BTM3_All_Window_Ventilate_Cmd 5;
BA_ "GenSigSendType" SG_ 498 BTM3_OpenFLFRDoorReq 5;
BA_ "GenSigSendType" SG_ 498 BTM3_OpenFRDoorReq 5;
BA_ "GenSigSendType" SG_ 755 BTM4_Key_Sts 2;
BA_ "GenSigSendType" SG_ 755 BTM4_SunroofCtrl 2;
BA_ "GenSigStartValue" SG_ 756 BLE_Smartkey_Battery_Lev 100;
BA_ "GenSigSendType" SG_ 980 BTM_Resp_EncrData0 5;
BA_ "GenSigSendType" SG_ 980 BTM_Resp_EncrData1 5;
BA_ "GenSigSendType" SG_ 980 BTM_Resp_EncrData2 5;
BA_ "GenSigSendType" SG_ 980 BTM_Resp_EncrData3 5;
BA_ "GenSigSendType" SG_ 980 BTM_Resp_EncrData4 5;
BA_ "GenSigSendType" SG_ 980 BTM_Resp_EncrData5 5;
BA_ "GenSigSendType" SG_ 980 BTM_Resp_EncrData6 5;
BA_ "GenSigSendType" SG_ 980 BTM_Resp_EncrData7 5;
BA_ "GenSigSendType" SG_ 320 CDCS3_FailSts 2;
BA_ "GenSigSendType" SG_ 320 CDCS3_ChargeConnKpTempSw 2;
BA_ "GenSigSendType" SG_ 320 CDCS3_EnergyRecLevelSet 2;
BA_ "GenSigSendType" SG_ 320 CDCS3_ePedalSw 2;
BA_ "GenSigSendType" SG_ 320 CDCS3_StopModeReq 2;
BA_ "GenSigSendType" SG_ 320 CDCS3_ESCOffSw 2;
BA_ "GenSigSendType" SG_ 320 CDCS3_EPSModeSet 2;
BA_ "GenSigSendType" SG_ 320 CDCS3_RangeModeReq 2;
BA_ "GenSigSendType" SG_ 320 CDCS3_HDCSw 2;
BA_ "GenSigSendType" SG_ 320 CDCS3_Refuelrequest 2;
BA_ "GenSigSendType" SG_ 320 CDCS3_CDCModeSet 4;
BA_ "GenSigSendType" SG_ 320 CDCS3_EnginIdingldleSet 4;
BA_ "GenSigSendType" SG_ 320 CDCS3_TractionModeSw 2;
BA_ "GenSigSendType" SG_ 320 CDCS3_AVHSw 2;
BA_ "GenSigSendType" SG_ 320 CDCS3_EPBSw 2;
BA_ "GenSigSendType" SG_ 320 CDCS3_CSTSw 2;
BA_ "GenSigSendType" SG_ 320 CDCS3_DriveModeSet 2;
BA_ "GenSigSendType" SG_ 320 CDCS3_BrakestyleSw 2;
BA_ "GenSigSendType" SG_ 320 CDCS3_Force_Refuelrequ 2;
BA_ "GenSigSendType" SG_ 320 CDCS3_EVModeRexOnAllowed 2;
BA_ "GenSigSendType" SG_ 320 CDCS3_PREMModeSet 2;
BA_ "GenSigSendType" SG_ 320 CDCS3_RexModeSet 2;
BA_ "GenSigStartValue" SG_ 320 CDCS3_Xcoordinate 65535;
BA_ "GenSigSendType" SG_ 320 CDCS3_Xcoordinate 2;
BA_ "GenSigStartValue" SG_ 320 CDCS3_Ycoordinate 65535;
BA_ "GenSigSendType" SG_ 320 CDCS3_Ycoordinate 2;
BA_ "GenSigStartValue" SG_ 320 CDCS3_XGestureSpd 255;
BA_ "GenSigSendType" SG_ 320 CDCS3_XGestureSpd 2;
BA_ "GenSigStartValue" SG_ 320 CDCS3_YGestureSpd 255;
BA_ "GenSigSendType" SG_ 320 CDCS3_YGestureSpd 2;
BA_ "GenSigSendType" SG_ 320 CDCS3_TouchEvtTyp 2;
BA_ "GenSigSendType" SG_ 320 CDCS3_REXchargSet 2;
BA_ "GenSigSendType" SG_ 320 CDCS3_ForceChargingLevelSet 2;
BA_ "GenSigStartValue" SG_ 442 CDCS10_Slot0_Volume 8;
BA_ "GenSigStartValue" SG_ 442 CDCS10_Slot1_Volume 8;
BA_ "GenSigStartValue" SG_ 442 CDCS10_Slot2_Volume 8;
BA_ "GenSigStartValue" SG_ 442 CDCS10_Slot3_Volume 8;
BA_ "GenSigStartValue" SG_ 442 CDCS10_Slot4_Volume 8;
BA_ "GenSigStartValue" SG_ 442 CDCS10_Slot5_Volume 8;
BA_ "GenSigStartValue" SG_ 442 CDCS10_Slot6_Volume 8;
BA_ "GenSigStartValue" SG_ 442 CDCS10_Slot7_Volume 8;
BA_ "GenSigStartValue" SG_ 442 CDCS10_AUD_Mute 1;
BA_ "GenSigStartValue" SG_ 444 CDCS10_Slot8_Volume 8;
BA_ "GenSigStartValue" SG_ 444 CDCS10_Slot9_Volume 8;
BA_ "GenSigStartValue" SG_ 444 CDCS10_Slot10_Volume 8;
BA_ "GenSigStartValue" SG_ 444 CDCS10_Slot11_Volume 8;
BA_ "GenSigStartValue" SG_ 444 CDCS10_Slot12_Volume 8;
BA_ "GenSigStartValue" SG_ 444 CDCS10_Slot13_Volume 8;
BA_ "GenSigStartValue" SG_ 444 CDCS10_Slot14_Volume 8;
BA_ "GenSigStartValue" SG_ 444 CDCS10_Slot15_Volume 8;
BA_ "GenSigInvalidValue" SG_ 794 CDCS19_Trip_AfterStart 1048575;
BA_ "GenSigInvalidValue" SG_ 794 CDCS19_Trip_AfterReset 1048575;
BA_ "GenSigInvalidValue" SG_ 794 CDCS19_TripEnergyConsump_AfterStart 4095;
BA_ "GenSigInvalidValue" SG_ 794 CDCS19_TripEnergyConsump_AfterReset 4095;
BA_ "GenSigInvalidValue" SG_ 794 CDCS19_TripDriveTime_AfterStart 65535;
BA_ "GenSigInvalidValue" SG_ 794 CDCS19_TripDriveTime_AfterReset 65535;
BA_ "GenSigInvalidValue" SG_ 794 CDCS19_AvgSpd_AfterStart 255;
BA_ "GenSigInvalidValue" SG_ 794 CDCS19_AvgSpd_AfterReset 255;
BA_ "GenSigInvalidValue" SG_ 794 CDCS19_TripFuelConsump_AfterStart 4095;
BA_ "GenSigInvalidValue" SG_ 794 CDCS19_TripFuelConsump_AfterReset 4095;
BA_ "GenSigSendType" SG_ 466 CDCS7_ALHMusicMode_Working 2;
BA_ "GenSigSendType" SG_ 466 CDCS7_ALH_SW 2;
BA_ "GenSigSendType" SG_ 466 CDCS7_ALHSelectModeCtrl 2;
BA_ "GenSigSendType" SG_ 466 CDCS7_ALH_RValueCmd 2;
BA_ "GenSigSendType" SG_ 466 CDCS7_ALH_GValueCmd 2;
BA_ "GenSigSendType" SG_ 466 CDCS7_ALH_BValueCmd 2;
BA_ "GenSigSendType" SG_ 466 CDCS7_ALH_BrightnessCm 2;
BA_ "GenSigSendType" SG_ 466 CDCS7_FL_SeatPositionMemoryPosition 2;
BA_ "GenSigSendType" SG_ 466 CDCS7_FL_SeatPositionMemory_Req 2;
BA_ "GenSigSendType" SG_ 466 CDCS7_FL_SeatEasygetON_OFF_Set 2;
BA_ "GenSigSendType" SG_ 466 CDCS7_FR_SeatPositionMemory_Req 2;
BA_ "GenSigSendType" SG_ 466 CDCS7_FL_SeatPositionLoad_Req 2;
BA_ "GenSigSendType" SG_ 466 CDCS7_PositionMemoryUnbind_Req 2;
BA_ "GenSigSendType" SG_ 466 CDCS7_FL_SeatPositionLoadPosition 2;
BA_ "GenSigSendType" SG_ 466 CDCS7_PosMemoryUnbindAccount 2;
BA_ "GenSigSendType" SG_ 466 CDCS7_PositionMode 2;
BA_ "GenSigSendType" SG_ 466 CDCS7_InteriorLightingReq 2;
BA_ "GenSigSendType" SG_ 466 CDCS7_DGSW 2;
BA_ "GenSigSendType" SG_ 466 CDCS7_FR_SeatPositionMemoryPosition 2;
BA_ "GenSigSendType" SG_ 466 CDCS7_FR_SeatPositionLoad_Req 2;
BA_ "GenSigSendType" SG_ 466 CDCS7_DGSWLevel 2;
BA_ "GenSigSendType" SG_ 466 CDCS7_Driver_MassageModeSet 2;
BA_ "GenSigSendType" SG_ 466 CDCS7_ALH_EntryMode 2;
BA_ "GenSigSendType" SG_ 466 CDCS7_Passenger_MassageModeSet 2;
BA_ "GenSigSendType" SG_ 466 CDCS7_Driver_MassageLevelSet 2;
BA_ "GenSigSendType" SG_ 466 CDCS7_ALH_AEBMode 2;
BA_ "GenSigSendType" SG_ 466 CDCS7_FR_SeatPositionLoadPosition 2;
BA_ "GenSigSendType" SG_ 466 CDCS7_Passenger_MassageLevelSet 2;
BA_ "GenSigSendType" SG_ 466 CDCS7_FragranceCtrlReq 2;
BA_ "GenSigSendType" SG_ 466 CDCS7_FragranceConcentrationSet 2;
BA_ "GenSigSendType" SG_ 466 CDCS7_FragrancePositionSet 2;
BA_ "GenSigInvalidValue" SG_ 466 CDCS7_LHTemp 255;
BA_ "GenSigSendType" SG_ 466 CDCS7_LHTemp 2;
BA_ "GenSigInvalidValue" SG_ 466 CDCS7_RHTemp 255;
BA_ "GenSigSendType" SG_ 466 CDCS7_RHTemp 2;
BA_ "GenSigInvalidValue" SG_ 466 CDCS7_BlowerSpdSet 15;
BA_ "GenSigSendType" SG_ 466 CDCS7_BlowerSpdSet 2;
BA_ "GenSigSendType" SG_ 466 CDCS7_HeatMaxSW 2;
BA_ "GenSigSendType" SG_ 466 CDCS7_FaceFootSW 2;
BA_ "GenSigSendType" SG_ 466 CDCS7_FaceWinSW 2;
BA_ "GenSigSendType" SG_ 466 CDCS7_FootWinSW 2;
BA_ "GenSigSendType" SG_ 466 CDCS7_FaceFootWinSW 2;
BA_ "GenSigSendType" SG_ 466 CDCS7_FR_SeatEasygetON_OFF_Set 2;
BA_ "GenSigSendType" SG_ 466 CDCS7_Fragrance_Position_1 2;
BA_ "GenSigSendType" SG_ 466 CDCS7_Fragrance_Position_2 2;
BA_ "GenSigSendType" SG_ 466 CDCS7_Fragrance_Position_3 2;
BA_ "GenSigSendType" SG_ 466 CDCS7_ALH_DriveModeSW 2;
BA_ "GenSigSendType" SG_ 466 CDCS7_FRSeatVoiceEZEReq 2;
BA_ "GenSigSendType" SG_ 466 CDCS7_FL_RLMotorPosCmd 2;
BA_ "GenSigSendType" SG_ 466 CDCS7_FL_UDMotorPosCmd 2;
BA_ "GenSigSendType" SG_ 466 CDCS7_CL_RLMotorPosCmd 2;
BA_ "GenSigSendType" SG_ 466 CDCS7_CL_UDMotorPosCmd 2;
BA_ "GenSigSendType" SG_ 466 CDCS7_CR_RLMotorPosCmd 2;
BA_ "GenSigSendType" SG_ 466 CDCS7_CR_UDMotorPosCmd 2;
BA_ "GenSigSendType" SG_ 466 CDCS7_FR_RLMotorPosCmd 2;
BA_ "GenSigSendType" SG_ 466 CDCS7_FR_UDMotorPosCmd 2;
BA_ "GenSigSendType" SG_ 466 CDCS7_AQSValue 2;
BA_ "GenSigSendType" SG_ 466 CDCS7_BlowModStsReq 2;
BA_ "GenSigSendType" SG_ 466 CDCS7_FR_ZeroGravityPause_Req 2;
BA_ "GenSigSendType" SG_ 466 CDCS7_ALHSelectColourCtrl 2;
BA_ "GenSigInvalidValue" SG_ 466 CDCS7_PMAirInQLevel 7;
BA_ "GenSigSendType" SG_ 466 CDCS7_PMAirInQLevel 2;
BA_ "GenSigSendType" SG_ 466 CDCS7_PM25_Value 2;
BA_ "GenSigSendType" SG_ 466 CDCS7_FLSeatVoiceHorizontalAdj 2;
BA_ "GenSigSendType" SG_ 466 CDCS7_FLSeatVoiceVerticalAdj 2;
BA_ "GenSigSendType" SG_ 466 CDCS7_FLSeatVoiceCushionTiltAdj 2;
BA_ "GenSigSendType" SG_ 466 CDCS7_FLSeatVoiceBackrestAngletAdj 2;
BA_ "GenSigSendType" SG_ 466 CDCS7_FRSeatVoiceHorizontalAdj 2;
BA_ "GenSigSendType" SG_ 466 CDCS7_FRSeatVoiceVerticalAdj 2;
BA_ "GenSigSendType" SG_ 466 CDCS7_FRSeatLegsupporVoiceAdj 2;
BA_ "GenSigSendType" SG_ 466 CDCS7_FRSeatVoiceBackrestAngletAdj 2;
BA_ "GenSigSendType" SG_ 468 CDCS5_ResetAllSetup 2;
BA_ "GenSigSendType" SG_ 468 CDCS5_FactoryReset 2;
BA_ "GenSigSendType" SG_ 468 CDCS5_RightMirrorAutoTurnDownSw 2;
BA_ "GenSigSendType" SG_ 468 CDCS5_Key_Ventilation_Set 2;
BA_ "GenSigSendType" SG_ 468 CDCS5_AutoDfrostSw 2;
BA_ "GenSigSendType" SG_ 468 CDCS5_AutoDrySw 2;
BA_ "GenSigSendType" SG_ 468 CDCS5_ChargingLampSwt 2;
BA_ "GenSigSendType" SG_ 468 CDCS5_MirrorFoldSet 2;
BA_ "GenSigSendType" SG_ 468 CDCS5_StationaryModeSet 2;
BA_ "GenSigSendType" SG_ 468 CDCS5_LightShowWinDown 2;
BA_ "GenSigSendType" SG_ 468 CDCS_BtmCallAutoSpdSw 2;
BA_ "GenSigSendType" SG_ 468 CDCS5_AutoAionSw 2;
BA_ "GenSigSendType" SG_ 468 CDCS5_AQSConfigSw 2;
BA_ "GenSigSendType" SG_ 468 CDCS5_CenterLock 2;
BA_ "GenSigSendType" SG_ 468 CDCS5_WindowSteam_SET 2;
BA_ "GenSigSendType" SG_ 468 CDCS5_CoolantFillingReq 2;
BA_ "GenSigSendType" SG_ 468 CDCS5_OutLampControl 2;
BA_ "GenSigSendType" SG_ 468 CDCS5_FMHTimeSet 2;
BA_ "GenSigSendType" SG_ 468 CDCS5_BiologicalDetectionSw 2;
BA_ "GenSigSendType" SG_ 468 CDCS5_BDCS_ReclockReqFdb 2;
BA_ "GenSigSendType" SG_ 468 CDCS5_ShutDownReq 2;
BA_ "GenSigSendType" SG_ 468 CDCS5_FindMyCarTimeSet 2;
BA_ "GenSigSendType" SG_ 468 CDCS5_BacklightLevel 2;
BA_ "GenSigSendType" SG_ 468 CDCS5_PetToLookAfterReq 2;
BA_ "GenSigSendType" SG_ 468 CDCS5_ChargeLidSw 2;
BA_ "GenSigSendType" SG_ 468 CDCS5_SpeedLockReq 2;
BA_ "GenSigSendType" SG_ 468 CDCS5_Wiper_maintenancePos_Req 2;
BA_ "GenSigSendType" SG_ 468 CDCS5_FindMyCarSet 2;
BA_ "GenSigSendType" SG_ 468 CDCS5_WelcomeLampMod 2;
BA_ "GenSigSendType" SG_ 468 CDCS5_AntiTheftRemanderSoundReq 2;
BA_ "GenSigStartValue" SG_ 468 CDCS5_LightShowMod 31;
BA_ "GenSigSendType" SG_ 468 CDCS5_LightShowMod 2;
BA_ "GenSigSendType" SG_ 468 CDCS5_FLHEALamp_Height 2;
BA_ "GenSigSendType" SG_ 468 CDCS5_PARKUnLockReq 2;
BA_ "GenSigSendType" SG_ 468 CDCS5_LOGOLampSwt 2;
BA_ "GenSigSendType" SG_ 468 CDCS5_AUTOHOLDLampSwt 2;
BA_ "GenSigSendType" SG_ 468 CDCS5_ElectronicLock_Pre_theft 2;
BA_ "GenSigSendType" SG_ 468 CDCS5_LockUpWindowSET 2;
BA_ "GenSigSendType" SG_ 468 CDCS5_MirrorFoldSw 2;
BA_ "GenSigSendType" SG_ 468 CDCS5_RL_SafetyLockSw 2;
BA_ "GenSigSendType" SG_ 468 CDCS5_RR_SafetyLockSw 2;
BA_ "GenSigSendType" SG_ 468 CDCS5_RearFogLampSWt 2;
BA_ "GenSigSendType" SG_ 468 CDCS5_WalkMeeting_SW 2;
BA_ "GenSigSendType" SG_ 468 CDCS5_Induction_PLG_SW 2;
BA_ "GenSigSendType" SG_ 468 CDCS5_Wal_Away_Up_SW 2;
BA_ "GenSigSendType" SG_ 468 CDCS5_HighPressureTankUnlockSW 2;
BA_ "GenSigStartValue" SG_ 468 CDCS5_ControlFLWindow 101;
BA_ "GenSigSendType" SG_ 468 CDCS5_ControlFLWindow 2;
BA_ "GenSigStartValue" SG_ 468 CDCS5_ControlRLWindow 101;
BA_ "GenSigSendType" SG_ 468 CDCS5_ControlRLWindow 2;
BA_ "GenSigStartValue" SG_ 468 CDCS5_ControlFRWindow 101;
BA_ "GenSigSendType" SG_ 468 CDCS5_ControlFRWindow 2;
BA_ "GenSigStartValue" SG_ 468 CDCS5_ControlRRWindow 101;
BA_ "GenSigSendType" SG_ 468 CDCS5_ControlRRWindow 2;
BA_ "GenSigSendType" SG_ 468 CDCS5_RLSeatBackrestAdjCmd 2;
BA_ "GenSigSendType" SG_ 468 CDCS5_RRSeatBackrestAdjCmd 2;
BA_ "GenSigSendType" SG_ 468 CDCS5_LSD_FL_Away_Up_SW 2;
BA_ "GenSigSendType" SG_ 468 CDCS5_LSD_FR_Away_Up_SW 2;
BA_ "GenSigSendType" SG_ 468 CDCS5_LRSeatHeaterCmd 2;
BA_ "GenSigSendType" SG_ 468 CDCS5_RRSeatHeaterCmd 2;
BA_ "GenSigSendType" SG_ 468 CDCS5_DGM_IntelligentProtectionSW 2;
BA_ "GenSigSendType" SG_ 468 CDCS5_DGM_AutoSW 2;
BA_ "GenSigSendType" SG_ 468 CDCS5_FrontDoorOpenModeSet 2;
BA_ "GenSigSendType" SG_ 468 CDCS5_CabinCleanConfigSW 2;
BA_ "GenSigSendType" SG_ 468 CDCS5_PM25AutoCleanPopup 2;
BA_ "GenSigSendType" SG_ 468 CDCS5_WindowFollowUpDoorSW 2;
BA_ "GenSigSendType" SG_ 468 CDCS5_DoorHandleRetractedOverTimeSW 2;
BA_ "GenSigSendType" SG_ 468 CDCS5_LeftMirrorAutoTurnDownSw 2;
BA_ "GenSigSendType" SG_ 468 CDCS5_PAB_OnOffSet 2;
BA_ "GenSigSendType" SG_ 468 CDCS5_SunRoofCtrlReq 2;
BA_ "GenSigStartValue" SG_ 468 CDCS5_SunRoofSLideCtrlReq 21;
BA_ "GenSigSendType" SG_ 468 CDCS5_SunRoofSLideCtrlReq 2;
BA_ "GenSigSendType" SG_ 468 CDCS5_CurtainCtrlReq 2;
BA_ "GenSigStartValue" SG_ 468 CDCS5_CurtainSLideCtrlReq 21;
BA_ "GenSigSendType" SG_ 468 CDCS5_CurtainSLideCtrlReq 2;
BA_ "GenSigSendType" SG_ 468 CDCS5_SunRoofStopCtrlReq 2;
BA_ "GenSigSendType" SG_ 468 CDCS5_CarTempHoldModeSw 2;
BA_ "GenSigSendType" SG_ 468 CDCS5_SmartLightReq 2;
BA_ "GenSigSendType" SG_ 468 CDCS5_NapPositionReset 2;
BA_ "GenSigStartValue" SG_ 468 CDCS5_PLG_DoorHeightSet 101;
BA_ "GenSigSendType" SG_ 468 CDCS5_PLG_DoorHeightSet 2;
BA_ "GenSigSendType" SG_ 468 CDCS5_RLLumbarUpAndDwnAdioAdj 2;
BA_ "GenSigSendType" SG_ 468 CDCS5_RoadRecSw 2;
BA_ "GenSigSendType" SG_ 468 CDCS5_TrailerModeSw 2;
BA_ "GenSigSendType" SG_ 468 CDCS5_RR_MassageModeSet 2;
BA_ "GenSigSendType" SG_ 468 CDCS5_RR_MassageLevelSet 2;
BA_ "GenSigSendType" SG_ 468 CDCS5_ZeroGravityPositionReset 2;
BA_ "GenSigSendType" SG_ 468 CDCS5_RL_MassageModeSet 2;
BA_ "GenSigSendType" SG_ 468 CDCS5_RL_MassageLevelSet 2;
BA_ "GenSigSendType" SG_ 468 CDCS5_RL_SeatVentCmd 2;
BA_ "GenSigSendType" SG_ 468 CDCS5_RR_SeatVentCmd 2;
BA_ "GenSigSendType" SG_ 468 CDCS5_RLLumbarFwdBakwdAdioAdj 2;
BA_ "GenSigSendType" SG_ 468 CDCS5_RRLumbarUpAndDwnAdioAdj 2;
BA_ "GenSigSendType" SG_ 468 CDCS5_RRLumbarFwdBakwdAdioAdj 2;
BA_ "GenSigSendType" SG_ 468 CDCS5_WiperNozzleHeatSWt 2;
BA_ "GenSigSendType" SG_ 501 CDCS11_LKSSetspeed 2;
BA_ "GenSigSendType" SG_ 501 CDCS11_LDW_OnOffSet 2;
BA_ "GenSigSendType" SG_ 501 CDCS11_LowSpeedBSDSw 2;
BA_ "GenSigSendType" SG_ 501 CDCS11_FCW_OnOffSet 2;
BA_ "GenSigSendType" SG_ 501 CDCS11_AEB_OnOffSet 2;
BA_ "GenSigSendType" SG_ 501 CDCS11_FCW_WarnTiming 2;
BA_ "GenSigSendType" SG_ 501 CDCS11_FCTA_OnOffSet 2;
BA_ "GenSigSendType" SG_ 501 CDCS11_RCTA_OnOffSet 2;
BA_ "GenSigSendType" SG_ 501 CDCS11_RCW_OnOffSet 2;
BA_ "GenSigSendType" SG_ 501 CDCS11_DOW_OnOffSet 2;
BA_ "GenSigSendType" SG_ 501 CDCS11_IHBC_SysSwState 2;
BA_ "GenSigSendType" SG_ 501 CDCS11_LCA_OnOffSet 2;
BA_ "GenSigSendType" SG_ 501 CDCS11_TSR_OnOffSet 2;
BA_ "GenSigSendType" SG_ 501 CDCS11_AVM_3DRotate 2;
BA_ "GenSigSendType" SG_ 501 CDCS11_AVM_Turnlightstart 2;
BA_ "GenSigSendType" SG_ 501 CDCS11_AVM_Steeringstart 2;
BA_ "GenSigSendType" SG_ 501 CDCS11_AVM_Magnifiedview 2;
BA_ "GenSigSendType" SG_ 501 CDCS11_AVM_MODdetection 2;
BA_ "GenSigSendType" SG_ 501 CDCS11_GM_OnOffSet 2;
BA_ "GenSigSendType" SG_ 501 CDCS11_NNP_OnOffSet 2;
BA_ "GenSigSendType" SG_ 501 CDCS11_DCLCSysState 2;
BA_ "GenSigSendType" SG_ 501 CDCS11_ALCSysState 2;
BA_ "GenSigSendType" SG_ 501 CDCS11_DriveOffPossilbeswitch 2;
BA_ "GenSigSendType" SG_ 501 CDCS11_DriveOffinhibitionswitch 2;
BA_ "GenSigSendType" SG_ 501 CDCS11_ADAS_SndCtrlOnOff 2;
BA_ "GenSigSendType" SG_ 501 CDCS11_AVM_auxiliaryline 2;
BA_ "GenSigSendType" SG_ 501 CDCS11_AVM_Raderdisplay 2;
BA_ "GenSigSendType" SG_ 501 CDCS11_AVM_Transparentchassis 2;
BA_ "GenSigSendType" SG_ 501 CDCS11_VoiceMode 2;
BA_ "GenSigSendType" SG_ 501 CDCS11_NNP_Active_OnOffSet 2;
BA_ "GenSigSendType" SG_ 501 CDCS11_ALC_mode 2;
BA_ "GenSigSendType" SG_ 501 CDCS11_ADSDriving_mode 2;
BA_ "GenSigSendType" SG_ 501 CDCS11_TSR_OverspeedOnoffSet 2;
BA_ "GenSigSendType" SG_ 501 CDCS11_NNP_AutoOnOffSet 2;
BA_ "GenSigSendType" SG_ 501 CDCS11_SnCtrl_NNP_OnOff 2;
BA_ "GenSigSendType" SG_ 501 CDCS11_GM_VidedIn 2;
BA_ "GenSigSendType" SG_ 501 CDCS11_TSR_SLFOnOffSet 2;
BA_ "GenSigSendType" SG_ 501 CDCS11_APA_FunctionMode 2;
BA_ "GenSigSendType" SG_ 501 CDCS11_TrackreverseSW 2;
BA_ "GenSigSendType" SG_ 501 CDCS11_SetPathwaySW 2;
BA_ "GenSigSendType" SG_ 501 CDCS11_PA_changeLanguage 2;
BA_ "GenSigSendType" SG_ 501 CDCS11_LDP_OnOffSet 2;
BA_ "GenSigSendType" SG_ 501 CDCS11_AVMSw 2;
BA_ "GenSigSendType" SG_ 501 CDCS11_tryHPP 2;
BA_ "GenSigSendType" SG_ 501 CDCS11_NetReset 2;
BA_ "GenSigSendType" SG_ 501 CDCS11_RPASw 2;
BA_ "GenSigSendType" SG_ 501 CDCS11_SetSw 2;
BA_ "GenSigSendType" SG_ 501 CDCS11_SoundCtrlSetReq 2;
BA_ "GenSigSendType" SG_ 501 CDCS11_location_sw 2;
BA_ "GenSigSendType" SG_ 501 CDCS11_Pathrefresh 2;
BA_ "GenSigSendType" SG_ 501 CDCS11_HPAGuideSW 2;
BA_ "GenSigSendType" SG_ 501 CDCS11_HPAPathwaytoCloudSW 2;
BA_ "GenSigSendType" SG_ 501 CDCS11_PathlearningSw 2;
BA_ "GenSigSendType" SG_ 501 CDCS11_PA_screenMd 2;
BA_ "GenSigSendType" SG_ 501 CDCS11_PASw 2;
BA_ "GenSigSendType" SG_ 501 CDCS11_PA_Recover 2;
BA_ "GenSigSendType" SG_ 501 CDCS_Lcsndrequest 2;
BA_ "GenSigSendType" SG_ 501 CDCS_Lcsndconfirm 2;
BA_ "GenSigSendType" SG_ 501 CDCS_SpdAdaptComfirm 2;
BA_ "GenSigSendType" SG_ 501 CDCS_PayModeConfirm 2;
BA_ "GenSigSendType" SG_ 501 CDCS11_SelectSlotID 2;
BA_ "GenSigSendType" SG_ 501 CDCS11_ParkingInReq 2;
BA_ "GenSigSendType" SG_ 501 CDCS11_ParkingOutReq 2;
BA_ "GenSigSendType" SG_ 501 CDCS11_AVM_ViewMode 2;
BA_ "GenSigSendType" SG_ 501 CDCS11_RPA_FunctionMode 2;
BA_ "GenSigSendType" SG_ 501 CDCS11_AVM_VideoOutputFail 2;
BA_ "GenSigSendType" SG_ 501 CDCS11_AVM_Initialization 2;
BA_ "GenSigSendType" SG_ 501 CDCS11_AVM_bodySync 2;
BA_ "GenSigSendType" SG_ 501 CDCS11_AVM_licenseplateabbr 2;
BA_ "GenSigSendType" SG_ 501 CDCS11_AVM_SpeView 2;
BA_ "GenSigSendType" SG_ 501 CDCS11_AVM_licenseplateArea 2;
BA_ "GenSigSendType" SG_ 501 CDCS11_AVM_StartMode 2;
BA_ "GenSigSendType" SG_ 501 CDCS11_AVM_LicensePlateNO1 2;
BA_ "GenSigSendType" SG_ 501 CDCS11_AVM_LicensePlateNO2 2;
BA_ "GenSigSendType" SG_ 501 CDCS11_DrvOffAlertSwitch 2;
BA_ "GenSigSendType" SG_ 501 CDCS11_AVM_LicensePlateNO3 2;
BA_ "GenSigSendType" SG_ 501 CDCS11_DCWposition 2;
BA_ "GenSigSendType" SG_ 501 CDCS11_AVM_LicensePlateNO4 2;
BA_ "GenSigSendType" SG_ 501 CDCS11_EOL_Fdbk 2;
BA_ "GenSigSendType" SG_ 501 CDCS11_AVM_LicensePlateNO5 2;
BA_ "GenSigSendType" SG_ 501 CDCS11_AVM_LicensePlateNO6 2;
BA_ "GenSigSendType" SG_ 501 CDCS11_DataUp_Trigger 2;
BA_ "GenSigSendType" SG_ 501 CDCS11_AVM_LicensePlateNO7 2;
BA_ "GenSigSendType" SG_ 501 CDCS11_AVM_DayNightMode 2;
BA_ "GenSigSendType" SG_ 501 CDCS11_AVM_LicensePlateNO8 2;
BA_ "GenSigSendType" SG_ 501 CDCS11_AVM_Powertype 2;
BA_ "GenSigSendType" SG_ 501 CDCS11_AVM_Diaphaneity 2;
BA_ "GenSigSendType" SG_ 501 CDCS11_AVM_DiaphaneitySw 2;
BA_ "GenSigSendType" SG_ 501 CDCS11_LDWLKAAidSwSts 2;
BA_ "GenSigSendType" SG_ 501 CDCS11_MOD_Sound_Sw 2;
BA_ "GenSigSendType" SG_ 501 CDCS11_MOD_BSD_Sw 2;
BA_ "GenSigSendType" SG_ 501 CDCS11_PA_FRS_OnOffSet 2;
BA_ "GenSigSendType" SG_ 501 CDCS11_PA_3D_OnOffSet 2;
BA_ "GenSigSendType" SG_ 501 CDCS11_PA_measure_OnOffSet 2;
BA_ "GenSigSendType" SG_ 501 CDCS11_MODSw 2;
BA_ "GenSigSendType" SG_ 501 CDCS11_VoiceNotifFrequency_mode 2;
BA_ "GenSigSendType" SG_ 501 CDCS11_ACCOnOffSet 2;
BA_ "GenSigSendType" SG_ 501 CDCS11_HPASw 2;
BA_ "GenSigSendType" SG_ 501 CDCS11_PA_WarningType 2;
BA_ "GenSigSendType" SG_ 501 CDCS11_HPA_OnOffSet 2;
BA_ "GenSigSendType" SG_ 501 CDCS11_DeleteMapID 2;
BA_ "GenSigSendType" SG_ 501 CDCS11_UploadMapID 2;
BA_ "GenSigSendType" SG_ 501 CDCS11_HPAActiveConfirm 2;
BA_ "GenSigSendType" SG_ 501 CDCS11_TSR_ALSUpdataSwState 2;
BA_ "GenSigSendType" SG_ 501 CDCS11_HPApreparkingSw 2;
BA_ "GenSigSendType" SG_ 501 CDCS11_HPAPathwaytoCloud_WorkSts 2;
BA_ "GenSigSendType" SG_ 501 CDCS11_TSR_SLWFVoiceSwState 2;
BA_ "GenSigSendType" SG_ 501 CDCS11_ELKA_OnOffSet 2;
BA_ "GenSigSendType" SG_ 501 CDCS11_Pathrelearn 2;
BA_ "GenSigSendType" SG_ 501 CDCS11_HPA_ONPath_ID1 2;
BA_ "GenSigSendType" SG_ 501 CDCS11_HPA_ONPath_ID2 2;
BA_ "GenSigSendType" SG_ 501 CDCS11_HPA_ONPath_ID3 2;
BA_ "GenSigSendType" SG_ 501 CDCS11_HPA_ONPath_ID4 2;
BA_ "GenSigSendType" SG_ 501 CDCS11_HPA_Select_ID 2;
BA_ "GenSigSendType" SG_ 501 CDCS11_PA_Select_ID 2;
BA_ "GenSigSendType" SG_ 501 CDCS11_learnpath_St 2;
BA_ "GenSigSendType" SG_ 501 CDCS11_LDWLKA_WarnTiming 2;
BA_ "GenSigStartValue" SG_ 501 CDCS11_TSR_LimitOverspeedSet 255;
BA_ "GenSigSendType" SG_ 501 CDCS11_TSR_LimitOverspeedSet 2;
BA_ "GenSigSendType" SG_ 501 CDCS11_FrbdWindowOpen_Req 2;
BA_ "GenSigSendType" SG_ 501 CDCS11_ParkingoutSlot_Type 2;
BA_ "GenSigSendType" SG_ 501 CDCS11_ParkingoutSlot_Dire 2;
BA_ "GenSigSendType" SG_ 501 CDCS11_OptionalSlot_Type 2;
BA_ "GenSigSendType" SG_ 501 CDCS11_OptionalSlot_Dire 2;
BA_ "GenSigSendType" SG_ 501 CDCS11_OptionalSlotAngle 2;
BA_ "GenSigSendType" SG_ 501 CDCS11_OptionalSlotCoor_P0_X 2;
BA_ "GenSigSendType" SG_ 501 CDCS11_OptionalSlotCoor_P0_Y 2;
BA_ "GenSigSendType" SG_ 501 CDCS11_OptionalSlotCoor_P1_X 2;
BA_ "GenSigSendType" SG_ 501 CDCS11_OptionalSlotCoor_P1_Y 2;
BA_ "GenSigSendType" SG_ 501 CDCS11_OptionalSlotCoor_P2_X 2;
BA_ "GenSigSendType" SG_ 501 CDCS11_OptionalSlotCoor_P2_Y 2;
BA_ "GenSigSendType" SG_ 501 CDCS11_OptionalSlotCoor_P3_X 2;
BA_ "GenSigSendType" SG_ 501 CDCS11_OptionalSlotCoor_P3_Y 2;
VAL_ 1538 BDCS_RepeatMessageRequest 1 "Repeat message request" 0 "No repeat message request";
VAL_ 1538 BDCS_ActiveWakeup 1 "Wakeup" 0 "No wakeup";
VAL_ 1538 BDCS_WakeUp_KL15 1 "KL15 Wakeup" 0 "No Request";
VAL_ 1538 BDCS_WakeUp_Rx_NM 1 "NM Wakeup" 0 "No Request";
VAL_ 1538 BDCS_WakeUp_Hazard 1 "Hazard Wakeup" 0 "No Request";
VAL_ 1538 BDCS_WakeUp_BackDoorFB 1 "BackDoorFB Wakeup" 0 "No Request";
VAL_ 1538 BDCS_WakeUp_BackDoorOutSW 1 "BackDoorOutSW Wakeup" 0 "No Request";
VAL_ 1538 BDCS_WakeUp_LiftGateLockSW 1 "LiftGateLockSW Wakeup" 0 "No Request";
VAL_ 1538 BDCS_WakeUp_PLGInLockSW 1 "PLGInLockSW Wakeup" 0 "No Request";
VAL_ 1538 BDCS_WakeUp_FullLock 1 "FullLock Wakeup" 0 "No Request";
VAL_ 1538 BDCS_RepeatFromSleep 1 "occur" 0 "not occur";
VAL_ 1538 BDCS_RepeatFromPrepare 1 "occur" 0 "not occur";
VAL_ 1538 BDCS_NormalFromRepeat 1 "occur" 0 "not occur";
VAL_ 1538 BDCS_NormalFromReady 1 "occur" 0 "not occur";
VAL_ 1538 BDCS_RepeatFromReady 1 "occur" 0 "not occur";
VAL_ 1538 BDCS_RepeatFromNormal 1 "occur" 0 "not occur";
VAL_ 1538 BDCS_WakeUp_RKE 1 "RKE_Wakeup" 0 "No Request";
VAL_ 1538 BDCS_RemainNetworkWakeUp_Power 1 "PowerMode Remain wakeup" 0 "default";
VAL_ 1538 BDCS_RemainNetworkWakeUp_DiagMode 1 "DiagMode Remain wakeup" 0 "default";
VAL_ 1538 BDCS_RemainNetworkWakeUp_HazardBlink 1 "HazardBlink Remain wakeup" 0 "default";
VAL_ 1538 BDCS_RemainNetworkWakeUp_PosLightOn 1 "PosLight On Remain wakeup" 0 "default";
VAL_ 1538 BDCS_RemainNetworkWakeUp_AlarmState 1 "AlarmState Remain wakeup" 0 "default";
VAL_ 1538 BDCS_RemainNetworkWakeUp_Wait_AutoRepeatLock 1 "AutoRepLock Remain wakeup reason" 0 "default";
VAL_ 1538 BDCS_RemainNetworkWakeUp_DomeLightOn 1 "DomeLamp Remain wakeup" 0 "default";
VAL_ 1538 BDCS_RemainNetworkWakeUp_PowerSavingRelayWorking 1 "Relay Remain wakeup" 0 "default";
VAL_ 1538 BDCS_RemainNetworkWakeUp_FollowmeHome 1 "Follow me Home Remain wakeup" 0 "default";
VAL_ 1538 BDCS_WakeUp_HoodAjarFB 1 "HoodAjarFBWakeup" 0 "No Request";
VAL_ 1538 BDCS_WakeUp_LIN2 1 "Wakeup" 0 "No Request";
VAL_ 1538 BDCS_WakeUp_TPMS 1 "Wakeup" 0 "No Request";
VAL_ 1538 BDCS_WakeUp_PassengerSideHandleLock 1 "PassengerSideHandleLock" 0 "default";
VAL_ 1538 BDCS_WakeUp_PassengerSideHandleUnLock 1 "PassengerSideHandleLock" 0 "default";
VAL_ 1538 BDCS_WakeUp_DriverSideHandleLock 1 "DriverSideHandleLock" 0 "default";
VAL_ 1538 BDCS_WakeUp_DriverSideHandleUnlock 1 "DriverSideHandleUnlock" 0 "default";
VAL_ 1538 BDCS_WakeUp_SSBSW2 1 "SSBSW2" 0 "default";
VAL_ 1538 BDCS_WakeUp_SSBSW1 1 "SSBSW1" 0 "default";
VAL_ 1538 BDCS_WakeUp_IGN2 1 "IGN2" 0 "default";
VAL_ 1538 BDCS_WakeUp_IGN1 1 "IGN1" 0 "default";
VAL_ 1538 BDCS_WakeUp_ACC 1 "ACC" 0 "default";
VAL_ 1538 BDCS_WakeUp_Break1 1 "Break1" 0 "default";
VAL_ 1538 BDCS_WakeUp_Break2 1 "Break2" 0 "No Request";
VAL_ 1538 BDCS_WakeUp_KickSensor 1 "KickSensor" 0 "No Request";
VAL_ 1538 BDCS_WakeUp_PassageSideContainerSW 1 "Request" 0 "not Request";
VAL_ 1538 BDCS_WakeUp_HornInput 1 "Request" 0 "not Request";
VAL_ 1538 BDCS_WakeUp_DriverSideSensor 1 "Request" 0 "not Request";
VAL_ 1538 BDCS_WakeUp_LightLevelInput 1 "Request" 0 "not Request";
VAL_ 1538 BDCS_WakeUp_HighBeam 1 "Request" 0 "not Request";
VAL_ 1538 BDCS_UserData5 1 "Request" 0 "not Request";
VAL_ 418 DDCU1_ControlWindowLockSw 1 "Active" 0 "Inactive";
VAL_ 418 DDCU1_OilFillCapFbk 1 "OilFillCap Open Warning" 0 "No Request";
VAL_ 418 DDCU1_FLWinCtrl_Fb 5 "Condition Error" 4 "Interrupt" 3 "Trigger anti-pinch" 2 "Complete" 1 "Running" 0 "Default";
VAL_ 418 DDCU1_RLWinCtrl_Fb 5 "Condition Error" 4 "Interrupt" 3 "Trigger anti-pinch" 2 "Complete" 1 "Running" 0 "Default";
VAL_ 418 DDCU1_FLDoorAjar 3 "Unknow" 2 "Open" 1 "Secondary" 0 "Closed";
VAL_ 418 DDCU1_RLDoorAjar 3 "Unknow" 2 "Open" 1 "Secondary" 0 "Closed";
VAL_ 418 DDCU1_RL_SafetyLockFdbk 1 "Disable" 0 "Enable";
VAL_ 418 DDCU1_MirrorFoldSt 1 "Fold" 0 "Unfold";
VAL_ 418 DDCU1_MirrorFoldSet_fdbk 1 "Enabled" 0 "Disabled";
VAL_ 418 DDCU1_LockReleaseSw_Out_FL 1 "Press" 0 "No press";
VAL_ 418 DDCU1_LockReleaseSw_Out_FR 1 "Press" 0 "No press";
VAL_ 418 DDCU1_LockReleaseSw_In_FL 1 "Press" 0 "No press";
VAL_ 418 DDCU1_LockReleaseSw_In_FR 1 "Press" 0 "No press";
VAL_ 418 DDCU1_FL_HallFault 1 "error present" 0 "No error";
VAL_ 418 DDCU1_FL_PWL_Init 1 "Initialized" 0 "Not initialized";
VAL_ 418 DDCU1_FL_PWL_State 3 "Other error persent" 2 "Open circuit error" 1 "Short to Gnd/KL30" 0 "No error";
VAL_ 418 DDCU1_RL_PWL_State 3 "Other error persent" 2 "Open circuit error" 1 "Short to Gnd/KL30" 0 "No error";
VAL_ 418 DDCU1_RL_HallFault 1 "error present" 0 "No error";
VAL_ 418 DDCU1_RL_PWL_Init 1 "Initialized" 0 "Not initialized";
VAL_ 418 DDCU1_LeftMirrorAutoTurnDownFb 1 "Enable" 0 "Disable";
VAL_ 418 DDCU1_LeftPosLoad_Sts 2 "Failed" 1 "Succeed" 0 "Default";
VAL_ 418 DDCU1_FL_WindowsExerciseSts 3 "reserved" 2 "down" 1 "up" 0 "stop";
VAL_ 418 DDCU1_RL_WindowsExerciseSts 3 "reserved" 2 "down" 1 "up" 0 "stop";
VAL_ 418 DDCU1_FRWindowsCtrl 4 "Auto Down" 3 "Auto Up" 2 "Manual Down" 1 "Manual Up" 0 "No request";
VAL_ 418 DDCU1_RRWindowsCtrl 4 "Auto Down" 3 "Auto Up" 2 "Manual Down" 1 "Manual Up" 0 "No request";
VAL_ 418 DDCU1_LeftPosMemory_Sts 2 "Failed" 1 "Succeed" 0 "Default";
VAL_ 418 DDCU1_FL_LockSt 1 "Unlock" 0 "Lock";
VAL_ 418 DDCU1_RL_LockSt 1 "Unlock" 0 "Lock";
VAL_ 418 DDCU1_WindowSteamSet_Fb 3 "Big" 2 "Middle" 1 "Little" 0 "Default";
VAL_ 418 DRGLS_CustomSignal 1 "Active" 0 "Inactive";
VAL_ 418 DFGLS_CustomSignal 1 "Active" 0 "Inactive";
VAL_ 418 DDCU1_FL_WindowsAnti_pinchSts 1 "Anti-pinch" 0 "No Anti-pinch";
VAL_ 418 DDCU1_RL_WindowsAnti_pinchSts 1 "Anti-pinch" 0 "No Anti-pinch";
VAL_ 418 DDCU1_LeftMirror_Pos_ManualAdjust_Sts 1 "Adjusted" 0 "Not adjust";
VAL_ 418 DDCU1_DoorHandleRetractedOverTimeSts 4 "5min" 3 "2min" 2 "30s" 1 "OFF" 0 "No Request";
VAL_ 418 DDCU1_FLWindowFollowUpDoorSts 3 "Reserved" 2 "Disable" 1 "Enable" 0 "Initial";
VAL_ 418 DDCU1_OilFillCapSts 1 "Open" 0 "Close";
VAL_ 418 DDCU1_CentralLockFailure 1 "Failure" 0 "No Failure";
VAL_ 418 DDCU1_OilFillCapLockSts 1 "Unlock" 0 "Lock";
VAL_ 418 DDCU1_MirrorFoldSpeedLimit_Fb 1 "Enable" 0 "Disable";
VAL_ 418 DDCU1_FL_DoorHandleSts 1 "Unfold" 0 "Fold";
VAL_ 418 DDCU1_RL_DoorHandleSts 1 "Unfold" 0 "Fold";
VAL_ 418 DDCU1_MirrorHeatingSts 1 "Active" 0 "InActive";
VAL_ 418 DDCU1_CentralLockLightSts 3 "Reserved" 2 "Reserved" 1 "Active" 0 "Inactive";
VAL_ 418 DDCU1_CentralLockSts 3 "Reserved" 2 "Default" 1 "Unlock" 0 "Lock";
VAL_ 418 DDCU1_DFGLS_FLWindowControl 4 "Auto Down" 3 "Auto Up" 2 "Manual Down" 1 "Manual Up" 0 "No request";
VAL_ 418 DDCU1_DFGLS_RLWindowControl 4 "Auto Down" 3 "Auto Up" 2 "Manual Down" 1 "Manual Up" 0 "No request";
VAL_ 418 DDCU1_FL_Cause_loss_PWL_Init 31 "Reserved" 25 "Parameter Update" 22 "System Error（RAM&ROM）" 20 "Max Activations" 17 "Position Out of Min Range" 16 "Position Out of Max Range" 15 "Down Stall above Lower Upper Limit" 13 "NVRAM Zone Defect" 10 "Initialized" 2 "Wrong Sensor Direction" 1 "Missing Position Counter Signal" 0 "Default";
VAL_ 418 DDCU1_DRGLS_RLWindowControl 4 "Auto Down" 3 "Auto Up" 2 "Manual Down" 1 "Manual Up" 0 "No request";
VAL_ 418 DFGLS_ButtonSoundRequest 1 "Press" 0 "No press";
VAL_ 418 DRGLS_ButtonSoundRequest 1 "Press" 0 "No press";
VAL_ 418 DDCU1_RL_Cause_loss_PWL_Init 31 "Reserved" 25 "Parameter Update" 22 "System Error（RAM&ROM）" 20 "Max Activations" 17 "Position Out of Min Range" 16 "Position Out of Max Range" 15 "Down Stall above Lower Upper Limit" 13 "NVRAM Zone Defect" 10 "Initialized" 2 "Wrong Sensor Direction" 1 "Missing Position Counter Signal" 0 "Default";
VAL_ 858 DDCU_OTA__FLDoorAjar 3 "Unknow" 2 "Open" 1 "Secondary" 0 "Closed";
VAL_ 858 DDCU_OTA__RLDoorAjar 3 "Unknow" 2 "Open" 1 "Secondary" 0 "Closed";
VAL_ 858 DDCU_OTA_CentralLockSts 3 "Reserved" 2 "Default" 1 "Unlock" 0 "Lock";
VAL_ 858 DDCU_OTA_FRWindowsCtrl 4 "Auto Down" 3 "Auto Up" 2 "Manual Down" 1 "Manual Up" 0 "No request";
VAL_ 858 DDCU_OTA_RRWindowsCtrl 4 "Auto Down" 3 "Auto Up" 2 "Manual Down" 1 "Manual Up" 0 "No request";
VAL_ 858 DDCU_OTA_ControlWindowLockSw 1 "Active" 0 "Inactive";
VAL_ 858 DDCU_OTA_FL_LockSt 1 "Unlock" 0 "Lock";
VAL_ 858 DDCU_OTA_RL_LockSt 1 "Unlock" 0 "Lock";
VAL_ 858 DDCU_OTA_MirrorFoldSt 1 "Fold" 0 "Unfold";
VAL_ 1550 DDCU_RepeatMessageRequest 1 "Repeat message request" 0 "No repeat message request";
VAL_ 1550 DDCU_ActiveWakeup 1 "Wakeup" 0 "No wakeup";
VAL_ 1550 DDCU_WakeUp_KL15 1 "KL15 ON Wakeup" 0 "No Request";
VAL_ 1550 DDCU_WakeUp_NM 1 "NM Wakeup" 0 "No Request";
VAL_ 1550 DDCU_WakeUp_FLDoor 1 "Wakeup Requrst" 0 "No Request";
VAL_ 1550 DDCU_WakeUp_RLDoor 1 "Wakeup Requrst" 0 "No Request";
VAL_ 1550 DDCU_WakeUp_FLInSW 1 "Wakeup Requrst" 0 "No Request";
VAL_ 1550 DDCU_WakeUp_FLOutSW 1 "Wakeup Requrst" 0 "No Request";
VAL_ 1550 DDCU_WakeUp_RLInSW 1 "Wakeup Requrst" 0 "No Request";
VAL_ 1550 DDCU_WakeUp_RLOutSW 1 "Wakeup Requrst" 0 "No Request";
VAL_ 1550 DDCU_RepeatFromSleep 1 "occur" 0 "not occur";
VAL_ 1550 DDCU_RepeatFromPrepare 1 "occur" 0 "not occur";
VAL_ 1550 DDCU_NormalFromRepeat 1 "occur" 0 "not occur";
VAL_ 1550 DDCU_NormalFromReady 1 "occur" 0 "not occur";
VAL_ 1550 DDCU_RepeatFromReady 1 "occur" 0 "not occur";
VAL_ 1550 DDCU_RepeatFromNormal 1 "occur" 0 "not occur";
VAL_ 1550 DDCU_RemainNetworkWakeUpReason1 1 "Remain wakeup reason" 0 "default";
VAL_ 1550 DDCU_RemainNetworkWakeUpReason2 1 "Remain wakeup reason" 0 "default";
VAL_ 1550 DDCU_RemainNetworkWakeUpReason3 1 "Remain wakeup reason" 0 "default";
VAL_ 1550 DDCU_RemainNetworkWakeUpReason4 1 "Remain wakeup reason" 0 "default";
VAL_ 1550 DDCU_WakeUp_FLLockSts 1 "Wakeup Requrst" 0 "No Request";
VAL_ 1550 DDCU_WakeUp_FuelTankCap 1 "Remain wakeup reason" 0 "default";
VAL_ 419 PDCU1_OilFillCapSts 1 "Open" 0 "Close";
VAL_ 419 PDCU1_OilFillCapLockSts 1 "Unlock" 0 "Lock";
VAL_ 419 PDCU1_FRWinCtrl_Fb 5 "Condition Error" 4 "Interrupt" 3 "Trigger anti-pinch" 2 "Complete" 1 "Running" 0 "Default";
VAL_ 419 PDCU1_RRWinCtrl_Fb 5 "Condition Error" 4 "Interrupt" 3 "Trigger anti-pinch" 2 "Complete" 1 "Running" 0 "Default";
VAL_ 419 PDCU1_FRDoorAjar 3 "Unknow" 2 "Open" 1 "Secondary" 0 "Closed";
VAL_ 419 PDCU1_RRDoorAjar 3 "Unknow" 2 "Open" 1 "Secondary" 0 "Closed";
VAL_ 419 PDCU1_RR_SafetyLockFdbk 1 "Disable" 0 "Enable";
VAL_ 419 PFGLS_CustomSignal 1 "Active" 0 "Inactive";
VAL_ 419 PRGLS_CustomSignal 1 "Active" 0 "Inactive";
VAL_ 419 PDCU1_LockReleaseSw_Out_FR 1 "Press" 0 "No press";
VAL_ 419 PDCU1_LockReleaseSw_Out_RR 1 "Press" 0 "No press";
VAL_ 419 PDCU1_LockReleaseSw_In_FR 1 "Press" 0 "No press";
VAL_ 419 PDCU1_LockReleaseSw_In_RR 1 "Press" 0 "No press";
VAL_ 419 PDCU1_FR_HallFault 1 "error present" 0 "No error";
VAL_ 419 PDCU1_FR_PWL_Init 1 "Initialized" 0 "Not initialized";
VAL_ 419 PDCU1_FR_PWL_State 3 "Other error persent" 2 "Open circuit error" 1 "Short to Gnd/KL30" 0 "No error";
VAL_ 419 PDCU1_RR_PWL_State 3 "Other error persent" 2 "Open circuit error" 1 "Short to Gnd/KL30" 0 "No error";
VAL_ 419 PDCU1_RR_HallFault 1 "error present" 0 "No error";
VAL_ 419 PDCU1_RR_PWL_Init 1 "Initialized" 0 "Not initialized";
VAL_ 419 PDCU1_RightMirrorAutoTurnDownFb 1 "Enable" 0 "Disable";
VAL_ 419 PDCU1_PosLoad_Sts 2 "Failed" 1 "Succeed" 0 "Default";
VAL_ 419 PDCU1_ChargeFillCapLockSts 1 "Unlock" 0 "Lock";
VAL_ 419 PDCU1_ChargeLidSts 1 "Open" 0 "Close";
VAL_ 419 PDCU1_PosMemory_Sts 2 "Failed" 1 "Succeed" 0 "Default";
VAL_ 419 PDCU1_FR_WindowsExerciseSts 3 "reserved" 2 "down" 1 "up" 0 "stop";
VAL_ 419 PDCU1_RR_WindowsExerciseSts 3 "reserved" 2 "down" 1 "up" 0 "stop";
VAL_ 419 PDCU1_FR_LockSt 1 "Unlock" 0 "Lock";
VAL_ 419 PDCU1_RR_LockSt 1 "Unlock" 0 "Lock";
VAL_ 419 PDCU1_WindowSteamSet_Fb 3 "Big" 2 "Middle" 1 "Little" 0 "Default";
VAL_ 419 PDCU1_FR_WindowsAnti_pinchSts 1 "Anti-pinch" 0 "No Anti-pinch";
VAL_ 419 PDCU1_RR_WindowsAnti_pinchSts 1 "Anti-pinch" 0 "No Anti-pinch";
VAL_ 419 PDCU1_DoorHandleRetractedOverTimeSts 4 "5min" 3 "2min" 2 "30s" 1 "OFF" 0 "No Request";
VAL_ 419 PDCU1_RightMirror_Pos_ManualAdjust_Sts 1 "Adjusted" 0 "Not adjust";
VAL_ 419 PDCU1_FRWindowFollowUpDoorSts 3 "Reserved" 2 "Disable" 1 "Enable" 0 "Initial";
VAL_ 419 PDCU1_FR_DoorHandleSts 1 "Unfold" 0 "Fold";
VAL_ 419 PDCU1_RR_DoorHandleSts 1 "Unfold" 0 "Fold";
VAL_ 419 PDCU1_MirrorHeatingSts 1 "Active" 0 "InActive";
VAL_ 419 PDCU1_PFGLS_RLWindowControl 4 "Auto Down" 3 "Auto Up" 2 "Manual Down" 1 "Manual Up" 0 "No request";
VAL_ 419 PDCU1_FR_Cause_loss_PWL_Init 31 "Reserved" 25 "Parameter Update" 22 "System Error（RAM&ROM）" 20 "Max Activations" 17 "Position Out of Min Range" 16 "Position Out of Max Range" 15 "Down Stall above Lower Upper Limit" 13 "NVRAM Zone Defect" 10 "Initialized" 2 "Wrong Sensor Direction" 1 "Missing Position Counter Signal" 0 "Default";
VAL_ 419 PDCU1_PRGLS_RRWindowControl 4 "Auto Down" 3 "Auto Up" 2 "Manual Down" 1 "Manual Up" 0 "No request";
VAL_ 419 PFGLS_ButtonSoundRequest 1 "Press" 0 "No press";
VAL_ 419 PRGLS_ButtonSoundRequest 1 "Press" 0 "No press";
VAL_ 419 PDCU1_RR_Cause_loss_PWL_Init 31 "Reserved" 25 "Parameter Update" 22 "System Error（RAM&ROM）" 20 "Max Activations" 17 "Position Out of Min Range" 16 "Position Out of Max Range" 15 "Down Stall above Lower Upper Limit" 13 "NVRAM Zone Defect" 10 "Initialized" 2 "Wrong Sensor Direction" 1 "Missing Position Counter Signal" 0 "Default";
VAL_ 859 PDCU_OTA_FRDoorAjar 3 "Unknow" 2 "Open" 1 "Secondary" 0 "Closed";
VAL_ 859 PDCU_OTA_RRDoorAjar 3 "Unknow" 2 "Open" 1 "Secondary" 0 "Closed";
VAL_ 859 PDCU_OTA_FR_LockSt 1 "Unlock" 0 "Lock";
VAL_ 859 PDCU_OTA_RR_LockSt 1 "Unlock" 0 "Lock";
VAL_ 1549 PDCU_RepeatMessageRequest 1 "Repeat message request" 0 "No repeat message request";
VAL_ 1549 PDCU_ActiveWakeup 1 "Wakeup" 0 "No wakeup";
VAL_ 1549 PDCU_WakeUp_KL15 1 "KL15 ON Wakeup" 0 "No Request";
VAL_ 1549 PDCU_WakeUp_NM 1 "NM Wakeup" 0 "No Request";
VAL_ 1549 PDCU_WakeUp_FRDoor 1 "Wakeup Requrst" 0 "No Request";
VAL_ 1549 PDCU_WakeUp_RRDoor 1 "Wakeup Requrst" 0 "No Request";
VAL_ 1549 PDCU_WakeUp_FRInSW 1 "Wakeup Requrst" 0 "No Request";
VAL_ 1549 PDCU_WakeUp_FROutSW 1 "Wakeup Requrst" 0 "No Request";
VAL_ 1549 PDCU_WakeUp_RRInSW 1 "Wakeup Requrst" 0 "No Request";
VAL_ 1549 PDCU_WakeUp_RROutSW 1 "Wakeup Requrst" 0 "No Request";
VAL_ 1549 PDCU_RepeatFromSleep 1 "occur" 0 "not occur";
VAL_ 1549 PDCU_RepeatFromPrepare 1 "occur" 0 "not occur";
VAL_ 1549 PDCU_NormalFromRepeat 1 "occur" 0 "not occur";
VAL_ 1549 PDCU_NormalFromReady 1 "occur" 0 "not occur";
VAL_ 1549 PDCU_RepeatFromReady 1 "occur" 0 "not occur";
VAL_ 1549 PDCU_RepeatFromNormal 1 "occur" 0 "not occur";
VAL_ 1549 PDCU_RemainNetworkWakeUpReason1 1 "Remain wakeup reason" 0 "default";
VAL_ 1549 PDCU_RemainNetworkWakeUpReason2 1 "Remain wakeup reason" 0 "default";
VAL_ 1549 PDCU_RemainNetworkWakeUpReason3 1 "Remain wakeup reason" 0 "default";
VAL_ 1549 PDCU_RemainNetworkWakeUpReason4 1 "Remain wakeup reason" 0 "default";
VAL_ 1549 PDCU_WakeUp_FuelTankCap 1 "Remain wakeup reason" 0 "default";
VAL_ 928 BAM1_Sts 4 "Connection" 3 "Initiating" 2 "Standby" 1 "Advertising" 0 "Sanning";
VAL_ 928 BAM1_Advertising_Sts 3 "Reserved" 2 "Handler Advertising" 1 "Auto Advertising" 0 "Dafut";
VAL_ 928 BAM1_WailBox_AUTHENTICATION 3 "Reserved" 2 "No pass" 1 "Pass" 0 "Dafut";
VAL_ 928 BAM1_WailBox_ConnectSts 2 "Connection" 1 "Not connection" 0 "Initial value";
VAL_ 928 BAM1_EorrCode 7 "Reserved" 6 "Reserved" 5 "Reserved" 4 "Reserved" 3 "Reserved" 2 "鉴权通过，无充电权限" 1 "鉴权通过" 0 "No err";
VAL_ 1609 BAM_RepeatMessageRequest 1 "Repeat message request" 0 "No repeat message request";
VAL_ 1609 BAM_ActiveWakeup 1 "Wakeup" 0 "No wakeup";
VAL_ 1609 BAM_WakeUp_KL15 1 "KL15 ON Wakeup" 0 "No Request";
VAL_ 1609 BAM_WakeUp_NM 1 "NM Wakeup" 0 "No Request";
VAL_ 1609 BAM_RepeatFromSleep 1 "occur" 0 "not occur";
VAL_ 1609 BAM_RepeatFromPrepare 1 "occur" 0 "not occur";
VAL_ 1609 BAM_NormalFromRepeat 1 "occur" 0 "not occur";
VAL_ 1609 BAM_NormalFromReady 1 "occur" 0 "not occur";
VAL_ 1609 BAM_RepeatFromReady 1 "occur" 0 "not occur";
VAL_ 1609 BAM_RepeatFromNormal 1 "occur" 0 "not occur";
VAL_ 1609 BAM_RemainNetworkWakeUpReason1 1 "Remain wakeup reason" 0 "default";
VAL_ 1609 BAM_RemainNetworkWakeUpReason2 1 "Remain wakeup reason" 0 "default";
VAL_ 1609 BAM_RemainNetworkWakeUpReason3 1 "Remain wakeup reason" 0 "default";
VAL_ 1609 BAM_RemainNetworkWakeUpReason4 1 "Remain wakeup reason" 0 "default";
VAL_ 243 BTM1_SecuritySts 3 "Reserved" 2 "In security  status" 1 "Not in Security status" 0 "Initial value";
VAL_ 243 BTM1_PhoneBatSts 1 "Abnormal" 0 "Normal";
VAL_ 243 BTM1_RemoteIntModSel 2 "60s Return" 1 "60s HangUp Phone" 0 "Not Selected";
VAL_ 243 BTM1_SelectSlotID 8 "slot 8" 7 "slot 7" 6 "slot 6" 5 "slot 5" 4 "slot 4" 3 "slot 3" 2 "slot 2" 1 "slot 1" 0 "No select";
VAL_ 243 BTM1_Retry 1 "Recover" 0 "Default";
VAL_ 243 BTM1_Fixslot 1 "OK" 0 "No request";
VAL_ 243 BTM1_parkingoutSlot_Dire 3 "Front" 2 "Right" 1 "Left" 0 "No request";
VAL_ 243 BTM1_parkingoutSlotType 3 "Oblique" 2 "Parallel" 1 "Vertical" 0 "Undecided";
VAL_ 243 BTM1_Recover 1 "Recover" 0 "Default";
VAL_ 243 BTM1_ParkingReq 2 "Request  RPA" 1 "Request" 0 "No Request";
VAL_ 243 BTM1_FunctionMode 4 "liner ctrl" 3 "choice parking in" 2 "Parking out" 1 "Parking in" 0 "No action";
VAL_ 243 BTM1_OptionalSlot_Dire 4 "Rear" 3 "Front" 2 "Right" 1 "Left" 0 "No request";
VAL_ 243 BTM1_OptionalSlotType 3 "Oblique" 2 "Parallel" 1 "Vertical" 0 "Undecided";
VAL_ 243 BTM1_RemoteParkReq 2 "Request off" 1 "Request on" 0 "No Request";
VAL_ 243 BTM1_Movectrl 2 "Retreat" 1 "Forward" 0 "No request";
VAL_ 498 BTM3_ArmingCmd 3 "FindCar" 2 "Unlock" 1 "Lock" 0 "Default/Not Active";
VAL_ 498 BTM3_TrunkCmd 3 "Reserved" 2 "Close" 1 "Open" 0 "No request";
VAL_ 498 BTM3_RKECmd 10 "ChargingflapClose" 9 "ChargingflapOpen" 8 "Reserved" 7 "APA Car press" 6 "Find Car" 5 "Trunk lock press" 4 "Long Lock" 3 "Long Unlock" 2 "Short Lock" 1 "Short Unlock" 0 "Default";
VAL_ 498 BTM3_Chargingflapcmd 2 "Open" 1 "Close" 0 "Default";
VAL_ 498 BTM3_WelcomeLampCmd 3 "Not Used" 2 "off" 1 "Active" 0 "Default";
VAL_ 498 BTM3_CLM_OnoffCmd 2 "OFF" 1 "ON" 0 "Default";
VAL_ 498 BTM3_Remote_ControlCmd 3 "Not Used" 2 "Flame out" 1 "Active" 0 "Not Active";
VAL_ 498 BTM3_RL_Window_Control_Cmd 5 "通风" 4 "Auto Down" 3 "Auto Up" 2 "Menu Down" 1 "Menu up" 0 "Not Active/Default";
VAL_ 498 BTM3_RR_Window_Control_Cmd 5 "通风" 4 "Auto Down" 3 "Auto Up" 2 "Menu Down" 1 "Menu up" 0 "Not Active/Default";
VAL_ 498 BTM3_CLM_ACCmd 2 "OFF" 1 "ON" 0 "Default";
VAL_ 498 BTM3_FL_Window_Control_Cmd 5 "通风" 4 "Auto Down" 3 "Auto Up" 2 "Menu Down" 1 "Menu up" 0 "Not Active/Default";
VAL_ 498 BTM3_FR_Window_Control_Cmd 5 "通风" 4 "Auto Down" 3 "Auto Up" 2 "Menu Down" 1 "Menu up" 0 "Not Active/Default";
VAL_ 498 BTM3_CLM_PTCCmd 2 "OFF" 1 "ON" 0 "Default";
VAL_ 498 BTM3_CLM_BlowerSpdSet 10 "Level 10" 9 "Level 9" 8 "Level 8" 7 "Level 7" 6 "Level 6" 5 "Level 5" 4 "Level 4" 3 "Level 3" 2 "Level 2" 1 "Level 1" 0 "No Request";
VAL_ 498 BTM3_Charging_cmd 2 "Open" 1 "Close" 0 "Default";
VAL_ 498 BTM3_OpenFLDoorReq 3 "Suspend" 2 "Close" 1 "Open" 0 "No request";
VAL_ 498 BTM3_All_Window_Closd_Cmd 3 "Not Used" 2 "off" 1 "on" 0 "Default";
VAL_ 498 BTM3_All_Window_Open_Cmd 3 "Not Used" 2 "off" 1 "on" 0 "Default";
VAL_ 498 BTM3_All_Window_Ventilate_Cmd 3 "Not Used" 2 "off" 1 "on" 0 "Default";
VAL_ 498 BTM3_OpenFLFRDoorReq 3 "Suspend" 2 "Close" 1 "Open" 0 "No request";
VAL_ 498 BTM3_OpenFRDoorReq 3 "Suspend" 2 "Close" 1 "Open" 0 "No request";
VAL_ 755 BTM4_Key_Sts 5 "Not connect" 4 "Outside connect" 3 "Outside Walk Meeting" 2 "Outside Walk Away" 1 "Outside Walk Up" 0 "Default";
VAL_ 755 BTM4_SunroofCtrl 7 "Reserved" 6 "Reserved" 5 "Reserved" 4 "Open开启" 3 "Comfort舒适" 2 "Tilt 通风" 1 "Close关闭" 0 "No Request";
VAL_ 756 BTM2_BluPhyKeyLearnSt 1 "Learning" 0 "No Learning";
VAL_ 756 BTM2_ConnectSts 3 "Smart key&Smart phone Connect" 2 "Smart phone Connect" 1 "Smart key Connect" 0 "Disconnect";
VAL_ 756 BTM2_FobGsenser 1 "moving" 0 "stay";
VAL_ 756 BTM2_Key_Position 7 "Welcome Area" 6 "Lock Area" 5 "Inside（PS）" 4 "PE Trunk" 3 "PE Passenger Side" 2 "PE Drive Side" 1 "PE Front" 0 "Default";
VAL_ 756 BTM2_LightShowMod 31 "No Action" 20 "Active20" 19 "Active19" 18 "Active18" 17 "Active17" 16 "Active16" 15 "Active15" 14 "Active14" 13 "Active13" 12 "Active12" 11 "Active11" 10 "Active10" 9 "Active9" 8 "Active8" 7 "Active7" 6 "Active6" 5 "Active5" 4 "Active4" 3 "Active3" 2 "Active2" 1 "Active1" 0 "Inactive";
VAL_ 756 BTM2_LightShowReq 3 "Reserved" 2 "OFF" 1 "ON" 0 "No request";
VAL_ 756 BTM2_SmartKey_Position 7 "Welcome Area" 6 "Lock Area" 5 "Inside（PS）" 4 "PE Trunk" 3 "PE Passenger Side" 2 "PE Drive Side" 1 "PE Front" 0 "Default";
VAL_ 756 BTM2_SmartPhone_Position 7 "Welcome Area" 6 "Lock Area" 5 "Inside（PS）" 4 "PE Trunk" 3 "PE Passenger Side" 2 "PE Drive Side" 1 "PE Front" 0 "Default";
VAL_ 756 BTM2_WelcomeLampCmd_SW 3 "Not Used" 2 "Inactive" 1 "Active" 0 "Default";
VAL_ 756 BTM2_Wal_Away_Up_SW 3 "Not Used" 2 "Inactive" 1 "Active" 0 "Default";
VAL_ 612 TC1_TrailerLinkSts 3 "Failure" 2 "reserved" 1 "ON" 0 "OFF";
VAL_ 612 TC1_TrailerModeSts 7 "Failure" 6 "reserved" 5 "reserved" 4 "reserved" 3 "reserved" 2 "reserved" 1 "Trailer Mode" 0 "Normal";
VAL_ 612 TC1_TrailerLightSts 1 "Active" 0 "Inactive";
VAL_ 612 TC1_TrailerLightFltSts 1 "Failure" 0 "Normal";
VAL_ 612 TC1_BrakeLightFltSts 1 "Failure" 0 "Normal";
VAL_ 612 TC1_LeftTurnLightFltSts 1 "Failure" 0 "Normal";
VAL_ 612 TC1_RightTurnLightFltSts 1 "Failure" 0 "Normal";
VAL_ 612 TC1_RearFogLampFltSts 1 "Failure" 0 "Normal";
VAL_ 612 TC1_BackupLightFltSts 1 "Failure" 0 "Normal";
VAL_ 612 TC1_PositionLightFltSts 1 "Failure" 0 "Normal";
VAL_ 320 CDCS3_FailSts 1 "Fail" 0 "Normal";
VAL_ 320 CDCS3_ChargeConnKpTempSw 3 "Reserved" 2 "关闭" 1 "开启" 0 "No request";
VAL_ 320 CDCS3_EnergyRecLevelSet 3 "High" 2 "Middle" 1 "Weak" 0 "No Action";
VAL_ 320 CDCS3_ePedalSw 3 "Reserved" 2 "Disable" 1 "Enable" 0 "No Request";
VAL_ 320 CDCS3_StopModeReq 3 "Reserved" 2 "Parking stop" 1 "Creep" 0 "No Request";
VAL_ 320 CDCS3_ESCOffSw 3 "Reserved" 2 "OFF" 1 "ON" 0 "No Action";
VAL_ 320 CDCS3_EPSModeSet 3 "Sport" 2 "Standard" 1 "Comfort" 0 "no action";
VAL_ 320 CDCS3_RangeModeReq 3 "Reserved" 2 "WLTC" 1 "NEDC" 0 "No Request";
VAL_ 320 CDCS3_HDCSw 3 "Reserved" 2 "OFF" 1 "ON" 0 "No Action";
VAL_ 320 CDCS3_Refuelrequest 3 "Reserved" 2 "OFF" 1 "ON" 0 "No Action";
VAL_ 320 CDCS3_CDCModeSet 3 "SPORT" 2 "NORMAL" 1 "COMFORT" 0 "NO  Request";
VAL_ 320 CDCS3_EnginIdingldleSet 3 "High" 2 "Low" 1 "Off" 0 "No request";
VAL_ 320 CDCS3_TractionModeSw 3 "Reserved" 2 "OFF" 1 "ON" 0 "No Action";
VAL_ 320 CDCS3_AVHSw 3 "Reserved" 2 "OFF" 1 "ON" 0 "No Action";
VAL_ 320 CDCS3_EPBSw 3 "Reserved" 2 "OFF" 1 "ON" 0 "No Action";
VAL_ 320 CDCS3_CSTSw 3 "Reserved" 2 "OFF" 1 "ON" 0 "No Action";
VAL_ 320 CDCS3_DriveModeSet 4 "LAUNCH" 3 "CONFORM" 2 "SPORT" 1 "ECO" 0 "No Action";
VAL_ 320 CDCS3_BrakestyleSw 3 "sport" 2 "normal" 1 "comfortable" 0 "No Action";
VAL_ 320 CDCS3_Force_Refuelrequ 3 "Reserved" 2 "OFF" 1 "ON" 0 "No Action";
VAL_ 320 CDCS3_EVModeRexOnAllowed 1 "纯电模式禁止增程器起动" 0 "not action";
VAL_ 320 CDCS3_PREMModeSet 3 "Reserved" 2 "OFF" 1 "ON" 0 "No Action";
VAL_ 320 CDCS3_RexModeSet 7 "reverse" 6 "reverse" 5 "reverse" 4 "PREM" 3 "FHEV" 2 "HEV" 1 "EV" 0 "No Action";
VAL_ 320 CDCS3_Xcoordinate 0 "No Action";
VAL_ 320 CDCS3_Ycoordinate 0 "No Action";
VAL_ 320 CDCS3_XGestureSpd 0 "No Action";
VAL_ 320 CDCS3_YGestureSpd 0 "No Action";
VAL_ 320 CDCS3_TouchEvtTyp 10 "Rotate" 9 "Zoom out" 8 "Zoom in" 7 "One finger swipe" 6 "One finger moving" 5 "One finger long press" 4 "One finger double click" 3 "One finger single click" 2 "One finger up" 1 "One finger down" 0 "No Action";
VAL_ 320 CDCS3_REXchargSet 3 "Reserved" 2 "OFF" 1 "ON" 0 "No action";
VAL_ 320 CDCS3_ForceChargingLevelSet 3 "Strong" 2 "Normal" 1 "Weak" 0 "No action";
VAL_ 442 CDCS10_Slot0_Valid 1 "Valid" 0 "Invalid";
VAL_ 442 CDCS10_Slot0_Volume 31 "Reserved";
VAL_ 442 CDCS10_WorK_status 3 "Reserved" 2 "Error" 1 "Ready" 0 "NotReady";
VAL_ 442 CDCS10_Slot1_Valid 1 "Valid" 0 "Invalid";
VAL_ 442 CDCS10_Slot1_Volume 31 "Reserved";
VAL_ 442 CDCS10_Slot2_Valid 1 "Valid" 0 "Invalid";
VAL_ 442 CDCS10_Slot2_Volume 31 "Reserved";
VAL_ 442 CDCS10_Slot3_Valid 1 "Valid" 0 "Invalid";
VAL_ 442 CDCS10_Slot3_Volume 31 "Reserved";
VAL_ 442 CDCS10_Slot4_Valid 1 "Valid" 0 "Invalid";
VAL_ 442 CDCS10_Slot4_Volume 31 "Reserved";
VAL_ 442 CDCS10_Slot5_Valid 1 "Valid" 0 "Invalid";
VAL_ 442 CDCS10_Slot5_Volume 31 "Reserved";
VAL_ 442 CDCS10_Slot6_Valid 1 "Valid" 0 "Invalid";
VAL_ 442 CDCS10_Slot6_Volume 31 "Reserved";
VAL_ 442 CDCS10_AUD_Engineering_Mode 3 "Reserved" 2 "Reserved" 1 "进入工程模式" 0 "退出工程模式";
VAL_ 442 CDCS10_Slot7_Valid 1 "Valid" 0 "Invalid";
VAL_ 442 CDCS10_Slot7_Volume 31 "Reserved";
VAL_ 442 CDCS10_AUD_Mute 1 "Mute" 0 "Unmute";
VAL_ 444 CDCS10_Slot8_Valid 1 "Valid" 0 "Invalid";
VAL_ 444 CDCS10_Slot8_Volume 31 "Reserved";
VAL_ 444 CDCS10_Slot9_Valid 1 "Valid" 0 "Invalid";
VAL_ 444 CDCS10_Slot9_Volume 31 "Reserved";
VAL_ 444 CDCS10_Slot10_Valid 1 "Valid" 0 "Invalid";
VAL_ 444 CDCS10_Slot10_Volume 31 "Reserved";
VAL_ 444 CDCS10_Slo11_Valid 1 "Valid" 0 "Invalid";
VAL_ 444 CDCS10_Slot11_Volume 31 "Reserved";
VAL_ 444 CDCS10_Slot12_Valid 1 "Valid" 0 "Invalid";
VAL_ 444 CDCS10_Slot12_Volume 31 "Reserved";
VAL_ 444 CDCS10_Slot13_Valid 1 "Valid" 0 "Invalid";
VAL_ 444 CDCS10_Slot13_Volume 31 "Reserved";
VAL_ 444 CDCS10_Slo14_Valid 1 "Valid" 0 "Invalid";
VAL_ 444 CDCS10_Slot14_Volume 31 "Reserved";
VAL_ 444 CDCS10_Slot15_Valid 1 "Valid" 0 "Invalid";
VAL_ 444 CDCS10_Slot15_Volume 31 "Reserved";
VAL_ 443 CDCS13_SwSmMode 3 "Reserved" 2 "BDCS-外后视镜" 1 "ARHUD" 0 "Default";
VAL_ 443 CDCS13_CurtainfMoveCtrlReq 3 "Reserved" 2 "Down Press" 1 "Up press" 0 "No Action";
VAL_ 443 CDCS13_Seatbelt_Sts 3 "预留" 2 "报警灯闪烁" 1 "报警灯常亮" 0 "报警灯熄灭";
VAL_ 443 CDCS13_SunRoofMoveCtrlReq 3 "Reserved" 2 "Down Press" 1 "Up press" 0 "No Action";
VAL_ 443 CDCS13_RoadCondition 7 "Reserved" 6 "Reserved" 5 "Reserved" 4 "驶出隧道且有拥堵" 3 "驶出隧道且无拥堵" 2 "驶入隧道且有拥堵" 1 "驶入隧道且无拥堵" 0 "Default";
VAL_ 794 CDCS19_Vehicle_service 3 "电池维修" 2 "发动机保养" 1 "整车保养" 0 "正常";
VAL_ 466 CDCS7_ALHMusicMode_Working 2 "Active" 1 "Inactive" 0 "No Action";
VAL_ 466 CDCS7_ALH_SW 3 "Reserved" 2 "OFF" 1 "ON" 0 "No Action";
VAL_ 466 CDCS7_ALHSelectModeCtrl 4 "General" 3 "Music" 2 "Reserved" 1 "Speed" 0 "NoRequest";
VAL_ 466 CDCS7_ALH_RValueCmd 0 "No Action";
VAL_ 466 CDCS7_ALH_GValueCmd 0 "No Action";
VAL_ 466 CDCS7_ALH_BValueCmd 0 "No Action";
VAL_ 466 CDCS7_ALH_BrightnessCm 0 "No Action";
VAL_ 466 CDCS7_FL_SeatPositionMemoryPosition 22 "Position22小憩模式前位置" 21 "Position21小憩位置" 20 "Position20" 19 "Position19" 18 "Position18" 17 "Position17" 16 "Position16" 15 "Position15" 14 "Position14" 13 "Position13" 12 "Position12" 11 "Position11" 10 "Position10" 9 "Position9" 8 "Position8" 7 "Position7" 6 "Position6" 5 "Position5" 4 "Position4" 3 "Position3" 2 "Position2" 1 "Position1" 0 "No Action";
VAL_ 466 CDCS7_FL_SeatPositionMemory_Req 1 "Request" 0 "No request";
VAL_ 466 CDCS7_FL_SeatEasygetON_OFF_Set 3 "Auto" 2 "OFF" 1 "ON" 0 "Default";
VAL_ 466 CDCS7_FR_SeatPositionMemory_Req 1 "Request" 0 "No request";
VAL_ 466 CDCS7_FL_SeatPositionLoad_Req 1 "Request" 0 "No request";
VAL_ 466 CDCS7_PositionMemoryUnbind_Req 1 "Request" 0 "No request";
VAL_ 466 CDCS7_FL_SeatPositionLoadPosition 22 "Position22小憩模式前位置" 21 "Position21小憩位置" 20 "Position20" 19 "Position19" 18 "Position18" 17 "Position17" 16 "Position16" 15 "Position15" 14 "Position14" 13 "Position13" 12 "Position12" 11 "Position11" 10 "Position10" 9 "Position9" 8 "Position8" 7 "Position7" 6 "Position6" 5 "Position5" 4 "Position4" 3 "Position3" 2 "Position2" 1 "Position1" 0 "No Action";
VAL_ 466 CDCS7_PosMemoryUnbindAccount 23 "上次应用座椅位置" 22 "坐姿2" 21 "坐姿1" 20 "小憩姿势" 19 "Account19" 18 "Account18" 17 "Accunt17" 16 "Account16" 15 "Account15" 14 "Account14" 13 "Account13" 12 "Account12" 11 "Account11" 10 "Account10" 9 "Account9" 8 "Account8" 7 "Account7" 6 "Account6" 5 "Account5" 4 "Account4" 3 "Account3" 2 "Account2" 1 "车主" 0 "No Account";
VAL_ 466 CDCS7_PositionMode 4 "Traffic jam mode" 3 "Free travel mode" 2 "Low speed mode" 1 "High speed mode" 0 "Normal mode";
VAL_ 466 CDCS7_InteriorLightingReq 3 "Auto" 2 "OFF" 1 "ON" 0 "No Action";
VAL_ 466 CDCS7_DGSW 3 "INVALID" 2 "CLOSE" 1 "OPEN" 0 "NO COMMOND";
VAL_ 466 CDCS7_FR_SeatPositionMemoryPosition 7 "Position7（一键观影位置）" 6 "Position6（零重力位置）" 5 "Position5进入小憩/零重力/一键观影前位置" 4 "Position4小憩位置" 3 "Position3" 2 "Position2" 1 "Position1" 0 "No Action";
VAL_ 466 CDCS7_FR_SeatPositionLoad_Req 1 "Request" 0 "No request";
VAL_ 466 CDCS7_DGSWLevel 31 "INVALID" 11 "100%" 10 "90%" 9 "80%" 8 "70%" 7 "60%" 6 "50%" 5 "40%" 4 "30%" 3 "20%" 2 "10%" 1 "0" 0 "NO_Req";
VAL_ 466 CDCS7_Driver_MassageModeSet 7 "RESERVED" 6 "OFF" 5 "MODE 5" 4 "MODE 4" 3 "MODE 3" 2 "MODE 2" 1 "MODE 1" 0 "No Request";
VAL_ 466 CDCS7_ALH_EntryMode 3 "Reserved" 2 "OFF" 1 "ON" 0 "No Action";
VAL_ 466 CDCS7_Passenger_MassageModeSet 7 "RESERVED" 6 "OFF" 5 "MODE 5" 4 "MODE 4" 3 "MODE 3" 2 "MODE 2" 1 "MODE 1" 0 "No Request";
VAL_ 466 CDCS7_Driver_MassageLevelSet 4 "OFF" 3 "High Intensity" 2 "Normal Intensity" 1 "Weak Intensity" 0 "No Request";
VAL_ 466 CDCS7_ALH_AEBMode 3 "Reserved" 2 "OFF" 1 "ON" 0 "No Action";
VAL_ 466 CDCS7_FR_SeatPositionLoadPosition 7 "Position7（一键观影位置）" 6 "Position6（零重力位置）" 5 "Position5进入小憩/零重力/一键观影前位置" 4 "Position4小憩位置" 3 "Position3" 2 "Position2" 1 "Position1" 0 "No Action";
VAL_ 466 CDCS7_Passenger_MassageLevelSet 4 "OFF" 3 "High Intensity" 2 "Normal Intensity" 1 "Weak Intensity" 0 "No Request";
VAL_ 466 CDCS7_FragranceCtrlReq 3 "Reserved" 2 "OFF" 1 "ON" 0 "No Action";
VAL_ 466 CDCS7_FragranceConcentrationSet 3 "High concentration" 2 "Middle concentration" 1 "Low concentration" 0 "Initial value";
VAL_ 466 CDCS7_FragrancePositionSet 3 "Fragrance Position_3 (位置3的香型）" 2 "Fragrance Position_2 (位置2的香型）" 1 "Fragrance Position_1 (位置1的香型)" 0 "Initial value";
VAL_ 466 CDCS7_LHTemp 255 "Invalid" 33 "High" 32 "31.5" 31 "31" 30 "30.5" 29 "30" 28 "29.5" 27 "29" 26 "28.5" 25 "28" 24 "27.5" 23 "27" 22 "26.5" 21 "26" 20 "25.5" 19 "25" 18 "24.5" 17 "24" 16 "23.5" 15 "23" 14 "22.5" 13 "22" 12 "21.5" 11 "21" 10 "20.5" 9 "20" 8 "19.5" 7 "19" 6 "18.5" 5 "18" 4 "17.5" 3 "17" 2 "16.5" 1 "Low" 0 "Inactive";
VAL_ 466 CDCS7_RHTemp 255 "Invalid" 33 "High" 32 "31.5" 31 "31" 30 "30.5" 29 "30" 28 "29.5" 27 "29" 26 "28.5" 25 "28" 24 "27.5" 23 "27" 22 "26.5" 21 "26" 20 "25.5" 19 "25" 18 "24.5" 17 "24" 16 "23.5" 15 "23" 14 "22.5" 13 "22" 12 "21.5" 11 "21" 10 "20.5" 9 "20" 8 "19.5" 7 "19" 6 "18.5" 5 "18" 4 "17.5" 3 "17" 2 "16.5" 1 "Low" 0 "Inactive";
VAL_ 466 CDCS7_BlowerSpdSet 10 "风速十挡" 9 "风速九挡" 8 "风速八挡" 7 "风速七挡" 6 "风速六挡" 5 "风速五挡" 4 "风速四挡" 3 "风速三挡" 2 "风速二挡" 1 "风速一挡" 0 "No Action";
VAL_ 466 CDCS7_HeatMaxSW 3 "Reserve" 2 "OFF" 1 "ON" 0 "No Action";
VAL_ 466 CDCS7_FaceFootSW 3 "Reserve" 2 "OFF" 1 "ON" 0 "No Action";
VAL_ 466 CDCS7_FaceWinSW 3 "Reserve" 2 "OFF" 1 "ON" 0 "No Action";
VAL_ 466 CDCS7_FootWinSW 3 "Reserve" 2 "OFF" 1 "ON" 0 "No Action";
VAL_ 466 CDCS7_FaceFootWinSW 3 "Reserve" 2 "OFF" 1 "ON" 0 "No Action";
VAL_ 466 CDCS7_FR_SeatEasygetON_OFF_Set 3 "Auto" 2 "OFF" 1 "ON" 0 "Default";
VAL_ 466 CDCS7_Fragrance_Position_1 15 "Reserved (预留）" 11 "Reserved (预留）" 10 "Type_10 (森林）" 9 "Type_9 (绚丽栀子花）" 8 "Type_8 (天竺葵先生）" 7 "Type_7 (保加利亚玫瑰）" 6 "Type_6 (白色广藿香）" 5 "Type_5 (清风）" 4 "Type_4 (薰衣草天堂）" 3 "Type_3 (雨后花园）" 2 "Type_2 (白茶）" 1 "Type_1 (秘境)" 0 "No Type (无香型)";
VAL_ 466 CDCS7_Fragrance_Position_2 15 "Reserved (预留）" 11 "Reserved (预留）" 10 "Type_10 (森林）" 9 "Type_9 (绚丽栀子花）" 8 "Type_8 (天竺葵先生）" 7 "Type_7 (保加利亚玫瑰）" 6 "Type_6 (白色广藿香）" 5 "Type_5 (清风）" 4 "Type_4 (薰衣草天堂）" 3 "Type_3 (雨后花园）" 2 "Type_2 (白茶）" 1 "Type_1 (秘境)" 0 "No Type (无香型)";
VAL_ 466 CDCS7_Fragrance_Position_3 15 "Reserved (预留）" 11 "Reserved (预留）" 10 "Type_10 (森林）" 9 "Type_9 (绚丽栀子花）" 8 "Type_8 (天竺葵先生）" 7 "Type_7 (保加利亚玫瑰）" 6 "Type_6 (白色广藿香）" 5 "Type_5 (清风）" 4 "Type_4 (薰衣草天堂）" 3 "Type_3 (雨后花园）" 2 "Type_2 (白茶）" 1 "Type_1 (秘境)" 0 "No Type (无香型)";
VAL_ 466 CDCS7_ALH_DriveModeSW 3 "Reserved" 2 "OFF" 1 "ON" 0 "No Action";
VAL_ 466 CDCS7_FRSeatVoiceEZEReq 3 "Reserve" 2 "OFF" 1 "ON" 0 "No Action";
VAL_ 466 CDCS7_AQSValue 7 "Reserved" 6 "Level 5" 5 "Level 4" 4 "Level 3" 3 "Level 2" 2 "Level 1" 1 "Level 0" 0 "No request";
VAL_ 466 CDCS7_BlowModStsReq 8 "Reserved" 7 "吹脸吹脚吹窗模式" 6 "吹脚吹窗模式" 5 "吹脸吹窗模式" 4 "吹脸吹脚模式" 3 "吹窗模式" 2 "吹脚模式" 1 "吹脸模式" 0 "No Action";
VAL_ 466 CDCS7_FR_ZeroGravityPause_Req 1 "Request" 0 "No request";
VAL_ 466 CDCS7_ALHSelectColourCtrl 3 "Multicolor Mode" 2 "Monoclour Mode" 1 "Drive Mode" 0 "No Action";
VAL_ 466 CDCS7_PMAirInQLevel 7 "Reserved" 6 "Level 6" 5 "Level 5" 4 "Level 4" 3 "Level 3" 2 "Level 2" 1 "Level 1" 0 "No request";
VAL_ 466 CDCS7_FLSeatVoiceHorizontalAdj 3 "reserrved" 2 "Backward" 1 "Forward" 0 "No request";
VAL_ 466 CDCS7_FLSeatVoiceVerticalAdj 3 "reserrved" 2 "Down" 1 "Up" 0 "No request";
VAL_ 466 CDCS7_FLSeatVoiceCushionTiltAdj 3 "reserrved" 2 "Downdip" 1 "Updip" 0 "No request";
VAL_ 466 CDCS7_FLSeatVoiceBackrestAngletAdj 3 "reserrved" 2 "Hypsokinesis" 1 "Foreake" 0 "No request";
VAL_ 466 CDCS7_FRSeatVoiceHorizontalAdj 3 "reserrved" 2 "Backward" 1 "Forward" 0 "No request";
VAL_ 466 CDCS7_FRSeatVoiceVerticalAdj 3 "reserrved" 2 "Down" 1 "Up" 0 "No request";
VAL_ 466 CDCS7_FRSeatLegsupporVoiceAdj 3 "reserrved" 2 "Downdip" 1 "Updip" 0 "No request";
VAL_ 466 CDCS7_FRSeatVoiceBackrestAngletAdj 3 "reserrved" 2 "Hypsokinesis" 1 "Foreake" 0 "No request";
VAL_ 468 CDCS5_ResetAllSetup 1 "Reset" 0 "No Action";
VAL_ 468 CDCS5_FactoryReset 1 "Reset" 0 "No Action";
VAL_ 468 CDCS5_RightMirrorAutoTurnDownSw 3 "Reserved" 2 "OFF" 1 "ON" 0 "No Action";
VAL_ 468 CDCS5_Key_Ventilation_Set 3 "Vent" 2 "OFF" 1 "ON" 0 "No Action";
VAL_ 468 CDCS5_AutoDfrostSw 3 "Reserved" 2 "OFF" 1 "ON" 0 "No Action";
VAL_ 468 CDCS5_AutoDrySw 3 "Reserved" 2 "OFF" 1 "ON" 0 "No Action";
VAL_ 468 CDCS5_ChargingLampSwt 3 "Reserved" 2 "OFF" 1 "ON" 0 "No Action";
VAL_ 468 CDCS5_MirrorFoldSet 2 "auto fold PE/RKE lock" 1 "not auto fold" 0 "No request";
VAL_ 468 CDCS5_StationaryModeSet 3 "Reserved" 2 "Exit Stationary Mode" 1 "Enter Stationary Mode" 0 "No request";
VAL_ 468 CDCS5_LightShowWinDown 3 "Reserved" 2 "Reserved" 1 "Window down" 0 "No request";
VAL_ 468 CDCS_BtmCallAutoSpdSw 3 "Reserved" 2 "OFF" 1 "ON" 0 "No Action";
VAL_ 468 CDCS5_AutoAionSw 3 "Reserved" 2 "OFF" 1 "ON" 0 "No Action";
VAL_ 468 CDCS5_AQSConfigSw 3 "Reserved" 2 "OFF" 1 "ON" 0 "No Action";
VAL_ 468 CDCS5_CenterLock 3 "Reserved" 2 "Unlock" 1 "Lock" 0 "No Action";
VAL_ 468 CDCS5_WindowSteam_SET 3 "big" 2 "middle" 1 "Little" 0 "No request";
VAL_ 468 CDCS5_CoolantFillingReq 3 "Reserved" 2 "OFF" 1 "ON" 0 "No Action";
VAL_ 468 CDCS5_OutLampControl 4 "AUTO" 3 "LowBeam" 2 "PositionLamp" 1 "OFF" 0 "No request";
VAL_ 468 CDCS5_FMHTimeSet 7 "Reserve2" 6 "Off" 5 "150" 4 "120" 3 "90" 2 "60" 1 "30" 0 "No Action";
VAL_ 468 CDCS5_BiologicalDetectionSw 3 "Reserved" 2 "OFF" 1 "ON" 0 "No Action";
VAL_ 468 CDCS5_BDCS_ReclockReqFdb 1 "request" 0 "no request";
VAL_ 468 CDCS5_ShutDownReq 1 "request" 0 "no request";
VAL_ 468 CDCS5_FindMyCarTimeSet 3 "30 second" 2 "20 second" 1 "10 second" 0 "No Action";
VAL_ 468 CDCS5_BacklightLevel 10 "Level 10" 9 "Level 9" 8 "Level 8" 7 "Level 7" 6 "Level 6" 5 "Level 5" 4 "Level 4" 3 "Level 3" 2 "Level 2" 1 "Level 1" 0 "No Action";
VAL_ 468 CDCS5_PetToLookAfterReq 3 "Reserved" 2 "OFF" 1 "ON" 0 "No Action";
VAL_ 468 CDCS5_ChargeLidSw 3 "Reserved" 2 "OFF" 1 "ON" 0 "No Action";
VAL_ 468 CDCS5_SpeedLockReq 3 "Reserved" 2 "OFF" 1 "ON" 0 "No Action";
VAL_ 468 CDCS5_Wiper_maintenancePos_Req 3 "Reserved" 2 "OFF" 1 "ON" 0 "No Action";
VAL_ 468 CDCS5_FindMyCarSet 3 "Reserved" 2 "闪灯" 1 "闪灯+鸣笛" 0 "No Action";
VAL_ 468 CDCS5_WelcomeLampMod 12 "预留场景4" 11 "预留场景3" 10 "预留场景2" 9 "预留场景1" 8 "泊车成功" 7 "解锁" 6 "慢充" 5 "快充" 4 "AUTOHOLD" 3 "寻车" 2 "欢送" 1 "迎宾" 0 "No Action";
VAL_ 468 CDCS5_AntiTheftRemanderSoundReq 3 "flicker_Chord（音效）" 2 "flicker" 1 "Smart_Chord（灯语+音效）" 0 "No Request";
VAL_ 468 CDCS5_LightShowMod 31 "No Action" 20 "Active20" 19 "Active19" 18 "Active18" 17 "Active17" 16 "Active16" 15 "Active15" 14 "Active14" 13 "Active13" 12 "Active12" 11 "Active11" 10 "Active10" 9 "Active9" 8 "Active8" 7 "Active7" 6 "Active6" 5 "Active5" 4 "Active4" 3 "Active3" 2 "Active2" 1 "Active1" 0 "Inactive";
VAL_ 468 CDCS5_FLHEALamp_Height 4 "Level 3" 3 "Level 2" 2 "Level 1" 1 "Level 0" 0 "No Action";
VAL_ 468 CDCS5_PARKUnLockReq 3 "Reserved" 2 "OFF" 1 "ON" 0 "No Action";
VAL_ 468 CDCS5_LOGOLampSwt 3 "Reserved" 2 "OFF" 1 "ON" 0 "No Action";
VAL_ 468 CDCS5_AUTOHOLDLampSwt 3 "Reserved" 2 "OFF" 1 "ON" 0 "No Action";
VAL_ 468 CDCS5_ElectronicLock_Pre_theft 3 "Reserved" 2 "停用防盗" 1 "启用防盗" 0 "No request";
VAL_ 468 CDCS5_LockUpWindowSET 3 "OFF" 2 "留缝" 1 "Close" 0 "No Action";
VAL_ 468 CDCS5_MirrorFoldSw 3 "Reserved" 2 "OFF" 1 "ON" 0 "No Action";
VAL_ 468 CDCS5_RL_SafetyLockSw 3 "Reserved" 2 "OFF" 1 "ON" 0 "No Action";
VAL_ 468 CDCS5_RR_SafetyLockSw 3 "Reserved" 2 "OFF" 1 "ON" 0 "No Action";
VAL_ 468 CDCS5_RearFogLampSWt 3 "Reserved" 2 "OFF" 1 "ON" 0 "No Action";
VAL_ 468 CDCS5_WalkMeeting_SW 3 "Reserved" 2 "OFF" 1 "ON" 0 "No Action";
VAL_ 468 CDCS5_Induction_PLG_SW 3 "Reserved" 2 "OFF" 1 "ON" 0 "No Action";
VAL_ 468 CDCS5_Wal_Away_Up_SW 3 "Reserved" 2 "OFF" 1 "ON" 0 "No Action";
VAL_ 468 CDCS5_HighPressureTankUnlockSW 3 "Reserved" 2 "Unlock" 1 "Lock" 0 "No Action";
VAL_ 468 CDCS5_ControlFLWindow 102 "Vent" 101 "No Action";
VAL_ 468 CDCS5_ControlRLWindow 102 "Vent" 101 "No Action";
VAL_ 468 CDCS5_ControlFRWindow 102 "Vent" 101 "No Action";
VAL_ 468 CDCS5_ControlRRWindow 102 "Vent" 101 "No Action";
VAL_ 468 CDCS5_RLSeatBackrestAdjCmd 2 "Hypsokinesis" 1 "Foreake" 0 "Norequest";
VAL_ 468 CDCS5_RRSeatBackrestAdjCmd 2 "Hypsokinesis" 1 "Foreake" 0 "Norequest";
VAL_ 468 CDCS5_LSD_FL_Away_Up_SW 3 "Reserved" 2 "OFF" 1 "ON" 0 "No Action";
VAL_ 468 CDCS5_LSD_FR_Away_Up_SW 3 "Reserved" 2 "OFF" 1 "ON" 0 "No Action";
VAL_ 468 CDCS5_LRSeatHeaterCmd 4 "High" 3 "Middle" 2 "Low" 1 "OFF" 0 "No Request";
VAL_ 468 CDCS5_RRSeatHeaterCmd 4 "High" 3 "Middle" 2 "Low" 1 "OFF" 0 "No Request";
VAL_ 468 CDCS5_DGM_IntelligentProtectionSW 2 "OFF" 1 "ON" 0 "NoRequest";
VAL_ 468 CDCS5_DGM_AutoSW 2 "OFF" 1 "ON" 0 "NoRequest";
VAL_ 468 CDCS5_FrontDoorOpenModeSet 3 "Driver door and front passenger door" 2 "Front passenger door(reserve)" 1 "Driver door" 0 "Default";
VAL_ 468 CDCS5_CabinCleanConfigSW 3 "Reserved" 2 "OFF" 1 "ON" 0 "No Action";
VAL_ 468 CDCS5_PM25AutoCleanPopup 3 "Reserved" 2 "OFF" 1 "ON" 0 "No Action";
VAL_ 468 CDCS5_WindowFollowUpDoorSW 3 "Reserved" 2 "Disable" 1 "Enable" 0 "No Request";
VAL_ 468 CDCS5_DoorHandleRetractedOverTimeSW 4 "5min" 3 "2min" 2 "30s" 1 "OFF" 0 "No Action";
VAL_ 468 CDCS5_LeftMirrorAutoTurnDownSw 3 "Reserved" 2 "OFF" 1 "ON" 0 "No Action";
VAL_ 468 CDCS5_PAB_OnOffSet 3 "Reserved" 2 "OFF" 1 "ON" 0 "No action";
VAL_ 468 CDCS5_SunRoofCtrlReq 7 "Reserved" 6 "Reserved" 5 "Reserved" 4 "Open开启" 3 "Comfort舒适" 2 "Tilt 通风" 1 "Close关闭" 0 "No Request";
VAL_ 468 CDCS5_SunRoofSLideCtrlReq 31 "Reserved" 30 "Reserved" 29 "Reserved" 28 "Reserved" 27 "Reserved" 26 "Reserved" 25 "Reserved" 24 "Reserved" 23 "Reserved" 22 "Reserved" 21 "No Action" 20 "100%" 19 "95%" 18 "90%" 17 "85%" 16 "80%" 15 "75%" 14 "70%" 13 "65%" 12 "60%" 11 "55%" 10 "50%" 9 "45%" 8 "40%" 7 "35%" 6 "30%" 5 "25%" 4 "20%" 3 "15%" 2 "10%" 1 "5%" 0 "0%";
VAL_ 468 CDCS5_CurtainCtrlReq 3 "Reserved" 2 "Open开启" 1 "Close 关闭" 0 "No Request";
VAL_ 468 CDCS5_CurtainSLideCtrlReq 31 "Reserved" 30 "Reserved" 29 "Reserved" 28 "Reserved" 27 "Reserved" 26 "Reserved" 25 "Reserved" 24 "Reserved" 23 "Reserved" 22 "Reserved" 21 "No Action" 20 "100%" 19 "95%" 18 "90%" 17 "85%" 16 "80%" 15 "75%" 14 "70%" 13 "65%" 12 "60%" 11 "55%" 10 "50%" 9 "45%" 8 "40%" 7 "35%" 6 "30%" 5 "25%" 4 "20%" 3 "15%" 2 "10%" 1 "5%" 0 "0%";
VAL_ 468 CDCS5_SunRoofStopCtrlReq 3 "Reserved" 2 "Press" 1 "No press" 0 "No Action";
VAL_ 468 CDCS5_CarTempHoldModeSw 3 "Reserved" 2 "OFF" 1 "ON" 0 "No action";
VAL_ 468 CDCS5_SmartLightReq 3 "Reserved" 2 "OFF" 1 "ON" 0 "No Action";
VAL_ 468 CDCS5_NapPositionReset 1 "Request" 0 "No request";
VAL_ 468 CDCS5_RLLumbarUpAndDwnAdioAdj 3 "reserrved" 2 "Down" 1 "Up" 0 "No request";
VAL_ 468 CDCS5_RoadRecSw 3 "Reserved" 2 "OFF" 1 "ON" 0 "No Action";
VAL_ 468 CDCS5_TrailerModeSw 3 "Reserved" 2 "OFF" 1 "ON" 0 "NO Action";
VAL_ 468 CDCS5_RR_MassageModeSet 7 "RESERVED" 6 "OFF" 5 "MODE 5" 4 "MODE 4" 3 "MODE 3" 2 "MODE 2" 1 "MODE 1" 0 "No Request";
VAL_ 468 CDCS5_RR_MassageLevelSet 4 "OFF" 3 "High Intensity" 2 "Normal Intensity" 1 "Weak Intensity" 0 "No Request";
VAL_ 468 CDCS5_ZeroGravityPositionReset 1 "Request" 0 "No request";
VAL_ 468 CDCS5_RL_MassageModeSet 7 "RESERVED" 6 "OFF" 5 "MODE 5" 4 "MODE 4" 3 "MODE 3" 2 "MODE 2" 1 "MODE 1" 0 "No Request";
VAL_ 468 CDCS5_RL_MassageLevelSet 4 "OFF" 3 "High Intensity" 2 "Normal Intensity" 1 "Weak Intensity" 0 "No Request";
VAL_ 468 CDCS5_RL_SeatVentCmd 4 "High" 3 "Middle" 2 "Low" 1 "OFF" 0 "No Request";
VAL_ 468 CDCS5_RR_SeatVentCmd 4 "High" 3 "Middle" 2 "Low" 1 "OFF" 0 "No Request";
VAL_ 468 CDCS5_RLLumbarFwdBakwdAdioAdj 3 "reserrved" 2 "Backward" 1 "Forward" 0 "No request";
VAL_ 468 CDCS5_RRLumbarUpAndDwnAdioAdj 3 "reserrved" 2 "Down" 1 "Up" 0 "No request";
VAL_ 468 CDCS5_RRLumbarFwdBakwdAdioAdj 3 "reserrved" 2 "Backward" 1 "Forward" 0 "No request";
VAL_ 468 CDCS5_WiperNozzleHeatSWt 3 "Reserved" 2 "OFF" 1 "ON" 0 "No Action";
VAL_ 501 CDCS11_LKSSetspeed 0 "No action";
VAL_ 501 CDCS11_LDW_OnOffSet 3 "reserved" 2 "OFF" 1 "ON" 0 "No action";
VAL_ 501 CDCS11_LowSpeedBSDSw 3 "reserved" 2 "OFF" 1 "ON" 0 "No action";
VAL_ 501 CDCS11_FCW_OnOffSet 3 "reserved" 2 "OFF" 1 "ON" 0 "No action";
VAL_ 501 CDCS11_AEB_OnOffSet 3 "reserved" 2 "OFF" 1 "ON" 0 "No action";
VAL_ 501 CDCS11_FCW_WarnTiming 3 "Early" 2 "Normal" 1 "Late" 0 "No action";
VAL_ 501 CDCS11_FCTA_OnOffSet 3 "reserved" 2 "OFF" 1 "ON" 0 "No action";
VAL_ 501 CDCS11_RCTA_OnOffSet 3 "reserved" 2 "OFF" 1 "ON" 0 "No action";
VAL_ 501 CDCS11_RCW_OnOffSet 3 "reserved" 2 "OFF" 1 "ON" 0 "No action";
VAL_ 501 CDCS11_DOW_OnOffSet 3 "reserved" 2 "OFF" 1 "ON" 0 "No action";
VAL_ 501 CDCS11_IHBC_SysSwState 3 "reserved" 2 "OFF" 1 "ON" 0 "No action";
VAL_ 501 CDCS11_LCA_OnOffSet 3 "reserved" 2 "OFF" 1 "ON" 0 "No action";
VAL_ 501 CDCS11_TSR_OnOffSet 3 "reserved" 2 "OFF" 1 "ON" 0 "No action";
VAL_ 501 CDCS11_AVM_3DRotate 3 "reserved" 2 "OFF" 1 "ON" 0 "No action";
VAL_ 501 CDCS11_AVM_Turnlightstart 3 "reserved" 2 "OFF" 1 "ON" 0 "No action";
VAL_ 501 CDCS11_AVM_Steeringstart 3 "reserved" 2 "OFF" 1 "ON" 0 "No action";
VAL_ 501 CDCS11_AVM_Magnifiedview 3 "reserved" 2 "OFF" 1 "ON" 0 "No action";
VAL_ 501 CDCS11_AVM_MODdetection 3 "reserved" 2 "OFF" 1 "ON" 0 "No action";
VAL_ 501 CDCS11_GM_OnOffSet 3 "reserved" 2 "OFF" 1 "ON" 0 "No action";
VAL_ 501 CDCS11_NNP_OnOffSet 3 "reserved" 2 "OFF" 1 "ON" 0 "No action";
VAL_ 501 CDCS11_DCLCSysState 3 "reserved" 2 "OFF" 1 "ON" 0 "No action";
VAL_ 501 CDCS11_ALCSysState 3 "reserved" 2 "OFF" 1 "ON" 0 "No action";
VAL_ 501 CDCS11_DriveOffPossilbeswitch 3 "reserved" 2 "OFF" 1 "ON" 0 "No action";
VAL_ 501 CDCS11_DriveOffinhibitionswitch 3 "reserved" 2 "OFF" 1 "ON" 0 "No action";
VAL_ 501 CDCS11_ADAS_SndCtrlOnOff 3 "reserved" 2 "OFF" 1 "ON" 0 "No action";
VAL_ 501 CDCS11_AVM_auxiliaryline 3 "reserved" 2 "OFF" 1 "ON" 0 "No action";
VAL_ 501 CDCS11_AVM_Raderdisplay 3 "reserved" 2 "OFF" 1 "ON" 0 "No action";
VAL_ 501 CDCS11_AVM_Transparentchassis 3 "reserved" 2 "OFF" 1 "ON" 0 "No action";
VAL_ 501 CDCS11_VoiceMode 3 "Reserved" 2 "More Tips" 1 "Simple" 0 "no action";
VAL_ 501 CDCS11_NNP_Active_OnOffSet 3 "Reserved" 2 "ON（开启）" 1 "OFF（关闭）" 0 "No Action";
VAL_ 501 CDCS11_ALC_mode 2 "Automated LC" 1 "Voice allowed LC + Lever allowed LC" 0 "no action";
VAL_ 501 CDCS11_ADSDriving_mode 3 "Radical" 2 "Normal" 1 "Basic" 0 "No action";
VAL_ 501 CDCS11_TSR_OverspeedOnoffSet 3 "Reserved" 2 "OFF" 1 "ON" 0 "No Action";
VAL_ 501 CDCS11_NNP_AutoOnOffSet 3 "Reserved" 2 "OFF" 1 "ON" 0 "No Action";
VAL_ 501 CDCS11_SnCtrl_NNP_OnOff 2 "NNP OFF Request" 1 "NNP ON Request" 0 "No Request";
VAL_ 501 CDCS11_GM_VidedIn 3 "Reserved" 2 "OFF" 1 "ON" 0 "No Action";
VAL_ 501 CDCS11_TSR_SLFOnOffSet 3 "Reserved" 2 "OFF" 1 "ON" 0 "No Action";
VAL_ 501 CDCS11_APA_FunctionMode 9 "TAB on" 8 "ISM on" 7 "AVP on" 6 "HPP on" 5 "RPA on" 4 "FAPA on" 3 "choice parking in" 2 "Parking out" 1 "Parking in" 0 "No Request";
VAL_ 501 CDCS11_TrackreverseSW 2 "Track revers off" 1 "Track revers on" 0 "No Request";
VAL_ 501 CDCS11_SetPathwaySW 2 "off" 1 "on" 0 "No Request";
VAL_ 501 CDCS11_PA_changeLanguage 2 "English" 1 "Chinese" 0 "No Action";
VAL_ 501 CDCS11_LDP_OnOffSet 3 "reserved" 2 "OFF" 1 "ON" 0 "No action";
VAL_ 501 CDCS11_AVMSw 3 "Show Calibration" 2 "Show AVM" 1 "Hide" 0 "No Request";
VAL_ 501 CDCS11_tryHPP 1 "Request" 0 "No Request";
VAL_ 501 CDCS11_NetReset 1 "Reset Request" 0 "No Request";
VAL_ 501 CDCS11_RPASw 3 "reserved" 2 "OFF" 1 "ON" 0 "No action";
VAL_ 501 CDCS11_SetSw 1 "Request" 0 "No Request";
VAL_ 501 CDCS11_SoundCtrlSetReq 7 "request AVM off" 6 "request AVM on" 5 "request RPA off" 4 "request RPA on" 3 "Start APA Parking" 2 "request APA off" 1 "request APA on" 0 "No Request";
VAL_ 501 CDCS11_location_sw 1 "parking area" 0 "default";
VAL_ 501 CDCS11_Pathrefresh 1 "Request Path refresh" 0 "No Request";
VAL_ 501 CDCS11_HPAGuideSW 2 "off" 1 "on" 0 "No Request";
VAL_ 501 CDCS11_HPAPathwaytoCloudSW 2 "off" 1 "on" 0 "No Request";
VAL_ 501 CDCS11_PathlearningSw 2 "Request Path learning off" 1 "Request Path learning on" 0 "No Request";
VAL_ 501 CDCS11_PA_screenMd 9 "TAB" 8 "ISM" 7 "AVP" 6 "HPP" 5 "RPA" 4 "FAPA" 3 "AVM" 2 "RVC" 1 "PDC" 0 "No Request";
VAL_ 501 CDCS11_PASw 3 "Reserve" 2 "Request PA off" 1 "Request PA on" 0 "No Request";
VAL_ 501 CDCS11_PA_Recover 1 "Recover" 0 "Default";
VAL_ 501 CDCS_Lcsndrequest 3 "Request inactive" 2 "Request  active right" 1 "Request active left" 0 "No action";
VAL_ 501 CDCS_Lcsndconfirm 2 "Confirm inactive" 1 "Confirm active" 0 "No action";
VAL_ 501 CDCS_SpdAdaptComfirm 2 "No" 1 "OK" 0 "No Action";
VAL_ 501 CDCS_PayModeConfirm 2 "No" 1 "OK" 0 "No Action";
VAL_ 501 CDCS11_SelectSlotID 15 "Reserved" 14 "Reserved" 13 "Reserved" 12 "slot 12" 11 "slot 11" 10 "slot 10" 9 "slot 9" 8 "slot 8" 7 "slot 7" 6 "slot 6" 5 "slot 5" 4 "slot 4" 3 "slot 3" 2 "slot 2" 1 "slot 1" 0 "No Action";
VAL_ 501 CDCS11_ParkingInReq 2 "Request  RPA" 1 "Request" 0 "No Request";
VAL_ 501 CDCS11_ParkingOutReq 2 "Request  RPA" 1 "Request" 0 "No Request";
VAL_ 501 CDCS11_AVM_ViewMode 2 "Request 3D Mode" 1 "Request 2D Mode" 0 "No Action";
VAL_ 501 CDCS11_RPA_FunctionMode 3 "choice parking in" 2 "Parking out" 1 "Parking in" 0 "No action";
VAL_ 501 CDCS11_AVM_VideoOutputFail 1 "Fail" 0 "No fail";
VAL_ 501 CDCS11_AVM_Initialization 1 "Request Initialize" 0 "No Request";
VAL_ 501 CDCS11_AVM_bodySync 3 "reserved" 2 "OFF" 1 "ON" 0 "No action";
VAL_ 501 CDCS11_AVM_licenseplateabbr 34 "台" 33 "澳" 32 "港" 31 "新" 30 "宁" 29 "蒙" 28 "桂" 27 "藏" 26 "青" 25 "甘" 24 "陕" 23 "云" 22 "贵" 21 "川" 20 "琼" 19 "粤" 18 "湘" 17 "鄂" 16 "豫" 15 "鲁" 14 "赣" 13 "闽" 12 "皖" 11 "浙" 10 "苏" 9 "黑" 8 "吉" 7 "辽" 6 "晋" 5 "冀" 4 "渝" 3 "沪" 2 "津" 1 "京" 0 "无";
VAL_ 501 CDCS11_AVM_SpeView 2 "Rear wide view" 1 "Front wide view" 0 "No Request";
VAL_ 501 CDCS11_AVM_licenseplateArea 26 "Z" 25 "Y" 24 "X" 23 "W" 22 "V" 21 "U" 20 "T" 19 "S" 18 "R" 17 "Q" 16 "P" 15 "O" 14 "N" 13 "M" 12 "L" 11 "K" 10 "J" 9 "I" 8 "H" 7 "G" 6 "F" 5 "E" 4 "D" 3 "C" 2 "B" 1 "A" 0 "Nothing";
VAL_ 501 CDCS11_AVM_StartMode 7 "Reserved" 6 "Reserved" 5 "Reserved" 4 "Reserved" 3 "24h" 2 "12h" 1 "0h" 0 "No Action";
VAL_ 501 CDCS11_AVM_LicensePlateNO1 41 "9" 40 "8" 39 "7" 38 "6" 37 "5" 36 "4" 35 "3" 34 "2" 33 "1" 32 "0" 26 "Z" 25 "Y" 24 "X" 23 "W" 22 "V" 21 "U" 20 "T" 19 "S" 18 "R" 17 "Q" 16 "P" 15 "O" 14 "N" 13 "M" 12 "L" 11 "K" 10 "J" 9 "I" 8 "H" 7 "G" 6 "F" 5 "E" 4 "D" 3 "C" 2 "B" 1 "A" 0 "Nothing";
VAL_ 501 CDCS11_AVM_LicensePlateNO2 41 "9" 40 "8" 39 "7" 38 "6" 37 "5" 36 "4" 35 "3" 34 "2" 33 "1" 32 "0" 26 "Z" 25 "Y" 24 "X" 23 "W" 22 "V" 21 "U" 20 "T" 19 "S" 18 "R" 17 "Q" 16 "P" 15 "O" 14 "N" 13 "M" 12 "L" 11 "K" 10 "J" 9 "I" 8 "H" 7 "G" 6 "F" 5 "E" 4 "D" 3 "C" 2 "B" 1 "A" 0 "Nothing";
VAL_ 501 CDCS11_DrvOffAlertSwitch 3 "reserved" 2 "OFF" 1 "ON" 0 "No action";
VAL_ 501 CDCS11_AVM_LicensePlateNO3 41 "9" 40 "8" 39 "7" 38 "6" 37 "5" 36 "4" 35 "3" 34 "2" 33 "1" 32 "0" 26 "Z" 25 "Y" 24 "X" 23 "W" 22 "V" 21 "U" 20 "T" 19 "S" 18 "R" 17 "Q" 16 "P" 15 "O" 14 "N" 13 "M" 12 "L" 11 "K" 10 "J" 9 "I" 8 "H" 7 "G" 6 "F" 5 "E" 4 "D" 3 "C" 2 "B" 1 "A" 0 "Nothing";
VAL_ 501 CDCS11_DCWposition 3 "level3" 2 "level2" 1 "level1" 0 "off";
VAL_ 501 CDCS11_AVM_LicensePlateNO4 41 "9" 40 "8" 39 "7" 38 "6" 37 "5" 36 "4" 35 "3" 34 "2" 33 "1" 32 "0" 26 "Z" 25 "Y" 24 "X" 23 "W" 22 "V" 21 "U" 20 "T" 19 "S" 18 "R" 17 "Q" 16 "P" 15 "O" 14 "N" 13 "M" 12 "L" 11 "K" 10 "J" 9 "I" 8 "H" 7 "G" 6 "F" 5 "E" 4 "D" 3 "C" 2 "B" 1 "A" 0 "Nothing";
VAL_ 501 CDCS11_EOL_Fdbk 2 "Completely Received" 1 "Ready to Receive" 0 "No request";
VAL_ 501 CDCS11_AVM_LicensePlateNO5 41 "9" 40 "8" 39 "7" 38 "6" 37 "5" 36 "4" 35 "3" 34 "2" 33 "1" 32 "0" 26 "Z" 25 "Y" 24 "X" 23 "W" 22 "V" 21 "U" 20 "T" 19 "S" 18 "R" 17 "Q" 16 "P" 15 "O" 14 "N" 13 "M" 12 "L" 11 "K" 10 "J" 9 "I" 8 "H" 7 "G" 6 "F" 5 "E" 4 "D" 3 "C" 2 "B" 1 "A" 0 "Nothing";
VAL_ 501 CDCS11_AVM_LicensePlateNO6 41 "9" 40 "8" 39 "7" 38 "6" 37 "5" 36 "4" 35 "3" 34 "2" 33 "1" 32 "0" 26 "Z" 25 "Y" 24 "X" 23 "W" 22 "V" 21 "U" 20 "T" 19 "S" 18 "R" 17 "Q" 16 "P" 15 "O" 14 "N" 13 "M" 12 "L" 11 "K" 10 "J" 9 "I" 8 "H" 7 "G" 6 "F" 5 "E" 4 "D" 3 "C" 2 "B" 1 "A" 0 "Nothing";
VAL_ 501 CDCS11_DataUp_Trigger 3 "Reserved" 2 "Reserved" 1 "trigger" 0 "no action";
VAL_ 501 CDCS11_AVM_LicensePlateNO7 41 "9" 40 "8" 39 "7" 38 "6" 37 "5" 36 "4" 35 "3" 34 "2" 33 "1" 32 "0" 26 "Z" 25 "Y" 24 "X" 23 "W" 22 "V" 21 "U" 20 "T" 19 "S" 18 "R" 17 "Q" 16 "P" 15 "O" 14 "N" 13 "M" 12 "L" 11 "K" 10 "J" 9 "I" 8 "H" 7 "G" 6 "F" 5 "E" 4 "D" 3 "C" 2 "B" 1 "A" 0 "Nothing";
VAL_ 501 CDCS11_AVM_DayNightMode 3 "Reserved" 2 "Night" 1 "Day" 0 "No Request";
VAL_ 501 CDCS11_AVM_LicensePlateNO8 41 "9" 40 "8" 39 "7" 38 "6" 37 "5" 36 "4" 35 "3" 34 "2" 33 "1" 32 "0" 26 "Z" 25 "Y" 24 "X" 23 "W" 22 "V" 21 "U" 20 "T" 19 "S" 18 "R" 17 "Q" 16 "P" 15 "O" 14 "N" 13 "M" 12 "L" 11 "K" 10 "J" 9 "I" 8 "H" 7 "G" 6 "F" 5 "E" 4 "D" 3 "C" 2 "B" 1 "A" 0 "Nothing";
VAL_ 501 CDCS11_AVM_Powertype 3 "PHEV" 2 "Traditional" 1 "EV" 0 "No Action";
VAL_ 501 CDCS11_AVM_Diaphaneity 11 "100%" 10 "90%" 9 "80%" 8 "70%" 7 "60%" 6 "50%" 5 "40%" 4 "30%" 3 "20%" 2 "10%" 1 "0" 0 "No Action";
VAL_ 501 CDCS11_AVM_DiaphaneitySw 1 "Request" 0 "No Request";
VAL_ 501 CDCS11_LDWLKAAidSwSts 7 "Reserved" 6 "Reserved" 5 "Reserved" 4 "LKA" 3 "LDW+LKA" 2 "LDW" 1 "OFF" 0 "No Request";
VAL_ 501 CDCS11_MOD_Sound_Sw 3 "Reserved" 2 "Off（关闭）" 1 "On（开启）" 0 "No Action";
VAL_ 501 CDCS11_MOD_BSD_Sw 3 "Reserved" 2 "Off（关闭）" 1 "On（开启）" 0 "No Action";
VAL_ 501 CDCS11_PA_FRS_OnOffSet 3 "Reserved" 2 "Off（关闭）" 1 "On（开启）" 0 "No Action";
VAL_ 501 CDCS11_PA_3D_OnOffSet 3 "Reserved" 2 "Off（关闭）" 1 "On（开启）" 0 "No Action";
VAL_ 501 CDCS11_PA_measure_OnOffSet 3 "Reserved" 2 "Off（关闭）" 1 "On（开启）" 0 "No Action";
VAL_ 501 CDCS11_MODSw 3 "Reserved" 2 "Off（关闭）" 1 "On（开启）" 0 "No Action";
VAL_ 501 CDCS11_VoiceNotifFrequency_mode 3 "Detailed" 2 "Simple" 1 "Basic" 0 "Not defined";
VAL_ 501 CDCS11_ACCOnOffSet 3 "Reserved" 2 "Off（关闭）" 1 "On（开启）" 0 "No Action";
VAL_ 501 CDCS11_HPASw 3 "Reserved" 2 "Off（关闭）" 1 "On（开启）" 0 "No Action";
VAL_ 501 CDCS11_PA_WarningType 3 "Reserved" 2 "TTS" 1 "Beep" 0 "No Action";
VAL_ 501 CDCS11_HPA_OnOffSet 3 "Reserved" 2 "Off（关闭）" 1 "On（开启）" 0 "No Action";
VAL_ 501 CDCS11_DeleteMapID 0 "No Action";
VAL_ 501 CDCS11_UploadMapID 0 "No Action";
VAL_ 501 CDCS11_HPAActiveConfirm 1 "Confirm" 0 "No Confirm";
VAL_ 501 CDCS11_TSR_ALSUpdataSwState 2 "on" 1 "Off" 0 "No Action";
VAL_ 501 CDCS11_HPApreparkingSw 2 "off" 1 "on" 0 "No Action";
VAL_ 501 CDCS11_HPAPathwaytoCloud_WorkSts 7 "Reserve" 6 "Reserve" 5 "Reserve" 4 "Uploading error" 3 "Uploading" 2 "Uploaded" 1 "To be uploaded" 0 "No Action";
VAL_ 501 CDCS11_TSR_SLWFVoiceSwState 3 "Reseved" 2 "on" 1 "Off" 0 "No Action";
VAL_ 501 CDCS11_ELKA_OnOffSet 3 "reserved" 2 "OFF" 1 "ON" 0 "No action";
VAL_ 501 CDCS11_Pathrelearn 1 "Request Path relearn" 0 "No Request";
VAL_ 501 CDCS11_PA_Select_ID 0 "default";
VAL_ 501 CDCS11_learnpath_St 2 "complete and upload" 1 "complete" 0 "default";
VAL_ 501 CDCS11_LDWLKA_WarnTiming 7 "Reserved" 6 "Reserved" 5 "Reserved" 4 "Reserved" 3 "Early" 2 "Normal" 1 "Late" 0 "No Action";
VAL_ 501 CDCS11_TSR_LimitOverspeedSet 255 "No Action";
VAL_ 501 CDCS11_FrbdWindowOpen_Req 3 "Reserved" 2 "No Forbid" 1 "Forbid" 0 "No Action";
VAL_ 501 CDCS11_ParkingoutSlot_Type 3 "Oblique" 2 "Parallel" 1 "Vertical" 0 "Undecided";
VAL_ 501 CDCS11_ParkingoutSlot_Dire 3 "Front" 2 "Right" 1 "Left" 0 "No request";
VAL_ 501 CDCS11_OptionalSlot_Type 3 "Oblique" 2 "Parallel" 1 "Vertical" 0 "Undecided";
VAL_ 501 CDCS11_OptionalSlot_Dire 4 "Rear" 3 "Front" 2 "Right" 1 "Left" 0 "No request";
VAL_ 501 CDCS11_OptionalSlotCoor_P0_X 0 "No Action";
VAL_ 501 CDCS11_OptionalSlotCoor_P0_Y 0 "No Action";
VAL_ 501 CDCS11_OptionalSlotCoor_P1_X 0 "No Action";
VAL_ 501 CDCS11_OptionalSlotCoor_P1_Y 0 "No Action";
VAL_ 501 CDCS11_OptionalSlotCoor_P2_X 0 "No Action";
VAL_ 501 CDCS11_OptionalSlotCoor_P2_Y 0 "No Action";
VAL_ 501 CDCS11_OptionalSlotCoor_P3_X 0 "No Action";
VAL_ 501 CDCS11_OptionalSlotCoor_P3_Y 0 "No Action";
VERSION ""

NS_ :

BS_:

BU_: GW_FD5 GW_FD6 GW_FD3 GW_FD4 GW_FD1 GW_FD2 PDCS_FD1 PDCU SRR3 SRR4 ADCU_FD3 BDCS DDCU CDCS ADCS_FD3 CDCS_OverSea TBOX FLC_ME_FD3 FLC_FD3 ICU_E02 ICU PDCS_HVM_FD1 TBOX_OverSea BMS ISC GCU EMS IDB ESC_FD3 EHB_FD3 MCU IMU ACU EPS WPC CDU AMP BAM PDCS_FD3 EVCC REPB ADCS_FD6 ADCU_FD6 FLC_ME_FD6 FLC_FD6 DLC GW_FD7 ESC_FD6 EHB_FD6

BO_ 515 CDCS_Fr15_203: 16 CDCS
 SG_ CDCS15_ALM_MusicMode_Rvalue : 7|8@0+ (1,0) [0|255] "NoUnit" GW_FD2,BDCS
 SG_ CDCS15_ALM_MusicMode_Gvalue : 15|8@0+ (1,0) [0|255] "NoUnit" GW_FD2,BDCS
 SG_ CDCS15_ALM_MusicMode_Bvalue : 23|8@0+ (1,0) [0|255] "NoUnit" GW_FD2,BDCS
 SG_ CDCS15_ALM_MusicMode_Brightness : 30|7@0+ (1,0) [0|127] "NoUnit" GW_FD2,BDCS
 SG_ CDCS15_ChildrenPresentDetection : 31|1@0+ (1,0) [0|1] "NoUnit" GW_FD2,BDCS
 SG_ CDCS15_FLSeatHorizontalAdj : 33|2@0+ (1,0) [0|3] "NoUnit" GW_FD2,BDCS
 SG_ CDCS15_FLSeatVerticalAdj : 35|2@0+ (1,0) [0|3] "NoUnit" GW_FD2,BDCS
 SG_ CDCS15_FLSeatCushionTiltAdj : 37|2@0+ (1,0) [0|3] "NoUnit" GW_FD2,BDCS
 SG_ CDCS15_FLSeatBackrestAngletAdj : 39|2@0+ (1,0) [0|3] "NoUnit" GW_FD2,BDCS
 SG_ CDCS15_FRSeatHorizontalAdj : 41|2@0+ (1,0) [0|3] "NoUnit" GW_FD2,BDCS
 SG_ CDCS15_FRSeatVerticalAdj : 43|2@0+ (1,0) [0|3] "NoUnit" GW_FD2,BDCS
 SG_ CDCS15_FRSeatLegsupportAdj : 45|2@0+ (1,0) [0|3] "NoUnit" GW_FD2,BDCS
 SG_ CDCS15_FRSeatBackrestAngletAdj : 47|2@0+ (1,0) [0|3] "NoUnit" GW_FD2,BDCS
 SG_ CDCS15_FLLumbarUpAndDownAdj : 49|2@0+ (1,0) [0|3] "NoUnit" GW_FD2,BDCS
 SG_ CDCS15_FLLumbaForwardorBackwardAdj : 51|2@0+ (1,0) [0|3] "NoUnit" GW_FD2,BDCS
 SG_ CDCS15_FRLumbarUpAndDownAdj : 53|2@0+ (1,0) [0|3] "NoUnit" GW_FD2,BDCS
 SG_ CDCS15_FRLumbaForwardorBackwardAdj : 55|2@0+ (1,0) [0|3] "NoUnit" GW_FD2,BDCS
 SG_ CDCS15_AILampVoiceMode : 63|4@0+ (1,0) [0|15] "NoUnit" Vector__XXX
 SG_ CDCS15_AILampMode : 68|5@0+ (1,0) [0|31] "NoUnit" Vector__XXX
 SG_ CDCS15_DMS_DriverStatusValid : 69|1@0+ (1,0) [0|1] "NoUnit" FLC_ME_FD3,GW_FD3
 SG_ CDCS15_DMS_DriverStatus : 71|2@0+ (1,0) [0|3] "NoUnit" FLC_ME_FD3,FLC_FD3,GW_FD3,ADCU_FD3,ADCS_FD3
 SG_ CDCS15_Storage_St : 72|1@0+ (1,0) [0|1] "NoUnit" FLC_ME_FD3,FLC_FD3,GW_FD3,ADCU_FD3,ADCS_FD3
 SG_ CDCS15_USB_St : 73|1@0+ (1,0) [0|1] "NoUnit" FLC_ME_FD3,FLC_FD3,GW_FD3,ADCU_FD3,ADCS_FD3
 SG_ CDCS15_UserSceneMode : 79|4@0+ (1,0) [0|15] "NoUnit" TBOX,FLC_ME_FD3,FLC_FD3,GW_FD5,GW_FD3,ADCU_FD3,GW_FD2,BDCS,ADCS_FD3,TBOX_OverSea
 SG_ CDCS15_NNP_DriverFatigueStatus : 85|2@0+ (1,0) [0|3] "NoUnit" FLC_ME_FD3,ACU,FLC_FD3,GW_FD3,GW_FD1,ADCS_FD3
 SG_ CDCS15_NNP_DriverDistractedStatus : 87|2@0+ (1,0) [0|3] "NoUnit" FLC_ME_FD3,ACU,FLC_FD3,GW_FD3,GW_FD1,ADCS_FD3
 SG_ CDCS15_ALHSelectTheme : 98|3@0+ (1,0) [0|7] "NoUnit" GW_FD2,BDCS
 SG_ CDCS15_RL_LumbarUpAndDownAdj : 113|2@0+ (1,0) [0|3] "NoUnit" GW_FD2,BDCS
 SG_ CDCS15_RL_LumbarFwdBakwdAdj : 115|2@0+ (1,0) [0|3] "NoUnit" GW_FD2,BDCS
 SG_ CDCS15_RR_LumbarUpAndDownAdj : 117|2@0+ (1,0) [0|3] "NoUnit" GW_FD2,BDCS
 SG_ CDCS15_RR_LumbarFwdBakwdAdj : 119|2@0+ (1,0) [0|3] "NoUnit" GW_FD2,BDCS
 SG_ CDCS15_FRSeatLegsupportLengthAdj : 121|2@0+ (1,0) [0|3] "NoUnit" GW_FD2,BDCS
 SG_ CDCS15_FRSeatLegsupporLengthVoiceAd : 123|2@0+ (1,0) [0|3] "NoUnit" GW_FD2,BDCS
 SG_ CDCS15_ALH_ADASWarning : 125|2@0+ (1,0) [0|3] "NoUnit" GW_FD2,BDCS
 SG_ CDCS15_ALHBrightnessAutoMode : 127|2@0+ (1,0) [0|3] "NoUnit" GW_FD2,BDCS

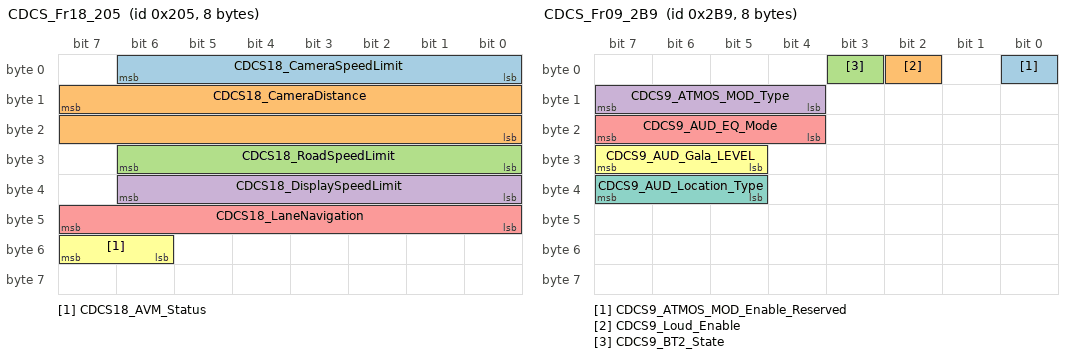
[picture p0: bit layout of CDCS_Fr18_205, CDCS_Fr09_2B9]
BO_ 517 CDCS_Fr18_205: 8 CDCS
 SG_ CDCS18_CameraSpeedLimit : 6|7@0+ (1,0) [0|120] "km/h" FLC_ME_FD6,FLC_FD6,GW_FD6,ADCS_FD6
 SG_ CDCS18_CameraDistance : 15|16@0+ (1,0) [0|30000] "m" FLC_ME_FD6,FLC_FD6,GW_FD6,ADCS_FD6
 SG_ CDCS18_RoadSpeedLimit : 30|7@0+ (1,0) [0|120] "km/h" FLC_ME_FD6,FLC_FD6,GW_FD6,ADCS_FD6
 SG_ CDCS18_DisplaySpeedLimit : 38|7@0+ (1,0) [0|120] "km/h" FLC_ME_FD6,FLC_FD6,GW_FD6,ADCS_FD6
 SG_ CDCS18_LaneNavigation : 47|8@0+ (1,0) [0|255] "NoUnit" FLC_ME_FD6,FLC_FD6,GW_FD6,ADCS_FD6
 SG_ CDCS18_AVM_Status : 55|2@0+ (1,0) [0|3] "NoUnit" FLC_ME_FD6,FLC_FD6,GW_FD6,ADCS_FD6

BO_ 697 CDCS_Fr09_2B9: 8 CDCS
 SG_ CDCS9_ATMOS_MOD_Enable_Reserved : 0|1@0+ (1,0) [0|1] "NoUnit" AMP
 SG_ CDCS9_Loud_Enable : 2|1@0+ (1,0) [0|1] "NoUnit" AMP
 SG_ CDCS9_BT2_State : 3|1@0+ (1,0) [0|1] "NoUnit" AMP
 SG_ CDCS9_ATMOS_MOD_Type : 15|4@0+ (1,0) [0|15] "NoUnit" AMP
 SG_ CDCS9_AUD_EQ_Mode : 23|4@0+ (1,0) [0|15] "NoUnit" AMP
 SG_ CDCS9_AUD_Gala_LEVEL : 31|3@0+ (1,0) [0|7] "NoUnit" AMP
 SG_ CDCS9_AUD_Location_Type : 39|3@0+ (1,0) [0|7] "NoUnit" AMP

BO_ 757 CDCS_Fr02_2F5: 8 CDCS
 SG_ CDCS2_DischargeObejectSelect : 7|2@0+ (1,0) [0|3] "NoUnit" BMS,GW_FD1,PDCS_HVM_FD1
 SG_ CDCS2_DischargeModeSelect : 9|2@0+ (1,0) [0|3] "NoUnit" BMS,GW_FD1,PDCS_HVM_FD1
 SG_ CDCS2_ICUBacklightMode : 11|2@0+ (1,0) [0|3] "NoUnit" ICU_E02,ICU
 SG_ CDCS2_DischargeActiveSw : 13|2@0+ (1,0) [0|3] "NoUnit" BMS,GW_FD1,PDCS_HVM_FD1
 SG_ CDCS2_WPC_OnOffSw : 15|2@0+ (1,0) [0|3] "NoUnit" WPC
 SG_ CDCS2_ICUMod_CtrlReq : 17|2@0+ (1,0) [0|3] "NoUnit" ICU_E02,ICU
 SG_ CDCS2_ICUDisplayMode : 19|2@0+ (1,0) [0|3] "NoUnit" ICU_E02,ICU
 SG_ CDCS2_ICUTripmeter_Set : 21|2@0+ (1,0) [0|3] "NoUnit" ICU_E02,ICU
 SG_ CDCS2_PrivacyForbidLocReq : 23|2@0+ (1,0) [0|3] "NoUnit" GW_FD5,TBOX_OverSea
 SG_ CDCS2_SOClowerlimit : 31|8@0+ (1,0) [0|100] "%" BMS,GW_FD1,PDCS_HVM_FD1
 SG_ CDCS2_PrivacyForbidDataReq : 33|2@0+ (1,0) [0|3] "NoUnit" GW_FD5,TBOX_OverSea
 SG_ CDCS2_TimezoneSet : 39|6@0+ (1,0) [0|63] "NoUnit" GW_FD5,TBOX_OverSea
 SG_ CDCS2_ICUBacklightLevel : 51|4@0+ (1,0) [0|15] "NoUnit" ICU_E02,ICU
 SG_ CDCS2_AvgEnergySET : 52|1@0+ (1,0) [0|1] "NoUnit" ICU_E02,ICU
 SG_ CDCS2_UnlockElectronicLock : 55|2@0+ (1,0) [0|3] "NoUnit" BMS,GW_FD1,PDCS_HVM_FD1
 SG_ CDCS2_DischargeMainSw : 57|2@0+ (1,0) [0|3] "NoUnit" BMS,GW_FD1,PDCS_HVM_FD1
 SG_ CDCS2_ChgConKpTemp : 59|2@0+ (1,0) [0|3] "NoUnit" BMS,GW_FD1,PDCS_HVM_FD1

BO_ 789 CDCS_Fr01_315: 8 CDCS
 SG_ CDCS1_AC_SW : 1|2@0+ (1,0) [0|3] "NoUnit" GW_FD2,BDCS
 SG_ CDCS1_CLM_CycleSw : 3|2@0+ (1,0) [0|3] "NoUnit" GW_FD2,BDCS
 SG_ CDCS1_CLM_BlowerSpdPlus : 5|2@0+ (1,0) [0|3] "NoUnit" GW_FD2,BDCS
 SG_ CDCS1_CLM_AutoSw : 7|2@0+ (1,0) [0|3] "NoUnit" GW_FD2,BDCS
 SG_ CDCS1_CLM_LHTempPlus : 8|1@0+ (1,0) [0|1] "NoUnit" GW_FD2,BDCS
 SG_ CDCS1_CLM_LHTempMinus : 9|1@0+ (1,0) [0|1] "NoUnit" GW_FD2,BDCS
 SG_ CDCS1_CLM_RHTempPlus : 10|1@0+ (1,0) [0|1] "NoUnit" GW_FD2,BDCS
 SG_ CDCS1_CLM_RHTempMinus : 11|1@0+ (1,0) [0|1] "NoUnit" GW_FD2,BDCS
 SG_ CDCS1_CLM_FootSw : 13|2@0+ (1,0) [0|3] "NoUnit" GW_FD2,BDCS
 SG_ CDCS1_CLM_AnionSw : 15|2@0+ (1,0) [0|3] "NoUnit" GW_FD2,BDCS
 SG_ CDCS1_CLM_BlowerSpdSet : 19|4@0+ (1,0) [0|15] "NoUnit" GW_FD2,BDCS
 SG_ CDCS1_CLM_AcFilterResetReq : 20|1@0+ (1,0) [0|1] "NoUnit" GW_FD2,BDCS
 SG_ CDCS1_CLM_BlowerSpdSetValid : 21|1@0+ (1,0) [0|1] "NoUnit" GW_FD2,BDCS
 SG_ CDCS1_CLM_LHTempSetValid : 22|1@0+ (1,0) [0|1] "NoUnit" GW_FD2,BDCS
 SG_ CDCS1_CLM_RHTempSetValid : 23|1@0+ (1,0) [0|1] "NoUnit" GW_FD2,BDCS
 SG_ CDCS1_CLM_LHTempSet : 29|6@0+ (1,0) [0|63] "NoUnit" GW_FD2,BDCS
 SG_ CDCS1_CLM_DualSw : 31|2@0+ (1,0) [0|3] "NoUnit" GW_FD2,BDCS
 SG_ CDCS1_CLM_RHTempSet : 37|6@0+ (1,0) [0|63] "NoUnit" GW_FD2,BDCS
 SG_ CDCS1_BDCS_RearDefrostSw : 41|2@0+ (1,0) [0|3] "NoUnit" PDCS_FD1,PDCU,GW_FD1,GW_FD2,BDCS,DDCU,PDCS_HVM_FD1
 SG_ CDCS1_CLM_OnoffSw : 43|2@0+ (1,0) [0|3] "NoUnit" GW_FD2,BDCS
 SG_ CDCS1_CLM_BlowerSpdMinus : 45|2@0+ (1,0) [0|3] "NoUnit" GW_FD2,BDCS
 SG_ CDCS1_CLM_WindowSw : 47|2@0+ (1,0) [0|3] "NoUnit" PDCS_FD1,GW_FD1,GW_FD2,BDCS,PDCS_HVM_FD1
 SG_ CDCS1_CLM_VentSw : 49|2@0+ (1,0) [0|3] "NoUnit" GW_FD2,BDCS
 SG_ CDCS1_ACMaxSW : 51|2@0+ (1,0) [0|3] "NoUnit" GW_FD2,BDCS
 SG_ CDCS1_AirClean : 53|2@0+ (1,0) [0|3] "NoUnit" GW_FD2,BDCS
 SG_ CDCS1_AC_ECONMode : 55|2@0+ (1,0) [0|3] "NoUnit" GW_FD2,BDCS
 SG_ CDCS1_LEAOSts : 58|3@0+ (1,0) [0|7] "NoUnit" GW_FD2,BDCS
 SG_ CDCS1_REAOSts : 61|3@0+ (1,0) [0|7] "NoUnit" GW_FD2,BDCS
 SG_ CDCS1_AC_Ventilation : 63|2@0+ (1,0) [0|3] "NoUnit" GW_FD2,BDCS

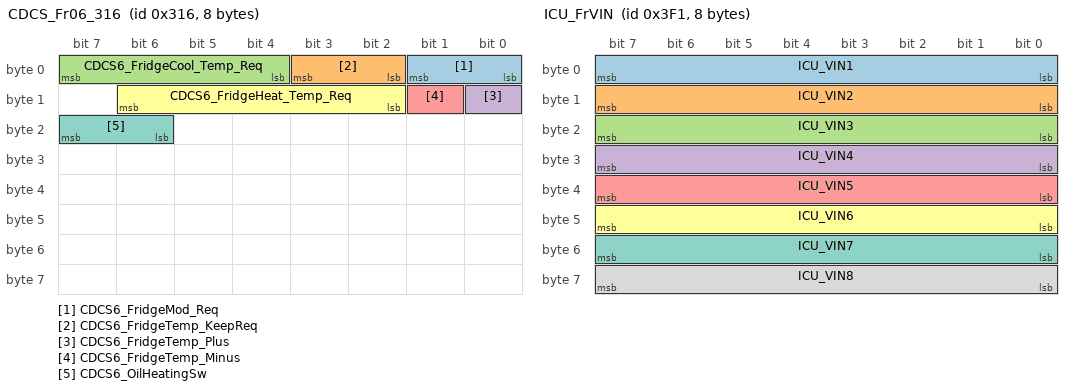
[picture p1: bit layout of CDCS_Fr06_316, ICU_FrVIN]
BO_ 790 CDCS_Fr06_316: 8 CDCS
 SG_ CDCS6_FridgeMod_Req : 1|2@0+ (1,0) [0|3] "NoUnit" GW_FD2,BDCS
 SG_ CDCS6_FridgeTemp_KeepReq : 3|2@0+ (1,0) [0|3] "NoUnit" GW_FD2,BDCS
 SG_ CDCS6_FridgeCool_Temp_Req : 7|4@0+ (1,0) [0|15] "NoUnit" GW_FD2,BDCS
 SG_ CDCS6_FridgeTemp_Plus : 8|1@0+ (1,0) [0|1] "NoUnit" GW_FD2,BDCS
 SG_ CDCS6_FridgeTemp_Minus : 9|1@0+ (1,0) [0|1] "NoUnit" GW_FD2,BDCS
 SG_ CDCS6_FridgeHeat_Temp_Req : 14|5@0+ (1,0) [0|31] "NoUnit" GW_FD2,BDCS
 SG_ CDCS6_OilHeatingSw : 23|2@0+ (1,0) [0|3] "NoUnit" GW_FD2,BDCS

BO_ 896 CDCS_Fr08_380: 8 CDCS
 SG_ CDCS8_VoiceTrunkCtrl : 1|2@0+ (1,0) [0|3] "NoUnit" GW_FD2,BDCS
 SG_ CDCS8_TrunkSWReq : 3|2@0+ (1,0) [0|3] "NoUnit" GW_FD2,BDCS
 SG_ CDCS8_RearDoorHeightSet : 5|2@0+ (1,0) [0|3] "NoUnit" GW_FD2,BDCS
 SG_ CDCS8_FRSeatEZEReq : 7|2@0+ (1,0) [0|3] "NoUnit" GW_FD2,BDCS
 SG_ CDCS8_FLSeatEZEReq : 13|2@0+ (1,0) [0|3] "NoUnit" GW_FD2,BDCS
 SG_ CDCS8_SOC_LampSwt : 15|2@0+ (1,0) [0|3] "NoUnit" GW_FD2,BDCS
 SG_ CDCS8_FLLumbarUpAndDownAdj : 17|2@0+ (1,0) [0|3] "NoUnit" GW_FD2,BDCS
 SG_ CDCS8_FLLumbaForwardorBackwardAdj : 19|2@0+ (1,0) [0|3] "NoUnit" GW_FD2,BDCS
 SG_ CDCS8_ALH_TemperatureSW : 21|2@0+ (1,0) [0|3] "NoUnit" GW_FD2,BDCS
 SG_ CDCS8_FRLumbarUpAndDownAdj : 23|2@0+ (1,0) [0|3] "NoUnit" GW_FD2,BDCS
 SG_ CDCS8_FRLumbaForwardorBackwardAdj : 25|2@0+ (1,0) [0|3] "NoUnit" GW_FD2,BDCS
 SG_ CDCS8_IncomingCall : 29|2@0+ (1,0) [0|3] "NoUnit" GW_FD2,BDCS
 SG_ CDCS8_FrontSeatAutoEZEReq : 33|2@0+ (1,0) [0|3] "NoUnit" GW_FD2,BDCS
 SG_ CDCS8_FRSeatHeatCmd : 36|3@0+ (1,0) [0|7] "NoUnit" GW_FD2,BDCS
 SG_ CDCS8_FLSeatHeatCmd : 39|3@0+ (1,0) [0|7] "NoUnit" GW_FD2,BDCS
 SG_ CDCS8_FLSeatVentCmd : 42|3@0+ (1,0) [0|7] "NoUnit" GW_FD2,BDCS
 SG_ CDCS8_FRSeatVentCmd : 55|3@0+ (1,0) [0|7] "NoUnit" GW_FD2,BDCS

BO_ 805 ICU_Fr02_325: 8 ICU_E02
 SG_ ICU2_Odometer : 7|24@0+ (0.1,0) [0|1677721.4] "km" PDCS_FD1,PDCU,IDB,ESC_FD3,ADCU_FD3,EPS,WPC,EHB_FD3,CDCS,CDU,ISC,AMP,SRR3,SRR4,BMS,EMS,BDCS,DDCU,BAM,ADCS_FD3,CDCS_OverSea,TBOX,FLC_ME_FD3,ACU,FLC_FD3,GW_FD5,GW_FD6,GCU,GW_FD3,GW_FD1,GW_FD2,MCU,PDCS_HVM_FD1,TBOX_OverSea
 SG_ ICU2_OdometerUpdate : 24|1@0+ (1,0) [0|1] "NoUnit" TBOX,GW_FD5,GW_FD2,BDCS,TBOX_OverSea

BO_ 1009 ICU_FrVIN: 8 ICU_E02
 SG_ ICU_VIN1 : 7|8@0+ (1,0) [0|255] "NoUnit" TBOX,GW_FD5,GW_FD2,BDCS,TBOX_OverSea
 SG_ ICU_VIN2 : 15|8@0+ (1,0) [0|255] "NoUnit" TBOX,GW_FD5,GW_FD2,BDCS,TBOX_OverSea
 SG_ ICU_VIN3 : 23|8@0+ (1,0) [0|255] "NoUnit" TBOX,GW_FD5,GW_FD2,BDCS,TBOX_OverSea
 SG_ ICU_VIN4 : 31|8@0+ (1,0) [0|255] "NoUnit" TBOX,GW_FD5,GW_FD2,BDCS,TBOX_OverSea
 SG_ ICU_VIN5 : 39|8@0+ (1,0) [0|255] "NoUnit" TBOX,GW_FD5,GW_FD2,BDCS,TBOX_OverSea
 SG_ ICU_VIN6 : 47|8@0+ (1,0) [0|255] "NoUnit" TBOX,GW_FD5,GW_FD2,BDCS,TBOX_OverSea
 SG_ ICU_VIN7 : 55|8@0+ (1,0) [0|255] "NoUnit" TBOX,GW_FD5,GW_FD2,BDCS,TBOX_OverSea
 SG_ ICU_VIN8 : 63|8@0+ (1,0) [0|255] "NoUnit" TBOX,GW_FD5,GW_FD2,BDCS,TBOX_OverSea

BO_ 489 CDCS_Fr21_1E9: 16 CDCS_OverSea
 SG_ CDCS21_NavSpeedLimitStatus : 5|4@0+ (1,0) [0|15] "" FLC_ME_FD6,GW_FD6
 SG_ CDCS21_Nav_CountryID : 15|8@0+ (1,0) [0|255] "" FLC_ME_FD6,GW_FD6
 SG_ CDCS21_Nav_SpeedLimitUnits : 7|2@0+ (1,0) [0|3] "" FLC_ME_FD6,GW_FD6
 SG_ CDCS21_Nav_CurrRoadType : 23|4@0+ (1,0) [0|15] "" FLC_ME_FD6,GW_FD6
 SG_ CDCS21_NavSpeedlimit : 31|6@0+ (1,0) [0|63] "" FLC_ME_FD6,GW_FD6
 SG_ CDCS21_NavRampDistance : 39|9@0+ (1,0) [0|511] "m" FLC_ME_FD6,GW_FD6
 SG_ CDCS21_NavSpeedlimit_Rain : 45|6@0+ (1,0) [0|63] "" FLC_ME_FD6,GW_FD6
 SG_ CDCS21_NavSpeedlimit_Snow : 55|6@0+ (1,0) [0|63] "" FLC_ME_FD6,GW_FD6
 SG_ CDCS21_NavSpeedlimit_fog : 63|6@0+ (1,0) [0|63] "" FLC_ME_FD6,GW_FD6
 SG_ CDCS21_NavSpeedlimitSign_Distance : 71|13@0+ (1,0) [0|8191] "m" FLC_ME_FD6,GW_FD6

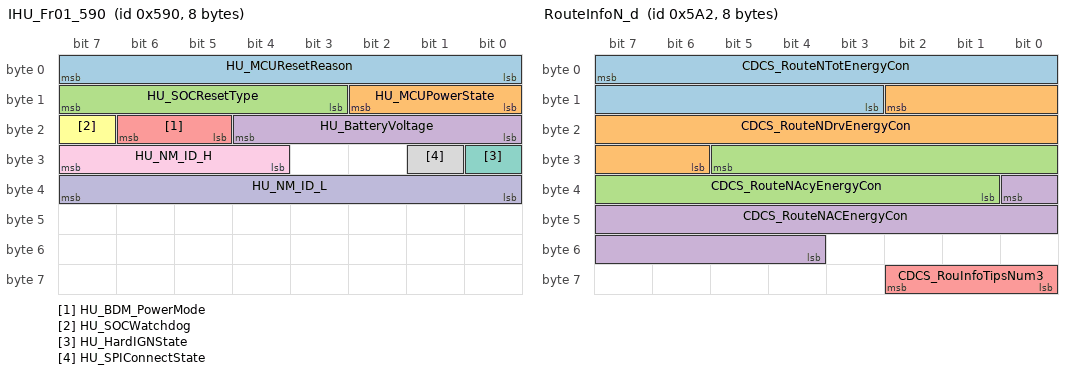
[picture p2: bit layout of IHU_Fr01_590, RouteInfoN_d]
BO_ 1424 IHU_Fr01_590: 8 CDCS_OverSea
 SG_ HU_MCUResetReason : 7|8@0+ (1,0) [0|127] "NoUnit" Vector__XXX
 SG_ HU_MCUPowerState : 10|3@0+ (1,0) [0|7] "NoUnit" Vector__XXX
 SG_ HU_SOCResetType : 15|5@0+ (1,0) [0|31] "NoUnit" Vector__XXX
 SG_ HU_BatteryVoltage : 20|5@0+ (1,0) [0|31] "NoUnit" Vector__XXX
 SG_ HU_BDM_PowerMode : 22|2@0+ (1,0) [0|3] "NoUnit" Vector__XXX
 SG_ HU_SOCWatchdog : 23|1@0+ (1,0) [0|1] "NoUnit" Vector__XXX
 SG_ HU_HardIGNState : 24|1@0+ (1,0) [0|1] "NoUnit" Vector__XXX
 SG_ HU_SPIConnectState : 25|1@0+ (1,0) [0|1] "NoUnit" Vector__XXX
 SG_ HU_NM_ID_H : 31|4@0+ (1,0) [0|15] "NoUnit" Vector__XXX
 SG_ HU_NM_ID_L : 39|8@0+ (1,0) [0|255] "NoUnit" Vector__XXX

BO_ 1544 CDCS_NM_608: 8 CDCS
 SG_ CDCS_SourceNodeIdentifier : 7|8@0+ (1,0) [0|255] "NoUnit" Vector__XXX
 SG_ CDCS_RepeatMessageRequest : 8|1@0+ (1,0) [0|1] "NoUnit" Vector__XXX
 SG_ CDCS_Reserve1 : 11|3@0+ (1,0) [0|3] "NoUnit" Vector__XXX
 SG_ CDCS_ActiveWakeup : 12|1@0+ (1,0) [0|1] "NoUnit" Vector__XXX
 SG_ CDCS_Reserve2 : 15|3@0+ (1,0) [0|7] "NoUnit" Vector__XXX
 SG_ CDCS_WakeUp_KL15 : 16|1@0+ (1,0) [0|1] "NoUnit" Vector__XXX
 SG_ CDCS_WakeUp_NM : 17|1@0+ (1,0) [0|1] "NoUnit" Vector__XXX
 SG_ CDCS_RepeatFromSleep : 24|1@0+ (1,0) [0|1] "NoUnit" Vector__XXX
 SG_ CDCS_RepeatFromPrepare : 25|1@0+ (1,0) [0|1] "NoUnit" Vector__XXX
 SG_ CDCS_NormalFromRepeat : 26|1@0+ (1,0) [0|1] "NoUnit" Vector__XXX
 SG_ CDCS_NormalFromReady : 27|1@0+ (1,0) [0|1] "NoUnit" Vector__XXX
 SG_ CDCS_RepeatFromReady : 28|1@0+ (1,0) [0|1] "NoUnit" Vector__XXX
 SG_ CDCS_RepeatFromNormal : 29|1@0+ (1,0) [0|1] "NoUnit" Vector__XXX
 SG_ CDCS_RemainNetworkWakeUpReason1 : 32|1@0+ (1,0) [0|1] "NoUnit" Vector__XXX
 SG_ CDCS_RemainNetworkWakeUpReason2 : 33|1@0+ (1,0) [0|1] "NoUnit" Vector__XXX
 SG_ CDCS_RemainNetworkWakeUpReason3 : 34|1@0+ (1,0) [0|1] "NoUnit" Vector__XXX
 SG_ CDCS_RemainNetworkWakeUpReason4 : 35|1@0+ (1,0) [0|1] "NoUnit" Vector__XXX

BO_ 1440 RouteInfoN_a_b: 64 CDCS
 SG_ CDCS_RouteNTraPonlongitude1or8 : 7|36@0+ (1.0E-7,-359.9999999) [-359.9999999|359.9999999] "" PDCS_FD1,GW_FD1,PDCS_HVM_FD1
 SG_ CDCS_RouteNTraPonlatitude1or8 : 35|36@0+ (1.0E-7,-359.9999999) [-359.9999999|359.9999999] "" PDCS_FD1,GW_FD1,PDCS_HVM_FD1
 SG_ CDCS_RouteNTraPonlongitude2or9 : 79|36@0+ (1.0E-7,-359.9999999) [-359.9999999|359.9999999] "" PDCS_FD1,GW_FD1,PDCS_HVM_FD1
 SG_ CDCS_RouteNTraPonlatitude2or9 : 107|36@0+ (1.0E-7,-359.9999999) [-359.9999999|359.9999999] "" PDCS_FD1,GW_FD1,PDCS_HVM_FD1
 SG_ CDCS_RouteNTraPonlongitude3or10 : 151|36@0+ (1.0E-7,-359.9999999) [-359.9999999|359.9999999] "" PDCS_FD1,GW_FD1,PDCS_HVM_FD1
 SG_ CDCS_RouteNTraPonlatitude3or10 : 179|36@0+ (1.0E-7,-359.9999999) [-359.9999999|359.9999999] "" PDCS_FD1,GW_FD1,PDCS_HVM_FD1
 SG_ CDCS_RouteNTraPonlongitude4or11 : 223|36@0+ (1.0E-7,-359.9999999) [-359.9999999|359.9999999] "" PDCS_FD1,GW_FD1,PDCS_HVM_FD1
 SG_ CDCS_RouteNTraPonlatitude4or11 : 251|36@0+ (1.0E-7,-359.9999999) [-359.9999999|359.9999999] "" PDCS_FD1,GW_FD1,PDCS_HVM_FD1
 SG_ CDCS_RouteNTraPonlongitude5or12 : 295|36@0+ (1.0E-7,-359.9999999) [-359.9999999|359.9999999] "" PDCS_FD1,GW_FD1,PDCS_HVM_FD1
 SG_ CDCS_RouteNTraPonlatitude5or12 : 323|36@0+ (1.0E-7,-359.9999999) [-359.9999999|359.9999999] "" PDCS_FD1,GW_FD1,PDCS_HVM_FD1
 SG_ CDCS_RouteNTraPonlongitude6or13 : 367|36@0+ (1.0E-7,-359.9999999) [-359.9999999|359.9999999] "" PDCS_FD1,GW_FD1,PDCS_HVM_FD1
 SG_ CDCS_RouteNTraPonlatitude6or13 : 395|36@0+ (1.0E-7,-359.9999999) [-359.9999999|359.9999999] "" PDCS_FD1,GW_FD1,PDCS_HVM_FD1
 SG_ CDCS_RouteNTraPonlongitude7or14 : 439|36@0+ (1.0E-7,-359.9999999) [-359.9999999|359.9999999] "" PDCS_FD1,GW_FD1,PDCS_HVM_FD1
 SG_ CDCS_RouteNTraPonlatitude7or14 : 467|36@0+ (1.0E-7,-359.9999999) [-359.9999999|359.9999999] "" PDCS_FD1,GW_FD1,PDCS_HVM_FD1
 SG_ CDCS_RouteInfoTipsNum1 : 511|8@0+ (1,0) [0|128] "" PDCS_FD1,GW_FD1,PDCS_HVM_FD1

BO_ 1441 RouteInfoN_c: 64 CDCS
 SG_ CDCS_RouteNTraPonlongitude15 : 7|36@0+ (1.0E-7,-359.9999999) [-359.9999999|359.9999999] "" PDCS_FD1,GW_FD1,PDCS_HVM_FD1
 SG_ CDCS_RouteNTraPonlatitude15 : 35|36@0+ (1.0E-7,-359.9999999) [-359.9999999|359.9999999] "" PDCS_FD1,GW_FD1,PDCS_HVM_FD1
 SG_ CDCS_RouteNTraPonlongitude16 : 79|36@0+ (1.0E-7,-359.9999999) [-359.9999999|359.9999999] "" PDCS_FD1,GW_FD1,PDCS_HVM_FD1
 SG_ CDCS_RouteNTraPonlatitude16 : 107|36@0+ (1.0E-7,-359.9999999) [-359.9999999|359.9999999] "" PDCS_FD1,GW_FD1,PDCS_HVM_FD1
 SG_ CDCS_RouteNTraPonlongitude17 : 151|36@0+ (1.0E-7,-359.9999999) [-359.9999999|359.9999999] "" PDCS_FD1,GW_FD1,PDCS_HVM_FD1
 SG_ CDCS_RouteNTraPonlatitude17 : 179|36@0+ (1.0E-7,-359.9999999) [-359.9999999|359.9999999] "" PDCS_FD1,GW_FD1,PDCS_HVM_FD1
 SG_ CDCS_RouteNTraPonlongitude18 : 223|36@0+ (1.0E-7,-359.9999999) [-359.9999999|359.9999999] "" PDCS_FD1,GW_FD1,PDCS_HVM_FD1
 SG_ CDCS_RouteNTraPonlatitude18 : 251|36@0+ (1.0E-7,-359.9999999) [-359.9999999|359.9999999] "" PDCS_FD1,GW_FD1,PDCS_HVM_FD1
 SG_ CDCS_RouteNTraPonlongitude19 : 295|36@0+ (1.0E-7,-359.9999999) [-359.9999999|359.9999999] "" PDCS_FD1,GW_FD1,PDCS_HVM_FD1
 SG_ CDCS_RouteNTraPonlatitude19 : 323|36@0+ (1.0E-7,-359.9999999) [-359.9999999|359.9999999] "" PDCS_FD1,GW_FD1,PDCS_HVM_FD1
 SG_ CDCS_RouteNTraPonlongitude20 : 367|36@0+ (1.0E-7,-359.9999999) [-359.9999999|359.9999999] "" PDCS_FD1,GW_FD1,PDCS_HVM_FD1
 SG_ CDCS_RouteNTraPonlatitude20 : 395|36@0+ (1.0E-7,-359.9999999) [-359.9999999|359.9999999] "" PDCS_FD1,GW_FD1,PDCS_HVM_FD1
 SG_ CDCS_RouteNDepartureTime : 439|16@0+ (1,0) [0|8640] "" PDCS_FD1,GW_FD1,PDCS_HVM_FD1
 SG_ CDCS_RouteNTripLength : 455|20@0+ (1,0) [0|500000] "" PDCS_FD1,GW_FD1,PDCS_HVM_FD1
 SG_ CDCS_RouteNDrivingTime : 467|16@0+ (1,0) [0|8640] "" PDCS_FD1,GW_FD1,PDCS_HVM_FD1
 SG_ CDCS_RouteNDailyRouteNum : 483|8@0+ (1,0) [0|255] "" PDCS_FD1,GW_FD1,PDCS_HVM_FD1
 SG_ CDCS_RouteNStrFixChrgPnt : 491|1@0+ (1,0) [0|1] "" PDCS_FD1,GW_FD1,PDCS_HVM_FD1
 SG_ CDCS_RouteNDestFixChrgPnt : 490|1@0+ (1,0) [0|1] "" PDCS_FD1,GW_FD1,PDCS_HVM_FD1
 SG_ CDCS_RouInfoTipsNum2 : 506|3@0+ (1,0) [0|7] "" PDCS_FD1,GW_FD1,PDCS_HVM_FD1

BO_ 1442 RouteInfoN_d: 8 CDCS
 SG_ CDCS_RouteNTotEnergyCon : 7|13@0+ (0.1,0) [0|500] "" PDCS_FD1,GW_FD1,PDCS_HVM_FD1
 SG_ CDCS_RouteNDrvEnergyCon : 10|13@0+ (0.1,0) [0|500] "" PDCS_FD1,GW_FD1,PDCS_HVM_FD1
 SG_ CDCS_RouteNAcyEnergyCon : 29|13@0+ (0.1,0) [0|500] "" PDCS_FD1,GW_FD1,PDCS_HVM_FD1
 SG_ CDCS_RouteNACEnergyCon : 32|13@0+ (0.1,0) [0|500] "" PDCS_FD1,GW_FD1,PDCS_HVM_FD1
 SG_ CDCS_RouInfoTipsNum3 : 58|3@0+ (1,0) [0|7] "" PDCS_FD1,GW_FD1,PDCS_HVM_FD1

BO_ 1443 PremInfo6: 16 CDCS
 SG_ CDCS_AgLngtud : 7|36@0+ (1.0E-7,-359.9999999) [-359.9999999|359.9999999] "" PDCS_FD1,GW_FD1,PDCS_HVM_FD1
 SG_ CDCS_AgLattud : 35|36@0+ (1.0E-7,-359.9999999) [-359.9999999|359.9999999] "" PDCS_FD1,GW_FD1,PDCS_HVM_FD1
 SG_ CDCS_FixChrgPnt : 76|1@0+ (1,0) [0|1] "" PDCS_FD1,GW_FD1,PDCS_HVM_FD1
 SG_ CDCS_ChrgPattn : 78|2@0+ (1,0) [0|3] "" PDCS_FD1,GW_FD1,PDCS_HVM_FD1
 SG_ CDCS_WorkingDay : 79|1@0+ (1,0) [0|1] "" PDCS_FD1,GW_FD1,PDCS_HVM_FD1
 SG_ CDCS_SocChrgStrtPnt : 75|16@0+ (0.1,0) [0|100] "" PDCS_FD1,GW_FD1,PDCS_HVM_FD1
 SG_ CDCS_VehRemTraLength : 91|20@0+ (1,0) [0|500000] "" PDCS_FD1,GW_FD1,PDCS_HVM_FD1
 SG_ CDCS_VehRemTraTime : 119|16@0+ (1,0) [0|8640] "" PDCS_FD1,GW_FD1,PDCS_HVM_FD1

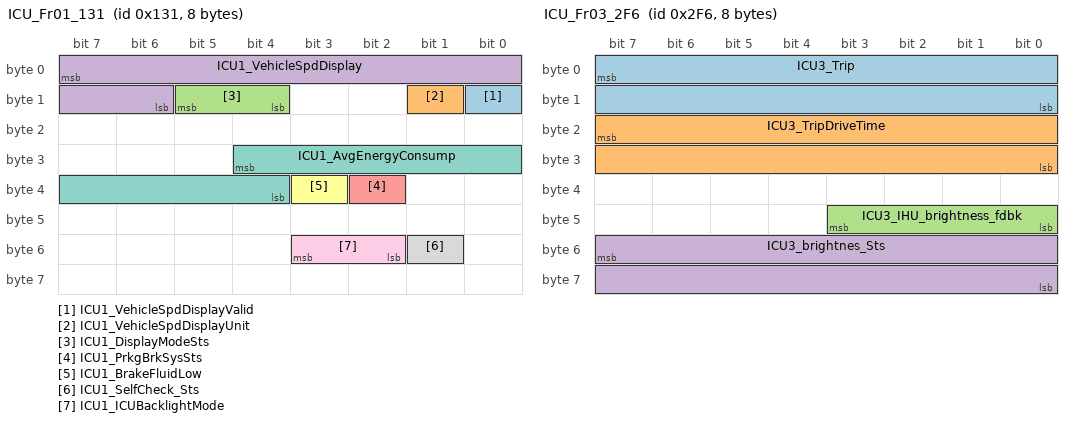
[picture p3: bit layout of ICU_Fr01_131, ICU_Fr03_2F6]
BO_ 305 ICU_Fr01_131: 8 ICU_E02
 SG_ ICU1_VehicleSpdDisplayValid : 8|1@0+ (1,0) [0|1] "NoUnit" SRR3,SRR4,CDCS,ADCS_FD3,CDCS_OverSea,TBOX,FLC_ME_FD3,FLC_FD3,GW_FD5,GW_FD6,GW_FD3,TBOX_OverSea
 SG_ ICU1_VehicleSpdDisplayUnit : 9|1@0+ (1,0) [0|1] "NoUnit" TBOX,GW_FD5,SRR3,GW_FD6,SRR4,CDCS,CDCS_OverSea,TBOX_OverSea
 SG_ ICU1_DisplayModeSts : 13|2@0+ (1,0) [0|3] "NoUnit" CDCS,CDCS_OverSea
 SG_ ICU1_VehicleSpdDisplay : 7|10@0+ (0.5,0) [0|511] "NoUnit" SRR3,SRR4,CDCS,ADCS_FD3,CDCS_OverSea,TBOX,FLC_ME_FD3,FLC_FD3,GW_FD5,GW_FD6,GW_FD3,TBOX_OverSea
 SG_ ICU1_PrkgBrkSysSts : 34|1@0+ (1,0) [0|1] "NoUnit" TBOX,GW_FD5,CDCS,CDCS_OverSea,TBOX_OverSea
 SG_ ICU1_BrakeFluidLow : 35|1@0+ (1,0) [0|1] "NoUnit" TBOX,GW_FD5,CDCS,CDCS_OverSea,TBOX_OverSea
 SG_ ICU1_AvgEnergyConsump : 28|9@0+ (0.1,0) [0|25] "Kwh/100Km" TBOX,GW_FD5,CDCS,CDCS_OverSea,TBOX_OverSea
 SG_ ICU1_SelfCheck_Sts : 49|1@0+ (1,0) [0|1] "NoUnit" CDCS,CDCS_OverSea
 SG_ ICU1_ICUBacklightMode : 51|2@0+ (1,0) [0|3] "" CDCS,CDCS_OverSea

BO_ 758 ICU_Fr03_2F6: 8 ICU_E02
 SG_ ICU3_Trip : 7|16@0+ (0.1,0) [0|6553.5] "km" TBOX,GW_FD5,CDCS,CDCS_OverSea,TBOX_OverSea
 SG_ ICU3_TripDriveTime : 23|16@0+ (1,0) [0|65535] "min" TBOX,GW_FD5,CDCS,CDCS_OverSea,TBOX_OverSea
 SG_ ICU3_IHU_brightness_fdbk : 43|4@0+ (1,0) [0|15] "NoUnit" CDCS,CDCS_OverSea
 SG_ ICU3_brightnes_Sts : 55|16@0+ (1,0) [0|65535] "Lx" CDCS,CDCS_OverSea

BO_ 1601 ICU_NM_641: 8 ICU_E02
 SG_ ICU_SourceNodeIdentifier : 7|8@0+ (1,0) [0|255] "NoUnit" Vector__XXX
 SG_ ICU_RepeatMessageRequest : 8|1@0+ (1,0) [0|1] "NoUnit" Vector__XXX
 SG_ ICU_Reserve1 : 11|3@0+ (1,0) [0|3] "NoUnit" Vector__XXX
 SG_ ICU_ActiveWakeup : 12|1@0+ (1,0) [0|1] "NoUnit" Vector__XXX
 SG_ ICU_Reserve2 : 15|3@0+ (1,0) [0|7] "NoUnit" Vector__XXX
 SG_ ICU_WakeUpReason1 : 16|1@0+ (1,0) [0|1] "NoUnit" Vector__XXX
 SG_ ICU_WakeUp_Rx_NM : 17|1@0+ (1,0) [0|1] "NoUnit" Vector__XXX
 SG_ ICU_WakeUpReason3 : 18|1@0+ (1,0) [0|1] "NoUnit" Vector__XXX
 SG_ ICU_WakeUpReason4 : 19|1@0+ (1,0) [0|1] "NoUnit" Vector__XXX
 SG_ ICU_WakeUpReason5 : 20|1@0+ (1,0) [0|1] "NoUnit" Vector__XXX
 SG_ ICU_WakeUpReason6 : 21|1@0+ (1,0) [0|1] "NoUnit" Vector__XXX
 SG_ ICU_WakeUpReason7 : 22|1@0+ (1,0) [0|1] "NoUnit" Vector__XXX
 SG_ ICU_WakeUpReason8 : 23|1@0+ (1,0) [0|1] "NoUnit" Vector__XXX
 SG_ ICU_RepeatFromSleep : 24|1@0+ (1,0) [0|1] "NoUnit" Vector__XXX
 SG_ ICU_RepeatFromPrepare : 25|1@0+ (1,0) [0|1] "NoUnit" Vector__XXX
 SG_ ICU_NormalFromRepeat : 26|1@0+ (1,0) [0|1] "NoUnit" Vector__XXX
 SG_ ICU_NormalFromReady : 27|1@0+ (1,0) [0|1] "NoUnit" Vector__XXX
 SG_ ICU_RepeatFromReady : 28|1@0+ (1,0) [0|1] "NoUnit" Vector__XXX
 SG_ ICU_RepeatFromNormal : 29|1@0+ (1,0) [0|1] "NoUnit" Vector__XXX
 SG_ ICU_RemainNetworkWakeUpReason1 : 32|1@0+ (1,0) [0|1] "NoUnit" Vector__XXX
 SG_ ICU_RemainNetworkWakeUpReason2 : 33|1@0+ (1,0) [0|1] "NoUnit" Vector__XXX
 SG_ ICU_RemainNetworkWakeUpReason3 : 34|1@0+ (1,0) [0|1] "NoUnit" Vector__XXX
 SG_ ICU_RemainNetworkWakeUpReason4 : 35|1@0+ (1,0) [0|1] "NoUnit" Vector__XXX

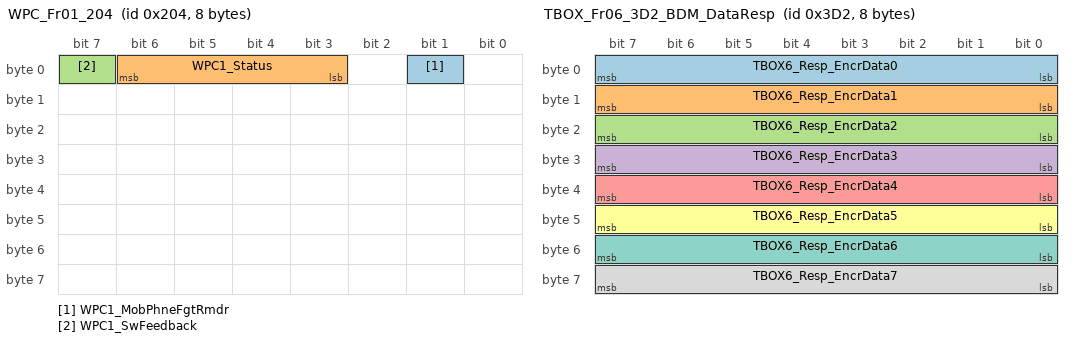
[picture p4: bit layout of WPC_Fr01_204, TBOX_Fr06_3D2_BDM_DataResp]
BO_ 516 WPC_Fr01_204: 8 WPC
 SG_ WPC1_MobPhneFgtRmdr : 1|1@0+ (1,0) [0|1] "NoUnit" ICU_E02,ICU,CDCS,CDCS_OverSea
 SG_ WPC1_Status : 6|4@0+ (1,0) [0|15] "NoUnit" ICU_E02,ICU,CDCS,CDCS_OverSea
 SG_ WPC1_SwFeedback : 7|1@0+ (1,0) [0|1] "NoUnit" ICU_E02,ICU,CDCS,CDCS_OverSea

BO_ 1606 WPC_NM_646: 8 WPC
 SG_ WPC_SourceNodeIdentifier : 7|8@0+ (1,0) [0|255] "NoUnit" Vector__XXX
 SG_ WPC_RepeatMessageRequest : 8|1@0+ (1,0) [0|1] "" Vector__XXX
 SG_ WPC_Reserve1 : 11|3@0+ (1,0) [0|3] "" Vector__XXX
 SG_ WPC_ActiveWakeup : 12|1@0+ (1,0) [0|1] "" Vector__XXX
 SG_ WPC_Reserve2 : 15|3@0+ (1,0) [0|7] "" Vector__XXX
 SG_ WPC_WakeUp_KL15 : 16|1@0+ (1,0) [0|1] "" Vector__XXX
 SG_ WPC_WakeUp_NM : 17|1@0+ (1,0) [0|1] "" Vector__XXX
 SG_ WPC_RepeatFromSleep : 24|1@0+ (1,0) [0|1] "" Vector__XXX
 SG_ WPC_RepeatFromPrepare : 25|1@0+ (1,0) [0|1] "" Vector__XXX
 SG_ WPC_NormalFromRepeat : 26|1@0+ (1,0) [0|1] "" Vector__XXX
 SG_ WPC_NormalFromReady : 27|1@0+ (1,0) [0|1] "" Vector__XXX
 SG_ WPC_RepeatFromReady : 28|1@0+ (1,0) [0|1] "" Vector__XXX
 SG_ WPC_RepeatFromNormal : 29|1@0+ (1,0) [0|1] "" Vector__XXX
 SG_ WPC_RemainNetworkWakeUpReason1 : 32|1@0+ (1,0) [0|1] "" Vector__XXX
 SG_ WPC_RemainNetworkWakeUpReason2 : 33|1@0+ (1,0) [0|1] "" Vector__XXX
 SG_ WPC_RemainNetworkWakeUpReason3 : 34|1@0+ (1,0) [0|1] "" Vector__XXX
 SG_ WPC_RemainNetworkWakeUpReason4 : 35|1@0+ (1,0) [0|1] "" Vector__XXX

BO_ 502 AMP_Fr01_1F6: 16 AMP
 SG_ AMP1_ATMOS_MOD_STATUS_Reserved : 1|2@0+ (1,0) [0|3] "NoUnit" CDCS,CDCS_OverSea
 SG_ AMP1_Loud_STATUS : 3|2@0+ (1,0) [0|3] "NoUnit" CDCS,CDCS_OverSea
 SG_ AMP1_SYS_RUN_STATUS : 5|2@0+ (1,0) [0|3] "NoUnit" CDCS,CDCS_OverSea
 SG_ AMP1_SPK1_DAIG_STATUS : 7|2@0+ (1,0) [0|3] "NoUnit" CDCS,CDCS_OverSea
 SG_ AMP1_SPK2_DAIG_STATUS : 9|2@0+ (1,0) [0|3] "NoUnit" CDCS,CDCS_OverSea
 SG_ AMP1_SPK3_DAIG_STATUS : 11|2@0+ (1,0) [0|3] "NoUnit" CDCS,CDCS_OverSea
 SG_ AMP1_ATMOS_MOD_Value : 15|4@0+ (1,0) [0|15] "NoUnit" CDCS,CDCS_OverSea
 SG_ AMP1_SPK4_DAIG_STATUS : 17|2@0+ (1,0) [0|3] "NoUnit" CDCS,CDCS_OverSea
 SG_ AMP1_SPK5_DAIG_STATUS : 19|2@0+ (1,0) [0|3] "NoUnit" CDCS,CDCS_OverSea
 SG_ AMP1_AUD_EQ_Value : 23|4@0+ (1,0) [0|15] "NoUnit" CDCS,CDCS_OverSea
 SG_ AMP1_SPK6_DAIG_STATUS : 25|2@0+ (1,0) [0|3] "NoUnit" CDCS,CDCS_OverSea
 SG_ AMP1_SPK7_DAIG_STATUS : 27|2@0+ (1,0) [0|3] "NoUnit" CDCS,CDCS_OverSea
 SG_ AMP1_BT2_State_Value : 28|1@0+ (1,0) [0|1] "NoUnit" CDCS,CDCS_OverSea
 SG_ AMP1_AUD_Gala_Value : 31|3@0+ (1,0) [0|7] "NoUnit" CDCS,CDCS_OverSea
 SG_ AMP1_SPK8_DAIG_STATUS : 33|2@0+ (1,0) [0|3] "NoUnit" CDCS,CDCS_OverSea
 SG_ AMP1_SPK9_DAIG_STATUS : 35|2@0+ (1,0) [0|3] "NoUnit" CDCS,CDCS_OverSea
 SG_ AMP1_AUD_Location_Value : 39|3@0+ (1,0) [0|7] "NoUnit" CDCS,CDCS_OverSea
 SG_ AMP1_SPK10_DAIG_STATUS : 41|2@0+ (1,0) [0|3] "NoUnit" CDCS,CDCS_OverSea
 SG_ AMP1_SPK11_DAIG_STATUS : 43|2@0+ (1,0) [0|3] "NoUnit" CDCS,CDCS_OverSea
 SG_ AMP1_SPK12_DAIG_STATUS : 45|2@0+ (1,0) [0|3] "NoUnit" CDCS,CDCS_OverSea
 SG_ AMP1_DSP_RUN_STATUS : 47|2@0+ (1,0) [0|3] "NoUnit" CDCS,CDCS_OverSea
 SG_ AMP1_SPK13_DAIG_STATUS : 49|2@0+ (1,0) [0|3] "NoUnit" CDCS,CDCS_OverSea
 SG_ AMP1_SPK14_DAIG_STATUS : 51|2@0+ (1,0) [0|3] "NoUnit" CDCS,CDCS_OverSea
 SG_ AMP1_SPK15_DAIG_STATUS : 53|2@0+ (1,0) [0|3] "NoUnit" CDCS,CDCS_OverSea
 SG_ AMP1_A2B_RUN_STATUS : 55|2@0+ (1,0) [0|3] "NoUnit" CDCS,CDCS_OverSea
 SG_ AMP1_SPK16_DAIG_STATUS : 57|2@0+ (1,0) [0|3] "NoUnit" CDCS,CDCS_OverSea
 SG_ AMP1_AMPLIFIER_RUN_STATUS : 62|2@0+ (1,0) [0|3] "NoUnit" CDCS,CDCS_OverSea
 SG_ AMP1_Version_HW : 95|4@0+ (1,0) [0|15] "NoUnit" CDCS,CDCS_OverSea
 SG_ AMP1_Version_SW : 91|12@0+ (1,0) [0|4095] "NoUnit" CDCS,CDCS_OverSea

BO_ 503 AMP_Fr02_1F7: 8 AMP
 SG_ APM2_Slot0_Valid : 0|1@0+ (1,0) [0|1] "NoUnit" CDCS,CDCS_OverSea
 SG_ APM2_Slot0_VolumeValue : 5|5@0+ (1,0) [0|31] "NoUnit" CDCS,CDCS_OverSea
 SG_ AMP2_A2B_Slot0_Value : 6|1@0+ (1,0) [0|1] "NoUnit" Vector__XXX
 SG_ AMP2_A2B_Slot1_Value : 7|1@0+ (1,0) [0|1] "NoUnit" Vector__XXX
 SG_ APM2_Slot1_Valid : 8|1@0+ (1,0) [0|1] "NoUnit" CDCS,CDCS_OverSea
 SG_ APM2_Slot1_VolumeValue : 13|5@0+ (1,0) [0|31] "NoUnit" CDCS,CDCS_OverSea
 SG_ AMP2_A2B_Slot2_Value : 14|1@0+ (1,0) [0|1] "NoUnit" Vector__XXX
 SG_ AMP2_A2B_Slot3_Value : 15|1@0+ (1,0) [0|1] "NoUnit" Vector__XXX
 SG_ APM2_Slot2_Valid : 16|1@0+ (1,0) [0|1] "NoUnit" CDCS,CDCS_OverSea
 SG_ APM2_Slot2_VolumeValue : 21|5@0+ (1,0) [0|31] "NoUnit" CDCS,CDCS_OverSea
 SG_ AMP2_A2B_Slot4_Value : 22|1@0+ (1,0) [0|1] "NoUnit" Vector__XXX
 SG_ AMP2_A2B_Slot5_Value : 23|1@0+ (1,0) [0|1] "NoUnit" Vector__XXX
 SG_ APM2_Slot3_Valid : 24|1@0+ (1,0) [0|1] "NoUnit" CDCS,CDCS_OverSea
 SG_ APM2_Slot3_VolumeValue : 29|5@0+ (1,0) [0|31] "NoUnit" CDCS,CDCS_OverSea
 SG_ AMP2_A2B_Slot6_Value : 30|1@0+ (1,0) [0|1] "NoUnit" Vector__XXX
 SG_ AMP2_A2B_Slot7_Value : 31|1@0+ (1,0) [0|1] "NoUnit" Vector__XXX
 SG_ APM2_Slot4_Valid : 32|1@0+ (1,0) [0|1] "NoUnit" CDCS,CDCS_OverSea
 SG_ APM2_Slot4_VolumeValue : 37|5@0+ (1,0) [0|31] "NoUnit" CDCS,CDCS_OverSea
 SG_ APM2_Slot5_Valid : 40|1@0+ (1,0) [0|1] "NoUnit" CDCS,CDCS_OverSea
 SG_ APM2_Slot5_VolumeValue : 45|5@0+ (1,0) [0|31] "NoUnit" CDCS,CDCS_OverSea
 SG_ APM2_Slot6_Valid : 48|1@0+ (1,0) [0|1] "NoUnit" CDCS,CDCS_OverSea
 SG_ APM2_Slot6_VolumeValue : 53|5@0+ (1,0) [0|31] "NoUnit" CDCS,CDCS_OverSea
 SG_ AMP2_AUD_Engineering_Mode : 55|2@0+ (1,0) [0|3] "NoUnit" CDCS,CDCS_OverSea
 SG_ APM2_Slot7_Valid : 56|1@0+ (1,0) [0|1] "NoUnit" CDCS,CDCS_OverSea
 SG_ APM2_Slot7_VolumeValue : 61|5@0+ (1,0) [0|31] "NoUnit" CDCS,CDCS_OverSea
 SG_ APM2_AUD_Mute_Status : 63|1@0+ (1,0) [0|1] "NoUnit" CDCS,CDCS_OverSea

BO_ 505 AMP_Fr03_1F9: 16 AMP
 SG_ AMP3_EQBand1Val : 7|5@0+ (1,0) [0|31] "NoUnit" Vector__XXX
 SG_ AMP3_EQBand2Val : 13|5@0+ (1,0) [0|31] "NoUnit" Vector__XXX
 SG_ AMP3_EQBand3Val : 2|5@0+ (1,0) [0|31] "NoUnit" Vector__XXX
 SG_ AMP3_EQBand4Val : 8|5@0+ (1,0) [0|31] "NoUnit" Vector__XXX
 SG_ AMP3_EQBand5Val : 19|5@0+ (1,0) [0|31] "NoUnit" Vector__XXX
 SG_ AMP3_SPK17_DAIG_STATUS : 30|2@0+ (1,0) [0|3] "NoUnit" Vector__XXX
 SG_ AMP3_SPK18_DAIG_STATUS : 28|2@0+ (1,0) [0|3] "NoUnit" Vector__XXX
 SG_ AMP3_SPK19_DAIG_STATUS : 26|2@0+ (1,0) [0|3] "NoUnit" Vector__XXX
 SG_ AMP3_SPK20_DAIG_STATUS : 24|2@0+ (1,0) [0|3] "NoUnit" Vector__XXX
 SG_ AMP3_Slot8_Valid : 38|1@0+ (1,0) [0|1] "NoUnit" CDCS,CDCS_OverSea
 SG_ AMP3_Slot8_VolumeValue : 37|5@0+ (1,0) [0|31] "NoUnit" CDCS,CDCS_OverSea
 SG_ AMP3_Slot9_Valid : 32|1@0+ (1,0) [0|1] "NoUnit" CDCS,CDCS_OverSea
 SG_ AMP3_Slot9_VolumeValue : 47|5@0+ (1,0) [0|31] "NoUnit" CDCS,CDCS_OverSea
 SG_ AMP3_Slot10_Valid : 42|1@0+ (1,0) [0|1] "NoUnit" CDCS,CDCS_OverSea
 SG_ AMP3_Slot10_VolumeValue : 41|5@0+ (1,0) [0|31] "NoUnit" CDCS,CDCS_OverSea
 SG_ AMP3_Slot11_Valid : 52|1@0+ (1,0) [0|1] "NoUnit" CDCS,CDCS_OverSea
 SG_ AMP3_Slot11_VolumeValue : 51|5@0+ (1,0) [0|31] "NoUnit" CDCS,CDCS_OverSea
 SG_ AMP3_Slot12_Valid : 62|1@0+ (1,0) [0|1] "NoUnit" CDCS,CDCS_OverSea
 SG_ AMP3_Slot12_VolumeValue : 61|5@0+ (1,0) [0|31] "NoUnit" CDCS,CDCS_OverSea
 SG_ AMP3_Slot13_Valid : 56|1@0+ (1,0) [0|1] "NoUnit" CDCS,CDCS_OverSea
 SG_ AMP3_Slot13_VolumeValue : 71|5@0+ (1,0) [0|31] "NoUnit" CDCS,CDCS_OverSea
 SG_ AMP3_Slot14_Valid : 66|1@0+ (1,0) [0|1] "NoUnit" CDCS,CDCS_OverSea
 SG_ AMP3_Slot14_VolumeValue : 65|5@0+ (1,0) [0|31] "NoUnit" CDCS,CDCS_OverSea
 SG_ AMP3_Slot15_Valid : 76|1@0+ (1,0) [0|1] "NoUnit" CDCS,CDCS_OverSea
 SG_ AMP3_Slot15_VolumeValue : 75|5@0+ (1,0) [0|31] "NoUnit" CDCS,CDCS_OverSea
 SG_ AMP3_A2B_Slot8_Value : 86|1@0+ (1,0) [0|1] "NoUnit" Vector__XXX
 SG_ AMP3_A2B_Slot9_Value : 85|1@0+ (1,0) [0|1] "NoUnit" Vector__XXX
 SG_ AMP3_A2B_Slot10_Value : 84|1@0+ (1,0) [0|1] "NoUnit" Vector__XXX
 SG_ AMP3_A2B_Slot11_Value : 83|1@0+ (1,0) [0|1] "NoUnit" Vector__XXX
 SG_ AMP3_A2B_Slot12_Value : 82|1@0+ (1,0) [0|1] "NoUnit" Vector__XXX
 SG_ AMP3_A2B_Slot13_Value : 81|1@0+ (1,0) [0|1] "NoUnit" Vector__XXX
 SG_ AMP3_A2B_Slot14_Value : 80|1@0+ (1,0) [0|1] "NoUnit" Vector__XXX
 SG_ AMP3_A2B_Slot15_Value : 95|1@0+ (1,0) [0|1] "NoUnit" Vector__XXX

BO_ 1589 AMP_NM_635: 8 AMP
 SG_ AMP_SourceNodeIdentifier : 7|8@0+ (1,0) [0|255] "NoUnit" Vector__XXX
 SG_ AMP_RepeatMessageRequest : 8|1@0+ (1,0) [0|1] "NoUnit" Vector__XXX
 SG_ AMP_Reserve1 : 11|3@0+ (1,0) [0|3] "NoUnit" Vector__XXX
 SG_ AMP_ActiveWakeup : 12|1@0+ (1,0) [0|1] "NoUnit" Vector__XXX
 SG_ AMP_Reserve2 : 15|3@0+ (1,0) [0|7] "NoUnit" Vector__XXX
 SG_ AMP_WakeUp_KL15 : 16|1@0+ (1,0) [0|1] "NoUnit" Vector__XXX
 SG_ AMP_WakeUp_NM : 17|1@0+ (1,0) [0|1] "NoUnit" Vector__XXX
 SG_ AMP_RepeatFromSleep : 24|1@0+ (1,0) [0|1] "NoUnit" Vector__XXX
 SG_ AMP_RepeatFromPrepare : 25|1@0+ (1,0) [0|1] "NoUnit" Vector__XXX
 SG_ AMP_NormalFromRepeat : 26|1@0+ (1,0) [0|1] "NoUnit" Vector__XXX
 SG_ AMP_NormalFromReady : 27|1@0+ (1,0) [0|1] "NoUnit" Vector__XXX
 SG_ AMP_RepeatFromReady : 28|1@0+ (1,0) [0|1] "NoUnit" Vector__XXX
 SG_ AMP_RepeatFromNormal : 29|1@0+ (1,0) [0|1] "NoUnit" Vector__XXX
 SG_ AMP_RemainNetworkWakeUpReason1 : 32|1@0+ (1,0) [0|1] "NoUnit" Vector__XXX
 SG_ AMP_RemainNetworkWakeUpReason2 : 33|1@0+ (1,0) [0|1] "NoUnit" Vector__XXX
 SG_ AMP_RemainNetworkWakeUpReason3 : 34|1@0+ (1,0) [0|1] "NoUnit" Vector__XXX
 SG_ AMP_RemainNetworkWakeUpReason4 : 35|1@0+ (1,0) [0|1] "NoUnit" Vector__XXX

BO_ 325 TBOX_RTCM_Fr01_145: 64 TBOX
 SG_ TBOX_RTCM_size : 7|8@0+ (1,0) [0|60] "NoUnit" IMU,FLC_FD6,GW_FD6,ADCS_FD6,ADCU_FD6
 SG_ TBOX_RTCM_num_total : 15|8@0+ (1,0) [0|255] "NoUnit" IMU,FLC_FD6,GW_FD6,ADCS_FD6,ADCU_FD6
 SG_ TBOX_RTCM_num : 23|8@0+ (1,0) [0|255] "NoUnit" IMU,FLC_FD6,GW_FD6,ADCS_FD6,ADCU_FD6
 SG_ TBOX_RTCM_Reserved : 31|8@0+ (1,0) [0|255] "NoUnit" IMU,FLC_FD6,GW_FD6,ADCS_FD6,ADCU_FD6
 SG_ TBOX_RTCM_data : 39|480@0+ (1,0) [0|0] "NoUnit" IMU,FLC_FD6,GW_FD6,ADCS_FD6,ADCU_FD6

BO_ 438 TBOX_Fr02_1B6: 32 TBOX
 SG_ TBOX2_AVMOnReq : 1|2@0+ (1,0) [0|3] "NoUnit" GW_FD3,ADCU_FD3,GW_FD4,CDCS,ADCS_FD3,CDCS_OverSea
 SG_ TBOX2_RemoteParkStartPressReqSts : 2|1@0+ (1,0) [0|1] "NoUnit" GW_FD3,ADCU_FD3,ADCS_FD3
 SG_ TBOX2_RemoteHPP : 3|1@0+ (1,0) [0|1] "NoUnit" GW_FD3,ADCU_FD3,ADCS_FD3
 SG_ TBOX2_AVMviewReq : 7|4@0+ (1,0) [0|15] "NoUnit" GW_FD3,ADCU_FD3,ADCS_FD3
 SG_ TBOX2_RemoteParkReq : 8|1@0+ (1,0) [0|1] "NoUnit" GW_FD3,ADCU_FD3,GW_FD2,BDCS,ADCS_FD3
 SG_ TBOX2_SecuritySts : 10|2@0+ (1,0) [0|3] "NoUnit" GW_FD3,ADCU_FD3,ADCS_FD3
 SG_ TBOX2_ConnectSts : 12|2@0+ (1,0) [0|3] "NoUnit" GW_FD3,ADCU_FD3,ADCS_FD3
 SG_ TBOX2_PhoneInCar : 14|2@0+ (1,0) [0|3] "NoUnit" GW_FD3,ADCU_FD3,ADCS_FD3
 SG_ TBOX2_RemoteParkAbortReq : 15|1@0+ (1,0) [0|1] "NoUnit" GW_FD3,ADCU_FD3,ADCS_FD3
 SG_ TBOX2_RemoteParkStartPressReq : 16|1@0+ (1,0) [0|1] "NoUnit" GW_FD3,ADCU_FD3,ADCS_FD3
 SG_ TBOX2_RemoteParkOutModSel : 19|3@0+ (1,0) [0|7] "NoUnit" GW_FD3,ADCU_FD3,ADCS_FD3
 SG_ TBOX2_PhoneBatSts : 20|1@0+ (1,0) [0|1] "NoUnit" GW_FD3,ADCU_FD3,ADCS_FD3
 SG_ TBOX2_RemoteIntModSel : 22|2@0+ (1,0) [0|3] "NoUnit" GW_FD3,ADCU_FD3,ADCS_FD3
 SG_ TBOX2_RemoteSw : 23|1@0+ (1,0) [0|1] "NoUnit" GW_FD3,ADCU_FD3,ADCS_FD3
 SG_ TBOX2_RemoteCtrModSel : 26|3@0+ (1,0) [0|7] "NoUnit" GW_FD3,ADCU_FD3,ADCS_FD3
 SG_ TBOX2_RemoteCtrSw : 27|1@0+ (1,0) [0|1] "NoUnit" GW_FD3,ADCU_FD3,ADCS_FD3
 SG_ TBOX2_Remotepick : 28|1@0+ (1,0) [0|1] "NoUnit" GW_FD3,ADCU_FD3,ADCS_FD3
 SG_ TBOX2_NNSsuspend : 30|2@0+ (1,0) [0|3] "NoUnit" GW_FD3,ADCU_FD3,GW_FD4,CDCS,ADCS_FD3,CDCS_OverSea
 SG_ TBOX2_RemoteVhpower : 33|2@0+ (1,0) [0|3] "NoUnit" PDCS_FD1,GW_FD3,ADCU_FD3,GW_FD1,GW_FD2,BDCS,PDCS_HVM_FD1,ADCS_FD3
 SG_ TBOX2_NRPReq : 35|2@0+ (1,0) [0|3] "NoUnit" GW_FD3,ADCU_FD3,ADCS_FD3
 SG_ TBOX2_SDMapReq : 37|2@0+ (1,0) [0|3] "NoUnit" GW_FD3,ADCU_FD3,ADCS_FD3
 SG_ TBOX2_NNSSW : 39|2@0+ (1,0) [0|3] "NoUnit" GW_FD3,ADCU_FD3,GW_FD4,CDCS,ADCS_FD3,CDCS_OverSea
 SG_ TBOX2_PA_PauseRecover_Req : 41|2@0+ (1,0) [0|3] "NoUnit" GW_FD3,ADCU_FD3,ADCS_FD3
 SG_ TBOX2_OpenFLDoorReq : 43|2@0+ (1,0) [0|3] "NoUnit" GW_FD2,BDCS
 SG_ TBOX2_OpenFLFRDoorReq : 45|2@0+ (1,0) [0|3] "NoUnit" GW_FD2,BDCS
 SG_ TBOX2_OpenFRDoorReq : 47|2@0+ (1,0) [0|3] "NoUnit" GW_FD2,BDCS
 SG_ TBOX2_RollingCounter : 51|4@0+ (1,0) [0|15] "NoUnit" GW_FD3,ADCU_FD3,ADCS_FD3
 SG_ TBOX2_Checksum : 63|8@0+ (1,0) [0|255] "NoUnit" GW_FD3,ADCU_FD3,ADCS_FD3
 SG_ TBOX2_Altitude : 71|16@0+ (0.1,-300) [-300|6000] "m" PDCS_FD1,GW_FD1,PDCS_HVM_FD1
 SG_ TBOX2_HPA_ONPath_ID : 87|8@0+ (1,0) [0|255] "noUnit" GW_FD3,ADCU_FD3,GW_FD4,CDCS,ADCS_FD3,CDCS_OverSea
 SG_ TBOX2_HPA_PickPath_ID : 95|8@0+ (1,0) [0|255] "noUnit" GW_FD3,ADCU_FD3,GW_FD4,CDCS,ADCS_FD3,CDCS_OverSea
 SG_ TBOX2_PrivacyForbidLocSts : 109|1@0+ (1,0) [0|1] "NoUnit" GW_FD4,CDCS_OverSea
 SG_ TBOX2_PrivacyForbidDataSts : 110|1@0+ (1,0) [0|1] "NoUnit" GW_FD4,CDCS_OverSea
 SG_ TBOX2_GMOnreq : 185|2@0+ (1,0) [0|3] "NoUnit" GW_FD3,ADCU_FD3,ADCS_FD3
 SG_ TBOX2_360viewReq : 187|2@0+ (1,0) [0|3] "NoUnit" GW_FD3,ADCU_FD3,ADCS_FD3
 SG_ TBOX2_360SpecView : 190|3@0+ (1,0) [0|7] "NoUnit" GW_FD3,ADCU_FD3,ADCS_FD3

BO_ 576 TBOX_Fr03_240: 8 TBOX
 SG_ TBOX3_RemoteStartReq : 0|1@0+ (1,0) [0|1] "NoUnit" GW_FD2,BDCS
 SG_ TBOX3_RemoteShutdownReq : 1|1@0+ (1,0) [0|1] "NoUnit" GW_FD2,BDCS
 SG_ TBOX3_ChargeCmd : 3|2@0+ (1,0) [0|3] "NoUnit" PDCS_FD1,BMS,GW_FD1,PDCS_HVM_FD1
 SG_ TBOX3_ChargeAppointmentSet : 4|1@0+ (1,0) [0|1] "NoUnit" PDCS_FD1,BMS,GW_FD1,PDCS_HVM_FD1
 SG_ TBOX3_FLWindowsCtrl : 7|3@0+ (1,0) [0|7] "NoUnit" GW_FD2,BDCS
 SG_ TBOX3_ChargeAppointmentTimeSet : 15|8@0+ (10,0) [0|1440] "min" PDCS_FD1,BMS,GW_FD1,PDCS_HVM_FD1
 SG_ TBOX3_RemoteLockCtrl : 17|2@0+ (1,0) [0|3] "NoUnit" GW_FD4,GW_FD2,BDCS,CDCS,CDCS_OverSea
 SG_ TBOX3_RemoteTrunkCtrl : 19|2@0+ (1,0) [0|3] "NoUnit" GW_FD2,BDCS
 SG_ TBOX3_FRWindowsCtrl : 22|3@0+ (1,0) [0|7] "NoUnit" GW_FD2,BDCS
 SG_ TBOX3_IHU_CertificateState : 23|1@0+ (1,0) [0|1] "NoUnit" GW_FD4,CDCS,CDCS_OverSea
 SG_ TBOX3_RLWindowsCtrl : 26|3@0+ (1,0) [0|7] "NoUnit" GW_FD2,BDCS
 SG_ TBOX3_RRWindowsCtrl : 29|3@0+ (1,0) [0|7] "NoUnit" GW_FD2,BDCS
 SG_ TBOX3_StartForbidReq : 31|2@0+ (1,0) [0|3] "NoUnit" GW_FD2,BDCS
 SG_ TBOX3_HCU_RefuelRequest : 33|2@0+ (1,0) [0|3] "NoUnit" PDCS_FD1,GW_FD1,PDCS_HVM_FD1
 SG_ TBOX3_DischargeMainSw : 35|2@0+ (1,0) [0|3] "NoUnit" BMS,GW_FD1,PDCS_HVM_FD1
 SG_ TBOX3_RemoteFindCarModSet : 37|2@0+ (1,0) [0|3] "NoUnit" GW_FD2,BDCS
 SG_ TBOX3_NetWorkSts : 39|2@0+ (1,0) [0|3] "NoUnit" CDCS,CDCS_OverSea
 SG_ TBOX3_RemoteReadyReq : 40|1@0+ (1,0) [0|1] "NoUnit" GW_FD2,BDCS
 SG_ TBOX3_SosState : 41|1@0+ (1,0) [0|1] "NoUnit" GW_FD2,BDCS
 SG_ TBOX3_LongLifeChrgModeReq : 43|1@0+ (1,0) [0|1] "NoUnit" PDCS_FD1,BMS,GW_FD1,PDCS_HVM_FD1
 SG_ TBOX3_LongDistaChrgModeReq : 44|1@0+ (1,0) [0|1] "NoUnit" PDCS_FD1,BMS,GW_FD1,PDCS_HVM_FD1
 SG_ TBOX3_BattHeatApt_Req : 45|1@0+ (1,0) [0|1] "NoUnit" PDCS_FD1,BMS,GW_FD1,PDCS_HVM_FD1
 SG_ TBOX3_SOCsettingvalid : 47|1@0+ (1,0) [0|1] "NoUnit" BMS,GW_FD1,PDCS_HVM_FD1
 SG_ TBOX3_SOClowerlimit : 55|8@0+ (1,0) [0|100] "%" BMS,GW_FD1,PDCS_HVM_FD1
 SG_ TBOX3_ChargeConKpTempSw : 57|2@0+ (1,0) [0|3] "NoUnit" PDCS_FD1,BMS,GW_FD1,PDCS_HVM_FD1
 SG_ TBOX3_PDCU_ChargeRequest : 59|2@0+ (1,0) [0|3] "NoUnit" PDCU,BMS,GW_FD1,GW_FD2,PDCS_HVM_FD1
 SG_ TBOX3_SunRoofCtrlReq : 62|3@0+ (1,0) [0|7] "NoUnit" GW_FD2,BDCS
 SG_ TBOX3_TemKeepModoffReq : 63|1@0+ (1,0) [0|1] "NoUnit" GW_FD2,BDCS

BO_ 581 TBOX_Fr04_245: 16 TBOX
 SG_ TBOX4_CLM_RemoteCtrlValid : 1|1@0+ (1,0) [0|1] "NoUnit" GW_FD2,BDCS
 SG_ TBOX4_CLM_ACCmd : 10|1@0+ (1,0) [0|1] "NoUnit" GW_FD2,BDCS
 SG_ TBOX4_CLM_DefrostMaxCmd : 11|1@0+ (1,0) [0|1] "NoUnit" GW_FD2,BDCS
 SG_ TBOX4_BDM_RearDefrostCmd : 12|1@0+ (1,0) [0|1] "NoUnit" PDCU,GW_FD2,BDCS,DDCU
 SG_ TBOX4_CLM_CycleCmd : 13|1@0+ (1,0) [0|1] "NoUnit" GW_FD2,BDCS
 SG_ TBOX4_CLM_OnoffCmd : 14|1@0+ (1,0) [0|1] "NoUnit" GW_FD2,BDCS
 SG_ TBOX4_CLM_AutoCmd : 17|1@0+ (1,0) [0|1] "NoUnit" GW_FD2,BDCS
 SG_ TBOX4_CLM_VentCmd : 22|1@0+ (1,0) [0|1] "NoUnit" GW_FD2,BDCS
 SG_ TBOX4_CLM_FootCmd : 23|1@0+ (1,0) [0|1] "NoUnit" GW_FD2,BDCS
 SG_ TBOX4_CLM_WindowCmd : 24|1@0+ (1,0) [0|1] "NoUnit" GW_FD2,BDCS
 SG_ TBOX4_CLM_AnionCmd : 25|1@0+ (1,0) [0|1] "NoUnit" GW_FD2,BDCS
 SG_ TBOX4_LHSeatHeaterCmd : 28|3@0+ (1,0) [0|7] "NoUnit" GW_FD2,BDCS
 SG_ TBOX4_RHSeatHeaterCmd : 31|3@0+ (1,0) [0|7] "NoUnit" GW_FD2,BDCS
 SG_ TBOX4_CLM_BlowerSpdSet : 39|4@0+ (1,0) [0|15] "NoUnit" GW_FD2,BDCS
 SG_ TBOX4_FridgeModReq : 41|2@0+ (1,0) [0|3] "NoUnit" GW_FD2,BDCS
 SG_ TBOX4_CLM_LHTempSet : 47|6@0+ (0.5,16) [16|32] "NoUnit" GW_FD2,BDCS
 SG_ TBOX4_CLM_RHTempSet : 55|6@0+ (0.5,16) [16|32] "NoUnit" GW_FD2,BDCS
 SG_ TBOX4_FLSeatVentCmd : 66|3@0+ (1,0) [0|7] "NoUnit" GW_FD2,BDCS
 SG_ TBOX4_FRSeatVentCmd : 69|3@0+ (1,0) [0|7] "NoUnit" GW_FD2,BDCS
 SG_ TBOX4_LRSeatHeaterCmd : 74|3@0+ (1,0) [0|7] "NoUnit" GW_FD2,BDCS
 SG_ TBOX4_RRSeatHeaterCmd : 77|3@0+ (1,0) [0|7] "NoUnit" GW_FD2,BDCS
 SG_ TBOX4_OilHeatingReq : 83|2@0+ (1,0) [0|3] "NoUnit" GW_FD2,BDCS

BO_ 806 TBOX_Fr05_326: 8 TBOX
 SG_ TBOX5_Odometer : 7|24@0+ (0.1,0) [0|1677721.4] "NoUnit" PDCS_FD1,ICU_E02,GW_FD4,GW_FD1,ICU,GW_FD2,BDCS,PDCS_HVM_FD1

BO_ 855 TBOX_Fr07_357: 16 TBOX
 SG_ TBOX7_perc_EngOilHealth : 7|8@0+ (1,0) [0|100] "%" PDCS_FD1,GW_FD1,PDCS_HVM_FD1
 SG_ TBOX7_m_MnResdMilgKm : 15|16@0+ (1,0) [0|30000] "km" PDCS_FD1,GW_FD1,PDCS_HVM_FD1
 SG_ TBOX7_ti_MnResTiDay : 31|16@0+ (1,0) [0|1000] "day" PDCS_FD1,GW_FD1,PDCS_HVM_FD1
 SG_ TBOX7_ti_AftMnFrznTimYear : 47|8@0+ (1,2000) [2000|2255] "" PDCS_FD1,GW_FD1,PDCS_HVM_FD1
 SG_ TBOX7_ti_AftMnFrznTimMonth : 51|4@0+ (1,0) [0|15] "" PDCS_FD1,GW_FD1,PDCS_HVM_FD1
 SG_ TBOX7_ti_AftMnFrznTimDay : 60|5@0+ (1,0) [0|31] "" PDCS_FD1,GW_FD1,PDCS_HVM_FD1
 SG_ TBOX7_ti_EE1EngIdleTimHr : 71|16@0+ (1,0) [0|15000] "h" PDCS_FD1,GW_FD1,PDCS_HVM_FD1
 SG_ TBOX7_m_EE1EngEquivRunMilgKm : 87|16@0+ (1,0) [0|20000] "km" PDCS_FD1,GW_FD1,PDCS_HVM_FD1
 SG_ TBOX7_u_EE1HourOfDayLck : 100|5@0+ (1,0) [0|25] "h" PDCS_FD1,GW_FD1,PDCS_HVM_FD1
 SG_ TBOX7_ti_EE1EngRunTimHr : 111|16@0+ (1,0) [0|15000] "h" PDCS_FD1,GW_FD1,PDCS_HVM_FD1

BO_ 978 TBOX_Fr06_3D2_BDM_DataResp: 8 TBOX
 SG_ TBOX6_Resp_EncrData0 : 7|8@0+ (1,0) [0|255] "NoUnit" GW_FD2,BDCS
 SG_ TBOX6_Resp_EncrData1 : 15|8@0+ (1,0) [0|255] "NoUnit" GW_FD2,BDCS
 SG_ TBOX6_Resp_EncrData2 : 23|8@0+ (1,0) [0|255] "NoUnit" GW_FD2,BDCS
 SG_ TBOX6_Resp_EncrData3 : 31|8@0+ (1,0) [0|255] "NoUnit" GW_FD2,BDCS
 SG_ TBOX6_Resp_EncrData4 : 39|8@0+ (1,0) [0|255] "NoUnit" GW_FD2,BDCS
 SG_ TBOX6_Resp_EncrData5 : 47|8@0+ (1,0) [0|255] "NoUnit" GW_FD2,BDCS
 SG_ TBOX6_Resp_EncrData6 : 55|8@0+ (1,0) [0|255] "NoUnit" GW_FD2,BDCS
 SG_ TBOX6_Resp_EncrData7 : 63|8@0+ (1,0) [0|255] "NoUnit" GW_FD2,BDCS

BO_ 1002 TBOX_Fr08_3EA: 16 TBOX
 SG_ TBOX8_GPSAgLngtud : 7|36@0+ (1.0E-7,-359.9999999) [-359.9999999|359.9999999] "deg" FLC_FD6,GW_FD6
 SG_ TBOX8_GPSAgLattud : 35|36@0+ (1.0E-7,-359.9999999) [-359.9999999|359.9999999] "deg" FLC_FD6,GW_FD6
 SG_ TBOX8_GPSYawangle : 79|12@0+ (0.1,0) [0|359.9] "deg" FLC_FD6,GW_FD6
 SG_ TBOX8_GPSValid : 83|1@0+ (1,0) [0|1] "NoUnit" FLC_FD6,GW_FD6

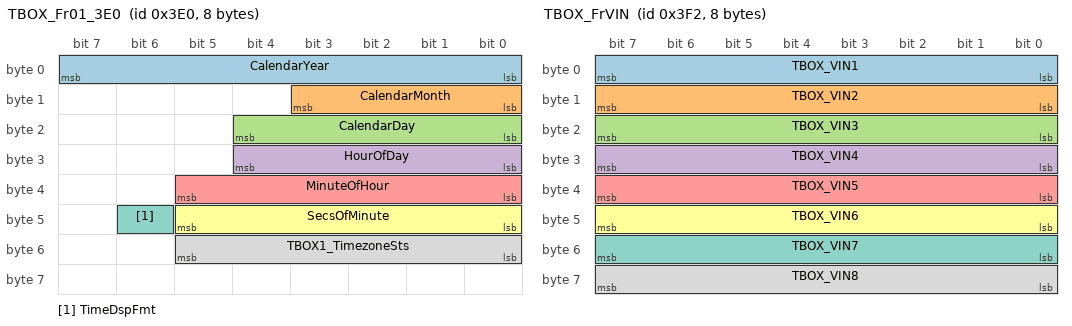
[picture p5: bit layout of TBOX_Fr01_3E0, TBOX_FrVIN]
BO_ 992 TBOX_Fr01_3E0: 8 TBOX
 SG_ CalendarYear : 7|8@0+ (1,2000) [2000|2255] "NoUnit" PDCS_FD1,PDCU,IDB,ESC_FD3,ADCU_FD3,EPS,WPC,EHB_FD3,CDCS,CDU,ICU_E02,ISC,AMP,SRR3,SRR4,BMS,EMS,BDCS,DDCU,BAM,ADCS_FD3,CDCS_OverSea,EVCC,FLC_ME_FD3,ACU,FLC_FD3,GW_FD6,GCU,GW_FD3,GW_FD4,GW_FD1,ICU,GW_FD2,MCU,PDCS_HVM_FD1
 SG_ CalendarMonth : 11|4@0+ (1,0) [0|15] "NoUnit" PDCS_FD1,PDCU,IDB,ESC_FD3,ADCU_FD3,EPS,WPC,EHB_FD3,CDCS,CDU,ICU_E02,ISC,AMP,SRR3,SRR4,BMS,EMS,BDCS,DDCU,BAM,ADCS_FD3,CDCS_OverSea,EVCC,FLC_ME_FD3,ACU,FLC_FD3,GW_FD6,GCU,GW_FD3,GW_FD4,GW_FD1,ICU,GW_FD2,MCU,PDCS_HVM_FD1
 SG_ CalendarDay : 20|5@0+ (1,0) [0|31] "NoUnit" PDCS_FD1,PDCU,IDB,ESC_FD3,ADCU_FD3,EPS,WPC,EHB_FD3,CDCS,CDU,ICU_E02,ISC,AMP,SRR3,SRR4,BMS,EMS,BDCS,DDCU,BAM,ADCS_FD3,CDCS_OverSea,EVCC,FLC_ME_FD3,ACU,FLC_FD3,GW_FD6,GCU,GW_FD3,GW_FD4,GW_FD1,ICU,GW_FD2,MCU,PDCS_HVM_FD1
 SG_ HourOfDay : 28|5@0+ (1,0) [0|23] "NoUnit" PDCS_FD1,PDCU,IDB,ESC_FD3,ADCU_FD3,EPS,WPC,EHB_FD3,CDCS,CDU,ICU_E02,ISC,AMP,SRR3,SRR4,BMS,EMS,BDCS,DDCU,BAM,ADCS_FD3,CDCS_OverSea,EVCC,FLC_ME_FD3,ACU,FLC_FD3,GW_FD6,GCU,GW_FD3,GW_FD4,GW_FD1,ICU,GW_FD2,MCU,PDCS_HVM_FD1
 SG_ MinuteOfHour : 37|6@0+ (1,0) [0|59] "NoUnit" PDCS_FD1,PDCU,IDB,ESC_FD3,ADCU_FD3,EPS,WPC,EHB_FD3,CDCS,CDU,ICU_E02,ISC,AMP,SRR3,SRR4,BMS,EMS,BDCS,DDCU,BAM,ADCS_FD3,CDCS_OverSea,EVCC,FLC_ME_FD3,ACU,FLC_FD3,GW_FD6,GCU,GW_FD3,GW_FD4,GW_FD1,ICU,GW_FD2,MCU,PDCS_HVM_FD1
 SG_ SecsOfMinute : 45|6@0+ (1,0) [0|59] "NoUnit" PDCS_FD1,PDCU,IDB,ESC_FD3,ADCU_FD3,EPS,WPC,EHB_FD3,CDCS,CDU,ICU_E02,ISC,AMP,SRR3,SRR4,BMS,EMS,BDCS,DDCU,BAM,ADCS_FD3,CDCS_OverSea,EVCC,FLC_ME_FD3,ACU,FLC_FD3,GW_FD6,GCU,GW_FD3,GW_FD4,GW_FD1,ICU,GW_FD2,MCU,PDCS_HVM_FD1
 SG_ TimeDspFmt : 46|1@0+ (1,0) [0|1] "NoUnit" PDCS_FD1,PDCU,IDB,ESC_FD3,ADCU_FD3,EPS,WPC,EHB_FD3,CDCS,CDU,ICU_E02,ISC,AMP,SRR3,SRR4,BMS,EMS,BDCS,DDCU,BAM,ADCS_FD3,CDCS_OverSea,EVCC,FLC_ME_FD3,ACU,FLC_FD3,GW_FD6,GCU,GW_FD3,GW_FD4,GW_FD1,ICU,GW_FD2,MCU,PDCS_HVM_FD1
 SG_ TBOX1_TimezoneSts : 53|6@0+ (1,0) [0|63] "NoUnit" GW_FD4,CDCS_OverSea

BO_ 1010 TBOX_FrVIN: 8 TBOX
 SG_ TBOX_VIN1 : 7|8@0+ (1,0) [0|255] "NoUnit" GW_FD4,GW_FD2,BDCS,CDCS,CDCS_OverSea
 SG_ TBOX_VIN2 : 15|8@0+ (1,0) [0|255] "NoUnit" GW_FD4,GW_FD2,BDCS,CDCS,CDCS_OverSea
 SG_ TBOX_VIN3 : 23|8@0+ (1,0) [0|255] "NoUnit" GW_FD4,GW_FD2,BDCS,CDCS,CDCS_OverSea
 SG_ TBOX_VIN4 : 31|8@0+ (1,0) [0|255] "NoUnit" GW_FD4,GW_FD2,BDCS,CDCS,CDCS_OverSea
 SG_ TBOX_VIN5 : 39|8@0+ (1,0) [0|255] "NoUnit" GW_FD4,GW_FD2,BDCS,CDCS,CDCS_OverSea
 SG_ TBOX_VIN6 : 47|8@0+ (1,0) [0|255] "NoUnit" GW_FD4,GW_FD2,BDCS,CDCS,CDCS_OverSea
 SG_ TBOX_VIN7 : 55|8@0+ (1,0) [0|255] "NoUnit" GW_FD4,GW_FD2,BDCS,CDCS,CDCS_OverSea
 SG_ TBOX_VIN8 : 63|8@0+ (1,0) [0|255] "NoUnit" GW_FD4,GW_FD2,BDCS,CDCS,CDCS_OverSea

BO_ 1537 TBOX_NM_601: 8 TBOX
 SG_ TBOX_SourceNodeIdentifier : 7|8@0+ (1,0) [0|255] "NoUnit" Vector__XXX
 SG_ TBOX_RepeatMessageRequest : 8|1@0+ (1,0) [0|1] "NoUnit" Vector__XXX
 SG_ TBOX_Reserve1 : 11|3@0+ (1,0) [0|3] "NoUnit" Vector__XXX
 SG_ TBOX_ActiveWakeup : 12|1@0+ (1,0) [0|1] "NoUnit" Vector__XXX
 SG_ TBOX_Reserve2 : 15|3@0+ (1,0) [0|7] "NoUnit" Vector__XXX
 SG_ TBOX_WakeUp_KL15 : 16|1@0+ (1,0) [0|1] "NoUnit" Vector__XXX
 SG_ TBOX_WakeUp_NM : 17|1@0+ (1,0) [0|1] "NoUnit" Vector__XXX
 SG_ TBOX_WakeUp_Telematics : 18|1@0+ (1,0) [0|1] "NoUnit" Vector__XXX
 SG_ TBOX_WakeUp_Diagnosis : 19|1@0+ (1,0) [0|1] "NoUnit" Vector__XXX
 SG_ TBOX_WakeUp_Ota : 20|1@0+ (1,0) [0|1] "NoUnit" Vector__XXX
 SG_ TBOX_WakeUp_Charge : 21|1@0+ (1,0) [0|1] "NoUnit" Vector__XXX
 SG_ TBOX_WakeUp_Ac : 22|1@0+ (1,0) [0|1] "NoUnit" Vector__XXX
 SG_ TBOX_WakeUp_Bt_control : 23|1@0+ (1,0) [0|1] "NoUnit" Vector__XXX
 SG_ TBOX_RepeatFromSleep : 24|1@0+ (1,0) [0|1] "NoUnit" Vector__XXX
 SG_ TBOX_RepeatFromPrepare : 25|1@0+ (1,0) [0|1] "NoUnit" Vector__XXX
 SG_ TBOX_NormalFromRepeat : 26|1@0+ (1,0) [0|1] "NoUnit" Vector__XXX
 SG_ TBOX_NormalFromReady : 27|1@0+ (1,0) [0|1] "NoUnit" Vector__XXX
 SG_ TBOX_RepeatFromReady : 28|1@0+ (1,0) [0|1] "NoUnit" Vector__XXX
 SG_ TBOX_RepeatFromNormal : 29|1@0+ (1,0) [0|1] "NoUnit" Vector__XXX
 SG_ TBOX_RemainNetworkWakeUpReason1 : 32|1@0+ (1,0) [0|1] "NoUnit" Vector__XXX
 SG_ TBOX_RemainNetworkWakeUpReason2 : 33|1@0+ (1,0) [0|1] "NoUnit" Vector__XXX
 SG_ TBOX_RemainNetworkWakeUpReason3 : 34|1@0+ (1,0) [0|1] "NoUnit" Vector__XXX
 SG_ TBOX_RemainNetworkWakeUpReason4 : 35|1@0+ (1,0) [0|1] "NoUnit" Vector__XXX
 SG_ TBOX_RemainNetworkWakeUpReason5 : 36|1@0+ (1,0) [0|1] "NoUnit" Vector__XXX
 SG_ TBOX_RemainNetworkWakeUpReason6 : 37|1@0+ (1,0) [0|1] "NoUnit" Vector__XXX
 SG_ TBOX_RemainNetworkWakeUpReason7 : 38|1@0+ (1,0) [0|1] "NoUnit" Vector__XXX
 SG_ TBOX_RemainNetworkWakeUpReason8 : 39|1@0+ (1,0) [0|1] "NoUnit" Vector__XXX
 SG_ TBOX_RemainNetworkWakeUpReason9 : 40|1@0+ (1,0) [0|1] "NoUnit" Vector__XXX
 SG_ TBOX_WakeUp_Anti_Theft : 55|1@0+ (1,0) [0|1] "NoUnit" Vector__XXX

BO_ 1890 DIAG_PhysReq_AICS: 8 TBOX
 SG_ DiagnosticReqAICS : 7|64@0+ (1,0) [0|0] "NoUnit" GW_FD7,GW_FD5

BO_ 1906 DIAG_PhysResp_AICS: 8 GW_FD7
 SG_ DiagnosticRespAICS : 7|64@0+ (1,0) [0|0] "NoUnit" TBOX,DLC,TBOX_OverSea

BO_ 2019 DIAG_PhysReq_PDCS1: 8 TBOX
 SG_ DiagnosticReqPDCS1 : 7|64@0+ (1,0) [0|0] "NoUnit" PDCS_FD1,GW_FD1,PDCS_HVM_FD1

BO_ 2027 DIAG_PhysResp_PDCS1: 8 PDCS_FD1
 SG_ DiagnosticRespPDCS1 : 7|64@0+ (1,0) [0|0] "NoUnit" TBOX,GW_FD7,GW_FD5,DLC,TBOX_OverSea

BO_ 2016 DIAG_PhysReq_EMS: 8 TBOX
 SG_ DiagnosticReqEMS : 7|64@0+ (1,0) [0|0] "NoUnit" EMS,GW_FD1

BO_ 2024 DIAG_PhysResp_EMS: 8 EMS
 SG_ DiagnosticRespEMS : 7|64@0+ (1,0) [0|0] "NoUnit" TBOX,GW_FD7,GW_FD5,DLC,TBOX_OverSea

BO_ 2021 DIAG_PhysReq_BMS: 8 TBOX
 SG_ DiagnosticReqBMS : 7|64@0+ (1,0) [0|0] "NoUnit" BMS,GW_FD1

BO_ 2029 DIAG_PhysResp_BMS: 8 BMS
 SG_ DiagnosticRespBMS : 7|64@0+ (1,0) [0|0] "NoUnit" TBOX,GW_FD7,GW_FD5,DLC,TBOX_OverSea

BO_ 2017 DIAG_PhysReq_MCU: 8 TBOX
 SG_ DIAGPhysReqMCU : 7|64@0+ (1,0) [0|0] "NoUnit" GW_FD1,MCU

BO_ 2025 DIAG_PhysResp_MCU: 8 MCU
 SG_ DIAGPhysRespMCU : 7|64@0+ (1,0) [0|0] "NoUnit" TBOX,GW_FD7,GW_FD5,DLC,TBOX_OverSea

BO_ 2018 DIAG_PhysReq_CDU: 8 TBOX
 SG_ DiagnosticReqCDU : 7|64@0+ (1,0) [0|0] "NoUnit" CDU,GW_FD1

BO_ 2026 DIAG_PhysResp_CDU: 8 CDU
 SG_ DiagnosticRespCDU : 7|64@0+ (1,0) [0|0] "NoUnit" TBOX,GW_FD7,GW_FD5,DLC,TBOX_OverSea

BO_ 1835 DIAG_PhysReq_HVM: 8 TBOX
 SG_ DiagnosticReqHVM : 7|64@0+ (1,0) [0|0] "NoUnit" GW_FD1,PDCS_HVM_FD1

BO_ 1851 DIAG_PhysResp_HVM: 8 PDCS_HVM_FD1
 SG_ DiagnosticRespHVM : 7|64@0+ (1,0) [0|0] "NoUnit" TBOX,GW_FD7,GW_FD5,DLC,TBOX_OverSea

BO_ 2020 DIAG_PhysReq_GCU: 8 TBOX
 SG_ DiagnosticReqGCU : 7|64@0+ (1,0) [0|0] "NoUnit" GCU,GW_FD1

BO_ 2028 DIAG_PhysResp_GCU: 8 GCU
 SG_ DiagnosticRespGCU : 7|64@0+ (1,0) [0|0] "NoUnit" TBOX,GW_FD7,GW_FD5,DLC,TBOX_OverSea

BO_ 1793 DIAG_PhysReq_EVCC: 8 TBOX
 SG_ DiagnosticReqEVCC : 7|64@0+ (1,0) [0|0] "NoUnit" EVCC,GW_FD1

BO_ 1809 DIAG_PhysResp_EVCC: 8 EVCC
 SG_ DiagnosticRespEVCC : 7|64@0+ (1,0) [0|0] "NoUnit" TBOX,GW_FD7,GW_FD5,DLC,TBOX_OverSea

BO_ 2022 DIAG_PhysReq_IDB: 8 TBOX
 SG_ DiagnosticReqIDB : 7|64@0+ (1,0) [0|0] "NoUnit" IDB,GW_FD3

BO_ 2030 DIAG_PhysResp_IDB: 8 IDB
 SG_ DiagnosticRespIDB : 7|64@0+ (1,0) [0|0] "NoUnit" TBOX,GW_FD7,GW_FD5,DLC,TBOX_OverSea

BO_ 1824 DIAG_PhysReq_ESC: 8 TBOX
 SG_ DiagnosticReqESC : 7|64@0+ (1,0) [0|0] "NoUnit" ESC_FD6,GW_FD6

BO_ 1840 DIAG_PhysResp_ESC: 8 ESC_FD6
 SG_ DiagnosticRespESC : 7|64@0+ (1,0) [0|0] "NoUnit" TBOX,GW_FD7,GW_FD5,DLC,TBOX_OverSea

BO_ 1825 DIAG_PhysReq_REPB: 8 TBOX
 SG_ DiagnosticReqREPB : 7|64@0+ (1,0) [0|0] "NoUnit" REPB,GW_FD3

BO_ 1841 DIAG_PhysResp_REPB: 8 REPB
 SG_ DiagnosticRespREPB : 7|64@0+ (1,0) [0|0] "NoUnit" TBOX,GW_FD7,GW_FD5,DLC,TBOX_OverSea

BO_ 1826 DIAG_PhysReq_EHB: 8 TBOX
 SG_ DiagnosticReqEHB : 7|64@0+ (1,0) [0|0] "NoUnit" EHB_FD6,GW_FD6

BO_ 1842 DIAG_PhysResp_EHB: 8 EHB_FD6
 SG_ DiagnosticRespEHB : 7|64@0+ (1,0) [0|0] "NoUnit" TBOX,GW_FD7,GW_FD5,DLC,TBOX_OverSea

BO_ 1828 DIAG_PhysReq_EPS: 8 TBOX
 SG_ DIAGPhysReqEPS : 7|64@0+ (1,0) [0|0] "NoUnit" GW_FD3,EPS

BO_ 1844 DIAG_PhysResp_EPS: 8 EPS
 SG_ DIAGPhysRespEPS : 7|64@0+ (1,0) [0|0] "NoUnit" TBOX,GW_FD7,GW_FD5,DLC,TBOX_OverSea

BO_ 1829 DIAG_PhysReq_ISC: 8 TBOX
 SG_ DiagnosticReqISC : 7|64@0+ (1,0) [0|0] "NoUnit" GW_FD3,ISC

BO_ 1845 DIAG_PhysResp_ISC: 8 ISC
 SG_ DiagnosticRespISC : 7|64@0+ (1,0) [0|0] "NoUnit" TBOX,GW_FD7,GW_FD5,DLC,TBOX_OverSea

BO_ 1831 DIAG_PhysReq_ADCS: 8 TBOX
 SG_ DiagnosticReqADCS : 7|64@0+ (1,0) [0|0] "NoUnit" GW_FD6,ADCS_FD6

BO_ 1847 DIAG_PhysResp_ADCS: 8 ADCS_FD6
 SG_ DiagnosticRespADCS : 7|64@0+ (1,0) [0|0] "NoUnit" TBOX,GW_FD7,GW_FD5,DLC,TBOX_OverSea

BO_ 1987 DIAG_PhysReq_ADCU: 8 TBOX
 SG_ DiagnosticReqADCU : 7|64@0+ (1,0) [0|0] "NoUnit" GW_FD6,ADCU_FD6

BO_ 2003 DIAG_PhysResp_ADCU: 8 ADCU_FD6
 SG_ DiagnosticRespADCU : 7|64@0+ (1,0) [0|0] "NoUnit" TBOX,GW_FD7,GW_FD5,DLC,TBOX_OverSea

BO_ 1986 DIAG_PhysReq_FLC: 8 TBOX
 SG_ DiagnosticReqFLC : 7|64@0+ (1,0) [0|0] "NoUnit" FLC_ME_FD6,FLC_FD6,GW_FD6

BO_ 2002 DIAG_PhysResp_FLC: 8 FLC_ME_FD6
 SG_ DiagnosticRespFLC : 7|64@0+ (1,0) [0|0] "NoUnit" TBOX,GW_FD7,GW_FD5,DLC,TBOX_OverSea

BO_ 1959 DIAG_PhysReq_IMU: 8 TBOX
 SG_ DiagnosticReqIMU : 7|64@0+ (1,0) [0|0] "NoUnit" IMU,GW_FD6

BO_ 1975 DIAG_PhysResp_IMU: 8 IMU
 SG_ DiagnosticRespIMU : 7|64@0+ (1,0) [0|0] "NoUnit" TBOX,GW_FD7,GW_FD5,DLC,TBOX_OverSea

BO_ 1989 DIAG_PhysReq_LRR: 8 TBOX
 SG_ DiagnosticReqLRR : 7|64@0+ (1,0) [0|0] "NoUnit" FLC_ME_FD6,FLC_FD6,GW_FD6,ADCS_FD6

BO_ 2005 DIAG_PhysResp_LRR: 8 FLC_ME_FD6
 SG_ DiagnosticRespLRR : 7|64@0+ (1,0) [0|0] "NoUnit" TBOX,GW_FD7,GW_FD5,DLC,TBOX_OverSea

BO_ 1988 DIAG_PhysReq_SRR1: 8 TBOX
 SG_ DiagnosticReqSRR1 : 7|64@0+ (1,0) [0|0] "NoUnit" FLC_FD6,GW_FD6,ADCS_FD6

BO_ 2004 DIAG_PhysResp_SRR1: 8 FLC_FD6
 SG_ DiagnosticRespSRR1 : 7|64@0+ (1,0) [0|0] "NoUnit" TBOX,GW_FD7,GW_FD5,DLC,TBOX_OverSea

BO_ 1991 DIAG_PhysReq_SRR2: 8 TBOX
 SG_ DiagnosticReqSRR2 : 7|64@0+ (1,0) [0|0] "NoUnit" FLC_FD6,GW_FD6,ADCS_FD6

BO_ 2007 DIAG_PhysResp_SRR2: 8 FLC_FD6
 SG_ DiagnosticRespSRR2 : 7|64@0+ (1,0) [0|0] "NoUnit" TBOX,GW_FD7,GW_FD5,DLC,TBOX_OverSea

BO_ 1992 DIAG_PhysReq_SRR3: 8 TBOX
 SG_ DiagnosticReqSRR3 : 7|64@0+ (1,0) [0|0] "NoUnit" FLC_FD6,SRR3,GW_FD6,ADCS_FD6

BO_ 2008 DIAG_PhysResp_SRR3: 8 FLC_FD6
 SG_ DiagnosticRespSRR3 : 7|64@0+ (1,0) [0|0] "NoUnit" TBOX,GW_FD7,GW_FD5,DLC,TBOX_OverSea

BO_ 1993 DIAG_PhysReq_SRR4: 8 TBOX
 SG_ DiagnosticReqSRR4 : 7|64@0+ (1,0) [0|0] "NoUnit" FLC_FD6,GW_FD6,SRR4,ADCS_FD6

BO_ 2009 DIAG_PhysResp_SRR4: 8 FLC_FD6
 SG_ DiagnosticRespSRR4 : 7|64@0+ (1,0) [0|0] "NoUnit" TBOX,GW_FD7,GW_FD5,DLC,TBOX_OverSea

BO_ 2033 DIAG_PhysReq_ACU: 8 TBOX
 SG_ DiagnosticReqACU : 7|64@0+ (1,0) [0|0] "NoUnit" ACU,GW_FD1

BO_ 2041 DIAG_PhysResp_ACU: 8 ACU
 SG_ DiagnosticRespACU : 7|64@0+ (1,0) [0|0] "NoUnit" TBOX,GW_FD7,GW_FD5,DLC,TBOX_OverSea

BO_ 1856 DIAG_PhysReq_BDCS: 8 TBOX
 SG_ DiagnosticReqBDCS : 7|64@0+ (1,0) [0|0] "NoUnit" GW_FD2,BDCS

BO_ 1872 DIAG_PhysResp_BDCS: 8 BDCS
 SG_ DiagnosticRespBDCS : 7|64@0+ (1,0) [0|0] "NoUnit" TBOX,GW_FD7,GW_FD5,DLC,TBOX_OverSea

BO_ 1896 DIAG_PhysReq_DDCU: 8 TBOX
 SG_ DiagnosticReqDDCU : 7|64@0+ (1,0) [0|0] "NoUnit" GW_FD2,DDCU

BO_ 1912 DIAG_PhysResp_DDCU: 8 DDCU
 SG_ DiagnosticRespDDCU : 7|64@0+ (1,0) [0|0] "NoUnit" TBOX,GW_FD7,GW_FD5,DLC,TBOX_OverSea

BO_ 1897 DIAG_PhysReq_PDCU: 8 TBOX
 SG_ DiagnosticReqPDCU : 7|64@0+ (1,0) [0|0] "NoUnit" PDCU,GW_FD2

BO_ 1913 DIAG_PhysResp_PDCU: 8 PDCU
 SG_ DiagnosticRespPDCU : 7|64@0+ (1,0) [0|0] "NoUnit" TBOX,GW_FD7,GW_FD5,DLC,TBOX_OverSea

BO_ 1990 DIAG_PhysReq_BAM: 8 TBOX
 SG_ DiagnosticReqBAM : 7|64@0+ (1,0) [0|0] "NoUnit" GW_FD2,BAM

BO_ 2006 DIAG_PhysResp_BAM: 8 BAM
 SG_ DiagnosticRespBAM : 7|64@0+ (1,0) [0|0] "NoUnit" TBOX,GW_FD7,GW_FD5,DLC,TBOX_OverSea

BO_ 1868 DIAG_PhysReq_EACP: 8 TBOX
 SG_ DiagnosticReqEACP : 7|64@0+ (1,0) [0|0] "NoUnit" GW_FD2,BDCS

BO_ 1884 DIAG_PhysResp_EACP: 8 BDCS
 SG_ DiagnosticRespEACP : 7|64@0+ (1,0) [0|0] "NoUnit" TBOX,GW_FD7,GW_FD5,DLC,TBOX_OverSea

BO_ 1869 DIAG_PhysReq_TC: 8 DLC
 SG_ DiagnosticReqTC : 7|64@0+ (1,0) [0|0] "NoUnit" GW_FD2,BDCS

BO_ 1885 DIAG_PhysResp_TC: 8 BDCS
 SG_ DiagnosticRespTC : 7|64@0+ (1,0) [0|0] "NoUnit" GW_FD7,GW_FD5,DLC,TBOX_OverSea

BO_ 1893 DIAG_PhysReq_PTC: 8 TBOX
 SG_ DiagnosticReqPTC : 7|64@0+ (1,0) [0|0] "NoUnit" GW_FD2,BDCS

BO_ 1909 DIAG_PhysResp_PTC: 8 BDCS
 SG_ DiagnosticRespPTC : 7|64@0+ (1,0) [0|0] "NoUnit" TBOX,GW_FD7,GW_FD5,DLC,TBOX_OverSea

BO_ 1956 DIAG_PhysReq_CS: 8 TBOX
 SG_ DiagnosticReqCS : 7|64@0+ (1,0) [0|0] "NoUnit" GW_FD2,BDCS

BO_ 1972 DIAG_PhysResp_CS: 8 BDCS
 SG_ DiagnosticRespCS : 7|64@0+ (1,0) [0|0] "NoUnit" TBOX,GW_FD7,GW_FD5,DLC,TBOX_OverSea

BO_ 1860 DIAG_PhysReq_RLS: 8 TBOX
 SG_ DiagnosticReqRLS : 7|64@0+ (1,0) [0|0] "NoUnit" GW_FD2,BDCS

BO_ 1876 DIAG_PhysResp_RLS: 8 BDCS
 SG_ DiagnosticRespRLS : 7|64@0+ (1,0) [0|0] "NoUnit" TBOX,GW_FD7,GW_FD5,DLC,TBOX_OverSea

BO_ 1898 DIAG_PhysReq_DFGLS: 8 TBOX
 SG_ DiagnosticReqDFGLS : 7|64@0+ (1,0) [0|0] "NoUnit" GW_FD2,DDCU

BO_ 1914 DIAG_PhysResp_DFGLS: 8 DDCU
 SG_ DiagnosticRespDFGLS : 7|64@0+ (1,0) [0|0] "NoUnit" TBOX,GW_FD7,GW_FD5,DLC,TBOX_OverSea

BO_ 1924 DIAG_PhysReq_OHC: 8 DLC
 SG_ DiagnosticReqOHC : 7|64@0+ (1,0) [0|0] "NoUnit" GW_FD2,BDCS

BO_ 1940 DIAG_PhysResp_OHC: 8 BDCS
 SG_ DiagnosticRespOHC : 7|64@0+ (1,0) [0|0] "NoUnit" GW_FD7,GW_FD5,DLC,TBOX_OverSea

BO_ 1920 DIAG_PhysReq_CDCS: 8 TBOX
 SG_ DiagnosticReqCDCS : 7|64@0+ (1,0) [0|0] "NoUnit" GW_FD4,CDCS,CDCS_OverSea

BO_ 1936 DIAG_PhysResp_CDCS: 8 CDCS
 SG_ DiagnosticRespCDCS : 7|64@0+ (1,0) [0|0] "NoUnit" TBOX,GW_FD7,GW_FD5,DLC,TBOX_OverSea

BO_ 1921 DIAG_PhysReq_ICU: 8 TBOX
 SG_ DiagnosticReqICU : 7|64@0+ (1,0) [0|0] "NoUnit" ICU_E02,GW_FD4,ICU

BO_ 1937 DIAG_PhysResp_ICU: 8 ICU_E02
 SG_ DiagnosticRespICU : 7|64@0+ (1,0) [0|0] "NoUnit" TBOX,GW_FD7,GW_FD5,DLC,TBOX_OverSea

BO_ 1926 DIAG_PhysReq_WPC: 8 TBOX
 SG_ DiagnosticReqWPC : 7|64@0+ (1,0) [0|0] "NoUnit" GW_FD4,WPC

BO_ 1942 DIAG_PhysResp_WPC: 8 WPC
 SG_ DiagnosticRespWPC : 7|64@0+ (1,0) [0|0] "NoUnit" TBOX,GW_FD7,GW_FD5,DLC,TBOX_OverSea

BO_ 1928 DIAG_PhysReq_AMP: 8 TBOX
 SG_ DiagnosticReqAMP : 7|64@0+ (1,0) [0|0] "NoUnit" AMP,GW_FD4

BO_ 1944 DIAG_PhysResp_AMP: 8 AMP
 SG_ DiagnosticRespAMP : 7|64@0+ (1,0) [0|0] "NoUnit" TBOX,GW_FD7,GW_FD5,DLC,TBOX_OverSea

BO_ 1968 DIAG_PhysResp_TBOX: 8 TBOX
 SG_ DiagnosticRespTBOX : 7|64@0+ (1,0) [0|0] "NoUnit" GW_FD7,DLC

BO_ 1952 DIAG_PhysReq_TBOX: 8 DLC
 SG_ DiagnosticReqTBOX : 7|64@0+ (1,0) [0|0] "NoUnit" TBOX,GW_FD5,TBOX_OverSea

BO_ 2015 DiagnosticReqFunc: 8 DLC
 SG_ DiagnosticReqFunc : 7|64@0+ (1,0) [0|0] "NoUnit" PDCS_FD1,EHB_FD6,ESC_FD6,PDCU,IDB,EPS,WPC,ADCU_FD6,CDCS,CDU,ICU_E02,AMP,SRR3,SRR4,BMS,ADCS_FD6,EMS,BDCS,DDCU,BAM,CDCS_OverSea,IMU,TBOX,EVCC,FLC_ME_FD6,ACU,GW_FD7,FLC_FD6,GW_FD5,GW_FD6,GCU,GW_FD3,GW_FD4,GW_FD1,ICU,GW_FD2,MCU,PDCS_HVM_FD1,TBOX_OverSea

BO_TX_BU_ 515 : CDCS,CDCS_OverSea;
BO_TX_BU_ 517 : CDCS,CDCS_OverSea;
BO_TX_BU_ 697 : CDCS,CDCS_OverSea;
BO_TX_BU_ 757 : CDCS,CDCS_OverSea;
BO_TX_BU_ 789 : CDCS,CDCS_OverSea;
BO_TX_BU_ 790 : CDCS,CDCS_OverSea;
BO_TX_BU_ 896 : CDCS,CDCS_OverSea;
BO_TX_BU_ 805 : ICU_E02,ICU;
BO_TX_BU_ 1009 : ICU_E02,ICU;
BO_TX_BU_ 1544 : CDCS,CDCS_OverSea;
BO_TX_BU_ 1440 : CDCS,CDCS_OverSea;
BO_TX_BU_ 1441 : CDCS,CDCS_OverSea;
BO_TX_BU_ 1442 : CDCS,CDCS_OverSea;
BO_TX_BU_ 1443 : CDCS,CDCS_OverSea;
BO_TX_BU_ 305 : ICU_E02,ICU;
BO_TX_BU_ 758 : ICU_E02,ICU;
BO_TX_BU_ 1601 : ICU_E02,ICU;
BO_TX_BU_ 325 : TBOX,TBOX_OverSea;
BO_TX_BU_ 438 : TBOX,TBOX_OverSea;
BO_TX_BU_ 576 : TBOX,TBOX_OverSea;
BO_TX_BU_ 581 : TBOX,TBOX_OverSea;
BO_TX_BU_ 806 : TBOX,TBOX_OverSea;
BO_TX_BU_ 855 : TBOX,TBOX_OverSea;
BO_TX_BU_ 978 : TBOX,TBOX_OverSea;
BO_TX_BU_ 1002 : TBOX,TBOX_OverSea;
BO_TX_BU_ 992 : TBOX,TBOX_OverSea;
BO_TX_BU_ 1010 : TBOX,TBOX_OverSea;
BO_TX_BU_ 1537 : TBOX,TBOX_OverSea;
BO_TX_BU_ 1890 : TBOX,DLC,TBOX_OverSea;
BO_TX_BU_ 1906 : GW_FD7,GW_FD5;
BO_TX_BU_ 2019 : TBOX,DLC,TBOX_OverSea;
BO_TX_BU_ 2027 : PDCS_FD1,PDCS_HVM_FD1;
BO_TX_BU_ 2016 : TBOX,DLC,TBOX_OverSea;
BO_TX_BU_ 2021 : TBOX,DLC,TBOX_OverSea;
BO_TX_BU_ 2017 : TBOX,DLC,TBOX_OverSea;
BO_TX_BU_ 2018 : TBOX,DLC,TBOX_OverSea;
BO_TX_BU_ 1835 : TBOX,DLC,TBOX_OverSea;
BO_TX_BU_ 2020 : TBOX,DLC,TBOX_OverSea;
BO_TX_BU_ 1793 : TBOX,DLC,TBOX_OverSea;
BO_TX_BU_ 2022 : TBOX,DLC,TBOX_OverSea;
BO_TX_BU_ 1824 : TBOX,DLC,TBOX_OverSea;
BO_TX_BU_ 1825 : TBOX,DLC,TBOX_OverSea;
BO_TX_BU_ 1826 : TBOX,DLC,TBOX_OverSea;
BO_TX_BU_ 1828 : TBOX,DLC,TBOX_OverSea;
BO_TX_BU_ 1829 : TBOX,DLC,TBOX_OverSea;
BO_TX_BU_ 1831 : TBOX,DLC,TBOX_OverSea;
BO_TX_BU_ 1987 : TBOX,DLC,TBOX_OverSea;
BO_TX_BU_ 1986 : TBOX,DLC,TBOX_OverSea;
BO_TX_BU_ 2002 : FLC_ME_FD6,FLC_FD6;
BO_TX_BU_ 1959 : TBOX,DLC,TBOX_OverSea;
BO_TX_BU_ 1989 : TBOX,DLC,TBOX_OverSea;
BO_TX_BU_ 2005 : FLC_ME_FD6,FLC_FD6,ADCS_FD6;
BO_TX_BU_ 1988 : TBOX,DLC,TBOX_OverSea;
BO_TX_BU_ 2004 : FLC_FD6,ADCS_FD6;
BO_TX_BU_ 1991 : TBOX,DLC,TBOX_OverSea;
BO_TX_BU_ 2007 : FLC_FD6,ADCS_FD6;
BO_TX_BU_ 1992 : TBOX,DLC,TBOX_OverSea;
BO_TX_BU_ 2008 : FLC_FD6,SRR3,ADCS_FD6;
BO_TX_BU_ 1993 : TBOX,DLC,TBOX_OverSea;
BO_TX_BU_ 2009 : FLC_FD6,SRR4,ADCS_FD6;
BO_TX_BU_ 2033 : TBOX,DLC,TBOX_OverSea;
BO_TX_BU_ 1856 : TBOX,DLC,TBOX_OverSea;
BO_TX_BU_ 1896 : TBOX,DLC,TBOX_OverSea;
BO_TX_BU_ 1897 : TBOX,DLC,TBOX_OverSea;
BO_TX_BU_ 1990 : TBOX,DLC,TBOX_OverSea;
BO_TX_BU_ 1868 : TBOX,DLC,TBOX_OverSea;
BO_TX_BU_ 1869 : DLC,TBOX_OverSea;
BO_TX_BU_ 1893 : TBOX,DLC,TBOX_OverSea;
BO_TX_BU_ 1956 : TBOX,DLC,TBOX_OverSea;
BO_TX_BU_ 1860 : TBOX,DLC,TBOX_OverSea;
BO_TX_BU_ 1898 : TBOX,DLC,TBOX_OverSea;
BO_TX_BU_ 1924 : DLC,TBOX_OverSea;
BO_TX_BU_ 1920 : TBOX,DLC,TBOX_OverSea;
BO_TX_BU_ 1936 : CDCS,CDCS_OverSea;
BO_TX_BU_ 1921 : TBOX,DLC,TBOX_OverSea;
BO_TX_BU_ 1937 : ICU_E02,ICU;
BO_TX_BU_ 1926 : TBOX,DLC,TBOX_OverSea;
BO_TX_BU_ 1928 : TBOX,DLC,TBOX_OverSea;
BO_TX_BU_ 1968 : TBOX,TBOX_OverSea;
CM_ BO_ 489 "欧盟智驾FLC_ME平台方案报文";
CM_ BO_ 1424 "CDCS MCU log数据";
CM_ BO_ 1440 "报文的发送时序按照如下顺序，依次每隔200ms发送1a, 1b, 1c, 1d, 2a, 2b, 2c, 2d......6a, 6b, 6c ,6d共24帧报文";
CM_ BO_ 1441 "报文的发送时序按照如下顺序，依次每隔200ms发送1a, 1b, 1c, 1d, 2a, 2b, 2c, 2d......6a, 6b, 6c ,6d共24帧报文";
CM_ BO_ 1442 "报文的发送时序按照如下顺序，依次每隔200ms发送1a, 1b, 1c, 1d, 2a, 2b, 2c, 2d......6a, 6b, 6c ,6d共24帧报文";
CM_ SG_ 515 CDCS15_ALM_MusicMode_Rvalue "氛围灯红色值(音乐律动）";
CM_ SG_ 515 CDCS15_ALM_MusicMode_Gvalue "氛围灯绿色值(音乐律动）";
CM_ SG_ 515 CDCS15_ALM_MusicMode_Bvalue "氛围灯蓝色值(音乐律动）";
CM_ SG_ 515 CDCS15_ALM_MusicMode_Brightness "氛围灯亮度(音乐律动）";
CM_ SG_ 515 CDCS15_ChildrenPresentDetection "儿童存在检测结果";
CM_ SG_ 515 CDCS15_FLSeatHorizontalAdj "主驾座椅水平调节";
CM_ SG_ 515 CDCS15_FLSeatVerticalAdj "主驾座椅垂直高度调节";
CM_ SG_ 515 CDCS15_FLSeatCushionTiltAdj "主驾座椅坐垫倾斜调节";
CM_ SG_ 515 CDCS15_FLSeatBackrestAngletAdj "主驾座椅靠背角度调节";
CM_ SG_ 515 CDCS15_FRSeatHorizontalAdj "副驾座椅水平调节";
CM_ SG_ 515 CDCS15_FRSeatVerticalAdj "副驾座椅垂直高度调节";
CM_ SG_ 515 CDCS15_FRSeatLegsupportAdj "副驾座椅腿托上下调节";
CM_ SG_ 515 CDCS15_FRSeatBackrestAngletAdj "副驾座椅靠背角度调节";
CM_ SG_ 515 CDCS15_FLLumbarUpAndDownAdj "主驾座椅腰托上下调节";
CM_ SG_ 515 CDCS15_FLLumbaForwardorBackwardAdj "主驾座椅腰托垂直前后调节";
CM_ SG_ 515 CDCS15_FRLumbarUpAndDownAdj "副驾座椅腰托上下调节";
CM_ SG_ 515 CDCS15_FRLumbaForwardorBackwardAdj "副驾座椅腰托垂直前后调节";
CM_ SG_ 515 CDCS15_AILampVoiceMode "AI灯带语音控制模式";
CM_ SG_ 515 CDCS15_AILampMode "AI灯带模式";
CM_ SG_ 515 CDCS15_DMS_DriverStatusValid "DMS报警状态值有效性";
CM_ SG_ 515 CDCS15_DMS_DriverStatus "驾驶员状态信号（DMS）";
CM_ SG_ 515 CDCS15_Storage_St "CDCS内部空间信号，用于哨兵模式状态机监控";
CM_ SG_ 515 CDCS15_USB_St "CDCS USB不可用信号，用于哨兵模式状态机监控";
CM_ SG_ 515 CDCS15_UserSceneMode "情景模式信号";
CM_ SG_ 515 CDCS15_NNP_DriverFatigueStatus "DMS检测驾驶员疲劳状态传输给ADCS，用于NNP判断";
CM_ SG_ 515 CDCS15_NNP_DriverDistractedStatus "DMS检测驾驶员分心状态传输给ADCS，用于NNP判断";
CM_ SG_ 515 CDCS15_ALHSelectTheme "氛围灯主题模式选择";
CM_ SG_ 515 CDCS15_RL_LumbarUpAndDownAdj "后排左座椅腰托上下调节信号";
CM_ SG_ 515 CDCS15_RL_LumbarFwdBakwdAdj "后排左座椅腰托垂直前后调节信号";
CM_ SG_ 515 CDCS15_RR_LumbarUpAndDownAdj "后排右座椅腰托上下调节信号";
CM_ SG_ 515 CDCS15_RR_LumbarFwdBakwdAdj "后排右座椅腰托垂直前后调节信号";
CM_ SG_ 515 CDCS15_FRSeatLegsupportLengthAdj "副驾座椅腿托长度调节";
CM_ SG_ 515 CDCS15_FRSeatLegsupporLengthVoiceAd "副驾座椅腿托长度语音调节";
CM_ SG_ 515 CDCS15_ALH_ADASWarning "氛围灯提醒ADAS功能开关";
CM_ SG_ 515 CDCS15_ALHBrightnessAutoMode "氛围灯亮度模式选择";
CM_ SG_ 517 CDCS18_CameraSpeedLimit "摄像头限速";
CM_ SG_ 517 CDCS18_CameraDistance "摄像头限速距离";
CM_ SG_ 517 CDCS18_RoadSpeedLimit "道路限速";
CM_ SG_ 517 CDCS18_DisplaySpeedLimit "座舱显示限速";
CM_ SG_ 517 CDCS18_LaneNavigation "车道级导航状态";
CM_ SG_ 517 CDCS18_AVM_Status "360环视工作状态";
CM_ SG_ 697 CDCS9_ATMOS_MOD_Enable_Reserved "音响模式开关";
CM_ SG_ 697 CDCS9_Loud_Enable "等响度开关";
CM_ SG_ 697 CDCS9_BT2_State "蓝牙连接状态";
CM_ SG_ 697 CDCS9_ATMOS_MOD_Type "音响模式调节";
CM_ SG_ 697 CDCS9_AUD_EQ_Mode "EQ模式（哪吒音效）";
CM_ SG_ 697 CDCS9_AUD_Gala_LEVEL "车随音量等级";
CM_ SG_ 697 CDCS9_AUD_Location_Type "最佳听音位信号";
CM_ SG_ 757 CDCS2_DischargeObejectSelect "对外放电对象选择";
CM_ SG_ 757 CDCS2_DischargeModeSelect "对外放电模式选择";
CM_ SG_ 757 CDCS2_ICUBacklightMode "ICU背光调节模式";
CM_ SG_ 757 CDCS2_DischargeActiveSw "对外放电激活开关";
CM_ SG_ 757 CDCS2_WPC_OnOffSw "手机无线充电开关信号";
CM_ SG_ 757 CDCS2_ICUMod_CtrlReq "平均功率，瞬时功率切";
CM_ SG_ 757 CDCS2_ICUDisplayMode "仪表显示模式";
CM_ SG_ 757 CDCS2_ICUTripmeter_Set "小计里程清零";
CM_ SG_ 757 CDCS2_PrivacyForbidLocReq "位置信息开关请求";
CM_ SG_ 757 CDCS2_SOClowerlimit "外接放电SOC设置";
CM_ SG_ 757 CDCS2_PrivacyForbidDataReq "车辆运行数据开关请求";
CM_ SG_ 757 CDCS2_TimezoneSet "全球时区设置";
CM_ SG_ 757 CDCS2_ICUBacklightLevel "仪表背光调节档位";
CM_ SG_ 757 CDCS2_AvgEnergySET "平均电耗清零";
CM_ SG_ 757 CDCS2_UnlockElectronicLock "中控大屏解锁电子锁控制信号";
CM_ SG_ 757 CDCS2_DischargeMainSw "对外放电主开关";
CM_ SG_ 757 CDCS2_ChgConKpTemp "插枪保温开启";
CM_ SG_ 789 CDCS1_AC_SW "空调开启请求";
CM_ SG_ 789 CDCS1_CLM_CycleSw "空调内外循环开关";
CM_ SG_ 789 CDCS1_CLM_BlowerSpdPlus "风速+";
CM_ SG_ 789 CDCS1_CLM_AutoSw "AUTO开关";
CM_ SG_ 789 CDCS1_CLM_LHTempPlus "主驾温度+";
CM_ SG_ 789 CDCS1_CLM_LHTempMinus "主驾温度-";
CM_ SG_ 789 CDCS1_CLM_RHTempPlus "副驾温度+";
CM_ SG_ 789 CDCS1_CLM_RHTempMinus "副驾温度-";
CM_ SG_ 789 CDCS1_CLM_FootSw "吹脚开关";
CM_ SG_ 789 CDCS1_CLM_AnionSw "空气净化/负离子发生器控制信号";
CM_ SG_ 789 CDCS1_CLM_BlowerSpdSet "风速设定（针对语音）";
CM_ SG_ 789 CDCS1_CLM_AcFilterResetReq "空调滤芯寿命重置请求";
CM_ SG_ 789 CDCS1_CLM_BlowerSpdSetValid "风速设定有效性（针对语音）";
CM_ SG_ 789 CDCS1_CLM_LHTempSetValid "主驾温度设定有效性（针对语音）";
CM_ SG_ 789 CDCS1_CLM_RHTempSetValid "副驾温度设定有效性（针对语音）";
CM_ SG_ 789 CDCS1_CLM_LHTempSet "主驾温度设定（针对语音）";
CM_ SG_ 789 CDCS1_CLM_DualSw "双区空调开关";
CM_ SG_ 789 CDCS1_CLM_RHTempSet "副驾温度设定（针对语音）";
CM_ SG_ 789 CDCS1_BDCS_RearDefrostSw "后除霜";
CM_ SG_ 789 CDCS1_CLM_OnoffSw "空调开启关闭开关";
CM_ SG_ 789 CDCS1_CLM_BlowerSpdMinus "风速-";
CM_ SG_ 789 CDCS1_CLM_WindowSw "吹窗开关";
CM_ SG_ 789 CDCS1_CLM_VentSw "吹面开关";
CM_ SG_ 789 CDCS1_ACMaxSW "AC MAX状态";
CM_ SG_ 789 CDCS1_AirClean "空气净化功能";
CM_ SG_ 789 CDCS1_AC_ECONMode "空调ECO经济模式开关";
CM_ SG_ 789 CDCS1_LEAOSts "左电动出风口状态";
CM_ SG_ 789 CDCS1_REAOSts "右电动出风口状态";
CM_ SG_ 789 CDCS1_AC_Ventilation "空调通风开关";
CM_ SG_ 790 CDCS6_FridgeMod_Req "车载冰箱运行模式请求";
CM_ SG_ 790 CDCS6_FridgeTemp_KeepReq "车载冰箱温度保持请求（锁车维持）";
CM_ SG_ 790 CDCS6_FridgeCool_Temp_Req "车载冰箱冷藏模式温度设置";
CM_ SG_ 790 CDCS6_FridgeTemp_Plus "车载冰箱温度加";
CM_ SG_ 790 CDCS6_FridgeTemp_Minus "车载冰箱温度减";
CM_ SG_ 790 CDCS6_FridgeHeat_Temp_Req "车载冰箱保温模式温度设置";
CM_ SG_ 790 CDCS6_OilHeatingSw "燃油加热器辅热按键请求";
CM_ SG_ 896 CDCS8_VoiceTrunkCtrl "大屏语音开启尾门";
CM_ SG_ 896 CDCS8_TrunkSWReq "大屏开关开启尾门请求";
CM_ SG_ 896 CDCS8_RearDoorHeightSet "尾门开启高度设置";
CM_ SG_ 896 CDCS8_FRSeatEZEReq "副驾 EZE 开关请求";
CM_ SG_ 896 CDCS8_FLSeatEZEReq "主驾 EZE 开关请求";
CM_ SG_ 896 CDCS8_SOC_LampSwt "电量提示设置开关";
CM_ SG_ 896 CDCS8_FLLumbarUpAndDownAdj "主驾语音座椅腰托上下调节";
CM_ SG_ 896 CDCS8_FLLumbaForwardorBackwardAdj "主驾语音座椅腰托垂直前后调节";
CM_ SG_ 896 CDCS8_ALH_TemperatureSW "氛围灯温度模式设置开关";
CM_ SG_ 896 CDCS8_FRLumbarUpAndDownAdj "副驾语音座椅腰托上下调节";
CM_ SG_ 896 CDCS8_FRLumbaForwardorBackwardAdj "副驾语音座椅腰托垂直前后调节";
CM_ SG_ 896 CDCS8_IncomingCall "蓝牙电话进来指示信号";
CM_ SG_ 896 CDCS8_FrontSeatAutoEZEReq "主动 EZE 功能开关请求";
CM_ SG_ 896 CDCS8_FRSeatHeatCmd "副驾座椅加热档位需求";
CM_ SG_ 896 CDCS8_FLSeatHeatCmd "主驾座椅加热档位需求";
CM_ SG_ 896 CDCS8_FLSeatVentCmd "主驾座椅通风档位需求";
CM_ SG_ 896 CDCS8_FRSeatVentCmd "副驾座椅通风档位需求";
CM_ SG_ 805 ICU2_Odometer "仪表显示总计里程";
CM_ SG_ 805 ICU2_OdometerUpdate "总计里程同步指令";
CM_ SG_ 1009 ICU_VIN1 "ICU VIN ASCII 第10位";
CM_ SG_ 1009 ICU_VIN2 "ICU VIN ASCII 第11位";
CM_ SG_ 1009 ICU_VIN3 "ICU VIN ASCII 第12位";
CM_ SG_ 1009 ICU_VIN4 "ICU VIN ASCII 第13位";
CM_ SG_ 1009 ICU_VIN5 "ICU VIN ASCII 第14位";
CM_ SG_ 1009 ICU_VIN6 "ICU VIN ASCII 第15位";
CM_ SG_ 1009 ICU_VIN7 "ICU VIN ASCII 第16位";
CM_ SG_ 1009 ICU_VIN8 "ICU VIN ASCII 第17位";
CM_ SG_ 489 CDCS21_NavSpeedLimitStatus "地图导航状态";
CM_ SG_ 489 CDCS21_Nav_CountryID "国家码";
CM_ SG_ 489 CDCS21_Nav_SpeedLimitUnits "Output speed unit 限速值速度单位";
CM_ SG_ 489 CDCS21_Nav_CurrRoadType "指示当前所处道路类型";
CM_ SG_ 489 CDCS21_NavSpeedlimit "地图提供的限速";
CM_ SG_ 489 CDCS21_NavRampDistance "前方匝道与本车距离";
CM_ SG_ 489 CDCS21_NavSpeedlimit_Rain "地图提供的雨条件限速";
CM_ SG_ 489 CDCS21_NavSpeedlimit_Snow "地图提供的雪条件限速";
CM_ SG_ 489 CDCS21_NavSpeedlimit_fog "地图提供的雾条件限速";
CM_ SG_ 489 CDCS21_NavSpeedlimitSign_Distance "地图提供的最近限速切换点距当前距离";
CM_ SG_ 1424 HU_MCUResetReason "MCUResetReason";
CM_ SG_ 1424 HU_MCUPowerState "MCUPowerState";
CM_ SG_ 1424 HU_SOCResetType "SOCResetType";
CM_ SG_ 1424 HU_BatteryVoltage "BatteryVoltage";
CM_ SG_ 1424 HU_BDM_PowerMode "HU_BDM_PowerMode";
CM_ SG_ 1424 HU_SOCWatchdog "SOCWatchdog";
CM_ SG_ 1424 HU_HardIGNState "HardIGNState";
CM_ SG_ 1424 HU_SPIConnectState "SPIConnectState";
CM_ SG_ 1424 HU_NM_ID_H "HU_NM_ID_H";
CM_ SG_ 1424 HU_NM_ID_L "HU_NM_ID_L";
CM_ SG_ 1544 CDCS_SourceNodeIdentifier "ECU节点标识符";
CM_ SG_ 1544 CDCS_RepeatMessageRequest "Repeat Message请求";
CM_ SG_ 1544 CDCS_Reserve1 "预留";
CM_ SG_ 1544 CDCS_ActiveWakeup "激活唤醒，主动唤醒网络时置1，其他（包括被动唤醒节点）为0";
CM_ SG_ 1544 CDCS_Reserve2 "预留";
CM_ SG_ 1544 CDCS_WakeUp_KL15 "KL15 ON 唤醒";
CM_ SG_ 1544 CDCS_WakeUp_NM "NM报文唤醒";
CM_ SG_ 1544 CDCS_RemainNetworkWakeUpReason1 "保持网络唤醒原因1";
CM_ SG_ 1544 CDCS_RemainNetworkWakeUpReason2 "保持网络唤醒原因2";
CM_ SG_ 1544 CDCS_RemainNetworkWakeUpReason3 "保持网络唤醒原因3";
CM_ SG_ 1544 CDCS_RemainNetworkWakeUpReason4 "保持网络唤醒原因4";
CM_ SG_ 1440 CDCS_RouteNTraPonlongitude1or8 "行程N轨迹点1or8经度
TravelN track point 1or8 longitude";
CM_ SG_ 1440 CDCS_RouteNTraPonlatitude1or8 "行程N轨迹点1纬度
TravelN track point 1or8 latitude";
CM_ SG_ 1440 CDCS_RouteNTraPonlongitude2or9 "行程N轨迹点2or9经度
TravelN track point 2or9 longitude";
CM_ SG_ 1440 CDCS_RouteNTraPonlatitude2or9 "行程N轨迹点2or9纬度
TravelN track point 2or9 latitude";
CM_ SG_ 1440 CDCS_RouteNTraPonlongitude3or10 "行程N轨迹点3or10经度
TravelN track point 3or10 longitude";
CM_ SG_ 1440 CDCS_RouteNTraPonlatitude3or10 "行程N轨迹点3or10纬度
TravelN track point 3or10 latitude";
CM_ SG_ 1440 CDCS_RouteNTraPonlongitude4or11 "行程N轨迹点4or11经度
TravelN track point 4or11 longitude";
CM_ SG_ 1440 CDCS_RouteNTraPonlatitude4or11 "行程N轨迹点4or11纬度
TravelN track point 4or11 latitude";
CM_ SG_ 1440 CDCS_RouteNTraPonlongitude5or12 "行程N轨迹点5or12经度
TravelN track point 5or12 longitude";
CM_ SG_ 1440 CDCS_RouteNTraPonlatitude5or12 "行程N轨迹点5or12纬度
TravelN track point 5or12 latitude";
CM_ SG_ 1440 CDCS_RouteNTraPonlongitude6or13 "行程N轨迹点6or13经度
TravelN track point 6or13 longitude";
CM_ SG_ 1440 CDCS_RouteNTraPonlatitude6or13 "行程N轨迹点6or13纬度
TravelN track point 6or13 latitude";
CM_ SG_ 1440 CDCS_RouteNTraPonlongitude7or14 "行程N轨迹点7or14经度
TravelN track point 7or14 longitude";
CM_ SG_ 1440 CDCS_RouteNTraPonlatitude7or14 "行程N轨迹点7or14纬度
TravelN track point 7or14 latitude";
CM_ SG_ 1440 CDCS_RouteInfoTipsNum1 "典型路径信息标签1
typical routine Tips number";
CM_ SG_ 1441 CDCS_RouteNTraPonlongitude15 "行程N轨迹点15经度
TravelN track point 15 longitude";
CM_ SG_ 1441 CDCS_RouteNTraPonlatitude15 "行程N轨迹点15纬度
TravelN track point 15 latitude";
CM_ SG_ 1441 CDCS_RouteNTraPonlongitude16 "行程N轨迹点16经度
TravelN track point 16 longitude";
CM_ SG_ 1441 CDCS_RouteNTraPonlatitude16 "行程N轨迹点16纬度
TravelN track point 16 latitude";
CM_ SG_ 1441 CDCS_RouteNTraPonlongitude17 "行程N轨迹点17经度
TravelN track point 17 longitude";
CM_ SG_ 1441 CDCS_RouteNTraPonlatitude17 "行程N轨迹点17纬度
TravelN track point 17 latitude";
CM_ SG_ 1441 CDCS_RouteNTraPonlongitude18 "行程N轨迹点18经度
TravelN track point 18 longitude";
CM_ SG_ 1441 CDCS_RouteNTraPonlatitude18 "行程N轨迹点18纬度
TravelN track point 18 latitude";
CM_ SG_ 1441 CDCS_RouteNTraPonlongitude19 "行程N轨迹点19经度
TravelN track point 19 longitude";
CM_ SG_ 1441 CDCS_RouteNTraPonlatitude19 "行程N轨迹点19纬度
TravelN track point 19 latitude";
CM_ SG_ 1441 CDCS_RouteNTraPonlongitude20 "行程N轨迹点20经度
TravelN track point 20 longitude";
CM_ SG_ 1441 CDCS_RouteNTraPonlatitude20 "行程N轨迹点20纬度
TravelN track point 20 latitude";
CM_ SG_ 1441 CDCS_RouteNDepartureTime "行程N的出发时间
Departure time";
CM_ SG_ 1441 CDCS_RouteNTripLength "行程N行程长度
Trip length";
CM_ SG_ 1441 CDCS_RouteNDrivingTime "行程N行驶时长
Driving time";
CM_ SG_ 1441 CDCS_RouteNDailyRouteNum "行程N的当日往返路径编号
Daily round-trip route number";
CM_ SG_ 1441 CDCS_RouteNStrFixChrgPnt "行程N起点是否有固定充电条件
Whether the starting point has fixed charging conditions";
CM_ SG_ 1441 CDCS_RouteNDestFixChrgPnt "行程N终点是否有固定充电条件
Whether there are fixed charging conditions at the end point";
CM_ SG_ 1441 CDCS_RouInfoTipsNum2 "典型路径信息标签2
typical routine Tips number";
CM_ SG_ 1442 CDCS_RouteNTotEnergyCon "行程N总能耗
total energy consumption";
CM_ SG_ 1442 CDCS_RouteNDrvEnergyCon "行程N驱动能耗
Driving energy consumption";
CM_ SG_ 1442 CDCS_RouteNAcyEnergyCon "行程N附件能耗
Accessory energy consumption";
CM_ SG_ 1442 CDCS_RouteNACEnergyCon "行程N空调能耗
AC energy consumption";
CM_ SG_ 1442 CDCS_RouInfoTipsNum3 "典型路径信息标签3
typical routine Tips number";
CM_ SG_ 1443 CDCS_AgLngtud "车辆当前位置（经度）
Vehicle current position (longitude)";
CM_ SG_ 1443 CDCS_AgLattud "车辆当前位置（纬度）
Vehicle current location (latitude)";
CM_ SG_ 1443 CDCS_FixChrgPnt "用户是否有充电条件
Whether the user has charging conditions";
CM_ SG_ 1443 CDCS_ChrgPattn "用户补能倾向
User charge and refuel tendency";
CM_ SG_ 1443 CDCS_WorkingDay "当前日期是否为工作日
Whether the current date is a working day";
CM_ SG_ 1443 CDCS_SocChrgStrtPnt "用户常用充电起始SOC值
Users commonly use the start SOC value of charging";
CM_ SG_ 1443 CDCS_VehRemTraLength "车辆剩余行程长度
Vehicle remaining travel length";
CM_ SG_ 1443 CDCS_VehRemTraTime "车辆剩余行程时间
Vehicle remaining travel time";
CM_ SG_ 305 ICU1_VehicleSpdDisplayValid "仪表显示车速有效性";
CM_ SG_ 305 ICU1_VehicleSpdDisplayUnit "车速显示单位";
CM_ SG_ 305 ICU1_DisplayModeSts "极简模式反馈状态";
CM_ SG_ 305 ICU1_VehicleSpdDisplay "仪表显示车速";
CM_ SG_ 305 ICU1_PrkgBrkSysSts "电子手刹状态";
CM_ SG_ 305 ICU1_BrakeFluidLow "制动液液位报警信号";
CM_ SG_ 305 ICU1_AvgEnergyConsump "平均能耗";
CM_ SG_ 305 ICU1_SelfCheck_Sts "仪表自检状态";
CM_ SG_ 305 ICU1_ICUBacklightMode "背光调节模式反馈";
CM_ SG_ 758 ICU3_Trip "里程小计";
CM_ SG_ 758 ICU3_TripDriveTime "行驶时间";
CM_ SG_ 758 ICU3_IHU_brightness_fdbk "背光反馈";
CM_ SG_ 758 ICU3_brightnes_Sts "光线传感器强度";
CM_ SG_ 1601 ICU_SourceNodeIdentifier "ECU节点标识符";
CM_ SG_ 1601 ICU_RepeatMessageRequest "Repeat Message请求";
CM_ SG_ 1601 ICU_Reserve1 "预留";
CM_ SG_ 1601 ICU_ActiveWakeup "激活唤醒，主动唤醒网络时置1，其他（包括被动唤醒节点）为0";
CM_ SG_ 1601 ICU_Reserve2 "预留";
CM_ SG_ 1601 ICU_WakeUpReason1 "唤醒原因1";
CM_ SG_ 1601 ICU_WakeUp_Rx_NM "网络管理报文唤醒";
CM_ SG_ 1601 ICU_WakeUpReason3 "唤醒原因3";
CM_ SG_ 1601 ICU_WakeUpReason4 "唤醒原因4";
CM_ SG_ 1601 ICU_WakeUpReason5 "唤醒原因5";
CM_ SG_ 1601 ICU_WakeUpReason6 "唤醒原因6";
CM_ SG_ 1601 ICU_WakeUpReason7 "唤醒原因7";
CM_ SG_ 1601 ICU_WakeUpReason8 "唤醒原因8";
CM_ SG_ 1601 ICU_RemainNetworkWakeUpReason1 "保持网络唤醒原因1";
CM_ SG_ 1601 ICU_RemainNetworkWakeUpReason2 "保持网络唤醒原因2";
CM_ SG_ 1601 ICU_RemainNetworkWakeUpReason3 "保持网络唤醒原因3";
CM_ SG_ 1601 ICU_RemainNetworkWakeUpReason4 "保持网络唤醒原因4";
CM_ SG_ 516 WPC1_MobPhneFgtRmdr "手机遗忘提醒";
CM_ SG_ 516 WPC1_Status "WPC充电状态";
CM_ SG_ 516 WPC1_SwFeedback "WPC开关状态反馈";
CM_ SG_ 1606 WPC_SourceNodeIdentifier "ECU节点标识符";
CM_ SG_ 1606 WPC_RepeatMessageRequest "Repeat Message请求";
CM_ SG_ 1606 WPC_Reserve1 "预留";
CM_ SG_ 1606 WPC_ActiveWakeup "激活唤醒，主动唤醒网络时置1，其他（包括被动唤醒节点）为0";
CM_ SG_ 1606 WPC_Reserve2 "预留";
CM_ SG_ 1606 WPC_WakeUp_KL15 "KL15 ON 唤醒";
CM_ SG_ 1606 WPC_WakeUp_NM "NM报文唤醒（OTA\远程）";
CM_ SG_ 1606 WPC_RemainNetworkWakeUpReason1 "保持网络唤醒原因1";
CM_ SG_ 1606 WPC_RemainNetworkWakeUpReason2 "保持网络唤醒原因2";
CM_ SG_ 1606 WPC_RemainNetworkWakeUpReason3 "保持网络唤醒原因3";
CM_ SG_ 1606 WPC_RemainNetworkWakeUpReason4 "保持网络唤醒原因4";
CM_ SG_ 502 AMP1_ATMOS_MOD_STATUS_Reserved "音响模式开关";
CM_ SG_ 502 AMP1_Loud_STATUS "等响度开关--Reserved";
CM_ SG_ 502 AMP1_SYS_RUN_STATUS "系统运行状态";
CM_ SG_ 502 AMP1_SPK1_DAIG_STATUS "SPK1故障状态";
CM_ SG_ 502 AMP1_SPK2_DAIG_STATUS "SPK2故障状态";
CM_ SG_ 502 AMP1_SPK3_DAIG_STATUS "SPK3故障状态";
CM_ SG_ 502 AMP1_ATMOS_MOD_Value "音响模式调节";
CM_ SG_ 502 AMP1_SPK4_DAIG_STATUS "SPK4故障状态";
CM_ SG_ 502 AMP1_SPK5_DAIG_STATUS "SPK5故障状态";
CM_ SG_ 502 AMP1_AUD_EQ_Value "EQ模式（哪吒音效）";
CM_ SG_ 502 AMP1_SPK6_DAIG_STATUS "SPK6故障状态";
CM_ SG_ 502 AMP1_SPK7_DAIG_STATUS "SPK7故障状态";
CM_ SG_ 502 AMP1_BT2_State_Value "蓝牙连接状态反馈";
CM_ SG_ 502 AMP1_AUD_Gala_Value "车随音量等级反馈信号";
CM_ SG_ 502 AMP1_SPK8_DAIG_STATUS "SPK8故障状态";
CM_ SG_ 502 AMP1_SPK9_DAIG_STATUS "SPK9故障状态";
CM_ SG_ 502 AMP1_AUD_Location_Value "最佳听音位信号";
CM_ SG_ 502 AMP1_SPK10_DAIG_STATUS "SPK10故障状态";
CM_ SG_ 502 AMP1_SPK11_DAIG_STATUS "SPK11故障状态";
CM_ SG_ 502 AMP1_SPK12_DAIG_STATUS "SPK12故障状态";
CM_ SG_ 502 AMP1_DSP_RUN_STATUS "DSP运行状态";
CM_ SG_ 502 AMP1_SPK13_DAIG_STATUS "SPK13故障状态";
CM_ SG_ 502 AMP1_SPK14_DAIG_STATUS "SPK14故障状态";
CM_ SG_ 502 AMP1_SPK15_DAIG_STATUS "SPK15故障状态";
CM_ SG_ 502 AMP1_A2B_RUN_STATUS "A2B运行状态";
CM_ SG_ 502 AMP1_SPK16_DAIG_STATUS "SPK16故障状态";
CM_ SG_ 502 AMP1_AMPLIFIER_RUN_STATUS "功放IC运行状态";
CM_ SG_ 502 AMP1_Version_HW "AMP硬件版本号";
CM_ SG_ 502 AMP1_Version_SW "AMP软件版本号";
CM_ SG_ 503 APM2_Slot0_Valid "有效性";
CM_ SG_ 503 APM2_Slot0_VolumeValue "音量";
CM_ SG_ 503 AMP2_A2B_Slot0_Value "Slot0音频输入";
CM_ SG_ 503 AMP2_A2B_Slot1_Value "Slot1音频输入";
CM_ SG_ 503 APM2_Slot1_Valid "有效性";
CM_ SG_ 503 APM2_Slot1_VolumeValue "音量";
CM_ SG_ 503 AMP2_A2B_Slot2_Value "Slot2音频输入";
CM_ SG_ 503 AMP2_A2B_Slot3_Value "Slot3音频输入";
CM_ SG_ 503 APM2_Slot2_Valid "有效性";
CM_ SG_ 503 APM2_Slot2_VolumeValue "音量";
CM_ SG_ 503 AMP2_A2B_Slot4_Value "Slot4音频输入";
CM_ SG_ 503 AMP2_A2B_Slot5_Value "Slot5音频输入";
CM_ SG_ 503 APM2_Slot3_Valid "有效性";
CM_ SG_ 503 APM2_Slot3_VolumeValue "音量";
CM_ SG_ 503 AMP2_A2B_Slot6_Value "Slot6音频输入";
CM_ SG_ 503 AMP2_A2B_Slot7_Value "Slot7音频输入";
CM_ SG_ 503 APM2_Slot4_Valid "有效性";
CM_ SG_ 503 APM2_Slot4_VolumeValue "音量";
CM_ SG_ 503 APM2_Slot5_Valid "有效性";
CM_ SG_ 503 APM2_Slot5_VolumeValue "音量";
CM_ SG_ 503 APM2_Slot6_Valid "有效性";
CM_ SG_ 503 APM2_Slot6_VolumeValue "音量";
CM_ SG_ 503 AMP2_AUD_Engineering_Mode "工程模式";
CM_ SG_ 503 APM2_Slot7_Valid "有效性";
CM_ SG_ 503 APM2_Slot7_VolumeValue "音量";
CM_ SG_ 503 APM2_AUD_Mute_Status "MUTE控制";
CM_ SG_ 505 AMP3_EQBand1Val "AMP向CDCS应答自定义EQ band1(80Hz）值信号";
CM_ SG_ 505 AMP3_EQBand2Val "新增AMP向CDCS应答自定义EQ值band2(500Hz)信号";
CM_ SG_ 505 AMP3_EQBand3Val "AMP向CDCS应答自定义EQ值band3(1000Hz)信号";
CM_ SG_ 505 AMP3_EQBand4Val "AMP向CDCS应答自定义EQ值band4(5000Hz)信号";
CM_ SG_ 505 AMP3_EQBand5Val "AMP向CDCS应答自定义EQ值band5（16000Hz)信号";
CM_ SG_ 505 AMP3_SPK17_DAIG_STATUS "AMP向CDCS反馈扬声器17状态";
CM_ SG_ 505 AMP3_SPK18_DAIG_STATUS "AMP向CDCS反馈扬声器18状态";
CM_ SG_ 505 AMP3_SPK19_DAIG_STATUS "AMP向CDCS反馈扬声器19状态";
CM_ SG_ 505 AMP3_SPK20_DAIG_STATUS "AMP向CDCS反馈扬声器20状态";
CM_ SG_ 505 AMP3_Slot8_Valid "有效性";
CM_ SG_ 505 AMP3_Slot8_VolumeValue "音量";
CM_ SG_ 505 AMP3_Slot9_Valid "有效性";
CM_ SG_ 505 AMP3_Slot9_VolumeValue "音量";
CM_ SG_ 505 AMP3_Slot10_Valid "有效性";
CM_ SG_ 505 AMP3_Slot10_VolumeValue "音量";
CM_ SG_ 505 AMP3_Slot11_Valid "有效性";
CM_ SG_ 505 AMP3_Slot11_VolumeValue "音量";
CM_ SG_ 505 AMP3_Slot12_Valid "有效性";
CM_ SG_ 505 AMP3_Slot12_VolumeValue "音量";
CM_ SG_ 505 AMP3_Slot13_Valid "有效性";
CM_ SG_ 505 AMP3_Slot13_VolumeValue "音量";
CM_ SG_ 505 AMP3_Slot14_Valid "有效性";
CM_ SG_ 505 AMP3_Slot14_VolumeValue "音量";
CM_ SG_ 505 AMP3_Slot15_Valid "有效性";
CM_ SG_ 505 AMP3_Slot15_VolumeValue "音量";
CM_ SG_ 505 AMP3_A2B_Slot8_Value "Slot8音频输入";
CM_ SG_ 505 AMP3_A2B_Slot9_Value "Slot9音频输入";
CM_ SG_ 505 AMP3_A2B_Slot10_Value "Slot10音频输入";
CM_ SG_ 505 AMP3_A2B_Slot11_Value "Slot11音频输入";
CM_ SG_ 505 AMP3_A2B_Slot12_Value "Slot12音频输入";
CM_ SG_ 505 AMP3_A2B_Slot13_Value "Slot13音频输入";
CM_ SG_ 505 AMP3_A2B_Slot14_Value "Slot14音频输入";
CM_ SG_ 505 AMP3_A2B_Slot15_Value "Slot15音频输入";
CM_ SG_ 1589 AMP_SourceNodeIdentifier "ECU节点标识符";
CM_ SG_ 1589 AMP_RepeatMessageRequest "Repeat Message请求";
CM_ SG_ 1589 AMP_Reserve1 "预留";
CM_ SG_ 1589 AMP_ActiveWakeup "激活唤醒，主动唤醒网络时置1，其他（包括被动唤醒节点）为0";
CM_ SG_ 1589 AMP_Reserve2 "预留";
CM_ SG_ 1589 AMP_WakeUp_KL15 "KL15 ON 唤醒";
CM_ SG_ 1589 AMP_WakeUp_NM "NM报文唤醒";
CM_ SG_ 1589 AMP_RemainNetworkWakeUpReason1 "保持网络唤醒原因1";
CM_ SG_ 1589 AMP_RemainNetworkWakeUpReason2 "保持网络唤醒原因2";
CM_ SG_ 1589 AMP_RemainNetworkWakeUpReason3 "保持网络唤醒原因3";
CM_ SG_ 1589 AMP_RemainNetworkWakeUpReason4 "保持网络唤醒原因4";
CM_ SG_ 325 TBOX_RTCM_size "单包数据的大小";
CM_ SG_ 325 TBOX_RTCM_num_total "分包总数";
CM_ SG_ 325 TBOX_RTCM_num "第几个分包";
CM_ SG_ 325 TBOX_RTCM_Reserved "预留位";
CM_ SG_ 325 TBOX_RTCM_data "数据";
CM_ SG_ 438 TBOX2_AVMOnReq "AVM远程启动信号";
CM_ SG_ 438 TBOX2_RemoteParkStartPressReqSts "远程APP操作车辆运动是否有效";
CM_ SG_ 438 TBOX2_RemoteHPP "远程HPP";
CM_ SG_ 438 TBOX2_AVMviewReq "用户请求AVM切换视野";
CM_ SG_ 438 TBOX2_RemoteParkReq "泊车请求";
CM_ SG_ 438 TBOX2_SecuritySts "无线网络认证状态";
CM_ SG_ 438 TBOX2_ConnectSts "无线网络APP连接情况";
CM_ SG_ 438 TBOX2_PhoneInCar "判断手机是否在车内";
CM_ SG_ 438 TBOX2_RemoteParkAbortReq "远程请求退出界面";
CM_ SG_ 438 TBOX2_RemoteParkStartPressReq "远程APP操作车辆运动状态";
CM_ SG_ 438 TBOX2_RemoteParkOutModSel "手机APP选择的泊车模式";
CM_ SG_ 438 TBOX2_PhoneBatSts "手机电量低提示信息";
CM_ SG_ 438 TBOX2_RemoteIntModSel "手机电话中断";
CM_ SG_ 438 TBOX2_RemoteSw "随意遥控开关";
CM_ SG_ 438 TBOX2_RemoteCtrModSel "手机APP选择的随意遥控模式";
CM_ SG_ 438 TBOX2_RemoteCtrSw "开启APP随意遥控泊车功能";
CM_ SG_ 438 TBOX2_Remotepick "手机App端选择接驾模式";
CM_ SG_ 438 TBOX2_NNSsuspend "智能召唤暂停";
CM_ SG_ 438 TBOX2_RemoteVhpower "请求车辆上下电";
CM_ SG_ 438 TBOX2_NRPReq "手机App打开智能召唤";
CM_ SG_ 438 TBOX2_SDMapReq "手机App显示地图";
CM_ SG_ 438 TBOX2_NNSSW "开始召唤开关";
CM_ SG_ 438 TBOX2_PA_PauseRecover_Req "手机端暂停&恢复HPP/SM请求";
CM_ SG_ 438 TBOX2_OpenFLDoorReq "左前门开闭指令";
CM_ SG_ 438 TBOX2_OpenFLFRDoorReq "前门双侧开闭指令";
CM_ SG_ 438 TBOX2_OpenFRDoorReq "右前门开闭指令";
CM_ SG_ 438 TBOX2_RollingCounter "E2E Profile2-CRC8H2F，Counter:0-15";
CM_ SG_ 438 TBOX2_Checksum "E2E Profile2-CRC8H2F
DataID List:#4 - 158 161 150 33 238 151 203 19 139 104 55 2 184 16 105 67";
CM_ SG_ 438 TBOX2_Altitude "海拔数值";
CM_ SG_ 438 TBOX2_HPA_ONPath_ID "手机端记忆泊车路线选择";
CM_ SG_ 438 TBOX2_HPA_PickPath_ID "记忆泊车接驾路线选择";
CM_ SG_ 438 TBOX2_PrivacyForbidLocSts "位置信息开关使能状态";
CM_ SG_ 438 TBOX2_PrivacyForbidDataSts "车辆运行数据开关使能状态";
CM_ SG_ 438 TBOX2_GMOnreq "哨兵模式远程开启";
CM_ SG_ 438 TBOX2_360viewReq "实时查看请求";
CM_ SG_ 438 TBOX2_360SpecView "视角实时查看";
CM_ SG_ 576 TBOX3_RemoteStartReq "远程启动请求";
CM_ SG_ 576 TBOX3_RemoteShutdownReq "远程熄火请求";
CM_ SG_ 576 TBOX3_ChargeCmd "远程充电控制";
CM_ SG_ 576 TBOX3_ChargeAppointmentSet "预约充电使能";
CM_ SG_ 576 TBOX3_FLWindowsCtrl "远程控制主驾车窗动作";
CM_ SG_ 576 TBOX3_ChargeAppointmentTimeSet "预约充电时间设置";
CM_ SG_ 576 TBOX3_RemoteLockCtrl "远程控制车辆上锁";
CM_ SG_ 576 TBOX3_RemoteTrunkCtrl "远程控制车辆尾门";
CM_ SG_ 576 TBOX3_FRWindowsCtrl "远程控制副驾车窗动作";
CM_ SG_ 576 TBOX3_IHU_CertificateState "TBOX证书有效状态";
CM_ SG_ 576 TBOX3_RLWindowsCtrl "远程控制左后车窗动作";
CM_ SG_ 576 TBOX3_RRWindowsCtrl "远程控制右后车窗动作";
CM_ SG_ 576 TBOX3_StartForbidReq "车辆禁止启动请求";
CM_ SG_ 576 TBOX3_HCU_RefuelRequest "远程控制加油请求信号";
CM_ SG_ 576 TBOX3_DischargeMainSw "外接放电开启";
CM_ SG_ 576 TBOX3_RemoteFindCarModSet "远程寻车提示模式设置";
CM_ SG_ 576 TBOX3_NetWorkSts "网络重置反馈信号";
CM_ SG_ 576 TBOX3_RemoteReadyReq "TBOX远程一键启动Ready需求";
CM_ SG_ 576 TBOX3_SosState "SOS触发信号";
CM_ SG_ 576 TBOX3_LongLifeChrgModeReq "日常使用充电模式设置请求";
CM_ SG_ 576 TBOX3_LongDistaChrgModeReq "长途旅行充电模式设置请求";
CM_ SG_ 576 TBOX3_BattHeatApt_Req "电池保温启动请求";
CM_ SG_ 576 TBOX3_SOCsettingvalid "SOC设置有效";
CM_ SG_ 576 TBOX3_SOClowerlimit "外接放电SOC设置";
CM_ SG_ 576 TBOX3_ChargeConKpTempSw "插枪保温模式";
CM_ SG_ 576 TBOX3_PDCU_ChargeRequest "充电口盖解闭锁";
CM_ SG_ 576 TBOX3_SunRoofCtrlReq "天窗控制请求";
CM_ SG_ 576 TBOX3_TemKeepModoffReq "远程驻车温度保持功能关闭请求";
CM_ SG_ 581 TBOX4_CLM_RemoteCtrlValid "远程空调控制指令有效性标志位";
CM_ SG_ 581 TBOX4_CLM_ACCmd "A/C控制指令";
CM_ SG_ 581 TBOX4_CLM_DefrostMaxCmd "除霜MAX控制指令";
CM_ SG_ 581 TBOX4_BDM_RearDefrostCmd "后除霜/雾控制指令";
CM_ SG_ 581 TBOX4_CLM_CycleCmd "空调内外循环控制指令";
CM_ SG_ 581 TBOX4_CLM_OnoffCmd "空调开启关闭控制指令";
CM_ SG_ 581 TBOX4_CLM_AutoCmd "AUTO控制指令";
CM_ SG_ 581 TBOX4_CLM_VentCmd "吹面控制指令";
CM_ SG_ 581 TBOX4_CLM_FootCmd "吹脚控制指令";
CM_ SG_ 581 TBOX4_CLM_WindowCmd "吹窗控制指令";
CM_ SG_ 581 TBOX4_CLM_AnionCmd "空气净化/负离子发生器控制指令";
CM_ SG_ 581 TBOX4_LHSeatHeaterCmd "主驾座椅加热指令";
CM_ SG_ 581 TBOX4_RHSeatHeaterCmd "副驾座椅加热指令";
CM_ SG_ 581 TBOX4_CLM_BlowerSpdSet "风速设定";
CM_ SG_ 581 TBOX4_FridgeModReq "远程冰箱运行模式控制指令";
CM_ SG_ 581 TBOX4_CLM_LHTempSet "主驾温度设定值";
CM_ SG_ 581 TBOX4_CLM_RHTempSet "副驾温度设定值";
CM_ SG_ 581 TBOX4_FLSeatVentCmd "主驾座椅通风指令";
CM_ SG_ 581 TBOX4_FRSeatVentCmd "副驾座椅通风指令";
CM_ SG_ 581 TBOX4_LRSeatHeaterCmd "后排左侧座椅加热指令";
CM_ SG_ 581 TBOX4_RRSeatHeaterCmd "后排右侧座椅加热指令";
CM_ SG_ 581 TBOX4_OilHeatingReq "燃油加热器辅热远程开关请求";
CM_ SG_ 806 TBOX5_Odometer "TBOX发送总里程";
CM_ SG_ 855 TBOX7_perc_EngOilHealth "增程器智能保养机油健康指数";
CM_ SG_ 855 TBOX7_m_MnResdMilgKm "增程器智能保养机油剩余保养里程";
CM_ SG_ 855 TBOX7_ti_MnResTiDay "增程器智能保养机油剩余保养时间";
CM_ SG_ 855 TBOX7_ti_AftMnFrznTimYear "增程器智能保养当前保养时间年";
CM_ SG_ 855 TBOX7_ti_AftMnFrznTimMonth "增程器智能保养当前保养时间月";
CM_ SG_ 855 TBOX7_ti_AftMnFrznTimDay "增程器智能保养当前保养时间天";
CM_ SG_ 855 TBOX7_ti_EE1EngIdleTimHr "增程器保养后怠速累计时间";
CM_ SG_ 855 TBOX7_m_EE1EngEquivRunMilgKm "增程器保养后等效运行里程累计";
CM_ SG_ 855 TBOX7_u_EE1HourOfDayLck "增程器保养时间小时";
CM_ SG_ 855 TBOX7_ti_EE1EngRunTimHr "增程器工作时间累计";
CM_ SG_ 978 TBOX6_Resp_EncrData0 "TBOX远程控制身份认证响应0";
CM_ SG_ 978 TBOX6_Resp_EncrData1 "TBOX远程控制身份认证响应1";
CM_ SG_ 978 TBOX6_Resp_EncrData2 "TBOX远程控制身份认证响应2";
CM_ SG_ 978 TBOX6_Resp_EncrData3 "TBOX远程控制身份认证响应3";
CM_ SG_ 978 TBOX6_Resp_EncrData4 "TBOX远程控制身份认证响应4";
CM_ SG_ 978 TBOX6_Resp_EncrData5 "TBOX远程控制身份认证响应5";
CM_ SG_ 978 TBOX6_Resp_EncrData6 "TBOX远程控制身份认证响应6";
CM_ SG_ 978 TBOX6_Resp_EncrData7 "TBOX远程控制身份认证响应7";
CM_ SG_ 1002 TBOX8_GPSAgLngtud "车辆当前位置（经度）
Vehicle current position (longitude)";
CM_ SG_ 1002 TBOX8_GPSAgLattud "车辆当前位置（纬度）
Vehicle current location (latitude)";
CM_ SG_ 1002 TBOX8_GPSYawangle "GPS朝向";
CM_ SG_ 1002 TBOX8_GPSValid "GPS有效状态";
CM_ SG_ 992 CalendarYear "Calendar Year";
CM_ SG_ 992 CalendarMonth "Calendar Month";
CM_ SG_ 992 CalendarDay "Calendar Day";
CM_ SG_ 992 HourOfDay "Hour Of Day";
CM_ SG_ 992 MinuteOfHour "Minute Of Hour";
CM_ SG_ 992 SecsOfMinute "Seconds Of Minute";
CM_ SG_ 992 TimeDspFmt "Time Display Format";
CM_ SG_ 992 TBOX1_TimezoneSts "时区设置状态";
CM_ SG_ 1010 TBOX_VIN1 "TBOX VIN ASCII 第10位";
CM_ SG_ 1010 TBOX_VIN2 "TBOX VIN ASCII 第11位";
CM_ SG_ 1010 TBOX_VIN3 "TBOX VIN ASCII 第12位";
CM_ SG_ 1010 TBOX_VIN4 "TBOX VIN ASCII 第13位";
CM_ SG_ 1010 TBOX_VIN5 "TBOX VIN ASCII 第14位";
CM_ SG_ 1010 TBOX_VIN6 "TBOX VIN ASCII 第15位";
CM_ SG_ 1010 TBOX_VIN7 "TBOX VIN ASCII 第16位";
CM_ SG_ 1010 TBOX_VIN8 "TBOX VIN ASCII 第17位";
CM_ SG_ 1537 TBOX_SourceNodeIdentifier "ECU节点标识符";
CM_ SG_ 1537 TBOX_RepeatMessageRequest "Repeat Message请求";
CM_ SG_ 1537 TBOX_Reserve1 "预留";
CM_ SG_ 1537 TBOX_ActiveWakeup "激活唤醒，主动唤醒网络时置1，其他（包括被动唤醒节点）为0";
CM_ SG_ 1537 TBOX_Reserve2 "预留";
CM_ SG_ 1537 TBOX_WakeUp_KL15 "KL15 ON 唤醒";
CM_ SG_ 1537 TBOX_WakeUp_NM "NM报文唤醒";
CM_ SG_ 1537 TBOX_WakeUp_Telematics "TBOX远程控制";
CM_ SG_ 1537 TBOX_WakeUp_Diagnosis "TBOX远程诊断";
CM_ SG_ 1537 TBOX_WakeUp_Ota "远程升级";
CM_ SG_ 1537 TBOX_WakeUp_Charge "本地预约充电";
CM_ SG_ 1537 TBOX_WakeUp_Ac "本地预约空调";
CM_ SG_ 1537 TBOX_WakeUp_Bt_control "蓝牙远控";
CM_ SG_ 1537 TBOX_RemainNetworkWakeUpReason1 "保持网络唤醒原因1";
CM_ SG_ 1537 TBOX_RemainNetworkWakeUpReason2 "保持网络唤醒原因2";
CM_ SG_ 1537 TBOX_RemainNetworkWakeUpReason3 "保持网络唤醒原因3";
CM_ SG_ 1537 TBOX_RemainNetworkWakeUpReason4 "保持网络唤醒原因4";
CM_ SG_ 1537 TBOX_RemainNetworkWakeUpReason5 "保持网络唤醒原因5";
CM_ SG_ 1537 TBOX_RemainNetworkWakeUpReason6 "保持网络唤醒原因6";
CM_ SG_ 1537 TBOX_RemainNetworkWakeUpReason7 "保持网络唤醒原因7";
CM_ SG_ 1537 TBOX_RemainNetworkWakeUpReason8 "保持网络唤醒原因8";
CM_ SG_ 1537 TBOX_RemainNetworkWakeUpReason9 "保持网络唤醒原因9";
CM_ SG_ 1537 TBOX_WakeUp_Anti_Theft "防盗拖车";

BA_DEF_ BO_ "CANFD_BRS" ENUM "0","1";
BA_DEF_ BO_ "GenMsgSendType" ENUM "Cycle","NoMsgSendType","IfActive","Event","CA","CE";
BA_DEF_ BO_ "GenMsgNrOfRepetition" INT 0 0;
BA_DEF_ BO_ "GenMsgILSupport" ENUM "No","Yes";
BA_DEF_ BO_ "GenMsgDelayTime" INT 0 0;
BA_DEF_ BO_ "GenMsgCycleTimeFast" INT 0 0;
BA_DEF_ BO_ "GenMsgCycleTime" INT 0 0;
BA_DEF_ BO_ "DiagResponse" ENUM "No","Yes";
BA_DEF_ BO_ "DiagRequest" ENUM "No","Yes";
BA_DEF_ BO_ "NmMessage" ENUM "No","Yes";
BA_DEF_ BO_ "VFrameFormat" ENUM "StandardCAN","ExtendedCAN","reserved","J1939PG","reserved","reserved","reserved","reserved","reserved","reserved","reserved","reserved","reserved","reserved","StandardCAN_FD","ExtendedCAN_FD";
BA_DEF_ SG_ "GenSigInvalidValue" HEX 0 0;
BA_DEF_ SG_ "GenSigStartValue" HEX 0 0;
BA_DEF_ SG_ "GenSigSendType" ENUM "Cycle","OnWrite","OnWriteWithRepetition","OnChange","OnChangeWithRepetition","IfActive","IfActiveWithRepetition","NoSigSendType","vector_leerstring";
BA_DEF_DEF_ "CANFD_BRS" "1";
BA_DEF_DEF_ "GenMsgSendType" "Cycle";
BA_DEF_DEF_ "GenMsgNrOfRepetition" 0;
BA_DEF_DEF_ "GenMsgILSupport" "Yes";
BA_DEF_DEF_ "GenMsgDelayTime" 0;
BA_DEF_DEF_ "GenMsgCycleTimeFast" 0;
BA_DEF_DEF_ "GenMsgCycleTime" 0;
BA_DEF_DEF_ "DiagResponse" "No";
BA_DEF_DEF_ "DiagRequest" "No";
BA_DEF_DEF_ "NmMessage" "No";
BA_DEF_DEF_ "VFrameFormat" "StandardCAN";
BA_DEF_DEF_ "GenSigInvalidValue" 0;
BA_DEF_DEF_ "GenSigStartValue" 0;
BA_DEF_DEF_ "GenSigSendType" "Cycle";
BA_ "GenMsgCycleTime" BO_ 515 50;
BA_ "VFrameFormat" BO_ 515 14;
BA_ "GenMsgCycleTime" BO_ 517 100;
BA_ "VFrameFormat" BO_ 517 14;
BA_ "GenMsgCycleTime" BO_ 697 100;
BA_ "VFrameFormat" BO_ 697 14;
BA_ "GenMsgNrOfRepetition" BO_ 757 3;
BA_ "GenMsgCycleTimeFast" BO_ 757 20;
BA_ "GenMsgSendType" BO_ 757 3;
BA_ "VFrameFormat" BO_ 757 14;
BA_ "GenMsgNrOfRepetition" BO_ 789 3;
BA_ "GenMsgCycleTimeFast" BO_ 789 20;
BA_ "GenMsgSendType" BO_ 789 3;
BA_ "VFrameFormat" BO_ 789 14;
BA_ "GenMsgNrOfRepetition" BO_ 790 3;
BA_ "GenMsgCycleTimeFast" BO_ 790 20;
BA_ "GenMsgSendType" BO_ 790 3;
BA_ "VFrameFormat" BO_ 790 14;
BA_ "GenMsgNrOfRepetition" BO_ 896 3;
BA_ "GenMsgCycleTimeFast" BO_ 896 20;
BA_ "GenMsgSendType" BO_ 896 3;
BA_ "VFrameFormat" BO_ 896 14;
BA_ "GenMsgCycleTime" BO_ 805 500;
BA_ "VFrameFormat" BO_ 805 14;
BA_ "GenMsgCycleTime" BO_ 1009 1000;
BA_ "VFrameFormat" BO_ 1009 14;
BA_ "GenMsgNrOfRepetition" BO_ 489 3;
BA_ "GenMsgCycleTimeFast" BO_ 489 50;
BA_ "GenMsgSendType" BO_ 489 3;
BA_ "VFrameFormat" BO_ 489 14;
BA_ "GenMsgCycleTime" BO_ 1424 1000;
BA_ "VFrameFormat" BO_ 1424 14;
BA_ "GenMsgCycleTime" BO_ 1544 500;
BA_ "NmMessage" BO_ 1544 1;
BA_ "GenMsgSendType" BO_ 1440 3;
BA_ "VFrameFormat" BO_ 1440 14;
BA_ "GenMsgSendType" BO_ 1441 3;
BA_ "VFrameFormat" BO_ 1441 14;
BA_ "GenMsgSendType" BO_ 1442 3;
BA_ "VFrameFormat" BO_ 1442 14;
BA_ "GenMsgCycleTime" BO_ 1443 1000;
BA_ "VFrameFormat" BO_ 1443 14;
BA_ "GenMsgCycleTime" BO_ 305 20;
BA_ "VFrameFormat" BO_ 305 14;
BA_ "GenMsgCycleTime" BO_ 758 200;
BA_ "VFrameFormat" BO_ 758 14;
BA_ "GenMsgCycleTime" BO_ 1601 500;
BA_ "NmMessage" BO_ 1601 1;
BA_ "GenMsgCycleTime" BO_ 516 100;
BA_ "VFrameFormat" BO_ 516 14;
BA_ "GenMsgCycleTime" BO_ 1606 500;
BA_ "NmMessage" BO_ 1606 1;
BA_ "GenMsgCycleTime" BO_ 502 50;
BA_ "VFrameFormat" BO_ 502 14;
BA_ "GenMsgCycleTime" BO_ 503 50;
BA_ "VFrameFormat" BO_ 503 14;
BA_ "GenMsgCycleTime" BO_ 505 50;
BA_ "VFrameFormat" BO_ 505 14;
BA_ "GenMsgCycleTime" BO_ 1589 500;
BA_ "NmMessage" BO_ 1589 1;
BA_ "GenMsgNrOfRepetition" BO_ 325 3;
BA_ "GenMsgCycleTimeFast" BO_ 325 20;
BA_ "GenMsgSendType" BO_ 325 3;
BA_ "VFrameFormat" BO_ 325 14;
BA_ "GenMsgCycleTime" BO_ 438 20;
BA_ "VFrameFormat" BO_ 438 14;
BA_ "GenMsgCycleTime" BO_ 576 100;
BA_ "VFrameFormat" BO_ 576 14;
BA_ "GenMsgCycleTime" BO_ 581 100;
BA_ "VFrameFormat" BO_ 581 14;
BA_ "GenMsgCycleTime" BO_ 806 500;
BA_ "VFrameFormat" BO_ 806 14;
BA_ "GenMsgSendType" BO_ 855 2;
BA_ "VFrameFormat" BO_ 855 14;
BA_ "GenMsgSendType" BO_ 978 2;
BA_ "VFrameFormat" BO_ 978 14;
BA_ "GenMsgCycleTime" BO_ 1002 1000;
BA_ "VFrameFormat" BO_ 1002 14;
BA_ "GenMsgCycleTime" BO_ 992 1000;
BA_ "VFrameFormat" BO_ 992 14;
BA_ "GenMsgCycleTime" BO_ 1010 1000;
BA_ "VFrameFormat" BO_ 1010 14;
BA_ "GenMsgCycleTime" BO_ 1537 500;
BA_ "NmMessage" BO_ 1537 1;
BA_ "DiagRequest" BO_ 1890 1;
BA_ "GenMsgSendType" BO_ 1890 2;
BA_ "VFrameFormat" BO_ 1890 14;
BA_ "DiagResponse" BO_ 1906 1;
BA_ "GenMsgSendType" BO_ 1906 2;
BA_ "VFrameFormat" BO_ 1906 14;
BA_ "DiagRequest" BO_ 2019 1;
BA_ "GenMsgSendType" BO_ 2019 2;
BA_ "VFrameFormat" BO_ 2019 14;
BA_ "DiagResponse" BO_ 2027 1;
BA_ "GenMsgSendType" BO_ 2027 2;
BA_ "VFrameFormat" BO_ 2027 14;
BA_ "DiagRequest" BO_ 2016 1;
BA_ "GenMsgSendType" BO_ 2016 2;
BA_ "VFrameFormat" BO_ 2016 14;
BA_ "DiagResponse" BO_ 2024 1;
BA_ "GenMsgSendType" BO_ 2024 2;
BA_ "VFrameFormat" BO_ 2024 14;
BA_ "DiagRequest" BO_ 2021 1;
BA_ "GenMsgSendType" BO_ 2021 2;
BA_ "VFrameFormat" BO_ 2021 14;
BA_ "DiagResponse" BO_ 2029 1;
BA_ "GenMsgSendType" BO_ 2029 2;
BA_ "VFrameFormat" BO_ 2029 14;
BA_ "DiagRequest" BO_ 2017 1;
BA_ "GenMsgSendType" BO_ 2017 2;
BA_ "VFrameFormat" BO_ 2017 14;
BA_ "DiagResponse" BO_ 2025 1;
BA_ "GenMsgSendType" BO_ 2025 2;
BA_ "VFrameFormat" BO_ 2025 14;
BA_ "DiagRequest" BO_ 2018 1;
BA_ "GenMsgSendType" BO_ 2018 2;
BA_ "VFrameFormat" BO_ 2018 14;
BA_ "DiagResponse" BO_ 2026 1;
BA_ "GenMsgSendType" BO_ 2026 2;
BA_ "VFrameFormat" BO_ 2026 14;
BA_ "DiagRequest" BO_ 1835 1;
BA_ "GenMsgSendType" BO_ 1835 2;
BA_ "VFrameFormat" BO_ 1835 14;
BA_ "DiagResponse" BO_ 1851 1;
BA_ "GenMsgSendType" BO_ 1851 2;
BA_ "VFrameFormat" BO_ 1851 14;
BA_ "DiagRequest" BO_ 2020 1;
BA_ "GenMsgSendType" BO_ 2020 2;
BA_ "VFrameFormat" BO_ 2020 14;
BA_ "DiagResponse" BO_ 2028 1;
BA_ "GenMsgSendType" BO_ 2028 2;
BA_ "VFrameFormat" BO_ 2028 14;
BA_ "DiagRequest" BO_ 1793 1;
BA_ "GenMsgSendType" BO_ 1793 2;
BA_ "VFrameFormat" BO_ 1793 14;
BA_ "DiagResponse" BO_ 1809 1;
BA_ "GenMsgSendType" BO_ 1809 2;
BA_ "VFrameFormat" BO_ 1809 14;
BA_ "DiagRequest" BO_ 2022 1;
BA_ "GenMsgSendType" BO_ 2022 2;
BA_ "VFrameFormat" BO_ 2022 14;
BA_ "DiagResponse" BO_ 2030 1;
BA_ "GenMsgSendType" BO_ 2030 2;
BA_ "VFrameFormat" BO_ 2030 14;
BA_ "DiagRequest" BO_ 1824 1;
BA_ "GenMsgSendType" BO_ 1824 2;
BA_ "VFrameFormat" BO_ 1824 14;
BA_ "DiagResponse" BO_ 1840 1;
BA_ "GenMsgSendType" BO_ 1840 2;
BA_ "VFrameFormat" BO_ 1840 14;
BA_ "DiagRequest" BO_ 1825 1;
BA_ "GenMsgSendType" BO_ 1825 2;
BA_ "VFrameFormat" BO_ 1825 14;
BA_ "DiagResponse" BO_ 1841 1;
BA_ "GenMsgSendType" BO_ 1841 2;
BA_ "VFrameFormat" BO_ 1841 14;
BA_ "DiagRequest" BO_ 1826 1;
BA_ "GenMsgSendType" BO_ 1826 2;
BA_ "VFrameFormat" BO_ 1826 14;
BA_ "DiagResponse" BO_ 1842 1;
BA_ "GenMsgSendType" BO_ 1842 2;
BA_ "VFrameFormat" BO_ 1842 14;
BA_ "DiagRequest" BO_ 1828 1;
BA_ "GenMsgSendType" BO_ 1828 2;
BA_ "VFrameFormat" BO_ 1828 14;
BA_ "DiagResponse" BO_ 1844 1;
BA_ "GenMsgSendType" BO_ 1844 2;
BA_ "VFrameFormat" BO_ 1844 14;
BA_ "DiagRequest" BO_ 1829 1;
BA_ "GenMsgSendType" BO_ 1829 2;
BA_ "VFrameFormat" BO_ 1829 14;
BA_ "DiagResponse" BO_ 1845 1;
BA_ "GenMsgSendType" BO_ 1845 2;
BA_ "VFrameFormat" BO_ 1845 14;
BA_ "DiagRequest" BO_ 1831 1;
BA_ "GenMsgSendType" BO_ 1831 2;
BA_ "VFrameFormat" BO_ 1831 14;
BA_ "DiagResponse" BO_ 1847 1;
BA_ "GenMsgSendType" BO_ 1847 2;
BA_ "VFrameFormat" BO_ 1847 14;
BA_ "DiagRequest" BO_ 1987 1;
BA_ "GenMsgSendType" BO_ 1987 2;
BA_ "VFrameFormat" BO_ 1987 14;
BA_ "DiagResponse" BO_ 2003 1;
BA_ "GenMsgSendType" BO_ 2003 2;
BA_ "VFrameFormat" BO_ 2003 14;
BA_ "DiagRequest" BO_ 1986 1;
BA_ "GenMsgSendType" BO_ 1986 2;
BA_ "VFrameFormat" BO_ 1986 14;
BA_ "DiagResponse" BO_ 2002 1;
BA_ "GenMsgSendType" BO_ 2002 2;
BA_ "VFrameFormat" BO_ 2002 14;
BA_ "DiagRequest" BO_ 1959 1;
BA_ "GenMsgSendType" BO_ 1959 2;
BA_ "VFrameFormat" BO_ 1959 14;
BA_ "DiagResponse" BO_ 1975 1;
BA_ "GenMsgSendType" BO_ 1975 2;
BA_ "VFrameFormat" BO_ 1975 14;
BA_ "DiagRequest" BO_ 1989 1;
BA_ "GenMsgSendType" BO_ 1989 2;
BA_ "VFrameFormat" BO_ 1989 14;
BA_ "DiagResponse" BO_ 2005 1;
BA_ "GenMsgSendType" BO_ 2005 2;
BA_ "VFrameFormat" BO_ 2005 14;
BA_ "DiagRequest" BO_ 1988 1;
BA_ "GenMsgSendType" BO_ 1988 2;
BA_ "VFrameFormat" BO_ 1988 14;
BA_ "DiagResponse" BO_ 2004 1;
BA_ "GenMsgSendType" BO_ 2004 2;
BA_ "VFrameFormat" BO_ 2004 14;
BA_ "DiagRequest" BO_ 1991 1;
BA_ "GenMsgSendType" BO_ 1991 2;
BA_ "VFrameFormat" BO_ 1991 14;
BA_ "DiagResponse" BO_ 2007 1;
BA_ "GenMsgSendType" BO_ 2007 2;
BA_ "VFrameFormat" BO_ 2007 14;
BA_ "DiagRequest" BO_ 1992 1;
BA_ "GenMsgSendType" BO_ 1992 2;
BA_ "VFrameFormat" BO_ 1992 14;
BA_ "DiagResponse" BO_ 2008 1;
BA_ "GenMsgSendType" BO_ 2008 2;
BA_ "VFrameFormat" BO_ 2008 14;
BA_ "DiagRequest" BO_ 1993 1;
BA_ "GenMsgSendType" BO_ 1993 2;
BA_ "VFrameFormat" BO_ 1993 14;
BA_ "DiagResponse" BO_ 2009 1;
BA_ "GenMsgSendType" BO_ 2009 2;
BA_ "VFrameFormat" BO_ 2009 14;
BA_ "DiagRequest" BO_ 2033 1;
BA_ "GenMsgSendType" BO_ 2033 2;
BA_ "VFrameFormat" BO_ 2033 14;
BA_ "DiagResponse" BO_ 2041 1;
BA_ "GenMsgSendType" BO_ 2041 2;
BA_ "VFrameFormat" BO_ 2041 14;
BA_ "DiagRequest" BO_ 1856 1;
BA_ "GenMsgSendType" BO_ 1856 2;
BA_ "VFrameFormat" BO_ 1856 14;
BA_ "DiagResponse" BO_ 1872 1;
BA_ "GenMsgSendType" BO_ 1872 2;
BA_ "VFrameFormat" BO_ 1872 14;
BA_ "DiagRequest" BO_ 1896 1;
BA_ "GenMsgSendType" BO_ 1896 2;
BA_ "VFrameFormat" BO_ 1896 14;
BA_ "DiagResponse" BO_ 1912 1;
BA_ "GenMsgSendType" BO_ 1912 2;
BA_ "VFrameFormat" BO_ 1912 14;
BA_ "DiagRequest" BO_ 1897 1;
BA_ "GenMsgSendType" BO_ 1897 2;
BA_ "VFrameFormat" BO_ 1897 14;
BA_ "DiagResponse" BO_ 1913 1;
BA_ "GenMsgSendType" BO_ 1913 2;
BA_ "VFrameFormat" BO_ 1913 14;
BA_ "DiagRequest" BO_ 1990 1;
BA_ "GenMsgSendType" BO_ 1990 2;
BA_ "VFrameFormat" BO_ 1990 14;
BA_ "DiagResponse" BO_ 2006 1;
BA_ "GenMsgSendType" BO_ 2006 2;
BA_ "VFrameFormat" BO_ 2006 14;
BA_ "DiagRequest" BO_ 1868 1;
BA_ "GenMsgSendType" BO_ 1868 2;
BA_ "VFrameFormat" BO_ 1868 14;
BA_ "DiagResponse" BO_ 1884 1;
BA_ "GenMsgSendType" BO_ 1884 2;
BA_ "VFrameFormat" BO_ 1884 14;
BA_ "DiagRequest" BO_ 1869 1;
BA_ "GenMsgSendType" BO_ 1869 2;
BA_ "VFrameFormat" BO_ 1869 14;
BA_ "DiagResponse" BO_ 1885 1;
BA_ "GenMsgSendType" BO_ 1885 2;
BA_ "VFrameFormat" BO_ 1885 14;
BA_ "DiagRequest" BO_ 1893 1;
BA_ "GenMsgSendType" BO_ 1893 2;
BA_ "VFrameFormat" BO_ 1893 14;
BA_ "DiagResponse" BO_ 1909 1;
BA_ "GenMsgSendType" BO_ 1909 2;
BA_ "VFrameFormat" BO_ 1909 14;
BA_ "DiagRequest" BO_ 1956 1;
BA_ "GenMsgSendType" BO_ 1956 2;
BA_ "VFrameFormat" BO_ 1956 14;
BA_ "DiagResponse" BO_ 1972 1;
BA_ "GenMsgSendType" BO_ 1972 2;
BA_ "VFrameFormat" BO_ 1972 14;
BA_ "DiagRequest" BO_ 1860 1;
BA_ "GenMsgSendType" BO_ 1860 2;
BA_ "VFrameFormat" BO_ 1860 14;
BA_ "DiagResponse" BO_ 1876 1;
BA_ "GenMsgSendType" BO_ 1876 2;
BA_ "VFrameFormat" BO_ 1876 14;
BA_ "DiagRequest" BO_ 1898 1;
BA_ "GenMsgSendType" BO_ 1898 2;
BA_ "VFrameFormat" BO_ 1898 14;
BA_ "DiagResponse" BO_ 1914 1;
BA_ "GenMsgSendType" BO_ 1914 2;
BA_ "VFrameFormat" BO_ 1914 14;
BA_ "DiagRequest" BO_ 1924 1;
BA_ "GenMsgSendType" BO_ 1924 2;
BA_ "VFrameFormat" BO_ 1924 14;
BA_ "DiagResponse" BO_ 1940 1;
BA_ "GenMsgSendType" BO_ 1940 2;
BA_ "VFrameFormat" BO_ 1940 14;
BA_ "DiagRequest" BO_ 1920 1;
BA_ "GenMsgSendType" BO_ 1920 2;
BA_ "VFrameFormat" BO_ 1920 14;
BA_ "DiagResponse" BO_ 1936 1;
BA_ "GenMsgSendType" BO_ 1936 2;
BA_ "VFrameFormat" BO_ 1936 14;
BA_ "DiagRequest" BO_ 1921 1;
BA_ "GenMsgSendType" BO_ 1921 2;
BA_ "VFrameFormat" BO_ 1921 14;
BA_ "DiagResponse" BO_ 1937 1;
BA_ "GenMsgSendType" BO_ 1937 2;
BA_ "VFrameFormat" BO_ 1937 14;
BA_ "DiagRequest" BO_ 1926 1;
BA_ "GenMsgSendType" BO_ 1926 2;
BA_ "VFrameFormat" BO_ 1926 14;
BA_ "DiagResponse" BO_ 1942 1;
BA_ "GenMsgSendType" BO_ 1942 2;
BA_ "VFrameFormat" BO_ 1942 14;
BA_ "DiagRequest" BO_ 1928 1;
BA_ "GenMsgSendType" BO_ 1928 2;
BA_ "VFrameFormat" BO_ 1928 14;
BA_ "DiagResponse" BO_ 1944 1;
BA_ "GenMsgSendType" BO_ 1944 2;
BA_ "VFrameFormat" BO_ 1944 14;
BA_ "DiagResponse" BO_ 1968 1;
BA_ "GenMsgSendType" BO_ 1968 2;
BA_ "VFrameFormat" BO_ 1968 14;
BA_ "DiagRequest" BO_ 1952 1;
BA_ "GenMsgSendType" BO_ 1952 2;
BA_ "VFrameFormat" BO_ 1952 14;
BA_ "DiagRequest" BO_ 2015 1;
BA_ "GenMsgSendType" BO_ 2015 2;
BA_ "VFrameFormat" BO_ 2015 14;
BA_ "GenSigStartValue" SG_ 697 CDCS9_AUD_Gala_LEVEL 1;
BA_ "GenSigSendType" SG_ 757 CDCS2_DischargeObejectSelect 2;
BA_ "GenSigSendType" SG_ 757 CDCS2_DischargeModeSelect 2;
BA_ "GenSigSendType" SG_ 757 CDCS2_ICUBacklightMode 2;
BA_ "GenSigSendType" SG_ 757 CDCS2_DischargeActiveSw 2;
BA_ "GenSigSendType" SG_ 757 CDCS2_WPC_OnOffSw 2;
BA_ "GenSigSendType" SG_ 757 CDCS2_ICUMod_CtrlReq 2;
BA_ "GenSigSendType" SG_ 757 CDCS2_ICUDisplayMode 2;
BA_ "GenSigSendType" SG_ 757 CDCS2_ICUTripmeter_Set 2;
BA_ "GenSigSendType" SG_ 757 CDCS2_PrivacyForbidLocReq 2;
BA_ "GenSigStartValue" SG_ 757 CDCS2_SOClowerlimit 20;
BA_ "GenSigSendType" SG_ 757 CDCS2_SOClowerlimit 2;
BA_ "GenSigSendType" SG_ 757 CDCS2_PrivacyForbidDataReq 2;
BA_ "GenSigSendType" SG_ 757 CDCS2_TimezoneSet 2;
BA_ "GenSigSendType" SG_ 757 CDCS2_ICUBacklightLevel 2;
BA_ "GenSigSendType" SG_ 757 CDCS2_AvgEnergySET 2;
BA_ "GenSigSendType" SG_ 757 CDCS2_UnlockElectronicLock 2;
BA_ "GenSigSendType" SG_ 757 CDCS2_DischargeMainSw 2;
BA_ "GenSigSendType" SG_ 757 CDCS2_ChgConKpTemp 2;
BA_ "GenSigSendType" SG_ 789 CDCS1_AC_SW 2;
BA_ "GenSigSendType" SG_ 789 CDCS1_CLM_CycleSw 2;
BA_ "GenSigSendType" SG_ 789 CDCS1_CLM_BlowerSpdPlus 2;
BA_ "GenSigSendType" SG_ 789 CDCS1_CLM_AutoSw 2;
BA_ "GenSigSendType" SG_ 789 CDCS1_CLM_LHTempPlus 2;
BA_ "GenSigSendType" SG_ 789 CDCS1_CLM_LHTempMinus 2;
BA_ "GenSigSendType" SG_ 789 CDCS1_CLM_RHTempPlus 2;
BA_ "GenSigSendType" SG_ 789 CDCS1_CLM_RHTempMinus 2;
BA_ "GenSigSendType" SG_ 789 CDCS1_CLM_FootSw 2;
BA_ "GenSigSendType" SG_ 789 CDCS1_CLM_AnionSw 2;
BA_ "GenSigSendType" SG_ 789 CDCS1_CLM_BlowerSpdSet 2;
BA_ "GenSigSendType" SG_ 789 CDCS1_CLM_AcFilterResetReq 2;
BA_ "GenSigSendType" SG_ 789 CDCS1_CLM_BlowerSpdSetValid 2;
BA_ "GenSigSendType" SG_ 789 CDCS1_CLM_LHTempSetValid 2;
BA_ "GenSigSendType" SG_ 789 CDCS1_CLM_RHTempSetValid 2;
BA_ "GenSigSendType" SG_ 789 CDCS1_CLM_LHTempSet 2;
BA_ "GenSigSendType" SG_ 789 CDCS1_CLM_DualSw 2;
BA_ "GenSigSendType" SG_ 789 CDCS1_CLM_RHTempSet 2;
BA_ "GenSigSendType" SG_ 789 CDCS1_BDCS_RearDefrostSw 2;
BA_ "GenSigSendType" SG_ 789 CDCS1_CLM_OnoffSw 2;
BA_ "GenSigSendType" SG_ 789 CDCS1_CLM_BlowerSpdMinus 2;
BA_ "GenSigSendType" SG_ 789 CDCS1_CLM_WindowSw 2;
BA_ "GenSigSendType" SG_ 789 CDCS1_CLM_VentSw 2;
BA_ "GenSigSendType" SG_ 789 CDCS1_ACMaxSW 2;
BA_ "GenSigSendType" SG_ 789 CDCS1_AirClean 2;
BA_ "GenSigSendType" SG_ 789 CDCS1_AC_ECONMode 2;
BA_ "GenSigSendType" SG_ 789 CDCS1_LEAOSts 2;
BA_ "GenSigSendType" SG_ 789 CDCS1_REAOSts 2;
BA_ "GenSigSendType" SG_ 789 CDCS1_AC_Ventilation 2;
BA_ "GenSigSendType" SG_ 790 CDCS6_FridgeMod_Req 2;
BA_ "GenSigSendType" SG_ 790 CDCS6_FridgeTemp_KeepReq 2;
BA_ "GenSigSendType" SG_ 790 CDCS6_FridgeCool_Temp_Req 2;
BA_ "GenSigSendType" SG_ 790 CDCS6_FridgeTemp_Plus 2;
BA_ "GenSigSendType" SG_ 790 CDCS6_FridgeTemp_Minus 2;
BA_ "GenSigSendType" SG_ 790 CDCS6_FridgeHeat_Temp_Req 2;
BA_ "GenSigSendType" SG_ 790 CDCS6_OilHeatingSw 2;
BA_ "GenSigSendType" SG_ 896 CDCS8_VoiceTrunkCtrl 2;
BA_ "GenSigSendType" SG_ 896 CDCS8_TrunkSWReq 2;
BA_ "GenSigSendType" SG_ 896 CDCS8_RearDoorHeightSet 2;
BA_ "GenSigSendType" SG_ 896 CDCS8_FRSeatEZEReq 2;
BA_ "GenSigSendType" SG_ 896 CDCS8_FLSeatEZEReq 2;
BA_ "GenSigSendType" SG_ 896 CDCS8_SOC_LampSwt 2;
BA_ "GenSigSendType" SG_ 896 CDCS8_FLLumbarUpAndDownAdj 2;
BA_ "GenSigSendType" SG_ 896 CDCS8_FLLumbaForwardorBackwardAdj 2;
BA_ "GenSigSendType" SG_ 896 CDCS8_ALH_TemperatureSW 2;
BA_ "GenSigSendType" SG_ 896 CDCS8_FRLumbarUpAndDownAdj 2;
BA_ "GenSigSendType" SG_ 896 CDCS8_FRLumbaForwardorBackwardAdj 2;
BA_ "GenSigSendType" SG_ 896 CDCS8_IncomingCall 2;
BA_ "GenSigSendType" SG_ 896 CDCS8_FrontSeatAutoEZEReq 2;
BA_ "GenSigSendType" SG_ 896 CDCS8_FRSeatHeatCmd 2;
BA_ "GenSigSendType" SG_ 896 CDCS8_FLSeatHeatCmd 2;
BA_ "GenSigSendType" SG_ 896 CDCS8_FLSeatVentCmd 2;
BA_ "GenSigSendType" SG_ 896 CDCS8_FRSeatVentCmd 2;
BA_ "GenSigSendType" SG_ 489 CDCS21_NavSpeedLimitStatus 2;
BA_ "GenSigSendType" SG_ 489 CDCS21_Nav_CountryID 2;
BA_ "GenSigSendType" SG_ 489 CDCS21_Nav_SpeedLimitUnits 2;
BA_ "GenSigSendType" SG_ 489 CDCS21_Nav_CurrRoadType 2;
BA_ "GenSigSendType" SG_ 489 CDCS21_NavSpeedlimit 2;
BA_ "GenSigStartValue" SG_ 489 CDCS21_NavRampDistance 511;
BA_ "GenSigSendType" SG_ 489 CDCS21_NavRampDistance 2;
BA_ "GenSigSendType" SG_ 489 CDCS21_NavSpeedlimit_Rain 2;
BA_ "GenSigSendType" SG_ 489 CDCS21_NavSpeedlimit_Snow 2;
BA_ "GenSigSendType" SG_ 489 CDCS21_NavSpeedlimit_fog 2;
BA_ "GenSigStartValue" SG_ 489 CDCS21_NavSpeedlimitSign_Distance 8191;
BA_ "GenSigSendType" SG_ 489 CDCS21_NavSpeedlimitSign_Distance 2;
BA_ "GenSigSendType" SG_ 1440 CDCS_RouteNTraPonlongitude1or8 3;
BA_ "GenSigSendType" SG_ 1440 CDCS_RouteNTraPonlatitude1or8 3;
BA_ "GenSigSendType" SG_ 1440 CDCS_RouteNTraPonlongitude2or9 3;
BA_ "GenSigSendType" SG_ 1440 CDCS_RouteNTraPonlatitude2or9 3;
BA_ "GenSigSendType" SG_ 1440 CDCS_RouteNTraPonlongitude3or10 3;
BA_ "GenSigSendType" SG_ 1440 CDCS_RouteNTraPonlatitude3or10 3;
BA_ "GenSigSendType" SG_ 1440 CDCS_RouteNTraPonlongitude4or11 3;
BA_ "GenSigSendType" SG_ 1440 CDCS_RouteNTraPonlatitude4or11 3;
BA_ "GenSigSendType" SG_ 1440 CDCS_RouteNTraPonlongitude5or12 3;
BA_ "GenSigSendType" SG_ 1440 CDCS_RouteNTraPonlatitude5or12 3;
BA_ "GenSigSendType" SG_ 1440 CDCS_RouteNTraPonlongitude6or13 3;
BA_ "GenSigSendType" SG_ 1440 CDCS_RouteNTraPonlatitude6or13 3;
BA_ "GenSigSendType" SG_ 1440 CDCS_RouteNTraPonlongitude7or14 3;
BA_ "GenSigSendType" SG_ 1440 CDCS_RouteNTraPonlatitude7or14 3;
BA_ "GenSigSendType" SG_ 1440 CDCS_RouteInfoTipsNum1 3;
BA_ "GenSigSendType" SG_ 1441 CDCS_RouteNTraPonlongitude15 3;
BA_ "GenSigSendType" SG_ 1441 CDCS_RouteNTraPonlatitude15 3;
BA_ "GenSigSendType" SG_ 1441 CDCS_RouteNTraPonlongitude16 3;
BA_ "GenSigSendType" SG_ 1441 CDCS_RouteNTraPonlatitude16 3;
BA_ "GenSigSendType" SG_ 1441 CDCS_RouteNTraPonlongitude17 3;
BA_ "GenSigSendType" SG_ 1441 CDCS_RouteNTraPonlatitude17 3;
BA_ "GenSigSendType" SG_ 1441 CDCS_RouteNTraPonlongitude18 3;
BA_ "GenSigSendType" SG_ 1441 CDCS_RouteNTraPonlatitude18 3;
BA_ "GenSigSendType" SG_ 1441 CDCS_RouteNTraPonlongitude19 3;
BA_ "GenSigSendType" SG_ 1441 CDCS_RouteNTraPonlatitude19 3;
BA_ "GenSigSendType" SG_ 1441 CDCS_RouteNTraPonlongitude20 3;
BA_ "GenSigSendType" SG_ 1441 CDCS_RouteNTraPonlatitude20 3;
BA_ "GenSigSendType" SG_ 1441 CDCS_RouteNDepartureTime 3;
BA_ "GenSigSendType" SG_ 1441 CDCS_RouteNTripLength 3;
BA_ "GenSigSendType" SG_ 1441 CDCS_RouteNDrivingTime 3;
BA_ "GenSigSendType" SG_ 1441 CDCS_RouteNDailyRouteNum 3;
BA_ "GenSigSendType" SG_ 1441 CDCS_RouteNStrFixChrgPnt 3;
BA_ "GenSigSendType" SG_ 1441 CDCS_RouteNDestFixChrgPnt 3;
BA_ "GenSigSendType" SG_ 1441 CDCS_RouInfoTipsNum2 3;
BA_ "GenSigSendType" SG_ 1442 CDCS_RouteNTotEnergyCon 3;
BA_ "GenSigSendType" SG_ 1442 CDCS_RouteNDrvEnergyCon 3;
BA_ "GenSigSendType" SG_ 1442 CDCS_RouteNAcyEnergyCon 3;
BA_ "GenSigSendType" SG_ 1442 CDCS_RouteNACEnergyCon 3;
BA_ "GenSigSendType" SG_ 1442 CDCS_RouInfoTipsNum3 3;
BA_ "GenSigStartValue" SG_ 502 AMP1_AUD_Gala_Value 1;
BA_ "GenSigStartValue" SG_ 503 APM2_Slot0_VolumeValue 8;
BA_ "GenSigStartValue" SG_ 503 APM2_Slot1_VolumeValue 8;
BA_ "GenSigStartValue" SG_ 503 APM2_Slot2_VolumeValue 8;
BA_ "GenSigStartValue" SG_ 503 APM2_Slot3_VolumeValue 8;
BA_ "GenSigStartValue" SG_ 503 APM2_Slot4_VolumeValue 8;
BA_ "GenSigStartValue" SG_ 503 APM2_Slot5_VolumeValue 8;
BA_ "GenSigStartValue" SG_ 503 APM2_Slot6_VolumeValue 8;
BA_ "GenSigStartValue" SG_ 503 APM2_Slot7_VolumeValue 8;
BA_ "GenSigStartValue" SG_ 503 APM2_AUD_Mute_Status 1;
BA_ "GenSigStartValue" SG_ 505 AMP3_EQBand1Val 12;
BA_ "GenSigStartValue" SG_ 505 AMP3_EQBand2Val 12;
BA_ "GenSigStartValue" SG_ 505 AMP3_EQBand3Val 12;
BA_ "GenSigStartValue" SG_ 505 AMP3_EQBand4Val 12;
BA_ "GenSigStartValue" SG_ 505 AMP3_EQBand5Val 12;
BA_ "GenSigStartValue" SG_ 505 AMP3_Slot8_VolumeValue 8;
BA_ "GenSigStartValue" SG_ 505 AMP3_Slot9_VolumeValue 8;
BA_ "GenSigStartValue" SG_ 505 AMP3_Slot10_VolumeValue 8;
BA_ "GenSigStartValue" SG_ 505 AMP3_Slot11_VolumeValue 8;
BA_ "GenSigStartValue" SG_ 505 AMP3_Slot12_VolumeValue 8;
BA_ "GenSigStartValue" SG_ 505 AMP3_Slot13_VolumeValue 8;
BA_ "GenSigStartValue" SG_ 505 AMP3_Slot14_VolumeValue 8;
BA_ "GenSigStartValue" SG_ 505 AMP3_Slot15_VolumeValue 8;
BA_ "GenSigSendType" SG_ 325 TBOX_RTCM_size 1;
BA_ "GenSigSendType" SG_ 325 TBOX_RTCM_num_total 1;
BA_ "GenSigSendType" SG_ 325 TBOX_RTCM_num 1;
BA_ "GenSigSendType" SG_ 325 TBOX_RTCM_Reserved 1;
BA_ "GenSigSendType" SG_ 325 TBOX_RTCM_data 1;
BA_ "GenSigInvalidValue" SG_ 438 TBOX2_Altitude 65535;
BA_ "GenSigStartValue" SG_ 438 TBOX2_PrivacyForbidLocSts 1;
BA_ "GenSigStartValue" SG_ 438 TBOX2_PrivacyForbidDataSts 1;
BA_ "GenSigStartValue" SG_ 576 TBOX3_SOClowerlimit 20;
BA_ "GenSigSendType" SG_ 855 TBOX7_perc_EngOilHealth 5;
BA_ "GenSigSendType" SG_ 855 TBOX7_m_MnResdMilgKm 5;
BA_ "GenSigSendType" SG_ 855 TBOX7_ti_MnResTiDay 5;
BA_ "GenSigSendType" SG_ 855 TBOX7_ti_AftMnFrznTimYear 5;
BA_ "GenSigSendType" SG_ 855 TBOX7_ti_AftMnFrznTimMonth 5;
BA_ "GenSigSendType" SG_ 855 TBOX7_ti_AftMnFrznTimDay 5;
BA_ "GenSigSendType" SG_ 855 TBOX7_ti_EE1EngIdleTimHr 5;
BA_ "GenSigSendType" SG_ 855 TBOX7_m_EE1EngEquivRunMilgKm 5;
BA_ "GenSigSendType" SG_ 855 TBOX7_u_EE1HourOfDayLck 5;
BA_ "GenSigSendType" SG_ 855 TBOX7_ti_EE1EngRunTimHr 5;
BA_ "GenSigSendType" SG_ 978 TBOX6_Resp_EncrData0 5;
BA_ "GenSigSendType" SG_ 978 TBOX6_Resp_EncrData1 5;
BA_ "GenSigSendType" SG_ 978 TBOX6_Resp_EncrData2 5;
BA_ "GenSigSendType" SG_ 978 TBOX6_Resp_EncrData3 5;
BA_ "GenSigSendType" SG_ 978 TBOX6_Resp_EncrData4 5;
BA_ "GenSigSendType" SG_ 978 TBOX6_Resp_EncrData5 5;
BA_ "GenSigSendType" SG_ 978 TBOX6_Resp_EncrData6 5;
BA_ "GenSigSendType" SG_ 978 TBOX6_Resp_EncrData7 5;
BA_ "GenSigInvalidValue" SG_ 1002 TBOX8_GPSAgLngtud 68719476735;
BA_ "GenSigStartValue" SG_ 1002 TBOX8_GPSAgLngtud 68719476735;
BA_ "GenSigInvalidValue" SG_ 1002 TBOX8_GPSAgLattud 68719476735;
BA_ "GenSigStartValue" SG_ 1002 TBOX8_GPSAgLattud 68719476735;
BA_ "GenSigInvalidValue" SG_ 1002 TBOX8_GPSYawangle 4095;
BA_ "GenSigStartValue" SG_ 1002 TBOX8_GPSYawangle 4095;
BA_ "GenSigStartValue" SG_ 992 TBOX1_TimezoneSts 15;
BA_ "GenSigSendType" SG_ 1890 DiagnosticReqAICS 5;
BA_ "GenSigSendType" SG_ 1906 DiagnosticRespAICS 5;
BA_ "GenSigSendType" SG_ 2019 DiagnosticReqPDCS1 5;
BA_ "GenSigSendType" SG_ 2027 DiagnosticRespPDCS1 5;
BA_ "GenSigSendType" SG_ 2016 DiagnosticReqEMS 5;
BA_ "GenSigSendType" SG_ 2024 DiagnosticRespEMS 5;
BA_ "GenSigSendType" SG_ 2021 DiagnosticReqBMS 5;
BA_ "GenSigSendType" SG_ 2029 DiagnosticRespBMS 5;
BA_ "GenSigSendType" SG_ 2017 DIAGPhysReqMCU 5;
BA_ "GenSigSendType" SG_ 2025 DIAGPhysRespMCU 5;
BA_ "GenSigSendType" SG_ 2018 DiagnosticReqCDU 5;
BA_ "GenSigSendType" SG_ 2026 DiagnosticRespCDU 5;
BA_ "GenSigSendType" SG_ 1835 DiagnosticReqHVM 5;
BA_ "GenSigSendType" SG_ 1851 DiagnosticRespHVM 5;
BA_ "GenSigSendType" SG_ 2020 DiagnosticReqGCU 5;
BA_ "GenSigSendType" SG_ 2028 DiagnosticRespGCU 5;
BA_ "GenSigSendType" SG_ 1793 DiagnosticReqEVCC 5;
BA_ "GenSigSendType" SG_ 1809 DiagnosticRespEVCC 5;
BA_ "GenSigSendType" SG_ 2022 DiagnosticReqIDB 5;
BA_ "GenSigSendType" SG_ 2030 DiagnosticRespIDB 5;
BA_ "GenSigSendType" SG_ 1824 DiagnosticReqESC 5;
BA_ "GenSigSendType" SG_ 1840 DiagnosticRespESC 5;
BA_ "GenSigSendType" SG_ 1825 DiagnosticReqREPB 5;
BA_ "GenSigSendType" SG_ 1841 DiagnosticRespREPB 5;
BA_ "GenSigSendType" SG_ 1826 DiagnosticReqEHB 5;
BA_ "GenSigSendType" SG_ 1842 DiagnosticRespEHB 5;
BA_ "GenSigSendType" SG_ 1828 DIAGPhysReqEPS 5;
BA_ "GenSigSendType" SG_ 1844 DIAGPhysRespEPS 5;
BA_ "GenSigSendType" SG_ 1829 DiagnosticReqISC 5;
BA_ "GenSigSendType" SG_ 1845 DiagnosticRespISC 5;
BA_ "GenSigSendType" SG_ 1831 DiagnosticReqADCS 5;
BA_ "GenSigSendType" SG_ 1847 DiagnosticRespADCS 5;
BA_ "GenSigSendType" SG_ 1987 DiagnosticReqADCU 5;
BA_ "GenSigSendType" SG_ 2003 DiagnosticRespADCU 5;
BA_ "GenSigSendType" SG_ 1986 DiagnosticReqFLC 5;
BA_ "GenSigSendType" SG_ 2002 DiagnosticRespFLC 5;
BA_ "GenSigSendType" SG_ 1959 DiagnosticReqIMU 5;
BA_ "GenSigSendType" SG_ 1975 DiagnosticRespIMU 5;
BA_ "GenSigSendType" SG_ 1989 DiagnosticReqLRR 5;
BA_ "GenSigSendType" SG_ 2005 DiagnosticRespLRR 5;
BA_ "GenSigSendType" SG_ 1988 DiagnosticReqSRR1 5;
BA_ "GenSigSendType" SG_ 2004 DiagnosticRespSRR1 5;
BA_ "GenSigSendType" SG_ 1991 DiagnosticReqSRR2 5;
BA_ "GenSigSendType" SG_ 2007 DiagnosticRespSRR2 5;
BA_ "GenSigSendType" SG_ 1992 DiagnosticReqSRR3 5;
BA_ "GenSigSendType" SG_ 2008 DiagnosticRespSRR3 5;
BA_ "GenSigSendType" SG_ 1993 DiagnosticReqSRR4 5;
BA_ "GenSigSendType" SG_ 2009 DiagnosticRespSRR4 5;
BA_ "GenSigSendType" SG_ 2033 DiagnosticReqACU 5;
BA_ "GenSigSendType" SG_ 2041 DiagnosticRespACU 5;
BA_ "GenSigSendType" SG_ 1856 DiagnosticReqBDCS 5;
BA_ "GenSigSendType" SG_ 1872 DiagnosticRespBDCS 5;
BA_ "GenSigSendType" SG_ 1896 DiagnosticReqDDCU 5;
BA_ "GenSigSendType" SG_ 1912 DiagnosticRespDDCU 5;
BA_ "GenSigSendType" SG_ 1897 DiagnosticReqPDCU 5;
BA_ "GenSigSendType" SG_ 1913 DiagnosticRespPDCU 5;
BA_ "GenSigSendType" SG_ 1990 DiagnosticReqBAM 5;
BA_ "GenSigSendType" SG_ 2006 DiagnosticRespBAM 5;
BA_ "GenSigSendType" SG_ 1868 DiagnosticReqEACP 5;
BA_ "GenSigSendType" SG_ 1884 DiagnosticRespEACP 5;
BA_ "GenSigSendType" SG_ 1869 DiagnosticReqTC 5;
BA_ "GenSigSendType" SG_ 1885 DiagnosticRespTC 5;
BA_ "GenSigSendType" SG_ 1893 DiagnosticReqPTC 5;
BA_ "GenSigSendType" SG_ 1909 DiagnosticRespPTC 5;
BA_ "GenSigSendType" SG_ 1956 DiagnosticReqCS 5;
BA_ "GenSigSendType" SG_ 1972 DiagnosticRespCS 5;
BA_ "GenSigSendType" SG_ 1860 DiagnosticReqRLS 5;
BA_ "GenSigSendType" SG_ 1876 DiagnosticRespRLS 5;
BA_ "GenSigSendType" SG_ 1898 DiagnosticReqDFGLS 5;
BA_ "GenSigSendType" SG_ 1914 DiagnosticRespDFGLS 5;
BA_ "GenSigSendType" SG_ 1924 DiagnosticReqOHC 5;
BA_ "GenSigSendType" SG_ 1940 DiagnosticRespOHC 5;
BA_ "GenSigSendType" SG_ 1920 DiagnosticReqCDCS 5;
BA_ "GenSigSendType" SG_ 1936 DiagnosticRespCDCS 5;
BA_ "GenSigSendType" SG_ 1921 DiagnosticReqICU 5;
BA_ "GenSigSendType" SG_ 1937 DiagnosticRespICU 5;
BA_ "GenSigSendType" SG_ 1926 DiagnosticReqWPC 5;
BA_ "GenSigSendType" SG_ 1942 DiagnosticRespWPC 5;
BA_ "GenSigSendType" SG_ 1928 DiagnosticReqAMP 5;
BA_ "GenSigSendType" SG_ 1944 DiagnosticRespAMP 5;
BA_ "GenSigSendType" SG_ 1968 DiagnosticRespTBOX 5;
BA_ "GenSigSendType" SG_ 1952 DiagnosticReqTBOX 5;
BA_ "GenSigSendType" SG_ 2015 DiagnosticReqFunc 5;
VAL_ 515 CDCS15_ChildrenPresentDetection 1 "Child exist" 0 "No child";
VAL_ 515 CDCS15_FLSeatHorizontalAdj 3 "reserrved" 2 "Backward" 1 "Forward" 0 "No  request";
VAL_ 515 CDCS15_FLSeatVerticalAdj 3 "reserrved" 2 "Down" 1 "Up" 0 "No  request";
VAL_ 515 CDCS15_FLSeatCushionTiltAdj 3 "reserrved" 2 "Downdip" 1 "Updip" 0 "No  request";
VAL_ 515 CDCS15_FLSeatBackrestAngletAdj 3 "reserrved" 2 "Hypsokinesis" 1 "Foreake" 0 "No request";
VAL_ 515 CDCS15_FRSeatHorizontalAdj 3 "reserrved" 2 "Backward" 1 "Forward" 0 "No  request";
VAL_ 515 CDCS15_FRSeatVerticalAdj 3 "reserrved" 2 "Down" 1 "Up" 0 "No  request";
VAL_ 515 CDCS15_FRSeatLegsupportAdj 3 "reserrved" 2 "Downdip" 1 "Updip" 0 "No  request";
VAL_ 515 CDCS15_FRSeatBackrestAngletAdj 3 "reserrved" 2 "Hypsokinesis" 1 "Foreake" 0 "No request";
VAL_ 515 CDCS15_FLLumbarUpAndDownAdj 3 "reserrved" 2 "Down" 1 "Up" 0 "No request";
VAL_ 515 CDCS15_FLLumbaForwardorBackwardAdj 3 "reserrved" 2 "Backward" 1 "Forward" 0 "No request";
VAL_ 515 CDCS15_FRLumbarUpAndDownAdj 3 "reserrved" 2 "Down" 1 "Up" 0 "No request";
VAL_ 515 CDCS15_FRLumbaForwardorBackwardAdj 3 "reserrved" 2 "Backward" 1 "Forward" 0 "No request";
VAL_ 515 CDCS15_AILampVoiceMode 15 "Reserved" 14 "Reserved" 13 "Reserved" 12 "Reserved" 11 "Reserved" 10 "Reserved" 9 "Reserved" 8 "Reserved" 7 "Voice preset7" 6 "Voice preset6" 5 "Voice preset5" 4 "Voice preset4" 3 "Voice preset3" 2 "Voice preset2" 1 "Voice preset1" 0 "No request";
VAL_ 515 CDCS15_AILampMode 31 "Reserved" 30 "Reserved" 29 "Reserved" 28 "Reserved" 27 "Reserved" 26 "Reserved" 25 "Reserved" 24 "Reserved" 23 "Reserved" 22 "Reserved" 21 "Reserved" 20 "Reserved" 19 "Reserved" 18 "Reserved" 17 "Reserved" 16 "Reserved" 15 "Reserved" 14 "Reserved" 13 "GreenRightTurn" 12 "GreenLeftTurn" 11 "GreenBreathing" 10 "GreenBlinkIntermittent" 9 "GreenBlink1Hz" 8 "RedBlink2Hz" 7 "RedBlink1Hz" 6 "YellowBlink1Hz" 5 "BlueStayON" 4 "BlueRightTurn2Hz" 3 "BlueRightTurn1Hz" 2 "BlueLeftTurn2Hz" 1 "BlueLeftTurn1Hz" 0 "No request";
VAL_ 515 CDCS15_DMS_DriverStatusValid 1 "Valid" 0 "Invalid";
VAL_ 515 CDCS15_DMS_DriverStatus 3 "reserved" 2 "Driver Distracted" 1 "Driver Fatigue" 0 "None";
VAL_ 515 CDCS15_Storage_St 1 "not available" 0 "available";
VAL_ 515 CDCS15_USB_St 1 "not available" 0 "available";
VAL_ 515 CDCS15_UserSceneMode 15 "Reserved" 14 "Reserved" 13 "Reserved" 12 "Reserved" 11 "Reserved" 10 "OtherMode5" 9 "OtherMode4" 8 "OtherMode3" 7 "OtherMode2" 6 "OtherMode1" 5 "CampingMode" 4 "PetMode" 3 "Childmode" 2 "CarWashMode" 1 "RacingMode" 0 "No Scene";
VAL_ 515 CDCS15_NNP_DriverFatigueStatus 3 "Fatigue" 2 "Not Fatigue" 1 "No Face" 0 "Disable";
VAL_ 515 CDCS15_NNP_DriverDistractedStatus 3 "Distracted" 2 "Not Distracted" 1 "No Face" 0 "Disable";
VAL_ 515 CDCS15_ALHSelectTheme 7 "Reserved" 6 "Reserved" 5 "Theme5" 4 "Theme4" 3 "Theme3" 2 "Theme2" 1 "Theme1" 0 "No Action";
VAL_ 515 CDCS15_RL_LumbarUpAndDownAdj 3 "reserrved" 2 "Down" 1 "Up" 0 "No request";
VAL_ 515 CDCS15_RL_LumbarFwdBakwdAdj 3 "reserrved" 2 "Backward" 1 "Forward" 0 "No request";
VAL_ 515 CDCS15_RR_LumbarUpAndDownAdj 3 "reserrved" 2 "Down" 1 "Up" 0 "No request";
VAL_ 515 CDCS15_RR_LumbarFwdBakwdAdj 3 "reserrved" 2 "Backward" 1 "Forward" 0 "No request";
VAL_ 515 CDCS15_FRSeatLegsupportLengthAdj 3 "reserrved" 2 "Backward" 1 "Forward" 0 "No request";
VAL_ 515 CDCS15_FRSeatLegsupporLengthVoiceAd 3 "reserrved" 2 "Backward" 1 "Forward" 0 "No request";
VAL_ 515 CDCS15_ALH_ADASWarning 3 "Reserved" 2 "OFF" 1 "ON" 0 "No Action";
VAL_ 515 CDCS15_ALHBrightnessAutoMode 3 "Reserved" 2 "Manual mode" 1 "Auto mode" 0 "No Request";
VAL_ 517 CDCS18_CameraSpeedLimit 0 "No traffic limit speed";
VAL_ 517 CDCS18_CameraDistance 0 "无限速信息";
VAL_ 517 CDCS18_RoadSpeedLimit 0 "No traffic limit speed";
VAL_ 517 CDCS18_DisplaySpeedLimit 0 "No traffic limit speed";
VAL_ 517 CDCS18_LaneNavigation 255 "Reserved" 254 "Reserved" 253 "Reserved" 252 "Reserved" 251 "Reserved" 250 "Reserved" 249 "Reserved" 248 "Reserved" 247 "Reserved" 246 "Reserved" 245 "Reserved" 244 "Reserved" 243 "Reserved" 242 "Reserved" 241 "Reserved" 240 "Reserved" 239 "Reserved" 238 "Reserved" 237 "Reserved" 236 "Reserved" 235 "Reserved" 234 "Reserved" 233 "Reserved" 232 "Reserved" 231 "Reserved" 230 "Reserved" 229 "Reserved" 228 "Reserved" 227 "Reserved" 226 "Reserved" 225 "Reserved" 224 "Reserved" 223 "Reserved" 222 "Reserved" 221 "Reserved" 220 "Reserved" 219 "Reserved" 218 "Reserved" 217 "Reserved" 216 "Reserved" 215 "Reserved" 214 "Reserved" 213 "Reserved" 212 "Reserved" 211 "Reserved" 210 "Reserved" 209 "Reserved" 208 "Reserved" 207 "Reserved" 206 "Reserved" 205 "Reserved" 204 "Reserved" 203 "Reserved" 202 "Reserved" 201 "Reserved" 200 "Reserved" 199 "Reserved" 198 "Reserved" 197 "Reserved" 196 "Reserved" 195 "Reserved" 194 "Reserved" 193 "Reserved" 192 "Reserved" 191 "Reserved" 190 "Reserved" 189 "Reserved" 188 "Reserved" 187 "Reserved" 186 "Reserved" 185 "Reserved" 184 "Reserved" 183 "Reserved" 182 "Reserved" 181 "Reserved" 180 "Reserved" 179 "Reserved" 178 "Reserved" 177 "Reserved" 176 "Reserved" 175 "Reserved" 174 "Reserved" 173 "Reserved" 172 "Reserved" 171 "Reserved" 170 "Reserved" 169 "Reserved" 168 "Reserved" 167 "Reserved" 166 "Reserved" 165 "Reserved" 164 "Reserved" 163 "Reserved" 162 "Reserved" 161 "Reserved" 160 "Reserved" 159 "Reserved" 158 "Reserved" 157 "Reserved" 156 "Reserved" 155 "Reserved" 154 "Reserved" 153 "Reserved" 152 "Reserved" 151 "Reserved" 150 "Reserved" 149 "Reserved" 148 "Reserved" 147 "Reserved" 146 "Reserved" 145 "Reserved" 144 "Reserved" 143 "Reserved" 142 "Reserved" 141 "Reserved" 140 "Reserved" 139 "Reserved" 138 "Reserved" 137 "Reserved" 136 "Reserved" 135 "Reserved" 134 "Reserved" 133 "Reserved" 132 "Reserved" 131 "Reserved" 130 "Reserved" 129 "Reserved" 128 "Reserved" 127 "Reserved" 126 "Reserved" 125 "Reserved" 124 "Reserved" 123 "Reserved" 122 "Reserved" 121 "Reserved" 120 "Reserved" 119 "Reserved" 118 "Reserved" 117 "Reserved" 116 "Reserved" 115 "Reserved" 114 "Reserved" 113 "Reserved" 112 "Reserved" 111 "Reserved" 110 "Reserved" 109 "Reserved" 108 "Reserved" 107 "Reserved" 106 "Reserved" 105 "Reserved" 104 "Reserved" 103 "Reserved" 102 "Reserved" 101 "Reserved" 100 "Reserved" 99 "Reserved" 98 "Reserved" 97 "Reserved" 96 "Reserved" 95 "Reserved" 94 "Reserved" 93 "Reserved" 92 "Reserved" 91 "Reserved" 90 "Reserved" 89 "Reserved" 88 "Reserved" 87 "Reserved" 86 "Reserved" 85 "Reserved" 84 "Reserved" 83 "Reserved" 82 "Reserved" 81 "Reserved" 80 "Reserved" 79 "Reserved" 78 "Reserved" 77 "Reserved" 76 "Reserved" 75 "Reserved" 74 "Reserved" 73 "Reserved" 72 "Reserved" 71 "Reserved" 70 "Reserved" 69 "Reserved" 68 "Reserved" 67 "Reserved" 66 "Reserved" 65 "Reserved" 64 "Reserved" 63 "Reserved" 62 "Reserved" 61 "Reserved" 60 "Reserved" 59 "Reserved" 58 "Reserved" 57 "Reserved" 56 "Reserved" 55 "Reserved" 54 "Reserved" 53 "Reserved" 52 "Reserved" 51 "Reserved" 50 "Reserved" 49 "Reserved" 48 "Reserved" 47 "Reserved" 46 "Reserved" 45 "Reserved" 44 "Reserved" 43 "Reserved" 42 "Reserved" 41 "Reserved" 40 "Reserved" 39 "Reserved" 38 "Reserved" 37 "Reserved" 36 "Reserved" 35 "Reserved" 34 "Reserved" 33 "Reserved" 32 "Reserved" 31 "Reserved" 30 "Reserved" 29 "Reserved" 28 "Reserved" 27 "Reserved" 26 "Reserved" 25 "Reserved" 24 "Reserved" 23 "Reserved" 22 "Reserved" 21 "Reserved" 20 "Reserved" 19 "Reserved" 18 "Reserved" 17 "Reserved" 16 "Reserved" 15 "Reserved" 14 "Reserved" 13 "Reserved" 12 "Reserved" 11 "Reserved" 10 "Reserved" 9 "Reserved" 8 "Reserved" 7 "Reserved" 6 "Reserved" 5 "Reserved" 4 "Reserved" 3 "Reserved" 2 "Reserved" 1 "处于车道级导航" 0 "不在车道级导航";
VAL_ 517 CDCS18_AVM_Status 3 "Reserved" 2 "Calibration" 1 "Normal AVM" 0 "Off";
VAL_ 697 CDCS9_ATMOS_MOD_Enable_Reserved 1 "ON" 0 "OFF";
VAL_ 697 CDCS9_Loud_Enable 1 "ON" 0 "OFF";
VAL_ 697 CDCS9_BT2_State 1 "connect" 0 "disconnect";
VAL_ 697 CDCS9_ATMOS_MOD_Type 4 "关闭天空音效" 3 "副驾私密模式（Private mode of Co-driver）" 2 "主驾私密模式_Driver Private mod" 1 "通用模式_Media Sky sound" 0 "驾享模式_Driver enjoyment mode";
VAL_ 697 CDCS9_AUD_EQ_Mode 6 "预留" 5 "预留" 4 "KTV模式" 3 "电影剧场" 2 "超重低音" 1 "纯净人声" 0 "HiFi音乐（默认）";
VAL_ 697 CDCS9_AUD_Gala_LEVEL 7 "预留" 6 "预留" 5 "预留" 4 "预留" 3 "HIGH" 2 "MID" 1 "LOW" 0 "OFF";
VAL_ 697 CDCS9_AUD_Location_Type 6 "预留" 5 "预留" 4 "预留" 3 "后排" 2 "全车" 1 "副驾" 0 "主驾（默认）";
VAL_ 757 CDCS2_DischargeObejectSelect 3 "Reserved" 2 "V2V" 1 "V2L" 0 "No request";
VAL_ 757 CDCS2_DischargeModeSelect 2 "三相设备" 1 "单相设备" 0 "No request";
VAL_ 757 CDCS2_ICUBacklightMode 3 "Reserved" 2 "manual 手动调节" 1 "auto 自动调节" 0 "No Request";
VAL_ 757 CDCS2_DischargeActiveSw 2 "Active" 1 "Inactive" 0 "No Request";
VAL_ 757 CDCS2_WPC_OnOffSw 3 "reserved" 2 "OFF" 1 "ON" 0 "No action";
VAL_ 757 CDCS2_ICUMod_CtrlReq 3 "reserved" 2 "瞬时电耗" 1 "平均电耗" 0 "No Request";
VAL_ 757 CDCS2_ICUDisplayMode 3 "OFF" 2 "Sample" 1 "Normal" 0 "No Request";
VAL_ 757 CDCS2_ICUTripmeter_Set 3 "reserved" 2 "清零" 1 "不清零" 0 "No Request";
VAL_ 757 CDCS2_PrivacyForbidLocReq 2 "Close" 1 "Open" 0 "Default";
VAL_ 757 CDCS2_SOClowerlimit 101 "No Action";
VAL_ 757 CDCS2_PrivacyForbidDataReq 2 "Close" 1 "Open" 0 "Default";
VAL_ 757 CDCS2_TimezoneSet 63 "Reserved" 62 "Reserved" 61 "Reserved" 60 "Reserved" 59 "Reserved" 58 "Reserved" 57 "Reserved" 56 "Reserved" 55 "Reserved" 54 "Reserved" 53 "Reserved" 52 "Reserved" 51 "Reserved" 50 "Reserved" 49 "Reserved" 48 "Reserved" 47 "Reserved" 46 "Reserved" 45 "Reserved" 44 "Reserved" 43 "Reserved" 42 "Reserved" 41 "Reserved" 40 "Reserved" 39 "Reserved" 38 "UTC+14（LINT — 莱恩群岛标准时间）" 37 "UTC+13（PHOT — 菲尼克斯群岛标准时间）+萨摩亚" 36 "UTC+12:45（CHAST — 查塔姆群岛标准时间）" 35 "UTC+12（NZST — 纽西兰标准时间）+斐济，纽西兰" 34 "UTC+11（VUT — 瓦努阿图标准时间）" 33 "UTC+10:30（LHST — 豪勋爵群岛标准时间）" 32 "UTC+10（AEST — 澳大利亚东部标准时间）+澳大利亚（昆士兰州、澳大利亚首都特区），巴布亚新几内亚" 31 "UTC+9:30（ACST — 澳大利亚中部标准时间）" 30 "UTC+9（JST — 日本标准时间）+东帝汶，印尼东部，日本" 29 "UTC+8:45 尤克拉" 28 "UTC+8（CT/CST — 中原标准时间）+文莱，中国香港，中国澳门，新加坡，马来西亚，印尼中部，澳大利亚 — 西澳大利亚-AWST — 澳大利亚西部标准时间" 27 "UTC+7（ICT — 中南半岛标准时间）+泰国，印尼西部" 26 "UTC+6:30（MMT — 缅甸标准时间）" 25 "UTC+6（BHT — 孟加拉标准时间）+孟加拉国，不丹" 24 "UTC+5:45（NPT — 尼泊尔标准时间）+尼泊尔" 23 "UTC+5:30（IST — 印度标准时间）+印度，斯里兰卡" 22 "UTC+5（PKT — 巴基斯坦标准时间）+马尔代夫，巴基斯坦" 21 "UTC+4:30（AFT — 阿富汗标准时间）" 20 "UTC+4（GST — 海湾标准时间）+毛里求斯，塞舌尔" 19 "UTC+3:30（IRST — 伊朗标准时间）" 18 "UTC+3（MSK — 莫斯科时区）+肯尼亚，坦桑尼亚，乌干达；" 17 "UTC+2（EET — 欧洲东部时区）+南非，博茨瓦纳，赞比亚，塞浦路斯，斯威士兰，莱索托，马拉维，莫桑比克，津巴布韦，纳米比亚9尼亚，坦桑尼亚，乌干达" 16 "UTC+1（CET — 欧洲中部时区）" 15 "UTC（WET — 欧洲西部时区，GMT - 格林尼治标准时间）+爱尔兰，英国" 14 "UTC-1（CVT — 佛得角标准时间）" 13 "UTC-2（FNT — 费尔南多迪诺罗尼亚群岛标准时间）" 12 "UTC-3（BRT — 巴西利亚标准时间）+巴哈马" 11 "UTC-3:30（NST — 纽芬兰岛标准时间）" 10 "UTC-4（AST — 大西洋标准时间）+安提瓜和巴布达，巴巴多斯，多米尼克，格林纳达，圭亚那，圣基茨和尼维斯， 圣文森特和格林纳丁斯，特立尼达和多巴哥，维尔京群岛" 9 "UTC-5（EST — 北美东部标准时间）+巴哈马，牙买加" 8 "UTC-6 （CST-北美中部标准时间）哥斯达黎加 尼加拉瓜，墨西哥，洪都拉斯，危地马拉，萨尔瓦多，伯利兹" 7 "UTC-7 （MST-山地时间） 育空，亚利桑那" 6 "UTC-8 （PST-太平洋标准时间 ）美国，加拿大，下加利福尼亚州" 5 "UTC-9 （AKST-阿拉斯加标准时间）" 4 "UTC-9:30 马克萨斯群岛" 3 "UTC-10（ HST-夏威夷，阿留申标准时间）" 2 "UTC-11 （SST-萨摩亚标准时间）" 1 "UTC-12 （贝克岛时间）" 0 "Invalid";
VAL_ 757 CDCS2_ICUBacklightLevel 10 "Level 10" 9 "Level 9" 8 "Level 8" 7 "Level 7" 6 "Level 6" 5 "Level 5" 4 "Level 4" 3 "Level 3" 2 "Level 2" 1 "Level 1" 0 "No Action";
VAL_ 757 CDCS2_AvgEnergySET 1 "清零" 0 "off";
VAL_ 757 CDCS2_UnlockElectronicLock 3 "Reserved" 2 "闭锁" 1 "解锁" 0 "No request";
VAL_ 757 CDCS2_DischargeMainSw 2 "On" 1 "Off" 0 "No Request";
VAL_ 757 CDCS2_ChgConKpTemp 2 "On" 1 "Off" 0 "No Request";
VAL_ 789 CDCS1_AC_SW 3 "Reserve" 2 "OFF" 1 "ON" 0 "No Action";
VAL_ 789 CDCS1_CLM_CycleSw 3 "AutoCycle" 2 "Fresh" 1 "Recirculation" 0 "No Action";
VAL_ 789 CDCS1_CLM_BlowerSpdPlus 3 "Reserve" 2 "Reserve" 1 "Press" 0 "No press";
VAL_ 789 CDCS1_CLM_AutoSw 3 "Reserve" 2 "OFF" 1 "ON" 0 "No Action";
VAL_ 789 CDCS1_CLM_LHTempPlus 1 "press" 0 "no press";
VAL_ 789 CDCS1_CLM_LHTempMinus 1 "press" 0 "no press";
VAL_ 789 CDCS1_CLM_RHTempPlus 1 "press" 0 "no press";
VAL_ 789 CDCS1_CLM_RHTempMinus 1 "press" 0 "no press";
VAL_ 789 CDCS1_CLM_FootSw 3 "Reserve" 2 "OFF" 1 "ON" 0 "No Action";
VAL_ 789 CDCS1_CLM_AnionSw 3 "Reserve" 2 "OFF" 1 "ON" 0 "No Action";
VAL_ 789 CDCS1_CLM_BlowerSpdSet 15 "Invalid" 14 "AUTO" 8 "Level 7" 7 "Level 6" 6 "Level 5" 5 "Level 4" 4 "Level 3" 3 "Level 2" 2 "Level 1" 1 "Level 0" 0 "No Request";
VAL_ 789 CDCS1_CLM_AcFilterResetReq 1 "Request" 0 "NoRequest";
VAL_ 789 CDCS1_CLM_BlowerSpdSetValid 1 "Valid" 0 "Invalid";
VAL_ 789 CDCS1_CLM_LHTempSetValid 1 "Valid" 0 "Invalid";
VAL_ 789 CDCS1_CLM_RHTempSetValid 1 "Valid" 0 "Invalid";
VAL_ 789 CDCS1_CLM_LHTempSet 63 "No Action" 62 "Invalid" 33 "High" 32 "31.5℃" 31 "31℃" 30 "30.5℃" 29 "30℃" 28 "29.5℃" 27 "29℃" 26 "28.5℃" 25 "28℃" 24 "27.5℃" 23 "27℃" 22 "26.5℃" 21 "26℃" 20 "25.5℃" 19 "25℃" 18 "24.5℃" 17 "24℃" 16 "23.5℃" 15 "23℃" 14 "22.5℃" 13 "22℃" 12 "21.5℃" 11 "21℃" 10 "20.5℃" 9 "20℃" 8 "19.5℃" 7 "19℃" 6 "18.5℃" 5 "18℃" 4 "17.5℃" 3 "17℃" 2 "16.5℃" 1 "Low" 0 "Inactive";
VAL_ 789 CDCS1_CLM_DualSw 3 "Reserve" 2 "OFF" 1 "ON" 0 "No Action";
VAL_ 789 CDCS1_CLM_RHTempSet 63 "No Action" 62 "Invalid" 33 "High" 32 "31.5℃" 31 "31℃" 30 "30.5℃" 29 "30℃" 28 "29.5℃" 27 "29℃" 26 "28.5℃" 25 "28℃" 24 "27.5℃" 23 "27℃" 22 "26.5℃" 21 "26℃" 20 "25.5℃" 19 "25℃" 18 "24.5℃" 17 "24℃" 16 "23.5℃" 15 "23℃" 14 "22.5℃" 13 "22℃" 12 "21.5℃" 11 "21℃" 10 "20.5℃" 9 "20℃" 8 "19.5℃" 7 "19℃" 6 "18.5℃" 5 "18℃" 4 "17.5℃" 3 "17℃" 2 "16.5℃" 1 "Low" 0 "Inactive";
VAL_ 789 CDCS1_BDCS_RearDefrostSw 3 "Reserve" 2 "OFF" 1 "ON" 0 "No Action";
VAL_ 789 CDCS1_CLM_OnoffSw 3 "Reserve" 2 "OFF" 1 "ON" 0 "No Action";
VAL_ 789 CDCS1_CLM_BlowerSpdMinus 3 "Reserve" 2 "Reserve" 1 "Press" 0 "No press";
VAL_ 789 CDCS1_CLM_WindowSw 3 "Reserve" 2 "OFF" 1 "ON" 0 "No Action";
VAL_ 789 CDCS1_CLM_VentSw 3 "Reserve" 2 "OFF" 1 "ON" 0 "No Action";
VAL_ 789 CDCS1_ACMaxSW 3 "Reserve" 2 "OFF" 1 "ON" 0 "No Action";
VAL_ 789 CDCS1_AirClean 3 "Reserve" 2 "OFF" 1 "ON" 0 "No Action";
VAL_ 789 CDCS1_AC_ECONMode 3 "Reserve" 2 "OFF" 1 "ON" 0 "No Action";
VAL_ 789 CDCS1_LEAOSts 5 "自动扫风" 4 "镜像模式" 3 "避人模式" 2 "脸部清爽" 1 "手动模式" 0 "No action";
VAL_ 789 CDCS1_REAOSts 5 "自动扫风" 4 "镜像模式" 3 "避人模式" 2 "脸部清爽" 1 "手动模式" 0 "No action";
VAL_ 789 CDCS1_AC_Ventilation 3 "Reserved" 2 "OFF" 1 "ON" 0 "No Action";
VAL_ 790 CDCS6_FridgeMod_Req 3 "保温" 2 "冷藏" 1 "关闭" 0 "No action";
VAL_ 790 CDCS6_FridgeTemp_KeepReq 3 "Reserved" 2 "Open" 1 "Close" 0 "No action";
VAL_ 790 CDCS6_FridgeCool_Temp_Req 15 "Reserved" 14 "Reserved" 13 "6℃" 12 "5℃" 11 "4℃" 10 "3℃" 9 "2℃" 8 "1℃" 7 "0℃" 6 "-1℃" 5 "-2℃" 4 "-3℃" 3 "-4℃" 2 "-5℃" 1 "-6℃" 0 "No action";
VAL_ 790 CDCS6_FridgeTemp_Plus 1 "Press" 0 "No Press";
VAL_ 790 CDCS6_FridgeTemp_Minus 1 "Press" 0 "No Press";
VAL_ 790 CDCS6_FridgeHeat_Temp_Req 31 "Reserved" 30 "Reserved" 29 "Reserved" 28 "Reserved" 27 "Reserved" 26 "Reserved" 25 "Reserved" 24 "Reserved" 23 "Reserved" 22 "Reserved" 21 "Reserved" 20 "Reserved" 19 "Reserved" 18 "Reserved" 17 "Reserved" 16 "50℃" 15 "49℃" 14 "48℃" 13 "47℃" 12 "46℃" 11 "45℃" 10 "44℃" 9 "43℃" 8 "42℃" 7 "41℃" 6 "40℃" 5 "39℃" 4 "38℃" 3 "37℃" 2 "36℃" 1 "35℃" 0 "No action";
VAL_ 790 CDCS6_OilHeatingSw 3 "Reserved" 2 "OFF" 1 "ON" 0 "No Action";
VAL_ 896 CDCS8_VoiceTrunkCtrl 3 "Reserved" 2 "Close" 1 "Open" 0 "No request";
VAL_ 896 CDCS8_TrunkSWReq 3 "Reserved" 2 "Close" 1 "Open" 0 "No Action";
VAL_ 896 CDCS8_RearDoorHeightSet 3 "High" 2 "Middle" 1 "Low" 0 "No request";
VAL_ 896 CDCS8_FRSeatEZEReq 3 "Reserve" 2 "OFF" 1 "ON" 0 "No Action";
VAL_ 896 CDCS8_FLSeatEZEReq 3 "Reserve" 2 "OFF" 1 "ON" 0 "No Action";
VAL_ 896 CDCS8_SOC_LampSwt 3 "Reserved" 2 "OFF" 1 "ON" 0 "No Action";
VAL_ 896 CDCS8_FLLumbarUpAndDownAdj 3 "reserrved" 2 "Down" 1 "Up" 0 "No request";
VAL_ 896 CDCS8_FLLumbaForwardorBackwardAdj 3 "reserrved" 2 "Backward" 1 "Forward" 0 "No request";
VAL_ 896 CDCS8_ALH_TemperatureSW 3 "Reserved" 2 "OFF" 1 "ON" 0 "No Action";
VAL_ 896 CDCS8_FRLumbarUpAndDownAdj 3 "reserrved" 2 "Down" 1 "Up" 0 "No request";
VAL_ 896 CDCS8_FRLumbaForwardorBackwardAdj 3 "reserrved" 2 "Backward" 1 "Forward" 0 "No request";
VAL_ 896 CDCS8_IncomingCall 3 "Reserved" 2 "No Incoming call" 1 "Incoming call" 0 "No Action";
VAL_ 896 CDCS8_FrontSeatAutoEZEReq 3 "Reserve" 2 "OFF" 1 "ON" 0 "No Action";
VAL_ 896 CDCS8_FRSeatHeatCmd 4 "High" 3 "Middle" 2 "Low" 1 "OFF" 0 "No Request";
VAL_ 896 CDCS8_FLSeatHeatCmd 4 "High" 3 "Middle" 2 "Low" 1 "OFF" 0 "No Request";
VAL_ 896 CDCS8_FLSeatVentCmd 4 "High" 3 "Middle" 2 "Low" 1 "OFF" 0 "No Request";
VAL_ 896 CDCS8_FRSeatVentCmd 4 "High" 3 "Middle" 2 "Low" 1 "OFF" 0 "No Request";
VAL_ 805 ICU2_OdometerUpdate 1 "Active" 0 "Inactive";
VAL_ 489 CDCS21_NavSpeedLimitStatus 3 "unknown;导航挂了，无gps定位或者无地图覆盖，而不是功能故障，不需要报导航故障" 2 "Active;导航状态良好，识别到有效限速" 1 "Inactive;导航状态良好，未识别到有效限速" 0 "Fault;导航故障，且导航发出的目标限定车速信息不可信";
VAL_ 489 CDCS21_Nav_CountryID 255 "Invalid无效" 254 "Reserved" 253 "Reserved" 252 "Reserved" 251 "Reserved" 250 "Reserved" 249 "Reserved" 248 "Reserved" 247 "Reserved" 246 "Reserved" 245 "Reserved" 244 "Reserved" 243 "Reserved" 242 "Reserved" 241 "Reserved" 240 "Reserved" 239 "Reserved" 238 "Reserved" 237 "Reserved" 236 "Reserved" 235 "Reserved" 234 "Reserved" 233 "Reserved" 232 "Reserved" 231 "Reserved" 230 "Reserved" 229 "Reserved" 228 "Reserved" 227 "Reserved" 226 "Reserved" 225 "Reserved" 224 "Reserved" 223 "Reserved" 222 "Reserved" 221 "Reserved" 220 "Reserved" 219 "Reserved" 218 "Reserved" 217 "Reserved" 216 "Reserved" 215 "Reserved" 214 "Reserved" 213 "Reserved" 212 "Reserved" 211 "Reserved" 210 "Reserved" 209 "Reserved" 208 "Reserved" 207 "Reserved" 206 "Reserved" 205 "Reserved" 204 "Reserved" 203 "Reserved" 202 "Reserved" 201 "Reserved" 200 "Reserved" 199 "Reserved" 198 "Reserved" 197 "Reserved" 196 "Reserved" 195 "Reserved" 194 "Reserved" 193 "Reserved" 192 "Reserved" 191 "Reserved" 190 "Reserved" 189 "Reserved" 188 "Reserved" 187 "Reserved" 186 "Reserved" 185 "Reserved" 184 "Reserved" 183 "Reserved" 182 "Reserved" 181 "Reserved" 180 "Reserved" 179 "Reserved" 178 "Reserved" 177 "Reserved" 176 "Reserved" 175 "Reserved" 174 "Reserved" 173 "Reserved" 172 "Reserved" 171 "Reserved" 170 "Reserved" 169 "Reserved" 168 "Reserved" 167 "Reserved" 166 "Reserved" 165 "Reserved" 164 "Reserved" 163 "Reserved" 162 "Reserved" 161 "Reserved" 160 "Reserved" 159 "Reserved" 158 "Reserved" 157 "Reserved" 156 "Reserved" 155 "Reserved" 154 "Reserved" 153 "Reserved" 152 "Reserved" 151 "Reserved" 150 "Reserved" 149 "Reserved" 148 "Reserved" 147 "Reserved" 146 "Reserved" 145 "Reserved" 144 "Reserved" 143 "Reserved" 142 "Reserved" 141 "Reserved" 140 "Reserved" 139 "Reserved" 138 "Reserved" 137 "Reserved" 136 "Reserved" 135 "Reserved" 134 "Reserved" 133 "Reserved" 132 "Reserved" 131 "Reserved" 130 "Reserved" 129 "Reserved" 128 "Reserved" 127 "Reserved" 126 "Reserved" 125 "Reserved" 124 "Reserved" 123 "Reserved" 122 "Reserved" 121 "Reserved" 120 "Reserved" 119 "Reserved" 118 "Reserved" 117 "Reserved" 116 "Reserved" 115 "Reserved" 114 "Reserved" 113 "Reserved" 112 "Reserved" 111 "Reserved" 110 "Reserved" 109 "Reserved" 108 "Reserved" 107 "Reserved" 106 "Reserved" 105 "Reserved" 104 "Reserved" 103 "Reserved" 102 "Reserved" 101 "Reserved" 100 "Reserved" 99 "Reserved" 98 "Reserved" 97 "Reserved" 96 "Reserved" 95 "Reserved" 94 "Reserved" 93 "Reserved" 92 "Reserved" 91 "Reserved" 90 "Reserved" 89 "Reserved" 88 "Reserved" 87 "Reserved" 86 "Reserved" 85 "Reserved" 84 "Reserved" 83 "Reserved" 82 "Reserved" 81 "Reserved" 80 "Reserved" 79 "Reserved" 78 "Reserved" 77 "Reserved" 76 "Reserved" 75 "Reserved" 74 "Reserved" 73 "Reserved" 72 "Reserved" 71 "Reserved" 70 "Reserved" 69 "Reserved" 68 "Reserved" 67 "Reserved" 66 "Reserved" 65 "Reserved" 64 "Reserved" 63 "Reserved" 61 "摩洛哥" 60 "埃及" 59 "厄瓜多尔" 58 "哥斯达黎加" 57 "智利" 56 "巴西" 55 "约旦" 54 "沙特阿拉伯" 53 "老挝" 52 "缅甸" 51 "菲律宾" 50 "越南" 49 "土耳其（Turkey）" 48 "以色列（Israel）" 47 "英国（UnitedKingdom）" 46 "挪威（Norway）" 45 "冰岛（Iceland）" 44 "瑞士（Switzerland）" 43 "列支敦士登（Liechtenstein）" 42 "瑞典（Sweden）" 41 "西班牙（Spain）" 40 "斯洛文尼亚（Slovenia）" 39 "斯洛伐克（Slovakia）" 38 "罗马尼亚（Romania）" 37 "葡萄牙（Portugal）" 36 "波兰（Poland）" 35 "荷兰（Netherlands）" 34 "马耳他（Malta）" 33 "卢森堡（Luxembourg）" 32 "立陶宛（Lithuania）" 31 "拉脱维亚（Latvia）" 30 "意大利（Italy）" 29 "爱尔兰（Ireland）" 28 "匈牙利（Hungary）" 27 "希腊（Greece）" 26 "德国（Germany）" 16 "法国（France）" 9 "芬兰（Finland）" 8 "爱沙尼亚（Estonia）" 7 "丹麦（Denmark）" 6 "捷克（Czechia）" 5 "克罗地亚（Croatia）" 4 "塞浦路斯（Cyprus）" 3 "保加利亚（Bulgaria）" 2 "比利时（Belgium）" 1 "奥地利（Austria）" 0 "NotUsed";
VAL_ 489 CDCS21_Nav_SpeedLimitUnits 3 "Reserved" 2 "KMH" 1 "MPH" 0 "Unknown";
VAL_ 489 CDCS21_Nav_CurrRoadType 3 "Interurban 非城市" 2 "Urban 城市" 1 "Highway 高速" 0 "Unknown";
VAL_ 489 CDCS21_NavSpeedlimit 63 "Reserved" 62 "Reserved" 61 "Reserved" 60 "Reserved" 59 "Reserved" 58 "Reserved" 57 "Reserved" 56 "Reserved" 55 "Reserved" 54 "Reserved" 53 "Reserved" 52 "Reserved" 51 "Reserved" 50 "Reserved" 49 "Reserved" 48 "Reserved" 47 "Reserved" 46 "Reserved" 45 "Reserved" 44 "Reserved" 43 "Reserved" 42 "Reserved" 41 "Reserved" 40 "Reserved" 39 "Reserved" 38 "无限速要求区域" 37 "超过限速180" 36 "SPL 180" 35 "SPL 175" 34 "SPL 170" 33 "SPL 165" 32 "SPL 160" 31 "SPL 155" 30 "SPL 150" 29 "SPL 145" 28 "SPL 140" 27 "SPL 135" 26 "SPL 130" 25 "SPL 125" 24 "SPL 120" 23 "SPL 115" 22 "SPL 110" 21 "SPL 105" 20 "SPL 100" 19 "SPL 95" 18 "SPL 90" 17 "SPL 85" 16 "SPL 80" 15 "SPL 75" 14 "SPL 70" 13 "SPL 65" 12 "SPL 60" 11 "SPL 55" 10 "SPL 50" 9 "SPL 45" 8 "SPL 40" 7 "SPL 35" 6 "SPL 30" 5 "SPL 25" 4 "SPL 20" 3 "SPL 15" 2 "SPL 10" 1 "SPL 5" 0 "No Display";
VAL_ 489 CDCS21_NavSpeedlimit_Rain 63 "Reserved" 62 "Reserved" 61 "Reserved" 60 "Reserved" 59 "Reserved" 58 "Reserved" 57 "Reserved" 56 "Reserved" 55 "Reserved" 54 "Reserved" 53 "Reserved" 52 "Reserved" 51 "Reserved" 50 "Reserved" 49 "Reserved" 48 "Reserved" 47 "Reserved" 46 "Reserved" 45 "Reserved" 44 "Reserved" 43 "Reserved" 42 "Reserved" 41 "Reserved" 40 "Reserved" 39 "Reserved" 38 "无限速要求区域" 37 "超过限速180" 36 "SPL 180" 35 "SPL 175" 34 "SPL 170" 33 "SPL 165" 32 "SPL 160" 31 "SPL 155" 30 "SPL 150" 29 "SPL 145" 28 "SPL 140" 27 "SPL 135" 26 "SPL 130" 25 "SPL 125" 24 "SPL 120" 23 "SPL 115" 22 "SPL 110" 21 "SPL 105" 20 "SPL 100" 19 "SPL 95" 18 "SPL 90" 17 "SPL 85" 16 "SPL 80" 15 "SPL 75" 14 "SPL 70" 13 "SPL 65" 12 "SPL 60" 11 "SPL 55" 10 "SPL 50" 9 "SPL 45" 8 "SPL 40" 7 "SPL 35" 6 "SPL 30" 5 "SPL 25" 4 "SPL 20" 3 "SPL 15" 2 "SPL 10" 1 "SPL 5" 0 "无雨条件限速";
VAL_ 489 CDCS21_NavSpeedlimit_Snow 63 "Reserved" 62 "Reserved" 61 "Reserved" 60 "Reserved" 59 "Reserved" 58 "Reserved" 57 "Reserved" 56 "Reserved" 55 "Reserved" 54 "Reserved" 53 "Reserved" 52 "Reserved" 51 "Reserved" 50 "Reserved" 49 "Reserved" 48 "Reserved" 47 "Reserved" 46 "Reserved" 45 "Reserved" 44 "Reserved" 43 "Reserved" 42 "Reserved" 41 "Reserved" 40 "Reserved" 39 "Reserved" 38 "无限速要求区域" 37 "超过限速180" 36 "SPL 180" 35 "SPL 175" 34 "SPL 170" 33 "SPL 165" 32 "SPL 160" 31 "SPL 155" 30 "SPL 150" 29 "SPL 145" 28 "SPL 140" 27 "SPL 135" 26 "SPL 130" 25 "SPL 125" 24 "SPL 120" 23 "SPL 115" 22 "SPL 110" 21 "SPL 105" 20 "SPL 100" 19 "SPL 95" 18 "SPL 90" 17 "SPL 85" 16 "SPL 80" 15 "SPL 75" 14 "SPL 70" 13 "SPL 65" 12 "SPL 60" 11 "SPL 55" 10 "SPL 50" 9 "SPL 45" 8 "SPL 40" 7 "SPL 35" 6 "SPL 30" 5 "SPL 25" 4 "SPL 20" 3 "SPL 15" 2 "SPL 10" 1 "SPL 5" 0 "无雪条件限速";
VAL_ 489 CDCS21_NavSpeedlimit_fog 63 "Reserved" 62 "Reserved" 61 "Reserved" 60 "Reserved" 59 "Reserved" 58 "Reserved" 57 "Reserved" 56 "Reserved" 55 "Reserved" 54 "Reserved" 53 "Reserved" 52 "Reserved" 51 "Reserved" 50 "Reserved" 49 "Reserved" 48 "Reserved" 47 "Reserved" 46 "Reserved" 45 "Reserved" 44 "Reserved" 43 "Reserved" 42 "Reserved" 41 "Reserved" 40 "Reserved" 39 "Reserved" 38 "无限速要求区域" 37 "超过限速180" 36 "SPL 180" 35 "SPL 175" 34 "SPL 170" 33 "SPL 165" 32 "SPL 160" 31 "SPL 155" 30 "SPL 150" 29 "SPL 145" 28 "SPL 140" 27 "SPL 135" 26 "SPL 130" 25 "SPL 125" 24 "SPL 120" 23 "SPL 115" 22 "SPL 110" 21 "SPL 105" 20 "SPL 100" 19 "SPL 95" 18 "SPL 90" 17 "SPL 85" 16 "SPL 80" 15 "SPL 75" 14 "SPL 70" 13 "SPL 65" 12 "SPL 60" 11 "SPL 55" 10 "SPL 50" 9 "SPL 45" 8 "SPL 40" 7 "SPL 35" 6 "SPL 30" 5 "SPL 25" 4 "SPL 20" 3 "SPL 15" 2 "SPL 10" 1 "SPL 5" 0 "无雾条件限速";
VAL_ 489 CDCS21_NavSpeedlimitSign_Distance 8191 "invalid";
VAL_ 1424 HU_MCUPowerState 7 "Reserved" 6 "Reserved" 5 "Normal(OTA)" 4 "STR mode(SOC+MCU sleep)" 3 "STR mode(SOC sleep)" 2 "Standby mode" 1 "Normal(remote)" 0 "Normal Mode";
VAL_ 1424 HU_SOCResetType 13 "SOC冷启动 (硬线心跳超时复位）" 12 "SOC冷启动（过高低压紧急保护复位）" 11 "SOC热启动（APP SPI下发0x5502复位）" 10 "SOC热启动（SOC持续时间超设定复位）" 9 "SOC冷启动（诊断复位）" 8 "SOC冷启动（屏幕按键复位）" 7 "SOC冷启动（SPI握手超时SOC复位）" 6 "SOC冷启动（SPI通讯超时SOC复位）" 5 "SOC热启动（SOC正常休眠唤醒）" 4 "SOC冷启动（方控按键复位）" 3 "SOC冷启动（APP SPI下发0x5502复位）" 2 "SOC冷启动（休眠25秒超时SOC强制下电）" 1 "SOC冷启动（Keypad 3次唤不醒SOC复位）" 0 "SOC冷启动（SOC正常断电上电）";
VAL_ 1424 HU_BDM_PowerMode 3 "Crank" 2 "ON" 1 "ACC（Reserved）" 0 "OFF";
VAL_ 1424 HU_SOCWatchdog 1 "SOC Watchdog Normal" 0 "SOC Watchdog Fail";
VAL_ 1424 HU_HardIGNState 1 "Hard IGNOn" 0 "Hard IGNOff";
VAL_ 1424 HU_SPIConnectState 1 "SPI Connect" 0 "SPI Not Connect";
VAL_ 1544 CDCS_RepeatMessageRequest 1 "Repeat message request" 0 "No repeat message request";
VAL_ 1544 CDCS_ActiveWakeup 1 "Wakeup" 0 "No wakeup";
VAL_ 1544 CDCS_WakeUp_KL15 1 "KL15 ON Wakeup" 0 "No Request";
VAL_ 1544 CDCS_WakeUp_NM 1 "NM Wakeup" 0 "No Request";
VAL_ 1544 CDCS_RepeatFromSleep 1 "occur" 0 "not occur";
VAL_ 1544 CDCS_RepeatFromPrepare 1 "occur" 0 "not occur";
VAL_ 1544 CDCS_NormalFromRepeat 1 "occur" 0 "not occur";
VAL_ 1544 CDCS_NormalFromReady 1 "occur" 0 "not occur";
VAL_ 1544 CDCS_RepeatFromReady 1 "occur" 0 "not occur";
VAL_ 1544 CDCS_RepeatFromNormal 1 "occur" 0 "not occur";
VAL_ 1544 CDCS_RemainNetworkWakeUpReason1 1 "Remain wakeup reason" 0 "default";
VAL_ 1544 CDCS_RemainNetworkWakeUpReason2 1 "Remain wakeup reason" 0 "default";
VAL_ 1544 CDCS_RemainNetworkWakeUpReason3 1 "Remain wakeup reason" 0 "default";
VAL_ 1544 CDCS_RemainNetworkWakeUpReason4 1 "Remain wakeup reason" 0 "default";
VAL_ 1440 CDCS_RouteInfoTipsNum1 12 "routine6 info b" 11 "routine6 info a" 10 "routine5 info b" 9 "routine5 info a" 8 "routine4 info b" 7 "routine4 info a" 6 "routine3 info b" 5 "routine3 info a" 4 "routine2 info b" 3 "routine2 info a" 2 "routine1 info b" 1 "routine1 info a" 0 "default";
VAL_ 1441 CDCS_RouInfoTipsNum2 6 "routine6 info c" 5 "routine5 info c" 4 "routine4 info c" 3 "routine3 info c" 2 "routine2 info c" 1 "routine1 info c" 0 "default";
VAL_ 1442 CDCS_RouInfoTipsNum3 6 "routine6 info d" 5 "routine5 info d" 4 "routine4 info d" 3 "routine3 info d" 2 "routine2 info d" 1 "routine1 info d" 0 "default";
VAL_ 305 ICU1_VehicleSpdDisplayValid 1 "Valid" 0 "Invalid";
VAL_ 305 ICU1_VehicleSpdDisplayUnit 1 "mph" 0 "kph";
VAL_ 305 ICU1_DisplayModeSts 3 "OFF" 2 "Sample" 1 "Normal" 0 "No Request";
VAL_ 305 ICU1_PrkgBrkSysSts 1 "On（电子手刹拉起）" 0 "Off(电子手刹未拉起)";
VAL_ 305 ICU1_BrakeFluidLow 1 "Low" 0 "Normal";
VAL_ 305 ICU1_SelfCheck_Sts 1 "自检状态" 0 "非自检状态";
VAL_ 305 ICU1_ICUBacklightMode 3 "Reserved" 2 "manual 手动调节" 1 "auto 自动调节" 0 "no active";
VAL_ 758 ICU3_IHU_brightness_fdbk 10 "Level10" 9 "Level9" 8 "Level8" 7 "Level7" 6 "Level6" 5 "Level5" 4 "Level4" 3 "Level3" 2 "Level2" 1 "Level1" 0 "invalid";
VAL_ 1601 ICU_RepeatMessageRequest 1 "Repeat message request" 0 "No repeat message request";
VAL_ 1601 ICU_ActiveWakeup 1 "Wakeup" 0 "No wakeup";
VAL_ 1601 ICU_WakeUpReason1 1 "Wakeup Requrst" 0 "No Request";
VAL_ 1601 ICU_WakeUp_Rx_NM 1 "NM Wakeup" 0 "No Request";
VAL_ 1601 ICU_WakeUpReason3 1 "Wakeup Requrst" 0 "No Request";
VAL_ 1601 ICU_WakeUpReason4 1 "Wakeup Requrst" 0 "No Request";
VAL_ 1601 ICU_WakeUpReason5 1 "Wakeup Requrst" 0 "No Request";
VAL_ 1601 ICU_WakeUpReason6 1 "Wakeup Requrst" 0 "No Request";
VAL_ 1601 ICU_WakeUpReason7 1 "Wakeup Requrst" 0 "No Request";
VAL_ 1601 ICU_WakeUpReason8 1 "Wakeup Requrst" 0 "No Request";
VAL_ 1601 ICU_RepeatFromSleep 1 "occur" 0 "not occur";
VAL_ 1601 ICU_RepeatFromPrepare 1 "occur" 0 "not occur";
VAL_ 1601 ICU_NormalFromRepeat 1 "occur" 0 "not occur";
VAL_ 1601 ICU_NormalFromReady 1 "occur" 0 "not occur";
VAL_ 1601 ICU_RepeatFromReady 1 "occur" 0 "not occur";
VAL_ 1601 ICU_RepeatFromNormal 1 "occur" 0 "not occur";
VAL_ 1601 ICU_RemainNetworkWakeUpReason1 1 "Remain wakeup reason" 0 "default";
VAL_ 1601 ICU_RemainNetworkWakeUpReason2 1 "Remain wakeup reason" 0 "default";
VAL_ 1601 ICU_RemainNetworkWakeUpReason3 1 "Remain wakeup reason" 0 "default";
VAL_ 1601 ICU_RemainNetworkWakeUpReason4 1 "Remain wakeup reason" 0 "default";
VAL_ 516 WPC1_MobPhneFgtRmdr 1 "Reminder Active" 0 "Reminder Not Active";
VAL_ 516 WPC1_Status 15 "Resved6" 14 "Resved5" 13 "Resved4" 12 "Resved3" 11 "Resved2" 10 "充满提醒（手机有充满提醒功能，无线充才会反馈）" 9 "其他错误（一般为接收端错误）" 8 "寻找钥匙中，无线充电功能中断" 7 "Over Temperature Protected(过温保护)" 6 "Overpower Protected(功率保护)" 5 "欠压保护" 4 "过压保护" 3 "FOD(检测到异物)" 2 "Charging(充电中)" 1 "Standby(待机状态)" 0 "Resved1";
VAL_ 516 WPC1_SwFeedback 1 "ON(充电功能开启)" 0 "OFF(充电功能关闭)";
VAL_ 1606 WPC_RepeatMessageRequest 1 "Repeat message request" 0 "No repeat message request";
VAL_ 1606 WPC_ActiveWakeup 1 "Wakeup" 0 "No wakeup";
VAL_ 1606 WPC_WakeUp_KL15 1 "KL15 ON Wakeup" 0 "No Request";
VAL_ 1606 WPC_WakeUp_NM 1 "NM Wakeup" 0 "No Request";
VAL_ 1606 WPC_RepeatFromSleep 1 "occur" 0 "not occur";
VAL_ 1606 WPC_RepeatFromPrepare 1 "occur" 0 "not occur";
VAL_ 1606 WPC_NormalFromRepeat 1 "occur" 0 "not occur";
VAL_ 1606 WPC_NormalFromReady 1 "occur" 0 "not occur";
VAL_ 1606 WPC_RepeatFromReady 1 "occur" 0 "not occur";
VAL_ 1606 WPC_RepeatFromNormal 1 "occur" 0 "not occur";
VAL_ 1606 WPC_RemainNetworkWakeUpReason1 1 "Remain wakeup reason" 0 "default";
VAL_ 1606 WPC_RemainNetworkWakeUpReason2 1 "Remain wakeup reason" 0 "default";
VAL_ 1606 WPC_RemainNetworkWakeUpReason3 1 "Remain wakeup reason" 0 "default";
VAL_ 1606 WPC_RemainNetworkWakeUpReason4 1 "Remain wakeup reason" 0 "default";
VAL_ 502 AMP1_ATMOS_MOD_STATUS_Reserved 3 "Reserve2" 2 "Reserve1" 1 "ON" 0 "OFF";
VAL_ 502 AMP1_Loud_STATUS 2 "Disable" 1 "Enable" 0 "No Action";
VAL_ 502 AMP1_SYS_RUN_STATUS 3 "预留" 2 "Error" 1 "Ready" 0 "NotReady";
VAL_ 502 AMP1_SPK1_DAIG_STATUS 2 "开路" 1 "短路" 0 "正常";
VAL_ 502 AMP1_SPK2_DAIG_STATUS 2 "开路" 1 "短路" 0 "正常";
VAL_ 502 AMP1_SPK3_DAIG_STATUS 2 "开路" 1 "短路" 0 "正常";
VAL_ 502 AMP1_ATMOS_MOD_Value 4 "关闭天空音效" 3 "副驾私密模式（Private mode of Co-driver）" 2 "主驾私密模式（Driver Private mod）" 1 "通用模式（Media Sky sound）" 0 "驾享模式（Driver enjoyment mode）";
VAL_ 502 AMP1_SPK4_DAIG_STATUS 2 "开路" 1 "短路" 0 "正常";
VAL_ 502 AMP1_SPK5_DAIG_STATUS 2 "开路" 1 "短路" 0 "正常";
VAL_ 502 AMP1_AUD_EQ_Value 6 "预留" 5 "预留" 4 "KTV模式" 3 "电影剧场" 2 "超重低音" 1 "纯净人声" 0 "HiFi音乐（默认）";
VAL_ 502 AMP1_SPK6_DAIG_STATUS 2 "开路" 1 "短路" 0 "正常";
VAL_ 502 AMP1_SPK7_DAIG_STATUS 2 "开路" 1 "短路" 0 "正常";
VAL_ 502 AMP1_BT2_State_Value 1 "connect" 0 "disconnect";
VAL_ 502 AMP1_AUD_Gala_Value 7 "预留" 6 "预留" 5 "预留" 4 "预留" 3 "HIGH" 2 "MID" 1 "LOW" 0 "OFF";
VAL_ 502 AMP1_SPK8_DAIG_STATUS 2 "开路" 1 "短路" 0 "正常";
VAL_ 502 AMP1_SPK9_DAIG_STATUS 2 "开路" 1 "短路" 0 "正常";
VAL_ 502 AMP1_AUD_Location_Value 6 "预留" 5 "预留" 4 "预留" 3 "后排" 2 "全车" 1 "副驾" 0 "主驾（默认）";
VAL_ 502 AMP1_SPK10_DAIG_STATUS 2 "开路" 1 "短路" 0 "正常";
VAL_ 502 AMP1_SPK11_DAIG_STATUS 2 "开路" 1 "短路" 0 "正常";
VAL_ 502 AMP1_SPK12_DAIG_STATUS 2 "开路" 1 "短路" 0 "正常";
VAL_ 502 AMP1_DSP_RUN_STATUS 3 "Reserved" 2 "Error" 1 "Ready" 0 "NotReady";
VAL_ 502 AMP1_SPK13_DAIG_STATUS 2 "开路" 1 "短路" 0 "正常";
VAL_ 502 AMP1_SPK14_DAIG_STATUS 2 "开路" 1 "短路" 0 "正常";
VAL_ 502 AMP1_SPK15_DAIG_STATUS 2 "开路" 1 "短路" 0 "正常";
VAL_ 502 AMP1_A2B_RUN_STATUS 3 "Reserved" 2 "Error" 1 "Ready" 0 "NotReady";
VAL_ 502 AMP1_SPK16_DAIG_STATUS 2 "开路" 1 "短路" 0 "正常";
VAL_ 502 AMP1_AMPLIFIER_RUN_STATUS 3 "Reserved" 2 "Error" 1 "Ready" 0 "NotReady";
VAL_ 503 APM2_Slot0_Valid 1 "Valid" 0 "Invalid";
VAL_ 503 APM2_Slot0_VolumeValue 31 "Reserved";
VAL_ 503 AMP2_A2B_Slot0_Value 1 "有音频输入" 0 "无音频输入";
VAL_ 503 AMP2_A2B_Slot1_Value 1 "有音频输入" 0 "无音频输入";
VAL_ 503 APM2_Slot1_Valid 1 "Valid" 0 "Invalid";
VAL_ 503 APM2_Slot1_VolumeValue 31 "Reserved";
VAL_ 503 AMP2_A2B_Slot2_Value 1 "有音频输入" 0 "无音频输入";
VAL_ 503 AMP2_A2B_Slot3_Value 1 "有音频输入" 0 "无音频输入";
VAL_ 503 APM2_Slot2_Valid 1 "Valid" 0 "Invalid";
VAL_ 503 APM2_Slot2_VolumeValue 31 "Reserved";
VAL_ 503 AMP2_A2B_Slot4_Value 1 "有音频输入" 0 "无音频输入";
VAL_ 503 AMP2_A2B_Slot5_Value 1 "有音频输入" 0 "无音频输入";
VAL_ 503 APM2_Slot3_Valid 1 "Valid" 0 "Invalid";
VAL_ 503 APM2_Slot3_VolumeValue 31 "Reserved";
VAL_ 503 AMP2_A2B_Slot6_Value 1 "有音频输入" 0 "无音频输入";
VAL_ 503 AMP2_A2B_Slot7_Value 1 "有音频输入" 0 "无音频输入";
VAL_ 503 APM2_Slot4_Valid 1 "Valid" 0 "Invalid";
VAL_ 503 APM2_Slot4_VolumeValue 31 "Reserved";
VAL_ 503 APM2_Slot5_Valid 1 "Valid" 0 "Invalid";
VAL_ 503 APM2_Slot5_VolumeValue 31 "Reserved";
VAL_ 503 APM2_Slot6_Valid 1 "Valid" 0 "Invalid";
VAL_ 503 APM2_Slot6_VolumeValue 31 "Reserved";
VAL_ 503 AMP2_AUD_Engineering_Mode 3 "Reserved" 2 "Reserved" 1 "进入工程模式" 0 "退出工程模式";
VAL_ 503 APM2_Slot7_Valid 1 "Valid" 0 "Invalid";
VAL_ 503 APM2_Slot7_VolumeValue 31 "Reserved";
VAL_ 503 APM2_AUD_Mute_Status 1 "Mute" 0 "Unmute";
VAL_ 505 AMP3_EQBand1Val 31 "Reserved" 30 "Reserved" 29 "Reserved" 28 "Reserved" 27 "Reserved" 26 "Reserved" 25 "Reserved" 24 "12dB" 23 "11dB" 22 "10dB" 21 "9dB" 20 "8dB" 19 "7dB" 18 "6dB" 17 "5dB" 16 "4dB" 15 "3dB" 14 "2dB" 13 "1dB" 12 "0dB" 11 "-1dB" 10 "-2dB" 9 "-3dB" 8 "-4dB" 7 "-5dB" 6 "-6dB" 5 "-7dB" 4 "-8dB" 3 "-9dB" 2 "-10dB" 1 "-11dB" 0 "-12dB";
VAL_ 505 AMP3_EQBand2Val 31 "Reserved" 30 "Reserved" 29 "Reserved" 28 "Reserved" 27 "Reserved" 26 "Reserved" 25 "Reserved" 24 "12dB" 23 "11dB" 22 "10dB" 21 "9dB" 20 "8dB" 19 "7dB" 18 "6dB" 17 "5dB" 16 "4dB" 15 "3dB" 14 "2dB" 13 "1dB" 12 "0dB" 11 "-1dB" 10 "-2dB" 9 "-3dB" 8 "-4dB" 7 "-5dB" 6 "-6dB" 5 "-7dB" 4 "-8dB" 3 "-9dB" 2 "-10dB" 1 "-11dB" 0 "-12dB";
VAL_ 505 AMP3_EQBand3Val 31 "Reserved" 30 "Reserved" 29 "Reserved" 28 "Reserved" 27 "Reserved" 26 "Reserved" 25 "Reserved" 24 "12dB" 23 "11dB" 22 "10dB" 21 "9dB" 20 "8dB" 19 "7dB" 18 "6dB" 17 "5dB" 16 "4dB" 15 "3dB" 14 "2dB" 13 "1dB" 12 "0dB" 11 "-1dB" 10 "-2dB" 9 "-3dB" 8 "-4dB" 7 "-5dB" 6 "-6dB" 5 "-7dB" 4 "-8dB" 3 "-9dB" 2 "-10dB" 1 "-11dB" 0 "-12dB";
VAL_ 505 AMP3_EQBand4Val 31 "Reserved" 30 "Reserved" 29 "Reserved" 28 "Reserved" 27 "Reserved" 26 "Reserved" 25 "Reserved" 24 "12dB" 23 "11dB" 22 "10dB" 21 "9dB" 20 "8dB" 19 "7dB" 18 "6dB" 17 "5dB" 16 "4dB" 15 "3dB" 14 "2dB" 13 "1dB" 12 "0dB" 11 "-1dB" 10 "-2dB" 9 "-3dB" 8 "-4dB" 7 "-5dB" 6 "-6dB" 5 "-7dB" 4 "-8dB" 3 "-9dB" 2 "-10dB" 1 "-11dB" 0 "-12dB";
VAL_ 505 AMP3_EQBand5Val 31 "Reserved" 30 "Reserved" 29 "Reserved" 28 "Reserved" 27 "Reserved" 26 "Reserved" 25 "Reserved" 24 "12dB" 23 "11dB" 22 "10dB" 21 "9dB" 20 "8dB" 19 "7dB" 18 "6dB" 17 "5dB" 16 "4dB" 15 "3dB" 14 "2dB" 13 "1dB" 12 "0dB" 11 "-1dB" 10 "-2dB" 9 "-3dB" 8 "-4dB" 7 "-5dB" 6 "-6dB" 5 "-7dB" 4 "-8dB" 3 "-9dB" 2 "-10dB" 1 "-11dB" 0 "-12dB";
VAL_ 505 AMP3_SPK17_DAIG_STATUS 2 "开路" 1 "短路" 0 "正常";
VAL_ 505 AMP3_SPK18_DAIG_STATUS 2 "开路" 1 "短路" 0 "正常";
VAL_ 505 AMP3_SPK19_DAIG_STATUS 2 "开路" 1 "短路" 0 "正常";
VAL_ 505 AMP3_SPK20_DAIG_STATUS 2 "开路" 1 "短路" 0 "正常";
VAL_ 505 AMP3_Slot8_Valid 1 "Valid" 0 "Invalid";
VAL_ 505 AMP3_Slot8_VolumeValue 31 "Reserved";
VAL_ 505 AMP3_Slot9_Valid 1 "Valid" 0 "Invalid";
VAL_ 505 AMP3_Slot9_VolumeValue 31 "Reserved";
VAL_ 505 AMP3_Slot10_Valid 1 "Valid" 0 "Invalid";
VAL_ 505 AMP3_Slot10_VolumeValue 31 "Reserved";
VAL_ 505 AMP3_Slot11_Valid 1 "Valid" 0 "Invalid";
VAL_ 505 AMP3_Slot11_VolumeValue 31 "Reserved";
VAL_ 505 AMP3_Slot12_Valid 1 "Valid" 0 "Invalid";
VAL_ 505 AMP3_Slot12_VolumeValue 31 "Reserved";
VAL_ 505 AMP3_Slot13_Valid 1 "Valid" 0 "Invalid";
VAL_ 505 AMP3_Slot13_VolumeValue 31 "Reserved";
VAL_ 505 AMP3_Slot14_Valid 1 "Valid" 0 "Invalid";
VAL_ 505 AMP3_Slot14_VolumeValue 31 "Reserved";
VAL_ 505 AMP3_Slot15_Valid 1 "Valid" 0 "Invalid";
VAL_ 505 AMP3_Slot15_VolumeValue 31 "Reserved";
VAL_ 505 AMP3_A2B_Slot8_Value 1 "有音频输入" 0 "无音频输入";
VAL_ 505 AMP3_A2B_Slot9_Value 1 "有音频输入" 0 "无音频输入";
VAL_ 505 AMP3_A2B_Slot10_Value 1 "有音频输入" 0 "无音频输入";
VAL_ 505 AMP3_A2B_Slot11_Value 1 "有音频输入" 0 "无音频输入";
VAL_ 505 AMP3_A2B_Slot12_Value 1 "有音频输入" 0 "无音频输入";
VAL_ 505 AMP3_A2B_Slot13_Value 1 "有音频输入" 0 "无音频输入";
VAL_ 505 AMP3_A2B_Slot14_Value 1 "有音频输入" 0 "无音频输入";
VAL_ 505 AMP3_A2B_Slot15_Value 1 "有音频输入" 0 "无音频输入";
VAL_ 1589 AMP_RepeatMessageRequest 1 "Repeat message request" 0 "No repeat message request";
VAL_ 1589 AMP_ActiveWakeup 1 "Wakeup" 0 "No wakeup";
VAL_ 1589 AMP_WakeUp_KL15 1 "KL15 ON Wakeup" 0 "No Request";
VAL_ 1589 AMP_WakeUp_NM 1 "NM Wakeup" 0 "No Request";
VAL_ 1589 AMP_RepeatFromSleep 1 "occur" 0 "not occur";
VAL_ 1589 AMP_RepeatFromPrepare 1 "occur" 0 "not occur";
VAL_ 1589 AMP_NormalFromRepeat 1 "occur" 0 "not occur";
VAL_ 1589 AMP_NormalFromReady 1 "occur" 0 "not occur";
VAL_ 1589 AMP_RepeatFromReady 1 "occur" 0 "not occur";
VAL_ 1589 AMP_RepeatFromNormal 1 "occur" 0 "not occur";
VAL_ 1589 AMP_RemainNetworkWakeUpReason1 1 "Remain wakeup reason" 0 "default";
VAL_ 1589 AMP_RemainNetworkWakeUpReason2 1 "Remain wakeup reason" 0 "default";
VAL_ 1589 AMP_RemainNetworkWakeUpReason3 1 "Remain wakeup reason" 0 "default";
VAL_ 1589 AMP_RemainNetworkWakeUpReason4 1 "Remain wakeup reason" 0 "default";
VAL_ 438 TBOX2_AVMOnReq 2 "ON" 1 "OFF" 0 "No Request";
VAL_ 438 TBOX2_RemoteParkStartPressReqSts 1 "Available" 0 "Not Available";
VAL_ 438 TBOX2_RemoteHPP 1 "Request" 0 "No Request";
VAL_ 438 TBOX2_AVMviewReq 8 "3D Right" 7 "3D Left" 6 "3D Rear" 5 "3D Front" 4 "2D Right" 3 "2D Left" 2 "2D Rear" 1 "2D Front" 0 "Not Active";
VAL_ 438 TBOX2_RemoteParkReq 1 "Request" 0 "No Request";
VAL_ 438 TBOX2_SecuritySts 3 "Reserved" 2 "In security  status" 1 "Not in Security status" 0 "Initial value";
VAL_ 438 TBOX2_ConnectSts 2 "Connection" 1 "Not connection" 0 "Initial value";
VAL_ 438 TBOX2_PhoneInCar 2 "Outside" 1 "Inside" 0 "Initial value";
VAL_ 438 TBOX2_RemoteParkAbortReq 1 "Request" 0 "No Request";
VAL_ 438 TBOX2_RemoteParkStartPressReq 1 "press" 0 "No press";
VAL_ 438 TBOX2_RemoteParkOutModSel 4 "Straight driving" 3 "Optional parking in" 2 "Parking out" 1 "Parking in" 0 "NotSelected";
VAL_ 438 TBOX2_PhoneBatSts 1 "Abnormal" 0 "Normal";
VAL_ 438 TBOX2_RemoteIntModSel 2 "60s Return" 1 "60s  HangUp Phone" 0 "NotSelected";
VAL_ 438 TBOX2_RemoteSw 1 "Request" 0 "No Request";
VAL_ 438 TBOX2_RemoteCtrModSel 4 "Turn Right" 3 "Turn Left" 2 "Backward" 1 "Forward" 0 "NotSelected";
VAL_ 438 TBOX2_RemoteCtrSw 1 "Request" 0 "No Request";
VAL_ 438 TBOX2_Remotepick 1 "request" 0 "Norequest";
VAL_ 438 TBOX2_NNSsuspend 3 "reserved" 2 "Recover" 1 "suspend" 0 "No Request";
VAL_ 438 TBOX2_RemoteVhpower 2 "request OFF" 1 "request start" 0 "Norequest";
VAL_ 438 TBOX2_NRPReq 3 "reserved" 2 "Request off" 1 "Request on" 0 "No Request";
VAL_ 438 TBOX2_SDMapReq 3 "reserved" 2 "Request off" 1 "Request on" 0 "No Request";
VAL_ 438 TBOX2_NNSSW 3 "reserved" 2 "Request off" 1 "Request on" 0 "No Request";
VAL_ 438 TBOX2_PA_PauseRecover_Req 3 "reserved" 2 "Recover" 1 "Pause" 0 "No Request";
VAL_ 438 TBOX2_OpenFLDoorReq 3 "Suspend" 2 "Close" 1 "Open" 0 "No request";
VAL_ 438 TBOX2_OpenFLFRDoorReq 3 "Suspend" 2 "Close" 1 "Open" 0 "No request";
VAL_ 438 TBOX2_OpenFRDoorReq 3 "Suspend" 2 "Close" 1 "Open" 0 "No request";
VAL_ 438 TBOX2_Altitude 65535 "Invalid";
VAL_ 438 TBOX2_HPA_ONPath_ID 0 "default";
VAL_ 438 TBOX2_HPA_PickPath_ID 0 "default";
VAL_ 438 TBOX2_PrivacyForbidLocSts 1 "Enable" 0 "Disable";
VAL_ 438 TBOX2_PrivacyForbidDataSts 1 "Enable" 0 "Disable";
VAL_ 438 TBOX2_GMOnreq 3 "reserved" 2 "OFF" 1 "ON" 0 "No action";
VAL_ 438 TBOX2_360viewReq 3 "reserved" 2 "OFF" 1 "ON" 0 "No action";
VAL_ 438 TBOX2_360SpecView 4 "right view" 3 "left view" 2 "rear view" 1 "front view" 0 "No request";
VAL_ 576 TBOX3_RemoteStartReq 1 "Request" 0 "No request";
VAL_ 576 TBOX3_RemoteShutdownReq 1 "Request" 0 "No request";
VAL_ 576 TBOX3_ChargeCmd 2 "Start" 1 "Stop" 0 "No request";
VAL_ 576 TBOX3_ChargeAppointmentSet 1 "Enable" 0 "Disable";
VAL_ 576 TBOX3_FLWindowsCtrl 5 "通风" 4 "Auto Down" 3 "Auto Up" 2 "Manual Down" 1 "Manual Up" 0 "No request";
VAL_ 576 TBOX3_RemoteLockCtrl 3 "寻车" 2 "Unlock" 1 "Lock" 0 "No request";
VAL_ 576 TBOX3_RemoteTrunkCtrl 3 "Pause_Resume（信号为发3帧后回到0x0）" 2 "Close" 1 "Open" 0 "No request";
VAL_ 576 TBOX3_FRWindowsCtrl 5 "通风" 4 "Auto Down" 3 "Auto Up预留" 2 "Manual Down" 1 "Manual Up" 0 "No request";
VAL_ 576 TBOX3_IHU_CertificateState 1 "Enable" 0 "Disable";
VAL_ 576 TBOX3_RLWindowsCtrl 5 "通风" 4 "Auto Down" 3 "Auto Up预留" 2 "Manual Down" 1 "Manual Up" 0 "No request";
VAL_ 576 TBOX3_RRWindowsCtrl 5 "通风" 4 "Auto Down" 3 "Auto Up预留" 2 "Manual Down" 1 "Manual Up" 0 "No request";
VAL_ 576 TBOX3_StartForbidReq 2 "允许启动" 1 "禁止启动" 0 "no request";
VAL_ 576 TBOX3_HCU_RefuelRequest 3 "Reserved" 2 "OFF" 1 "ON" 0 "No Action";
VAL_ 576 TBOX3_DischargeMainSw 3 "Reserved" 2 "On" 1 "Off" 0 "No Request";
VAL_ 576 TBOX3_RemoteFindCarModSet 3 "闪灯+鸣笛" 2 "闪灯" 1 "鸣笛" 0 "No Request";
VAL_ 576 TBOX3_NetWorkSts 3 "Reserved" 2 "Resetting" 1 "Normal" 0 "Invalid";
VAL_ 576 TBOX3_RemoteReadyReq 1 "Request" 0 "No request";
VAL_ 576 TBOX3_SosState 1 "ON" 0 "OFF";
VAL_ 576 TBOX3_LongLifeChrgModeReq 1 "Long Life Mode" 0 "No request";
VAL_ 576 TBOX3_LongDistaChrgModeReq 1 "Long Distance Mode" 0 "No request";
VAL_ 576 TBOX3_BattHeatApt_Req 1 "request" 0 "No request";
VAL_ 576 TBOX3_SOCsettingvalid 1 "valid" 0 "inviald";
VAL_ 576 TBOX3_ChargeConKpTempSw 3 "Reserved" 2 "预约保温模式" 1 "充电保温模式" 0 "无保温模式";
VAL_ 576 TBOX3_PDCU_ChargeRequest 3 "Reserved" 2 "OFF" 1 "ON" 0 "No Request";
VAL_ 576 TBOX3_SunRoofCtrlReq 7 "Reserved" 6 "Reserved" 5 "Reserved" 4 "Open开启" 3 "Comfort舒适" 2 "Tilt 通风" 1 "Close关闭" 0 "No Request";
VAL_ 576 TBOX3_TemKeepModoffReq 1 "Request" 0 "No Request";
VAL_ 581 TBOX4_CLM_RemoteCtrlValid 1 "Valid" 0 "Invalid";
VAL_ 581 TBOX4_CLM_ACCmd 1 "Active" 0 "Inactive";
VAL_ 581 TBOX4_CLM_DefrostMaxCmd 1 "Active" 0 "Inactive";
VAL_ 581 TBOX4_BDM_RearDefrostCmd 1 "Active" 0 "Inactive";
VAL_ 581 TBOX4_CLM_CycleCmd 1 "Active" 0 "Inactive";
VAL_ 581 TBOX4_CLM_OnoffCmd 1 "Active" 0 "Inactive";
VAL_ 581 TBOX4_CLM_AutoCmd 1 "Active" 0 "Inactive";
VAL_ 581 TBOX4_CLM_VentCmd 1 "Active" 0 "Inactive";
VAL_ 581 TBOX4_CLM_FootCmd 1 "Active" 0 "Inactive";
VAL_ 581 TBOX4_CLM_WindowCmd 1 "Active" 0 "Inactive";
VAL_ 581 TBOX4_CLM_AnionCmd 1 "Active" 0 "Inactive";
VAL_ 581 TBOX4_LHSeatHeaterCmd 4 "High" 3 "Middle" 2 "Low" 1 "OFF" 0 "No Request";
VAL_ 581 TBOX4_RHSeatHeaterCmd 4 "High" 3 "Middle" 2 "Low" 1 "OFF" 0 "No Request";
VAL_ 581 TBOX4_CLM_BlowerSpdSet 14 "AUTO" 11 "风速十档" 10 "风速九档" 9 "风速八档" 8 "风速七档" 7 "风速六档" 6 "风速五档" 5 "风速四档" 4 "风速三档" 3 "Speed level 2" 2 "Speed level 1" 1 "Speed level 0" 0 "No request";
VAL_ 581 TBOX4_FridgeModReq 3 "保温" 2 "冷藏" 1 "关闭" 0 "No Request";
VAL_ 581 TBOX4_CLM_LHTempSet 32 "Hi(32)" 0 "Lo(16)";
VAL_ 581 TBOX4_CLM_RHTempSet 32 "Hi(32)" 0 "Lo(16)";
VAL_ 581 TBOX4_FLSeatVentCmd 4 "High" 3 "Middle" 2 "Low" 1 "OFF" 0 "No Reques";
VAL_ 581 TBOX4_FRSeatVentCmd 4 "High" 3 "Middle" 2 "Low" 1 "OFF" 0 "No Reques";
VAL_ 581 TBOX4_LRSeatHeaterCmd 4 "High" 3 "Middle" 2 "Low" 1 "OFF" 0 "No Reques";
VAL_ 581 TBOX4_RRSeatHeaterCmd 4 "High" 3 "Middle" 2 "Low" 1 "OFF" 0 "No Reques";
VAL_ 581 TBOX4_OilHeatingReq 3 "Reserved" 2 "OFF" 1 "ON" 0 "No Request";
VAL_ 1002 TBOX8_GPSValid 1 "Valid" 0 "Invalid";
VAL_ 992 CalendarMonth 12 "December" 11 "November" 10 "October" 9 "September" 8 "August" 7 "July" 6 "June" 5 "May" 4 "April" 3 "March" 2 "February" 1 "January" 0 "Unknown";
VAL_ 992 TimeDspFmt 1 "12 hour mode(not used)" 0 "24 hour mode(default)";
VAL_ 992 TBOX1_TimezoneSts 63 "Reserved" 62 "Reserved" 61 "Reserved" 60 "Reserved" 59 "Reserved" 58 "Reserved" 57 "Reserved" 56 "Reserved" 55 "Reserved" 54 "Reserved" 53 "Reserved" 52 "Reserved" 51 "Reserved" 50 "Reserved" 49 "Reserved" 48 "Reserved" 47 "Reserved" 46 "Reserved" 45 "Reserved" 44 "Reserved" 43 "Reserved" 42 "Reserved" 41 "Reserved" 40 "Reserved" 39 "Reserved" 38 "UTC+14（LINT — 莱恩群岛标准时间）" 37 "UTC+13（PHOT — 菲尼克斯群岛标准时间）+萨摩亚" 36 "UTC+12:45（CHAST — 查塔姆群岛标准时间）" 35 "UTC+12（NZST — 纽西兰标准时间）+斐济，纽西兰" 34 "UTC+11（VUT — 瓦努阿图标准时间）" 33 "UTC+10:30（LHST — 豪勋爵群岛标准时间）" 32 "UTC+10（AEST — 澳大利亚东部标准时间）+澳大利亚（昆士兰州、澳大利亚首都特区），巴布亚新几内亚" 31 "UTC+9:30（ACST — 澳大利亚中部标准时间）" 30 "UTC+9（JST — 日本标准时间）+东帝汶，印尼东部，日本" 29 "UTC+8:45 尤克拉" 28 "UTC+8（CT/CST — 中原标准时间）+文莱，中国香港，中国澳门，新加坡，马来西亚，印尼中部，澳大利亚 — 西澳大利亚-AWST — 澳大利亚西部标准时间" 27 "UTC+7（ICT — 中南半岛标准时间）+泰国，印尼西部" 26 "UTC+6:30（MMT — 缅甸标准时间）" 25 "UTC+6（BHT — 孟加拉标准时间）+孟加拉国，不丹" 24 "UTC+5:45（NPT — 尼泊尔标准时间）+尼泊尔" 23 "UTC+5:30（IST — 印度标准时间）+印度，斯里兰卡" 22 "UTC+5（PKT — 巴基斯坦标准时间）+马尔代夫，巴基斯坦" 21 "UTC+4:30（AFT — 阿富汗标准时间）" 20 "UTC+4（GST — 海湾标准时间）+毛里求斯，塞舌尔" 19 "UTC+3:30（IRST — 伊朗标准时间）" 18 "UTC+3（MSK — 莫斯科时区）+肯尼亚，坦桑尼亚，乌干达；" 17 "UTC+2（EET — 欧洲东部时区）+南非，博茨瓦纳，赞比亚，塞浦路斯，斯威士兰，莱索托，马拉维，莫桑比克，津巴布韦，纳米比亚9尼亚，坦桑尼亚，乌干达" 16 "UTC+1（CET — 欧洲中部时区）" 15 "UTC（WET — 欧洲西部时区，GMT - 格林尼治标准时间）+爱尔兰，英国" 14 "UTC-1（CVT — 佛得角标准时间）" 13 "UTC-2（FNT — 费尔南多迪诺罗尼亚群岛标准时间）" 12 "UTC-3（BRT — 巴西利亚标准时间）+巴哈马" 11 "UTC-3:30（NST — 纽芬兰岛标准时间）" 10 "UTC-4（AST — 大西洋标准时间）+安提瓜和巴布达，巴巴多斯，多米尼克，格林纳达，圭亚那，圣基茨和尼维斯， 圣文森特和格林纳丁斯，特立尼达和多巴哥，维尔京群岛" 9 "UTC-5（EST — 北美东部标准时间）+巴哈马，牙买加" 8 "UTC-6 （CST-北美中部标准时间）哥斯达黎加 尼加拉瓜，墨西哥，洪都拉斯，危地马拉，萨尔瓦多，伯利兹" 7 "UTC-7 （MST-山地时间） 育空，亚利桑那" 6 "UTC-8 （PST-太平洋标准时间 ）美国，加拿大，下加利福尼亚州" 5 "UTC-9 （AKST-阿拉斯加标准时间）" 4 "UTC-9:30 马克萨斯群岛" 3 "UTC-10（ HST-夏威夷，阿留申标准时间）" 2 "UTC-11 （SST-萨摩亚标准时间）" 1 "UTC-12 （贝克岛时间）" 0 "Invalid";
VAL_ 1537 TBOX_RepeatMessageRequest 1 "Repeat message request" 0 "No repeat message request";
VAL_ 1537 TBOX_ActiveWakeup 1 "Wakeup" 0 "No wakeup";
VAL_ 1537 TBOX_WakeUp_KL15 1 "KL15 ON Wakeup" 0 "No Request";
VAL_ 1537 TBOX_WakeUp_NM 1 "NM Wakeup" 0 "No Request";
VAL_ 1537 TBOX_WakeUp_Telematics 1 "Telematics" 0 "No Request";
VAL_ 1537 TBOX_WakeUp_Diagnosis 1 "Diagnosis" 0 "No Request";
VAL_ 1537 TBOX_WakeUp_Ota 1 "Ota" 0 "No Request";
VAL_ 1537 TBOX_WakeUp_Charge 1 "Charge" 0 "No Request";
VAL_ 1537 TBOX_WakeUp_Ac 1 "Ac" 0 "No Request";
VAL_ 1537 TBOX_WakeUp_Bt_control 1 "Bt_control" 0 "No Request";
VAL_ 1537 TBOX_RepeatFromSleep 1 "occur" 0 "not occur";
VAL_ 1537 TBOX_RepeatFromPrepare 1 "occur" 0 "not occur";
VAL_ 1537 TBOX_NormalFromRepeat 1 "occur" 0 "not occur";
VAL_ 1537 TBOX_NormalFromReady 1 "occur" 0 "not occur";
VAL_ 1537 TBOX_RepeatFromReady 1 "occur" 0 "not occur";
VAL_ 1537 TBOX_RepeatFromNormal 1 "occur" 0 "not occur";
VAL_ 1537 TBOX_RemainNetworkWakeUpReason1 1 "Remain wakeup reason" 0 "default";
VAL_ 1537 TBOX_RemainNetworkWakeUpReason2 1 "Remain wakeup reason" 0 "default";
VAL_ 1537 TBOX_RemainNetworkWakeUpReason3 1 "Remain wakeup reason" 0 "default";
VAL_ 1537 TBOX_RemainNetworkWakeUpReason4 1 "Remain wakeup reason" 0 "default";
VAL_ 1537 TBOX_RemainNetworkWakeUpReason5 1 "Remain wakeup reason" 0 "default";
VAL_ 1537 TBOX_RemainNetworkWakeUpReason6 1 "Remain wakeup reason" 0 "default";
VAL_ 1537 TBOX_RemainNetworkWakeUpReason7 1 "Remain wakeup reason" 0 "default";
VAL_ 1537 TBOX_RemainNetworkWakeUpReason8 1 "Remain wakeup reason" 0 "default";
VAL_ 1537 TBOX_RemainNetworkWakeUpReason9 1 "Remain wakeup reason" 0 "default";
VAL_ 1537 TBOX_WakeUp_Anti_Theft 1 "Anti-theft" 0 "No Request";
